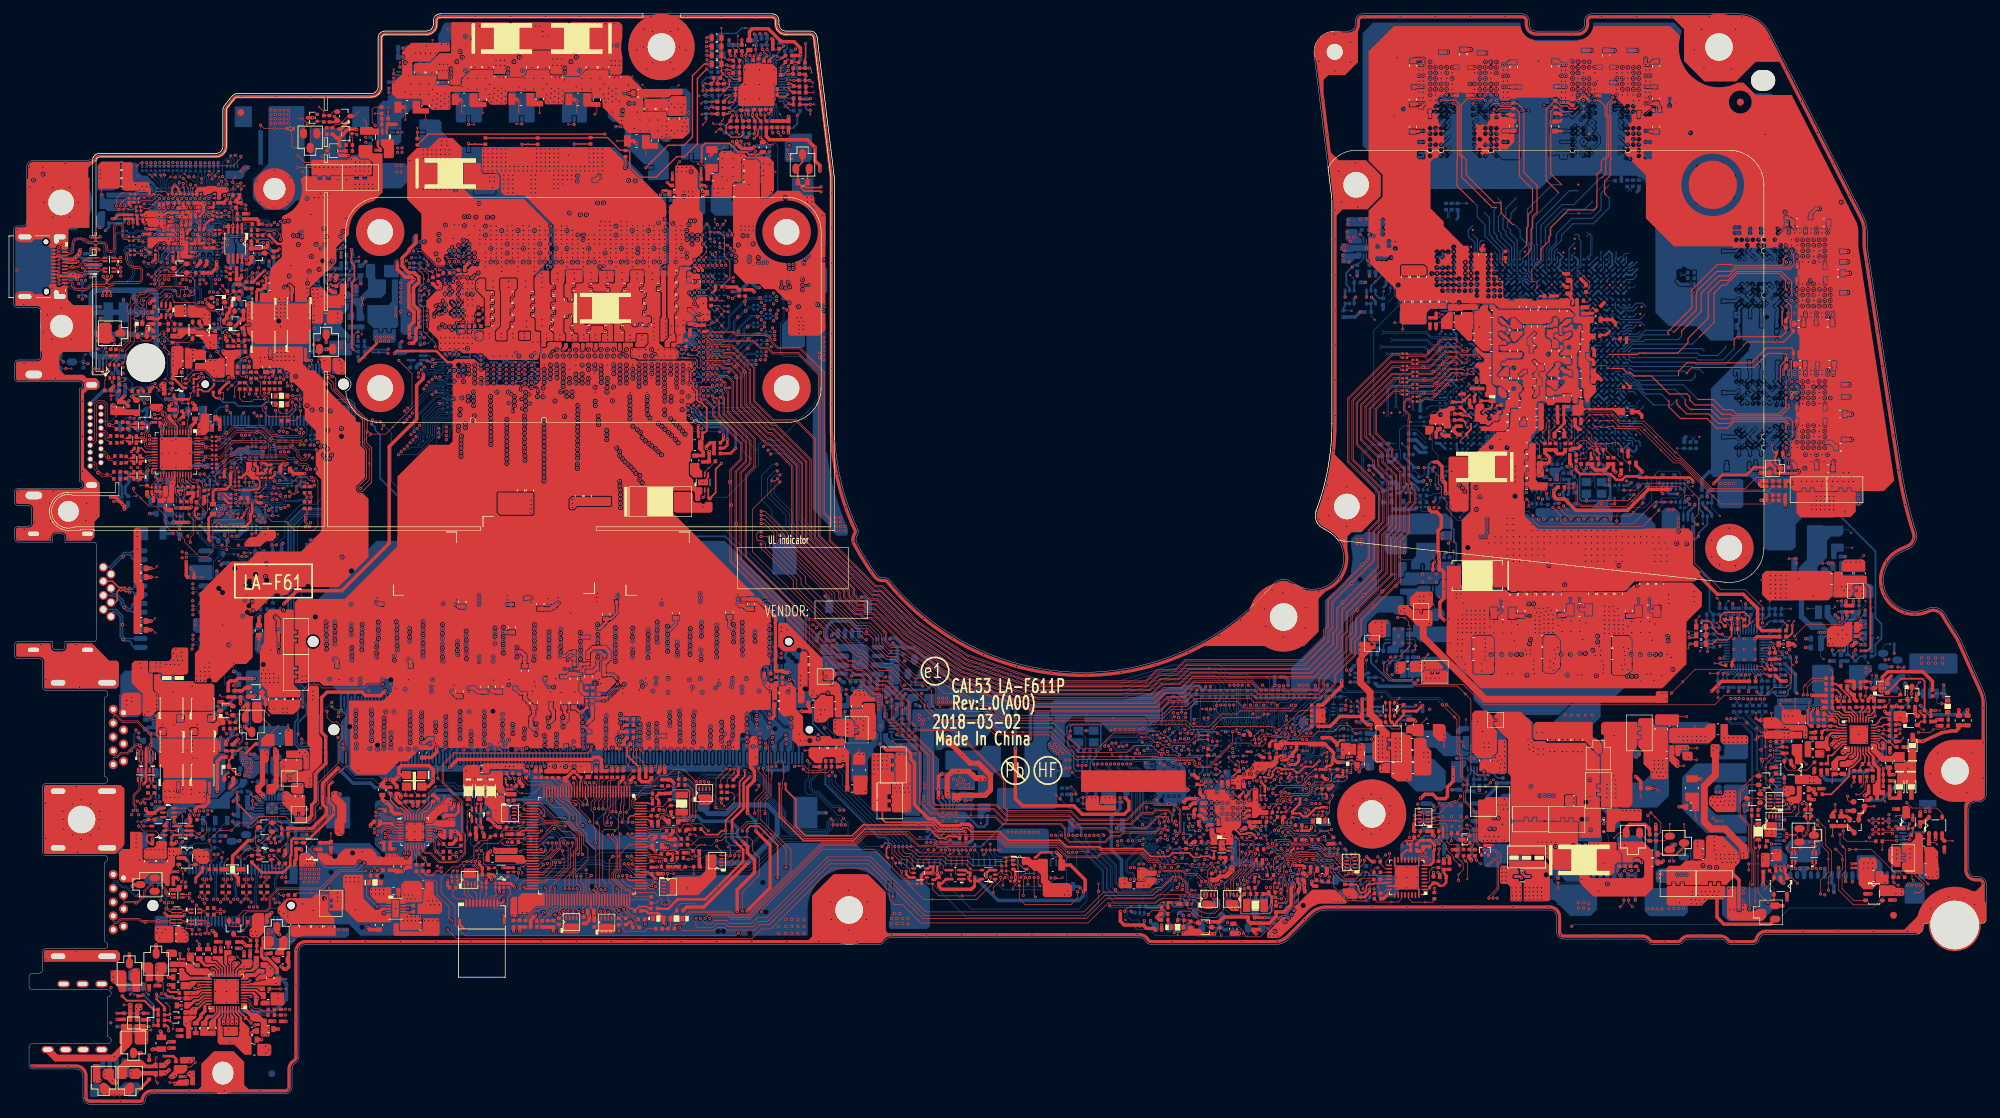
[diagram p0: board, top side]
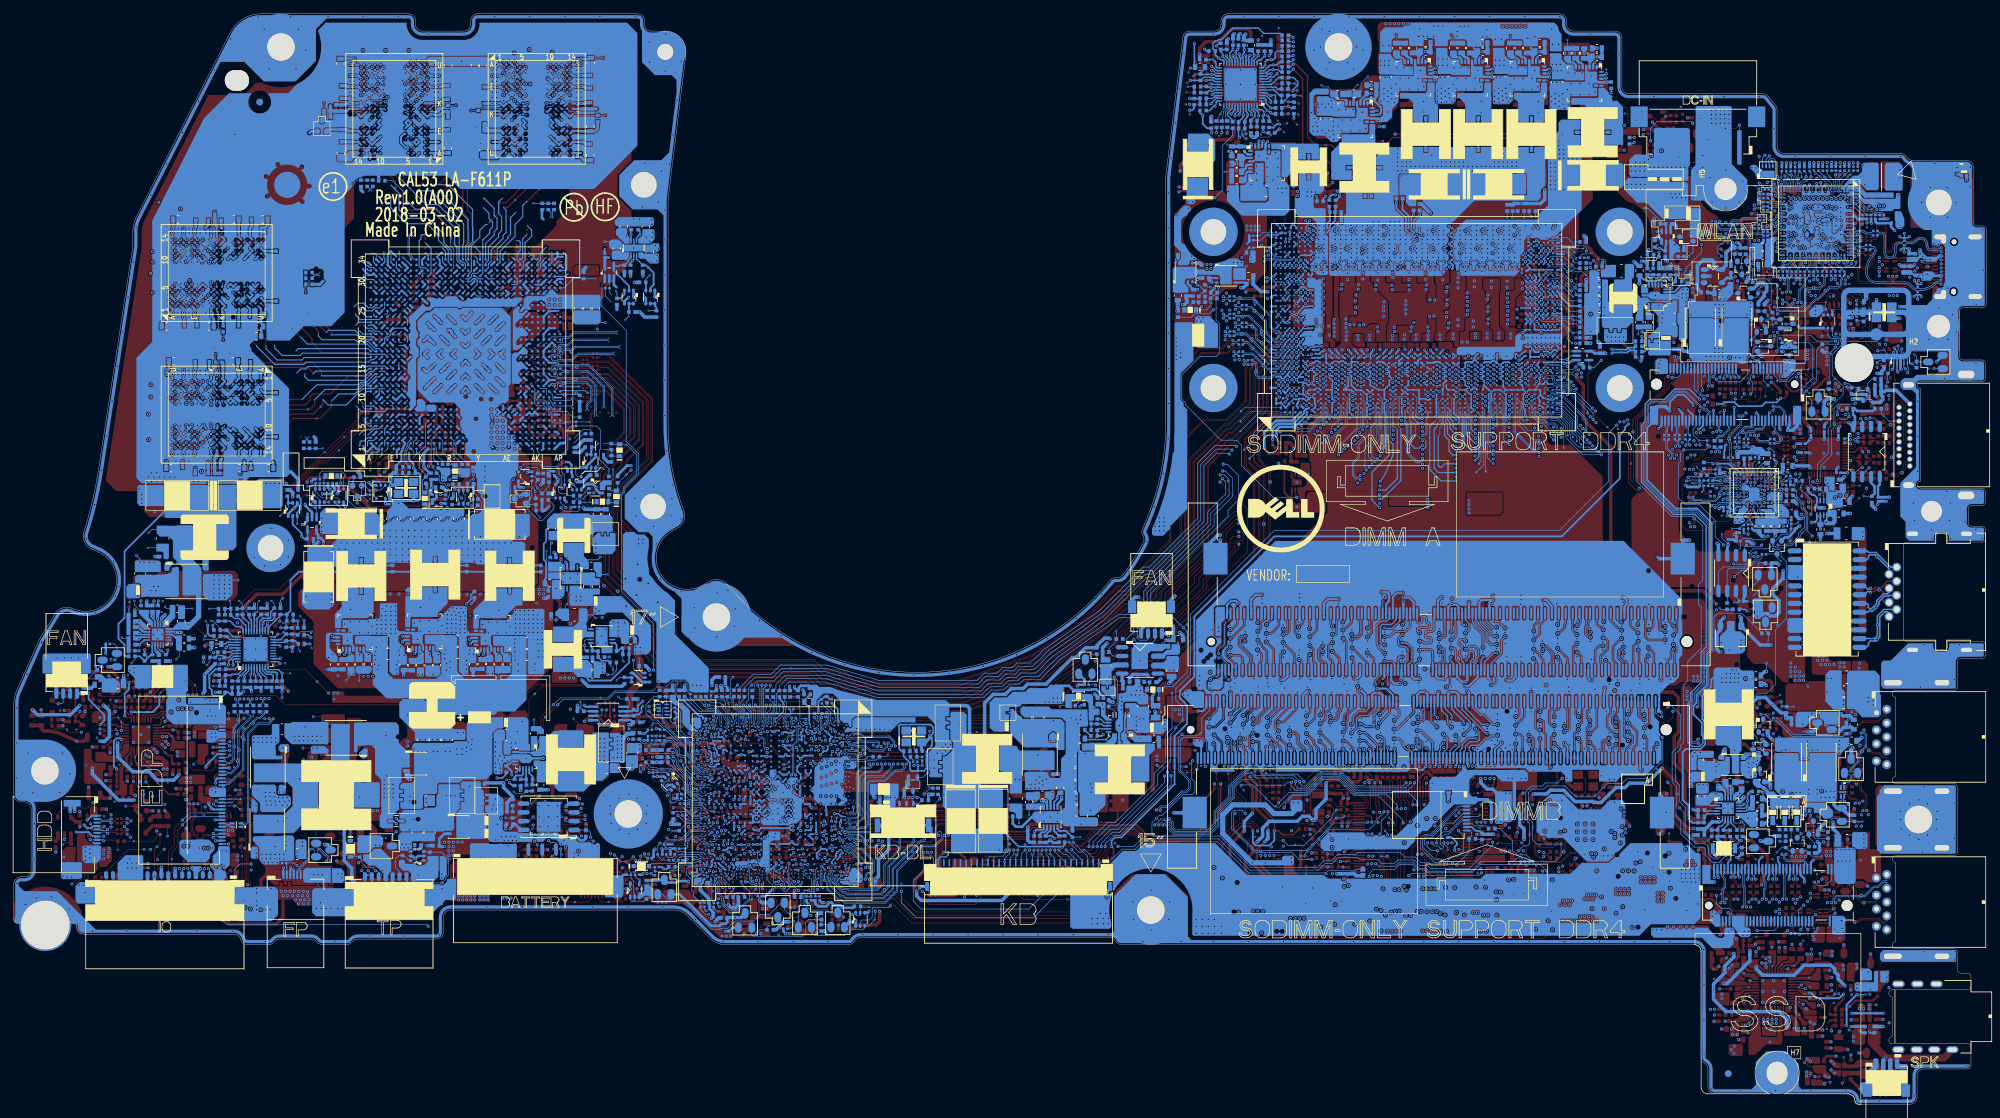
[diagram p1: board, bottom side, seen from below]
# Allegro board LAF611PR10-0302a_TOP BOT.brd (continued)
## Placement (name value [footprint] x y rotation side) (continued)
RH463  1K_0201_5%  [R_0201]  192.86 47.41 90 bottom
RH501  499_0402_1%  [R_0402]  190.2 45.67 180 top
RH502  499_0402_1%  [R_0402]  191.49 47.54 90 top
RH503  0_0201_5%  [R_0201]  182.46 31.99 0 top
RH506  1M_0402_5%  [R_0402]  190.91 38.62 270 top
RH512  10K_0201_5%  [R_0201]  166.4 29.21 0 top
RH515  8.2K_0402_5%  [R_0402]  189.68 34.35 0 bottom
RH520  8.2K_0402_5%  [R_0402]  194.84 53.75 270 bottom
RH521  10K_0201_5%  [R_0201]  186.07 44.22 180 top
RH524  2.2K_0402_5%  [R_0402]  189.94 41.27 90 bottom
RH531  1M_0402_5%  [R_0402]  182.61 28.72 270 top
RH533  100K_0201_5%  [R_0201]  189.19 35.3 180 bottom
RH537  10K_0201_5%  [R_0201]  180.34 47.33 0 top
RH545  10K_0201_5%  [R_0201]  192.61 34.31 180 bottom
RH546  10K_0201_5%  [R_0201]  185.74 39.57 0 top
RH551  10K_0201_5%  [R_0201]  193.61 54.18 180 bottom
RH552  10K_0201_5%  [R_0201]  191.25 54.18 0 bottom
RH553  10K_0201_5%  [R_0201]  183.44 48.45 270 top
RH554  10K_0201_5%  [R_0201]  184.06 47.85 0 top
RH557  10K_0201_5%  [R_0201]  169.39 29.5 90 bottom
RH561  10K_0201_5%  [R_0201]  170.03 29.5 90 bottom
RH562  10K_0201_5%  [R_0201]  170.66 30.09 270 bottom
RH571  8.2K_0402_5%  [R_0402]  182.89 58.97 90 bottom
RH573  10K_0201_5%  [R_0201]  184.99 41.51 90 top
RH578  8.2K_0402_5%  [R_0402]  185.43 40.37 0 top
RH580  1K_0201_5%  [R_0201]  167.01 58.03 90 bottom
RH581  1K_0201_5%  [R_0201]  168.46 57.99 90 bottom
RH588  20K_0402_5%  [R_0402]  188.7 57.73 180 top
RH589  10K_0402_5%  [R_0402]  187.78 56.97 0 top
RH613  20K_0402_5%  [R_0402]  185.21 59.89 270 bottom
RH614  20K_0402_5%  [R_0402]  186.73 59.89 270 bottom
RH656  0_0201_5%  [R_0201]  180.21 52.21 180 top
RH658  15_0402_5%  [R_0402]  187.81 38.28 0 top
RH665  30_0402_5%  [R_0402]  178.52 58.95 90 bottom
RH666  200_0402_1%  [R_0402]  189.1 58.98 90 bottom
RH667  150_0402_1%  [R_0402]  188.3 58.97 90 bottom
RH668  200_0402_1%  [R_0402]  187.78 56.21 0 top
RH669  100_0402_1%  [R_0402]  160.12 50.29 0 bottom
RH670  200_0402_1%  [R_0402]  187.78 55.45 0 top
RH671  4.7K_0402_5%~D  [R_0402]  185.97 59.89 270 bottom
RH672  0_0201_5%  [R_0201]  183.27 31.13 270 top
RH673  100K_0201_5%  [R_0201]  184.49 59.72 270 bottom
RH674  1K_0201_5%  [R_0201]  189.37 44.86 180 bottom
RH675  1K_0201_5%  [R_0201]  189.37 44.27 180 bottom
RH676  10K_0201_5%  [R_0201]  182.12 47.7 180 top
RH679  100K_0201_5%  [R_0201]  173.44 25.37 0 bottom
RH680  100K_0201_5%  [R_0201]  185.57 47.99 270 top
RH681  10K_0201_5%  [R_0201]  168.76 30.09 270 bottom
RH682  0_0201_5%  [R_0201]  183.38 42.25 180 top
RH683  0_0201_5%  [R_0201]  143.55 33.76 180 top
RH684  0_0201_5%  [R_0201]  189.95 35.32 0 bottom
RH685  150K_0402_5%  [R_0402]  183.75 41.57 180 top
RH687  10K_0201_5%  [R_0201]  193.03 53.29 0 bottom
RH697  0_0402_5%  [R_0402]  178.59 27 0 top
RH698  0_0402_5%  [R_0402]  172.8 50.49 90 top
RH699  0_0201_5%  [R_0201]  191.83 53.29 180 bottom
RH700  100K_0201_5%  [R_0201]  181.97 29.93 0 top
RH701  8.2K_0402_5%  [R_0402]  181.2 40.85 180 top
RH705  10K_0201_5%  [R_0201]  189.75 36.16 0 bottom
RH706  8.2K_0402_5%  [R_0402]  189.33 47.45 180 top
RH707  8.2K_0402_5%  [R_0402]  195.73 53.75 270 bottom
RH708  33_0402_5%  [R_0402]  213.19 42.34 270 bottom
RH709  49.9K_0402_1%  [R_0402]  193.9 51.26 180 bottom
RH710  49.9K_0402_1%  [R_0402]  190.65 51.26 0 bottom
RH711  33_0201_5%  [R_0201]  153.92 49.67 90 bottom
RH712  33_0201_5%  [R_0201]  154.65 49.57 0 bottom
RH713  0_0201_5%  [R_0201]  185.42 28.56 90 bottom
RH714  0_0201_5%  [R_0201]  186 28.56 90 bottom
RH716  10K_0201_5%  [R_0201]  172.79 52.8 90 top
RH717  10K_0201_5%  [R_0201]  185.75 33.25 270 top
RH719  10K_0201_5%  [R_0201]  187.43 59.94 270 bottom
RH721  10K_0201_5%  [R_0201]  188.37 48.45 0 top
RH722  4.7K_0201_5%  [R_0201]  26.62 103.99 270 top
RH723  4.7K_0201_5%  [R_0201]  28.96 104.79 270 top
RH724  1K_0201_5%  [R_0201]  26.02 103.75 90 top
RH725  1K_0201_5%  [R_0201]  26.02 105.54 270 top
RH726  100K_0201_5%  [R_0201]  174.48 33.62 270 top
RH727  4.7K_0402_5%  [R_0402]  173.3 33.38 270 top
RH728  100K_0201_5%  [R_0201]  192.29 48.3 0 top
RH731  0_0603_5%  [R_0603]  170.98 58.22 180 bottom
RH732  0_0603_5%  [R_0603]  162.76 31.7 180 top
RH734  10K_0201_5%  [R_0201]  180.39 38.52 180 top
RH735  100K_0402_5%  [R_0402]  204.42 39.5 180 top
RH736  0_0402_5%  [R_0402]  177.28 47.32 90 top
RH737  8.2K_0402_5%  [R_0402]  182.11 58.97 90 bottom
RH738  100K_0201_5%  [R_0201]  180.19 32.92 180 top
RH739  100K_0201_5%  [R_0201]  189.73 55.15 90 bottom
RH740  100K_0201_5%  [R_0201]  144.18 32.27 0 top
RH741  100K_0201_5%  [R_0201]  192.22 36.16 0 bottom
RH742  100K_0201_5%  [R_0201]  196.06 33.2 0 bottom
RH743  100K_0201_5%  [R_0201]  185.73 36.98 180 top
RH744  100K_0201_5%  [R_0201]  23.79 115.05 180 bottom
RH745  100K_0201_5%  [R_0201]  21.88 102.78 0 top
RH746  100K_0201_5%  [R_0201]  189.71 57.38 270 bottom
RH747  10K_0402_5%  [R_0402]  196.99 60.86 90 bottom
RH748  51_0402_5%  [R_0402]  193.95 63.45 0 bottom
RH749  1K_0201_5%  [R_0201]  193.62 35.57 180 bottom
RL2  2.49K_0402_1%  [R_0402]  54.51 45.87 270 top
RL3  1K_0402_5%  [R_0402]  63.08 37.65 180 top
RL4  15K_0402_5%  [R_0402]  64.67 37.41 90 top
RL6  100K_0402_5%  [R_0402]  40.84 36.94 90 top
RL7  10K_0402_5%  [R_0402]  45.87 37.08 90 top
RL8  33_0402_5%  [R_0402]  59.36 44.68 270 top
RL9  33_0402_5%  [R_0402]  56.67 44.73 270 top
RL13  0_0402_5%  [R0402_0OHM]  58.24 33.73 90 top
RL14  75_0603_5%  [R_0603]  17.73 68.65 0 top
RL15  75_0603_5%  [R_0603]  17.73 69.92 0 top
RL17  0_0402_5%  [R_0402]  60.65 43.78 90 top
RL19  75_0603_5%  [R_0603]  17.73 76.27 0 top
RL20  75_0603_5%  [R_0603]  17.73 77.54 0 top
RP1  100K_8P4R_5%  [RP_0804_8P4R]  253.94 40.46 90 top
RP2  100_8P4R_5%  [RP_0804_8P4R]  255.28 43.17 180 top
RP3  10K_0804_8P4R_5%  [RP_0804_8P4R]  172.18 29.14 90 top
RP9  0_0402_5%  [R_0402]  17.09 103.2 0 top
RP10  0_0402_5%  [R_0402]  14.77 108.33 90 top
RP11  0_0201_5%  [R0201_0OHM]  21.14 99.27 180 top
RP24  47K_0402_5%  [R_0402]  25.2 89.34 270 top
RP25  47K_0402_5%  [R_0402]  25.98 89.34 270 top
RP28  0_0603_1%  [R0603_0OHM]  26.23 99.2 90 top
RP30  4.99K_0402_1%  [R_0402]  23.17 89.08 0 bottom
RP31  10K_0402_1%  [R_0402]  24.84 89.08 0 bottom
RP32  4.53K_0402_1%  [R_0402]  27.54 88.8 270 top
RP33  10K_0201_5%  [R_0201]  25.27 102.02 270 top
RP34  10K_0201_5%  [R_0201]  23.49 102.01 270 top
RP35  10K_0201_5%  [R_0201]  23.77 88.81 90 top
RP36  10K_0201_5%  [R_0201]  19.96 88.68 90 top
RP37  10K_0201_5%  [R_0201]  24.36 88.81 90 top
RP38  10K_0201_5%  [R_0201]  26.65 88.73 90 top
RP39  10K_0402_5%  [R_0402]  24.33 100.28 0 top
RP40  10K_0402_5%  [R_0402]  23.36 100.48 270 top
RP41  10K_0402_5%  [R_0402]  24.16 86.28 90 top
RP42  10K_0402_5%  [R_0402]  19.28 88.61 90 top
RP43  10K_0402_5%  [R_0402]  25.01 86.29 90 top
RP44  10K_0402_5%  [R_0402]  24.54 99.47 270 top
RP45  1K_0201_5%  [R_0201]  28.24 88.89 270 top
RP48  10K_0201_5%  [R_0201]  21.18 89.27 270 top
RP49  10K_0201_5%  [R_0201]  20.55 89.27 270 top
RP50  33_0804_8P4R_5%  [RP_0804_8P4R]  192.05 57.86 180 bottom
RP51  0_0603_1%  [R0603_0OHM]  22.63 87.4 270 top
RP52  0_0603_1%  [R0603_0OHM]  22.25 89.28 180 bottom
RPE1  10K_8P4R_5%  [RP_0804_8P4R]  94.07 32.19 0 top
RPE2  10K_8P4R_5%  [RP_0804_8P4R]  102.33 34.5 180 top
RPE3  100K_8P4R_5%  [RP_0804_8P4R]  99.16 44.46 90 top
RPE4  100K_8P4R_5%  [RP_0804_8P4R]  71.22 42.82 0 top
RPE5  100K_8P4R_5%  [RP_0804_8P4R]  79.92 25.79 90 top
RPE6  100K_8P4R_5%  [RP_0804_8P4R]  85 25.71 90 top
RPE7  10K_0804_8P4R_5%  [RP_0804_8P4R]  65.19 31.88 90 top
RPH5  33_0804_8P4R_5%  [RP_0804_8P4R]  204.53 40.81 180 top
RPH6  10K_8P4R_5%  [RP_0804_8P4R]  176.98 30.29 270 top
RPH7  15_0804_8P4R_5%  [RP_0804_8P4R]  194 34.22 180 top
RPT1  100K_0804_8P4R_5%  [RP_0804_8P4R]  32.35 134.59 90 bottom
RS1  0_0402_5%  [R0402_0OHM]  269.39 38.05 0 top
RS2  10K_0402_5%  [R_0402]  24.85 31.44 180 top
RS3  100K_0402_5%  [R_0402]  272.64 42.71 0 top
RS4  100K_0402_5%  [R_0402]  275.44 38.95 180 top
RS5  10K_0402_5%  [R_0402]  279.3 38.11 270 top
RS8  0_0603_5%  [R_0603]  277.08 37.87 180 top
RS9  10K_0402_5%  [R_0402]  34.75 26.39 180 top
RS10  0_0201_5%  [R_0201]  25.81 24.6 0 top
RSPI1  0_0402_5%  [R_0402]  183.32 61.82 180 bottom
RT1  0_0201_5%  [R_0201]  24.72 131.71 0 top
RT2  0_0201_5%  [R_0201]  32.21 131.13 90 bottom
RT3  3.01K_0201_1%  [R_0201]  25.07 125.34 90 top
RT4  1M_0201_1%  [R_0201]  24.28 135.1 90 bottom
RT5  14K_0402_1%  [R_0402]  25.23 130.39 0 top
RT6  10K_0201_5%  [R_0201]  29.64 131.71 180 top
RT7  10K_0201_5%  [R_0201]  26.47 131.71 180 top
RT8  10K_0201_5%  [R_0201]  27.65 131.71 180 top
RT9  10K_0201_5%  [R_0201]  29.64 131.14 180 top
RT10  0_0201_5%  [R_0201]  27.65 135.04 90 bottom
RT11  1M_0201_1%  [R_0201]  29.55 135.04 90 bottom
RT12  0_0201_5%  [R_0201]  18.31 129.91 180 top
RT13  0_0201_5%  [R_0201]  17.5 131.71 180 top
RT14  0_0201_5%  [R_0201]  23.01 135.1 90 bottom
RT15  0_0201_5%  [R_0201]  19.2 135.1 90 bottom
RT16  0_0201_5%  [R_0201]  21.11 135.1 90 bottom
RT17  100_0201_5%  [R_0201]  19.84 135.1 90 bottom
RT18  100_0201_5%  [R_0201]  31.64 130.54 0 bottom
RT19  14K_0402_1%  [R_0402]  28.92 124.87 270 top
RT20  10K_0201_5%  [R_0201]  31.58 131.72 270 bottom
RT21  10K_0201_5%  [R_0201]  16.66 128.11 90 bottom
RT23  0_0201_5%  [R_0201]  18.03 131.08 180 top
RT24  10K_0201_5%  [R_0201]  32.8 131.71 270 bottom
RT25  4.75K_0402_0.5%  [R_0402]  22.3 130.4 0 top
RT26  3.3K_0201_5%  [R_0201]  25.55 135.62 270 bottom
RT27  3.3K_0201_5%  [R_0201]  26.31 135.62 270 bottom
RT28  10K_0201_5%  [R_0201]  28.28 135.62 270 bottom
RT29  10K_0201_5%  [R_0201]  28.92 135.62 270 bottom
RT30  10K_0201_5%  [R_0201]  18.57 135.69 270 bottom
RT31  10K_0201_5%  [R_0201]  23.65 135.69 270 bottom
RT32  10K_0201_5%  [R_0201]  24.11 131.71 180 top
RT33  10K_0201_5%  [R_0201]  20.47 135.69 270 bottom
RT34  100K_0201_5%  [R_0201]  27.01 135.04 90 bottom
RT35  100K_0201_5%  [R_0201]  20.24 131.7 180 top
RT36  100K_0201_5%  [R_0201]  22.38 135.1 90 bottom
RT37  100K_0201_5%  [R_0201]  18.42 129.27 270 top
RT40  1M_0201_1%  [R_0201]  17.29 128.69 270 bottom
RT42  1M_0201_1%  [R_0201]  14.8 128.7 270 bottom
RT43  499_0201_1%  [R_0201]  23.01 123.3 270 top
RT44  499_0201_1%  [R_0201]  20.47 123.56 270 top
RT45  100K_0201_5%  [R_0201]  15.39 128.69 270 bottom
RT46  100K_0201_5%  [R_0201]  17.93 128.69 270 bottom
RT47  100K_0201_5%  [R_0201]  24.92 135.1 90 bottom
RT48  3.3K_0402_5%  [R_0402]  32.21 119.39 180 top
RT49  2.2K_0402_5%  [R_0402]  32.21 120.98 180 top
RT50  2.2K_0402_5%  [R_0402]  32.21 120.2 180 top
RT51  3.3K_0402_5%  [R_0402]  16.54 87.07 90 bottom
RT57  10K_0201_5%  [R_0201]  28.34 90.18 0 bottom
RT58  10K_0201_5%  [R_0201]  28.33 89.61 0 bottom
RT59  0_0402_5%  [R_0402]  27.95 88.94 0 bottom
RT60  0_0402_5%  [R_0402]  26.62 90.24 0 bottom
RT61  0_0201_5%  [R_0201]  37.24 92.52 270 top
RT62  100K_0201_5%  [R_0201]  32.85 92.88 90 bottom
RT63  100K_0201_5%  [R_0201]  33.87 83.89 270 bottom
RT64  0_0402_5%  [R_0402]  32.86 87.74 0 top
RT65  0_0402_5%  [R_0402]  28.93 87.27 180 bottom
RT66  10K_0201_5%  [R_0201]  32.57 90.7 270 top
RT67  10K_0201_5%  [R_0201]  33.24 88.88 180 top
RT68  100K_0201_5%  [R_0201]  40.88 89.48 0 bottom
RT69  100K_0201_5%  [R_0201]  40.2 90.24 180 bottom
RT70  100K_0201_5%  [R_0201]  37.91 93.57 180 bottom
RT71  100K_0201_5%  [R_0201]  39.17 91.24 180 bottom
RT72  100K_0201_5%  [R_0201]  39.17 91.85 180 bottom
RT73  100K_0201_5%  [R_0201]  36.64 93.57 180 bottom
RT74  0_0201_5%  [R_0201]  35.67 82.72 90 bottom
RT75  15K_0402_0.1%  [R_0402]  34.13 93.49 90 bottom
RT76  100K_0201_5%  [R_0201]  28.84 129.2 90 top
RT78  100K_0201_5%  [R_0201]  28.84 128.6 270 top
RT80  100K_0201_5%  [R_0201]  18.03 130.52 180 top
RT83  0_0201_5%  [R_0201]  33.43 94.24 270 bottom
RT86  10K_0201_5%  [R_0201]  16.02 128.11 90 bottom
RT94  10K_0201_5%  [R_0201]  22.92 131.71 180 top
RT95  0_0402_5%  [R_0402]  12.84 128.93 90 bottom
RT97  0_0402_5%  [R0402_0OHM]  12.85 127.5 0 bottom
RT101  15_0201_1%  [R_0201]  31.45 132.37 0 bottom
RT102  0_0201_5%  [R_0201]  32.96 84.86 180 top
RT108  0_0201_5%  [R_0201]  31.39 88.27 270 top
RT111  1M_0201_1%  [R_0201]  31.39 86.42 90 top
RT112  10K_0201_5%  [R_0201]  35.26 90.66 0 top
RT113  100K_0201_5%  [R_0201]  36.47 90.66 0 top
RT114  0_0201_5%  [R_0201]  39.61 89.48 0 bottom
RT115  0_0201_5%  [R_0201]  41.47 90.24 180 bottom
RT118  0_0402_5%  [R_0402]  40.37 91.04 0 bottom
RT119  0_0402_5%  [R_0402]  40.83 91.95 90 bottom
RT120  0_0402_5%  [R_0402]  28.87 88.12 180 bottom
RT122  0_0201_5%  [R_0201]  34.44 83.89 270 bottom
RT123  15_0201_1%  [R_0201]  28.89 90.88 180 bottom
RT125  3.3K_0201_5%  [R_0201]  35.56 81.5 0 bottom
RT126  3.3K_0201_5%  [R_0201]  34.7 80.88 90 bottom
RT127  3.3K_0201_5%  [R_0201]  37.34 81.14 90 bottom
RT128  3.3K_0201_5%  [R_0201]  35.73 72.79 180 bottom
RT129  100K_0201_5%  [R_0201]  16.64 131.1 270 top
RT130  0_0402_5%  [R_0402]  42.82 88.48 90 top
RT131  0_0402_5%  [R_0402]  42.06 88.48 90 top
RT132  0_0402_5%  [R_0402]  42.82 86.23 90 top
RT133  0_0402_5%  [R_0402]  42.06 86.23 90 top
RT134  0_0603_5%  [R0603_0OHM]  28.8 85.43 90 top
RT152  10K_0201_5%  [R_0201]  21.74 135.69 270 bottom
RT153  10K_0201_5%  [R_0201]  17.73 128.68 90 top
RT154  0_0201_5%  [R_0201]  18.75 114.03 270 bottom
RT155  0_0201_5%  [R_0201]  18.76 115.72 270 bottom
RT156  33_0402_5%  [R_0402]  37.49 71.61 90 bottom
RT157  33_0402_5%  [R_0402]  31.81 117.66 180 top
RT159  0_0201_5%  [R_0201]  15.72 126.37 0 bottom
RT160  0_0201_5%  [R_0201]  15.72 125.74 0 bottom
RT161  0_0201_5%  [R_0201]  16.87 122.9 0 top
RT162  0_0201_5%  [R_0201]  16.87 123.53 0 top
RT163  0_0201_5%  [R_0201]  35.08 83.81 270 bottom
RT164  0_0201_5%  [R_0201]  30.67 93.28 90 bottom
RT165  0_0201_5%  [R_0201]  28.22 84.57 270 bottom
RT166  100K_0201_5%  [R_0201]  27.67 83.26 0 bottom
RT167  0_0201_5%  [R_0201]  31.86 79.58 0 bottom
RT168  0_0402_5%  [R0402_0OHM]  27 122.01 0 top
RTPM1  33_0402_5%  [R_0402]  196.84 30.51 0 top
RTPM2  33_0402_5%  [R_0402]  196.77 32.51 0 top
RTPM3  33_0402_5%  [R_0402]  196.77 33.56 0 top
RTPM4  10K_0402_5%  [R_0402]  196.84 29.74 0 top
RTPM6  0_0402_5%  [R_0402]  207.71 33.98 90 top
RTPM7  0_0402_5%  [R_0402]  206.9 33.98 90 top
RTPM8  0_0402_5%  [R_0402]  203 37.59 180 top
RTPM9  10K_0402_5%  [R_0402]  196.77 35.1 0 top
RTPM10  0_0402_5%  [R_0402]  202.6 39.52 270 top
RTPM11  0_0402_5%  [R_0402]  205.51 29.72 90 top
RTPM12  0_0402_5%  [R_0402]  206.1 34.24 90 top
RV27  100K_0402_5%  [R_0402]  224.97 91.33 270 bottom
RV28  0_0402_5%  [R0402_0OHM]  15.75 97.71 180 top
RV29  0_0402_5%  [R0402_0OHM]  15.52 93.8 180 top
RV30  0_0402_5%  [R0402_0OHM]  15.52 92.78 180 top
RV33  0_0402_5%  [R0402_0OHM]  15.39 91.51 180 top
RV34  0_0402_5%  [R0402_0OHM]  15.39 90.5 180 top
RV37  10K_0402_5%  [R_0402]  224.2 91.33 270 bottom
RV39  10K_0402_5%  [R_0402]  208.02 88.39 0 bottom
RV40  0_0201_5%  [R_0201]  204 98.16 90 bottom
RV41  10K_0402_5%  [R_0402]  201.8 97.03 270 bottom
RV42  10K_0402_5%  [R_0402]  225.74 90.78 270 bottom
RV49  10K_0402_5%  [R_0402]  226.02 93.95 180 top
RV50  2.49K_0402_1%  [R_0402]  202.92 120.39 270 bottom
RV51  10K_0402_5%  [R_0402]  225.23 95.62 270 top
RV52  10M_0402_5%  [R_0402]  229.07 92.24 180 bottom
RV55  10K_0402_5%  [R_0402]  223.06 95.61 270 top
RV56  0_0201_5%  [R_0201]  233.84 88.79 270 bottom
RV57  10K_0402_5%  [R_0402]  236.14 90.75 180 bottom
RV58  10K_0402_5%  [R_0402]  208.94 87.47 180 bottom
RV60  100K_0402_5%  [R_0402]  222.56 92.61 270 bottom
RV62  10K_0402_5%  [R_0402]  203.48 99.44 90 bottom
RV63  10K_0402_5%  [R_0402]  203.48 102.59 270 bottom
RV66  100K_0402_5%  [R_0402]  225.11 93.15 0 top
RV77  40.2_0402_1%  [R_0402]  226.17 116.27 0 top
RV78  40.2_0402_1%  [R_0402]  227.45 118.47 270 top
RV79  60.4_0402_1%  [R_0402]  229.63 115.53 225 top
RV95  10K_0402_5%  [R_0402]  223 146.16 270 top
RV96  10K_0402_5%  [R_0402]  258.37 108.7 180 top
RV98  10K_0402_5%  [R_0402]  216.94 145.84 270 top
RV99  10K_0402_5%  [R_0402]  258.34 111.93 180 top
RV107  10K_0402_5%  [R_0402]  216.94 144.06 270 top
RV108  10K_0402_5%  [R_0402]  223 144.32 270 top
RV110  10K_0402_5%  [R_0402]  256.34 112.35 90 top
RV111  10K_0402_5%  [R_0402]  256.44 107.81 270 top
RV116  1K_0402_1%  [R_0402]  222.55 144.57 270 bottom
RV117  1K_0402_1%  [R_0402]  218.15 143.81 270 bottom
RV120  121_0402_1%  [R_0402]  237.21 143.86 0 top
RV121  121_0402_1%  [R_0402]  200.87 143.11 270 bottom
RV125  549_0402_1%  [R_0402]  238.61 142.84 0 bottom
RV126  931_0402_1%  [R_0402]  240.47 143.73 180 bottom
RV127  1.33K_0402_1%  [R_0402]  238.75 143.72 90 bottom
RV131  1K_0402_1%  [R_0402]  255.06 111.79 180 bottom
RV132  1K_0402_1%  [R_0402]  256.14 107.36 180 bottom
RV135  121_0402_1%  [R_0402]  256.44 127.34 90 top
RV136  121_0402_1%  [R_0402]  256.74 92.15 0 top
RV140  549_0402_1%  [R_0402]  254.53 91.29 0 bottom
RV141  931_0402_1%  [R_0402]  255 94.27 0 top
RV142  1.33K_0402_1%  [R_0402]  256.3 91.29 0 bottom
RV146  100K_0402_5%  [R_0402]  230.62 93.56 270 top
RV147  100K_0402_5%  [R_0402]  255.41 90.19 0 top
RV148  100K_0402_5%  [R_0402]  255.41 89.43 0 top
RV149  100K_0402_5%  [R_0402]  233.76 92.87 0 top
RV150  100K_0402_5%  [R_0402]  229.3 92.65 180 top
RV152  100K_0402_5%  [R_0402]  229.04 94.73 0 top
RV153  100K_0402_5%  [R_0402]  253.57 90.19 0 top
RV154  100K_0402_5%  [R_0402]  253.57 89.43 0 top
RV155  100K_0402_5%  [R_0402]  233.54 94.6 180 top
RV156  100K_0402_5%  [R_0402]  228.25 93.46 0 top
RV157  100K_0402_5%  [R_0402]  255.36 87.4 0 top
RV158  100K_0402_5%  [R_0402]  255.36 88.16 0 top
RV159  100K_0402_5%  [R_0402]  231.42 93.56 270 top
RV160  100K_0402_5%  [R_0402]  253.56 87.4 0 top
RV161  100K_0402_5%  [R_0402]  253.56 88.16 0 top
RV162  100K_0402_5%  [R_0402]  232.55 91.77 90 top
RV191  1.8K_0402_5%  [R_0402]  221.95 86.75 90 bottom
RV192  1.8K_0402_5%  [R_0402]  219.74 89.78 180 bottom
RV500  619_0402_1%  [R_0402]  15.65 95.77 90 top
RV501  619_0402_1%  [R_0402]  16.49 97.76 90 top
RV502  619_0402_1%  [R_0402]  16.26 92.84 90 top
RV503  619_0402_1%  [R_0402]  16.21 90.55 90 top
RV512  1.8K_0402_5%  [R_0402]  222.29 95.61 270 top
RV513  1.8K_0402_5%  [R_0402]  221.51 95.61 270 top
RV514  1.8K_0402_5%  [R_0402]  220.47 92.6 270 bottom
RV515  1.8K_0402_5%  [R_0402]  219.64 92.6 270 bottom
RV526  10K_0402_5%  [R_0402]  223.32 92.61 270 bottom
RV532  10K_0402_5%  [R_0402]  202.63 97.03 270 bottom
RV571  0_0402_5%  [R_0402]  218.22 87.59 270 bottom
RV572  0_0402_5%  [R_0402]  221.83 89.73 180 bottom
RV573  100K_0402_5%  [R_0402]  207.92 90.03 90 bottom
RV574  10K_0402_5%  [R_0402]  224.44 95.62 270 top
RV583  0_0402_5%  [R0402_0OHM]  204.88 113.82 270 top
RV584  0_0402_5%  [R0402_0OHM]  208.18 101.62 270 top
RV585  0_0402_5%  [R0402_0OHM]  208.43 99.92 180 top
RV586  0_0402_5%  [R0402_0OHM]  208.43 99.03 180 top
RV590  0_0402_5%  [R0402_0OHM]  212.51 104.48 270 top
RV593  100K_0402_5%  [R_0402]  226.75 92.65 0 top
RV594  40.2_0402_1%  [R_0402]  234.23 132.82 90 bottom
RV595  40.2_0402_1%  [R_0402]  233.41 132.82 90 bottom
RV596  40.2_0402_1%  [R_0402]  207.19 129.45 90 bottom
RV597  40.2_0402_1%  [R_0402]  208.02 129.45 90 bottom
RV598  40.2_0402_1%  [R_0402]  243.39 95.83 270 bottom
RV599  40.2_0402_1%  [R_0402]  242.57 95.83 270 bottom
RV600  40.2_0402_1%  [R_0402]  242.19 120.37 0 bottom
RV601  40.2_0402_1%  [R_0402]  242.19 119.54 0 bottom
RV602  60.4_0402_1%  [R_0402]  231.66 133.64 0 bottom
RV603  60.4_0402_1%  [R_0402]  215.8 123.41 270 top
RV604  60.4_0402_1%  [R_0402]  232.89 103.79 0 top
RV605  60.4_0402_1%  [R_0402]  232.41 110.84 0 top
RV638  2.2_0402_1%  [R_0402]  18.28 90.5 180 top
RV639  2.2_0402_1%  [R_0402]  18.28 92.78 180 top
RV640  2.2_0402_1%  [R_0402]  17.71 95.67 180 top
RV641  2.2_0402_1%  [R_0402]  17.71 96.68 180 top
RV642  2.2_0402_1%  [R_0402]  18.28 93.8 180 top
RV643  2.2_0402_1%  [R_0402]  18.54 98.6 180 top
RV645  2.2_0402_1%  [R_0402]  18.28 91.51 180 top
RV646  2.2_0402_1%  [R_0402]  18.54 97.84 180 top
RV655  0_0402_5%  [R0402_0OHM]  210.84 100.88 0 top
RV673  0_0402_5%  [R0402_0OHM]  14.9 96.71 180 top
RV674  0_0402_5%  [R0402_0OHM]  15.75 98.73 180 top
RV675  0_0402_5%  [R0402_0OHM]  14.9 95.7 180 top
RV676  2.2K_0402_5%  [R_0402]  14.07 103.28 180 top
RV677  2.2K_0402_5%  [R_0402]  19.66 103.2 180 top
RV678  10K_0402_5%  [R_0402]  15.11 105.76 180 bottom
RV679  10K_0402_5%  [R_0402]  14.81 106.72 90 bottom
RV680  0_0402_5%  [R0402_0OHM]  14.01 108.33 90 top
RV681  0_0402_5%  [R0402_0OHM]  15.27 104.16 270 top
RV682  10K_0402_5%  [R_0402]  220.71 93.67 270 top
RV683  0_0402_5%  [R0402_0OHM]  208.75 90.36 90 bottom
RV684  0_0402_5%  [R_0402]  209.54 90.36 90 bottom
RW3  0_0805_5%  [R_0805]  26.96 106.74 90 top
RW4  75K_0402_1%  [R_0402]  23.71 109.99 270 bottom
RW5  0_0805_5%  [R_0805]  23.91 114.91 0 top
RW9  0_0402_5%  [R_0402]  38.72 98.92 0 top
RW11  75K_0402_1%  [R_0402]  22.97 111.15 270 top
RW12  10K_0402_5%  [R_0402]  29.13 110.96 90 top
RW13  0_0402_5%  [R_0402]  33.43 104.42 270 top
RW15  0_0402_5%  [R_0402]  34.32 105.94 270 top
RW18  0_0402_5%  [R_0402]  35.08 105.03 90 top
RW19  0_0402_5%  [R_0402]  32.66 103.5 90 top
RW20  0_0402_5%  [R_0402]  36.98 103.5 90 top
RW21  0_0402_5%  [R_0402]  36.22 103.5 90 top
RW25  0_0402_5%  [R_0402]  37.74 103.5 90 top
RW26  0_0402_5%  [R_0402]  38.51 103.5 90 top
RW27  0_0402_5%  [R_0402]  34.24 103.45 0 top
RW28  0_0402_5%  [R_0402]  33.25 105.87 180 top
RW29  75K_0402_1%  [R_0402]  24.24 105.95 180 top
RW30  75K_0402_1%  [R_0402]  26.34 120.31 0 top
RW31  0_0201_1%  [R_0201]  40.36 95.45 90 bottom
RX6  150K_0402_5%  [R_0402]  16.1 104.98 180 bottom
RX8  100K_0402_5%  [R_0402]  19.47 103.69 270 bottom
RZ21  0_0402_5%  [R_0402]  169.6 37.89 270 top
RZ48  0_0603_1%  [R0603_0OHM]  106.03 119.84 0 bottom
RZ49  10K_0402_5%  [R_0402]  112.21 116.61 180 bottom
RZ67  0_0603_1%  [R0603_0OHM]  98.58 93.86 270 top
RZ71  100K_0201_5%  [R_0201]  138.38 34.07 270 top
RZ102  100K_0402_5%  [R_0402]  113.01 116.08 0 bottom
RZ108  150K_0402_5%  [R_0402]  51.64 33.09 0 top
RZ111  0_0402_5%  [R_0402]  113.01 116.9 0 bottom
RZ112  0_0402_5%  [R_0402]  113.04 118.6 270 bottom
RZ234  0_0201_5%  [R_0201]  145.47 31.67 90 top
RZ237  0_0201_5%  [R_0201]  142.96 34.5 0 top
RZ238  0_0201_5%  [R_0201]  143.55 35.1 90 top
SW1  TST71-N-220-T170-S017_2P  [SW_TST71-N-220-T170-S017_2P]  36.35 37.03 0 bottom
T2  PAD~D  [TPC12]  26.7 134.16 180 bottom
T7  PAD~D  [TPC12]  28.3 135.04 0 top
T9  PAD~D  [TPC12]  29.68 135.06 0 top
T45  PAD~D  [TPC12]  62.29 44.55 0 top
T47  PAD~D  [TPC12]  61.04 45.95 0 top
T62  PAD~D  [TPC12]  33.62 90.66 180 top
T63  PAD~D  [TPC12]  34.06 89.44 180 top
T65  PAD~D  [TPC12]  33 93.28 180 top
T92  PAD  [TPC12]  190.82 38.47 180 bottom
T97  PAD~D  [TPC12]  227.91 98.93 0 top
T98  PAD~D  [TPC12]  204.48 100.71 180 bottom
T99  PAD~D  [TPC12]  204.48 102.25 180 bottom
T100  PAD~D  [TPC12]  203.62 103.83 180 bottom
T101  PAD~D  [TPC12]  202.34 102.94 180 bottom
T4937  PAD  [TPC12]  182.6 44.77 0 top
T4938  PAD  [TPC12]  171.92 57.2 0 top
T4939  PAD  [TPC12]  173.75 57.19 0 top
T4940  PAD  [TPC12]  188.54 49.14 180 bottom
T4941  PAD  [TPC12]  178.68 37.11 0 top
T4942  PAD  [TPC12]  178.33 51 0 top
T4943  PAD  [TPC12]  181.27 61.85 180 bottom
TC1  PAD~D  [TPC12]  102.15 124.67 0 top
TC4  PAD~D  [TPC12]  72.38 91.55 180 bottom
TC5  PAD~D  [TPC12]  73.74 91.46 180 bottom
TC6  PAD~D  [TPC12]  73.42 102.02 0 top
TC7  PAD~D  [TPC12]  74.57 102.72 0 top
TC8  PAD~D  [TPC12]  72 102.74 0 top
TC9  PAD~D  [TPC12]  71.58 101.46 0 top
TC10  PAD~D  [TPC12]  73.37 92.7 180 bottom
TC11  PAD~D  [TPC12]  74.68 101.38 0 top
TC12  PAD~D  [TPC12]  73.53 100.66 0 top
TC13  PAD~D  [TPC12]  72.19 100.25 0 top
TC14  PAD~D  [TPC12]  75.79 107.31 0 top
TC15  PAD~D  [TPC12]  74.41 107.4 0 top
TC16  PAD~D  [TPC12]  72.64 104.56 0 top
TC17  PAD~D  [TPC12]  75.64 104.55 0 top
TC18  PAD~D  [TPC12]  72.57 107.38 0 top
TC19  PAD~D  [TPC12]  75.38 106.01 0 top
TC20  PAD~D  [TPC12]  73.33 103.4 0 top
TC21  PAD~D  [TPC12]  74.42 104.14 0 top
TC22  PAD~D  [TPC12]  75.82 103.14 0 top
TC23  PAD~D  [TPC12]  73.53 105.98 0 top
TC24  PAD~D  [TPC12]  107.9 97.38 180 bottom
TC25  PAD~D  [TPC12]  107.37 94.7 180 bottom
TC26  PAD~D  [TPC12]  106.59 93.42 180 bottom
TC27  PAD~D  [TPC12]  59.79 96.52 180 bottom
TC28  PAD~D  [TPC12]  64.88 119.77 0 top
TC29  PAD~D  [TPC12]  58.58 95.44 180 bottom
TC30  PAD~D  [TPC12]  66.64 119.97 0 top
TC31  PAD~D  [TPC12]  59.54 123.26 180 bottom
TC32  PAD~D  [TPC12]  98.1 117.04 0 top
TC33  PAD~D  [TPC12]  100.52 118.12 0 top
TC34  PAD~D  [TPC12]  63.42 124.09 0 top
TC35  PAD~D  [TPC12]  65.57 124.92 0 top
TC36  PAD~D  [TPC12]  93.72 120.98 0 top
TC37  PAD~D  [TPC12]  92.74 108.6 0 top
TC38  PAD~D  [TPC12]  85.38 121.3 0 top
TC39  PAD~D  [TPC12]  88.17 108.6 0 top
TC40  PAD~D  [TPC12]  77.1 121.41 0 top
TC41  PAD~D  [TPC12]  77.95 108.94 0 top
TC42  PAD~D  [TPC12]  100.19 124 0 top
TC43  PAD~D  [TPC12]  100.19 122.59 0 top
TC44  PAD~D  [TPC12]  102.21 122.03 0 top
TC45  PAD~D  [TPC12]  65.14 123.25 0 top
TC46  PAD~D  [TPC12]  101.6 123.29 0 top
TC47  PAD~D  [TPC12]  81.77 104.7 0 top
TC48  PAD~D  [TPC12]  98.15 109.1 0 top
TC49  PAD~D  [TPC12]  99.4 99.77 0 top
TC50  PAD~D  [TPC12]  98.07 100.15 0 top
TC51  PAD~D  [TPC12]  101.42 128.13 0 top
TC52  PAD~D  [TPC12]  107.9 98.82 180 bottom
TC53  PAD~D  [TPC12]  59.21 95.95 180 bottom
TC54  PAD~D  [TPC12]  58.27 123.82 180 bottom
TC55  PAD~D  [TPC12]  60.55 96.77 180 bottom
TC56  PAD~D  [TPC12]  57.87 119.96 180 bottom
TC57  PAD~D  [TPC12]  102.97 127.9 0 top
TC58  PAD~D  [TPC12]  67.22 122.03 0 top
TC59  PAD~D  [TPC12]  107.85 100.29 180 bottom
TC94  PAD~D  [TPC12]  75.35 108.72 0 top
TC95  PAD~D  [TPC12]  72.63 108.75 0 top
TC96  PAD~D  [TPC12]  62.61 122.69 0 top
TC97  PAD~D  [TPC12]  61.11 94.98 180 bottom
TC98  PAD~D  [TPC12]  62.33 119.38 0 top
TC99  PAD~D  [TPC12]  59.8 116.86 180 bottom
TC100  PAD~D  [TPC12]  60 120.56 180 bottom
TC101  PAD~D  [TPC12]  63.87 122.9 0 top
TC103  PAD~D  [TPC12]  252.54 44.14 180 bottom
TC104  PAD~D  [TPC12]  252.71 50.02 0 top
TC105  PAD~D  [TPC12]  25.71 106.36 180 bottom
TC106  PAD~D  [TPC12]  30.91 103.41 0 top
TC107  PAD~D  [TPC12]  39.51 105.8 90 top
TC108  PAD~D  [TPC12]  39.51 104.46 90 top
TC109  PAD~D  [TPC12]  40.31 103.36 90 top
TC110  PAD~D  [TPC12]  33.35 102.36 0 top
TC111  PAD~D  [TPC12]  64.01 108.93 0 top
TH1  PAD~D  [TPC12]  174.51 49.48 0 top
TH2  PAD~D  [TPC12]  174.54 48.18 0 top
TH3  PAD~D  [TPC12]  172.23 39.05 0 top
TH4  PAD~D  [TPC12]  170.89 39.47 0 top
TH5  PAD~D  [TPC12]  169.82 41.92 0 top
TH6  PAD~D  [TPC12]  170.14 40.65 0 top
TH7  PAD~D  [TPC12]  175.71 50.13 0 top
TH8  PAD~D  [TPC12]  178.33 49.48 0 top
TH101  PAD~D  [TPC12]  178.32 38.51 0 top
TH138  PAD~D  [TPC12]  167.55 30.99 0 top
TH139  PAD~D  [TPC12]  168.66 31.98 0 top
TH141  PAD~D  [TPC12]  166.4 53 0 top
TH142  PAD~D  [TPC12]  164.76 53.43 0 top
TH143  PAD~D  [TPC12]  163.11 53.15 0 top
TH145  PAD~D  [TPC12]  170.13 50.66 0 top
TH148  PAD~D  [TPC12]  188.25 37.55 180 bottom
TL1  MHPC_NS692417  [MHPC_NS692417_24P]  27.7 80.08 270 bottom
TP40  PAD  [TPC12]  86.57 60.65 180 bottom
TP41  PAD  [TPC12]  86.84 73.32 180 bottom
TP42  PAD  [TPC12]  91.44 60.79 0 top
TP43  PAD  [TPC12]  91.06 49.48 0 top
TP44  PAD  [TPC12]  84.49 49.48 0 top
TP74  PAD  [TPC12]  77.28 27.56 0 top
TPC1  PAD  [TPC12]  58.84 117.68 0 top
TPC2  PAD  [TPC12]  58.97 116.34 0 top
TPC3  PAD  [TPC12]  176.85 54.23 0 top
TPC4  PAD  [TPC12]  57.91 121.73 0 top
TPC5  PAD  [TPC12]  58.98 111.4 0 top
TPC6  PAD  [TPC12]  59.64 120.93 0 top
TPC7  PAD  [TPC12]  111.28 115.2 90 top
TPC8  PAD  [TPC12]  179.9 33.9 0 top
TPC9  PAD  [TPC12]  181.2 28.97 180 bottom
TPC10  PAD  [TPC12]  64.68 118.4 0 top
TPC11  PAD  [TPC12]  63.56 119.02 0 top
TPC12  PAD  [TPC12]  63.46 117.64 0 top
TPC13  PAD  [TPC12]  58.48 123.42 0 top
TPC14  PAD  [TPC12]  59.8 112.51 0 top
TPC15  PAD  [TPC12]  59.8 111.61 180 bottom
TPC16  PAD  [TPC12]  59.82 112.94 180 bottom
TPC17  PAD  [TPC12]  59.79 114.86 0 top
TPC18  PAD  [TPC12]  64.68 116.04 0 top
TPC19  PAD  [TPC12]  63.37 116.05 0 top
TPC20  PAD  [TPC12]  62.08 116.29 0 top
TPC21  PAD  [TPC12]  62.04 114.41 0 top
TPC22  PAD  [TPC12]  61.02 115.49 0 top
TPC23  PAD  [TPC12]  60.81 113.98 0 top
TPC24  PAD  [TPC12]  64.08 113.09 0 top
TPC25  PAD  [TPC12]  61.94 112.86 0 top
TPC26  PAD  [TPC12]  63.34 112.03 0 top
TPC27  PAD  [TPC12]  59.91 110.12 180 bottom
TPC28  PAD  [TPC12]  63.34 114.48 0 top
TPC29  PAD  [TPC12]  64.68 114.44 0 top
TPC30  PAD  [TPC12]  58.76 109.82 0 top
TPC31  PAD  [TPC12]  60.1 117.19 0 top
TPC32  PAD  [TPC12]  181.14 34.26 180 top
TPC33  PAD  [TPC12]  60.96 120.89 0 top
TPS10  PAD  [TPC12]  109.53 39.11 0 top
U1  -  [SY6288C20AAC_SOT23-5]  258.06 49.65 180 top
U2  -  [NCT7718W_MSOP8]  197.16 55.56 90 bottom
U3  -  [SY6288C20AAC_SOT23-5]  256.54 32.77 180 top
UA1  -  [ALC3204-CG_MQFN40_5X5]  33.3 14.51 180 top
UC1  CFL-H_BGA1440  [CFL-H_BGA_1440P-T]  102.71 100.13 270 bottom
UC10  -  [74AUP1G07GW_TSSOP5]  59.27 108.98 270 bottom
UC12  -  [TC7SH08FUF_SSOP5]  144.6 35.32 270 top
UC16  74AUP1G07SE-7_SOT353  [74AUP1G07GW_TSSOP5]  137.1 32.57 90 top
UE1  -  [MEC1416-NU-D0_VTQFP128_14X14]  89.09 45.24 270 top
UE2  -  [NL17SZ06DFT2G_SC70-5]  71.48 32.93 90 top
UG12  AOZ1331_SON14_2X3  [TPS22966DPUR_SON14_2X3]  196.86 122.87 180 bottom
UG22  -  [NL17SZ08DFT2G_SC70-5]  238.94 87.14 180 bottom
UG25  -  [74LVC1G32GW_TSSOP5]  199.85 119.5 180 bottom
UG27  -  [74LVC1G32GW_TSSOP5]  241.56 84.98 0 bottom
UG31  -  [NL17SZ08DFT2G_SC70-5]  204.55 88.9 180 bottom
UH1  CNP-H_BGA874  [CNP-H_BGA_874P-T]  163.89 55.81 270 bottom
UH3  -  [TC7SH08FU_SSOP5]  196.16 30 180 bottom
UH4  W25Q256JVEIQ_WSON8_8X6  [W25Q256FVEIQ_WSON8_8X6-NPM]  203.98 39.69 90 bottom
UH14  -  [MC74VHC1G08DFT2G_SC70-5]  130.18 34.11 270 top
UH15  S IC FL 128M W25Q128JVSIQ SOIC8P SPI ROM  [W25Q128FVSIQ_SO8]  204.3 39.69 90 bottom
UL1  -  [RTL8111H-CG_QFN32_4X4]  55.96 40.83 0 top
UL2  -  [SY6288C20AAC_SOT23-5]  44.33 35.94 90 top
UP1  -  [RT9041E-15GQW_WDFN8_2X2]  23 87.38 0 bottom
UP2  PS8409AQFN48GTR2-A2_QFN48_6X6  [PS8409AQFN48GTR2-A0_QFN48_6X6]  25.66 97.23 270 top
US1  -  [LNG2DMTR_LGA12_2X2]  193.54 49.21 90 top
US2  -  [SY6288D20AAC_SOT23-5]  277.08 39.15 0 top
UT1  ALPINE-RIDGE_BGA337  [ALPINE-RIDGE_BGA_337P]  19.58 132.54 270 bottom
UT2  -  [W25Q80DVSSIG_SO8]  15.39 98.06 0 bottom
UT3  -  [W25X20CLSNIG_SO8]  34.93 79.44 0 bottom
UT4  SN1610042ZQZR BGA 96P_BGA96  [TPS65982DAZQZR-ES_BGA_96P]  31.05 90.99 270 bottom
UTPM1  -  [NPCT650VB2YX_QFN32_5X5]  204.07 31.07 180 top
UU1  -  [SY6288D20AAC_SOT23-5]  23.87 36.58 270 top
UU3  -  [SY6288D20AAC_SOT23-5]  267.9 31.39 270 top
UV1  N17P-GT_BGA908  [N15P-GT_BGA_908P]  233.7 94.85 90 bottom
UV6  H5GC4H24MFR-T2C  [H5GQ1H24AFR-T2L_BGA_170P]  225.1 137.65 0 bottom
UV7  H5GC4H24MFR-T2C  [H5GQ1H24AFR-T2L_BGA_170P]  214.9 150.45 180 bottom
UV8  H5GC4H24MFR-T2C  [H5GQ1H24AFR-T2L_BGA_170P]  249.6 105 270 bottom
UV9  H5GC4H24MFR-T2C  [H5GQ1H24AFR-T2L_BGA_170P]  262.4 115.1 90 bottom
UV14  -  [NL17SZ08DFT2G_SC70-5]  206.97 87.73 180 bottom
UV17  -  [AP2330W-7_SC59-3]  20.15 100.91 270 top
UV19  -  [NL17SZ08DFT2G_SC70-5]  231.6 89.56 0 bottom
UV20  -  [NL17SZ08DFT2G_SC70-5]  210.44 90.21 90 bottom
UW1  -  [SY6288C20AAC_SOT23-5]  27.76 113.2 180 top
UZ1  -  [EM5209VF_DFN14_3X2]  54.23 29.49 270 top
UZ7  -  [TPS22967DSGR_SON8_2X2]  173.66 38.15 270 top
UZ9  -  [TPS22961DNYR_WSON8]  111.35 120.86 270 bottom
UZ15  -  [TPS22961DNYR_WSON8]  116.8 119.03 180 bottom
UZ16  -  [AOZ1336DI_DFN8_2X2]  98.97 88.89 0 top
UZ21  -  [MC74VHC1G08DFT2G_SC70-5]  141.97 32.57 90 top
YE1  32.768KHZ_9PF_X1A000141000200  [Y_X1A000141000200_2P]  96.62 42.26 90 top
YH1  32.768KHZ_X1A000141000300  [Y_CM31532768DZFT_2P]  180.87 28.78 180 top
YH2  24MHZ 12PF +-10PPM 7M24090001  [Y_X3G024000DC1H_4P]  156.23 52.37 180 bottom
YL1  25MHZ_10PF_7V25000014  [Y_7V25000014_4P]  59.04 47.66 180 top
YT1  25MHZ 20PF +-10PPM 7M25000153  [Y_7V25000012_4P]  15.86 113.75 180 bottom
YV1  27MHZ_10PF_7V27000050  [Y_7V27000011_4P]  229.71 88.34 180 bottom
ZTB02  PAD  [TPC12]  270.31 54.66 0 top

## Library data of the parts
C1-C3 C5-C12 C14 C16-C19 C21 C23 C26 C27 C31-C34 C37 C59-C61 C149 C150 CA2 CA4 CA6 CA7 CA9 CA10 CA14 CA16 CA27-CA31 CA34-CA38 CA40-CA42 CA51-CA53 CC17-CC28 CC33-CC35 CC41-CC43 CC57 CC298-CC300 CC303 CD3-CD5 CD9 CD11-CD18 CD28-CD31 CD35 CD36 CD39 CD41-CD48 CD58-CD63 CE1-CE4 CE6-CE17 CE19-CE23 CE25 CE26 CE28 CE30-CE34 CE99 CE100 CG47 CG48 CG64 CG65 CG310 CG386 CG442 CG482 CG487 CH12-CH25 CH29-CH36 CH45-CH49 CH51 CH62 CH63 CH197 CH209-CH212 CH222-CH226 CH228 CL1-CL12 CL15 CL18-CL20 CL22 CL23 CP3 CP7 CP11 CP14 CP25 CP27 CS5 CS6 CS8 CS16-CS23 CS25-CS27 CS29 CT37 CT38 CT50-CT53 CT81 CT82 CT88 CT94-CT97 CT101 CT103 CT104 CT156 CT157 CTPM1-CTPM7 CU1-CU7 CU11 CU12 CU16 CV52 CV53 CV70-CV72 CV87-CV90 CV100-CV103 CV112-CV114 CV117-CV119 CV152-CV154 CV158 CV165-CV167 CV173-CV175 CV177 CV184-CV186 CV192-CV194 CV199 CV200 CV202 CV206-CV211 CV214 CV374-CV380 CV382-CV388 CV390-CV396 CV398-CV404 CV598-CV601 CV833 CV835-CV838 CV843 CV851-CV858 CV869-CV884 CV895-CV906 CV937-CV940 CW1-CW4 CW7-CW9 CX2 CZ9-CZ12 CZ28 CZ32 CZ33 CZ37 CZ40 CZ46 CZ47 CZ49-CZ51 CZ57 CZ86 CZ88 CZ96 CZ97 CZ102 CZ108 CZ111 LV7 LV13 PC1-PC4 PC7 PC9-PC14 PC22-PC24 PC301 PC302 PC305-PC307 PC315 PC501 PC502 PC505-PC507 PC516 PC517 PC901-PC904 PC908 PC910 PC912 PC1004 PC1008 PC1805-PC1807 PC2503-PC2505 PCA01 PCA02 PCA11 PCA12 PCA107-PCA113 PCB01 PCB02 PCB18-PCB24 PCB26 PCB28 PCB29 PCB33-PCB35 PCB38-PCB45 PCB56 PCB57 PCG01 PCG02 PCG11 PCG12 PCG111-PCG120 PCH01 PCH02 PCH06 PCH07 PCH09 PCH12 PCI03 PCI04 PCI08 PCI09 PCI18 PCI19 PCI28 PCI29 PCI38 PCI39 PCI48-PCI53 PCI101-PCI121 PCM01 PCM02 PCM11 PCM12 PCM15-PCM19 PCM22 PCM23 PCS01 PCS02 PCS03 PCS04 PCS05 PCS06 PCS07 PCS08 PCS10-PCS14 PCS16 PCS19-PCS22 PCV02 PCV03 PCV04 PCV05 PCV06 PCV07 PCV08 PCV09-PCV20 PCV30 PCV31 PCV40 PCV41 PCV54-PCV57 PCV101-PCV108 PCV201-PCV205 PCW01 PCW02 PCW07 PCW08 PCW10 PCW12-PCW15 PCW17 PCZ01 PCZ02 PCZ03 PCZ04 PCZ05 PCZ06 PCZ07 PCZ08 PCZ09-PCZ31 PCZ33-PCZ38 PRW16 = C_0402
C4 C15 C22 C151 CA1 CA3 CA5 CA11-CA13 CA15 CA20-CA26 CA32 CA33 CC29-CC32 CD1 CD2 CD6 CD7 CD10 CD19-CD26 CD32-CD34 CD37 CD40 CD49-CD56 CE5 CE24 CG288-CG290 CG320 CH52 CH53 CL24 CL25 CP8 CP28 CP29 CP32 CS35 CS36 CT73-CT75 CT90-CT93 CT98-CT100 CT106 CT154 CT155 CV50 CV51 CV79 CV80 CV83-CV86 CV91-CV97 CV120 CV156 CV160-CV164 CV168-CV172 CV179-CV183 CV187-CV191 CV213 CV373 CV381 CV389 CV397 CV597 CV834 CV839-CV842 CV844 CV845 CV859-CV868 CV885-CV894 CV941-CV947 CW5 CW6 CZ23 CZ25 CZ109 CZ110 PC5 PC6 PC8 PC308 PC309 PC508 PC509 PC515 PC907 PC909 PC911 PC913-PC916 PC1001-PC1003 PC1005-PC1007 PC1801-PC1804 PCA07 PCA08 PCA09 PCA10 PCA105 PCA106 PCB25 PCB27 PCB30 PCB36 PCB37 PCG07 PCG08 PCG09 PCG10 PCG104-PCG110 PCH08 PCH10 PCI14-PCI17 PCI24-PCI27 PCI34-PCI37 PCI44-PCI47 PCI122-PCI136 PCM05 PCM06 PCM07 PCM08 PCM09 PCM10 PCM13 PCM14 PCM20 PCM21 PCS09 PCS15 PCS23 PCV01 PCV26-PCV29 PCV36-PCV39 PCV46-PCV49 PCV109-PCV133 PCV206 PCV207 PCV211-PCV217 PCW09 PCW11 PCZ32 = C_0603
C30 C148 CS7 CS24 CS30 CS33 CS34 CU8 CU9 CU13 CU14 CU17 PC303 PC304 PC310-PC314 PC503 PC504 PC510-PC514 PC518 PC905 PC906 PC2501 PC2502 PCA03 PCA04 PCA05 PCA06 PCA101-PCA104 PCB03 PCB04 PCB05 PCB06 PCB10-PCB17 PCB31 PCB32 PCB53 PCB54 PCG03 PCG04 PCG05 PCG06 PCG101-PCG103 PCH03 PCH04 PCI10-PCI13 PCI20-PCI23 PCI30-PCI33 PCI40-PCI43 PCI137-PCI141 PCM03 PCM04 PCV21-PCV24 PCV32-PCV35 PCV42-PCV45 PCV134-PCV140 PCV208-PCV210 PCW03 PCW04 PCW05 PCW06 = C_0805
C46-C56 CA43-CA50 CC1-CC16 CC36-CC40 CC148 CC301 CC302 CE36-CE39 CG246 CG438 CG440 CG527 CH201 CP4-CP6 CP9 CP10 CP12 CP13 CP15-CP24 CP26 CS1-CS4 CS32 CT1-CT5 CT12-CT16 CT18 CT21 CT39-CT49 CT54-CT72 CT77-CT80 CT83-CT86 CT102 CT108-CT113 CT117-CT126 CT137 CT153 CU19-CU22 CV212 CV529-CV546 PCG121-PCG132 PCI142-PCI165 = C_0201
CD27 PCH13 PCH14 PCW18 PCW19 = C_D2
CE35 = C_0402-NPM
CL13 CU10 CU15 = C_1206
CLIP1 = CLIP_15X3
CLIP2 = CLIP_10P2X7P2_SHIELDING_CASE1
CLRP1 = SHORTPADS: User Part Number: PART#
D1 = BAS40C_SOT23-3
D3 D4 DA3 PDB04 PDS01 = BAT54CW_SOT323-3
D5 D6 DT19-DT21 = RB551V-30_SOD323-2
D7 DC2 = RB520SM-30T2R_EMD2-2
DA1 DA2 DA4 DA7 DC1 = L03ESDL5V0CC3-2_SOT23-3
DA5 = AZ5123-02SPR7G_SOT23-3
DA6 DF1 DU2 DU4 = AZC199-02SPR7G_SOT23-3
DA8 = BAT54ATB_SOT523-3
DE1 = AZ5125-01HPR7G_SOD523-2
DE7 DE9 DG3 DG4 DG7 DG10 DH2 DN1 DN2 DV9 DV11 DZ1 DZ2 = RB751S40T1G_SOD523-2
DH1 = RB751V40_SC76-2
DT2-DT9 = ESD101-B1-02ELS_TSSLP-2-4-2
DT10 DT11 = TVWDF1004AD0_DFN9
DT16 = PESD24VS2UT_SOT23-3
DU1 DU3 = L05ESDL5V0NA-4_SLP2510P8-10-9
F1 = F_SMD1812P150TF-24
F3 = F_MF-NSMF050-2
FD1-FD5 = FIDUCIAL_C40M80
H1 = H_3P7-G
H2 = H_3P3
H3 = H_5P6N
H4 = H_3P0
H5 = H_3P2
H6 H11 H13 H16 = H_4P0
H7 = H_3P0X3P3
H8-H10 = H_4P0-G
H12 = H_2P3
H14 = H_3P5X3P0N
H15 = H_7P0
HCPU1-HCPU4 HGPU2-HGPU4 = H_3P7
JDEG1 = JXT_FP241AH-010GAAM_10P
JDIMM1 = LOTES_ADDR0206-P001A02_260P
JDIMM2 = LOTES_ADDR0205-P001A02_260P
JEDP1 = ACES_51540-04001-P01_40P
JESPI1 = JXT_FP241AH-010GAAM_10P-NPM
JFAN1 JFAN2 JSPK1 = ACES_50224-00401-001_4P
JFP = ACES_51522-00801-001_8P
JHDD = ACES_51625-01201-001_12P
JHDMI1 = ACON_HMRBL-AK120D_19P
JHP1 = SINGA_2SJ3095-136111F_6P
JIOB1 = TWVM_FPC1020-18RC-TA0HC_18P
JKB = ACES_51698-03001-001_30P-T
JKBBL = ACES_51575-00401-001_4P
JLAN1 = SINGA_2RJ3076-058211F_8P
JP5 JP10 PJP3 PJP501 PJP1002 PJP1802 = JUMP_43X79
JSSD1 = LCN_DAN05-67306-0103_75P
JTP = ACES_51524-0080N-001_8P
JUSB1 JUSB2 = LOTES_AUSB0172-P001A_9P
JUSBC1 = FOX_UT12113-116B2-7H_24P
JWLAN1 = LOTES_APCI0136-P001A_75P
L3 LT2 LT3 LU1 LU4 LU8 LU9 = INPAQ_MCM1012B900F06BP_4P
L4 = INPAQ_MCM1012B900F06BP_4P-NPM
L5 = MURAT_BLM15PX221SN1D_2P
LA1-LA4 = MURAT_BLM15PX330SN1D_2P
LED1 = LED_LTW-295DSKS-5A_4P
LG8 = CHILI_PBY160808T-300Y-N_2P
LT1 = MAG_MND-04ABIR60M-XGL_2P
LT4 = MURAT_LQM18PN1R0MFHD_2P
LU2 LU3 LU5 LU6 = INPAQ_HCM1012GH900BP_4P
LV3-LV6 = INPAQ_HCM1012GH900BP_4P-NPM
PBATT1 = ACES_50458-01001-P01_10P-T
PCB07 PCI05 PCI06 PCI07 = C_EEFCX1E330R
PCG171 PCG172 = C_EEFSS0D221R
PCI171-PCI173 PCV173 PCV272 = C_X
PCV50 = C_ECST250ADA101MF611
PCV171 PCV172 PCV271 = C_D1
PD1 PD5 PD6 = TVNST52302AB0_SOT523-3
PD2 PD3 = BAV99W_SC70-3
PD4 PD7 PDS02 PDS07 = PDS5100H-13_POWERDI5-3
PD10 PDS03 = LRB715FT1G_SOT323-3
PD12 = DFLS160-7_POWERDI123-2
PD13 PD14 = PJSOT24C_SOT23-3
PD501 PDB01 PDB02 PDB03 PDB05 PDS04 PDS05 PDS06 = SDMK0340L-7-F_SOD323-2
PHV01 PHZ01 PHZ02 PHZ03 PHZ04 PHZ05 PR1-PR17 PR22 PR31 PR33-PR48 PR50-PR52 PR62-PR65 PR100 PR302-PR304 PR306-PR308 PR502-PR504 PR506-PR511 PR901 PR903-PR906 PR908-PR913 PR1001 PR1002 PR1004-PR1007 PR1801-PR1803 PR1805-PR1807 PR2501-PR2504 PRB02 PRB03 PRB04 PRB05 PRB07 PRB09-PRB11 PRB13 PRB14 PRB16 PRB19-PRB45 PRB50 PRB51 PRB57 PRB59-PRB61 PRB68 PRB70 PRG03 PRH01 PRH03 PRH04 PRH05 PRH10 PRH13 PRH14 PRI03 PRI07 PRI11 PRI15 PRM03 PRM06 PRM07 PRM08 PRM09-PRM11 PRS01 PRS02 PRS03 PRS04 PRS05 PRS06 PRS07 PRS08 PRS09-PRS12 PRS14-PRS16 PRS23 PRS25-PRS30 PRS32-PRS34 PRS36-PRS51 PRV01 PRV02 PRV03 PRV04 PRV06 PRV07 PRV08 PRV09-PRV11 PRV13-PRV38 PRV40 PRV43-PRV46 PRV50 PRV54 PRV58 PRW02 PRW03 PRW06 PRW07 PRW08 PRW09-PRW15 PRW17-PRW19 PRZ02 PRZ03 PRZ05 PRZ06 PRZ08 PRZ10-PRZ12 PRZ14-PRZ34 PRZ40-PRZ42 PRZ44-PRZ50 PRZ52 PRZ54-PRZ64 PRZ66-PRZ77 R1 R2 R5 R9 R10 R19-R22 R24-R34 R38-R43 R45-R49 R57 R68 R69 R73 R78 R79 R82 R83 RA3 RA7-RA11 RA23-RA34 RA41-RA43 RC1-RC5 RC8-RC13 RC15 RC16 RC19 RC20 RC22 RC46 RC76-RC78 RC80 RC83-RC86 RC144 RC145 RC224 RC249 RC250 RC252-RC264 RC267-RC277 RC442 RD1-RD24 RE1 RE3 RE4 RE6 RE8-RE11 RE14-RE19 RE21 RE23 RE25 RE29-RE32 RE41 RE43 RE45-RE49 RE51 RE52 RE54 RE59 RE68 RE70 RE82 RE89 RE90 RE100 RE101 RE150-RE153 RE155-RE157 RE161-RE169 RG37 RG50 RG51 RG70 RG509-RG514 RG543 RG544 RG546 RG549 RG550 RG557 RG573 RG575 RG576 RG580 RH1 RH13 RH14 RH16 RH20 RH33 RH38 RH39 RH64-RH66 RH70-RH75 RH78 RH79 RH83 RH84 RH93 RH104 RH109 RH130 RH143 RH174 RH501 RH502 RH506 RH515 RH520 RH524 RH531 RH571 RH578 RH588 RH589 RH613 RH614 RH658 RH665-RH671 RH685 RH697 RH698 RH701 RH706-RH710 RH727 RH735-RH737 RH747 RH748 RL2-RL4 RL6-RL9 RL17 RP9 RP10 RP24 RP25 RP30-RP32 RP39-RP44 RS2-RS5 RS9 RSPI1 RT5 RT19 RT25 RT48-RT51 RT59 RT60 RT64 RT65 RT75 RT95 RT118-RT120 RT130-RT133 RT156 RT157 RTPM1-RTPM4 RTPM6-RTPM12 RV27 RV37 RV39 RV41 RV42 RV49-RV52 RV55 RV57 RV58 RV60 RV62 RV63 RV66 RV77-RV79 RV95 RV96 RV98 RV99 RV107 RV108 RV110 RV111 RV116 RV117 RV120 RV121 RV125-RV127 RV131 RV132 RV135 RV136 RV140-RV142 RV146-RV150 RV152-RV162 RV191 RV192 RV500-RV503 RV512-RV515 RV526 RV532 RV571-RV574 RV593-RV605 RV638-RV643 RV645 RV646 RV676-RV679 RV682 RV684 RW4 RW9 RW11-RW13 RW15 RW18-RW21 RW25-RW30 RX6 RX8 RZ21 RZ49 RZ102 RZ108 RZ111 RZ112 = R_0402
PJP1 PJP4 PJP302 PJP303 PJP502 PJP503 PJP902 PJPB01 PJPB02 PJPB03 PJPB04 PJPB05 PJPB06 PJPB07 PJPB08 PJPH02 PJPH03 PJPM02 PJPM04 PJPW02 PJPW03 = JUMP_43X118
PJP301 PJP901 PJP1001 PJP1801 PJP2501 PJP2502 PJPH01 PJPM01 PJPM03 PJPW01 = JUMP_43X39
PJPDC1 = ACES_51202-00901-001_9P-T
PL1 PL4-PL7 PL311 PL511 PL911 PL1011 PL1811 PLB11-PLB13 PLH11 PLM11 PLS11 PLS12 PLW11 = 5A_Z120_0805_2P
PL3 = MURAT_BLM15AG102SN1D_2P
PL301 PL501 PLH01 PLM01 = L_7X7X3_M_2P
PL901 = CYNTE_PCMB042T-1R0MS_2P
PL1001 = MAGLA_MMD-05CZ-1R0M-M7L_2P
PL1801 = L_5X5X3_M_2P
PLA01 = MAG_MMD05CZR47M_4P
PLB01 = TAI-T_TMPA1005S-2R2MN-D_2P
PLG01 PLI01 PLI02 PLI03 PLI04 = L_7X7X3_M
PLI11 PLIV11 = KC_FBMA-L11-453215800LMA90T_2P
PLV01 PLV02 PLV03 = L_7X7X4_M
PLW01 = MAG_MMD-06CZ-R82M-V1L_2P
PQ1 = FDV301N-G_SOT23-3
PQ2 = LMBT3904WT1G_SC70-3
PQ3 PQ4 PQ7 PQ8 PQB03 PQS01 PQS02 PQS15-PQS18 = AON7409_DFN8-5
PQ5 PQ6 PQ11 PQ15-PQ18 PQ20 PQ21 PQB04 PQB05 PQS03 PQS04 PQS08 PQS11 PQS12 PQS19 = 2N7002KW_SOT323-3
PQ12 PQ13 PQS05 PQS10 PQS22 = 2N7002KDW_SOT363-6
PQ19 PQS06 PQS13 PQS20 = AO3409_SOT23-3
PQB01 PQB02 PQB07 PQH01 PQW01 = AON6962_DFN5X6D-8-7
PQB06 = AON7380_DFN3X3-8-5
PQB10 = LTC015EUBFS8TL_UMT3F
PQB11 = LMUN5113T1G_SOT323-3
PQM01 = AONH36334_DFN3X3A8-10
PQS07 PQS21 = DMN65D8LW-7_SOT323-3
PR32 PR305 PR505 PR907 PR1804 PRA04 PRB17 PRB18 PRG04 PRH06 PRI04 PRI08 PRI12 PRI16 PRM01 PRV49 PRV53 PRV57 PRW04 RH89 = R_1206
PR301 PR501 PR902 PR1003 PRA01 PRA02 PRB06 PRB15 PRB46 PRB65-PRB67 PRB69 PRG01 PRG02 PRH02 PRI01 PRI02 PRI05 PRI06 PRI09 PRI10 PRI13 PRI14 PRM02 PRM04 PRM05 PRV05 PRV39 PRV41 PRV42 PRV47 PRV48 PRV51 PRV52 PRV55 PRV56 PRW01 PRW05 PRZ13 PRZ35-PRZ38 PRZ51 PRZ53 R13 R36 R37 RC251 RE2 RE50 RH731 RH732 RL14 RL15 RL19 RL20 RS8 = R_0603
PRB01 PRB12 = R_1206_4P-D
PRB08 RC14 RW3 RW5 = R_0805
PU01 = RT9069-33GB_SOT23-5
PU301 = SY8288BRAC_QFN20_3X3
PU501 = SY8288CRAC_QFN20_3X3
PU901 = SY8286RAC_QFN20_3X3
PU1001 PU1801 = RT8061AZQW_WDFN10_3X3
PU2501 = RT9059GSP_SO8
PUA01 PUG01 PUI01 PUI02 PUI03 PUI04 PUV01 PUV02 PUV03 = NCP302045MNTXG_PQFN33_5X5
PUB01 = ISL9538HRTZ-T_TQFN32_4X4
PUB02 PUS02 UH3 = TC7SH08FU_SSOP5
PUH01 = TPS51212DSCR_SON10_3X3
PUM01 = RT8207PGQW_WQFN20_3X3
PUS01 = LM393DGKR_VSSOP8
PUS03 = TC7SH32FU_SSOP5
PUS04 = AP2204R-5P0TRG1_SOT89-3
PUV101 = NCP81276MNTXG_QFN40_5X5
PUW01 = RT8816AGQW_WQFN20_3X3
PUZ01 = NCP81215MNTXG_QFN52_6X6
Q1 Q12 Q13 Q23 Q24 QH7 = 2N7002K_SOT23-3
Q6 Q9 Q22 QA1 = LN2306LT1G_SOT23-3
Q7 Q18 Q19 = DDTA144VCA-7-F_SOT23-3
Q8 = SSM3K7002FU_SC70-3
Q10 Q11 Q17 Q27 QS1 = DMN66D0LDW-7_SOT363-6
Q14 = LMBT3904LT1G_SOT23-3
Q25 Q29 Q30 = L2N7002WT1G_SC-70-3
Q26 = LP2301ALT1G_SOT23-3
QG10 QV3 QV20 QV21 = 2N7002W-T-R7_SOT323-3
QG23 QH4 QV96 = DMN65D8LDW-7_SOT363-6
QG502-QG506 QH10 QV1 = 2N7002DW-7-F_SOT363-6
QH8 QH9 = L2N7002DW1T1G_SC88-6
QV10 = BSS138DW_SC88-6
QX3 = MMBT3904WH_SOT323-3
R3 RA1 RA22 = R0805_0OHM
R6 R8 R35 R77 RA2 RA5 RA6 RA12 RA17 RA18 RA40 RE28 RE37 RE42 RE85 RE158 RH150 RH162 RL13 RS1 RT97 RT168 RV28-RV30 RV33 RV34 RV583-RV586 RV590 RV655 RV673-RV675 RV680 RV681 RV683 = R0402_0OHM
R16 RA4 RE7 RE66 RE104 RE105 RP28 RP51 RP52 RT134 RZ48 RZ67 = R0603_0OHM
R3004-R3008 R3010 R3019 R3021 R3023-R3026 RC6 RC7 RC44 RC45 RE53 RE55-RE58 RE60-RE63 RE121 RE122 RE149 RF1 RG9 RG505 RG506 RG516 RG551 RG553 RG554 RH4 RH11 RH12 RH23 RH24 RH29 RH30 RH62 RH63 RH69 RH90 RH94 RH103 RH105 RH128 RH135 RH179 RH180 RH199 RH453 RH455 RH462 RH463 RH503 RH512 RH521 RH533 RH537 RH545 RH546 RH551-RH554 RH557 RH561 RH562 RH573 RH580 RH581 RH656 RH672-RH676 RH679-RH684 RH687 RH699 RH700 RH705 RH711-RH714 RH716 RH717 RH719 RH721-RH726 RH728 RH734 RH738-RH746 RH749 RP33-RP38 RP45 RP48 RP49 RS10 RT1-RT4 RT6-RT18 RT20 RT21 RT23 RT24 RT26-RT37 RT40 RT42-RT47 RT57 RT58 RT61-RT63 RT66-RT74 RT76 RT78 RT80 RT83 RT86 RT94 RT101 RT102 RT108 RT111-RT115 RT122 RT123 RT125-RT129 RT152-RT155 RT159-RT167 RV40 RV56 RW31 RZ71 RZ234 RZ237 RZ238 = R_0201
RA13-RA16 = MURAT_BLM15PD600SN1D_2P
RE65 RE67 = R_0402-NPM
RE160 RP11 = R0201_0OHM
RP1-RP3 RP50 RPE1-RPE7 RPH5-RPH7 RPT1 = RP_0804_8P4R
SW1 = SW_TST71-N-220-T170-S017_2P
T2 T7 T9 T45 T47 T62 T63 T65 T92 T97-T101 T4937-T4943 TC1 TC4-TC59 TC94-TC101 TC103-TC111 TH1-TH8 TH101 TH138 TH139 TH141-TH143 TH145 TH148 TP40-TP44 TP74 TPC1-TPC33 TPS10 ZTB02 = TPC12
TL1 = MHPC_NS692417_24P
U1 U3 UL2 UW1 = SY6288C20AAC_SOT23-5
U2 = NCT7718W_MSOP8
UA1 = ALC3204-CG_MQFN40_5X5
UC1 = CFL-H_BGA_1440P-T
UC10 UC16 = 74AUP1G07GW_TSSOP5
UC12 = TC7SH08FUF_SSOP5
UE1 = MEC1416-NU-D0_VTQFP128_14X14
UE2 = NL17SZ06DFT2G_SC70-5
UG12 = TPS22966DPUR_SON14_2X3
UG22 UG31 UV14 UV19 UV20 = NL17SZ08DFT2G_SC70-5
UG25 UG27 = 74LVC1G32GW_TSSOP5
UH1 = CNP-H_BGA_874P-T
UH4 = W25Q256FVEIQ_WSON8_8X6-NPM
UH14 UZ21 = MC74VHC1G08DFT2G_SC70-5
UH15 = W25Q128FVSIQ_SO8
UL1 = RTL8111H-CG_QFN32_4X4
UP1 = RT9041E-15GQW_WDFN8_2X2
UP2 = PS8409AQFN48GTR2-A0_QFN48_6X6
US1 = LNG2DMTR_LGA12_2X2
US2 UU1 UU3 = SY6288D20AAC_SOT23-5
UT1 = ALPINE-RIDGE_BGA_337P
UT2 = W25Q80DVSSIG_SO8
UT3 = W25X20CLSNIG_SO8
UT4 = TPS65982DAZQZR-ES_BGA_96P
UTPM1 = NPCT650VB2YX_QFN32_5X5
UV1 = N15P-GT_BGA_908P
UV6-UV9 = H5GQ1H24AFR-T2L_BGA_170P
UV17 = AP2330W-7_SC59-3
UZ1 = EM5209VF_DFN14_3X2
UZ7 = TPS22967DSGR_SON8_2X2
UZ9 UZ15 = TPS22961DNYR_WSON8
UZ16 = AOZ1336DI_DFN8_2X2
YE1 = Y_X1A000141000200_2P
YH1 = Y_CM31532768DZFT_2P
YH2 = Y_X3G024000DC1H_4P
YL1 = Y_7V25000014_4P
YT1 = Y_7V25000012_4P
YV1 = Y_7V27000011_4P

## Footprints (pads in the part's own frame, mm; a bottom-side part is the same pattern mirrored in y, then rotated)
2N7002DW-7-F_SOT363-6
  oval 0.432x0.61 smd: 1(0,0) 2(0.65,0) 3(1.3,0) 4(1.3,1.9) 5(0.65,1.9) 6(0,1.9)
2N7002K_SOT23-3
  oval 1.016x1.524 smd: 1(0,0) 2(0.965,2.083) 3(-0.965,2.083)
2N7002KDW_SOT363-6
  oval 0.356x0.889 smd: 1(0,0) 2(0.65,0) 3(1.3,0) 4(1.3,1.6) 5(0.65,1.6) 6(0,1.6)
2N7002KW_SOT323-3
  oval 0.66x0.864 smd: 1(0,0) 2(0.65,1.85) 3(-0.65,1.85)
2N7002W-T-R7_SOT323-3
  oval 0.813x0.914 smd: 1(0,0) 2(0.65,1.6) 3(-0.65,1.6)
5A_Z120_0805_2P
  rect 0.813x1.397 smd: 1(0,0) 2(1.702,0)
74AUP1G07GW_TSSOP5
  oval 0.381x1.346 smd: 1(0,0) 2(0.65,0) 3(1.3,0) 4(1.3,1.79) 5(0,1.79)
74LVC1G32GW_TSSOP5
  oval 0.381x1.346 smd: 1(0,0) 2(0.65,0) 3(1.3,0) 4(1.3,1.79) 5(0,1.79)
ACES_50224-00401-001_4P
  oval 0.61x1.549 smd: 1(0,0) 2(1,0) 3(2,0) 4(3,0)
  rect 1.194x1.803 smd: 5(4.3,-3.875) 6(-1.3,-3.875)
ACES_50458-01001-P01_10P-T
  oval 0.559x1.803 smd: 1(0,0) 2(2,0) 3(4,0) 4(6,0) 5(8,0) 6(10,0) 7(12,0) 8(14,0) 9(16,0) 10(18,0)
  rect 1.295x2.057 smd: 11(-3.1,-5.275) 12(21.1,-5.275)
ACES_51202-00901-001_9P-T
  rect 0.66x5.004 smd: 1(0,0) 2(1.5,0) 3(3,0) 4(4.5,0) 5(6,0) 6(7.5,0) 7(9,0) 8(10.5,0) 9(12,0)
  rect 2.489x2.997 smd: 10(-2.5,-4.45) 11(14.5,-4.45)
ACES_51522-00801-001_8P
  oval 0.305x1.295 smd: 1(0,0) 2(0.5,0) 3(1,0) 4(1.5,0) 5(2,0) 6(2.5,0) 7(3,0) 8(3.5,0)
  rect 2.489x1.905 smd: 9(5.65,-3.3) 10(-2.15,-3.3)
ACES_51524-0080N-001_8P
  oval 0.61x1.295 smd: 1(0,0) 2(1,0) 3(2,0) 4(3,0) 5(4,0) 6(5,0) 7(6,0) 8(7,0)
  rect 2.489x2.21 smd: 9(10,-3.05) 10(-3,-3.05)
ACES_51540-04001-P01_40P
  oval 0.305x1.092 smd: 1(0,0) 2(0.5,0) 3(1,0) 4(1.5,0) 5(2,0) 6(2.5,0) 7(3,0) 8(3.5,0) 9(4,0) 10(4.5,0) 11(5,0) 12(5.5,0) 13(6,0) 14(6.5,0) 15(7,0) 16(7.5,0) 17(8,0) 18(8.5,0) 19(9,0) 20(9.5,0) 21(10,0) 22(10.5,0) 23(11,0) 24(11.5,0) 25(12,0) 26(12.5,0) 27(13,0) 28(13.5,0) 29(14,0) 30(14.5,0) 31(15,0) 32(15.5,0) 33(16,0) 34(16.5,0) 35(17,0) 36(17.5,0) 37(18,0) 38(18.5,0) 39(19,0) 40(19.5,0)
  rect 0.787x2.489 smd: 41(21.2,-3.6) 42(-1.7,-3.6)
ACES_51575-00401-001_4P
  oval 0.406x0.838 smd: 1(0,0) 2(1,0) 3(2,0) 4(3,0)
  rect 0.787x2.007 smd: 5(-2.2,-3.175) 6(5.2,-3.175)
ACES_51625-01201-001_12P
  oval 0.305x1.092 smd: 1(0,0) 2(0.5,0) 3(1,0) 4(1.5,0) 5(2,0) 6(2.5,0) 7(3,0) 8(3.5,0) 9(4,0) 10(4.5,0) 11(5,0) 12(5.5,0)
  rect 0.991x2.489 smd: 13(-1.8,-3.6) 14(7.3,-3.6)
ACES_51698-03001-001_30P-T
  oval 0.229x1.092 smd: 1(0,0) 2(-0.8,0) 3(-1.6,0) 4(-2.4,0) 5(-3.2,0) 6(-4,0) 7(-4.8,0) 8(-5.6,0) 9(-6.4,0) 10(-7.2,0) 11(-8,0) 12(-8.8,0) 13(-9.6,0) 14(-10.4,0) 15(-11.2,0) 16(-12,0) 17(-12.8,0) 18(-13.6,0) 19(-14.4,0) 20(-15.2,0) 21(-16,0) 22(-16.8,0) 23(-17.6,0) 24(-18.4,0) 25(-19.2,0) 26(-20,0) 27(-20.8,0) 28(-21.6,0) 29(-22.4,0) 30(-23.2,0)
  rect 0.559x1.295 smd: 31(-24.825,-3.45) 32(1.625,-3.45)
ACON_HMRBL-AK120D_19P
  round 0.813 hole 0.559: 1(0,0) 2(0.5,1.55) 3(1,0) 4(1.5,1.55) 5(2,0) 6(2.5,1.55) 7(3,0) 8(3.5,1.55) 9(4,0) 10(4.5,1.55) 11(5,0) 12(5.5,1.55) 13(6,0) 14(6.5,1.55) 15(7,0) 16(7.5,1.55) 17(8,0) 18(8.5,1.55) 19(9,0)
  oval 1.397x2.21 hole 0.787x1.6: 20(-2.75,0.2) 21(11.75,0.2)
  oval 1.702x2.997 hole 1.092x2.388: 22(-4.25,-8.15) 23(13.25,-8.15)
ALC3204-CG_MQFN40_5X5
  oval 0.889x0.203 smd: 1(0,0) 2(0,-0.4) 3(0,-0.8) 4(0,-1.2) 5(0,-1.6) 6(0,-2) 7(0,-2.4) 8(0,-2.8) 9(0,-3.2) 10(0,-3.6) 21(5.1,-3.6) 22(5.1,-3.2) 23(5.1,-2.8) 24(5.1,-2.4) 25(5.1,-2) 26(5.1,-1.6) 27(5.1,-1.2) 28(5.1,-0.8) 29(5.1,-0.4) 30(5.1,0)
  oval 0.203x0.889 smd: 11(0.75,-4.35) 12(1.15,-4.35) 13(1.55,-4.35) 14(1.95,-4.35) 15(2.35,-4.35) 16(2.75,-4.35) 17(3.15,-4.35) 18(3.55,-4.35) 19(3.95,-4.35) 20(4.35,-4.35) 31(4.35,0.75) 32(3.95,0.75) 33(3.55,0.75) 34(3.15,0.75) 35(2.75,0.75) 36(2.35,0.75) 37(1.95,0.75) 38(1.55,0.75) 39(1.15,0.75) 40(0.75,0.75)
  rect 3.607x3.607 smd: 41(2.55,-1.8)
ALPINE-RIDGE_BGA_337P
  round 0.254 smd: A1(0,0) A23(10.12,0) AA2(0.46,-9.2) AA22(9.66,-9.2) AB2(0.46,-9.66) AB3(0.92,-9.66) AB4(1.38,-9.66) AB5(1.84,-9.66) AB6(2.3,-9.66) AB7(2.76,-9.66) AB8(3.22,-9.66) AB9(3.68,-9.66) AB10(4.14,-9.66) AB11(4.6,-9.66) AB12(5.06,-9.66) AB13(5.52,-9.66) AB14(5.98,-9.66) AB15(6.44,-9.66) AB16(6.9,-9.66) AB17(7.36,-9.66) AB18(7.82,-9.66) AB19(8.28,-9.66) AB20(8.74,-9.66) AB21(9.2,-9.66) AB22(9.66,-9.66) AC1(0,-10.12) AC23(10.12,-10.12) B2(0.46,-0.46) B3(0.92,-0.46) B4(1.38,-0.46) B5(1.84,-0.46) B6(2.3,-0.46) B7(2.76,-0.46) B8(3.22,-0.46) B9(3.68,-0.46) B10(4.14,-0.46) B11(4.6,-0.46) B12(5.06,-0.46) B13(5.52,-0.46) B14(5.98,-0.46) B15(6.44,-0.46) B16(6.9,-0.46) B17(7.36,-0.46) B18(7.82,-0.46) B19(8.28,-0.46) B20(8.74,-0.46) B21(9.2,-0.46) B22(9.66,-0.46) C2(0.46,-0.92) C22(9.66,-0.92) D2(0.46,-1.38) D4(1.16,-1.16) D5(1.81,-1.16) D6(2.46,-1.16) D8(3.11,-1.16) D9(3.76,-1.16) D11(4.41,-1.16) D12(5.06,-1.16) D13(5.71,-1.16) D15(6.36,-1.16) D16(7.01,-1.16) D18(7.66,-1.16) D19(8.31,-1.16) D20(8.96,-1.16) D22(9.66,-1.38) E2(0.46,-1.84) E4(1.16,-1.81) E5(1.81,-1.81) E6(2.46,-1.81) E8(3.11,-1.81) E9(3.76,-1.81) E11(4.41,-1.81) E12(5.06,-1.81) E13(5.71,-1.81) E15(6.36,-1.81) E16(7.01,-1.81) E18(7.66,-1.81) E19(8.31,-1.81) E20(8.96,-1.81) E22(9.66,-1.84) F2(0.46,-2.3) F4(1.16,-2.46) F5(1.81,-2.46) F6(2.46,-2.46) F8(3.11,-2.46) F9(3.76,-2.46) F11(4.41,-2.46) F12(5.06,-2.46) F13(5.71,-2.46) F15(6.36,-2.46) F16(7.01,-2.46) F18(7.66,-2.46) F19(8.31,-2.46) F20(8.96,-2.46) F22(9.66,-2.3) G2(0.46,-2.76) G22(9.66,-2.76) H2(0.46,-3.22) H4(1.16,-3.11) H5(1.81,-3.11) H6(2.46,-3.11) H8(3.11,-3.11) H9(3.76,-3.11) H11(4.41,-3.11) H12(5.06,-3.11) H13(5.71,-3.11) H15(6.36,-3.11) H16(7.01,-3.11) H18(7.66,-3.11) H19(8.31,-3.11) H20(8.96,-3.11) H22(9.66,-3.22) J2(0.46,-3.68) J4(1.16,-3.76) J5(1.81,-3.76) J6(2.46,-3.76) J8(3.11,-3.76) J9(3.76,-3.76) J11(4.41,-3.76) J12(5.06,-3.76) J13(5.71,-3.76) J15(6.36,-3.76) J16(7.01,-3.76) J18(7.66,-3.76) J19(8.31,-3.76) J20(8.96,-3.76) J22(9.66,-3.68) K2(0.46,-4.14) K22(9.66,-4.14) L2(0.46,-4.6) L4(1.16,-4.41) L5(1.81,-4.41) L6(2.46,-4.41) L8(3.11,-4.41) L9(3.76,-4.41) L11(4.41,-4.41) L12(5.06,-4.41) L13(5.71,-4.41) L15(6.36,-4.41) L16(7.01,-4.41) L18(7.66,-4.41) L19(8.31,-4.41) L20(8.96,-4.41) L22(9.66,-4.6) M2(0.46,-5.06) M4(1.16,-5.06) M5(1.81,-5.06) M6(2.46,-5.06) M8(3.11,-5.06) M9(3.76,-5.06) M11(4.41,-5.06) M12(5.06,-5.06) M13(5.71,-5.06) M15(6.36,-5.06) M16(7.01,-5.06) M18(7.66,-5.06) M19(8.31,-5.06) M20(8.96,-5.06) M22(9.66,-5.06) N2(0.46,-5.52) N4(1.16,-5.71) N5(1.81,-5.71) N6(2.46,-5.71) N8(3.11,-5.71) N9(3.76,-5.71) N11(4.41,-5.71) N12(5.06,-5.71) N13(5.71,-5.71) N15(6.36,-5.71) N16(7.01,-5.71) N18(7.66,-5.71) N19(8.31,-5.71) N20(8.96,-5.71) N22(9.66,-5.52) P2(0.46,-5.98) P22(9.66,-5.98) R2(0.46,-6.44) R4(1.16,-6.36) R5(1.81,-6.36) R6(2.46,-6.36) R8(3.11,-6.36) R9(3.76,-6.36) R11(4.41,-6.36) R12(5.06,-6.36) R13(5.71,-6.36) R15(6.36,-6.36) R16(7.01,-6.36) R18(7.66,-6.36) R19(8.31,-6.36) R20(8.96,-6.36) R22(9.66,-6.44) T2(0.46,-6.9) T4(1.16,-7.01) T5(1.81,-7.01) T6(2.46,-7.01) T8(3.11,-7.01) T9(3.76,-7.01) T11(4.41,-7.01) T12(5.06,-7.01) T13(5.71,-7.01) T15(6.36,-7.01) T16(7.01,-7.01) T18(7.66,-7.01) T19(8.31,-7.01) T20(8.96,-7.01) T22(9.66,-6.9) U2(0.46,-7.36) U22(9.66,-7.36) V2(0.46,-7.82) V4(1.16,-7.66) V5(1.81,-7.66) V6(2.46,-7.66) V8(3.11,-7.66) V9(3.76,-7.66) V11(4.41,-7.66) V12(5.06,-7.66) V13(5.71,-7.66) V15(6.36,-7.66) V16(7.01,-7.66) V18(7.66,-7.66) V19(8.31,-7.66) V20(8.96,-7.66) V22(9.66,-7.82) W2(0.46,-8.28) W4(1.16,-8.31) W5(1.81,-8.31) W6(2.46,-8.31) W8(3.11,-8.31) W9(3.76,-8.31) W11(4.41,-8.31) W12(5.06,-8.31) W13(5.71,-8.31) W15(6.36,-8.31) W16(7.01,-8.31) W18(7.66,-8.31) W19(8.31,-8.31) W20(8.96,-8.31) W22(9.66,-8.28) Y2(0.46,-8.74) Y4(1.16,-8.96) Y5(1.81,-8.96) Y6(2.46,-8.96) Y8(3.11,-8.96) Y9(3.76,-8.96) Y11(4.41,-8.96) Y12(5.06,-8.96) Y13(5.71,-8.96) Y15(6.36,-8.96) Y16(7.01,-8.96) Y18(7.66,-8.96) Y19(8.31,-8.96) Y20(8.96,-8.96) Y22(9.66,-8.74)
  oval 0.178x0.33 smd: A2(0.46,0) A3(0.92,0) A4(1.38,0) A5(1.84,0) A6(2.3,0) A7(2.76,0) A8(3.22,0) A9(3.68,0) A10(4.14,0) A11(4.6,0) A12(5.06,0) A13(5.52,0) A14(5.98,0) A15(6.44,0) A16(6.9,0) A17(7.36,0) A18(7.82,0) A19(8.28,0) A20(8.74,0) A21(9.2,0) A22(9.66,0) AC2(0.46,-10.12) AC3(0.92,-10.12) AC4(1.38,-10.12) AC5(1.84,-10.12) AC6(2.3,-10.12) AC7(2.76,-10.12) AC8(3.22,-10.12) AC9(3.68,-10.12) AC10(4.14,-10.12) AC11(4.6,-10.12) AC12(5.06,-10.12) AC13(5.52,-10.12) AC14(5.98,-10.12) AC15(6.44,-10.12) AC16(6.9,-10.12) AC17(7.36,-10.12) AC18(7.82,-10.12) AC19(8.28,-10.12) AC20(8.74,-10.12) AC21(9.2,-10.12) AC22(9.66,-10.12)
  oval 0.33x0.178 smd: AA1(0,-9.2) AA23(10.12,-9.2) AB1(0,-9.66) AB23(10.12,-9.66) B1(0,-0.46) B23(10.12,-0.46) C1(0,-0.92) C23(10.12,-0.92) D1(0,-1.38) D23(10.12,-1.38) E1(0,-1.84) E23(10.12,-1.84) F1(0,-2.3) F23(10.12,-2.3) G1(0,-2.76) G23(10.12,-2.76) H1(0,-3.22) H23(10.12,-3.22) J1(0,-3.68) J23(10.12,-3.68) K1(0,-4.14) K23(10.12,-4.14) L1(0,-4.6) L23(10.12,-4.6) M1(0,-5.06) M23(10.12,-5.06) N1(0,-5.52) N23(10.12,-5.52) P1(0,-5.98) P23(10.12,-5.98) R1(0,-6.44) R23(10.12,-6.44) T1(0,-6.9) T23(10.12,-6.9) U1(0,-7.36) U23(10.12,-7.36) V1(0,-7.82) V23(10.12,-7.82) W1(0,-8.28) W23(10.12,-8.28) Y1(0,-8.74) Y23(10.12,-8.74)
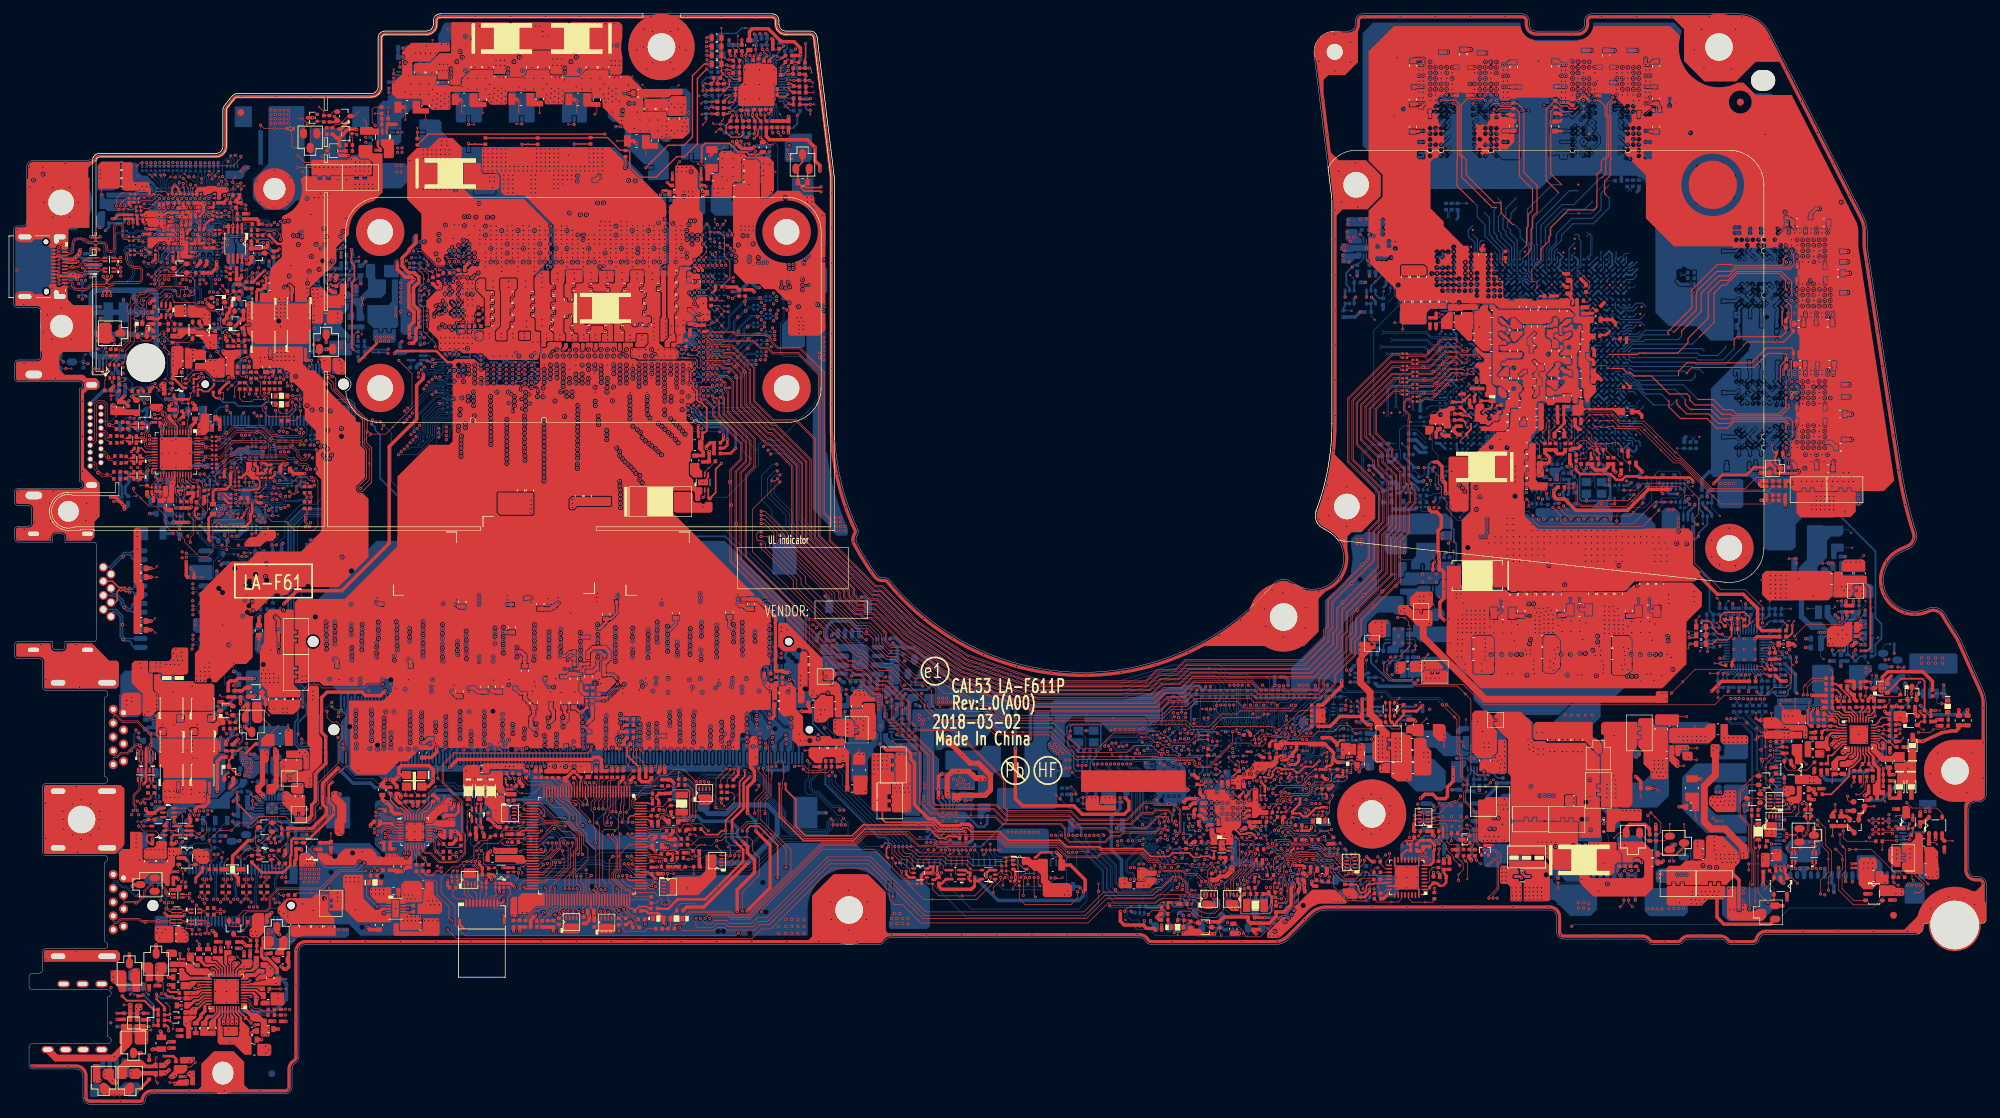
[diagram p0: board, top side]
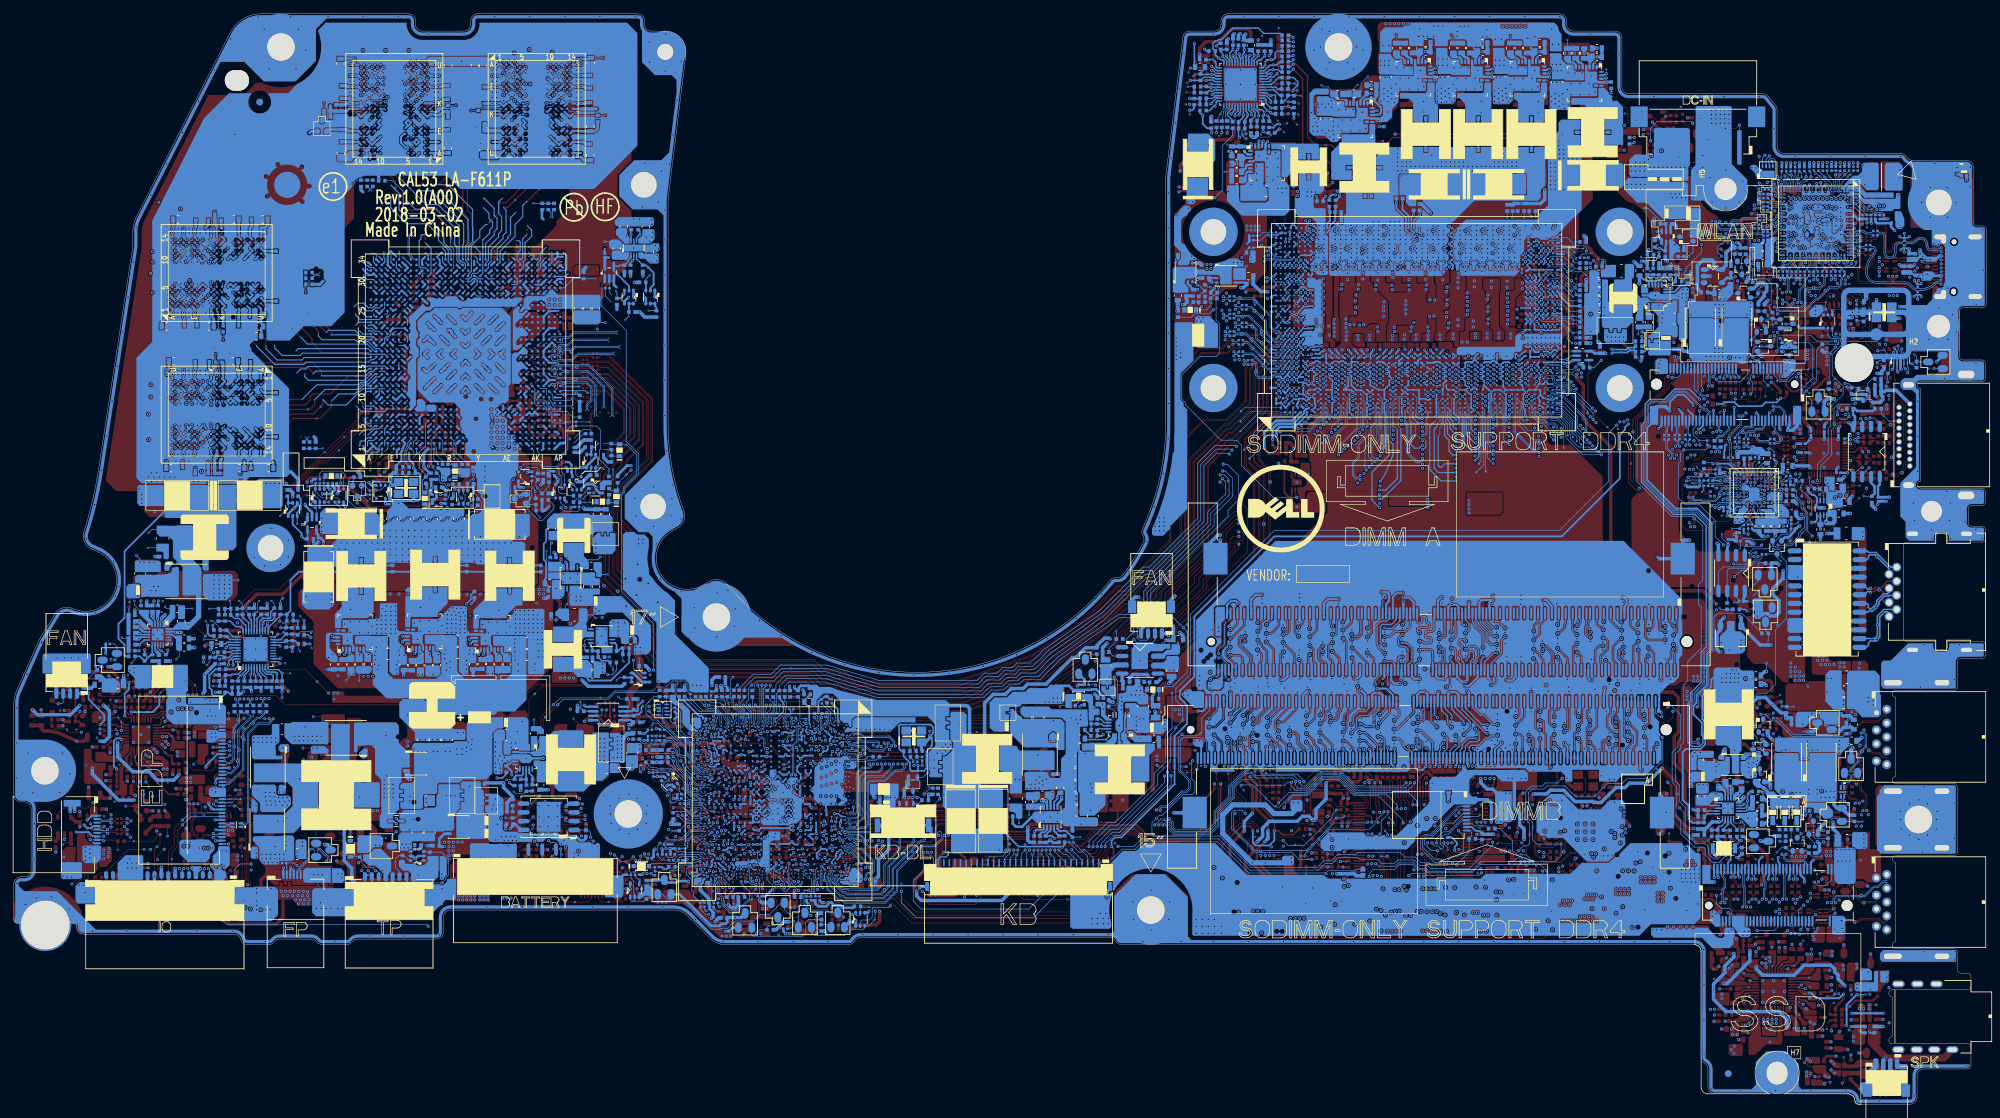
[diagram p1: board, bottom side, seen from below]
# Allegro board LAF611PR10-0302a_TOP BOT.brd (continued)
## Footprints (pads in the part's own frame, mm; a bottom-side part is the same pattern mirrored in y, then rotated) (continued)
H_2P3
  round 2.819 hole 2.311: 1(0,0)
H_3P0
  round 3.505 hole 2.997: 1(0,0)
H_3P0X3P3
  oval 3.505x3.81 hole 2.997x3.302: 1(0,0)
H_3P2
  round 3.708 hole 3.2: 1(0,0)
H_3P3
  round 3.81 hole 3.302: 1(0,0)
H_3P5X3P0N
  oval 3.505x2.997 hole 3.505x2.997 unplated: (0,0)
H_3P7
  round 4.216 hole 3.708: 1(0,0)
H_3P7-G
  round 4.216 hole 3.708: 1(0,0)
H_4P0
  round 4.496 hole 3.988: 1(0,0)
H_4P0-G
  round 4.496 hole 3.988: 1(0,0)
H_5P6N
  round 5.588 hole 5.588 unplated: (0,0)
H_7P0
  round 7.518 hole 7.01: 1(0,0)
INPAQ_HCM1012GH900BP_4P
  rect 0.711x0.305 smd: 1(0,0) 2(1.25,0) 3(1.25,-0.5) 4(0,-0.5)
INPAQ_HCM1012GH900BP_4P-NPM
  rect 0.711x0.305 smd: 1(0,0) 2(1.25,0) 3(1.25,-0.5) 4(0,-0.5)
INPAQ_MCM1012B900F06BP_4P
  rect 0.711x0.305 smd: 1(0,0) 2(1.25,0) 3(1.25,-0.5) 4(0,-0.5)
INPAQ_MCM1012B900F06BP_4P-NPM
  rect 0.711x0.305 smd: 1(0,0) 2(1.25,0) 3(1.25,-0.5) 4(0,-0.5)
ISL9538HRTZ-T_TQFN32_4X4
  oval 0.787x0.203 smd: 1(0,0) 2(0,-0.4) 3(0,-0.8) 4(0,-1.2) 5(0,-1.6) 6(0,-2) 7(0,-2.4) 8(0,-2.8) 17(4.2,-2.8) 18(4.2,-2.4) 19(4.2,-2) 20(4.2,-1.6) 21(4.2,-1.2) 22(4.2,-0.8) 23(4.2,-0.4) 24(4.2,0)
  oval 0.203x0.787 smd: 9(0.7,-3.5) 10(1.1,-3.5) 11(1.5,-3.5) 12(1.9,-3.5) 13(2.3,-3.5) 14(2.7,-3.5) 15(3.1,-3.5) 16(3.5,-3.5) 25(3.5,0.7) 26(3.1,0.7) 27(2.7,0.7) 28(2.3,0.7) 29(1.9,0.7) 30(1.5,0.7) 31(1.1,0.7) 32(0.7,0.7)
  rect 2.692x2.692 smd: 33(2.1,-1.4)
JUMP_43X39
  custom 0.191x0.191 smd: 1(0,0) 2(0.914,0)
JUMP_43X79
  custom 0.188x0.188 smd: 1(0,0) 2(1.1,0)
JUMP_43X118
  custom 0.187x0.187 smd: 1(0,0) 2(1.1,0)
JXT_FP241AH-010GAAM_10P
  oval 0.305x1.092 smd: 1(0,0) 2(0.5,0) 3(1,0) 4(1.5,0) 5(2,0) 6(2.5,0) 7(3,0) 8(3.5,0) 9(4,0) 10(4.5,0)
  rect 0.406x0.787 smd: 11(-1,-2.65) 12(5.5,-2.65)
JXT_FP241AH-010GAAM_10P-NPM
  oval 0.305x1.092 smd: 1(0,0) 2(0.5,0) 3(1,0) 4(1.5,0) 5(2,0) 6(2.5,0) 7(3,0) 8(3.5,0) 9(4,0) 10(4.5,0)
  rect 0.406x0.787 smd: 11(-1,-2.65) 12(5.5,-2.65)
KC_FBMA-L11-453215800LMA90T_2P
  rect 1.803x3.404 smd: 1(0,0) 2(3.8,0)
L2N7002DW1T1G_SC88-6
  oval 0.406x0.508 smd: 1(0,0) 2(0.65,0) 3(1.3,0) 4(1.3,1.9) 5(0.65,1.9) 6(0,1.9)
L2N7002WT1G_SC-70-3
  oval 0.711x0.889 smd: 1(0,0) 2(-0.65,-1.9) 3(0.65,-1.9)
L03ESDL5V0CC3-2_SOT23-3
  oval 1.016x1.524 smd: 1(0,0) 2(0.965,2.083) 3(-0.965,2.083)
L05ESDL5V0NA-4_SLP2510P8-10-9
  rect 0.203x0.686 smd: 1(0,0) 2(-0.5,0) 4(-1.5,0) 5(-2,0) 6(-2,-0.875) 7(-1.5,-0.875) 8(-0.5,-0.875) 9(0,-0.875)
  rect 0.406x1.549 smd: 3(-1,-0.437)
L_5X5X3_M_2P
  rect 2.159x2.794 smd: 1(0,0) 2(4.35,0)
L_7X7X3_M
  custom 0.591x0.591 smd: 1(0,0) 4(6.05,0)
  rect 0.762x0.508 smd: 2(0.8,0) 3(5.25,0)
L_7X7X3_M_2P
  rect 2.362x3.505 smd: 1(0,0) 2(6.05,0)
L_7X7X4_M
  custom 0.591x0.591 smd: 1(0,0) 4(6.05,0)
  rect 0.762x0.508 smd: 2(0.8,0) 3(5.25,0)
LCN_DAN05-67306-0103_75P
  round 1.092 hole 1.092 unplated: (-0.75,-5.275)
  round 1.6 hole 1.6 unplated: (19.25,-5.275)
  oval 0.305x1.549 smd: 1(0,0) 2(0.25,-7.55) 3(0.5,0) 4(0.75,-7.55) 5(1,0) 6(1.25,-7.55) 7(1.5,0) 8(1.75,-7.55) 9(2,0) 10(2.25,-7.55) 11(2.5,0) 12(2.75,-7.55) 13(3,0) 14(3.25,-7.55) 15(3.5,0) 16(3.75,-7.55) 17(4,0) 18(4.25,-7.55) 19(4.5,0) 20(4.75,-7.55) 21(5,0) 22(5.25,-7.55) 23(5.5,0) 24(5.75,-7.55) 25(6,0) 26(6.25,-7.55) 27(6.5,0) 28(6.75,-7.55) 29(7,0) 30(7.25,-7.55) 31(7.5,0) 32(7.75,-7.55) 33(8,0) 34(8.25,-7.55) 35(8.5,0) 36(8.75,-7.55) 37(9,0) 38(9.25,-7.55) 39(9.5,0) 40(9.75,-7.55) 41(10,0) 42(10.25,-7.55) 43(10.5,0) 44(10.75,-7.55) 45(11,0) 46(11.25,-7.55) 47(11.5,0) 48(11.75,-7.55) 49(12,0) 50(12.25,-7.55) 51(12.5,0) 52(12.75,-7.55) 53(13,0) 54(13.25,-7.55) 55(13.5,0) 56(13.75,-7.55) 57(14,0) 58(14.25,-7.55) 67(16.5,0) 68(16.75,-7.55) 69(17,0) 70(17.25,-7.55) 71(17.5,0) 72(17.75,-7.55) 73(18,0) 74(18.25,-7.55) 75(18.5,0)
  rect 1.194x2.743 smd: 76(19.6,-0.775) 77(-1.1,-0.775)
LED_LTW-295DSKS-5A_4P
  rect 0.508x0.406 smd: 1(0,0) 2(1.2,0) 3(0,0.7) 4(1.2,0.7)
LM393DGKR_VSSOP8
  oval 1.575x0.381 smd: 1(0,0) 2(0,-0.65) 3(0,-1.3) 4(0,-1.95) 5(4.35,-1.95) 6(4.35,-1.3) 7(4.35,-0.65) 8(4.35,0)
LMBT3904LT1G_SOT23-3
  oval 1.016x1.524 smd: 1(0,0) 2(0.965,2.083) 3(-0.965,2.083)
LMBT3904WT1G_SC70-3
  oval 0.711x0.889 smd: 1(0,0) 2(0.65,1.9) 3(-0.65,1.9)
LMUN5113T1G_SOT323-3
  oval 0.711x0.889 smd: 1(0,0) 2(0.65,1.9) 3(-0.65,1.9)
LN2306LT1G_SOT23-3
  oval 1.016x1.524 smd: 1(0,0) 2(0.965,2.083) 3(-0.965,2.083)
LNG2DMTR_LGA12_2X2
  oval 0.406x0.305 smd: 1(0,0) 4(0,-1.5) 7(1.602,-1.5) 10(1.602,0)
  oval 0.508x0.305 smd: 2(0.051,-0.5) 3(0.051,-1) 8(1.551,-1) 9(1.551,-0.5)
  oval 0.305x0.508 smd: 5(0.551,-1.5) 6(1.051,-1.5) 11(1.051,0) 12(0.551,0)
LOTES_ADDR0205-P001A02_260P
  round 1.6 hole 1.6 unplated: (-1.025,4.1)
  round 1.092 hole 1.092 unplated: (67.775,4.1)
  oval 0.305x1.753 smd: 1(0,0) 2(0.25,8.2) 3(0.5,0) 4(0.75,8.2) 5(1,0) 6(1.25,8.2) 7(1.5,0) 8(1.75,8.2) 9(2,0) 10(2.25,8.2) 11(2.5,0) 12(2.75,8.2) 13(3,0) 14(3.25,8.2) 15(3.5,0) 16(3.75,8.2) 17(4,0) 18(4.25,8.2) 19(4.5,0) 20(4.75,8.2) 21(5,0) 22(5.25,8.2) 23(5.5,0) 24(5.75,8.2) 25(6,0) 26(6.25,8.2) 27(6.5,0) 28(6.75,8.2) 29(7,0) 30(7.25,8.2) 31(7.5,0) 32(7.75,8.2) 33(8,0) 34(8.25,8.2) 35(8.5,0) 36(8.75,8.2) 37(9,0) 38(9.25,8.2) 39(9.5,0) 40(9.75,8.2) 41(10,0) 42(10.25,8.2) 43(10.5,0) 44(10.75,8.2) 45(11,0) 46(11.25,8.2) 47(11.5,0) 48(11.75,8.2) 49(12,0) 50(12.25,8.2) 51(12.5,0) 52(12.75,8.2) 53(13,0) 54(13.25,8.2) 55(13.5,0) 56(13.75,8.2) 57(14,0) 58(14.25,8.2) 59(14.5,0) 60(14.75,8.2) 61(15,0) 62(15.25,8.2) 63(15.5,0) 64(15.75,8.2) 65(16,0) 66(16.25,8.2) 67(16.5,0) 68(16.75,8.2) 69(17,0) 70(17.25,8.2) 71(17.5,0) 72(17.75,8.2) 73(18,0) 74(18.25,8.2) 75(18.5,0) 76(18.75,8.2) 77(19,0) 78(19.25,8.2) 79(19.5,0) 80(19.75,8.2) 81(20,0) 82(20.25,8.2) 83(20.5,0) 84(20.75,8.2) 85(21,0) 86(21.25,8.2) 87(21.5,0) 88(21.75,8.2) 89(22,0) 90(22.25,8.2) 91(22.5,0) 92(22.75,8.2) 93(23,0) 94(23.25,8.2) 95(23.5,0) 96(23.75,8.2) 97(24,0) 98(24.25,8.2) 99(24.5,0) 100(24.75,8.2) 101(25,0) 102(25.25,8.2) 103(25.5,0) 104(25.75,8.2) 105(26,0) 106(26.25,8.2) 107(26.5,0) 108(26.75,8.2) 109(27,0) 110(27.25,8.2) 111(27.5,0) 112(27.75,8.2) 113(28,0) 114(28.25,8.2) 115(28.5,0) 116(28.75,8.2) 117(29,0) 118(29.25,8.2) 119(29.5,0) 120(29.75,8.2) 121(30,0) 122(30.25,8.2) 123(30.5,0) 124(30.75,8.2) 125(31,0) 126(31.25,8.2) 127(31.5,0) 128(31.75,8.2) 129(32,0) 130(32.25,8.2) 131(32.5,0) 132(32.75,8.2) 133(33,0) 134(33.25,8.2) 135(33.5,0) 136(33.75,8.2) 137(34,0) 138(34.25,8.2) 139(34.5,0) 140(34.75,8.2) 141(35,0) 142(35.25,8.2) 143(35.5,0) 144(35.75,8.2) 145(38,0) 146(38.25,8.2) 147(38.5,0) 148(38.75,8.2) 149(39,0) 150(39.25,8.2) 151(39.5,0) 152(39.75,8.2) 153(40,0) 154(40.25,8.2) 155(40.5,0) 156(40.75,8.2) 157(41,0) 158(41.25,8.2) 159(41.5,0) 160(41.75,8.2) 161(42,0) 162(42.25,8.2) 163(42.5,0) 164(42.75,8.2) 165(43,0) 166(43.25,8.2) 167(43.5,0) 168(43.75,8.2) 169(44,0) 170(44.25,8.2) 171(44.5,0) 172(44.75,8.2) 173(45,0) 174(45.25,8.2) 175(45.5,0) 176(45.75,8.2) 177(46,0) 178(46.25,8.2) 179(46.5,0) 180(46.75,8.2) 181(47,0) 182(47.25,8.2) 183(47.5,0) 184(47.75,8.2) 185(48,0) 186(48.25,8.2) 187(48.5,0) 188(48.75,8.2) 189(49,0) 190(49.25,8.2) 191(49.5,0) 192(49.75,8.2) 193(50,0) 194(50.25,8.2) 195(50.5,0) 196(50.75,8.2) 197(51,0) 198(51.25,8.2) 199(51.5,0) 200(51.75,8.2) 201(52,0) 202(52.25,8.2) 203(52.5,0) 204(52.75,8.2) 205(53,0) 206(53.25,8.2) 207(53.5,0) 208(53.75,8.2) 209(54,0) 210(54.25,8.2) 211(54.5,0) 212(54.75,8.2) 213(55,0) 214(55.25,8.2) 215(55.5,0) 216(55.75,8.2) 217(56,0) 218(56.25,8.2) 219(56.5,0) 220(56.75,8.2) 221(57,0) 222(57.25,8.2) 223(57.5,0) 224(57.75,8.2) 225(58,0) 226(58.25,8.2) 227(58.5,0) 228(58.75,8.2) 229(59,0) 230(59.25,8.2) 231(59.5,0) 232(59.75,8.2) 233(60,0) 234(60.25,8.2) 235(60.5,0) 236(60.75,8.2) 237(61,0) 238(61.25,8.2) 239(61.5,0) 240(61.75,8.2) 241(62,0) 242(62.25,8.2) 243(62.5,0) 244(62.75,8.2) 245(63,0) 246(63.25,8.2) 247(63.5,0) 248(63.75,8.2) 249(64,0) 250(64.25,8.2) 251(64.5,0) 252(64.75,8.2) 253(65,0) 254(65.25,8.2) 255(65.5,0) 256(65.75,8.2) 257(66,0) 258(66.25,8.2) 259(66.5,0) 260(66.75,8.2)
  rect 3.505x4.597 smd: 261(-0.425,16.1) 262(67.175,16.1)
LOTES_ADDR0206-P001A02_260P
  round 1.092 hole 1.092 unplated: (-67.775,-4.1)
  round 1.6 hole 1.6 unplated: (1.025,-4.1)
  oval 0.305x1.753 smd: 1(0,0) 2(-0.25,-8.2) 3(-0.5,0) 4(-0.75,-8.2) 5(-1,0) 6(-1.25,-8.2) 7(-1.5,0) 8(-1.75,-8.2) 9(-2,0) 10(-2.25,-8.2) 11(-2.5,0) 12(-2.75,-8.2) 13(-3,0) 14(-3.25,-8.2) 15(-3.5,0) 16(-3.75,-8.2) 17(-4,0) 18(-4.25,-8.2) 19(-4.5,0) 20(-4.75,-8.2) 21(-5,0) 22(-5.25,-8.2) 23(-5.5,0) 24(-5.75,-8.2) 25(-6,0) 26(-6.25,-8.2) 27(-6.5,0) 28(-6.75,-8.2) 29(-7,0) 30(-7.25,-8.2) 31(-7.5,0) 32(-7.75,-8.2) 33(-8,0) 34(-8.25,-8.2) 35(-8.5,0) 36(-8.75,-8.2) 37(-9,0) 38(-9.25,-8.2) 39(-9.5,0) 40(-9.75,-8.2) 41(-10,0) 42(-10.25,-8.2) 43(-10.5,0) 44(-10.75,-8.2) 45(-11,0) 46(-11.25,-8.2) 47(-11.5,0) 48(-11.75,-8.2) 49(-12,0) 50(-12.25,-8.2) 51(-12.5,0) 52(-12.75,-8.2) 53(-13,0) 54(-13.25,-8.2) 55(-13.5,0) 56(-13.75,-8.2) 57(-14,0) 58(-14.25,-8.2) 59(-14.5,0) 60(-14.75,-8.2) 61(-15,0) 62(-15.25,-8.2) 63(-15.5,0) 64(-15.75,-8.2) 65(-16,0) 66(-16.25,-8.2) 67(-16.5,0) 68(-16.75,-8.2) 69(-17,0) 70(-17.25,-8.2) 71(-17.5,0) 72(-17.75,-8.2) 73(-18,0) 74(-18.25,-8.2) 75(-18.5,0) 76(-18.75,-8.2) 77(-19,0) 78(-19.25,-8.2) 79(-19.5,0) 80(-19.75,-8.2) 81(-20,0) 82(-20.25,-8.2) 83(-20.5,0) 84(-20.75,-8.2) 85(-21,0) 86(-21.25,-8.2) 87(-21.5,0) 88(-21.75,-8.2) 89(-22,0) 90(-22.25,-8.2) 91(-22.5,0) 92(-22.75,-8.2) 93(-23,0) 94(-23.25,-8.2) 95(-23.5,0) 96(-23.75,-8.2) 97(-24,0) 98(-24.25,-8.2) 99(-24.5,0) 100(-24.75,-8.2) 101(-25,0) 102(-25.25,-8.2) 103(-25.5,0) 104(-25.75,-8.2) 105(-26,0) 106(-26.25,-8.2) 107(-26.5,0) 108(-26.75,-8.2) 109(-27,0) 110(-27.25,-8.2) 111(-27.5,0) 112(-27.75,-8.2) 113(-28,0) 114(-28.25,-8.2) 115(-28.5,0) 116(-28.75,-8.2) 117(-29,0) 118(-29.25,-8.2) 119(-29.5,0) 120(-29.75,-8.2) 121(-30,0) 122(-30.25,-8.2) 123(-30.5,0) 124(-30.75,-8.2) 125(-31,0) 126(-31.25,-8.2) 127(-31.5,0) 128(-31.75,-8.2) 129(-32,0) 130(-32.25,-8.2) 131(-32.5,0) 132(-32.75,-8.2) 133(-33,0) 134(-33.25,-8.2) 135(-33.5,0) 136(-33.75,-8.2) 137(-34,0) 138(-34.25,-8.2) 139(-34.5,0) 140(-34.75,-8.2) 141(-35,0) 142(-35.25,-8.2) 143(-35.5,0) 144(-35.75,-8.2) 145(-38,0) 146(-38.25,-8.2) 147(-38.5,0) 148(-38.75,-8.2) 149(-39,0) 150(-39.25,-8.2) 151(-39.5,0) 152(-39.75,-8.2) 153(-40,0) 154(-40.25,-8.2) 155(-40.5,0) 156(-40.75,-8.2) 157(-41,0) 158(-41.25,-8.2) 159(-41.5,0) 160(-41.75,-8.2) 161(-42,0) 162(-42.25,-8.2) 163(-42.5,0) 164(-42.75,-8.2) 165(-43,0) 166(-43.25,-8.2) 167(-43.5,0) 168(-43.75,-8.2) 169(-44,0) 170(-44.25,-8.2) 171(-44.5,0) 172(-44.75,-8.2) 173(-45,0) 174(-45.25,-8.2) 175(-45.5,0) 176(-45.75,-8.2) 177(-46,0) 178(-46.25,-8.2) 179(-46.5,0) 180(-46.75,-8.2) 181(-47,0) 182(-47.25,-8.2) 183(-47.5,0) 184(-47.75,-8.2) 185(-48,0) 186(-48.25,-8.2) 187(-48.5,0) 188(-48.75,-8.2) 189(-49,0) 190(-49.25,-8.2) 191(-49.5,0) 192(-49.75,-8.2) 193(-50,0) 194(-50.25,-8.2) 195(-50.5,0) 196(-50.75,-8.2) 197(-51,0) 198(-51.25,-8.2) 199(-51.5,0) 200(-51.75,-8.2) 201(-52,0) 202(-52.25,-8.2) 203(-52.5,0) 204(-52.75,-8.2) 205(-53,0) 206(-53.25,-8.2) 207(-53.5,0) 208(-53.75,-8.2) 209(-54,0) 210(-54.25,-8.2) 211(-54.5,0) 212(-54.75,-8.2) 213(-55,0) 214(-55.25,-8.2) 215(-55.5,0) 216(-55.75,-8.2) 217(-56,0) 218(-56.25,-8.2) 219(-56.5,0) 220(-56.75,-8.2) 221(-57,0) 222(-57.25,-8.2) 223(-57.5,0) 224(-57.75,-8.2) 225(-58,0) 226(-58.25,-8.2) 227(-58.5,0) 228(-58.75,-8.2) 229(-59,0) 230(-59.25,-8.2) 231(-59.5,0) 232(-59.75,-8.2) 233(-60,0) 234(-60.25,-8.2) 235(-60.5,0) 236(-60.75,-8.2) 237(-61,0) 238(-61.25,-8.2) 239(-61.5,0) 240(-61.75,-8.2) 241(-62,0) 242(-62.25,-8.2) 243(-62.5,0) 244(-62.75,-8.2) 245(-63,0) 246(-63.25,-8.2) 247(-63.5,0) 248(-63.75,-8.2) 249(-64,0) 250(-64.25,-8.2) 251(-64.5,0) 252(-64.75,-8.2) 253(-65,0) 254(-65.25,-8.2) 255(-65.5,0) 256(-65.75,-8.2) 257(-66,0) 258(-66.25,-8.2) 259(-66.5,0) 260(-66.75,-8.2)
  rect 3.505x4.597 smd: 261(-67.175,7.9) 262(0.425,7.9)
LOTES_APCI0136-P001A_75P
  round 1.092 hole 1.092 unplated: (-0.75,-5.275)
  round 1.6 hole 1.6 unplated: (19.25,-5.275)
  oval 0.305x1.549 smd: 1(0,0) 2(0.25,-7.55) 3(0.5,0) 4(0.75,-7.55) 5(1,0) 6(1.25,-7.55) 7(1.5,0) 8(1.75,-7.55) 9(2,0) 10(2.25,-7.55) 11(2.5,0) 12(2.75,-7.55) 13(3,0) 14(3.25,-7.55) 15(3.5,0) 16(3.75,-7.55) 17(4,0) 18(4.25,-7.55) 19(4.5,0) 20(4.75,-7.55) 21(5,0) 22(5.25,-7.55) 23(5.5,0) 32(7.75,-7.55) 33(8,0) 34(8.25,-7.55) 35(8.5,0) 36(8.75,-7.55) 37(9,0) 38(9.25,-7.55) 39(9.5,0) 40(9.75,-7.55) 41(10,0) 42(10.25,-7.55) 43(10.5,0) 44(10.75,-7.55) 45(11,0) 46(11.25,-7.55) 47(11.5,0) 48(11.75,-7.55) 49(12,0) 50(12.25,-7.55) 51(12.5,0) 52(12.75,-7.55) 53(13,0) 54(13.25,-7.55) 55(13.5,0) 56(13.75,-7.55) 57(14,0) 58(14.25,-7.55) 59(14.5,0) 60(14.75,-7.55) 61(15,0) 62(15.25,-7.55) 63(15.5,0) 64(15.75,-7.55) 65(16,0) 66(16.25,-7.55) 67(16.5,0) 68(16.75,-7.55) 69(17,0) 70(17.25,-7.55) 71(17.5,0) 72(17.75,-7.55) 73(18,0) 74(18.25,-7.55) 75(18.5,0)
  rect 1.194x2.743 smd: 76(-1.1,-0.775) 77(19.6,-0.775)
LOTES_AUSB0172-P001A_9P
  round 1.295 hole 0.711: 1(0,0) 2(-2.5,0) 3(-4.5,0) 4(-7,0) 5(-7.5,-1.5) 6(-5.5,-1.5) 7(-3.5,-1.5) 8(-1.5,-1.5) 9(0.5,-1.5)
  oval 1.397x3.2 hole 0.787x2.591: 10(4.35,-2.38) 13(-11.35,-2.38)
  oval 1.397x2.692 hole 0.787x2.108: 11(4.35,-9.48) 12(-11.35,-9.48)
LP2301ALT1G_SOT23-3
  oval 1.016x1.524 smd: 1(0,0) 2(0.965,2.083) 3(-0.965,2.083)
LRB715FT1G_SOT323-3
  oval 0.711x0.889 smd: 1(0,0) 2(0.65,1.9) 3(-0.65,1.9)
LTC015EUBFS8TL_UMT3F
  oval 0.787x0.889 smd: 1(0,0) 2(-0.65,-1.6) 3(0.65,-1.6)
MAG_MMD05CZR47M_4P
  custom 0.54x0.54 smd: 1(0,0) 4(4.35,0)
  rect 0.762x0.508 smd: 2(0.699,0) 3(3.652,0)
MAG_MMD-06CZ-R82M-V1L_2P
  rect 2.159x3.505 smd: 1(0,0) 2(5.85,0)
MAG_MND-04ABIR60M-XGL_2P
  rect 1.448x3.708 smd: 1(0,0) 2(2.845,0)
MAGLA_MMD-05CZ-1R0M-M7L_2P
  rect 1.905x2.794 smd: 1(0,0) 2(4.1,0)
MC74VHC1G08DFT2G_SC70-5
  oval 0.381x0.711 smd: 1(0,0) 2(0.65,0) 3(1.3,0) 4(1.3,1.9) 5(0,1.9)
MEC1416-NU-D0_VTQFP128_14X14
  oval 1.753x0.203 smd: 1(0,0) 2(0,-0.4) 3(0,-0.8) 4(0,-1.2) 5(0,-1.6) 6(0,-2) 7(0,-2.4) 8(0,-2.8) 9(0,-3.2) 10(0,-3.6) 11(0,-4) 12(0,-4.4) 13(0,-4.8) 14(0,-5.2) 15(0,-5.6) 16(0,-6) 17(0,-6.4) 18(0,-6.8) 19(0,-7.2) 20(0,-7.6) 21(0,-8) 22(0,-8.4) 23(0,-8.8) 24(0,-9.2) 25(0,-9.6) 26(0,-10) 27(0,-10.4) 28(0,-10.8) 29(0,-11.2) 30(0,-11.6) 31(0,-12) 32(0,-12.4) 65(15.654,-12.4) 66(15.654,-12) 67(15.654,-11.6) 68(15.654,-11.2) 69(15.654,-10.8) 70(15.654,-10.4) 71(15.654,-10) 72(15.654,-9.6) 73(15.654,-9.2) 74(15.654,-8.8) 75(15.654,-8.4) 76(15.654,-8) 77(15.654,-7.6) 78(15.654,-7.2) 79(15.654,-6.8) 80(15.654,-6.4) 81(15.654,-6) 82(15.654,-5.6) 83(15.654,-5.2) 84(15.654,-4.8) 85(15.654,-4.4) 86(15.654,-4) 87(15.654,-3.6) 88(15.654,-3.2) 89(15.654,-2.8) 90(15.654,-2.4) 91(15.654,-2) 92(15.654,-1.6) 93(15.654,-1.2) 94(15.654,-0.8) 95(15.654,-0.4) 96(15.654,0)
  oval 0.203x1.753 smd: 33(1.627,-14.027) 34(2.027,-14.027) 35(2.427,-14.027) 36(2.827,-14.027) 37(3.227,-14.027) 38(3.627,-14.027) 39(4.027,-14.027) 40(4.427,-14.027) 41(4.827,-14.027) 42(5.227,-14.027) 43(5.627,-14.027) 44(6.027,-14.027) 45(6.427,-14.027) 46(6.827,-14.027) 47(7.227,-14.027) 48(7.627,-14.027) 49(8.027,-14.027) 50(8.427,-14.027) 51(8.827,-14.027) 52(9.227,-14.027) 53(9.627,-14.027) 54(10.027,-14.027) 55(10.427,-14.027) 56(10.827,-14.027) 57(11.227,-14.027) 58(11.627,-14.027) 59(12.027,-14.027) 60(12.427,-14.027) 61(12.827,-14.027) 62(13.227,-14.027) 63(13.627,-14.027) 64(14.027,-14.027) 97(14.027,1.627) 98(13.627,1.627) 99(13.227,1.627) 100(12.827,1.627) 101(12.427,1.627) 102(12.027,1.627) 103(11.627,1.627) 104(11.227,1.627) 105(10.827,1.627) 106(10.427,1.627) 107(10.027,1.627) 108(9.627,1.627) 109(9.227,1.627) 110(8.827,1.627) 111(8.427,1.627) 112(8.027,1.627) 113(7.627,1.627) 114(7.227,1.627) 115(6.827,1.627) 116(6.427,1.627) 117(6.027,1.627) 118(5.627,1.627) 119(5.227,1.627) 120(4.827,1.627) 121(4.427,1.627) 122(4.027,1.627) 123(3.627,1.627) 124(3.227,1.627) 125(2.827,1.627) 126(2.427,1.627) 127(2.027,1.627) 128(1.627,1.627)
MHPC_NS692417_24P
  oval 0.762x2.057 smd: 1(0,0) 2(1.27,0) 3(2.54,0) 4(3.81,0) 5(5.08,0) 6(6.35,0) 7(7.62,0) 8(8.89,0) 9(10.16,0) 10(11.43,0) 11(12.7,0) 12(13.97,0) 13(13.97,9.365) 14(12.7,9.365) 15(11.43,9.365) 16(10.16,9.365) 17(8.89,9.365) 18(7.62,9.365) 19(6.35,9.365) 20(5.08,9.365) 21(3.81,9.365) 22(2.54,9.365) 23(1.27,9.365) 24(0,9.365)
MMBT3904WH_SOT323-3
  oval 0.61x0.787 smd: 1(0,0) 2(-0.65,-1.6) 3(0.65,-1.6)
MURAT_BLM15AG102SN1D_2P
  rect 0.457x0.508 smd: 1(0,0) 2(0.85,0)
MURAT_BLM15PD600SN1D_2P
  rect 0.508x0.762 smd: 1(0,0) 2(0.75,0)
MURAT_BLM15PX221SN1D_2P
  rect 0.457x0.508 smd: 1(0,0) 2(0.85,0)
MURAT_BLM15PX330SN1D_2P
  rect 0.457x0.508 smd: 1(0,0) 2(0.85,0)
MURAT_LQM18PN1R0MFHD_2P
  rect 0.61x0.711 smd: 1(0,0) 2(1.3,0)
N15P-GT_BGA_908P
  round 0.381 smd: A2(0.8,0) A3(1.6,0) A5(3.3,0) A6(4.1,0) A8(5.8,0) A9(6.6,0) A11(8.3,0) A12(9.1,0) A14(10.8,0) A15(11.6,0) A17(13.3,0) A18(14.1,0) A20(15.8,0) A21(16.6,0) A23(18.3,0) A24(19.1,0) A26(20.8,0) A27(21.6,0) A29(23.3,0) A30(24.1,0) A32(25.8,0) A33(26.6,0) AA1(0,-16.6) AA2(0.8,-16.6) AA3(1.6,-16.6) AA4(2.4,-16.6) AA5(3.2,-16.6) AA6(4.05,-16.6) AA7(4.9,-16.6) AA8(5.7,-16.6) AA27(21.7,-16.6) AA28(22.5,-16.6) AA29(23.35,-16.6) AA30(24.2,-16.6) AA31(25,-16.6) AA32(25.8,-16.6) AA33(26.6,-16.6) AA34(27.4,-16.6) AB2(0.8,-17.45) AB3(1.6,-17.45) AB4(2.4,-17.45) AB5(3.2,-17.45) AB7(4.9,-17.45) AB8(5.7,-17.45) AB27(21.7,-17.45) AB28(22.5,-17.45) AB30(24.2,-17.45) AB31(25,-17.45) AB32(25.8,-17.45) AB33(26.6,-17.45) AC1(0,-18.3) AC2(0.8,-18.3) AC3(1.6,-18.3) AC4(2.4,-18.3) AC5(3.2,-18.3) AC6(4.05,-18.3) AC7(4.9,-18.3) AC8(5.7,-18.3) AC27(21.7,-18.3) AC28(22.5,-18.3) AC29(23.35,-18.3) AC30(24.2,-18.3) AC31(25,-18.3) AC32(25.8,-18.3) AC33(26.6,-18.3) AC34(27.4,-18.3) AD1(0,-19.1) AD2(0.8,-19.1) AD3(1.6,-19.1) AD4(2.4,-19.1) AD5(3.2,-19.1) AD6(4.05,-19.1) AD7(4.9,-19.1) AD8(5.7,-19.1) AD27(21.7,-19.1) AD28(22.5,-19.1) AD29(23.35,-19.1) AD30(24.2,-19.1) AD31(25,-19.1) AD32(25.8,-19.1) AD33(26.6,-19.1) AD34(27.4,-19.1) AE2(0.8,-19.95) AE3(1.6,-19.95) AE4(2.4,-19.95) AE5(3.2,-19.95) AE7(4.9,-19.95) AE8(5.7,-19.95) AE27(21.7,-19.95) AE28(22.5,-19.95) AE30(24.2,-19.95) AE31(25,-19.95) AE32(25.8,-19.95) AE33(26.6,-19.95) AF1(0,-20.8) AF2(0.8,-20.8) AF3(1.6,-20.8) AF4(2.4,-20.8) AF5(3.2,-20.8) AF6(4.05,-20.8) AF7(4.9,-20.8) AF8(5.7,-20.8) AF27(21.7,-20.8) AF28(22.5,-20.8) AF29(23.35,-20.8) AF30(24.2,-20.8) AF31(25,-20.8) AF32(25.8,-20.8) AF33(26.6,-20.8) AF34(27.4,-20.8) AG1(0,-21.6) AG2(0.8,-21.6) AG3(1.6,-21.6) AG4(2.4,-21.6) AG5(3.2,-21.6) AG6(4.05,-21.6) AG7(4.9,-21.6) AG8(5.7,-21.7) AG9(6.6,-21.7) AG10(7.45,-21.7) AG11(8.3,-21.7) AG12(9.1,-21.7) AG13(9.95,-21.7) AG14(10.8,-21.7) AG15(11.6,-21.7) AG16(12.45,-21.7) AG17(13.3,-21.7) AG18(14.1,-21.7) AG19(14.95,-21.7) AG20(15.8,-21.7) AG21(16.6,-21.7) AG22(17.45,-21.7) AG23(18.3,-21.7) AG24(19.1,-21.7) AG25(19.95,-21.7) AG26(20.8,-21.7) AG27(21.7,-21.7) AG28(22.5,-21.6) AG29(23.35,-21.6) AG30(24.2,-21.6) AG31(25,-21.6) AG32(25.8,-21.6) AG33(26.6,-21.6) AG34(27.4,-21.6) AH2(0.8,-22.45) AH3(1.6,-22.45) AH4(2.4,-22.45) AH5(3.2,-22.45) AH6(4.05,-22.45) AH7(4.9,-22.5) AH8(5.8,-22.5) AH9(6.6,-22.5) AH10(7.45,-22.5) AH11(8.3,-22.5) AH12(9.1,-22.5) AH13(9.95,-22.5) AH14(10.8,-22.5) AH15(11.6,-22.5) AH16(12.45,-22.5) AH17(13.3,-22.5) AH18(14.1,-22.5) AH19(14.95,-22.5) AH20(15.8,-22.5) AH21(16.6,-22.5) AH22(17.45,-22.5) AH23(18.3,-22.5) AH24(19.1,-22.5) AH25(19.95,-22.5) AH26(20.8,-22.5) AH27(21.6,-22.5) AH28(22.5,-22.5) AH29(23.35,-22.45) AH30(24.2,-22.45) AH31(25,-22.45) AH32(25.8,-22.45) AH33(26.6,-22.45) AJ1(0,-23.3) AJ2(0.8,-23.3) AJ3(1.6,-23.3) AJ4(2.4,-23.3) AJ5(3.2,-23.3) AJ6(4.05,-23.35) AJ7(4.95,-23.35) AJ8(5.8,-23.35) AJ9(6.6,-23.35) AJ11(8.3,-23.35) AJ12(9.1,-23.35) AJ14(10.8,-23.35) AJ15(11.6,-23.35) AJ17(13.3,-23.35) AJ18(14.1,-23.35) AJ20(15.8,-23.35) AJ21(16.6,-23.35) AJ23(18.3,-23.35) AJ24(19.1,-23.35) AJ26(20.8,-23.35) AJ27(21.6,-23.35) AJ28(22.45,-23.35) AJ29(23.35,-23.35) AJ30(24.2,-23.3) AJ31(25,-23.3) AJ32(25.8,-23.3) AJ33(26.6,-23.3) AJ34(27.4,-23.3) AK1(0,-24.1) AK2(0.8,-24.1) AK3(1.6,-24.1) AK4(2.4,-24.1) AK5(3.2,-24.2) AK6(4.1,-24.2) AK7(4.95,-24.2) AK8(5.8,-24.2) AK9(6.6,-24.2) AK10(7.45,-24.2) AK11(8.3,-24.2) AK12(9.1,-24.2) AK13(9.95,-24.2) AK14(10.8,-24.2) AK15(11.6,-24.2) AK16(12.45,-24.2) AK17(13.3,-24.2) AK18(14.1,-24.2) AK19(14.95,-24.2) AK20(15.8,-24.2) AK21(16.6,-24.2) AK22(17.45,-24.2) AK23(18.3,-24.2) AK24(19.1,-24.2) AK25(19.95,-24.2) AK26(20.8,-24.2) AK27(21.6,-24.2) AK28(22.45,-24.2) AK29(23.3,-24.2) AK30(24.2,-24.2) AK31(25,-24.1) AK32(25.8,-24.1) AK33(26.6,-24.1) AK34(27.4,-24.1) AL2(0.8,-24.95) AL3(1.6,-24.95) AL4(2.4,-25) AL5(3.3,-25) AL6(4.1,-25) AL7(4.95,-25) AL8(5.8,-25) AL9(6.6,-25) AL10(7.45,-25) AL11(8.3,-25) AL12(9.1,-25) AL13(9.95,-25) AL14(10.8,-25) AL15(11.6,-25) AL16(12.45,-25) AL17(13.3,-25) AL18(14.1,-25) AL19(14.95,-25) AL20(15.8,-25) AL21(16.6,-25) AL22(17.45,-25) AL23(18.3,-25) AL24(19.1,-25) AL25(19.95,-25) AL26(20.8,-25) AL27(21.6,-25) AL28(22.45,-25) AL29(23.3,-25) AL30(24.1,-25) AL31(25,-25) AL32(25.8,-24.95) AL33(26.6,-24.95) AM1(0,-25.8) AM2(0.8,-25.8) AM3(1.6,-25.8) AM4(2.45,-25.8) AM5(3.3,-25.8) AM6(4.1,-25.8) AM7(4.95,-25.8) AM8(5.8,-25.8) AM9(6.6,-25.8) AM10(7.45,-25.8) AM11(8.3,-25.8) AM12(9.1,-25.8) AM13(9.95,-25.8) AM14(10.8,-25.8) AM15(11.6,-25.8) AM16(12.45,-25.8) AM17(13.3,-25.8) AM18(14.1,-25.8) AM19(14.95,-25.8) AM20(15.8,-25.8) AM21(16.6,-25.8) AM22(17.45,-25.8) AM23(18.3,-25.8) AM24(19.1,-25.8) AM25(19.95,-25.8) AM26(20.8,-25.8) AM27(21.6,-25.8) AM28(22.45,-25.8) AM29(23.3,-25.8) AM30(24.1,-25.8) AM31(24.95,-25.8) AM32(25.8,-25.8) AM33(26.6,-25.8) AM34(27.4,-25.8) AN1(0,-26.6) AN2(0.8,-26.6) AN3(1.6,-26.6) AN4(2.45,-26.6) AN5(3.3,-26.6) AN6(4.1,-26.6) AN7(4.95,-26.6) AN8(5.8,-26.6) AN9(6.6,-26.6) AN10(7.45,-26.6) AN11(8.3,-26.6) AN12(9.1,-26.6) AN13(9.95,-26.6) AN14(10.8,-26.6) AN15(11.6,-26.6) AN16(12.45,-26.6) AN17(13.3,-26.6) AN18(14.1,-26.6) AN19(14.95,-26.6) AN20(15.8,-26.6) AN21(16.6,-26.6) AN22(17.45,-26.6) AN23(18.3,-26.6) AN24(19.1,-26.6) AN25(19.95,-26.6) AN26(20.8,-26.6) AN27(21.6,-26.6) AN28(22.45,-26.6) AN29(23.3,-26.6) AN30(24.1,-26.6) AN31(24.95,-26.6) AN32(25.8,-26.6) AN33(26.6,-26.6) AN34(27.4,-26.6) AP2(0.8,-27.4) AP3(1.6,-27.4) AP5(3.3,-27.4) AP6(4.1,-27.4) AP8(5.8,-27.4) AP9(6.6,-27.4) AP11(8.3,-27.4) AP12(9.1,-27.4) AP14(10.8,-27.4) AP15(11.6,-27.4) AP17(13.3,-27.4) AP18(14.1,-27.4) AP20(15.8,-27.4) AP21(16.6,-27.4) AP23(18.3,-27.4) AP24(19.1,-27.4) AP26(20.8,-27.4) AP27(21.6,-27.4) AP29(23.3,-27.4) AP30(24.1,-27.4) AP32(25.8,-27.4) AP33(26.6,-27.4) B1(0,-0.8) B2(0.8,-0.8) B3(1.6,-0.8) B4(2.45,-0.8) B5(3.3,-0.8) B6(4.1,-0.8) B7(4.95,-0.8) B8(5.8,-0.8) B9(6.6,-0.8) B10(7.45,-0.8) B11(8.3,-0.8) B12(9.1,-0.8) B13(9.95,-0.8) B14(10.8,-0.8) B15(11.6,-0.8) B16(12.45,-0.8) B17(13.3,-0.8) B18(14.1,-0.8) B19(14.95,-0.8) B20(15.8,-0.8) B21(16.6,-0.8) B22(17.45,-0.8) B23(18.3,-0.8) B24(19.1,-0.8) B25(19.95,-0.8) B26(20.8,-0.8) B27(21.6,-0.8) B28(22.45,-0.8) B29(23.3,-0.8) B30(24.1,-0.8) B31(24.95,-0.8) B32(25.8,-0.8) B33(26.6,-0.8) B34(27.4,-0.8) C1(0,-1.6) C2(0.8,-1.6) C3(1.6,-1.6) C4(2.45,-1.6) C5(3.3,-1.6) C6(4.1,-1.6) C7(4.95,-1.6) C8(5.8,-1.6) C9(6.6,-1.6) C10(7.45,-1.6) C11(8.3,-1.6) C12(9.1,-1.6) C13(9.95,-1.6) C14(10.8,-1.6) C15(11.6,-1.6) C16(12.45,-1.6) C17(13.3,-1.6) C18(14.1,-1.6) C19(14.95,-1.6) C20(15.8,-1.6) C21(16.6,-1.6) C22(17.45,-1.6) C23(18.3,-1.6) C24(19.1,-1.6) C25(19.95,-1.6) C26(20.8,-1.6) C27(21.6,-1.6) C28(22.45,-1.6) C29(23.3,-1.6) C30(24.1,-1.6) C31(24.95,-1.6) C32(25.8,-1.6) C33(26.6,-1.6) C34(27.4,-1.6) D2(0.8,-2.45) D3(1.6,-2.45) D4(2.4,-2.4) D5(3.3,-2.4) D6(4.1,-2.4) D7(4.95,-2.4) D8(5.8,-2.4) D9(6.6,-2.4) D10(7.45,-2.4) D11(8.3,-2.4) D12(9.1,-2.4) D13(9.95,-2.4) D14(10.8,-2.4) D15(11.6,-2.4) D16(12.45,-2.4) D17(13.3,-2.4) D18(14.1,-2.4) D19(14.95,-2.4) D20(15.8,-2.4) D21(16.6,-2.4) D22(17.45,-2.4) D23(18.3,-2.4) D24(19.1,-2.4) D25(19.95,-2.4) D26(20.8,-2.4) D27(21.6,-2.4) D28(22.45,-2.4) D29(23.3,-2.4) D30(24.1,-2.4) D31(25,-2.4) D32(25.8,-2.45) D33(26.6,-2.45) E1(0,-3.3) E2(0.8,-3.3) E3(1.6,-3.3) E4(2.4,-3.3) E5(3.2,-3.2) E6(4.1,-3.2) E7(4.95,-3.2) E8(5.8,-3.2) E9(6.6,-3.2) E10(7.45,-3.2) E11(8.3,-3.2) E12(9.1,-3.2) E13(9.95,-3.2) E14(10.8,-3.2) E15(11.6,-3.2) E16(12.45,-3.2) E17(13.3,-3.2) E18(14.1,-3.2) E19(14.95,-3.2) E20(15.8,-3.2) E21(16.6,-3.2) E22(17.45,-3.2) E23(18.3,-3.2) E24(19.1,-3.2) E25(19.95,-3.2) E26(20.8,-3.2) E27(21.6,-3.2) E28(22.45,-3.2) E29(23.3,-3.2) E30(24.2,-3.2) E31(25,-3.3) E32(25.8,-3.3) E33(26.6,-3.3) E34(27.4,-3.3) F1(0,-4.1) F2(0.8,-4.1) F3(1.6,-4.1) F4(2.4,-4.1) F5(3.2,-4.1) F6(4.05,-4.05) F7(4.95,-4.05) F8(5.8,-4.05) F9(6.6,-4.05) F11(8.3,-4.05) F12(9.1,-4.05) F14(10.8,-4.05) F15(11.6,-4.05) F17(13.3,-4.05) F18(14.1,-4.05) F20(15.8,-4.05) F21(16.6,-4.05) F23(18.3,-4.05) F24(19.1,-4.05) F26(20.8,-4.05) F27(21.6,-4.05) F28(22.45,-4.05) F29(23.35,-4.05) F30(24.2,-4.1) F31(25,-4.1) F32(25.8,-4.1) F33(26.6,-4.1) F34(27.4,-4.1) G2(0.8,-4.95) G3(1.6,-4.95) G4(2.4,-4.95) G5(3.2,-4.95) G6(4.05,-4.95) G7(4.9,-4.9) G8(5.8,-4.9) G9(6.6,-4.9) G10(7.45,-4.9) G11(8.3,-4.9) G12(9.1,-4.9) G13(9.95,-4.9) G14(10.8,-4.9) G15(11.6,-4.9) G16(12.45,-4.9) G17(13.3,-4.9) G18(14.1,-4.9) G19(14.95,-4.9) G20(15.8,-4.9) G21(16.6,-4.9) G22(17.45,-4.9) G23(18.3,-4.9) G24(19.1,-4.9) G25(19.95,-4.9) G26(20.8,-4.9) G27(21.6,-4.9) G28(22.5,-4.9) G29(23.35,-4.95) G30(24.2,-4.95) G31(25,-4.95) G32(25.8,-4.95) G33(26.6,-4.95) H1(0,-5.8) H2(0.8,-5.8) H3(1.6,-5.8) H4(2.4,-5.8) H5(3.2,-5.8) H6(4.05,-5.8) H7(4.9,-5.8) H8(5.7,-5.7) H9(6.6,-5.7) H10(7.45,-5.7) H11(8.3,-5.7) H12(9.1,-5.7) H13(9.95,-5.7) H14(10.8,-5.7) H15(11.6,-5.7) H16(12.45,-5.7) H17(13.3,-5.7) H18(14.1,-5.7) H19(14.95,-5.7) H20(15.8,-5.7) H21(16.6,-5.7) H22(17.45,-5.7) H23(18.3,-5.7) H24(19.1,-5.7) H25(19.95,-5.7) H26(20.8,-5.7) H27(21.7,-5.7) H28(22.5,-5.8) H29(23.35,-5.8) H30(24.2,-5.8) H31(25,-5.8) H32(25.8,-5.8) H33(26.6,-5.8) H34(27.4,-5.8) J1(0,-6.6) J2(0.8,-6.6) J3(1.6,-6.6) J4(2.4,-6.6) J5(3.2,-6.6) J6(4.05,-6.6) J7(4.9,-6.6) J8(5.7,-6.6) J27(21.7,-6.6) J28(22.5,-6.6) J29(23.35,-6.6) J30(24.2,-6.6) J31(25,-6.6) J32(25.8,-6.6) J33(26.6,-6.6) J34(27.4,-6.6) K2(0.8,-7.45) K3(1.6,-7.45) K4(2.4,-7.45) K5(3.2,-7.45) K7(4.9,-7.45) K8(5.7,-7.45) K27(21.7,-7.45) K28(22.5,-7.45) K30(24.2,-7.45) K31(25,-7.45) K32(25.8,-7.45) K33(26.6,-7.45) L1(0,-8.3) L2(0.8,-8.3) L3(1.6,-8.3) L4(2.4,-8.3) L5(3.2,-8.3) L6(4.05,-8.3) L7(4.9,-8.3) L8(5.7,-8.3) L27(21.7,-8.3) L28(22.5,-8.3) L29(23.35,-8.3) L30(24.2,-8.3) L31(25,-8.3) L32(25.8,-8.3) L33(26.6,-8.3) L34(27.4,-8.3) M1(0,-9.1) M2(0.8,-9.1) M3(1.6,-9.1) M4(2.4,-9.1) M5(3.2,-9.1) M6(4.05,-9.1) M7(4.9,-9.1) M8(5.7,-9.1) M27(21.7,-9.1) M28(22.5,-9.1) M29(23.35,-9.1) M30(24.2,-9.1) M31(25,-9.1) M32(25.8,-9.1) M33(26.6,-9.1) M34(27.4,-9.1) N2(0.8,-9.95) N3(1.6,-9.95) N4(2.4,-9.95) N5(3.2,-9.95) N7(4.9,-9.95) N8(5.7,-9.95) N27(21.7,-9.95) N28(22.5,-9.95) N30(24.2,-9.95) N31(25,-9.95) N32(25.8,-9.95) N33(26.6,-9.95) P1(0,-10.8) P2(0.8,-10.8) P3(1.6,-10.8) P4(2.4,-10.8) P5(3.2,-10.8) P6(4.05,-10.8) P7(4.9,-10.8) P8(5.7,-10.8) P27(21.7,-10.8) P28(22.5,-10.8) P29(23.35,-10.8) P30(24.2,-10.8) P31(25,-10.8) P32(25.8,-10.8) P33(26.6,-10.8) P34(27.4,-10.8) R1(0,-11.6) R2(0.8,-11.6) R3(1.6,-11.6) R4(2.4,-11.6) R5(3.2,-11.6) R6(4.05,-11.6) R7(4.9,-11.6) R8(5.7,-11.6) R27(21.7,-11.6) R28(22.5,-11.6) R29(23.35,-11.6) R30(24.2,-11.6) R31(25,-11.6) R32(25.8,-11.6) R33(26.6,-11.6) R34(27.4,-11.6) T2(0.8,-12.45) T3(1.6,-12.45) T4(2.4,-12.45) T5(3.2,-12.45) T7(4.9,-12.45) T8(5.7,-12.45) T27(21.7,-12.45) T28(22.5,-12.45) T30(24.2,-12.45) T31(25,-12.45) T32(25.8,-12.45) T33(26.6,-12.45) U1(0,-13.3) U2(0.8,-13.3) U3(1.6,-13.3) U4(2.4,-13.3) U5(3.2,-13.3) U6(4.05,-13.3) U7(4.9,-13.3) U8(5.7,-13.3) U27(21.7,-13.3) U28(22.5,-13.3) U29(23.35,-13.3) U30(24.2,-13.3) U31(25,-13.3) U32(25.8,-13.3) U33(26.6,-13.3) U34(27.4,-13.3) V1(0,-14.1) V2(0.8,-14.1) V3(1.6,-14.1) V4(2.4,-14.1) V5(3.2,-14.1) V6(4.05,-14.1) V7(4.9,-14.1) V8(5.7,-14.1) V27(21.7,-14.1) V28(22.5,-14.1) V29(23.35,-14.1) V30(24.2,-14.1) V31(25,-14.1) V32(25.8,-14.1) V33(26.6,-14.1) V34(27.4,-14.1) W2(0.8,-14.95) W3(1.6,-14.95) W4(2.4,-14.95) W5(3.2,-14.95) W7(4.9,-14.95) W8(5.7,-14.95) W27(21.7,-14.95) W28(22.5,-14.95) W30(24.2,-14.95) W31(25,-14.95) W32(25.8,-14.95) W33(26.6,-14.95) Y1(0,-15.8) Y2(0.8,-15.8) Y3(1.6,-15.8) Y4(2.4,-15.8) Y5(3.2,-15.8) Y6(4.05,-15.8) Y7(4.9,-15.8) Y8(5.7,-15.8) Y27(21.7,-15.8) Y28(22.5,-15.8) Y29(23.35,-15.8) Y30(24.2,-15.8) Y31(25,-15.8) Y32(25.8,-15.8) Y33(26.6,-15.8) Y34(27.4,-15.8)
  round 0.406 smd: AA12(8.2,-17.2) AA13(9.2,-17.2) AA14(10.2,-17.2) AA15(11.2,-17.2) AA16(12.2,-17.2) AA17(13.2,-17.2) AA18(14.2,-17.2) AA19(15.2,-17.2) AA20(16.2,-17.2) AA21(17.2,-17.2) AA22(18.2,-17.2) AA23(19.2,-17.2) AB12(8.2,-18.2) AB13(9.2,-18.2) AB14(10.2,-18.2) AB15(11.2,-18.2) AB16(12.2,-18.2) AB17(13.2,-18.2) AB18(14.2,-18.2) AB19(15.2,-18.2) AB20(16.2,-18.2) AB21(17.2,-18.2) AB22(18.2,-18.2) AB23(19.2,-18.2) AC12(8.2,-19.2) AC13(9.2,-19.2) AC14(10.2,-19.2) AC15(11.2,-19.2) AC16(12.2,-19.2) AC17(13.2,-19.2) AC18(14.2,-19.2) AC19(15.2,-19.2) AC20(16.2,-19.2) AC21(17.2,-19.2) AC22(18.2,-19.2) AC23(19.2,-19.2) M12(8.2,-8.2) M13(9.2,-8.2) M14(10.2,-8.2) M15(11.2,-8.2) M16(12.2,-8.2) M17(13.2,-8.2) M18(14.2,-8.2) M19(15.2,-8.2) M20(16.2,-8.2) M21(17.2,-8.2) M22(18.2,-8.2) M23(19.2,-8.2) N12(8.2,-9.2) N13(9.2,-9.2) N14(10.2,-9.2) N15(11.2,-9.2) N16(12.2,-9.2) N17(13.2,-9.2) N18(14.2,-9.2) N19(15.2,-9.2) N20(16.2,-9.2) N21(17.2,-9.2) N22(18.2,-9.2) N23(19.2,-9.2) P12(8.2,-10.2) P13(9.2,-10.2) P14(10.2,-10.2) P15(11.2,-10.2) P16(12.2,-10.2) P17(13.2,-10.2) P18(14.2,-10.2) P19(15.2,-10.2) P20(16.2,-10.2) P21(17.2,-10.2) P22(18.2,-10.2) P23(19.2,-10.2) R12(8.2,-11.2) R13(9.2,-11.2) R14(10.2,-11.2) R15(11.2,-11.2) R16(12.2,-11.2) R17(13.2,-11.2) R18(14.2,-11.2) R19(15.2,-11.2) R20(16.2,-11.2) R21(17.2,-11.2) R22(18.2,-11.2) R23(19.2,-11.2) T12(8.2,-12.2) T13(9.2,-12.2) T14(10.2,-12.2) T15(11.2,-12.2) T16(12.2,-12.2) T17(13.2,-12.2) T18(14.2,-12.2) T19(15.2,-12.2) T20(16.2,-12.2) T21(17.2,-12.2) T22(18.2,-12.2) T23(19.2,-12.2) U12(8.2,-13.2) U13(9.2,-13.2) U14(10.2,-13.2) U15(11.2,-13.2) U16(12.2,-13.2) U17(13.2,-13.2) U18(14.2,-13.2) U19(15.2,-13.2) U20(16.2,-13.2) U21(17.2,-13.2) U22(18.2,-13.2) U23(19.2,-13.2) V12(8.2,-14.2) V13(9.2,-14.2) V14(10.2,-14.2) V15(11.2,-14.2) V16(12.2,-14.2) V17(13.2,-14.2) V18(14.2,-14.2) V19(15.2,-14.2) V20(16.2,-14.2) V21(17.2,-14.2) V22(18.2,-14.2) V23(19.2,-14.2) W12(8.2,-15.2) W13(9.2,-15.2) W14(10.2,-15.2) W15(11.2,-15.2) W16(12.2,-15.2) W17(13.2,-15.2) W18(14.2,-15.2) W19(15.2,-15.2) W20(16.2,-15.2) W21(17.2,-15.2) W22(18.2,-15.2) W23(19.2,-15.2) Y12(8.2,-16.2) Y13(9.2,-16.2) Y14(10.2,-16.2) Y15(11.2,-16.2) Y16(12.2,-16.2) Y17(13.2,-16.2) Y18(14.2,-16.2) Y19(15.2,-16.2) Y20(16.2,-16.2) Y21(17.2,-16.2) Y22(18.2,-16.2) Y23(19.2,-16.2)
NCP81215MNTXG_QFN52_6X6
  oval 0.838x0.203 smd: 1(0,0) 2(0,-0.4) 3(0,-0.8) 4(0,-1.2) 5(0,-1.6) 6(0,-2) 7(0,-2.4) 8(0,-2.8) 9(0,-3.2) 10(0,-3.6) 11(0,-4) 12(0,-4.4) 13(0,-4.8) 27(6.15,-4.8) 28(6.15,-4.4) 29(6.15,-4) 30(6.15,-3.6) 31(6.15,-3.2) 32(6.15,-2.8) 33(6.15,-2.4) 34(6.15,-2) 35(6.15,-1.6) 36(6.15,-1.2) 37(6.15,-0.8) 38(6.15,-0.4) 39(6.15,0)
  oval 0.203x0.838 smd: 14(0.675,-5.475) 15(1.075,-5.475) 16(1.475,-5.475) 17(1.875,-5.475) 18(2.275,-5.475) 19(2.675,-5.475) 20(3.075,-5.475) 21(3.475,-5.475) 22(3.875,-5.475) 23(4.275,-5.475) 24(4.675,-5.475) 25(5.075,-5.475) 26(5.475,-5.475) 40(5.475,0.675) 41(5.075,0.675) 42(4.675,0.675) 43(4.275,0.675) 44(3.875,0.675) 45(3.475,0.675) 46(3.075,0.675) 47(2.675,0.675) 48(2.275,0.675) 49(1.875,0.675) 50(1.475,0.675) 51(1.075,0.675) 52(0.675,0.675)
  rect 4.699x4.699 smd: 53(3.075,-2.4)
NCP81276MNTXG_QFN40_5X5
  oval 0.889x0.203 smd: 1(0,0) 2(0,-0.4) 3(0,-0.8) 4(0,-1.2) 5(0,-1.6) 6(0,-2) 7(0,-2.4) 8(0,-2.8) 9(0,-3.2) 10(0,-3.6) 21(5.1,-3.6) 22(5.1,-3.2) 23(5.1,-2.8) 24(5.1,-2.4) 25(5.1,-2) 26(5.1,-1.6) 27(5.1,-1.2) 28(5.1,-0.8) 29(5.1,-0.4) 30(5.1,0)
  oval 0.203x0.889 smd: 11(0.75,-4.35) 12(1.15,-4.35) 13(1.55,-4.35) 14(1.95,-4.35) 15(2.35,-4.35) 16(2.75,-4.35) 17(3.15,-4.35) 18(3.55,-4.35) 19(3.95,-4.35) 20(4.35,-4.35) 31(4.35,0.75) 32(3.95,0.75) 33(3.55,0.75) 34(3.15,0.75) 35(2.75,0.75) 36(2.35,0.75) 37(1.95,0.75) 38(1.55,0.75) 39(1.15,0.75) 40(0.75,0.75)
  rect 3.505x3.505 smd: 41(2.55,-1.8)
NCP302045MNTXG_PQFN33_5X5
  oval 0.305x0.711 smd: 1(0,-0.051) 2(0.5,-0.051) 3(1,-0.051) 4(1.5,-0.051) 5(2,-0.051) 6(2.5,-0.051) 7(3,-0.051) 8(3.5,-0.051)
  custom 0.32x0.32 smd: 9(3.135,1.215)
  custom 0.543x0.543 smd: 10(2.225,3.215)
  rect 3.81x0.711 smd: 11(1.75,4.851)
  rect 0.711x1.295 smd: 12(-0.701,3.65)
  oval 0.711x0.305 smd: 13(-0.701,2.65) 14(-0.701,2.15) 15(-0.701,1.65) 16(-0.701,1.15) 17(-0.701,0.65)
  rect 1.422x1.118 smd: 18(0.7,1.215)
  rect 0.584x0.356 smd: 19(0.09,2.625)
NCT7718W_MSOP8
  oval 0.381x1.575 smd: 1(0,0) 2(0.65,0) 3(1.3,0) 4(1.95,0) 5(1.95,4.35) 6(1.3,4.35) 7(0.65,4.35) 8(0,4.35)
NL17SZ06DFT2G_SC70-5
  oval 0.406x0.508 smd: 1(0,0) 2(0.65,0) 3(1.3,0) 4(1.3,1.9) 5(0,1.9)
NL17SZ08DFT2G_SC70-5
  oval 0.406x0.508 smd: 1(0,0) 2(0.65,0) 3(1.3,0) 4(1.3,1.9) 5(0,1.9)
NPCT650VB2YX_QFN32_5X5
  oval 0.889x0.254 smd: 1(0,0) 2(0,-0.5) 3(0,-1) 4(0,-1.5) 5(0,-2) 6(0,-2.5) 7(0,-3) 8(0,-3.5) 17(5.1,-3.5) 18(5.1,-3) 19(5.1,-2.5) 20(5.1,-2) 21(5.1,-1.5) 22(5.1,-1) 23(5.1,-0.5) 24(5.1,0)
  oval 0.254x0.889 smd: 9(0.8,-4.3) 10(1.3,-4.3) 11(1.8,-4.3) 12(2.3,-4.3) 13(2.8,-4.3) 14(3.3,-4.3) 15(3.8,-4.3) 16(4.3,-4.3) 25(4.3,0.8) 26(3.8,0.8) 27(3.3,0.8) 28(2.8,0.8) 29(2.3,0.8) 30(1.8,0.8) 31(1.3,0.8) 32(0.8,0.8)
  rect 3.505x3.505 smd: 33(2.55,-1.75)
PDS5100H-13_POWERDI5-3
  rect 4.851x3.353 smd: 1(0,0)
  rect 1.397x1.397 smd: 2(3.982,-0.92) 3(3.982,0.92)
PESD24VS2UT_SOT23-3
  oval 1.016x1.524 smd: 1(0,0) 2(0.965,2.083) 3(-0.965,2.083)
PJSOT24C_SOT23-3
  oval 1.016x1.524 smd: 1(0,0) 2(0.965,2.083) 3(-0.965,2.083)
PS8409AQFN48GTR2-A0_QFN48_6X6
  oval 0.889x0.203 smd: 1(0,0) 2(0,-0.4) 3(0,-0.8) 4(0,-1.2) 5(0,-1.6) 6(0,-2) 7(0,-2.4) 8(0,-2.8) 9(0,-3.2) 10(0,-3.6) 11(0,-4) 12(0,-4.4) 25(6.1,-4.4) 26(6.1,-4) 27(6.1,-3.6) 28(6.1,-3.2) 29(6.1,-2.8) 30(6.1,-2.4) 31(6.1,-2) 32(6.1,-1.6) 33(6.1,-1.2) 34(6.1,-0.8) 35(6.1,-0.4) 36(6.1,0)
  oval 0.203x0.889 smd: 13(0.85,-5.25) 14(1.25,-5.25) 15(1.65,-5.25) 16(2.05,-5.25) 17(2.45,-5.25) 18(2.85,-5.25) 19(3.25,-5.25) 20(3.65,-5.25) 21(4.05,-5.25) 22(4.45,-5.25) 23(4.85,-5.25) 24(5.25,-5.25) 37(5.25,0.85) 38(4.85,0.85) 39(4.45,0.85) 40(4.05,0.85) 41(3.65,0.85) 42(3.25,0.85) 43(2.85,0.85) 44(2.45,0.85) 45(2.05,0.85) 46(1.65,0.85) 47(1.25,0.85) 48(0.85,0.85)
  rect 4.496x4.496 smd: 49(3.05,-2.2)
R0201_0OHM
  rect 0.381x0.356 smd: 1(0,0) 2(0.584,0)
R0402_0OHM
  rect 0.508x0.559 smd: 1(0,0) 2(0.914,0)
R0603_0OHM
  rect 0.635x0.889 smd: 1(0,0) 2(1.397,0)
R0805_0OHM
  rect 0.813x1.397 smd: 1(0,0) 2(1.702,0)
R_0201
  rect 0.381x0.356 smd: 1(0,0) 2(0.584,0)
R_0402
  rect 0.508x0.559 smd: 1(0,0) 2(0.914,0)
R_0402-NPM
  rect 0.508x0.559 smd: 1(0,0) 2(0.914,0)
R_0603
  rect 0.635x0.889 smd: 1(0,0) 2(1.397,0)
R_0805
  rect 0.813x1.397 smd: 1(0,0) 2(1.702,0)
R_1206
  rect 1.016x1.651 smd: 1(0,0) 2(2.667,0)
R_1206_4P-D
  custom 0.371x0.371 smd: 1(0,0) 4(3.327,0)
  custom 0.114x0.114 smd: 2(0.775,0) 3(2.553,0)
RB520SM-30T2R_EMD2-2
  rect 0.61x0.787 smd: 1(0,0) 2(1.7,0)
RB551V-30_SOD323-2
  rect 0.559x0.813 smd: 1(0,0) 2(2.3,0)
RB751S40T1G_SOD523-2
  rect 0.61x0.787 smd: 1(0,0) 2(1.7,0)
RB751V40_SC76-2
  rect 0.61x0.61 smd: 1(0,0) 2(2.2,0)
RP_0804_8P4R
  oval 0.66x0.254 smd: 1(0,0) 2(0,-0.5) 3(0,-1) 4(0,-1.5) 5(1.15,-1.5) 6(1.15,-1) 7(1.15,-0.5) 8(1.15,0)
RT8061AZQW_WDFN10_3X3
  oval 0.254x0.889 smd: 1(0,0) 2(0.5,0) 3(1,0) 4(1.5,0) 5(2,0) 6(2,3.1) 7(1.5,3.1) 8(1,3.1) 9(0.5,3.1) 10(0,3.1)
  rect 2.464x1.626 smd: 11(1,1.55)
RT8207PGQW_WQFN20_3X3
  oval 0.203x0.889 smd: 1(0,0) 2(0.4,0) 3(0.8,0) 4(1.2,0) 5(1.6,0) 11(1.6,3.1) 12(1.2,3.1) 13(0.8,3.1) 14(0.4,3.1) 15(0,3.1)
  oval 0.889x0.203 smd: 6(2.35,0.75) 7(2.35,1.15) 8(2.35,1.55) 9(2.35,1.95) 10(2.35,2.35) 16(-0.75,2.35) 17(-0.75,1.95) 18(-0.75,1.55) 19(-0.75,1.15) 20(-0.75,0.75)
  rect 1.702x1.702 smd: 21(0.8,1.55)
RT8816AGQW_WQFN20_3X3
  oval 0.203x0.889 smd: 1(0,0) 2(0.4,0) 3(0.8,0) 4(1.2,0) 5(1.6,0) 11(1.6,3.1) 12(1.2,3.1) 13(0.8,3.1) 14(0.4,3.1) 15(0,3.1)
  oval 0.889x0.203 smd: 6(2.35,0.75) 7(2.35,1.15) 8(2.35,1.55) 9(2.35,1.95) 10(2.35,2.35) 16(-0.75,2.35) 17(-0.75,1.95) 18(-0.75,1.55) 19(-0.75,1.15) 20(-0.75,0.75)
  rect 1.702x1.702 smd: 21(0.8,1.55)
RT9041E-15GQW_WDFN8_2X2
  oval 0.254x0.838 smd: 1(0,0) 2(0.5,0) 3(1,0) 4(1.5,0) 5(1.5,2.15) 6(1,2.15) 7(0.5,2.15) 8(0,2.15)
  rect 1.118x0.533 smd: 9(0.75,1.075)
RT9059GSP_SO8
  oval 0.635x1.854 smd: 1(0,0) 2(1.27,0) 3(2.54,0) 4(3.81,0) 5(3.81,5.157) 6(2.54,5.157) 7(1.27,5.157) 8(0,5.157)
  rect 2.311x2.311 smd: 9(1.905,2.579)
RT9069-33GB_SOT23-5
  oval 0.711x0.991 smd: 1(0,0) 2(0.95,0) 3(1.9,0) 4(1.9,2.6) 5(0,2.6)
RTL8111H-CG_QFN32_4X4
  oval 0.889x0.203 smd: 1(0,0) 2(0,-0.4) 3(0,-0.8) 4(0,-1.2) 5(0,-1.6) 6(0,-2) 7(0,-2.4) 8(0,-2.8) 17(4.1,-2.8) 18(4.1,-2.4) 19(4.1,-2) 20(4.1,-1.6) 21(4.1,-1.2) 22(4.1,-0.8) 23(4.1,-0.4) 24(4.1,0)
  oval 0.203x0.889 smd: 9(0.65,-3.45) 10(1.05,-3.45) 11(1.45,-3.45) 12(1.85,-3.45) 13(2.25,-3.45) 14(2.65,-3.45) 15(3.05,-3.45) 16(3.45,-3.45) 25(3.45,0.65) 26(3.05,0.65) 27(2.65,0.65) 28(2.25,0.65) 29(1.85,0.65) 30(1.45,0.65) 31(1.05,0.65) 32(0.65,0.65)
  rect 2.692x2.692 smd: 33(2.05,-1.4)
SDMK0340L-7-F_SOD323-2
  rect 1.346x0.66 smd: 1(0,0) 2(2.4,0)
SHORTPADS
  custom 0.19x0.19 smd: 1(-0.483,0) 2(0.483,0)
SINGA_2RJ3076-058211F_8P
  round 1.295 hole 0.889: 1(0,0) 2(-1.02,1.1) 3(-2.04,0) 4(-3.06,1.1) 5(-4.08,0) 6(-5.1,1.1) 7(-6.12,0) 8(-7.14,1.1)
  oval 0.991x2.007 hole 0.61x1.6: 9(-11.97,-2.3) 10(-11.97,-10.1) 11(4.83,-10.1) 12(4.83,-2.3)
SINGA_2SJ3095-136111F_6P
  oval 0.991x1.803 hole 0.61x1.397: 1(0,0) 2(-9.5,5.5) 3(0,5.2) 4(0,7.8) 5(-9.5,0) 6(-9.5,2.75) 7(0,2.65)
SSM3K7002FU_SC70-3
  oval 0.508x0.991 smd: 1(0,0) 2(0.65,1.9) 3(-0.65,1.9)
SW_TST71-N-220-T170-S017_2P
  rect 0.61x1.499 smd: 1(0,0) 2(3.2,0)
SY6288C20AAC_SOT23-5
  oval 0.559x0.787 smd: 1(0,0) 2(0.95,0) 3(1.9,0) 4(1.9,2.4) 5(0,2.4)
SY6288D20AAC_SOT23-5
  oval 0.559x0.787 smd: 1(0,0) 2(0.95,0) 3(1.9,0) 4(1.9,2.4) 5(0,2.4)
SY8286RAC_QFN20_3X3
  oval 0.889x0.254 smd: 1(0,0) 2(0,-0.45) 3(0,-0.9) 4(0,-1.35) 5(0,-1.8) 11(3.1,-1.8) 12(3.1,-1.35) 13(3.1,-0.9) 14(3.1,-0.45) 15(3.1,0)
  oval 0.254x0.889 smd: 6(0.65,-2.45) 7(1.1,-2.45) 8(1.55,-2.45) 9(2,-2.45) 10(2.45,-2.45) 16(2.45,0.65) 17(2,0.65) 18(1.55,0.65) 19(1.1,0.65) 20(0.65,0.65)
  rect 0.991x0.991 smd: 21(1.55,-0.9)
SY8288BRAC_QFN20_3X3
  oval 0.889x0.254 smd: 1(0,0) 2(0,-0.45) 3(0,-0.9) 4(0,-1.35) 5(0,-1.8) 11(3.1,-1.8) 12(3.1,-1.35) 13(3.1,-0.9) 14(3.1,-0.45) 15(3.1,0)
  oval 0.254x0.889 smd: 6(0.65,-2.45) 7(1.1,-2.45) 8(1.55,-2.45) 9(2,-2.45) 10(2.45,-2.45) 16(2.45,0.65) 17(2,0.65) 18(1.55,0.65) 19(1.1,0.65) 20(0.65,0.65)
  rect 0.991x0.991 smd: 21(1.55,-0.9)
SY8288CRAC_QFN20_3X3
  oval 0.889x0.254 smd: 1(0,0) 2(0,-0.45) 3(0,-0.9) 4(0,-1.35) 5(0,-1.8) 11(3.1,-1.8) 12(3.1,-1.35) 13(3.1,-0.9) 14(3.1,-0.45) 15(3.1,0)
  oval 0.254x0.889 smd: 6(0.65,-2.45) 7(1.1,-2.45) 8(1.55,-2.45) 9(2,-2.45) 10(2.45,-2.45) 16(2.45,0.65) 17(2,0.65) 18(1.55,0.65) 19(1.1,0.65) 20(0.65,0.65)
  rect 0.991x0.991 smd: 21(1.55,-0.9)
TAI-T_TMPA1005S-2R2MN-D_2P
  rect 3.556x3.505 smd: 1(0,0) 2(8.95,0)
TC7SH08FU_SSOP5
  oval 0.406x0.787 smd: 1(0,0) 2(0.65,0) 3(1.3,0) 4(1.3,1.9) 5(0,1.9)
TC7SH08FUF_SSOP5
  oval 0.457x0.711 smd: 1(0,0) 2(0.65,0) 3(1.3,0) 4(1.3,1.875) 5(0,1.875)
TC7SH32FU_SSOP5
  oval 0.381x1.422 smd: 1(0,0) 2(0.65,0) 3(1.3,0) 4(1.3,1.7) 5(0,1.7)
TPC12
  round 0.305 smd: 1(0,0)
TPS22961DNYR_WSON8
  oval 0.305x0.508 smd: 1(0,0) 2(0.65,0) 3(1.3,0) 4(1.95,0) 5(1.95,2.7)
  oval 1.6x0.508 smd: 6(0.65,2.7)
  rect 2.388x1.6 smd: 7(0.975,1.35)
TPS22966DPUR_SON14_2X3
  oval 0.203x0.762 smd: 1(0,0) 2(0.4,0) 3(0.8,0) 4(1.2,0) 5(1.6,0) 6(2,0) 7(2.4,0) 8(2.4,2.05) 9(2,2.05) 10(1.6,2.05) 11(1.2,2.05) 12(0.8,2.05) 13(0.4,2.05) 14(0,2.05)
  rect 2.489x0.889 smd: 15(1.2,1.025)
TPS22967DSGR_SON8_2X2
  oval 0.254x0.787 smd: 1(0,0) 2(0.5,0) 3(1,0) 4(1.5,0) 5(1.5,2.2) 6(1,2.2) 7(0.5,2.2) 8(0,2.2)
  rect 1.6x0.889 smd: 9(0.75,1.1)
TPS51212DSCR_SON10_3X3
  oval 0.279x0.838 smd: 1(0,0) 2(0.5,0) 3(1,0) 4(1.5,0) 5(2,0) 6(2,2.95) 7(1.5,2.95) 8(1,2.95) 9(0.5,2.95) 10(0,2.95)
  custom 0.412x0.412 smd: 11(1,1.475)
TPS65982DAZQZR-ES_BGA_96P
  round 0.254 smd: A1(0,0) A2(0.5,0) A3(1,0) A4(1.5,0) A5(2.001,0) A6(2.501,0) A7(3.001,0) A8(3.501,0) A9(4.001,0) A10(4.501,0) A11(5.001,0) B1(0,-0.5) B2(0.5,-0.5) B3(1,-0.5) B4(1.5,-0.5) B5(2.001,-0.5) B6(2.501,-0.5) B7(3.001,-0.5) B8(3.501,-0.5) B9(4.001,-0.5) B10(4.501,-0.5) B11(5.001,-0.5) C1(0,-1) C2(0.5,-1) C10(4.501,-1) C11(5.001,-1) D1(0,-1.5) D2(0.5,-1.5) D5(2.001,-1.5) D6(2.501,-1.5) D7(3.001,-1.5) D8(3.501,-1.5) D10(4.501,-1.5) D11(5.001,-1.5) E1(0,-2.001) E2(0.5,-2.001) E4(1.5,-2.001) E5(2.001,-2.001) E6(2.501,-2.001) E7(3.001,-2.001) E8(3.501,-2.001) E10(4.501,-2.001) E11(5.001,-2.001) F1(0,-2.501) F2(0.5,-2.501) F4(1.5,-2.501) F5(2.001,-2.501) F6(2.501,-2.501) F7(3.001,-2.501) F8(3.501,-2.501) F10(4.501,-2.501) F11(5.001,-2.501) G1(0,-3.001) G2(0.5,-3.001) G4(1.5,-3.001) G5(2.001,-3.001) G6(2.501,-3.001) G7(3.001,-3.001) G8(3.501,-3.001) G10(4.501,-3.001) G11(5.001,-3.001) H1(0,-3.501) H2(0.5,-3.501) H4(1.5,-3.501) H5(2.001,-3.501) H6(2.501,-3.501) H7(3.001,-3.501) H8(3.501,-3.501) H10(4.501,-3.501) H11(5.001,-3.501) J1(0,-4.001) J2(0.5,-4.001) J10(4.501,-4.001) J11(5.001,-4.001) K1(0,-4.501) K2(0.5,-4.501) K3(1,-4.501) K4(1.5,-4.501) K5(2.001,-4.501) K6(2.501,-4.501) K7(3.001,-4.501) K8(3.501,-4.501) K9(4.001,-4.501) K10(4.501,-4.501) K11(5.001,-4.501) L1(0,-5.001) L2(0.5,-5.001) L3(1,-5.001) L4(1.5,-5.001) L5(2.001,-5.001) L6(2.501,-5.001) L7(3.001,-5.001) L8(3.501,-5.001) L9(4.001,-5.001) L10(4.501,-5.001) L11(5.001,-5.001)
TVNST52302AB0_SOT523-3
  oval 0.508x0.559 smd: 1(0,0) 2(-0.5,-1.4) 3(0.5,-1.4)
TVWDF1004AD0_DFN9
  oval 0.203x0.686 smd: 1(0,0) 2(0.5,0) 4(1.5,0) 5(2,0) 6(2,0.875) 7(1.5,0.875) 8(0.5,0.875) 9(0,0.875)
  oval 0.406x1.549 smd: 3(1,0.437)
TWVM_FPC1020-18RC-TA0HC_18P
  oval 0.61x1.143 smd: 1(0,0) 2(-1,0) 3(-2,0) 4(-3,0) 5(-4,0) 6(-5,0) 7(-6,0) 8(-7,0) 9(-8,0) 10(-9,0) 11(-10,0) 12(-11,0) 13(-12,0) 14(-13,0) 15(-14,0) 16(-15,0) 17(-16,0) 18(-17,0)
  rect 2.489x2.21 smd: 19(-20,-2.975) 20(3,-2.975)
W25Q80DVSSIG_SO8
  oval 0.635x1.676 smd: 1(0,0) 2(1.27,0) 3(2.54,0) 4(3.81,0) 5(3.81,7.25) 6(2.54,7.25) 7(1.27,7.25) 8(0,7.25)
W25Q128FVSIQ_SO8
  oval 0.635x1.676 smd: 1(0,0) 2(1.27,0) 3(2.54,0) 4(3.81,0) 5(3.81,7.25) 6(2.54,7.25) 7(1.27,7.25) 8(0,7.25)
W25Q256FVEIQ_WSON8_8X6-NPM
  oval 0.66x0.991 smd: 1(0,0) 2(1.27,0) 3(2.54,0) 4(3.81,0) 5(3.81,8) 6(2.54,8) 7(1.27,8) 8(0,8)
  rect 4.293x3.404 smd: 9(1.905,4)
W25X20CLSNIG_SO8
  oval 0.635x1.854 smd: 1(0,0) 2(1.27,0) 3(2.54,0) 4(3.81,0) 5(3.81,5.165) 6(2.54,5.165) 7(1.27,5.165) 8(0,5.165)
Y_7V25000012_4P
  rect 1.397x1.194 smd: 1(0,0) 2(2.2,0) 3(2.2,1.7) 4(0,1.7)
Y_7V25000014_4P
  rect 1.397x1.194 smd: 1(0,0) 2(2.2,0) 3(2.2,1.7) 4(0,1.7)
Y_7V27000011_4P
  rect 1.397x1.194 smd: 1(0,0) 2(2.2,0) 3(2.2,1.7) 4(0,1.7)
Y_CM31532768DZFT_2P
  rect 1.092x1.905 smd: 1(0,0) 2(2.5,0)
Y_X1A000141000200_2P
  rect 0.991x1.803 smd: 1(0,0) 2(2.5,0)
Y_X3G024000DC1H_4P
  rect 1.397x1.194 smd: 1(0,0) 2(2.2,0) 3(2.2,1.7) 4(0,1.7)

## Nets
1.0VS_VGAP_VIN: PC1001.1 PC1002.2 PJP1001.2 PL1011.2 PU1001.8 PU1001.9 PU1001.10
1.2V_VDDQ_EN: CZ102.1 DZ1.2 PRM08.1 RZ102.2
1.2V_VIN: PCM01.1 PCM02.1 PCM03.1 PCM04.1 PCM22.1 PCM23.1 PJPM01.2 PLM11.2 PQM01.2 PQM01.3 PQM01.4 PQM01.10 PRM07.1
1.35VGPUP: PCW18.1 PCW19.1 PJPW02.1 PJPW03.1 PLW01.2 PRW14.2
1V05PRIM_PG: PRH01.2 PUH01.1 RE149.1
1V8_AON_ON: QG503.2 RG70.2 UG12.3 UG25.4
1V8_MAIN_EN: CG487.1 DG3.2 DG7.2 DG10.1 QG504.2 RG549.1 RG550.1 RV55.1 UG12.5 UV1.P7
2.5V_VIN: PC2501.1 PJP2501.2 PU2501.3
3.3V_TS_EN: U3.4 UH1.BD30
3V_FB: PC315.1 PR307.2 PR308.1 PU301.13
3V_SN: PC309.1 PR305.2
3V_VIN: PC301.1 PC302.1 PC303.1 PC304.1 PC305.1 PC306.1 PJP301.2 PL311.2 PU301.2 PU301.3 PU301.4 PU301.5
5V_FB: PC517.1 PR510.2 PR511.1 PU501.13
5V_SN: PC509.1 PR505.2
5V_VIN: PC501.1 PC502.1 PC503.1 PC504.1 PC505.1 PC506.1 PJP501.2 PL511.2 PU501.2 PU501.3 PU501.4 PU501.5
5VS_FAN1: JFAN1.4 RE104.2
5VS_FAN2: JFAN2.4 RE105.2
+0.6V_DDR_VTT: CD5.1 CD6.1 CD7.1 CD31.1 CD32.1 CD33.1 CD34.1 CD60.1 CD61.1 JDIMM1.258 JDIMM2.258 PJPM03.2
+0.6VSP: PCM20.1 PCM21.1 PJPM03.1 PUM01.2 PUM01.20
+0.9V_CIO: CT78.1 CT79.1 CT80.1 UT1.R8 UT1.R9 UT1.R11 UT1.R12
+0.9V_DP: CT54.1 CT57.1 CT58.1 CT59.1 CT60.1 CT61.1 CT62.1 UT1.L6 UT1.L8 UT1.L11 UT1.L12 UT1.M6 UT1.M8 UT1.T11 UT1.T12 UT1.V11 UT1.V12 UT1.V13
+0.9V_LVR_OUT: CT81.1 CT82.1 CT83.1 CT84.1 UT1.F18 UT1.H11 UT1.H18 UT1.J11
+0.9V_PCIE: CT55.1 CT70.1 CT71.1 CT72.1 UT1.L18 UT1.L19 UT1.M13 UT1.M15 UT1.M16 UT1.M18 UT1.N18 UT1.N19
+0.9V_SVR: CT63.1 CT64.1 CT65.1 CT66.1 CT67.1 CT68.1 CT69.1 CT73.1 CT74.1 CT75.1 LT1.2 UT1.E12 UT1.E13 UT1.F11 UT1.F12 UT1.F13 UT1.F15 UT1.J9 UT1.L9 UT1.M9
+0.9V_USB: CT56.1 CT77.1 UT1.R15 UT1.R16
+1.0VS_VGA_PGOOD: PR1002.2 PU1001.4 UG27.2
+1.0VS_VGAP: PC1003.1 PC1005.1 PC1006.1 PC1007.1 PJP1002.1 PL1001.2 PR1001.2
+1.2V_DDR: CC17.1 CC18.1 CC19.1 CC20.1 CC21.1 CC22.1 CC23.1 CC24.1 CC25.1 CC26.1 CC27.1 CC28.1 CC29.1 CC30.1 CC31.1 CC32.1 CD11.1 CD12.1 CD13.1 CD14.1 CD15.1 CD16.1 CD17.1 CD18.1 CD19.1 CD20.1 CD21.1 CD22.1 CD23.1 CD24.1 CD25.1 CD26.1 CD27.1 CD41.1 CD42.1 CD43.1 CD44.1 CD45.1 CD46.1 CD47.1 CD48.1 CD49.1 CD50.1 CD51.1 CD52.1 CD53.1 CD54.1 CD55.1 CD56.1 CH197.1 CZ50.1 JDIMM1.12 JDIMM1.33 JDIMM1.54 JDIMM1.75 JDIMM1.96 JDIMM1.111 JDIMM1.112 JDIMM1.117 JDIMM1.118 JDIMM1.123 JDIMM1.124 JDIMM1.129 JDIMM1.130 JDIMM1.135 JDIMM1.136 JDIMM1.141 JDIMM1.142 JDIMM1.147 JDIMM1.148 JDIMM1.153 JDIMM1.154 JDIMM1.159 JDIMM1.160 JDIMM1.163 JDIMM1.178 JDIMM1.199 JDIMM1.220 JDIMM1.241 JDIMM2.12 JDIMM2.33 JDIMM2.54 JDIMM2.75 JDIMM2.96 JDIMM2.111 JDIMM2.112 JDIMM2.117 JDIMM2.118 JDIMM2.123 JDIMM2.124 JDIMM2.129 JDIMM2.130 JDIMM2.135 JDIMM2.136 JDIMM2.141 JDIMM2.142 JDIMM2.147 JDIMM2.148 JDIMM2.153 JDIMM2.154 JDIMM2.159 JDIMM2.160 JDIMM2.163 JDIMM2.178 JDIMM2.199 JDIMM2.220 JDIMM2.241 PJPM02.2 PJPM04.2 RC14.2 RD7.1 RD10.1 RD20.1 RD23.1 RD24.1 UC1.AA6 UC1.AE12 UC1.AF5 UC1.AF6 UC1.AG5 UC1.AG9 UC1.AJ12 UC1.AL11 UC1.AP6 UC1.AP7 UC1.AR6 UC1.AR12 UC1.AT12 UC1.AW6 UC1.AY6 UC1.J5 UC1.J6 UC1.K6 UC1.K12 UC1.L6 UC1.L12 UC1.R6 UC1.T6 UC1.W6 UC1.Y12 UC10.5 UZ16.1 UZ16.2
+1.2V_RTM: CP3.1 CP4.1 CP5.1 CP6.1 CP7.1 CP8.1 CP9.1 CP10.1 CP11.1 CP12.1 CP13.1 CP14.1 RP51.1 RP52.1 UP2.6 UP2.11 UP2.15 UP2.18 UP2.30 UP2.43 UP2.46
+1.2V_RTM_IN: CP32.1 RP30.1 RP51.2 RP52.2 UP1.1
+1.2V_VCCPLL_OC: CC36.1 CC37.1 CZ49.1 RC14.1 RZ67.1 UC1.BH13 UC1.BJ13 UC1.G11
+1.2V_VCCPLL_OC_OUT: RZ67.2 UZ16.7 UZ16.8
+1.2VP: PCM05.1 PCM06.1 PCM07.1 PCM08.1 PCM09.1 PCM10.1 PCM17.2 PCM18.1 PJPM02.1 PJPM04.1 PLM01.1 PRM10.2 PUM01.5 PUM01.19
+1.05V_LDO: CH16.1 UH1.BG45 UH1.BG46
+1.05V_VCCAMPHYPLL: CH18.1 CH19.1 RH732.1 UH1.C49 UH1.D49 UH1.E49
+1.05V_XDP: RC80.1 RC251.2
+1.05V_XTAL: CH20.1 RH731.1 UH1.P2 UH1.P3
+1.05VALW: CC41.1 CC42.1 CH12.1 CH13.1 CH14.1 CH15.1 CH17.1 CH21.1 CH22.1 CH23.1 CH24.1 CH62.1 CH223.1 CZ88.1 CZ96.1 PJPH02.2 PJPH03.2 RC251.1 RE162.1 RH71.1 RH731.2 RH732.2 RH748.1 UH1.AA22 UH1.AA23 UH1.AB20 UH1.AB22 UH1.AB23 UH1.AB27 UH1.AB28 UH1.AB30 UH1.AD20 UH1.AD23 UH1.AD27 UH1.AD28 UH1.AD30 UH1.AD31 UH1.AE17 UH1.AF23 UH1.AF27 UH1.AF30 UH1.AF31 UH1.AG31 UH1.B1 UH1.B2 UH1.B3 UH1.C1 UH1.C2 UH1.D1 UH1.E1 UH1.U26 UH1.U29 UH1.V19 UH1.V25 UH1.V27 UH1.V28 UH1.V30 UH1.V31 UH1.W19 UH1.W20 UH1.W22 UH1.W23 UH1.W31 UZ9.1 UZ9.2 UZ9.7 UZ15.1 UZ15.2 UZ15.7
+1.05VP: PCH13.1 PCH14.1 PJPH02.1 PJPH03.1 PLH01.2 PRH10.2
+1.8V_AVDD: CA12.2 RA5.2 UA1.33
+1.8V_CPVDD: CA13.2 CA14.1 CA46.1 CA50.1 RA6.2 UA1.29
+1.8V_PHVLDO: RH736.2 UH1.AF19 UH1.AF20
+1.8V_PLLVDD: CV50.1 CV51.1 LV7.1 RV583.2 RV584.2 RV585.2 RV586.2
+1.8V_PRIM: CG288.1 CH29.1 CH35.1 PJP1802.2 QA1.1 RE66.1 RG70.1 RH93.2 RH150.2 RH546.2 RH578.2 RH588.1 RH613.1 RH614.1 RH671.1 RH719.1 RH722.2 RH723.2 RH736.1 UG12.1 UG12.2 UH1.AG19 UH1.AG20 UH1.AN15 UH1.AR15 UH1.BB11
+1.8VA_TBTA_LDO: CT100.1 UT4.K1
+1.8VALW_EC: CE15.1 CE38.1 CE39.1 RE66.2 UE1.54
+1.8VALWP: PC1802.1 PC1803.1 PC1804.1 PC1807.1 PJP1802.1 PL1801.2 PR1807.1
+1.8VD_TBTA_LDO: CT99.1 UT4.A2
+1.24V_PRIM_DPHY: RH174.2 UH1.AJ22 UH1.AJ23
+1.24V_PRIM_MAR: CH36.1 UH1.BG5
+1.24V_VCCLDOSRAM_IN: RH174.1 UH1.AK22 UH1.AK23
+1.35VGPU_BOOT1: PRW05.2 PUW01.1
+1.35VGPU_BOOT1_1: PCW11.2 PRW05.1
+1.35VGPU_EN: PRW06.2 PUW01.3
+1.35VGPU_LGATE1: PQW01.6 PUW01.19
+1.35VGPU_PHASE1: PCW11.1 PLW01.1 PQW01.7 PRW04.1 PUW01.20
+1.35VGPU_PSI: PCW13.1 PRW07.2 PRW08.1 PUW01.4
+1.35VGPU_PVCC: PCW09.1 PRW01.2 PUW01.18
+1.35VGPU_TON: PRW03.2 PUW01.9
+1.35VGPU_TON_1: PCW10.2 PRW02.2 PRW03.1
+1.35VGPU_UGATE1: PQW01.1 PUW01.2
+1.35VGPU_VIN: PCW01.1 PCW02.1 PCW03.1 PCW04.1 PCW05.1 PCW06.1 PCW07.1 PCW08.1 PJPW01.2 PLW11.2 PQW01.2 PRW02.1
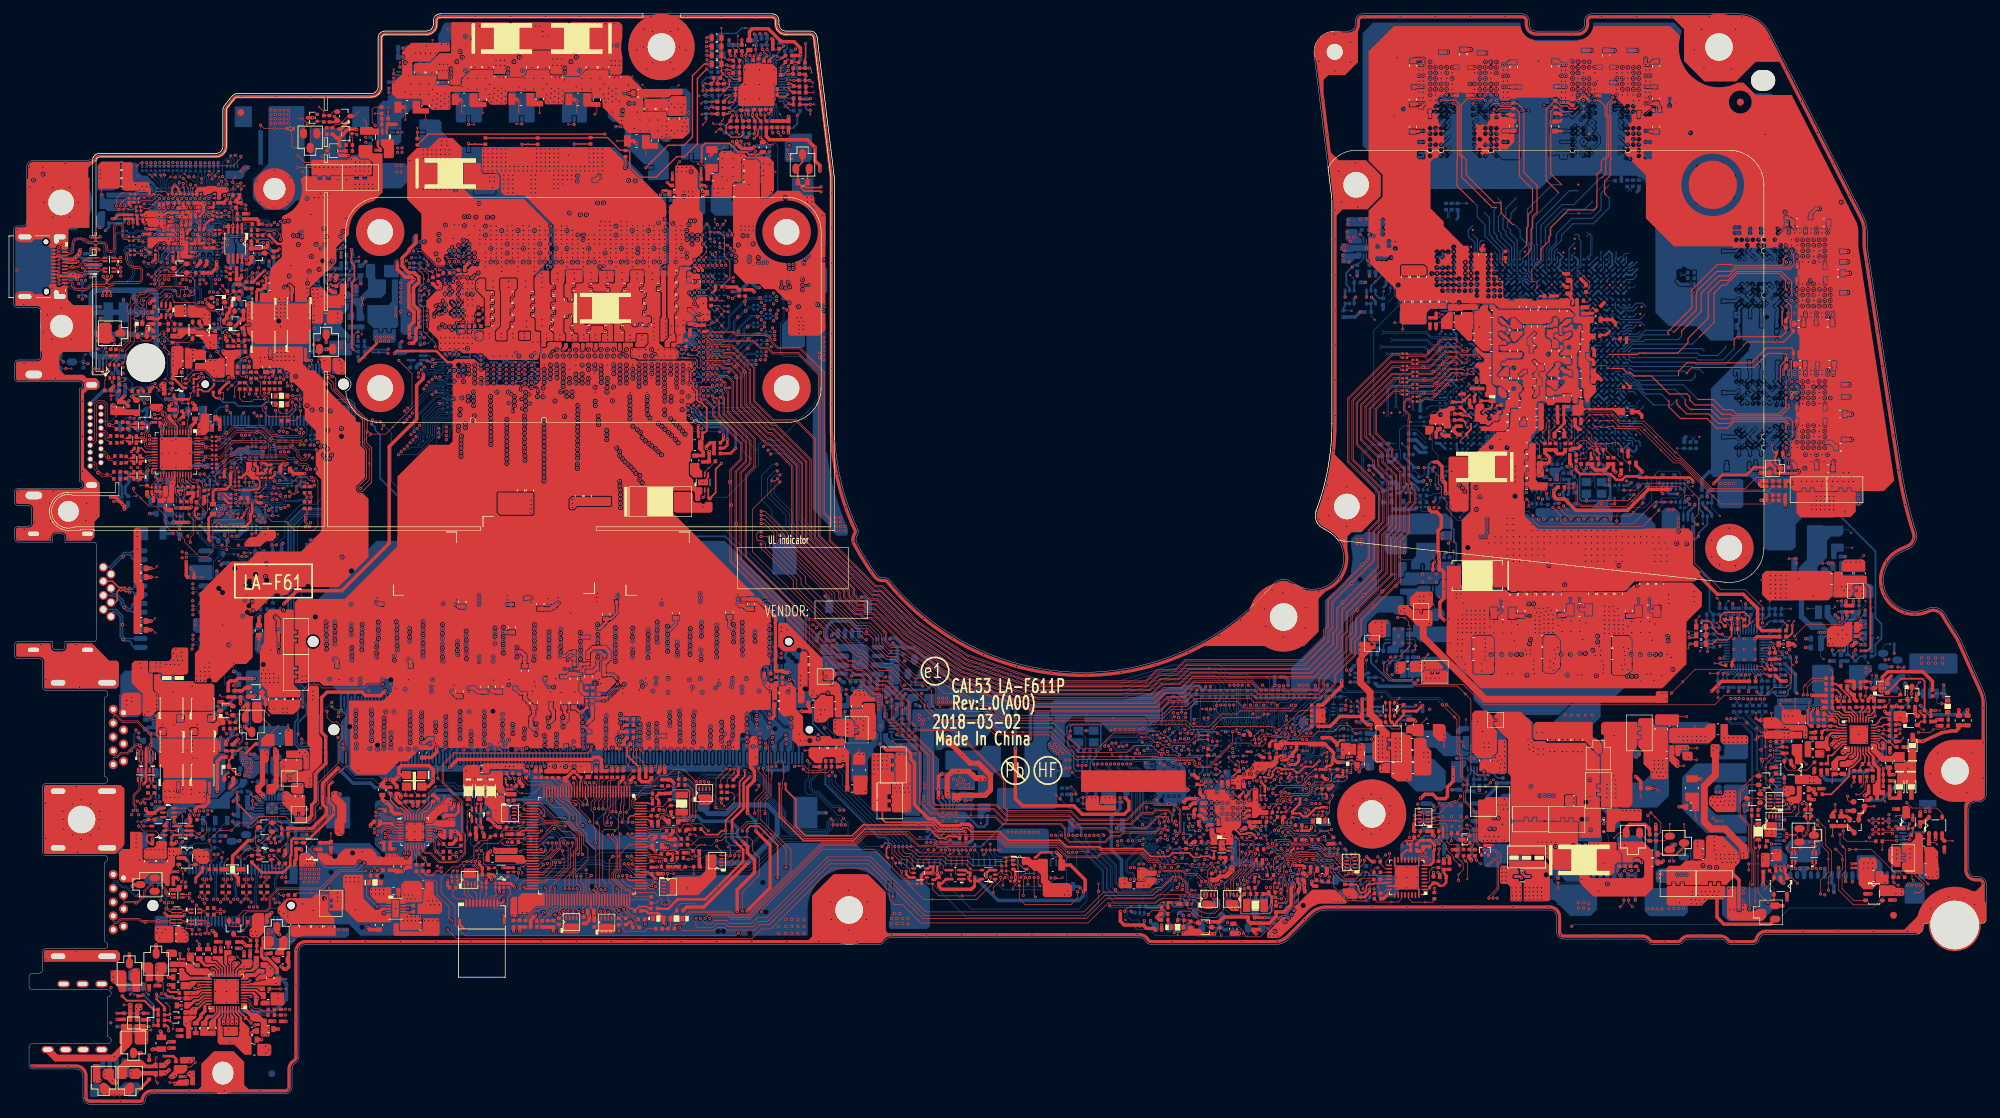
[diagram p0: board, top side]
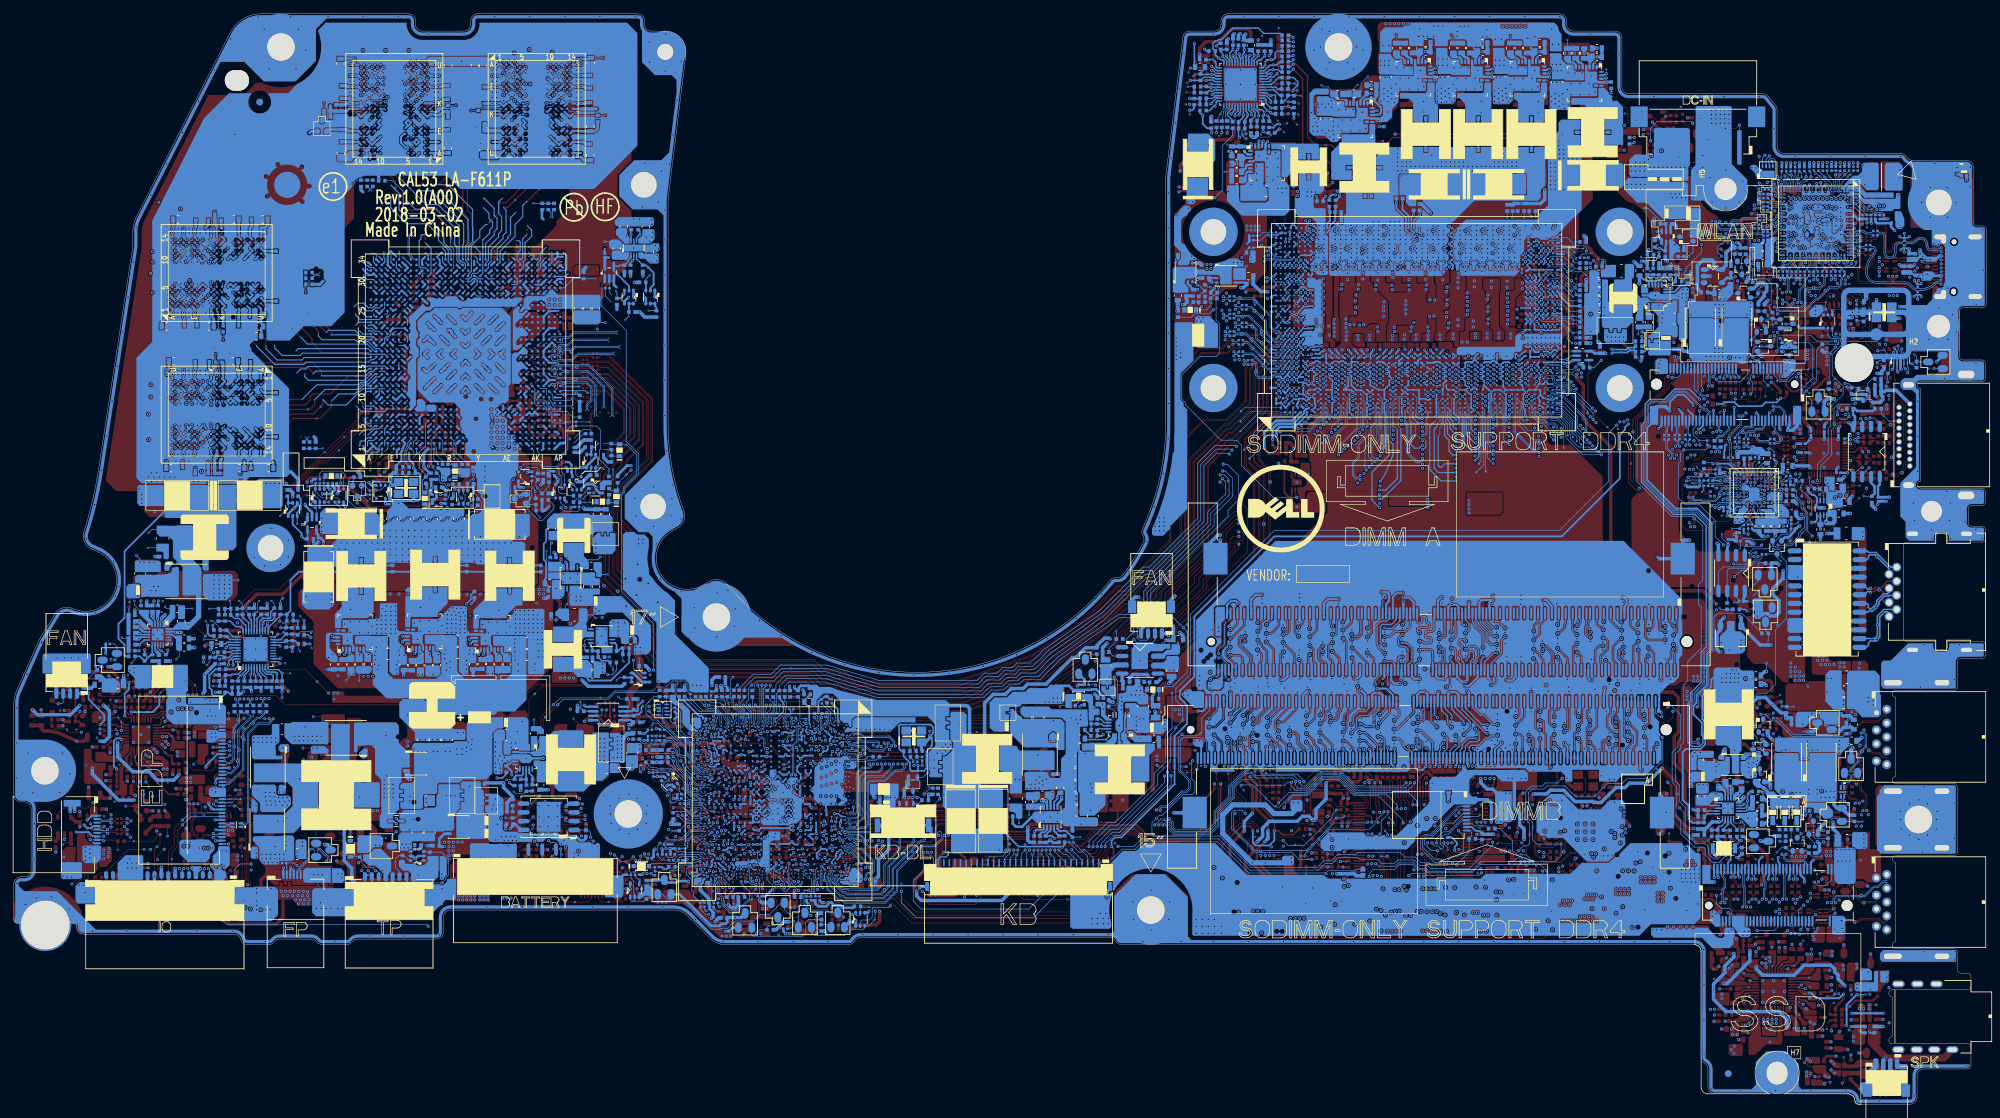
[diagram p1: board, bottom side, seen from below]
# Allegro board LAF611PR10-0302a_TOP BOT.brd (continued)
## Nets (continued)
+1.35VS_VGA: CV79.2 CV80.2 CV83.1 CV84.1 CV85.1 CV86.1 CV100.1 CV101.1 CV102.1 CV103.1 CV112.1 CV113.1 CV160.1 CV161.1 CV162.1 CV163.1 CV164.1 CV165.1 CV166.1 CV167.1 CV168.1 CV169.1 CV170.1 CV171.1 CV172.1 CV173.1 CV174.1 CV175.1 CV179.1 CV180.1 CV181.1 CV182.1 CV183.1 CV184.1 CV185.1 CV186.1 CV187.1 CV188.1 CV189.1 CV190.1 CV191.1 CV192.1 CV193.1 CV194.1 CV206.1 CV207.1 CV208.1 CV209.1 CV210.1 CV211.1 CV373.1 CV374.1 CV375.1 CV376.1 CV377.1 CV378.1 CV379.1 CV380.1 CV381.1 CV382.1 CV383.1 CV384.1 CV385.1 CV386.1 CV387.1 CV388.1 CV389.1 CV390.1 CV391.1 CV392.1 CV393.1 CV394.1 CV395.1 CV396.1 CV397.1 CV398.1 CV399.1 CV400.1 CV401.1 CV402.1 CV403.1 CV404.1 CV834.1 CV841.2 CV842.2 CV844.2 CV845.2 CV851.1 CV852.1 CV853.1 CV854.1 CV855.1 CV856.1 CV857.1 CV858.1 CV859.1 CV860.1 CV861.1 CV862.1 CV863.1 CV864.1 CV865.1 CV866.1 CV867.1 CV868.1 CV869.1 CV870.1 CV871.1 CV872.1 CV873.1 CV874.1 CV875.1 CV876.1 CV877.1 CV878.1 CV879.1 CV880.1 CV881.1 CV882.1 CV883.1 CV884.1 CV885.1 CV886.1 CV887.1 CV888.1 CV889.1 CV890.1 CV891.1 CV892.1 CV893.1 CV894.1 CV895.1 CV896.1 CV897.1 CV898.1 CV899.1 CV900.1 CV901.1 CV902.1 CV941.1 CV942.1 CV943.2 CV944.2 CV945.1 CV946.1 CV947.1 PJPW02.2 PJPW03.2 RG514.1 RV77.1 RV95.1 RV96.1 RV98.1 RV99.1 RV117.2 RV125.1 RV131.2 RV140.1 RV602.2 RV603.2 RV604.2 RV605.2 UV1.AA27 UV1.AA30 UV1.AB27 UV1.AB33 UV1.AC27 UV1.AD27 UV1.AE27 UV1.AF27 UV1.AG27 UV1.B13 UV1.B16 UV1.B19 UV1.E13 UV1.E16 UV1.E19 UV1.H8 UV1.H9 UV1.H10 UV1.H11 UV1.H12 UV1.H13 UV1.H14 UV1.H15 UV1.H16 UV1.H18 UV1.H19 UV1.H20 UV1.H21 UV1.H22 UV1.H23 UV1.H24 UV1.L27 UV1.M27 UV1.N27 UV1.P27 UV1.R27 UV1.T27 UV1.T30 UV1.T33 UV1.V27 UV1.W27 UV1.W30 UV1.W33 UV1.Y27 UV6.B1 UV6.B3 UV6.B12 UV6.B14 UV6.C5 UV6.C10 UV6.D1 UV6.D3 UV6.D11 UV6.D12 UV6.D14 UV6.E5 UV6.E10 UV6.F1 UV6.F3 UV6.F12 UV6.F14 UV6.G1 UV6.G2 UV6.G4 UV6.G11 UV6.G13 UV6.G14 UV6.H3 UV6.H12 UV6.K3 UV6.K12 UV6.L1 UV6.L2 UV6.L4 UV6.L11 UV6.L13 UV6.L14 UV6.M1 UV6.M3 UV6.M12 UV6.M14 UV6.N5 UV6.N10 UV6.P1 UV6.P3 UV6.P11 UV6.P12 UV6.P14 UV6.R5 UV6.R10 UV6.T1 UV6.T3 UV6.T12 UV6.T14 UV7.B1 UV7.B3 UV7.B12 UV7.B14 UV7.C5 UV7.C10 UV7.D1 UV7.D3 UV7.D11 UV7.D12 UV7.D14 UV7.E5 UV7.E10 UV7.F1 UV7.F3 UV7.F12 UV7.F14 UV7.G1 UV7.G2 UV7.G4 UV7.G11 UV7.G13 UV7.G14 UV7.H3 UV7.H12 UV7.K3 UV7.K12 UV7.L1 UV7.L2 UV7.L4 UV7.L11 UV7.L13 UV7.L14 UV7.M1 UV7.M3 UV7.M12 UV7.M14 UV7.N5 UV7.N10 UV7.P1 UV7.P3 UV7.P11 UV7.P12 UV7.P14 UV7.R5 UV7.R10 UV7.T1 UV7.T3 UV7.T12 UV7.T14 UV8.B1 UV8.B3 UV8.B12 UV8.B14 UV8.C5 UV8.C10 UV8.D1 UV8.D3 UV8.D11 UV8.D12 UV8.D14 UV8.E5 UV8.E10 UV8.F1 UV8.F3 UV8.F12 UV8.F14 UV8.G1 UV8.G2 UV8.G4 UV8.G11 UV8.G13 UV8.G14 UV8.H3 UV8.H12 UV8.K3 UV8.K12 UV8.L1 UV8.L2 UV8.L4 UV8.L11 UV8.L13 UV8.L14 UV8.M1 UV8.M3 UV8.M12 UV8.M14 UV8.N5 UV8.N10 UV8.P1 UV8.P3 UV8.P11 UV8.P12 UV8.P14 UV8.R5 UV8.R10 UV8.T1 UV8.T3 UV8.T12 UV8.T14 UV9.B1 UV9.B3 UV9.B12 UV9.B14 UV9.C5 UV9.C10 UV9.D1 UV9.D3 UV9.D11 UV9.D12 UV9.D14 UV9.E5 UV9.E10 UV9.F1 UV9.F3 UV9.F12 UV9.F14 UV9.G1 UV9.G2 UV9.G4 UV9.G11 UV9.G13 UV9.G14 UV9.H3 UV9.H12 UV9.K3 UV9.K12 UV9.L1 UV9.L2 UV9.L4 UV9.L11 UV9.L13 UV9.L14 UV9.M1 UV9.M3 UV9.M12 UV9.M14 UV9.N5 UV9.N10 UV9.P1 UV9.P3 UV9.P11 UV9.P12 UV9.P14 UV9.R5 UV9.R10 UV9.T1 UV9.T3 UV9.T12 UV9.T14
+1V8_AON: CG246.1 CG289.1 CG320.1 CG440.1 CG527.1 CV202.1 CV212.1 CV213.1 CV214.1 CV529.1 CV530.1 CV843.1 PR1006.1 PRV04.1 PRW07.1 PRW09.1 RG9.2 RG510.1 RG516.1 RV39.1 RV41.2 RV42.2 RV55.2 RV57.2 RV60.2 RV146.2 RV147.2 RV148.2 RV149.2 RV150.2 RV157.2 RV158.2 RV159.2 RV191.2 RV192.2 RV512.2 RV513.2 RV514.2 RV515.2 RV526.2 RV532.2 RV574.2 RV593.2 RV678.1 RV679.1 RV682.2 RV683.1 UG12.6 UG12.7 UG12.13 UG12.14 UG22.5 UG27.5 UG31.5 UV1.J8 UV1.K8 UV14.5 UV19.5 UV20.5
+1V8_MAIN: CG290.1 CV94.2 CV95.2 CV97.1 CV117.1 CV118.1 CV119.1 CV120.1 CV835.1 CV836.1 CV837.1 CV838.1 CV839.1 CV840.1 LG8.1 LV7.2 LV13.2 RG512.1 RV590.1 UG12.8 UG12.9 UV1.AG13 UV1.AG15 UV1.AG16 UV1.AG18 UV1.AG25 UV1.AH15 UV1.AH18 UV1.AH26 UV1.AH27 UV1.AJ27 UV1.AK27 UV1.AL27 UV1.AM28 UV1.AN28 UV1.L8 UV1.M8
+1VS_GFX: CV87.1 CV88.1 CV89.1 CV90.1 CV91.1 CV92.1 CV93.2 CV96.1 PJP1002.2 RG544.1 RV655.1 UV1.AG19 UV1.AG21 UV1.AG22 UV1.AG24 UV1.AH21 UV1.AH25
+2.5V_MEM: CD1.1 CD2.1 CD3.1 CD4.1 CD35.1 CD36.1 CD37.1 CD62.1 CD63.1 JDIMM1.257 JDIMM1.259 JDIMM2.257 JDIMM2.259 PJP2502.2
+2.5VP: PC2502.1 PC2505.1 PJP2502.1 PR2502.1 PU2501.6
+3.3V_ADP_DCIN: DT19.2 PC9.1 PDS01.2 PR14.1 PR22.1 PRS02.1 PRS04.1 PRS32.1 PRS34.1 PRS45.1 PU01.5
+3.3V_ANA_PCIE: CT85.1 UT1.L16
+3.3V_ANA_USB2: CT86.1 UT1.J16
+3.3V_FLASH: CT45.1 CT103.1 CT137.1 RT48.1 RT49.1 RT50.1 RT51.1 RT66.1 RT67.1 RT74.1 RT112.1 RT125.2 RT126.2 RT127.2 RT128.2 UT2.8 UT3.8 UT4.G1
+3.3V_LC: CT46.1 RT6.1 RT7.1 RT8.1 RT9.1 UT1.R6
+3.3V_TBT_SX: CT47.1 Q29.2 RT26.1 RT27.1 RT28.1 RT30.1 RT31.1 RT32.1 RT33.1 RT61.2 RT70.1 RT86.1 RT94.1 RT97.2 RT152.1 RT153.1 RT166.1 UT1.F8
+3.3V_TBT_SX_R: CT102.1 RT61.1 UT4.H2
+3.3V_VBUS_IN: DT21.2 PCS13.1 PCS14.1 PCS16.1 PDS01.3 PRB38.1 PRS12.1 PUS02.5 PUS03.5 PUS04.3
+3.3V_WLAN: CW6.1 CW7.1 CW8.1 CW9.1 JWLAN1.2 JWLAN1.4 JWLAN1.72 JWLAN1.74 RW3.1 RW5.2 UW1.1
+3V_1.8V_PGPPA: CH63.1 RH128.2 RH143.2 RH150.1 RH506.2 RH701.2 UH1.AN32
+3V_DVDD: CA5.2 CA6.1 CA15.1 CA16.1 CA44.1 CA48.1 RA2.2 RA3.2 RA8.1 UA1.1 UA1.8
+3V_PCH_PRIM: CC43.1 CC148.1 CH30.1 CH31.1 CH32.1 CH33.1 CZ32.1 RC252.1 RE10.2 RE11.2 RH12.1 RH23.2 RH29.2 RH62.1 RH63.1 RH64.1 RH65.1 RH66.1 RH89.2 RH130.1 RH143.1 RH162.1 RH524.1 RH674.1 RH675.1 RH687.2 RH721.2 RH724.2 RH725.2 RH726.2 RH727.2 RH734.2 RH737.2 RH744.1 RH745.1 RPH6.5 RPH6.6 RPH6.7 RPH6.8 RS2.2 RSPI1.2 RT29.1 RTPM9.1 RTPM10.1 RW5.1 UC12.5 UH1.AC35 UH1.AC36 UH1.AE35 UH1.AE36 UH1.AN21 UH1.AN24 UH1.AN26 UH1.AN44 UH1.AP26 UH1.AT44 UH1.AW9 UH1.AY8 UH1.BB7 UH1.BB14 UH1.V23 UZ7.7 UZ7.8
+3V_RTM: CP24.1 CP25.1 CP26.1 RP24.2 RP25.2 RP28.1 RP33.1 RP34.1 RP35.1 RP36.1 RP37.1 RP38.1 RP48.2 RP49.2 UP2.1 UP2.24
+3V_SPI: CH49.1 RH74.1 RH75.1 RH78.1 RH735.1 RSPI1.1 UH4.8 UH15.8
+3VALW: CC298.1 CC302.1 CL9.1 CZ25.1 CZ37.1 DT20.2 JIOB1.9 PC909.1 PJP302.2 PJP303.2 PJP1001.1 PJP1801.1 PJP2501.1 PL1011.1 PL1811.1 PR5.2 PR33.1 PR41.2 PR905.2 PR1803.1 PRB27.1 PRH01.1 PRM06.1 PRS28.1 PU901.15 Q17.2 Q17.5 R35.1 RA11.2 RE2.1 RE18.2 RE21.2 RE25.1 RE55.1 RE56.1 RE57.1 RE58.1 RE59.1 RE150.2 RE164.1 RH89.1 RH685.1 RH706.1 RH707.1 RL7.1 RPE1.5 RPE1.6 RPE1.7 RPE1.8 RPE2.5 RPE2.6 RPE2.7 RPE2.8 RPE3.1 RPE3.2 RPE3.3 RPE3.4 RPE4.1 RPE4.2 RPE4.3 RPE4.4 RPE5.1 RPE5.2 RPE5.3 RPE5.4 RPE6.1 RPE6.2 RPE6.3 RPE6.4 RPE7.5 RPE7.6 RPE7.7 RPE7.8 RT95.1 RT97.1 RT134.1 RTPM6.2 RW11.1 RW12.1 UC16.5 UL2.5 UW1.5 UZ1.1 UZ1.2 UZ7.1 UZ7.2 UZ21.5
+3VALW_DSW: CH34.1 RH162.2 RH453.2 RH515.2 RH533.2 RH545.2 RH717.2 UH1.BE48 UH1.BE49
+3VALW_EC: CE5.1 CE6.1 CE7.2 CE8.2 CE9.1 CE10.1 CE11.1 CE12.1 CE13.1 CE20.1 CE21.1 CE36.1 CE37.1 DT19.1 DT20.1 DT21.1 JESPI1.1 JESPI1.2 PRS49.1 PRS50.1 R43.1 RE1.1 RE2.2 RE3.1 RE8.2 RE9.2 RE14.2 RE15.2 RE17.2 RE30.2 RE31.2 RE46.1 RE49.1 RE155.1 RE165.2 RE166.2 RE169.2 UE1.5 UE1.19 UE1.22 UE1.43 UE1.65 UE1.82 UE1.103 UE1.115
+3VALW_PD: CT88.1 CT101.1 RT134.2 UT4.B1 UT4.H1
+3VALWP: PC310.1 PC311.1 PC312.1 PC313.1 PC314.1 PJP302.1 PJP303.1 PL301.2 PR304.1 PR306.2 PR307.1 PR504.1 PU301.14
+3VLP: D1.2 PC308.1 PU301.16 PU301.17 R42.1 RE29.2 RE167.1
+3VS: C17.1 C21.1 C37.2 C46.1 C50.1 C55.1 C56.1 CC301.1 CD9.1 CD10.1 CD39.1 CD40.1 CE22.1 CG438.1 CH201.1 CP28.1 CS29.1 CS30.1 CTPM3.1 CTPM4.1 CW3.1 CW4.1 CW5.1 CZ9.1 CZ110.1 JDIMM1.255 JDIMM2.255 JFP.7 JFP.8 JIOB1.12 JP10.2 PR901.1 PR1002.1 PRV01.1 PRV02.1 PRV10.2 PRW18.1 PRZ17.1 Q6.2 Q10.2 Q10.5 Q11.2 Q11.5 Q23.2 Q24.2 QA1.2 QH4.2 QH4.5 QX3.1 R5.1 R16.1 R24.1 R28.1 R29.1 R33.1 R34.1 R36.1 R48.1 R49.1 R57.1 R82.1 R83.1 RA2.1 RC270.1 RD1.1 RD2.1 RD3.1 RD13.1 RD14.1 RD15.1 RE121.1 RE122.1 RE152.1 RE153.1 RE156.2 RG50.1 RG51.1 RG505.1 RG506.1 RH33.2 RH69.2 RH179.2 RH180.1 RH462.1 RH463.1 RH501.1 RH502.1 RH512.2 RH520.1 RH521.1 RH537.2 RH551.1 RH553.1 RH557.1 RH561.1 RH571.2 RH573.2 RH676.1 RH680.1 RH709.2 RH710.2 RH728.1 RL3.1 RP3.1 RP3.2 RP3.3 RP3.4 RP28.2 RS3.1 RT57.1 RT58.1 RT168.1 RTPM7.2 RTPM8.1 RW3.2 U1.5 U2.1 UE2.5 UG25.5 UH3.5 UH14.5 UP1.5 UP1.8 US1.2 US1.3 US1.9 US1.10 UTPM1.8 UZ1.13 UZ1.14
+3VS_CAM: C14.1 C15.1 C49.1 JEDP1.29 R16.2
+3VS_SSD: CS24.1 CS25.1 CS26.1 CS27.1 CS33.1 CS34.1 CS35.1 CS36.1 JP10.1 JSSD1.2 JSSD1.4 JSSD1.12 JSSD1.14 JSSD1.16 JSSD1.18 JSSD1.70 JSSD1.72 JSSD1.74 RS9.1
+3VS_TBT: CT48.1 CT49.1 CT50.1 CT51.1 CT52.1 CT53.1 LT4.2 RT20.1 RT21.1 RT76.2 RT95.2 RT168.2 UT1.A2 UT1.A3 UT1.B3 UT1.H9
+5V_AVDD: CA10.1 CA11.1 CA45.1 CA49.1 RA4.2 UA1.20
+5V_HDD: CS5.1 CS6.1 CS7.1 CS32.1 JHDD.10 JHDD.11 JHDD.12 JP5.2 RS4.1 RS8.2
+5V_KB_BL: C34.1 C51.1 C150.1 F3.1 JKBBL.1
+5V_PVDD: CA1.1 CA2.1 CA3.1 CA4.1 CA43.1 CA47.1 RA1.2 UA1.34 UA1.39
+5VALW: CP29.1 CT90.1 CT91.1 CT92.1 CT93.1 CU5.1 CU16.1 CZ23.1 CZ40.1 CZ51.1 CZ86.1 CZ97.1 PCA08.1 PCG08.1 PCH10.1 PCI15.1 PCI25.1 PCI35.1 PCI45.1 PCV28.1 PCV38.1 PCV48.1 PD2.3 PD3.3 PJP502.2 PJP503.2 PR4.1 PR2504.1 PRA01.1 PRG01.1 PRI01.1 PRI05.1 PRI09.1 PRI13.1 PRM04.1 PRM05.2 PRV47.1 PRV51.1 PRV55.1 PRW01.1 PRZ53.1 PRZ71.1 PRZ77.1 PUA01.15 PUG01.2 PUG01.15 PUH01.7 PUI01.2 PUI01.15 PUI02.2 PUI02.15 PUI03.2 PUI03.15 PUI04.2 PUI04.15 PUV01.2 PUV01.15 PUV02.2 PUV02.15 PUV03.2 PUV03.15 Q18.3 Q19.3 RG509.1 RG511.1 RG513.1 RG543.1 RH747.1 UP1.6 UT4.A11 UT4.B11 UT4.C11 UT4.D11 UT4.H10 UU1.5 UU3.5 UZ1.4 UZ1.6 UZ1.7 UZ7.4 UZ9.3 UZ15.3 UZ16.4
+5VALWP: PC510.1 PC511.1 PC512.1 PC513.1 PC514.1 PC518.1 PJP502.1 PJP503.1 PL501.2 PR509.2 PR510.1 PU501.14
+5VS: C30.1 C31.1 C53.1 C54.1 C148.1 CG386.1 CS8.1 CZ12.1 CZ109.1 F3.2 JP5.1 PRV05.2 PUV101.17 Q7.3 R13.1 RA1.1 RA4.1 RE82.1 RE100.1 RE101.1 RE104.1 RE105.1 RE151.1 RS5.2 U3.5 UG12.4 US2.5 UV17.1 UZ1.8 UZ1.9
+VBUS_DC_SS: PCS23.1 PDS02.2 PDS02.3 PDS07.2 PDS07.3 PQS01.5 PQS02.5 PQS15.5 PQS16.5
+VBUS_DC_TRIP: PCS09.1 PCS21.1 PQS01.1 PQS01.2 PQS01.3 PQS13.3 PQS15.1 PQS15.2 PQS15.3 PQS17.1 PQS17.2 PQS17.3 PQS18.1 PQS18.2 PQS18.3 PQS20.3 PRS08.1 PRS36.1 PRS42.1 PRS44.1
+VCC_CORE: PCI101.1 PCI102.1 PCI103.1 PCI104.1 PCI105.1 PCI106.1 PCI107.1 PCI108.1 PCI109.1 PCI110.1 PCI111.1 PCI112.1 PCI113.1 PCI114.1 PCI115.1 PCI116.1 PCI117.1 PCI118.1 PCI119.1 PCI120.1 PCI121.1 PCI122.1 PCI123.1 PCI124.1 PCI125.1 PCI126.1 PCI127.1 PCI128.1 PCI129.1 PCI130.1 PCI131.1 PCI132.1 PCI133.1 PCI134.1 PCI135.1 PCI136.1 PCI137.1 PCI138.1 PCI139.1 PCI140.1 PCI141.1 PCI142.1 PCI143.1 PCI144.1 PCI145.1 PCI146.1 PCI147.1 PCI148.1 PCI149.1 PCI150.1 PCI151.1 PCI152.1 PCI153.1 PCI154.1 PCI155.1 PCI156.1 PCI157.1 PCI158.1 PCI159.1 PCI160.1 PCI161.1 PCI162.1 PCI163.1 PCI164.1 PCI165.1 PCI171.1 PCI172.1 PCI173.1 PLI01.4 PLI02.4 PLI03.4 PLI04.4 RC10.2 UC1.AA13 UC1.AA31 UC1.AA32 UC1.AA33 UC1.AA34 UC1.AA35 UC1.AA36 UC1.AA37 UC1.AA38 UC1.AB29 UC1.AB30 UC1.AB31 UC1.AB32 UC1.AB35 UC1.AB36 UC1.AB37 UC1.AB38 UC1.AC13 UC1.AC14 UC1.AC29 UC1.AC30 UC1.AC31 UC1.AC32 UC1.AC33 UC1.AC34 UC1.AC35 UC1.AC36 UC1.AD13 UC1.AD14 UC1.AD31 UC1.AD32 UC1.AD33 UC1.AD34 UC1.AD35 UC1.AD36 UC1.AD37 UC1.AD38 UC1.AE13 UC1.AE14 UC1.AE30 UC1.AE31 UC1.AE32 UC1.AE35 UC1.AE36 UC1.AE37 UC1.AE38 UC1.AF29 UC1.AF30 UC1.AF31 UC1.AF32 UC1.AF33 UC1.AF34 UC1.AF35 UC1.AF36 UC1.AF37 UC1.AF38 UC1.AG14 UC1.AG31 UC1.AG32 UC1.AG33 UC1.AG34 UC1.AG35 UC1.AG36 UC1.AH13 UC1.AH14 UC1.AH29 UC1.AH30 UC1.AH31 UC1.AH32 UC1.AJ14 UC1.AJ29 UC1.AJ30 UC1.AJ31 UC1.AJ32 UC1.AJ33 UC1.AJ34 UC1.AJ35 UC1.AJ36 UC1.AK31 UC1.AK32 UC1.AK33 UC1.AK34 UC1.AK35 UC1.AK36 UC1.AK37 UC1.AK38 UC1.AL13 UC1.AL29 UC1.AL30 UC1.AL31 UC1.AL32 UC1.AL35 UC1.AL36 UC1.AL37 UC1.AL38 UC1.AM13 UC1.AM14 UC1.AM29 UC1.AM30 UC1.AM31 UC1.AM32 UC1.AM33 UC1.AM34 UC1.AM35 UC1.AM36 UC1.AN13 UC1.AN14 UC1.AN31 UC1.AN32 UC1.AN33 UC1.AN34 UC1.AN35 UC1.AN36 UC1.AN37 UC1.AN38 UC1.AP13 UC1.AP30 UC1.AP31 UC1.AP32 UC1.AP35 UC1.AP36 UC1.AP37 UC1.AP38 UC1.K13 UC1.K14 UC1.L13 UC1.L14 UC1.N13 UC1.N14 UC1.N30 UC1.N31 UC1.N32 UC1.N35 UC1.N36 UC1.N37 UC1.N38 UC1.P13 UC1.P14 UC1.P29 UC1.P30 UC1.P31 UC1.P32 UC1.P33 UC1.P34 UC1.P35 UC1.P36 UC1.R13 UC1.R31 UC1.R32 UC1.R33 UC1.R34 UC1.R35 UC1.R36 UC1.R37 UC1.R38 UC1.T29 UC1.T30 UC1.T31 UC1.T32 UC1.T35 UC1.T36 UC1.T37 UC1.T38 UC1.U29 UC1.U30 UC1.U31 UC1.U32 UC1.U33 UC1.U34 UC1.U35 UC1.U36 UC1.V13 UC1.V14 UC1.V31 UC1.V32 UC1.V33 UC1.V34 UC1.V35 UC1.V36 UC1.V37 UC1.V38 UC1.W13 UC1.W14 UC1.W29 UC1.W30 UC1.W31 UC1.W32 UC1.W35 UC1.W36 UC1.W37 UC1.W38 UC1.Y29 UC1.Y30 UC1.Y31 UC1.Y32 UC1.Y33 UC1.Y34 UC1.Y35 UC1.Y36
+VCCGT: PCG101.1 PCG102.1 PCG103.1 PCG104.1 PCG105.1 PCG106.1 PCG107.1 PCG108.1 PCG109.1 PCG110.1 PCG111.1 PCG112.1 PCG113.1 PCG114.1 PCG115.1 PCG116.1 PCG117.1 PCG118.1 PCG119.1 PCG120.1 PCG121.1 PCG122.1 PCG123.1 PCG124.1 PCG125.1 PCG126.1 PCG127.1 PCG128.1 PCG129.1 PCG130.1 PCG131.1 PCG132.1 PCG171.1 PCG172.1 PLG01.4 RC12.2 UC1.AT14 UC1.AT31 UC1.AT32 UC1.AT33 UC1.AT34 UC1.AT35 UC1.AT36 UC1.AT37 UC1.AT38 UC1.AU14 UC1.AU29 UC1.AU30 UC1.AU31 UC1.AU32 UC1.AU35 UC1.AU36 UC1.AU37 UC1.AU38 UC1.AV29 UC1.AV30 UC1.AV31 UC1.AV32 UC1.AV33 UC1.AV34 UC1.AV35 UC1.AV36 UC1.AW14 UC1.AW31 UC1.AW32 UC1.AW33 UC1.AW34 UC1.AW35 UC1.AW36 UC1.AW37 UC1.AW38 UC1.AY29 UC1.AY30 UC1.AY31 UC1.AY32 UC1.AY35 UC1.AY36 UC1.AY37 UC1.AY38 UC1.BA13 UC1.BA14 UC1.BA29 UC1.BA30 UC1.BA31 UC1.BA32 UC1.BA33 UC1.BA34 UC1.BA35 UC1.BA36 UC1.BB13 UC1.BB14 UC1.BB31 UC1.BB32 UC1.BB33 UC1.BB34 UC1.BB35 UC1.BB36 UC1.BB37 UC1.BB38 UC1.BC29 UC1.BC30 UC1.BC31 UC1.BC32 UC1.BC35 UC1.BC36 UC1.BC37 UC1.BC38 UC1.BD13 UC1.BD14 UC1.BD29 UC1.BD30 UC1.BD31 UC1.BD32 UC1.BD33 UC1.BD34 UC1.BD35 UC1.BD36 UC1.BE31 UC1.BE32 UC1.BE33 UC1.BE34 UC1.BE35 UC1.BE36 UC1.BE37 UC1.BE38 UC1.BF13 UC1.BF14 UC1.BF29 UC1.BF30 UC1.BF31 UC1.BF32 UC1.BF35 UC1.BF36 UC1.BF37 UC1.BF38 UC1.BG29 UC1.BG30 UC1.BG31 UC1.BG32 UC1.BG33 UC1.BG34 UC1.BG35 UC1.BG36 UC1.BH33 UC1.BH34 UC1.BH35 UC1.BH36 UC1.BH37 UC1.BH38 UC1.BJ16 UC1.BJ17 UC1.BJ19 UC1.BJ20 UC1.BJ21 UC1.BJ23 UC1.BJ24 UC1.BJ26 UC1.BJ27 UC1.BJ37 UC1.BJ38 UC1.BK16 UC1.BK17 UC1.BK19 UC1.BK20 UC1.BK21 UC1.BK23 UC1.BK24 UC1.BK26 UC1.BK27 UC1.BL15 UC1.BL16 UC1.BL17 UC1.BL23 UC1.BL24 UC1.BL25 UC1.BL26 UC1.BL27 UC1.BL28 UC1.BL36 UC1.BL37 UC1.BM15 UC1.BM16 UC1.BM17 UC1.BM36 UC1.BM37 UC1.BN15 UC1.BN16 UC1.BN17 UC1.BN36 UC1.BN37 UC1.BN38 UC1.BP15 UC1.BP16 UC1.BP17 UC1.BP37 UC1.BP38 UC1.BR15 UC1.BR16 UC1.BR17 UC1.BR37 UC1.BT15 UC1.BT16 UC1.BT17 UC1.BT37
+VCCIO: CC33.1 CC34.1 CC35.1 PJP902.2 RC1.2 RC9.1 RC271.2 UC1.AG12 UC1.G15 UC1.G17 UC1.G19 UC1.G21 UC1.H15 UC1.H16 UC1.H17 UC1.H19 UC1.H20 UC1.H21 UC1.H26 UC1.H27 UC1.J15 UC1.J16 UC1.J17 UC1.J19 UC1.J20 UC1.J21 UC1.J26 UC1.J27
+VCCIO_PG: PR901.2 PU901.9 RH103.1
+VCCIOP: PC912.1 PC913.1 PC914.1 PC915.1 PC916.1 PJP902.1 PL901.2 PR908.1
+VCCRTCEXT: CH25.1 UH1.BF47 UH1.BG47
+VCCSA: CC303.1 PCA101.1 PCA102.1 PCA103.1 PCA104.1 PCA105.1 PCA106.1 PCA107.1 PCA108.1 PCA109.1 PCA110.1 PCA111.1 PCA112.1 PCA113.1 PLA01.4 RC15.2 UC1.J30 UC1.K29 UC1.K30 UC1.K31 UC1.K32 UC1.K33 UC1.K34 UC1.K35 UC1.L31 UC1.L32 UC1.L35 UC1.L36 UC1.L37 UC1.L38 UC1.M29 UC1.M30 UC1.M31 UC1.M32 UC1.M33 UC1.M34 UC1.M35 UC1.M36
+VCCST: C151.1 CC38.1 CC39.1 CZ28.1 PCZ12.2 PRZ20.1 PRZ21.2 PRZ22.1 PRZ23.1 RC20.2 RC46.2 RC259.1 RC260.1 RC261.1 RC263.1 UC1.H28 UC1.H30 UC1.J28 UZ15.6
+VCCSTG: CC40.1 CZ47.1 RC76.2 RC77.2 RC78.2 RC262.1 RZ48.1 UC1.G30 UC1.H29
+VCCSTG_OUT: RZ48.2 UZ9.6
GND: C1.2 C2.2 C3.2 C4.2 C5.2 C12.2 C14.2 C15.2 C16.2 C17.2 C19.2 C21.2 C26.2 C27.2 C30.2 C31.2 C34.2 C37.1 C46.2 C47.2 C48.2 C49.2 C50.2 C51.2 C52.2 C53.2 C54.2 C55.2 C56.2 C59.2 C60.2 C61.2 C148.2 C149.2 C150.2 C151.2 CA1.2 CA2.2 CA3.2 CA4.2 CA5.1 CA6.2 CA9.2 CA13.1 CA14.2 CA15.2 CA16.2 CA22.1 CA25.2 CA27.2 CA28.2 CA29.2 CA30.2 CA38.1 CA40.2 CA43.2 CA44.2 CA45.2 CA46.2 CA47.2 CA48.2 CA49.2 CA50.2 CA51.2 CA52.2 CA53.2 CC17.2 CC18.2 CC19.2 CC20.2 CC21.2 CC22.2 CC23.2 CC24.2 CC25.2 CC26.2 CC27.2 CC28.2 CC29.2 CC30.2 CC31.2 CC32.2 CC33.2 CC34.2 CC35.2 CC36.2 CC37.2 CC38.2 CC39.2 CC40.2 CC41.2 CC42.2 CC43.2 CC57.1 CC148.2 CC298.2 CC299.2 CC300.2 CC301.2 CC302.2 CC303.2 CD1.2 CD2.2 CD3.2 CD4.2 CD5.2 CD6.2 CD7.2 CD9.2 CD10.2 CD11.2 CD12.2 CD13.2 CD14.2 CD15.2 CD16.2 CD17.2 CD18.2 CD19.2 CD20.2 CD21.2 CD22.2 CD23.2 CD24.2 CD25.2 CD26.2 CD27.2 CD28.2 CD29.2 CD31.2 CD32.2 CD33.2 CD34.2 CD35.2 CD36.2 CD37.2 CD39.2 CD40.2 CD41.2 CD42.2 CD43.2 CD44.2 CD45.2 CD46.2 CD47.2 CD48.2 CD49.2 CD50.2 CD51.2 CD52.2 CD53.2 CD54.2 CD55.2 CD56.2 CD58.2 CD60.2 CD61.2 CD62.2 CD63.2 CE3.2 CE4.2 CE5.2 CE6.2 CE7.1 CE8.1 CE9.2 CE10.2 CE11.2 CE12.2 CE13.2 CE14.2 CE15.2 CE16.2 CE17.2 CE19.2 CE20.2 CE22.2 CE23.2 CE24.2 CE26.2 CE28.2 CE31.2 CE32.1 CE33.2 CE34.1 CE35.1 CE36.2 CE37.2 CE38.2 CE39.2 CE99.2 CE100.2 CG47.2 CG48.2 CG64.2 CG65.2 CG246.2 CG288.2 CG289.2 CG290.2 CG310.2 CG320.2 CG386.2 CG438.2 CG440.2 CG442.2 CG482.2 CG487.2 CG527.2 CH12.2 CH13.2 CH14.2 CH15.2 CH16.2 CH17.2 CH18.2 CH19.2 CH20.2 CH21.2 CH22.2 CH23.2 CH24.2 CH25.2 CH29.2 CH30.2 CH31.2 CH32.2 CH33.2 CH34.2 CH35.2 CH36.2 CH45.2 CH46.2 CH47.2 CH48.2 CH49.2 CH51.1 CH52.2 CH53.2 CH62.2 CH63.2 CH197.2 CH201.2 CH209.2 CH210.2 CH211.2 CH212.2 CH222.2 CH223.2 CH224.1 CH225.2 CH226.2 CH228.2 CL5.2 CL6.2 CL7.2 CL8.2 CL9.2 CL10.2 CL11.2 CL12.2 CL13.2 CL15.2 CL18.2 CL19.2 CL20.2 CL22.2 CL23.2 CL24.2 CL25.2 CLIP1.1(TP-1) CLIP2.1(TP-1) CLRP1.2 CP3.2 CP4.2 CP5.2 CP6.2 CP7.2 CP8.2 CP9.2 CP10.2 CP11.2 CP12.2 CP13.2 CP14.2 CP24.2 CP25.2 CP26.2 CP27.2 CP28.2 CP29.2 CP32.2 CS5.2 CS6.2 CS7.2 CS8.2 CS24.2 CS25.2 CS26.2 CS27.2 CS29.2 CS30.2 CS32.2 CS33.2 CS34.2 CS35.2 CS36.2 CT37.2 CT38.2 CT45.2 CT46.2 CT47.2 CT48.2 CT49.2 CT50.2 CT51.2 CT52.2 CT53.2 CT54.2 CT55.2 CT56.2 CT57.2 CT58.2 CT59.2 CT60.2 CT61.2 CT62.2 CT63.2 CT64.2 CT65.2 CT66.2 CT67.2 CT68.2 CT69.2 CT70.2 CT71.2 CT72.2 CT73.2 CT74.2 CT75.2 CT77.2 CT78.2 CT79.2 CT80.2 CT81.2 CT82.2 CT83.2 CT84.2 CT85.2 CT86.2 CT88.2 CT90.2 CT91.2 CT92.2 CT93.2 CT94.2 CT95.2 CT96.1 CT97.1 CT98.2 CT99.2 CT100.2 CT101.2 CT102.2 CT103.2 CT104.2 CT106.2 CT112.2 CT113.2 CT137.2 CT153.2 CT154.2 CT155.2 CT156.1 CT157.1 CTPM1.2 CTPM2.2 CTPM3.2 CTPM4.2 CTPM5.2 CTPM6.2 CTPM7.2 CU5.2 CU6.2 CU7.2 CU8.2 CU9.2 CU10.2 CU11.2 CU12.2 CU13.2 CU14.2 CU15.2 CU16.2 CU17.2 CU19.2 CU20.2 CU21.2 CU22.2 CV50.2 CV51.2 CV52.2 CV53.2 CV70.1 CV71.1 CV72.2 CV79.1 CV80.1 CV83.2 CV84.2 CV85.2 CV86.2 CV87.2 CV88.2 CV89.2 CV90.2 CV91.2 CV92.2 CV93.1 CV94.1 CV95.1 CV96.2 CV97.2 CV100.2 CV101.2 CV102.2 CV103.2 CV112.2 CV113.2 CV114.2 CV117.2 CV118.2 CV119.2 CV120.2 CV152.2 CV153.2 CV154.2 CV156.2 CV158.2 CV160.2 CV161.2 CV162.2 CV163.2 CV164.2 CV165.2 CV166.2 CV167.2 CV168.2 CV169.2 CV170.2 CV171.2 CV172.2 CV173.2 CV174.2 CV175.2 CV177.2 CV179.2 CV180.2 CV181.2 CV182.2 CV183.2 CV184.2 CV185.2 CV186.2 CV187.2 CV188.2 CV189.2 CV190.2 CV191.2 CV192.2 CV193.2 CV194.2 CV199.2 CV200.2 CV202.2 CV206.2 CV207.2 CV208.2 CV209.2 CV210.2 CV211.2 CV212.2 CV213.2 CV214.2 CV373.2 CV374.2 CV375.2 CV376.2 CV377.2 CV378.2 CV379.2 CV380.2 CV381.2 CV382.2 CV383.2 CV384.2 CV385.2 CV386.2 CV387.2 CV388.2 CV389.2 CV390.2 CV391.2 CV392.2 CV393.2 CV394.2 CV395.2 CV396.2 CV397.2 CV398.2 CV399.2 CV400.2 CV401.2 CV402.2 CV403.2 CV404.2 CV529.2 CV530.2 CV597.2 CV598.2 CV599.1 CV600.1 CV601.1 CV833.2 CV834.2 CV835.2 CV836.2 CV837.2 CV838.2 CV839.2 CV840.2 CV841.1 CV842.1 CV843.2 CV844.1 CV845.1 CV851.2 CV852.2 CV853.2 CV854.2 CV855.2 CV856.2 CV857.2 CV858.2 CV859.2 CV860.2 CV861.2 CV862.2 CV863.2 CV864.2 CV865.2 CV866.2 CV867.2 CV868.2 CV869.2 CV870.2 CV871.2 CV872.2 CV873.2 CV874.2 CV875.2 CV876.2 CV877.2 CV878.2 CV879.2 CV880.2 CV881.2 CV882.2 CV883.2 CV884.2 CV885.2 CV886.2 CV887.2 CV888.2 CV889.2 CV890.2 CV891.2 CV892.2 CV893.2 CV894.2 CV895.2 CV896.2 CV897.2 CV898.2 CV899.2 CV900.2 CV901.2 CV902.2 CV903.2 CV904.2 CV905.2 CV906.2 CV937.2 CV938.2 CV939.2 CV940.2 CV941.2 CV942.2 CV943.1 CV944.1 CV945.2 CV946.2 CV947.2 CW3.2 CW4.2 CW5.2 CW6.2 CW7.2 CW8.2 CW9.2 CX2.2 CZ9.2 CZ10.2 CZ11.2 CZ12.2 CZ23.2 CZ25.2 CZ28.2 CZ32.2 CZ33.1 CZ37.2 CZ40.2 CZ46.1 CZ47.2 CZ49.2 CZ50.2 CZ51.2 CZ57.2 CZ86.2 CZ88.2 CZ96.2 CZ97.2 CZ102.2 CZ108.2 CZ109.2 CZ110.2 CZ111.2 DA1.1 DA2.1 DA4.1 DA5.1 DA6.1 DA7.1 DC1.1 DE1.2 DF1.1 DT2.2 DT3.2 DT4.2 DT5.2 DT6.2 DT7.2 DT8.2 DT9.2 DT10.3 DT11.3 DT16.1 DU1.3 DU2.1 DU3.3 DU4.1 H1.1(TP-1) H2.1(TP-1) H4.1(TP-1) H5.1(TP-1) H6.1(TP-1) H7.1(TP-1) H8.1(TP-1) H9.1(TP-1) H10.1(TP-1) H11.1(TP-1) H12.1(TP-1) H13.1(TP-1) H15.1(TP-1) H16.1(TP-1) HCPU1.1(TP-1) HCPU2.1(TP-1) HCPU3.1(TP-1) HCPU4.1(TP-1) HGPU2.1(TP-1) HGPU3.1(TP-1) HGPU4.1(TP-1) JDEG1.10 JDEG1.11 JDEG1.12 JDIMM1.1 JDIMM1.2 JDIMM1.5 JDIMM1.6 JDIMM1.9 JDIMM1.10 JDIMM1.14 JDIMM1.15 JDIMM1.18 JDIMM1.19 JDIMM1.22 JDIMM1.23 JDIMM1.26 JDIMM1.27 JDIMM1.30 JDIMM1.31 JDIMM1.35 JDIMM1.36 JDIMM1.39 JDIMM1.40 JDIMM1.43 JDIMM1.44 JDIMM1.47 JDIMM1.48 JDIMM1.51 JDIMM1.52 JDIMM1.56 JDIMM1.57 JDIMM1.60 JDIMM1.61 JDIMM1.64 JDIMM1.65 JDIMM1.68 JDIMM1.69 JDIMM1.72 JDIMM1.73 JDIMM1.77 JDIMM1.78 JDIMM1.81 JDIMM1.82 JDIMM1.85 JDIMM1.86 JDIMM1.89 JDIMM1.90 JDIMM1.93 JDIMM1.94 JDIMM1.98 JDIMM1.99 JDIMM1.102 JDIMM1.103 JDIMM1.106 JDIMM1.107 JDIMM1.167 JDIMM1.168 JDIMM1.171 JDIMM1.172 JDIMM1.175 JDIMM1.176 JDIMM1.180 JDIMM1.181 JDIMM1.184 JDIMM1.185 JDIMM1.188 JDIMM1.189 JDIMM1.192 JDIMM1.193 JDIMM1.196 JDIMM1.197 JDIMM1.201 JDIMM1.202 JDIMM1.205 JDIMM1.206 JDIMM1.209 JDIMM1.210 JDIMM1.213 JDIMM1.214 JDIMM1.217 JDIMM1.218 JDIMM1.222 JDIMM1.223 JDIMM1.226 JDIMM1.227 JDIMM1.230 JDIMM1.231 JDIMM1.234 JDIMM1.235 JDIMM1.238 JDIMM1.239 JDIMM1.243 JDIMM1.244 JDIMM1.247 JDIMM1.248 JDIMM1.251 JDIMM1.252 JDIMM1.261 JDIMM1.262 JDIMM2.1 JDIMM2.2 JDIMM2.5 JDIMM2.6 JDIMM2.9 JDIMM2.10 JDIMM2.14 JDIMM2.15 JDIMM2.18 JDIMM2.19 JDIMM2.22 JDIMM2.23 JDIMM2.26 JDIMM2.27 JDIMM2.30 JDIMM2.31 JDIMM2.35 JDIMM2.36 JDIMM2.39 JDIMM2.40 JDIMM2.43 JDIMM2.44 JDIMM2.47 JDIMM2.48 JDIMM2.51 JDIMM2.52 JDIMM2.56 JDIMM2.57 JDIMM2.60 JDIMM2.61 JDIMM2.64 JDIMM2.65 JDIMM2.68 JDIMM2.69 JDIMM2.72 JDIMM2.73 JDIMM2.77 JDIMM2.78 JDIMM2.81 JDIMM2.82 JDIMM2.85 JDIMM2.86 JDIMM2.89 JDIMM2.90 JDIMM2.93 JDIMM2.94 JDIMM2.98 JDIMM2.99 JDIMM2.102 JDIMM2.103 JDIMM2.106 JDIMM2.107 JDIMM2.167 JDIMM2.168 JDIMM2.171 JDIMM2.172 JDIMM2.175 JDIMM2.176 JDIMM2.180 JDIMM2.181 JDIMM2.184 JDIMM2.185 JDIMM2.188 JDIMM2.189 JDIMM2.192 JDIMM2.193 JDIMM2.196 JDIMM2.197 JDIMM2.201 JDIMM2.202 JDIMM2.205 JDIMM2.206 JDIMM2.209 JDIMM2.210 JDIMM2.213 JDIMM2.214 JDIMM2.217 JDIMM2.218 JDIMM2.222 JDIMM2.223 JDIMM2.226 JDIMM2.227 JDIMM2.230 JDIMM2.231 JDIMM2.234 JDIMM2.235 JDIMM2.238 JDIMM2.239 JDIMM2.243 JDIMM2.244 JDIMM2.247 JDIMM2.248 JDIMM2.251 JDIMM2.252 JDIMM2.261 JDIMM2.262 JEDP1.13 JEDP1.17 JEDP1.20 JEDP1.23 JEDP1.24 JEDP1.25 JEDP1.32 JEDP1.35 JEDP1.38 JEDP1.41 JEDP1.42 JESPI1.9 JESPI1.11 JESPI1.12 JFAN1.1 JFAN1.5 JFAN1.6 JFAN2.1 JFAN2.5 JFAN2.6 JFP.1 JFP.3 JFP.4 JFP.9 JFP.10 JHDD.1 JHDD.4 JHDD.7 JHDD.13 JHDD.14 JHDMI1.2 JHDMI1.5 JHDMI1.8 JHDMI1.11 JHDMI1.17 JHDMI1.20 JHDMI1.21 JHDMI1.22 JHDMI1.23 JIOB1.1 JIOB1.2 JIOB1.5 JIOB1.8 JIOB1.10 JIOB1.19 JIOB1.20 JKB.30 JKB.31 JKB.32 JKBBL.5 JKBBL.6 JLAN1.9 JLAN1.10 JLAN1.11 JLAN1.12 JSPK1.5 JSPK1.6 JSSD1.1 JSSD1.3 JSSD1.9 JSSD1.15 JSSD1.21 JSSD1.27 JSSD1.33 JSSD1.39 JSSD1.45 JSSD1.51 JSSD1.57 JSSD1.71 JSSD1.73 JSSD1.75 JSSD1.76 JSSD1.77 JTP.5 JTP.9 JTP.10 JUSB1.4 JUSB1.7 JUSB1.10 JUSB1.11 JUSB1.12 JUSB1.13 JUSB2.4 JUSB2.7 JUSB2.10 JUSB2.11 JUSB2.12 JUSB2.13 JUSBC1.1 JUSBC1.2 JUSBC1.3 JUSBC1.4 JUSBC1.5 JUSBC1.6 JUSBC1.A1 JUSBC1.A12 JUSBC1.B1 JUSBC1.B12 JWLAN1.1 JWLAN1.7 JWLAN1.13 JWLAN1.18 JWLAN1.19 JWLAN1.33 JWLAN1.39 JWLAN1.45 JWLAN1.51 JWLAN1.57 JWLAN1.63 JWLAN1.69 JWLAN1.75 JWLAN1.76 JWLAN1.77 LED1.1 LED1.3 PBATT1.1 PBATT1.2 PBATT1.3 PBATT1.4 PBATT1.11 PBATT1.12 PC1.2 PC2.2 PC3.2 PC4.2 PC7.2 PC8.2 PC9.2 PC10.2 PC11.2 PC12.2 PC22.2 PC23.2 PC301.2 PC302.2 PC303.2 PC304.2 PC305.2 PC306.2 PC308.2 PC309.2 PC310.2 PC311.2 PC312.2 PC313.2 PC314.2 PC501.2 PC502.2 PC503.2 PC504.2 PC505.2 PC506.2 PC508.2 PC509.2 PC510.2 PC511.2 PC512.2 PC513.2 PC514.2 PC515.2 PC516.2 PC518.2 PC901.2 PC902.2 PC903.2 PC904.2 PC905.2 PC906.2 PC908.2 PC909.2 PC910.2 PC911.2 PC913.2 PC914.2 PC915.2 PC916.2 PC1001.2 PC1002.1 PC1004.2 PC1005.2 PC1006.2 PC1007.2 PC1008.2 PC1801.2 PC1802.2 PC1803.2 PC1804.2 PC1805.2 PC1806.2 PC2501.2 PC2502.2 PC2503.2 PC2504.2 PCA01.2 PCA02.2 PCA03.2 PCA04.2 PCA05.2 PCA06.2 PCA07.1 PCA08.2 PCA10.2 PCA11.2 PCA12.2 PCA101.2 PCA102.2 PCA103.2 PCA104.2 PCA105.2 PCA106.2 PCA107.2 PCA108.2 PCA109.2 PCA110.2 PCA111.2 PCA112.2 PCA113.2 PCB01.2 PCB02.2 PCB03.2 PCB04.2 PCB05.2 PCB06.2 PCB07.2 PCB10.2 PCB11.2 PCB12.2 PCB13.2 PCB14.2 PCB15.2 PCB16.2 PCB17.2 PCB19.2 PCB20.2 PCB21.2 PCB22.2 PCB23.2 PCB24.2 PCB26.2 PCB27.2 PCB28.2 PCB29.2 PCB31.2 PCB32.2 PCB33.2 PCB34.2 PCB35.2 PCB36.2 PCB37.2 PCB38.2 PCB39.2 PCB40.2 PCB42.2 PCB43.2 PCB44.1 PCB45.2 PCB53.2 PCB54.2 PCB56.2 PCG01.2 PCG02.2 PCG03.2 PCG04.2 PCG05.2 PCG06.2 PCG07.1 PCG08.2 PCG10.2 PCG11.2 PCG12.2 PCG101.2 PCG102.2 PCG103.2 PCG104.2 PCG105.2 PCG106.2 PCG107.2 PCG108.2 PCG109.2 PCG110.2 PCG111.2 PCG112.2 PCG113.2 PCG114.2 PCG115.2 PCG116.2 PCG117.2 PCG118.2 PCG119.2 PCG120.2 PCG121.2 PCG122.2 PCG123.2 PCG124.2 PCG125.2 PCG126.2 PCG127.2 PCG128.2 PCG129.2 PCG130.2 PCG131.2 PCG132.2 PCG171.2 PCG172.2 PCH01.2 PCH02.2 PCH03.2 PCH04.2 PCH06.2 PCH07.2 PCH09.2 PCH10.2 PCH12.2 PCH13.2 PCH14.2 PCI03.2 PCI04.2 PCI05.2 PCI06.2 PCI07.2 PCI08.2 PCI09.2 PCI10.2 PCI11.2 PCI12.2 PCI13.2 PCI14.1 PCI15.2 PCI17.2 PCI18.2 PCI19.2 PCI20.2 PCI21.2 PCI22.2 PCI23.2 PCI24.1 PCI25.2 PCI27.2 PCI28.2 PCI29.2 PCI30.2 PCI31.2 PCI32.2 PCI33.2 PCI34.1 PCI35.2 PCI37.2 PCI38.2 PCI39.2 PCI40.2 PCI41.2 PCI42.2 PCI43.2 PCI44.1 PCI45.2 PCI47.2 PCI48.2 PCI49.2 PCI50.2 PCI51.2 PCI52.2 PCI53.2 PCI101.2 PCI102.2 PCI103.2 PCI104.2 PCI105.2 PCI106.2 PCI107.2 PCI108.2 PCI109.2 PCI110.2 PCI111.2 PCI112.2 PCI113.2 PCI114.2 PCI115.2 PCI116.2 PCI117.2 PCI118.2 PCI119.2 PCI120.2 PCI121.2 PCI122.2 PCI123.2 PCI124.2 PCI125.2 PCI126.2 PCI127.2 PCI128.2 PCI129.2 PCI130.2 PCI131.2 PCI132.2 PCI133.2 PCI134.2 PCI135.2 PCI136.2 PCI137.2 PCI138.2 PCI139.2 PCI140.2 PCI141.2 PCI142.2 PCI143.2 PCI144.2 PCI145.2 PCI146.2 PCI147.2 PCI148.2 PCI149.2 PCI150.2 PCI151.2 PCI152.2 PCI153.2 PCI154.2 PCI155.2 PCI156.2 PCI157.2 PCI158.2 PCI159.2 PCI160.2 PCI161.2 PCI162.2 PCI163.2 PCI164.2 PCI165.2 PCI171.2 PCI172.2 PCI173.2 PCM01.2 PCM02.2 PCM03.2 PCM04.2 PCM05.2 PCM06.2 PCM07.2 PCM08.2 PCM09.2 PCM10.2 PCM11.2 PCM13.2 PCM14.2 PCM15.2 PCM16.2 PCM18.2 PCM19.2 PCM20.2 PCM21.2 PCM22.2 PCM23.2 PCS01.1 PCS02.2 PCS03.2 PCS04.2 PCS05.2 PCS06.2 PCS07.2 PCS08.2 PCS11.2 PCS12.2 PCS13.2 PCS14.2 PCS15.2 PCS16.2 PCS22.2 PCS23.2 PCV01.2 PCV03.1 PCV06.1 PCV08.1 PCV09.2 PCV10.2 PCV11.1 PCV17.2 PCV18.2 PCV19.2 PCV20.2 PCV21.2 PCV22.2 PCV23.2 PCV24.2 PCV26.1 PCV28.2 PCV29.2 PCV30.2 PCV31.2 PCV32.2 PCV33.2 PCV34.2 PCV35.2 PCV36.1 PCV38.2 PCV39.2 PCV40.2 PCV41.2 PCV42.2 PCV43.2 PCV44.2 PCV45.2 PCV46.1 PCV48.2 PCV49.2 PCV50.2 PCV54.2 PCV55.2 PCV56.2 PCV57.2 PCV101.2 PCV102.2 PCV103.2 PCV104.2 PCV105.2 PCV106.2 PCV107.2 PCV108.2 PCV109.2 PCV110.2 PCV111.2 PCV112.2 PCV113.2 PCV114.2 PCV115.2 PCV116.2 PCV117.2 PCV118.2 PCV119.2 PCV120.2 PCV121.2 PCV122.2 PCV123.2 PCV124.2 PCV125.2 PCV126.2 PCV127.2 PCV128.2 PCV129.2 PCV130.2 PCV131.2 PCV132.2 PCV133.2 PCV134.2 PCV135.2 PCV136.2 PCV137.2 PCV138.2 PCV139.2 PCV140.2 PCV171.2 PCV172.2 PCV173.2 PCV201.2 PCV202.2 PCV203.2 PCV204.2 PCV205.2 PCV206.2 PCV207.2 PCV208.2 PCV209.2 PCV210.2 PCV211.2 PCV212.2 PCV213.2 PCV214.2 PCV215.2 PCV216.2 PCV217.2 PCV271.2 PCV272.2 PCW01.2 PCW02.2 PCW03.2 PCW04.2 PCW05.2 PCW06.2 PCW07.2 PCW08.2 PCW09.2 PCW10.1 PCW12.2 PCW13.2 PCW14.1 PCW15.1 PCW17.2 PCW18.2 PCW19.2 PCZ08.1 PCZ09.1 PCZ11.1 PCZ12.1 PCZ16.2 PCZ19.1 PCZ22.2 PCZ26.2 PCZ29.2 PCZ30.1 PCZ31.2 PCZ32.2 PCZ38.2 PD1.1 PD2.2 PD3.2 PD5.1 PD6.1 PD12.2 PD13.1 PD14.1 PHZ03.2 PHZ04.2 PJPDC1.2 PJPDC1.3 PJPDC1.4 PJPDC1.5 PQ2.3 PQ5.3 PQ6.3 PQ11.3 PQ12.1 PQ12.4 PQ13.1 PQ13.4 PQ15.3 PQ16.3 PQ17.3 PQ18.3 PQ20.3 PQ21.3 PQB01.3 PQB01.4 PQB01.5 PQB02.3 PQB02.4 PQB02.5 PQB04.3 PQB05.3 PQB07.3 PQB07.4 PQB07.5 PQB10.3 PQH01.3 PQH01.4 PQH01.5 PQM01.5 PQM01.6 PQM01.7 PQS03.3 PQS04.3 PQS05.1 PQS05.4 PQS07.3 PQS08.3 PQS10.1 PQS10.4 PQS11.3 PQS12.3 PQS19.3 PQS21.3 PQS22.1 PQS22.4 PQW01.3 PQW01.4 PQW01.5 PR6.2 PR15.2 PR16.2 PR17.2 PR38.2 PR40.2 PR43.2 PR44.1 PR45.2 PR63.2 PR64.2 PR100.2 PR303.2 PR308.2 PR508.2 PR511.2 PR904.2 PR906.1 PR910.2 PR912.1 PR1004.2 PR1007.2 PR1802.2 PR1805.2 PR2503.2 PRB07.2 PRB10.2 PRB20.2 PRB23.2 PRB24.2 PRB26.2 PRB29.1 PRB33.2 PRB50.1 PRB51.2 PRB57.2 PRH03.1 PRH05.2 PRH13.2 PRM11.2 PRS05.2 PRS06.2 PRS07.2 PRS14.2 PRS25.2 PRS27.1 PRS29.2 PRS30.2 PRS48.2 PRS51.2 PRV03.1 PRV07.1 PRV18.2 PRV24.2 PRV25.2 PRV26.2 PRV29.1 PRV30.1 PRV31.1 PRV32.1 PRV33.1 PRV34.1 PRV35.1 PRV38.1 PRW08.2 PRW15.1 PRW16.2 PRW17.2 PRZ14.1 PRZ15.2 PRZ16.2 PRZ18.2 PRZ31.2 PRZ44.2 PRZ54.2 PRZ55.2 PRZ56.2 PRZ57.2 PRZ58.2 PRZ59.2 PRZ67.2 PRZ69.2 PRZ72.2 PU01.2 PU301.7 PU301.8 PU301.18 PU301.21 PU501.7 PU501.8 PU501.18 PU501.21 PU901.7 PU901.8 PU901.18 PU901.21 PU1001.11 PU1801.11 PU2501.8 PU2501.9 PUA01.2 PUA01.4 PUA01.10 PUA01.14 PUA01.18 PUB01.33 PUB02.3 PUG01.4 PUG01.10 PUG01.14 PUG01.18 PUH01.11 PUI01.4 PUI01.10 PUI01.14 PUI01.18 PUI02.4 PUI02.10 PUI02.14 PUI02.18 PUI03.4 PUI03.10 PUI03.14 PUI03.18 PUI04.4 PUI04.10 PUI04.14 PUI04.18 PUM01.1 PUM01.3 PUM01.14 PUM01.21 PUS01.4 PUS02.3 PUS03.3 PUS04.2 PUV01.4 PUV01.10 PUV01.14 PUV01.18 PUV02.4 PUV02.10 PUV02.14 PUV02.18 PUV03.4 PUV03.10 PUV03.14 PUV03.18 PUV101.41 PUW01.10 PUW01.21 PUZ01.53 Q1.3 Q8.3 Q13.3 Q25.3 Q27.1 Q27.4 QG10.3 QG23.1 QG23.4 QG502.1 QG503.1 QG503.4 QG504.1 QG504.4 QG505.1 QG505.4 QG506.1 QG506.4 QH7.3 QH8.1 QH8.4 QH9.1 QH9.4 QH10.1 QH10.4 QS1.1 QS1.4 QV10.1 QV10.4 QV20.3 QV21.3 R2.2 R10.2 R27.2 R40.2 R45.2 R79.1 RA9.1 RA17.2 RA18.2 RA22.2 RA24.2 RC3.1 RC4.1 RC5.1 RC6.1 RC7.1 RC11.2 RC13.2 RC16.2 RC19.2 RC83.2 RC84.2 RC85.2 RC144.2 RC145.2 RC224.2 RC253.2 RC254.2 RC255.2 RC256.2 RC257.2 RC258.2 RC274.2 RD4.2 RD5.2 RD6.2 RD11.2 RD12.2 RD16.2 RD17.2 RD18.2 RD21.2 RD22.2 RE16.2 RE19.2 RE32.2 RE48.2 RE50.1 RE53.1 RE62.2 RE68.2 RE157.2 RE168.2 RG37.2 RG557.2 RG573.2 RH14.1 RH20.1 RH24.2 RH30.2 RH90.1 RH94.2 RH109.2 RH135.1 RH199.2 RH455.1 RH552.2 RH554.2 RH562.2 RH580.2 RH581.2 RH589.2 RH666.2 RH667.2 RH668.2 RH670.2 RH673.1 RH679.2 RH681.2 RH700.1 RH705.2 RH716.2 RH738.2 RH739.2 RH740.2 RH741.2 RH742.2 RH743.2 RH746.2 RH749.2 RL2.1 RL4.2 RL6.1 RP1.1 RP1.2 RP1.3 RP31.2 RP32.2 RP39.1 RP40.1 RP41.1 RP42.1 RP43.1 RP44.1 RPT1.1 RPT1.2 RPT1.3 RPT1.4 RT3.2 RT4.2 RT5.2 RT11.2 RT17.2 RT18.2 RT19.2 RT24.2 RT34.2 RT35.2 RT36.2 RT37.2 RT40.2 RT42.2 RT43.2 RT44.2 RT45.2 RT46.2 RT47.2 RT62.2 RT63.2 RT64.2 RT65.2 RT68.2 RT69.2 RT71.2 RT72.2 RT73.2 RT75.2 RT78.2 RT80.2 RT83.1 RT108.2 RT111.2 RT113.2 RT129.2 RT163.2 RTPM4.2 RV27.2 RV37.2 RV49.2 RV50.1 RV51.2 RV58.1 RV62.2 RV63.2 RV66.1 RV78.1 RV79.1 RV107.2 RV108.2 RV110.2 RV111.2 RV116.2 RV120.2 RV121.2 RV127.2 RV132.2 RV135.2 RV136.2 RV142.2 RV152.1 RV153.1 RV154.1 RV155.1 RV156.1 RV160.1 RV161.1 RV162.1 RV573.2 RW4.2 RW29.2 RW30.2 RX8.2 RZ71.2 SW1.2 U1.2 U2.5 U3.2 UA1.41 UC1.A3 UC1.A4 UC1.A6 UC1.A9 UC1.A10 UC1.A12 UC1.A14 UC1.A16 UC1.A18 UC1.A20 UC1.A22 UC1.A24 UC1.A26 UC1.A28 UC1.A30 UC1.A34 UC1.AA12 UC1.AA29 UC1.AA30 UC1.AB6 UC1.AB33 UC1.AB34 UC1.AC1 UC1.AC2 UC1.AC3 UC1.AC4 UC1.AC5 UC1.AC6 UC1.AC12 UC1.AC37 UC1.AC38 UC1.AD6 UC1.AD7 UC1.AD8 UC1.AD9 UC1.AD10 UC1.AD11 UC1.AD12 UC1.AD29 UC1.AD30 UC1.AE6 UC1.AE33 UC1.AE34 UC1.AF1 UC1.AF2 UC1.AF3 UC1.AF4 UC1.AF12 UC1.AF13 UC1.AF14 UC1.AG6 UC1.AG7 UC1.AG8 UC1.AG10 UC1.AG11 UC1.AG13 UC1.AG29 UC1.AG30 UC1.AH6 UC1.AH12 UC1.AH33 UC1.AH34 UC1.AH35 UC1.AH36 UC1.AJ1 UC1.AJ2 UC1.AJ3 UC1.AJ4 UC1.AJ5 UC1.AJ6 UC1.AJ13 UC1.AJ37 UC1.AJ38 UC1.AK4 UC1.AK29 UC1.AK30 UC1.AL4 UC1.AL7 UC1.AL8 UC1.AL9 UC1.AL10 UC1.AL12 UC1.AL14 UC1.AL33 UC1.AL34 UC1.AM1 UC1.AM2 UC1.AM3 UC1.AM4 UC1.AM5 UC1.AM12 UC1.AM37 UC1.AM38 UC1.AN5 UC1.AN6 UC1.AN12 UC1.AN29 UC1.AN30 UC1.AP8 UC1.AP9 UC1.AP10 UC1.AP11 UC1.AP12 UC1.AP33 UC1.AP34 UC1.AR1 UC1.AR2 UC1.AR3 UC1.AR4 UC1.AR5 UC1.AR13 UC1.AR14 UC1.AR29 UC1.AR30 UC1.AR31 UC1.AR32 UC1.AR33 UC1.AR34 UC1.AR35 UC1.AR36 UC1.AR37 UC1.AR38 UC1.AT6 UC1.AT29 UC1.AT30 UC1.AU6 UC1.AU7 UC1.AU8 UC1.AU9 UC1.AU10 UC1.AU11 UC1.AU12 UC1.AU33 UC1.AU34 UC1.AV37 UC1.AV38 UC1.AW1 UC1.AW2 UC1.AW3 UC1.AW4 UC1.AW5 UC1.AW12 UC1.AW29 UC1.AW30 UC1.AY12 UC1.AY14 UC1.AY33 UC1.AY34 UC1.B3 UC1.B9 UC1.B37 UC1.BA6 UC1.BA7 UC1.BA8 UC1.BA9 UC1.BA10 UC1.BA11 UC1.BA12 UC1.BA37 UC1.BA38 UC1.BB1 UC1.BB2 UC1.BB3 UC1.BB4 UC1.BB5 UC1.BB6 UC1.BB12 UC1.BB29 UC1.BB30 UC1.BC6 UC1.BC12 UC1.BC13 UC1.BC14 UC1.BC33 UC1.BC34 UC1.BD6 UC1.BD7 UC1.BD8 UC1.BD9 UC1.BD10 UC1.BD11 UC1.BD12 UC1.BD37 UC1.BD38 UC1.BE1 UC1.BE2 UC1.BE3 UC1.BE4 UC1.BE5 UC1.BE6 UC1.BE29 UC1.BE30 UC1.BF6 UC1.BF12 UC1.BF33 UC1.BF34 UC1.BG6 UC1.BG12 UC1.BG13 UC1.BG14 UC1.BG37 UC1.BG38 UC1.BH1 UC1.BH2 UC1.BH3 UC1.BH4 UC1.BH5 UC1.BH6 UC1.BH7 UC1.BH8 UC1.BH9 UC1.BH10 UC1.BH11 UC1.BH12 UC1.BH14 UC1.BJ12 UC1.BJ14 UC1.BJ15 UC1.BJ18 UC1.BJ22 UC1.BJ25 UC1.BJ29 UC1.BJ30 UC1.BJ31 UC1.BJ32 UC1.BJ33 UC1.BJ34 UC1.BJ35 UC1.BJ36 UC1.BK6 UC1.BK13 UC1.BK14 UC1.BK15 UC1.BK18 UC1.BK22 UC1.BK25 UC1.BK29 UC1.BL6 UC1.BL13 UC1.BL14 UC1.BL18 UC1.BL19 UC1.BL20 UC1.BL21 UC1.BL22 UC1.BL29 UC1.BL33 UC1.BL35 UC1.BL38 UC1.BM2 UC1.BM3 UC1.BM5 UC1.BM6 UC1.BM7 UC1.BM8 UC1.BM9 UC1.BM11 UC1.BM12 UC1.BM13 UC1.BM14 UC1.BM18 UC1.BM21 UC1.BM22 UC1.BM23 UC1.BM24 UC1.BM25 UC1.BM26 UC1.BM27 UC1.BM28 UC1.BM29 UC1.BM33 UC1.BM35 UC1.BM38 UC1.BN2 UC1.BN4 UC1.BN7 UC1.BN12 UC1.BN14 UC1.BN18 UC1.BN19 UC1.BN20 UC1.BN21 UC1.BN24 UC1.BN29 UC1.BN30 UC1.BN31 UC1.BN34 UC1.BP7 UC1.BP12 UC1.BP14 UC1.BP18 UC1.BP21 UC1.BP24 UC1.BP25 UC1.BP26 UC1.BP29 UC1.BP33 UC1.BP34 UC1.BR7 UC1.BR9 UC1.BR12 UC1.BR14 UC1.BR18 UC1.BR21 UC1.BR24 UC1.BR25 UC1.BR26 UC1.BR29 UC1.BR34 UC1.BR36 UC1.BR38 UC1.BT3 UC1.BT4 UC1.BT5 UC1.BT8 UC1.BT12 UC1.BT14 UC1.BT18 UC1.BT21 UC1.BT24 UC1.BT26 UC1.BT29 UC1.BT32 UC1.BT35 UC1.BT36 UC1.C2 UC1.C5 UC1.C8 UC1.C9 UC1.C11 UC1.C13 UC1.C15 UC1.C17 UC1.C19 UC1.C21 UC1.C23 UC1.C25 UC1.C27 UC1.C29 UC1.C31 UC1.C37 UC1.D3 UC1.D6 UC1.D9 UC1.D10 UC1.D12 UC1.D14 UC1.D16 UC1.D18 UC1.D20 UC1.D22 UC1.D24 UC1.D26 UC1.D28 UC1.D30 UC1.D33 UC1.D38 UC1.E4 UC1.E9 UC1.E34 UC1.E35 UC1.E38 UC1.F2 UC1.F3 UC1.F4 UC1.F5 UC1.F8 UC1.F9 UC1.F11 UC1.F13 UC1.F15 UC1.F17 UC1.F19 UC1.F21 UC1.F23 UC1.F25 UC1.F27 UC1.F29 UC1.F31 UC1.F36 UC1.G4 UC1.G5 UC1.G6 UC1.G8 UC1.G9 UC1.G10 UC1.G12 UC1.G14 UC1.G16 UC1.G18 UC1.G20 UC1.G22 UC1.G23 UC1.G24 UC1.G26 UC1.G28 UC1.H11 UC1.H12 UC1.H18 UC1.H22 UC1.H25 UC1.H32 UC1.H35 UC1.J4 UC1.J7 UC1.J10 UC1.J18 UC1.J22 UC1.J25 UC1.J32 UC1.J33 UC1.J36 UC1.K1 UC1.K2 UC1.K3 UC1.K4 UC1.K5 UC1.K7 UC1.K8 UC1.K9 UC1.K10 UC1.K11 UC1.K38 UC1.L29 UC1.L30 UC1.L33 UC1.L34 UC1.M6 UC1.M12 UC1.M13 UC1.M14 UC1.N1 UC1.N2 UC1.N3 UC1.N4 UC1.N5 UC1.N6 UC1.N7 UC1.N8 UC1.N9 UC1.N10 UC1.N11 UC1.N12 UC1.N33 UC1.N34 UC1.P6 UC1.P12 UC1.P37 UC1.P38 UC1.R12 UC1.R29 UC1.R30 UC1.T1 UC1.T2 UC1.T3 UC1.T4 UC1.T5 UC1.T7 UC1.T8 UC1.T9 UC1.T10 UC1.T11 UC1.T12 UC1.T13 UC1.T14 UC1.T33 UC1.T34 UC1.U6 UC1.U37 UC1.U38 UC1.V6 UC1.V12 UC1.V29 UC1.V30 UC1.W1 UC1.W2 UC1.W3 UC1.W4 UC1.W5 UC1.W12 UC1.W33 UC1.W34 UC1.Y7 UC1.Y8 UC1.Y9 UC1.Y10 UC1.Y11 UC1.Y13 UC1.Y14 UC1.Y37 UC1.Y38 UC10.3 UC12.3 UC16.3 UE1.17 UE1.51 UE1.64 UE1.84 UE1.100 UE1.124 UE2.3 UG12.11 UG12.15 UG22.3 UG25.3 UG27.3 UG31.3 UH1.A2 UH1.A3 UH1.A4 UH1.A5 UH1.A8 UH1.A28 UH1.A33 UH1.A37 UH1.A45 UH1.A46 UH1.A47 UH1.A48 UH1.AA5 UH1.AA19 UH1.AA20 UH1.AA25 UH1.AA27 UH1.AA28 UH1.AA30 UH1.AA31 UH1.AA49 UH1.AB19 UH1.AB25 UH1.AB31 UH1.AC4 UH1.AC12 UH1.AC17 UH1.AC33 UH1.AC38 UH1.AC46 UH1.AD1 UH1.AD2 UH1.AD19 UH1.AD22 UH1.AD25 UH1.AD49 UH1.AE4 UH1.AE12 UH1.AE33 UH1.AE38 UH1.AE46 UH1.AF22 UH1.AF25 UH1.AF28 UH1.AG1 UH1.AG22 UH1.AG23 UH1.AG25 UH1.AG27 UH1.AG28 UH1.AG30 UH1.AG49 UH1.AH12 UH1.AH17 UH1.AH33 UH1.AH38 UH1.AJ19 UH1.AJ20 UH1.AJ25 UH1.AJ27 UH1.AJ28 UH1.AJ30 UH1.AJ31 UH1.AK4 UH1.AK19 UH1.AK20 UH1.AK25 UH1.AK27 UH1.AK28 UH1.AK30 UH1.AK31 UH1.AK46 UH1.AL12 UH1.AL17 UH1.AL21 UH1.AL24 UH1.AL26 UH1.AL29 UH1.AL33 UH1.AL38 UH1.AM1 UH1.AM18 UH1.AM32 UH1.AM49 UH1.AN12 UH1.AN16 UH1.AN34 UH1.AN38 UH1.AP4 UH1.AP46 UH1.AR12 UH1.AR16 UH1.AR34 UH1.AR38 UH1.AT1 UH1.AT16 UH1.AT18 UH1.AT21 UH1.AT24 UH1.AT26 UH1.AT29 UH1.AT32 UH1.AT34 UH1.AT45 UH1.AV11 UH1.AV39 UH1.AW4 UH1.AW10 UH1.AW40 UH1.AW46 UH1.B47 UH1.B48 UH1.B49 UH1.BA5 UH1.BA6 UH1.BA12 UH1.BA14 UH1.BA44 UH1.BB9 UH1.BB41 UH1.BB43 UH1.BC8 UH1.BC10 UH1.BC13 UH1.BC15 UH1.BC19 UH1.BC24 UH1.BC26 UH1.BC31 UH1.BC35 UH1.BC40 UH1.BC45 UH1.BD43 UH1.BE44 UH1.BF1 UH1.BF2 UH1.BF3 UH1.BF48 UH1.BF49 UH1.BG2 UH1.BG3 UH1.BG4 UH1.BG17 UH1.BG22 UH1.BG25 UH1.BG28 UH1.BG33 UH1.BG37 UH1.BG48 UH1.C4 UH1.C5 UH1.C12 UH1.C25 UH1.C30 UH1.C48 UH1.D8 UH1.D12 UH1.D16 UH1.D17 UH1.D30 UH1.D33 UH1.E8 UH1.E10 UH1.E13 UH1.E15 UH1.E17 UH1.E19 UH1.E22 UH1.E24 UH1.E26 UH1.E31 UH1.E33 UH1.E35 UH1.E40 UH1.E42 UH1.F41 UH1.F43 UH1.F47 UH1.G6 UH1.G44 UH1.H8 UH1.J4 UH1.J9 UH1.J10 UH1.J26 UH1.J29 UH1.J40 UH1.J46 UH1.J47 UH1.J48 UH1.K11 UH1.K39 UH1.M5 UH1.M16 UH1.M18 UH1.M21 UH1.M24 UH1.M32 UH1.M34 UH1.M49 UH1.N12 UH1.N16 UH1.N34 UH1.N35 UH1.N37 UH1.N38 UH1.P4 UH1.P26 UH1.P29 UH1.P46 UH1.R3 UH1.R4 UH1.R12 UH1.R16 UH1.R26 UH1.R29 UH1.R34 UH1.R38 UH1.T4 UH1.T5 UH1.T7 UH1.T17 UH1.T18 UH1.T32 UH1.T49 UH1.U12 UH1.U15 UH1.U17 UH1.U21 UH1.U24 UH1.U33 UH1.U38 UH1.V4 UH1.V20 UH1.V22 UH1.V46 UH1.W25 UH1.W27 UH1.W28 UH1.W30 UH1.Y9 UH1.Y10 UH1.Y12 UH1.Y17 UH1.Y33 UH1.Y38 UH3.3 UH4.4 UH4.9 UH14.3 UH15.4 UL1.33 UL2.2 UP1.4 UP1.9 UP2.49 US1.5 US1.6 US1.7 US1.8 US2.2 UT1.A1 UT1.A6 UT1.A8 UT1.A10 UT1.A12 UT1.A14 UT1.A16 UT1.A18 UT1.A20 UT1.A22 UT1.AA22 UT1.AA23 UT1.AB1 UT1.AB2 UT1.AB6 UT1.AB8 UT1.AB10 UT1.AB12 UT1.AB14 UT1.AB16 UT1.AB18 UT1.AB20 UT1.AB22 UT1.AC1 UT1.AC2 UT1.AC6 UT1.AC8 UT1.AC10 UT1.AC12 UT1.AC14 UT1.AC16 UT1.AC18 UT1.AC20 UT1.AC22 UT1.B1 UT1.B2 UT1.B6 UT1.B8 UT1.B10 UT1.B12 UT1.B14 UT1.B16 UT1.B18 UT1.B20 UT1.B22 UT1.C22 UT1.C23 UT1.D5 UT1.D6 UT1.D8 UT1.D9 UT1.D11 UT1.D12 UT1.D13 UT1.D15 UT1.D16 UT1.D18 UT1.E4 UT1.E5 UT1.E6 UT1.E8 UT1.E9 UT1.E11 UT1.E15 UT1.E16 UT1.E22 UT1.E23 UT1.F5 UT1.F6 UT1.F9 UT1.F16 UT1.F20 UT1.G22 UT1.G23 UT1.H1 UT1.H2 UT1.H5 UT1.H8 UT1.H12 UT1.H13 UT1.H15 UT1.H16 UT1.H20 UT1.J5 UT1.J8 UT1.J12 UT1.J13 UT1.J15 UT1.J18 UT1.J19 UT1.J20 UT1.J22 UT1.J23 UT1.K1 UT1.K2 UT1.L5 UT1.L13 UT1.L15 UT1.L20 UT1.L22 UT1.L23 UT1.M1 UT1.M2 UT1.M5 UT1.M11 UT1.M12 UT1.M19 UT1.M20 UT1.N5 UT1.N8 UT1.N9 UT1.N11 UT1.N12 UT1.N13 UT1.N15 UT1.N20 UT1.N22 UT1.N23 UT1.P1 UT1.P2 UT1.R5 UT1.R18 UT1.R19 UT1.R20 UT1.R22 UT1.R23 UT1.T1 UT1.T2 UT1.T5 UT1.T6 UT1.T8 UT1.T9 UT1.T13 UT1.T15 UT1.T16 UT1.T18 UT1.T20 UT1.U22 UT1.U23 UT1.V5 UT1.V6 UT1.V8 UT1.V9 UT1.V15 UT1.V16 UT1.V20 UT1.W5 UT1.W6 UT1.W8 UT1.W9 UT1.W13 UT1.W18 UT1.W20 UT1.W22 UT1.W23 UT1.Y9 UT1.Y13 UT1.Y20 UT2.4 UT3.4 UT4.A1 UT4.A6 UT4.A7 UT4.A8 UT4.B7 UT4.B8 UT4.D8 UT4.E5 UT4.E6 UT4.E7 UT4.E8 UT4.F5 UT4.F6 UT4.F7 UT4.F8 UT4.G5 UT4.G6 UT4.G7 UT4.G8 UT4.H4 UT4.H5 UT4.H8 UT4.L1 UTPM1.9 UTPM1.16 UTPM1.23 UTPM1.32 UTPM1.33 UU1.2 UU3.2 UV1.A2 UV1.A33 UV1.AA13 UV1.AA15 UV1.AA17 UV1.AA18 UV1.AA20 UV1.AA22 UV1.AB2 UV1.AB5 UV1.AB7 UV1.AB12 UV1.AB14 UV1.AB16 UV1.AB19 UV1.AB21 UV1.AB23 UV1.AB28 UV1.AB30 UV1.AB32 UV1.AC13 UV1.AC15 UV1.AC17 UV1.AC18 UV1.AC20 UV1.AC22 UV1.AE2 UV1.AE5 UV1.AE7 UV1.AE28 UV1.AE30 UV1.AE32 UV1.AE33 UV1.AG11 UV1.AH2 UV1.AH5 UV1.AH7 UV1.AH10 UV1.AH11 UV1.AH13 UV1.AH16 UV1.AH19 UV1.AH22 UV1.AH24 UV1.AH28 UV1.AH29 UV1.AH30 UV1.AH32 UV1.AH33 UV1.AJ7 UV1.AK7 UV1.AK10 UV1.AL2 UV1.AL5 UV1.AL12 UV1.AL14 UV1.AL15 UV1.AL17 UV1.AL18 UV1.AL20 UV1.AL21 UV1.AL23 UV1.AL24 UV1.AL26 UV1.AL28 UV1.AL30 UV1.AL32 UV1.AL33 UV1.AM13 UV1.AM16 UV1.AM19 UV1.AM22 UV1.AM25 UV1.AN1 UV1.AN4 UV1.AN7 UV1.AN10 UV1.AN13 UV1.AN16 UV1.AN19 UV1.AN22 UV1.AN25 UV1.AN30 UV1.AN34 UV1.AP2 UV1.AP33 UV1.B1 UV1.B4 UV1.B7 UV1.B10 UV1.B22 UV1.B25 UV1.B28 UV1.B31 UV1.B34 UV1.C7 UV1.C10 UV1.C13 UV1.C16 UV1.C19 UV1.C22 UV1.C25 UV1.C28 UV1.D2 UV1.D31 UV1.D33 UV1.E5 UV1.E7 UV1.E10 UV1.E22 UV1.E25 UV1.F7 UV1.F28 UV1.G2 UV1.G3 UV1.G5 UV1.G7 UV1.G10 UV1.G13 UV1.G16 UV1.G19 UV1.G22 UV1.G25 UV1.G28 UV1.G30 UV1.G32 UV1.G33 UV1.K2 UV1.K5 UV1.K7 UV1.K28 UV1.K30 UV1.K32 UV1.K33 UV1.M13 UV1.M15 UV1.M17 UV1.M18 UV1.M20 UV1.M22 UV1.N2 UV1.N5 UV1.N7 UV1.N12 UV1.N14 UV1.N16 UV1.N19 UV1.N21 UV1.N23 UV1.N28 UV1.N30 UV1.N32 UV1.N33 UV1.P13 UV1.P15 UV1.P17 UV1.P18 UV1.P20 UV1.P22 UV1.R12 UV1.R14 UV1.R16 UV1.R19 UV1.R21 UV1.R23 UV1.T2 UV1.T5 UV1.T7 UV1.T13 UV1.T15 UV1.T17 UV1.T18 UV1.T20 UV1.T22 UV1.T28 UV1.T32 UV1.U12 UV1.U14 UV1.U16 UV1.U19 UV1.U21 UV1.U23 UV1.V12 UV1.V14 UV1.V16 UV1.V19 UV1.V21 UV1.V23 UV1.W13 UV1.W15 UV1.W17 UV1.W18 UV1.W20 UV1.W22 UV1.W28 UV1.W32 UV1.Y12 UV1.Y14 UV1.Y16 UV1.Y19 UV1.Y21 UV1.Y23 UV6.A1 UV6.A3 UV6.A12 UV6.A14 UV6.B5 UV6.B10 UV6.C1 UV6.C3 UV6.C4 UV6.C11 UV6.C12 UV6.C14 UV6.D10 UV6.E1 UV6.E3 UV6.E12 UV6.E14 UV6.F5 UV6.F10 UV6.G5 UV6.G10 UV6.H1 UV6.H2 UV6.H13 UV6.H14 UV6.J10 UV6.K1 UV6.K2 UV6.K13 UV6.K14 UV6.L5 UV6.L10 UV6.M5 UV6.M10 UV6.N1 UV6.N3 UV6.N12 UV6.N14 UV6.P10 UV6.R1 UV6.R3 UV6.R4 UV6.R11 UV6.R12 UV6.R14 UV6.T5 UV6.T10 UV6.U1 UV6.U3 UV6.U12 UV6.U14 UV7.A1 UV7.A3 UV7.A12 UV7.A14 UV7.B5 UV7.B10 UV7.C1 UV7.C3 UV7.C4 UV7.C11 UV7.C12 UV7.C14 UV7.D10 UV7.E1 UV7.E3 UV7.E12 UV7.E14 UV7.F5 UV7.F10 UV7.G5 UV7.G10 UV7.H1 UV7.H2 UV7.H13 UV7.H14 UV7.J10 UV7.K1 UV7.K2 UV7.K13 UV7.K14 UV7.L5 UV7.L10 UV7.M5 UV7.M10 UV7.N1 UV7.N3 UV7.N12 UV7.N14 UV7.P10 UV7.R1 UV7.R3 UV7.R4 UV7.R11 UV7.R12 UV7.R14 UV7.T5 UV7.T10 UV7.U1 UV7.U3 UV7.U12 UV7.U14 UV8.A1 UV8.A3 UV8.A12 UV8.A14 UV8.B5 UV8.B10 UV8.C1 UV8.C3 UV8.C4 UV8.C11 UV8.C12 UV8.C14 UV8.D10 UV8.E1 UV8.E3 UV8.E12 UV8.E14 UV8.F5 UV8.F10 UV8.G5 UV8.G10 UV8.H1 UV8.H2 UV8.H13 UV8.H14 UV8.J10 UV8.K1 UV8.K2 UV8.K13 UV8.K14 UV8.L5 UV8.L10 UV8.M5 UV8.M10 UV8.N1 UV8.N3 UV8.N12 UV8.N14 UV8.P10 UV8.R1 UV8.R3 UV8.R4 UV8.R11 UV8.R12 UV8.R14 UV8.T5 UV8.T10 UV8.U1 UV8.U3 UV8.U12 UV8.U14 UV9.A1 UV9.A3 UV9.A12 UV9.A14 UV9.B5 UV9.B10 UV9.C1 UV9.C3 UV9.C4 UV9.C11 UV9.C12 UV9.C14 UV9.D10 UV9.E1 UV9.E3 UV9.E12 UV9.E14 UV9.F5 UV9.F10 UV9.G5 UV9.G10 UV9.H1 UV9.H2 UV9.H13 UV9.H14 UV9.J10 UV9.K1 UV9.K2 UV9.K13 UV9.K14 UV9.L5 UV9.L10 UV9.M5 UV9.M10 UV9.N1 UV9.N3 UV9.N12 UV9.N14 UV9.P10 UV9.R1 UV9.R3 UV9.R4 UV9.R11 UV9.R12 UV9.R14 UV9.T5 UV9.T10 UV9.U1 UV9.U3 UV9.U12 UV9.U14 UV14.3 UV17.2 UV19.3 UV20.3 UW1.2 UZ1.11 UZ1.15 UZ7.5 UZ7.9 UZ9.5 UZ15.5 UZ16.5 UZ16.9 UZ21.3 YH2.2 YH2.4 YL1.2 YL1.4 YT1.2 YT1.4 YV1.2 YV1.4
GND_SENSE_VGA: PRV07.2 PRV09.1 UV1.L5
V3D3_STB: RA11.1 RA12.1 UA1.16
VBAT_CHG: PCB45.1 PRB39.2 PRB68.2 PUB01.31
VBUS_P_CTRL_P1: PRS38.1 PRS48.1 PUS03.1 UT4.G11
VCC3V3_S0: CT153.1 CT154.1 CT155.1 LT4.1 UT1.R13
VCC_SA_SENSE: PRZ05.1 RC275.2
VCC_SENSE: PRZ08.1 RC10.1 UC1.AG37
VCC_VCCIO: PC910.1 PU901.16 PU901.17
VCCDSW_ON: DC2.2 RC442.1 RE163.2 RE164.2
VCCGT_SENSE: PRZ40.2 RC12.1 UC1.AH38
VCCIO_EN: CZ108.1 DZ2.2 PR903.1 RZ108.2
VCCIO_SENSE: PR911.2 RC272.2
VCCMPHY_SENSE: TH139.1(TP-1) UH1.K47
VCCST_EN: RZ111.2 RZ112.2 UZ15.4
VCCST_PWRGD_CPU: RC269.2 UC1.H13
VCCSTG_EN: CZ111.1 RZ49.1 UZ9.4
VDD10: CL5.1 CL6.1 CL15.1 CL18.1 CL19.1 CL22.1 CL23.1 UL1.3 UL1.8 UL1.22 UL1.24 UL1.30
VDD_1.2V: PCM14.1 PRM03.2 PRM04.2 PUM01.11
VDD_CHG: PCB28.1 PRB09.2 PRB11.1 PRB13.2 PRB60.1 PUB01.18
VDD_SENSE_VGA: PRV11.2 PRV14.1 UV1.L4
VDDP_CHG: PCB29.1 PRB09.1 PUB01.8
VIN_+1.05V: PCH01.1 PCH02.1 PCH03.1 PCH04.1 PCH06.1 PCH07.1 PJPH01.2 PLH11.2 PQH01.2
VIN_VCCIO: PC901.1 PC902.1 PC903.1 PC904.1 PC905.1 PC906.1 PJP901.2 PL911.2 PU901.2 PU901.3 PU901.4 PU901.5
VSS_SA_SENSE: PRZ02.1 RC276.2
VSS_SENSE: PRZ10.1 RC11.1 UC1.AG38
VSSGT_SENSE: PRZ42.2 RC13.1 UC1.AH37
VSSIO_SENSE: PR912.2 RC273.2
VSSMPHY_SENSE: TH138.1(TP-1) UH1.K46
81215_ALERT: PRZ26.2 PUZ01.41
81215_SCLK: PRZ25.1 PUZ01.42
81215_SDIO: PRZ27.1 PUZ01.40
81215_VR_HOT: PRZ24.1 PUZ01.39
+CHARGER_SRC: PCB01.1 PCB02.1 PCB03.1 PCB04.1 PCB05.1 PCB06.1 PCB07.1 PD13.3 PJPB01.2 PJPB02.1 PJPB03.1 PJPB08.2 PLB11.2 PLB12.2 PLB13.2 PQB01.2 PQB07.2
+DC_IN: PC3.1 PC4.1 PC5.1 PC8.1 PD12.1 PDB03.2 PJP1.2 PJP4.2 PL1.2 PL5.2 PL6.2 PQ3.1 PQ3.2 PQ3.3 PQ7.1 PQ7.2 PQ7.3 PR8.1 PR13.1 PR32.1 PR34.1 PR36.1 PR62.1 PRS03.1 PU01.1
+DC_IN_SS: PD4.2 PD4.3 PD7.2 PD7.3 PQ3.5 PQ4.5 PQ7.5 PQ8.5 PR11.1
+DCBAT_LCD: C4.1 C5.1 C47.1 F1.2 JEDP1.1 JEDP1.2 JEDP1.3 JEDP1.4
+FB_A_VREFC0: CV158.1 CV200.1 RV125.2 RV126.2 RV127.1 UV6.J14 UV7.J14
+FB_B_VREFC1: CV177.1 CV199.1 RV140.2 RV141.2 RV142.1 UV8.J14 UV9.J14
+FB_PLLAVDD: CV152.1 CV153.1 CV154.1 CV156.1 CV937.1 CV938.1 LV13.1 UV1.H17 UV1.K27 UV1.U27
+GPCPLL_AVDD: CV833.1 CV939.1 RV583.1 UV1.H26
+GPU_CORE: PCV101.1 PCV102.1 PCV103.1 PCV104.1 PCV105.1 PCV106.1 PCV107.1 PCV108.1 PCV109.1 PCV110.1 PCV111.1 PCV112.1 PCV113.1 PCV114.1 PCV115.1 PCV116.1 PCV117.1 PCV118.1 PCV119.1 PCV120.1 PCV121.1 PCV122.1 PCV123.1 PCV124.1 PCV125.1 PCV126.1 PCV127.1 PCV128.1 PCV129.1 PCV130.1 PCV131.1 PCV132.1 PCV133.1 PCV134.1 PCV135.1 PCV136.1 PCV137.1 PCV138.1 PCV139.1 PCV140.1 PCV171.1 PCV172.1 PCV173.1 PCV201.1 PCV202.1 PCV203.1 PCV204.1 PCV205.1 PCV206.1 PCV207.1 PCV208.1 PCV209.1 PCV210.1 PCV211.1 PCV212.1 PCV213.1 PCV214.1 PCV215.1 PCV216.1 PCV217.1 PCV271.1 PCV272.1 PLV01.4 PLV02.4 PLV03.4 PRV11.1 UV1.AA1 UV1.AA2 UV1.AA3 UV1.AA4 UV1.AA5 UV1.AA6 UV1.AA7 UV1.AA8 UV1.AA12 UV1.AA14 UV1.AA16 UV1.AA19 UV1.AA21 UV1.AA23 UV1.AB13 UV1.AB15 UV1.AB17 UV1.AB18 UV1.AB20 UV1.AB22 UV1.AC12 UV1.AC14 UV1.AC16 UV1.AC19 UV1.AC21 UV1.AC23 UV1.M12 UV1.M14 UV1.M16 UV1.M19 UV1.M21 UV1.M23 UV1.N13 UV1.N15 UV1.N17 UV1.N18 UV1.N20 UV1.N22 UV1.P12 UV1.P14 UV1.P16 UV1.P19 UV1.P21 UV1.P23 UV1.R13 UV1.R15 UV1.R17 UV1.R18 UV1.R20 UV1.R22 UV1.T12 UV1.T14 UV1.T16 UV1.T19 UV1.T21 UV1.T23 UV1.U4 UV1.U5 UV1.U6 UV1.U7 UV1.U8 UV1.U13 UV1.U15 UV1.U17 UV1.U18 UV1.U20 UV1.U22 UV1.V1 UV1.V2 UV1.V3 UV1.V4 UV1.V5 UV1.V6 UV1.V7 UV1.V8 UV1.V13 UV1.V15 UV1.V17 UV1.V18 UV1.V20 UV1.V22 UV1.W2 UV1.W3 UV1.W4 UV1.W5 UV1.W7 UV1.W8 UV1.W12 UV1.W14 UV1.W16 UV1.W19 UV1.W21 UV1.W23 UV1.Y1 UV1.Y2 UV1.Y3 UV1.Y4 UV1.Y5 UV1.Y6 UV1.Y7 UV1.Y8 UV1.Y13 UV1.Y15 UV1.Y17 UV1.Y18 UV1.Y20 UV1.Y22
+IFPX_PLLVDD: CG47.1 LG8.2 UV1.AF7
+LAN_VDD33: CL7.1 CL8.1 CL20.1 CL24.1 CL25.1 RL17.2 UL1.11 UL1.23 UL1.32 UL2.1
+LCDVDD: R3.2 U1.1
+LCDVDD_LCD: C2.1 C3.1 C12.1 JEDP1.7 JEDP1.8 R3.1
+LINE1_VREFO_L: DA8.1 UA1.24
+MIC2-VREFO: RA25.1 RA26.1 UA1.23
+PEX_PLL_HVDD: CV114.1 RV590.2 UV1.AH12
+PWR_SRC: F1.1 PCB10.1 PCB11.1 PCB12.1 PCB13.1 PCB14.1 PCB15.1 PCB16.1 PCB17.1 PCB21.1 PCB22.1 PCB23.1 PCB24.1 PCB53.1 PCB54.1 PD14.2 PJP301.1 PJP501.1 PJP901.1 PJPB02.2 PJPB03.2 PJPB04.2 PJPB05.2 PJPH01.1 PJPM01.1 PJPW01.1 PL311.1 PL511.1 PL911.1 PLH11.1 PLI11.1 PLIV11.1 PLM11.1 PLW11.1 PQB06.5 PR302.2 PRB21.2 PRB67.2 PRV23.2
+PWR_SRC_AC: PD13.2 PJPB01.1 PJPB08.1 PLB11.1 PLB12.1 PLB13.1 PRB01.4
+RTC_CELL: C1.1 D1.1 Q26.3 RA12.2 RE7.1 RE41.1 RE70.2 RH697.2
+RTC_CELL_PCH: C59.1 CH225.1 CH226.1 Q26.1 R73.1 RH83.1 RH84.1 RH531.2 RH697.1 UH1.BC49 UH1.BD49
+RTC_CELL_VBAT: CE14.1 RE7.2 UE1.122
+RTC_VCC: JIOB1.11 R1.2
+SDC_IN: PC6.1 PCS10.1 PD4.1 PD7.1 PDB02.2 PDS02.1 PDS07.1 PQ4.1 PQ4.2 PQ4.3 PQ8.1 PQ8.2 PQ8.3 PQ19.3 PQS02.1 PQS02.2 PQS02.3 PQS06.3 PQS16.1 PQS16.2 PQS16.3 PR9.1 PR47.1 PRB01.1 PRB04.2 PRB05.1 PRS09.1 PRS10.1
+SP_PLLVDD: CV52.1 RV585.1 UV1.AE8
+TBTA_VBUS: CT94.1 CT95.1 CT96.2 CT97.2 CT106.1 DT16.2 DT16.3 JUSBC1.A4 JUSBC1.A9 JUSBC1.B4 JUSBC1.B9 PCS05.1 PCS06.1 PCS15.1 PLS11.1 PLS12.1 PRS26.1 PUS04.1 UT4.A10 UT4.B10 UT4.H11 UT4.J10 UT4.J11 UT4.K11
+TBTA_VBUS_1: PCS07.1 PCS08.1 PLS11.2 PLS12.2 PQS17.5 PQS18.5 PRS07.1
+TP_VDD: C19.1 C52.1 JTP.8 Q9.2 Q12.1 R31.1 R32.1 R36.2 R37.2 R39.1 R40.1 R41.1 R46.1 R47.1
+TPAN_VDD: C48.1 JEDP1.40 R13.2 R30.2 U3.1
+V_DDR_REFA: CD28.1 JDIMM1.164 RD9.2 RD10.2 RD12.1
+V_DDR_REFA_R: CD30.1 RD9.1 UC1.BN13
+V_DDR_REFB: CD58.1 JDIMM2.164 RD19.2 RD20.2 RD21.1
+V_DDR_REFB_R: CD59.1 RD19.1 UC1.BR13
+VCHGR: PCB31.1 PCB32.1 PJPB07.1 PQB03.1 PQB03.2 PQB03.3 PRB12.4
+VDISPLAY_VCC: CV597.1 CV598.1 JHDMI1.18 RV676.1 RV677.1 UV17.3
+VID_PLLVDD: CV53.1 RV586.1 UV1.AD7
+XS_PLLVDD: CV72.1 CV940.1 RV584.1 UV1.AD8
AC_B2B_ACOK: PD10.1 PQ16.1 PQ21.1 PR2.1
AC_B2B_S1: PC22.1 PQ15.1 PQ16.2 PQS11.1 PR22.2
AC_B2B_S1_A: PC7.1 PQ5.2 PR2.2 PR100.1
AC_B2B_S2: PC10.1 PQ6.2 PR11.2 PR17.1 PR51.1
AC_B2B_S2_A: PQ17.2 PQ18.1 PR50.2
AC_B2B_S2_B: PQ19.2 PR47.2 PR48.1
AC_B2B_S2_G: PC6.2 PQ4.4 PQ8.4 PQ19.1 PR9.2 PR12.1
AC_B2B_S2_SW: PC23.1 PQ18.2 PR51.2 PR52.2
AC_DIS: PRB43.2 PRB45.1 UE1.69
AC_DIS1: PQ21.2 PQB04.2 PRB23.1 PRB43.1
AC_OK: PD10.2 PR13.2 PR15.1 PRB44.1 PRS33.1 PRS41.1
AC_PRESENT: DH1.2 RH533.1 UH1.BG42
AC_SW_PROCHOT: PC13.1 PC24.1 PQ12.6 PR33.2
ACAV_IN1: PQB04.1 PR65.1 PRB11.2 PRB20.1 PRB22.2 PRB41.1
ACAVIN_EC: PQS22.5 PQS22.6 PRS49.2
ACIN_CHG: PCB26.1 PRB05.2 PRB07.1 PUB01.19
ACOK_CHG: PRB22.1 PUB01.24
ADJ_2.5V: PC2505.2 PR2502.2 PR2503.1 PU2501.7
ADP_CHG: PCB56.1 PRB04.1 PRB51.1 PRB70.1 PUB01.16
ADPIN: PC1.1 PC2.1 PJP1.1 PJP4.1 PJPDC1.6 PJPDC1.7 PJPDC1.8 PJPDC1.9 PL1.1 PL5.1 PL6.1
ALERT#: R28.2 U2.6
ALL_GPWRGD: RV56.2 RV572.1 UV19.4
ALL_SYS_PWRGD: RE42.1 RH105.2 UH14.2
ALWON: PQB10.2 PR506.1 UE1.121
AMBER_LED_BAT: Q18.1 R68.2
AUD_AGND: CA7.2 CA10.2 CA11.2 CA12.1 CA20.1 CA21.1 CA23.2 CA26.2 CA34.2 CA35.2 CA36.2 CA37.2 CA41.2 CA42.2 CA51.1 CA52.1 CA53.1 JHP1.7 RA17.1 RA18.1 RA22.1 RA30.2 RA34.2 RA40.2 RA41.1 UA1.19 UA1.31
AUD_HP1_JACK_L: RA27.1 RA28.2 UA1.25
AUD_HP1_JACK_L1: LA2.1 RA27.2 RA29.2
AUD_HP1_JACK_R: RA31.1 RA32.2 UA1.26
AUD_HP1_JACK_R1: LA3.1 RA31.2 RA33.2
AUD_PC_BEEP: CA31.2 UA1.11
AUD_PC_BEEP_C: DA3.1 RA23.1
AUD_SENSE_A: CA7.1 RA3.1 RA10.2 UA1.12
AUD_SPK_L+: RA15.1 UA1.35
AUD_SPK_L+_C: CA28.1 DA1.2 JSPK1.3 RA15.2
AUD_SPK_L-: RA16.1 UA1.36
AUD_SPK_L-_C: CA27.1 DA1.3 JSPK1.4 RA16.2
AUD_SPK_R+: RA13.1 UA1.38
AUD_SPK_R+_C: CA30.1 DA2.2 JSPK1.1 RA13.2
AUD_SPK_R-: RA14.1 UA1.37
AUD_SPK_R-_C: CA29.1 DA2.3 JSPK1.2 RA14.2
AUD_VREF: CA23.1 UA1.22
AUX_EN_WOWL: TP74.1(TP-1) UE1.70
AUX_ON: RL6.2 UE1.3 UL2.4
BA: PQB11.1 PRB65.2 PRB66.1
BA_PWR: PRB66.2 PRB68.1 PRB69.2
BAT1_LED#: Q17.1 RE18.1 UE1.106
BAT2_LED#: Q17.4 RE21.1 UE1.1
BATGONE_CHG: PCB34.1 PRB24.1 PRB25.1 PUB01.25
BATLOW#: RT14.1 RT31.2 UT1.F2
BATT+: PC11.1 PJP3.1 PJPB07.2 PL4.1 PL7.1 PQB03.5 PQB11.3 PRB39.1 PRB65.1
BATT++: PBATT1.8 PBATT1.9 PBATT1.10 PC12.1 PJP3.2 PL4.2 PL7.2
BATT_WHITE_LED_R#: Q17.3 Q19.2 Q22.1
BBS_BIT0: RH130.2 UH1.BA26
BEEP: DA3.3 UE1.45
BGATE_CHG: PCB33.1 PQB03.4 PRB61.2 PUB01.32
BKLT_CTRL: D3.1 R9.1 RP1.8 RP2.7
BKLT_IN_EC: RE157.1 UE1.67 UH1.AV46
BLON_OUT_C: JEDP1.28 RP1.7 RP2.1
BOARD_ID: CE2.1 RE1.2 RE6.2 UE1.111
BOOT1_CHG: PRB06.1 PUB01.12
BOOT2_CHG: PCB30.1 PUB01.4
BS_VCCIO: PR902.1 PU901.1
BST_1.2V: PRM02.1 PUM01.18
BST_1.2V_R: PCM12.1 PRM02.2
BST_3V: PR301.1 PU301.1
BST_5V: PR501.1 PU501.1
BST_+1.05V: PCH08.1 PRH02.2
BST_VCCIO: PC907.1 PR902.2
BT_RADIO_DIS#: DN2.1 RH706.2 UH1.BA24
BT_RADIO_DIS#_R: DN2.2 JWLAN1.54
BUSPOWER#: RT74.2 RT163.1 UT4.F10
BYPSRC: PRB50.2 PUB01.13
CAP_LED: JKB.27 R25.2
CAP_LED#: Q6.3 R24.2 UE1.93
CAP_LED_Q: Q7.1 R25.1
CAP_LED_R#: Q6.1 Q7.2
CATERR#: RC263.2 TC96.1(TP-1) UC1.BM30
CBN: CA24.2 UA1.28
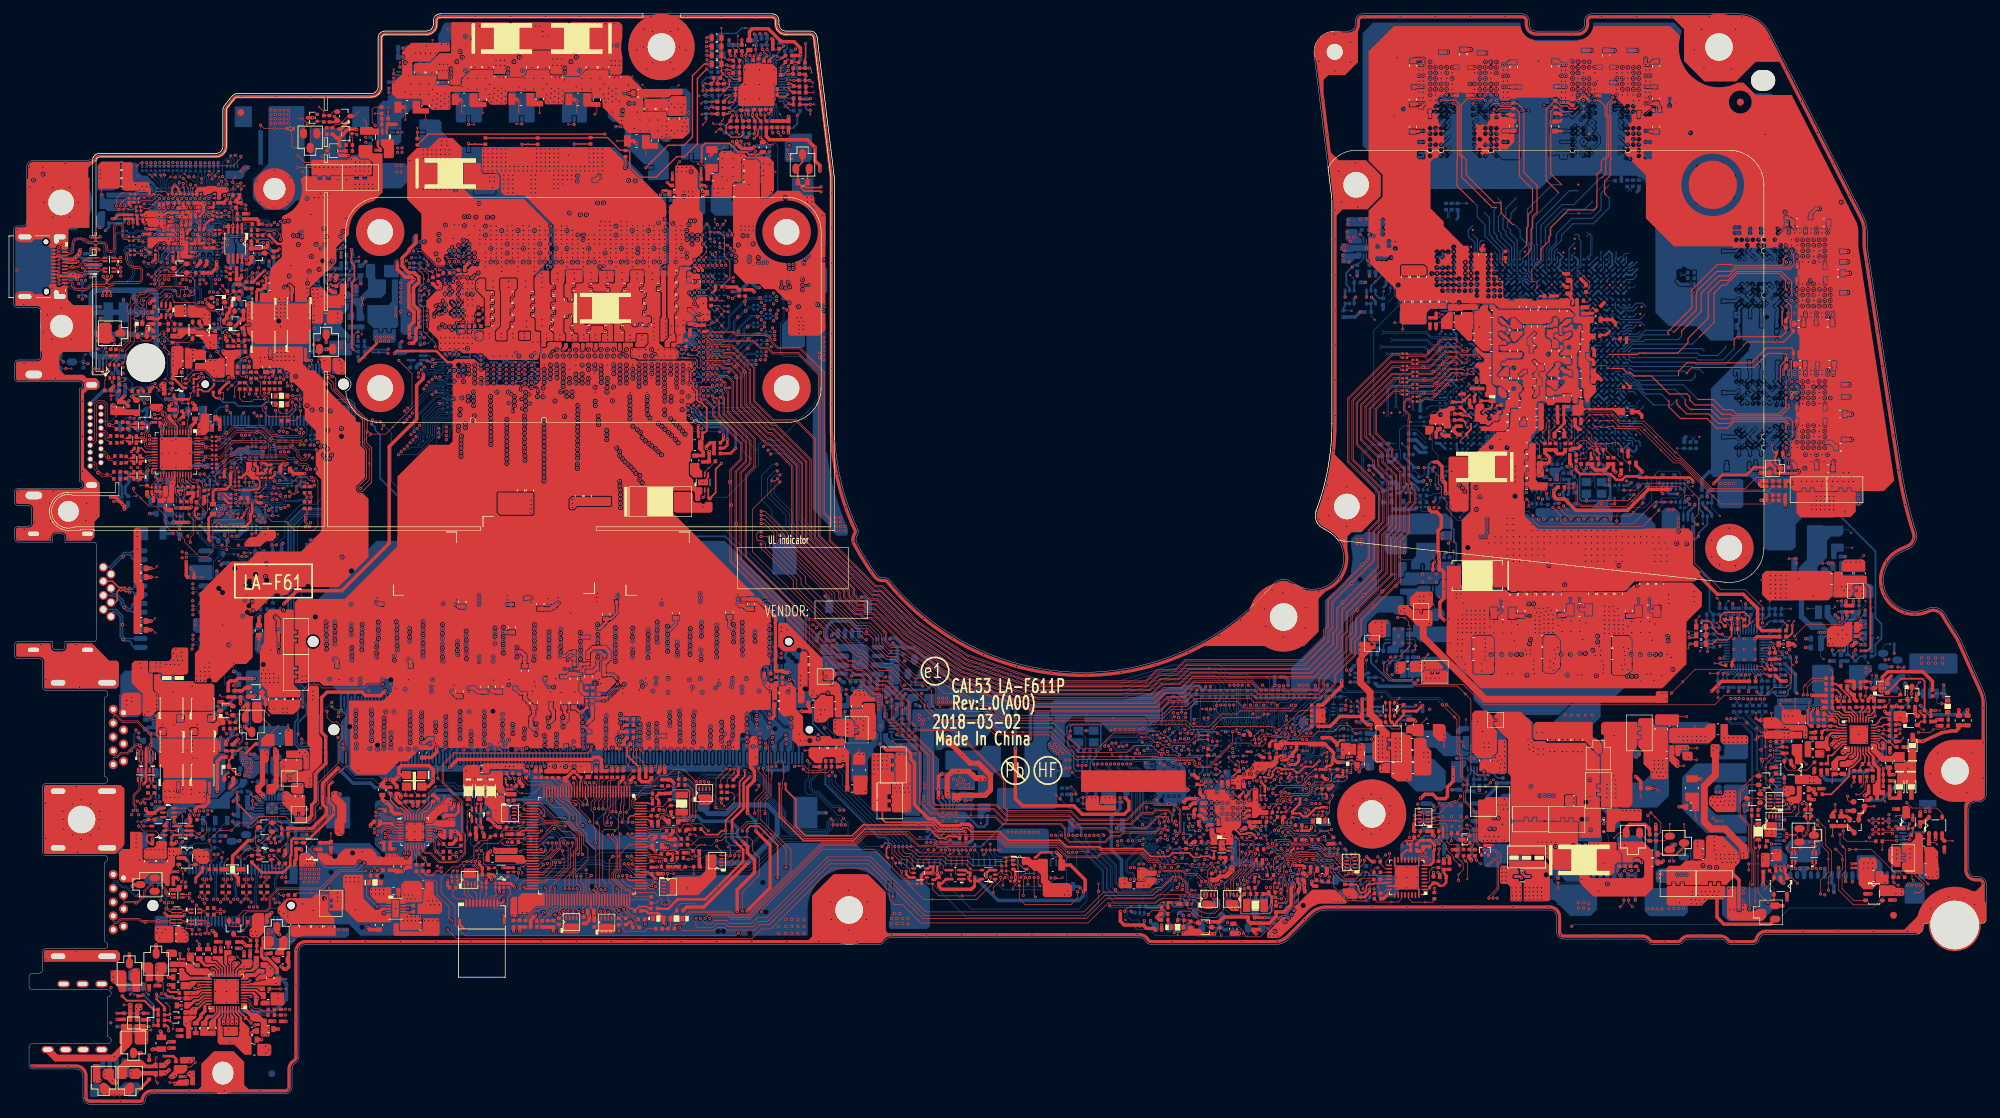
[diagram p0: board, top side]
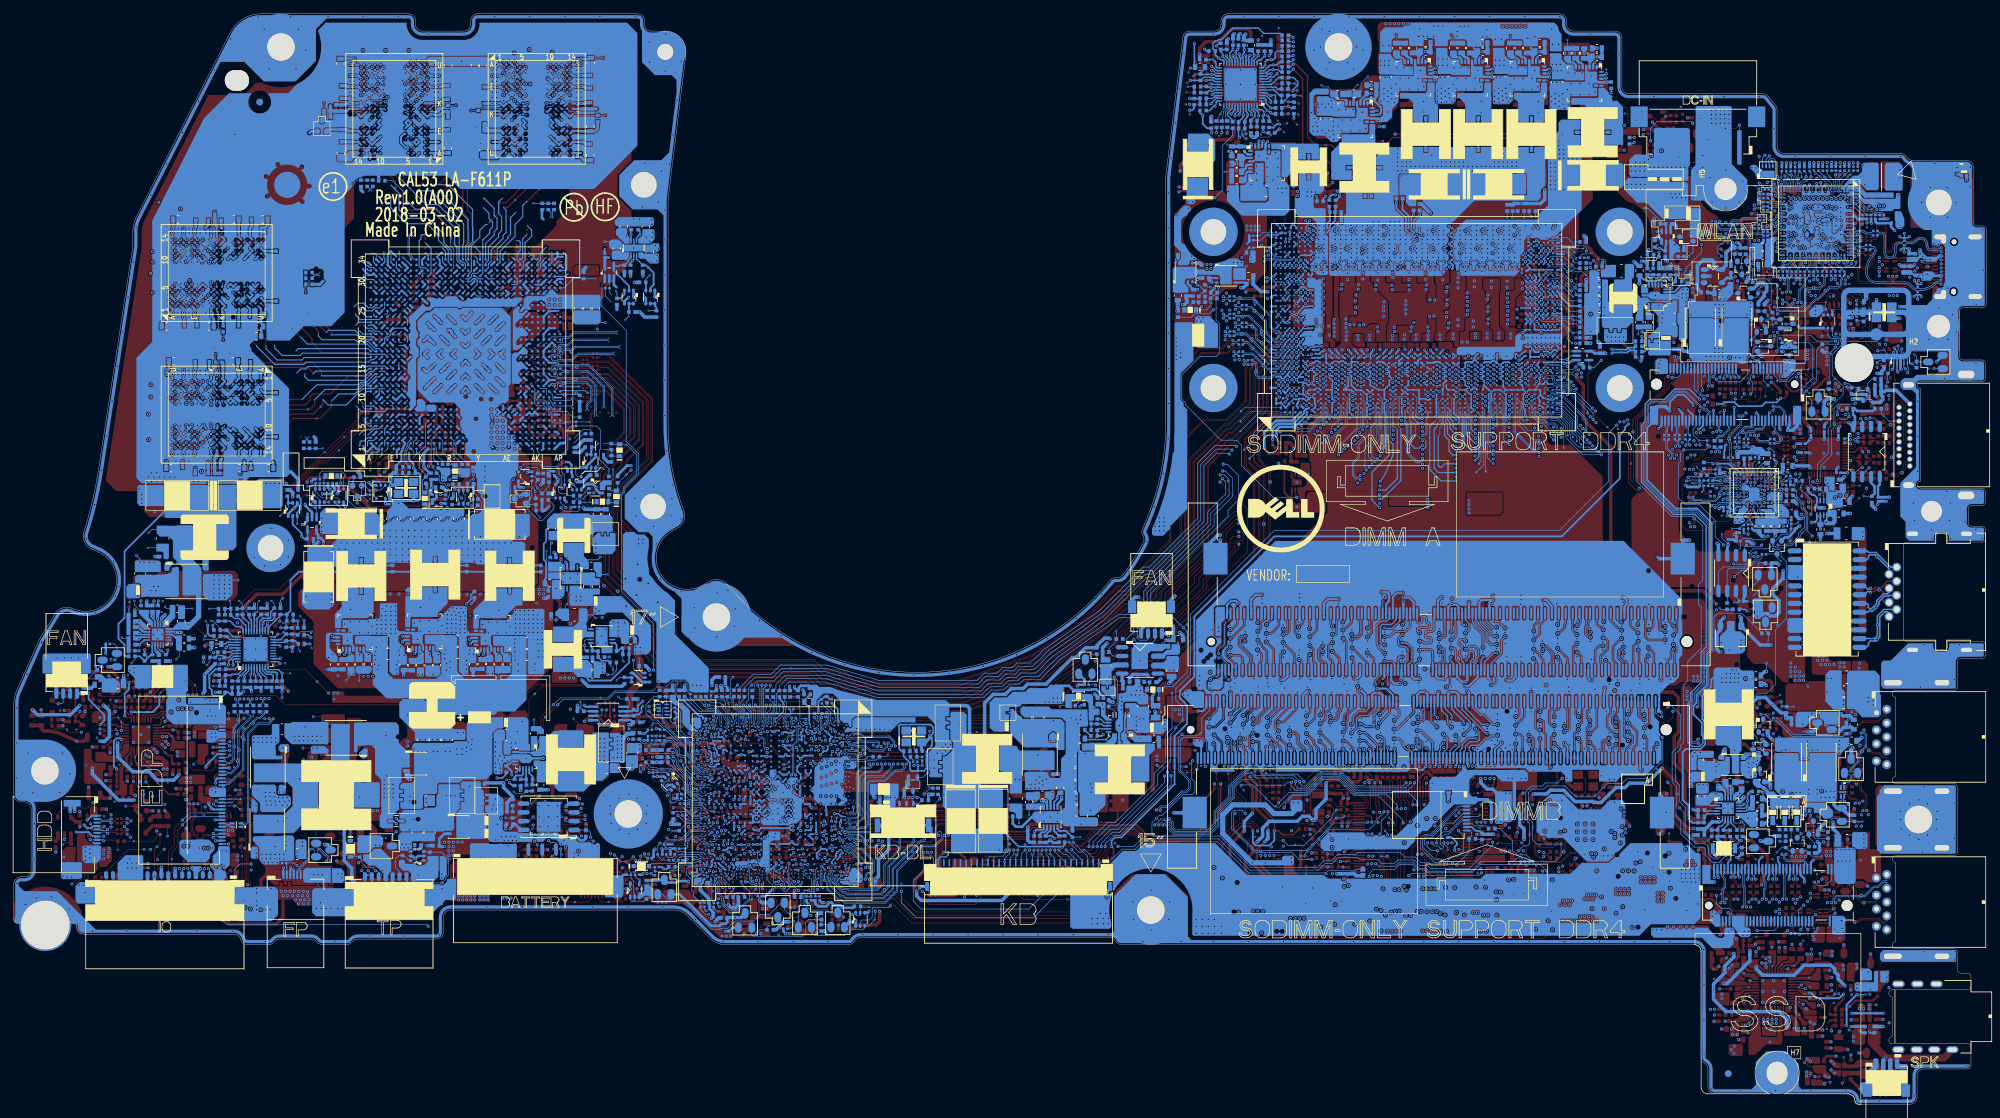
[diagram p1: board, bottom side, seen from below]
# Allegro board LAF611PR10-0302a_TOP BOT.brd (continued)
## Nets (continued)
CBP: CA24.1 UA1.30
CFG0: RC255.1 TPC10.1(TP-1) UC1.BN25
CFG1: TPC11.1(TP-1) UC1.BN27
CFG2: RC258.1 TPC12.1(TP-1) UC1.BN26
CFG3: RC250.1 TPC13.1(TP-1) UC1.BN28
CFG4: RC257.1 TPC14.1(TP-1) UC1.BR20
CFG5: RC256.1 TPC15.1(TP-1) UC1.BM20
CFG6: RC253.1 TPC16.1(TP-1) UC1.BT20
CFG7: RC254.1 TPC17.1(TP-1) UC1.BP20
CFG8: TPC20.1(TP-1) UC1.BR23
CFG9: TPC21.1(TP-1) UC1.BR22
CFG10: TPC22.1(TP-1) UC1.BT23
CFG11: TPC23.1(TP-1) UC1.BT22
CFG12: TPC24.1(TP-1) UC1.BM19
CFG13: TPC25.1(TP-1) UC1.BR19
CFG14: TPC26.1(TP-1) UC1.BP19
CFG15: TPC27.1(TP-1) UC1.BT19
CFG16: TPC19.1(TP-1) UC1.BP23
CFG17: TPC18.1(TP-1) UC1.BN23
CFG18: TPC29.1(TP-1) UC1.BN22
CFG19: TPC28.1(TP-1) UC1.BP22
CFG_RCOMP: RC19.1 UC1.BT25
CHG_AMBER_LED_R#: Q17.6 Q18.2
CLK_CNV_PRX_DTX_N: R3008.1 UH1.BD4
CLK_CNV_PRX_DTX_P: R3010.1 UH1.BE3
CLK_CNV_PRX_R_DTX_N: JWLAN1.21 R3008.2
CLK_CNV_PRX_R_DTX_P: JWLAN1.23 R3010.2
CLK_CNV_PTX_DRX_N: R3025.1 UH1.BC5
CLK_CNV_PTX_DRX_P: R3026.1 UH1.BB6
CLK_CNV_PTX_R_DRX_N: JWLAN1.71 R3025.2
CLK_CNV_PTX_R_DRX_P: JWLAN1.73 R3026.2
CLK_PCIE_N0: UH1.AJ6 UT1.T19
CLK_PCIE_N7: UH1.W7 UV1.AK13
CLK_PCIE_N9: JSSD1.53 UH1.U2
CLK_PCIE_N14: UH1.T2 UL1.16
CLK_PCIE_N15: JWLAN1.49 UH1.V2
CLK_PCIE_P0: UH1.AJ7 UT1.V19
CLK_PCIE_P7: UH1.W6 UV1.AL13
CLK_PCIE_P9: JSSD1.55 UH1.U3
CLK_PCIE_P14: UH1.T1 UL1.15
CLK_PCIE_P15: JWLAN1.47 UH1.V3
CLK_SMB: PBATT1.7 PR42.1
CLK_TP_SIO: C27.1 JTP.1 R32.2 UE1.78
CLKREQ_CNV#: QH9.2 RH725.1 RW29.1 UH1.BA17
CLKREQ_CNV#_D: JWLAN1.14 QH9.3 RH723.1
CLKREQ_PCIE#0: RT2.2 RT24.1 UH1.BF31
CLKREQ_PCIE#0_R: RT2.1 RT20.2 UT1.AC5
CLKREQ_PCIE#7: QV3.1 RP3.5 UH1.AC48
CLKREQ_PCIE#9: JSSD1.52 RP3.8 UH1.AF48
CLKREQ_PCIE#14: RL13.1 RP3.6 UH1.AC44
CLKREQ_PCIE#14_R: RL13.2 UL1.12
CLKREQ_PCIE#15: RP3.7 RW9.1 UH1.AC43
CLKREQ_PCIE#15_R: JWLAN1.53 RW9.2
CLKRUN#: RH701.1 UH1.AV32
CMP_STRAP0: RE165.1 UE1.118
CMP_VIN0: RE37.1 RE52.1 RE166.1 UE1.20
CMP_VOUT0: PR507.1 QG23.3 RE49.2 RE52.2 RG580.1 UE1.85
CNV_BRI_PRX_DTX: RH614.2 RW19.1 UH1.AY2
CNV_BRI_PRX_R_DTX: JWLAN1.22 RW13.1 RW19.2 RW27.1
CNV_BRI_PTX_DRX: RH671.2 RW20.1 UH1.AV4
CNV_BRI_PTX_R_DRX: JWLAN1.36 RW20.2
CNV_PRX_DTX_N0: R3006.1 UH1.BB3
CNV_PRX_DTX_N1: R3004.1 UH1.BA3
CNV_PRX_DTX_P0: R3007.1 UH1.BB4
CNV_PRX_DTX_P1: R3005.1 UH1.BA2
CNV_PRX_R_DTX_N0: JWLAN1.15 R3006.2
CNV_PRX_R_DTX_N1: JWLAN1.9 R3004.2
CNV_PRX_R_DTX_P0: JWLAN1.17 R3007.2
CNV_PRX_R_DTX_P1: JWLAN1.11 R3005.2
CNV_PTX_DRX_N0: R3023.1 UH1.BE6
CNV_PTX_DRX_N1: R3019.1 UH1.BG6
CNV_PTX_DRX_P0: R3024.1 UH1.BD7
CNV_PTX_DRX_P1: R3021.1 UH1.BF6
CNV_PTX_R_DRX_N0: JWLAN1.65 R3023.2
CNV_PTX_R_DRX_N1: JWLAN1.59 R3019.2
CNV_PTX_R_DRX_P0: JWLAN1.67 R3024.2
CNV_PTX_R_DRX_P1: JWLAN1.61 R3021.2
CNV_RF_RESET#: QH8.2 RH724.1 RW4.1 UH1.BE16
CNV_RF_RESET#_D: JWLAN1.10 QH8.3 RH722.1
CNV_RGI_PRX_DTX: RH613.2 RW21.1 UH1.AV3
CNV_RGI_PRX_R_DTX: JWLAN1.34 RW21.2
CNV_RGI_PTX_DRX: RH588.2 RH589.1 RW18.1 UH1.BA4
CNV_RGI_PTX_R_DRX: JWLAN1.32 RW15.1 RW18.2 RW28.1
CNV_WT_RCOMP: RH667.1 UH1.BA1
CNVI_EN#: Q30.2 RW30.1 UH1.BF17
COMP_1PH: PCZ10.1 PCZ11.2 PUZ01.50
COMP_2PH: PCZ24.2 PCZ25.2 PUZ01.33
COMP_4PH: PCZ13.1 PRZ29.1 PUZ01.6
COMP_CHG: PCB39.1 PRB30.1 PUB01.28
CORE_SW1: PLI01.1 PRI04.1 PUI01.11 PUI01.12
CORE_SW2: PLI02.1 PRI08.1 PUI02.11 PUI02.12
CORE_SW3: PLI03.1 PRI12.1 PUI03.11 PUI03.12
CORE_SW4: PLI04.1 PRI16.1 PUI04.11 PUI04.12
CPU_24MHZ_N: UC1.D31 UH1.C6
CPU_24MHZ_P: UC1.E31 UH1.D7
CPU_B+: PCA01.1 PCA02.1 PCA03.1 PCA04.1 PCA05.1 PCA06.1 PCA11.1 PCA12.1 PCG01.1 PCG02.1 PCG03.1 PCG04.1 PCG05.1 PCG06.1 PCG11.1 PCG12.1 PCI03.1 PCI04.1 PCI05.1 PCI06.1 PCI07.1 PCI08.1 PCI09.1 PCI10.1 PCI11.1 PCI12.1 PCI13.1 PCI18.1 PCI19.1 PCI20.1 PCI21.1 PCI22.1 PCI23.1 PCI28.1 PCI29.1 PCI30.1 PCI31.1 PCI32.1 PCI33.1 PCI38.1 PCI39.1 PCI40.1 PCI41.1 PCI42.1 PCI43.1 PCI48.1 PCI49.1 PCI50.1 PCI51.1 PCI52.1 PCI53.1 PLI11.2 PRZ52.1 PUA01.8 PUA01.9 PUG01.8 PUG01.9 PUI01.8 PUI01.9 PUI02.8 PUI02.9 PUI03.8 PUI03.9 PUI04.8 PUI04.9
CPU_DISPA_BCLK: RH38.1 UC1.G27
CPU_DISPA_BCLK_R: RH38.2 UH1.AM3
CPU_DISPA_SDI: RC2.1 UH1.AN3
CPU_DISPA_SDI_C: RC2.2 UC1.G29
CPU_DISPA_SDO: RH39.1 UC1.G25
CPU_DISPA_SDO_R: RH39.2 UH1.AM2
CPU_DP1_AUXN: CT126.1 UC1.E27
CPU_DP1_AUXN_C: CT126.2 RT76.1 UT1.W11
CPU_DP1_AUXP: CT125.1 UC1.D27
CPU_DP1_AUXP_C: CT125.2 RT78.1 UT1.Y11
CPU_DP1_CTRL_DATA: RH33.1 UH1.AR8
CPU_DP1_HPD: RPT1.6 UH1.AT6 UT1.AA2
CPU_DP1_N0: CT118.1 UC1.K37
CPU_DP1_N0_C: CT118.2 UT1.AC7
CPU_DP1_N1: CT120.1 UC1.J34
CPU_DP1_N1_C: CT120.2 UT1.AC9
CPU_DP1_N2: CT122.1 UC1.H36
CPU_DP1_N2_C: CT122.2 UT1.AC11
CPU_DP1_N3: CT124.1 UC1.J38
CPU_DP1_N3_C: CT124.2 UT1.AC13
CPU_DP1_P0: CT117.1 UC1.K36
CPU_DP1_P0_C: CT117.2 UT1.AB7
CPU_DP1_P1: CT119.1 UC1.J35
CPU_DP1_P1_C: CT119.2 UT1.AB9
CPU_DP1_P2: CT121.1 UC1.H37
CPU_DP1_P2_C: CT121.2 UT1.AB11
CPU_DP1_P3: CT123.1 UC1.J37
CPU_DP1_P3_C: CT123.2 UT1.AB13
CPU_ID: RH23.1 RH24.1 UH1.AP24
CPU_TRIGOUT: RC8.2 UC1.J23
CPU_TRIGOUT_R: RC8.1 UH1.AK2
CPU_VCCIO_PWR_GATE#: RH719.2 RZ234.1 UH1.AY3
CPU_XDP_TCK0: RC83.1 TPC2.1(TP-1) UC1.BR28 UH1.AH4
CPU_XDP_TDI: RC77.1 TPC5.1(TP-1) UC1.BL32 UH1.AH2
CPU_XDP_TDO: RC78.1 TPC1.1(TP-1) UC1.BT28 UH1.AH3
CPU_XDP_TMS: RC76.1 TPC4.1(TP-1) UC1.BP28 UH1.AJ4
CPU_XDP_TRST#: RC85.1 TPC6.1(TP-1) UC1.BP30 UH1.AM4
CPVEE: CA25.1 UA1.27
CS_1.2V: PRM03.1 PUM01.13
CSCOMP_2PH: PCZ27.1 PCZ28.1 PHZ02.1 PRZ48.2 PRZ49.1 PUZ01.31
CSCOMP_4PH: PCZ17.1 PCZ18.2 PHZ01.1 PRZ32.1 PRZ33.1 PUZ01.8
CSIN_CHG: PCB18.2 PCB20.1 PRB03.2 PUB01.14
CSIP_CHG: PCB18.1 PCB19.1 PRB02.2 PUB01.15
CSN_1PH: PHZ05.1 PLA01.3 PRZ70.1
CSN_1PH_R: PCZ06.1 PCZ07.1 PCZ38.1 PRZ70.2 PUZ01.48
CSON_CHG: PCB41.2 PCB43.1 PRB36.1 PUB01.1
CSOP_CHG: PCB38.1 PCB41.1 PRB32.1 PUB01.2
CSP1_2PH: PCZ33.2 PRZ60.1 PUZ01.28
CSP1_4PH: PCZ34.2 PRZ61.2 PRZ73.2 PUZ01.11
CSP2_4PH: PCZ35.2 PRZ62.2 PRZ74.2 PUZ01.12
CSP3_4PH: PCZ36.2 PRZ63.2 PRZ75.2 PUZ01.13
CSP4_4PH: PCZ37.2 PRZ64.2 PRZ76.2 PRZ77.2 PUZ01.26
CSP_1PH: PCZ06.2 PCZ07.2 PRZ12.2 PRZ13.1 PUZ01.47
CSREF_2PH: PCZ26.1 PCZ33.1 PRG03.2 PUZ01.29
CSREF_4PH: PCZ19.2 PCZ34.1 PCZ35.1 PCZ36.1 PCZ37.1 PRI03.2 PRI07.2 PRI11.2 PRI15.2 PRZ73.1 PRZ74.1 PRZ75.1 PRZ76.1 PUZ01.10
CSSUM_2PH: PCZ27.2 PCZ28.2 PRZ50.2 PRZ51.1 PUZ01.30
CSSUM_4PH: PCZ17.2 PCZ18.1 PRZ34.2 PRZ35.2 PRZ36.2 PRZ37.2 PRZ38.2 PUZ01.9
DAT_SMB: PBATT1.6 PR37.1
DAT_TP_SIO: C26.1 JTP.2 R31.2 UE1.79
DBC_PANEL_EN: R6.2 UH1.BD29
DBC_PANEL_EN_R: JEDP1.11 R5.2 R6.1
DCIN_CHG: PCB27.1 PRB08.2 PUB01.17
DDR_A_ACT#: JDIMM1.114 UC1.AU3
DDR_A_ALERT#: JDIMM1.116 UC1.AU5
DDR_A_BA0: JDIMM1.150 UC1.AH5
DDR_A_BA1: JDIMM1.145 UC1.AH1
DDR_A_BG0: JDIMM1.115 UC1.AU1
DDR_A_BG1: JDIMM1.113 UC1.AU2
DDR_A_CKE0: JDIMM1.109 UC1.AT1
DDR_A_CKE1: JDIMM1.110 UC1.AT2
DDR_A_CLK0: JDIMM1.137 UC1.AG1
DDR_A_CLK1: JDIMM1.138 UC1.AK2
DDR_A_CLK#0: JDIMM1.139 UC1.AG2
DDR_A_CLK#1: JDIMM1.140 UC1.AK1
DDR_A_CS#0: JDIMM1.149 UC1.AD5
DDR_A_CS#1: JDIMM1.157 UC1.AE2
DDR_A_D0: JDIMM1.4 UC1.BR6
DDR_A_D1: JDIMM1.3 UC1.BT6
DDR_A_D2: JDIMM1.20 UC1.BP3
DDR_A_D3: JDIMM1.21 UC1.BR3
DDR_A_D4: JDIMM1.8 UC1.BN5
DDR_A_D5: JDIMM1.7 UC1.BP6
DDR_A_D6: JDIMM1.16 UC1.BP2
DDR_A_D7: JDIMM1.17 UC1.BN3
DDR_A_D8: JDIMM1.29 UC1.BL4
DDR_A_D9: JDIMM1.25 UC1.BL5
DDR_A_D10: JDIMM1.37 UC1.BL2
DDR_A_D11: JDIMM1.41 UC1.BM1
DDR_A_D12: JDIMM1.24 UC1.BK4
DDR_A_D13: JDIMM1.28 UC1.BK5
DDR_A_D14: JDIMM1.42 UC1.BK1
DDR_A_D15: JDIMM1.38 UC1.BK2
DDR_A_D16: JDIMM1.45 UC1.BG4
DDR_A_D17: JDIMM1.49 UC1.BG5
DDR_A_D18: JDIMM1.63 UC1.BF4
DDR_A_D19: JDIMM1.58 UC1.BF5
DDR_A_D20: JDIMM1.50 UC1.BG2
DDR_A_D21: JDIMM1.46 UC1.BG1
DDR_A_D22: JDIMM1.62 UC1.BF1
DDR_A_D23: JDIMM1.59 UC1.BF2
DDR_A_D24: JDIMM1.67 UC1.BD2
DDR_A_D25: JDIMM1.70 UC1.BD1
DDR_A_D26: JDIMM1.80 UC1.BC4
DDR_A_D27: JDIMM1.84 UC1.BC5
DDR_A_D28: JDIMM1.66 UC1.BD5
DDR_A_D29: JDIMM1.71 UC1.BD4
DDR_A_D30: JDIMM1.83 UC1.BC1
DDR_A_D31: JDIMM1.79 UC1.BC2
DDR_A_D32: JDIMM1.174 UC1.AB1
DDR_A_D33: JDIMM1.170 UC1.AB2
DDR_A_D34: JDIMM1.187 UC1.AA4
DDR_A_D35: JDIMM1.186 UC1.AA5
DDR_A_D36: JDIMM1.169 UC1.AB5
DDR_A_D37: JDIMM1.173 UC1.AB4
DDR_A_D38: JDIMM1.182 UC1.AA2
DDR_A_D39: JDIMM1.183 UC1.AA1
DDR_A_D40: JDIMM1.195 UC1.V5
DDR_A_D41: JDIMM1.191 UC1.V2
DDR_A_D42: JDIMM1.207 UC1.U1
DDR_A_D43: JDIMM1.203 UC1.U2
DDR_A_D44: JDIMM1.194 UC1.V1
DDR_A_D45: JDIMM1.190 UC1.V4
DDR_A_D46: JDIMM1.208 UC1.U5
DDR_A_D47: JDIMM1.204 UC1.U4
DDR_A_D48: JDIMM1.211 UC1.R2
DDR_A_D49: JDIMM1.216 UC1.P5
DDR_A_D50: JDIMM1.212 UC1.R4
DDR_A_D51: JDIMM1.228 UC1.P4
DDR_A_D52: JDIMM1.215 UC1.R5
DDR_A_D53: JDIMM1.229 UC1.P2
DDR_A_D54: JDIMM1.224 UC1.R1
DDR_A_D55: JDIMM1.225 UC1.P1
DDR_A_D56: JDIMM1.237 UC1.M4
DDR_A_D57: JDIMM1.236 UC1.M1
DDR_A_D58: JDIMM1.232 UC1.L4
DDR_A_D59: JDIMM1.233 UC1.L2
DDR_A_D60: JDIMM1.245 UC1.M5
DDR_A_D61: JDIMM1.249 UC1.M2
DDR_A_D62: JDIMM1.246 UC1.L5
DDR_A_D63: JDIMM1.250 UC1.L1
DDR_A_DQS0: JDIMM1.13 UC1.BP5
DDR_A_DQS1: JDIMM1.34 UC1.BK3
DDR_A_DQS2: JDIMM1.55 UC1.BF3
DDR_A_DQS3: JDIMM1.76 UC1.BC3
DDR_A_DQS4: JDIMM1.179 UC1.AB3
DDR_A_DQS5: JDIMM1.200 UC1.V3
DDR_A_DQS6: JDIMM1.221 UC1.R3
DDR_A_DQS7: JDIMM1.242 UC1.M3
DDR_A_DQS#0: JDIMM1.11 UC1.BR5
DDR_A_DQS#1: JDIMM1.32 UC1.BL3
DDR_A_DQS#2: JDIMM1.53 UC1.BG3
DDR_A_DQS#3: JDIMM1.74 UC1.BD3
DDR_A_DQS#4: JDIMM1.177 UC1.AA3
DDR_A_DQS#5: JDIMM1.198 UC1.U3
DDR_A_DQS#6: JDIMM1.219 UC1.P3
DDR_A_DQS#7: JDIMM1.240 UC1.L3
DDR_A_MA0: JDIMM1.144 UC1.AH3
DDR_A_MA1: JDIMM1.133 UC1.AP4
DDR_A_MA2: JDIMM1.132 UC1.AN4
DDR_A_MA3: JDIMM1.131 UC1.AP5
DDR_A_MA4: JDIMM1.128 UC1.AP2
DDR_A_MA5: JDIMM1.126 UC1.AP1
DDR_A_MA6: JDIMM1.127 UC1.AP3
DDR_A_MA7: JDIMM1.122 UC1.AN1
DDR_A_MA8: JDIMM1.125 UC1.AN3
DDR_A_MA9: JDIMM1.121 UC1.AT4
DDR_A_MA10: JDIMM1.146 UC1.AH2
DDR_A_MA11: JDIMM1.120 UC1.AN2
DDR_A_MA12: JDIMM1.119 UC1.AU4
DDR_A_MA13: JDIMM1.158 UC1.AE3
DDR_A_MA14_WE#: JDIMM1.151 UC1.AG4
DDR_A_MA15_CAS#: JDIMM1.156 UC1.AD1
DDR_A_MA16_RAS#: JDIMM1.152 UC1.AH4
DDR_A_ODT0: JDIMM1.155 UC1.AD3
DDR_A_ODT1: JDIMM1.161 UC1.AE4
DDR_A_PAR: JDIMM1.143 UC1.AG3
DDR_B_ACT#: JDIMM2.114 UC1.AT9
DDR_B_ALERT#: JDIMM2.116 UC1.AR8
DDR_B_BA0: JDIMM2.150 UC1.AH8
DDR_B_BA1: JDIMM2.145 UC1.AH9
DDR_B_BG0: JDIMM2.115 UC1.AR9
DDR_B_BG1: JDIMM2.113 UC1.AR7
DDR_B_CKE0: JDIMM2.109 UC1.AT8
DDR_B_CKE1: JDIMM2.110 UC1.AT10
DDR_B_CLK0: JDIMM2.137 UC1.AM9
DDR_B_CLK1: JDIMM2.138 UC1.AM7
DDR_B_CLK#0: JDIMM2.139 UC1.AN9
DDR_B_CLK#1: JDIMM2.140 UC1.AM8
DDR_B_CS#0: JDIMM2.149 UC1.AF11
DDR_B_CS#1: JDIMM2.157 UC1.AE7
DDR_B_D0: JDIMM2.8 UC1.BT11
DDR_B_D1: JDIMM2.7 UC1.BR11
DDR_B_D2: JDIMM2.16 UC1.BT9
DDR_B_D3: JDIMM2.21 UC1.BR8
DDR_B_D4: JDIMM2.4 UC1.BP11
DDR_B_D5: JDIMM2.3 UC1.BN11
DDR_B_D6: JDIMM2.20 UC1.BP8
DDR_B_D7: JDIMM2.17 UC1.BN8
DDR_B_D8: JDIMM2.24 UC1.BL12
DDR_B_D9: JDIMM2.28 UC1.BL11
DDR_B_D10: JDIMM2.29 UC1.BL8
DDR_B_D11: JDIMM2.41 UC1.BJ8
DDR_B_D12: JDIMM2.38 UC1.BJ11
DDR_B_D13: JDIMM2.37 UC1.BJ10
DDR_B_D14: JDIMM2.25 UC1.BL7
DDR_B_D15: JDIMM2.42 UC1.BJ7
DDR_B_D16: JDIMM2.50 UC1.BG11
DDR_B_D17: JDIMM2.49 UC1.BG10
DDR_B_D18: JDIMM2.45 UC1.BG8
DDR_B_D19: JDIMM2.62 UC1.BF8
DDR_B_D20: JDIMM2.63 UC1.BF11
DDR_B_D21: JDIMM2.59 UC1.BF10
DDR_B_D22: JDIMM2.46 UC1.BG7
DDR_B_D23: JDIMM2.58 UC1.BF7
DDR_B_D24: JDIMM2.84 UC1.BB11
DDR_B_D25: JDIMM2.71 UC1.BC11
DDR_B_D26: JDIMM2.83 UC1.BB8
DDR_B_D27: JDIMM2.67 UC1.BC8
DDR_B_D28: JDIMM2.66 UC1.BC10
DDR_B_D29: JDIMM2.79 UC1.BB10
DDR_B_D30: JDIMM2.70 UC1.BC7
DDR_B_D31: JDIMM2.80 UC1.BB7
DDR_B_D32: JDIMM2.186 UC1.AA11
DDR_B_D33: JDIMM2.182 UC1.AA10
DDR_B_D34: JDIMM2.174 UC1.AC11
DDR_B_D35: JDIMM2.173 UC1.AC10
DDR_B_D36: JDIMM2.187 UC1.AA7
DDR_B_D37: JDIMM2.183 UC1.AA8
DDR_B_D38: JDIMM2.169 UC1.AC8
DDR_B_D39: JDIMM2.170 UC1.AC7
DDR_B_D40: JDIMM2.190 UC1.W8
DDR_B_D41: JDIMM2.194 UC1.W7
DDR_B_D42: JDIMM2.207 UC1.V10
DDR_B_D43: JDIMM2.203 UC1.V11
DDR_B_D44: JDIMM2.191 UC1.W11
DDR_B_D45: JDIMM2.195 UC1.W10
DDR_B_D46: JDIMM2.204 UC1.V7
DDR_B_D47: JDIMM2.208 UC1.V8
DDR_B_D48: JDIMM2.216 UC1.R11
DDR_B_D49: JDIMM2.224 UC1.P11
DDR_B_D50: JDIMM2.228 UC1.P7
DDR_B_D51: JDIMM2.211 UC1.R8
DDR_B_D52: JDIMM2.215 UC1.R10
DDR_B_D53: JDIMM2.229 UC1.P10
DDR_B_D54: JDIMM2.212 UC1.R7
DDR_B_D55: JDIMM2.225 UC1.P8
DDR_B_D56: JDIMM2.250 UC1.L11
DDR_B_D57: JDIMM2.236 UC1.M11
DDR_B_D58: JDIMM2.246 UC1.L7
DDR_B_D59: JDIMM2.232 UC1.M8
DDR_B_D60: JDIMM2.249 UC1.L10
DDR_B_D61: JDIMM2.233 UC1.M10
DDR_B_D62: JDIMM2.237 UC1.M7
DDR_B_D63: JDIMM2.245 UC1.L8
DDR_B_DQS0: JDIMM2.13 UC1.BP9
DDR_B_DQS1: JDIMM2.34 UC1.BJ9
DDR_B_DQS2: JDIMM2.55 UC1.BF9
DDR_B_DQS3: JDIMM2.76 UC1.BB9
DDR_B_DQS4: JDIMM2.179 UC1.AA9
DDR_B_DQS5: JDIMM2.200 UC1.V9
DDR_B_DQS6: JDIMM2.221 UC1.P9
DDR_B_DQS7: JDIMM2.242 UC1.L9
DDR_B_DQS#0: JDIMM2.11 UC1.BN9
DDR_B_DQS#1: JDIMM2.32 UC1.BL9
DDR_B_DQS#2: JDIMM2.53 UC1.BG9
DDR_B_DQS#3: JDIMM2.74 UC1.BC9
DDR_B_DQS#4: JDIMM2.177 UC1.AC9
DDR_B_DQS#5: JDIMM2.198 UC1.W9
DDR_B_DQS#6: JDIMM2.219 UC1.R9
DDR_B_DQS#7: JDIMM2.240 UC1.M9
DDR_B_MA0: JDIMM2.144 UC1.AJ9
DDR_B_MA1: JDIMM2.133 UC1.AK6
DDR_B_MA2: JDIMM2.132 UC1.AK5
DDR_B_MA3: JDIMM2.131 UC1.AL5
DDR_B_MA4: JDIMM2.128 UC1.AL6
DDR_B_MA5: JDIMM2.126 UC1.AM6
DDR_B_MA6: JDIMM2.127 UC1.AN7
DDR_B_MA7: JDIMM2.122 UC1.AN10
DDR_B_MA8: JDIMM2.125 UC1.AN8
DDR_B_MA9: JDIMM2.121 UC1.AR11
DDR_B_MA10: JDIMM2.146 UC1.AH7
DDR_B_MA11: JDIMM2.120 UC1.AN11
DDR_B_MA12: JDIMM2.119 UC1.AR10
DDR_B_MA13: JDIMM2.158 UC1.AF9
DDR_B_MA14_WE#: JDIMM2.151 UC1.AH11
DDR_B_MA15_CAS#: JDIMM2.156 UC1.AF8
DDR_B_MA16_RAS#: JDIMM2.152 UC1.AH10
DDR_B_ODT0: JDIMM2.155 UC1.AF7
DDR_B_ODT1: JDIMM2.161 UC1.AE8
DDR_B_PAR: JDIMM2.143 UC1.AJ7
DDR_DRAMRST#: CD29.1 JDIMM1.108 JDIMM2.108 RD8.2
DDR_VTT_PG_CTRL: UC1.BT13 UC10.2
DEBUG_CTL1: RT66.2 UT4.E4
DEBUG_CTL2: RT67.2 UT4.D5
DGPU_HOLD_RST#: RV58.2 UH1.BB20 UV14.1
DGPU_PEX_RST#: RG546.1 RV39.2 RV40.1 RV571.1 RV573.1 RV684.1 UG22.1 UV14.4 UV20.2
DGPU_PEX_RST#_R: RV40.2 UV1.AJ12
DGPU_PRSNT#: RH135.2 UH1.BD38
DGPU_PWR_EN: RG551.1 RH537.1 UH1.AN18
DGPU_PWROK: PRW18.2 PUW01.13 RH676.2 UG25.1 UH1.AV16 UV19.2
DIFFOUT_2PH: PRZ45.1 PRZ46.2 PUZ01.35
DIFFOUT_4PH: PCZ14.2 PRZ30.2 PUZ01.4
DIMM_CHA_SA0: JDIMM1.256 RD1.2 RD4.1
DIMM_CHA_SA1: JDIMM1.260 RD2.2 RD5.1
DIMM_CHA_SA2: JDIMM1.166 RD3.2 RD6.1
DIMM_CHB_SA0: JDIMM2.256 RD13.2 RD16.1
DIMM_CHB_SA1: JDIMM2.260 RD14.2 RD17.1
DIMM_CHB_SA2: JDIMM2.166 RD15.2 RD18.1
DMI_CRX_PTX_N0: UC1.E8 UH1.C33
DMI_CRX_PTX_N1: UC1.F6 UH1.C32
DMI_CRX_PTX_N2: UC1.E5 UH1.C31
DMI_CRX_PTX_N3: UC1.J9 UH1.C29
DMI_CRX_PTX_P0: UC1.D8 UH1.B33
DMI_CRX_PTX_P1: UC1.E6 UH1.B32
DMI_CRX_PTX_P2: UC1.D5 UH1.B31
DMI_CRX_PTX_P3: UC1.J8 UH1.B29
DMI_CTX_PRX_N0: UC1.A8 UH1.K34
DMI_CTX_PRX_N1: UC1.B6 UH1.G33
DMI_CTX_PRX_N2: UC1.A5 UH1.K32
DMI_CTX_PRX_N3: UC1.B4 UH1.G30
DMI_CTX_PRX_P0: UC1.B8 UH1.J35
DMI_CTX_PRX_P1: UC1.C6 UH1.F34
DMI_CTX_PRX_P2: UC1.B5 UH1.J32
DMI_CTX_PRX_P3: UC1.D4 UH1.F30
DMIC_CLK: L5.2 UA1.3
DMIC_CLK_EDP: CA9.1 JEDP1.31 L5.1
DMIC_DATA: RA42.2 UA1.2
DMIC_DATA_EDP: CA40.1 JEDP1.30 RA42.1
DP_RCOMP: RC1.1 UC1.D37
DPSNK1_DDC_CLK: RPT1.8 UT1.Y5
DPSNK1_DDC_DATA: RPT1.7 UT1.R4
DPSNK_RBIAS: RT19.1 UT1.Y18
DPSRC_RBIAS: RT5.1 UT1.N6
DRVON: PUA01.16 PUG01.16 PUI01.16 PUI02.16 PUI03.16 PUI04.16 PUZ01.17
EC_AC_BAT#: DV11.2 PQ20.1 RV60.1 UV1.N3
EC_AGND: CE1.2 CE2.2 CE21.2 CE25.2 CE30.2 RE4.1 RE6.1 RE50.2 UE1.112
EC_MUTE#: RA8.2 RE28.2 UA1.40
EC_RX_R: JWLAN1.40 RW26.2
EC_TX_R: JWLAN1.38 RW25.2
EDP_AUXN: C10.1 UC1.B26
EDP_AUXN_C: C10.2 JEDP1.16
EDP_AUXP: C11.1 UC1.C26
EDP_AUXP_C: C11.2 JEDP1.15
EDP_BKLT_CTRL: D3.2 R8.2 R9.2
EDP_DISP_UTIL: TC1.1(TP-1) UC1.A33
EDP_HPD: JEDP1.12 RH656.1 RP1.6
EDP_HPD_R: RH656.2 UH1.AN6
EDP_SW: T4937.1(TP-1) UH1.BB24
EDP_TXN0: C6.1 UC1.E29
EDP_TXN0_C: C6.2 JEDP1.18
EDP_TXN1: C8.1 UC1.E28
EDP_TXN1_C: C8.2 JEDP1.21
EDP_TXP0: C7.1 UC1.D29
EDP_TXP0_C: C7.2 JEDP1.19
EDP_TXP1: C9.1 UC1.F28
EDP_TXP1_C: C9.2 JEDP1.22
EDP_VDD_EN: D4.2 UH1.AV44
EN_0.6VSP: PCM16.1 PRM09.2 PUM01.7
EN_1.0VS_VGAP: PC1008.1 PR1005.2 PR1006.2 PR1007.1 PU1001.5
EN_1.2V: PCM15.1 PRM08.2 PUM01.8
EN_1.8VALW: PC1805.1 PR1801.2 PR1802.1 PR1806.2 PU1801.5
EN_2.5V: PC2503.1 PR2501.2 PU2501.2
EN_3V: PR502.1 PU301.12
EN_5V: PR503.1 PU501.12
EN_+1.05V: PCH09.1 PRH04.2 PRH14.2 PUH01.3
EN_PD_HV_1: PUS02.1 RT164.2
EN_VCCIO: PC908.1 PR903.2 PR904.1 PR913.2 PU901.11
EN_VCCSTG_VCCPLL_OC: PR913.1 RZ49.2 RZ238.2 UC12.4 UZ16.3
ENLDO_3V5V: PR302.1 PR303.1 PU301.11 PU501.11
ESPI_ALERT#: RH578.1 UE1.55 UH1.AW35
ESPI_CLK: CC57.2 RH658.1 UH1.BB36
ESPI_CLK_R: JESPI1.10 RE67.2 RH658.2 UE1.57
ESPI_CS#: JESPI1.7 UE1.58 UH1.BE38
ESPI_IO0: RPH7.8 UH1.BB39
ESPI_IO0_R: JESPI1.3 RPH7.1 UE1.59
ESPI_IO1: RPH7.7 UH1.AW37
ESPI_IO1_R: JESPI1.4 RPH7.2 UE1.60
ESPI_IO2: RPH7.6 UH1.AV37
ESPI_IO2_R: JESPI1.5 RPH7.3 UE1.61
ESPI_IO3: RPH7.5 UH1.BA38
ESPI_IO3_R: JESPI1.6 RPH7.4 UE1.62
ESPI_RESET#: RH743.1 UE1.53 UH1.BF38
FAN1_PWM: Q23.3 RE121.2 UE1.47
FAN1_PWM_OUT: JFAN1.2 Q23.1 RE100.2
FAN1_TACH: CE28.1 CE99.1 DE7.2 RE152.2 UE1.40
FAN1_TACH_D: DE7.1 JFAN1.3 RE82.2
FAN2_PWM: Q24.3 RE122.2 UE1.34
FAN2_PWM_OUT: JFAN2.2 Q24.1 RE101.2
FAN2_TACH: CE100.1 DE9.2 RE153.2 UE1.41
FAN2_TACH_D: DE9.1 JFAN2.3 RE151.2
FB_1.0VS_VGAP: PC1003.2 PR1001.1 PR1004.1 PU1001.6
FB_1.2V: PCM17.1 PRM10.1 PRM11.1 PUM01.6
FB_1.8VALW: PC1807.2 PR1805.1 PR1807.2 PU1801.6
FB_2PH: PCZ23.2 PCZ24.1 PRZ46.1 PRZ47.1 PUZ01.34
FB_4PH: PCZ13.2 PCZ15.2 PRZ28.1 PRZ30.1 PUZ01.5
FB_+1.05V: PRH10.1 PRH13.1 PUH01.4
FB_A_CLK0: RV595.1 UV1.R30 UV6.J12
FB_A_CLK0#: RV594.1 UV1.R31 UV6.J11
FB_A_CLK1: RV597.1 UV1.AB31 UV7.J12
FB_A_CLK1#: RV596.1 UV1.AC31 UV7.J11
FB_A_CMD0: UV1.U30 UV6.G12
FB_A_CMD1: UV1.T31 UV6.H10
FB_A_CMD2: UV1.U29 UV6.H11
FB_A_CMD3: UV1.R34 UV6.K11
FB_A_CMD4: UV1.R33 UV6.K10
FB_A_CMD5: UV1.U32 UV6.L12
FB_A_CMD6: UV1.U33 UV6.K4
FB_A_CMD7: UV1.U28 UV6.K5
FB_A_CMD8: UV1.V28 UV6.J4
FB_A_CMD9: UV1.V29 UV6.J5
FB_A_CMD10: UV1.V30 UV6.H4
FB_A_CMD11: UV1.U34 UV6.H5
FB_A_CMD12: UV1.U31 UV6.G3
FB_A_CMD13: RV108.1 UV1.V34 UV6.J2
FB_A_CMD14: RV95.2 UV1.V33 UV6.J3
FB_A_CMD15: UV1.Y32 UV6.L3
FB_A_CMD16: UV1.AA31 UV7.L12
FB_A_CMD17: UV1.AA29 UV7.K10
FB_A_CMD18: UV1.AA28 UV7.K11
FB_A_CMD19: UV1.AC34 UV7.H11
FB_A_CMD20: UV1.AC33 UV7.H10
FB_A_CMD21: UV1.AA32 UV7.G12
FB_A_CMD22: UV1.AA33 UV7.H4
FB_A_CMD23: UV1.Y28 UV7.H5
FB_A_CMD24: UV1.Y29 UV7.J4
FB_A_CMD25: UV1.W31 UV7.J5
FB_A_CMD26: UV1.Y30 UV7.K4
FB_A_CMD27: UV1.AA34 UV7.K5
FB_A_CMD28: UV1.Y31 UV7.L3
FB_A_CMD29: RV107.1 UV1.Y34 UV7.J2
FB_A_CMD30: RV98.2 UV1.Y33 UV7.J3
FB_A_CMD31: UV1.V31 UV7.G3
FB_A_D0: UV1.L28 UV6.A4
FB_A_D1: UV1.M29 UV6.A2
FB_A_D2: UV1.L29 UV6.B4
FB_A_D3: UV1.M28 UV6.B2
FB_A_D4: UV1.N31 UV6.E4
FB_A_D5: UV1.P29 UV6.E2
FB_A_D6: UV1.R29 UV6.F4
FB_A_D7: UV1.P28 UV6.F2
FB_A_D8: UV1.J28 UV6.A11
FB_A_D9: UV1.H29 UV6.A13
FB_A_D10: UV1.J29 UV6.B11
FB_A_D11: UV1.H28 UV6.B13
FB_A_D12: UV1.G29 UV6.E11
FB_A_D13: UV1.E31 UV6.E13
FB_A_D14: UV1.E32 UV6.F11
FB_A_D15: UV1.F30 UV6.F13
FB_A_D16: UV1.C34 UV6.U11
FB_A_D17: UV1.D32 UV6.U13
FB_A_D18: UV1.B33 UV6.T11
FB_A_D19: UV1.C33 UV6.T13
FB_A_D20: UV1.F33 UV6.N11
FB_A_D21: UV1.F32 UV6.N13
FB_A_D22: UV1.H33 UV6.M11
FB_A_D23: UV1.H32 UV6.M13
FB_A_D24: UV1.P34 UV6.U4
FB_A_D25: UV1.P32 UV6.U2
FB_A_D26: UV1.P31 UV6.T4
FB_A_D27: UV1.P33 UV6.T2
FB_A_D28: UV1.L31 UV6.N4
FB_A_D29: UV1.L34 UV6.N2
FB_A_D30: UV1.L32 UV6.M4
FB_A_D31: UV1.L33 UV6.M2
FB_A_D32: UV1.AG28 UV7.U4
FB_A_D33: UV1.AF29 UV7.U2
FB_A_D34: UV1.AG29 UV7.T4
FB_A_D35: UV1.AF28 UV7.T2
FB_A_D36: UV1.AD30 UV7.N4
FB_A_D37: UV1.AD29 UV7.N2
FB_A_D38: UV1.AC29 UV7.M4
FB_A_D39: UV1.AD28 UV7.M2
FB_A_D40: UV1.AJ29 UV7.U11
FB_A_D41: UV1.AK29 UV7.U13
FB_A_D42: UV1.AJ30 UV7.T11
FB_A_D43: UV1.AK28 UV7.T13
FB_A_D44: UV1.AM29 UV7.N11
FB_A_D45: UV1.AM31 UV7.N13
FB_A_D46: UV1.AN29 UV7.M11
FB_A_D47: UV1.AM30 UV7.M13
FB_A_D48: UV1.AN31 UV7.A11
FB_A_D49: UV1.AN32 UV7.A13
FB_A_D50: UV1.AP30 UV7.B11
FB_A_D51: UV1.AP32 UV7.B13
FB_A_D52: UV1.AM33 UV7.E11
FB_A_D53: UV1.AL31 UV7.E13
FB_A_D54: UV1.AK33 UV7.F11
FB_A_D55: UV1.AK32 UV7.F13
FB_A_D56: UV1.AD34 UV7.A4
FB_A_D57: UV1.AD32 UV7.A2
FB_A_D58: UV1.AC30 UV7.B4
FB_A_D59: UV1.AD33 UV7.B2
FB_A_D60: UV1.AF31 UV7.E4
FB_A_D61: UV1.AG34 UV7.E2
FB_A_D62: UV1.AG32 UV7.F4
FB_A_D63: UV1.AG33 UV7.F2
FB_A_DBI0: UV1.P30 UV6.D2
FB_A_DBI1: UV1.F31 UV6.D13
FB_A_DBI2: UV1.F34 UV6.P13
FB_A_DBI3: UV1.M32 UV6.P2
FB_A_DBI4: UV1.AD31 UV7.P2
FB_A_DBI5: UV1.AL29 UV7.P13
FB_A_DBI6: UV1.AM32 UV7.D13
FB_A_DBI7: UV1.AF34 UV7.D2
FB_A_EDC0: UV1.M31 UV6.C2
FB_A_EDC1: UV1.G31 UV6.C13
FB_A_EDC2: UV1.E33 UV6.R13
FB_A_EDC3: UV1.M33 UV6.R2
FB_A_EDC4: UV1.AE31 UV7.R2
FB_A_EDC5: UV1.AK30 UV7.R13
FB_A_EDC6: UV1.AN33 UV7.C13
FB_A_EDC7: UV1.AF33 UV7.C2
FB_A_WCK0: UV1.K31 UV6.D4
FB_A_WCK1: UV1.H34 UV6.P4
FB_A_WCK2: UV1.AG30 UV7.P4
FB_A_WCK3: UV1.AJ34 UV7.D4
FB_A_WCK#0: UV1.L30 UV6.D5
FB_A_WCK#1: UV1.J34 UV6.P5
FB_A_WCK#2: UV1.AG31 UV7.P5
FB_A_WCK#3: UV1.AK34 UV7.D5
FB_B_CLK0: RV599.1 UV1.D12 UV8.J12
FB_B_CLK0#: RV598.1 UV1.E12 UV8.J11
FB_B_CLK1: RV601.1 UV1.E20 UV9.J12
FB_B_CLK1#: RV600.1 UV1.F20 UV9.J11
FB_B_CMD0: UV1.D13 UV8.G12
FB_B_CMD1: UV1.E14 UV8.H10
FB_B_CMD2: UV1.F14 UV8.H11
FB_B_CMD3: UV1.A12 UV8.K11
FB_B_CMD4: UV1.B12 UV8.K10
FB_B_CMD5: UV1.C14 UV8.L12
FB_B_CMD6: UV1.B14 UV8.K4
FB_B_CMD7: UV1.G15 UV8.K5
FB_B_CMD8: UV1.F15 UV8.J4
FB_B_CMD9: UV1.E15 UV8.J5
FB_B_CMD10: UV1.D15 UV8.H4
FB_B_CMD11: UV1.A14 UV8.H5
FB_B_CMD12: UV1.D14 UV8.G3
FB_B_CMD13: RV111.1 UV1.A15 UV8.J2
FB_B_CMD14: RV96.2 UV1.B15 UV8.J3
FB_B_CMD15: UV1.C17 UV8.L3
FB_B_CMD16: UV1.D18 UV9.L12
FB_B_CMD17: UV1.E18 UV9.K10
FB_B_CMD18: UV1.F18 UV9.K11
FB_B_CMD19: UV1.A20 UV9.H11
FB_B_CMD20: UV1.B20 UV9.H10
FB_B_CMD21: UV1.C18 UV9.G12
FB_B_CMD22: UV1.B18 UV9.H4
FB_B_CMD23: UV1.G18 UV9.H5
FB_B_CMD24: UV1.G17 UV9.J4
FB_B_CMD25: UV1.F17 UV9.J5
FB_B_CMD26: UV1.D16 UV9.K4
FB_B_CMD27: UV1.A18 UV9.K5
FB_B_CMD28: UV1.D17 UV9.L3
FB_B_CMD29: RV110.1 UV1.A17 UV9.J2
FB_B_CMD30: RV99.2 UV1.B17 UV9.J3
FB_B_CMD31: UV1.E17 UV9.G3
FB_B_D0: UV1.G9 UV8.A4
FB_B_D1: UV1.E9 UV8.A2
FB_B_D2: UV1.G8 UV8.B4
FB_B_D3: UV1.F9 UV8.B2
FB_B_D4: UV1.F11 UV8.E4
FB_B_D5: UV1.G11 UV8.E2
FB_B_D6: UV1.F12 UV8.F4
FB_B_D7: UV1.G12 UV8.F2
FB_B_D8: UV1.G6 UV8.A11
FB_B_D9: UV1.F5 UV8.A13
FB_B_D10: UV1.E6 UV8.B11
FB_B_D11: UV1.F6 UV8.B13
FB_B_D12: UV1.F4 UV8.E11
FB_B_D13: UV1.G4 UV8.E13
FB_B_D14: UV1.E2 UV8.F11
FB_B_D15: UV1.F3 UV8.F13
FB_B_D16: UV1.C2 UV8.U11
FB_B_D17: UV1.D4 UV8.U13
FB_B_D18: UV1.D3 UV8.T11
FB_B_D19: UV1.C1 UV8.T13
FB_B_D20: UV1.B3 UV8.N11
FB_B_D21: UV1.C4 UV8.N13
FB_B_D22: UV1.B5 UV8.M11
FB_B_D23: UV1.C5 UV8.M13
FB_B_D24: UV1.A11 UV8.U4
FB_B_D25: UV1.C11 UV8.U2
FB_B_D26: UV1.D11 UV8.T4
FB_B_D27: UV1.B11 UV8.T2
FB_B_D28: UV1.D8 UV8.N4
FB_B_D29: UV1.A8 UV8.N2
FB_B_D30: UV1.C8 UV8.M4
FB_B_D31: UV1.B8 UV8.M2
FB_B_D32: UV1.F24 UV9.U4
FB_B_D33: UV1.G23 UV9.U2
FB_B_D34: UV1.E24 UV9.T4
FB_B_D35: UV1.G24 UV9.T2
FB_B_D36: UV1.D21 UV9.N4
FB_B_D37: UV1.E21 UV9.N2
FB_B_D38: UV1.G21 UV9.M4
FB_B_D39: UV1.F21 UV9.M2
FB_B_D40: UV1.G27 UV9.U11
FB_B_D41: UV1.D27 UV9.U13
FB_B_D42: UV1.G26 UV9.T11
FB_B_D43: UV1.E27 UV9.T13
FB_B_D44: UV1.E29 UV9.N11
FB_B_D45: UV1.F29 UV9.N13
FB_B_D46: UV1.E30 UV9.M11
FB_B_D47: UV1.D30 UV9.M13
FB_B_D48: UV1.A32 UV9.A11
FB_B_D49: UV1.C31 UV9.A13
FB_B_D50: UV1.C32 UV9.B11
FB_B_D51: UV1.B32 UV9.B13
FB_B_D52: UV1.D29 UV9.E11
FB_B_D53: UV1.A29 UV9.E13
FB_B_D54: UV1.C29 UV9.F11
FB_B_D55: UV1.B29 UV9.F13
FB_B_D56: UV1.B21 UV9.A4
FB_B_D57: UV1.C23 UV9.A2
FB_B_D58: UV1.A21 UV9.B4
FB_B_D59: UV1.C21 UV9.B2
FB_B_D60: UV1.B24 UV9.E4
FB_B_D61: UV1.C24 UV9.E2
FB_B_D62: UV1.B26 UV9.F4
FB_B_D63: UV1.C26 UV9.F2
FB_B_DBI0: UV1.E11 UV8.D2
FB_B_DBI1: UV1.E3 UV8.D13
FB_B_DBI2: UV1.A3 UV8.P13
FB_B_DBI3: UV1.C9 UV8.P2
FB_B_DBI4: UV1.F23 UV9.P2
FB_B_DBI5: UV1.F27 UV9.P13
FB_B_DBI6: UV1.C30 UV9.D13
FB_B_DBI7: UV1.A24 UV9.D2
FB_B_EDC0: UV1.D10 UV8.C2
FB_B_EDC1: UV1.D5 UV8.C13
FB_B_EDC2: UV1.C3 UV8.R13
FB_B_EDC3: UV1.B9 UV8.R2
FB_B_EDC4: UV1.E23 UV9.R2
FB_B_EDC5: UV1.E28 UV9.R13
FB_B_EDC6: UV1.B30 UV9.C13
FB_B_EDC7: UV1.A23 UV9.C2
FB_B_WCK0: UV1.F8 UV8.D4
FB_B_WCK1: UV1.A5 UV8.P4
FB_B_WCK2: UV1.D24 UV9.P4
FB_B_WCK3: UV1.B27 UV9.D4
FB_B_WCK#0: UV1.E8 UV8.D5
FB_B_WCK#1: UV1.A6 UV8.P5
FB_B_WCK#2: UV1.D25 UV9.P5
FB_B_WCK#3: UV1.C27 UV9.D5
FB_VCCIO: PC912.2 PR909.2 PR910.1 PU901.14
FB_VCCIO_SENSE: PR908.2 PR909.1 PR911.1
FBVDD/Q_EN: PRW06.1 QG506.2 RG557.1 UG27.4
FBVDDQ_SENSE: PRW19.2 UV1.F1
FFS_INT1: RH728.2 UH1.AW26 US1.12
FFS_INT2: QS1.2 RH680.2 UH1.BF18 US1.11
FFS_INT2_Q: JHDD.9 QS1.3 RS4.2
FPR_SCAN#: JFP.2 RE85.2 RE156.1 RF1.1
GC6_EVENT#_D: DV9.2 RV42.1 UV1.L6
GC6_THM_DIS#: RH573.1 UE1.23 UH1.BC33
GPD_7: RH12.2 RH705.1 UH1.BE41
GPP_H12: RH727.1 UH1.AB47
GPP_H15: RH726.1 UH1.AC47
GPP_J9: RH93.1 UH1.AU9
GPPJ_RCOMP_1P8: RH666.1 UH1.BD1 UH1.BE1 UH1.BE2
GPU_EVENT#: DV9.1 UH1.BB26
GPU_GC6_FB_EN: QV10.5 RV37.1 UV1.M3
GPU_GC6_FB_EN_H: QV10.6 RG51.2 RG553.1 UG27.1 UH1.BF29
GPU_HPD_RT: RG575.2 RP45.2 UV20.1
GPU_ID1: RH551.2 RH552.1 UH1.AW18
GPU_ID2: RH553.2 RH554.1 UH1.AV18
GPU_JTAG_TCK: T98.1(TP-1) UV1.AM10
GPU_JTAG_TDI: T99.1(TP-1) UV1.AM11
GPU_JTAG_TDO: T100.1(TP-1) UV1.AP12
GPU_JTAG_TMS: T101.1(TP-1) UV1.AP11
GPU_JTAG_TRST#: RV63.1 UV1.AN11
GPU_PEX_RST_HOLD#: RV41.1 UV1.T8
GPU_PWR_EN: RG551.2 UG25.2 UG31.1
GPU_PWR_LEVEL: DV11.1 UE1.10
GPU_THM_SMBCLK: Q11.3 QV1.3 RE11.1 UE1.12 UH1.BF27
GPU_THM_SMBDAT: Q11.6 QV1.6 RE10.1 UE1.11 UH1.BE27
GSYNC_ID: RH29.1 RH30.1 UH1.BE17
GT_SW1: PLG01.1 PRG04.1 PUG01.11 PUG01.12
H_CPUPWRGD: UC1.BT31 UH1.AE3
H_DRAMRST#: RD7.2 RD8.1 UH1.BB46
H_PECI: RE23.1 UE1.94
H_PLTRST_CPU#: UC1.BP35 UH1.AG5
H_PM_DOWN: RC22.1 RH14.2 UH1.AE2
H_PM_DOWN_R: RC22.2 UC1.BP31
H_PM_SYNC_PCH: RH13.1 UH1.AF3
H_PM_SYNC_R: RH13.2 UC1.BM34
H_PROCHOT#: CE26.1 PQ11.1 PQ12.3 PQS10.3 PRB19.1 PRZ20.2 PRZ24.2 RC262.2 RC268.1 UE2.4
H_PROCHOT#_R: CH211.1 RC268.2 UC1.BR30
H_THERMTRIP#: RC45.1 RC46.1 RH79.2
H_THERMTRIP#_C: RC45.2 UC1.J31
H_THERMTRIP#_R: RH79.1 UH1.AD3
H_VCCST_PWRGD: CH210.1 RC20.1 RC269.1 UC16.4
HDA_CODEC_SDIN0: RA7.2 UA1.7
HDD_DET#: T4940.1(TP-1) UH1.BE19
HDD_DEVSLP: RS1.1 UH1.AL48
HDD_DEVSLP_R: JHDD.8 RS1.2
HDD_EN_PCH: RH687.1 RH699.1 US2.4
HDD_EN_PCH_H: RH699.2 UH1.BD17
HDMI_CEC: CV601.2 JHDMI1.13 RP11.2
HDMI_CLKN: CP23.2 LV3.4 RV641.1 UP2.13
HDMI_CLKP: CP23.1 LV3.1 RV640.1 UP2.14
HDMI_CTRL_CLK: JHDMI1.15 RV681.2 UP2.7
HDMI_CTRL_DAT: JHDMI1.16 RV680.2 UP2.8
HDMI_HPD: CV599.2 CX2.1 JHDMI1.19 RX6.2 UP2.21
HDMI_HPD_PCH: QX3.3 RX8.1 UH1.AW24
HDMI_L_CLKN: JHDMI1.12 RV673.2
HDMI_L_CLKP: JHDMI1.10 RV675.2
HDMI_L_TX_N0: JHDMI1.9 RV674.2
HDMI_L_TX_N1: JHDMI1.6 RV29.2
HDMI_L_TX_N2: JHDMI1.3 RV33.2
HDMI_L_TX_P0: JHDMI1.7 RV28.2
HDMI_L_TX_P1: JHDMI1.4 RV30.2
HDMI_L_TX_P2: JHDMI1.1 RV34.2
HDMI_RESERVED: CV600.2 JHDMI1.14
HDMI_TX_N0: LV4.4 RV643.1 UP2.16
HDMI_TX_N1: LV5.4 RV642.1 UP2.19
HDMI_TX_N2: LV6.4 RV645.1 UP2.22
HDMI_TX_P0: LV4.1 RV646.1 UP2.17
HDMI_TX_P1: LV5.1 RV639.1 UP2.20
HDMI_TX_P2: LV6.1 RV638.1 UP2.23
HOST_DEBUG_TX: JDEG1.8 RE57.2 RW15.2 UE1.81
HPD_IFPC: QG10.1 RV682.1 UV1.U3
HPOUT_L: CA35.1 DA4.2 JHP1.1 LA2.2 RA30.1
HPOUT_R: CA34.1 DA4.3 JHP1.2 LA3.2 RA34.1
HV_GATE1_A: RT64.1 UT4.B9
HV_GATE2_A: RT65.1 UT4.A9
HW_ACAV_IN: CE32.2 DH1.1 PR31.1 PRB42.2 PUS02.2 RH749.1 UE1.128
HW_ACAVIN_NB: PQS22.2 PR46.1 PR52.1 PRB40.1 PRS23.1 PRS39.2 PRS40.1 PRS51.1
HW_ACAVIN_NB_EC: CE34.2 PQS22.3 PRS50.2 UE1.24
I2C1_SCL_TCH_PAD: Q10.1 R34.2 UH1.BE21
I2C1_SDA_TCH_PAD: Q10.4 R33.2 UH1.BF21
I2C_SCL_TP: JTP.6 Q10.6 R46.2
I2C_SDA_TP: JTP.7 Q10.3 R47.2
I2CB_SCL: RV512.1 UV1.R7
I2CB_SDA: RV513.1 UV1.R6
I2CC_SCL_R: RV514.1 UV1.R2
I2CC_SDA_R: RV515.1 UV1.R3
I_ADP: CE25.1 RE51.1 UE1.110
I_ADP_R: PRB35.2 RE51.2
I_BATT: CE30.1 RE54.1 UE1.114
I_BATT_R: PRB34.2 PRB59.1 RE54.2
ICSP_CLK: RE60.2 UE1.101
ICSP_CLR: RE61.2 UE1.87
ICSP_DAT: RE63.2 UE1.102
IFP_IOVDD: CG48.1 CG310.1 RV655.2 UV1.AC7 UV1.AC8 UV1.AF6 UV1.AG6 UV1.AG8 UV1.AG9
IFPC_CLK_CN: CP22.2 UP2.48
IFPC_CLK_CP: CP21.2 UP2.47
IFPC_CLK_N: CP22.1 UV1.AG4
IFPC_CLK_P: CP21.1 UV1.AG5
IFPC_I2C_8409_CLK: RP9.2 RP25.1 UP2.34
IFPC_I2C_8409_DAT: RP10.2 RP24.1 UP2.33
IFPC_I2C_CLK: QV96.4 RV679.2 UV1.AG3
IFPC_I2C_CLK_R: QV96.3 RP9.1 RV677.2 RV681.1
IFPC_I2C_DAT: QV96.1 RV678.2 UV1.AG2
IFPC_I2C_DAT_R: QV96.6 RP10.1 RV676.2 RV680.1
IFPC_TX0_CN: CP20.2 UP2.45
IFPC_TX0_CP: CP19.2 UP2.44
IFPC_TX0_N: CP20.1 UV1.AH4
IFPC_TX0_P: CP19.1 UV1.AH3
IFPC_TX1_CN: CP18.2 UP2.42
IFPC_TX1_CP: CP17.2 UP2.41
IFPC_TX1_N: CP18.1 UV1.AJ2
IFPC_TX1_P: CP17.1 UV1.AJ3
IFPC_TX2_CN: CP16.2 UP2.39
IFPC_TX2_CP: CP15.2 UP2.38
IFPC_TX2_N: CP16.1 UV1.AJ1
IFPC_TX2_P: CP15.1 UV1.AK1
IFPCD_RSET: RG37.1 UV1.AF8
ILIM_1PH: PCZ09.2 PRZ15.1 PUZ01.49
ILIM_2PH: PRZ48.1 PUZ01.32
ILIM_4PH: PRZ32.2 PUZ01.7
ILMT_VCCIO: PR905.1 PR906.2 PU901.13
IMON_1PH: PCZ08.2 PRZ14.2 PUZ01.46
IMVP_VR_ON: CE31.1 RE16.1 RE158.1 UZ21.1
IMVP_VR_PG: PRZ17.2 PUZ01.45 UH14.1
INT_TP#: JTP.4 Q9.3 R39.2
INTRUDER#: RH531.1 UH1.BB44
IR_CAM_DETECT#: JEDP1.26 TC103.1(TP-1)
ISOLATE#: RL3.2 RL4.1 UL1.20
JACK_PLUG: DA7.3 JHP1.5 RA10.1
JACK_PLUG_DET: DA7.2 JHP1.6 RA40.1
JTAG_CLK: JDEG1.4 RPE7.3
JTAG_TDI: JDEG1.2 RE60.1 RPE7.1
JTAG_TDO: JDEG1.5 RE63.1 RPE7.4
JTAG_TMS: JDEG1.3 RE61.1 RPE7.2
KB_BL_CTRL#: C149.1 JKBBL.4 Q8.1
KB_DET#: JKB.1 RH128.1 UH1.BE34
KB_LED_BL_DET: R26.1 R27.1 UH1.BD8
KB_LED_DET_C: JKBBL.2 R26.2
KB_LED_PWM: Q8.2 UE1.44
KSI0: JKB.9 RPE1.4 UE1.98
KSI1: JKB.7 RPE1.3 UE1.99
KSI2: JKB.5 RPE1.2 UE1.6
KSI3: JKB.8 RPE1.1 UE1.7
KSI4: JKB.4 RPE2.1 UE1.104
KSI5: JKB.6 RPE2.2 UE1.105
KSI6: JKB.3 RPE2.3 UE1.107
KSI7: JKB.2 RPE2.4 UE1.108
KSO0: JKB.18 RPE3.8 UE1.2
KSO1: JKB.16 RPE3.7 UE1.14
KSO2: JKB.17 RPE3.6 UE1.15
KSO3: JKB.15 RPE3.5 UE1.16
KSO4: JKB.11 RPE4.8 UE1.37
KSO5: JKB.10 RPE4.7 UE1.38
KSO6: JKB.13 RPE4.6 UE1.39
KSO7: JKB.12 RPE4.5 UE1.50
KSO8: JKB.14 RPE6.8 UE1.46
KSO9: JKB.24 RE15.1 UE1.68
KSO10: JKB.26 RPE5.8 UE1.72
KSO11: JKB.25 RPE5.7 UE1.74
KSO12: JKB.19 RPE5.6 UE1.75
KSO13: JKB.22 RPE5.5 UE1.76
KSO14: JKB.23 RPE6.6 UE1.77
KSO15: JKB.21 RPE6.7 UE1.86
KSO16: JKB.20 RPE6.5 UE1.92
L_BKLT_CTRL: R8.1 UH1.AU48
LAN_MDIN0: TL1.2 UL1.2
LAN_MDIN1: TL1.6 UL1.5
LAN_MDIN2: TL1.8 UL1.7
LAN_MDIN3: TL1.12 UL1.10
LAN_MDIP0: TL1.1 UL1.1
LAN_MDIP1: TL1.5 UL1.4
LAN_MDIP2: TL1.7 UL1.6
LAN_MDIP3: TL1.11 UL1.9
LAN_WAKE#: RH11.2 RH545.1 UH1.BG44
LANWAKE#: RH11.1 UE1.35
LANXIN: RL8.2 UL1.28
LANXIN_R: CL10.1 RL8.1 YL1.1
LANXOUT: RL9.2 UL1.29
LANXOUT_R: CL11.1 RL9.1 YL1.3
LCD_BRIGHTNESS: JEDP1.27 RP2.2
LCD_CBL_DET#: JEDP1.14 TC104.1(TP-1)
LCD_TST: D3.3 RP2.6 UE1.26
LCD_TST_C: JEDP1.10 RP2.3
LCD_VCC_TEST_EN: D4.3 UE1.113
LCDVDD_EN: D4.1 R10.1 U1.4
LDO1_CAP: CA20.2 RA41.2 UA1.21
LDO2_CAP: CA21.2 UA1.32
LDO3_CAP: CA22.2 UA1.6
LED0: T47.1(TP-1) UL1.27
LED1: T45.1(TP-1) UL1.25
LG1_CHG: PQB01.6 PQB07.6 PUB01.9
LG2_CHG: PCB57.2 PQB02.6 PUB01.7
LG_1.2V: PQM01.8 PUM01.15
LG_+1.05V: PQH01.6 PUH01.6
LID_CL_SIO#: CE19.1 D5.1 R22.1 RE25.2 UE1.66
LID_CLOSE#: CC300.1 JIOB1.18 R22.2
LINE1-L_C: CA32.2 RA28.1
LINE1-L_R: CA33.2 RA32.1
LINE1_L: CA32.1 UA1.18
LINE1_R: CA33.1 UA1.17
LM393_P: PCB44.2 PCS01.2 PDS01.1 PR50.1 PRB37.2 PUB02.5 PUS01.8
LOM_TCT: CL12.1 TL1.3 TL1.4 TL1.9 TL1.10
LX1_CHG: PCB25.2 PLB01.1 PQB01.7 PQB07.7 PRB17.1 PUB01.10
LX2_CHG: PRB15.2 PRB46.2 PUB01.6
LX2P_CHG: PJPB06.2 PLB01.2 PQB02.7 PRB18.1 PRB46.1
LX_1.0VS_VGAP: PL1001.1 PR1003.1 PU1001.2 PU1001.3
LX_1.2V: PCM12.2 PLM01.2 PQM01.9 PRM01.1 PUM01.16
LX_1.8VALW: PL1801.1 PR1804.1 PU1801.2 PU1801.3
LX_3V: PC307.2 PL301.1 PR305.1 PU301.6 PU301.19 PU301.20
LX_5V: PC507.2 PL501.1 PR505.1 PU501.6 PU501.19 PU501.20
LX_+1.05V: PCH08.2 PLH01.1 PQH01.7 PRH06.1 PUH01.8
LX_VCCIO: PC907.2 PL901.1 PR907.1 PU901.6 PU901.19 PU901.20
M2_SSD_DETECT: JSSD1.69 RS2.1 UH1.AJ43
MASK_SATA_LED#: Q22.2 RC224.1 UE1.56
MCT: CL13.1 RL14.1 RL15.1 RL19.1 RL20.1
MCT0: RL14.2 TL1.15
MCT1: RL15.2 TL1.16
MCT2: RL19.2 TL1.21
MCT3: RL20.2 TL1.22
ME_FWP: RE19.1 RH16.1 UE1.80
ME_SUS_PWR_ACK: RH506.1 UH1.BC37
MEC_XTAL1: CE3.1 RE47.2 YE1.1
MEC_XTAL1_R: RE47.1 UE1.123
MEC_XTAL2: CE4.1 RE45.1 UE1.125 YE1.2
MEM_VDD_CTL: PRW10.1 UV1.L3
MEM_VREF: QV20.2 QV21.2 RV27.1 UV1.L1
MIC_CAP: CA26.1 UA1.15
MODEL_ID: CE1.1 RE3.2 RE4.2 UE1.109
MSCLK: JDEG1.6 RE55.2
MSDATA: JDEG1.7 RE56.2 RE62.1
NB_MUTE#: RE28.1 UE1.119
NC_B4: RT45.1 RT86.2 UT1.B4
NC_B5: RT46.1 UT1.B5
NC_G2: RT47.1 UT1.G2
NCT7718_DXN: C22.2 C23.2 Q14.3 U2.3
NCT7718_DXP: C22.1 C23.1 Q14.1 Q14.2 U2.2
NRB_BIT: RH524.2 UH1.BE30
NV_ALERT#: RV526.1 UV1.M2
NVVDD1_EN: CG442.1 DG7.1 PRV06.2 RG549.2
NVVDD1_PGOOD: DG4.1 PRV10.1 PUV101.38 UV19.1
NVVDD_B+: PCV17.1 PCV18.1 PCV19.1 PCV20.1 PCV21.1 PCV22.1 PCV23.1 PCV24.1 PCV30.1 PCV31.1 PCV32.1 PCV33.1 PCV34.1 PCV35.1 PCV40.1 PCV41.1 PCV42.1 PCV43.1 PCV44.1 PCV45.1 PCV50.1 PCV54.1 PCV55.1 PCV56.1 PCV57.1 PLIV11.2 PUV01.8 PUV01.9 PUV02.8 PUV02.9 PUV03.8 PUV03.9
NVVDD_PSI: PRV08.2 RV574.1 UV1.M7
NVVDD_VID: PRV13.2 UV1.P6
OTGEN/CMIN_CHG: PRB10.1 PRB13.1 PUB01.20
OVERT#: RG9.1 RG576.1 UV1.M1
OVP_TRIP_P1: PQS03.2 UT4.E10
PA_USB2_RBIAS: RT43.1 UT1.H19
PANEL_BKEN_EC: RP2.8 UE1.117
PB_USB2_RBIAS: RT44.1 UT1.F19
PBAT_CHG_SMBCLK: PD5.3 PR42.2 PRB16.1 RE9.1 UE1.9
PBAT_CHG_SMBDAT: PD5.2 PR37.2 PRB14.1 RE8.1 UE1.8
PBAT_PRES#: CE16.1 PC14.1 PD6.2 PQB05.1 PR39.2 PR41.1 PRB25.2 UE1.29
PCH_AZ_BITCLK: RH739.1 RP50.5 UH1.BD11
PCH_AZ_CODEC_BITCLK: RA43.2 RP50.4 UA1.5
PCH_AZ_CODEC_SDIN0: RA7.1 UH1.BE11
PCH_AZ_CODEC_SDOUT: RP50.1 UA1.4
PCH_AZ_CODEC_SYNC: RP50.2 UA1.9
PCH_AZ_RST#: RH746.1 RP50.6 UH1.BE10
PCH_AZ_SDOUT: CH51.2 RH16.2 RP50.8 UH1.BF12
PCH_AZ_SYNC: RP50.7 UH1.BG13
PCH_BATLOW#: RH515.1 RT14.2 UH1.BF44
PCH_CPU_BCLK_N: UC1.A32 UH1.C8
PCH_CPU_BCLK_P: UC1.B31 UH1.B8
PCH_CPU_PCIBCLK_N: UC1.C36 UH1.B6
PCH_CPU_PCIBCLK_P: UC1.D35 UH1.A6
PCH_DPWROK: RH90.2 RH672.2 UH1.AW41
PCH_JTAG_TCK1: RC84.1 TPC3.1(TP-1) UH1.AJ3
PCH_PCIE_WAKE#: RH4.2 RH453.1 UH1.BB47
PCH_PLTRST#: CH222.1 RH742.1 UH1.AV29 UH3.1 UH3.2
PCH_PRIM_EN: PR1806.1 PRH14.1 QH10.2 RC442.2 RZ21.1
PCH_PWROK: RH94.1 UH1.AY42 UH14.4
PCH_RSMRST#: CH212.1 RC86.1 RH503.1 RH672.1 RH700.2 UE1.27
PCH_RSMRST#_R: RH503.2 UH1.BA47
PCH_RTCRST#: CH53.1 CLRP1.1 QH7.1 RH84.2 UH1.BE47
PCH_RTCX1: CH45.1 RH70.1 UH1.BA49 YH1.1
PCH_RTCX2: CH46.1 RH70.2 UH1.BA48 YH1.2
PCH_SATA_LED#: Q27.2 R77.2 RH512.1 UH1.AK48
PCH_SMBCLK: JDIMM1.253 JDIMM2.253 QH4.1 RH463.2 US1.1
PCH_SMBDATA: JDIMM1.254 JDIMM2.254 QH4.4 RH462.2 US1.4
PCH_SPI_CLK: RH104.1 RH708.2 UH4.6 UH15.6
PCH_SPI_CLK_R: RH104.2 RH738.1 RTPM3.1 UH1.AW47
PCH_SPI_CLK_TPM: RTPM3.2 UTPM1.19
PCH_SPI_CS2#: UH1.AT40 UTPM1.20
PCH_SPI_CS#: RH74.2 UH1.AY47 UH4.1 UH15.1
PCH_SPI_HOLD#: RPH5.1 UH4.7 UH15.7
PCH_SPI_HOLD#_R: RH78.2 RH455.2 RPH5.8 UH1.BA46
PCH_SPI_SI: RPH5.3 UH4.5 UH15.5
PCH_SPI_SI_R: RC264.2 RH735.2 RPH5.6 RTPM2.1 UH1.AU41
PCH_SPI_SI_TPM: RTPM2.2 UTPM1.21
PCH_SPI_SO: RPH5.2 UH4.2 UH15.2
PCH_SPI_SO_R: RPH5.7 RTPM1.1 UH1.BA45
PCH_SPI_SO_TPM: RTPM1.2 UTPM1.24
PCH_SPI_WP#: RPH5.4 UH4.3 UH15.3
PCH_SPI_WP#_R: RC249.1 RH75.2 RPH5.5 UH1.AY48
PCH_SRTCRST#: CH52.1 RH83.2 UH1.BD46
PCH_TRIGOUT: RH665.1 UH1.AK3
PCH_TRIGOUT_R: RH665.2 UC1.H23
PCH_XDP_CLK_N: T4938.1(TP-1) UH1.Y3
PCH_XDP_CLK_P: T4939.1(TP-1) UH1.Y4
PCIE_PRX_C_DTX_N14: CL2.1 UL1.18
PCIE_PRX_C_DTX_N21: CT16.2 UT1.V22
PCIE_PRX_C_DTX_N22: CT2.2 UT1.P22
PCIE_PRX_C_DTX_N23: CT108.2 UT1.K22
PCIE_PRX_C_DTX_N24: CT110.2 UT1.F22
PCIE_PRX_C_DTX_P14: CL1.1 UL1.17
PCIE_PRX_C_DTX_P21: CT14.2 UT1.V23
PCIE_PRX_C_DTX_P22: CT12.2 UT1.P23
PCIE_PRX_C_DTX_P23: CT109.2 UT1.K23
PCIE_PRX_C_DTX_P24: CT111.2 UT1.F23
PCIE_PRX_DTX_N9: JSSD1.5 UH1.G36
PCIE_PRX_DTX_N10: JSSD1.17 UH1.K37
PCIE_PRX_DTX_N11: JSSD1.29 UH1.G38
PCIE_PRX_DTX_N12: JSSD1.43 UH1.H42
PCIE_PRX_DTX_N14: CL2.2 UH1.D46
PCIE_PRX_DTX_N15: JWLAN1.43 UH1.F44
PCIE_PRX_DTX_N21: CT16.1 UH1.T43
PCIE_PRX_DTX_N22: CT2.1 UH1.U40
PCIE_PRX_DTX_N23: CT108.1 UH1.W43
PCIE_PRX_DTX_N24: CT110.1 UH1.Y40
PCIE_PRX_DTX_P9: JSSD1.7 UH1.F36
PCIE_PRX_DTX_P10: JSSD1.19 UH1.J37
PCIE_PRX_DTX_P11: JSSD1.31 UH1.F39
PCIE_PRX_DTX_P12: JSSD1.41 UH1.J41
PCIE_PRX_DTX_P14: CL1.2 UH1.C47
PCIE_PRX_DTX_P15: JWLAN1.41 UH1.E45
PCIE_PRX_DTX_P21: CT14.1 UH1.R44
PCIE_PRX_DTX_P22: CT12.1 UH1.U41
PCIE_PRX_DTX_P23: CT109.1 UH1.W44
PCIE_PRX_DTX_P24: CT111.1 UH1.Y41
PCIE_PTX_C_CRX_N23: CT18.2 UT1.M22
PCIE_PTX_C_DRX_N9: CS16.2 JSSD1.11
PCIE_PTX_C_DRX_N10: CS18.2 JSSD1.23
PCIE_PTX_C_DRX_N11: CS20.2 JSSD1.35
PCIE_PTX_C_DRX_N12: CS22.2 JSSD1.47
PCIE_PTX_C_DRX_N14: CL4.1 UL1.14
PCIE_PTX_C_DRX_N15: CW1.2 JWLAN1.37
PCIE_PTX_C_DRX_N21: CT15.2 UT1.Y22
PCIE_PTX_C_DRX_N22: CT13.2 UT1.T22
PCIE_PTX_C_DRX_N24: CT21.2 UT1.H22
PCIE_PTX_C_DRX_P9: CS17.2 JSSD1.13
PCIE_PTX_C_DRX_P10: CS19.2 JSSD1.25
PCIE_PTX_C_DRX_P11: CS21.2 JSSD1.37
PCIE_PTX_C_DRX_P12: CS23.2 JSSD1.49
PCIE_PTX_C_DRX_P14: CL3.1 UL1.13
PCIE_PTX_C_DRX_P15: CW2.2 JWLAN1.35
PCIE_PTX_C_DRX_P21: CT3.2 UT1.Y23
PCIE_PTX_C_DRX_P22: CT1.2 UT1.T23
PCIE_PTX_C_DRX_P23: CT4.2 UT1.M23
PCIE_PTX_C_DRX_P24: CT5.2 UT1.H23
PCIE_PTX_DRX_N9: CS16.1 UH1.C34
PCIE_PTX_DRX_N10: CS18.1 UH1.C35
PCIE_PTX_DRX_N11: CS20.1 UH1.B36
PCIE_PTX_DRX_N12: CS22.1 UH1.D38
PCIE_PTX_DRX_N14: CL4.2 UH1.C39
PCIE_PTX_DRX_N15: CW2.1 UH1.B40
PCIE_PTX_DRX_N21: CT15.1 UH1.G47
PCIE_PTX_DRX_N22: CT13.1 UH1.H47
PCIE_PTX_DRX_N23: CT18.1 UH1.G49
PCIE_PTX_DRX_N24: CT21.1 UH1.G46
PCIE_PTX_DRX_P9: CS17.1 UH1.D34
PCIE_PTX_DRX_P10: CS19.1 UH1.B35
PCIE_PTX_DRX_P11: CS21.1 UH1.C36
PCIE_PTX_DRX_P12: CS23.1 UH1.E37
PCIE_PTX_DRX_P14: CL3.2 UH1.D39
PCIE_PTX_DRX_P15: CW1.1 UH1.C40
PCIE_PTX_DRX_P21: CT3.1 UH1.F46
PCIE_PTX_DRX_P22: CT1.1 UH1.H48
PCIE_PTX_DRX_P23: CT4.1 UH1.G48
PCIE_PTX_DRX_P24: CT5.1 UH1.G45
PCIE_RBIAS: RT3.1 UT1.N16
PCIE_RCOMPN: RH669.1 UH1.B12
PCIE_RCOMPP: RH669.2 UH1.A13
PCIE_WAKE#: RH4.1 RS10.2 RT10.2 RW31.1 UE1.4 UL1.21
PCIE_WAKE#_R: JWLAN1.55 RW31.2
PCIE_WAKE#_SSD_R: JSSD1.54 RS10.1
PD_EE_CLK: RT123.1 UT4.A3
PD_EE_CLK_R: RT123.2 RT156.2 UT3.6
PD_EE_CS_N: RT126.1 UT3.1 UT4.B3
PD_EE_DI: UT3.5 UT4.B4
PD_EE_DO: RT125.1 UT3.2 UT4.A4
PD_EE_HOLD#: RT128.1 UT3.7
PD_EE_WP#: RT127.1 UT3.3
PD_I2C_INT#: RT120.1 UT4.B6
PD_I2C_SCL_R: RT57.2 RT60.2 RT118.2 UT4.B5
PD_I2C_SDA_R: RT58.2 RT59.2 RT119.2 UT4.A5
PD_UART: RT62.1 UT4.E2 UT4.F2
PECI_EC: DE1.1 RC44.1 RE23.2 RH73.2
PECI_EC_R: RC44.2 UC1.BT34
PECI_PCH: RH73.1 UH1.AF2
PEG_CRX_C_GTX_N0: CV532.1 UV1.AJ14
PEG_CRX_C_GTX_N1: CV534.1 UV1.AG14
PEG_CRX_C_GTX_N2: CV536.1 UV1.AJ15
PEG_CRX_C_GTX_N3: CV538.1 UV1.AK16
PEG_CRX_C_GTX_N4: CV540.1 UV1.AJ17
PEG_CRX_C_GTX_N5: CV542.1 UV1.AG17
PEG_CRX_C_GTX_N6: CV544.1 UV1.AJ18
PEG_CRX_C_GTX_N7: CV546.1 UV1.AK19
PEG_CRX_C_GTX_P0: CV531.1 UV1.AK14
PEG_CRX_C_GTX_P1: CV533.1 UV1.AH14
PEG_CRX_C_GTX_P2: CV535.1 UV1.AK15
PEG_CRX_C_GTX_P3: CV537.1 UV1.AL16
PEG_CRX_C_GTX_P4: CV539.1 UV1.AK17
PEG_CRX_C_GTX_P5: CV541.1 UV1.AH17
PEG_CRX_C_GTX_P6: CV543.1 UV1.AK18
PEG_CRX_C_GTX_P7: CV545.1 UV1.AL19
PEG_CRX_GTX_N0: CV532.2 UC1.E10
PEG_CRX_GTX_N1: CV534.2 UC1.E11
PEG_CRX_GTX_N2: CV536.2 UC1.E12
PEG_CRX_GTX_N3: CV538.2 UC1.E13
PEG_CRX_GTX_N4: CV540.2 UC1.E14
PEG_CRX_GTX_N5: CV542.2 UC1.E15
PEG_CRX_GTX_N6: CV544.2 UC1.E16
PEG_CRX_GTX_N7: CV546.2 UC1.E17
PEG_CRX_GTX_P0: CV531.2 UC1.F10
PEG_CRX_GTX_P1: CV533.2 UC1.D11
PEG_CRX_GTX_P2: CV535.2 UC1.F12
PEG_CRX_GTX_P3: CV537.2 UC1.D13
PEG_CRX_GTX_P4: CV539.2 UC1.F14
PEG_CRX_GTX_P5: CV541.2 UC1.D15
PEG_CRX_GTX_P6: CV543.2 UC1.F16
PEG_CRX_GTX_P7: CV545.2 UC1.D17
PEG_CTX_C_GRX_N0: CC2.2 UV1.AM12
PEG_CTX_C_GRX_N1: CC4.2 UV1.AM14
PEG_CTX_C_GRX_N2: CC6.2 UV1.AP15
PEG_CTX_C_GRX_N3: CC8.2 UV1.AM15
PEG_CTX_C_GRX_N4: CC10.2 UV1.AM17
PEG_CTX_C_GRX_N5: CC12.2 UV1.AP18
PEG_CTX_C_GRX_N6: CC14.2 UV1.AM18
PEG_CTX_C_GRX_N7: CC16.2 UV1.AM20
PEG_CTX_C_GRX_P0: CC1.2 UV1.AN12
PEG_CTX_C_GRX_P1: CC3.2 UV1.AN14
PEG_CTX_C_GRX_P2: CC5.2 UV1.AP14
PEG_CTX_C_GRX_P3: CC7.2 UV1.AN15
PEG_CTX_C_GRX_P4: CC9.2 UV1.AN17
PEG_CTX_C_GRX_P5: CC11.2 UV1.AP17
PEG_CTX_C_GRX_P6: CC13.2 UV1.AN18
PEG_CTX_C_GRX_P7: CC15.2 UV1.AN20
PEG_CTX_GRX_N0: CC2.1 UC1.B10
PEG_CTX_GRX_N1: CC4.1 UC1.B11
PEG_CTX_GRX_N2: CC6.1 UC1.B12
PEG_CTX_GRX_N3: CC8.1 UC1.B13
PEG_CTX_GRX_N4: CC10.1 UC1.B14
PEG_CTX_GRX_N5: CC12.1 UC1.B15
PEG_CTX_GRX_N6: CC14.1 UC1.B16
PEG_CTX_GRX_N7: CC16.1 UC1.B17
PEG_CTX_GRX_P0: CC1.1 UC1.C10
PEG_CTX_GRX_P1: CC3.1 UC1.A11
PEG_CTX_GRX_P2: CC5.1 UC1.C12
PEG_CTX_GRX_P3: CC7.1 UC1.A13
PEG_CTX_GRX_P4: CC9.1 UC1.C14
PEG_CTX_GRX_P5: CC11.1 UC1.A15
PEG_CTX_GRX_P6: CC13.1 UC1.C16
PEG_CTX_GRX_P7: CC15.1 UC1.A17
PEG_RCOMP: RC9.2 UC1.G2
PEX_CLKREQ#: QV3.3 RV57.1 UV1.AK12
PEX_TERMP: RV50.2 UV1.AP29
PEX_VDD_EN: PR1005.1 QG505.2 UG31.4
PEX_VDD_EN_U: CG482.1 DG10.2 RG550.2 UG31.2
PIRQA#: RH546.1 UH1.BA36
PLTRST#: JSSD1.50 JWLAN1.52 RE65.1 RH199.1 RT1.2 UH3.4 UL1.19 UTPM1.17 UV14.2
POK: DC2.1 PR35.1 PR304.2 PR504.2 PR1801.1 PU301.9 PU501.9
POWER_SW#_MB: CC299.1 DC1.3 JIOB1.17 RE43.2 SW1.1 TPS10.1(TP-1)
POWER_SW_IN#: CE33.1 RE41.2 RE43.1 RE161.1 UE1.127
PRIM_PWRGD: RE149.2 RE160.2 UE1.30
PRIM_PWRGD_R: PR1803.2 PRH04.1 PU1801.4 RE150.1 RE160.1
PROC_DETECT#: RC277.1 UH1.AP41
PROC_SELECT#: TC97.1(TP-1) UC1.BN1
PROCHOT: RE53.2 UE1.83 UE2.2
PROJECT_ID1: RH557.2 RH681.1 UH1.L48
PROJECT_ID2: RH561.2 RH562.1 UH1.M45
PS_ID: PD2.1 PR1.2 PR5.1 UE1.36
PSID: PJPDC1.1 PL3.1
PSID-1: PQ2.2 PR3.2 PR6.1
PSID-3: PQ1.3 PR1.1
PTP_DIS#: D6.1 UE1.90
PWM1_1PH/ICCMAX1: PRZ18.1 PUA01.1 PUZ01.44
PWM1_2PH/ICCMAX2: PRZ59.1 PUG01.1 PUZ01.23
PWM1_4PH/ICCMAX4: PRZ54.1 PUI01.1 PUZ01.18
PWM2_2PH/ROSC1: PRZ72.1 PUZ01.22
PWM2_4PH/ADDR: PRZ55.1 PUI02.1 PUZ01.19
PWM3_4PH/VBOOT: PRZ56.1 PUI03.1 PUZ01.20
PWM4_4PH/ROSCM: PRZ57.1 PUI04.1 PUZ01.21
PWR_BTN_DOCK1#: Q29.3 RT165.2 RT166.2
PWR_TB_DOCK#: RE161.2 RT167.2
REFCLK_CNV: JWLAN1.64 RH698.1
REFCLK_CNV_H: RH698.2 RH716.1 UH1.R6
RESET_N: RT102.1 UT4.F11
RESET_OUT#: RE158.2 UE1.73
RF_+1.30V: PRH05.1 PUH01.5
RING2: LA1.1 RA25.2 UA1.13
RING2_R: CA36.1 CA42.1 DA5.3 JHP1.4 LA1.2
RJ45_MDIN0: JLAN1.2 TL1.23
RJ45_MDIN1: JLAN1.6 TL1.19
RJ45_MDIN2: JLAN1.5 TL1.17
RJ45_MDIN3: JLAN1.8 TL1.13
RJ45_MDIP0: JLAN1.1 TL1.24
RJ45_MDIP1: JLAN1.3 TL1.20
RJ45_MDIP2: JLAN1.4 TL1.18
RJ45_MDIP3: JLAN1.7 TL1.14
ROM_CS#: T97.1(TP-1) UV1.H6
ROM_SCLK: RV159.1 RV162.2 UV1.H4
ROM_SI: RV157.1 RV160.2 UV1.H5
ROM_SO: RV158.1 RV161.2 UV1.H7
RSET: RL2.2 UL1.31
RTC_DET#: Q1.1 RH734.1 UH1.AV34
RTC_PWR: D1.3 Q1.2 R1.1 R2.1
RTCRST_ON: C61.1 D7.1 Q26.2 QH7.2 R78.2 R79.2 RH679.1 UE1.31
RTD3_CIO_PWR_EN: RT16.2 UH1.Y46
RTD3_CIO_PWR_EN_R: RT16.1 RT36.1 RT152.2 UT1.F1
RTD3_USB_PWR_EN: RT12.2 UH1.Y48
RTD3_USB_PWR_EN_R: RT12.1 RT37.1 RT153.2 UT1.D4
RTM_CSCL: RP48.1 UP2.29
RTM_CSDA: RP49.1 UP2.28
RTM_DCIN_ENB: RP33.2 RP39.2 UP2.3
RTM_EQ: RP34.2 RP40.2 UP2.5
RTM_HDMI_ID: RP37.2 RP43.2 UP2.32
RTM_I2C_ADDR: RP35.2 RP41.2 UP2.31
RTM_PDB: RP44.2 UP2.4
RTM_PRE: RP36.2 RP42.2 UP2.27
RTM_RST#: CP27.1 RP38.2 UP2.35
RUNPWROK: RE42.2 UE1.48
SA_SW: PLA01.1 PRA04.1 PUA01.11 PUA01.12
SATA3_PRX_C_DTX_N0: CS3.2 JHDD.5
SATA3_PRX_C_DTX_P0: CS4.2 JHDD.6
SATA3_PRX_DTX_N0: CS3.1 UH1.C45
SATA3_PRX_DTX_P0: CS4.1 UH1.C46
SATA3_PTX_C_DRX_N0: CS2.2 JHDD.3
SATA3_PTX_C_DRX_P0: CS1.2 JHDD.2
SATA3_PTX_DRX_N0: CS2.1 UH1.B38
SATA3_PTX_DRX_P0: CS1.1 UH1.C38
SATA_LED#_R: Q22.3 Q27.3 R83.2
SD_RCOMP_1P8: RH668.1 UH1.BE5
SD_RCOMP_3P3: RH670.1 UH1.BE4
SIO_EXT_SCI#: RH521.2 UH1.AU26
SIO_EXT_WAKE#: RH721.1 UE1.116 UH1.AW21
SIO_PWRBTN#: RH717.1 UE1.52 UH1.BE46
SIO_SLP_S0#: RE90.2 RH682.2 RTPM11.2 RTPM12.2
SIO_SLP_S0#_PCH: RH682.1 UH1.BC28
SIO_SLP_S3#: DZ2.1 RH683.2 RH740.1 RT15.2 RZ108.1 RZ112.1 RZ237.1 UZ1.3 UZ1.5 UZ21.2
SIO_SLP_S3#_AR: RT15.1 RT30.2 UT1.D2
SIO_SLP_S3#_PCH: RH683.1 UH1.BF42
SIO_SLP_S4#: DZ1.1 PR2501.1 RH684.2 RH741.1 RZ102.1 RZ111.1
SIO_SLP_S4#_PCH: RH684.1 UH1.BE42
SLEEVE: LA4.1 RA26.2 UA1.14
SLEEVE_R: CA37.1 CA41.1 DA5.2 JHP1.3 LA4.2
SM_PG_CTRL: PRM09.1 RC270.2 UC10.4
SM_RCOMP0: RC3.2 UC1.G1
SM_RCOMP1: RC4.2 UC1.H1
SM_RCOMP2: RC5.2 UC1.J2
SMBALERT#: RH66.2 UH1.BE25
SMBCLK: QH4.6 RH674.2 UH1.BE26
SMBDATA: QH4.3 RH675.2 UH1.BF26
SML0_SMBCLK: RH62.2 RH501.2 UH1.BF25
SML0_SMBDATA: RH63.2 RH502.2 UH1.BE24
SML0ALERT#: RH64.2 UH1.BF24
SML1ALERT#: RH65.2 UH1.BD33
SNB_1.0VS_VGAP: PC1004.1 PR1003.2
SNB_VCCIO: PC911.1 PR907.2
SNUB1_CHG: PCB36.1 PRB17.2
SNUB2_CHG: PCB37.1 PRB18.2
SNUB_+1.05V: PCH12.1 PRH06.2
SPKR: DA3.2 RH685.2 UH1.AW29
SSD_DEVSLP: JSSD1.38 RS9.2 UH1.AH35
SSD_LED#: JSSD1.10 R77.1
STRAP0: RV146.1 RV152.2 UV1.J2
STRAP1: RV147.1 RV153.2 UV1.J7
STRAP2: RV148.1 RV154.2 UV1.J6
STRAP3: RV149.1 RV155.2 UV1.J5
STRAP4: RV150.1 RV156.2 UV1.J3
STRAP5: RV66.2 RV593.1 UV1.J1
SUSCLK: RH713.2 RH714.2 UH1.BE45
SUSCLK_EC: RE45.2 RH714.1
SUSCLK_WLAN: JWLAN1.50 RH713.1
SW1_2PH: PLG01.2 PRZ51.2 PRZ60.2
SW1_4PH: PLI01.2 PRZ35.1 PRZ61.1
SW2_4PH: PLI02.2 PRZ36.1 PRZ62.1
SW3_4PH: PLI03.2 PRZ37.1 PRZ63.1
SW4_4PH: PLI04.2 PRZ38.1 PRZ64.1
SW_1PH: PLA01.2 PRZ13.2
SYS_PEX_RST_MON#: RV532.1 UV1.R8
SYS_PWROK: RE68.1 RH673.2 UE1.28 UH1.AU3
SYS_RESET#: CH209.1 RH571.1 RH737.1 UH1.AU2
SYSPWR_PRES: RE29.1 RE32.1 UE1.120
T_CRIT#: R29.2 U2.4
TBT_A_AUX_N: CT44.2 UT1.W15
TBT_A_AUX_N_C: CT44.1 RT70.2 UT4.J2
TBT_A_AUX_P: CT43.2 UT1.Y15
TBT_A_AUX_P_C: CT43.1 RT73.1 UT4.J1
TBT_A_CC1: CT112.1 DT11.2 DT11.8 JUSBC1.B5 UT4.K9 UT4.L9
TBT_A_CC2: CT113.1 DT11.1 DT11.9 JUSBC1.A5 UT4.K10 UT4.L10
TBT_A_SBU1: DT11.4 DT11.7 JUSBC1.B8 UT4.K8
TBT_A_SBU2: DT11.5 DT11.6 JUSBC1.A8 UT4.L8
TBT_A_TRX_DTX_N0: DT5.1 JUSBC1.A10 RT162.1
TBT_A_TRX_DTX_N0_R: RT162.2 UT1.A21
TBT_A_TRX_DTX_N1: DT9.1 JUSBC1.B10 RT160.1
TBT_A_TRX_DTX_N1_R: RT160.2 UT1.B15
TBT_A_TRX_DTX_P0: DT4.1 JUSBC1.A11 RT161.1
TBT_A_TRX_DTX_P0_R: RT161.2 UT1.B21
TBT_A_TRX_DTX_P1: DT8.1 JUSBC1.B11 RT159.1
TBT_A_TRX_DTX_P1_R: RT159.2 UT1.A15
TBT_A_TTX_C_DRX_N0: CT42.1 DT3.1 JUSBC1.B3
TBT_A_TTX_C_DRX_N1: CT40.1 DT7.1 JUSBC1.A3
TBT_A_TTX_C_DRX_P0: CT41.1 DT2.1 JUSBC1.B2
TBT_A_TTX_C_DRX_P1: CT39.1 DT6.1 JUSBC1.A2
TBT_A_TTX_DRX_N0: CT42.2 UT1.B19
TBT_A_TTX_DRX_N1: CT40.2 UT1.B17
TBT_A_TTX_DRX_P0: CT41.2 UT1.A19
TBT_A_TTX_DRX_P1: CT39.2 UT1.A17
TBT_A_USB20_L_NB: DT10.4 DT10.7 JUSBC1.A7 LT3.2
TBT_A_USB20_L_NT: DT10.2 DT10.8 JUSBC1.B7 LT2.3
TBT_A_USB20_L_PB: DT10.5 DT10.6 JUSBC1.A6 LT3.3
TBT_A_USB20_L_PT: DT10.1 DT10.9 JUSBC1.B6 LT2.2
TBT_A_USB20_N: RT131.2 UT1.D20
TBT_A_USB20_NB: LT3.1 UT4.L7
TBT_A_USB20_NT: LT2.4 UT4.L6
TBT_A_USB20_P: RT130.2 UT1.E20
TBT_A_USB20_PB: LT3.4 UT4.K7
TBT_A_USB20_PT: LT2.1 UT4.K6
TBT_CIO_PLUG_EVENT#: RT29.2 UH1.BF8 UT1.W2
TBT_CONFIG: RT112.2 RT113.1 UT4.H6
TBT_EE_CLK: RT101.1 UT1.AB4
TBT_EE_CLK_R: RT101.2 RT157.2 UT2.6
TBT_EE_CS_N: RT50.2 UT1.AC3 UT2.1
TBT_EE_DI: UT1.AB3 UT2.5
TBT_EE_DO: RT49.2 UT1.AC4 UT2.2
TBT_EE_WP_N: RT48.2 UT1.V1 UT2.3
TBT_FORCE_PWR: RT13.2 UH1.Y47
TBT_FORCE_PWR_R: RT13.1 RT35.1 RT94.2 UT1.H4
TBT_HDMI_DDC_CLK: T9.1(TP-1) UT1.Y2
TBT_HDMI_DDC_DATA: T7.1(TP-1) UT1.Y1
TBT_HOLD_N: RT51.2 UT2.7
TBT_I2C_SCL: RT27.2 UT1.U2 UT4.D2
TBT_I2C_SDA: RT26.2 UT1.U1 UT4.D1
TBT_PCIE_WAKE_N: RT10.1 RT28.2 UT1.W1
TBT_RBIAS: RT25.1 UT1.H6
TBT_RESET_N: RT23.1 RT80.1 RT102.2 UT1.F4
TBT_RESET_N_EC#: RT23.2 RT122.2 RT129.1 UE1.97
TBT_RSENSE: RT25.2 UT1.J6
TBT_RST#_R: RT1.1 UT1.L4
TBT_SRC_CFG1: RT11.1 UT1.AA1
TBT_SRC_HPD: RT4.1 UT1.G1
TBT_SVR_IND: LT1.1 UT1.C1 UT1.C2 UT1.D1
TBT_TCK: RT7.2 UT1.T4
TBT_TDI: RT9.2 UT1.Y4
TBT_TDO: RT6.2 UT1.W4
TBT_TEST_EN: RT17.1 UT1.E1
TBT_TEST_PWG: RT18.1 UT1.AB5
TBT_TMS: RT8.2 UT1.V4
TBT_TMU_CLK_OUT: RT34.1 T2.1(TP-1) UT1.V2
TBT_XTAL_25_IN: RT154.1 UT1.D22
TBT_XTAL_25_IN_R: CT37.1 RT154.2 YT1.1
TBT_XTAL_25_OUT: RT155.1 UT1.D23
TBT_XTAL_25_OUT_R: CT38.1 RT155.2 YT1.3
TBTA_DEBUG1: RT71.1 RT118.1 UT4.L2
TBTA_DEBUG2: RT72.1 RT119.1 UT4.K2
TBTA_DIG_AUD_N: RT69.1 RT115.2 UT4.K3
TBTA_DIG_AUD_P: RT68.1 RT114.2 UT4.L3
TBTA_HPD: RPT1.5 UT1.M4 UT4.C10
TBTA_HRESET: RE89.2 RT108.1 UT4.D6
TBTA_I2C_INT: RT32.2 UT1.J4 UT4.C1
TBTA_LDO_BMC: CT98.1 UT4.E1
TBTA_LSRX: RT42.1 RT115.1 UT1.A4 UT4.K4
TBTA_LSTX: RT21.2 RT40.1 RT114.1 UT1.A5 UT4.L4
TBTA_MRESET: RT63.1 RT122.1 UT4.E11
TBTA_ROSC: RT75.1 UT4.G2
TBTB_I2C_INT: RT33.2 UT1.E2
TESTMODE: RV62.1 UV1.AK11
THERMDA: UT1.AB23 UT1.AC23
THM_SML1_CLK: Q11.4 R49.2 U2.8
THM_SML1_DATA: Q11.1 R48.2 U2.7
TON_1.2V: PRM07.2 PUM01.9
TOUCH_SCREEN_PD#: D5.2 R19.2 RH69.1 UH1.AM45
TOUCHPAD_INTR#: DH2.2 RH179.1 UH1.BF32
TP_EN#: R38.1 UE1.49
TP_LOCK#: D6.2 JTP.3 R41.2
TP_WAKE_KBC#: DH2.1 Q9.1 RE14.1 UE1.33
TPM_PIRQ#: RTPM9.2 UH1.BE18 UTPM1.18
TRIP_+1.05V: PRH03.2 PUH01.2
TS_EN: C16.1 JEDP1.39 R19.1
TSENSE_2PH: PCZ31.1 PRZ68.1 PUZ01.25
TSENSE_4PH: PCZ29.1 PRZ66.1 PUZ01.14
TSENSE_PSYS: PRB31.2 PRZ58.1 PUZ01.24
TYPEC_SMBCLK: RE31.1 RT60.1 UE1.91
TYPEC_SMBDA: RE30.1 RT59.1 UE1.89
UART_2_CRXD_DTXD: RH709.1 RW27.2 UH1.BD20
UART_2_CTXD_DRXD: RH710.1 RW28.2 UH1.BE20
UG1_CHG: PQB01.1 PQB07.1 PUB01.11
UG2_CHG: PCB57.1 PQB02.1 PUB01.5
UG_1.2V: PQM01.1 PUM01.17
UG_+1.05V: PQH01.1 PUH01.9
UPD1_ALERT: RE155.2 RT120.2 UE1.32
US2_5VHDD: RS8.1 US2.1
USB2_COMP: RH109.1 UH1.F4
USB2_ID: RH581.1 UH1.G3
USB2_VBUSSENSE: RH580.1 UH1.F3
USB3_PRX_DTX_N1: LU3.3 UH1.D11
USB3_PRX_DTX_N3: LU6.3 UH1.B10
USB3_PRX_DTX_P1: LU3.2 UH1.C11
USB3_PRX_DTX_P3: LU6.2 UH1.C10
USB3_PRX_L_DTX_N1: DU1.1 DU1.9 JUSB1.5 LU3.4
USB3_PRX_L_DTX_N3: DU3.1 DU3.9 JUSB2.5 LU6.4
USB3_PRX_L_DTX_P1: DU1.2 DU1.8 JUSB1.6 LU3.1
USB3_PRX_L_DTX_P3: DU3.2 DU3.8 JUSB2.6 LU6.1
USB3_PTX_C_DRX_N1: CU2.2 LU2.3
USB3_PTX_C_DRX_N3: CU4.2 LU5.3
USB3_PTX_C_DRX_P1: CU1.2 LU2.2
USB3_PTX_C_DRX_P3: CU3.2 LU5.2
USB3_PTX_DRX_N1: CU2.1 UH1.F9
USB3_PTX_DRX_N3: CU4.1 UH1.F11
USB3_PTX_DRX_P1: CU1.1 UH1.F7
USB3_PTX_DRX_P3: CU3.1 UH1.G12
USB3_PTX_L_DRX_N1: DU1.4 DU1.7 JUSB1.8 LU2.4
USB3_PTX_L_DRX_N3: DU3.4 DU3.7 JUSB2.8 LU5.4
USB3_PTX_L_DRX_P1: DU1.5 DU1.6 JUSB1.9 LU2.1
USB3_PTX_L_DRX_P3: DU3.5 DU3.6 JUSB2.9 LU5.1
USB20_N1: LU1.2 UH1.J3
USB20_N1_R: DU2.3 JUSB1.2 LU1.1
USB20_N2: LU9.3 UH1.N13
USB20_N2_R: JIOB1.7 LU9.4
USB20_N3: LU4.2 UH1.K4
USB20_N3_R: DU4.3 JUSB2.2 LU4.1
USB20_N4: RT133.1 UH1.M10
USB20_N4_R: RT131.1 RT133.2 UT4.K5
USB20_N5: L3.4 UH1.M1
USB20_N5_R: JEDP1.33 L3.3
USB20_N6: LU8.3 UH1.K7
USB20_N6_R: JIOB1.4 LU8.4
USB20_N7: JWLAN1.5 UH1.L4
USB20_N8: L4.4 R21.2 UH1.G4
USB20_N8_R: DA6.2 JEDP1.36 L4.3 R21.1
USB20_N9: DF1.3 JFP.6 UH1.M6
USB20_N11: TH145.1(TP-1) UH1.R10
USB20_N14: TH142.1(TP-1) UH1.E5
USB20_P1: LU1.3 UH1.J2
USB20_P1_R: DU2.2 JUSB1.3 LU1.4
USB20_P2: LU9.2 UH1.N15
USB20_P2_R: JIOB1.6 LU9.1
USB20_P3: LU4.3 UH1.K3
USB20_P3_R: DU4.2 JUSB2.3 LU4.4
USB20_P4: RT132.1 UH1.L9
USB20_P4_R: RT130.1 RT132.2 UT4.L5
USB20_P5: L3.1 UH1.L2
USB20_P5_R: JEDP1.34 L3.2
USB20_P6: LU8.2 UH1.K6
USB20_P6_R: JIOB1.3 LU8.1
USB20_P7: JWLAN1.3 UH1.L3
USB20_P8: L4.1 R20.2 UH1.G5
USB20_P8_R: DA6.3 JEDP1.37 L4.2 R20.1
USB20_P9: DF1.2 JFP.5 UH1.N8
USB20_P11: TH143.1(TP-1) UH1.P9
USB20_P14: TH141.1(TP-1) UH1.F6
USB20_VCCB: CU17.1 CU21.1 CU22.1 JIOB1.13 JIOB1.14 JIOB1.15 JIOB1.16 UU3.1
USB30_VCCA: CU6.1 CU7.1 CU8.1 CU9.1 CU10.1 CU11.1 CU12.1 CU13.1 CU14.1 CU15.1 CU19.1 CU20.1 JUSB1.1 JUSB2.1 UU1.1
USB_EN#: RE17.1 UE1.13 UU1.4 UU3.4
USB_OC0#: CH228.1 RPH6.4 UH1.AH36 UU1.3
USB_OC1#: RPH6.3 UH1.AL40 UU3.3
USB_OC2#: RPH6.1 UH1.AJ44
USB_OC3#: RPH6.2 UH1.AL41
USB_POWERSHARE_VBUS_EN: RE168.1 RE169.1 UE1.71
USBC_B2B_S1: PDS04.1 PDS05.1 PDS06.1 PQS08.2
USBC_B2B_S1_A: PCS11.1 PQS03.1 PQS04.2 PQS08.1 PRS12.2 PRS14.1
USBC_B2B_S2: PCS12.1 PQS05.2 PQS05.3 PQS19.2 PRS25.1 PUS02.4
USBC_B2B_S2_G: PCS10.2 PQS02.4 PQS06.1 PQS16.4 PRS09.2 PRS16.1
USBC_B2B_S3: PQS07.2 PRS34.2
USBC_SW_PROCHOT: PCS19.1 PCS20.1 PQS10.6 PRS28.2
VBST_+1.05V: PRH02.1 PUH01.10
VCI_IN1: RE70.1 UE1.126
VCIN0_PH: C32.1 C33.1 R42.2 R43.2 RE37.2 RH1.1
VCREF0: CE23.1 RE46.2 RE48.1 RE167.2 UE1.25
VD_IN1_C: C32.2 C33.2 R45.1 RH1.2
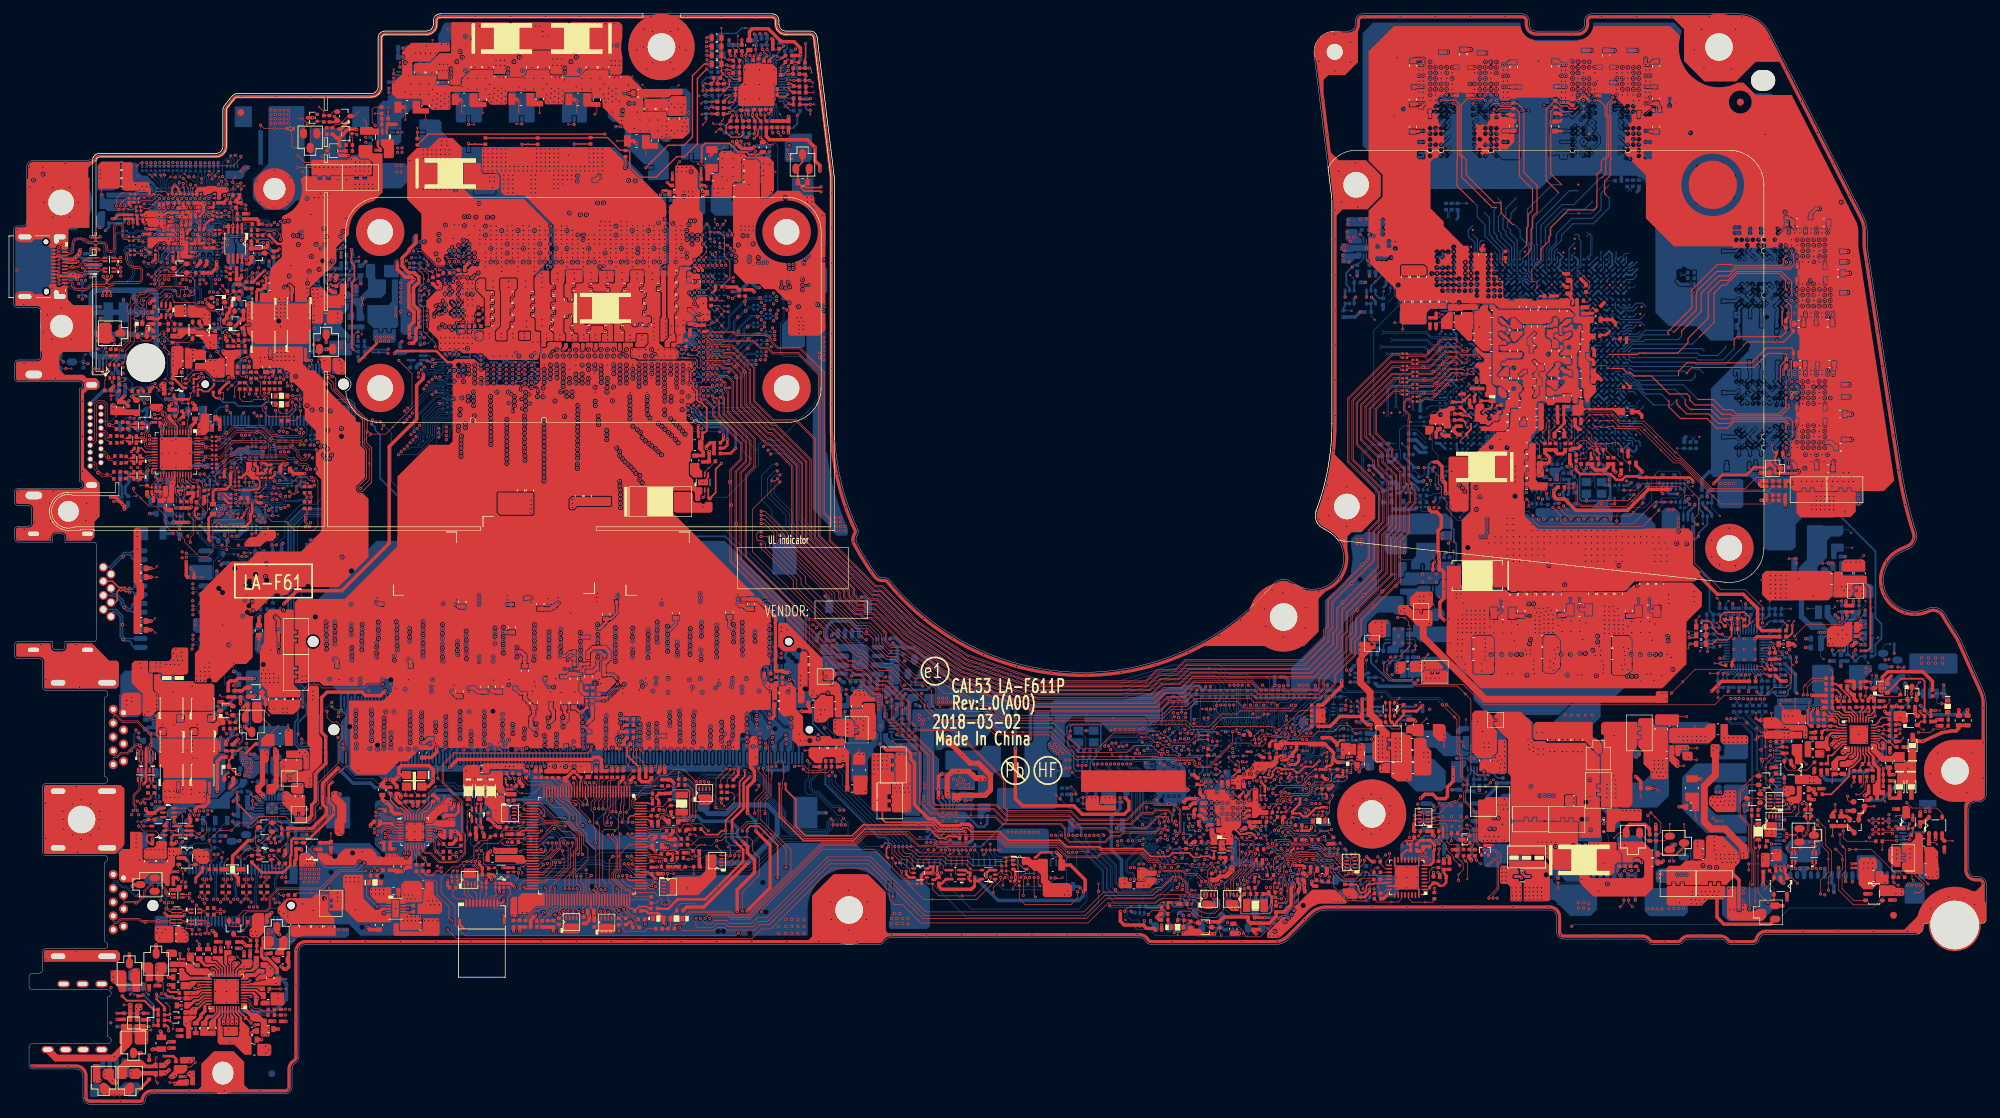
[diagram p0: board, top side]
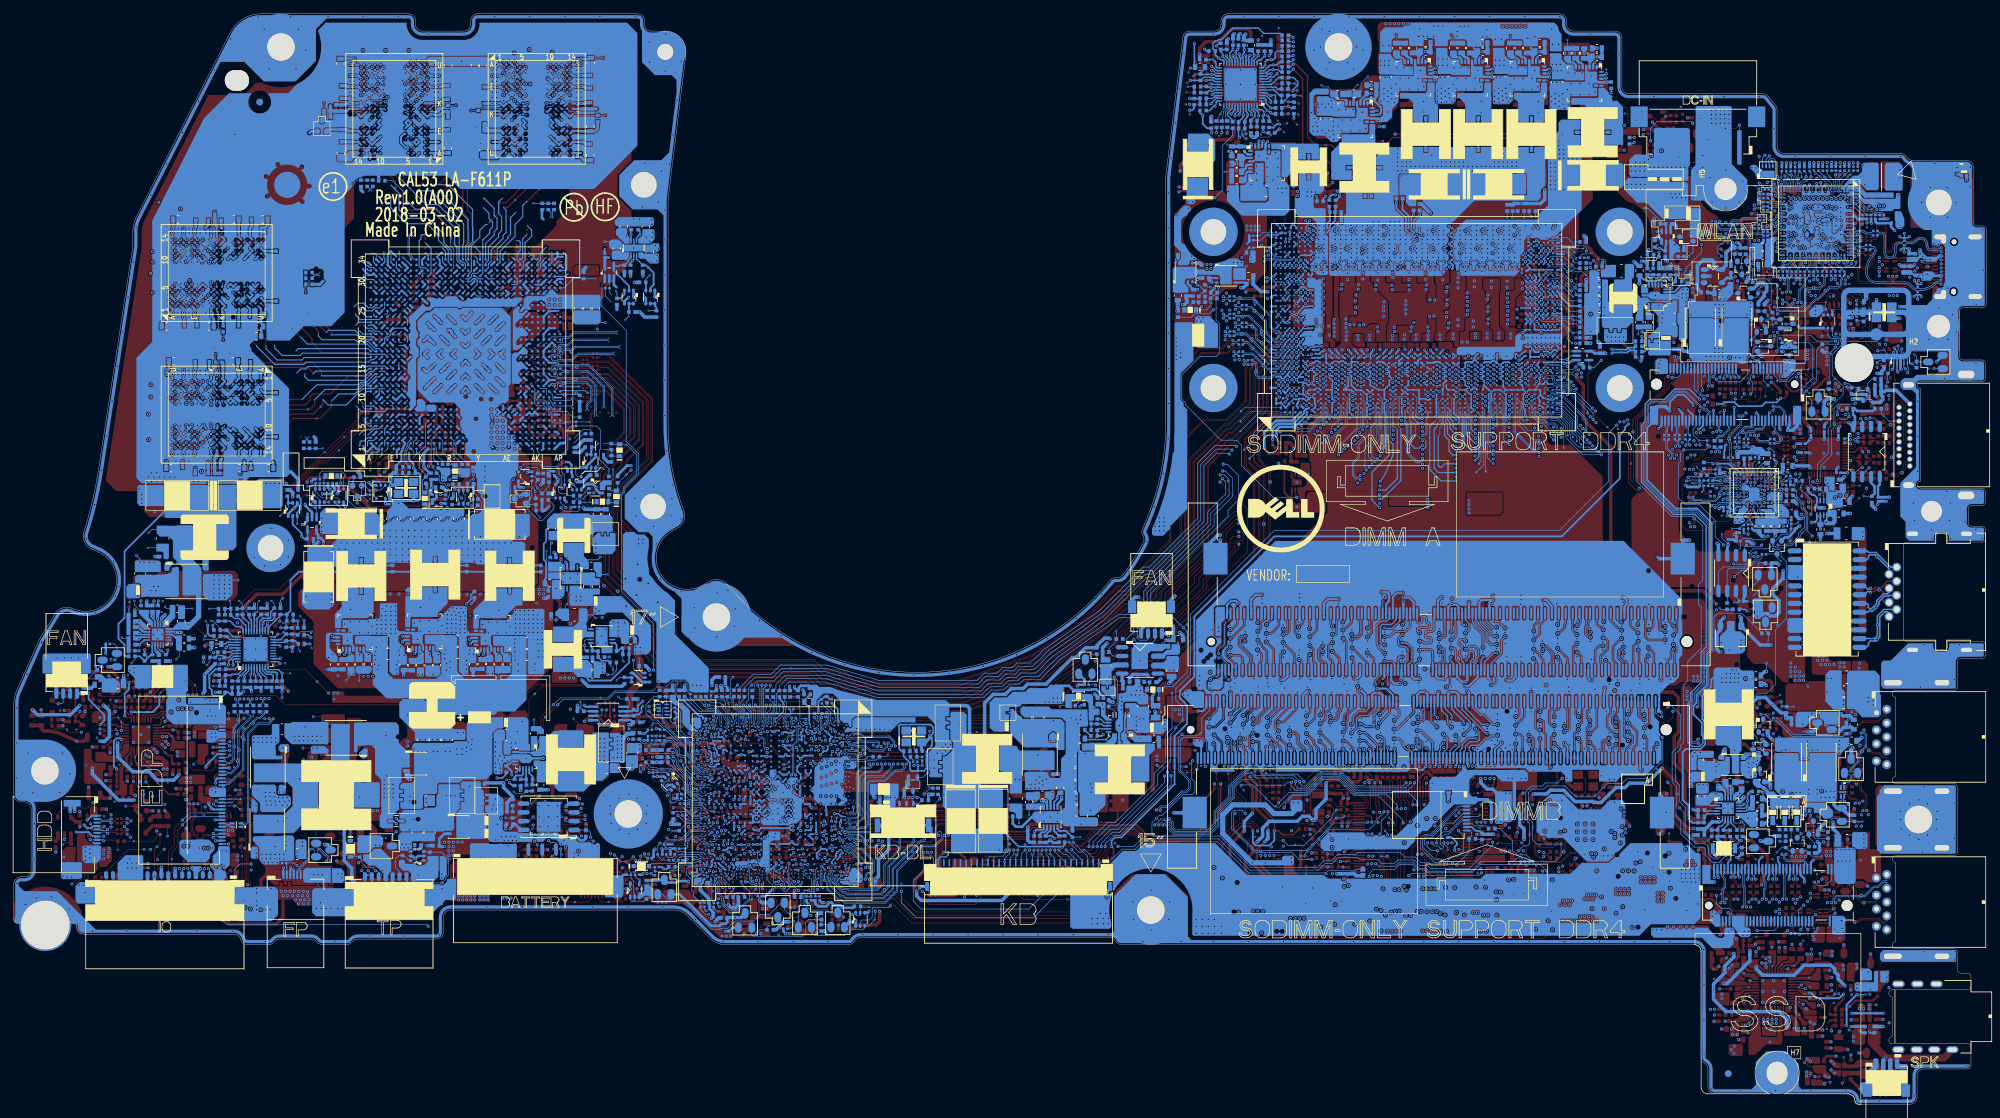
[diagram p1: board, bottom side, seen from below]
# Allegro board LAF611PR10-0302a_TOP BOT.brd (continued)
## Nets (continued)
VGA_CSREF: PCV11.2 PCV14.1 PCV15.1 PCV16.1 PRV37.2 PRV40.2 PRV43.2 PRV50.1 PRV54.1 PRV58.1 PUV101.21
VGA_DRON: PUV01.16 PUV02.16 PUV03.16 PUV101.12
VGA_PWM1: PRV38.2 PUV01.1 PUV101.11
VGA_PWM2: PRV35.2 PUV02.1 PUV101.10
VGA_PWM3: PRV34.2 PUV03.1 PUV101.9
VGA_REFIN: PCV06.2 PRV16.1 PRV19.1 PUV101.1
VGA_SMB_CK2: QV1.4 RV191.1 UV1.T4
VGA_SMB_DA2: QV1.1 RV192.1 UV1.T3
VGA_SW1: PLV01.1 PRV49.1 PUV01.11 PUV01.12
VGA_SW2: PLV02.1 PRV53.1 PUV02.11 PUV02.12
VGA_SW3: PLV03.1 PRV57.1 PUV03.11 PUV03.12
VGA_SWN1: PLV01.2 PRV39.1 PRV46.2
VGA_SWN2: PLV02.2 PRV41.1 PRV45.2
VGA_SWN3: PLV03.2 PRV42.1 PRV44.2
VGA_VREF: PCV08.2 PRV17.1 PUV101.2
VL: PC515.1 PU501.15
VR_CAP: CE24.1 TP44.1(TP-1) UE1.18
VR_ON: PRZ19.2 RZ71.1 UC16.2 UZ21.4
VR_SVID_ALERT#: PRZ22.2 PRZ26.1 RC261.2 RC267.1
VR_SVID_ALERT#_R: RC267.2 UC1.BH31
VR_SVID_CLK: PRZ23.2 PRZ25.2 UC1.BH32
VR_SVID_DATA: PRZ21.1 PRZ27.2 RC260.2 UC1.BH29
VREF_CPU: CE17.1 RE162.2 UE1.95
VSN_1PH: PCZ01.2 PRZ03.2 PUZ01.51
VSN_2PH: PCZ21.1 PRZ41.1 PUZ01.37
VSN_4PH: PCZ05.2 PRZ11.2 PUZ01.2
VSP_1PH: PCZ03.2 PRZ06.2 PUZ01.52
VSP_2PH: PCZ20.1 PRZ40.1 PUZ01.38
VSP_4PH: PCZ04.2 PRZ08.2 PUZ01.1
VTTREF_1.2V: PCM19.1 PUM01.4
WHITE_LED_BAT: Q19.1 R69.2
WLAN_PWR_EN: Q30.3 UE1.21
WLAN_RADIO_DIS#: DN1.1 RH520.2 RH707.2 UH1.BB16
WLAN_RADIO_DIS#_R: DN1.2 JWLAN1.56
XCLK_BIASREF: RH20.2 RH71.2 UH1.T3
XDP_BPM#0: TC98.1(TP-1) UC1.BR27
XDP_BPM#1: TC99.1(TP-1) UC1.BT27
XDP_BPM#2: TC101.1(TP-1) UC1.BM31
XDP_BPM#3: TC100.1(TP-1) UC1.BT30
XDP_HOOK0: RC86.2 TPC32.1(TP-1)
XDP_ITP_PMODE: RC80.2 TPC7.1(TP-1) UH1.AL3
XDP_PRDY#: TPC31.1(TP-1) UC1.BP27 UH1.AM5
XDP_PREQ#: RC259.2 TPC30.1(TP-1) UC1.BL30 UH1.AL2
XDP_PRSENT_CPU: RC144.1 RC250.2 TPC33.1(TP-1)
XDP_PRSENT_PCH: RC145.1 RC249.2 TPC9.1(TP-1)
XDP_SPI_SI: RC252.2 RC264.1 TPC8.1(TP-1)
XTAL24_IN: RH712.1 UH1.U10
XTAL24_IN_R: CH47.1 RH72.1 RH712.2 YH2.1
XTAL24_OUT: RH711.1 UH1.U9
XTAL24_OUT_R: CH48.1 RH72.2 RH711.2 YH2.3
XTAL_OUT: CV71.2 RV52.2 UV1.H2 YV1.3
XTALIN: CV70.2 RV52.1 UV1.H3 YV1.1
XTALOUT: RV51.1 UV1.J4
XTALSSIN: RV49.1 UV1.H1
N12281337: RA9.2 UA1.10
N16785983: TC28.1(TP-1) UC1.BK28
N16785994: TC30.1(TP-1) UC1.BJ28
N16789236: TC45.1(TP-1) UC1.BL31
N16789248: TC47.1(TP-1) UC1.AJ8
N16789274: TC48.1(TP-1) UC1.G13
N16789292: TC51.1(TP-1) UC1.C38
N16789346: TC55.1(TP-1) UC1.BP1
N16789364: TC57.1(TP-1) UC1.B38
N16789382: TC59.1(TP-1) UC1.B2
N16789430: TC25.1(TP-1) UC1.E2
N16789448: TC26.1(TP-1) UC1.E1
N16789466: TC24.1(TP-1) UC1.D1
N16789484: TC27.1(TP-1) UC1.BR1
N16789502: TC29.1(TP-1) UC1.BT2
N16789520: TC31.1(TP-1) UC1.BN35
N16789538: TC32.1(TP-1) UC1.J24
N16789556: TC33.1(TP-1) UC1.H24
N16789574: TC34.1(TP-1) UC1.BN33
N16789592: TC35.1(TP-1) UC1.BL34
N16789610: TC36.1(TP-1) UC1.N29
N16789628: TC37.1(TP-1) UC1.R14
N16789646: TC38.1(TP-1) UC1.AE29
N16789664: TC39.1(TP-1) UC1.AA14
N16789682: TC40.1(TP-1) UC1.AP29
N16789700: TC41.1(TP-1) UC1.AP14
N16789725: TC42.1(TP-1) UC1.F30
N16789743: TC43.1(TP-1) UC1.E30
N16789761: TC44.1(TP-1) UC1.B30
N16789779: TC46.1(TP-1) UC1.C30
N16789797: TC49.1(TP-1) UC1.G3
N16789815: TC50.1(TP-1) UC1.J3
N16789833: TC54.1(TP-1) UC1.BR35
N16789851: TC56.1(TP-1) UC1.BR31
N16789869: TC58.1(TP-1) UC1.BH30
N16795294: RC6.2 UC1.A36
N16795301: RC7.2 UC1.A37
N16815495: TC4.1(TP-1) UC1.BA2
N16815498: TC5.1(TP-1) UC1.BA1
N16815505: TC6.1(TP-1) UC1.AY4
N16815512: TC7.1(TP-1) UC1.AY5
N16815519: TC8.1(TP-1) UC1.BA5
N16815526: TC9.1(TP-1) UC1.BA4
N16815533: TC10.1(TP-1) UC1.AY1
N16815540: TC12.1(TP-1) UC1.AY2
N16820214: TC13.1(TP-1) UC1.BA3
N16820216: TC11.1(TP-1) UC1.AY3
N16844270: TC14.1(TP-1) UC1.AW11
N16844279: TC15.1(TP-1) UC1.AY11
N16844288: TC16.1(TP-1) UC1.AY8
N16844297: TC17.1(TP-1) UC1.AW8
N16844306: TC18.1(TP-1) UC1.AY10
N16844322: TC19.1(TP-1) UC1.AW10
N16844331: TC20.1(TP-1) UC1.AY7
N16844333: TC22.1(TP-1) UC1.AW7
N16844514: TC23.1(TP-1) UC1.AY9
N16844516: TC21.1(TP-1) UC1.AW9
N16865170: TC94.1(TP-1) UC1.AU13
N16865242: TC95.1(TP-1) UC1.AY13
N16946088: QG23.5 QG23.6 RG546.2
N17003752: JDIMM1.134 RD23.2
N17004366: JDIMM2.134 RD24.2
N17075731: DA8.2 RA29.1
N17075741: DA8.3 RA33.1
N17283936: QA1.3 RA5.1 RA6.1
N17389450: PC516.1 PD501.2 PR502.2 PR503.2 PR506.2 PR508.1
N17462309: JDEG1.9 RE58.2
N17462311: JDEG1.1 RE59.2
N17462343: JESPI1.8 RE65.2
N17731278: DG3.1 QG502.3 RG505.2 RG580.2
N18346546: Q13.1 R37.1
N18346552: C18.2 Q12.2 Q13.2 R38.2
N18346555: C18.1 Q12.3 R35.2
N18855880: R57.2 U1.3
N18983262: CE35.2 RE67.1
N18984098: CA38.2 RA43.1
N19136586: QS1.5 QS1.6 RS3.2
N20816750: PRG02.1 PUG01.5
N20816752: PCG09.2 PUG01.7
N20816771: PCG09.1 PRG02.2
N20816775: PCG07.2 PRG01.2 PUG01.3
N20816793: PLG01.3 PRG03.1
N20816821: PCA09.2 PUA01.7
N20816822: PRA02.1 PUA01.5
N20816832: PCA07.2 PRA01.2 PUA01.3
N20816859: PCA09.1 PRA02.2
N20820556: PLI01.3 PRI03.1
N20820665: PLI02.3 PRI07.1
N20820729: PLI03.3 PRI11.1
N20820776: PLI04.3 PRI15.1
N20905578: CT104.1 UT4.H7
N21354362: PQS05.5 PUS03.4
N21379353: PC508.1 PU501.16 PU501.17
N21388536: PDS03.1 PUS03.2
N21449558: PQ1.2 PQ2.1 PR4.2 PR7.1
N21449563: PD1.2 PL3.2 PQ1.1 PR3.1
N21449587: PQ13.2 PR31.2 PR35.2 PR45.1
N21449588: PQ13.3 PR32.2
N21449601: PQ12.2 PR36.2 PR44.2
N21449607: PC14.2 PQ11.2 PR43.1
N21449609: PQ13.5 PQ13.6 PR34.2 PR38.1
N21449623: PC13.2 PQ12.5 PR40.1
N21449665: PD3.1 PR7.2
N21449681: PQ6.1 PR12.2
N21449685: PC5.2 PQ3.4 PQ7.4 PR8.2 PR10.1
N21449690: PQ5.1 PR10.2
N21449736: PBATT1.5 PR39.1
N21449778: PQS10.2 PRS26.2 PRS27.2
N21484822: PC1801.1 PJP1801.2 PL1811.2 PU1801.8 PU1801.9 PU1801.10
N21513882: PD10.3 PR14.2 PR16.1
N21517490: PQ15.2 PR46.2 PR65.2
N21537645: PQ17.1 PR48.2
N21556764: PCS19.2 PQS10.5 PRS29.1
N21558641: PCS20.2 PQS11.2 PRS30.1
N21562486: PDS06.2 PRS23.2
N21563532: PDS05.2 PRS33.2
N21563639: PDS04.2 PRS32.2
N21599913: RL7.2 UL2.3
N21664134: RS5.1 US2.3
N21741311: PQS12.1 PRS37.2
N21741314: PQS13.2 PRS36.2 PRS37.1
N21741394: PQS12.2 PRS38.2
N21741739: PCS09.2 PQS01.4 PQS13.1 PQS15.4 PRS08.2 PRS11.1
N21876819: QV21.1 RV141.1
N21996246: R30.1 U3.3
N22121555: RW12.2 UW1.3
N22230445: PCS04.1 PRS01.2 PRS02.2 PRS39.1 PUS01.1
N22234781: PDS03.2 PRS40.2
N22234784: PDS03.3 PRS41.2
N22253138: LED1.4 R68.1
N22253145: LED1.2 R69.1
N22336501: PHZ03.1 PRZ66.2 PRZ67.1
N22336574: PHZ04.1 PRZ68.2 PRZ69.1
N22572921: PRZ71.2 PUZ01.27
N22693418: CTPM5.1 CTPM6.1 CTPM7.1 RTPM8.2 RTPM10.2 UTPM1.14 UTPM1.22
N22693460: CTPM1.1 CTPM2.1 RTPM6.1 RTPM7.1 UTPM1.1
N22693593: RTPM4.1 UTPM1.27
N22894187: RE85.1 UE1.42
N23415623: RE89.1 UE1.96
N23757940: TC52.1(TP-1) UC1.C1
N23757941: TC53.1(TP-1) UC1.BR2
N24091331: T92.1(TP-1) UH1.BE33
N24173022: TH101.1(TP-1) UH1.AL35
N24203733: QV96.2 QV96.5 RV683.2 RV684.2
N24570150: Q25.1 R73.2
N24570154: C60.1 D7.2 Q25.2 R78.1
N24625779: CZ11.1 UZ1.12
N24625783: CZ10.1 UZ1.10
N24678846: RH103.2 RH105.1 RH180.2
N24681096: RC271.1 RC272.1 UC1.H14
N24681102: RC273.1 RC274.1 UC1.J14
N25297595: RZ234.2 UC12.2
N25297620: RZ237.2 RZ238.1 UC12.1
N25559338: QX3.2 RX6.1
N25587837: RTPM11.1 UTPM1.29
N25587876: RTPM12.1 UTPM1.3
N25755660: PQS19.1 PRS43.2
N25756286: PCS21.2 PQS17.4 PQS18.4 PQS20.1 PRS42.2 PRS43.1
N25791938: QV20.1 RV126.1
N25839183: PR62.2 PR63.1 PU01.4
N25903529: RV116.1 UV6.J1
N25932446: RV132.1 UV8.J1
N25932452: RV136.1 UV8.J13
N25986828: RV131.1 UV9.J1
N25986830: RV135.1 UV9.J13
N26540304: LV3.3 RV500.2 RV641.2 RV673.1
N26540312: LV4.3 RV501.2 RV643.2 RV674.1
N26540318: LV5.3 RV29.1 RV502.2 RV642.2
N26540324: LV6.3 RV33.1 RV503.2 RV645.2
N26540332: LV6.2 RV34.1 RV503.1 RV638.2
N26540338: LV5.2 RV30.1 RV502.1 RV639.2
N26540344: LV4.2 RV28.1 RV501.1 RV646.2
N26540350: LV3.2 RV500.1 RV640.2 RV675.1
N26571966: QV3.2 RV56.1
N26577826: QG10.2 RG573.1 RG575.1 UV20.4
N26578092: QV1.2 QV1.5 RV571.2 RV572.2
N26699849: CT156.2 RT156.1
N26700727: CT157.2 RT157.1
N26701062: CH224.2 RH708.1
N26874760: PCV03.2 PRV15.1 PRV16.2 PRV17.2
N26874782: PRV06.1 PUV101.36
N26874784: PCV16.2 PRV43.1 PRV44.1 PUV101.18
N26874788: PCV14.2 PRV37.1 PRV46.1 PUV101.20
N26874798: PRV20.1 PRV22.1 PUV101.28
N26874811: PCV04.2 PCV07.2 PUV101.30
N26875019: PCV12.2 PCV13.2 PRV36.2 PRV39.2 PRV41.2 PRV42.2 PUV101.22
N26875029: PHV01.1 PRV28.2 PRV36.1
N26875045: PRV31.2 PUV101.6
N26875049: PRV30.2 PUV101.5
N26875053: PCV09.1 PRV23.1 PUV101.3
N26875069: PRV33.2 PUV101.8
N26875073: PRV32.2 PUV101.7
N26875077: PRV29.2 PUV101.4
N26875110: PRV15.2 PUV101.40
N26875121: PCV02.2 PRV09.2 PUV101.32
N26875125: PCV02.1 PRV14.2 PUV101.31
N26875157: PRV03.2 PRV04.2 PRV08.1 PUV101.37
N26875247: PRV13.1 PUV101.39
N26877105: PLV01.3 PRV50.2
N26877609: PCV27.2 PUV01.7
N26877615: PRV48.1 PUV01.5
N26877657: PCV26.2 PRV47.2 PUV01.3
N26877691: PRV52.1 PUV02.5
N26877733: PCV27.1 PRV48.2
N26877795: PCV37.2 PUV02.7
N26877907: PCV36.2 PRV51.2 PUV02.3
N26878499: PRV56.1 PUV03.5
N26878505: PCV47.2 PUV03.7
N26878545: PCV47.1 PRV56.2
N26878585: PCV49.1 PRV57.2
N26878589: PLV03.3 PRV58.2
N26891657: PRV18.1 PRV19.2
N26891663: PCV15.2 PRV40.1 PRV45.1 PUV101.19
N26891668: PCV04.1 PCV05.2 PRV21.1 PRV22.2 PUV101.29
N26891679: PCV07.1 PRV21.2
N26891685: PCV05.1 PRV20.2
N26891690: PCV01.1 PRV05.1 PUV101.33
N26891691: PRV01.2 PUV101.35
N26891692: PRV02.2 PUV101.34
N26891707: PRV24.1 PUV101.27
N26891711: PRV25.1 PUV101.26
N26891716: PCV10.1 PRV26.1 PUV101.25
N26891720: PRV27.1 PUV101.24
N26891721: PCV12.1 PCV13.1 PHV01.2 PRV27.2 PRV28.1 PUV101.23
N26893030: PLV02.3 PRV54.2
N26893128: PCV37.1 PRV52.2
N26894100: PCV46.2 PRV55.2 PUV03.3
N26983473: PQS07.1 PRS15.2
N26983484: PQS06.2 PRS10.2 PRS15.1
N26985058: RC15.1 RC275.1 UC1.M38
N26985064: RC16.1 RC276.1 UC1.M37
N27106564: RC277.2 UC1.BR33
N27108011: T4941.1(TP-1) UH1.AN40
N27125806: PC24.2 PQ20.2 PR64.1
N27182711: PCZ25.1 PRZ47.2
N27238858: PCI17.1 PRI04.2
N27238942: PCI27.1 PRI08.2
N27239057: PCI37.1 PRI12.2
N27239175: PCI47.1 PRI16.2
N27239423: PCG10.1 PRG04.2
N27239504: PCA10.1 PRA04.2
N27327907: PQS20.2 PRS44.2 PRS46.1
N27327919: PRS45.2 PRS47.2
N27330630: PQS21.1 PRS46.2
N27330757: PCS22.1 PQS21.2 PRS47.1
N27396422: PCV29.1 PRV49.2
N27396428: PCV39.1 PRV53.2
N27484470: PRW09.2 PRW10.2 PUW01.5
N27522006: Q27.5 Q27.6 R82.2
N27603868: T65.1(TP-1) UT4.B2
N27604678: RT164.1 UT4.C2
N27605266: RT165.1 UT4.D7
N27606921: Q29.1 RT167.1
N27736039: JWLAN1.6 TC105.1(TP-1)
N27736188: JWLAN1.16 TC106.1(TP-1)
N27736197: JWLAN1.44 TC107.1(TP-1)
N27736206: JWLAN1.46 TC108.1(TP-1)
N27736215: JWLAN1.48 TC109.1(TP-1)
N27736333: RW13.2 TC110.1(TP-1)
N27933518: PCI46.2 PUI04.7
N27933520: PRI14.1 PUI04.5
N27933540: PCI44.2 PRI13.2 PUI04.3
N27933602: PCI46.1 PRI14.2
N28152235: PCZ20.2 PCZ21.2 PRZ41.2 PRZ42.1
N28152401: PCZ30.2 PRZ52.2 PUZ01.15
N28152437: PCZ16.1 PRZ31.1 PUZ01.3
N28152465: PCZ22.1 PRZ44.1 PUZ01.36
N28152580: PCZ01.1 PCZ02.2 PRZ02.2 PRZ03.1
N28152729: PCZ02.1 PCZ03.1 PRZ05.2 PRZ06.1
N28152784: PCZ32.1 PRZ53.2 PUZ01.16
N28152958: PHZ02.2 PRZ49.2 PRZ50.1
N28153073: PHZ05.2 PRZ12.1
N28153589: PRZ19.1 PUZ01.43
N28153954: PCZ15.1 PRZ29.2
N28154016: PCZ04.1 PCZ05.1 PRZ10.2 PRZ11.1
N28154283: PHZ01.2 PRZ33.2 PRZ34.1
N28180064: PCZ10.2 PRZ16.1
N28185893: PCZ23.1 PRZ45.2
N28185971: PCZ14.1 PRZ28.2
N28761690: PQB06.4 PRB61.1
N28764708: PCB35.1 PRB21.1 PRB57.1 PUB01.3
N28766144: PRB26.1 PRB59.2 PUB01.27
N28767446: PRB27.2 PRB29.2 PRB60.2 PUB01.26
N28769298: PD14.3 PJPB04.1 PJPB05.1 PJPB06.1 PQB02.2 PQB06.1 PQB06.2 PQB06.3 PRB12.1
N28789751: PCW17.1 PRW14.1 PRW19.1 PUW01.11
N28823932: CZ57.1 UZ16.6
N28832867: RL17.1 UL1.26
N28866414: PDB01.1 PDB02.1 PDB03.1 PRB08.1 PRB70.2
N28866422: PRB01.3 PRB03.1
N28866424: PRB28.1 PUB01.29
N28866425: PCB40.1 PRB28.2 PRB34.1 PRB35.1
N28866427: PRB31.1 PRB33.1 PUB01.30
N28866432: PDB04.3 PRB37.1 PRB38.2
N28866460: PRB12.3 PRB36.2
N28866498: PDB04.1 PDB05.1 PUB02.1
N28866500: PRB42.1 PUB02.4
N28866517: PRB12.2 PRB32.2
N28866565: PRB41.2 PUB02.2
N28866567: PDB04.2 PRB40.2
N28866577: PCB42.1 PRB30.2
N28866586: PCB25.1 PRB06.2
N28866597: PCB30.2 PRB15.1
N28866613: PRB01.2 PRB02.1
N28866635: PRB14.2 PUB01.21
N28866636: PRB16.2 PUB01.22
N28866639: PRB19.2 PUB01.23 ZTB02.1(TP-1)
N28866700: PDB05.2 PRB44.2
N28866811: PQB05.2 PRB45.2
N28909904: QV10.2 QV10.3 RG50.2
N28980130: RE90.1 RE163.1 UE1.88
N29040119: PDB01.2 PRB67.1 PRB69.1
N29056076: PQB10.1 PQB11.2
N29169731: TC111.1(TP-1) UC1.BP13
N29212180: RP30.2 RP31.1 UP1.2
N29536756: CZ46.2 RZ21.2 UZ7.3
N29536778: CZ33.2 UZ7.6
N29634660: RP32.1 UP2.36
N29634710: RP11.1 UP2.9
N29634752: RP45.1 UP2.40
N30315085: CG64.1 UG12.12
N30315086: CG65.1 UG12.10
N30316777: DG4.2 QG502.4 RG506.2
N30316795: QG502.6 RG516.2 UG22.2
N30391035: QG502.5 RG554.2
N30391036: RG554.1 UG22.4
N30391037: QG502.2 RG553.2
N30700583: QG505.5 QG505.6 RG543.2
N30700603: QG506.5 QG506.6 RG513.2
N30700625: QG506.3 RG514.2
N30700675: QG503.5 QG503.6 RG509.2
N30700682: QG503.3 RG510.2
N30700690: QG504.5 QG504.6 RG511.2
N30700699: QG504.3 RG512.2
N30700734: QG505.3 RG544.2
N30909781: QH10.5 QH10.6 RH747.2
N30909795: QH10.3 RH748.2
N31133241: Q30.1 RW11.2 UW1.4
N31240142: T4942.1(TP-1) UH1.AL10
N31240160: T4943.1(TP-1) UH1.AR3
N31738846: QH8.5 QH8.6 RH744.2
N31739459: QH9.5 QH9.6 RH745.2
N32320644: PRW13.1 PRW15.2 PRW16.1 PUW01.7
N32320879: PRW17.1 PUW01.12
N32320932: PCW14.2 PRW11.2 PUW01.8
N32321023: PCW12.1 PRW04.2
N32321094: PCW15.2 PRW11.1 PRW12.2 PRW13.2
N32332705: PRW12.1 PUW01.6
N33188643: CA31.1 RA23.2 RA24.1
N35924928: RV77.2 UV1.J27
N35928308: RV78.2 UV1.H27
N35950826: RV79.2 UV1.H25
N36655056: TH148.1(TP-1) UH1.BE35
N36697219: TH1.1(TP-1) UH1.Y14
N36697221: TH2.1(TP-1) UH1.Y15
N36697223: TH4.1(TP-1) UH1.U35
N36697225: TH5.1(TP-1) UH1.N32
N36697227: TH6.1(TP-1) UH1.R32
N36697229: TH7.1(TP-1) UH1.AH15
N36697231: TH8.1(TP-1) UH1.AH14
N36697247: TH3.1(TP-1) UH1.U37
N40598435: PC307.1 PR301.2
N40598500: PC507.1 PR501.2
N40598503: PC315.2 PR306.1
N40598539: PC517.2 PR509.1
N40598619: PD501.1 PR507.2
N40664383: JDIMM1.165 TP41.1(TP-1)
N40665360: JDIMM2.165 TP42.1(TP-1)
N40665398: JDIMM2.162 TP43.1(TP-1)
N41527020: JDIMM1.162 TP40.1(TP-1)
N42077965: PCI16.2 PUI01.7
N42077969: PRI02.1 PUI01.5
N42077993: PCI14.2 PRI01.2 PUI01.3
N42078041: PCI26.2 PUI02.7
N42078055: PRI06.1 PUI02.5
N42078421: PCI16.1 PRI02.2
N42078657: PCI26.1 PRI06.2
N42078671: PCI24.2 PRI05.2 PUI02.3
N42079748: PRI10.1 PUI03.5
N42079752: PCI36.2 PUI03.7
N42079902: PCI36.1 PRI10.2
N42079910: PCI34.2 PRI09.2 PUI03.3
N45824609: PCS03.1 PRS01.1 PRS03.2 PRS05.1 PUS01.3
N45824651: PCS02.1 PRS04.2 PRS06.1 PUS01.2
N45824918: PQS04.1 PRS11.2
N45824994: PQS05.6 PRS16.2
N47710281: PC2504.1 PR2504.2 PU2501.4
N47714748: PCM11.1 PRM01.2
N47719295: PCM13.1 PRM05.1 PUM01.12
N47720067: PRM06.2 PUM01.10
N47887852: PC1806.1 PR1804.2
N101473793: RV120.1 UV6.J13
N101484120: RV117.1 UV7.J1
N101484397: RV121.1 UV7.J13
N124752685: CD30.2 RD11.1
N124753277: CD59.2 RD22.1
N132121209: CV903.1 RV594.2 RV595.2
N132122697: CV904.1 RV596.2 RV597.2
N132123770: CV905.1 RV598.2 RV599.2
N132124417: CV906.1 RV600.2 RV601.2
N132421462: RV602.1 UV1.R32
N132421465: RV603.1 UV1.AC32
N132618344: RV604.1 UV1.C12
N133325166: RV605.1 UV1.C20
N135624823: RT83.2 UT4.F1
N135625951: RT111.1 UT4.D10
N135629282: T62.1(TP-1) UT4.F4
N135629285: T63.1(TP-1) UT4.G4
N137678407: QG23.2 RG576.2

Pads without a net: DC1 2; FD1 1; FD2 1; FD3 1; FD4 1; FD5 1; JDIMM1 87 88 91 92 95 97 100 101 104 105; JDIMM2 87 88 91 92 95 97 100 101 104 105; JEDP1 5 6 9; JKB 28 29; JKBBL 3; JSSD1 6 8 20 22 24 26 28 30 32 34 36 40 42 44 46 48 56 58 67 68; JWLAN1 8 12 20 42 58 60 62 66 68 70; PD1 3; PD6 3; PJPDC1 10 11; PU01 3; PU301 10 15; PU501 10; PU901 10 12; PU1001 1 7; PU1801 1 7; PU2501 1 5; PUA01 6 13 17 19; PUG01 6 13 17 19; PUI01 6 13 17 19; PUI02 6 13 17 19; PUI03 6 13 17 19; PUI04 6 13 17 19; PUS01 5 6 7; PUV01 6 13 17 19; PUV02 6 13 17 19; PUV03 6 13 17 19; PUV101 13 14 15 16; PUW01 14 15 16 17; RF1 2; RP1 4 5; RP2 4 5; RP50 3; RW25 1; RW26 1; UC1 A19 A21 A23 A25 A27 A29 AD2 AD4 AE1 AE5 AE9 AE10 AE11 AF10 AJ10 AJ11 AK3 AL1 AL2 AL3 AM10 AM11 AT3 AT5 AT7 AT11 AT13 AW13 B18 B19 B20 B21 B22 B23 B24 B25 B27 B28 B29 B33 B34 B36 C18 C20 C22 C24 C28 C33 C34 D19 D21 D23 D25 D34 E3 E18 E19 E20 E21 E22 E23 E24 E25 E26 E33 E36 E37 F18 F20 F22 F24 F26 F33 F34 F35 F37 G38 H33 H34; UC10 1; UC16 1; UE1 63; UE2 1; UH1 A17 A22 A25 A42 A44 AA1 AA45 AB2 AB3 AB48 AC2 AC3 AC6 AC7 AC9 AC11 AC14 AC15 AC39 AC41 AD47 AD48 AE6 AE7 AE9 AE11 AE14 AE15 AE39 AE41 AE43 AE44 AE47 AE48 AF47 AG45 AH9 AH10 AH40 AH41 AH46 AH47 AH48 AJ46 AJ47 AK47 AL9 AL13 AL15 AL37 AL47 AM7 AM43 AM46 AM47 AM48 AN4 AN10 AN13 AN29 AN35 AN37 AN46 AN47 AP2 AP3 AP9 AP21 AP29 AP47 AP48 AR2 AR13 AR18 AR32 AR35 AR37 AR42 AR47 AR48 AT5 AT10 AT49 AU4 AU24 AU46 AU47 AV6 AV7 AV13 AV21 AV43 AV47 AW2 AW3 AW13 AW15 AW32 AW48 B9 B14 B15 B17 B18 B19 B21 B23 B24 B25 B26 B27 B41 B42 B44 BA20 BA30 BA33 BB30 BB34 BC1 BC17 BC22 BC42 BD12 BD16 BD21 BD34 BD39 BD42 BE8 BE9 BE12 BE14 BE15 BE23 BE29 BE31 BE32 BE36 BE39 BE40 BF9 BF10 BF14 BF15 BF19 BF23 BF33 BF35 BF36 BF40 BF41 BG8 C3 C9 C14 C15 C16 C17 C18 C19 C20 C21 C23 C24 C26 C27 C41 C42 C44 D4 D20 D21 D29 D42 D43 E28 F14 F16 F20 F24 F26 G1 G2 G14 G17 G20 G24 G26 H2 H3 J13 J15 J18 J21 J24 K13 K16 K18 K21 K29 K43 K44 L24 L26 L41 L46 L47 M26 M29 M40 M44 N2 N3 N18 N42 N47 N48 P21 P24 P41 P47 P48 R13 R15 R18 R21 R24 R35 R37 R40 R46 R47 T45 T46 T47 T48 U13 U47 U48 V47 V48 W3 W4 W46 W47 Y2 Y35 Y36; UP1 3 7; UP2 2 10 12 25 26 37; UT1 A7 A9 A11 A13 A23 AB15 AB17 AB19 AB21 AC15 AC17 AC19 AC21 B7 B9 B11 B13 B23 D19 E18 E19 J1 J2 L1 L2 N1 N2 N4 R1 R2 V18 W12 W16 W19 Y6 Y8 Y12 Y16 Y19; UT4 G10 L11; UTPM1 2 4 5 6 7 10 11 12 13 15 25 26 28 30 31; UV1 A9 A26 A27 A30 AB3 AB4 AB8 AC1 AC2 AC3 AC4 AC5 AC6 AC28 AD1 AD2 AD3 AD4 AD5 AD6 AE3 AE4 AF1 AF2 AF3 AF4 AF5 AF30 AF32 AG1 AG7 AG10 AG12 AG20 AG23 AG26 AH6 AH8 AH9 AH20 AH23 AH31 AJ4 AJ5 AJ6 AJ8 AJ9 AJ11 AJ20 AJ21 AJ23 AJ24 AJ26 AJ28 AJ31 AJ32 AJ33 AK2 AK3 AK4 AK5 AK6 AK8 AK9 AK20 AK21 AK22 AK23 AK24 AK25 AK26 AK31 AL3 AL4 AL6 AL7 AL8 AL9 AL10 AL11 AL22 AL25 AM1 AM2 AM3 AM4 AM5 AM6 AM7 AM8 AM9 AM21 AM23 AM24 AM26 AM27 AM34 AN2 AN3 AN5 AN6 AN8 AN9 AN21 AN23 AN24 AN26 AN27 AP3 AP5 AP6 AP8 AP9 AP20 AP21 AP23 AP24 AP26 AP27 B2 B6 B23 C6 C15 D6 D7 D9 D19 D20 D22 D23 D26 D28 E1 E4 E26 E34 F2 F26 G14 G20 H30 H31 J30 J31 J32 J33 K3 K4 L2 L7 M4 M5 M6 M30 M34 N4 N8 P1 P2 P3 P4 P5 P8 R1 R4 R5 R28 U1 U2 V32; UV6 A5 A10 U5 U10; UV7 A5 A10 U5 U10; UV8 A5 A10 U5 U10; UV9 A5 A10 U5 U10

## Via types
v1: diameter 0.457, hole 0.203, TOP to BOTTOM, 7741 vias
v2: diameter 0.305, hole 0.152, TOP to BOTTOM, 806 vias
v3: diameter 0.406, hole 0.203, TOP to BOTTOM, 249 vias
v4: diameter 0.508, hole 0.254, TOP to BOTTOM, 88 vias

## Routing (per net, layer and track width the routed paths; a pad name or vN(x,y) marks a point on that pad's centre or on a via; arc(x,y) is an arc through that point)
1.0VS_VGAP_VIN:
  vias: v1(203.35,73.48) v1(203.35,72.85) v1(203.99,73.48) v1(203.99,72.85) v3(204.93,73.71)
1.2V_VDDQ_EN: length 4.4
  BOTTOM w0.102: v1(113.52,115.4) 113.93,115.81 RZ102.2 114.72,116.08 CZ102.1 115.85,114.95 DZ1.2 ; v1(37.21,37.84) 37.05,38.01 PRM08.1
1.2V_VIN: length 1
  BOTTOM w0.254: v1(35.43,38.14) 35.71,38.14 36.07,38.49 PRM07.1
  vias: v1(39.06,49.5) v1(39.06,48.86) v1(39.12,48.24) v2(38.66,49.19)
1.35VGPUP: length 24.9
  BOTTOM w0.254: v1(263.3,86.05) 269.33,80.02 269.33,70.38 270.21,69.51 270.21,67.38 269.33,66.51 269.33,65.02 269.13,64.82 PRW14.2
  vias: v1(260.12,86.69) v1(260.12,86.05) v1(260.78,87.98) v1(260.76,87.39) v1(260.76,86.69) v1(260.76,86.05) v1(261.42,87.98) v1(261.39,87.32) v1(261.39,86.69) v1(261.39,86.05) v1(262.03,87.95) v1(262.03,87.32) v1(262.03,86.69) v1(262.03,86.05) v1(262.66,87.95) v1(262.66,87.32) v1(262.66,86.69) v1(262.66,86.05) v1(263.3,87.96) v1(263.3,87.32) v1(263.3,86.69) v3(264.94,85.74)
1V05PRIM_PG: length 36.3
  TOP w0.254: RE149.1 71.18,46.38 v1(71.18,47.12) ; v1(137.69,39.47) 137.66,39.44 133.76,39.44 132.8,40.4 122.85,40.4 121.31,38.86 114.52,38.86 113.13,40.25 113.13,44.06 v2(112.24,44.95) 111.65,45.54 111.65,46.35 v1(111.65,46.35)
  BOTTOM w0.254: PUH01.1 136.35,39.84 136.47,39.71 137.45,39.71 v1(137.69,39.47) 137.71,39.44 PRH01.2
1V8_AON_ON: length 7.9
  BOTTOM w0.203: UG25.4 197.75,121.29 197.61,121.43 RG70.2 196.45,121.99 196.45,122.12 196.06,122.51 UG12.3
  BOTTOM w0.254: UG25.4 198.55,120.62 v2(196.99,119.06) 196.35,118.42 QG503.2
1V8_MAIN_EN: length 27.7
  TOP w0.102: RV55.1 223.06,95.82 222.76,96.12 222.49,96.12 222.24,96.36 222.24,97.36 222.95,98.07 222.95,98.88 222.49,99.35
  BOTTOM w0.102: 200.03,95.63 RG549.1 198.78,95.5 DG7.2 196.77,95.5 195.23,93.96 195.23,91.24 197.19,89.28 197.19,88.62 197.66,88.15 197.66,87.59 DG10.1 199.24,87.1 199.34,87.2 199.24,87.3 RG550.1
  BOTTOM w0.114: 222.49,99.35 222.88,99.75 UV1.P7
  BOTTOM w0.203: UG12.5 195.26,122.34 CG487.1 193.89,121.43 v1(193.62,121.15)
  BOTTOM w0.254: v1(193.62,121.15) 192.79,120.32 192.79,118.59 193.26,118.12 QG504.2
2.5V_VIN: length 0.7
  TOP w0.102: v1(126.8,61.84) 126.8,61.71 v2(127.22,61.29)
3.3V_TS_EN: length 13
  TOP w0.102: v1(251.01,34.77) v3(251.01,33.88) ; U3.4 v1(254.64,29.61)
  BOTTOM w0.089: 187.34,41.31 186.12,41.31 185.92,41.51 185.6,41.51 185.49,41.41 185.11,41.41 UH1.BD30
  BOTTOM w0.102: v1(254.64,29.61) 254.64,31.26 253.47,32.43 253.47,33.91 252.61,34.77 v1(251.01,34.77) ; v1(188.08,41.85) 187.98,41.85 187.43,41.31 187.34,41.31
3V_FB: length 3.2
  BOTTOM w0.254: PR307.2 211.22,46.22 PC315.1 ; PR307.2 211.24,47.01 PU301.13 ; PR307.2 212,46.99 PR308.1
3V_SN: length 2.1
  TOP w0.102: v2(204.39,55.8) 203.21,54.62 PR305.2
3V_VIN:
  vias: v1(212.5,53.92) v1(212.75,52.27) v1(212.75,51.64) v1(213.39,52.27) v1(213.39,51.64) v3(211.79,55.37)
5V_FB: length 3.6
  BOTTOM w0.203: PC517.1 129.5,54.16 PR511.1 128.65,55.06 PR510.2 127.96,55.03 127.71,54.77 PU501.13
5V_SN:
  vias: v3(123.23,45.27)
5V_VIN:
  vias: v1(121.87,55.76) v1(122.45,55.76) v1(122.96,56.08) v1(122.96,55.45) v1(122.96,54.81) v1(122.96,54.18) v1(123.6,56.18) v3(124.45,54.14)
5VS_FAN1: length 9.7
  TOP w0.102: v1(118.67,67.15) 118.67,67.09 119.08,66.69 v3(119.08,66.66)
  BOTTOM w0.508: 117.59,67.28 117.59,69.11 118.4,69.92 121.02,69.92 122.25,68.69 JFAN1.4 ; 117.59,67.28 117.73,67.15 v1(118.67,67.15) ; 117.59,67.28 RE104.2
5VS_FAN2: length 4.2
  TOP w0.102: v1(275.34,60.21) 275.34,60.68 v3(275.73,61.07)
  BOTTOM w0.508: RE105.2 273.67,60.69 274.16,60.21 v1(275.34,60.21) ; JFAN2.4 v1(279.2,60.66)
+0.6V_DDR_VTT: length 29
  TOP w0.508: 42.55,41.26 43.1,41.8 43.1,43.28 43.61,43.8 43.61,47.8 45.13,49.32 45.13,53.2 44.52,53.81 44.52,58.84 45.31,59.64 50.36,59.64 50.86,59.13 53.03,59.13 v1(53.75,59.85)
  vias: v1(112.26,60.82) v1(112.27,60.23) v1(113.78,52.62) v1(114.48,52.58) v3(113.65,53.55)
+0.6VSP: length 2.6
  BOTTOM w0.203: PUM01.2 39.93,43.22 40.45,43.75
  BOTTOM w0.254: 40.45,43.75 40.56,43.86 PCM21.1
  vias: v1(39.06,44.89) v1(40.56,44.54) v1(41.17,44.56) v1(41.77,44.53) v3(39.1,43.89)
+0.9V_CIO: length 2.9
  TOP w0.127: CT80.1 26.34,127.62 v2(26.45,127.51)
  TOP w0.356: v1(26.26,129.1) 26.29,129.1 26.42,129.23 CT78.1 ; CT79.1 25.55,127.75 v1(25.61,127.8)
  TOP w0.381: CT80.1 26.26,128.48 v1(26.26,129.1)
+0.9V_DP: length 3.7
  TOP w0.127: v1(17.25,127.56) v2(17.25,126.88)
  TOP w0.356: CT57.1 24.24,127.74 v1(24.31,127.8)
  TOP w0.381: v1(26.91,127.15) 26.84,127.08 CT54.1 ; CT60.1 CT61.1 CT62.1 17.25,127.97 v1(17.25,127.56)
  vias: v1(24.31,129.75) v1(24.96,129.75) v1(26.91,127.8)
+0.9V_LVR_OUT: length 0.6
  TOP w0.381: CT84.1 22.94,127.75 v1(23,127.8)
  vias: v1(22.36,125.21) v1(23.01,125.22) v2(20.71,125.28)
+0.9V_PCIE: length 1.4
  TOP w0.127: v2(26.86,123.05) 26.53,122.72 CT70.1
  vias: v1(24.32,126.5) v1(24.32,125.85) v1(24.32,125.19) v1(24.32,124.56)
+0.9V_SVR: length 1.2
  TOP w0.127: v3(12.66,131.61) 12.66,132.84
  vias: v1(12.48,135.21) v1(12.5,134.62) v1(12.49,134.03) v1(21.08,127.8) v1(21.06,127.16) v1(21.72,127.8) v1(21.72,127.16) v1(21.72,126.5) v1(23.66,128.45) v1(24.31,128.47)
+0.9V_USB: length 2.5
  TOP w0.381: v1(26.26,125.85) 26.53,125.85 v2(26.82,125.56) 26.82,125.04 26.8,125.02 CT56.1 27.14,124.53 27.24,124.63 CT77.1
+1.0VS_VGA_PGOOD: length 5.1
  TOP w0.102: v1(205.54,78.45) 205.54,78.84 v2(205.25,79.13)
  TOP w0.381: PR1002.2 205.31,78.22 v1(205.54,78.45)
  BOTTOM w0.254: PU1001.4 205.31,78.22 v1(205.54,78.45)
  BOTTOM w0.381: v1(243.21,86.82) 243.21,86.66 242.21,85.66 UG27.2
+1.0VS_VGAP: length 10.5
  BOTTOM w0.254: PC1006.1 208.33,83.13 v2(208.33,81.46) 208.69,81.1 208.69,78.83 208.34,78.48 208.34,76.17 208.51,76 PC1003.1 208.03,74.91 PR1001.2
+1.2V_DDR: length 149.9
  TOP w0.381: v1(55.07,108.67) 55.4,109 61.14,109 62.76,107.38 63.78,107.38
  TOP w0.508: v1(92.2,48.87) 92.2,48.19 RD20.1 ; CD48.1 93.47,48.23 v1(93.47,48.86)
  BOTTOM w0.203: UC1.W6 89.53,103.39 v1(89.15,103) 89.13,103 88.75,103.38 UC1.AA6 ; v1(84.04,105.78) 84.03,105.78 UC1.AG9 ; UC1.AP7 78.11,103.64 UC1.AP6 UC1.AR6 76.65,103.02 v1(76.57,103.02) ; UC1.AW6 74.43,103.39 v1(74.08,103.73) UC1.AY6 ; UC1.L6 96.29,103.39 96.49,103.58 96.93,103.58 UC1.K6 UC1.J6 98.06,103.3 v1(98.34,103.05) 98.06,102.82 UC1.J5 ; UC1.L12 96.64,107.55 96.98,107.55 UC1.K12 97.47,107.3 97.65,107.12 97.65,107.12 v1(97.7,107.07) ; v1(89.54,107.01) 89.4,107.01 89.11,107.3 UC1.Y12 ; UC1.AL11 80.54,106.33 v1(80.4,106.33) ; v1(84.11,103.05) UC1.AF6 ; v1(84.11,103.05) UC1.AF5 ; v1(84.11,103.05) UC1.AG5
  BOTTOM w0.254: v1(47.06,61.46) 47.07,61.47 JDIMM1.12 ; UC1.AT12 76.6,106.97 v1(76.74,106.97) UC1.AR12 ; JDIMM2.12 50.08,48.53 v1(49.86,48.31) ; v1(61.01,52.2) 60.57,51.77 JDIMM2.54 ; JDIMM2.130 79.58,49.11 v1(79.82,48.87) ; v1(85.86,106.98) 85.74,106.98 UC1.AE12 ; v1(55.21,60.22) 55.21,59.54 55.33,59.42 JDIMM2.33 ; JDIMM2.136 81.08,49.33 81.05,49.3 v1(81.05,48.87) 81.53,48.39 82.3,48.39 82.58,48.66 JDIMM2.142 ; JDIMM2.124 78.08,49.05 v1(78.23,48.89) ; v1(76.81,48.88) 76.81,49.01 76.57,49.24 JDIMM2.118 ; v1(57.1,61.42) 57.32,61.42 57.57,61.67 JDIMM1.54 ; v1(92.29,105.13) 92.29,103.93 92.6,103.62 92.7,103.62 UC1.R6 UC1.T6 91.95,103.39 v1(91.59,103.03) ; v1(81.32,106.93) 81.69,107.3 UC1.AJ12 ; JDIMM2.96 71.08,51.31 v1(70.11,52.27) ; v1(84.45,73.95) 85.28,73.95 85.82,73.41 JDIMM1.159 ; v1(65.83,59.59) JDIMM2.75
  BOTTOM w0.305: JDIMM1.142 79.57,61.88 79.3,61.6 v1(78.4,61.6) 78.38,61.6 78.07,61.9 JDIMM1.136 ; JDIMM2.154 v1(87.58,51.36) ; JDIMM2.123 77.83,59.44 v1(77.61,59.65) 76.75,59.65 76.32,59.22 JDIMM2.117 ; JDIMM1.163 86.82,72.37 86.39,72.81 86.39,73.86 86.62,74.1 v1(87.4,74.1) ; v1(84.32,73.32) 83.48,73.32 82.82,72.66 JDIMM1.147 ; JDIMM1.130 76.57,61.86 75.86,61.14 v1(75.31,61.14) 75.07,61.38 75.07,61.45 JDIMM1.124 ; JDIMM2.129 79.32,59.48 v1(79.2,59.6) ; v1(104.12,51.66) 104.07,51.62 JDIMM2.220 ; JDIMM1.75 62.82,72.03 63.17,72.37 63.17,72.49 63.65,72.97 v1(64.03,72.97) ; JDIMM1.199 95.82,72.52 95.25,73.09 v1(93.74,73.09) ; v1(91.38,61.64) 90.95,61.64 90.57,62.02 JDIMM1.178 ; JDIMM2.141 82.32,59.23 81.87,59.68 v1(81.18,59.68) 81.14,59.68 80.83,59.37 JDIMM2.135 ; JDIMM1.220 101.07,61.93 101.59,61.42 v1(102.01,61.42) ; JDIMM2.160 89.08,51.2 v1(89.23,51.36) ; JDIMM1.118 73.57,61.78 74.85,60.51 v1(75.42,60.51) ; JDIMM2.111 74.83,59.54 v1(75.05,59.76) ; v1(93.47,48.86) 93.58,48.96 JDIMM2.178 ; JDIMM1.135 77.82,71.97 77.48,72.31 v1(77.31,72.31) 76.66,72.31 76.32,71.98 JDIMM1.129 ; JDIMM1.154 84.57,61.56 v1(84.67,61.46) ; v1(88.09,60.14) 86.76,60.14 85.83,59.21 JDIMM2.147 ; v1(98.05,59.79) 98.07,59.77 98.21,59.77 98.83,59.15 JDIMM2.199 ; JDIMM1.153 84.32,72.29 84.32,72.29 v1(84.32,72.7) ; v1(71.37,72.97) 71.5,72.97 ; 71.5,72.97 72.97,72.97 73.32,72.62 JDIMM1.117 ; 71.5,72.97 71.88,72.59 71.88,71.93 71.82,71.87 JDIMM1.111 ; JDIMM2.163 89.83,59.28 v1(90.52,59.98) ; v1(85.7,48.87) 86.08,49.24 JDIMM2.148 ; v1(81.97,61.57) 82.75,61.57 83.07,61.9 JDIMM1.148 ; JDIMM1.123 74.82,72.59 v1(74.82,72.6) ; JDIMM1.141 79.32,72.86 78.86,73.33 v1(78.77,73.33) ; JDIMM1.112 72.07,61.75 71.79,61.46 v1(71.65,61.46) ; v1(74.92,48.92) 74.92,49.12 75.08,49.28 JDIMM2.112 ; v1(52.54,73.28) 52.33,73.28 52.02,72.97 52.02,72.35 52.32,72.05 JDIMM1.33 ; v1(69.38,61.38) 69.38,61.38 69.31,61.31 68.63,61.31 68.07,61.86 JDIMM1.96 ; JDIMM1.241 106.32,73.05 105.65,73.72 v1(104.8,73.72) ; JDIMM2.241 v1(109.32,59.56) ; v1(84.92,60.89) 85.66,60.89 86.07,61.31 JDIMM1.160 ; JDIMM2.159 88.83,59.25 88.57,59.5 v1(88.09,59.5) 87.68,59.5 87.32,59.14 JDIMM2.153
  BOTTOM w0.381: UC10.5 57,108.98 56.67,108.66 CH197.1
  BOTTOM w0.508: v1(55.07,108.67) 55.09,108.66 CH197.1
  vias: v1(41.73,61.92) v1(41.73,61.29) v1(42.32,61.92) v1(42.32,61.29) v1(63.66,60.65) v1(71.37,73.57) v1(77.29,73.17) v3(80.58,71.07)
+1.2V_RTM: length 15.3
  TOP w0.127: CP8.1 v3(27.77,100.86)
  TOP w0.203: UP2.46 v1(27.41,95.58) ; UP2.18 19.03,94.38 18.45,94.96 CP13.1 ; UP2.43 v1(27.3,94.38) ; UP2.6 23.66,98.09 v1(23.16,98.59) ; CP6.1 21.24,98.69 21.72,98.21 21.72,97.71 21.66,97.65 UP2.11 ; v1(19.63,95.58) UP2.15
  TOP w0.381: v1(21.19,98.06) 21.12,98.14 CP6.1 ; v1(17.85,94.4) 18.02,94.57 CP13.1
  TOP w0.508: CP7.1 22.5,99.24 v1(23.16,98.59)
  BOTTOM w0.381: CP5.1 23.42,98.33 v1(23.16,98.59) ; v1(21.19,98.06) 21.39,97.87 CP12.1 ; v1(27.3,94.38) 27.27,94.38 27.19,94.31 CP10.1 ; CP9.1 27.41,95.58 v1(27.41,95.58)
  vias: v1(22.92,89.81) v1(23.22,90.32) v1(26.92,97.66) v1(26.92,97.05)
+1.2V_RTM_IN: length 3.1
  TOP w0.102: RP51.2 23.55,85.09 v3(24.17,85.09)
  TOP w0.508: v1(21.9,86.57) 21.9,86.3 22.19,86 RP51.2
+1.2V_VCCPLL_OC: length 17.5
  TOP w0.254: v1(98.49,106.42) 97.91,105.84 97.91,104.74 98.31,104.33 98.31,103.72 98.83,103.2 98.83,101.93 99.17,101.6 99.41,101.6 100.25,100.75 v3(100.25,98.27) 100.25,97.51 99.92,97.18 CC37.1
  TOP w0.356: RC14.1 99.37,96.01 99.63,96.27 CC36.1
  TOP w0.381: CC37.1 CC36.1
  TOP w0.508: RZ67.1 98.59,93.88 CZ49.1 99.72,94.41 99.37,94.76 RC14.1
  BOTTOM w0.203: UC1.G11 v1(98.49,106.42)
  BOTTOM w0.254: UC1.BJ13 66.78,108.31 UC1.BH13 67.41,107.67 v1(67.6,107.67)
+1.2V_VCCPLL_OC_OUT:
  vias: v2(97.98,91.26)
+1.2VP: length 30.8
  BOTTOM w0.203: PCM18.1 40.36,42.02 PUM01.5
  BOTTOM w0.254: PCM18.1 40.77,40.79 PCM17.2 PRM10.2 42.51,40.74 43.04,41.26 43.04,43.18 43.92,44.06 43.92,50.95 43.45,51.42 41.31,51.42 40.64,52.09 40.64,55.27 41.07,55.7 41.07,59.13 39.75,60.45 39.75,61.44 39.52,61.67 v1(38.25,61.67)
  vias: v1(35.84,62.3) v1(35.84,61.67) v1(35.84,61.03) v1(36.14,62.84) v1(36.42,62.3) v1(36.42,61.67) v1(36.42,61.03) v1(36.75,62.86) v1(37.01,62.3) v1(37.01,61.67) v1(37.01,61.03) v1(37.59,62.3) v1(37.62,61.67) v1(37.62,61.03) v1(38.25,61.03) v1(38.82,46.16) v1(38.8,45.55) v3(37.17,65.75)
+1.05V_LDO: length 2.4
  TOP w0.508: CH16.1 187.6,34.29 187.6,33.55 v1(187.49,33.44)
  BOTTOM w0.254: v1(187.49,33.44) 187.39,33.54 UH1.BG46 UH1.BG45
+1.05V_VCCAMPHYPLL: length 1.2
  TOP w0.102: CH19.1 v2(166.12,32.47)
  vias: v1(163.48,31.67) v1(164.16,31.67)
+1.05V_XDP: length 2.4
  TOP w0.127: v1(116.93,115.53) 116.93,115.06 v3(117.16,114.83)
  BOTTOM w0.508: RC80.1 116.93,115.53 v1(116.93,115.53) RC251.2
+1.05V_XTAL: length 5.5
  BOTTOM w0.152: UH1.P3 170.12,54.95 UH1.P2 170.27,55.52
  BOTTOM w0.254: 170.27,55.52 170.27,57.38 170.98,58.09 RH731.1 170.98,58.44 CH20.1
+1.05VALW: length 62.7
  TOP w0.254: v1(172.48,46.71) 171.95,46.18 171.35,46.18 CH22.1
  TOP w0.381: v1(103.92,39.57) 103.92,41.13 105.57,42.78 105.57,46.45 v1(106.52,47.4) ; RE162.1 93.15,28.28 94.67,28.28 96.03,29.64 100.01,29.64 v3(101.81,31.44) 105.51,35.14 105.51,36.84 v1(104.34,38.02)
  TOP w0.508: v1(172.51,41.3) 172.2,41.3 171.72,41.78 CH15.1 ; v1(171.27,44.21) 169.74,44.21 CH14.1 ; CH12.1 172.45,43.54 172.48,43.57 v1(172.48,43.67) ; CH13.1 171.92,42.64 v1(172.49,42.07) ; CH62.1 174.75,46.09 v1(174.83,46)
  BOTTOM w0.381: 170.14,60.34 170.36,60.55 171.5,60.55 171.77,60.29 171.77,60.01 RH71.1 172.05,59.87 172.43,60.25 v1(172.43,60.43)
  BOTTOM w0.508: v1(160.05,44.37) 160.05,42.8 158.78,41.53 158.78,36.83 160.25,35.36 160.25,33.01 v1(160.68,32.58) 160.69,32.57 v1(160.69,31.93) ; v1(193.43,62.81) 193.43,62.93 RH748.1 ; v1(103.92,39.57) 103.92,38.44 v1(104.34,38.02) ; v1(147.08,52.89) 147.08,57.29 147.47,57.68 150.88,57.68
  vias: v1(107.72,121.79) v1(108.31,121.79) v1(108.92,121.82) v1(149.81,52.04) v1(150.22,51.61) v1(150.55,52.09) v1(150.62,51.18) v1(150.95,51.66) v1(151.03,50.75) v1(151.36,51.23) v1(151.77,50.8) v1(152.21,49.81) v1(152.21,48.63) v1(152.8,49.81) v1(152.8,48.63) v1(172.53,42.88) v1(173.2,46.69) v1(173.26,41.29) v1(174.06,45.13) v1(174.81,43.6) v1(174.82,42.81) v1(174.78,42.03) v1(175.27,48.07) v1(175.55,42.01) v1(175.58,45.18) v1(175.62,43.56) v1(175.55,41.23) v1(176.34,41.25) v1(177.08,41.26)
+1.05VP: length 15.6
  BOTTOM w0.254: PCH13.1 143.67,40.99 v2(140.27,37.59) 139.96,37.28 133.57,37.28 133.31,37.54 PRH10.2
+1.8V_AVDD: length 21.6
  TOP w0.508: RA5.2 37.14,21.81 v1(36.5,21.81)
  BOTTOM w0.508: v1(28.81,11.02) 28.81,12.25 29.96,13.4 37.67,13.4 39.44,15.17 39.44,17.38 37.81,19.02 37.81,20.01 36.5,21.32 v1(36.5,21.81)
+1.8V_CPVDD: length 3.5
  TOP w0.508: v1(38.67,19.95) 39.08,19.54 v2(39.43,19.54) 39.76,19.87 39.76,20.7 CA13.2 39.62,21.22 39.73,21.33 RA6.2
  vias: v1(26.05,13.79)
+1.8V_PHVLDO: length 4.2
  TOP w0.102: v2(177.01,49.68) 177.28,49.41 RH736.2
  TOP w0.254: v1(176.38,47.42) 177.19,48.23 RH736.2
  BOTTOM w0.254: v1(176.38,47.42) 176.06,47.1 UH1.AF19 175.84,46.97 175.84,46.45 UH1.AF20
+1.8V_PLLVDD: length 0.7
  TOP w0.508: RV583.2 204.88,112.22
  vias: v2(206.55,100.48)
+1.8V_PRIM: length 18.7
  TOP w0.254: RH723.2 28.96,104 28.11,103.15 27.41,103.15 27.15,103.4 RH722.2 26.62,102.61 v1(26.65,102.58)
  TOP w0.356: RH578.2 186.35,39.6 RH546.2
  TOP w0.381: v1(187.73,40.18) 187.73,39.94 187.36,39.57 RH546.2 ; v1(177.88,41.28) 177.99,41.28 178.43,41.73 RH150.2
  TOP w0.508: RE66.1 68.54,36.2 v1(68.97,36.63) ; v1(192.11,61.29) 192.11,60.53 v3(190.47,58.89) 189.31,57.73 RH588.1 ; QA1.1 38.06,24.92 v1(38.44,24.54)
  BOTTOM w0.203: v1(183.9,50.37) 184,50.47 UH1.BB11 ; UH1.AN15 v1(180.1,48.92) UH1.AR15 ; v1(176.36,46.66) 176.7,46.32 UH1.AG20 ; v1(177.11,46.66) 176.75,47.03 UH1.AG19
  BOTTOM w0.508: RG70.1 197.02,119.86
  vias: v1(185.96,60.62) v1(186.54,60.62) v1(187.15,60.63) v1(194.34,81.74) v1(194.34,81.1) v1(194.97,81.74) v1(194.97,81.1) v1(204.37,61.67) v1(205,61.67) v1(205.64,61.67) v1(206.27,61.67)
+1.8VA_TBTA_LDO: length 7
  TOP w0.127: v2(39.33,90.5) 38.56,91.27 CT100.1
  TOP w0.457: CT100.1 38.56,92.31 v1(38.94,92.7)
  BOTTOM w0.254: v1(38.94,92.7) 37.23,92.7 36.51,91.98 36.19,91.98 35.55,91.34 UT4.K1
+1.8VALW_EC:
  vias: v2(73.24,34.95)
+1.8VALWP: length 11.4
  TOP w0.127: v1(204.08,63.82) 204.08,64.56 v3(204.61,65.09)
  BOTTOM w0.254: PR1807.1 196.34,65.96 PC1807.1 196.34,63.92 198.95,61.31 202.1,61.31 202.36,61.57 PC1804.1
  vias: v1(203.47,63.78) v1(203.48,63.15) v1(204.09,63.19)
+1.8VD_TBTA_LDO: length 4.4
  BOTTOM w0.127: CT99.1 29.41,93.42 v2(29.07,93.76)
  BOTTOM w0.203: UT4.A2 31.05,90.49 30.25,91.28 30.25,91.38 30.23,91.41
  BOTTOM w0.381: 30.23,91.41 29.67,91.41
  BOTTOM w0.508: 29.67,91.41 29.41,91.66 CT99.1
+1.24V_PRIM_DPHY: length 3.4
  TOP w0.127: v2(176.01,44.74) 176.67,44.74 176.91,44.5 RH174.2
  TOP w0.381: v1(177.91,45.16) 177.32,44.57 RH174.2
  BOTTOM w0.203: UH1.AJ23 v1(177.91,45.16) UH1.AJ22
+1.24V_VCCLDOSRAM_IN: length 2.5
  TOP w0.127: v1(178.69,45.16) v2(179.09,45.56)
  TOP w0.381: RH174.1 178.69,44.95 v1(178.69,45.16)
  BOTTOM w0.203: UH1.AK22 v1(178.69,45.16) UH1.AK23
+1.35VGPU_BOOT1: length 1.2
  BOTTOM w0.102: v2(263.47,72) 263.18,71.7 PRW05.2
+1.35VGPU_BOOT1_1: length 1.6
  BOTTOM w0.102: 261.09,71.72 v2(259.51,71.72)
+1.35VGPU_EN: length 0.7
  TOP w0.102: v1(264.54,70.33) 264.54,70.2 v2(264.14,69.8)
+1.35VGPU_LGATE1: length 1
  TOP w0.102: v1(257.84,78.94) v3(256.82,78.94)
  vias: v1(257.84,78.31) v1(261.37,68.27) v1(261.98,68.3)
+1.35VGPU_PHASE1: length 9.9
  BOTTOM w0.102: v2(265.84,82.68) 265.33,83.2 PRW04.1
  BOTTOM w0.762: 260.2,68.98 258.62,70.56 258.62,74.71 PQW01.7
+1.35VGPU_PSI: length 2.7
  TOP w0.102: PRW08.1 v2(263.96,71.25)
  TOP w0.254: PCW13.1 PRW08.1 265.07,70.79 v1(265.23,70.64)
+1.35VGPU_PVCC: length 1.8
  BOTTOM w0.102: PCW09.1 261.4,64.83 v2(261.82,64.41)
+1.35VGPU_TON: length 1.2
  TOP w0.102: v2(267.86,66.46) 267.86,66.71 v1(267.22,67.35)
+1.35VGPU_TON_1: length 1
  BOTTOM w0.102: v2(269.72,67.54) 269.6,67.41 PRW03.1
+1.35VGPU_UGATE1: length 0.9
  TOP w0.102: v1(262.53,78.28) v3(261.68,78.28)
  vias: v1(263.14,78.28) v1(263.54,70.79) v1(263.94,70.36)
+1.35VGPU_VIN: length 11.8
  TOP w0.254: v1(267.21,65.62) 268.18,65.62 268.6,66.05 v2(268.6,72.71) 268.6,74.76 267.97,75.39
  BOTTOM w0.254: PRW02.1 v1(267.21,65.62)
  vias: v1(264.45,74.9) v1(264.81,74.32) v1(265.13,74.9) v1(265.52,74.33)
+1.35VS_VGA: length 25.4
  TOP w0.305: RV604.2 233.8,103.87 233.3,104.37 ; RV603.2 215.8,121.88 215.82,121.85
  TOP w0.381: 223.9,142.45 223.66,142.21 CV860.1 ; CV190.1 258.26,112.93 258.27,112.92
  TOP w0.4: v1(261.6,106.2) v1(261.6,105.6) ; v1(260,106.2) v1(260,105.6) ; v1(257.2,102.2) v1(257.2,103) v1(258,103) ; v1(260,126.1) v1(260,126.7) ; v1(261.6,126.7) v1(261.6,126.1) ; v1(261.6,114.5) v1(261.6,113.9) ; v1(260,114.5) v1(260,113.9)
  TOP w0.406: v1(227.9,145.25) v1(227.1,146.05) v1(226.3,145.25)
  TOP w0.457: RV605.2 233.32,110.25 233.3,110.22
  TOP w0.508: 258.41,107.11 258.4,107.1 CV182.1
  BOTTOM w0.127: 226.3,137.25 226.3,138.05
  BOTTOM w0.305: UV1.AB33 215.85,121.85 215.82,121.85 ; UV1.E13 230.07,105.22 ; UV1.T33 220.85,121.05 220.82,121.05 ; UV1.E16 230.07,107.72 ; 233.3,110.22 233.3,110.2 UV1.B19 ; 216.67,118.62 UV1.AA30 ; v1(258.8,101.4) UV8.N5 ; 221.67,118.62 UV1.T30 ; 230.9,110.22 230.9,110.2 UV1.E19 ; UV1.W33 218.75,122.05 ; UV1.B13 233.3,104.37 ; UV7.D3 213.3,148.05 ; 219.17,118.62 UV1.W30 ; UV1.B16 233.55,107.3
  BOTTOM w0.508: RV602.2 232.57,134.59 ; RG514.1 244.21,90.45 245.29,91.53 246.11,91.53
  vias: v1(203.3,149.65) v1(203.3,148.05) v1(203.3,146.45) v1(203.3,145.65) v1(203.9,149.65) v1(203.9,148.05) v1(203.9,146.45) v1(203.9,145.65) v1(204.9,145.25) v1(205.7,146.05) v1(205.7,145.25) v1(206.5,149.25) v1(206.5,148.45) v1(206.5,146.05) v1(207.3,148.45) v1(208.11,149.26) v1(208.1,147.65) v1(208.1,146.85) v1(211.3,149.25) v1(211.3,146.85) v1(212.9,146.05) v1(213.7,149.25) v1(213.7,148.45) v1(213.7,146.05) v1(213.7,145.25) v1(214.49,145.26) v1(215.5,149.65) v1(215.5,148.05) v1(215.49,146.45) v1(215.49,145.65) v1(216.1,149.65) v1(216.1,148.05) v1(216.13,146.45) v1(216.13,145.65) v1(223.9,149.65) v1(223.9,148.05) v1(223.9,146.45) v1(223.9,145.65) v1(224.5,149.65) v1(224.5,148.05) v1(224.5,146.45) v1(224.5,145.65) v1(225.5,146.05) v1(226.3,148.45) v1(227.1,149.25) v1(228.7,149.25) v1(228.7,146.85) v1(229.1,148.1) v1(231.9,149.25) v1(231.88,146.83) v1(232.7,149.25) v1(232.7,146.05) v1(233.5,149.25) v1(233.51,148.46) v1(233.52,147.67) v1(233.5,146.05) v1(234.3,146.05) v1(234.3,145.25) v1(235.1,145.25) v1(236.1,149.65) v1(236.1,148.05) v1(236.1,146.45) v1(236.1,145.65) v1(236.7,149.65) v1(236.7,148.05) v1(236.7,146.45) v1(257.2,125.1) v1(257.2,124.3) v1(257.2,116.3) v1(257.2,95.8) v1(257.2,95) v1(257.6,126.1) v1(257.6,114.5) v1(257.6,106.2) v1(257.6,105.59) v1(258,124.3) v1(258,123.5) v1(258.02,117.08) v1(258,115.5) v1(257.99,103.81) v1(258,97.4) v1(258,96.6) v1(258,95) v1(258.4,126.7) v1(258.4,126.1) v1(258.4,106.18) v1(258.4,105.6) v1(258.55,113.99) v1(258.6,90.14) v1(258.8,121.9) v1(258.8,118.7) v1(258.8,116.3) v1(258.77,98.23) v1(259.36,90.14) v1(259.63,121.87) v1(259.6,103.8) v1(260,94) v1(260,93.04) v1(260.12,90.14) v1(260.4,123.5) v1(260.4,122.7) v1(260.4,116.3) v1(260.4,104.6) v1(260.4,96.6) v1(260.88,90.14) v1(261.2,123.5) v1(261.2,121.9) v1(261.2,118.7) v1(261.2,117.1) v1(261.2,103) v1(261.2,102.2) v1(261.2,101.4) v1(261.2,98.2) v1(261.2,97.4) v1(261.2,96.6) v1(261.52,89.45) v1(261.6,94) v1(261.65,90.14) v1(261.9,93.04) v1(262.03,90.75) v1(262.28,89.45) v1(262.41,90.13) v1(262.79,90.75) v1(263.04,89.43) v1(263.13,90.12) v1(263.55,90.75) v1(263.89,90.12) v1(264.31,90.75) v1(264.69,91.39) v1(264.66,90.09) v1(265.07,90.75) v1(265.42,90.09) v1(265.46,91.39) v1(265.84,90.75) v1(266.14,90.12) v3(253.35,140.35)
+1V8_AON: length 55.8
  TOP w0.508: RV574.2 224.44,94.47 224.11,94.13 223.35,94.13 223.06,94.43 RV55.2 223.05,94.7 RV512.2 RV513.2 221.51,94.26 222.2,93.57 222.2,93.01 221.94,92.76 RV682.2 ; v1(207.13,88.35) 207.13,89.9 v1(206.62,90.41) 206.62,92.3 205.98,92.94 205.45,92.94 ; RV158.2 RV157.2 v1(256.27,86.66) ; v1(257.12,89.87) 256.8,90.19 RV147.2 RV148.2 ; v1(231.75,91.48) 231.42,91.81 RV159.2 RV146.2 230.62,92.21 230.19,91.78 228.8,91.78 228.38,92.2 RV150.2 RV593.2 ; v1(235.61,91.51) 234.67,92.45 RV149.2
  BOTTOM w0.305: UV19.5 v1(231.6,86.91) 231.52,86.83 CV530.1 ; UG31.5 204.55,91.14 204.66,91.25 CG527.1 204.66,92.54 205.06,92.94 205.45,92.94
  BOTTOM w0.356: UV20.5 212.34,89.42 CV529.1 212.17,89.25 v1(211.56,89.25)
  BOTTOM w0.381: v1(242.27,90.03) 242.27,90.17 241.98,90.45 RG516.1 ; v1(225.6,89.18) 225.6,89.72 RV42.2 ; RV191.2 221.77,87.84 v1(221.77,88.41) ; PR1006.1 206.93,79.57 v1(207.2,79.84) ; v1(240.71,88.33) 239.48,88.33 238.94,88.87 UG22.5 238.94,89.15 239.22,89.43 CG246.1 ; CV212.1 207.16,90.95 v1(206.62,90.41) 206.62,90.01 206.97,89.66 UV14.5 ; v1(240.58,81.15) 240.58,81.55 241,81.97 CG440.1 241.32,82.36 241.56,82.6 UG27.5
  BOTTOM w0.508: PRW07.1 PRW09.1 v1(266.13,72.81) ; v1(235.61,91.51) 235.22,91.13 RV57.2 ; v1(218.83,89.14) 218.83,89.76 RV192.2 ; RG510.1 198.1,115.01 ; PRV04.1 256.21,63.73 v1(257.75,62.19) 257.75,59.69 v1(257.98,59.46) ; v1(15.8,105.76) RV678.1 15.11,106.03 14.81,106.34 RV679.1 ; 204.32,95.03 203.98,95.03 202.89,96.12 RV532.2 RV41.2 ; RV39.1 207.18,88.39 v1(207.13,88.35) ; RV683.1 208.75,89.99 v1(209.12,89.62)
  vias: v1(192.32,122.86) v1(192.34,122.06) v1(193.17,121.89) v1(196.72,125.64) v1(220.69,91.05) v1(221.12,91.67) v1(223.29,91.01) v1(223.29,90.42)
+1V8_MAIN: length 7
  TOP w0.102: 204.9,97.15 v3(204.9,96.29)
  TOP w0.381: CV120.1 222.89,97.12 224.3,98.53 CV119.1 224.3,99.13 224.24,99.19 CV118.1 CV117.1 224.95,100.94 224.96,100.93
  BOTTOM w0.508: RG512.1 v1(195.54,118.93)
  vias: v1(192.9,126.19) v1(193.04,125.48) v1(193.39,124.88) v1(193.86,125.46)
+1VS_GFX: length 3.7
  TOP w0.508: RV655.1 210.63,101.09 210.63,101.93
  BOTTOM w0.508: v1(203.98,90.23) 203.84,90.09 203.04,90.09 202.1,91.03 RG544.1
  vias: v1(201.17,81.11) v1(201.17,80.47) v1(201.17,79.84) v3(212.04,112.44)
+2.5V_MEM:
  vias: v1(111.03,69.02) v1(111.03,68.4) v1(115.48,59.21) v1(115.65,59.79) v1(116.1,59.21) v3(111.9,68.65)
+2.5VP: length 1.1
  TOP w0.127: v1(117.53,62.79) v2(117.53,63.84)
  vias: v1(118.14,62.8)
+3.3V_ADP_DCIN: length 32.6
  TOP w0.508: v1(30.4,113.05) 30.4,113.41 30.81,113.82 30.81,114.22 31.22,114.63 31.22,115.18 31.59,115.55 v1(31.59,116.36) ; PRS45.1 31.01,60.97 31.31,61.26 32.08,61.26 32.42,61.6 v2(33.85,61.6) v1(34.8,61.6) ; PRS02.1 34.38,124.83 PDS01.2 35.68,123.84 35.83,123.99 36.5,123.99 36.72,124.2 v1(36.72,124.66) ; DT19.2 67.41,44.61 v1(67.01,45.02) ; PRS04.1 v1(33.97,128.87)
  BOTTOM w0.508: PRS34.1 24.41,36.36 24.11,36.66 24.11,37.67 v1(24.42,37.98) ; v1(30.66,38.81) 29.9,38.81 PRS32.1 ; PR22.1 32.07,115.87 v1(31.59,116.36) ; PC9.1 41.77,118.03 41.77,121.35 40.93,122.19 39.68,122.19 39.38,121.89 39.38,121.27 38.89,120.79 PU01.5 38.22,120.82 37.64,121.4 37.64,123.18 36.97,123.85 36.47,123.85 PR14.1 36.39,124.07 36.72,124.4 v1(36.72,124.66)
+3.3V_ANA_PCIE: length 0.5
  BOTTOM w0.203: v1(23.66,125.2) 23.99,125.53 UT1.L16
+3.3V_ANA_USB2: length 0.5
  BOTTOM w0.203: UT1.J16 v1(23.66,125.85)
+3.3V_FLASH: length 24.7
  TOP w0.254: RT67.1 34.67,88.88 34.76,88.97 35.25,88.97 35.57,89.29 35.57,90.19 35.26,90.5 RT112.1
  TOP w0.381: v1(33.9,91.62) 32.97,90.7 RT66.1
  TOP w0.508: v1(32.93,119.98) 32.93,119.63 32.69,119.39 RT48.1 RT50.1 RT49.1 ; v1(15.99,86.1) 15.99,86.57 v3(15.75,86.82) 14.7,87.87 v1(14,87.87)
  BOTTOM w0.203: v1(33.9,91.62) 33.93,91.59 33.93,91.11 UT4.G1
  BOTTOM w0.381: UT2.8 15.39,89.67 15.65,89.42 CT45.1 14.03,87.83 v1(14,87.87) ; v1(34.49,72.79) 34.5,72.79 RT128.2 35.14,73.17 34.93,73.38 UT3.8 ; RT74.1 36.11,82.72 v1(36.38,82.45) 36.14,82.22 RT125.2 36.14,81.5 36.38,81.5 36.61,81.72 RT127.2 ; RT126.2 34.27,81.46 33.92,81.11 v1(33.62,81.11)
  BOTTOM w0.508: RT51.1 16.54,86.65 v1(15.99,86.1)
+3.3V_LC: length 1.1
  TOP w0.356: CT46.1 26.33,129.8 v1(26.27,129.74)
  BOTTOM w0.203: v1(26.27,129.74) 25.94,130.08 UT1.R6
  vias: v1(30.78,132.48) v2(28.41,132.57)
+3.3V_TBT_SX: length 21.1
  TOP w0.127: v1(18.57,136.25) 18.28,136.25 v3(17.84,135.81)
  TOP w0.305: RT32.1 24.11,131.94 23.86,132.18 23.86,132.47 v1(23.31,133.02) 22.92,132.63 RT94.1
  TOP w0.356: CT47.1 21.64,129.82 v1(21.71,129.75)
  TOP w0.381: v1(37.1,91.35) 37.1,91.8 RT61.2 ; RT153.1 17.86,128.55 17.86,127.45 v1(17.95,127.36)
  BOTTOM w0.203: v1(21.71,129.75) UT1.F8
  BOTTOM w0.254: v1(37.65,95.43) 37.82,95.26 37.82,94.55 37.91,94.46 RT70.1
  BOTTOM w0.305: RT30.1 v1(18.57,136.25)
  BOTTOM w0.381: RT28.1 v1(28.28,136.24) ; RT152.1 v1(21.74,136.27) ; RT33.1 v1(20.47,136.25) ; RT86.1 16.02,127.68 15.84,127.5 RT97.2 13.76,126.97 v1(13.23,126.44) ; RT26.1 v1(25.55,136.27) ; Q29.2 29.13,82.02 28.61,82.02 27.67,82.95 RT166.1 27.49,83.26 27.07,83.68 v1(26.94,83.68) ; RT27.1 v1(26.31,136.25) ; RT31.1 v1(23.65,136.27)
+3.3V_TBT_SX_R: length 2.8
  TOP w0.127: v1(35.79,92.78) 35.75,92.74 v2(35.75,92.1)
  TOP w0.381: RT61.1 CT102.1 36.35,92.78 v1(35.79,92.78)
  BOTTOM w0.254: UT4.H2 34.55,90.09 v1(34.64,90)
+3.3V_VBUS_IN: length 57.1
  TOP w0.254: PCS13.1 19.69,37.71 19.22,38.17 19.22,38.67 19.5,38.95 PUS02.5 ; PCS14.1 22.78,38.7 23.04,38.95 PUS03.5
  TOP w0.508: PCS13.1 v1(20.05,38.36) ; v1(37.86,70.49) 38.29,70.06 PCS16.1 ; v1(46.89,48.64) 44.7,46.45 v3(44.7,44.92) 44.7,43.4 45.23,42.87 45.23,41.99 43.13,39.89 v1(42.35,39.89) 39.7,39.89 PRB38.1 ; PRS12.1 30.04,50.21 29.44,49.62 v1(29.44,45.25) ; v1(33.7,121.64) 34.07,121.64 34.38,121.95 PDS01.3 ; PCS14.1 23.28,37.71 v1(23.53,37.96) ; v1(65.49,44.91) 65.76,44.63 DT21.2
  BOTTOM w0.508: v1(38.43,65.47) 38.6,65.47 38.94,65.81 38.94,68.15 38.44,68.65 PUS04.3 38.44,69.91 v1(37.86,70.49) ; v1(46.89,48.64) 49.07,46.46 51.61,46.46 52.26,45.81 53.55,45.81 55.69,43.67 56.83,43.67 56.97,43.81 59.51,43.81 61.13,45.43 63.06,45.43 63.59,44.91 v1(65.49,44.91)
+3.3V_WLAN: length 1.7
  TOP w0.127: v3(29.34,108.9) 30.01,108.23 CW6.1
  vias: v1(27.29,113.75) v1(27.61,114.25) v1(28.23,114.26) v1(28.27,113.66) v1(28.48,107.6) v1(29.1,107.61) v1(29.36,105.37) v1(47.09,107.67) v1(47.37,107.14) v1(47.38,106.54) v3(28.97,106.16) v3(47.51,105.89)
+3V_1.8V_PGPPA: length 6.4
  TOP w0.127: v3(180.43,39.6) 180.43,39.65 179.9,40.18 v1(179.81,40.18)
  TOP w0.508: v1(190.09,37.62) 190.18,37.71 RH506.2 ; v1(179.81,40.18) 179.27,40.18 CH63.1 179.05,40 178.84,40.21 178.84,40.59 178.69,40.74 RH150.1 179.52,40.82 RH143.2 180.26,40.82 RH701.2
  BOTTOM w0.254: UH1.AN32 179.59,40.4 v1(179.81,40.18) ; RH128.2 190.12,37.59 v1(190.09,37.62)
+3V_DVDD: length 8.7
  TOP w0.127: v2(39.4,18.12) 38.16,18.12 RA2.2
  TOP w0.508: RA3.2 v1(34.19,22.25)
  BOTTOM w0.508: v1(34.19,22.25) 34.19,20.74 37.48,17.45 v1(37.94,17.45)
  vias: v1(36.02,10.05) v1(36.68,10.08) v1(36.83,10.87)
+3V_PCH_PRIM: length 68.1
  TOP w0.254: RH724.2 RH725.2 26.2,104.95 26.23,104.93 26.55,104.93 26.82,105.2 v1(26.82,105.24)
  TOP w0.305: 176.82,40.02 176.82,39.67 177.38,39.11 178.22,39.11 178.37,39.27 179.06,39.27 RH734.2
  TOP w0.356: RH62.1 189.95,44.74 v1(189.95,44.27) ; RTPM9.1 196.41,35.1 195.73,35.79 v1(195.73,35.79)
  TOP w0.381: RH721.2 188.96,48.45 RH63.1 189.82,48.73 190.06,48.97 190.49,48.97 190.75,49.24 190.75,49.82 190.93,49.99 ; RC252.1 180.65,34.85 v1(180.35,34.54)
  TOP w0.406: v1(183.36,49.88) 183.41,49.83 184.16,49.83 184.74,50.41 CC43.1
  TOP w0.508: CH31.1 189.67,52.13 190.93,50.88 190.93,49.99 191.44,49.48 v1(192.3,49.48) ; 185.58,52.12 185.58,51.38 184.99,50.79 CC43.1 ; v1(63.07,48.77) 64.2,49.9 83.63,49.9 83.91,50.18 84.66,50.18 85.03,49.81 85.03,48.87 85.01,48.86 RE11.2 RE10.2 ; RTPM10.1 202.63,39.55 202.63,39.56 202.55,39.64 v1(202.55,40.55) ; RH162.1 164.95,25.45 163.87,25.45 163.39,25.93 160.66,25.93 160.08,26.5 v1(160.08,27.9)
  BOTTOM w0.203: UH1.AN21 179.49,45.71 v1(179.68,45.52) ; v1(180.26,42.93) UH1.AP26
  BOTTOM w0.254: UH1.AW9 183.07,51.82 v1(183.3,51.59) ; UH1.AP26 UH1.AN26 ; v1(183.36,49.88) 183.36,49.75 183.49,49.62 UH1.BB14 ; UH1.BB7 v1(183.66,52.53) UH1.AY8 ; UH1.AN24 v1(179.77,44.04) ; UH1.V23 v1(172.5,45.18) ; v1(194.21,52.65) RH29.2 RH687.2
  BOTTOM w0.305: RH675.1 RH674.1
  BOTTOM w0.356: RT29.1 v1(28.92,136.22) ; v1(191.59,36.94) 191.53,36.88 RH12.1 ; v1(189.95,44.27) RH675.1
  BOTTOM w0.381: RH737.2 182.11,60.28 v1(182.43,60.6)
  BOTTOM w0.508: RH64.1 v1(192.3,49.48) RH66.1 ; RH65.1 190.29,40.5 v1(190.32,40.52) 190.32,40.68 189.94,41.06 RH524.1 ; v1(182.43,60.6) 182.4,60.63 RSPI1.2
  vias: v1(21.33,103.88) v1(21.77,104.3) v1(22.72,30.99) v1(23.36,30.99) v1(24.68,115.43) v1(24.68,114.82) v1(24.68,114.24) v1(36.81,25.28) v1(36.78,24.69) v1(37.31,24.93) v1(46.22,44.93) v1(46.91,39.53) v1(46.95,25.23) v1(47.37,39.1) v1(47.64,25.25) v1(48.22,25.25) v1(152.02,30.3) v1(152.46,30.85) v1(152.65,30.29) v1(175.13,39.17) v1(175.32,38.61) v1(176.17,38.81) v1(176.25,34.33) v1(176.25,33.74) v1(176.46,28.31) v1(177.04,28.31)
+3V_RTM: length 15.6
  TOP w0.127: v2(25.58,102.91) 25.58,102.32 RP33.1
  TOP w0.203: UP2.24 20.1,91.98 19.95,91.84 19.95,91.48 v1(20.08,91.36) ; v1(25.66,98.12) UP2.1
  TOP w0.254: RP37.1 24.35,88.81 RP35.1 23.77,88.55 v1(24.09,88.23)
  TOP w0.381: v1(21.15,88.13) 21.18,88.16 21.18,88.65 21.15,88.68 ; RP48.2 21.15,88.68 ; 21.15,88.68 RP49.2 ; v1(23.16,102.67) 23.16,102.34 RP34.1 24.45,102.01 24.45,102.02 RP33.1 ; RP38.1 26.65,88.01 v1(26.65,88.01) ; v1(20.19,88.11) 19.96,88.34 RP36.1
  TOP w0.508: v1(25.68,87.15) 25.68,87.63 25.98,87.92 RP25.2 25.97,88.43 RP24.2 ; RP28.1 26.23,98.69 v1(25.66,98.12) ; v1(20.19,88.11) 20.21,88.09 CP25.1
  BOTTOM w0.356: v1(20.08,91.36) 20.09,91.38 CP24.1
  BOTTOM w0.381: v1(25.66,98.12) 25.35,97.81 CP26.1
+3V_SPI: length 10.2
  TOP w0.508: RH735.1 RH78.1 205.25,39.03 v1(205.48,38.8) ; v1(208.12,36.82) 208.14,36.84 RH75.1
  BOTTOM w0.381: UH4.8 212.81,40.53 CH49.1 213.16,40.26 v1(213.56,39.86) ; v1(205.48,38.8) 204.02,38.8 203.43,38.2 202.88,38.2 202.59,38.49 RH74.1
  BOTTOM w0.508: RSPI1.1 183.91,61.82 184.35,61.38 v1(184.35,60.59)
+3VALW: length 248.1
  TOP w0.356: v1(139.01,32.88) 139,32.87 CC302.1 139,31.58 ; RE57.1 70.28,31.97 RE56.1
  TOP w0.381: v1(62.77,32.46) 62.77,31.62 RE59.1 ; UC16.5 134.87,32.57 134.24,31.94 CC298.1 ; v1(93.07,34.33) 93.02,34.29 RE18.2 ; v1(72.42,31.4) 71.86,31.97 RE58.1 RE57.1 ; PR5.2 47.02,137.95 v1(47,137.97) ; CC302.1 139.52,32.29 139.8,32.57 UZ21.5 ; RE55.1 v1(68.35,32.53) ; v1(28.38,81.52) 28.18,81.72 28.18,84.81 RT134.1
  TOP w0.508: v1(59.24,105.67) 59.24,105.02 58.28,104.06 58.28,99.13 54.3,95.15 54.3,81.17 47.44,74.31 40.97,74.31 v1(39.04,72.39) ; PR905.2 46.58,119.73 46.58,119.29 v1(46.48,119.19) ; RA11.2 v1(29.93,22.68) ; 139,31.58 138.53,31.11 134.25,31.11 133.85,31.52 CC298.1 ; PR41.2 210.56,35.66 210.86,35.37 v1(210.86,35.24) ; v1(32.48,31.74) 32.48,32.74 31.65,33.58 31.65,35.9 33.91,38.16 v1(34.46,38.16) ; v1(138.65,40.06) 138.2,40.51 137.1,40.51 136.92,40.33 134.13,40.33 133.17,41.29 132.36,41.29 130.3,43.36 130.3,49.39 129.74,49.95 129.74,50.77 129.25,51.27 126.25,51.27 v1(125.8,51.72) ; v1(106.22,34.94) 99.8,28.52 97.32,28.52 RE164.1 ; RE150.2 73.6,46.23 73.13,46.7 v1(73.13,47.13) ; v1(183.57,40.72) 183.57,41.39 RH685.1 ; v1(207.44,35.88) 207.71,35.61 RTPM6.2 ; v1(150.81,36.45) 151.46,35.8 151.46,34.61 RH89.1 152.86,34.61 154.99,32.47 154.99,31.04 v1(154.74,30.78) ; v1(190.04,47.06) 189.71,47.06 RH706.1 ; PRB27.1 v1(270.56,58.36) ; RE25.1 v1(72.3,25.04) ; RE21.2 89.27,46.93 v1(89.27,46.54) ; RL7.1 v1(45.87,36.33) ; R35.1 v1(237.54,40.49)
  TOP w1.016: 197.5,54.81 197.5,55.21 196.2,56.5 196.2,59.63 194.83,61 194.83,64.2 ; 203.91,69.58 203.91,67.59 212.88,58.61 238.01,58.61
  BOTTOM w0.254: PU901.15 48.75,118.95 49.15,119.35 49.56,119.35 PC909.1
  BOTTOM w0.381: PRM06.1 35.04,38.75 v1(34.46,38.16)
  BOTTOM w0.508: PR33.1 46.43,122.34 v1(46.11,122.02) ; v1(138.65,40.06) 138.65,38.16 138.38,37.89 PRH01.1 ; PC909.1 50.15,118.81 v1(50.22,118.74) ; v1(139.01,32.88) 142.41,29.49 154.08,29.49 154.74,30.15 v1(154.74,30.78) ; v1(234.59,29.52) 234.59,30.66 236.46,32.54 236.46,34.15 237.54,35.23 v1(237.54,40.49) ; PR1803.1 v1(203.23,64.68) ; v1(263.32,30.66) 263.32,31.66 263,31.99 JIOB1.9 ; v1(73.13,47.13) 73.13,46.53 72.2,45.6 71.4,45.6 70.65,44.86
  BOTTOM w0.762: 99.85,42.67 100.47,42.06 103.05,42.06 104.31,43.31 109.01,43.31 110.45,41.87 110.45,39.17 v1(106.22,34.94) 101.39,34.94
  vias: v1(12.43,126.87) v1(23.76,111.12) v1(28.42,110.21) v1(28.45,109.52) v1(28.93,109.88) v1(42.19,34.62) v1(42.51,35.15) v1(42.82,34.62) v1(43.14,35.15) v1(43.46,34.62) v1(51.74,31.06) v1(51.74,30.43) v1(52.32,31.06) v1(52.32,30.43) v1(52.91,31.06) v1(52.91,30.43) v1(53.49,31.06) v1(53.49,30.43) v1(57.23,114.34) v1(65.39,33.87) v1(66,33.87) v1(66.59,33.87) v1(68.91,45.01) v1(69.52,45.01) v1(70.22,40.83) v1(70.8,40.83) v1(79.65,25.09) v1(80.29,25.09) v1(80.92,25.09) v1(81.56,25.09) v1(84.73,25.04) v1(85.37,25.04) v1(85.99,25.02) v1(86.64,25.04) v1(99.5,43.66) v1(100.19,43.66) v1(100.48,35.63) v1(100.48,35) v1(126.15,58.82) v1(173.6,38.81) v1(174.19,38.82) v1(190.61,39.75) v1(194.73,66.09) v1(194.72,65.42) v1(195.39,66.09) v1(195.4,65.41) v1(197.43,53.16) v1(197.43,52.58) v1(197.43,52) v1(197.43,51.41) v1(197.43,50.8) v1(197.45,50.21) v1(197.46,49.63) v1(198.01,53.16) v1(198.01,52.58) v1(198.01,52) v1(198.01,51.41) v1(198.01,50.8) v1(198.03,50.18) v1(198.64,50.18) v1(200.66,71.36) v1(201.16,71.72) v1(201.23,71.09) v1(204.79,69.57) v1(238.47,59.49) v1(239.06,59.49) v3(69.76,42.53) v3(97.45,31.29) v3(239.04,58.61)
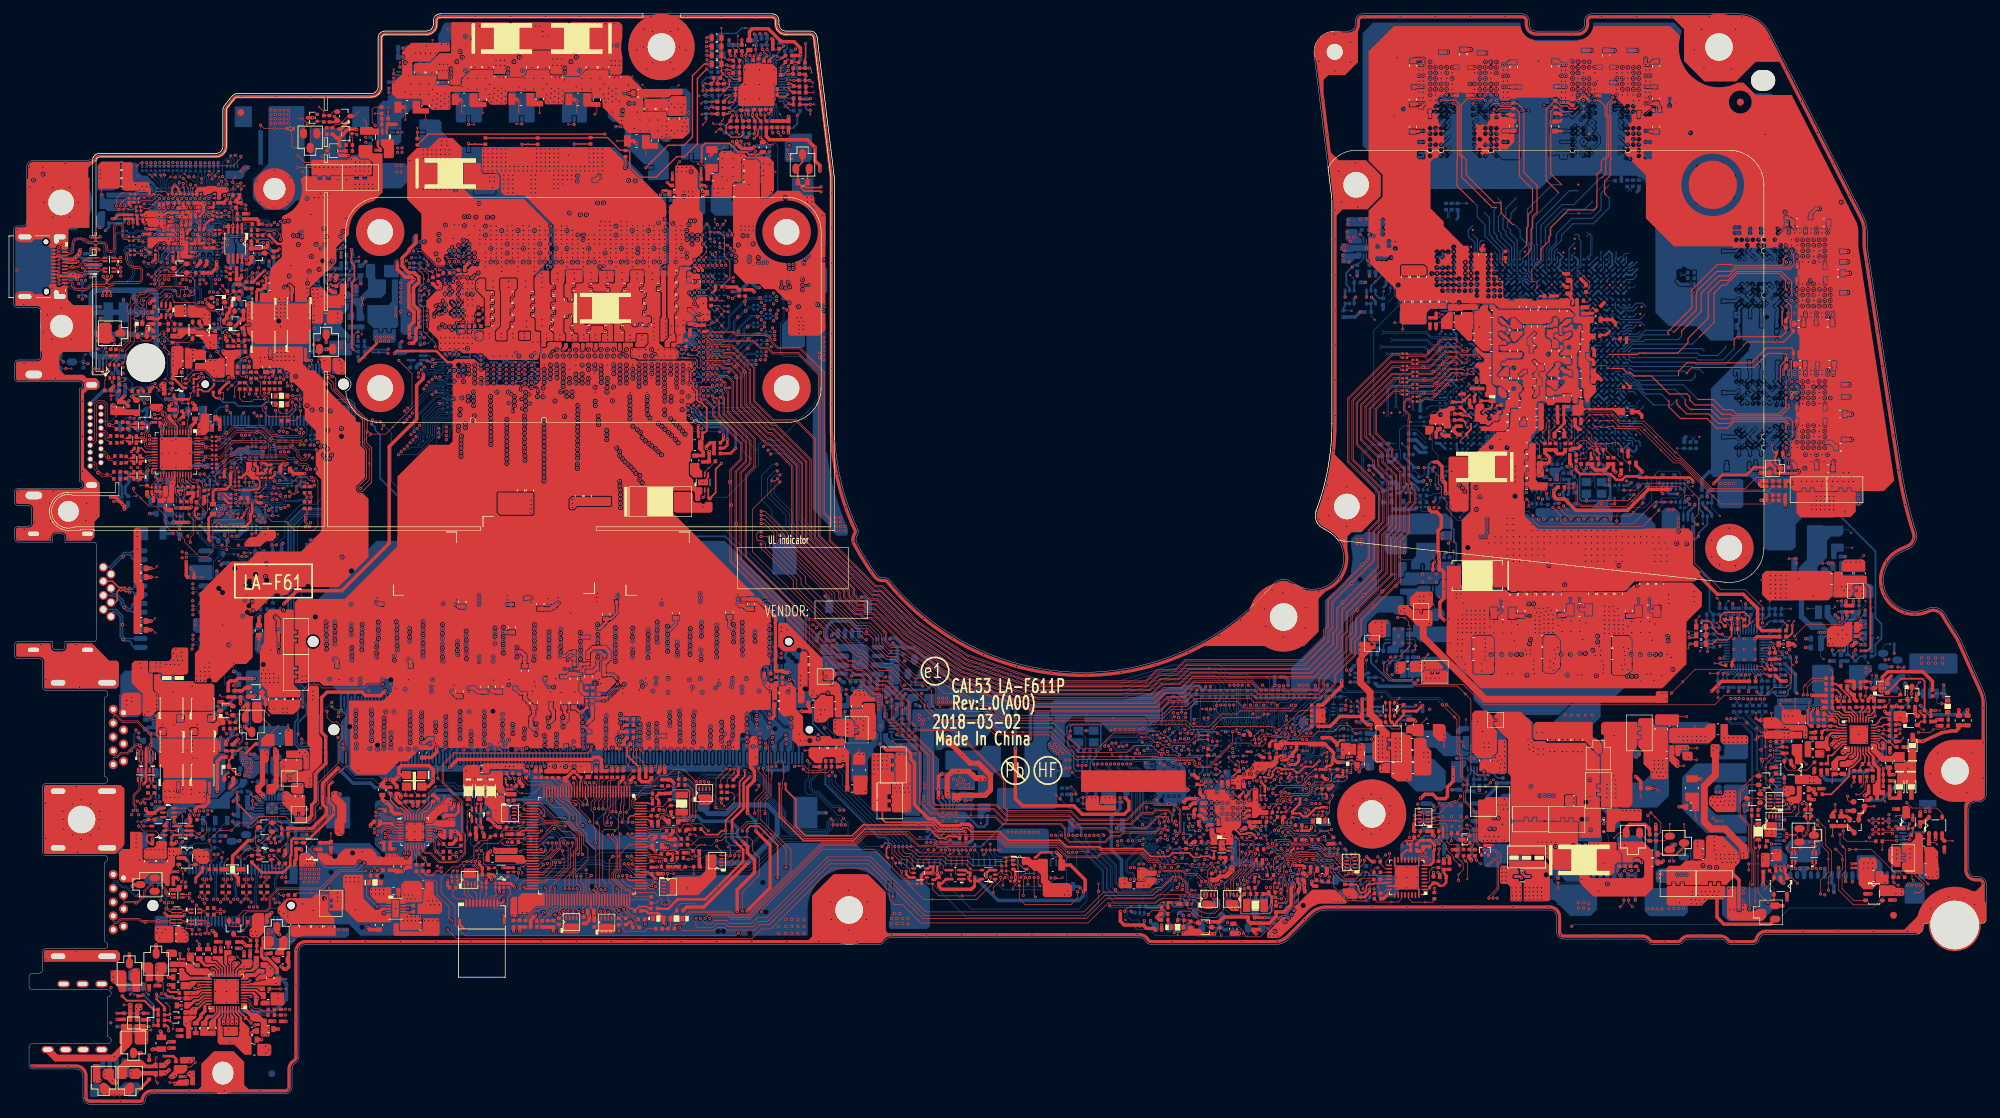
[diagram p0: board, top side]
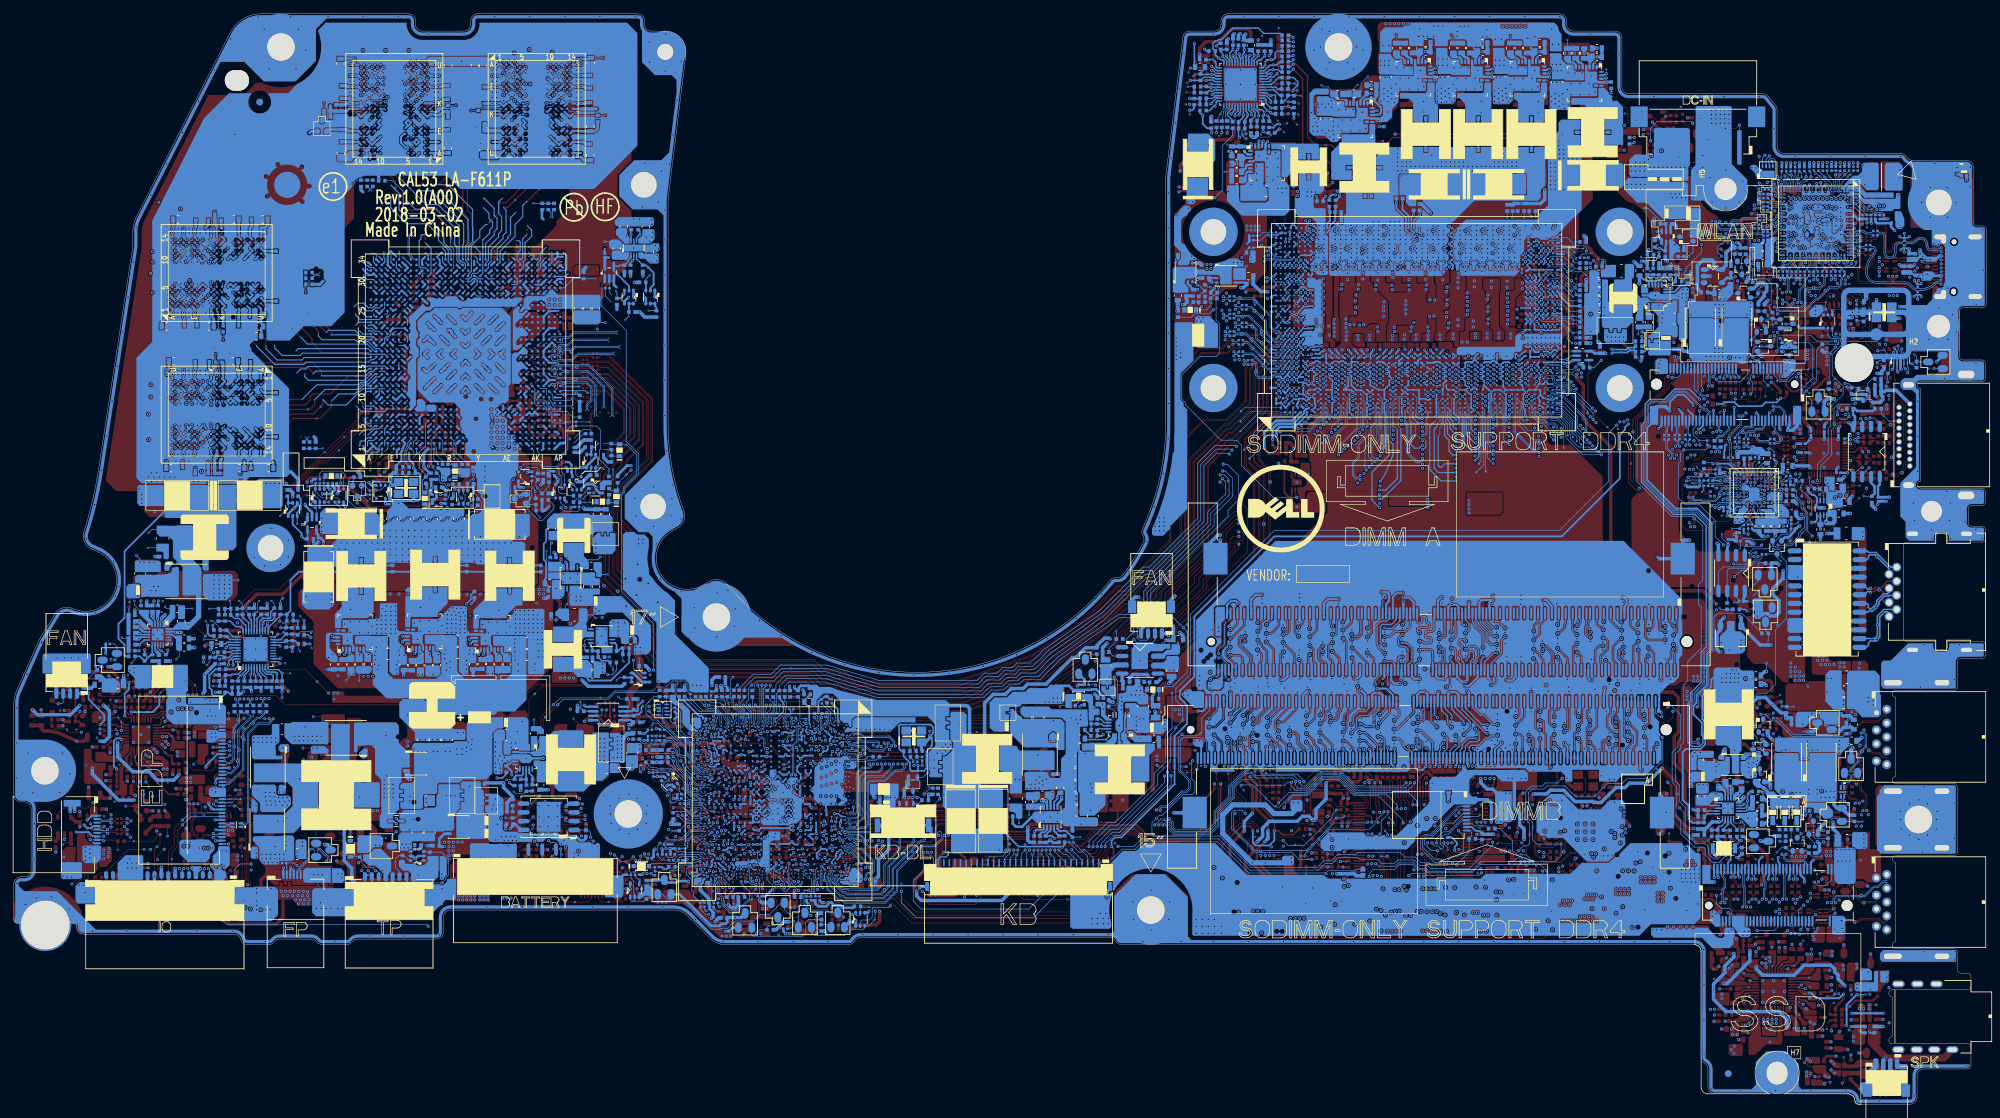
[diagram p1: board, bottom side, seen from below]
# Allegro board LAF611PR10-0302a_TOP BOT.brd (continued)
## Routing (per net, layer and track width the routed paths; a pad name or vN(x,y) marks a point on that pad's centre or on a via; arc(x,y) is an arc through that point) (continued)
+3VALW_DSW: length 13.4
  TOP w0.127: v3(185.65,29.46) 185.84,29.65 CH34.1
  TOP w0.381: RH717.2 185.75,32.13 186.08,31.8 186.08,31.73 186.05,31.7 v1(186.05,31.69) 186.05,31.33 185.84,31.13 CH34.1
  TOP w0.508: RH162.2 v1(166.05,25.93)
  BOTTOM w0.254: RH515.2 190.89,34.05 v1(191.31,34.05) 191.57,34.31 RH545.2
  BOTTOM w0.305: v1(186.05,31.69) 186.03,31.7 186.01,31.7 185.66,32.06 UH1.BE49 185.66,32.36 UH1.BE48 ; RH533.2 188.11,35.3 187.97,35.45 187.94,35.45 v1(187.94,35.44)
  BOTTOM w0.381: 184.82,29.11 184.68,28.98 RH453.2 184.68,28.26 184.19,27.76
  BOTTOM w0.508: v1(184.43,26.94) 184.19,27.18 184.19,27.76 ; 184.82,29.11 184.82,29.76 186.05,30.99 v1(186.05,31.69)
+3VALW_EC: length 49.2
  TOP w0.203: CE11.1 73.55,39.61 UE1.43 ; CE13.1 92.03,33.35 91.77,33.61 UE1.103 ; CE21.1 92.91,38.77 92.76,38.92 92.09,38.92 91.58,38.41 UE1.115 ; UE1.5 87.49,46.4 v1(87.63,46.54) ; CE8.2 82.03,46.73 81.89,46.59 UE1.19 ; UE1.22 80.69,46.06 80.3,46.45 v1(80.15,46.45) ; CE10.1 83.49,28.44 UE1.82
  TOP w0.305: v1(89.18,26.52) 89.41,26.29 89.41,25.73 RE31.2
  TOP w0.381: RE166.2 81.06,48.14 81.93,47.28 CE8.2 ; v1(92.97,32.61) 92.83,32.61 92.28,33.16 CE13.1 ; RE30.2 88.65,25.99 v1(89.18,26.52)
  TOP w0.457: RE8.2 87.34,48.73 v1(87.21,48.86) ; RE46.1 75.54,48.27 v1(75.54,48.88) ; v1(86.44,48.87) 86.56,48.74 RE9.2
  TOP w0.508: v1(80.15,46.45) 79.72,46.89 CE20.1 79.96,47.24 80.86,48.14 RE166.2 ; RE3.1 99.16,34.49 v1(99.16,35.9) RE1.1 ; CE9.1 88.16,47.07 v1(87.63,46.54) ; v1(92.27,38.39) 92.61,38.39 CE21.1 ; RE169.2 RE15.2 74.77,26.64 v1(75.49,27.37) ; RE17.2 v1(84.24,48.86) ; v1(66.86,38.32) 66.92,38.38 PRS50.1 66.82,39.13 PRS49.1 ; R43.1 64.54,111.83 v1(64.36,111.66) ; RE165.2 95.35,39.33 v1(94.95,38.92) ; CE10.1 83.92,27.33 83.95,27.3 v1(83.98,27.3) 83.97,27.3 RE49.1 ; CE11.1 v1(73.69,39.06)
  BOTTOM w0.457: 73.7,44.08 72.14,44.08 71.59,43.54 v1(71.59,40.83)
  BOTTOM w0.508: v1(68.58,47.15) 68.26,46.84 68.26,42.87 67.5,42.11 67.5,40.44 66.86,39.79 v1(66.86,38.32)
  vias: v1(66.62,47.16) v1(67.29,47.14) v1(69.17,47.16) v1(73.6,27.75) v1(74.19,27.75) v3(65.46,48.25)
+3VALW_PD: length 9.9
  TOP w0.381: RT134.2 28.8,88.58 29.2,88.98 v3(29.63,88.98) 30.7,88.98 31.36,89.63 CT88.1 31.36,91.31 v1(31.55,91.51)
  BOTTOM w0.203: UT4.B1 v1(31.55,91.51) ; UT4.H1 34.55,91.79 34.67,91.9 v1(34.69,91.9) 34.73,91.94 34.73,92.08 35.01,92.36 35.01,92.61
  BOTTOM w0.381: CT101.1 35.01,92.61
+3VALWP: length 5.8
  BOTTOM w0.254: PU301.14 210.79,47.92 210.31,47.44 PR307.1 210.36,46.94 PR306.2 210.31,46.2 v1(209.67,46.2) ; PR304.1 214.1,47.79 214.68,47.21 v1(215.44,47.21)
  BOTTOM w0.508: v1(126.31,58.17) 126.39,58.25 126.71,58.25 PR504.1
  vias: v1(199.92,52.91) v1(199.92,52.27) v1(199.92,51.64) v1(199.92,51) v1(199.92,50.37) v1(199.92,49.73) v1(200.56,52.91) v1(200.56,52.27) v1(200.56,51.64) v1(200.56,51) v1(200.56,50.37) v1(200.56,49.73) v3(201.57,46.95)
+3VLP: length 44
  TOP w0.254: RE29.2 100.23,39.01 101.84,39.01 102.4,39.57 v1(102.99,39.57) 102.99,41.07 105,43.08 105,46.68 105.76,47.44 v1(105.76,48.27) ; v1(110.52,32.75) 110.52,37.46 107.75,40.23 106.53,40.23 106.1,39.8 v1(106.1,39.55) ; R42.1 64.43,112.6 v1(64.36,112.53)
  TOP w0.508: v1(203.51,44.23) 204.14,44.86 205.27,44.86 205.91,44.22 207.1,44.22 207.4,44.52 207.4,45.89 208.24,46.73 v3(208.24,47.43) v1(208.24,48.72) ; v1(76.2,48.87) 76.2,48.26 RE167.1
  BOTTOM w0.254: v1(102.99,39.57) 102.99,38.16 103.71,37.44 105.65,37.44 106.1,37.88 v1(106.1,39.55)
  BOTTOM w0.381: v1(182.45,25.02) 181.87,25.02 181.35,25.55 D1.2
+3VS: length 206.7
  TOP w0.254: RH537.2 180.99,47.27 181.88,47.27 182.12,47.51 RH676.1 182.12,48.15 182.62,48.66 183.23,48.66 RH553.1 183.47,48.48 185.08,48.48 RH680.1 185.9,47.99 186.75,48.84 187.99,48.84 v1(188.85,49.69) ; 204.87,34.65 204.78,34.57 UTPM1.8
  TOP w0.305: v1(199.99,54.93) 199.68,54.93 199.68,54.94 R49.1 199.09,55.54 Q11.5 Q11.2
  TOP w0.33: RH573.2 186.1,42.09 186.56,41.63 187.12,41.63 188.34,42.84 188.94,42.84 189.09,42.99 RH179.2 189.85,42.99 v1(189.94,42.9)
  TOP w0.356: v1(167.55,29.17) 167.51,29.21 RH512.2 R83.1 ; RH180.1 131.32,32.55
  TOP w0.381: RD13.1 115.76,48.85 v1(115.74,48.87) ; v1(119.96,49.06) 119.75,48.85 RD14.1 ; v1(190.9,46.07) 190.5,45.67 RH501.1 ; RH521.1 186.07,43.49 184.99,42.4 RH573.2 ; CH201.1 195.4,29.98 196.16,30.75 v1(196.16,31.14) ; v1(199.99,54.93) 199.99,55.27 201.06,56.34 R48.1 202.97,56.89 v1(203.81,57.73) ; RH728.1 192.29,47.43 v1(192.26,47.41) 191.62,47.41 RH502.1 ; v1(88.04,54.53) 88.36,54.86 RD15.1 ; 204.87,34.65 204.97,34.65 205.4,35.08 205.4,36.66 205.54,36.81 v1(205.54,37.16) 205.54,37.56 204.9,38.2 CTPM3.1 203.88,38.2 CTPM4.1 203.5,38.19 203.02,37.72 203.02,37.62 RTPM8.1 ; UH14.5 132.27,34.11 132.54,34.38 CC301.1 133.01,34.1 132.98,34.07 v1(132.98,33.47) ; v1(255.55,64.43) 254.83,64.43 PRV02.1 PRV01.1 ; UE2.5 69.58,32.97 69.29,33.25 CE22.1 68.68,32.98 69.1,32.57 v1(69.1,32.47)
  TOP w0.457: RE156.2 68.02,39.14 v1(67.81,39.36) ; R5.1 v1(256.55,50.8)
  TOP w0.508: v1(256.45,61.25) 255.64,61.25 PRV10.2 ; RA2.1 38.1,19.66 36.74,21.02 36.2,21.02 35.85,21.36 35.85,22.52 36.13,22.8 ; v1(206.91,70.07) 206.32,70.67 206.32,72.64 206.88,73.2 v3(206.88,74.62) 206.88,76.98 206.52,77.34 PR1002.1 206.22,78.82 v1(206.19,78.85) 206.19,79.69 206.05,79.83 206.05,82.99 206.51,83.46 206.51,85.06 205.86,85.71 205.11,85.71 204.78,86.03 v1(204.78,86.34) ; v1(116.61,135.05) 116.61,135.86 115.91,136.56 v1(115.91,138.46) 114.79,139.58 109.33,139.58 108.86,140.06 PRZ17.1 ; RT168.1 27,121.82 v1(26.42,121.23) ; v1(112.27,62.51) 111.4,62.51 RD2.1 RD1.1 110.19,62.81 110.19,70.56 v1(108.23,72.51) 107.66,73.08 CD10.1 105.59,73.08 CD9.1 ; v1(82.91,55.08) 83.71,55.88 RD3.1 ; R57.1 260.5,48.06 v1(260.39,47.94) ; v1(132.98,33.47) 131.66,33.47 131.32,33.13 131.32,32.55 ; 195.07,56.41 v1(195.07,58.63) ; 195.07,56.41 195.07,55.67 195.82,54.93 v1(196.38,54.93) ; 195.07,56.41 194.77,56.11 191.85,56.11 190.42,54.68 RH33.2 ; v1(238.63,35.2) 238.4,34.97 R36.1 ; RL3.1 63.45,37.65 63.95,38.16 v1(63.95,38.52) ; v1(239.64,88.95) 239.61,88.97 236.47,88.97 233.44,85.94 226,85.94 224.35,87.59 223.23,87.59 222.81,88.01 222.81,88.78 v1(222.82,88.8) 223.34,89.32 RG51.1 ; CD40.1 114.95,57.53 115.19,57.29 CD39.1 114.07,56.84 v1(114,56.9) ; R16.1 260.02,44.08 v1(260.49,44.08) ; v1(25.84,101.5) 26.23,101.11 RP28.2 ; v1(25.31,84.2) v1(23.11,84.2) ; RE153.1 v1(278.26,54.77) ; RTPM7.2 v1(206.9,35.53) ; RS3.1 v1(271.96,42.71)
  BOTTOM w0.254: v1(196.16,31.14) UH3.5 ; RH463.1 192.27,47.41 v1(192.26,47.41) ; RH520.1 194.74,53.64 v1(194.19,53.64) 194.03,53.64 193.61,54.06 RH551.1 ; RT58.1 v1(27.78,89.61) ; UP1.5 24.5,84.52 24.76,84.26 25.25,84.26 v1(25.31,84.2)
  BOTTOM w0.305: RT58.1 28.34,89.61 RT57.1 ; JDIMM1.255 109.82,72.21 109.78,72.25 109.65,72.38 109.18,72.85 108.57,72.85 v1(108.23,72.51) ; v1(192.26,47.41) 191.27,47.41 QH4.2 ; v1(114,56.9) 113.34,56.9 112.83,57.42 JDIMM2.255 ; RG505.1 204.69,86.43 v1(204.78,86.34) ; U2.1 196.03,55.56 C21.1
  BOTTOM w0.356: v1(175.57,31.11) 176.57,30.11 RH69.2 ; RH557.1 RH561.1 ; RE122.1 v1(272.05,65.25)
  BOTTOM w0.381: 199.25,122.52 CG438.1 199.85,122.5 UG25.5 ; Q10.2 226.87,35.92 v1(227.29,35.51) 227.7,35.92 Q10.5 ; RG506.1 239.9,89.22 v1(239.64,88.95) ; v1(190.9,46.07) 190.76,46.2 190.09,46.2 189.83,45.94 QH4.5 ; RH557.1 169.39,29.04 168.97,28.62 167.81,28.62 167.55,28.88 v1(167.55,29.17) 167.04,29.17 166.66,28.78 165.79,28.78 165.43,28.42 163.94,28.42 R82.1 ; Q23.2 130.44,61.43 RE121.1 131.32,60.7 v1(131.5,60.53)
  BOTTOM w0.508: PRW18.1 v1(262.7,64.13) ; QX3.1 18.01,102.07 19.29,102.07 v1(19.36,102.01) ; RC270.1 58.27,106.82 58.57,107.12 v1(58.91,107.12) ; JIOB1.12 v1(266,32.18) ; RH571.2 182.89,60.14 183.06,60.32 v1(183.06,60.59) ; v1(222.82,88.8) 223.3,89.28 RG50.1 ; C21.1 196.08,54.93 v1(196.38,54.93) ; v1(30.01,78.06) 30.26,78.31 R24.1 31.06,78.26 Q6.2 ; RH710.2 v1(192.29,51.26) RH709.2 ; v1(119.41,61.54) 119.89,61.06 RE152.1 ; v1(195.07,58.63) 195.09,58.64 R29.1 ; R33.1 226.44,37.19 v1(226.75,36.87) ; PR901.1 42.72,120.22 v1(42.72,120.53) ; Q24.2 v1(271.72,63.31) ; R28.1 v1(203.81,57.73) ; R34.1 v1(192.29,50.24)
  vias: v1(25.87,109.09) v1(25.86,108.5) v1(25.87,107.91) v1(36.14,23.91) v1(39.02,71.52) v1(46.81,30.57) v1(46.84,29.98) v1(46.84,29.39) v1(47.47,30.56) v1(47.47,29.98) v1(47.47,29.39) v1(56.52,30.28) v1(56.9,29.7) v1(57.1,30.28) v1(57.48,29.7) v1(57.68,30.28) v1(58.06,29.7) v1(172.4,28.52) v1(173,28.5) v1(193.44,51.86) v1(194.23,48.55) v1(195.9,49.12) v1(195.9,48.54) v1(240.69,33.22) v1(241.33,33.22) v1(241.96,33.22) v1(259.77,47.2) v1(259.77,46.57) v1(260.4,47.2) v1(260.4,46.57)
+3VS_CAM: length 4.5
  TOP w0.127: v2(257.87,41.78) 258.24,42.15 258.24,43.64
  BOTTOM w0.305: v1(257.15,43.61) 257.15,43.31 256.49,42.65 JEDP1.29
+3VS_SSD:
  vias: v1(20.69,24.85) v1(20.83,25.42) v1(21.44,24.81) v1(21.88,25.31) v1(34.36,25) v1(34.57,24.44) v1(34.99,25.01) v1(35.17,24.41) v1(38.45,27.84) v1(39.07,27.61) v1(39.63,27.82) v1(39.64,27.2) v3(21.13,24.04) v3(41.75,28.98) v3(43.31,28.03)
+3VS_TBT: length 6.1
  TOP w0.127: v3(33.65,120.77) 33.56,120.68 32.97,120.68 v1(32.94,120.71)
  TOP w0.305: v1(28.21,129.76) 28.24,129.79 RT76.2 28.9,129.84 CT49.1
  TOP w0.356: CT48.1 22.45,128.37 v1(22.36,128.45)
  TOP w0.508: RT168.2 27.92,121.55 v1(27.63,121.26)
  BOTTOM w0.203: UT1.H9 v1(22.36,128.45)
  BOTTOM w0.381: v1(31.08,131.6) 31.17,131.69 31.55,131.69 RT20.1 ; v1(16.58,127.49) 16.66,127.56 RT21.1
  BOTTOM w0.508: LT4.2 32.94,121.48 v1(32.94,120.71)
  vias: v1(15.21,129.49) v1(16.04,130.02)
+5V_HDD: length 8.2
  TOP w0.127: v3(276.94,31.88) 275.74,33.07 CS7.1 ; v3(274.83,32.37) 274.61,32.59 274.61,33.54 ; 275.04,33.53 275.04,33.2 276.34,31.9 276.34,31.22 275.74,30.62 v3(275.07,30.62)
  vias: v1(274.35,36.92) v1(274.35,36.28) v1(274.35,35.65) v1(274.98,37.17) v1(274.98,36.54) v1(274.98,35.9) v1(274.98,35.27)
+5V_KB_BL: length 1.2
  TOP w0.127: C34.1 v3(160.34,43.74)
  vias: v1(157.89,44.37) v1(158.52,44.37) v1(159.16,44.37)
+5V_PVDD:
  vias: v3(31.27,8.98)
+5VALW: length 156.2
  TOP w0.254: v1(102.37,92.74) 101.54,91.92 101.54,88.53 CZ51.1 100.47,87.85 UZ16.4 ; UZ7.4 173.66,36.27 173.6,36.2 CZ40.1 173.11,35.68 172.92,35.88 172.56,35.88 172.56,35.88 171.71,35.88 171.56,35.72 170.68,35.72 170.04,36.36 167.64,36.36 167.13,35.85 164.48,35.85 163.34,36.99 157.31,36.99 157.06,37.24 152.33,37.24 151.38,38.19 143.92,38.19 142.66,39.44 138.51,39.44 137.96,39.99 137.31,39.99 137.15,39.83 133.91,39.83 132.96,40.78 126.12,40.78 125.64,41.26 125.64,42.61
  TOP w0.381: v1(34.48,87.03) 34.48,85.61 34.24,85.37 34.24,84.35 33.52,83.62 32.96,83.62 v1(32.92,83.67)
  TOP w0.508: v1(49.61,141.04) 49.52,141.13 48.4,141.13 47.09,139.82 PD2.3 ; v1(104.59,139.37) 104.59,138.99 105.28,138.31 106.85,138.31 v1(107.06,138.52) ; PR4.1 46.68,139.82 PD2.3 ; PRZ53.1 106.42,155.2 106.85,155.62 109.16,155.62 111.02,153.77 112.88,153.77 113.8,152.85 v1(113.8,151.92) 113.64,151.76 PRZ77.1 ; PD2.3 47.07,138.74 PD3.3
  BOTTOM w0.203: v1(34.48,87.03) 34.55,86.96 UT4.H10
  BOTTOM w0.254: PUI04.15 63.3,149.16 v1(63.21,149.25) ; PUH01.7 134.85,43.73 134.4,44.18 v1(134.4,44.36) 134.4,44.62 PCH10.1 ; PUG01.15 55.63,148.43 55.04,148.43 v1(54.95,148.52) ; PUV03.2 237.24,65.37 v1(237.51,65.1) ; v1(79.71,149.33) 79.95,149.33 80.12,149.16 PUI02.15 ; v1(88,143.2) 88.46,143.2 88.52,143.14 PUI01.15 ; PUA01.15 104.75,139.21 v1(104.59,139.37) ; v1(217.44,65.09) 217.28,65.24 PUV01.2 ; v1(227.36,65.23) 227.16,65.42 PUV02.2 ; PUI03.15 71.54,149.16 v1(71.45,149.25)
  BOTTOM w0.305: v1(219.4,67.26) 219.17,67.49 PUV01.15 ; PUG01.2 56.87,150.51 v1(56.62,150.75) ; CZ86.1 112.46,119.56 UZ9.3 ; PRI01.1 88.24,145.74 88.49,145.49 ; PUV02.15 229.09,67.69 v1(229.13,67.73) ; UP1.6 24,83.9 CP29.1 v1(23.98,83.21) ; 88.49,145.49 88.49,145.19 87.55,144.25 87.55,143.52 87.87,143.2 v1(88,143.2) ; 88.49,145.49 89.72,145.49 90.03,145.17 PUI01.2 ; PUI02.2 81.63,151.27 v1(81.39,151.52) ; 114.12,117.88 v1(114.12,117.88) ; PUI03.2 73.38,151.27 v1(73.13,151.52) ; v1(239.23,67.69) 239.11,67.57 PUV03.15 ; UZ15.3 115.5,118.72 114.79,118.02 CZ97.1 ; v1(64.88,151.52) 65.12,151.27 PUI04.2
  BOTTOM w0.381: v1(7.18,107.42) 6.3,108.3 Q19.3
  BOTTOM w0.457: PCI35.1 PRI09.1 v1(72.83,152.32) ; v1(64.56,152.32) PRI13.1 PCI45.1 ; v1(81.1,152.33) PRI05.1 80.38,152.33 PCI25.1 ; PCG08.1 PRG01.1 v1(56.29,151.55)
  BOTTOM w0.508: PRW01.1 v1(259.25,67.37) ; v1(228.95,62.04) PCV38.1 227.78,62.83 PRV51.1 ; RH747.1 197.37,60.48 202.26,60.48 v1(203.18,61.4) ; PRI01.1 88.23,146.29 PCI15.1 ; RG513.1 245.39,88.9 245,88.51 v1(245,87.91) ; CZ97.1 114.12,117.88 ; RG511.1 194.06,113.92 v1(194.79,114.65) RG509.1 ; PRM05.2 32.43,43.05 PRM04.1 31.86,41.84 v1(31.73,41.97) ; v1(112.03,118.96) 112.47,119.4 CZ86.1 ; PRV55.1 238.98,62.94 PCV48.1 v1(240.01,62.92) ; PR2504.1 123.93,61.74 123.48,62.19 121.42,62.19 v1(121.18,61.95) ; v1(218.91,62.1) PCV28.1 217.71,62.95 PRV47.1 ; PRZ71.1 v1(113.8,151.92) ; RG543.1 203.43,94.33 204.32,94.33 ; v1(21.95,102.06) 21.98,102.09 22.98,102.09 23.44,101.62 23.44,100.38 Q18.3 ; v1(107.06,138.52) 107.14,138.6 PRA01.1 PCA08.1
  vias: v1(26.19,35.84) v1(26.73,41.83) v1(26.82,35.84) v1(26.88,42.42) v1(27.48,42.44) v1(27.46,35.84) v1(28.06,42.53) v1(28.06,41.94) v1(28.09,35.84) v1(28.65,42.45) v1(30.02,83.67) v1(30.61,83.67) v1(30.85,85.5) v1(31.36,85.11) v1(31.75,83.67) v1(32.33,83.67) v1(48.01,32.79) v1(48.01,32.16) v1(48.64,32.79) v1(48.64,32.16) v1(49.28,32.79) v1(49.28,32.16) v1(49.91,32.79) v1(49.91,32.16) v1(112.17,138.76) v1(124.46,50.37) v1(124.46,49.73) v1(124.46,49.1) v1(124.46,48.51) v1(124.92,44) v1(125.04,50.37) v1(125.04,49.73) v1(125.04,49.1) v1(125.04,48.51) v1(125.68,50.37) v1(125.68,49.73) v1(125.68,49.1) v1(125.68,48.51) v1(126.31,50.37) v1(126.31,49.73) v1(126.31,49.1) v1(126.31,48.51) v1(233.45,61.92) v1(234.09,61.92) v1(234.72,61.92) v1(272.29,30.46) v1(273.13,31.07) v1(273.1,30.46) v3(27.61,36.69) v3(49.42,28.13) v3(124.38,47.76)
+5VALWP: length 3.5
  BOTTOM w0.203: PU501.14 128.4,54.32 PR510.1 128.61,53.3 PR509.2
  BOTTOM w0.254: PR509.2 127.95,53.29 127.74,53.49 v1(127.74,53.49)
  vias: v1(127.48,45.77) v1(127.7,46.34) v1(127.66,45.19) v1(128.12,45.77) v1(128.17,50.62) v1(128.32,46.34) v1(128.3,45.19) v1(128.8,50.62) v1(128.75,45.77) v1(128.89,45.16) v1(128.96,46.34) v1(129.38,45.77) v1(129.5,45.16) v1(129.59,46.34) v1(130.38,50.74) v3(129.53,42.52)
+5VS: length 112.4
  TOP w0.457: v1(106.06,27.95) 109.41,31.3 109.41,37.47 v1(107.34,39.54)
  TOP w0.508: RE151.1 277.58,61.19 276.18,62.6 271.12,62.6 270.33,61.8 270.33,61.24 ; v1(144.9,51.46) 144.9,44.2 145.92,43.18 153.35,43.18 154.56,41.97 160.67,41.97 161.33,42.63 161.33,43.8 v1(160.76,44.37) ; v1(275.81,40.17) CS8.1 276.37,40.84 US2.5 ; v1(257.69,66.32) 257.41,66.6 PRV05.2 ; 106.65,49.42 106.65,48.71 107.13,48.23 107.13,46.85 106.14,45.86 106.14,42.11 v1(106.17,42.09) ; U3.5 v1(256.54,29.54) ; RS5.2 v1(279.3,36.5)
  BOTTOM w0.203: UG12.4 195.66,122.27 v1(195.87,122.06) 196.13,121.8 CG386.1 ; v1(246.84,66.3) 246.98,66.44 PUV101.17
  BOTTOM w0.381: C30.1 120.65,58.14 RE82.1 120.65,59.08 v1(120.4,59.33)
  BOTTOM w0.457: v1(106.17,42.09) 107.34,40.91 v1(107.34,39.54)
  BOTTOM w0.508: 32.46,70.81 32.27,71 31.61,71 31.28,70.67 30.49,70.67 29.97,71.19 29.97,72.87 30.86,73.77 30.86,74.62 29.37,76.11 v1(29.37,77.18) ; RE104.1 116.19,67.77 v1(116.69,68.28) ; v1(144.9,51.46) 144.9,58.07 143.66,59.31 141.91,59.31 141.07,60.15 139.31,60.15 138.67,60.8 136.01,60.8 132.18,64.63 131.72,64.63 130.29,66.06 RE100.1 128.68,66.32 127.54,67.45 126.86,67.45 v1(126.74,67.33) ; F3.2 160.99,44.61 v1(160.76,44.37)
  vias: v1(20.83,100.43) v1(21.34,100.79) v1(22.3,22.13) v1(22.32,21.51) v1(33.11,70.64) v1(33.41,72.95) v1(36.41,8.39) v1(36.49,7.4) v1(36.88,7.88) v1(56.36,26.54) v1(56.95,27.13) v1(56.95,26.54) v1(57.53,27.13) v1(57.53,26.54) v1(58.12,27.13) v1(58.12,26.54) v1(58.7,27.13) v1(58.7,26.54) v1(107.26,52.88) v1(252.96,35.95) v1(252.96,35.31) v1(270.26,60.49) v1(270.25,59.87) v1(271.56,37.02) v1(271.59,36.43) v1(271.7,35.84) v1(272.35,36.79) v1(272.39,36.18) v1(272.39,35.55) v3(107.24,50.2)
+VBUS_DC_SS: length 0.8
  TOP w0.127: 29.68,52.4 29.92,52.64 v3(29.92,53.14)
  vias: v1(21.25,52.6) v1(21.25,52.01) v1(21.26,51.43) v1(21.26,50.82) v1(24.38,51.24) v1(25.11,51.24) v1(25.84,52.52) v1(25.84,51.93) v1(25.78,51.26) v1(25.9,50.11) v1(26.49,50.08) v1(29,51.25) v1(29.61,51.16)
+VBUS_DC_TRIP: length 6
  TOP w0.102: 20.74,55.7 v3(19.93,55.7)
  TOP w0.508: v1(33.15,57.34) 33.15,57.38 33.63,57.86 PRS44.1 33.86,56.95 33.48,56.56 33.48,55.95
  BOTTOM w0.508: v1(21,56.5) 20.7,56.2 PRS08.1 19.7,56.2 PCS09.1
  vias: v1(21.57,54.99) v1(23.19,54.91) v1(25.25,56.53) v1(25.69,56.04) v1(26.54,54.91)
+VCC_CORE: length 41.6
  BOTTOM w0.127: 89.59,121.23 UC1.W30 89.54,121.51 ; UC1.U29 91.78,120.86 ; UC1.U29 91.45,120.53 ; UC1.U29 91.12,120.86 ; UC1.Y29 89.42,120.86 ; UC1.Y29 88.76,120.86 ; UC1.Y29 89.09,120.53 ; 82.33,121.51 UC1.AJ30 82,121.84 ; UC1.AH29 82.79,120.53 ; UC1.AH29 83.12,120.86 ; UC1.AH29 82.46,120.86 ; 82.46,121.51 UC1.AH30 82.5,121.23 ; 84.36,121.84 UC1.AF30 84.65,121.8 ; 91.91,120.86 UC1.T29 ; UC1.T29 92.57,120.86 ; UC1.T29 92.24,120.53 ; 79.64,121.84 UC1.AM30 79.97,121.51 ; UC1.AL29 80.76,120.86 ; UC1.AL29 80.42,120.53 ; UC1.AL29 80.09,120.86 ; 79.97,120.86 UC1.AM29 ; UC1.AM29 79.31,120.86 ; UC1.AM29 79.64,120.53 ; UC1.AC29 86.72,120.53 ; UC1.AC29 87.05,120.86 ; UC1.AC29 86.39,120.86 ; 93.53,121.23 UC1.P30 93.81,121.84 ; 92.24,121.84 UC1.T30 91.91,121.51 ; UC1.W29 90.2,120.86 ; UC1.W29 89.87,120.53 ; UC1.W29 89.54,120.86 ; 87.18,121.51 UC1.AB30 87.51,121.84 ; 80.42,121.84 UC1.AL30 80.09,121.51 ; 88.8,121.23 UC1.Y30 89.42,121.51 ; 87.18,120.86 UC1.AB29 ; UC1.AB29 87.84,120.86 ; UC1.AB29 87.51,120.53 ; 85.15,121.84 UC1.AE30 85.48,121.51 ; 94.6,121.84 UC1.N30 94.93,121.51 ; UC1.AJ29 82,120.53 ; UC1.AJ29 82.33,120.86 ; UC1.AJ29 81.67,120.86 ; 84.08,120.58 UC1.AF29 84.36,120.53 ; 91.16,121.23 UC1.U30 91.78,121.51 ; UC1.AM33 79.34,123.51 ; UC1.AM33 79.64,123.22 ; UC1.AM33 79.64,123.8 ; 93.48,120.86 UC1.P29 93.81,120.53 ; 86.44,121.23 UC1.AC30 87.05,121.51
  BOTTOM w0.254: UC1.N14 v1(95.02,109.19) ; UC1.P13 v1(94.11,108.27) ; UC1.W13 v1(89.54,108.27) ; UC1.N13 v1(95.02,108.27) ; UC1.R13 v1(93.2,108.27) ; UC1.V14 v1(91.37,109.19) ; UC1.AC13 v1(86.79,108.27) ; UC1.P14 v1(94.11,109.19) ; UC1.AA13 v1(87.71,108.27) ; UC1.AN14 v1(78.56,109.19) ; v1(80.39,108.27) UC1.AM13 ; UC1.AE14 v1(84.97,109.19) ; UC1.AD14 v1(85.88,109.19) ; UC1.AJ14 v1(82.22,108.27) UC1.AH14 ; v1(78.56,108.27) UC1.AP13 ; UC1.AC14 v1(86.79,109.19) ; UC1.K14 UC1.L14 96.35,108.79 v1(95.78,109.11) ; UC1.AH13 v1(83.14,108.27) ; UC1.V13 v1(90.45,108.27) ; UC1.AD13 v1(85.88,108.27) ; UC1.AM14 v1(80.36,109.14) ; v1(79.48,108.27) UC1.AN13 ; UC1.AG14 v1(83.14,109.19) ; UC1.AE13 v1(84.97,108.27) ; UC1.K13 96.46,108.01 UC1.L13 v1(95.94,108.27) ; UC1.W14 v1(90.45,109.19) ; UC1.AL13 v1(81.31,108.27)
  vias: v1(67.97,138.25) v1(67.97,137.62) v1(67.97,136.98) v1(67.97,136.35) v1(67.97,135.71) v1(67.97,135.08) v1(68.61,138.25) v1(68.61,137.62) v1(68.61,136.98) v1(68.61,136.35) v1(68.61,135.71) v1(68.61,135.08) v1(69.24,138.25) v1(69.24,137.62) v1(69.24,136.98) v1(69.24,136.35) v1(69.24,135.71) v1(69.24,135.08) v1(69.88,138.25) v1(69.88,137.62) v1(69.88,136.98) v1(69.88,136.35) v1(69.88,135.71) v1(69.88,135.08) v1(70.51,138.25) v1(70.51,137.62) v1(70.51,136.98) v1(70.51,136.35) v1(70.51,135.71) v1(70.51,135.08) v1(70.89,134.44) v1(70.89,133.81) v1(70.89,133.17) v1(70.89,132.54) v1(71.15,138.25) v1(71.15,137.62) v1(71.15,136.98) v1(71.15,136.35) v1(71.15,135.71) v1(71.15,135.08) v1(71.53,134.44) v1(71.53,133.81) v1(71.53,133.17) v1(71.53,132.54) v1(71.53,131.9) v1(71.78,135.71) v1(71.78,135.08) v1(72.19,134.44) v1(72.19,133.81) v1(72.19,133.17) v1(72.19,132.54) v1(72.19,131.9) v1(72.42,135.71) v1(72.42,135.08) v1(73.05,135.71) v1(73.05,135.08) v1(73.69,135.71) v1(73.69,135.08) v1(74.32,135.71) v1(74.32,135.08) v1(74.83,134.44) v1(74.83,133.81) v1(74.83,133.17) v1(74.83,132.54) v1(74.83,131.9) v1(74.96,135.71) v1(74.96,135.08) v1(75.49,134.44) v1(75.49,133.81) v1(75.49,133.17) v1(75.49,132.54) v1(75.49,131.9) v1(75.62,138.25) v1(75.62,137.62) v1(75.62,136.98) v1(75.62,136.35) v1(75.62,135.71) v1(75.62,135.08) v1(76.25,138.25) v1(76.25,137.62) v1(76.25,136.98) v1(76.25,136.35) v1(76.25,135.71) v1(76.25,135.08) v1(76.89,138.25) v1(76.89,137.62) v1(76.89,136.98) v1(76.89,136.35) v1(76.89,135.71) v1(76.89,135.08) v1(77.52,138.25) v1(77.52,137.62) v1(77.52,136.98) v1(77.52,136.35) v1(77.52,135.71) v1(77.52,135.08) v1(77.8,112.36) v1(78,115.72) v1(78.13,134.44) v1(78.13,133.81) v1(78.13,133.17) v1(78.13,132.54) v1(78.06,117.64) v1(78.05,113.97) v1(78.16,138.25) v1(78.16,137.62) v1(78.16,136.98) v1(78.16,136.35) v1(78.16,135.71) v1(78.16,135.08) v1(78.44,125.8) v1(78.46,126.43) v1(78.46,125.13) v1(78.46,124.48) v1(78.46,123.19) v1(78.46,122.53) v1(78.62,119.32) v1(78.7,120.26) v1(78.79,138.25) v1(78.79,137.62) v1(78.79,136.98) v1(78.79,136.35) v1(78.79,135.71) v1(78.79,135.08) v1(78.79,134.44) v1(78.79,133.81) v1(78.79,133.17) v1(78.79,132.54) v1(79.01,111.31) v1(78.99,110.69) v1(79.24,127.08) v1(79.2,126.44) v1(79.24,125.78) v1(79.22,125.14) v1(79.24,124.48) v1(79.24,123.18) v1(79.23,122.55) v1(79.43,135.71) v1(79.43,135.08) v1(79.43,134.44) v1(79.43,133.81) v1(79.43,133.17) v1(79.79,116.39) v1(79.91,114.04) v1(80.03,127.09) v1(80.04,125.8) v1(80.03,125.13) v1(80.01,124.51) v1(80.01,123.19) v1(80.03,122.53) v1(80.03,121.89) v1(80.03,121.19) v1(80.06,135.71) v1(80.06,135.08) v1(80.06,134.44) v1(80.06,133.81) v1(80.7,135.71) v1(80.7,135.08) v1(80.7,134.44) v1(80.7,133.81) v1(80.82,126.43) v1(80.82,125.78) v1(80.82,125.12) v1(80.82,124.48) v1(80.8,123.85) v1(80.82,123.18) v1(80.83,122.55) v1(80.77,112.49) v1(81.03,117.92) v1(81.33,135.71) v1(81.33,135.08) v1(81.61,125.13) v1(81.61,124.51) v1(81.61,123.83) v1(81.58,123.19) v1(81.61,122.53) v1(81.97,135.71) v1(81.97,135.08) v1(82.4,123.85) v1(82.4,123.21) v1(82.37,122.53) v1(82.39,121.89) v1(82.39,121.19) v1(82.47,111.33) v1(82.48,110.74) v1(82.6,135.71) v1(82.6,135.08) v1(83.24,138.25) v1(83.24,137.62) v1(83.24,136.98) v1(83.24,136.35) v1(83.24,135.71) v1(83.24,135.08) v1(83.18,125.79) v1(83.18,125.14) v1(83.2,124.49) v1(83.19,123.19) v1(83.16,122.55) v1(83.18,112.45) v1(83.5,120.3) v1(83.5,119.35) v1(83.48,117.85) v1(83.87,138.25) v1(83.87,137.62) v1(83.87,136.98) v1(83.87,136.35) v1(83.87,135.71) v1(83.87,135.08) v1(83.96,125.79) v1(83.97,125.13) v1(83.97,124.48) v1(83.97,123.19) v1(83.97,122.53) v1(83.97,116.28) v1(83.97,115.64) v1(83.97,115.01) v1(83.97,114.37) v1(84.51,138.25) v1(84.51,137.62) v1(84.51,136.98) v1(84.51,136.35) v1(84.51,135.71) v1(84.51,135.08) v1(84.77,127.15) v1(84.79,126.46) v1(84.79,125.77) v1(84.76,125.13) v1(84.75,124.51) v1(84.76,123.19) v1(84.76,122.53) v1(84.76,121.94) v1(84.93,127.74) v1(85.14,138.25) v1(85.14,137.62) v1(85.14,136.98) v1(85.14,136.35) v1(85.14,135.71) v1(85.14,135.08) v1(85.54,127.08) v1(85.54,126.44) v1(85.54,125.78) v1(85.54,125.17) v1(85.54,124.48) v1(85.54,122.53) v1(85.55,121.92) v1(85.56,127.69) v1(85.57,123.85) v1(85.64,112.42) v1(85.94,118.5) v1(85.88,111.24) v1(85.91,110.65) v1(86.2,127.74) v1(86.27,127.15) v1(86.33,126.43) v1(86.33,125.78) v1(86.33,125.13) v1(86.32,124.51) v1(86.31,123.85) v1(86.32,123.22) v1(86.33,122.53) v1(87.14,125.15) v1(87.12,124.48) v1(87.1,123.85) v1(87.12,123.18) v1(87.11,122.55) v1(87.12,121.89) v1(87.12,121.19) v1(87.85,127.74) v1(87.9,127.13) v1(87.91,126.43) v1(87.9,125.78) v1(87.91,125.13) v1(87.93,124.48) v1(87.99,120.32) v1(88.02,119.31) v1(88.04,112.47) v1(88.32,118.52) v1(88.69,127.69) v1(88.69,127.08) v1(88.69,126.47) v1(88.69,125.78) v1(88.69,125.15) v1(88.69,124.48) v1(88.69,123.85) v1(88.69,123.18) v1(88.71,122.55) v1(89.18,111.26) v1(89.17,110.65) v1(89.51,127.15) v1(89.47,125.78) v1(89.5,125.15) v1(89.48,124.51) v1(89.49,123.82) v1(89.47,123.19) v1(89.48,122.53) v1(89.46,121.89) v1(89.48,121.19) v1(89.54,109.19) v1(90.27,127.08) v1(90.26,126.44) v1(90.27,125.78) v1(90.26,125.15) v1(90.27,124.48) v1(90.66,112.76) v1(90.85,117.96) v1(91.05,125.78) v1(91.05,124.51) v1(91.05,127.08) v1(91.05,126.43) v1(91.05,125.13) v1(91.05,123.83) v1(91.08,123.19) v1(91.05,122.55) v1(91.23,116.27) v1(91.27,114.56) v1(91.84,125.78) v1(91.84,125.12) v1(91.84,124.48) v1(91.84,123.82) v1(91.84,123.18) v1(91.84,122.53) v1(91.84,121.89) v1(91.84,121.19) v1(91.9,127.18) v1(92.03,112.79) v1(92.38,120.28) v1(92.38,119.33) v1(92.51,111.8) v1(92.63,127.08) v1(92.63,126.43) v1(92.62,125.78) v1(92.63,125.13) v1(92.63,124.48) v1(92.64,113.63) v1(92.61,112.99) v1(92.64,112.38) v1(92.59,111.2) v1(92.61,110.61) v1(93.22,118.62) v1(93.2,109.19) v1(93.39,126.44) v1(93.42,125.78) v1(93.39,125.15) v1(93.42,124.48) v1(93.39,123.83) v1(93.42,123.18) v1(93.41,122.55) v1(94.15,127.11) v1(94.19,125.77) v1(94.17,125.14) v1(94.2,124.53) v1(94.21,123.18) v1(94.21,122.53) v1(94.18,121.89) v3(80.24,137.36)
+VCCGT: length 29.4
  BOTTOM w0.127: 73.05,121.23 UC1.AY30 73.01,121.51 ; 70.69,121.23 UC1.BC30 70.65,121.51 ; 70.65,120.86 UC1.BC29 ; UC1.BC29 70.98,120.53 ; UC1.BC29 71.31,120.86 ; 69.9,121.23 UC1.BD30 70.52,121.51 ; 72.22,120.86 UC1.BA29 ; UC1.BA29 72.88,120.86 ; UC1.BA29 72.55,120.53 ; 73.01,120.86 UC1.AY29 ; UC1.AY29 73.67,120.86 ; UC1.AY29 73.34,120.53 ; 74.91,121.84 UC1.AV30 75.24,121.51 ; 72.88,121.51 UC1.BA30 72.55,121.84 ; 67.5,121.51 UC1.BG30 ; UC1.BG30 67.83,121.84 ; UC1.BG30 68.16,121.51 ; UC1.BD29 70.52,120.86 ; UC1.BD29 69.86,120.86 ; UC1.BD29 70.19,120.53 ; UC1.AV29 74.91,120.53 ; UC1.AV29 74.58,120.86 ; UC1.AV29 75.24,120.86 ; UC1.BF29 68.61,120.53 ; UC1.BF29 68.94,120.86 ; UC1.BF29 68.28,120.86 ; 75.37,120.86 UC1.AU29 ; UC1.AU29 75.7,120.53 ; UC1.AU29 76.03,120.86 ; 67.83,120.53 UC1.BG29 68.16,120.86 ; 68.28,121.51 UC1.BF30 68.33,121.23 ; 75.7,121.84 UC1.AU30 75.37,121.51
  BOTTOM w0.254: UC1.BJ23 v1(66.31,115.64) ; UC1.BJ27 v1(66.31,118.79) ; UC1.BJ20 v1(66.31,113.28) UC1.BJ19 ; UC1.BL24 v1(65.01,116.43) ; UC1.BK27 v1(65.66,118.79) ; UC1.BK19 v1(65.66,113.28) UC1.BK20 ; UC1.BT15 v1(61.76,109.34) ; UC1.BJ24 v1(66.31,116.43) ; UC1.BL25 v1(65.01,117.22) ; UC1.BJ21 v1(66.31,114.07) ; UC1.BN15 v1(63.71,109.34) ; UC1.BK21 v1(65.66,114.07) ; UC1.BJ26 v1(66.31,118) ; UC1.BP15 v1(63.06,109.34) 62.74,109.67 UC1.BR15 ; UC1.BK26 v1(65.66,118) ; UC1.BL23 v1(65.01,115.64) ; v1(65.01,118.79) UC1.BL27 65.11,119.41 65.11,119.75 UC1.BL28 ; UC1.BM15 v1(64.36,109.34) ; UC1.BL15 v1(65.01,109.34) ; UC1.BK24 v1(65.66,116.43) ; UC1.BL26 v1(65.01,118) ; UC1.BK23 v1(65.66,115.64)
  BOTTOM w0.508: RC12.2 81.72,130.29 v1(80.4,128.97)
  vias: v1(59.21,138.12) v1(59.21,137.49) v1(59.21,136.85) v1(59.21,132.41) v1(59.84,138.12) v1(59.84,137.49) v1(59.84,136.85) v1(59.84,132.41) v1(60.48,138.12) v1(60.48,137.49) v1(60.48,136.85) v1(60.48,132.41) v1(61.11,138.12) v1(61.11,137.49) v1(61.11,136.85) v1(61.11,132.41) v1(61.75,138.12) v1(61.75,137.49) v1(61.75,136.85) v1(61.75,136.22) v1(61.75,135.58) v1(61.75,134.95) v1(61.75,134.31) v1(61.75,133.68) v1(61.75,133.04) v1(61.75,132.41) v1(61.76,110.92) v1(61.76,110.13) v1(61.87,139.39) v1(61.87,138.76) v1(62.38,138.12) v1(62.38,137.49) v1(62.38,136.85) v1(62.38,136.22) v1(62.38,135.58) v1(62.38,134.95) v1(62.38,134.31) v1(62.38,133.68) v1(62.38,133.04) v1(62.38,132.41) v1(62.41,110.92) v1(62.41,110.13) v1(62.64,139.39) v1(62.64,138.76) v1(63.02,138.12) v1(63.02,137.49) v1(63.02,136.85) v1(63.02,136.22) v1(63.02,135.58) v1(63.02,134.95) v1(63.02,134.31) v1(63.02,133.68) v1(63.02,133.04) v1(63.02,132.41) v1(63.06,110.92) v1(63.06,110.13) v1(63.55,125.29) v1(63.73,127.27) v1(63.71,110.92) v1(63.71,110.13) v1(64.4,127.25) v1(64.36,110.92) v1(64.36,110.13) v1(65.01,110.92) v1(65.01,110.13) v1(65.66,110.92) v1(65.66,110.13) v1(65.86,125.81) v1(66.31,110.92) v1(66.31,110.13) v1(66.65,127.11) v1(67.43,126.43) v1(67.43,125.79) v1(67.43,125.13) v1(67.43,124.48) v1(68.22,125.14) v1(68.22,124.48) v1(68.22,123.18) v1(68.22,122.53) v1(68.22,121.88) v1(68.22,121.19) v1(68.79,111.48) v1(68.79,110.89) v1(69.01,127.08) v1(69.01,126.43) v1(69.01,125.79) v1(69.01,125.13) v1(69.01,124.49) v1(69.03,123.19) v1(69.01,122.54) v1(69.24,115.44) v1(69.24,114.17) v1(69.24,112.9) v1(69.32,119.12) v1(69.32,118.21) v1(69.27,116.66) v1(69.38,108.25) v1(69.79,127.08) v1(69.79,126.43) v1(69.79,125.78) v1(69.79,125.13) v1(69.79,124.48) v1(69.79,123.84) v1(69.79,123.18) v1(69.79,122.54) v1(70.32,108.24) v1(70.58,125.78) v1(70.58,125.13) v1(70.58,124.48) v1(70.58,123.83) v1(70.58,123.19) v1(70.58,122.53) v1(70.58,121.89) v1(70.58,121.19) v1(70.58,120.54) v1(71.26,108.27) v1(71.37,127.08) v1(71.37,126.43) v1(71.37,125.78) v1(71.37,125.13) v1(72.07,127.15) v1(72.13,116.51) v1(72.08,114.78) v1(72.09,112.99) v1(72.13,108.27) v1(72.16,126.43) v1(72.16,125.78) v1(72.16,125.13) v1(72.16,124.49) v1(72.16,123.83) v1(72.16,123.19) v1(72.16,122.53) v1(72.19,111.53) v1(72.19,110.9) v1(72.94,125.78) v1(72.94,125.14) v1(72.94,124.48) v1(72.94,123.84) v1(72.94,123.18) v1(72.94,122.54) v1(72.94,121.89) v1(72.94,121.19) v1(72.94,120.54) v1(73.7,127.18) v1(73.73,126.43) v1(73.73,125.79) v1(73.73,125.13) v1(73.73,124.49) v1(74.04,119.15) v1(74.07,118.29) v1(74.19,113.36) v1(74.19,112.47) v1(74.52,127.08) v1(74.52,126.44) v1(74.52,125.78) v1(74.52,125.14) v1(74.52,124.48) v1(74.52,123.84) v1(74.52,123.18) v1(74.52,122.54) v1(75.07,117.41) v1(75.06,116.18) v1(75.07,114.91) v1(75.08,110.31) v1(75.31,125.79) v1(75.31,125.13) v1(75.31,124.49) v1(75.31,123.83) v1(75.31,123.19) v1(75.31,122.53) v1(75.32,121.9) v1(75.31,121.19) v1(75.31,120.54) v1(75.84,110.31) v1(76.09,127.08) v1(76.09,126.44) v1(76.09,125.78) v1(76.09,125.14) v1(76.09,123.84) v1(76.09,122.54) v1(76.88,126.43) v1(76.88,125.79) v1(76.88,125.13) v1(76.88,123.83) v1(76.88,122.53) v3(57.26,136.55)
+VCCIO: length 11.7
  TOP w0.127: v3(101.09,113.1) 100.73,112.74 RC9.1
  TOP w0.381: v1(49.95,107.54) 52.48,110.07 v1(52.48,110.44) ; v1(101.08,117.43) 101.54,117.88 RC1.2
  TOP w0.508: v1(97.79,111.14) 97.79,111.17 97.83,111.21 CC33.1 ; RC9.1 98.48,112.74 v1(98.48,112.74) 98.3,112.92 CC34.1 ; CC35.1 97.83,114.96 v1(98.52,114.27)
  BOTTOM w0.254: RC271.2 49.81,107.68 v1(49.95,107.54) ; UC1.AG12 83.76,107.3 84.03,107.03 v1(84.03,107)
  vias: v1(52.48,111.02) v1(53.06,111.02) v1(53.06,110.44) v1(53.65,111.02) v1(53.65,110.44) v1(54.23,111.02) v1(54.23,110.44) v1(54.81,111.02) v1(98.5,113.52) v1(98.47,111.15) v1(99.15,114.27)
+VCCIO_PG: length 124.1
  TOP w0.254: v1(126.53,37.29) 126.25,37.01 126.25,35.89 RH103.1
  BOTTOM w0.254: v1(42.49,118.82) PR901.2 43.54,118.49 44.2,118.49 45.11,117.58 45.51,117.58 45.59,117.49 PU901.9 ; v1(51.77,98.45) 52.27,97.94 52.27,97.6 52.99,96.88 52.99,90.57 61.39,82.18 102.96,82.18 114.55,70.58 114.55,61.9 116.66,59.79 116.66,58.77 115.61,57.72 115.61,55.06 117.42,53.25 117.42,46.29 125.11,38.6 126.07,38.6 126.53,38.14 v1(126.53,37.29)
+VCCIOP: length 3
  TOP w0.127: v1(55.25,114.12) v3(55.25,115.31)
  BOTTOM w0.381: v1(49.89,122.01) 49.44,122.01 49.19,121.75 PR908.1 49.07,121.68 49,121.6 PC912.1
+VCCRTCEXT: length 1.8
  TOP w0.508: v1(187.07,32.99) 186.64,33.43 CH25.1
  BOTTOM w0.254: v1(187.07,32.99) 187.02,33.04 UH1.BG47 UH1.BF47
+VCCSA: length 5.3
  TOP w0.127: v1(96.04,135.58) 96.04,136.12 v3(96.34,136.42)
  BOTTOM w0.127: 97.55,121.53 UC1.J30 ; UC1.J30 97.22,121.2 ; UC1.J30 97.55,120.87 ; UC1.K30 97.29,121.51 ; UC1.K30 96.63,121.51 ; UC1.K30 96.96,121.84 ; 95.72,120.86 UC1.M29 95.39,120.53 ; 96.63,120.86 UC1.K29 ; UC1.K29 96.96,120.53 ; UC1.K29 97.29,120.86 ; 95.72,121.51 UC1.M30 95.39,121.84
  vias: v1(95.02,111.31) v1(95.1,112.62) v1(95.8,127.08) v1(95.8,126.44) v1(95.8,125.81) v1(95.8,125.15) v1(95.8,124.48) v1(95.8,123.82) v1(95.8,123.19) v1(95.8,122.53) v1(95.91,120.34) v1(95.91,118.57) v1(95.91,116.79) v1(95.91,115.14) v1(96.04,134.95) v1(96.53,127.15) v1(96.53,126.44) v1(96.57,125.78) v1(96.59,125.15) v1(96.6,124.49) v1(96.57,123.18) v1(96.59,122.53) v1(96.67,135.58) v1(96.67,134.95) v1(97.03,132.03) v1(97.31,135.58) v1(97.31,134.95) v1(97.61,132.03) v1(97.61,131.39) v1(97.94,135.58) v1(98.2,132.03) v1(98.2,131.39)
+VCCST: length 41.1
  TOP w0.508: v1(112.07,142.95) PCZ12.2 PRZ21.2 110.43,142.29 PRZ22.1 PRZ23.1 ; v1(57.23,110.13) 57.72,110.13 58.19,110.6 58.19,112.15 58.57,112.53 v3(58.57,113.46) 58.57,114.93 57.8,115.7 57.8,118.17 58.6,118.97 58.6,119.68 57.94,120.34 57.14,120.34 56.18,121.3 56.18,122.45 57.19,123.46 57.19,123.7 58.18,124.69 v1(58.18,125.72) ; v1(107.13,117.55) 106.79,117.88 RC20.2
  BOTTOM w0.254: v1(98.49,122.17) 98.16,121.85 UC1.H30 ; UC1.J28 97.46,120.13 v1(97.79,119.81) 98.11,120.13 UC1.H28
  BOTTOM w0.508: v1(63.87,132.31) 63.87,130.94 64.46,130.34 v1(67.31,130.34) 68.36,130.34 RC261.1 RC260.1 ; v1(58.18,125.72) 57.86,125.4 RC263.1 ; RC259.1 v1(57.23,110.13) ; PRZ20.1 112.15,142.86 v1(112.07,142.95)
  BOTTOM w1.016: 116.09,129.12 116.98,128.23 116.98,124.55 116.29,123.86
  vias: v1(106.39,122.59) v1(106.39,122.01) v1(114.54,122.36) v1(115,122.73) v1(115.42,129.67)
+VCCSTG: length 22
  TOP w0.356: CC40.1 99.07,120.71 98.52,121.27 v1(98.52,121.38)
  TOP w0.508: v1(57.22,110.92) v3(57.22,111.84) 57.22,112.59 57.89,113.26 57.89,114.62 57.16,115.34 57.16,118.65 v1(57.88,119.36) 57.53,119.71 56.63,119.71 55.47,120.87 v1(55.47,121.87)
  BOTTOM w0.254: UC1.H29 98.52,121.34 v1(98.52,121.38) UC1.G30
  BOTTOM w0.381: v1(55.47,121.87) 55.57,121.76 RC262.1
  BOTTOM w0.508: v1(103.94,117.59) 104.95,117.59 CZ47.1 RZ48.1 ; v1(57.88,119.36) 57.86,119.35 RC76.2 RC78.2 ; RC77.2 v1(57.22,110.92)
+VCCSTG_OUT: length 0.7
  BOTTOM w0.127: 107.2,120.74 107.2,121.13 v2(106.97,121.36)
GND: length 4265.9
  TOP w0.127: 200.94,113.1 v3(200.94,112.18) ; v3(68.97,40) 69.15,40 v1(69.6,40.45) ; v1(95.28,41.64) 94.75,41.64 94.55,41.85 93.85,41.85 93.59,41.58 93.59,41.28 CE14.2 ; v3(114.44,51.21) 115.14,51.21 115.15,51.19 ; v1(254.28,55.75) v3(254.28,56.59) ; 50.44,99.05 50.44,95.36 51.03,94.77 51.03,90.61 49.68,89.25 49.68,88.94 49.99,88.63 50.39,88.63 51.77,90.01 51.77,94.99 51.02,95.74 51.02,97.19 v1(51.12,97.3) 51.12,99.06 46.58,103.6 46.58,105.03 46.3,105.31 v1(46.03,105.31) 45.75,105.6 45.12,105.6 44.98,105.45 44.98,104.99 45.91,104.07 45.91,103.59 50.44,99.05
  TOP w0.152: 97.76,41.91 97.76,41.67 97.64,41.54 95.37,41.54 v1(95.28,41.64)
  TOP w0.203: DT5.2 12.94,119.71 v1(12.94,119.81) ; DT5.2 13.63,119.21 14.14,119.72 v1(14.14,119.81) ; DT5.2 13.53,119.31 v1(13.53,119.81) ; UE1.84 84.29,30.59 v1(83.91,30.97) ; DT4.2 13.07,117.74 12.85,117.52 v1(12.85,117.03) ; DT4.2 13.81,117.74 14.02,117.52 v1(14.02,117.03) ; DT4.2 v1(13.44,117.03) ; DT7.2 12.08,123.91 v1(12.34,123.65) ; DT7.2 11.3,123.91 v1(11.14,123.75) ; DT7.2 v1(11.84,123.32) ; UE1.64 74.02,31.21 v1(73.81,31.42) ; v1(177.47,29.5) 177.53,29.43 177.53,27.66 177.62,27.58 181.7,27.58 181.98,27.86 v1(181.98,28.84) ; UE1.17 82.69,44.3 82.97,44.02 82.97,43.38 v1(82.94,43.35) ; v1(88.7,33.13) 88.7,32.7 88.99,32.41 UE1.100 ; v1(88.88,40.81) 88.88,41.42 89.18,41.72 89.61,41.72 89.91,42.01 UE1.124 ; v1(171.46,53.4) 171.48,53.38 RH716.2 ; DT6.2 11.3,125.39 v1(11.14,125.55) ; DT6.2 12.33,125.39 v1(12.5,125.55) ; DT6.2 v1(11.84,126.02) ; UZ1.11 v1(57.02,28.29) ; UTPM1.9 203.27,34.57 v1(203.05,34.34) ; UE1.51 76.64,36.41 76.89,36.67 v1(76.89,36.73) ; 97.76,41.91 97.76,45.37 97.62,45.51 95.43,45.51 CE4.2
  TOP w0.254: UTPM1.23 199.73,31.57 v1(200,31.29) ; CT81.2 19.53,123.25 v1(18.98,123.8) ; C48.2 255.51,33.95 v1(255.51,34.45) ; v1(174.9,37.29) 175.54,36.65 UZ7.5 ; UZ16.5 100.47,90.74 v1(99.72,89.99) ; v1(200,34.34) 199.77,34.57 UTPM1.16 ; CP27.2 26.16,85.99 26.16,85.2 26.61,84.76 v1(26.7,84.76) ; v1(70.84,29.6) 70.84,29.3 70.63,29.09 JDEG1.10 ; v1(24.03,21.79) CA45.2 CA49.2 ; 229.44,94.11 229.04,94.5 RV152.1 ; CU21.2 v1(265.91,34.19) ; v1(203.05,31.29) 203.27,31.07 UTPM1.32 ; PR45.2 53.96,141.63 PQ13.1 ; CD43.2 82.54,54.65 v1(82.24,54.65) ; v1(52.82,42.75) 53.46,42.75 CL20.2 ; v1(79.13,64.84) 79.79,64.84 80.4,65.45 RD11.2 ; v1(184.34,47.18) 184.34,47.38 184.65,47.69 RH554.2 ; RT108.2 31.18,87.69 30.54,88.33 v1(30.32,88.33) ; CU22.2 v1(265.94,34.83)
  TOP w0.305: CD18.2 87.2,71.01 86.41,70.22 CD24.2 ; v1(94.54,68.6) 94.89,68.6 95.78,69.49 CD25.2 ; v1(37.76,91.43) 37.76,91.07 37.34,90.66 RT113.2 ; PQS22.4 66.26,41.66 v1(65.99,41.93) ; v1(23.66,131.06) 23.66,130.97 23.93,130.7 CT59.2 ; RT78.2 28.43,128.02 v1(27.56,127.15) ; v1(67.63,43.47) 67.56,43.41 PQS22.1 ; CV841.1 212.48,124.19 212.66,124.37 ; PQ13.4 52.66,138.65 53.01,138.3 PR38.2 ; RD12.2 84.92,65.45 v1(84.51,65.45) ; v1(184.75,36.37) 184.75,36.59 RH743.2 ; CT78.2 27.43,129.05 26.93,128.54 CT80.2 ; v1(16.95,129.95) 16.64,130.26 RT129.2 16.64,130.52 RT80.2
  TOP w0.33: v1(36.09,35.7) 35.81,35.42 PUB02.3
  TOP w0.356: v1(21.71,128.45) 21.71,128.61 22.14,129.03 22.87,129.03 CT48.2 23.04,129.05 CT58.2 ; v1(206.71,40.22) 206.77,40.16 RH455.1 ; v1(192.43,52.65) 191.9,52.65 191.43,52.18 191.43,52.16 ; CC148.2 147.84,35.69 148.6,36.45 v1(150.19,36.45) ; CC40.2 99.66,120.79 99.19,121.26 v1(99.19,121.39) ; 133.78,32.85 133.66,32.85 133.29,32.49 RH94.2 ; v1(133.59,33.47) CC301.2 ; v1(179.5,32.18) 179.5,32.82 RH738.2 ; RZ71.2 138.38,33.11 v1(138.16,32.89) 138.16,32.55 CC302.2 ; CU19.2 v1(23.74,33.65) ; RE62.2 70.26,30.77 ; CT47.2 21.06,129.76 v1(21.06,129.75) ; v1(144.9,32.83) 144.9,32.4 RH740.2 ; v1(180.44,46.76) 180.44,46.59 180.99,46.05 RH24.2
  TOP w0.381: v1(73.74,48.91) 73.74,48.55 74.08,48.21 RE68.2 ; CD42.2 73.3,59.43 CD46.2 ; 211.54,102.72 211.33,102.52 CG47.2 ; CV856.2 CV852.2 216.14,147.21 v1(216.1,147.25) ; v1(95.28,41.64) 95.08,41.84 CE3.2 ; v1(99.09,98.23) 99,98.14 99,97.23 CC37.2 CC36.2 ; CH45.2 181.24,30.43 181.58,30.76 CH212.2 181.58,30.41 181.97,30.02 RH700.1 181.97,29.42 181.98,29.41 RH90.1 v1(181.98,28.84) ; v1(24.79,3.99) 24.15,3.99 CA27.2 ; CV879.2 259.94,128.83 260.69,129.59 v1(261.24,129.59) ; CV52.2 209.39,100.82 209.99,100.22 ; 70.26,30.77 v1(70.26,30.71) ; RT43.2 23.01,122.01 v1(23.2,121.82) ; CT82.2 18.74,125.94 v1(18.62,125.83) ; v1(21.84,27.65) 22.28,27.21 DU3.3 24.48,27.21 v1(24.71,27.44) ; PD6.1 213.22,37.46 213.23,37.45 v1(213.86,37.45) ; CV398.2 262.05,121.86 v1(262,121.9) ; UC16.3 137.68,33.87 138.06,33.49 RZ71.2 ; CT85.2 21.59,125.85 v1(21.06,125.85) ; CT62.2 CT61.2 CT60.2 15.12,128.71 14.56,128.14 v1(14.22,128.14) ; v1(259.2,113.9) 258.92,113.62 CV190.2 ; CV382.2 204.87,142.88 204.9,142.85 ; CT54.2 27.56,126.72 v1(27.56,127.15) ; CD17.2 81.99,67.59 v1(81.98,67.59) ; v1(19.88,98.63) 19.94,98.69 CP6.2 ; CV875.2 231.85,150.1 v1(231.9,150.05) ; v1(260.8,106.2) 260.97,106.37 CV184.2 ; v1(71.37,72.33) 71.4,72.31 CD13.2 ; 235.1,142.85 235.13,142.88 CV374.2 ; v1(23.17,40.87) 23.19,40.89 PQS05.4 ; v1(263.2,113.9) 263.11,113.81 CV188.2 ; v1(224.5,144.95) 224.92,144.95 225.32,144.55 CV166.2 ; v1(12.57,121.49) DT10.3 v1(10.35,121.49) ; 223.9,140.85 223.86,140.81 CV860.2 ; RV110.2 256.34,113.54 v1(256.7,113.9) ; CT102.2 36.38,91.72 v1(36.38,91.34) 35.83,91.34 35.75,91.26 CT137.2 35.28,92.18 CT103.2 ; PQS10.4 20.89,113.63 20.21,113.63 20.1,113.73 PRS27.1 ; v1(256,106.2) 256.44,106.65 RV111.2 ; PUS02.3 21.87,40.52 v1(22.16,40.82) ; CA48.2 35.37,11.51 34.92,11.51 v1(34.85,11.43) ; CV388.2 211.28,150.03 v1(211.3,150.05) ; v1(84.45,68.86) 84.8,68.86 85.69,69.74 CD24.2 ; CV186.2 257.96,101.36 v1(258,101.4) ; CT79.2 25.4,126.5 v1(24.96,126.5) 24.96,126.44 25.07,126.33 RT3.2 ; UZ21.3 141.11,33.87 140.74,33.5 v1(140.74,32.88) ; v1(223.9,147.25) 223.87,147.28 CV869.2 ; RT44.2 20.47,122.3 v1(20.05,121.88) ; v1(19.29,51.6) 19.13,51.44 DU1.3 19.13,46.7 v1(18.76,46.33) ; CT72.2 CT55.2 23.8,122.28 24.18,121.9 v1(24.18,121.82) ; v1(231.9,147.65) 231.68,147.87 CV380.2 ; v1(257.69,126.76) 257.33,127.11 CV191.2 257.33,127.77 256.85,128.25 RV135.2 ; v1(30.29,87.74) 31.04,87 RT111.2 ; CH33.2 178.45,42.5 v1(177.93,41.98) ; v1(203.28,144.85) 203.03,144.85 202.87,144.69 CV865.2 ; v1(258.09,121.85) 258.03,121.8 CV193.2 ; CA28.2 23.47,6.55 23.07,6.95 v1(21.73,6.95) ; v1(23.66,124.55) 23.64,124.53 CT83.2 ; UH14.3 129.52,32.81 129.1,33.23 v1(129.1,33.72) ; v1(36.04,127.36) 35.44,127.36 PCS04.2 ; CV375.2 236.74,147.21 v1(236.7,147.25) ; CV867.2 203.2,140.75 203.3,140.85 ; v1(87.75,55.8) 88.66,55.8 RD18.2 ; v1(263.2,106.2) 263.37,106.37 CV183.2 ; 223.3,99.33 223.39,99.24 CV119.2 ; CT68.2 CT69.2 19.18,126.65 v1(19.07,126.76) ; v1(262,101.4) 262.05,101.36 CV391.2 ; CV861.2 237.16,150.91 v1(236.7,150.45) ; JDEG1.11 64.46,26.06 v1(65.19,25.34) ; CTPM1.2 206.3,33.28 v1(206.03,33.55) ; v1(211.3,146.05) 211.25,146.01 CV174.2 ; QH9.1 24.55,103.65 23.25,104.95 QH9.4 22.96,105.35 23.33,105.71 RW29.2 ; v1(52.53,72.64) 52.8,72.37 CD12.2 ; CE32.1 93.32,43.99 v1(93.01,44.3) 93.01,44.63 CE33.2 ; v1(33.58,50.67) 33.58,50.8 34.92,52.14 PCM11.2 ; v1(259.2,106.2) 259.11,106.29 CV182.2 ; 228.16,94.25 228.16,93.55 RV156.1 ; CV864.2 216.12,140.88 216.1,140.85 ; CV192.2 257.96,118.75 v1(258,118.7) ; CH46.2 177.96,30.43 177.47,29.94 v1(177.47,29.5) ; v1(203.92,144.85) 203.92,144.56 CV173.2 ; CA29.2 v1(19.58,7.12) ; JDEG1.12 70.96,27.19 v1(70.79,27.36) ; CD28.2 84.45,64.06 v1(84.52,64.13) ; v1(187.02,38.17) 186.92,38.28 CC57.1 ; CU5.2 27.33,33.78 26.32,32.77 v1(26.32,32.13) ; v1(144.9,32.83) 144.9,33.72 UC12.3 ; v1(262.4,126.7) 262.54,126.84 CV397.2 ; v1(104.8,48.5) 104.8,47.68 104.09,46.97 R45.2 ; PRV38.1 248.58,64.04 v1(248.85,64.31) ; v1(38.32,66.85) 38.32,68.25 PCS16.2 ; RT64.2 33.9,87.63 v1(33.9,87.01) ; CL15.2 63.36,42.82 63.71,43.17 v1(63.71,43.52) ; v1(182.58,52.57) 182.04,52.57 181.69,52.22 CH30.2 ; CT88.2 30.44,91.72 v1(30.55,91.83) ; CV400.2 262.11,118.81 v1(262,118.7) ; CE22.2 CE26.2 67.77,34.26 67.34,34.7 v1(67.34,35.11) ; CV940.2 209.2,102.79 209.1,102.68 ; v1(64.03,72.29) 64.32,72 CD21.2 ; v1(35.04,87.32) 35.34,87.01 CT104.2 ; CTPM2.2 v1(205.38,33.53) ; v1(24.96,127.8) 24.96,127.27 CT57.2 ; PQS10.1 22.65,115.17 22.35,114.86 v1(22.17,114.86) ; PCA108.2 94.99,132.95 v1(94.53,133.41) ; PCS12.2 21.07,42.85 PQS05.1 ; 211.57,105.18 211.63,105.12 CV114.2 ; CV393.2 262.05,98.24 v1(262,98.2) ; v1(216.1,150.45) 216.43,150.78 CV868.2 ; CL19.2 CL18.2 52.95,37.84 v1(52.92,37.81) ; CD22.2 72.06,68.3 v1(70.81,68.3) ; v1(19.12,128.66) 19.1,128.68 RT37.2 ; v1(104.13,68.79) 103.91,68.79 103.53,69.17 CD26.2 ; PCA110.2 99.98,132.96 v1(100.18,132.76) ; C27.2 235.1,35.33 v1(235.48,34.95) ; 236.7,140.85 236.8,140.75 CV164.2 ; v1(203.3,151.25) 202.74,151.25 CV381.2 ; v1(99.62,132.1) 100.09,132.1 PCA105.2 99.89,131.49 v1(99.62,131.49) ; CV870.2 228.74,146.01 v1(228.7,146.05) ; v1(23.01,127.15) 23,127.16 CT84.2 22.3,127.02 CT86.2 ; RC84.2 178.89,53.65 v1(178.48,54.06) ; v1(208.1,150.05) 208.14,150.1 CV387.2 ; CV404.2 260.78,113.88 v1(260.8,113.9) ; CE17.2 91.42,28.01 91.78,27.64 93.23,27.64 DE1.2 93.99,26.3 v1(94.26,26.03) ; RD6.2 82.88,57.43 v1(82.04,56.59) 81.22,57.42 CD50.2 ; v1(36.3,120.62) 36.22,120.62 34.56,118.96 PC7.2 ; v1(223.9,150.45) 223.44,150.91 CV373.2 ; CV876.2 228.74,150.1 v1(228.7,150.05) ; v1(26.26,125.2) 26.21,125.15 CT56.2 CT71.2 ; CV175.2 203.26,147.21 v1(203.3,147.25) ; RE50.1 93.95,37.15 v1(94.6,37.15) ; v1(30.85,131.02) 30.39,130.57 PRS05.2 ; PCA106.2 94.47,132.23 93.96,132.23 v1(93.85,132.13) ; v1(257.94,98.29) 257.96,98.3 CV392.2 ; CH35.2 180.5,50.16 v1(180.1,50.57) ; v1(208.1,146.05) 208.14,146.01 CV383.2 ; v1(93,53.25) 93.03,53.29 CD47.2 ; RT35.2 19.65,132.31 v1(19.18,132.79) ; 63.36,41.82 63.84,41.82 64.34,42.32 v1(64.34,43.49) ; RP39.1 24.54,100.07 RP44.1 24.33,99.47 v1(23.93,99.06) ; PUS03.3 25.31,40.51 25.58,40.78 PRS48.2 ; CP13.2 17.43,94.86 v1(17.01,94.44) ; PCA107.2 v1(95.29,134.76) ; v1(18.95,127.42) 18.66,127.71 CT67.2 ; RV120.2 238.12,144.29 CV859.2 236.74,144.81 v1(236.7,144.85) ; v1(30.48,127.01) 30.91,127.01 31.06,126.87 PUS01.4 ; PR38.2 52.36,138.07 v1(52.35,138.06) ; v1(26.25,123.26) 26.21,123.3 CT70.2 ; v1(70.74,34.23) UE2.3 72.29,34.23 RE53.1 ; CV389.2 263.18,92.91 v1(263.3,93.04) ; CT77.2 27.66,123.91 v1(28.2,123.91) 28.25,123.95 RT19.2 ; PCS01.1 38.11,123.47 v1(38.39,123.75) ; 230.9,111.87 230.34,111.31 229.55,111.31 CV112.2 ; CA25.2 v1(24.26,14.3) ; PR6.2 46.6,142.15 PQ2.3 46.79,142.53 v1(46.34,142.97) ; 224.21,97.65 224.29,97.57 CV120.2 ; PCA109.2 v1(99.44,135.45) ; QS1.4 v1(274.74,41.08)
  TOP w0.4: v1(259.2,126.1) v1(259.2,126.7) ; v1(203.9,147.25) v1(203.3,147.25) ; v1(223.9,150.45) v1(224.5,150.45) ; v1(236.7,150.45) v1(236.1,150.45) v1(236.1,151.28) ; v1(203.3,151.25) v1(203.9,151.25) v1(203.9,150.45) v1(203.3,150.45) ; v1(259.2,105.6) v1(259.2,106.2) ; v1(259.2,113.9) v1(259.2,114.5) ; v1(263.2,114.5) v1(263.2,113.9) ; v1(236.1,147.25) v1(236.7,147.25) ; v1(224.5,144.95) v1(223.9,144.95) ; v1(223.9,147.25) v1(224.5,147.25)
  TOP w0.406: v1(184.4,49.33) 184.57,49.16 185.41,49.16 185.9,49.66 CC43.2 ; CH16.2 186.45,34.55 v1(185.24,34.55)
  TOP w0.457: CE28.2 69.96,40.08 v1(69.6,40.45) 68.81,41.24 PRS51.2 ; 224.17,118.62 224.54,118.26 CV152.2 ; CZ40.2 174.52,35.68 CZ33.1 175.34,35.18 v1(175.08,34.92) ; CH228.2 168.34,28.98 v1(168.15,29.17) ; CV938.2 224.26,120.17 224.17,120.25 ; PQ11.3 v1(275.27,59.4) ; CV154.2 223.3,116.97 223.32,116.95 ; v1(109.38,55.85) 109.71,55.85 110.01,56.15 CD7.2 ; CC298.2 133.78,32.85 133.78,33.09 133.59,33.29 v1(133.59,33.47) ; CE9.2 88.16,48.72 v1(88.3,48.86) ; RV108.2 223.65,143.4 223.9,143.15 ; v1(18.24,2.18) 19.58,3.53 CA30.2 ; v1(263.72,58.95) 263.72,58.55 263.94,58.32 PRB33.2 ; PCB43.2 v1(260.96,57.23) ; RP41.1 24.16,86.29 RP43.1 25.56,86.29 v1(25.7,86.43)
  TOP w0.508: v1(58.37,43.13) 58.48,43.24 CL10.2 ; v1(198.82,30.39) 198.17,29.74 RTPM4.2 ; 223.3,99.33 223.33,99.36 CV118.2 CV117.2 ; v1(171.62,45.49) 171.62,44.92 CH32.2 ; PC309.2 202.54,55.66 v1(202.79,55.41) ; CH15.2 171.43,40.44 v1(171.63,40.24) ; v1(252.59,91.27) 252.7,91.37 QV21.3 ; v1(75.58,54.3) 75.22,54.3 74.81,54.71 74.81,55.95 75.21,56.35 CD49.2 73.94,58.69 CD46.2 ; UW1.2 26.81,112.99 v1(27.2,112.6) ; U1.2 257.11,49.24 v1(257.58,48.77) ; PQ16.3 33.22,113.69 PQ15.3 33.02,113.59 32.09,112.66 v1(32.05,112.66) ; v1(261.49,58.51) 261.73,58.27 PCB45.2 ; RA22.2 20.11,7.97 v1(20.03,7.89) ; RW30.2 28.59,120.31 v3(29.34,121.06) v1(29.34,121.92) ; PCB29.2 262.35,48.35 v1(262.35,47.7) ; DA6.1 v1(260.43,39.92) ; v1(68.9,60.21) 69.41,59.7 70.16,59.7 70.17,59.71 CD53.2 ; RV153.1 v1(252.56,90.19) 252.56,89.68 252.81,89.43 RV154.1 ; 215.5,140.85 216.1,140.85 ; PQB04.3 275.06,56.52 v1(275.06,56.85) PR43.2 ; CL12.2 24.94,76.5 v1(24.94,78.54) ; CV833.2 205.77,112.22 ; CT49.2 30.39,130.46 PRS05.2 ; PCS11.2 30.7,52.51 v1(30.9,52.71) ; 226.64,98.45 226.76,98.57 CV214.2 ; RP40.1 CP7.2 22.5,101.04 v1(22.82,101.35) ; CC19.2 84.2,109.34 v1(84.05,109.19) ; v1(19.09,42.76) 19.09,42.54 PRS25.2 19.49,42.14 PCS12.2 ; CU16.2 272.18,29.54 v1(272.19,29.54) ; RV78.1 227.45,118.69 226.69,119.45 226.67,119.45 ; v1(19.53,112.92) PRS29.2 ; PCB39.2 266.23,58.71 PCB42.2 265.99,59.25 v1(265.57,59.66) 265.23,60.01 PCB40.2 ; v1(267.75,44.66) 267.88,44.66 PCB56.2 PRB51.2 ; v1(263.49,55.37) 263.2,55.65 PCB38.2 ; v1(42.06,91.26) 40.53,91.26 CT100.2 ; CV598.2 15.99,101.61 CV597.2 15.37,101.89 v1(15.95,102.47) ; CD23.2 76.65,71.72 76.68,71.68 77.7,71.68 CD16.2 78.19,71.98 v1(78.74,72.53) ; R10.2 254.27,48.75 v1(254.17,48.65) ; PQB10.3 v1(265.21,42.47) ; US2.2 v1(278.03,38.31) ; DA7.1 v1(20.59,23.05) ; v1(252.79,87.4) RV160.1 RV161.1 ; PRB20.2 271.01,56.52 v1(270.69,56.84) ; RP42.1 19.28,88.1 v1(19.4,87.98) ; PCS15.2 v1(35.46,67.14) ; v1(82.03,62.18) 81.06,62.18 CD51.2 80.37,62.26 79.99,61.87 CD45.2 ; CZ108.2 55.33,33.86 CL24.2 56.24,33.69 v1(56.33,33.78) 56.84,34.29 CL7.2 ; v1(74.82,73.29) 74.16,73.29 CD14.2 ; PCV117.2 218.47,98.59 218.47,99.17 ; v1(23.77,32.57) 23.57,32.78 CU11.2 CU12.2 ; v1(32.41,52.79) 31.68,52.06 PRS14.2 ; v1(79.48,109.19) 79.88,109.59 CC22.2 ; CD58.2 RD21.2 v1(91.42,48.86) ; PR45.2 v1(55.53,141.82) ; QS1.1 272.59,39.9 v1(272.3,40.19) ; PCW13.2 PRW08.2 v1(265.07,72.82) ; UL2.2 v1(43.49,36.89) ; v1(93.97,33.35) CE13.2 ; v1(77.35,55.27) 77.54,55.27 78.05,55.79 78.05,56.87 77.69,57.23 CD44.2 ; PQS11.3 v1(19.22,112.28) 19.79,112.28 PRS30.2 ; RV107.2 216.55,143.15 216.45,143.25 216.13,143.25 ; CZ32.2 174.3,41.03 v1(174.03,41.3) ; CV394.2 v1(265.84,96.18) ; v1(57.73,43.17) 57.73,43.56 CL11.2 ; CV390.2 260.8,92.15 260.8,92.96 v1(260.88,93.04) ; UU3.2 v1(268.68,30.44) ; CV189.2 v1(265.55,120.24) ; 63.36,41.82 62.46,41.82 CL8.2 ; CH31.2 189.35,53.03 190.56,53.03 191.43,52.16 CS29.2 ; CV943.1 231.25,113.55 231.7,113.1 231.7,112.72 ; CZ23.2 51.52,25.26 v1(51.21,25.58) ; v1(172.6,40.25) 172.78,40.43 CZ37.2 ; v1(265.1,61.21) 266.1,61.21 PRB24.2 PCB34.2 ; v1(251.9,67.36) 252.18,67.64 PRV07.1 ; CV202.2 225.87,98.16 226.38,97.65 226.67,97.65 ; RL4.2 64.67,38.81 63.98,39.5 v1(63.86,39.5) CL23.2 CL22.2 ; v1(34.47,10.34) 34.75,10.62 CA3.2 ; v1(265.85,66.37) 266.04,66.37 266.46,66.79 PCW14.1 ; CH12.2 170.59,43.54 v1(169.97,42.92) 169.91,42.86 CH14.2 ; CD55.2 67.13,59.7 66.61,60.22 v1(65.82,60.22) ; RV51.2 225.45,94.92 226.31,94.92 226.68,95.28 ; CC17.2 82.32,109.29 v1(82.22,109.19) ; v1(170.45,47.66) 170.78,47.66 CH22.2 ; RE157.2 CE19.2 v1(73.19,25.04) ; CA52.2 v1(22.43,8.13) ; PD1.1 v1(43.21,142.76) ; CZ46.1 170.65,37.95 v1(170.25,37.56) ; C17.2 v1(261.89,45.67) ; 120.59,49.85 120.59,49.84 PC509.2 ; v1(179.73,24.66) 179.3,25.09 CH225.2 179.31,25.28 CH226.2 ; v1(240.36,37.58) 240.3,37.58 Q13.3 ; RD4.2 108.56,61.74 v1(108.71,61.59) ; PCS04.2 35.4,127.82 35.12,128.1 PRS06.2 ; CL9.2 40.64,35.24 40.84,35.44 RL6.1 41.46,36.94 v1(41.63,36.77) ; RD22.2 87.85,53.92 v1(87.64,53.71) ; CH62.2 175.66,46.01 v1(175.59,45.94) ; 235.53,99.37 235.53,99.7 235.01,100.22 CV213.2 ; v1(103.09,118.25) 104.55,118.25 CH210.2 ; RP32.2 27.54,87.02 v1(27.39,86.87) ; CL6.2 51.6,40.42 v1(51.6,40.25) ; CV863.2 v1(231.54,152.5) ; PCB19.2 v1(268.94,46.75) ; RE168.2 76.45,25.65 RE16.2 CE31.2 v1(78.05,25.04) ; RV136.2 257.66,92.47 v1(257.22,92.91) ; PRB23.2 277.97,55.38 v1(278.24,55.66) CE100.2 ; v1(272.01,47.7) PCB26.2 271.3,47.78 PCB27.2 ; CV180.2 262.88,95.8 v1(262,95.8) ; RV155.1 233.54,93.66 ; PD3.2 47.23,137.29 v1(48.39,137.29) ; v1(100.65,94.44) 100.58,94.37 CZ57.2 100.5,92.96 CZ49.2 ; v1(34.91,59.21) 34.69,58.99 PQS21.3 ; CD20.2 73.93,64.91 73.37,65.48 v1(72.79,65.48) ; UV17.2 17.2,102.42 v1(17.07,102.42) ; CD11.2 57.42,64.04 v1(57.1,64.36) ; DU4.1 17.37,31.78 v1(17.13,31.55) ; CV53.2 208.68,98.13 208.32,97.77 208.32,97.43 208.85,96.9 RG37.2 ; PRS48.2 25.43,41.32 v1(25.43,41.82) ; RV162.1 232.55,91.2 v1(232.32,90.97) ; CH52.2 189.97,33.4 v1(189.69,33.12) ; CH29.2 177.91,46.05 v1(177.91,46.66) ; CT157.1 32.62,118.64 v1(31.91,118.64) ; v1(94.18,48.88) CD48.2 ; PRB10.2 v1(273.99,51.69) ; RC3.1 RC5.1 RC4.1 100.75,95.71 100.2,95.15 v1(100.2,94.89) ; RA17.2 33.07,23.47 v1(33.38,23.16) 33.61,22.93 RA24.2 ; v1(256,32.03) 255.59,32.44 U3.2 ; PRB07.2 v1(272.03,46.81) ; H15.1 280.8,26.83 ; RE32.2 97.39,39.76 v1(97.84,39.76) ; CV185.2 v1(265.52,102.34) ; CE14.2 v1(93.19,40.21) ; v1(55.7,47.53) 55.84,47.66 YL1.2 ; v1(55.7,47.53) 55.17,46.99 v1(54.53,46.99) 55.4,46.12 CL5.2 ; v1(55.7,47.53) 55.7,48.64 56.06,49 60.07,49 60.67,48.4 v1(60.67,47.14) 60.67,46.67 59.96,45.96 YL1.4 ; v1(104.77,72.47) 105.09,72.15 CD9.2 105.61,72.15 106.08,71.68 CD10.2 ; CV181.2 v1(265.87,99.86) ; PRZ69.2 109.79,154.06 v1(109.67,154.18) ; CV939.2 228.41,114.44 ; CD19.2 83.75,62.59 84.24,63.07 CD28.2 ; PCI106.2 84.2,133.72 84.67,134.19 v1(84.67,134.34) ; v1(27.98,115.93) 28.52,115.39 PQ21.3 ; CA15.2 v1(38.29,10.87) ; PRB50.1 260.43,45.13 v1(260.43,45.59) C15.2 ; CV170.2 v1(210.77,152.62) ; PCB28.2 v1(271.42,50.85) ; v1(263.2,106.2) v1(263.2,105.6) ; DA4.1 v1(16.73,21.73) ; RV49.2 RV66.1 225.11,92.76 225.34,92.53 v1(225.34,92.32) ; v1(267.13,46.66) PCB20.2 ; v1(46.43,64.45) 46.75,64.12 CD15.2 ; CD41.2 59.97,52.88 59.4,52.31 v1(59.02,52.31) ; v1(271.6,61.96) 271.04,61.4 PQB05.3 ; CC21.2 87.66,109.24 v1(87.71,109.19) ; CV403.2 v1(265.29,117.44) ; PCB35.2 260.59,53.77 v1(259.97,53.77) ; PCS22.2 v1(32.79,57.95) ; C31.2 v1(253.09,31.8) ; PCB36.2 v1(240.94,43.05) ; v1(29.8,97.63) 29.8,98.99 29.5,99.29 CP8.2 ; v1(63.35,59.78) 64.08,59.05 CD56.2 ; R79.1 165.81,27.55 v1(165.34,27.08) 165.74,26.68 C61.2 ; CH13.2 170.74,42.49 v1(170.74,41.48) ; v1(28.69,97.55) 28.7,97.55 CP11.2 ; CV858.2 v1(212.95,152.13) ; CA40.2 v1(39.38,11.99) ; 205.78,96.47 205.78,97.28 206.19,97.69 CV51.2 ; v1(82.06,60.96) 82.06,59.88 82.58,59.35 CD29.2 ; CA1.2 v1(35.82,9.35) ; DT16.1 v1(15.42,112.6) ; CH25.2 186.7,32.31 v1(186.7,31.66) 186.7,31.07 186.75,31.01 CH34.2 ; CS8.2 v1(275.81,42.37) ; DA5.1 v1(18.42,7.42) ; v1(32.97,130.3) 32.81,130.47 32.35,130.47 PCS02.2 32.63,131.19 PCS03.2 ; PQS19.3 31.38,57.9 30.49,57.9 30.15,58.23 v1(29.65,58.23) ; UU1.2 24.7,35.63 v1(25.04,35.3) ; CV937.2 228.62,109.15 228.4,109.37 ; CA13.1 37.9,20.84 v1(37.54,21.2) ; CE33.2 94.18,44.94 94.22,44.98 CE4.2 ; PCV101.2 218.48,106.03 218,105.55 ; CV883.2 v1(265.25,121.89) ; RL2.1 53.59,45.87 CL25.2 53.31,46.46 v1(53.81,46.97) ; RE19.2 82.82,26.16 83.26,26.61 v1(83.26,27.3) 83.01,27.56 CE10.2 ; PCZ12.1 v1(112.07,140.56) ; PQS03.3 31.77,46.31 v1(31.21,45.75) ; CS27.2 CS25.2 36.9,27.3 v1(37.32,27.72) ; CV851.2 v1(207.42,152.25) ; PRB26.2 268.31,58.63 v1(268.72,59.04) 269.12,58.64 PRB29.1 ; CV395.2 v1(265.51,104.12) ; RV79.1 230.07,115.98 230.07,116.05 ; v1(177.61,39.64) 177.97,40 CH63.2 ; PRS27.1 19.51,113.73 v1(19.37,113.86) ; v1(79.41,55.3) 79.68,55.3 80.02,55.64 80.02,56.36 79.66,56.72 CD52.2 ; CV165.2 v1(228.2,152.51) ; CV50.2 206.77,96.76 206.54,97 ; CA16.2 v1(37.75,12.01) ; CE11.2 v1(71.27,39.06) ; RC144.2 61.69,118.74 v1(61.69,118.14) 61.22,118.14 RC85.2 ; v1(48.28,142.12) 47.28,141.12 PD2.2 ; PCB44.1 39.27,36.15 v1(39.06,35.94) ; CTPM6.2 203.02,36.74 203.14,36.63 v1(203.67,36.63) 203.67,36.63 203.87,36.83 CTPM4.2 204.79,37.28 CTPM3.2 ; CH211.2 65.24,121.16 65.86,121.77 v1(65.86,121.89) ; CD54.2 60.4,50.18 61.19,50.97 v1(61.19,51.58) ; v1(210,38.08) 209.74,38.33 PD5.1 ; CZ25.2 v1(55.64,30) ; CV167.2 v1(234.82,152.51) ; CA51.2 29.23,24.61 v1(28.73,25.12) ; CV399.2 v1(265.31,123.41)
  GND1 w0.203: H10.1 12.23,41.2 ; H10.1 8.03,39.43 ; H10.1 9.8,43.63 ; H10.1 11.57,42.97 ; H10.1 11.57,39.43 ; H10.1 9.8,38.77 ; H10.1 8.03,42.97 ; H10.1 7.37,41.2 ; JHDMI1.5 11.51,93.89 ; JHDMI1.5 10.59,93.89 ; JHDMI1.5 10.47,94.35 ; JHDMI1.5 11.63,94.35 ; JHDMI1.5 11.51,94.81 ; JHDMI1.5 10.59,94.81 ; 4.88,37.98 JUSB2.11 ; JUSB2.11 4.88,37.1 ; JUSB2.11 7.92,37.98 ; JUSB2.11 7.92,37.1 ; JUSB2.11 6.4,37.98 ; JUSB1.7 14.38,53.98 ; JUSB1.7 15.21,53.15 ; JUSB1.7 13.74,52.52 ; JUSB1.7 15.01,53.79 ; JUSB1.7 13.74,53.79 ; JUSB1.7 15.01,52.52 ; JUSB1.7 14.38,52.32 ; JUSB1.7 13.55,53.15 ; JUSB2.4 16.51,25.11 ; JUSB2.4 15.88,26.58 ; JUSB2.4 16.51,26.38 ; JUSB2.4 15.88,24.92 ; JUSB2.4 15.24,26.38 ; JUSB2.4 16.71,25.75 ; 10.47,97.35 JHDMI1.11 ; JHDMI1.11 11.51,96.89 ; JHDMI1.11 11.51,97.81 ; JHDMI1.11 11.63,97.35 ; JHDMI1.11 10.59,97.81 ; JHDMI1.11 10.59,96.89 ; JUSB2.10 13.5,37.98 ; JUSB2.10 15.28,37.98 ; JUSB2.10 15.28,36.22 ; JUSB2.10 11.72,37.98 ; JUSB2.10 15.28,37.1 ; JUSB2.10 11.72,37.1 ; JUSB2.10 13.5,36.22 ; 5.97,85.8 H4.1 ; H4.1 6.48,84.38 ; H4.1 9.32,84.38 ; H4.1 6.48,87.22 ; H4.1 7.9,83.87 ; H4.1 9.83,85.8 ; H4.1 9.32,87.22 ; H4.1 7.9,87.73 ; H12.1 192.27,151.13 ; H12.1 191.1,153.89 ; H12.1 189.93,151.13 ; H12.1 192.69,152.3 ; H12.1 189.51,152.3 ; H12.1 192.27,153.47 ; H12.1 189.93,153.47 ; H12.1 191.1,150.71 ; H16.1 280.85,50.68 ; H16.1 279.08,46.48 ; H16.1 283.28,48.25 ; H16.1 280.85,45.82 ; H16.1 278.42,48.25 ; H16.1 279.08,50.02 ; H16.1 282.62,50.02 ; H16.1 282.62,46.48 ; H9.1 95.47,154.77 ; H9.1 91.93,151.23 ; H9.1 91.27,153 ; H9.1 93.7,150.57 ; H9.1 93.7,155.43 ; H9.1 91.93,154.77 ; H9.1 96.13,153 ; H9.1 95.47,151.23 ; H11.1 248.47,151.23 ; H11.1 248.47,154.77 ; H11.1 246.7,150.57 ; H11.1 244.27,153 ; H11.1 244.93,154.77 ; H11.1 244.93,151.23 ; H11.1 249.13,153 ; H11.1 246.7,155.43 ; 13.5,60.12 JUSB1.10 ; JUSB1.10 15.28,61 ; JUSB1.10 11.72,61 ; JUSB1.10 11.72,61.88 ; JUSB1.10 13.5,61.88 ; JUSB1.10 15.28,61.88 ; JUSB1.10 15.28,60.12 ; 5.18,132.17 H1.1 ; H1.1 6.85,128.21 ; H1.1 6.85,132.79 ; H1.1 9.14,130.5 ; H1.1 8.52,128.83 ; H1.1 5.18,128.83 ; H1.1 8.52,132.17 ; H1.1 4.56,130.5 ; JLAN1.9 10.65,66.42 ; JLAN1.9 10.65,65.08 ; JLAN1.9 11.83,65.08 ; JLAN1.9 9.47,66.42 ; JLAN1.9 9.47,65.08 ; JLAN1.9 11.83,65.75 ; JLAN1.9 9.47,65.75 ; JUSB1.4 15.88,50.48 ; JUSB1.4 15.24,50.29 ; JUSB1.4 16.51,50.29 ; JUSB1.4 16.51,49.02 ; JUSB1.4 16.71,49.65 ; JUSB1.4 15.88,48.82 ; 37.7,130.42 H5.1 ; H5.1 39.19,133.94 ; H5.1 39.73,132.45 ; H5.1 36.21,133.94 ; H5.1 37.7,134.48 ; H5.1 35.67,132.45 ; H5.1 39.19,130.96 ; H5.1 36.21,130.96 ; JUSB2.13 15.28,20.52 ; JUSB2.13 13.5,22.28 ; JUSB2.13 13.5,20.52 ; JUSB2.13 11.72,21.4 ; JUSB2.13 11.72,20.52 ; JUSB2.13 15.28,21.4 ; JUSB2.13 15.28,22.28 ; 4.88,61.88 JUSB1.11 ; JUSB1.11 6.4,61.88 ; JUSB1.11 7.92,61.88 ; JUSB1.11 7.92,61 ; JUSB1.11 4.88,61 ; JHDMI1.8 13.06,95.39 ; JHDMI1.8 12.14,96.31 ; JHDMI1.8 12.14,95.39 ; JHDMI1.8 13.06,96.31 ; JHDMI1.8 13.18,95.85 ; JHDMI1.8 12.02,95.85 ; 30.25,2.42 H7.1 ; H7.1 32.18,2.42 ; H7.1 30.25,6.58 ; H7.1 28.32,6.58 ; H7.1 32.18,6.58 ; H7.1 32.18,4.5 ; H7.1 28.32,4.5 ; H7.1 28.32,2.42 ; JHDMI1.22 4.58,87.07 ; JHDMI1.22 4.58,88.1 ; JHDMI1.22 1.22,87.07 ; JHDMI1.22 1.22,88.1 ; JHDMI1.22 2.9,87.07 ; 4.88,45.3 JUSB1.12 ; JUSB1.12 6.4,44.42 ; JUSB1.12 7.92,45.3 ; JUSB1.12 4.88,44.42 ; JUSB1.12 7.92,44.42 ; 5.41,125.22 JUSBC1.2 ; JUSBC1.2 6.89,126.35 ; JUSBC1.2 5.41,124.29 ; JUSBC1.2 6.15,126.35 ; JUSBC1.2 5.41,126.35 ; JLAN1.10 4.03,65.08 ; JLAN1.10 2.85,65.08 ; JLAN1.10 1.67,66.42 ; JLAN1.10 1.67,65.08 ; JLAN1.10 1.67,65.75 ; JLAN1.10 4.03,65.75 ; JLAN1.10 2.85,66.42 ; JLAN1.10 4.03,66.42 ; HGPU3.1 195.87,134.72 ; HGPU3.1 192.53,131.38 ; HGPU3.1 195.87,131.38 ; HGPU3.1 194.2,130.76 ; HGPU3.1 192.53,134.72 ; HGPU3.1 191.91,133.05 ; HGPU3.1 196.49,133.05 ; HGPU3.1 194.2,135.34 ; 111.8,101.36 HCPU4.1 ; HCPU4.1 110.13,101.98 ; HCPU4.1 111.8,105.94 ; HCPU4.1 109.51,103.65 ; HCPU4.1 110.13,105.32 ; HCPU4.1 113.47,101.98 ; HCPU4.1 113.47,105.32 ; HCPU4.1 114.09,103.65 ; JHDMI1.20 11.25,90.48 ; JHDMI1.20 12.53,88.72 ; JHDMI1.20 9.97,90.48 ; JHDMI1.20 9.97,88.72 ; JHDMI1.20 12.53,90.48 ; JHDMI1.20 12.53,89.6 ; JHDMI1.20 11.25,88.72 ; 6.4,20.52 JUSB2.12 ; JUSB2.12 4.88,20.52 ; JUSB2.12 7.92,21.4 ; JUSB2.12 7.92,20.52 ; JUSB2.12 4.88,21.4 ; JHDMI1.23 4.58,105.6 ; JHDMI1.23 1.22,106.63 ; JHDMI1.23 2.9,106.63 ; JHDMI1.23 1.22,105.6 ; JHDMI1.23 4.58,106.63 ; 9.97,104.98 JHDMI1.21 ; JHDMI1.21 11.25,104.98 ; JHDMI1.21 12.53,104.1 ; JHDMI1.21 12.53,103.22 ; JHDMI1.21 9.97,103.22 ; JHDMI1.21 12.53,104.98 ; JHDMI1.21 11.25,103.22 ; 192.86,84.21 HGPU2.1 ; HGPU2.1 192.86,88.79 ; HGPU2.1 194.53,84.83 ; HGPU2.1 190.57,86.5 ; HGPU2.1 195.15,86.5 ; HGPU2.1 191.19,84.83 ; HGPU2.1 191.19,88.17 ; HGPU2.1 194.53,88.17 ; 50.71,103.65 HCPU3.1 ; HCPU3.1 53,101.36 ; HCPU3.1 54.67,101.98 ; HCPU3.1 51.33,101.98 ; HCPU3.1 51.33,105.32 ; HCPU3.1 55.29,103.65 ; HCPU3.1 53,105.94 ; HCPU3.1 54.67,105.32 ; 1.6,124.69 JUSBC1.5 ; JUSBC1.5 3.02,125.52 ; JUSBC1.5 3.02,124.69 ; JUSBC1.5 3.02,126.35 ; JUSBC1.5 1.6,126.35 ; JUSBC1.6 1.6,117.71 ; JUSBC1.6 1.6,116.05 ; JUSBC1.6 3.02,117.71 ; JUSBC1.6 3.02,116.05 ; JUSBC1.6 3.02,116.88 ; JUSBC1.1 7.88,125.52 ; JUSBC1.1 5.42,126.35 ; JUSBC1.1 5.42,124.69 ; JUSBC1.1 6.65,126.35 ; JUSBC1.1 7.88,126.35 ; JUSBC1.1 5.42,125.52 ; JUSBC1.1 7.88,124.69 ; 194.02,42 H8.1 ; H8.1 198.22,40.23 ; H8.1 194.68,43.77 ; H8.1 198.22,43.77 ; H8.1 194.68,40.23 ; H8.1 198.88,42 ; H8.1 196.45,39.57 ; H8.1 196.45,44.43 ; 13.74,28.61 JUSB2.7 ; JUSB2.7 15.01,28.61 ; JUSB2.7 14.38,30.08 ; JUSB2.7 15.21,29.25 ; JUSB2.7 13.55,29.25 ; JUSB2.7 15.01,29.88 ; JUSB2.7 13.74,29.88 ; JUSB2.7 14.38,28.42 ; 5.41,116.05 JUSBC1.3 ; JUSBC1.3 6.89,116.05 ; JUSBC1.3 6.15,116.05 ; JUSBC1.3 5.41,117.18 ; JUSBC1.3 5.41,118.11 ; 248.2,78.21 HGPU4.1 ; HGPU4.1 246.53,82.17 ; HGPU4.1 246.53,78.83 ; HGPU4.1 249.87,78.83 ; HGPU4.1 245.91,80.5 ; HGPU4.1 249.87,82.17 ; HGPU4.1 250.49,80.5 ; HGPU4.1 248.2,82.79 ; JLAN1.11 4.03,82.55 ; JLAN1.11 2.85,83.22 ; JLAN1.11 1.67,82.55 ; JLAN1.11 4.03,83.22 ; JLAN1.11 1.67,83.22 ; JLAN1.11 4.03,81.88 ; JLAN1.11 2.85,81.88 ; JLAN1.11 1.67,81.88 ; 9.47,83.22 JLAN1.12 ; JLAN1.12 9.47,82.55 ; JLAN1.12 10.65,83.22 ; JLAN1.12 9.47,81.88 ; JLAN1.12 10.65,81.88 ; H2.1 6.9,114.68 ; H2.1 5.38,114.12 ; H2.1 8.98,112.6 ; H2.1 8.42,111.08 ; H2.1 5.38,111.08 ; H2.1 4.82,112.6 ; H2.1 6.9,110.52 ; H2.1 8.42,114.12 ; 5.42,116.88 JUSBC1.4 ; JUSBC1.4 7.88,116.88 ; JUSBC1.4 6.65,116.05 ; JUSBC1.4 7.88,117.71 ; JUSBC1.4 5.42,116.05 ; JUSBC1.4 7.88,116.05 ; H6.1 185.47,68.73 ; H6.1 183.7,68.07 ; H6.1 181.93,68.73 ; H6.1 181.27,70.5 ; H6.1 186.13,70.5 ; H6.1 183.7,72.93 ; H6.1 185.47,72.27 ; H6.1 181.93,72.27 ; 51.33,127.92 HCPU1.1 ; HCPU1.1 50.71,126.25 ; HCPU1.1 51.33,124.58 ; HCPU1.1 53,123.96 ; HCPU1.1 53,128.54 ; HCPU1.1 54.67,124.58 ; HCPU1.1 55.29,126.25 ; HCPU1.1 54.67,127.92 ; JHDMI1.2 13.06,93.31 ; JHDMI1.2 12.14,92.39 ; JHDMI1.2 12.6,92.27 ; JHDMI1.2 12.02,92.85 ; JHDMI1.2 12.14,93.31 ; JHDMI1.2 13.18,92.85 ; JHDMI1.2 13.06,92.39 ; JUSB1.13 15.28,45.3 ; JUSB1.13 11.72,44.42 ; JUSB1.13 15.28,44.42 ; JUSB1.13 13.5,44.42 ; JUSB1.13 15.28,46.18 ; JUSB1.13 11.72,45.3 ; JUSB1.13 13.5,46.18 ; JHDMI1.17 11.63,100.35 ; JHDMI1.17 10.59,100.81 ; JHDMI1.17 10.59,99.89 ; JHDMI1.17 11.51,100.81 ; JHDMI1.17 10.47,100.35 ; JHDMI1.17 11.51,99.89 ; HCPU2.1 114.09,126.25 ; HCPU2.1 109.51,126.25 ; HCPU2.1 110.13,127.92 ; HCPU2.1 110.13,124.58 ; HCPU2.1 111.8,128.54 ; HCPU2.1 113.47,127.92 ; HCPU2.1 111.8,123.96 ; HCPU2.1 113.47,124.58 ; 120.85,25.67 H13.1 ; H13.1 119.08,29.87 ; H13.1 119.08,26.33 ; H13.1 123.28,28.1 ; H13.1 122.62,26.33 ; H13.1 118.42,28.1 ; H13.1 120.85,30.53 ; H13.1 122.62,29.87
  VCC w0.203: H9.1 96.13,153 ; H9.1 95.47,151.23 ; H9.1 93.7,155.43 ; H9.1 91.93,151.23 ; H9.1 91.93,154.77 ; H9.1 95.47,154.77 ; H9.1 91.27,153 ; H9.1 93.7,150.57 ; 181.93,72.27 H6.1 ; H6.1 185.47,72.27 ; H6.1 183.7,72.93 ; H6.1 183.7,68.07 ; H6.1 181.93,68.73 ; H6.1 181.27,70.5 ; H6.1 186.13,70.5 ; H6.1 185.47,68.73 ; 189.93,151.13 H12.1 ; H12.1 192.69,152.3 ; H12.1 192.27,153.47 ; H12.1 189.51,152.3 ; H12.1 191.1,153.89 ; H12.1 191.1,150.71 ; H12.1 192.27,151.13 ; H12.1 189.93,153.47 ; HGPU4.1 250.49,80.5 ; HGPU4.1 248.2,78.21 ; HGPU4.1 245.91,80.5 ; HGPU4.1 246.53,78.83 ; HGPU4.1 248.2,82.79 ; HGPU4.1 249.87,78.83 ; HGPU4.1 249.87,82.17 ; HGPU4.1 246.53,82.17 ; HGPU3.1 195.87,131.38 ; HGPU3.1 191.91,133.05 ; HGPU3.1 194.2,130.76 ; HGPU3.1 192.53,134.72 ; HGPU3.1 194.2,135.34 ; HGPU3.1 195.87,134.72 ; HGPU3.1 196.49,133.05 ; HGPU3.1 192.53,131.38 ; H1.1 8.52,128.83 ; H1.1 6.85,128.21 ; H1.1 5.18,132.17 ; H1.1 8.52,132.17 ; H1.1 5.18,128.83 ; H1.1 4.56,130.5 ; H1.1 6.85,132.79 ; H1.1 9.14,130.5 ; 36.21,130.96 H5.1 ; H5.1 39.19,130.96 ; H5.1 35.67,132.45 ; H5.1 37.7,134.48 ; H5.1 36.21,133.94 ; H5.1 39.19,133.94 ; H5.1 37.7,130.42 ; H5.1 39.73,132.45 ; 244.93,151.23 H11.1 ; H11.1 244.93,154.77 ; H11.1 246.7,150.57 ; H11.1 246.7,155.43 ; H11.1 248.47,154.77 ; H11.1 248.47,151.23 ; H11.1 249.13,153 ; H11.1 244.27,153 ; 28.32,4.5 H7.1 ; H7.1 32.18,6.58 ; H7.1 32.18,2.42 ; H7.1 28.32,6.58 ; H7.1 28.32,2.42 ; H7.1 30.25,6.58 ; H7.1 30.25,2.42 ; H7.1 32.18,4.5
  GND2 w0.203: 10.47,100.35 JHDMI1.17 ; JHDMI1.17 10.59,100.81 ; JHDMI1.17 10.59,99.89 ; JHDMI1.17 11.51,100.81 ; JHDMI1.17 11.63,100.35 ; JHDMI1.17 11.51,99.89 ; JHDMI1.23 4.58,106.63 ; JHDMI1.23 4.58,105.6 ; JHDMI1.23 1.22,105.6 ; JHDMI1.23 1.22,106.63 ; JHDMI1.23 2.9,106.63 ; 6.48,84.38 H4.1 ; H4.1 7.9,83.87 ; H4.1 9.83,85.8 ; H4.1 6.48,87.22 ; H4.1 9.32,87.22 ; H4.1 7.9,87.73 ; H4.1 9.32,84.38 ; H4.1 5.97,85.8 ; 36.21,130.96 H5.1 ; H5.1 37.7,134.48 ; H5.1 37.7,130.42 ; H5.1 39.73,132.45 ; H5.1 39.19,133.94 ; H5.1 36.21,133.94 ; H5.1 39.19,130.96 ; H5.1 35.67,132.45 ; 1.67,65.08 JLAN1.10 ; JLAN1.10 4.03,66.42 ; JLAN1.10 2.85,66.42 ; JLAN1.10 4.03,65.08 ; JLAN1.10 4.03,65.75 ; JLAN1.10 1.67,65.75 ; JLAN1.10 1.67,66.42 ; JLAN1.10 2.85,65.08 ; 2.9,87.07 JHDMI1.22 ; JHDMI1.22 4.58,87.07 ; JHDMI1.22 4.58,88.1 ; JHDMI1.22 1.22,87.07 ; JHDMI1.22 1.22,88.1 ; 91.93,151.23 H9.1 ; H9.1 93.7,150.57 ; H9.1 91.27,153 ; H9.1 95.47,154.77 ; H9.1 93.7,155.43 ; H9.1 96.13,153 ; H9.1 95.47,151.23 ; H9.1 91.93,154.77 ; JLAN1.9 11.83,65.08 ; JLAN1.9 9.47,66.42 ; JLAN1.9 9.47,65.75 ; JLAN1.9 10.65,66.42 ; JLAN1.9 10.65,65.08 ; JLAN1.9 9.47,65.08 ; JLAN1.9 11.83,65.75 ; 28.32,4.5 H7.1 ; H7.1 28.32,2.42 ; H7.1 28.32,6.58 ; H7.1 30.25,6.58 ; H7.1 30.25,2.42 ; H7.1 32.18,2.42 ; H7.1 32.18,4.5 ; H7.1 32.18,6.58 ; JUSB1.4 16.51,50.29 ; JUSB1.4 15.88,48.82 ; JUSB1.4 16.71,49.65 ; JUSB1.4 16.51,49.02 ; JUSB1.4 15.88,50.48 ; JUSB1.4 15.24,50.29 ; 279.08,50.02 H16.1 ; H16.1 282.62,50.02 ; H16.1 279.08,46.48 ; H16.1 283.28,48.25 ; H16.1 282.62,46.48 ; H16.1 280.85,45.82 ; H16.1 280.85,50.68 ; H16.1 278.42,48.25 ; H10.1 11.57,39.43 ; H10.1 9.8,43.63 ; H10.1 9.8,38.77 ; H10.1 8.03,42.97 ; H10.1 12.23,41.2 ; H10.1 7.37,41.2 ; H10.1 11.57,42.97 ; H10.1 8.03,39.43 ; 9.97,90.48 JHDMI1.20 ; JHDMI1.20 12.53,88.72 ; JHDMI1.20 12.53,90.48 ; JHDMI1.20 9.97,88.72 ; JHDMI1.20 12.53,89.6 ; JHDMI1.20 11.25,88.72 ; JHDMI1.20 11.25,90.48 ; 244.27,153 H11.1 ; H11.1 248.47,154.77 ; H11.1 244.93,154.77 ; H11.1 246.7,155.43 ; H11.1 249.13,153 ; H11.1 248.47,151.23 ; H11.1 244.93,151.23 ; H11.1 246.7,150.57 ; JUSB1.12 7.92,45.3 ; JUSB1.12 6.4,44.42 ; JUSB1.12 7.92,44.42 ; JUSB1.12 4.88,44.42 ; JUSB1.12 4.88,45.3 ; HCPU3.1 54.67,101.98 ; HCPU3.1 55.29,103.65 ; HCPU3.1 51.33,101.98 ; HCPU3.1 53,105.94 ; HCPU3.1 51.33,105.32 ; HCPU3.1 50.71,103.65 ; HCPU3.1 54.67,105.32 ; HCPU3.1 53,101.36 ; 11.72,37.98 JUSB2.10 ; JUSB2.10 13.5,36.22 ; JUSB2.10 15.28,37.98 ; JUSB2.10 11.72,37.1 ; JUSB2.10 15.28,37.1 ; JUSB2.10 15.28,36.22 ; JUSB2.10 13.5,37.98 ; 1.6,116.05 JUSBC1.6 ; JUSBC1.6 1.6,117.71 ; JUSBC1.6 3.02,116.88 ; JUSBC1.6 3.02,117.71 ; JUSBC1.6 3.02,116.05 ; 109.51,103.65 HCPU4.1 ; HCPU4.1 111.8,101.36 ; HCPU4.1 114.09,103.65 ; HCPU4.1 110.13,105.32 ; HCPU4.1 111.8,105.94 ; HCPU4.1 110.13,101.98 ; HCPU4.1 113.47,101.98 ; HCPU4.1 113.47,105.32 ; 5.41,126.35 JUSBC1.2 ; JUSBC1.2 5.41,125.22 ; JUSBC1.2 6.89,126.35 ; JUSBC1.2 5.41,124.29 ; JUSBC1.2 6.15,126.35 ; 4.88,21.4 JUSB2.12 ; JUSB2.12 7.92,20.52 ; JUSB2.12 7.92,21.4 ; JUSB2.12 4.88,20.52 ; JUSB2.12 6.4,20.52 ; H6.1 183.7,72.93 ; H6.1 181.27,70.5 ; H6.1 181.93,72.27 ; H6.1 186.13,70.5 ; H6.1 181.93,68.73 ; H6.1 185.47,68.73 ; H6.1 183.7,68.07 ; H6.1 185.47,72.27 ; JUSB2.4 15.88,26.58 ; JUSB2.4 16.71,25.75 ; JUSB2.4 16.51,25.11 ; JUSB2.4 15.88,24.92 ; JUSB2.4 15.24,26.38 ; JUSB2.4 16.51,26.38 ; HGPU3.1 195.87,131.38 ; HGPU3.1 194.2,130.76 ; HGPU3.1 194.2,135.34 ; HGPU3.1 196.49,133.05 ; HGPU3.1 195.87,134.72 ; HGPU3.1 192.53,131.38 ; HGPU3.1 191.91,133.05 ; HGPU3.1 192.53,134.72 ; H1.1 9.14,130.5 ; H1.1 5.18,128.83 ; H1.1 4.56,130.5 ; H1.1 8.52,128.83 ; H1.1 6.85,132.79 ; H1.1 8.52,132.17 ; H1.1 5.18,132.17 ; H1.1 6.85,128.21 ; HCPU1.1 54.67,127.92 ; HCPU1.1 50.71,126.25 ; HCPU1.1 53,128.54 ; HCPU1.1 51.33,124.58 ; HCPU1.1 54.67,124.58 ; HCPU1.1 55.29,126.25 ; HCPU1.1 51.33,127.92 ; HCPU1.1 53,123.96 ; JHDMI1.2 13.06,93.31 ; JHDMI1.2 12.6,92.27 ; JHDMI1.2 12.14,92.39 ; JHDMI1.2 12.14,93.31 ; JHDMI1.2 13.18,92.85 ; JHDMI1.2 13.06,92.39 ; JHDMI1.2 12.02,92.85 ; 110.13,124.58 HCPU2.1 ; HCPU2.1 109.51,126.25 ; HCPU2.1 111.8,123.96 ; HCPU2.1 113.47,124.58 ; HCPU2.1 114.09,126.25 ; HCPU2.1 111.8,128.54 ; HCPU2.1 110.13,127.92 ; HCPU2.1 113.47,127.92 ; HGPU4.1 249.87,78.83 ; HGPU4.1 248.2,78.21 ; HGPU4.1 248.2,82.79 ; HGPU4.1 250.49,80.5 ; HGPU4.1 246.53,82.17 ; HGPU4.1 246.53,78.83 ; HGPU4.1 245.91,80.5 ; HGPU4.1 249.87,82.17 ; JUSB2.7 15.01,28.61 ; JUSB2.7 14.38,30.08 ; JUSB2.7 15.01,29.88 ; JUSB2.7 14.38,28.42 ; JUSB2.7 13.55,29.25 ; JUSB2.7 15.21,29.25 ; JUSB2.7 13.74,28.61 ; JUSB2.7 13.74,29.88 ; JUSB1.7 15.01,52.52 ; JUSB1.7 13.55,53.15 ; JUSB1.7 13.74,53.79 ; JUSB1.7 14.38,53.98 ; JUSB1.7 15.21,53.15 ; JUSB1.7 14.38,52.32 ; JUSB1.7 15.01,53.79 ; JUSB1.7 13.74,52.52 ; 10.47,97.35 JHDMI1.11 ; JHDMI1.11 11.63,97.35 ; JHDMI1.11 11.51,97.81 ; JHDMI1.11 10.59,97.81 ; JHDMI1.11 11.51,96.89 ; JHDMI1.11 10.59,96.89 ; 6.9,110.52 H2.1 ; H2.1 5.38,114.12 ; H2.1 8.98,112.6 ; H2.1 8.42,114.12 ; H2.1 8.42,111.08 ; H2.1 6.9,114.68 ; H2.1 5.38,111.08 ; H2.1 4.82,112.6 ; H12.1 191.1,153.89 ; H12.1 192.27,153.47 ; H12.1 192.69,152.3 ; H12.1 189.51,152.3 ; H12.1 189.93,153.47 ; H12.1 191.1,150.71 ; H12.1 189.93,151.13 ; H12.1 192.27,151.13 ; 10.47,94.35 JHDMI1.5 ; JHDMI1.5 10.59,93.89 ; JHDMI1.5 10.59,94.81 ; JHDMI1.5 11.51,93.89 ; JHDMI1.5 11.63,94.35 ; JHDMI1.5 11.51,94.81 ; H13.1 123.28,28.1 ; H13.1 122.62,29.87 ; H13.1 119.08,26.33 ; H13.1 119.08,29.87 ; H13.1 122.62,26.33 ; H13.1 120.85,30.53 ; H13.1 118.42,28.1 ; H13.1 120.85,25.67 ; 11.72,45.3 JUSB1.13 ; JUSB1.13 15.28,46.18 ; JUSB1.13 11.72,44.42 ; JUSB1.13 15.28,45.3 ; JUSB1.13 15.28,44.42 ; JUSB1.13 13.5,44.42 ; JUSB1.13 13.5,46.18 ; 190.57,86.5 HGPU2.1 ; HGPU2.1 195.15,86.5 ; HGPU2.1 192.86,88.79 ; HGPU2.1 191.19,84.83 ; HGPU2.1 192.86,84.21 ; HGPU2.1 194.53,88.17 ; HGPU2.1 191.19,88.17 ; HGPU2.1 194.53,84.83 ; 5.42,124.69 JUSBC1.1 ; JUSBC1.1 6.65,126.35 ; JUSBC1.1 5.42,125.52 ; JUSBC1.1 7.88,125.52 ; JUSBC1.1 7.88,126.35 ; JUSBC1.1 7.88,124.69 ; JUSBC1.1 5.42,126.35 ; JHDMI1.8 13.18,95.85 ; JHDMI1.8 13.06,95.39 ; JHDMI1.8 12.14,96.31 ; JHDMI1.8 12.02,95.85 ; JHDMI1.8 12.14,95.39 ; JHDMI1.8 13.06,96.31 ; JUSBC1.5 3.02,125.52 ; JUSBC1.5 3.02,126.35 ; JUSBC1.5 1.6,126.35 ; JUSBC1.5 3.02,124.69 ; JUSBC1.5 1.6,124.69 ; H8.1 198.22,43.77 ; H8.1 194.68,40.23 ; H8.1 196.45,44.43 ; H8.1 198.88,42 ; H8.1 198.22,40.23 ; H8.1 194.02,42 ; H8.1 196.45,39.57 ; H8.1 194.68,43.77 ; 9.47,81.88 JLAN1.12 ; JLAN1.12 9.47,83.22 ; JLAN1.12 10.65,81.88 ; JLAN1.12 10.65,83.22 ; JLAN1.12 9.47,82.55 ; 13.5,20.52 JUSB2.13 ; JUSB2.13 13.5,22.28 ; JUSB2.13 11.72,20.52 ; JUSB2.13 15.28,20.52 ; JUSB2.13 15.28,22.28 ; JUSB2.13 15.28,21.4 ; JUSB2.13 11.72,21.4 ; 11.25,103.22 JHDMI1.21 ; JHDMI1.21 12.53,104.98 ; JHDMI1.21 12.53,104.1 ; JHDMI1.21 9.97,104.98 ; JHDMI1.21 11.25,104.98 ; JHDMI1.21 12.53,103.22 ; JHDMI1.21 9.97,103.22 ; JUSBC1.4 7.88,116.05 ; JUSBC1.4 5.42,116.05 ; JUSBC1.4 7.88,116.88 ; JUSBC1.4 6.65,116.05 ; JUSBC1.4 7.88,117.71 ; JUSBC1.4 5.42,116.88 ; 4.88,61 JUSB1.11 ; JUSB1.11 7.92,61.88 ; JUSB1.11 7.92,61 ; JUSB1.11 4.88,61.88 ; JUSB1.11 6.4,61.88 ; JLAN1.11 2.85,83.22 ; JLAN1.11 2.85,81.88 ; JLAN1.11 4.03,82.55 ; JLAN1.11 1.67,82.55 ; JLAN1.11 1.67,81.88 ; JLAN1.11 1.67,83.22 ; JLAN1.11 4.03,81.88 ; JLAN1.11 4.03,83.22 ; JUSB2.11 6.4,37.98 ; JUSB2.11 4.88,37.1 ; JUSB2.11 7.92,37.1 ; JUSB2.11 7.92,37.98 ; JUSB2.11 4.88,37.98 ; 6.15,116.05 JUSBC1.3 ; JUSBC1.3 5.41,118.11 ; JUSBC1.3 6.89,116.05 ; JUSBC1.3 5.41,117.18 ; JUSBC1.3 5.41,116.05 ; 13.5,60.12 JUSB1.10 ; JUSB1.10 15.28,61 ; JUSB1.10 15.28,61.88 ; JUSB1.10 11.72,61 ; JUSB1.10 13.5,61.88 ; JUSB1.10 15.28,60.12 ; JUSB1.10 11.72,61.88
  GND3 w0.203: 5.41,124.29 JUSBC1.2 ; JUSBC1.2 6.15,126.35 ; JUSBC1.2 5.41,125.22 ; JUSBC1.2 5.41,126.35 ; JUSBC1.2 6.89,126.35 ; JUSBC1.3 6.89,116.05 ; JUSBC1.3 5.41,116.05 ; JUSBC1.3 5.41,117.18 ; JUSBC1.3 5.41,118.11 ; JUSBC1.3 6.15,116.05 ; JUSBC1.6 3.02,116.05 ; JUSBC1.6 3.02,117.71 ; JUSBC1.6 1.6,117.71 ; JUSBC1.6 3.02,116.88 ; JUSBC1.6 1.6,116.05 ; H11.1 248.47,151.23 ; H11.1 246.7,150.57 ; H11.1 244.93,154.77 ; H11.1 246.7,155.43 ; H11.1 244.93,151.23 ; H11.1 244.27,153 ; H11.1 249.13,153 ; H11.1 248.47,154.77 ; HGPU2.1 195.15,86.5 ; HGPU2.1 191.19,84.83 ; HGPU2.1 190.57,86.5 ; HGPU2.1 194.53,84.83 ; HGPU2.1 192.86,84.21 ; HGPU2.1 194.53,88.17 ; HGPU2.1 192.86,88.79 ; HGPU2.1 191.19,88.17 ; 11.72,61 JUSB1.10 ; JUSB1.10 13.5,61.88 ; JUSB1.10 11.72,61.88 ; JUSB1.10 15.28,61 ; JUSB1.10 15.28,61.88 ; JUSB1.10 13.5,60.12 ; JUSB1.10 15.28,60.12 ; HGPU4.1 249.87,82.17 ; HGPU4.1 248.2,82.79 ; HGPU4.1 246.53,78.83 ; HGPU4.1 248.2,78.21 ; HGPU4.1 245.91,80.5 ; HGPU4.1 249.87,78.83 ; HGPU4.1 250.49,80.5 ; HGPU4.1 246.53,82.17 ; 2.85,65.08 JLAN1.10 ; JLAN1.10 2.85,66.42 ; JLAN1.10 1.67,66.42 ; JLAN1.10 1.67,65.75 ; JLAN1.10 4.03,65.08 ; JLAN1.10 4.03,65.75 ; JLAN1.10 4.03,66.42 ; JLAN1.10 1.67,65.08 ; JUSB2.4 16.71,25.75 ; JUSB2.4 16.51,25.11 ; JUSB2.4 15.24,26.38 ; JUSB2.4 15.88,26.58 ; JUSB2.4 16.51,26.38 ; JUSB2.4 15.88,24.92 ; 120.85,25.67 H13.1 ; H13.1 119.08,26.33 ; H13.1 123.28,28.1 ; H13.1 122.62,29.87 ; H13.1 122.62,26.33 ; H13.1 120.85,30.53 ; H13.1 119.08,29.87 ; H13.1 118.42,28.1 ; 10.59,93.89 JHDMI1.5 ; JHDMI1.5 11.63,94.35 ; JHDMI1.5 11.51,93.89 ; JHDMI1.5 11.51,94.81 ; JHDMI1.5 10.47,94.35 ; JHDMI1.5 10.59,94.81 ; JHDMI1.20 12.53,88.72 ; JHDMI1.20 11.25,88.72 ; JHDMI1.20 11.25,90.48 ; JHDMI1.20 12.53,90.48 ; JHDMI1.20 12.53,89.6 ; JHDMI1.20 9.97,88.72 ; JHDMI1.20 9.97,90.48 ; H16.1 282.62,46.48 ; H16.1 282.62,50.02 ; H16.1 280.85,45.82 ; H16.1 278.42,48.25 ; H16.1 279.08,50.02 ; H16.1 283.28,48.25 ; H16.1 280.85,50.68 ; H16.1 279.08,46.48 ; HGPU3.1 196.49,133.05 ; HGPU3.1 195.87,134.72 ; HGPU3.1 192.53,134.72 ; HGPU3.1 194.2,130.76 ; HGPU3.1 194.2,135.34 ; HGPU3.1 192.53,131.38 ; HGPU3.1 191.91,133.05 ; HGPU3.1 195.87,131.38 ; H6.1 186.13,70.5 ; H6.1 181.93,68.73 ; H6.1 185.47,72.27 ; H6.1 183.7,68.07 ; H6.1 183.7,72.93 ; H6.1 185.47,68.73 ; H6.1 181.93,72.27 ; H6.1 181.27,70.5 ; 12.14,96.31 JHDMI1.8 ; JHDMI1.8 13.06,95.39 ; JHDMI1.8 12.02,95.85 ; JHDMI1.8 13.06,96.31 ; JHDMI1.8 12.14,95.39 ; JHDMI1.8 13.18,95.85 ; 28.32,2.42 H7.1 ; H7.1 32.18,6.58 ; H7.1 32.18,4.5 ; H7.1 28.32,6.58 ; H7.1 28.32,4.5 ; H7.1 30.25,6.58 ; H7.1 32.18,2.42 ; H7.1 30.25,2.42 ; HCPU4.1 113.47,101.98 ; HCPU4.1 111.8,105.94 ; HCPU4.1 111.8,101.36 ; HCPU4.1 110.13,105.32 ; HCPU4.1 110.13,101.98 ; HCPU4.1 113.47,105.32 ; HCPU4.1 114.09,103.65 ; HCPU4.1 109.51,103.65 ; 189.93,151.13 H12.1 ; H12.1 189.51,152.3 ; H12.1 191.1,150.71 ; H12.1 191.1,153.89 ; H12.1 192.27,153.47 ; H12.1 192.69,152.3 ; H12.1 192.27,151.13 ; H12.1 189.93,153.47 ; JUSBC1.5 3.02,125.52 ; JUSBC1.5 3.02,124.69 ; JUSBC1.5 3.02,126.35 ; JUSBC1.5 1.6,126.35 ; JUSBC1.5 1.6,124.69 ; 10.59,100.81 JHDMI1.17 ; JHDMI1.17 10.47,100.35 ; JHDMI1.17 10.59,99.89 ; JHDMI1.17 11.51,99.89 ; JHDMI1.17 11.63,100.35 ; JHDMI1.17 11.51,100.81 ; JLAN1.12 10.65,83.22 ; JLAN1.12 9.47,82.55 ; JLAN1.12 9.47,81.88 ; JLAN1.12 9.47,83.22 ; JLAN1.12 10.65,81.88 ; JHDMI1.21 11.25,104.98 ; JHDMI1.21 9.97,103.22 ; JHDMI1.21 9.97,104.98 ; JHDMI1.21 12.53,104.98 ; JHDMI1.21 12.53,103.22 ; JHDMI1.21 12.53,104.1 ; JHDMI1.21 11.25,103.22 ; H2.1 8.98,112.6 ; H2.1 8.42,114.12 ; H2.1 5.38,114.12 ; H2.1 5.38,111.08 ; H2.1 4.82,112.6 ; H2.1 6.9,110.52 ; H2.1 6.9,114.68 ; H2.1 8.42,111.08 ; H5.1 39.19,130.96 ; H5.1 37.7,134.48 ; H5.1 37.7,130.42 ; H5.1 39.73,132.45 ; H5.1 35.67,132.45 ; H5.1 39.19,133.94 ; H5.1 36.21,133.94 ; H5.1 36.21,130.96 ; JUSB1.4 16.71,49.65 ; JUSB1.4 15.24,50.29 ; JUSB1.4 15.88,48.82 ; JUSB1.4 16.51,49.02 ; JUSB1.4 15.88,50.48 ; JUSB1.4 16.51,50.29 ; 13.74,28.61 JUSB2.7 ; JUSB2.7 15.01,29.88 ; JUSB2.7 14.38,30.08 ; JUSB2.7 14.38,28.42 ; JUSB2.7 15.21,29.25 ; JUSB2.7 13.74,29.88 ; JUSB2.7 13.55,29.25 ; JUSB2.7 15.01,28.61 ; 8.03,39.43 H10.1 ; H10.1 9.8,43.63 ; H10.1 11.57,39.43 ; H10.1 8.03,42.97 ; H10.1 7.37,41.2 ; H10.1 9.8,38.77 ; H10.1 11.57,42.97 ; H10.1 12.23,41.2 ; 110.13,127.92 HCPU2.1 ; HCPU2.1 113.47,127.92 ; HCPU2.1 110.13,124.58 ; HCPU2.1 111.8,128.54 ; HCPU2.1 109.51,126.25 ; HCPU2.1 114.09,126.25 ; HCPU2.1 111.8,123.96 ; HCPU2.1 113.47,124.58 ; JHDMI1.23 4.58,106.63 ; JHDMI1.23 4.58,105.6 ; JHDMI1.23 1.22,106.63 ; JHDMI1.23 2.9,106.63 ; JHDMI1.23 1.22,105.6 ; 11.72,44.42 JUSB1.13 ; JUSB1.13 15.28,46.18 ; JUSB1.13 13.5,44.42 ; JUSB1.13 11.72,45.3 ; JUSB1.13 13.5,46.18 ; JUSB1.13 15.28,45.3 ; JUSB1.13 15.28,44.42 ; 91.27,153 H9.1 ; H9.1 91.93,154.77 ; H9.1 95.47,151.23 ; H9.1 95.47,154.77 ; H9.1 93.7,150.57 ; H9.1 91.93,151.23 ; H9.1 93.7,155.43 ; H9.1 96.13,153 ; 4.88,37.98 JUSB2.11 ; JUSB2.11 7.92,37.1 ; JUSB2.11 6.4,37.98 ; JUSB2.11 4.88,37.1 ; JUSB2.11 7.92,37.98 ; JLAN1.11 4.03,81.88 ; JLAN1.11 1.67,83.22 ; JLAN1.11 2.85,81.88 ; JLAN1.11 1.67,81.88 ; JLAN1.11 2.85,83.22 ; JLAN1.11 1.67,82.55 ; JLAN1.11 4.03,82.55 ; JLAN1.11 4.03,83.22 ; H4.1 9.83,85.8 ; H4.1 7.9,83.87 ; H4.1 6.48,87.22 ; H4.1 6.48,84.38 ; H4.1 7.9,87.73 ; H4.1 9.32,84.38 ; H4.1 5.97,85.8 ; H4.1 9.32,87.22 ; HCPU1.1 54.67,124.58 ; HCPU1.1 53,128.54 ; HCPU1.1 54.67,127.92 ; HCPU1.1 53,123.96 ; HCPU1.1 51.33,124.58 ; HCPU1.1 51.33,127.92 ; HCPU1.1 50.71,126.25 ; HCPU1.1 55.29,126.25 ; 50.71,103.65 HCPU3.1 ; HCPU3.1 54.67,101.98 ; HCPU3.1 55.29,103.65 ; HCPU3.1 53,105.94 ; HCPU3.1 54.67,105.32 ; HCPU3.1 51.33,105.32 ; HCPU3.1 51.33,101.98 ; HCPU3.1 53,101.36 ; JHDMI1.11 11.63,97.35 ; JHDMI1.11 10.59,96.89 ; JHDMI1.11 10.47,97.35 ; JHDMI1.11 11.51,96.89 ; JHDMI1.11 11.51,97.81 ; JHDMI1.11 10.59,97.81 ; 4.88,21.4 JUSB2.12 ; JUSB2.12 7.92,20.52 ; JUSB2.12 6.4,20.52 ; JUSB2.12 4.88,20.52 ; JUSB2.12 7.92,21.4 ; 9.47,65.08 JLAN1.9 ; JLAN1.9 9.47,65.75 ; JLAN1.9 10.65,66.42 ; JLAN1.9 10.65,65.08 ; JLAN1.9 9.47,66.42 ; JLAN1.9 11.83,65.75 ; JLAN1.9 11.83,65.08 ; 4.88,45.3 JUSB1.12 ; JUSB1.12 7.92,44.42 ; JUSB1.12 6.4,44.42 ; JUSB1.12 7.92,45.3 ; JUSB1.12 4.88,44.42 ; JUSB1.7 14.38,53.98 ; JUSB1.7 15.21,53.15 ; JUSB1.7 15.01,53.79 ; JUSB1.7 13.55,53.15 ; JUSB1.7 13.74,52.52 ; JUSB1.7 14.38,52.32 ; JUSB1.7 15.01,52.52 ; JUSB1.7 13.74,53.79 ; 5.42,125.52 JUSBC1.1 ; JUSBC1.1 6.65,126.35 ; JUSBC1.1 7.88,124.69 ; JUSBC1.1 5.42,124.69 ; JUSBC1.1 5.42,126.35 ; JUSBC1.1 7.88,126.35 ; JUSBC1.1 7.88,125.52 ; 13.5,20.52 JUSB2.13 ; JUSB2.13 15.28,21.4 ; JUSB2.13 11.72,20.52 ; JUSB2.13 13.5,22.28 ; JUSB2.13 15.28,20.52 ; JUSB2.13 15.28,22.28 ; JUSB2.13 11.72,21.4 ; H1.1 8.52,128.83 ; H1.1 5.18,132.17 ; H1.1 6.85,132.79 ; H1.1 8.52,132.17 ; H1.1 4.56,130.5 ; H1.1 9.14,130.5 ; H1.1 5.18,128.83 ; H1.1 6.85,128.21 ; 12.02,92.85 JHDMI1.2 ; JHDMI1.2 13.06,92.39 ; JHDMI1.2 13.06,93.31 ; JHDMI1.2 12.14,92.39 ; JHDMI1.2 12.6,92.27 ; JHDMI1.2 13.18,92.85 ; JHDMI1.2 12.14,93.31 ; 194.68,40.23 H8.1 ; H8.1 196.45,44.43 ; H8.1 196.45,39.57 ; H8.1 198.22,43.77 ; H8.1 198.22,40.23 ; H8.1 194.02,42 ; H8.1 198.88,42 ; H8.1 194.68,43.77 ; JUSB2.10 15.28,37.1 ; JUSB2.10 13.5,36.22 ; JUSB2.10 15.28,37.98 ; JUSB2.10 11.72,37.98 ; JUSB2.10 13.5,37.98 ; JUSB2.10 15.28,36.22 ; JUSB2.10 11.72,37.1 ; JUSBC1.4 7.88,116.88 ; JUSBC1.4 5.42,116.88 ; JUSBC1.4 5.42,116.05 ; JUSBC1.4 7.88,117.71 ; JUSBC1.4 7.88,116.05 ; JUSBC1.4 6.65,116.05 ; 4.88,61.88 JUSB1.11 ; JUSB1.11 7.92,61.88 ; JUSB1.11 7.92,61 ; JUSB1.11 4.88,61 ; JUSB1.11 6.4,61.88 ; JHDMI1.22 4.58,88.1 ; JHDMI1.22 4.58,87.07 ; JHDMI1.22 2.9,87.07 ; JHDMI1.22 1.22,88.1 ; JHDMI1.22 1.22,87.07
  BOTTOM w0.127: v1(246.55,59.71) v3(246.55,58.83) ; 200.94,113.1 v3(199.77,113.1) ; v1(267.11,78.45) 267.11,78.91 v3(267.61,79.41) ; 231.67,94.45 231.25,94.87 UV1.D2 ; UV1.B34 232.91,122.26 232.91,122.93 233.12,123.14 233.68,123.14 ; v3(237.3,61.31) 236.86,61.75 v1(236.86,62.26) ; v3(200.13,151.42) CV172.2 ; UH1.A37 163.76,37.8 163.57,37.8 v1(163.34,37.57) ; v3(246.43,73.24) 246.79,72.88 v1(246.79,72.43) ; v1(254.11,75.85) v3(252.92,75.85) ; 198.93,124.83 v3(199.87,124.83) ; v3(31.81,63.83) v1(31.81,62.61) ; v1(186.98,47.87) UH1.BG17
  BOTTOM w0.15: UV1.C25 231.7,115.2 231.7,116.05 ; 231.7,110.22 231.7,110.85 231.5,111.05 231.1,111.05 230.9,111.25 230.9,111.87 ; 232.5,102.72 232.5,103.4 232.35,103.55 231.7,103.55 ; UV1.W28 218.35,116.95 217.48,116.95
  BOTTOM w0.152: UC1.AE34 UC1.AE33 ; v1(176.54,60.64) 176.54,60.5 176.92,60.12 176.92,56.22 176.88,56.18 UH1.AG1 ; v1(177.04,31.78) 176.88,31.94 UH1.AG49 ; UH1.A28 v1(163.89,42.98) ; v1(186.91,42.14) 186.73,42.32 UH1.BG28 ; UH1.C48 165.1,32.53 165.73,32.53 UH1.F47 ; UH1.T49 171.33,31.95 v1(171.65,31.62) ; 174.73,56.11 175.02,55.81 UH1.AD1 UH1.AD2 ; UH1.AA49 173.17,31.83 v1(173.17,31.76) ; UH1.BG25 186.87,44 v1(186.96,44.09) ; DT6.2 12.33,125.39 v1(12.5,125.55) ; DT6.2 v1(11.84,126.02) ; DT6.2 11.3,125.39 v1(11.14,125.55) ; UH1.A33 163.62,40.13 v1(163.28,40.46) ; UH1.R4 170.64,54.19 UH1.R3 ; UH1.D30 165.51,41.63 UH1.C30 ; UH1.A8 163.34,52.29 v1(163.24,52.39) ; v1(179.27,56.5) 179.07,56.31 UH1.AM1 ; UH1.D33 165.63,39.98 UH1.E33 ; UH1.BG33 v1(187.02,40.13) ; UH1.M49 v1(169.1,31.66) ; UH1.BG37 186.78,37.93 v1(187.02,38.17) ; v1(168.08,32.41) UH1.J48 168.08,33.29 UH1.J47 ; UV1.G19 229.65,109.8 ; UH1.BG22 v1(186.98,45.68)
  BOTTOM w0.178: UT1.B16 UT1.A16 18.81,125.64 v1(18.62,125.83) ; UT1.M2 UT1.M1 ; UT1.B12 UT1.A12 19.51,127.42 v1(18.95,127.42) ; UT1.AC8 UT1.AB8 ; UT1.AC6 UT1.AB6 ; UT1.T2 UT1.T1 ; UT1.B18 UT1.A18 18.74,124.72 v1(18.67,124.79) ; v1(30.33,123.45) 29.76,122.88 UT1.AC22 UT1.AB22 ; UT1.AB12 UT1.AC12 30.01,127.48 v1(30.48,127.01) ; UT1.K2 UT1.K1 23.72,132.83 23.94,133.05 v1(23.94,133.4) ; UT1.P2 UT1.P1 v1(25.56,133.05) ; UT1.E22 UT1.E23 21.42,121.99 v1(21.28,121.85) ; UT1.B22 UT1.A22 19.21,122.88 v1(19,122.67) ; UT1.AB2 UT1.AB1 29.24,132.75 v1(29.62,133.14) ; v1(22.21,121.74) 22.34,121.87 UT1.G23 UT1.G22 ; UT1.AC16 UT1.AB16 ; v1(24.18,121.82) UT1.L23 UT1.L22 ; UT1.H1 UT1.H2 22.8,132.08 ; UT1.C22 UT1.C23 20.5,122.33 v1(20.05,121.88) ; UT1.R22 UT1.R23 26.02,121.88 v1(26.11,121.79) ; v1(18.98,123.8) UT1.A20 UT1.B20 ; UT1.AC10 UT1.AB10 ; UT1.AB18 UT1.AC18 30.12,124.72 v1(30.21,124.63) ; UT1.N23 UT1.N22 ; v1(19.07,126.76) 19.27,126.56 UT1.A14 UT1.B14 ; v1(29.34,121.92) 29.06,121.92 28.78,122.2 UT1.AA23 ; UT1.U23 UT1.U22 ; UT1.B6 UT1.A6 ; UT1.AC14 UT1.AB14 ; v1(19.12,128.66) 19.38,128.4 UT1.A10 ; UV1.E22 UV1.G22 ; UT1.AB20 29.34,123.69 29.59,123.69 UT1.AC20 ; v1(23.2,121.82) 23.26,121.88 UT1.J23 UT1.J22 ; UT1.W23 UT1.W22
  BOTTOM w0.203: v1(81.61,125.79) 81.93,126.11 UC1.AJ37 UC1.AJ38 ; UC1.K11 v1(97.64,106.31) ; v1(97.64,106.31) 97.9,106.15 98.06,106.04 UC1.J10 ; v1(97.64,106.31) UC1.K10 v1(96.83,105.68) UC1.K9 97.29,105.29 97.29,104.75 UC1.K8 v1(97.64,104.34) ; UH1.BE44 185.56,34.81 185.3,34.55 v1(185.24,34.55) 185.07,34.72 UH1.BD43 ; UH1.J4 167.95,54.06 v1(167.67,53.78) ; UC1.AC6 v1(86.76,103.78) 86.64,103.86 UC1.AD7 UC1.AD8 v1(85.89,105.02) 86.18,105.23 UC1.AD9 UC1.AD10 ; UC1.AC6 UC1.AC5 UC1.AC4 86.64,101.8 v1(86.62,101.79) 86.64,101.77 UC1.AC3 UC1.AC2 UC1.AC1 86.96,100.03 86.96,95.22 v1(87.22,94.97) ; UC1.AC6 UC1.AB6 UC1.Y7 UC1.Y8 v1(89.54,105.07) UC1.Y9 UC1.Y10 v1(89.54,106.37) UC1.Y11 ; UH1.AC46 174.58,33.94 v1(174.21,34.31) ; UT1.B16 20.21,125.64 v1(20.43,125.86) 20.74,126.17 UT1.D15 ; UC1.C25 101.41,117.98 UC1.D26 ; UH1.G44 167,35.14 166.43,35.71 UH1.F41 166.43,36.21 v1(166.21,36.43) 165.81,36.83 UH1.E40 ; UC1.D12 101.41,106.95 UC1.C11 101.41,106.75 v1(101.74,106.42) ; UC1.AG8 UC1.AG7 v1(84.08,103.75) UC1.AG6 UC1.AH6 UC1.AJ6 UC1.AJ5 UC1.AJ4 ; UC1.D14 101.41,108.53 UC1.C13 101.41,108.32 v1(101.74,108) ; UH1.R29 170.91,41.65 v1(170.74,41.48) ; v1(174.02,57.69) 174.02,56.82 174.73,56.11 ; UH1.AT1 181.3,56.3 v1(181.45,56.45) ; UC1.BM5 64.58,102.65 v1(64.82,102.21) 64.65,101.87 UC1.BM3 UC1.BM2 UC1.BN2 ; UC1.BM5 64.5,102.66 UC1.BN4 v1(63.58,102.07) 63.32,102.07 63.15,101.9 62.6,101.9 62.35,102.15 UC1.BT4 ; UC1.BM5 64.48,102.76 UC1.BM6 64.57,103.39 UC1.BL6 ; UC1.BT8 61.46,104.78 v1(61.01,105.23) ; 22.38,123.27 22.34,123.22 UT1.G22 ; UC1.N10 v1(95.03,106.33) UC1.N11 v1(95.03,106.98) ; UC1.AU33 75.77,123.51 v1(76.09,123.18) ; UC1.G5 98.7,102.74 98.37,102.41 98.29,102.41 UC1.J4 ; UC1.G5 98.81,102.78 98.81,103.34 UC1.G6 v1(98.81,103.92) UC1.G8 ; UC1.G5 99.3,102.74 UC1.F5 ; UC1.H25 98.07,117.84 98.03,117.88 97.5,117.88 UC1.J25 ; UC1.AR5 77,102.72 v1(76.57,102.37) 77,102.09 UC1.AR4 UC1.AR3 UC1.AR2 UC1.AR1 77.01,99.97 76.27,99.23 76.27,98.66 76.53,98.4 v1(76.71,98.4) ; v1(171.46,53.4) 171.46,53.8 UH1.T5 171.18,54.07 UH1.T4 ; UC1.AL10 v1(81.31,105.67) UC1.AL9 ; UC1.BR21 62.68,114.4 62.15,114.4 UC1.BT21 61.62,114.46 v1(61.52,114.36) ; UH1.K11 168.22,51 v1(168.66,50.57) ; UT1.AA22 28.78,123.25 28.74,123.28 ; DT2.2 9.61,117.15 v1(9.37,116.92) ; DT2.2 10.2,117.15 v1(10.43,116.92) ; DT2.2 v1(9.92,116.51) ; UC1.BH12 v1(67.59,107.01) UC1.BG12 ; UC1.AM5 UC1.AM4 79.56,102.05 79.56,101.47 UC1.AM3 UC1.AM2 UC1.AM1 79.53,99.66 v1(79.67,99.52) ; v1(41.12,53.57) 41.12,53.38 41,53.25 41,52.24 41.46,51.77 42.6,51.77 43.16,52.33 43.16,57.95 42.75,58.35 42.75,59.52 41.25,61.02 41.25,65.42 40.51,66.16 40.51,83.76 42.1,85.35 45.22,85.35 49.86,89.99 49.86,98.22 49.33,98.75 49.33,101.33 48.68,101.98 46.56,101.98 45.05,103.48 42.93,103.48 v1(41.47,102.02) ; v1(66.51,103.06) UC1.BK6 UC1.BL6 ; v1(66.51,103.06) UC1.BH5 UC1.BH4 UC1.BH3 ; v1(66.51,103.06) UC1.BH6 ; UC1.D22 100.76,115.34 UC1.C21 101.76,115.04 v1(101.76,115.08) ; UC1.BM27 64.41,119.46 v1(64.41,119.59) 64.69,119.87 UC1.BM28 UC1.BM29 ; UH1.AG22 176.66,45.55 v1(176.37,45.83) 176.09,45.55 UH1.AF22 v1(175.59,45.94) UH1.AD22 ; UH1.AD19 v1(174.81,47.49) UH1.AB19 ; v1(169.75,33.83) 169.86,33.94 UH1.P46 ; UC1.F31 99.16,122.86 UC1.H32 ; UH1.W28 172.88,42.48 v1(173.27,42.87) 173.65,42.49 UH1.AA28 ; UC1.F15 v1(99.81,109.55) ; UC1.F15 v1(99.11,109.54) UC1.G14 ; UC1.F15 v1(99.16,110.33) UC1.G16 ; UC1.BN12 63.99,107.32 63.44,107.32 UC1.BP12 UC1.BR12 UC1.BT12 61.12,107.37 v1(60.95,107.21) ; v1(71.56,103.06) 71.57,103.01 71.57,102.61 71.62,102.56 71.62,101.91 71.98,101.55 UC1.BB3 UC1.BB2 UC1.BB1 ; v1(71.56,103.06) UC1.BB6 UC1.BA7 ; v1(71.56,103.06) UC1.BC6 UC1.BD6 v1(69.86,103.06) ; v1(71.56,103.06) UC1.BB5 UC1.BB4 ; UC1.AR38 77.35,126.76 v1(77.67,127.08) ; v1(103.4,116.78) 103.13,117.05 UC1.A24 ; UT1.E22 21.42,122.98 21.78,123.35 ; UC1.A20 102.39,114.23 v1(102.39,114.3) ; UC1.AH33 82.86,123.51 v1(83.18,123.83) 82.85,124.16 UC1.AH34 ; UC1.D3 UC1.E4 100.06,102.01 99.53,102.01 UC1.F4 ; v1(63.06,123.51) UC1.BP33 63.39,122.98 UC1.BN31 v1(63.78,121.94) UC1.BN30 ; v1(63.06,123.51) UC1.BR34 ; v1(63.06,123.51) UC1.BP34 ; UC1.G8 98.75,104.39 98.46,104.39 UC1.J7 v1(97.64,104.34) ; UC1.G8 UC1.F8 v1(99.79,104.85) ; UC1.AM38 79.7,126.76 v1(80.03,126.43) 79.71,126.11 UC1.AM37 ; v1(9.78,119.23) 9.92,119.09 DT3.2 ; UC1.BN34 v1(64.36,123.51) UC1.BM33 ; v1(103.42,109.3) 103.3,109.18 UC1.A14 ; UH1.AT26 181.03,43.09 v1(180.86,42.92) ; UC1.F9 99.47,105.23 v1(99.79,104.85) ; UC1.AD12 86.64,107.11 v1(86.79,107.01) UC1.AD11 86.64,106.47 v1(86.8,106.37) 86.64,106.24 UC1.AD10 ; UC1.BE6 69.88,103.8 UC1.BD7 UC1.BD8 v1(70.34,105.1) 70.09,105.23 UC1.BD9 v1(70.34,105.74) UC1.BD10 v1(70.34,106.37) UC1.BD11 v1(70.35,106.96) ; UC1.BE6 v1(69.86,103.06) ; UC1.BE6 UC1.BF6 UC1.BG6 UC1.BH6 ; UH1.U17 171.62,47.81 UH1.T17 UH1.T18 171.52,47.02 v1(171.81,46.73) ; UC1.BM38 64.83,126.77 v1(65.19,127.14) 65.54,126.8 UC1.BL38 ; UV6.J10 231.77,144.05 231.61,143.89 ; UC1.AJ4 UC1.AJ3 v1(81.6,101.11) UC1.AJ2 v1(81.61,100.47) UC1.AJ1 ; UC1.AJ4 UC1.AK4 81.02,101.95 80.55,101.95 UC1.AL4 ; UC1.T13 UC1.T12 ; UC1.T12 91.66,107.46 91.08,107.46 UC1.V12 ; UC1.T12 v1(92.28,107.01) UC1.R12 93,107.56 93.39,107.56 93.65,107.3 UC1.P12 93.87,107.51 94.35,107.51 UC1.N12 v1(95.03,106.98) ; UC1.T12 UC1.T11 v1(92.29,106.37) UC1.T10 v1(92.29,105.74) UC1.T9 UC1.T8 UC1.T7 91.26,103.48 UC1.U6 91.2,103.32 90.49,103.32 UC1.V6 89.77,102.74 UC1.W5 UC1.W4 UC1.W3 v1(89.14,101.13) UC1.W2 UC1.W1 89.58,99.65 v1(89.14,99.2) ; UC1.T3 UC1.T4 UC1.T5 ; UC1.T3 92.1,101.33 92.11,101.31 92.11,100.94 92.1,100.92 UC1.T2 UC1.T1 91.72,99.8 v1(91.71,99.79) ; UC1.T3 v1(91.66,101.12) ; UC1.BA7 UC1.BA6 ; UC1.BA7 UC1.BA8 v1(73.08,105.1) 72.84,105.23 UC1.BA9 v1(73.08,105.74) UC1.BA10 v1(73.08,106.37) UC1.BA11 v1(73.07,107) ; UC1.D20 100.76,113.64 101.29,113.11 UC1.C19 101.53,113.11 101.72,113.3 v1(101.72,113.48) ; v1(267.19,66.51) 266.52,67.17 PUW01.10 ; UC1.BJ32 v1(65.86,122.54) ; 25.12,123.26 25.1,123.23 UT1.N22 ; UH1.J46 168.03,33.97 v1(168.47,34.41) ; UC1.A22 v1(103.35,115.48) ; v1(66.52,101.1) 66.55,101.1 UC1.BH3 ; v1(30.05,133.55) 30.16,133.43 30.16,133.06 29.7,132.6 UT1.AC1 UT1.AC2 ; UC1.N34 94.52,124.16 v1(94.19,123.83) 94.51,123.51 UC1.N33 ; UC1.BL35 65.27,124.81 v1(65.03,125.05) 65.03,125.04 UC1.BM35 ; UC1.BL33 v1(65.86,123.84) UC1.BJ33 ; DT7.2 12.08,123.91 v1(12.34,123.65) ; DT7.2 v1(11.84,123.32) ; DT7.2 11.79,123.86 11.25,123.86 v1(11.14,123.75) ; v1(67.22,115.25) UC1.BJ22 66.58,115.19 66.05,115.19 UC1.BK22 ; v1(99.79,104.85) 100.11,105.23 UC1.E9 ; UT1.W22 27.86,123.25 ; UC1.BL6 UC1.BM7 ; v1(103.45,105.97) 103.4,106.02 102.72,106.02 UC1.A10 ; UH1.J10 167.59,51.37 167.59,51.79 UH1.J9 ; v1(183.89,48.94) 183.99,48.84 184.62,48.84 UH1.BC15 ; UC1.BM23 64.69,116.08 v1(64.34,116.43) 64.04,116.73 UC1.BN24 ; UC1.N1 UC1.N2 UC1.N3 v1(94.19,101.75) UC1.N4 UC1.N5 UC1.N6 ; v1(35.01,43.45) 35.24,43.22 PUM01.14 ; UC1.BR36 62.63,125.45 UC1.BT36 61.67,125.87 v1(61.5,125.87) ; v1(69.86,103.06) UC1.BE5 UC1.BE4 UC1.BE3 ; UC1.BM7 UC1.BN7 v1(63.71,104.63) UC1.BP7 UC1.BR7 ; UC1.BM7 64.61,104.3 64.61,104.94 UC1.BM8 64.5,105.23 v1(64.35,105.4) UC1.BM9 ; UH1.BB41 184.23,36.23 184.61,36.23 v1(184.75,36.37) 184.81,36.43 184.81,36.78 UH1.BC40 ; v1(102.33,111.15) 102.34,111.15 102.41,111.09 102.41,111.06 UC1.A16 ; UH1.AD49 174.75,32.19 v1(174.69,32.24) ; UC1.A26 v1(103.09,118.25) ; UC1.N6 94.61,104 UC1.N7 UC1.N8 95.01,105.14 v1(95.01,105.65) UC1.N9 ; UC1.N6 UC1.M6 ; v1(179.5,32.18) 179.5,32.19 UH1.AM49 ; UC1.BH3 66.99,101.4 66.99,100.82 UC1.BH2 66.7,100.53 UC1.BH1 66.7,99.7 v1(66.61,99.62) ; JKB.30 151.6,35.48 151.3,35.78 150.49,35.78 150.19,36.08 v1(150.19,36.45) ; v1(184.35,39.36) 184.43,39.36 UH1.BC35 ; DT3.2 10.37,119.08 v1(10.37,119.26) ; DT3.2 9.55,118.62 v1(9.38,118.79) ; UH1.E10 165.64,51.08 166.04,50.68 v1(166.04,50.53) ; UH1.AT21 181.49,45.63 v1(181.52,45.63) ; v1(97.59,102.43) 97.28,102.74 UC1.K5 ; v1(97.59,102.43) 97.62,102.43 UC1.J4 ; v1(97.59,102.43) 97.49,102.43 97.18,102.12 97.16,102.12 UC1.K4 UC1.K3 97.04,101.35 97.04,100.87 UC1.K2 v1(97.54,100.44) UC1.K1 ; UC1.BP25 63.06,117.28 v1(63.06,117.22) 63.06,117.15 UC1.BP24 ; v1(30.55,91.83) 30.55,91.61 31.05,91.11 UT4.A1 ; v1(169.97,42.92) 170.14,43.09 UH1.P26 ; v1(97.64,104.34) UC1.K7 ; UC1.BH6 UC1.BH7 v1(67.59,104.37) UC1.BH8 v1(67.59,105.02) 67.3,105.23 UC1.BH9 UC1.BH10 v1(67.6,106.37) UC1.BH11 ; UH1.P4 169.93,54.06 169.84,53.97 v1(169.84,53.68) 169.38,53.68 UH1.M5 ; v1(102.41,112.72) 102.41,112.63 UC1.A18 ; UC1.T33 v1(92.63,123.83) 92.3,124.16 UC1.T34 ; UC1.AU6 74.68,102.74 UC1.AW5 UC1.AW4 UC1.AW3 UC1.AW2 v1(74.05,100.46) UC1.AW1 ; UC1.AU6 UC1.AT6 ; UC1.AU6 v1(74.89,103.73) UC1.AU7 UC1.AU8 75.76,104.95 v1(75.89,105.03) 75.76,105.11 UC1.AU9 v1(75.82,105.74) UC1.AU10 v1(75.83,106.34) UC1.AU11 ; v1(82.35,125.13) 82.67,124.81 UC1.AH35 ; CT156.1 34.81,71.61 v1(34.6,71.41) ; UC1.F25 99.83,117.47 v1(99.83,117.45) ; UT1.E4 21.05,131.71 20.59,131.71 20.36,131.48 20.36,131.11 UT1.D5 ; v1(170.44,53.65) 170.73,53.94 UH1.R4 ; v1(76.09,124.48) 75.77,124.16 UC1.AU34 ; UC1.AB34 v1(87.91,123.83) UC1.AB33 ; UC1.J4 98.06,102.01 98.38,101.75 UC1.G4 UC1.F4 ; UC1.AL34 80.36,124.16 v1(80.03,123.83) 80.35,123.51 UC1.AL33 ; UH1.AN38 v1(180.1,37.56) UH1.AR38 ; UC1.A28 v1(103.07,119.84) ; UC1.AD10 86.64,105.82 v1(86.8,105.72) ; v1(94.15,103.74) 93.8,103.39 UC1.P6 ; v1(68.22,125.78) 67.89,126.11 UC1.BG37 ; UC1.BD38 70.25,126.76 v1(70.58,126.43) 70.26,126.11 UC1.BD37 ; UH1.AT24 181.03,44.25 v1(181.19,44.08) ; UC1.AY33 73.41,123.51 v1(73.73,123.83) 73.4,124.16 UC1.AY34 ; UT1.J20 23.26,123.5 UT1.J22 ; UC1.G12 v1(98.49,107.21) ; v1(98.49,107.21) UC1.H12 ; v1(98.49,107.21) UC1.H11 ; UC1.F4 99.45,101.77 99.55,101.67 UC1.F3 ; PUM01.1 38.34,43.62 37.97,43.25 v1(37.97,42.82) ; UG12.11 v1(195.66,123.9) ; UC1.Y37 v1(89.48,126.43) UC1.Y38 ; UC1.U38 v1(91.84,126.43) UC1.U37 ; UC1.BJ18 UC1.BK18 ; UC1.BR29 UC1.BP29 UC1.BN29 UC1.BM29 ; UC1.D18 101.41,111.68 UC1.C17 101.41,111.47 v1(101.74,111.15) ; v1(184.59,44.08) 184.76,44.25 UH1.BC24 ; UC1.BC34 71.05,124.16 v1(71.37,124.48) ; UC1.BE3 UC1.BE2 UC1.BE1 69.47,99.67 v1(69.01,99.21) ; UC1.BE3 v1(68.97,101.11) ; UC1.AF4 UC1.AF3 v1(84.14,101.11) UC1.AF2 UC1.AF1 v1(84.55,99.59) ; v1(165.5,51.88) 165.39,52 UH1.D8 165.63,52.41 UH1.E8 ; UC1.J18 UC1.H18 98.21,112.23 98.72,112.23 UC1.G18 99.14,112 v1(99.14,111.93) 99.46,111.61 UC1.F17 99.8,111.2 v1(99.8,111.11) ; UH1.D30 165.75,41.73 166.06,42.04 v1(166.62,42.04) ; UH1.F43 165.84,35.77 UH1.E42 165.84,36.06 v1(165.52,36.38) ; v1(95.78,121.89) 95.83,121.89 96.17,121.54 UC1.L30 UC1.L29 ; UH1.AN12 179.68,50.57 v1(180.1,50.57) 180.52,50.57 UH1.AR12 ; UC1.BK15 v1(65.62,109.35) UC1.BK14 ; UC1.BR38 62.42,127.02 v1(62.42,127.24) ; v1(95.03,106.98) 95.47,107.29 UC1.M12 UC1.M13 UC1.M14 ; UC1.AN12 79.02,107.3 v1(78.56,107) 78.11,106.65 UC1.AP11 v1(78.57,106.37) UC1.AP10 v1(78.56,105.74) UC1.AP9 78.32,105.23 v1(78.56,105.1) UC1.AP8 78.54,104.26 78.54,103.53 UC1.AN6 78.64,103.34 UC1.AN5 ; v1(61.06,103.08) 61.18,102.95 UC1.BT5 ; v1(101.74,104.85) UC1.C8 ; v1(101.74,104.85) 101.96,105.12 UC1.B9 102.15,105.32 102.63,105.32 UC1.A9 ; v1(101.74,104.85) 101.42,105.23 UC1.C9 ; v1(30.25,124.02) 30.02,123.8 UT1.AC20 ; UC1.BJ34 v1(65.86,124.49) UC1.BJ35 UC1.BJ36 ; UC1.F11 v1(99.79,106.42) ; UH1.AK20 177.96,46.66 v1(177.91,46.66) 177.86,46.66 UH1.AJ20 ; UC1.W33 v1(90.27,123.18) ; UH1.AJ19 177.52,47.38 v1(177.91,47.77) 178.3,47.39 UH1.AK19 ; v1(176.36,45.16) UH1.AG23 ; UH1.E35 165.91,39.3 v1(166.01,39.3) ; v1(101.71,116.66) 101.71,116.56 UC1.C23 101.1,116.57 101.1,116.71 UC1.D24 ; 234.1,112.72 233.3,112.72 ; v1(101.74,109.57) 101.41,109.9 UC1.C15 101.41,110.1 UC1.D16 ; UC1.BM18 UC1.BN18 63.92,111.98 63.51,111.98 UC1.BP18 63.26,111.97 62.86,111.97 UC1.BR18 62.71,112.08 62.11,112.08 UC1.BT18 61.79,112.1 v1(61.56,112.33) ; v1(103.28,125.79) 102.46,125.79 102.21,126.04 UC1.B37 102.01,126.04 UC1.C37 ; UT1.D13 20.47,126.56 UT1.B14 ; v1(70.35,106.96) UC1.BD12 ; v1(70.35,106.96) 70.42,106.96 70.76,107.3 UC1.BC12 UC1.BC13 UC1.BC14 ; UC1.BM22 64.69,115.18 v1(65.01,114.85) 65.34,114.53 UC1.BL21 ; v1(103.46,107.64) 103.4,107.64 103.37,107.6 UC1.A12 ; UC1.AC38 v1(87.12,127.08) ; UH1.AP46 180.17,34.06 179.89,34.34 179.29,34.34 179.07,34.57 v1(178.86,34.57) 178.86,34.47 178.33,33.94 UH1.AK46 ; UC1.W34 89.94,124.16 v1(90.28,123.82) ; UC1.AL7 80.88,104.04 v1(81.32,104.36) UC1.AL8 ; UC1.BG38 v1(68.22,127.08) ; UC1.BJ14 UC1.BH14 v1(67.58,108.28) 67.63,108.28 UC1.BG14 68.11,108.54 68.11,108 UC1.BG13 ; UT1.AB8 28.94,129.32 ; UH1.V20 v1(172.43,45.99) 172.1,45.66 UH1.V22 ; 24.2,123.29 24.18,123.26 UT1.L22 ; UC1.BF34 68.68,124.16 v1(69.01,123.83) 68.69,123.51 UC1.BF33 ; UH1.AT18 v1(181.12,46.77) ; UC1.AP34 78.13,124.16 v1(78.46,123.83) 78.13,123.51 UC1.AP33 ; UT1.B10 UT1.A10 ; UH1.E33 165.84,40.59 v1(165.76,40.67) ; UC1.BJ12 66.31,107.34 v1(66.68,106.97) ; UC1.BC33 71.04,123.51 v1(71.37,123.18) ; UC1.AC37 v1(87.12,125.78) ; UH1.BC31 v1(184.76,40.72) ; UC1.AP12 v1(77.65,106.96) ; UT4.L1 36.05,91.01 v1(36.38,91.34) ; UC1.BM29 UC1.BL29 65.77,120.76 UC1.BK29 66.39,121.37 UC1.BJ30 v1(65.86,121.89) UC1.BJ31 ; UT1.R22 26.02,123.03 v1(26.25,123.26) ; UT1.T1 26.48,132.8 v1(26.3,132.98) ; UC1.G20 99.14,113.58 v1(99.14,113.51) ; UT1.D18 20.58,124.72 UT1.B18 ; v1(24.52,133.25) 24.52,132.93 24.64,132.81 UT1.M1 ; UC1.BR9 v1(63.08,106.21) ; UC1.BR14 62.74,108.93 v1(63.08,108.58) 63.08,108.62 63.39,108.93 UC1.BP14 63.41,108.92 64.01,108.92 UC1.BN14 ; UC1.AV37 74.99,126.11 v1(75.31,126.43) 74.98,126.76 UC1.AV38 ; UC1.AD6 v1(85.81,103.05) UC1.AE6 ; UH1.AT29 v1(180.65,41.54) ; UC1.A30 103.01,121.68 v1(103.01,121.41) ; UH1.V46 171.92,33.94 v1(171.86,33.89) ; UT1.AB10 28.91,128.4 ; v1(100.42,114.27) 100.41,114.28 v1(99.76,114.28) 99.46,114.58 UC1.F21 98.81,115.34 UC1.G22 98.78,115.44 98.15,115.44 UC1.H22 UC1.J22 ; UC1.L33 96.25,123.51 v1(96.57,123.83) 96.24,124.16 UC1.L34 ; UC1.AE33 v1(85.54,123.18) ; UH1.AK4 v1(178.48,54.06)
  BOTTOM w0.25: 234.86,120.88 234.85,120.87 234.85,120.82 234.15,120.12 234.15,120.05 ; 223.32,123.25 223.53,123.25 223.87,122.91 223.87,122.87 224.09,122.65 224.17,122.65 223.75,122.22 223.75,122.07 223.72,122.04 223.72,121.66 223.75,121.63 UV1.N33 ; 230,122.65 230.34,122.99 230.34,122.99 230.8,123.44 230.8,123.45 ; 209.1,118.55 209.15,118.6 209.9,118.6 209.92,118.62
  BOTTOM w0.254: UC1.AJ13 82.22,107.63 v1(82.22,106.97) 82.43,107.18 82.43,107.3 UC1.AH12 ; CH209.2 183.89,59.72 RH673.1 ; v1(63.06,118.77) 63.39,118.44 UC1.BP26 ; UC1.BT24 62.09,116.91 v1(62.41,117.24) UC1.BR25 ; UC1.D3 100.89,101.29 UC1.C2 102.02,101.5 UC1.B3 UC1.A3 UC1.A4 ; v1(176.34,42) 176.66,41.68 UH1.AG30 176.8,41.68 v1(177.11,41.99) ; UV1.AH16 210.87,106.97 210.65,106.97 ; 230.04,115.04 230.07,115.04 230.18,114.93 230.37,114.93 UV1.E25 230.5,114.82 230.9,115.22 ; v1(29.8,97.63) 29.95,97.78 JWLAN1.7 ; UC1.BK14 UC1.BK13 65.86,108.16 UC1.BL13 UC1.BM13 ; UH1.K11 167.83,51.08 167.69,51.22 UH1.J10 ; 26.92,123.28 26.94,123.26 UT1.U22 ; v1(97.4,125.14) 97.72,125.46 UC1.J36 ; UV1.AL32 208.72,120.65 208.32,121.05 208.35,121.05 UV1.AL33 ; UH1.AW4 182.37,54.01 v1(182.67,53.71) ; UC1.H35 98.6,124.81 v1(98.93,125.14) ; UC1.BL22 65.34,115.18 v1(65.01,114.85) ; UC1.BR26 62.65,118.31 62.17,118.31 UC1.BT26 61.95,118.4 v1(61.69,118.14) ; 228.4,116.95 UV1.G28 229.22,117.77 229.65,117.35 UV1.F28 ; UC1.BA37 v1(72.95,126.44) UC1.BA38 ; UC1.BR24 62.74,116.89 v1(63.06,117.22) ; UH1.AT45 181.2,34.52 v1(181.49,34.81) ; UC1.F19 v1(99.8,113.51) ; v1(86.79,107.01) 87.08,107.3 UC1.AC12 87.4,107.45 88.01,107.45 UC1.AA12 ; UH1.AH38 177.78,37.6 v1(177.8,37.58) UH1.AL38 ; UH1.AJ27 177.52,43.28 v1(177.93,43.69) ; UH1.AJ27 v1(177.92,42.83) ; UH1.AJ27 v1(177.14,42.84) ; UH1.AL33 178.23,39.64 v1(177.61,39.64) 177.55,39.64 UH1.AH33 177.2,39.96 UH1.AE33 UH1.AC33 173.2,39.96 UH1.Y33 ; UH1.AE38 175.28,37.67 v1(174.9,37.29) ; UV1.AM13 207.9,104.88 208.67,105.65 UV1.AL14 UV1.AL15 ; UC1.AG11 v1(84.06,106.37) UC1.AG10 ; UC1.K38 97.49,127.29 v1(97.66,127.29) ; UH1.AN34 180.07,39.18 v1(180.07,39.1) ; UH1.BC10 184.42,50.83 184.42,50.13 UH1.BC13 184.38,49.82 184.38,49.36 v1(184.4,49.33) ; UH1.AC17 174.54,48.04 174.19,47.68 v1(173.94,47.68) 173.56,47.68 173.21,48.03 UH1.Y17 ; UC1.BF12 69.07,107.4 69.77,107.4 UC1.BD12 ; UC1.AH36 82.73,125.46 v1(82.41,125.77) ; UH1.AE12 176.42,50.33 v1(176.45,50.29) 176.57,50.4 UH1.AH12 ; v1(182.58,52.57) 182.58,52.87 182.84,53.13 UH1.BA6 183.39,53.14 UH1.BA5 ; v1(182.71,50.78) UH1.AW10 182.36,51.26 UH1.AV11 ; UC1.A34 103.02,124.29 v1(103.26,124.29) ; UH1.AD25 175.29,44.09 175.89,44.09 UH1.AF25 176.31,44.34 176.31,44.34 v1(176.32,44.34) ; v1(170.74,41.48) 170.24,41.99 UH1.P29 ; v1(180.53,40.21) 180.38,40.06 UH1.AR34 ; UH1.BC26 184.76,43.91 v1(184.59,44.08) ; UV8.M10 258.4,97.83 v1(257.94,98.29) 257.6,97.95 UV8.L10 ; UC1.F3 99.64,101.44 99.73,101.34 99.73,100.98 99.55,100.8 UC1.F2 ; JFP.4 244.85,33.77 v1(245.35,34.27) JFP.3 ; UC1.D26 100.76,118.71 v1(101.08,119.02) ; UH1.U12 v1(171.51,49.98) 171.05,50.44 UH1.R12 UH1.N12 ; v1(61.09,123.06) UC1.BT32 ; RT69.2 v1(38.47,90.24) ; UV1.T7 221.24,99.75 220.84,99.35 220.84,99.3 ; UC1.BL19 UC1.BL18 UC1.BM18 ; UC1.AF12 84.55,107.3 v1(84.96,106.89) 84.96,107.61 UC1.AF13 ; JEDP1.13 255.9,50.65 257.58,48.97 v1(257.58,48.77) ; v1(183.89,48.94) 183.59,49.24 UH1.BA14 ; JSSD1.21 34.37,32.72 v1(34.53,32.57) ; UH1.AF28 v1(176.36,42.84) UH1.AG28 176.75,42.35 v1(177.11,41.99) ; UH1.Y33 172.91,40.25 v1(172.6,40.25) ; UH1.Y33 172.88,39.67 v1(172.6,39.67) ; 230.07,99.37 UV1.F7 228.85,99.8 UV1.G7 ; UC1.BC12 70.87,107.3 71.14,107.57 71.44,107.57 UC1.BB12 71.83,107.42 72.5,107.42 UC1.BA12 ; UC1.D10 101.15,105.56 ; 101.15,105.56 UC1.D9 ; 101.15,105.56 UC1.C9 ; UC1.C31 101.41,122.63 v1(101.09,122.96) 100.76,123.28 UC1.D33 ; JHDD.4 273.85,40.25 274.12,39.98 274.75,39.98 v1(275.18,40.41) ; UC1.AG13 v1(84.05,108.27) UC1.AF14 ; v1(31.52,32.57) 31.52,32.93 31.37,33.08 JSSD1.33 ; RC274.2 v1(49.81,111.11) ; 209.09,116.05 209.09,116.04 UV1.AL26 ; v1(173.26,43.67) 173.65,43.28 UH1.AA27 v1(174.08,43.66) ; v1(173.26,43.67) 172.88,43.29 UH1.W27 ; v1(173.26,43.67) 172.93,44 UH1.W25 ; v1(177.93,41.98) 177.63,41.68 UH1.AJ30 ; v1(177.93,41.98) 178.3,42.35 UH1.AK28 v1(177.92,42.83) ; v1(177.93,41.98) 178.23,41.68 UH1.AK30 ; v1(177.93,41.98) 177.93,42.05 UH1.AJ28 ; v1(45.78,100.34) 45.78,101.6 44.71,102.67 43.71,102.67 42.42,101.37 v1(42.42,101.12) ; 228.16,94.25 228.16,93.33 227.65,92.83 227.64,92.83 227.51,92.69 v1(227.51,92.01) ; v1(169.26,39.17) UH1.M34 169.28,39.67 UH1.M32 ; UC1.BT29 v1(61.57,120.76) ; v1(154.54,49.03) 154.54,48.34 154.64,48.23 ; v1(35.01,82.67) 35.08,82.73 RT163.2 ; UH1.J29 167.78,42.47 v1(167.85,42.54) UH1.J26 ; UH1.AK30 178.43,41.54 178.43,41.03 UH1.AK31 ; UH1.AK30 178.61,41.99 UH1.AL29 ; 154.64,48.23 153.67,48.23 153.33,48.58 153.33,51.04 152.5,51.87 152.5,53.01 v1(152.82,53.33) 152.74,53.33 152.34,53.73 152.34,54.55 152.73,54.94 157.1,54.94 157.27,54.77 157.27,51.45 156.92,51.1 CH47.2 156.61,50.34 155.7,49.43 155.7,48.46 155.47,48.23 154.64,48.23 ; JSSD1.27 32.87,35.31 v1(32.41,35.77) ; UC1.Y13 UC1.Y14 v1(88.62,109.19) ; v1(65.62,109.35) 65.62,109.23 UC1.BL14 65.21,108.82 64.82,108.82 UC1.BM14 ; v1(39.35,32.81) 39.37,32.84 JSSD1.1 ; UC1.BT3 v1(61.54,101.43) ; UH1.AA31 173.65,40.92 v1(174.03,41.3) UH1.AB31 ; UC1.G10 UC1.F9 UC1.G9 ; UC1.BR14 62.55,109.13 62.29,109.13 62.1,108.95 UC1.BT14 ; 208.33,104.3 208.68,103.95 UV1.AL12 ; v1(61.5,124.98) 61.85,124.63 UC1.BT35 ; PUA01.4 105.99,136.45 v1(105.19,137.25) ; RT62.2 32.85,94.01 v1(32.88,94.03) ; UH1.AC12 173.96,50.33 v1(173.68,50.6) 173.48,50.4 UH1.Y12 ; UH1.AA19 v1(174.09,46.66) ; v1(174.17,53.67) 173.98,53.86 UH1.AA5 173.49,53.75 172.74,53.75 UH1.V4 ; v1(35.72,32.91) 35.87,33.07 JSSD1.15 ; UC1.P37 v1(94.17,126.43) UC1.P38 ; UC1.AU11 UC1.AU12 75.23,107.43 74.64,107.43 UC1.AW12 74,107.74 74,107.76 ; JEDP1.20 255.9,47.15 256.16,46.89 v1(256.16,46.48) ; UH1.E31 165.64,41.04 165.76,40.92 v1(165.76,40.67) ; UV1.AN25 206.53,114.8 ; 212.34,102.76 212.34,102.81 UV1.AG11 ; UH1.AR16 180.38,48.35 v1(179.97,47.94) ; UC1.AY14 74,108.13 74,107.76 ; v1(180.73,47.94) 181.14,48.35 UH1.AT16 ; v1(169,35.59) 169.19,35.78 169.19,36.3 168.57,36.92 UH1.K39 167.87,36.92 UH1.J40 ; UC1.AR35 77.34,124.81 v1(77.67,124.48) 77.35,124.16 UC1.AR34 ; UH1.AL17 178.4,48.13 v1(177.91,48.63) ; UC1.G26 99.12,118.94 v1(99.12,119.05) 99.14,119.05 99.46,119.37 UC1.F27 98.81,120.06 UC1.G28 ; v1(177.92,42.83) 177.53,42.45 UH1.AJ28 ; v1(177.11,41.99) 177.11,42.04 UH1.AJ28 ; v1(177.93,43.69) 177.62,44 UH1.AJ25 177.41,44 v1(177.13,43.73) 176.86,44 UH1.AG25 ; v1(177.93,43.69) 178.3,43.32 UH1.AK27 ; v1(177.93,43.69) 178.24,44 UH1.AK25 ; UH1.BC8 184.14,52.19 UH1.BB9 v1(183.97,51.51) 183.62,51.15 183.62,50.77 UH1.BA12 ; v1(256.13,39.72) 256.06,39.65 JEDP1.35 ; UC1.F36 99.34,125.46 v1(99.67,125.79) ; JESPI1.12 77.3,38.6 76.58,37.88 76.58,37.56 76.89,37.24 v1(76.89,36.73) ; v1(37.85,100.41) 37.95,100.32 JWLAN1.39 ; UC1.AR33 77.34,123.51 v1(77.67,123.18) 77.35,122.86 UC1.AR32 ; v1(64.34,118.78) 64.69,118.43 UC1.BM26 ; JWLAN1.19 32.95,99.75 v1(33.25,100.05) ; v1(254.17,48.65) JEDP1.17 ; JSSD1.39 29.87,34.86 30.09,35.08 v1(30.09,35.69) ; RT24.2 33.01,130.92 33.01,130.34 v1(32.97,130.3) 32.74,130.54 RT18.2 ; v1(174.08,43.66) UH1.AB25 ; v1(174.08,43.66) 173.74,44 UH1.AA25 ; UH1.AJ31 177.63,40.79 178.19,40.79 UH1.AK31 ; 223.3,99.33 223.71,99.75 UV1.N7 ; UC1.AN12 79.14,107.42 79.82,107.42 UC1.AM12 UC1.AL12 ; v1(31.32,100.07) 31.45,99.94 JWLAN1.13 ; UH1.AE46 175.78,33.99 175.08,34.69 v1(175.08,34.92) ; v1(174.02,57.69) 174.02,58.1 174.58,58.67 RH14.1 ; 216.1,98.57 216.25,98.42 UV1.AB5 ; UC1.AR13 v1(76.74,108.27) UC1.AR14 ; UH1.N16 170.02,48.09 v1(170.45,47.66) 170.81,48.01 UH1.R16 ; UC1.J33 97.68,123.51 v1(97.35,123.18) 97.43,123.18 UC1.J32 UC1.H32 ; UC1.BM21 64.69,114.39 65,114.08 65.02,114.08 v1(65.04,114.07) 65.04,113.97 UC1.BL20 ; UV1.N2 223.75,94.9 ; UH1.AA20 173.65,46.29 v1(173.28,45.92) ; UH1.AN16 179.36,48.35 v1(179.08,48.63) ; v1(169.93,40.19) 170.02,40.1 UH1.N34 UH1.R34 ; UH1.AW46 182.47,33.94 v1(182.79,34.26) 183.4,34.87 UH1.BA44 ; UH1.AM18 v1(178.88,47.8) ; UH1.AC38 173.26,37.67 UH1.Y38 v1(172.79,37.99) 172.38,37.58 UH1.U38 ; UC1.BN20 64.04,113.78 v1(64.33,114.07) 64.04,114.36 UC1.BN21 ; v1(192.42,54.35) 192.01,54.35 RH552.2 ; RH580.2 167.32,58.61 RH109.2 168.03,59.01 RH581.2 168.68,58.58 168.96,58.29 v1(168.96,56.74) ; JEDP1.38 256.11,38.15 v1(256.13,38.12) ; JSSD1.3 38.87,32.93 v1(38.76,32.82) ; 229.17,97.65 228.77,98.05 UV1.G5 228.43,98.37 228.43,98.47 ; v1(171.46,53.4) 171.36,53.3 UH1.T7 ; UC1.D38 100.62,127.01 v1(100.26,127.37) 99.82,126.92 UC1.E38 ; UH1.U21 v1(171.62,45.49) 171.62,44.59 UH1.U24 ; JEDP1.32 v1(256.21,41.15) ; UH1.AC4 175.14,54.06 v1(175.3,53.9) 175.62,53.9 UH1.AE4 ; UH1.AL12 v1(177.85,50.42) ; UC1.BJ18 66.64,112.06 v1(67.03,111.66) ; UC1.A6 v1(103.49,103.68) ; UH1.N38 v1(170.25,37.56) UH1.R38 ; v1(63.68,114.08) 63.39,114.37 UC1.BP21 ; v1(246.35,34.24) JFP.1 ; JWLAN1.69 v1(45.45,97.56) ; UH1.AM32 178.46,40.74 UH1.AK31 ; PUM01.3 v1(37.97,42.82) ; UH1.Y9 v1(174.03,51.92) 173.29,51.18 UH1.Y10 ; v1(63.72,112.5) 63.72,112.57 UC1.BN19 ; UC1.C27 101.08,119.75 v1(101.08,119.81) 101.08,119.88 UC1.D28 ; UV1.K2 226.28,95.65 226.47,95.46 226.5,95.46 226.68,95.28 ; 227.1,137.25 UV6.A3 ; UH1.AG27 v1(177.14,42.84) ; v1(177.14,42.84) UH1.AJ28 ; UC1.D30 100.76,121.71 v1(101.09,121.38) 101.41,121.06 UC1.C29 ; UC1.BJ15 66.49,109.59 66.13,109.59 UC1.BK15 ; UH1.BC45 184.37,34.45 v1(184.37,34.84) 184.37,35.24 UH1.BB43 ; JWLAN1.77 48.05,98.88 49.05,97.88 49.05,90.34 44.89,86.19 41.78,86.19 39.69,84.1 39.69,65.82 40.43,65.08 40.43,60.68 41.91,59.21 41.91,58.08 42.34,57.64 42.34,56.43 41.12,55.21 v1(41.12,53.57) ; UV1.AB7 216.25,99.36 216.1,99.21 ; UH1.U17 172.03,48.22 172.03,48.8 UH1.U15 v1(171.51,49.32) ; RP31.2 25.76,88.72 25.18,88.15 24.87,88.15 24.5,87.78 UP1.4 24.5,86.5 24.31,86.31 UP1.9 ; UH1.AL26 v1(178.79,44.03) UH1.AL24 ; UC1.G23 98.81,116.33 v1(99.14,116.66) ; UC1.E35 v1(99.78,124.48) 100.11,124.14 UC1.E34 ; v1(47.39,97.78) 46.95,98.22 JWLAN1.75 ; 206.2,102.26 207.06,102.26 UV1.AN10 ; v1(99.77,108) 99.46,108.31 UC1.F13 ; UC1.BJ25 v1(66.31,117.22) ; 210.6,112 210.8,112 211.1,112.3 UV1.AH22 ; UC1.H25 98.19,117.84 98.58,118.22 99.08,118.22 UC1.F25 ; v1(167.67,53.78) 167.02,53.13 UH1.G6 167.3,52.82 UH1.H8 ; JHDD.7 273.9,38.75 274.52,39.37 v1(276.3,39.37) ; 74,107.76 UC1.AY12 ; v1(43.17,100.46) 43.15,100.46 42.45,99.76 JWLAN1.57 ; CV71.1 226.84,91.35 226.53,91.03 226.53,87.58 226.78,87.33 v1(227.51,87.33) ; UC1.AR37 77.34,126.11 v1(77.67,125.78) 77.35,125.46 UC1.AR36 ; UH1.T32 171.52,40.35 v1(171.63,40.24) 171.94,39.92 UH1.U33 ; JESPI1.9 74.39,40.1 73.84,39.55 73.26,39.55 CE35.1 ; v1(41.62,97.71) 41.46,97.71 40.95,98.22 JWLAN1.51 ; v1(103.96,139.32) 104.25,139.03 PUA01.14 ; UC1.T14 v1(92.28,109.19) ; v1(99.79,115.87) 99.46,116.2 UC1.F23 99.14,116.59 v1(99.14,116.66) ; UC1.AL14 v1(81.27,109.14) ; UC1.AR31 77.35,122.21 v1(77.67,121.89) 77.65,121.89 UC1.AR30 77.15,121.39 77.15,120.98 UC1.AR29 ; UH1.W30 v1(173.26,42.07) UH1.AA30 ; v1(176.66,48.42) 177.06,48.03 UH1.AH17 ; 230.9,99.37 230.5,99.77 UV1.E7 ; UC1.BM24 64.66,116.82 v1(64.34,117.22) 64.66,117.61 UC1.BM25 ; v1(181.42,37.1) 181.99,37.1 UH1.AV39 182.36,36.74 UH1.AW40 ; 230.8,123.45 231.25,123 231.25,123 231.26,122.99 231.26,122.61 231.25,122.6 231.25,122.14 ; v1(36.96,36) 36.96,35.37 37.37,34.95 JSSD1.9 ; v1(101.7,103.29) 101.54,103.14 101.54,103.01 UC1.C5 101.08,103.21 101.08,103.35 UC1.D6 ; UC1.BM11 v1(65,106.98) UC1.BM12 ; UH1.R26 UH1.P26 ; UC1.F29 99.19,121.26 v1(99.19,121.39) ; UH1.AP4 v1(180.64,54.06) ; UC1.G24 99.14,116.73 v1(99.14,116.66) ; UH1.N37 v1(170.3,38.86) 170.09,39.08 UH1.N35 ; v1(258.8,125.1) UV9.E14 v1(259.2,126.1) ; JWLAN1.33 v1(36.45,100.83) ; v1(60.95,107.21) 60.87,107.29 60.27,107.29 59.88,107.68 UC10.3 ; JHDD.1 274.07,41.75 v1(274.74,41.08) ; UC1.BK25 v1(65.66,117.22) ; v1(91.37,108.27) UC1.T13 ; UH1.BC19 184.74,46.78 v1(184.34,47.18) ; UC1.BK29 66.31,120.63 UC1.BJ29 ; 229.44,94.11 229.29,93.95 229.29,93.14 229.95,92.48 ; UH1.AT34 181.14,40.19 v1(181.12,40.21) UH1.AT32 ; RH30.2 v1(192.43,52.65) ; JWLAN1.45 v1(39.45,100.43) ; v1(178.75,46.55) 178.75,46.04 UH1.AL21 ; UV8.K1 v1(257.2,104.6) ; UV9.N12 252.8,123.9 252.4,124.3 ; UC1.W12 v1(90.48,107.01)
  BOTTOM w0.279: UV1.AN25 UV1.AM25 208.7,114 UV1.AL24 UV1.AL23
  BOTTOM w0.3: UV1.K33 226.25,121.6 226.31,121.65 226.31,122.17 225.82,122.65
  BOTTOM w0.305: UV1.A33 234.07,121.82 234.17,121.82 ; UV7.C4 v1(212.1,148.45) ; UV7.C4 212.9,148.45 v1(212.9,148.45) UV7.C3 v1(212.9,149.25) UV7.C4 ; UV8.T10 v1(262,98.2) ; v1(262.8,117.1) UV9.A3 v1(262,116.3) ; 206.7,121.05 UV1.AP33 205.92,121.07 205.89,121.07 ; 255.6,103.8 UV8.H2 254.8,104.6 UV8.H1 255.1,105.1 255.1,105.6 ; UV1.B25 232.5,114.37 UV1.C25 ; UV9.A14 v1(262.4,126.1) v1(262.4,126.7) ; v1(262,121.9) 261.6,122.3 UV9.B10 v1(261.2,122.7) 260.8,123.1 UV9.C11 ; UV1.AH10 211.2,102.38 211.54,102.72 211.54,102.81 UV1.AH11 ; 226.3,143.65 UV6.H2 225.5,142.85 UV6.H1 224.6,143.25 224.5,143.15 ; 252.4,125.1 UV9.N14 252.8,125.5 252.8,126.1 ; UV8.J10 255.87,97.93 255.87,98.29 ; 252.4,103.8 252.8,103.4 UV8.E3 ; v1(258.8,95.8) UV8.N12 v1(259.6,95.8) ; v1(258,122.7) UV9.G10 257.63,122.3 258.08,121.85 v1(258.09,121.85) 258.24,122 258.24,122.14 UV9.F10 v1(258.8,122.7) ; 205.7,144.45 UV7.H13 ; 220.86,97.66 221.25,98.05 UV1.T5 ; 223.75,118.2 224.17,118.62 UV1.N30 ; 213.32,121.85 213.35,121.85 UV1.AE33 214.17,121.05 UV1.AE32 ; UV7.C1 v1(215.5,148.85) v1(216.1,148.85) ; 249.6,126.1 UV9.U14 ; 206.7,123.35 206.7,122.65 ; 206.7,122.65 UV1.AN34 ; 206.7,122.65 205.9,122.65 ; v1(203.3,151.25) v1(203.9,151.25) v1(203.9,150.45) ; UV9.T10 250.4,122.3 250,122.7 ; UV8.A3 249.2,103 ; UV1.AN7 206.4,99.8 ; UV1.AN13 UV1.AM13 207.9,104.77 208.33,104.34 208.33,104.3 ; v1(256.8,126.7) v1(256.8,126.1) UV9.H14 ; 224.17,120.25 223.77,120.65 UV1.N32 223.72,120.65 223.32,121.05 223.35,121.05 UV1.N33 ; v1(207.3,147.65) UV7.D10 v1(208.1,148.45) ; v1(260.4,125.1) UV9.C14 v1(260.8,126.1) ; UV7.G10 207.7,145.65 v1(208.1,146.05) UV7.F10 v1(207.3,146.85) ; v1(236.1,147.25) 235.5,147.25 UV6.N14 v1(235.1,146.85) ; v1(262.4,114.5) UV9.A1 v1(262.8,115.5) ; 251.2,94 251.2,94 UV8.C14 251.2,94.6 250.8,95 ; v1(236.7,144.85) v1(236.1,144.85) 236.1,144.85 UV6.K14 ; 205.9,119.37 205.94,119.42 206.65,119.42 206.7,119.37 206.7,119.35 UV1.AN30 206.7,118.55 ; 234.15,120.05 234.1,120 233.52,120 233.3,120.22 232.9,119.82 UV1.B31 ; UV9.L10 254.4,122.3 254,122.7 UV9.M10 253.2,122.7 ; v1(224.5,147.25) UV6.N1 v1(225.5,147.65) ; UV6.R4 v1(227.1,148.45) UV6.R3 ; UV6.R4 v1(227.9,148.45) ; UV6.R4 227.5,148.85 227.9,149.25 UV6.T5 ; UV6.R11 v1(232.7,148.45) UV6.P10 ; v1(260.4,121.9) UV9.D10 v1(259.6,122.7) ; 206.54,97 206.84,97.3 UV1.AN4 ; UV6.P10 v1(231.9,147.65) ; UV6.P10 v1(231.9,148.45) ; UV6.N3 v1(226.3,146.85) ; UV6.N3 v1(227.1,147.65) ; UV6.N3 v1(226.3,147.65) ; UV1.W28 218.77,117.35 219.17,116.95 ; v1(258.8,102.2) UV8.M5 v1(258,101.4) 257.6,101.8 UV8.L5 ; 250.8,101.4 250.4,101.8 UV8.B5 250,101.4 ; v1(214.5,146.85) UV7.E1 v1(215.5,147.25) ; UV9.K14 254.8,125.1 UV9.K13 255.2,124.7 255.6,124.3 ; UV1.AH5 211.36,98.05 211.71,98.39 211.71,98.41 ; 214.17,116.95 214.15,116.95 UV1.AE28 214.17,117.77 ; 230.84,121.03 230.84,121.03 231.25,121.43 UV1.D33 231.25,122.1 231.25,122.14 ; 226.67,116.95 226.65,116.95 UV1.K28 ; UV8.M10 258.4,97.8 v1(258.8,97.4) ; UV6.L10 v1(231.9,146.05) 232.3,146.45 UV6.M10 232.3,146.45 v1(232.7,146.85) ; UV1.AH13 211.57,105.18 ; UV7.R12 206.5,138.85 206.9,139.25 UV7.R11 206.9,139.25 207.7,140.05 UV7.P10 ; v1(28.69,97.55) 28.69,97.9 28.45,98.14 JWLAN1.1 ; UV6.F5 227.9,142.05 228.3,142.45 UV6.G5 228.7,142.05 228.3,141.65 UV6.F5 ; UV6.F5 228.7,141.25 ; UV8.K13 256.8,95.4 v1(256.4,95.8) ; 226.3,141.25 UV6.E3 226.3,140.45 ; v1(236.1,150.45) UV6.U14 ; UV1.G25 228.44,114.44 228.41,114.44 ; 252.8,114.5 252.8,114.5 UV9.N1 ; UV9.N3 252.8,116.7 253.2,116.3 ; v1(223.9,144.95) v1(224.5,144.95) 224.6,144.85 UV6.K1 UV6.K2 ; v1(212.1,149.25) 212.1,149.25 UV7.B5 v1(211.3,150.05) ; UV1.AK7 209.57,99.8 209.99,100.22 209.99,100.15 210.33,99.8 UV1.AJ7 210.48,99.8 210.79,100.11 211.15,99.75 UV1.AH7 ; 236.1,139.25 235.5,139.25 UV6.C14 235.5,139.25 235.1,138.85 ; 213.49,99.28 213.75,99.54 UV1.AE7 ; 224.5,140.85 UV6.E1 ; v1(202.84,57.73) 202.63,57.51 U2.5 ; v1(227.9,146.85) UV6.M5 v1(228.7,146.05) 228.3,145.65 UV6.L5 ; UV1.AH19 210.92,110.07 210.6,110.07 ; v1(260.4,95) UV8.R14 v1(260.8,94) ; v1(224.5,148.85) UV6.R1 v1(225.5,149.25) ; 250.8,104.6 UV8.C1 251.2,105.6 ; v1(213.7,150.85) 213.3,150.45 UV7.A3 v1(212.9,150.05) ; 229.17,119.45 228.78,119.05 UV1.G30 ; CP9.2 26.1,95.58 v1(25.48,96.2) ; UV7.B10 v1(207.3,149.25) 206.9,148.85 UV7.C11 ; v1(204.9,149.25) UV7.C14 v1(203.9,148.85) v1(203.3,148.85) ; 218.32,121.05 218.35,121.05 UV1.W32 ; 208.33,121.84 208.36,121.84 UV1.AL33 ; UV7.U3 213.3,137.65 212.9,137.25 ; 203.9,137.65 UV7.U14 ; 203.9,137.65 203.3,137.65 ; 203.9,137.65 203.9,137.05 203.3,137.05 ; UV9.B5 v1(262,117.9) ; UV9.B5 261.2,117.9 v1(261.2,117.9) UV9.C4 260.4,117.1 v1(260.4,117.1) 260.8,116.7 UV9.C3 260.8,116.7 v1(261.2,116.3) ; UV9.B5 v1(262,118.7) ; 233.3,117.72 232.9,117.32 UV1.B28 ; v1(256.8,105.59) UV8.K1 ; UV8.P10 v1(259.6,98.2) ; UV8.P10 v1(260.4,98.2) ; UV8.P10 v1(260.4,97.4) UV8.R11 ; v1(259.2,105.6) UV8.N1 v1(258.8,104.6) ; v1(236.1,151.28) 236.14,151.32 238.08,151.32 CV163.2 ; 226.67,97.65 226.65,97.65 UV1.K5 ; v1(262.4,94) UV8.U14 ; 228.4,105.22 UV1.G13 229.22,105.22 229.65,104.8 ; v1(44.48,100.53) 43.95,100 JWLAN1.63 ; 228.37,111.87 UV1.G22 ; UV1.AL28 208.7,117.32 208.3,117.72 ; UV1.AH30 211.67,118.62 UV1.AH29 210.8,117.75 UV1.AH28 ; v1(203.3,147.25) v1(203.9,147.25) UV7.E14 ; 213.7,138.85 UV7.R3 213.3,139.25 212.9,138.85 UV7.R4 ; UV6.A12 233.8,137.54 233.8,137.5 233.77,137.47 233.77,136.89 233.86,136.8 ; UV1.T32 221.65,120.25 221.67,120.25 ; UV8.D10 251.55,97.35 UV8.C11 250.8,96.6 250.84,96.56 250.84,96.56 UV8.C12 251.2,96.2 251.6,95.8 ; UV1.K30 225.85,118.65 225.85,118.6 226.25,118.2 ; 252.4,95 252.8,94.6 UV8.E14 252.8,94 252.8,94 ; UV1.C7 232.5,99.37 UV1.B7 233.3,99.37 ; CZ47.2 107.18,118.91 UZ9.5 ; v1(236.1,148.85) UV6.R14 v1(235.1,148.45) ; UV1.E10 230.07,101.87 229.22,102.72 UV1.G10 ; v1(203.9,150.45) UV7.A14 ; v1(203.9,150.45) v1(203.3,150.45) ; v1(38.64,86.2) 38.4,86.44 CT112.2 38,86.43 CT113.2 ; UV7.N3 213.7,140.45 ; 251.6,115.5 UV9.R1 251.2,115.1 251.2,114.5 ; UV1.V12 220,103.69 UV1.U12 ; UV1.N28 223.35,116.95 223.32,116.95 ; UV8.F5 253.2,101.4 253.2,101.4 ; UV8.F5 253.6,101.8 254,101.4 UV8.G5 254.4,101.8 254,102.2 UV8.F5 ; UV1.AL20 UV1.AL21 208.27,111.93 UV1.AM22 UV1.AN22 ; UV1.C22 232.1,112.32 231.7,112.72 ; UV8.U12 v1(262,95.8) ; 211.3,138.05 211.7,138.45 UV7.T5 211.3,138.85 ; 252.8,105.6 UV8.E1 253.2,104.6 ; 253.19,118.71 UV9.M5 254.01,118.71 254.4,118.31 UV9.L5 ; v1(262,101.4) 261.6,101.8 UV8.T5 ; 252.4,95.8 UV8.E12 ; v1(259.2,114.5) UV9.E1 v1(259.6,115.5) ; 206.5,137.25 UV7.U12 ; UV8.R12 260.8,96.2 v1(261.2,95.8) ; v1(25.48,94.18) 25.6,94.31 CP10.2 ; UV6.K13 234.7,144.85 234.3,144.45 ; v1(47,56.67) 47.33,56.99 ; 215.82,118.62 UV1.AB30 ; 251.6,117.1 UV9.R3 251.2,116.7 250.8,117.1 UV9.R4 ; 207.3,141.25 207.7,141.65 UV7.M10 207.3,142.05 207.7,142.45 UV7.L10 ; UV9.E12 v1(259.6,124.3) ; 250.8,103 251.2,102.6 UV8.C4 251.6,103 251.2,103.4 UV8.C3 ; UV1.G16 229.22,107.72 ; 250,115.5 UV9.U1 249.6,115.1 249.6,114.5 ; v1(256.8,94) 256.8,94 UV8.K14 ; v1(28.51,32.57) 28.51,33.01 28.37,33.14 JSSD1.45 ; UV1.E22 230.9,111.87 ; UV1.B4 232.9,97.29 233.3,96.88 233.35,96.88 ; 214.5,139.65 UV7.R1 214.9,139.25 216.1,139.25 ; UV1.AE2 213.75,95.09 ; JSSD1.51 26.87,33.16 26.32,32.6 v1(26.32,32.13) ; v1(227.11,150.87) UV6.U3 v1(226.3,150.05) ; UV6.G10 232.7,142.05 232.3,141.65 UV6.F10 232.7,141.25 ; 234.76,95.25 234.76,94.74 234.47,94.45 234.16,94.45 233.36,95.25 233.3,95.25 ; 216.03,95.02 216.25,95.24 UV1.AB2 ; UV8.K2 v1(257.2,104.6) ; UV1.B10 232.5,102.72 ; UV1.G3 229.15,96.05 UV1.G2 229.24,94.48 229.44,94.11 ; UV8.H14 255.2,94.6 254.8,95 UV8.H13 255.6,95.8 ; 215.82,116.95 215.85,116.95 UV1.AB28 ; UV1.K7 226.63,99.37 226.63,98.46 226.64,98.45 ; UV6.D10 232.7,139.65 UV6.C11 233.5,138.85 233.9,139.25 UV6.C12 234.3,139.65 234.3,139.65 ; v1(214.5,150.05) UV7.A1 v1(215.5,150.45) ; UV9.J10 v1(256.44,121.86) ; UV7.J10 208.1,143.65 208.3,143.65 ; UV6.T5 v1(227.9,150.05) ; UV6.T5 v1(228.7,150.05) ; 253.2,97.4 UV8.F10 253.6,97.8 254,97.4 UV8.G10 ; 210.82,121.85 210.85,121.85 UV1.AH33 210.85,121.05 UV1.AH32 ; UV9.G5 v1(258,118.7) UV9.F5 v1(258.8,117.9) ; 203.3,140.85 203.9,140.85 UV7.N14 204.9,140.45 ; 250,97.4 UV8.B10 ; UV1.A2 233.3,95.25 ; 233.3,95.25 UV1.B1 ; UV7.A12 v1(205.7,150.05) ; UV9.H2 v1(256.4,115.5) 256.8,115.1 UV9.H1 256.8,114.6 v1(256.7,114.5) ; UV1.AK10 209.12,102.68 209.1,102.68 ; v1(33.45,107.6) 33.08,107.6 32.7,107.22 JWLAN1.18 ; 249.98,118.72 250.4,118.3 UV9.T5 250.79,118.69 250.79,118.72 ; v1(260.8,114.5) UV9.C1 v1(261.2,115.5) ; 226.69,120.17 226.67,120.18 226.67,120.22 UV1.K32 ; v1(262.4,105.6) UV8.U1 ; 224.5,139.25 UV6.C1 ; UV7.G5 v1(211.3,146.05) 211.7,146.45 UV7.F5 211.7,146.45 v1(212.1,146.85) ; UV7.T10 207.7,138.45 207.3,138.05 ; UV1.C10 232.5,101.87 ; UV1.AN16 UV1.AM16 208.29,107.73 UV1.AL17 UV1.AL18 208.7,109.06 207.96,109.8 UV1.AM19 207.9,109.85 207.49,110.26 207.1,109.87 UV1.AN19 ; 234.3,143.65 UV6.H13 235.1,142.85 235.5,143.25 UV6.H14 ; v1(204.9,146.85) UV7.E14 ; UV7.E14 v1(204.9,147.65) ; UV1.AH2 211.18,95.65 210.79,95.26 ; 249.2,96.6 249.6,96.2 UV8.A12 ; 250.8,125.1 UV9.R14 251.2,125.5 251.2,126.1 ; 249.6,105.6 UV8.A1 ; v1(205.7,148.45) 206.1,148.85 UV7.C12 ; UV8.N3 v1(259.6,103) ; v1(215.49,144.85) UV7.H1 214.9,144.82 214.5,144.41 214.1,144.81 UV7.H2 ; 209.1,118.55 UV1.AL30 208.7,118.97 208.3,119.37 ; 233.3,112.72 232.9,112.32 UV1.B22 ; UV1.G32 228.32,121.05 UV1.G33 228.77,121.45 229.17,121.85 ; 230.9,97.65 UV1.E5 ; 220.82,117.77 UV1.T28 ; UV6.E12 234.3,140.45 ; 232.7,138.05 UV6.B10 ; UV1.AL2 208.75,94.84 208.95,94.64 ; 213.32,119.45 213.35,119.45 UV1.AE30 ; UV7.K14 204.9,142.85 205.3,143.25 UV7.K13 205.7,143.65 ; v1(234.3,147.65) 233.9,147.25 UV6.N12 ; UV1.C13 231.7,105.2 ; UV1.N5 223.81,98.05 224.21,97.65 ; 228.4,109.37 UV1.G19 ; UV9.P10 252,122.3 251.2,123.1 UV9.R11 251.2,123.1 250.8,123.5 UV9.R12 ; v1(234.3,149.25) 233.9,148.85 UV6.R12 ; 211.3,141.25 211.7,141.65 UV7.M5 211.3,142.05 211.7,142.45 UV7.L5 ; UV1.AL5 208.32,97.77 ; 235.1,140.45 235.1,140.45 UV6.E14 235.5,140.85 236.1,140.85 ; 249.6,94 249.6,94 UV8.A14 ; UV9.H13 v1(256.4,124.3) ; v1(213.7,147.65) 213.3,147.25 UV7.E3 213.3,147.25 v1(212.9,146.85) ; UV1.AE5 213.35,97.65 ; 255.1,114.5 255.2,114.6 UV9.K1 255.2,115.1 254.8,115.5 254.8,115.5 UV9.K2 255.6,116.3 ; v1(114.27,121.73) UZ15.5 ; UV8.N14 v1(259.2,94) ; 231.7,120.25 UV1.D31 ; v1(25.04,35.3) 25.37,34.96 JSSD1.57 ; v1(261.2,103.8) UV8.R3 v1(260.4,103) UV8.R4 ; PUA01.2 106.85,137.45 v1(107.32,137.92) ; 216.67,120.25 216.65,120.25 UV1.AB32 ; UV9.E3 v1(259.6,117.1) ; 231.7,117.72 232.1,117.32 UV1.C28 ; 232.5,121.85 UV1.B34 ; UV6.T10 v1(231.9,150.05) ; 204.9,138.85 UV7.R14 203.9,139.25 203.3,139.25 ; UV8.R1 v1(260.8,105.6) ; 228.7,140.45 228.87,140.45 229.34,139.98 229.34,139.15 228.64,138.45 UV6.B5 ; v1(262,103.8) UV8.U3 ; v1(205.7,147.65) UV7.E12 v1(206.5,146.85) ; UV1.C16 231.72,107.72 ; 224.5,137.65 UV6.A1 ; 216.13,143.25 UV7.K1 214.5,142.85 UV7.K2 213.7,143.65 ; UV7.H14 v1(203.92,144.85) ; UV6.U12 v1(234.3,150.05) ; UV9.U3 249.2,116.3 ; 205.7,141.25 UV7.N12 ; 199.87,123.83 CG438.2 ; UV9.A12 v1(262,124.3) ; UV9.C12 v1(261.2,124.3) ; UV9.U12 249.2,123.5 ; 231.7,110.22 UV1.C19 ; UV1.AH24 210.76,114.45 ; UV6.C4 227.1,139.65 UV6.C3 227.1,138.85 227.5,139.25 UV6.C4
  BOTTOM w0.356: PR44.1 45.65,127.2 PQ12.1 ; CV212.2 208.01,91.6 v1(208.02,91.59) ; v1(194.32,33.36) 194.48,33.2 RH199.2 ; RH679.2 174.03,25.04 v1(173.7,24.71) ; RH746.2 189.35,56.43 v1(189.35,56.28) 189.35,56.11 RH739.2 ; RH705.2 190.34,36.54 190.42,36.62 v1(190.42,37.01) 189.71,37.01 RH135.1 ; v1(168.15,29.17) 168.43,29.17 RH681.2 ; v1(47.32,125.55) 46.95,125.18 PQ12.4 ; 197.42,32.93 197.16,33.2 RH742.2 ; v1(172.44,30.95) 172.44,30.43 172.39,30.38 RC224.2 ; v1(263.2,105.6) v1(262.4,105.6) v1(262.4,106.2) ; RH562.2 170.66,29.25 v1(170.37,28.96) ; UV1.T2 221.22,95.65 221.06,95.82 221.05,95.82 220.82,96.04 ; RC7.1 106.61,125.04 RC6.1 106.6,124.87 v1(106.96,124.52) ; RH749.2 192.8,35.81 RH741.2 192.8,36.71 v1(192.6,36.92) ; v1(212.08,87.91) 212.85,88.68 CV529.2 ; v1(37.76,91.43) 38.16,91.43 38.35,91.24 RT71.2 RT72.2 ; v1(21.44,92.16) 21.67,91.93 CP24.2 ; v1(14.22,128.14) 14.26,128.11 RT42.2 14.8,128.11 RT45.2 ; 249,105.6 249,106.2
  BOTTOM w0.381: CV885.2 262.92,106.48 v1(263.2,106.2) ; QG505.4 201.18,93.64 202.48,92.34 QG505.1 v1(203.2,92.13) ; RT34.2 v1(27.01,136.23) ; PRH13.2 134.2,37.84 135.01,37.84 v1(135.43,38.26) 135.8,37.9 PCH09.2 136.08,37.89 PRH03.1 ; v1(36.09,35.7) 35.88,35.7 CC299.2 ; 252.8,126.7 252.82,126.72 CV893.2 ; v1(211.07,91.39) 210.94,91.51 UV20.3 ; UV1.AA22 216.5,113.11 215.56,114.05 UV1.AB23 ; CP12.2 21.39,96.25 v1(21.44,96.2) ; CV887.2 247.81,92.91 ; CV402.2 250.97,126.93 251.2,126.7 ; PCH12.2 140.83,40.61 140.36,40.14 139.5,40.14 138.07,41.57 137.89,41.57 ; CP5.2 23.42,96.24 v1(23.46,96.2) ; UV19.3 233.58,89.56 v1(233.99,89.97) ; v1(194.12,116.8) 193.91,116.59 QG504.4 ; PCM15.2 PCM16.2 38.95,38.68 38.95,38.46 v1(38.47,37.99) ; CV904.2 208.94,129.4 208.94,128.27 208.72,128.05 ; v1(39.19,118.25) 39.32,118.12 PC8.2 39.83,117.35 39.97,117.49 PC9.2 ; v1(161.64,27.92) 161.86,27.7 Q27.4 ; CV898.2 249.16,102.96 249.2,103 ; v1(250.96,59.71) 250.96,59.97 251.1,60.11 PRV29.1 PCV09.2 ; CT37.2 18.03,114.2 v1(18.45,114.62) ; v1(215.5,147.25) v1(216.1,147.25) 216.14,147.21 CV857.2 ; 251.06,92.78 CV899.2 ; v1(256.92,65.76) 256.74,65.95 PCV01.2 ; UV1.M17 225.5,108.07 226,108.57 225.52,109.05 UV1.M18 ; CG246.2 238.63,89.62 238.39,89.37 238.39,88.55 v1(238.57,88.36) ; v1(183.72,60.58) CH209.2 ; v1(10.35,121.49) 10.56,121.28 CT96.1 CT97.1 12.36,121.28 v1(12.57,121.49) ; v1(236.7,147.25) v1(236.1,147.25) ; UV1.P20 UV1.R19 ; UV1.P22 223.86,113.41 223.86,113.46 223.9,113.5 223.95,113.5 UV1.N23 ; RT36.2 v1(22.38,136.3) ; RV37.2 224.2,90.41 RV27.2 v1(224.97,89.18) 224.97,88.34 QV10.1 ; CV396.2 251.1,106.3 251.2,106.2 ; UV1.U23 220,113.55 UV1.V23 219.18,114.37 219.18,114.56 219.17,114.57 ; v1(255.55,63.65) 255.45,63.75 PRV03.1 ; QH10.4 195.73,62.4 194.43,61.1 QH10.1 v1(193.33,61.1) ; RT63.2 33.6,83.03 32.99,83.03 CT90.2 ; v1(227.51,87.33) 229.28,87.33 v1(229.67,86.94) ; v1(153.04,44.86) C149.2 ; UV1.V19 219.89,109.66 220.11,109.66 UV1.U19 ; PCV08.1 252.88,59.41 PCV03.1 252.48,59.38 v1(252.15,59.71) ; UV1.AC22 214.99,112.56 215.02,112.56 215.02,112.53 UV1.AB21 ; UV1.R21 222.22,112.05 222.01,111.84 222.01,111.56 UV1.T20 ; UV1.R16 222.99,106.56 222.99,106.46 223.09,106.46 UV1.P15 ; UV1.W15 UV1.Y14 ; v1(205.48,92.17) 205.24,91.94 CG527.2 ; PCV11.1 v1(246.79,72.43) ; v1(262.4,126.7) 262.29,126.82 CV894.2 ; QV10.4 223.01,86.98 v1(223.56,86.98) ; UV1.T17 222,108.55 UV1.T18 ; UV1.V14 220,105.55 UV1.U14 ; v1(19.88,98.63) 19.31,98.06 UT2.4 18.98,98.28 18.98,99.5 19.25,99.77 CV601.1 19.03,100.66 18.68,100.32 16.45,100.32 CV600.1 ; UV1.Y16 UV1.AA15 ; v1(207.9,86.54) 208.54,85.9 RG573.2 208.94,85.97 RV58.1 ; v1(259.2,106.2) 259.1,106.3 CV896.2 ; v1(205.42,87.18) 205.67,87.43 UV14.3 ; CH20.2 171.03,59.78 v1(171.21,59.96) ; PCV06.1 v1(256.35,62.1) ; UV1.AN1 UV1.AP2 205.83,95.65 205.73,95.75 ; CV71.1 227.26,91.77 v1(227.51,92.01) ; CV886.2 252.95,106.35 252.8,106.2 ; UV1.AC20 214.95,110.6 215.02,110.6 215.02,110.53 UV1.AB19 ; CV884.2 260.69,113.79 v1(260.8,113.9) ; UV1.Y21 UV1.W20 ; 255.2,126.7 255.35,126.85 CV199.2 ; v1(260.88,93.04) 260.95,92.97 CV901.2 ; UV1.N21 224.98,112.53 225.15,112.53 225.15,112.7 UV1.M22 ; 230.95,87.69 230.95,89.47 v1(230.83,89.59) ; CV401.2 257.19,127.25 v1(257.69,126.76) ; CV902.2 249.17,96.57 249.2,96.6 ; QG506.1 245.65,85.42 v1(244.81,86.27) 244.35,86.72 QG506.4 ; CV878.2 249.16,123.46 249.2,123.5 ; UG31.3 203.25,89.02 202.51,89.75 QG23.1 201.59,89.75 v1(201.12,89.28) 201.12,88.97 200.6,88.45 QG23.4 ; UV1.AA17 216,108.55 UV1.AA18 ; PRV18.2 v1(256.2,59.61) ; v1(194.21,55.4) 194.34,55.27 C21.2 ; PCV10.2 PRV26.2 v1(248.69,72.46) ; PRV24.2 PRV25.2 v1(250.55,72.4) ; PRV34.1 PRV35.1 246.53,59.73 v1(246.55,59.71) ; v1(111.68,118.11) 111.68,118.05 112.18,117.55 CZ111.2 ; UV1.P18 224,108.55 UV1.P17 ; PRV32.1 PRV33.1 248.06,59.77 v1(248,59.71) ; PR15.2 PR16.2 35.59,124.41 35.85,124.67 v1(36.1,124.67) ; 226.05,110.45 225.5,111 UV1.M20 225.2,110.75 225.2,110.53 224.98,110.53 UV1.N19 ; v1(203.3,151.25) 202.05,151.25 CV172.2 ; RH20.1 173.11,59.94 v1(173.11,60.5) ; v1(196.05,92.41) 196.65,92.41 198.01,91.06 CG482.2 ; RV121.2 200.87,141.2 201.26,140.81 CV866.2 203.26,140.81 203.3,140.85 ; v1(47.32,125.55) 47.61,125.55 47.93,125.23 PR40.2 ; v1(19.12,128.66) 18.57,128.11 RT46.2 RT40.2 ; QG503.4 197,116.2 v1(196.43,116.78) ; 249,126.87 248.63,127.23 CV187.2 ; v1(54.95,147.9) 54.92,147.93 PHZ04.2 ; v1(25.48,96.2) 25.35,96.33 CP26.2 ; UV1.R12 222.03,103.52 222.02,103.52 222.02,103.6 221.95,103.6 UV1.T13 ; 255.1,113.9 255.06,113.86 CV880.2 ; UV1.V16 220,107.55 UV1.U16 ; CV179.2 249.56,112.27 CV891.2 249.27,112.77 249.6,113.09 249.6,113.94 ; UV1.AC17 215.04,108.59 215.04,108.65 214.9,108.65 UV1.AC18 ; QG503.1 v1(195.7,116.8) ; UV1.Y12 UV1.W13 ; RT17.2 v1(19.84,136.24) ; v1(12.3,106.35) 12.4,106.45 DT11.3 ; UV1.W17 218,108.55 UV1.W18 ; UV1.AC15 UV1.AB16 ; UV1.AA20 UV1.Y19 ; v1(259.2,126.7) 259.04,126.87 CV194.2 ; UV1.AC13 214.99,104.54 215.02,104.54 215.04,104.57 215.04,104.59 UV1.AB14 ; UV1.N16 UV1.M15 225.75,106.05 226.07,106.37 ; CV877.2 252.84,113.86 252.8,113.9 ; UG27.3 242.86,84.43 243.39,83.9 v1(243.63,83.9) ; v1(163.54,26.57) Q27.1 ; v1(42.41,42.69) 42.29,42.57 PCM19.2 PCM18.2 ; v1(259.2,113.9) 258.84,113.54 CV881.2 ; v1(22.17,114.86) 22.25,114.79 QH8.4 ; RT11.2 v1(29.55,136.26) ; 198.17,118.22 198.55,118.59 UG25.3 ; QH8.1 26.93,112.32 v1(27.2,112.6) ; CG440.2 241.61,81.09 v1(242,81.09) RG557.2 ; 252,93.04 CV888.2 ; v1(214.19,39.84) 214.19,40.41 CH49.2 ; QV20.3 239.85,141.05 CV377.2 ; UV1.Y23 UV1.W22 ; CV890.2 263.94,113.16 v1(263.2,113.9) ; UV1.N14 UV1.M13 225.9,103.65 ; v1(249.58,59.71) PRV31.1 PRV30.1 ; QG504.1 v1(192.61,116.82) ; UV1.AB12 UV1.AA13 ; 249.2,116.3 249.12,116.22 CV882.2 ; UV1.N12 UV1.P13 ; UV1.R23 UV1.T22 ; RT4.2 v1(24.28,136.28) ; CV892.2 256.44,113.64 v1(256.7,113.9) ; UV1.R14 UV1.T15 ; RT68.2 41.63,89.32 43.21,89.32 v1(43.47,89.58) ; UV1.V21 220,111.55 UV1.U21 ; CV895.2 257.07,106.47 v1(256.8,106.2) ; CT45.2 v1(14.45,87.25) ; v1(237.39,86.49) 237.64,86.74 UG22.3 ; v1(154.42,38.92) 154.42,39.99 154.06,40.35 JKBBL.6 152.6,39.95 v1(152.6,38.91) ; RT47.2 v1(24.92,136.25) ; CV900.2 v1(259.11,92.02) ; v1(263.3,93.04) CV889.2
  BOTTOM w0.4: v1(223.9,147.25) v1(224.5,147.25) ; 249,106.2 249.6,106.2 ; v1(259.2,105.6) v1(259.2,106.2) ; v1(263.2,113.9) v1(263.2,114.5) ; 223.9,143.15 224.5,143.15 ; v1(259.2,113.9) v1(259.2,114.5) ; v1(263.2,106.2) v1(263.2,105.6) ; 249.6,114.5 249.6,113.94 249,113.94 249,114.5 249.6,114.5 249.6,114.5 ; 249.6,126.87 249.6,126.1 249,126.1 249,126.87 249.6,126.87
  BOTTOM w0.406: 251.2,106.2 251.2,105.6 ; v1(236.7,150.45) v1(236.1,150.45) v1(236.1,151.28) ; v1(259.2,126.1) v1(259.2,126.7) ; v1(262.4,113.9) v1(262.4,114.5) v1(263.2,114.5) ; v1(260.8,114.5) v1(260.8,113.9) ; v1(236.1,148.85) v1(236.7,148.85) ; 249.6,106.2 249.6,105.6 ; 223.9,139.25 224.5,139.25 ; v1(260.8,126.1) v1(260.8,126.7) ; 252.8,113.9 252.8,114.5 ; v1(224.5,148.85) v1(223.9,148.85) ; 255.1,106.2 255.1,105.6 ; 251.2,113.9 251.2,114.5 ; v1(260.8,106.2) v1(260.8,105.6) ; 252.8,126.7 252.8,126.1 ; 251.2,126.1 251.2,126.7 ; 223.9,137.65 224.5,137.65 224.5,137 224.5,137 224.48,137.02 223.9,137.02 223.9,137.01 223.9,137.65
  BOTTOM w0.457: v1(223.9,147.25) 223.48,147.25 223.33,147.4 CV871.2 ; v1(203.3,147.25) 202.78,147.25 202.57,147.05 CV854.2 ; JKB.31 154.08,31.5 v1(154.31,31.28) ; PC1801.2 195.49,67.43 v1(195.96,67.9) ; CV161.2 222.57,137.65 223.9,137.65 ; v1(256,106.2) v1(256,105.59) ; 223.9,143.15 223.71,143.15 223.2,143.66 RV116.2 CV873.2 ; YH2.4 v1(155.11,54.07) ; CV200.2 202.65,144.95 202.75,144.85 v1(203.28,144.85) v1(203.92,144.85) ; v1(208.02,91.59) 208.02,91.04 RV573.2 ; CV874.2 223.25,141.01 223.42,140.85 224.5,140.85 ; CZ97.2 CZ96.2 115.74,116.59 115.63,116.48 CZ102.2 116,115.71 v1(116.27,115.71) ; CV378.2 236.79,145.56 v1(236.7,145.65) v1(236.7,144.85) 237.12,144.85 237.34,144.63 CV158.2 RV127.2 ; v1(127.19,30) 127.19,30.74 126.77,31.15 JKB.32 ; 203.3,137.05 202.87,136.62 CV169.2 ; v1(203.3,148.85) 202.75,148.85 202.71,148.89 CV385.2 ; CV903.2 235.12,132.31 234.83,132.02 ; CV386.2 216.74,144.8 216.68,144.85 v1(216.13,144.85) v1(215.49,144.85) ; RV132.2 255.1,107.23 255.1,106.2 ; v1(11.14,123.75) 11.15,123.74 CT94.2 CT95.2 ; v1(152.82,53.33) 152.82,53.01 153.46,52.37 YH2.2 154.03,51.26 CH48.2 ; 236.1,139.25 236.7,139.25 236.72,139.27 CV376.2 ; CV379.2 237.29,147.4 237.13,147.25 v1(236.7,147.25) ; CV906.2 241.08,118.65 240.62,119.11 ; CG442.2 199.39,92.95 200.03,93.59 200.03,94.07 ; 203.3,139.25 202.87,139.25 202.58,138.96 CV853.2 ; v1(223.9,144.95) 223.62,144.95 223.14,145.43 CV872.2 ; RX8.2 19.41,102.72 17.37,102.72 v1(17.07,102.42) ; R2.2 168.09,25.07 v1(167.88,24.87) ; CV377.2 237.27,141.05 237.07,140.85 236.1,140.85 ; RV142.2 CV177.2 v1(257.22,92.91)
  BOTTOM w0.508: PU01.2 v1(39.86,119.84) ; C1.2 183.35,26.97 v1(183.91,26.41) ; JKBBL.5 159.98,40.35 v1(159.53,39.9) ; JDIMM2.262 116.35,42.2 116.38,42.16 v1(117.51,42.16) ; v1(47.48,79.17) 47.26,78.95 JDIMM1.262 43.9,81.45 43.72,81.63 v1(42.92,81.63) ; PCZ31.2 109.87,153.98 v1(109.67,154.18) ; CZ28.2 116.92,122.46 v1(117.13,122.24) ; v1(44.86,126.73) 44.86,127.09 45.16,127.39 PR44.1 ; v1(93.97,33.35) 91.4,33.35 91.12,33.07 CLRP1.2 ; v1(164.45,26.55) 164.45,26.35 Q1.3 ; CG386.2 v1(196.13,119.86) ; CT92.2 v1(30.51,82.26) ; CT92.2 CT91.2 ; CT92.2 CT93.2 ; CG487.2 v1(194.35,119.88) ; CZ86.2 113.88,119.57 v1(114.11,119.34) ; PRZ57.2 108.17,154.7 v1(107.94,154.93) ; JDIMM2.261 46.9,44.43 47.18,44.72 v1(47.18,44.92) ; PC1802.2 201.64,64.15 PR1802.2 ; v1(31.81,60.59) 32.03,60.81 PCM08.2 ; PRH05.2 132.19,40.46 ; JFAN1.6 117.95,72.97 v1(117.38,73.54) ; CX2.2 CV599.1 16.1,102.63 v1(15.95,102.47) ; PCB33.2 v1(225.58,37.41) ; PCG07.1 v1(58.15,152.09) ; v1(19.4,87.98) 19.78,87.61 CP32.2 ; CZ88.2 113.76,121.73 v1(114.27,121.73) ; UT3.4 38.74,80.98 v1(38.92,81.16) ; v1(109.35,137.88) 109.15,137.67 PCA08.2 ; YV1.2 v1(227.51,87.33) ; v1(50.93,121.94) 50.32,121.33 PC909.2 ; v1(153.04,44.86) 153.01,44.83 R27.2 ; PC22.2 32.95,116.07 32.11,116.92 PR100.2 31.74,117.72 31.74,118.46 v1(31.91,118.64) 32.17,118.9 32.79,118.9 33.65,118.03 PQ5.3 ; v1(26.7,84.76) 27.1,84.76 27.5,85.15 CT106.2 ; v1(56.13,110.37) 55.88,110.12 CH197.2 ; CP14.2 20.92,90.4 v1(20.52,90.8) ; v1(202.95,86.33) 202.71,86.09 PC1007.2 PC1005.2 ; v1(71.27,39.06) 72.77,39.06 CE35.1 ; v1(25.48,92.16) 25.69,92.38 CT99.2 ; 255.29,93.37 255.44,93.22 CV897.2 ; RT65.2 27.8,87.27 v1(27.39,86.87) ; v1(31.66,40.92) 31.99,40.59 PCM14.2 ; PR303.2 128.53,58.93 v1(128.99,59.38) ; JIOB1.10 v1(264,34.24) ; v1(45.78,100.34) 46.39,100.95 47.72,100.95 48.05,100.62 JWLAN1.77 ; v1(42.4,39.01) 42.34,38.95 PRM11.2 ; v1(107.13,154.86) 107.38,154.61 PRZ55.2 107.13,153.93 PCZ32.2 ; CV905.2 241.68,96.36 241.91,96.59 ; v1(262,34.11) JIOB1.8 ; Q8.3 155.92,46.19 156.53,45.58 v1(156.53,44.37) ; v1(256.8,106.2) v1(256.8,105.59) ; v1(118.31,67.82) 118.61,68.11 JFAN1.1 ; DU2.1 19.55,51.34 v1(19.29,51.6) ; YT1.4 v1(15.86,116.43) ; PCS23.2 18.49,52.59 v1(18,53.08) ; v1(264.32,63.39) PRW17.2 264.34,64.13 PCW17.2 ; v1(23.17,40.87) 24.34,39.69 PQS07.3 ; PR1004.2 208.25,73.23 v1(208.69,73.23) ; PRZ16.2 105.49,140.19 105.75,139.94 v1(106.11,139.94) 106.37,140.19 PCZ11.1 ; PCW12.2 v1(264.92,79.24) ; PQS04.3 31.87,52.24 v1(32.41,52.79) ; PCI15.2 v1(88.94,147.48) ; v1(31.81,62.61) 32.05,62.61 PCM06.2 ; PC2502.2 117.83,61.36 v1(118.3,60.88) ; JESPI1.11 v1(77.8,43.91) ; v1(120.28,56.84) 120.17,56.73 C30.2 ; YV1.4 230.16,89.59 v1(230.83,89.59) v1(230.83,90.35) 230.83,91.01 230.5,91.35 CV70.1 230.02,92.41 229.95,92.48 ; v1(22.16,40.82) 22.16,39.88 21.45,39.17 CU15.2 ; PCG08.2 v1(56.31,152.83) ; PC12.2 214,43.61 213.49,44.11 CH224.1 213.19,44.54 214.5,45.86 v1(214.5,46.49) 217.16,46.49 PC11.2 ; v1(110.81,81.62) 110.81,79.64 JDIMM1.261 112.42,79.87 112.42,81.1 111.15,82.37 v1(110.82,82.37) ; RC145.2 180.51,29.95 180.51,28.87 180.94,28.43 181.57,28.43 v1(181.98,28.84) ; v1(190.02,60.67) 190.03,60.66 CH36.2 191.02,59.88 CH51.1 ; v1(30.9,52.71) 31.62,53.43 PQS12.3 ; JTP.5 v1(230.55,31.92) ; v1(32.5,108.22) 33.07,108.79 PQ6.3 ; PRZ59.2 108.97,154.73 v1(108.78,154.92) ; PCW15.1 v1(267.84,71.5) ; PR308.2 v1(212.03,45.4) ; 202.59,121.11 202.92,120.78 RV50.1 ; v1(267.19,66.51) PCW10.1 ; RV62.2 RV63.2 ; v1(276.56,42.35) 276.56,43.21 JHDD.13 277.19,43.26 v1(277.19,42.34) ; C148.2 v1(269.47,62.01) ; v1(45.61,121.58) 45.61,121.42 45.7,121.34 PR904.2 PR906.1 PR910.2 PR912.1 ; CT90.2 32.92,82.67 32.45,82.2 v1(32.19,82.2) ; QG502.1 241.81,87.14 v1(242.32,87.65) ; JWLAN1.76 27.35,98.16 27.87,97.63 27.96,97.55 v1(28.69,97.55) ; CP29.2 v1(23.98,81.77) ; v1(19.66,85.48) CP28.2 ; PC308.2 v1(208.03,45.52) ; RC16.2 v1(93.29,127.53) ; v1(127.18,66.73) 127.83,66.09 PC2503.2 127.83,64.72 PC2501.2 ; v1(240.36,37.58) 239.91,37.58 239.52,37.18 DF1.1 ; 252.8,106.2 252.8,105.6 ; UH4.4 UH15.4 205.05,43.5 v1(205.44,43.12) ; v1(103.49,154.03) PRZ67.2 103.49,153.29 PCZ29.2 104.41,153.31 PCZ30.1 ; DC1.1 32.59,38.05 v1(32.69,38.15) ; PQ17.3 v1(28.43,112.29) ; v1(212.08,87.91) 211.71,88.27 QG10.3 ; PC1806.2 v1(207.62,70.26) ; QH7.3 177.1,29.13 v1(177.47,29.5) ; CZ47.2 107.46,118.17 v1(107.84,118.17) ; YT1.2 v1(12.51,113.75) ; H15.1 280.8,26.68 ; PCA07.1 108.46,136.14 v1(108.44,136.16) ; JFAN2.1 275.3,59.42 v1(275.27,59.4) ; PQS08.3 31.55,46.65 31.21,46.31 v1(31.21,45.75) ; v1(23.04,108.81) 23.45,108.81 RW4.2 ; v1(122.62,73.39) 123.13,73.39 123.55,72.97 JFAN1.5 ; PCW09.2 v1(259.2,66.09) ; PQ18.3 31.88,112.42 32.05,112.59 v1(32.05,112.66) ; v1(17.38,116.58) 17.73,116.22 CT38.2 ; JSSD1.77 40.47,32.66 39.97,32.16 v1(39.34,32.16) ; v1(31.74,43.85) 32.15,44.26 PCM13.2 ; v1(188.3,60.63) RH667.2 188.3,59.89 RH666.2 ; v1(256.7,113.9) v1(256.7,114.5) ; CL13.2 v1(23.06,82.6) ; 255.1,114.5 255.1,113.9 ; v1(39.06,35.94) 39.55,36.43 SW1.2 ; PR64.2 v1(43.71,124.42) ; PCI35.2 v1(72.85,153.55) ; PR63.2 v1(36.93,122.01)
  vias: v1(0.43,120.7) v1(0.5,126.53) v1(0.65,88.72) v1(0.57,81.81) v1(1.45,115.73) v1(1.49,107.27) v1(1.5,83.21) v1(2.28,135.6) v1(2.29,132.74) v1(2.83,5.54) v1(3.03,84.23) v1(3.87,66.52) v1(4.22,135.56) v1(4.31,111.75) v1(4.39,130.5) v1(4.58,61.49) v1(4.58,43.56) v1(4.58,38.48) v1(4.59,20.88) v1(4.85,114.25) v1(5.19,86.98) v1(5.16,81.79) v1(5.31,84.44) v1(5.54,118.1) v1(5.49,110.69) v1(5.62,132.64) v1(5.62,128.36) v1(5.73,88.72) v1(6.03,104.98) v1(6.89,124.4) v1(6.88,115.26) v1(7.09,42.38) v1(7.2,41.2) v1(7.21,39.84) v1(7.4,136.17) v1(7.59,124.57) v1(7.84,81.79) v1(7.78,5.53) v1(7.9,83.13) v1(8.08,132.64) v1(8.08,128.36) v1(8.28,110.69) v1(8.5,43.45) v1(8.5,38.95) v1(8.95,66.52) v1(8.98,22.07) v1(9.06,45.97) v1(9.23,36.43) v1(9.31,130.5) v1(9.53,60.33) v1(9.75,44.04) v1(9.75,38.32) v1(9.93,101.73) v1(9.93,96.65) v1(9.93,91.57) v1(10.39,84.44) v1(10.43,1.2) v1(10.52,86.98) v1(11.1,43.45) v1(11.1,38.95) v1(12.29,39.84) v1(12.38,137.17) v1(12.42,42.38) v1(12.4,41.2) v1(12.51,115.4) v1(13.49,1.38) v1(14.52,1.36) v1(15.02,121.47) v1(15.32,1.35) v1(15.47,119.89) v1(15.45,0.43) v1(15.79,106.64) v1(16.23,1.42) v1(17.06,41.9) v1(17.46,137.17) v1(17.86,43.85) v1(18.06,41.88) v1(18.19,132.28) v1(18.3,63.82) v1(18.38,63.12) v1(18.53,97.06) v1(18.58,132.82) v1(18.82,132.28) v1(18.88,56.39) v1(19.24,36.84) v1(19.44,120.06) v1(19.43,56.79) v1(19.7,35.18) v1(19.83,36.84) v1(19.96,43.41) v1(20.28,35.18) v1(20.31,1.93) v1(20.41,36.84) v1(20.65,59.08) v1(20.65,58.42) v1(20.65,57.81) v1(20.65,57.22) v1(20.87,35.18) v1(20.99,36.84) v1(21.06,129.08) v1(21.06,128.45) v1(21.08,126.51) v1(21.29,29.54) v1(21.44,94.18) v1(21.54,118.8) v1(21.45,35.18) v1(21.58,36.84) v1(21.81,87.79) v1(22.34,123.9) v1(22.43,61.62) v1(22.54,137.17) v1(23.04,109.43) v1(23.04,108.2) v1(23.04,107.58) v1(23.04,106.99) v1(23.01,61.64) v1(22.96,29.17) v1(23.44,86.3) v1(23.46,94.18) v1(23.46,92.16) v1(23.66,127.15) v1(23.66,126.5) v1(23.66,123.9) v1(24.05,118.79) v1(24.31,123.9) v1(24.35,79.93) v1(24.35,79.07) v1(24.38,25.41) v1(24.64,24.89) v1(24.88,23.83) v1(24.92,11.63) v1(25.04,24.4) v1(25.39,1.93) v1(25.53,119.12) v1(25.47,11.89) v1(25.61,129.1) v1(25.61,123.9) v1(25.78,65.89) v1(25.85,29.35) v1(25.9,75.3) v1(25.88,72.86) v1(25.91,70.85) v1(25.93,67.88) v1(26.91,118.69) v1(26.86,30.01) v1(27.62,137.17) v1(27.56,130.4) v1(27.57,125.21) v1(27.6,29.09) v1(27.81,118.79) v1(28.23,124.55) v1(29.19,118.74) v1(29.18,17.89) v1(29.18,16.31) v1(29.18,14.74) v1(29.51,117.44) v1(29.71,88.28) v1(29.7,87.69) v1(29.92,29.26) v1(30.18,116.66) v1(30.28,108.99) v1(30.43,27.89) v1(30.47,1.93) v1(30.57,129.29) v1(30.68,141.22) v1(30.66,115.37) v1(30.75,17.89) v1(30.75,16.31) v1(30.75,14.74) v1(31.1,10.83) v1(31.37,29.23) v1(31.69,105.15) v1(32.33,17.89) v1(32.33,16.31) v1(32.33,14.74) v1(32.85,145.82) v1(32.89,135.01) v1(32.87,29.25) v1(33.04,50.92) v1(33.03,50.3) v1(33.09,49.72) v1(33.22,49.15) v1(33.29,135.5) v1(33.44,47.58) v1(33.6,79.27) v1(33.61,50.07) v1(33.69,124.3) v1(33.71,123.41) v1(33.66,122.23) v1(33.72,49.45) v1(33.73,48.09) v1(33.77,48.69) v1(33.92,135.57) v1(33.88,95.08) v1(34.01,47.44) v1(34.11,96.84) v1(34.08,28.53) v1(34.2,49.97) v1(34.33,48.08) v1(34.34,29.26) v1(34.35,49.34) v1(34.36,48.72) v1(34.76,100.04) v1(35.07,89.6) v1(35.2,133.58) v1(35.45,65.92) v1(35.45,66.51) v1(35.55,1.93) v1(35.71,130.55) v1(36.07,94.49) v1(36.73,42.82) v1(36.78,20.12) v1(36.98,57.22) v1(37.21,143.87) v1(37.21,143.23) v1(37.21,142.6) v1(37.21,141.96) v1(37.17,19.68) v1(37.35,43.45) v1(37.35,42.2) v1(37.62,57.22) v1(37.62,29.7) v1(37.67,135.16) v1(37.67,129.7) v1(37.68,127.58) v1(37.84,143.87) v1(37.84,143.23) v1(37.84,142.6) v1(37.84,141.96) v1(37.93,145.82) v1(38.2,127.28) v1(38.31,66.22) v1(38.25,15.95) v1(38.25,15.31) v1(38.48,143.87) v1(38.48,143.23) v1(38.48,142.6) v1(38.48,141.96) v1(38.91,57.24) v1(38.91,56.65) v1(39.11,143.87) v1(39.11,143.23) v1(39.11,142.6) v1(39.11,141.96) v1(39.31,87.97) v1(39.54,97.2) v1(39.55,57.24) v1(39.55,56.65) v1(39.75,143.87) v1(39.75,143.23) v1(39.75,142.6) v1(39.75,141.96) v1(39.66,130.55) v1(39.73,127.84) v1(39.73,2.2) v1(39.75,94.41) v1(39.94,134.1) v1(39.9,13.71) v1(40.38,46.21) v1(40.85,22.39) v1(40.82,17.31) v1(40.82,12.23) v1(40.82,7.15) v1(40.97,46.24) v1(41.35,50.88) v1(41.56,126.22) v1(41.56,46.21) v1(41.67,125.52) v1(41.78,134.93) v1(41.78,50.37) v1(42.16,50.88) v1(42.27,96.02) v1(42.41,131.09) v1(42.45,50.37) v1(42.41,25.65) v1(42.93,84.15) v1(43.01,145.82) v1(43.23,117.89) v1(43.22,93.53) v1(43.33,25.65) v1(43.38,117.27) v1(43.36,116.69) v1(43.45,115.53) v1(43.4,114.15) v1(43.36,113.42) v1(43.46,116.11) v1(43.46,112.27) v1(43.61,91.92) v1(43.9,117.9) v1(43.97,117.27) v1(43.97,116.69) v1(43.98,95.78) v1(44.08,110.63) v1(44.22,25.65) v1(44.55,116.93) v1(44.47,108.03) v1(44.79,93.94) v1(44.92,107.61) v1(45.08,108.19) v1(45.2,69.8) v1(45.19,68.6) v1(45.24,67.15) v1(45.24,25.65) v1(45.36,94.79) v1(45.69,61.51) v1(45.8,23.53) v1(45.97,93.94) v1(46.1,25.65) v1(46.44,69.75) v1(46.45,67.79) v1(46.45,66.61) v1(47.62,51.55) v1(47.85,117.04) v1(48.09,145.82) v1(48.79,72.34) v1(48.79,69.42) v1(48.82,67.97) v1(48.81,61.46) v1(48.9,65.48) v1(48.9,64.29) v1(49.48,56.98) v1(49.47,55.08) v1(49.46,53.85) v1(49.58,52.12) v1(49.57,51.48) v1(50.11,61.52) v1(50.11,60.88) v1(50.35,67.59) v1(50.34,66.43) v1(50.4,68.83) v1(50.88,23.53) v1(51.37,59.83) v1(51.51,51.44) v1(51.76,57.02) v1(51.76,55.75) v1(51.78,54.58) v1(51.77,53.26) v1(52.49,66.74) v1(52.47,64.72) v1(52.6,51.37) v1(52.64,38.93) v1(52.71,69.18) v1(52.73,68) v1(53.13,151.9) v1(53.07,146.83) v1(53.32,61.4) v1(53.54,51.47) v1(53.58,55.28) v1(53.56,54.04) v1(53.56,52.74) v1(53.83,56.81) v1(54.26,39.46) v1(54.55,60.79) v1(54.57,53.72) v1(54.57,51.54) v1(55.05,64.85) v1(54.98,56.79) v1(55.23,28.29) v1(55.4,135.84) v1(55.4,134.95) v1(55.44,69.24) v1(55.42,68.07) v1(55.45,66.9) v1(55.51,65.74) v1(56.03,135.84) v1(56.03,134.95) v1(55.98,118.87) v1(55.98,118.18) v1(55.98,117.47) v1(55.97,116.81) v1(55.97,116.1) v1(55.97,114.71) v1(56.04,94.43) v1(55.99,51.37) v1(55.96,23.53) v1(56.45,98.64) v1(56.59,146.47) v1(56.55,100.32) v1(56.6,60.04) v1(56.78,35.74) v1(56.93,95.26) v1(56.9,40.55) v1(56.9,39.43) v1(56.9,38.31) v1(57.07,148.83) v1(57.08,51.36) v1(57.26,154.87) v1(57.27,99.5) v1(57.25,68.87) v1(57.27,66.96) v1(57.3,56.74) v1(57.33,56.14) v1(57.33,54.23) v1(57.33,52.96) v1(57.44,147.69) v1(57.44,146.13) v1(57.44,96.94) v1(57.75,96.15) v1(58.01,40.55) v1(58.01,39.43) v1(58.01,38.31) v1(58.08,51.43) v1(58.57,105.82) v1(58.74,147.69) v1(58.74,146.13) v1(58.73,98.24) v1(58.85,152.09) v1(58.99,56.68) v1(58.99,55.47) v1(58.98,53.6) v1(59.13,40.55) v1(59.13,39.43) v1(59.13,38.31) v1(59.22,69.83) v1(59.21,68.64) v1(59.19,67.38) v1(59.19,66.06) v1(59.2,64.81) v1(59.41,26.54) v1(59.56,152.09) v1(60.04,147.69) v1(60.04,146.13) v1(60.05,104.52) v1(60,29.44) v1(60,26.54) v1(60.2,52.08) v1(60.27,152.09) v1(60.27,28.87) v1(60.41,60.36) v1(60.39,59.73) v1(60.46,144.57) v1(60.59,146.83) v1(60.63,145.28) v1(60.6,61.43) v1(60.59,29.43) v1(60.63,26.54) v1(60.91,28.87) v1(60.99,152.09) v1(61.03,144.12) v1(61.04,23.53) v1(61.05,55.27) v1(61.23,145.49) v1(61.23,144.73) v1(61.18,29.42) v1(61.27,146.27) v1(61.28,34.46) v1(61.29,26.54) v1(61.52,147.88) v1(61.48,97.81) v1(61.6,28.87) v1(61.68,157.37) v1(61.78,145.91) v1(61.78,145.15) v1(61.78,144.39) v1(61.87,153.36) v1(62.03,68.76) v1(62,67.44) v1(62,66.62) v1(62,65.35) v1(62.13,147.88) v1(62.13,72.44) v1(62.07,64.09) v1(62.38,146.27) v1(62.35,145.54) v1(62.35,144.78) v1(62.5,55.41) v1(62.49,54.15) v1(62.49,52.88) v1(62.49,51.61) v1(62.58,97.99) v1(62.57,96.75) v1(62.76,153.36) v1(62.76,147.88) v1(62.95,145.83) v1(62.95,145.07) v1(62.95,144.3) v1(63.2,148.66) v1(64.18,67) v1(64.18,65.06) v1(64.34,98.12) v1(64.56,56.15) v1(64.57,54.8) v1(64.57,53.53) v1(64.7,95.54) v1(64.69,93.73) v1(64.69,36.57) v1(64.85,147.24) v1(64.78,96.7) v1(65.08,51.35) v1(65.3,154.51) v1(65.32,149.6) v1(65.34,97.87) v1(65.41,66.54) v1(65.46,67.82) v1(65.49,65.24) v1(65.7,148.46) v1(65.7,146.89) v1(65.87,56.77) v1(66.12,23.53) v1(66.15,54) v1(66.15,51.99) v1(66.32,154.25) v1(66.76,157.37) v1(67,148.46) v1(67,146.89) v1(67.08,118.85) v1(67.11,118.03) v1(67.05,110.91) v1(67.31,73.63) v1(67.31,73) v1(67.32,72.34) v1(67.33,64.74) v1(67.34,64.08) v1(68.02,52.85) v1(68.06,56.85) v1(68.07,55.47) v1(68.07,54.2) v1(68.29,148.46) v1(68.29,146.89) v1(68.57,51.33) v1(68.84,147.6) v1(68.78,146.14) v1(68.78,145.54) v1(68.86,134.19) v1(68.86,133.55) v1(68.91,51.98) v1(69.03,121.9) v1(69.01,97.31) v1(69.03,96.08) v1(69.09,145.03) v1(69.24,116.05) v1(69.24,114.78) v1(69.24,113.51) v1(69.27,117.3) v1(69.36,145.64) v1(69.36,64.74) v1(69.36,64.13) v1(69.53,147.03) v1(69.48,146.26) v1(69.49,134.19) v1(69.49,133.55) v1(69.65,148.61) v1(69.62,68.27) v1(69.58,66.66) v1(69.57,51.54) v1(69.6,36.63) v1(69.79,121.89) v1(69.9,145.29) v1(70.02,146.67) v1(70.02,145.91) v1(70.13,154.13) v1(70.23,148.64) v1(70.23,51.45) v1(70.18,36.64) v1(70.5,144.92) v1(70.5,111.55) v1(70.5,110.91) v1(70.57,147.04) v1(70.57,146.28) v1(70.57,145.52) v1(70.7,56.46) v1(70.72,55.64) v1(70.7,54.18) v1(70.7,52.65) v1(70.84,148.64) v1(70.81,67.13) v1(70.82,65.95) v1(71.02,154.13) v1(71.12,146.62) v1(71.12,145.86) v1(71.12,145.09) v1(71.06,52.04) v1(71.1,48.87) v1(71.2,23.53) v1(71.32,99.08) v1(71.32,97.18) v1(71.32,95.91) v1(71.32,94.64) v1(71.32,93.37) v1(71.44,148.66) v1(71.37,121.89) v1(71.58,119.12) v1(71.6,118.21) v1(71.57,52.68) v1(71.71,48.87) v1(71.84,157.37) v1(72.14,121.9) v1(72.13,117.1) v1(72.1,115.37) v1(72.09,113.63) v1(72.11,27.36) v1(72.22,154.51) v1(72.19,54.36) v1(72.29,48.87) v1(72.71,51.37) v1(72.72,27.36) v1(72.86,154.43) v1(73.1,147.24) v1(73.58,149.6) v1(73.57,51.36) v1(73.7,121.89) v1(73.88,111.53) v1(73.88,110.94) v1(73.91,98.99) v1(73.88,97.7) v1(73.9,96.32) v1(73.88,95.03) v1(73.95,93.82) v1(73.87,53.66) v1(73.95,148.46) v1(73.95,146.89) v1(74.52,121.89) v1(74.84,87.37) v1(74.84,86.76) v1(74.84,86.15) v1(74.84,85.54) v1(74.93,156.03) v1(75.05,115.56) v1(75.05,114.29) v1(75.07,116.78) v1(75.25,148.46) v1(75.25,146.89) v1(75.32,68.78) v1(75.32,67.61) v1(75.32,66.44) v1(75.31,64.89) v1(75.51,156.03) v1(76.12,156) v1(76.12,121.89) v1(76.28,23.53) v1(76.36,120.23) v1(76.42,119.59) v1(76.44,118.95) v1(76.41,118.17) v1(76.43,113.53) v1(76.41,112.64) v1(76.52,155.25) v1(76.55,148.46) v1(76.55,146.89) v1(76.56,154.53) v1(76.71,96.49) v1(76.71,95.22) v1(76.71,93.32) v1(76.71,92.05) v1(76.71,90.78) v1(76.92,157.37) v1(76.92,145.48) v1(76.86,121.9) v1(76.89,52.64) v1(77.1,147.6) v1(77.05,146.05) v1(77.11,111.45) v1(77.09,110.8) v1(77.2,34.83) v1(77.3,145.03) v1(77.44,67.76) v1(77.44,66.56) v1(77.41,65.37) v1(77.53,48.88) v1(77.63,145.63) v1(77.74,146.26) v1(77.75,148.62) v1(77.8,147.02) v1(77.78,113.02) v1(78.04,118.22) v1(78.03,116.41) v1(78.08,145.06) v1(78.08,114.58) v1(78.27,146.6) v1(78.27,145.84) v1(78.35,148.63) v1(78.46,121.89) v1(78.52,52.92) v1(78.47,51.63) v1(78.57,156.03) v1(78.82,147.04) v1(78.82,146.27) v1(78.82,145.55) v1(78.8,144.96) v1(78.96,148.62) v1(79.14,68.78) v1(79.13,66.78) v1(79.08,48.87) v1(79.24,121.89) v1(79.27,156.03) v1(79.4,146.65) v1(79.4,145.89) v1(79.4,145.12) v1(79.69,148.23) v1(79.9,156.03) v1(79.91,154.51) v1(80.48,116.4) v1(80.51,114.03) v1(80.47,48.87) v1(80.72,111.87) v1(80.75,111.26) v1(80.75,110.67) v1(80.81,154.51) v1(80.82,121.86) v1(80.79,87.53) v1(80.8,86.95) v1(80.8,86.36) v1(81.01,118.54) v1(81,52.49) v1(81.05,120.29) v1(81.11,119.38) v1(81.39,154.52) v1(81.36,147.24) v1(81.36,23.53) v1(81.54,92.02) v1(81.56,134.31) v1(81.56,133.55) v1(81.58,121.89) v1(81.57,97.99) v1(81.57,96.01) v1(81.58,94.07) v1(81.83,149.6) v1(82,157.37) v1(81.99,66.28) v1(81.99,65.05) v1(82.09,154.52) v1(82.05,48.86) v1(82.21,148.46) v1(82.21,146.89) v1(82.34,53.42) v1(82.39,51.64) v1(82.79,113.12) v1(83.18,121.86) v1(83.21,111.85) v1(83.51,148.46) v1(83.51,146.89) v1(83.49,118.49) v1(83.98,121.89) v1(84.16,111.33) v1(84.2,110.73) v1(84.5,67.32) v1(84.58,98.37) v1(84.8,148.46) v1(84.8,146.89) v1(85.31,146.14) v1(85.35,147.6) v1(85.4,145.57) v1(85.59,144.96) v1(85.63,111.83) v1(85.64,52.18) v1(85.71,56.24) v1(85.65,54.88) v1(85.67,53.66) v1(85.83,120.26) v1(85.83,119.65) v1(85.79,96.87) v1(85.94,117.87) v1(86,146.26) v1(86,145.49) v1(86.06,147.05) v1(86.34,148.61) v1(86.33,121.88) v1(86.39,153.24) v1(86.44,23.53) v1(86.55,146.62) v1(86.55,145.86) v1(86.55,145.09) v1(86.94,148.61) v1(87.02,68.32) v1(87.02,67.05) v1(87.02,65.86) v1(87.02,64.67) v1(87.08,157.37) v1(87.12,146.99) v1(87.12,146.23) v1(87.12,145.46) v1(87.1,116.1) v1(87.18,115.43) v1(87.18,114.82) v1(87.2,114.02) v1(87.27,153.24) v1(87.4,73.48) v1(87.58,148.61) v1(87.61,145.14) v1(87.64,52.65) v1(87.66,93.86) v1(87.69,89.49) v1(87.78,88.24) v1(87.78,86.97) v1(87.91,121.89) v1(87.95,142.36) v1(88.02,111.85) v1(88.32,117.89) v1(88.43,92.97) v1(88.69,121.89) v1(89.28,92.18) v1(89.52,68.3) v1(89.52,67.03) v1(89.53,65.91) v1(89.52,64.73) v1(89.76,141.21) v1(90.01,91.26) v1(90.11,152.58) v1(90.06,112.8) v1(90.23,143.57) v1(90.19,120.23) v1(90.19,119.42) v1(90.25,121.89) v1(90.39,55.79) v1(90.61,142.43) v1(90.61,140.87) v1(90.65,97.22) v1(90.62,54.4) v1(90.62,53.21) v1(90.64,52) v1(90.83,118.6) v1(90.83,61.08) v1(90.9,111.26) v1(90.88,110.64) v1(90.91,89.92) v1(91.1,153) v1(91.06,121.9) v1(91.17,155.56) v1(91.2,117.11) v1(91.24,115.31) v1(91.33,105.67) v1(91.35,96.01) v1(91.43,112.8) v1(91.52,149.82) v1(91.52,23.53) v1(91.74,66.65) v1(91.77,68.63) v1(91.77,65.41) v1(91.84,53.04) v1(91.9,142.43) v1(91.9,140.87) v1(91.86,54.37) v1(92.08,51.36) v1(92.16,157.37) v1(92.3,95.25) v1(92.4,155.25) v1(92.4,150.75) v1(92.46,59.8) v1(92.65,121.9) v1(92.83,48.87) v1(92.92,61.63) v1(92.89,60.83) v1(93.04,68.03) v1(93.01,54.42) v1(93.03,51.98) v1(93.08,69.2) v1(93.07,66.84) v1(93.2,142.43) v1(93.2,140.87) v1(93.24,117.98) v1(93.25,98.49) v1(93.41,121.91) v1(93.69,93.98) v1(93.72,72.4) v1(93.75,141.57) v1(93.79,139.99) v1(94.07,51.36) v1(94.2,97.66) v1(94.31,113.59) v1(94.35,112.33) v1(94.33,111.73) v1(94.34,111.13) v1(94.44,142.26) v1(94.43,140.37) v1(94.43,139.61) v1(94.35,112.93) v1(94.45,141.53) v1(94.5,140.95) v1(94.57,67.39) v1(94.58,66.21) v1(94.64,59.62) v1(94.69,61.61) v1(94.86,56.71) v1(94.9,54.76) v1(95,155.25) v1(95,150.75) v1(94.97,139.99) v1(95.03,99.19) v1(95.1,140.9) v1(95.07,51.36) v1(95.19,142.63) v1(95.16,96.77) v1(95.44,149.81) v1(95.55,140.53) v1(95.71,96.2) v1(95.91,119.45) v1(95.91,117.68) v1(95.91,115.9) v1(95.91,114.25) v1(95.95,142.63) v1(96.01,112.62) v1(95.98,66.9) v1(95.98,64.92) v1(96.12,155.56) v1(96.07,140.95) v1(96.07,51.36) v1(96.3,153) v1(96.32,97.88) v1(96.32,56.94) v1(96.33,55.66) v1(96.35,111.33) v1(96.37,54.4) v1(96.4,53.19) v1(96.6,142.62) v1(96.6,23.53) v1(96.72,140.79) v1(96.77,141.48) v1(96.86,112.72) v1(96.98,142.06) v1(96.97,113.46) v1(97.13,96.95) v1(97.07,51.36) v1(97.24,157.37) v1(97.22,152.54) v1(97.23,142.62) v1(97.41,141.48) v1(97.38,140.82) v1(97.74,61.44) v1(97.85,68.24) v1(97.85,67) v1(97.85,65.73) v1(98.07,51.36) v1(98.19,60.36) v1(98.31,55.52) v1(98.31,53.04) v1(98.36,54.34) v1(98.46,56.79) v1(99.3,73.93) v1(99.33,73.31) v1(99.32,72.71) v1(99.32,61.57) v1(99.4,65.74) v1(99.48,69.73) v1(99.46,68.38) v1(99.46,64.94) v1(99.6,59.62) v1(99.58,51.43) v1(99.72,86.43) v1(100.72,51.37) v1(100.79,54.63) v1(100.77,52.68) v1(101.24,132.54) v1(101.52,60.22) v1(101.71,69.34) v1(101.7,67.4) v1(101.69,66.19) v1(101.66,64.7) v1(101.68,23.53) v1(101.88,132.54) v1(101.88,131.9) v1(102.01,60.81) v1(102.32,157.37) v1(102.42,54.71) v1(102.39,52.53) v1(102.48,136.87) v1(102.48,135.57) v1(102.48,134.28) v1(102.51,132.54) v1(102.67,51.66) v1(102.83,137.72) v1(102.85,53.59) v1(103.19,133.73) v1(103.48,51.66) v1(103.83,60.4) v1(103.86,122.88) v1(103.92,52.76) v1(104.04,136.87) v1(104.04,135.57) v1(104.04,134.28) v1(103.95,61.61) v1(103.95,60.97) v1(104.01,55.34) v1(104.01,54.06) v1(104.14,67.51) v1(104.77,73.13) v1(105.35,60.38) v1(105.35,59.65) v1(105.38,69.05) v1(105.38,67.81) v1(105.41,66.52) v1(105.43,64.99) v1(105.76,149.7) v1(105.76,147.58) v1(105.76,145.46) v1(105.95,61.57) v1(106.05,51.85) v1(106.07,56.46) v1(106.05,54.35) v1(106.1,53.1) v1(106.76,23.53) v1(106.96,51.74) v1(107.2,68.4) v1(107.4,157.37) v1(107.47,55.67) v1(107.48,54.39) v1(107.81,59.78) v1(107.88,149.7) v1(107.88,147.58) v1(107.88,145.46) v1(107.94,53.64) v1(107.92,51.74) v1(108.04,107.75) v1(108.14,116.04) v1(108.13,114.57) v1(108.14,113.51) v1(108.18,112.1) v1(108.45,135.08) v1(108.45,134.37) v1(108.7,107.72) v1(108.72,60.92) v1(108.79,51.59) v1(109.17,54.54) v1(109.33,60.37) v1(109.43,114.91) v1(109.38,69.3) v1(109.36,68.09) v1(109.36,66.82) v1(109.37,65.56) v1(109.58,109.63) v1(109.79,112.33) v1(109.78,53.75) v1(109.91,117.38) v1(109.91,115.82) v1(109.92,113.37) v1(109.89,51.79) v1(110,149.7) v1(110,147.58) v1(110,145.46) v1(110.1,110.64) v1(110.58,114.89) v1(111.73,52.87) v1(111.82,154.87) v1(111.84,23.53) v1(111.95,138.1) v1(111.95,137.46) v1(111.95,136.83) v1(112,59.65) v1(112.42,55.18) v1(112.59,137.46) v1(112.59,136.83) v1(113.8,62) v1(113.8,61.35) v1(113.83,60.65) v1(116.07,152.08) v1(116.47,23.54) v1(116.69,147.04) v1(116.74,57.08) v1(116.74,56.4) v1(117.31,141.99) v1(117.32,57.09) v1(117.93,136.95) v1(118.14,29.28) v1(118.27,131.88) v1(118.27,126.8) v1(118.27,121.72) v1(118.27,116.64) v1(118.27,111.56) v1(118.27,106.48) v1(118.27,101.4) v1(118.33,96.32) v1(118.26,26.74) v1(118.99,91.29) v1(119.96,50.36) v1(119.96,49.74) v1(120.34,86.39) v1(120.8,30.94) v1(120.8,25.22) v1(121.44,81.43) v1(121.82,59.23) v1(122,23.53) v1(122.31,59.87) v1(122.43,64.16) v1(122.45,59.23) v1(122.56,60.43) v1(122.95,59.87) v1(123.08,59.23) v1(123.34,26.74) v1(123.47,29.28) v1(123.66,59.22) v1(124.02,77.05) v1(125.04,58.9) v1(125.04,58.27) v1(125.07,57.69) v1(125.1,57.1) v1(125.3,52.09) v1(125.43,54.77) v1(126.98,24.53) v1(127.92,73.8) v1(131,56.26) v1(131.04,55.67) v1(131.46,55.09) v1(131.62,70.31) v1(131.62,55.65) v1(131.65,44.53) v1(131.65,43.93) v1(131.76,46.36) v1(131.76,45.77) v1(132.06,24.53) v1(134.38,42.14) v1(134.38,40.94) v1(135.35,41.54) v1(135.76,67.38) v1(135.95,47.05) v1(136.32,42.14) v1(136.32,40.94) v1(136.51,46.84) v1(136.5,46.19) v1(136.92,47.35) v1(137.01,46.51) v1(137,45.72) v1(137.14,24.53) v1(137.43,46.92) v1(137.58,46.3) v1(137.58,45.72) v1(138.16,46.3) v1(138.19,45.69) v1(138.77,45.7) v1(140.27,65.05) v1(142.22,24.53) v1(143.79,39.37) v1(144.42,39.37) v1(145.07,63.36) v1(145.06,39.37) v1(145.69,39.37) v1(146.33,39.37) v1(146.96,39.37) v1(147.3,24.53) v1(147.6,39.37) v1(148.23,39.37) v1(150.05,62.37) v1(150.11,38.92) v1(152.38,24.53) v1(155.12,62.07) v1(155.31,44.37) v1(155.89,44.37) v1(156.27,38.92) v1(157.44,49.24) v1(157.46,24.53) v1(158.7,54.1) v1(158.68,51.32) v1(159.33,54.23) v1(160.05,54.23) v1(160.18,62.48) v1(160.27,38.15) v1(160.43,49.22) v1(160.79,54.25) v1(161.01,51.96) v1(161.43,54.22) v1(162.03,54.22) v1(162.54,51.28) v1(162.54,24.53) v1(162.8,54.2) v1(162.77,34.02) v1(162.78,32.56) v1(163.4,54.35) v1(163.38,32.56) v1(163.7,49.4) v1(165.14,63.6) v1(165.41,44) v1(165.86,49.39) v1(166.38,49.07) v1(167.52,23.53) v1(167.65,49.47) v1(168.78,49.2) v1(169.19,24.84) v1(169.89,65.39) v1(169.85,45.5) v1(172.5,24.71) v1(172.6,23.53) v1(173.11,24.71) v1(174.35,67.82) v1(177.28,24.71) v1(177.47,70.05) v1(177.68,23.53) v1(180.99,71.68) v1(181.11,69.14) v1(182.04,74.42) v1(182.76,23.55) v1(183.63,73.99) v1(183.65,67.62) v1(186.72,26.73) v1(186.84,68.89) v1(186.91,71.85) v1(187.01,55.15) v1(188.8,150.93) v1(188.79,84.67) v1(188.77,74.16) v1(189.37,145.29) v1(189.99,140.25) v1(190.03,89.6) v1(190.15,87.68) v1(190.27,85.14) v1(190.51,136.07) v1(190.92,94.6) v1(191.05,154.87) v1(191.15,149.52) v1(191.13,129.39) v1(191.13,125.08) v1(191.13,120) v1(191.13,114.92) v1(191.13,109.84) v1(191.13,104.76) v1(191.13,99.68) v1(191.47,28.53) v1(191.66,135.03) v1(191.83,76.03) v1(192.09,130.58) v1(192.09,123.86) v1(192.39,81.08) v1(192.54,124.25) v1(192.58,123.51) v1(192.81,89.34) v1(192.81,83.62) v1(193.03,127.33) v1(193.05,127.99) v1(193.17,30.07) v1(193.41,153.71) v1(193.4,150.79) v1(193.46,57.57) v1(193.74,43.18) v1(193.85,42) v1(193.86,40.64) v1(194.07,136.23) v1(194.41,129.83) v1(194.41,50.01) v1(194.84,128.08) v1(194.78,52) v1(194.78,51.36) v1(195.15,44.25) v1(195.15,39.75) v1(195.35,85.14) v1(195.47,157.37) v1(195.48,87.68) v1(195.66,128.13) v1(196.4,44.84) v1(196.4,39.12) v1(196.55,28.53) v1(197.75,44.25) v1(197.75,39.75) v1(197.89,48.97) v1(197.89,48.33) v1(198.94,40.64) v1(199.07,43.18) v1(199.05,42) v1(199.73,68.75) v1(199.73,66.74) v1(200,32.82) v1(200.18,63.69) v1(200.18,63.11) v1(200.18,62.52) v1(200.32,67.74) v1(200.55,157.37) v1(200.9,68.75) v1(200.9,66.74) v1(201.52,34.34) v1(201.52,32.82) v1(201.52,31.29) v1(201.63,28.53) v1(203.05,32.82) v1(203.11,43.43) v1(203.28,42.8) v1(203.8,76.73) v1(203.8,75.56) v1(203.99,50.87) v1(203.99,50.24) v1(204.62,50.87) v1(204.62,50.24) v1(204.81,76.15) v1(204.83,57.16) v1(205.63,157.37) v1(205.81,76.73) v1(205.81,75.56) v1(206.65,82.5) v1(206.65,81.86) v1(206.71,43.21) v1(206.71,41.6) v1(206.71,28.53) v1(207.98,43.2) v1(208,41.6) v1(208.06,40.22) v1(208.69,74.5) v1(208.69,73.86) v1(208.81,65.61) v1(208.81,64.72) v1(208.77,50.06) v1(208.94,70.18) v1(208.94,69.54) v1(208.94,68.91) v1(208.94,68.27) v1(208.91,67.26) v1(208.91,66.62) v1(209.19,40.22) v1(209.32,74.5) v1(209.32,73.86) v1(209.45,65.61) v1(209.45,64.72) v1(209.37,43.2) v1(209.37,41.59) v1(209.54,67.26) v1(209.54,66.62) v1(209.58,70.81) v1(209.58,70.18) v1(209.58,69.54) v1(209.58,68.91) v1(209.58,68.27) v1(209.96,63.7) v1(209.96,62.81) v1(210.21,71.45) v1(210.21,70.81) v1(210.21,70.18) v1(210.21,69.54) v1(210.21,68.91) v1(210.21,68.27) v1(210.71,157.37) v1(210.65,147.66) v1(210.85,71.45) v1(210.85,70.81) v1(210.85,70.18) v1(210.85,69.54) v1(210.85,68.91) v1(210.85,68.27) v1(211.24,50.06) v1(211.48,71.45) v1(211.48,70.81) v1(211.48,70.18) v1(211.48,69.54) v1(211.48,68.91) v1(211.48,68.27) v1(211.79,28.53) v1(212.12,71.45) v1(212.12,70.81) v1(212.12,70.18) v1(212.12,69.54) v1(212.12,68.91) v1(212.12,68.27) v1(212.24,82.12) v1(212.75,71.45) v1(212.75,70.81) v1(212.75,70.18) v1(212.75,69.54) v1(212.75,68.91) v1(212.75,68.27) v1(212.88,82.12) v1(213.13,84.66) v1(213.13,84.02) v1(213.13,83.39) v1(213.13,82.75) v1(213.29,34.64) v1(213.56,69.05) v1(213.75,35.04) v1(213.91,49.68) v1(214.11,69.76) v1(214.11,68.2) v1(214.19,35.43) v1(214.36,50.16) v1(214.58,29.82) v1(214.68,49.65) v1(214.78,41.41) v1(214.94,48.05) v1(215,50.41) v1(214.98,48.64) v1(215.1,49.23) v1(215.29,49.82) v1(215.41,69.76) v1(215.41,68.2) v1(215.64,48.77) v1(215.6,48.13) v1(215.67,52.4) v1(215.67,51.76) v1(215.67,51) v1(215.67,50.37) v1(215.68,49.35) v1(215.79,157.37) v1(216.12,62.3) v1(216.7,69.76) v1(216.7,68.2) v1(216.66,35.58) v1(216.75,62.3) v1(216.87,28.53) v1(216.99,73.72) v1(217.08,67.05) v1(217.25,35.58) v1(217.56,69.41) v1(217.83,35.58) v1(217.87,73.78) v1(218.42,35.58) v1(218.73,65.72) v1(218.83,91.05) v1(218.85,65.1) v1(219,35.58) v1(219.39,65.75) v1(219.49,65.13) v1(219.78,73.78) v1(219.86,64.21) v1(219.86,63.57) v1(219.86,62.94) v1(220.04,71.79) v1(219.99,62.3) v1(220.05,70.66) v1(220.12,70.05) v1(220.12,69.42) v1(220.11,68.82) v1(220.11,68.24) v1(220.21,154.87) v1(220.34,71.18) v1(220.33,53.77) v1(220.63,71.78) v1(220.75,69.96) v1(220.81,73.79) v1(220.75,70.56) v1(220.77,69.38) v1(220.75,68.78) v1(220.77,68.19) v1(220.93,71.12) v1(221.13,53.8) v1(221.32,84.66) v1(221.26,71.76) v1(221.4,70.77) v1(221.39,70.18) v1(221.39,69.54) v1(221.39,68.91) v1(221.39,68.27) v1(221.56,89) v1(221.65,71.3) v1(221.89,71.83) v1(221.95,28.53) v1(222.02,70.81) v1(222.02,70.18) v1(222.02,69.54) v1(222.02,68.91) v1(222.02,68.27) v1(222.08,73.79) v1(222.26,52.77) v1(222.4,71.45) v1(222.66,70.81) v1(222.66,70.18) v1(222.66,69.54) v1(222.66,68.91) v1(222.66,68.27) v1(223.03,52.77) v1(223.26,84.67) v1(223.44,69.26) v1(223.42,33.35) v1(223.42,32.71) v1(223.79,24.51) v1(223.99,69.96) v1(223.99,68.4) v1(224.04,52.77) v1(224.43,56.31) v1(224.8,52.77) v1(225.21,84.66) v1(225.29,154.87) v1(225.28,69.96) v1(225.28,68.4) v1(225.32,56.31) v1(225.44,150.94) v1(225.7,44.22) v1(225.7,43.64) v1(225.82,52.77) v1(226.23,62.13) v1(226.34,56.31) v1(226.32,29.15) v1(226.34,28.4) v1(226.58,69.96) v1(226.58,68.4) v1(226.58,52.77) v1(226.82,62.14) v1(226.96,67.26) v1(227.1,29.16) v1(227.1,28.4) v1(227.15,84.67) v1(227.43,69.62) v1(227.36,56.31) v1(227.86,29.03) v1(227.86,28.27) v1(227.99,37.64) v1(228.3,37.1) v1(228.37,73.82) v1(228.37,56.31) v1(228.37,52.46) v1(228.37,51.83) v1(228.58,37.64) v1(228.82,64.94) v1(228.78,24.33) v1(228.88,37.1) v1(229.07,84.68) v1(229.16,37.64) v1(229.37,66.23) v1(229.55,64.97) v1(229.46,37.1) v1(229.64,73.82) v1(229.63,65.65) v1(229.72,157.37) v1(229.79,64.14) v1(229.94,62.96) v1(229.93,62.36) v1(229.97,63.57) v1(230.15,72.08) v1(230.15,71.32) v1(230.15,70.69) v1(230.15,70.05) v1(230.15,69.42) v1(230.15,68.78) v1(230.15,68.15) v1(230.78,71.96) v1(230.78,71.32) v1(230.78,70.69) v1(230.78,70.05) v1(230.78,69.42) v1(230.78,68.78) v1(230.78,68.15) v1(230.91,73.84) v1(230.99,84.67) v1(231.42,72.08) v1(231.55,71.32) v1(231.55,70.69) v1(231.55,70.05) v1(231.55,69.42) v1(231.55,68.78) v1(231.55,68.15) v1(232.05,71.7) v1(232.18,73.84) v1(232.18,70.69) v1(232.18,70.05) v1(232.18,69.42) v1(232.18,68.78) v1(232.18,68.15) v1(232.74,42.48) v1(232.82,70.05) v1(232.82,69.42) v1(232.82,68.78) v1(232.87,68.19) v1(233.32,42.48) v1(233.52,69.13) v1(233.91,42.48) v1(233.86,24.33) v1(234.07,69.84) v1(234.07,68.27) v1(234.49,42.48) v1(234.8,157.37) v1(235.08,42.48) v1(235.37,69.84) v1(235.37,68.27) v1(235.74,75.28) v1(236.25,62.24) v1(236.34,28.29) v1(236.66,69.84) v1(236.66,68.27) v1(237.01,75.28) v1(237.04,67.13) v1(237.07,28.28) v1(237.51,69.49) v1(237.78,28.28) v1(237.86,33.32) v1(237.86,32.74) v1(238.15,75.28) v1(238.46,33.34) v1(238.46,28.27) v1(238.88,23.53) v1(239.2,65.09) v1(239.42,86.05) v1(239.42,73.73) v1(239.42,73.1) v1(239.42,72.46) v1(239.45,28.33) v1(239.81,64.65) v1(239.88,157.37) v1(240.06,86.05) v1(240.19,28.32) v1(240.82,84.78) v1(240.82,84.15) v1(240.82,83.51) v1(240.82,82.88) v1(240.88,53.25) v1(240.89,28.32) v1(241.52,53.25) v1(241.52,52.59) v1(241.57,28.32) v1(242.16,53.25) v1(242.16,52.59) v1(242.79,53.25) v1(242.79,52.59) v1(243.11,152.58) v1(243.11,74.23) v1(243.09,73.47) v1(243.11,72.74) v1(243.43,53.25) v1(243.43,52.59) v1(243.59,37.98) v1(243.59,37.37) v1(243.9,24.33) v1(244.06,53.25) v1(244.06,52.59) v1(244.17,155.56) v1(244.34,36.51) v1(244.34,35.93) v1(244.52,149.82) v1(244.7,53.25) v1(244.7,52.59) v1(245.31,157.36) v1(245.52,43.89) v1(245.64,81.61) v1(245.64,79.2) v1(245.81,44.4) v1(245.77,43.25) v1(246.15,43.76) v1(246.44,44.37) v1(246.49,43.24) v1(246.79,78.05) v1(246.93,89.83) v1(246.9,43.82) v1(247.04,44.4) v1(247.41,43.3) v1(247.51,43.87) v1(247.58,89.84) v1(247.65,45.12) v1(247.66,44.5) v1(248.1,43.31) v1(248.12,31.23) v1(248.17,89.85) v1(248.19,83.35) v1(248.19,43.89) v1(248.25,28.14) v1(248.3,45.11) v1(248.29,44.5) v1(248.44,149.81) v1(248.42,58.71) v1(248.73,43.26) v1(248.81,89.83) v1(248.76,31.23) v1(248.85,67.36) v1(248.85,65.84) v1(248.95,45.11) v1(248.93,44.5) v1(248.88,43.89) v1(248.88,28.14) v1(248.91,23.53) v1(249.05,55.8) v1(249.12,155.56) v1(249.07,77.93) v1(250.04,157.35) v1(250.22,58.68) v1(250.22,31.19) v1(250.22,30.55) v1(250.22,29.41) v1(250.22,28.78) v1(250.22,28.14) v1(250.38,67.36) v1(250.38,65.84) v1(250.38,64.31) v1(250.6,79.07) v1(251.9,65.84) v1(251.9,64.31) v1(252.07,58.64) v1(253.7,39.62) v1(253.77,25.03) v1(254.01,154.18) v1(254.11,76.48) v1(254.11,75.21) v1(254.11,74.58) v1(254.11,73.94) v1(254.31,39.62) v1(254.33,39.04) v1(254.87,76.48) v1(254.87,75.85) v1(254.87,75.21) v1(254.87,74.58) v1(254.87,73.94) v1(254.87,73.31) v1(255.63,76.48) v1(255.63,75.85) v1(255.63,75.21) v1(255.63,74.58) v1(255.63,73.94) v1(255.63,73.31) v1(255.73,58.48) v1(256.19,54.54) v1(256.16,45.79) v1(256.16,45.19) v1(256.32,149.66) v1(256.4,117.1) v1(256.4,103) v1(256.4,76.48) v1(256.4,75.85) v1(256.4,75.21) v1(256.4,74.58) v1(256.4,73.94) v1(256.4,73.31) v1(256.36,58.48) v1(256.57,37.06) v1(256.69,45.46) v1(256.69,34.47) v1(256.95,58.48) v1(258.38,34.11) v1(258.47,37.06) v1(258.63,145.13) v1(258.72,43.47) v1(258.85,25.03) v1(259.2,53.8) v1(259.22,53.19) v1(259.6,97.4) v1(259.55,34.11) v1(259.83,37.92) v1(259.89,119.22) v1(260.4,118.7) v1(260.4,117.9) v1(260.4,102.2) v1(260.4,101.4) v1(260.59,37.92) v1(260.93,140.61) v1(261.38,34.11) v1(262,30.3) v1(262.53,66.62) v1(262.8,102.2) v1(263.24,136.08) v1(263.17,66.62) v1(263.91,67.97) v1(263.93,25.03) v1(264.38,130.54) v1(264.54,68.59) v1(264.54,67.35) v1(265.07,78.43) v1(265.16,67.97) v1(265.54,131.55) v1(265.71,78.43) v1(265.82,54.6) v1(265.82,52.36) v1(266.52,78.45) v1(266.85,88.21) v1(266.85,87.58) v1(266.85,86.94) v1(266.93,53.48) v1(267.65,126.93) v1(268.04,121.86) v1(268.05,54.6) v1(268.05,52.36) v1(268.42,41.02) v1(268.49,38.63) v1(268.82,116.84) v1(269.01,25.03) v1(269.35,40.18) v1(269.59,111.82) v1(269.68,31.96) v1(270.16,74.89) v1(270.36,106.8) v1(270.65,73.52) v1(270.72,32.09) v1(270.92,78.59) v1(271.13,101.78) v1(271.29,41.9) v1(271.27,40.11) v1(271.91,96.76) v1(272.35,38.76) v1(272.68,91.74) v1(273.56,71.12) v1(273.66,86.75) v1(273.96,31.7) v1(273.96,25.03) v1(274.6,31.7) v1(274.84,81.81) v1(275.01,70.9) v1(275.23,31.7) v1(275.87,31.7) v1(276,64.59) v1(276,63.83) v1(277.01,64.59) v1(277.01,63.83) v1(276.99,32.87) v1(277.26,47.83) v1(277.34,28.25) v1(277.62,32.87) v1(278.03,64.59) v1(278.03,63.83) v1(278.24,33.59) v1(278.23,33.01) v1(278.32,50.81) v1(278.64,71.16) v1(278.67,45.07) v1(279.04,64.59) v1(279.04,63.83) v1(279.94,30.01) v1(281.35,66.86) v1(282.11,29.85) v1(282.42,40.57) v1(282.42,35.49) v1(282.59,45.06) v1(283.27,50.81) v1(283.41,62.22) v1(283.69,28.91) v1(284.92,57.37) v1(284.92,52.29) v1(284.92,47.21) v1(284.91,31.98) v3(17.59,133.07) v3(23.03,59.69) v3(47.38,115.56) v3(59.69,153.14) v3(62.85,155.57) v3(69.24,132.68) v3(72.26,155.51) v3(81.97,155.62) v3(86.63,143.58) v3(97.63,143.53) v3(109.36,135.98) v3(109.64,132.08) v3(116.27,55.61) v3(130.96,40.51) v3(132.37,55.88) v3(204.72,49.48) v3(207.76,66.72) v3(209.69,72.52) v3(220.56,150.94) v3(238.44,62.04) v3(243.23,54.62) v3(258.24,76.05) v3(260.35,73.58) v3(262.85,67.37) v3(267.21,89.03) v3(278.13,35.75)
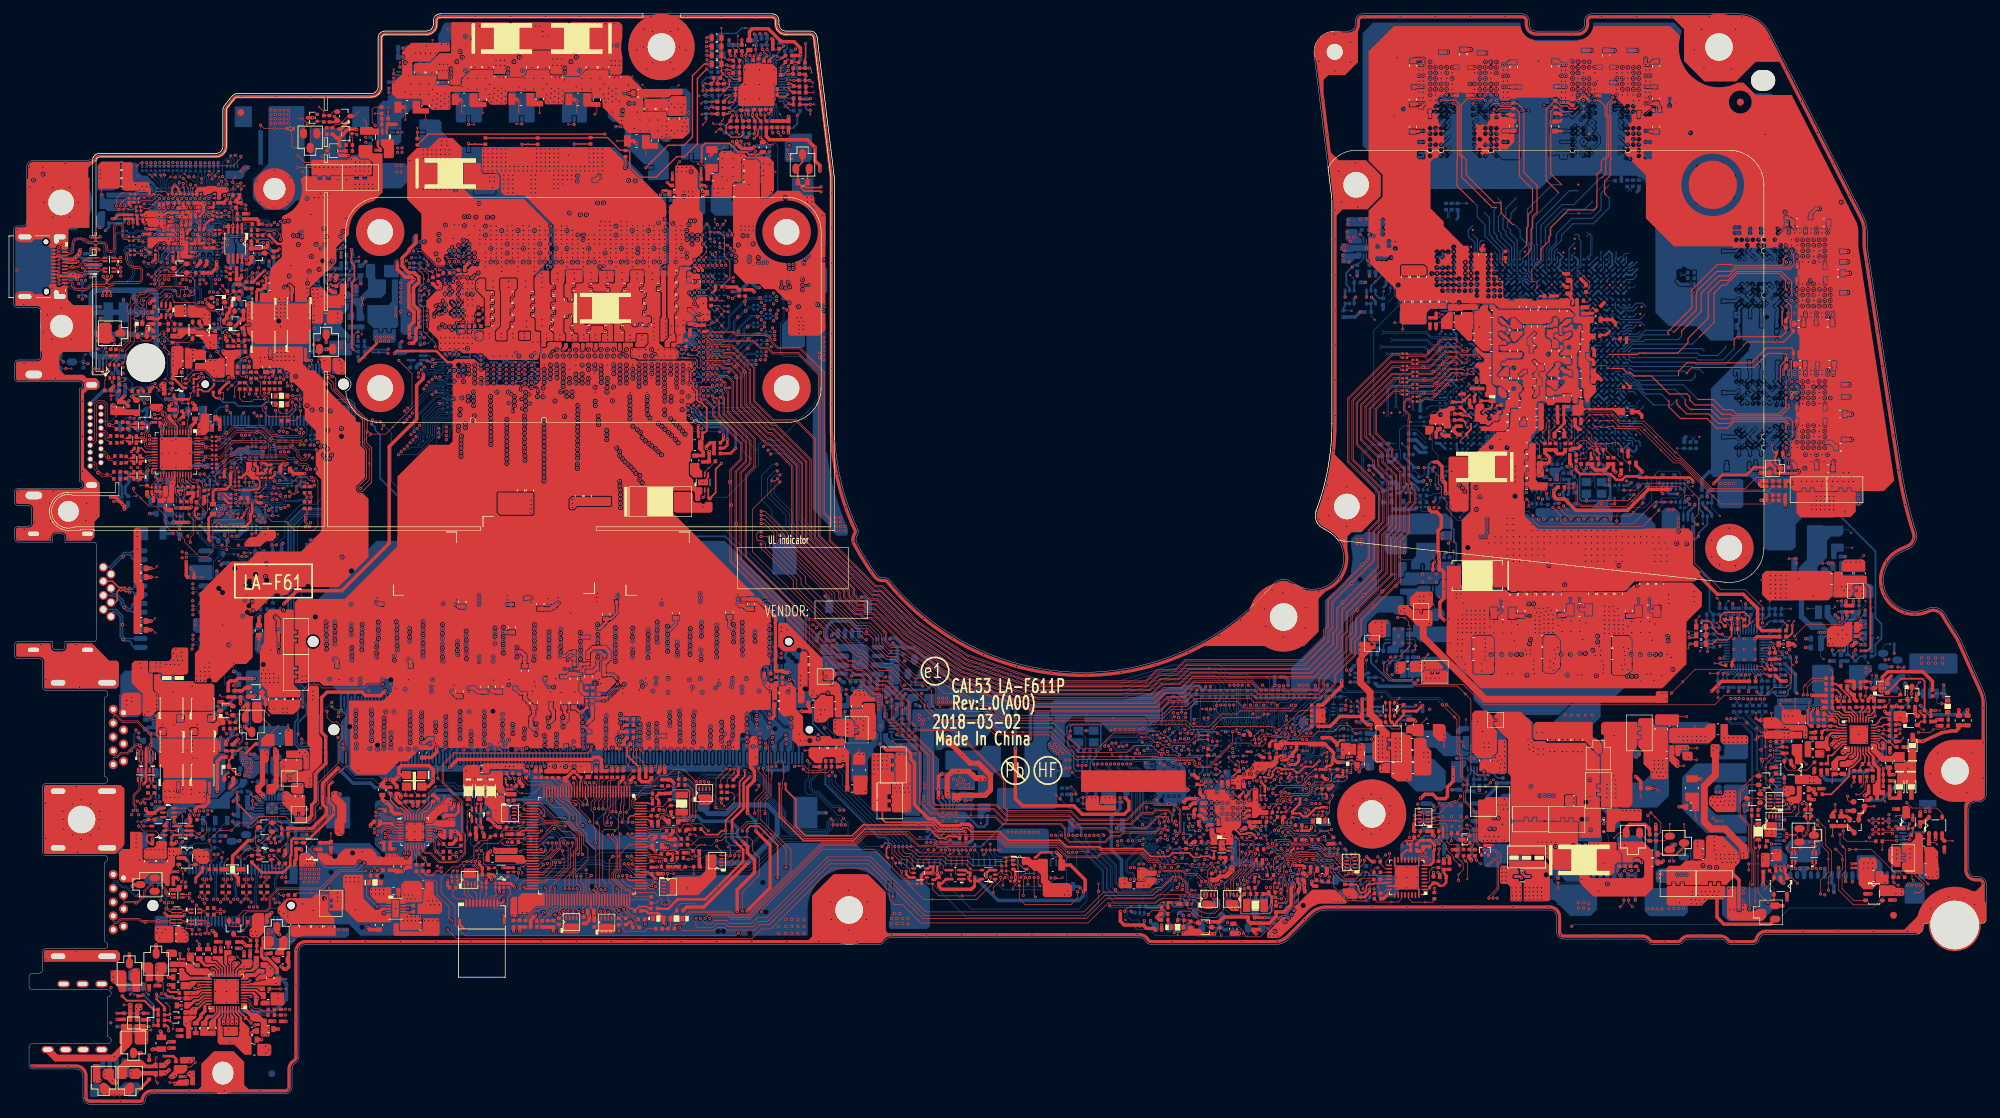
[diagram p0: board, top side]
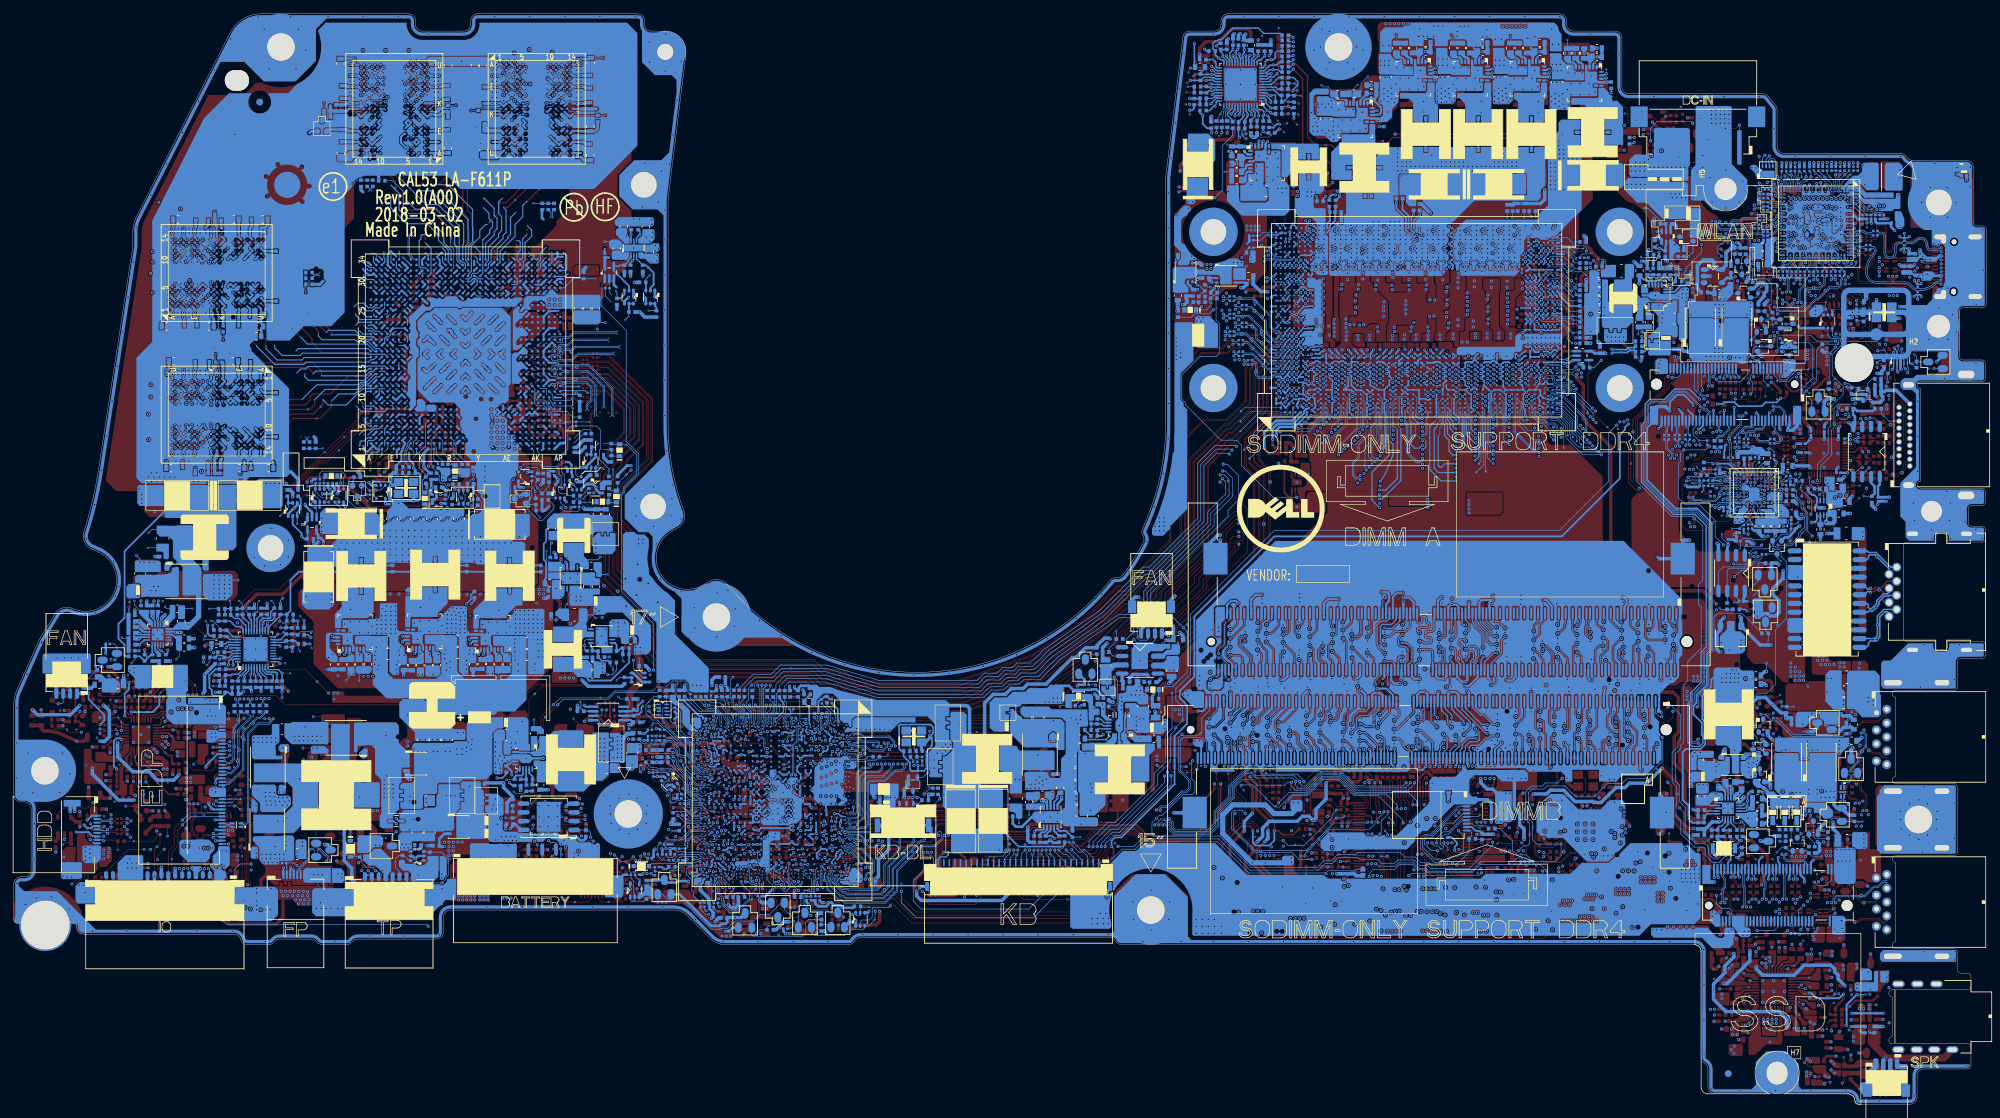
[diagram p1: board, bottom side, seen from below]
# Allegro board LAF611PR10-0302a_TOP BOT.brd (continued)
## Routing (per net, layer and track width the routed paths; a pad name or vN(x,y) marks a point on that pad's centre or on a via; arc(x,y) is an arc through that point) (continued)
GND_SENSE_VGA: length 5.8
  TOP w0.102: v1(257.3,69.32) 257.3,69.63 v2(257.57,69.9)
  TOP w0.254: PRV07.2 256.72,67.64 257.3,68.22 v1(257.3,69.32)
  BOTTOM w0.254: v1(257.3,69.32) 257.3,68.1 256.99,67.78 PRV09.1 ; 224.97,98.49 225.4,98.06 UV1.L5
VBAT_CHG: length 5.7
  TOP w0.203: PUB01.31 265.93,56.01 265.62,56.32 264.58,56.32 264.08,56.82 263.53,56.82 263.11,57.24 PRB68.2 PCB45.1 PRB39.2
VBUS_P_CTRL_P1: length 8.2
  TOP w0.102: PRS48.1 27.5,41.17 27.88,40.79 27.88,39.31 27.19,38.62 v1(26.43,38.62) 26.1,38.95 PUS03.1 ; v1(30.81,53.6) 30.35,54.05 PRS38.1
  BOTTOM w0.102: UT4.G11 34.32,85.72 34.32,85.58 v1(34.79,85.1)
VCC3V3_S0: length 1.6
  BOTTOM w0.102: LT4.1 v2(31.7,120.43)
  BOTTOM w0.254: UT1.R13 v1(26.26,126.5)
  vias: v1(30.4,125.27) v1(30.95,125.01) v1(30.89,124.34)
VCC_SA_SENSE: length 3.2
  TOP w0.127: v1(102.27,141.13) 102.02,141.13 v2(101.55,140.66)
  BOTTOM w0.254: v1(94.16,131.62) 94.64,131.62 95.02,131.24 RC275.2 ; v1(102.27,141.13) 102.34,141.13 PRZ05.1
VCC_SENSE: length 8
  TOP w0.127: v2(99.51,143.19) 99.65,143.34 v1(100.98,143.34)
  TOP w0.254: PRZ08.1 101.01,143.31 v1(100.98,143.34)
  BOTTOM w0.254: UC1.AG37 83.94,126.48 83.94,128.26 85.33,129.65 v1(85.33,130.45) RC10.1
VCC_VCCIO: length 2.2
  TOP w0.102: v1(49.51,118.45) v2(49.51,117.47)
  TOP w0.508: v1(45.5,118.1) 46.1,117.5 PC910.1
VCCDSW_ON: length 7.2
  TOP w0.102: v2(98.46,29.06) 96.48,29.06 95.91,28.48 RE164.2 95.02,27.14 DC2.2 95.02,25.77 RC442.1 94.64,25.39 RE163.2
VCCGT_SENSE: length 5.1
  TOP w0.127: v1(115.24,144.7) v2(115.79,144.7)
  TOP w0.254: PRZ40.2 115.21,144.67 v1(115.24,144.7)
  BOTTOM w0.254: RC12.1 v1(81.95,128.73) 82.79,127.89 UC1.AH38
VCCIO_EN: length 10.6
  TOP w0.102: v2(52.16,34.21) 52.59,33.78 v1(52.59,33.76) 52.91,34.09 53.19,34.09 CZ108.1 52.65,33.09 RZ108.2 52.55,32.62 DZ2.2
  BOTTOM w0.102: PR903.1 44.06,119.94 43.46,120.53 43.46,120.98 41.16,123.28 v1(41.16,124.41)
VCCIO_SENSE: length 16.5
  TOP w0.254: v1(49.07,109.28) 48.93,109.42 48.93,118.86 49.28,119.2 49.28,121.37 48.84,121.8 v2(48.84,122.17) v1(48.84,123.7)
  BOTTOM w0.254: v1(49.07,109.28) 49.44,108.91 RC272.2 ; v1(48.84,123.7) 49.02,123.52 PR911.2
VCCMPHY_SENSE: length 2.8
  TOP w0.102: TH139.1 168.66,31.72 v1(168.3,31.37)
  BOTTOM w0.089: UH1.K47 168.44,31.5 v1(168.3,31.37)
VCCST_EN: length 4.5
  TOP w0.102: v1(114.11,118.52) v2(115,118.52)
  BOTTOM w0.102: UZ15.4 114.61,119.03 v1(114.11,118.52) 113.88,118.52 RZ112.2 113.34,117.4 113.44,117.4 RZ111.2
VCCST_PWRGD_CPU: length 9.6
  TOP w0.102: v1(97.59,108.52) 97.72,108.39 98.92,108.39 99.3,108.01 99.3,106.62 99.2,106.52 99,106.52 98.88,106.64 98.88,107.69 98.6,107.97 v2(97.09,107.97) 96.79,107.97 96.69,108.07 96.69,108.47 97.23,109.02 RC269.2
  BOTTOM w0.076: v1(97.59,108.52) 97.72,108.39 UC1.H13
VCCSTG_EN: length 3.7
  TOP w0.102: v1(111.06,118.24) v2(111.06,118.95)
  BOTTOM w0.102: RZ49.1 111.77,117.04 111.66,117.04 CZ111.1 111.06,117.64 v1(111.06,118.24) 111.35,118.53 UZ9.4
VDD10: length 17.3
  TOP w0.203: UL1.8 54.63,38.03 CL18.1 ; 54.79,40.48 55.24,40.03 UL1.3 ; UL1.22 61.17,40.03 61.35,39.86 61.93,39.86 CL23.1 ; UL1.30 57.41,42.03 55.93,43.51
  TOP w0.381: CL6.1 53.27,40.64 54.63,40.64 54.79,40.48
  TOP w0.508: 55.93,43.51 55.33,44.11 55.33,44.89 CL5.1 55.67,44.96 55.99,44.63 v1(55.99,44.36) ; CL6.1 53,40.5 v1(52.68,40.19) ; v1(55.23,36.96) CL19.1 CL18.1 ; CL23.1 CL22.1 62.04,38.61 61.62,39.03 v1(61.62,39.32)
  vias: v1(62.23,43.46) v1(62.82,43.46) v1(63.17,43.97) v2(61.35,42.58)
VDD_1.2V: length 5.3
  TOP w0.254: v1(32.3,45.09) 32.3,43.56 v3(32.77,43.08) v1(34.49,41.36)
  BOTTOM w0.254: v1(32.3,45.09) 32.46,45.25 PRM03.2
VDD_CHG: length 25.9
  TOP w0.127: v2(273.34,53.05) 273.34,52.98 v1(272.88,52.52)
  TOP w0.203: 269.58,52.34 269.44,52.48 PUB01.18
  TOP w0.254: 269.58,52.34 269.82,52.09 269.82,51.56 269.93,51.46 270.43,51.46 PCB28.1
  TOP w0.381: PRB11.1 272.65,57.47 v1(272.37,57.76) 272.16,57.55 PRB60.1 ; PRB13.2 272.76,52.49 272.8,52.52 v1(272.88,52.52)
  TOP w0.508: v1(270.33,52.3) 270.51,52.12 PCB28.1 ; PRB09.2 v1(261.48,47.62)
  BOTTOM w0.508: v1(270.33,52.3) 270.33,50.3 268.14,48.11 265.77,48.11 264.57,46.9 262.2,46.9 v1(261.48,47.62) ; v1(272.88,52.52) 272.2,52.52 271.55,53.17 271.55,56.94 v1(272.37,57.76)
VDD_SENSE_VGA: length 3
  TOP w0.102: v2(255.98,69.87) v1(256.56,69.3)
  TOP w0.254: PRV11.2 256.57,68.71 256.57,69.28 v1(256.56,69.3)
  BOTTOM w0.254: v1(256.56,69.3) 256.56,68.79 PRV14.1 ; UV1.L4 225.4,97.26 224.97,97.69
VDDP_CHG: length 5.2
  TOP w0.203: PUB01.8 264.6,52.08 263.45,50.92 v2(263.45,50.88) ; PCB29.1 262.32,49.25 PRB09.1
  TOP w0.254: PCB29.1 262.48,49.41 262.48,50.47 263.03,50.47 v2(263.45,50.88)
VIN_+1.05V:
  vias: v3(134.93,55.5)
VIN_VCCIO:
  vias: v1(46.85,114.45) v1(46.89,113.77) v1(46.89,113.14) v2(47.44,113.41)
VSS_SA_SENSE: length 3.9
  TOP w0.127: v1(102.26,141.83) 101.26,141.83 v2(101.13,141.96)
  BOTTOM w0.254: v1(102.26,141.83) 102.63,141.83 103.13,141.33 103.73,141.33 PRZ02.1 ; v1(93.55,131.62) 93.55,131.32 94.03,130.83 RC276.2
VSS_SENSE: length 6.5
  TOP w0.127: v1(100.15,142.71) 100.15,142.23 v2(99.7,141.77)
  BOTTOM w0.254: UC1.AG38 83.57,128.61 84.44,129.47 v1(84.44,130.42) RC11.1 ; v1(100.15,142.71) PRZ10.1
VSSGT_SENSE: length 5.5
  TOP w0.127: v2(115.22,143.23) 115.24,143.24 v1(115.24,143.85)
  BOTTOM w0.254: UC1.AH37 83.17,126.49 83.17,128.4 v1(82.84,128.73) RC13.1 ; PRZ42.2 114.58,144.13 114.86,143.85 v1(115.24,143.85)
VSSIO_SENSE: length 4.3
  TOP w0.127: v1(47.34,123.26) v2(47.34,122.49)
  BOTTOM w0.254: v1(49.81,111.77) 49.62,111.77 49.2,111.35 49.2,109.97 49.49,109.68 RC273.2 ; v1(47.34,123.26) 47.35,123.26 PR912.2
VSSMPHY_SENSE: length 4.6
  TOP w0.102: v1(169.09,31.08) 169,30.99 TH138.1
  BOTTOM w0.089: UH1.K46 168.53,33.78 168.67,33.65 168.67,31.5 v1(169.09,31.08)
81215_ALERT: length 2.4
  BOTTOM w0.102: PUZ01.41 109.88,144.22 110.31,143.67 110.33,143.58 PRZ26.2
81215_SCLK: length 2.5
  BOTTOM w0.102: PUZ01.42 109.48,144.22 110.05,143.58 110.05,142.92 PRZ25.1
81215_SDIO: length 2.5
  BOTTOM w0.102: PRZ27.1 v2(110.81,143.28) 110.28,144.22 PUZ01.40
81215_VR_HOT: length 2.6
  BOTTOM w0.203: PUZ01.39 111.26,145.18 111.42,145.02 111.42,144.75 v2(111.94,144.23) 112.38,143.79 112.81,143.79 PRZ24.1
+CHARGER_SRC: length 6.5
  TOP w0.508: v1(249.59,28.14) 249.59,32.45 248.82,33.22 ; PD13.3 v1(255.93,28.73)
  vias: v1(220.5,37.92) v1(221.13,37.92) v1(221.77,37.92) v1(221.77,37.29) v1(221.77,36.65) v1(221.77,36.02) v1(222.4,37.92) v1(222.4,37.29) v1(222.4,36.65) v1(222.4,36.02) v1(223.04,37.92) v1(246.02,38.68) v1(246.02,38.05) v1(246.02,37.41) v1(246.02,36.78) v1(246.25,35.47) v1(246.28,36.14) v1(246.91,36.14) v1(246.91,35.51) v1(247.22,34.97) v1(247.47,53.02) v1(247.47,52.39) v1(247.55,36.14) v1(247.55,35.51) v1(247.85,34.97) v1(248.11,53.02) v1(248.11,52.39) v1(248.18,36.14) v1(248.18,35.51) v1(248.49,34.97) v1(248.74,53.02) v1(248.74,52.39) v1(248.82,36.14) v1(248.82,35.51) v1(249.12,34.97) v1(249.38,53.02) v1(249.38,52.39) v1(249.45,36.14) v1(249.45,35.51) v1(250.01,53.02) v1(250.01,52.39) v1(250.65,53.02) v1(250.65,52.39) v3(247.54,37.3)
+DC_IN: length 6.2
  TOP w0.381: PRS03.1 38.16,124.51 38.82,124.51
  TOP w0.508: PDB03.2 v1(274.52,45.88)
  BOTTOM w0.508: v1(34.48,119.68) 34.48,119.21 34.71,118.99 PR13.1 ; PU01.1 40.41,120.79 40.09,121.11 v1(40.09,121.38) ; PR36.1 v1(48.03,128.15)
  vias: v1(37.06,117.54) v1(37.82,116.55) v1(38.44,116.55) v1(39.27,116.53) v1(42.44,118.06) v1(42.42,117.45) v1(42.49,119.45) v1(43.5,131.21) v1(44.13,131.21) v1(44.35,131.75) v1(44.77,131.21) v1(44.98,131.75) v1(45.4,131.21) v1(45.62,131.75) v1(46.88,133.81) v1(47.51,133.81) v1(48.15,133.81) v1(49.39,133.12) v1(49.39,132.49) v1(50.03,133.12) v1(50.03,132.49) v1(50.66,133.12) v1(50.66,132.49) v1(51.3,133.12) v1(51.3,132.49) v1(51.93,133.12) v1(51.93,132.49) v3(42.95,128.76)
+DC_IN_SS: length 0.8
  TOP w0.508: PR11.1 30.63,110.69 v1(30.63,111.22)
  vias: v1(34.01,114.2) v1(34.02,113.58) v1(34.07,115.95) v1(34.07,115.37) v1(34.07,114.78) v1(34.6,114.22) v1(38.04,115.72) v1(38.04,115.14) v1(38.04,114.55) v1(38.04,113.97) v1(38.63,115.72) v1(38.63,115.14) v1(38.63,114.55) v1(38.63,113.97) v1(39.21,115.72) v1(39.21,115.14) v1(39.21,114.55) v1(39.21,113.97) v1(42.72,114.22) v1(42.77,116.36) v3(38.6,112.56)
+DCBAT_LCD: length 3
  TOP w0.127: v3(255.52,57.89) 255.96,57.45 255.96,56.84 ; 257.71,56.84 v3(257.71,58.61)
  vias: v1(256.15,56.17) v1(256.73,56.17) v1(257.31,56.16) v3(256.99,56.91)
+FB_A_VREFC0: length 9.3
  BOTTOM w0.305: 237.23,143.72 236.9,144.05 UV6.J14 ; UV7.J14 203.1,144.05
  BOTTOM w0.508: RV125.2 239.56,142.88 RV126.2 ; RV126.2 238.76,143.73 RV127.1 CV158.1 237.23,143.72 ; RV126.2 239.56,144.48 ; 201.06,144.04 CV200.1 203.08,144.04 203.1,144.05
+FB_B_VREFC1: length 9.7
  TOP w0.102: v2(255.92,95.34) RV141.2
  TOP w0.381: RV141.2 255.92,93.77 v1(256.03,93.66)
  BOTTOM w0.305: UV9.J14 256,127.09 ; UV8.J14 256,94.01
  BOTTOM w0.508: 256,127.09 256.27,127.36 CV199.1 v1(256.27,129.08) ; 256,94.01 256.03,93.98 v1(256.03,93.66) 256.3,93.38 CV177.1 RV142.1 RV140.2
+FB_PLLAVDD: length 5.5
  TOP w0.127: 206.85,112.46 206.55,112.17 v2(206.55,111.81)
  TOP w0.381: CV154.1 221.44,116.95 220.8,116.95
  TOP w0.457: CV153.1 228.55,107.6 228.4,107.75 228.02,107.75 227.71,108.06 CV937.1
  BOTTOM w0.305: UV1.U27 220.8,116.95 ; UV1.H17 228.4,107.75 ; UV1.K27 225.89,116.19 225.86,116.19 225.51,115.84
+GPCPLL_AVDD: length 3.2
  TOP w0.127: 205.77,114.5 206.21,114.5 206.44,114.27 v2(206.74,114.27)
  TOP w0.508: 205.77,114.5 CV833.1 RV583.1
  BOTTOM w0.305: 227.7,115.23 227.7,115.32 228,115.62 UV1.H26
+GPU_CORE: length 17.4
  TOP w0.508: 243.65,76.61 246.46,73.79 250.21,73.79 252.29,71.72 252.29,69.18 252.93,68.53 PRV11.1
  BOTTOM w0.381: UV1.V20 219,111.55
  vias: v1(213.39,81.23) v1(214.27,82.12) v1(214.27,81.23) v1(215.16,82.12) v1(215.16,81.23) v1(216.05,84.78) v1(216.05,83.89) v1(216.05,83.01) v1(216.05,82.12) v1(216.05,81.23) v1(216.05,80.34) v1(216.05,79.45) v1(216.05,78.56) v1(216.94,84.78) v1(216.94,83.89) v1(216.94,83.01) v1(216.94,82.12) v1(216.94,81.23) v1(216.94,80.34) v1(216.94,79.45) v1(216.94,78.56) v1(217.2,92.28) v1(217.2,91.64) v1(217.2,90.75) v1(217.2,90.12) v1(217.83,82.12) v1(217.83,81.23) v1(217.83,80.34) v1(217.83,79.45) v1(217.83,78.56) v1(218.72,82.12) v1(218.72,81.23) v1(218.72,80.34) v1(218.72,79.45) v1(218.72,78.56) v1(218.83,91.82) v1(219.61,83.89) v1(219.61,83.01) v1(219.61,82.12) v1(219.61,81.23) v1(219.61,80.34) v1(219.61,79.45) v1(220.5,83.01) v1(220.5,82.12) v1(220.5,81.23) v1(220.5,80.34) v1(220.5,79.45) v1(220.5,78.56) v1(220.56,84.66) v1(221.39,83.01) v1(221.39,82.12) v1(221.39,81.23) v1(221.39,80.34) v1(221.39,79.45) v1(221.39,78.56) v1(222.28,83.01) v1(222.28,82.12) v1(222.28,81.23) v1(222.5,84.67) v1(223.29,83.01) v1(223.29,82.12) v1(223.29,81.23) v1(224.31,83.01) v1(224.31,82.12) v1(224.31,81.23) v1(224.45,84.66) v1(225.32,83.01) v1(225.32,82.12) v1(225.32,81.23) v1(226.34,83.01) v1(226.34,82.12) v1(226.34,81.23) v1(226.39,84.67) v1(227.36,83.01) v1(227.36,82.12) v1(227.36,81.23) v1(227.36,80.34) v1(227.36,79.45) v1(227.36,78.56) v1(228.24,83.01) v1(228.24,82.12) v1(228.24,81.23) v1(228.24,80.34) v1(228.24,79.45) v1(228.24,78.56) v1(228.3,84.68) v1(229.13,83.01) v1(229.13,82.12) v1(229.13,81.23) v1(229.13,80.34) v1(229.13,79.45) v1(229.13,78.56) v1(230.02,83.01) v1(230.02,82.12) v1(230.02,81.23) v1(230.02,80.34) v1(230.02,79.45) v1(230.02,78.56) v1(230.22,84.67) v1(230.91,83.01) v1(230.91,82.12) v1(230.91,81.23) v1(230.91,80.34) v1(230.91,79.45) v1(231.8,83.01) v1(231.8,82.12) v1(231.8,81.23) v1(231.8,80.34) v1(231.8,79.45) v1(231.8,78.56) v1(232.69,82.12) v1(232.69,81.23) v1(232.69,80.34) v1(232.69,79.45) v1(232.69,78.56) v1(233.58,82.12) v1(233.58,81.23) v1(234.47,82.12) v1(234.47,81.23) v1(235.36,82.12) v1(235.36,81.23) v1(236.25,82.12) v1(236.25,81.23) v1(237.13,82.12) v1(237.13,81.23) v1(237.39,80.34) v1(237.39,79.45) v1(237.39,78.56) v1(238.02,82.12) v1(238.02,81.23) v1(238.28,80.34) v1(238.28,79.45) v1(238.28,78.56) v1(238.91,81.23) v1(239.17,80.34) v1(239.17,79.45) v1(239.17,78.56) v3(215.04,96.18)
+IFPX_PLLVDD: length 4.7
  TOP w0.305: 212.5,100.09 v2(212.91,100.5) 213,100.59 213.49,100.59 213.88,100.97 LG8.2 213.83,101.8 CG47.1
  BOTTOM w0.305: UV1.AF7 212.84,99.75 212.5,100.09
+LAN_VDD33: length 8.9
  TOP w0.203: UL1.32 56.61,41.78 56.35,42.04 55.86,42.04 ; CL7.1 57.35,35.74 57.56,35.95 57.56,36.6 57.41,36.75 UL1.11
  TOP w0.508: v1(61.42,43.99) 61.42,44.12 60.84,44.7 RL17.2 ; CL25.1 53.31,44.14 v1(53.75,43.7) 53.9,43.7 54.63,42.97 CL20.1 55.09,42.04 55.86,42.04
  vias: v1(54.09,35.93) v1(54.73,35.93) v1(55.36,35.93) v1(63.02,41.12) v1(63.63,41.12) v3(50.41,36.54)
+LCDVDD: length 1.5
  TOP w0.127: v3(259.33,49.2) 258.88,49.65 U1.1
+LCDVDD_LCD: length 4.4
  TOP w0.127: C2.1 252.77,53.81 v3(252.13,54.44) ; 253.38,53.07 v3(253.38,51.73) ; 253.24,53.29 252.57,53.29 v3(252.02,52.74)
  vias: v1(256.13,53.69) v1(256.13,53.11) v1(256.74,53.69) v1(256.74,53.11)
+LINE1_VREFO_L: length 2.7
  TOP w0.203: v1(26.18,16.74) 26.85,16.74 27.03,16.92 v2(27.09,16.92) 28.2,16.92 UA1.24
  TOP w0.381: DA8.1 v1(23.34,12.55)
+MIC2-VREFO: length 7.8
  TOP w0.203: UA1.23 26.76,17.31 v1(26.7,17.25)
  TOP w0.305: RA26.1 v1(19.46,13.16) ; RA25.1 v1(14.91,13.16)
  BOTTOM w0.305: v1(14.91,13.16) v1(19.46,13.16)
+PEX_PLL_HVDD: length 3.2
  TOP w0.127: 210.79,103.54 210.79,104.01 v2(210.5,104.3)
  TOP w0.508: 210.79,103.54 210.82,103.57 CV114.1 211.64,103.57 RV590.2
  BOTTOM w0.254: UV1.AH12 210.79,103.54
+PWR_SRC: length 15.7
  TOP w0.508: PRV23.2 247.07,61.19 v3(246.44,60.56) v1(245.64,59.76) ; PRB21.2 v1(259.96,53) ; PRB67.2 v1(281.39,57.1)
  BOTTOM w0.381: PR302.2 127.71,58.99 128.74,60.02 129.38,60.02 129.44,59.96 132.09,59.96 132.66,60.54 134.59,60.54 134.79,60.34
  vias: v1(42.75,46.03) v1(42.8,47.19) v1(42.8,46.61) v1(43.27,59.74) v1(43.27,59.13) v1(43.27,58.55) v1(47.38,110.12) v1(47.37,109.5) v1(51.89,99.03) v1(52.41,98.75) v1(53.01,98.75) v1(55.52,138.38) v1(55.52,137.74) v1(56.16,138.38) v1(56.16,137.74) v1(112.17,121.53) v1(112.17,120.94) v1(112.75,121.53) v1(112.75,120.94) v1(116.57,108.71) v1(116.57,108.08) v1(117.2,110.95) v1(117.2,110.31) v1(117.2,109.68) v1(117.2,109.04) v1(117.2,108.41) v1(117.2,107.77) v1(118.83,55.55) v1(118.82,54.96) v1(118.82,54.38) v1(118.97,84.89) v1(118.97,84.26) v1(118.97,83.62) v1(118.97,82.99) v1(119.61,84.89) v1(119.61,84.26) v1(119.61,83.62) v1(119.61,82.99) v1(120.24,83.62) v1(120.24,82.99) v1(120.65,54.94) v1(120.65,54.35) v1(120.65,53.77) v1(133.8,58.77) v1(133.8,58.18) v1(134.38,58.77) v1(134.38,58.18) v1(134.96,58.77) v1(134.96,58.18) v1(135.55,58.18) v1(136.13,58.18) v1(219.06,52.8) v1(219.1,52.02) v1(219.23,51.38) v1(219.61,52.4) v1(219.86,51.64) v1(219.86,51) v1(220.5,51.38) v1(220.5,50.62) v1(221.25,50.62) v1(221.26,51.38) v1(222.26,51.05) v1(222.91,51.05) v1(224.04,51.05) v1(224.67,51.05) v1(225.61,51.01) v1(226.25,51.01) v1(226.88,51.01) v1(227.44,51.43) v1(227.46,44.98) v1(227.46,44.37) v1(228.05,44.51) v1(228.05,43.89) v1(267.42,74.82) v1(267.42,74.18) v1(267.42,73.6) v1(267.97,63.14) v1(267.97,62.47) v1(268.57,62.77)
+PWR_SRC_AC: length 12.3
  TOP w0.508: v1(246.41,30.17) 246.41,27.06 247.42,26.05 254.06,26.05 PD13.2
  vias: v1(218.66,31.33) v1(218.66,30.74) v1(218.66,30.16) v1(218.66,29.57) v1(219.25,31.33) v1(219.25,30.74) v1(219.25,30.16) v1(219.25,29.57) v1(219.83,31.33) v1(219.83,30.74) v1(219.83,30.16) v1(219.83,29.57) v1(220.42,31.33) v1(220.42,30.74) v1(220.42,30.16) v1(220.42,29.57) v1(221,31.33) v1(221,30.74) v1(221,30.16) v1(221,29.57) v1(242.64,29.6) v1(242.74,29) v1(242.83,30.76) v1(242.85,30.17) v1(243.25,29.58) v1(243.48,30.81) v1(243.45,28.99) v1(243.61,30.17) v1(243.87,29.54) v1(244.12,30.81) v1(244.25,30.17) v1(244.17,28.99) v1(244.57,29.6) v1(244.75,30.81) v1(245.01,30.17) v1(245.39,30.81) v1(245.77,30.17) v1(246.02,30.81) v1(246.66,30.81) v3(240.98,29.16)
+RTC_CELL: length 48.3
  TOP w0.127: v1(180.96,27.01) 181,26.97 v2(181.62,26.97)
  TOP w0.381: RH697.2 180.95,27 v1(180.96,27.01)
  TOP w0.508: RE70.2 RE41.1 95.01,46.97 v1(95.5,46.48) ; RA12.2 v1(29.11,22.68) ; v1(105.47,38) 106.15,37.32 106.15,36.35 107.15,35.34 107.15,33.52 104.64,31.01 v1(104.64,27.91) ; RE7.1 96.3,41.07 v1(97.36,41.07)
  BOTTOM w0.381: Q26.3 189.03,30.38 184.46,25.81 183.26,25.81 182.94,26.12 182.39,26.12 182.14,26.36 C1.1
  BOTTOM w0.508: v1(95.5,46.48) 95.5,44.16 96.95,42.71 96.95,41.48 v1(97.36,41.07) 97.38,41.07 97.98,41.67 98.92,41.67 99.64,40.94 103.7,40.94 104.67,39.97 104.67,38.79 v1(105.47,38) ; D1.1 180.17,27.01 v1(180.96,27.01) 182.11,27.01 C1.1
+RTC_CELL_PCH: length 27.2
  TOP w0.508: v1(185.02,31.69) 185.02,31.46 184.79,31.23 184.79,28.87 v2(184.2,28.29) 183.72,27.81 RH531.2 182.61,27.14 181.67,26.19 CH226.1 179.31,26.19 CH225.1 178.91,26.2 178.59,26.52 RH697.1 178.5,27.09 175.1,27.09 R73.1 174.41,26.4 v1(173.2,26.4) ; v1(187.77,32.27) 187.77,31.84 188.05,31.56 RH83.1
  BOTTOM w0.381: C59.1 192.15,32.37 192.06,32.46 Q26.1 190.86,32.08 189.52,32.08 189.33,32.27 v1(187.77,32.27)
  BOTTOM w0.508: v1(173.2,26.4) 173.93,26.4 175.08,25.25 RH84.1
+RTC_CELL_VBAT: length 4.7
  TOP w0.203: UE1.122 91.72,41.21 92.04,40.89 CE14.1
  TOP w0.508: v1(94,41.41) 94.52,40.89 RE7.2 ; v1(92.41,40.2) 92.28,40.34 CE14.1
  BOTTOM w0.127: v1(94,41.41) 93.08,41.41 v2(92.8,41.69)
+RTC_VCC: length 2.5
  TOP w0.127: v1(265,32.23) v3(265,32.96)
  BOTTOM w0.508: JIOB1.11 v1(265,32.23) ; R1.2 168.82,27.66 v1(169.2,27.28)
+SDC_IN: length 11.3
  TOP w0.508: PDB02.2 272.4,44.3 v1(271.4,44.3) 271.37,44.32 PRB04.2 PRB05.1 ; v1(45.25,109.25) 45.3,109.29 PQ19.3
  BOTTOM w0.508: 42.98,108.96 43.72,108.96 44.01,109.25 v1(45.25,109.25) ; v1(22.01,44.4) 22.01,43.32 21.54,42.85 PQS06.3 19.85,41.82 PRS10.1
  vias: v1(21.87,45.29) v1(22.5,45.29) v1(22.64,44.4) v1(23.14,45.29) v1(23.28,44.4) v1(23.9,44.4) v1(24.45,45.54) v1(24.45,44.91) v1(25.68,45.54) v1(25.68,44.91) v1(26.42,61.97) v1(26.42,61.33) v1(26.91,45.11) v1(27,62.6) v1(27,61.97) v1(27,61.33) v1(27.52,45.12) v1(27.64,63.24) v1(27.64,62.6) v1(27.64,61.97) v1(27.64,61.33) v1(27.55,44.51) v1(28.27,63.87) v1(28.27,63.24) v1(28.27,62.6) v1(28.27,61.97) v1(35.68,108.04) v1(35.68,107.41) v1(36.28,108.05) v1(37.52,107.62) v1(38.1,109.37) v1(38.1,108.79) v1(38.1,108.2) v1(38.1,107.62) v1(38.68,109.37) v1(38.68,108.79) v1(38.68,108.2) v1(38.68,107.62) v1(39.27,109.37) v1(39.27,108.79) v1(39.27,108.2) v1(39.27,107.62) v1(39.85,108.2) v1(39.85,107.62) v1(40.51,108.2) v1(40.51,107.62) v1(41.55,33.98) v1(41.55,33.35) v1(41.55,32.71) v1(42.01,32.16) v1(42.19,33.98) v1(42.19,33.35) v1(42.19,32.71) v1(42.65,32.16) v1(42.82,33.98) v1(42.82,33.35) v1(42.82,32.71) v1(43.28,32.13) v1(43.46,33.98) v1(43.46,33.35) v1(43.46,32.71) v1(43.89,32.16) v1(44.09,33.98) v1(44.09,33.35) v1(44.09,32.71) v1(110.64,25.73) v1(110.64,24.71) v1(111.66,26.74) v1(111.66,25.73) v1(111.66,24.71) v1(112.55,26.74) v1(112.55,25.73) v1(112.55,24.71) v1(113.44,26.74) v1(113.44,25.73) v1(113.44,24.71) v1(114.33,26.74) v1(114.33,25.73) v1(114.33,24.71) v1(126.98,26.89) v1(126.98,26.13) v1(127.37,27.6) v1(127.74,26.89) v1(127.74,26.13) v1(128.2,27.6) v1(128.56,26.89) v1(128.56,26.13) v1(129.35,26.87) v1(129.35,26.11) v1(181.64,24.33) v1(182.27,24.33) v1(182.91,24.33) v1(190.98,29.26) v1(191.57,29.26) v1(192.15,29.26) v1(215.29,34.12) v1(215.29,33.54) v1(215.29,32.96) v1(215.29,32.37) v1(215.88,34.12) v1(215.88,33.54) v1(215.88,32.96) v1(215.88,32.37) v1(216.73,31.32) v1(216.73,30.73) v1(216.79,30.14) v1(216.76,29.56) v1(217.31,31.32) v1(217.32,30.73) v1(217.34,29.56) v1(217.37,30.14) v1(217.91,30.73) v1(217.93,29.56) v1(217.96,31.31) v1(217.96,30.14) v3(30.19,69.3)
+SP_PLLVDD: length 3.4
  TOP w0.305: RV585.1 209.29,99.92 CV52.1 209.54,99.67 v2(210.31,99.67) 210.51,99.67 210.88,99.3
  BOTTOM w0.305: 213.32,101.1 213.75,100.66 UV1.AE8
+TBTA_VBUS: length 9.2
  TOP w0.508: PCS15.1 35.46,70.39 v1(35.66,70.59) ; v1(19.67,115.92) 20.1,116.35 PRS26.1
  BOTTOM w0.508: v1(31.12,66.46) 32.7,66.46 35.44,69.19 PUS04.1 35.44,70.37 v1(35.66,70.59)
  vias: v1(6.51,122.79) v1(6.51,119.86) v1(8.15,122.22) v1(8.54,120.11) v1(8.75,122.25) v1(9.13,122.69) v1(9.15,120) v1(9.19,119.41) v1(9.54,123.11) v1(9.61,123.69) v1(9.73,119.88) v1(12.22,110.49) v1(14.46,110.62) v1(20.59,63.88) v1(20.56,63.29) v1(21.19,63.87) v1(21.16,63.29) v1(22.02,63.63) v1(22.68,63.63) v1(23.02,64.22) v1(23.05,65.24) v1(23.28,63.62) v1(23.58,64.85) v1(23.68,64.22) v1(23.9,63.61) v1(24.2,64.84) v1(24.29,65.42) v1(24.4,64.21) v1(29.64,85.75) v1(29.66,85.14) v1(30.02,86.21) v1(30.16,85.46) v1(30.38,86.69) v1(30.61,86.15) v1(35.18,84.52) v1(35.46,85.19) v1(35.7,84.23) v1(35.96,84.76) v1(36.33,84.23) v3(23.43,65.82)
+TBTA_VBUS_1:
  vias: v3(25.79,60.48)
+TP_VDD:
  vias: v1(226.86,33.17) v1(226.86,32.54) v1(232.41,37.46) v1(233.01,37.46) v3(229.27,30.82)
+TPAN_VDD: length 4.3
  TOP w0.127: U3.1 257.23,32.77 v3(258.04,31.96)
  TOP w0.381: R30.2 v1(254.91,34.45) ; U3.1 256.54,33.14 256.27,33.4 C48.1 256.27,34.04 256.09,34.21 v1(256.09,34.45)
  vias: v1(254.62,36.64) v1(255.24,36.64)
+V_DDR_REFA: length 11.5
  TOP w0.381: v1(87.28,61.6) 86.73,62.15 v2(86.6,62.15) RD10.2
  TOP w0.508: RD9.2 83.08,65.35 83.82,66.09 85.51,66.09 86.17,65.43 86.17,64.5 85.67,64.01 RD12.1 85.37,63.93 85.37,63.08 CD28.1 85.36,62.2 RD10.2
  BOTTOM w0.305: v1(87.28,61.6) 87.07,61.8 JDIMM1.164
+V_DDR_REFA_R: length 4.5
  TOP w0.127: v1(81.19,62.98) v2(79.64,62.98)
  TOP w0.381: v1(81.19,62.98) 81.66,62.98 82.01,63.33 CD30.1 83.02,63.69 RD9.1
  BOTTOM w0.254: v1(64.35,108.52) 64.35,108.48 UC1.BN13
+V_DDR_REFB: length 9.9
  TOP w0.305: v1(90.5,48.85) 90.35,48.85 88.7,50.5 v2(88.7,50.71) 88.7,51.56 89.21,52.07 RD19.2
  TOP w0.508: RD20.2 92.23,47.05 91.83,46.66 90.87,46.66 90.51,47.02 CD58.1 RD21.1 90.5,48.19 v1(90.5,48.85)
  BOTTOM w0.305: JDIMM2.164 90.08,49.07 90.3,48.85 v1(90.5,48.85)
+V_DDR_REFB_R: length 3.6
  TOP w0.127: v1(87.6,51.97) 87.2,52.38 v2(87.2,53.01)
  TOP w0.381: RD19.1 88.15,51.97 v1(87.6,51.97)
  TOP w0.508: CD59.1 88.29,52.6 RD19.1
  BOTTOM w0.254: v1(62.42,108.56) 62.74,108.24 UC1.BR13
+VCHGR: length 0.8
  TOP w0.127: v1(221.51,44.65) v3(220.73,44.65)
  vias: v1(222.15,44.65) v1(222.78,44.65) v1(227.58,41.24) v1(228.12,39.7)
+VDISPLAY_VCC: length 2.7
  TOP w0.127: v3(21.02,103.31) 21.02,103.41 20.65,103.79 v1(20.12,103.79)
  TOP w0.508: RV676.1 14.07,103.51 v1(14.48,103.92) ; v1(20.12,103.79) 19.66,103.33 RV677.1
  vias: v1(14.4,101.22) v1(14.39,100.63)
+VID_PLLVDD: length 3.3
  TOP w0.127: v2(210.31,97.86) 210.03,98.14 210.03,98.45
  TOP w0.305: 210.03,98.45 210.03,98.64 209.63,99.04 CV53.1 209.29,99.03 RV586.1
  BOTTOM w0.305: UV1.AD7 214.18,100.17
+XS_PLLVDD: length 4.8
  TOP w0.127: v2(214.22,100.68) 214.55,101.01 214.55,101.13
  TOP w0.305: 210.66,102.69 209.85,101.87 CV940.1 209.52,101.62 RV584.1
  TOP w0.381: 214.55,101.13 215.17,101.13 CV72.1
  BOTTOM w0.305: UV1.AD8 214.55,100.6 214.55,101.13
AC_B2B_ACOK: length 8.8
  TOP w0.102: PQ21.1 31.32,116.86 32.02,116.86 32.25,116.63 PQ16.1 33.13,117.19 33.13,118.52 PR2.1 33.56,118.96 33.56,119.36 v1(34.51,120.31) 35.07,120.31 v2(35.27,120.51)
  BOTTOM w0.102: PD10.1 34.76,120.07 v1(34.51,120.31)
AC_B2B_S1: length 23.6
  TOP w0.102: PQ16.2 31.92,114.45 v1(31.56,114.09) 31.27,113.8 PQ15.1 31.27,112.5 31.15,112.38 30.24,112.38 29.91,112.71 29.91,114.15 29.22,114.83 28.41,114.83 27.76,115.49 26.65,115.49 26.14,116 23.36,116 23.03,116.33 23.03,117.01 22.66,117.38 21.94,117.38 21.35,116.78 19.87,116.78 19.2,116.11 19.2,115.23 18.9,114.92 18.9,114.3 v2(18.76,114.16) 18.57,113.97 PQS11.1
  BOTTOM w0.102: PC22.1 32.95,114.78 PR22.2 31.56,114.27 v1(31.56,114.09)
AC_B2B_S1_A: length 5
  TOP w0.102: v1(34.43,117.38) PC7.1 PR2.2
  BOTTOM w0.102: v2(32.51,118.35) 33.02,117.84 PR100.1 33.02,116.99 33.28,116.73 PQ5.2 34.43,117.1 v1(34.43,117.38)
AC_B2B_S2: length 6.5
  TOP w0.102: PC10.1 PR17.1 32.5,109.69 PR51.1 31.77,110.49 PR11.2 31.75,110.62 v1(31.24,111.13) 31.24,111.28 v2(30.77,111.75)
  BOTTOM w0.102: v1(31.24,111.13) 32.05,110.33 PQ6.2
AC_B2B_S2_A: length 3.8
  BOTTOM w0.102: PR50.2 30.91,112.82 v2(30.8,112.71) ; PR50.2 30.59,113.69 30.49,113.59 PQ17.2 ; PR50.2 31.34,113.69 31.41,113.63 PQ18.1
AC_B2B_S2_B: length 4.7
  TOP w0.102: v1(43.35,109.91) 43.61,109.91 PQ19.2 44.22,108.56 44.01,108.34 v2(44.01,107.4) ; v1(34.05,107.51) PR47.2 34.05,106.7 PR48.1
AC_B2B_S2_G: length 7.1
  TOP w0.102: v3(42.72,106.64) 43.08,107 v1(43.08,107.64)
  TOP w0.254: PC6.2 37.4,105.94 PR12.1 37.54,105.46 v1(37.46,105.39)
  TOP w0.381: v1(43.08,107.64) PR9.2 42.2,107.76 PQ8.4 ; v1(45.19,110.22) PQ19.1 ; PQ4.4 v1(37.11,108.05)
AC_B2B_S2_SW: length 3.9
  TOP w0.102: PC23.1 33.48,109.7 PR51.2 33.4,109.78 PR52.2 33.42,110.58 v1(34.03,110.58)
  BOTTOM w0.102: PQ18.2 33.18,111.44 v1(34.03,110.58)
AC_DIS: length 3.9
  TOP w0.102: v1(278.02,56.98) v2(278.64,56.98) ; v1(78.22,31.37) 78.29,31.3 UE1.69
  TOP w0.254: PRB43.2 277.35,56.97 PRB45.1 v1(278.02,56.98)
AC_DIS1: length 5.2
  TOP w0.102: v1(27.73,116.46) 27.96,116.69 PQ21.2 ; PQB04.2 276.07,54.22 v2(276.31,54.22)
  TOP w0.254: PQB04.2 275.92,55.38 PRB23.1 PRB43.1 276.34,56.17 275.78,56.73 v1(275.78,56.86)
AC_OK: length 51.8
  TOP w0.102: v1(45.31,56.85) 45.31,55.97 45.98,55.3 46.76,55.3 47.5,54.56 47.5,52.87 47.03,52.4 47.03,49.48 44.04,46.49 44.04,43.44 43.67,43.07 43.67,41.51 42.76,40.61 40.34,40.61 39.3,41.64 35.46,41.64 34.52,40.7 32.55,40.7 v3(31.46,39.61) 29.7,39.61 v1(28.27,38.18) 28.27,37.76 28.53,37.5 28.53,34.86 28.27,34.61 PRB44.1
  BOTTOM w0.102: v1(35.43,121.07) 35.43,122.39 PR15.1 34.53,122.76 34.53,122.49 34.69,122.34 PD10.2 34.69,121.39 33.8,120.5 PR13.2 ; PRS33.1 28.22,38.23 v1(28.27,38.18) 27.86,37.77 26.14,37.77 PRS41.1
AC_PRESENT: length 7.8
  BOTTOM w0.102: DH1.2 193.08,34.83 189.66,34.83 RH533.1 189.19,35.56 188.95,35.8 188.25,35.8 188.18,35.88 186.68,35.88 UH1.BG42
AC_SW_PROCHOT: length 0.9
  TOP w0.102: v2(44.44,123.82) 45.03,124.42 v1(45.05,124.42)
ACAV_IN1: length 34.7
  TOP w0.254: PR65.1 28.85,102.54 29.24,102.16 v1(29.73,102.16)
  TOP w0.381: v1(46.06,46.61) 45.56,46.1 45.56,43.8 46.29,43.07 v3(46.29,42.24) 46.29,41.92 42.81,38.44 40.42,38.44 40.16,38.18 40.16,36.11 40,35.95 40,34.56 38.97,33.53 35.89,33.53 34.44,34.97 PRB41.1
  BOTTOM w0.254: v1(38.9,101.33) 38.14,101.33 37.87,101.6 36.41,101.6 35.83,101.01 32.47,101.01 31.93,101.56 30.33,101.56 v1(29.73,102.16)
  vias: v1(272.86,55.94)
ACAVIN_EC: length 2.6
  TOP w0.102: PQS22.6 67.56,40.57 67.73,40.41 PRS49.2 67.6,40 66.91,40.69 PQS22.5
ACIN_CHG: length 9.7
  TOP w0.102: v1(270.46,48.5) 270.46,48.73 v2(270.05,49.14)
  TOP w0.203: PUB01.19 269.71,52.88 v1(269.81,52.79)
  TOP w0.254: PRB05.2 PRB07.1 PCB26.1 v1(270.46,48.5)
  BOTTOM w0.254: v1(269.81,52.79) 269.97,52.95 270.52,52.95 270.88,52.58 270.88,48.92 v1(270.46,48.5)
ACOK_CHG: length 2.9
  TOP w0.203: PRB22.1 271.11,55.95 v2(270.25,55.95) 269.9,55.6 269.9,55.43 269.35,54.88 PUB01.24
ADP_CHG: length 2.4
  TOP w0.127: PRB04.1 270.46,44.09 v2(270.76,43.79)
  TOP w0.508: PRB70.1 269.58,44.79 PCB56.1
ADPIN: length 6
  TOP w0.127: 44.07,136.31 42.06,136.31 v3(41.06,137.31) ; v1(43.59,135.58) v3(41.01,135.58)
  vias: v1(44.22,135.58) v1(44.86,135.58) v1(45.49,135.58) v1(46.13,135.58) v1(46.76,135.58) v1(47.4,135.58) v1(48.03,135.58) v1(48.67,135.58) v1(49.44,136.32) v1(49.44,135.69) v1(49.44,135.05) v1(50.08,136.32) v1(50.08,135.69) v1(50.08,135.05) v1(50.71,136.32) v1(50.71,135.69) v1(50.71,135.05) v1(51.35,135.69) v1(51.35,135.05) v3(48.87,136.74)
ALERT#: length 3
  BOTTOM w0.102: U2.6 202.89,56.86 R28.2 203.31,57.29 203.31,58.1 v2(203.43,58.22)
ALL_GPWRGD: length 17.7
  TOP w0.102: v1(234.39,88.21) v2(233.81,87.63) 233.56,87.37 229.52,87.37 228.85,86.7 226.72,86.7 226.24,87.18 226.24,89.45 225.83,89.86 222.68,89.86 v1(222.44,89.62)
  BOTTOM w0.102: v1(222.44,89.62) 222.33,89.73 RV572.1 ; UV19.4 233.44,88.21 RV56.2 v1(234.39,88.21)
ALL_SYS_PWRGD: length 68.4
  TOP w0.102: v1(125.6,37.3) 125.6,37.31 v2(126.06,37.77) 126.8,37.77 127.05,37.52 127.05,36.34 128.14,35.24 RH105.2 128.66,34.9 129.64,33.92 129.64,33.63 129.81,33.46 UH14.2 ; RE42.1 v1(71.4,37.92)
  BOTTOM w0.102: v1(125.6,37.3) 123.28,37.3 122.19,38.39 111.04,38.39 106.52,33.87 96.61,33.87 95.67,34.81 94.59,34.81 93.71,35.7 90.9,35.7 90.58,35.38 88.01,35.38 87.5,34.86 85.61,34.86 85.15,35.33 82.72,35.33 81.92,34.53 80.82,34.53 80.41,34.12 74.8,34.12 71.4,37.52 v1(71.4,37.92)
ALWON: length 35.4
  TOP w0.102: v1(109.66,48.87) v2(109.66,47.85) 109.66,47.19 109.54,47.07 109.54,44.76 108.68,43.9 v1(108.68,42.09) ; UE1.121 v1(89.49,40.81) ; PQB10.2 265.56,43.77 265.3,44.02 v1(265.3,44.56)
  BOTTOM w0.102: v1(108.68,42.09) 108.86,41.9 108.86,39.86 105.71,36.71 98.36,36.71 94.37,40.69 89.61,40.69 v1(89.49,40.81)
  BOTTOM w0.203: v1(131.1,57.56) 131.1,57.64 130.93,57.8 PR506.1
AMBER_LED_BAT: length 3.6
  BOTTOM w0.102: v2(21.69,103.15) 22.02,103.47 R68.2 23.9,103.47 24.26,103.11 Q18.1
AUD_AGND: length 37
  TOP w0.127: v1(25.27,21.7) v3(25.27,22.44)
  TOP w0.203: v1(28.67,19.59) 29.04,19.59 29.35,19.28 UA1.19
  TOP w0.381: CA26.2 v1(31.01,22.71)
  TOP w0.457: CA7.2 v1(33.3,22.07)
  TOP w0.508: v1(21.18,10.55) 21.35,10.37 RA22.1 ; CA52.1 v1(22.45,9.04) ; CA20.1 v1(22.34,18.36) ; CA53.1 v1(23.65,9.86) ; RA40.2 v1(19.58,16.53) ; CA23.2 22.9,17.27 v1(22.37,17.27) ; CA36.2 v1(14.94,12.27) ; CA37.2 v1(19.55,12.22) ; CA51.1 v1(30,23.5) ; RA41.1 v1(22.63,19.38) ; RA17.1 v1(32.92,22.55) ; RA18.1 v1(23.65,10.74)
  GND1 w0.203: 8.97,7.23 JHP1.7 ; JHP1.7 11.13,7.23 ; JHP1.7 8.97,7.9 ; JHP1.7 11.13,7.9 ; JHP1.7 10.05,7.23
  VCC w0.203: 10.05,7.23 JHP1.7 ; JHP1.7 8.97,7.23 ; JHP1.7 11.13,7.23 ; JHP1.7 8.97,7.9 ; JHP1.7 11.13,7.9
  GND2 w0.203: 10.05,7.23 JHP1.7 ; JHP1.7 8.97,7.9 ; JHP1.7 11.13,7.9 ; JHP1.7 8.97,7.23 ; JHP1.7 11.13,7.23
  GND3 w0.203: 8.97,7.23 JHP1.7 ; JHP1.7 10.05,7.23 ; JHP1.7 8.97,7.9 ; JHP1.7 11.13,7.23 ; JHP1.7 11.13,7.9
  BOTTOM w0.381: CA41.2 v1(19.56,11.24)
  BOTTOM w0.508: CA42.2 v1(14.93,11.24)
  vias: v1(14.03,11.78) v1(14.06,16.86) v1(16.74,16.62) v1(18.71,17.36) v1(18.71,16.77) v1(25.91,21.7) v1(27.17,11) v1(27.78,11) v1(28.36,13.98)
AUD_HP1_JACK_L: length 8.2
  TOP w0.305: RA27.1 21.79,14.04 20.66,15.18 v1(20.66,15.94)
  BOTTOM w0.305: v1(20.66,15.94) 21.26,15.33 24.56,15.33 25.29,16.06 v1(25.6,16.06)
  vias: v2(26.26,15.92)
AUD_HP1_JACK_L1: length 6.8
  TOP w0.305: RA29.2 RA27.2 20.21,13.69 v3(19.74,14.15) 18.92,14.97 16.36,14.97 LA2.1
AUD_HP1_JACK_R: length 1.2
  TOP w0.254: v1(22.38,10.62) 22.38,11.15 22.12,11.4 RA31.1
  vias: v1(25.55,15.36)
AUD_HP1_JACK_R1: length 8.7
  TOP w0.305: v1(20.19,11.4) RA31.2 RA33.2 ; v1(18.71,15.87) 18.49,15.65 LA3.1
  BOTTOM w0.127: v1(18.71,15.87) v2(17.43,15.87)
  BOTTOM w0.305: v1(18.71,15.87) 20.19,14.39 v1(20.19,11.4)
AUD_PC_BEEP:
  vias: v2(35.12,20.31)
AUD_PC_BEEP_C: length 2.8
  TOP w0.102: RA23.1 33.71,24.23 v2(33.25,24.23) 32.2,24.23 DA3.1
AUD_SENSE_A: length 17.9
  TOP w0.102: v2(32.33,21.37) 33.16,20.55 CA7.1
  TOP w0.508: RA10.2 v1(20.43,17.14)
  BOTTOM w0.508: v1(20.43,17.14) 21.43,18.14 21.43,18.66 21.94,19.17 21.94,19.58 22.48,20.12 26.32,20.12 27.77,18.66 32.32,18.66 33.27,19.62 v1(33.27,19.91)
AUD_SPK_L+:
  vias: v1(25.43,6.2) v1(25.91,6.53) v1(30.37,12.28) v1(30.37,11.7)
AUD_SPK_L+_C: length 2
  TOP w0.127: RA15.2 25.61,5.39 v3(26.26,6.04)
  vias: v1(13.07,4.65) v1(13.07,4.05) v1(14.25,3.35) v1(14.81,3.13) v1(22.78,3.91) v1(23.34,4.09)
AUD_SPK_L-:
  vias: v1(26,4.66) v1(26,4.07) v1(30.98,12.28) v1(30.98,11.7) v3(25.44,4.46)
AUD_SPK_L-_C: length 0.9
  TOP w0.127: v3(22.57,3.16) 23.19,3.16 v1(23.4,2.95)
  vias: v1(11.62,5.54) v1(11.8,3.28) v1(12.21,5.54) v1(12.45,3.4)
AUD_SPK_R+:
  vias: v1(21.93,4.52) v1(22.44,4.95) v1(32.22,12.28) v1(32.22,11.7)
AUD_SPK_R+_C: length 1.4
  TOP w0.127: v3(20.82,3.06) 20.54,3.33 RA13.2
  vias: v1(16.96,4.71) v1(16.96,4.11)
AUD_SPK_R-:
  vias: v1(22,5.79) v1(22.44,6.26) v1(31.59,12.28) v1(31.59,11.7)
AUD_SPK_R-_C: length 1.2
  TOP w0.127: v2(20.64,6.78) 20.54,6.68 RA14.2
  vias: v1(15.01,4.67) v1(15.01,4.08)
AUD_VREF:
  vias: v2(25.53,17.02)
AUX_EN_WOWL: length 2.8
  TOP w0.102: TP74.1 78.19,28.47 78.56,28.47 78.69,28.6 UE1.70
AUX_ON: length 15.8
  TOP w0.102: v1(88,40.8) 88,41.15 88.19,41.34 88.19,43.18 88.29,43.29 UE1.3 ; v1(50.03,35.08) 49.23,34.29 v2(48.21,34.29) 44.99,34.29 43.59,35.69 43.59,36.07 41.93,37.72 UL2.4 40.86,37.84 RL6.2
BA: length 5
  TOP w0.127: PRB66.1 v3(263.13,38.81)
  TOP w0.508: PRB66.1 PRB65.2 265.32,40.25 PQB11.1
BA_PWR: length 11.2
  TOP w0.127: v1(263.5,42.47) v3(263.5,43.39)
  TOP w0.508: v1(263.5,42.47) 263.13,42.1 PRB66.2 ; v1(261.58,57.24) 261.75,57.4 PRB68.1 ; PRB69.2 v1(282.66,57.1)
  BOTTOM w0.508: v1(275.81,57.71) 277.15,56.36 281.93,56.36 v1(282.66,57.1)
BAT1_LED#: length 4.5
  TOP w0.102: v1(93.42,35.13) 93.34,35.2 RE18.1 91.84,34.81 UE1.106
  BOTTOM w0.102: v1(93.42,35.13) v2(92.61,35.13) ; Q17.1 29.55,110.57 v1(29.82,110.83)
BAT2_LED#: length 9.2
  TOP w0.102: v1(88.6,42.24) 89.09,42.74 UE1.1 89.09,46.06 88.86,46.29 88.86,47.43 RE21.1 88.84,49.06 v2(88.84,49.16)
  BOTTOM w0.102: v1(28.47,108.24) 28.47,108.6 28.17,108.9 Q17.4
BATGONE_CHG: length 10.1
  TOP w0.102: v1(268.69,61.01) 268.83,61.16 v2(268.83,62.09)
  TOP w0.203: PUB01.25 268.33,55.87 268.4,55.94 269.03,55.94 v1(269.3,56.21)
  TOP w0.254: PCB34.1 PRB24.1 267.28,61.17 PRB25.1 268.53,61.17 v1(268.69,61.01)
  BOTTOM w0.254: v1(269.3,56.21) 269.3,59.4 268.69,60.01 v1(268.69,61.01)
BATLOW#: length 4.1
  BOTTOM w0.076: UT1.F2 22.11,132.31 22.11,133.42
  BOTTOM w0.102: 22.11,133.42 22.11,133.72 v2(22.61,134.22) 23.01,134.63 RT14.1 RT31.2
BATT+: length 4.3
  TOP w0.508: PQB11.3 265.17,41.64 PRB65.1 v1(264.38,42.44) ; v1(260.11,59.21) 260.17,59.14 PRB39.1
  vias: v1(219.48,45.98)
BATT++:
  vias: v1(203.7,35.99) v1(203.81,35.39) v1(204.25,36.35) v1(204.29,35.75) v1(204.29,35.06) v1(204.81,35.44) v1(205.77,38.15) v1(206.17,37.71) v1(212.6,38.15) v1(212.87,38.72) v1(213.22,38.15) v1(213.49,38.72) v1(213.83,38.15) v1(214.14,38.72) v1(214.41,38.15) v1(214.73,43.31) v1(214.8,38.72) v1(215.33,43.32) v1(215.53,42.69) v1(215.91,43.32) v1(216.12,42.69) v3(215.38,40.51) v3(215.62,38.21) v3(215.66,44.14)
BATT_WHITE_LED_R#: length 14.4
  TOP w0.102: v1(7.53,106.46) v2(8.31,106.46)
  BOTTOM w0.102: Q22.1 170.4,27.68 v1(170.04,27.33) ; v1(21.79,110.43) 24.5,110.43 25.36,111.29 30.05,111.29 30.23,111.11 30.23,109.57 Q17.3 ; v1(7.53,106.46) 7.53,106.45 Q19.2
BBS_BIT0: length 3.2
  TOP w0.102: RH130.2 182.09,42.77 v2(182.53,43.21) 182.66,43.34 183.23,43.34 v1(183.74,43.85)
  BOTTOM w0.102: UH1.BA26 v1(183.74,43.85)
BEEP: length 34.4
  TOP w0.102: v1(66.97,36.68) 68.02,37.73 70.08,37.73 70.78,38.43 73.78,38.43 74.16,38.81 UE1.45 ; v1(50.93,33.75) 50.83,33.64 47.2,33.64 v2(45.81,32.26) 44.62,31.06 38.33,31.06 37.17,29.91 37.17,28.42 36.59,27.84 33.72,27.84 33.21,27.32 33.21,26.07 32.85,25.72 31.36,25.72 31.14,25.94 DA3.3
BGATE_CHG: length 8.9
  TOP w0.102: v1(237.03,45.72) 237.53,45.72 v3(237.96,45.29)
  TOP w0.203: v1(262.6,56.75) 262.86,56.49 263.84,56.49 264.38,55.95 265.42,55.95 265.53,55.84 PUB01.32
  TOP w0.508: PRB61.2 v1(237.03,45.72)
  BOTTOM w0.381: v1(223.04,37.29) 223.67,37.29 PCB33.1 223.8,38.4 223.06,39.14 PQB03.4
BKLT_CTRL: length 9.7
  TOP w0.102: RP1.8 253.94,42.04 254.72,42.82 254.72,43.48 254.54,43.67 RP2.7 253.74,43.67 253.12,44.28 D3.1 251.43,43.59 R9.1 250.79,42.58 v2(250.39,42.19)
BKLT_IN_EC: length 15.4
  TOP w0.102: RE157.1 74.02,26.86 74.19,27.04 74.51,27.04 75.4,27.93 v2(75.85,27.93) 76.16,28.24 77,28.24 77.49,28.74 UE1.67 77.49,30.36 77.55,30.42 77.55,31.32 80.54,34.31 80.54,36.99 80.81,37.25 v1(80.81,37.81)
  BOTTOM w0.089: UH1.AV46 v1(181.87,34.37)
BLON_OUT_C: length 5.5
  TOP w0.102: RP1.7 254.44,41.95 255.28,42.8 RP2.1 256.18,43.17 v1(256.47,43.46) 256.47,43.44 256.88,43.03 v2(256.88,42.68)
  BOTTOM w0.102: JEDP1.28 256.16,43.15 v1(256.47,43.46)
BOARD_ID: length 10.6
  TOP w0.102: UE1.111 91.5,36.81 92.21,36.1 93.55,36.1 CE2.1 94.16,36.71 95.64,36.71 RE6.2 96.47,36.9 97.99,36.9 RE1.2 99.14,37.54 v2(100,37.54)
BOOT1_CHG:
  vias: v2(266,49.55)
BOOT2_CHG:
  vias: v2(262.53,53.29)
BST_1.2V: length 1.3
  BOTTOM w0.102: PRM02.1 37.88,46.7 v2(39.1,46.7)
BST_1.2V_R: length 0.9
  BOTTOM w0.102: 35.38,46.65 v2(34.48,46.65)
BST_3V: length 0.8
  TOP w0.102: v1(209.7,51.76) 209.55,51.92 v3(209.55,52.48)
BST_5V:
  vias: v2(122.53,52.91)
BST_+1.05V: length 0.9
  TOP w0.102: v1(137.66,43.95) v2(138.51,43.95)
BST_VCCIO: length 1.1
  BOTTOM w0.102: v2(50.33,111.42) 50.33,112.32 PC907.1
BT_RADIO_DIS#: length 7.6
  TOP w0.102: v1(38.58,102.81) 38.18,102.81 DN2.1 ; RH706.2 187.58,47.45 v2(187.38,47.24) 186.97,46.84 186.97,46.56 186.22,45.81 183.96,45.81 v1(183.31,45.16)
  BOTTOM w0.102: v1(183.31,45.16) UH1.BA24
BT_RADIO_DIS#_R: length 6.8
  TOP w0.102: v2(41.44,102.58) 41.39,102.53 v1(40.34,102.53) 40.31,102.5 DN2.2
  BOTTOM w0.102: v1(40.34,102.53) 40.91,102.53 41.7,103.32 JWLAN1.54
BUSPOWER#: length 5.2
  BOTTOM w0.076: UT4.F10 33.8,86.24 33.8,85.82 33.98,85.64 33.98,85.51
  BOTTOM w0.102: v2(36.77,83.3) RT74.2 35.17,83.81 RT163.1 34.44,84.44 34.44,84.87 33.98,85.33 33.98,85.51
BYPSRC: length 9.7
  TOP w0.203: 267.18,49.95 267.18,51 267.13,51.05 PUB01.13
  TOP w0.254: 267.18,49.95 266.05,48.82 265.88,48.82 265.53,48.47 265.53,47.46 v2(264.54,46.47) 262.93,44.86 PRB50.2
CAP_LED: length 39.7
  TOP w0.102: v1(41.81,57.49) 41.81,59.9 42.71,60.8 44.09,60.8 44.65,60.23 50.79,60.23 51.35,60.79 v1(53.32,60.79)
  BOTTOM w0.102: v1(41.81,57.49) 41.61,57.7 41.61,59.08 40.13,60.56 40.13,64.96 39.37,65.71 39.37,70.48 38.8,71.06 35.34,71.06 R25.2 ; JKB.27 149.2,33.58 v1(150.04,32.74)
CAP_LED#: length 15.2
  TOP w0.102: UE1.93 87.89,31.19 86.53,32.55 86.53,33.44 87.13,34.04 87.13,37.81 v1(86,38.95)
  BOTTOM w0.102: R24.2 32.36,78.31 32.45,78.4 v2(32.88,78.4) 33,78.28 Q6.3 33,75.74 v1(33.6,75.13)
CAP_LED_Q: length 3
  BOTTOM w0.102: v2(31.52,67) R25.1 31.93,68.55 Q7.1
CAP_LED_R#: length 5
  BOTTOM w0.102: Q7.2 30.96,72.62 32.03,73.68 Q6.1 32.77,74.5 v2(33.63,73.63)
CATERR#: length 3.2
  TOP w0.102: TC96.1 62.94,122.36 63.95,122.36 v1(64.36,121.94)
  BOTTOM w0.102: UC1.BM30 64.69,121.62 v1(64.36,121.94) ; RC263.2 v1(59.41,124.79)
CBN: length 2.8
  TOP w0.203: v1(26.47,14.45) 26.72,14.45 v2(27.03,14.76) 27.58,15.31 UA1.28
  TOP w0.254: CA24.2 v1(26.31,10.98)
CBP: length 3.8
  TOP w0.203: UA1.30 27.9,14.51 27.63,14.25 27.63,14.07
  TOP w0.508: 27.63,14.07 27.63,13.47 v2(27.07,12.9) 27.07,12.56 26.31,11.81 CA24.1
CFG0: length 7.9
  TOP w0.102: TPC10.1 64.68,118.31 v1(64.37,117.99)
  BOTTOM w0.102: RC255.1 60.25,114.76 61.85,116.36 63.48,116.36 63.73,116.61 63.73,117.3 UC1.BN25 64.37,117.94 v1(64.37,117.99)
CFG1: length 1.1
  TOP w0.102: TPC11.1 63.56,119.44 v1(63.69,119.56)
  BOTTOM w0.102: v1(63.69,119.56) 64.04,119.22 UC1.BN27
CFG2: length 6.7
  TOP w0.102: TPC12.1 63.42,117.64 v1(63.07,117.99)
  BOTTOM w0.076: RC258.1 60.35,116.28 62.07,117.99 v1(63.07,117.99) 63.63,117.99 UC1.BN26
CFG3: length 7
  TOP w0.102: TPC13.1 58.97,123.42 61.19,121.19 62.17,121.19 RC250.1 63.66,120.31 v1(63.69,120.34)
  BOTTOM w0.102: v1(63.69,120.34) 64.04,119.99 UC1.BN28
CFG4: length 5.3
  TOP w0.102: TPC14.1 v1(59.8,113.47)
  BOTTOM w0.102: RC257.1 59.02,113.47 v1(59.8,113.47) 60.07,113.74 61.74,113.74 61.96,113.96 62.44,113.96 UC1.BR20
CFG5: length 6.8
  BOTTOM w0.102: UC1.BM20 64.27,113.26 61.48,113.26 59.83,111.61 TPC15.1 59.73,111.68 RC256.1
CFG6: length 3.8
  BOTTOM w0.102: RC253.1 59.27,112.94 TPC16.1 60.33,112.94 60.85,113.46 61.87,113.46 UC1.BT20
CFG7: length 5.8
  TOP w0.102: TPC17.1 59.79,114.08 v1(59.8,114.07)
  BOTTOM w0.102: UC1.BP20 62.9,114.15 61.87,114.15 61.68,113.97 59.91,113.97 v1(59.8,114.07) 59.73,113.99 RC254.1
CFG8: length 1.3
  TOP w0.102: v1(62.42,115.67) 62.08,116.01 TPC20.1
  BOTTOM w0.102: v1(62.42,115.67) 62.74,115.99 UC1.BR23
CFG9: length 1.1
  TOP w0.102: TPC21.1 62.04,114.46 v1(62.43,114.86)
  BOTTOM w0.102: v1(62.43,114.86) 62.43,114.94 UC1.BR22
CFG10: length 1.3
  TOP w0.102: v1(61.75,115.67) 61.2,115.67 TPC22.1
  BOTTOM w0.102: UC1.BT23 61.75,115.7 v1(61.75,115.67)
CFG11: length 2.1
  TOP w0.102: v1(61.52,115.12) 60.81,114.41 TPC23.1
  BOTTOM w0.102: v1(61.52,115.12) 61.96,115.12 UC1.BT22
CFG12: length 1.5
  TOP w0.102: TPC24.1 64.81,113.09 v1(65,113.28)
  BOTTOM w0.102: UC1.BM19 64.69,112.97 v1(65,113.28)
CFG13: length 1.1
  TOP w0.102: TPC25.1 62.05,112.86 v1(62.41,112.51)
  BOTTOM w0.102: v1(62.41,112.51) 62.74,112.84 UC1.BR19
CFG14: length 1.1
  TOP w0.102: TPC26.1 63.34,112.21 v1(63.05,112.5)
  BOTTOM w0.102: v1(63.05,112.5) 63.39,112.83 UC1.BP19
CFG15: length 4
  BOTTOM w0.102: UC1.BT19 61.5,112.88 60.64,112.03 60.64,110.86 TPC27.1
CFG16: length 1.1
  TOP w0.102: v1(63.71,115.64) 63.71,115.72 TPC19.1
  BOTTOM w0.102: UC1.BP23 63.39,115.96 v1(63.71,115.64)
CFG17: length 1
  TOP w0.102: v1(64.34,115.65) 64.68,115.99 TPC18.1
  BOTTOM w0.102: UC1.BN23 64.04,115.95 v1(64.34,115.65)
CFG18: length 1.1
  TOP w0.102: TPC29.1 64.68,114.56 v1(64.37,114.86)
  BOTTOM w0.102: v1(64.37,114.86) 64.04,115.2 UC1.BN22
CFG19: length 1.1
  TOP w0.102: v1(63.71,114.85) 63.34,114.48 TPC28.1
  BOTTOM w0.102: UC1.BP22 63.39,115.17 v1(63.71,114.85)
CFG_RCOMP: length 4.3
  BOTTOM w0.254: UC1.BT25 61.63,117.16 61.63,116.98 60.17,115.52 v2(59.77,115.52) RC19.1
CHG_AMBER_LED_R#: length 13.4
  BOTTOM w0.102: Q18.2 25.22,101.78 26.56,103.11 26.56,103.61 25.08,105.08 v2(25.08,107.83) 25.08,109.64 25.64,110.2 Q17.6
CLK_CNV_PRX_DTX_N: length 1.7
  BOTTOM w0.102: UH1.BD4 185.18,54.16 v1(184.94,53.91) ; v1(35.75,95.02) 35.92,95.19 35.92,95.64 R3008.1
CLK_CNV_PRX_DTX_P: length 1.5
  BOTTOM w0.102: R3010.1 36.13,95.64 36.13,95.23 v1(36.34,95.02) ; UH1.BE3 185.17,54.86 v1(185.05,54.98)
CLK_CNV_PRX_R_DTX_N: length 4.1
  BOTTOM w0.102: JWLAN1.21 33.45,98.3 33.88,97.87 34.85,97.87 35.88,96.84 35.88,96.61 R3008.2
CLK_CNV_PRX_R_DTX_P: length 4.1
  BOTTOM w0.102: R3010.2 36.09,96.69 36.09,96.92 34.94,98.08 33.97,98.08 33.83,98.21 33.83,98.37 33.95,98.48 JWLAN1.23
CLK_CNV_PTX_DRX_N: length 3.8
  BOTTOM w0.089: v1(184.37,53.16) 184.38,53.16 184.38,53.56 UH1.BC5
  BOTTOM w0.102: v1(45.1,93.42) 45.3,93.62 45.3,94.14 46.15,94.99 46.15,96 R3025.1
CLK_CNV_PTX_DRX_P: length 3.9
  BOTTOM w0.102: UH1.BB6 183.98,53.16 183.98,53.49 v1(183.91,53.57) ; v1(45.69,93.42) 45.51,93.6 45.51,94.06 46.35,94.9 46.35,96 R3026.1
CLK_CNV_PTX_R_DRX_N: length 2.3
  BOTTOM w0.102: R3025.2 46.16,97.02 46.16,97.28 46.1,97.34 46.1,97.96 45.95,98.11 JWLAN1.71
CLK_CNV_PTX_R_DRX_P: length 2.3
  BOTTOM w0.102: R3026.2 46.37,96.99 46.37,97.36 46.3,97.43 46.3,97.96 46.45,98.11 JWLAN1.73
CLK_PCIE_N0: length 3.3
  BOTTOM w0.089: UH1.AJ6 177.52,53.13 176.98,53.13 176.68,52.83 176.68,51.82 v1(176.33,51.48)
  BOTTOM w0.094: UT1.T19 v1(26.26,123.9)
CLK_PCIE_N7: length 2.4
  BOTTOM w0.089: v1(173.42,52.52) 173.42,52.93 173.2,53.15 172.79,53.15 172.61,52.97 172.61,52.85 UH1.W7
  BOTTOM w0.102: UV1.AK13 209.91,104.39
CLK_PCIE_N9: length 13
  BOTTOM w0.089: UH1.U2 171.81,55.04 172.06,54.8 172.06,52.62 172.7,51.98 172.7,47.81 v1(172.86,47.66)
  BOTTOM w0.102: v1(29.56,36.16) 29.37,35.97 29.37,35.63 28.87,35.13 26.41,35.13 26.23,34.95 26.23,34.85 26.37,34.7 JSSD1.53
CLK_PCIE_N14: length 45.2
  TOP w0.102: v1(82.98,51.72) 83.36,51.34 83.36,51.2 83.09,50.93 63.71,50.93 61.97,49.19 61.97,46.48 64.76,43.7 64.76,39.34 65.16,38.94 65.16,36.35 63.98,35.17 61.58,35.17 60.28,36.47 59.58,36.47 59.32,36.73 59.32,36.98 59.41,37.08 UL1.16
  BOTTOM w0.089: v1(170.73,55.09) 170.9,55.09 UH1.T2
CLK_PCIE_N15: length 71
  BOTTOM w0.089: v1(172.22,55.87) 172.06,55.71 172.06,55.48 172.12,55.42 172.31,55.42 172.45,55.56 172.63,55.56 172.64,55.55 172.64,55.44 172.75,55.44 172.77,55.42 172.77,55.18 172.62,55.03 172.55,55.03 UH1.V2
  BOTTOM w0.102: v1(41.63,52.83) 41.86,52.83 41.94,52.75 41.94,52.53 42.01,52.45 42.56,52.45 42.65,52.54 42.65,57.77 42.24,58.18 42.24,59.31 40.74,60.81 40.74,65.21 40,65.95 40,83.97 41.91,85.88 45.02,85.88 49.35,90.21 49.35,98.01 48.84,98.51 48.84,101.13 48.49,101.49 46.32,101.49 44.84,102.97 43.46,102.97 40.92,100.44 40.49,100.44 40.16,100.1 40.16,99.86 40.26,99.76 40.38,99.76 40.45,99.69 JWLAN1.49
CLK_PCIE_P0: length 3.6
  BOTTOM w0.089: v1(176.34,50.88) 176.73,51.27 176.73,51.61 176.87,51.74 176.87,52.75 177.06,52.94 177.46,52.94 177.6,52.8 UH1.AJ7
  BOTTOM w0.094: UT1.V19 27.24,124.23 v1(26.91,123.9)
CLK_PCIE_P7: length 2.4
  BOTTOM w0.089: v1(174.11,52.51) 173.22,53.4 UH1.W6
  BOTTOM w0.102: UV1.AL13 208.72,104.8 209.1,104.42
CLK_PCIE_P9: length 13.1
  BOTTOM w0.089: UH1.U3 171.72,54.78 171.62,54.78 171.49,54.65 171.49,54.51 171.59,54.41 171.8,54.41 171.86,54.35 171.86,52.54 172.51,51.9 172.51,47.9 v1(172.27,47.66)
  BOTTOM w0.102: JSSD1.55 25.87,34.68 26.02,34.82 26.02,35.03 26.32,35.33 28.78,35.33 29.16,35.71 29.16,35.97 v1(28.97,36.16)
CLK_PCIE_P14: length 45.9
  TOP w0.102: UL1.15 59.01,37.05 59.11,36.96 59.11,36.65 59.49,36.26 60.19,36.26 61.49,34.96 64.07,34.96 65.36,36.26 65.36,39.03 64.96,39.43 64.96,43.79 62.18,46.57 62.18,49.11 63.79,50.72 83.17,50.72 83.57,51.12 v1(83.57,51.72)
  BOTTOM w0.089: v1(170.77,55.7) 170.89,55.81 UH1.T1
CLK_PCIE_P15: length 71.2
  BOTTOM w0.089: UH1.V3 172.42,54.56 172.96,55.1 172.96,55.5 172.83,55.63 v1(172.83,55.9)
  BOTTOM w0.102: v1(41.63,52.25) 42.65,52.25 42.86,52.46 42.86,57.86 42.45,58.26 42.45,59.39 40.94,60.9 40.94,65.3 40.2,66.04 40.2,83.89 41.99,85.68 45.11,85.68 49.56,90.13 49.56,98.09 49.05,98.6 49.05,101.22 48.57,101.7 46.41,101.7 44.93,103.18 43.38,103.18 40.84,100.64 40.41,100.64 39.95,100.18 JWLAN1.47
CLK_SMB: length 3.2
  TOP w0.102: v1(207.98,38.15) PR42.1
  BOTTOM w0.102: PBATT1.7 206.9,37.69 207.09,37.87 207.7,37.87 v1(207.98,38.15)
CLK_TP_SIO: length 11.3
  TOP w0.102: R32.2 234.7,34.44 C27.1 235.03,34.11 v1(235.03,33.8) ; v1(233.63,29.53) 233.63,29.11 v3(234.15,28.59) ; v1(81.42,33.01) 81.42,31.96 81.99,31.39 81.99,30.81 81.89,30.71 UE1.78
  BOTTOM w0.102: v1(235.03,33.8) 234.55,33.32 JTP.1 234.55,31.89 233.63,30.97 v1(233.63,29.53)
CLKREQ_CNV#: length 5.7
  TOP w0.102: v1(27.15,105.75) 26.24,105.75 RH725.1 25.95,105.54 25.46,105.05 25.46,104.7 25.07,104.3 QH9.2 24.5,104.3 24.24,104.56 RW29.1
  BOTTOM w0.102: UH1.BA17 v1(182.92,48.11)
CLKREQ_CNV#_D: length 9.2
  TOP w0.102: v1(31.1,105.16) 30.61,104.67 v2(30.25,104.67) 29.07,104.67 RH723.1 27.58,106.16 25.92,106.16 24.86,105.1 QH9.3
  BOTTOM w0.102: v1(31.1,105.16) 31.7,105.76 JWLAN1.14
CLKREQ_PCIE#0: length 4.7
  BOTTOM w0.089: UH1.BF31 186.06,41.01 187.58,41.01 187.81,41.24 188.07,41.24 188.1,41.27
  BOTTOM w0.102: 188.1,41.27 v1(188.67,41.84) ; RT2.2 32.22,131.71 RT24.1 32.8,132.36 v1(32.9,132.46)
CLKREQ_PCIE#0_R: length 2.8
  BOTTOM w0.102: UT1.AC5 30.02,130.7 30.11,130.61 31.06,130.61 RT20.2 RT2.1
CLKREQ_PCIE#7: length 17.4
  TOP w0.102: v1(235.68,87.02) v3(234.31,85.64) 233.79,85.12 224.75,85.12 223.54,86.34 v1(223.54,86.35) ; v1(173.86,31.33) 173.86,30.8 173.68,30.62 RP3.5
  BOTTOM w0.102: UH1.AC48 174.67,32.81 173.86,32 v1(173.86,31.33) ; QV3.1 v1(235.68,87.02)
CLKREQ_PCIE#9: length 92.9
  TOP w0.102: v1(99.31,26.9) 100.12,26.1 100.89,26.1 101.38,26.59 103.13,26.59 103.56,26.16 106.71,26.16 107.62,27.06 108.98,27.06 117.72,35.8 123.96,35.8 131.93,27.82 154.78,27.82 157.65,30.69 164.57,30.69 165.24,31.37 166.02,31.37 167.66,33.01 168.75,33.01 169.81,31.94 169.81,30.79 170.32,30.29 RP3.8 172.18,30.63 v1(171.85,30.96)
  BOTTOM w0.102: v1(26.82,25.25) 26.62,25.44 JSSD1.52 ; v1(171.85,30.96) 172.24,31.36 173.09,31.36 173.61,30.83 173.93,30.83 174.38,31.29 175.15,31.29 176.39,32.52 UH1.AF48
CLKREQ_PCIE#14: length 109
  TOP w0.102: v1(174.3,31.78) 173.75,31.78 173.36,31.39 173.36,30.8 173.18,30.62 RP3.6 173.18,30.02 173.42,29.78 174.18,29.78 174.41,29.55 174.41,28.34 173.72,27.65 172.29,27.65 172.12,27.81 171.77,27.81 171.2,28.38 171.2,29.28 170.82,29.67 170.13,29.67 169.44,30.35 165.61,30.35 164.99,29.73 158.05,29.73 155.18,26.86 131.53,26.86 123.62,34.78 118.07,34.78 118,34.71 117.99,34.71 109.25,25.97 107.89,25.97 107.11,25.2 103.16,25.2 102.77,25.59 101.79,25.59 101.32,25.12 96.79,25.12 v1(96.29,25.61) ; v1(63.36,26.54) 62.94,26.96 v2(62.94,27.89) 62.94,28.6 61.2,30.34 61.2,32.12 60.9,32.42 59.39,32.42 58.24,33.56 RL13.1
  BOTTOM w0.102: v1(174.3,31.78) 175.17,31.78 175.46,32.08 175.46,33.93 174.77,34.63 UH1.AC44
CLKREQ_PCIE#14_R: length 2.9
  TOP w0.102: RL13.2 58.24,35.95 v2(58.09,36.11) 57.94,36.26 57.94,36.76 57.81,36.88 UL1.12
CLKREQ_PCIE#15: length 97.2
  TOP w0.102: v1(174.24,34.97) 173.86,34.97 172.7,33.8 172.7,32.78 172.85,32.62 172.85,32 172.72,31.86 172.72,31.67 173.09,31.3 173.09,31.03 172.68,30.62 RP3.7 172.68,29.98 172.49,29.79 171.2,29.79 171.02,29.97 170.35,29.97 169.58,30.74 169.58,31.88 168.66,32.8 167.74,32.8 165.95,31.01 165.59,31.01 164.79,30.21 157.85,30.21 154.98,27.34 131.73,27.34 123.76,35.32 117.92,35.32 109.05,26.45 107.69,26.45 106.91,25.68 103.36,25.68 102.93,26.11 101.63,26.11 101.12,25.6 98.87,25.6 98.69,25.78 v1(98.69,26.9) ; RW9.1 38.72,98.17 39.03,97.86 39.84,97.86 v2(39.88,97.9) 40.2,97.59 v1(40.89,97.59)
  BOTTOM w0.102: UH1.AC43 174.62,35.34 v1(174.24,34.97)
CLKREQ_PCIE#15_R: length 4.3
  TOP w0.102: RW9.2 40.68,98.92 v2(41.15,99.39) 41.49,99.73 v1(41.49,100.38)
  BOTTOM w0.102: JWLAN1.53 41.45,100.34 v1(41.49,100.38)
CLKRUN#: length 2.8
  TOP w0.102: v2(182.16,40.54) 181.84,40.85 RH701.1 181.2,41.47 v1(181.25,41.52)
  BOTTOM w0.102: UH1.AV32 181.25,41.37 v1(181.25,41.52)
CMP_STRAP0: length 4
  TOP w0.102: RE165.1 94.08,39.23 91.96,39.23 91.58,39.61 UE1.118
CMP_VIN0: length 30.2
  TOP w0.102: v2(102.76,43.17) 102.38,43.55 v1(102.38,43.6) RE37.1 RE52.1 ; RE166.1 81.05,47.23 81.49,46.79 UE1.20 81.49,44.37 82.39,43.48 82.39,43.36 v1(82.36,43.33)
  BOTTOM w0.102: v1(82.36,43.33) 82.39,43.36 82.39,43.94 83.56,45.11 91.23,45.11 93.57,47.45 96.06,47.45 98.41,45.11 100.87,45.11 v1(102.38,43.6)
CMP_VOUT0: length 54.8
  TOP w0.102: RE49.2 84.51,26.19 84.51,28.54 84.69,28.72 UE1.85 84.69,30.63 84.47,30.86 84.47,31.21 84.71,31.46 84.71,40.33 v1(84.35,40.7) ; RE52.2 103.89,45.13 104.22,44.8 v2(104.22,44.25) 104.22,43.71 103.22,42.71 101.78,42.71 v1(101.58,42.91) 101.58,47.05 v1(103.06,48.53)
  BOTTOM w0.102: v1(201.42,88.49) 202.1,88.49 QG23.3 203.01,87.59 203.92,87.59 RG580.1 ; v1(131.33,59.42) 131.33,58.16 PR507.1 ; v1(101.58,42.91) 101.39,43.1 101.39,43.52 100.26,44.65 98.22,44.65 95.88,46.99 93.76,46.99 91.42,44.65 87.93,44.65 84.36,41.08 84.36,40.72 v1(84.35,40.7)
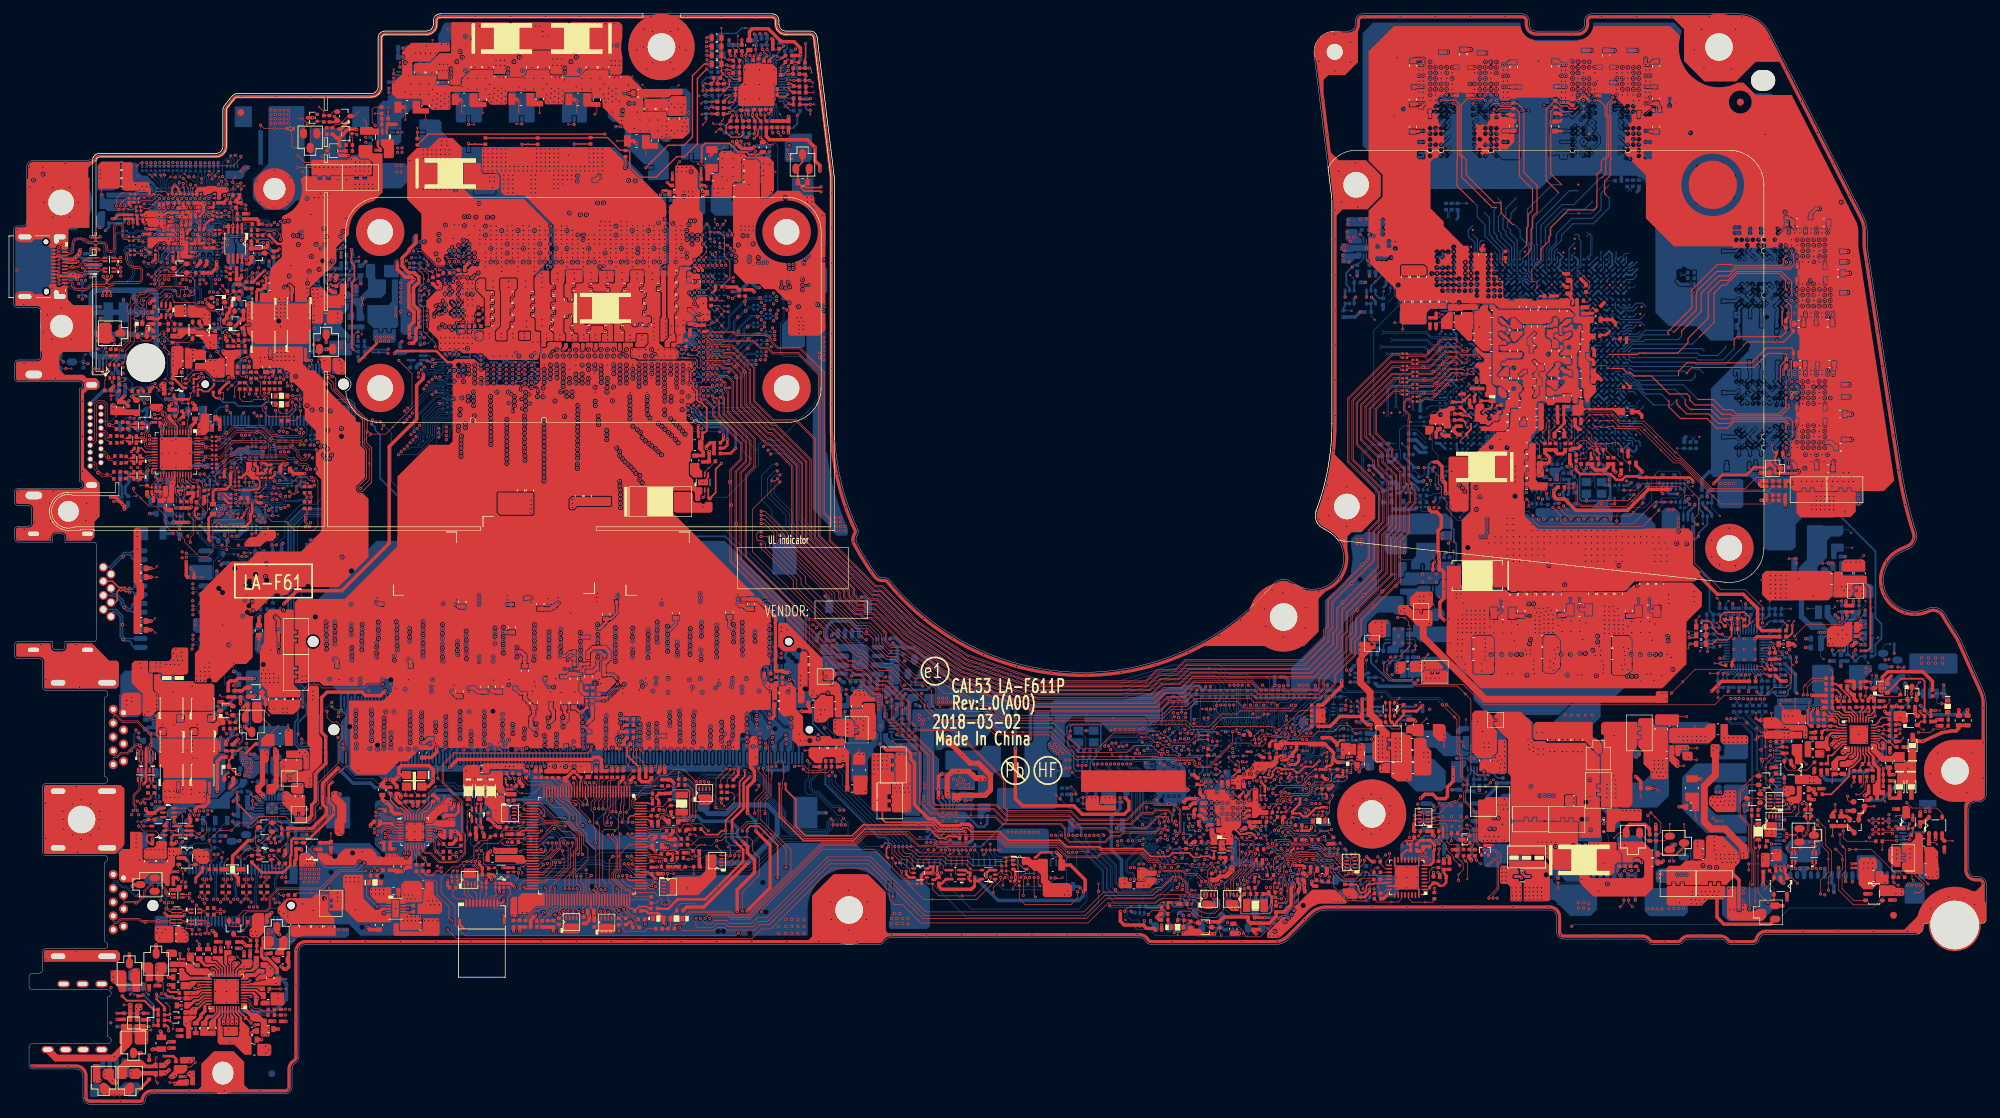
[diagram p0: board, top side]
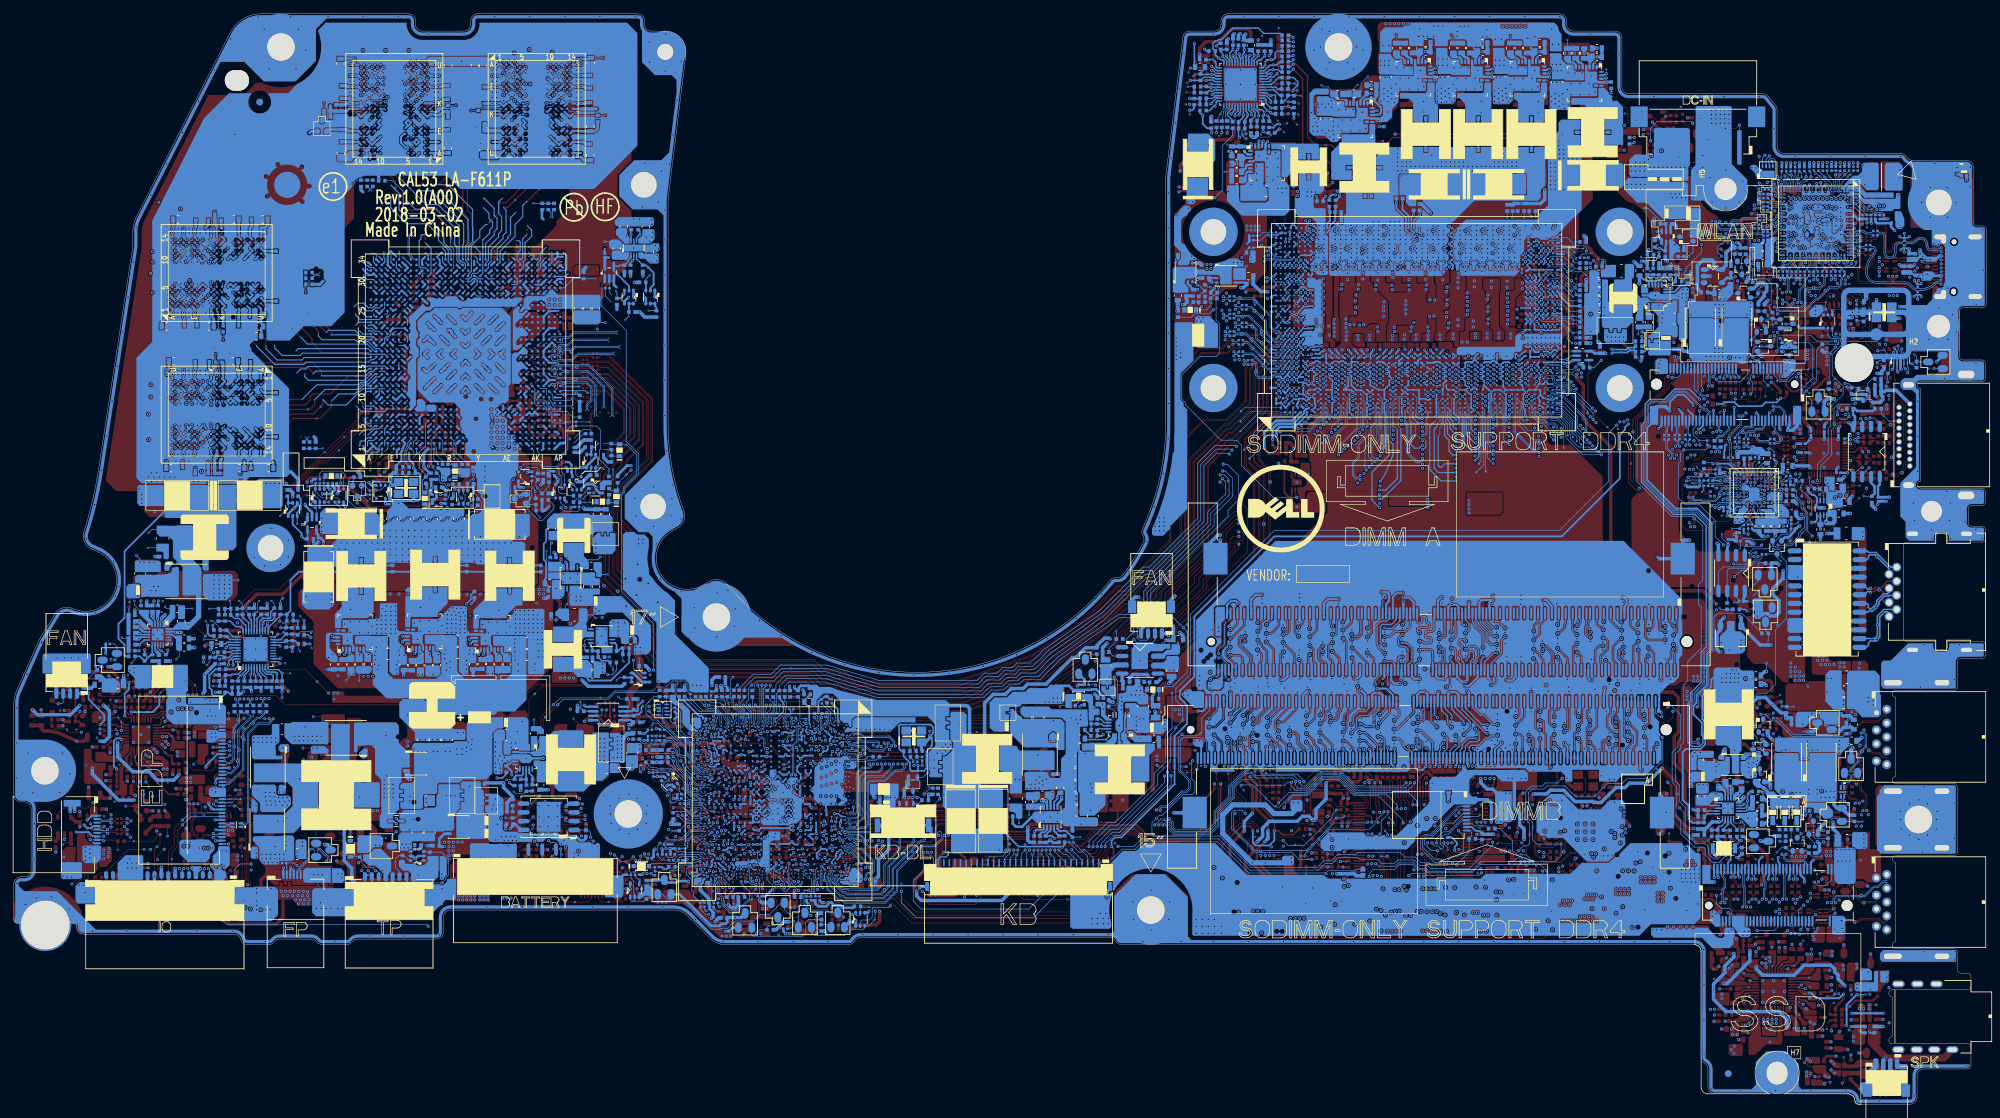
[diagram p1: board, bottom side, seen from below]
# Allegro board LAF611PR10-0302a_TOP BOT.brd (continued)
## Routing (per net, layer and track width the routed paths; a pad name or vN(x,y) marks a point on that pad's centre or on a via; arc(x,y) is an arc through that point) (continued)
CNV_BRI_PRX_DTX: length 104.6
  TOP w0.102: v1(108.14,84.64) 108.56,84.64 110.4,82.79 110.4,81.12 117.96,73.57 117.96,72.61 121.07,69.51 121.75,68.83 123.57,68.83 124.73,67.66 124.73,66.46 126.41,64.78 127.67,64.78 130.36,62.09 131.98,62.09 134.59,59.48 135.69,59.48 137.95,57.22 141.01,57.22 142.75,55.48 v2(151.69,55.48) 169.68,55.48 170.49,54.67 172.93,54.67 174.72,56.47 176.96,56.47 177.41,56.92 184.81,56.92 185.43,57.54 v1(185.43,57.74) ; v1(36.3,102.07) 36.21,101.98 34.71,101.98 34.4,101.67 33.15,101.67 32.66,102.16 RW19.1
  BOTTOM w0.089: 183.09,56.37 182.98,56.27 UH1.AY2
  BOTTOM w0.102: 183.09,56.37 184,57.28 184.98,57.28 v1(185.43,57.74) 186.2,58.51 186.29,58.51 186.73,58.95 RH614.2
CNV_BRI_PRX_R_DTX: length 9.2
  TOP w0.102: v2(31.94,102.41) 31.94,103.69 RW19.2 RW13.1 34.24,103.61 RW27.1 34.09,103.3 v1(34.09,102.78)
  BOTTOM w0.102: JWLAN1.22 33.7,105.81 34.09,105.42 34.09,104.77 33.85,104.52 33.85,103.02 v1(34.09,102.78)
CNV_BRI_PTX_DRX: length 99.6
  TOP w0.102: v1(36.87,102.89) 36.98,103.01 RW20.1 ; v1(184.84,57.74) 184.43,57.32 177.94,57.32 176.96,58.3 171.02,58.3 169.88,57.16 167.54,57.16 166.27,55.88 v2(159.03,55.88) 142.92,55.88 141.18,57.62 139.41,57.62 128.02,65.22 126.55,65.22 125.14,66.63 125.14,67.83 123.74,69.23 121.92,69.23 121.19,69.96 118.37,72.78 118.37,73.74 111.57,80.53 111.57,82.33 108.68,85.22 v1(108.13,85.22)
  BOTTOM w0.089: 182.95,56.54 182.6,56.19 182.6,55.76 182.11,55.27 182.11,54.87 182.19,54.79 182.19,54.42 UH1.AV4
  BOTTOM w0.102: 182.95,56.54 184.14,57.74 v1(184.84,57.74) 185.97,58.86 RH671.2
CNV_BRI_PTX_R_DRX: length 2.2
  TOP w0.102: v1(36.93,105.13) 36.98,105.09 RW20.2
  BOTTOM w0.102: v1(36.93,105.13) 36.93,105.43 37.2,105.7 JWLAN1.36
CNV_PRX_DTX_N0: length 1.9
  BOTTOM w0.089: v1(184.1,54.43) 184.07,54.46 184.07,54.95 184.23,55.11 184.31,55.11 UH1.BB3
  BOTTOM w0.102: v1(34.46,95.14) 34.63,95.31 34.63,95.49 R3006.1
CNV_PRX_DTX_N1: length 3.9
  BOTTOM w0.089: UH1.BA3 183.79,54.98 184.12,55.3 v1(184.12,55.58)
  BOTTOM w0.102: R3004.1 31.47,95.85 32.85,95.85 33.3,96.29 33.3,96.62 v1(33.52,96.83)
CNV_PRX_DTX_P0: length 1.5
  BOTTOM w0.089: UH1.BB4 184.39,54.89 184.6,54.89 184.69,54.81 v1(184.69,54.44)
  BOTTOM w0.102: R3007.1 34.84,95.49 34.84,95.34 v1(35.04,95.14)
CNV_PRX_DTX_P1: length 3.6
  BOTTOM w0.089: v1(184.12,56.17) 183.75,55.81 183.75,55.59 183.73,55.56 UH1.BA2
  BOTTOM w0.102: v1(32.93,96.83) 33.1,96.67 33.1,96.38 32.77,96.05 31.47,96.05 R3005.1
CNV_PRX_R_DTX_N0: length 4.8
  BOTTOM w0.102: R3006.2 34.63,96.5 34.63,96.98 34.35,97.26 33.58,97.26 33.25,97.59 32.4,97.59 32.1,97.89 32.1,98.13 31.95,98.28 JWLAN1.15
CNV_PRX_R_DTX_N1: length 4.5
  BOTTOM w0.102: JWLAN1.9 30.45,97.43 29.66,96.64 v4(29.66,96.26) 29.66,95.9 29.93,95.63 R3004.2
CNV_PRX_R_DTX_P0: length 4.8
  BOTTOM w0.102: JWLAN1.17 32.45,98.35 32.3,98.2 32.3,97.97 32.48,97.8 33.33,97.8 33.66,97.46 34.44,97.46 34.83,97.06 34.83,96.51 R3007.2
CNV_PRX_R_DTX_P1: length 4.4
  BOTTOM w0.102: JWLAN1.11 30.95,98.2 30.66,97.9 30.66,97.34 29.89,96.58 29.89,95.96 30.02,95.84 30.24,95.84 R3005.2
CNV_PTX_DRX_N0: length 2.9
  BOTTOM w0.089: UH1.BE6 185.66,52.99 185.86,52.99 186,53.13 186.69,53.13 v1(187.05,52.77)
  BOTTOM w0.102: v1(44.36,95.22) 44.51,95.37 44.51,96.12 R3023.1
CNV_PTX_DRX_N1: length 2.4
  BOTTOM w0.102: UH1.BG6 186.73,53.4 186.82,53.31 187.27,53.31 187.65,53.69 v1(187.66,53.69) ; v1(42.88,95.38) 43.09,95.6 43.09,96.02 R3019.1
CNV_PTX_DRX_P0: length 2.9
  BOTTOM w0.089: UH1.BD7 185.36,52.91 185.45,52.83 185.93,52.83 186.07,52.97 186.36,52.97 186.44,52.89 v1(186.44,52.75)
  BOTTOM w0.102: R3024.1 44.72,95.92 44.72,95.45 v1(44.95,95.22)
CNV_PTX_DRX_P1: length 2.2
  BOTTOM w0.089: v1(187.06,53.68) 186.3,53.68 UH1.BF6
  BOTTOM w0.102: v1(43.46,95.38) 43.3,95.55 43.3,96.02 R3021.1
CNV_PTX_R_DRX_N0: length 2.3
  BOTTOM w0.102: JWLAN1.65 44.45,98.14 44.6,98 44.6,97.02 R3023.2
CNV_PTX_R_DRX_N1: length 2.3
  BOTTOM w0.102: R3019.2 43.09,97.03 43.09,97.97 42.95,98.11 JWLAN1.59
CNV_PTX_R_DRX_P0: length 2.3
  BOTTOM w0.102: JWLAN1.67 44.95,98.12 44.8,97.98 44.8,97.05 R3024.2
CNV_PTX_R_DRX_P1: length 2.3
  BOTTOM w0.102: JWLAN1.61 43.45,98.12 43.3,97.97 43.3,97.03 R3021.2
CNV_RF_RESET#: length 16.2
  TOP w0.102: v1(186.27,49.01) 186.34,49.01 v2(186.93,49.6) ; RH724.1 26.02,103.21 v1(26.04,103.19)
  BOTTOM w0.076: v1(186.27,49.01) 185.97,48.71 185.57,48.71 185.42,48.56 UH1.BE16
  BOTTOM w0.102: QH8.2 22.9,111.26 22.47,110.83 21.5,110.83 21.35,110.68 21.35,110.15 21.51,109.99 23.7,109.99 RW4.1 24.58,109.13 24.58,104.66 v1(26.04,103.19)
CNV_RF_RESET#_D: length 9.9
  TOP w0.102: v1(27.45,105.23) 27.45,105.17 26.62,104.34 RH722.1 ; v1(20.92,110.51) v2(21.41,110.03)
  BOTTOM w0.102: JWLAN1.10 30.7,105.45 29.81,104.56 28.63,104.56 27.95,105.23 v1(27.45,105.23) ; v1(20.92,110.51) 20.92,110.57 21.41,111.06 22.06,111.06 22.25,111.25 QH8.3
CNV_RGI_PRX_DTX: length 96.9
  TOP w0.102: RW21.1 36.22,102.95 v1(36.28,102.88) ; v1(182.78,57.73) 182.34,58.17 179.45,58.17 178.91,58.71 170.85,58.71 169.71,57.56 167.38,57.56 166.1,56.29 v2(155.21,56.29) 143.09,56.29 141.35,58.03 139.54,58.03 128.15,65.62 126.72,65.62 125.55,66.79 125.55,68 123.91,69.64 122.08,69.64 121.35,70.37 118.77,72.95 118.77,73.9 111.99,80.69 111.99,82.48 108.67,85.81 v1(108.13,85.81)
  BOTTOM w0.089: 182.38,56.87 182.38,55.86 181.94,55.41 181.94,54.64 UH1.AV3
  BOTTOM w0.102: 182.38,56.87 182.78,57.26 v1(182.78,57.73) 183.14,58.09 184.51,58.09 185.21,58.79 RH613.2
CNV_RGI_PRX_R_DTX: length 2.3
  TOP w0.102: RW21.2 36.22,105.09 v1(36.36,105.23)
  BOTTOM w0.102: v1(36.36,105.23) 36.7,105.57 JWLAN1.34
CNV_RGI_PTX_DRX: length 114.5
  TOP w0.102: v1(108.13,84.05) 108.57,84.05 109.97,82.66 109.97,80.92 114.55,76.33 114.55,75.44 120.9,69.1 120.9,69.1 121.61,68.39 122.73,68.39 123.18,67.94 123.74,67.94 124.3,67.38 124.3,66.32 126.24,64.38 127.5,64.38 130.2,61.68 131.81,61.68 133.39,60.11 133.39,58.01 133.63,57.78 136.82,57.78 137.78,56.81 140.84,56.81 142.58,55.07 v2(148.46,55.07) 150.5,55.07 153.14,52.44 153.41,52.44 154.32,51.52 156.88,51.52 159.09,53.73 163.98,53.73 164.25,54 165.67,54 166.23,53.44 166.52,53.44 167.68,52.28 169.96,52.28 170.93,53.26 170.93,53.48 171.39,53.95 173.41,53.95 174.12,54.66 182.12,54.66 182.6,54.18 v1(183.03,54.18) 183.72,54.86 184.02,54.86 186.11,56.95 187.76,56.95 RH589.1 RH588.2 ; RW18.1 35.68,104.42 35.68,102.78 35.99,102.48 36.6,102.48 36.85,102.23 36.85,101.85 35.99,100.99 35.99,100.39 36.86,99.53 39.88,99.53 40.74,100.39 v1(40.74,101.17)
  BOTTOM w0.102: UH1.BA4 183.16,54.3 v1(183.03,54.18)
CNV_RGI_PTX_R_DRX: length 4.3
  TOP w0.102: v1(35.77,105.2) 35.77,105.25 RW18.2 RW15.1 34.24,105.87 RW28.1
  BOTTOM w0.102: v1(35.77,105.2) 35.77,105.3 36.2,105.73 JWLAN1.32
CNV_WT_RCOMP: length 6.3
  BOTTOM w0.089: 186.12,56.8 184.15,56.8 183.52,56.17 UH1.BA1
  BOTTOM w0.102: 186.12,56.8 RH667.1
CNVI_EN#: length 9.8
  TOP w0.102: v2(19.79,118.7) v1(20.39,118.7) 20.77,119.08 20.77,119.4 21.41,120.04 23.8,120.04 24.09,120.33 Q30.2 25.05,120.31 RW30.1
  BOTTOM w0.076: UH1.BF17 186.08,48.07 186.33,48.31 186.64,48.31 186.95,48.62 187.03,48.62 187.64,49.23 v1(187.64,49.51)
COMP_1PH: length 3.5
  BOTTOM w0.203: PCZ11.2 106.4,141.52 PCZ10.1 105.76,142.99 v2(105.76,143.34) 105.76,143.53 106.28,144.05 PUZ01.50
COMP_2PH: length 3.7
  TOP w0.102: v1(112.14,147.68) 111.86,147.96 v2(111.86,148.33)
  TOP w0.203: v1(112.14,147.68) 112.5,147.68 112.82,147.37 PCZ24.2 112.92,147.27 PCZ25.2
  BOTTOM w0.203: PUZ01.33 112.04,147.58 v1(112.14,147.68)
COMP_4PH: length 3.8
  BOTTOM w0.203: PUZ01.6 v2(103.56,147.18) 102.75,147.18 102.5,146.93 PCZ13.1 101.94,147.68 PRZ29.1
COMP_CHG: length 2.9
  TOP w0.203: PUB01.28 267.13,56.86 267.46,57.18 PRB30.1 266.56,57.47 PCB39.1
CORE_SW1: length 3
  TOP w0.127: v2(87.28,139.41) PRI04.1
  TOP w0.508: PRI04.1 89.67,139.41 v1(90.07,139.01)
CORE_SW2: length 2.8
  TOP w0.127: v1(81.43,145.11) v2(81.43,143.6)
  TOP w0.508: PRI08.1 81.12,145.42 v1(81.43,145.11)
CORE_SW3: length 2.7
  TOP w0.127: v1(73.05,145.11) v2(73.05,143.53)
  TOP w0.508: v1(73.05,145.11) 72.7,145.46 PRI12.1
CORE_SW4: length 2.6
  TOP w0.127: v2(64.8,143.56) v1(64.8,145.11)
  TOP w0.508: PRI16.1 64.49,145.41 v1(64.8,145.11)
CPU_24MHZ_N: length 11
  BOTTOM w0.089: 163.31,53.03 163.34,53.03 163.34,53.02 164.39,53.02 164.74,53.38 164.85,53.38 164.94,53.29 164.94,53.19 UH1.C6 ; v1(104.41,122.7) 104.41,122.46 104.32,122.37 103.12,122.37 103.03,122.46 102.47,122.46 102.27,122.26 100.59,122.26 100.53,122.32 100.53,122.45 100.64,122.56 UC1.D31
  BOTTOM w0.102: v1(159.87,51.75) 160.08,51.96 160.08,52.33 160.32,52.57 162.57,52.57 163.04,53.03 163.31,53.03
CPU_24MHZ_P: length 10.7
  BOTTOM w0.089: 163.31,52.82 163.34,52.82 163.34,52.83 165.24,52.83 UH1.D7 ; UC1.E31 100.34,122.34 100.34,122.24 100.51,122.07 102.35,122.07 102.55,122.27 102.95,122.27 103.04,122.18 104.25,122.18 v1(104.45,121.99)
  BOTTOM w0.102: v1(160.45,51.75) 160.29,51.92 160.29,52.25 160.4,52.36 162.66,52.36 163.12,52.82 163.31,52.82
CPU_B+: length 0.7
  TOP w0.381: PRZ52.1 v1(105.32,154.03)
  vias: v1(58.45,149.24) v1(59.5,149.24) v1(60.48,149.24) v1(61.48,149.55) v1(61.61,150.49) v1(62.07,149.55) v1(62.19,150.49) v1(62.65,149.55) v1(62.78,150.49) v1(66.71,155.98) v1(66.7,150) v1(67.36,156.01) v1(67.76,150) v1(68.05,155.98) v1(68.69,155.98) v1(68.73,150) v1(69.32,155.98) v1(69.75,151.08) v1(69.75,150.32) v1(69.96,155.98) v1(70.38,151.08) v1(70.38,150.32) v1(71.02,151.08) v1(71.02,150.32) v1(74.96,149.98) v1(76.01,149.98) v1(76.99,149.98) v1(78,151.26) v1(77.97,150.34) v1(78.64,151.26) v1(78.6,150.34) v1(79.24,150.34) v1(79.27,151.26) v1(83.21,149.98) v1(83.69,156.37) v1(84.33,156.37) v1(84.27,149.98) v1(84.96,156.37) v1(85.24,149.98) v1(85.6,156.37) v1(86.23,156.37) v1(86.44,151) v1(86.44,150.35) v1(86.87,156.37) v1(87.02,151) v1(87.02,150.35) v1(87.61,150.97) v1(87.61,150.33) v1(91.61,143.96) v1(92.66,143.96) v1(93.64,143.96) v1(94.73,145.23) v1(94.74,144.3) v1(95.15,144.75) v1(95.61,144.26) v1(96.07,144.74) v1(96.55,144.23) v1(96.63,143.57) v1(96.93,144.7) v1(105.21,127.07) v1(105.21,126.49) v1(105.57,135.73) v1(105.57,134.68) v1(105.58,133.71) v1(105.79,127.07) v1(105.79,126.49) v1(106.33,133.09) v1(106.38,127.07) v1(106.38,126.49) v1(106.96,127.07) v1(106.96,126.49) v1(113.32,113.84) v1(113.61,113.3) v1(113.61,112.71) v1(113.61,112.13) v1(113.61,111.54) v1(113.92,113.84) v1(114.2,113.3) v1(114.2,112.71) v1(114.2,112.13) v1(114.8,131.22) v1(114.8,130.59) v1(115.44,131.22) v1(115.44,130.59) v3(117.03,128.65)
CPU_DISPA_BCLK: length 92.8
  BOTTOM w0.076: v1(98.51,119.05) 98.51,119.12 UC1.G27
  BOTTOM w0.102: RH38.1 180.41,60.18 178.39,62.21 175.79,62.21 174.44,63.55 167.71,63.55 160.07,61.29 146.05,61.29 144.97,62.37 143.14,62.37 142.3,63.21 140.89,63.21 140.25,63.84 138.29,63.84 136.4,65.73 128.3,71.41 121.98,77.73 121.12,77.73 114.12,84.73 114.12,92.78 111.56,95.34 108.71,95.34 108.58,95.21 v1(108.47,95.21)
CPU_DISPA_BCLK_R: length 4.6
  BOTTOM w0.089: 179.82,56.63 179.82,56.16 179.51,55.85 179.51,55.16 179.3,54.95 UH1.AM3
  BOTTOM w0.102: RH38.2 180.41,57.62 179.82,57.03 179.82,56.63
CPU_DISPA_SDI: length 5.2
  BOTTOM w0.089: 180.99,57.34 180.73,57.34 180.2,56.81 180.2,55.88 179.88,55.56 179.88,54.84 179.76,54.73 UH1.AN3
  BOTTOM w0.102: 180.99,57.34 181.27,57.61 181.27,58.88 RC2.1
CPU_DISPA_SDI_C: length 1.5
  BOTTOM w0.102: v1(98.5,120.56) 98.81,120.87 UC1.G29 ; RC2.2 181.18,60.11 v1(180.64,60.64)
CPU_DISPA_SDO: length 91.3
  BOTTOM w0.076: UC1.G25 v1(99.21,117.44)
  BOTTOM w0.102: RH39.1 179.65,60.26 178.2,61.72 175.6,61.72 174.24,63.07 v2(172.89,63.07) 167.79,63.07 160.14,60.81 145.85,60.81 144.77,61.89 142.94,61.89 142.1,62.72 140.69,62.72 140.05,63.36 137.96,63.36 135.65,65.67 127.99,71.03 121.78,77.25 120.92,77.25 113.64,84.53 113.64,92.58 111.41,94.8 109.26,94.8 109.11,94.66 v1(109.11,94.64)
CPU_DISPA_SDO_R: length 4.2
  BOTTOM w0.089: 179.63,56.65 179.63,56.26 179.3,55.93 179.3,55.46 179.27,55.43 UH1.AM2
  BOTTOM w0.102: 179.63,56.65 179.63,57.11 180.17,57.64 180.17,58.16 179.65,58.68 RH39.2
CPU_DP1_AUXN: length 1.8
  TOP w0.102: CT126.1 30.23,128.81 30.94,128.81 v1(31.16,129.03)
  BOTTOM w0.102: v1(99.79,119.05) 100.09,119.41 UC1.E27
CPU_DP1_AUXN_C: length 2.8
  TOP w0.102: v1(27.56,128.45) 27.8,128.69 27.8,128.85 28.11,129.16 28.64,129.16 28.68,129.2 RT76.1 29.04,129.01 CT126.2
  BOTTOM w0.102: UT1.W11 v1(27.56,128.45)
CPU_DP1_AUXP: length 1.8
  TOP w0.102: v1(31.16,128.45) 31,128.61 30.22,128.61 CT125.1
  BOTTOM w0.102: UC1.D27 100.74,119.41 v1(100.44,119.05)
CPU_DP1_AUXP_C: length 2.8
  TOP w0.102: CT125.2 29.23,128.6 29.12,128.71 28.95,128.71 RT78.1 28.62,128.6 28.55,128.67 28.55,128.87 28.46,128.96 28.19,128.96 28,128.76 28,128.66 v1(28.21,128.45)
  BOTTOM w0.102: UT1.Y11 v1(28.21,128.45)
CPU_DP1_CTRL_DATA: length 10.2
  TOP w0.102: RH33.1 187.78,54.66 187.42,54.3 187.31,54.3 187.3,54.3 186.82,54.3 185.62,53.1 184.99,53.1 184.1,54 183.67,54 183,53.33 182.15,53.33 181.9,53.58 v2(181.43,53.58) 180.59,53.58 180.11,53.1 v1(180.11,52.86)
  BOTTOM w0.089: UH1.AR8 180.47,52.51 v1(180.11,52.86)
CPU_DP1_HPD: length 98.5
  TOP w0.102: v1(108.12,81.07) 108.12,80.47 112.75,75.83 112.75,74.71 122.27,65.19 122.76,65.19 125.2,62.74 126.84,62.74 128.34,61.24 128.34,60.56 128.74,60.16 129.42,60.16 131.76,57.82 131.76,57.34 133.92,55.19 140.17,55.19 141.91,53.45 v2(143.52,53.45) 149.83,53.45 152.46,50.81 152.73,50.81 153.65,49.89 167.85,49.89 168.01,49.73 170.53,49.73 170.71,49.55 170.71,49.17 171.17,48.71 172.92,48.71 176.47,52.26 178.87,52.26 179.29,51.83 180.66,51.83 181.06,52.23 v1(181.06,52.83)
  BOTTOM w0.076: UT1.AA2 29.01,132.31 29.01,133.04 29.47,133.51
  BOTTOM w0.089: v1(181.06,52.83) 181.06,53.1 UH1.AT6
  BOTTOM w0.102: 29.47,133.51 v1(30.21,134.24) 30.21,136.27 30.85,136.9 31.15,136.9 31.45,136.61 31.45,136.19 31.35,136.1 RPT1.6
CPU_DP1_N0: length 2
  BOTTOM w0.102: CT118.1 32.41,129.58 33.51,129.58 v1(33.56,129.53) ; v1(97.36,126.44) 97.29,126.44 UC1.K37
CPU_DP1_N0_C: length 2.6
  BOTTOM w0.089: 30.29,129.8 30.27,129.8 30.26,129.81 30.06,129.81 30.01,129.77 30.01,129.64 29.91,129.54 29.66,129.54 29.6,129.6 29.6,129.68 UT1.AC7
  BOTTOM w0.102: CT118.2 31.43,129.57 31.06,129.57 30.82,129.8 30.29,129.8
CPU_DP1_N1: length 5.3
  BOTTOM w0.102: v1(98.12,124.46) 97.82,124.16 UC1.J34 ; CT120.1 32.9,128.09 35.21,128.09 35.51,127.79 36.63,127.79 36.81,127.61 36.81,127.41 v1(36.62,127.22)
CPU_DP1_N1_C: length 3.7
  BOTTOM w0.089: CT120.2 31.92,128.14 31.77,128.14 31.49,127.86 30.7,127.86 30.27,128.28 30.27,128.42 30.01,128.69 29.95,128.69 29.88,128.62 29.53,128.62 29.48,128.67 29.48,128.76 29.58,128.86 UT1.AC9
CPU_DP1_N2: length 7.3
  BOTTOM w0.102: UC1.H36 98.64,125.46 v1(98.93,125.75) ; CT122.1 33.66,126.92 34.74,126.92 35.16,126.5 38.48,126.5 38.95,126.97 38.95,127.58 v1(39.13,127.76)
CPU_DP1_N2_C: length 4.2
  BOTTOM w0.089: UT1.AC11 29.59,127.94 29.49,127.83 29.49,127.74 29.53,127.7 29.89,127.7 29.96,127.78 30.09,127.78 30.47,127.4 30.69,127.4 31.09,127
  BOTTOM w0.102: CT122.2 32.71,126.92 31.91,126.92 31.89,126.9 31.19,126.9 31.09,127
CPU_DP1_N3: length 12.5
  BOTTOM w0.089: UC1.J38 97.85,126.76 97.74,126.66 97.74,126.51 97.81,126.45 98.17,126.45 98.32,126.59 98.32,126.95 98.08,127.19 98.08,127.65 v1(97.88,127.85)
  BOTTOM w0.102: CT124.1 32.39,126.08 34.32,126.08 34.4,126 37.08,126 37.54,125.54 37.89,125.54 38.34,125.98 39.57,125.98 39.98,126.39 40.58,126.39 40.87,126.1 40.87,125.87 v1(41.04,125.69)
CPU_DP1_N3_C: length 2.9
  BOTTOM w0.089: 30.35,126.59 30.33,126.6 30.32,126.6 30.04,126.88 30.04,127.09 29.87,127.26 29.69,127.26 29.63,127.19 29.63,127.09 UT1.AC13
  BOTTOM w0.102: CT124.2 31.44,126.08 30.85,126.08 30.35,126.59
CPU_DP1_P0: length 2.1
  BOTTOM w0.102: v1(97.36,125.78) 97.28,125.78 UC1.K36 ; v1(33.56,130.12) 33.22,129.79 32.37,129.79 CT117.1
CPU_DP1_P0_C: length 2.6
  BOTTOM w0.089: UT1.AB7 29.53,130 30.26,130 30.27,130.01 30.29,130.01
  BOTTOM w0.102: 30.29,130.01 30.91,130.01 31.14,129.78 31.45,129.78 CT117.2
CPU_DP1_P1: length 5.7
  BOTTOM w0.102: CT119.1 32.92,128.3 35.3,128.3 35.59,128 36.71,128 37.02,127.7 37.02,127.41 v1(37.2,127.22) ; v1(98.15,125.12) 97.84,124.81 UC1.J35
CPU_DP1_P1_C: length 3.7
  BOTTOM w0.089: CT119.2 31.99,128.33 31.69,128.33 31.41,128.05 30.78,128.05 30.46,128.36 30.46,128.5 30.14,128.82 30.11,128.85 29.88,129.09 29.46,129.09 UT1.AB9
CPU_DP1_P2: length 7
  BOTTOM w0.102: v1(98.14,125.8) 98.23,125.8 UC1.H37 ; CT121.1 33.66,127.13 34.82,127.13 35.25,126.7 38.39,126.7 38.74,127.05 38.74,127.58 v1(38.55,127.76)
CPU_DP1_P2_C: length 4.3
  BOTTOM w0.089: 31.15,127.21 30.77,127.59 30.55,127.59 30.34,127.8 29.98,128.16 29.46,128.16 UT1.AB11
  BOTTOM w0.102: CT121.2 32.71,127.13 v4(31.61,127.13) 31.23,127.13 31.15,127.21
CPU_DP1_P3: length 12
  BOTTOM w0.089: UC1.J37 97.89,126.26 98.25,126.26 98.51,126.51 98.51,127.03 98.27,127.27 98.27,127.65 v1(98.46,127.85)
  BOTTOM w0.102: CT123.1 32.39,125.88 34.23,125.88 34.32,125.79 37,125.79 37.46,125.33 37.98,125.33 38.42,125.78 39.66,125.78 40.06,126.19 40.49,126.19 40.66,126.02 40.66,125.9 v1(40.46,125.69)
CPU_DP1_P3_C: length 2.9
  BOTTOM w0.089: UT1.AB13 29.47,126.78 29.87,126.78 30.19,126.47 30.19,126.46 30.2,126.44
  BOTTOM w0.102: 30.2,126.44 30.77,125.88 31.44,125.88 CT123.2
CPU_ID: length 3.1
  TOP w0.102: v1(180.43,44.08) 180.39,44.12 RH23.1 ; RH24.1 RH23.1 ; RH23.1 v2(180.39,46)
  BOTTOM w0.102: UH1.AP24 180.26,44.25 v1(180.43,44.08)
CPU_TRIGOUT: length 5.6
  TOP w0.102: v2(102.44,116.28) 101.12,116.28 RC8.2 100.34,117.05 98.89,117.05 v1(98.47,116.64)
  BOTTOM w0.076: UC1.J23 97.84,116.64 v1(98.47,116.64)
CPU_TRIGOUT_R: length 5.8
  TOP w0.102: RC8.1 101.96,115.61 v2(102.73,114.83) 102.88,114.68 v1(103.35,114.68)
  BOTTOM w0.089: 177.7,56.34 177.7,55.33 UH1.AK2
  BOTTOM w0.102: v1(178.08,57.76) 177.7,57.37 177.7,56.34
CPU_VCCIO_PWR_GATE#: length 75.2
  TOP w0.102: RZ234.1 145.47,29.72 146.27,28.92 152.96,28.92 153.91,29.87 v1(153.91,30.77) ; v1(214,29.83) 214,30.29 214.82,31.11 214.82,34.9 215.06,35.14 v2(215.06,35.79) 215.06,36.19 214.41,36.85 212.77,36.85 211.62,37.99 211.62,42.29 209.99,43.91 209.99,45.1 210.34,45.44 210.34,46.71 209.55,47.5 209.55,50.38 209.11,50.82 209.11,56.04 207.34,57.81 v1(207.28,57.81)
  BOTTOM w0.089: 183.65,56.63 183.21,56.18 183.21,54.92 182.98,54.7 UH1.AY3
  BOTTOM w0.102: 183.65,56.63 184.05,57.03 185.77,57.03 187.43,58.69 RH719.2 187.58,59.36 187.82,59.6 187.82,60.77 188.29,61.24 190.08,61.24 190.95,60.37 192.35,60.37 192.93,59.8 198.45,59.8 199.45,58.8 206.28,58.8 v1(207.28,57.81)
CPU_XDP_TCK0: length 10.3
  TOP w0.102: TPC2.1 58.97,116.78 v1(59.35,117.16)
  BOTTOM w0.076: 59.23,117.04 v1(59.35,117.16) 59.45,117.26 59.45,117.65 61.48,119.68 62.45,119.68 UC1.BR28
  BOTTOM w0.089: 176.38,56.57 176.38,55.68 176.62,55.44 176.62,54.96 176.81,54.77 176.81,54.52 UH1.AH4
  BOTTOM w0.102: RC83.1 59.23,117.04 ; v1(175.9,57.76) 175.9,57.13 176.38,56.65 176.38,56.57
CPU_XDP_TDI: length 7.2
  TOP w0.102: TPC5.1 58.98,111.33 v1(59.39,110.92)
  BOTTOM w0.089: UH1.AH2 177.07,55.52 177.17,55.62 177.17,56.57
  BOTTOM w0.102: v1(59.39,110.92) RC77.1 ; UC1.BL32 v1(65.86,123.19) ; v1(177.12,60.64) 177.17,60.59 177.17,56.57
CPU_XDP_TDO: length 8.3
  TOP w0.102: v1(59.46,118.17) 58.97,117.68 TPC1.1
  BOTTOM w0.076: 58.9,117.8 59.12,117.8 59.46,118.14 v1(59.46,118.17) 59.58,118.17 61.38,119.97 UC1.BT28
  BOTTOM w0.089: UH1.AH3 176.84,55.08 176.84,55.48 176.64,55.67 176.64,56.57
  BOTTOM w0.102: v1(176.49,57.76) 176.49,57.27 176.64,57.11 176.64,56.57 ; RC78.1 58.9,117.8
CPU_XDP_TMS: length 16.1
  TOP w0.102: v1(59.98,119.17) 59.98,120.12 58.37,121.73 TPC4.1
  BOTTOM w0.076: UC1.BP28 63.05,120.3 62.01,120.3 61.89,120.19 61.14,120.19 60.12,119.17 v1(59.98,119.17)
  BOTTOM w0.089: 177.41,56.57 177.41,55.2 177.79,54.83 177.79,54.75 177.79,54.41 UH1.AJ4
  BOTTOM w0.102: v1(59.98,119.17) 59.37,118.57 RC76.1 ; 177.41,56.57 177.41,60.15 177.7,60.44 v1(177.7,60.64)
CPU_XDP_TRST#: length 9.3
  TOP w0.102: TPC6.1 60.08,120.48 v1(60.57,120.48) 60.62,120.43 RC85.1
  BOTTOM w0.076: v1(60.57,120.48) 61.27,121.18 63.02,121.18 UC1.BP30
  BOTTOM w0.089: 180.01,56.5 180.01,56.01 179.7,55.69 179.7,55 179.52,54.82 179.52,54.68 179.52,54.68 179.52,54.61 UH1.AM4
  BOTTOM w0.102: 180.01,56.5 180.01,56.95 180.82,57.76 v1(180.84,57.76)
CS_1.2V: length 5
  TOP w0.102: v1(34.53,43.91) v3(34.53,42.84)
  BOTTOM w0.203: PUM01.13 34.96,42.82 34.53,43.25 v1(34.53,43.91) 34.53,44.94 34.22,45.25 PRM03.1
CSCOMP_2PH: length 8.2
  TOP w0.102: v1(115.12,148.16) 115.25,148.16 v2(115.58,147.83)
  TOP w0.203: v1(115.12,148.16) PRZ48.2 114.5,149.02 PRZ49.1 114.43,149.09 PCZ27.1
  BOTTOM w0.152: PHZ02.1 51.15,138.99 v1(50.93,139.22)
  BOTTOM w0.203: PUZ01.31 111.47,148.38 111.67,148.57 112.23,148.57 112.28,148.63 113.14,148.63 113.6,148.17 PCZ28.1 115.12,148.17 v1(115.12,148.16)
CSCOMP_4PH: length 12
  TOP w0.102: v1(100.28,146.68) 100.28,146.5 v2(99.87,146.09)
  TOP w0.152: PRZ33.1 100.36,146.76 v1(100.28,146.68)
  TOP w0.203: PRZ33.1 PCZ17.1 101.79,146.76 PCZ18.2 102.92,146.76 103.51,147.35 v1(103.51,148.23)
  BOTTOM w0.203: PRZ32.1 100.22,148.59 99.58,147.95 99.58,147.48 100.28,146.78 v1(100.28,146.68) ; v1(103.51,148.23) 103.76,147.98 PUZ01.8 ; PHZ01.1 89.9,131.44 v1(89.9,133.62)
CSIN_CHG: length 4.4
  TOP w0.203: PRB03.2 266.26,48.3 PCB20.1 267.13,48.89 PCB18.2 267.81,49.57 v2(267.81,50.2) 267.81,50.35 267.53,50.63 PUB01.14
CSIP_CHG: length 7
  TOP w0.102: PRB02.2 267.6,47.87 267.6,46.26 v2(267.3,45.96)
  TOP w0.203: PRB02.2 268.07,48.33 268.36,48.33 268.36,48.32 PCB19.1 268.94,48.67 PCB18.1 268.38,50.29 267.93,50.73 PUB01.15
CSN_1PH: length 3.3
  TOP w0.102: v1(107.1,140.44) v2(106.39,140.44)
  TOP w0.203: v1(107.1,140.44) 107.19,140.53 PRZ70.1
  BOTTOM w0.152: PLA01.3 v1(97.99,134.97)
  BOTTOM w0.203: v1(95.56,131.39) 95.91,131.04 PHZ05.1
CSN_1PH_R: length 6.7
  TOP w0.203: PRZ70.2 107.19,142.53 106.86,142.86 v1(106.86,143.18) 106.86,143.73 PCZ38.1
  BOTTOM w0.102: v2(107.52,140.11) 107.52,140.94 PCZ07.1
  BOTTOM w0.203: PUZ01.48 107.08,143.67 106.86,143.45 v1(106.86,143.18) 106.86,142.87 107.26,142.47 PCZ06.1 PCZ07.1
CSON_CHG: length 5.7
  TOP w0.203: PRB36.1 261.05,55.65 PCB41.2 261.88,55.65 PCB43.1 262.13,56.53 262.5,56.16 263.55,56.16 v2(263.77,55.94) 264.03,55.68 264.03,55.05 264.21,54.88 PUB01.1
CSOP_CHG: length 3.9
  TOP w0.203: PUB01.2 263.87,54.48 v2(263.77,54.58) 263.61,54.74 PCB38.1 261.88,54.74 PCB41.1 261.05,54.73 PRB32.1
CSP1_2PH: length 3.2
  TOP w0.152: PRZ60.1 113.05,150.78 113.01,150.82 PCZ33.2 112.04,150.32 v1(112.04,150.2)
  BOTTOM w0.203: PUZ01.28 111.34,149.58 111.96,150.2 v1(112.04,150.2)
CSP1_4PH: length 6.3
  TOP w0.102: v2(103.16,148.67) 103.01,148.82 103.01,149.57 v1(103.16,149.72)
  TOP w0.152: PCZ34.2 103.61,149.72 v1(103.16,149.72)
  BOTTOM w0.203: PRZ61.2 PRZ73.2 102.07,149.36 102.42,149.72 v1(103.16,149.72) 103.67,149.72 104.2,149.18 PUZ01.11
CSP2_4PH: length 5.3
  TOP w0.152: v1(103.13,150.4) 103.39,150.15 PCZ35.2
  BOTTOM w0.203: PUZ01.12 104.39,149.58 v2(103.75,150.22) 103.57,150.4 v1(103.13,150.4) 102.62,150.4 102.14,150.88 PRZ74.2 PRZ62.2
CSP3_4PH: length 6.1
  TOP w0.152: v1(103.44,151.16) 103.94,151.16 PCZ36.2
  BOTTOM w0.203: PRZ63.2 PRZ75.2 102.57,152.41 102.87,152.11 v2(102.87,151.43) 103.13,151.16 v1(103.44,151.16) 104.02,151.16 104.3,150.88 104.3,150.43 104.74,149.98 PUZ01.13
CSP4_4PH: length 16.6
  TOP w0.254: PRZ77.2 111.29,151.4 v1(111.02,151.4)
  BOTTOM w0.203: PUZ01.26 110.28,150.95 110.46,151.13 110.76,151.13 v1(111.02,151.4) 111.52,151.89 PCZ37.2 111.86,152.75 111.86,153.52 111.51,153.88 111.24,153.88 111.05,154.08 110.62,154.08 108.96,155.74 v2(105.83,155.74) 105.3,155.74 104.53,154.96 102.13,154.96 PRZ64.2 PRZ76.2
CSP_1PH: length 8.5
  TOP w0.102: v2(109.8,138.9) 109.18,138.9 108.88,139.2 PRZ13.1
  TOP w0.203: v1(107.48,143.18) 107.48,142.94 108.03,142.39 PRZ12.2
  TOP w0.254: PRZ13.1 108.36,139.59 v1(108.02,139.92)
  BOTTOM w0.203: PUZ01.47 107.48,143.19 v1(107.48,143.18) 107.48,142.82 PCZ06.2 PCZ07.2 108.17,140.07 v1(108.02,139.92)
CSREF_2PH: length 32.6
  TOP w0.152: v1(112.05,149.61) 112,149.61 111.32,148.94 PCZ26.1 110.95,150.14 PCZ33.1
  TOP w0.203: v1(85.5,140.39) v2(61.33,140.39) 59.96,140.39 PRG03.2
  BOTTOM w0.152: v1(112.05,149.61) 111.81,149.61 111.38,149.18 PUZ01.29
CSREF_4PH: length 57.9
  TOP w0.152: v1(103.44,149.16) 103.44,149.01 104.11,148.34 PCZ19.2 105.02,148.83 104.99,148.86 PCZ34.1 PCZ35.1 PCZ36.1
  TOP w0.203: v1(100.25,149.81) 98.9,148.45 98.9,139 97.03,137.13 95.91,137.13 92.94,134.16 90.6,134.16 89.13,135.63 89.13,137.84 88.94,138.03 PRI03.2 88.48,138.05 87.74,138.05 85.89,139.89 PRI07.2 83.38,139.82 PRI11.2 v2(70.73,139.82) 68.24,139.82 PRI15.2
  BOTTOM w0.152: PRZ74.1 100.55,150.88 v1(100.28,151.15) ; PRZ73.1 100.7,149.36 v1(100.25,149.81) ; PRZ76.1 100.76,153.74 v1(100.23,153.74) ; PRZ75.1 100.92,152.38 100.32,152.38 v1(100.25,152.45)
  BOTTOM w0.203: PCZ37.1 112.79,152.41 v1(113.08,152.7) ; v1(103.44,149.16) 103.74,149.16 104.12,148.78 PUZ01.10
CSSUM_2PH: length 6.9
  TOP w0.203: v1(112.04,149.03) 112.1,149.09 PCZ27.2 PRZ50.2
  BOTTOM w0.102: PCZ28.2 114.39,149.08 v2(114.71,148.77)
  BOTTOM w0.203: PUZ01.30 111.41,148.78 111.65,149.03 v1(112.04,149.03) 113.62,149.03 PCZ28.2 113.67,149.25 113.05,149.86 PRZ51.1
CSSUM_4PH: length 11.9
  TOP w0.102: v2(102.37,155.74) PRZ38.2
  TOP w0.203: PCZ18.1 101.79,147.67 PCZ17.2 101.79,148.11 PRZ34.2 102.2,148.71 102.59,149.1 v1(102.59,149.13) 102.59,149.16 102.37,149.38 PRZ35.2 PRZ36.2 PRZ37.2 PRZ38.2
  BOTTOM w0.203: v1(102.59,149.13) 103.02,148.7 103.69,148.7 104.01,148.38 PUZ01.9
DAT_SMB: length 6.1
  TOP w0.102: PR37.1 209.74,35.52 v1(210.05,35.22) 210.29,34.97 v2(210.29,32.59)
  BOTTOM w0.102: v1(210.05,35.22) 209.37,35.22 208.9,35.68 PBATT1.6
DAT_TP_SIO: length 11.8
  TOP w0.102: C26.1 R31.2 233.12,34.31 233.64,33.8 v1(234.09,33.8) ; UE1.79 82.29,30.56 82.48,30.74 82.48,31.71 82.05,32.13 v1(82.05,33.01) ; v1(232.94,29.53) 232.94,29.11 v3(232.4,28.56)
  BOTTOM w0.102: v1(234.09,33.8) 233.55,33.26 JTP.2 233.55,31.78 232.94,31.18 v1(232.94,29.53)
DBC_PANEL_EN: length 4.1
  TOP w0.102: v1(187.32,42.56) 187.08,42.8 v2(186.72,42.8) ; R6.2 v1(254.1,52.48)
  BOTTOM w0.102: UH1.BD29 185.39,42.56 v1(187.32,42.56)
DBC_PANEL_EN_R: length 3.9
  TOP w0.102: R5.2 255.4,51.71 v2(254.9,51.22) ; R5.2 256.46,51.71 v1(256.53,51.65) ; R5.2 255.88,52.45 R6.1
  BOTTOM w0.102: JEDP1.11 v1(256.53,51.65)
DCIN_CHG:
  vias: v2(270.02,50.51)
DDR_A_ACT#: length 7.1
  BOTTOM w0.076: v1(73.93,98.35) 74.27,98.69 74.27,99.07 74.98,99.78 74.98,101.03 UC1.AU3
  BOTTOM w0.168: JDIMM1.114 72.57,63.99 71.29,65.27 v1(70.82,65.27)
DDR_A_ALERT#: length 2.5
  BOTTOM w0.076: UC1.AU5 v1(75.76,102.41)
  BOTTOM w0.168: v1(72.78,64.71) 72.78,64.6 73.06,64.32 73.06,63.96 73.07,63.95 JDIMM1.116
DDR_A_BA0: length 9
  BOTTOM w0.076: UC1.AH5 82.89,102.74 82.39,102.24 82.39,99.89 82.27,99.77 81.67,99.77 v1(81.59,99.85)
  BOTTOM w0.168: v1(84.49,66.74) 83.89,66.74 83.08,65.93 83.08,64.17 83.57,63.67 JDIMM1.150
DDR_A_BA1: length 10
  BOTTOM w0.168: JDIMM1.145 82.32,69.82 82.19,69.68 82.15,69.65 81.84,69.65 81.67,69.82 81.67,70.39 81.5,70.56 81.16,70.56 80.99,70.39 80.99,69.82 80.82,69.65 80.69,69.65 80.52,69.48 80.52,69.14 80.69,68.97 82.1,68.97 82.27,68.8 82.27,68.42 82.1,68.25 v1(81.97,68.25) ; UC1.AH1 82.93,99.29 82.25,98.6 v1(81.61,98.6)
DDR_A_BG0: length 8.2
  BOTTOM w0.168: UC1.AU1 75.39,99.88 74.52,99.02 74.52,97.71 v1(73.88,97.06) ; JDIMM1.115 72.82,69.65 71.64,68.46 71.64,68.02 71.33,67.71 v1(70.82,67.71)
DDR_A_BG1: length 12.4
  BOTTOM w0.076: UC1.AU2 75.71,100.78 75.79,100.71 75.79,99.99 74.86,99.05 74.86,97.41 74.12,96.67 73.69,96.67 73.39,96.38
  BOTTOM w0.168: v1(70.82,69.03) 71.39,69.03 72.32,69.97 JDIMM1.113 ; 73.39,96.38 73.39,93.72 v1(73.95,93.17)
DDR_A_CKE0: length 8.7
  BOTTOM w0.076: UC1.AT1 76.12,99.97 75.54,99.39 75.43,99.39 75.22,99.18 75.22,99.01
  BOTTOM w0.168: 75.22,99.01 75.22,96.91 74.04,95.73 v1(73.87,95.73) ; JDIMM1.109 71.32,70.02 71.15,69.85 70.56,69.85 v1(69.62,68.92)
DDR_A_CKE1: length 13.4
  BOTTOM w0.076: UC1.AT2 76.42,100.48 76.42,100.02 75.53,99.13
  BOTTOM w0.168: v1(73.87,94.45) 74.35,94.45 75.53,95.63 75.53,99.13 ; v1(69.61,67.65) 70.12,67.14 70.12,65.27 71.57,63.82 JDIMM1.110
DDR_A_CLK0: length 14.2
  BOTTOM w0.076: 83.98,98.75 84,98.77 84,98.79 83.98,98.8 83.98,100.23 83.86,100.35 83.74,100.35 83.67,100.28 UC1.AG1
  BOTTOM w0.102: v1(81.57,93.48) 81.41,93.32 81.41,93.17 81.53,93.04 82.34,93.04 83.67,94.38 83.67,94.86 83.67,94.87 83.67,94.94 83.66,94.94 83.66,98.43 83.98,98.75 ; v1(79.14,67.36) 78.94,67.56 78.47,67.56 78.19,67.83 78.19,69.99 78.32,70.12 JDIMM1.137
DDR_A_CLK1: length 8.7
  BOTTOM w0.076: UC1.AK2 80.93,100.43 80.92,100.43 80.69,100.2 80.69,99.44 80.89,99.24 80.89,97.06 81.12,96.83 81.53,96.83 v1(81.58,96.77)
  BOTTOM w0.102: JDIMM1.138 78.57,63.92 78.38,64.11 78.38,65.75 78.65,66.01 78.97,66.01 v1(79.13,66.17)
DDR_A_CLK#0: length 14.3
  BOTTOM w0.076: UC1.AG2 83.93,100.52 84.15,100.3 84.15,100.3 84.19,100.26 84.19,98.62 84.15,98.58
  BOTTOM w0.102: 84.15,98.58 83.9,98.33 83.9,94.28 82.43,92.81 81.74,92.81 v1(81.53,92.61) ; JDIMM1.139 78.82,70.29 78.49,69.96 78.42,69.89 78.42,67.93 78.56,67.79 79.1,67.79 79.18,67.87 79.18,68.08 v1(79.13,68.12)
DDR_A_CLK#1: length 8.4
  BOTTOM w0.076: UC1.AK1 81.15,100.18 81.07,100.26 80.99,100.26 80.86,100.13 80.86,99.51 81.05,99.31 81.05,97.13 81.19,96.99 81.3,96.99 81.38,97.07 81.38,97.41 81.44,97.48 81.51,97.48 v1(81.58,97.41)
  BOTTOM w0.102: v1(79.13,65.46) 79.13,65.63 78.97,65.78 78.74,65.78 78.61,65.66 78.61,64.2 78.83,63.98 78.95,63.98 79.08,63.85 79.08,62.86 JDIMM1.140
DDR_A_CS#0: length 23.9
  BOTTOM w0.076: UC1.AD5 85.85,102.41 85.16,102.41 85.08,102.32 85.08,98.13 84.68,97.73
  BOTTOM w0.168: v1(87.02,67.68) 86.3,67.68 85.56,68.42 84.03,68.42 83.32,69.13 JDIMM1.149 ; v1(87.78,87.6) 87.36,87.6 85.74,89.22 84.68,90.28 84.68,97.73
DDR_A_CS#1: length 20.6
  BOTTOM w0.076: UC1.AE2 85.73,100.5 85.73,98.15 85.19,97.61
  BOTTOM w0.168: v1(87.01,66.45) 87.22,66.45 87.65,66.88 87.65,69.17 87.38,69.44 86.03,69.44 85.32,70.14 JDIMM1.157 ; v1(87.78,88.87) 86.86,88.87 85.19,90.55 85.19,97.61
DDR_A_D0: length 11
  BOTTOM w0.076: UC1.BR6 62.62,103.46 62.23,103.46 62.21,103.44 61.77,103.44 61.55,103.66 60.76,103.66 60.19,103.09 60.19,102.83 58.9,101.54
  BOTTOM w0.102: v1(45.24,66.52) 45.24,66.51 44.85,66.11 44.85,65.43 45.07,65.2 JDIMM1.4 ; 58.9,101.54 57.65,100.29 v1(57.65,100.01)
DDR_A_D1: length 11.2
  BOTTOM w0.076: UC1.BT6 61.95,103.86 60.71,103.86 58.9,102.05
  BOTTOM w0.102: 58.9,102.05 56.86,100.01 v1(56.86,99.07) ; v1(45.22,67.89) 45.22,67.9 44.72,68.4 44.72,70.05 44.82,70.15 JDIMM1.3
DDR_A_D2: length 12.1
  BOTTOM w0.076: UC1.BP3 62.95,101.19 62.38,101.19 62.27,101.08 61.73,101.08
  BOTTOM w0.102: 61.73,101.08 61.6,100.95 61.1,100.95 59.33,99.19 59.33,97.57 58.57,96.81 58.57,96.24 58.02,95.69 57.36,95.69 v1(57.33,95.73) ; JDIMM1.20 49.07,63.75 49.33,64.01 49.33,64.46 v1(48.9,64.9)
DDR_A_D3: length 14.5
  BOTTOM w0.076: 60.91,101.33 61.43,101.84 61.74,101.84 61.81,101.77 62.27,101.77 62.51,101.52 UC1.BR3
  BOTTOM w0.102: v1(58.17,96.59) 58.17,96.85 59.1,97.78 59.1,99.52 60.91,101.33 ; JDIMM1.21 49.32,67.66 48.84,67.18 46.49,67.18 46.46,67.21 v1(46.45,67.21)
DDR_A_D4: length 12.6
  BOTTOM w0.076: 58.9,102.65 59.4,103.15 59.71,103.15 60.61,104.05 62.45,104.05 62.74,103.76 63.8,103.76 63.92,103.63 UC1.BN5
  BOTTOM w0.102: 58.9,102.65 v1(56.98,100.73) ; JDIMM1.8 46.07,64.14 45.6,64.61 45.6,65.54 45.28,65.86 v1(45.27,65.86)
DDR_A_D5: length 5.9
  BOTTOM w0.076: v1(60.56,102.7) 60.56,103.13 60.88,103.45 61.43,103.45 61.61,103.27 62.25,103.27 62.48,103.05 63.05,103.05 63.43,103.42 UC1.BP6
  BOTTOM w0.102: JDIMM1.7 45.82,69.8 45.21,69.19 v1(45.19,69.19)
DDR_A_D6: length 16.2
  BOTTOM w0.076: 63.15,99.45 63.21,99.45 63.73,99.97 63.73,100.66 UC1.BP2
  BOTTOM w0.102: JDIMM1.16 48.07,65.27 v1(48.9,66.09) ; 63.15,99.45 62.93,99.23 61.91,99.23 60.84,98.16 60.84,96.5 58.33,93.99 v1(55.66,93.99)
DDR_A_D7: length 14.8
  BOTTOM w0.076: UC1.BN3 63.86,101.28 63.46,101.28 63.45,101.27 63.31,101.27 63.13,101.09 63.13,100.95 63.12,100.94 63.12,100.38 63.03,100.28 63.03,100.01 62.81,99.79 61.67,99.79
  BOTTOM w0.102: v1(48.79,68.65) 48.64,68.65 48.16,69.14 48.16,70.02 48.32,70.18 JDIMM1.17 ; 61.67,99.79 60.29,98.42 60.29,97 60.17,96.87 60.17,96.31 58.95,95.1 57.46,95.1 57.17,94.81 v1(56.48,94.81)
DDR_A_D8: length 3.9
  BOTTOM w0.076: v1(65.74,101.76) 65.41,102.09 UC1.BL4
  BOTTOM w0.102: v1(50.38,68.18) 51.48,69.28 51.48,69.96 51.32,70.12 JDIMM1.29
DDR_A_D9: length 2.2
  BOTTOM w0.076: UC1.BL5 65.41,102.74 v1(65.74,102.41)
  BOTTOM w0.102: JDIMM1.25 50.35,71.03 50.35,69.48 v1(50.4,69.43)
DDR_A_D10: length 2.4
  BOTTOM w0.076: v1(64.58,100.54) 64.63,100.54 64.87,100.78 UC1.BL2
  BOTTOM w0.102: v1(52.74,69.78) 52.95,69.78 53.32,70.15 JDIMM1.37
DDR_A_D11: length 3.7
  BOTTOM w0.076: v1(64.53,99.76) UC1.BM1
  BOTTOM w0.102: v1(52.74,68.59) 52.92,68.59 54.32,70 JDIMM1.41
DDR_A_D12: length 3.5
  BOTTOM w0.076: UC1.BK4 v1(66.51,101.76)
  BOTTOM w0.102: v1(50.34,65.74) 50.23,65.63 50.23,63.85 50.07,63.7 JDIMM1.24
DDR_A_D13: length 5
  BOTTOM w0.076: UC1.BK5 v1(66.51,102.41)
  BOTTOM w0.102: JDIMM1.28 51.07,66.28 v1(50.34,67.01)
DDR_A_D14: length 6.1
  BOTTOM w0.076: UC1.BK1 65.68,99.66 64.75,98.74 64.68,98.74 64.64,98.7 63.89,98.7 62.57,97.38 v1(62.57,97.38)
  BOTTOM w0.102: JDIMM1.42 54.57,63.76 v1(55.06,64.24)
DDR_A_D15: length 11.7
  BOTTOM w0.076: 64.14,98.52 64.77,98.52 66.11,99.86 UC1.BK2
  BOTTOM w0.102: v1(52.75,67.39) 52.85,67.39 53.99,66.25 53.99,64.25 53.57,63.84 JDIMM1.38 ; v1(62.57,96.15) 63.03,96.61 63.03,97.4 64.14,98.52
DDR_A_D16: length 5.2
  BOTTOM w0.076: v1(66.42,99.02) 66.88,99.02 67.12,99.26 67.12,100.48 67.27,100.63 67.27,101.58 67.77,102.09 UC1.BG4
  BOTTOM w0.102: v1(55.32,69.82) JDIMM1.45
DDR_A_D17: length 9.3
  BOTTOM w0.076: UC1.BG5 68.16,102.42 68.16,101.95 67.97,101.77 67.69,101.77 67.44,101.52 67.44,100.56 67.32,100.45 67.32,99.19 66.58,98.45
  BOTTOM w0.089: 66.58,98.45 v1(65.34,98.45)
  BOTTOM w0.102: JDIMM1.49 56.32,69.5 55.48,68.66 v1(55.4,68.66)
DDR_A_D18: length 3.9
  BOTTOM w0.076: v1(68.97,101.76) 68.9,101.76 UC1.BF4
  BOTTOM w0.102: v1(59.21,67.97) 59.82,68.59 JDIMM1.63
DDR_A_D19: length 3.3
  BOTTOM w0.089: UC1.BF5 v1(68.97,102.41)
  BOTTOM w0.102: v1(59.19,65.42) 58.57,64.8 JDIMM1.58
DDR_A_D20: length 10.1
  BOTTOM w0.076: UC1.BG2 67.84,100.58 67.52,100.27 67.52,98.75 66.28,97.51 v1(64.31,97.51)
  BOTTOM w0.102: JDIMM1.50 56.57,65.72 55.98,66.32 v1(55.46,66.32)
DDR_A_D21: length 11.4
  BOTTOM w0.076: UC1.BG1 67.84,98.84
  BOTTOM w0.102: JDIMM1.46 55.57,63.72 55.8,63.94 55.8,64.82 54.74,65.87 54.74,67.06 55.18,67.49 v1(55.43,67.49) ; v1(64.71,96.12) 65.46,96.12 67.84,98.5 67.84,98.84
DDR_A_D22: length 4.7
  BOTTOM w0.089: UC1.BF1 v1(68.97,99.81)
  BOTTOM w0.102: JDIMM1.62 59.57,63.71 59.76,63.9 59.76,66.14 v1(59.2,66.7)
DDR_A_D23: length 2.6
  BOTTOM w0.089: UC1.BF2 v1(68.97,100.46)
  BOTTOM w0.102: v1(59.21,69.24) 58.7,69.75 58.7,70.13 58.82,70.25 JDIMM1.59
DDR_A_D24: length 8.2
  BOTTOM w0.076: UC1.BD2 70.08,100.51 70.08,99.88 70.03,99.83 70.03,99.38 70.02,99.38 70.02,99.36 69.75,99.08 69.75,98.16 69.62,98.03 69.62,97.38
  BOTTOM w0.102: v1(69.01,96.67) 69.62,97.28 69.62,97.38 ; v1(62,68.1) 61.86,68.1 60.98,68.97 60.98,69.42 60.82,69.58 JDIMM1.67
DDR_A_D25: length 7.3
  BOTTOM w0.076: UC1.BD1 70.36,99.46 69.91,99.02 69.91,97.41 69.89,97.38
  BOTTOM w0.102: JDIMM1.70 61.57,64.28 v1(62,64.71) ; v1(69.01,95.47) 69.14,95.47 69.89,96.23 69.89,97.38
DDR_A_D26: length 12.5
  BOTTOM w0.076: 72.19,99.23 71.54,99.88 71.54,100.57 71.53,100.57 71.53,101.41 71.09,101.85 UC1.BC4
  BOTTOM w0.102: v1(71.32,94) 71.75,94.43 71.75,95.2 72.19,95.63 72.19,99.23 ; JDIMM1.80 64.07,64.31 64.64,64.87 64.64,65.07 v1(65.46,65.88)
DDR_A_D27: length 12.8
  BOTTOM w0.076: UC1.BC5 71.09,102.55 71.37,102.27 71.37,101.83 71.7,101.5 71.7,99.97 72.44,99.23
  BOTTOM w0.102: v1(65.49,64.47) 65.07,64.06 JDIMM1.84 ; 72.44,99.23 72.44,95.51 72.13,95.2 72.13,93.54 v1(71.32,92.73)
DDR_A_D28: length 8.4
  BOTTOM w0.076: UC1.BD5 69.75,102.13 69.75,101.97 69.74,101.96 69.74,101.56 69.75,101.55 69.75,100.02 69.7,99.97 69.7,99.52 69.69,99.52 69.69,99.5 69.42,99.22 69.42,98.98 v1(69.01,98.58)
  BOTTOM w0.102: JDIMM1.66 60.57,64.56 v1(62,65.98)
DDR_A_D29: length 6.4
  BOTTOM w0.076: v1(69.01,97.94) 69.58,98.51 69.58,99.15 69.86,99.43 69.86,99.45 69.86,99.45 69.86,99.9 69.91,99.95 69.91,101.64 UC1.BD4
  BOTTOM w0.102: JDIMM1.71 61.82,69.59 v1(62,69.42)
DDR_A_D30: length 6.9
  BOTTOM w0.076: 71.73,99.2 71.09,99.84 UC1.BC1
  BOTTOM w0.102: JDIMM1.83 64.82,69.85 65.44,69.24 v1(65.44,68.46) ; v1(71.32,96.54) 71.73,96.95 71.73,99.2
DDR_A_D31: length 10.7
  BOTTOM w0.076: 71.96,99.09 71.96,99.22 71.37,99.81 71.37,100.51 UC1.BC2
  BOTTOM w0.102: v1(65.46,67.18) 64.59,68.05 64.59,69.39 63.82,70.15 JDIMM1.79 ; v1(71.32,95.27) 71.96,95.91 71.96,99.09
DDR_A_D32: length 13.3
  BOTTOM w0.076: 89.55,95.35 88.58,96.32 88.58,97.71 87.98,98.32 87.98,100.12 UC1.AB1
  BOTTOM w0.102: v1(89.7,91.76) 89.88,91.95 89.88,95.02 89.55,95.35 ; v1(91.75,66.03) 91.69,66.03 89.57,63.91 JDIMM1.174
DDR_A_D33: length 12.2
  BOTTOM w0.076: 89.09,95.35 88.18,96.26 88.18,97.71 87.81,98.08 87.81,99.89 87.68,100.02 87.68,100.61 87.86,100.78 UC1.AB2
  BOTTOM w0.102: v1(88.87,92.59) 88.87,93.23 89.36,93.72 89.36,95.07 89.09,95.35 ; v1(89.54,65.32) 89.45,65.32 88.57,64.44 JDIMM1.170
DDR_A_D34: length 1.9
  BOTTOM w0.076: UC1.AA4 v1(89.14,101.76)
  BOTTOM w0.102: v1(93.1,69.78) 92.82,70.05 JDIMM1.187
DDR_A_D35: length 5.3
  BOTTOM w0.076: UC1.AA5 v1(89.13,102.37)
  BOTTOM w0.102: v1(93.03,67.44) 92.57,66.98 JDIMM1.186
DDR_A_D36: length 12.6
  BOTTOM w0.076: UC1.AB5 87.55,102.33 87.55,102.07 87.35,101.87 87.35,99.82 87.43,99.75 87.43,97.08 87.47,97.04 87.47,95.8
  BOTTOM w0.102: 87.47,95.8 87.65,95.62 v1(87.65,94.45) ; JDIMM1.169 88.32,70.35 88.89,69.79 88.89,68.24 v1(89.5,67.63)
DDR_A_D37: length 12.4
  BOTTOM w0.076: 88.63,95.35 87.85,96.13 87.85,97.51 87.59,97.77 87.59,99.84 87.51,99.91 87.51,101.64 UC1.AB4
  BOTTOM w0.102: v1(88.04,93.42) 88.1,93.47 88.54,93.47 88.87,93.8 88.87,95.11 88.63,95.35 ; JDIMM1.173 89.2,70.92 89.2,69.07 89.35,68.91 v1(89.52,68.91)
DDR_A_D38: length 2.3
  BOTTOM w0.076: UC1.AA2 v1(89.14,100.53)
  BOTTOM w0.102: v1(91.74,64.6) 91.57,64.44 JDIMM1.182
DDR_A_D39: length 3.6
  BOTTOM w0.076: UC1.AA1 v1(89.14,99.88)
  BOTTOM w0.102: v1(93.07,68.61) 93.06,68.6 92.91,68.6 91.82,69.69 JDIMM1.183
DDR_A_D40: length 7
  BOTTOM w0.076: v1(89.57,98.11) 89.54,98.13 89.54,98.95 89.86,99.27 89.86,101.57 90.08,101.79 90.08,102.35 UC1.V5
  BOTTOM w0.102: JDIMM1.195 94.82,69.45 v1(94.56,69.19)
DDR_A_D41: length 7
  BOTTOM w0.076: v1(90.2,97.6) 90.27,97.66 90.27,98.75 90.19,98.82 90.19,100.51 UC1.V2
  BOTTOM w0.102: v1(94.58,68) 94.11,68 94,68.1 94,70.04 93.82,70.22 JDIMM1.191
DDR_A_D42: length 3.7
  BOTTOM w0.076: UC1.U1 91.21,99.71 91.63,99.29 v1(92.05,99.29)
  BOTTOM w0.102: JDIMM1.207 97.82,70.35 97.9,70.28 97.9,68.85 v1(97.87,68.82)
DDR_A_D43: length 4.4
  BOTTOM w0.076: UC1.U2 91.36,100.78 91.61,100.53 v1(91.61,100.5)
  BOTTOM w0.102: JDIMM1.203 96.82,68.65 v1(97.85,67.63)
DDR_A_D44: length 8.6
  BOTTOM w0.076: UC1.V1 90.47,98.02 91.15,97.33 91.15,96.71 v1(90.9,96.46)
  BOTTOM w0.102: JDIMM1.194 94.57,64.09 95.18,64.7 95.18,66.35 94.74,66.8 v1(94.57,66.8)
DDR_A_D45: length 11.3
  BOTTOM w0.076: v1(91.85,95.63) 91.73,95.63 91.56,95.47 91.23,95.47 89.75,96.95 89.75,97.78 90.03,98.06 90.03,101.5 90.33,101.8 90.33,101.94 UC1.V4
  BOTTOM w0.102: JDIMM1.190 93.57,64.51 v1(94.59,65.53)
DDR_A_D46: length 2.9
  BOTTOM w0.076: v1(91.66,102.41) 91.33,102.74 UC1.U5
  BOTTOM w0.102: JDIMM1.208 98.07,64.84 v1(97.84,65.08)
DDR_A_D47: length 4.4
  BOTTOM w0.076: v1(91.61,101.8) 91.33,102.09 UC1.U4
  BOTTOM w0.102: v1(97.85,66.36) 97.35,65.87 97.35,64.07 97.07,63.8 JDIMM1.204
DDR_A_D48: length 5.5
  BOTTOM w0.076: v1(93.76,98.11) 93.76,98.74 92.71,99.79 92.71,100.51 UC1.R2
  BOTTOM w0.102: JDIMM1.211 98.82,69.69 v1(99.48,69.03)
DDR_A_D49: length 5.3
  BOTTOM w0.076: UC1.P5 93.72,102.84 93.95,103.07 v1(94.17,103.07)
  BOTTOM w0.102: v1(101.71,66.79) 101.71,66.79 100.07,65.16 JDIMM1.216
DDR_A_D50: length 10.9
  BOTTOM w0.076: v1(96.72,97.43) 96.38,97.43 95.37,96.42 94.74,96.42 92.66,98.5 92.66,99.52 92.54,99.64 92.54,101.64 UC1.R4
  BOTTOM w0.102: JDIMM1.212 99.07,64.19 99.23,64.35 v1(99.42,64.35)
DDR_A_D51: length 5
  BOTTOM w0.076: UC1.P4 v1(94.17,102.37)
  BOTTOM w0.102: v1(104.14,66.89) 103.07,65.83 JDIMM1.228
DDR_A_D52: length 13.1
  BOTTOM w0.076: v1(96.11,95.69) 95.1,95.69 92.43,98.36 92.43,99.51 92.38,99.57 92.38,102.13 UC1.R5
  BOTTOM w0.102: v1(99.48,67.71) 99.99,68.22 99.99,70.16 99.82,70.32 JDIMM1.215
DDR_A_D53: length 2.5
  BOTTOM w0.076: v1(94.15,100.47) 94.04,100.47 UC1.P2
  BOTTOM w0.102: JDIMM1.229 103.32,70.21 v1(104.13,69.41)
DDR_A_D54: length 6.4
  BOTTOM w0.076: v1(94.71,97.22) 94.71,98.05 92.99,99.77 UC1.R1
  BOTTOM w0.102: v1(101.66,65.46) 102.07,65.05 JDIMM1.224
DDR_A_D55: length 4.7
  BOTTOM w0.076: v1(94.16,99.76) 94.11,99.76 UC1.P1
  BOTTOM w0.102: JDIMM1.225 102.32,69.24 103.44,68.13 v1(104.12,68.13)
DDR_A_D56: length 1.9
  BOTTOM w0.076: v1(95.08,101.73) UC1.M4
  BOTTOM w0.102: v1(105.38,69.71) 105.32,69.77 JDIMM1.237
DDR_A_D57: length 8.3
  BOTTOM w0.076: UC1.M1 95.5,100.01 97.75,97.76 v1(99.54,97.76)
  BOTTOM w0.102: JDIMM1.236 105.07,63.89 104.84,64.13 104.84,65.18 v1(105.41,65.76)
DDR_A_D58: length 5.4
  BOTTOM w0.076: UC1.L4 96.32,102.09 v1(96.65,101.76)
  BOTTOM w0.102: JDIMM1.232 104.07,65.56 104.81,66.3 104.81,66.58 v1(105.38,67.15)
DDR_A_D59: length 3.6
  BOTTOM w0.076: UC1.L2 96.5,100.52 v1(96.68,100.52)
  BOTTOM w0.102: v1(105.38,68.44) 104.93,68.89 104.93,69.66 104.32,70.27 JDIMM1.233
DDR_A_D60: length 5.1
  BOTTOM w0.076: UC1.M5 95.47,102.71 v1(95.09,102.38)
  BOTTOM w0.102: JDIMM1.245 107.32,69.3 109.21,67.42 v1(109.36,67.42)
DDR_A_D61: length 11.8
  BOTTOM w0.076: v1(102.14,97.32) 97.92,97.32 95.22,100.02 95.22,100.51 UC1.M2
  BOTTOM w0.102: v1(109.34,68.69) 109.11,68.69 108.32,69.48 JDIMM1.249
DDR_A_D62: length 4.2
  BOTTOM w0.076: UC1.L5 v1(96.67,103.07)
  BOTTOM w0.102: JDIMM1.246 107.57,64.6 107.95,64.97 v1(109.37,64.97)
DDR_A_D63: length 5.8
  BOTTOM w0.076: UC1.L1 96.68,99.69 v1(97.69,99.69)
  BOTTOM w0.102: JDIMM1.250 108.57,63.6 110,65.02 110,65.56 109.42,66.15 v1(109.36,66.15)
DDR_A_DQS0: length 12.5
  BOTTOM w0.076: UC1.BP5 63.25,102.51 62.94,102.82 62.38,102.82 62.21,102.65 61.63,102.65 61.52,102.54 61.14,102.54 58.9,100.3
  BOTTOM w0.102: v1(57.91,97.33) 57.91,97.56 57.76,97.72 57.75,97.72 57.75,99.15 58.9,100.3 ; JDIMM1.13 47.32,68.76 47.09,68.53 46.6,68.53 46.46,68.39 v1(46.45,68.39)
DDR_A_DQS1: length 11.8
  BOTTOM w0.076: UC1.BK3 65.79,101.12 65.79,100.84 65.76,100.7 65.67,100.51 65.51,100.38 65.37,100.24 65.37,99.72 64.62,98.97 64.48,98.97 63.93,98.97 63.37,98.41 62.45,98.41 62.21,98.17 62.21,97.05 61.92,96.77 61.71,96.77 v1(61.48,96.54)
  BOTTOM w0.102: v1(52.49,66.14) 52.79,65.84 52.98,65.84 53.24,65.58 53.24,64.56 52.57,63.9 JDIMM1.34
DDR_A_DQS2: length 13.1
  BOTTOM w0.076: 68.32,98.2 68.32,98.22 68.29,98.25 68.29,101.15 UC1.BF3
  BOTTOM w0.102: JDIMM1.55 57.82,69.2 57.98,69.04 57.98,68.05 57.67,67.74 57.42,67.74 v1(57.27,67.59) ; v1(64.69,94.32) 64.86,94.49 65.53,94.49 68.32,97.27 68.32,98.2
DDR_A_DQS3: length 8.5
  BOTTOM w0.076: v1(71.32,98.45) 71.32,98.32 71.2,98.2 70.94,98.2 70.81,98.32 70.81,101.34 70.91,101.44 UC1.BC3
  BOTTOM w0.102: JDIMM1.76 63.07,63.66 62.8,63.93 62.8,65.15 63.65,66 64.07,66 64.17,65.9 v1(64.17,65.65)
DDR_A_DQS4: length 18
  BOTTOM w0.076: UC1.AB3 88.03,101.51 88.14,101.51 88.25,101.4 88.25,98.62 88.92,97.95 88.92,97.19 90.73,95.38 90.73,94.99 90.7,94.96 90.7,94.94
  BOTTOM w0.102: v1(91.79,68.02) 91.79,67.81 91.64,67.66 91.05,67.66 90.55,68.16 90.55,69.98 90.82,70.25 JDIMM1.179 ; 90.7,94.94 90.7,93.52 91.48,92.73 91.48,91.06 91.12,90.7 90.75,90.7 90.58,90.88 v1(90.58,91)
DDR_A_DQS5: length 12.3
  BOTTOM w0.076: UC1.V3 90.66,101.44 90.77,101.33 90.77,99.54 90.95,99.36 90.95,97.77 93.18,95.55 93.18,95.5 93.19,95.49
  BOTTOM w0.102: 93.19,95.49 93.29,95.38 93.29,95.01 93.1,94.82 92.86,94.82 v1(92.81,94.87) ; v1(95.98,66.32) 96.32,65.98 96.38,65.98 96.62,65.74 96.62,64.38 96.07,63.84 JDIMM1.200
DDR_A_DQS6: length 9.3
  BOTTOM w0.076: UC1.R3 93.28,101.14 93.28,99.76 93.85,99.2 94.42,99.2 94.82,99.59 95.18,99.59 95.88,98.9 95.88,98.83 95.79,98.74 v1(95.47,98.74)
  BOTTOM w0.102: JDIMM1.221 101.32,70.19 101.05,69.92 101.05,68.55 101.3,68.3 101.44,68.3 101.72,68.58 101.72,68.73 v1(101.7,68.75)
DDR_A_DQS7: length 11.5
  BOTTOM w0.076: v1(98.62,98.71) 98.36,98.71 98.1,98.45 97.3,98.45 95.79,99.95 95.79,101.14 UC1.M3
  BOTTOM w0.102: v1(107.19,67.73) 107.22,67.71 107.83,67.71 108.09,67.44 108.09,66.37 108.09,66.36 108.07,66.36 106.45,64.74 106.45,63.93 106.57,63.81 JDIMM1.242
DDR_A_DQS#0: length 12.3
  BOTTOM w0.076: UC1.BR5 62.87,102.16 62.99,102.16 63.09,102.26 63.09,102.43 62.88,102.64 62.5,102.64 62.34,102.48 61.76,102.48 61.61,102.33 61.25,102.33 59.07,100.16 59.07,100.13 59.07,100.13
  BOTTOM w0.102: JDIMM1.11 46.82,70.24 47.1,69.97 47.1,68.86 46.99,68.76 46.67,68.76 46.48,68.95 46.48,69.14 46.46,69.15 v1(46.46,69.16) ; v1(58.36,97.77) 58.25,97.66 58.14,97.66 57.99,97.81 57.99,99.05 59.07,100.13
DDR_A_DQS#1: length 11.8
  BOTTOM w0.076: v1(61.48,97.18) 61.48,97.09 61.64,96.93 61.85,96.93 62.04,97.12 62.04,98.24 62.38,98.58 63.3,98.58 63.86,99.13 64.55,99.13 65.2,99.79 65.2,100.31 65.4,100.5 65.54,100.61 65.54,100.62 65.63,100.86 65.63,101.32 65.52,101.44 UC1.BL3
  BOTTOM w0.102: JDIMM1.32 52.07,62.85 52.07,63.98 52.2,64.11 52.46,64.11 53.01,64.65 53.01,65.49 52.89,65.61 52.6,65.61 52.49,65.49 v1(52.49,65.3)
DDR_A_DQS#2: length 12.9
  BOTTOM w0.076: 68.09,98.2 68.09,98.22 68.12,98.25 68.12,101.42 68.05,101.5 67.9,101.5 UC1.BG3
  BOTTOM w0.102: v1(64.69,94.95) 64.69,94.82 64.8,94.72 65.44,94.72 68.09,97.37 68.09,98.2 ; v1(57.27,68.28) 57.27,68.13 57.43,67.97 57.58,67.97 57.75,68.14 57.75,68.95 57.6,69.1 57.6,69.93 57.32,70.2 JDIMM1.53
DDR_A_DQS#3: length 8.6
  BOTTOM w0.076: UC1.BD3 70.65,101.14 70.65,98.26 70.87,98.03 71.11,98.03 v1(71.32,97.81)
  BOTTOM w0.102: v1(64.18,66.41) 63.99,66.23 63.56,66.23 62.57,65.25 JDIMM1.74
DDR_A_DQS#4: length 18.2
  BOTTOM w0.076: 90.93,94.94 90.93,94.96 90.89,94.99 90.89,95.45 89.08,97.26 89.08,98.02 88.42,98.69 88.42,101.16 UC1.AA3
  BOTTOM w0.102: 90.93,94.94 90.93,93.61 91.71,92.82 91.71,90.97 91.22,90.47 90.63,90.47 v1(90.52,90.37) ; JDIMM1.177 90.32,68.07 90.96,67.44 91.64,67.44 v1(91.79,67.29)
DDR_A_DQS#5: length 12.2
  BOTTOM w0.076: 93.35,95.65 93.34,95.66 93.29,95.66 91.12,97.84 91.12,99.43 90.93,99.61 90.93,101.16 UC1.U3
  BOTTOM w0.102: JDIMM1.198 95.57,63.87 95.74,64.04 95.95,64.04 96.39,64.48 96.39,65.65 96.29,65.75 96.11,65.75 95.98,65.62 v1(95.98,65.5) ; 93.35,95.65 93.52,95.48 93.52,94.92 93.22,94.61 v1(93.22,94.42)
DDR_A_DQS#6: length 9.4
  BOTTOM w0.076: UC1.P3 93.44,101.16 93.44,99.83 93.91,99.36 94.35,99.36 94.75,99.76 95.25,99.76 96.04,98.96 96.04,98.76 95.89,98.6 v1(95.89,98.33)
  BOTTOM w0.102: JDIMM1.219 100.82,68.44 101.2,68.07 101.62,68.07 v1(101.71,67.99)
DDR_A_DQS#7: length 11.4
  BOTTOM w0.076: UC1.L3 96.2,101.47 96.06,101.47 95.96,101.37 95.96,100.02 97.36,98.61 98.03,98.61 98.3,98.88 98.3,99.03 v1(98.08,99.25)
  BOTTOM w0.102: v1(107.23,66.99) 107.23,67.2 107.51,67.48 107.73,67.48 107.85,67.36 107.85,66.47 106.22,64.84 106.22,63.8 106.07,63.65 JDIMM1.240
DDR_A_MA0: length 13
  BOTTOM w0.076: 81.07,95.99 81.07,96.03 81.4,96.36 81.89,96.36 82.52,96.99 82.52,98.24 83.22,98.94 83.22,101.15 82.93,101.44 UC1.AH3
  BOTTOM w0.168: JDIMM1.144 80.07,65.48 80.37,65.78 81.91,65.78 v1(81.99,65.69) ; v1(81.55,94.75) 81.44,94.75 81.07,95.12 81.07,95.99
DDR_A_MA1: length 3.3
  BOTTOM w0.076: UC1.AP4 77.95,102.09 v1(78.28,101.76)
  BOTTOM w0.168: v1(77.41,68.35) 77.32,68.43 JDIMM1.133
DDR_A_MA2: length 17.5
  BOTTOM w0.076: UC1.AN4 79.19,101.53 79.19,99.42 79.92,98.69
  BOTTOM w0.168: v1(76.71,90.19) 78.84,90.19 80.49,91.84 80.49,98.12 79.92,98.69 ; v1(77.41,64.69) 77.52,64.58 77.52,64.22 77.07,63.77 JDIMM1.132
DDR_A_MA3: length 8.5
  BOTTOM w0.076: UC1.AP5 77.33,102.16 77.33,99.65 v1(76.71,99.03)
  BOTTOM w0.168: JDIMM1.131 76.82,69.36 76.71,69.24 76.71,67.78 77.31,67.18 v1(77.44,67.18)
DDR_A_MA4: length 7.5
  BOTTOM w0.168: JDIMM1.128 76.07,63.72 76.75,64.39 76.75,65.75 76.97,65.98 v1(77.41,65.98) ; v1(76.71,97.76) 76.86,97.76 77.12,98.02 77.12,98.8 77.57,99.25 77.57,100.45 UC1.AP2
DDR_A_MA5: length 9.6
  BOTTOM w0.168: UC1.AP1 77.9,99 77.56,98.66 77.56,97.78 76.91,97.13 v1(76.71,97.13) ; v1(75.32,67.03) 75.5,67.21 76.07,67.21 76.25,67.04 76.25,66.58 76.02,66.36 75.95,66.36 75.78,66.19 75.78,65.85 75.95,65.68 76.02,65.68 76.19,65.51 76.19,64.95 75.9,64.65 75.9,64.21 75.57,63.89 JDIMM1.126
DDR_A_MA6: length 8.4
  BOTTOM w0.076: 78.19,99.83 78.19,101.14 UC1.AP3
  BOTTOM w0.168: v1(76.71,95.86) 76.76,95.86 77.94,97.04 77.94,98.43 78.19,98.69 78.19,99.83 ; JDIMM1.127 75.82,69.54 75.65,69.37 v1(75.33,69.37)
DDR_A_MA7: length 15.5
  BOTTOM w0.076: 79.28,96.71 79.03,96.95 79.03,97.87 78.86,98.04 78.86,99.91 UC1.AN1
  BOTTOM w0.168: v1(76.71,92.68) 78.32,92.68 78.8,92.2 79.06,92.2 79.28,92.42 79.28,96.71 ; JDIMM1.122 74.57,64.08 74.19,64.47 74.19,65.36 74.36,65.53 74.6,65.53 74.8,65.33 74.8,64.78 75.25,64.33 v1(75.25,64.25)
DDR_A_MA8: length 12
  BOTTOM w0.076: UC1.AN3 78.36,101.16 78.36,100.02 78.48,99.9 78.48,99.78 78.58,99.67
  BOTTOM w0.168: 78.58,99.67 78.58,98.44 78.34,98.2 78.34,96.73 77.7,96.09 77.7,94.49 77.17,93.95 v1(76.71,93.95) ; JDIMM1.125 75.32,70.08 74.83,69.58 74.83,68.65 75.28,68.2 v1(75.32,68.2)
DDR_A_MA9: length 14.1
  BOTTOM w0.076: 75.79,99.08 76.69,99.98 76.69,101.51 UC1.AT4
  BOTTOM w0.168: 75.79,99.08 75.79,95.5 v1(76.71,94.59) ; JDIMM1.121 74.32,69.75 73.98,69.41 73.98,69.17 72.79,67.99 v1(72.79,66.11)
DDR_A_MA10: length 4.3
  BOTTOM w0.076: 82.58,99.7 82.58,100.44 UC1.AH2
  BOTTOM w0.168: JDIMM1.146 82.57,63.55 81.98,64.15 v1(81.98,64.45) ; 82.58,99.7 82.11,99.23 v1(81.59,99.23)
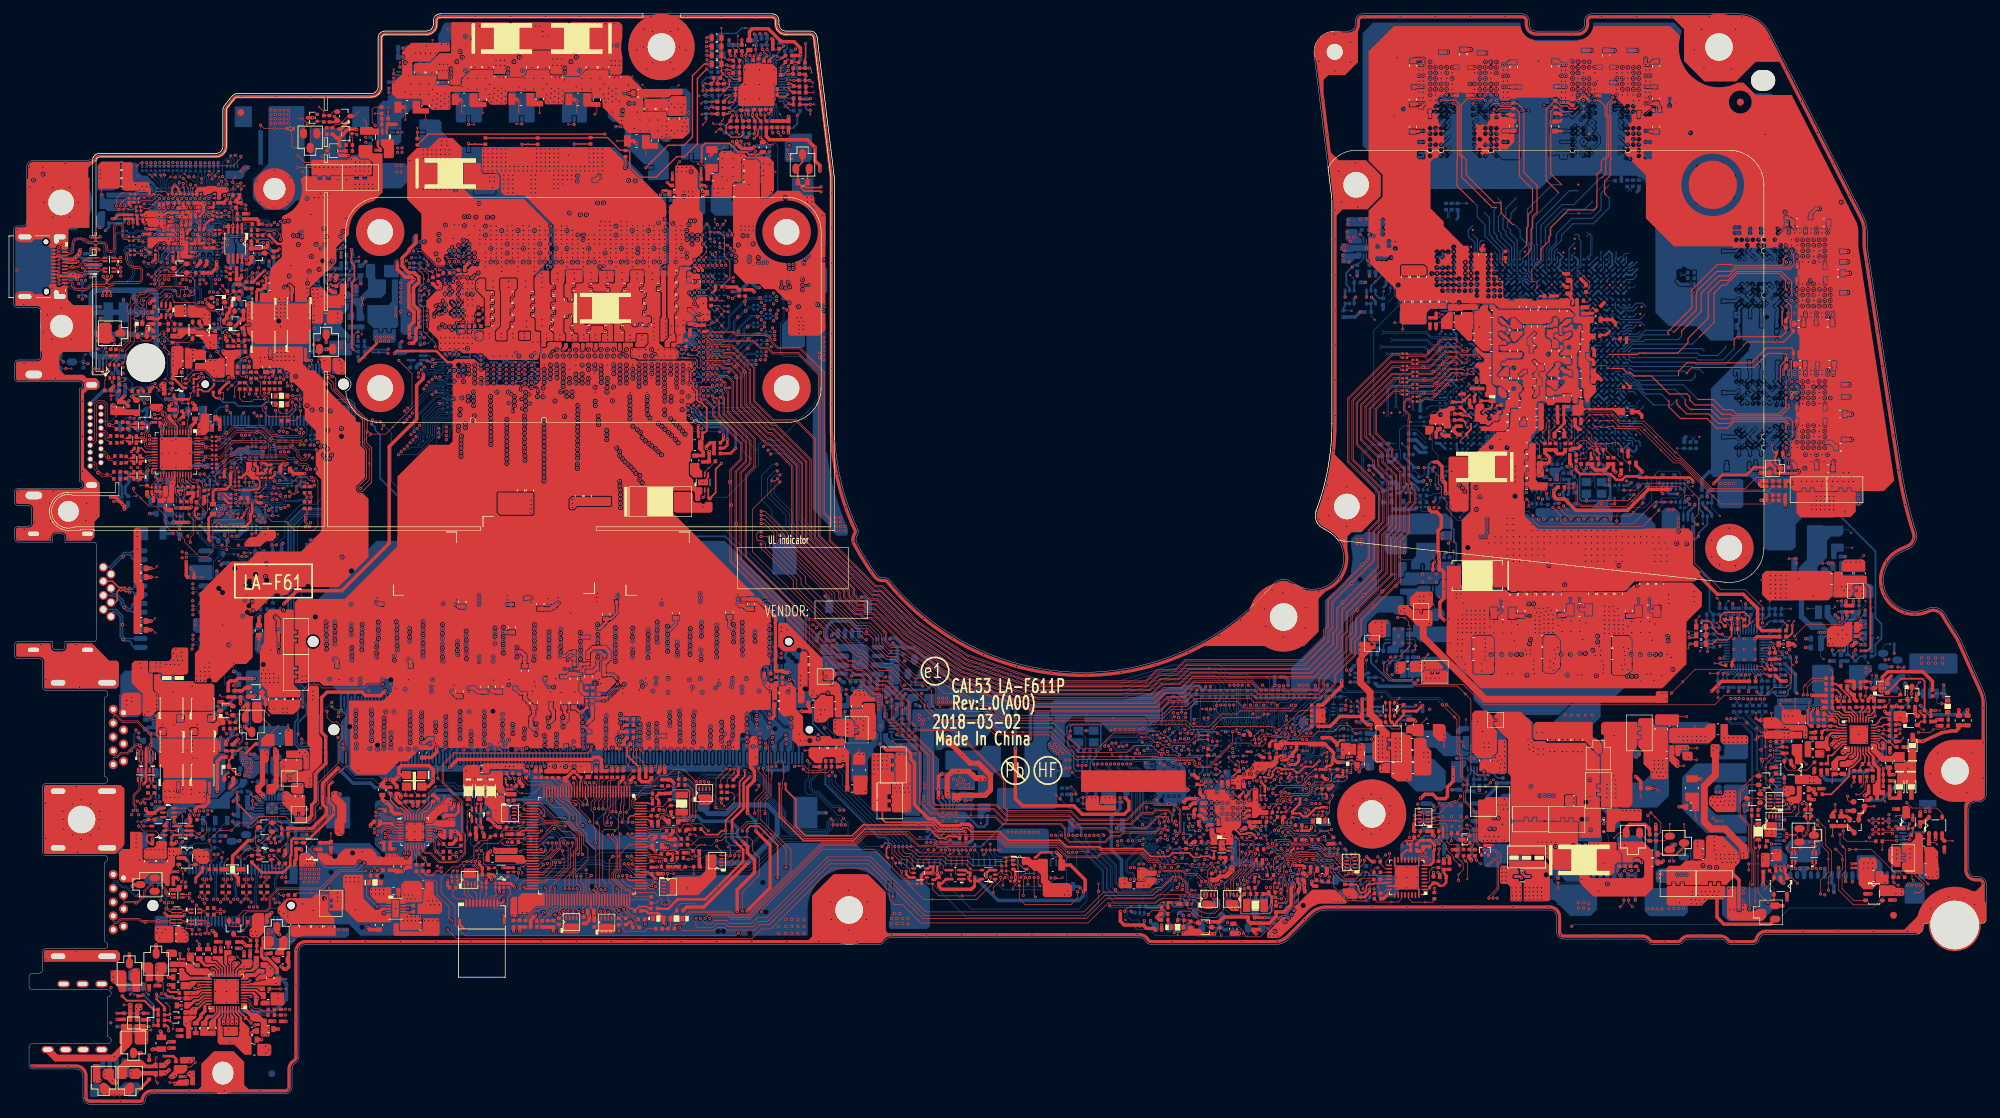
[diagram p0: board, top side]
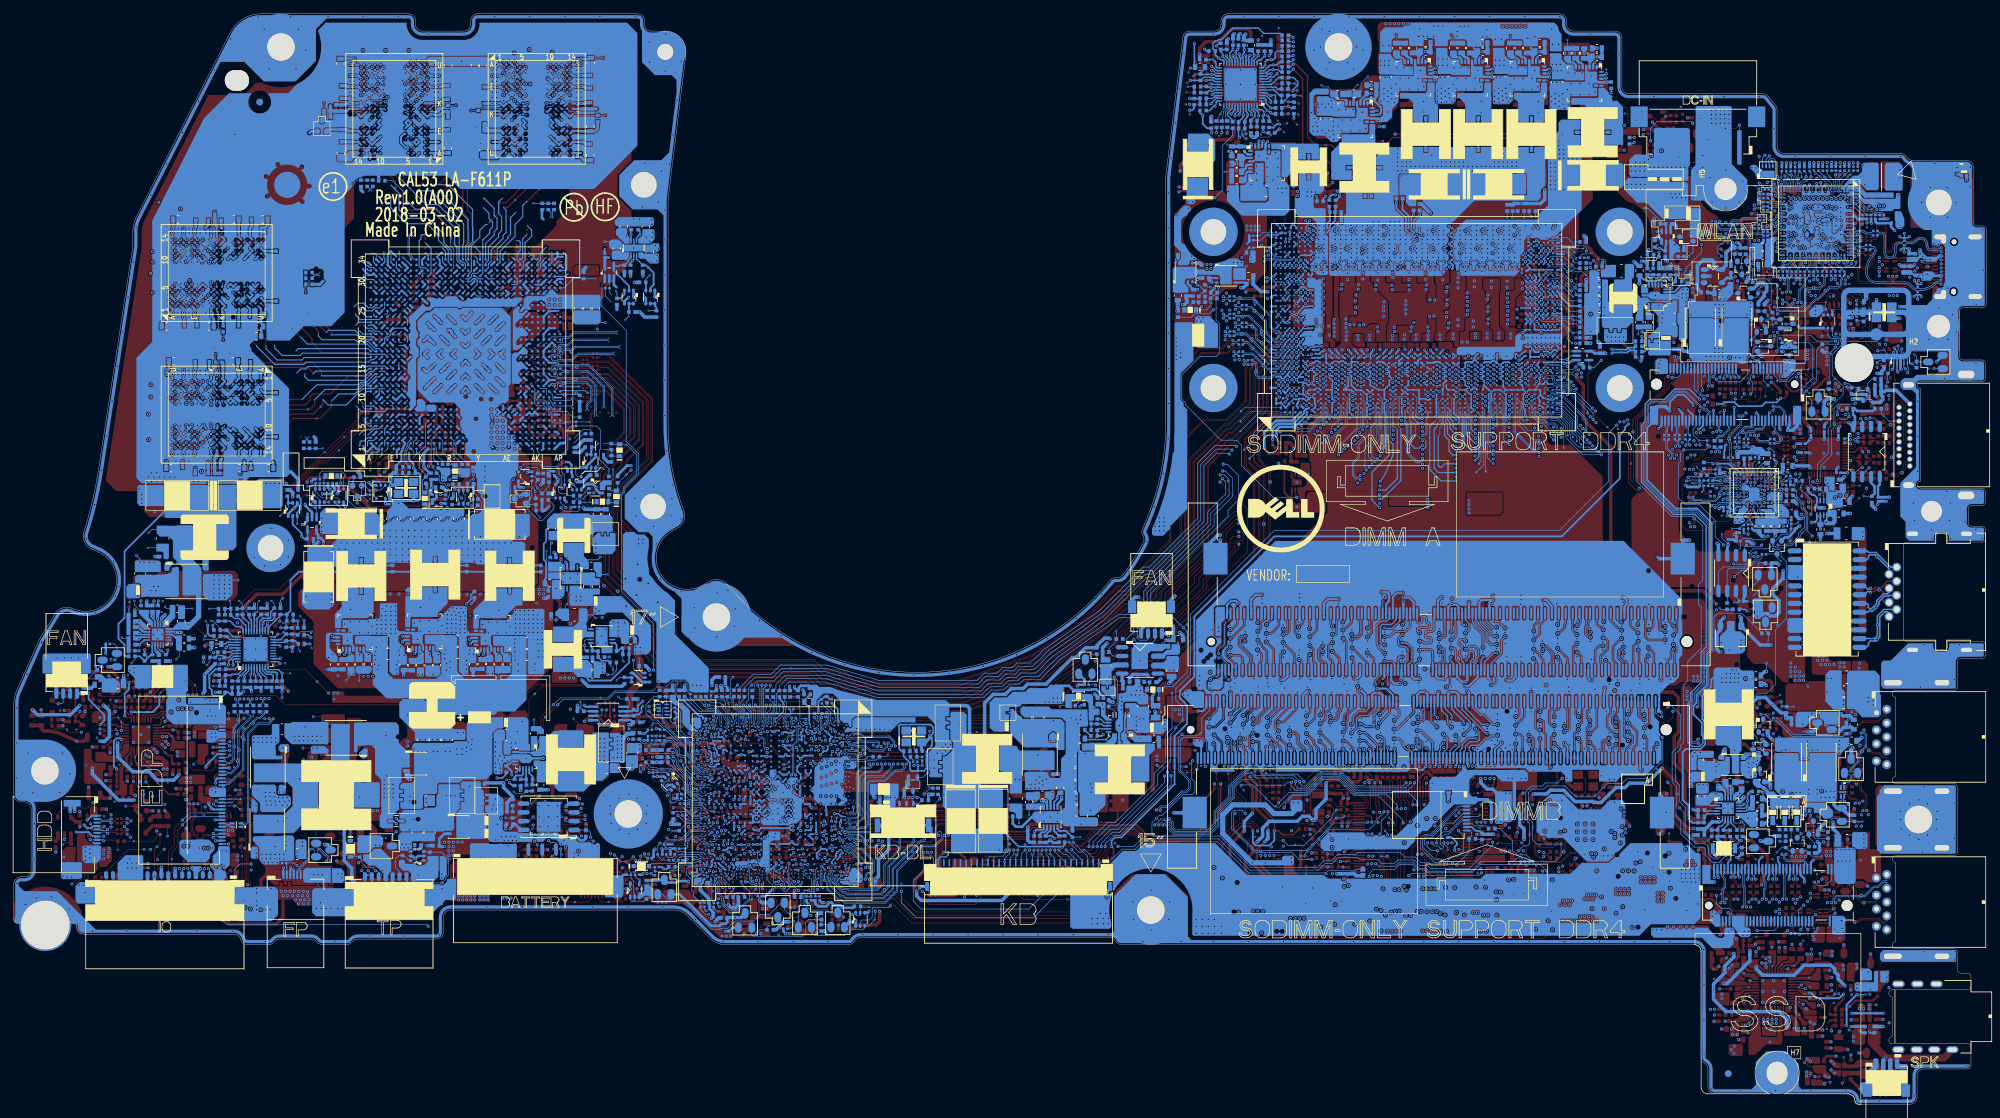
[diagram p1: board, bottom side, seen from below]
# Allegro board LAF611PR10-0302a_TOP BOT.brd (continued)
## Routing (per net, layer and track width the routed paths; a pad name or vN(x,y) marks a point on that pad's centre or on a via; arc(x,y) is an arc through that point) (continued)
DDR_A_MA11: length 18.3
  BOTTOM w0.076: 79.44,98.14 79.44,98.52 79.03,98.94 79.03,100.71 78.95,100.78 UC1.AN2
  BOTTOM w0.168: JDIMM1.120 74.07,63.64 73.65,64.06 73.65,64.6 73.42,64.83 73.42,65.73 73.96,66.27 74.72,66.27 75.15,65.83 v1(75.31,65.83) ; 79.44,98.14 79.85,97.73 79.85,92.02 79.25,91.41 v1(76.71,91.41)
DDR_A_MA12: length 9.7
  BOTTOM w0.076: UC1.AU4 75.39,101.89 74.81,101.32 74.81,99.94 74.47,99.6 v1(73.88,99.6)
  BOTTOM w0.168: v1(70.81,66.54) 71.68,66.54 72.21,67.08 72.21,68.23 73.4,69.41 73.4,69.65 73.82,70.07 JDIMM1.119
DDR_A_MA13: length 6.6
  BOTTOM w0.076: UC1.AE3 85.82,101.06 85.82,100.64 85.89,100.57 85.89,98.08 85.82,98.01 85.82,97.56 v1(85.78,97.51)
  BOTTOM w0.168: JDIMM1.158 85.57,63.28 85.65,63.36 85.65,63.74 85.99,64.08 v1(87.02,64.08)
DDR_A_MA14_WE#: length 6.8
  BOTTOM w0.076: v1(84.57,98.95) 84.91,99.29 84.91,102.33 84.83,102.4 84.39,102.4 84.38,102.39 83.97,102.39 UC1.AG4
  BOTTOM w0.168: v1(84.43,69.45) 83.82,70.05 JDIMM1.151
DDR_A_MA15_CAS#: length 6.5
  BOTTOM w0.076: UC1.AD1 86.18,96.54 85.85,96.21 v1(85.78,96.21)
  BOTTOM w0.168: JDIMM1.156 85.07,64.59 84.94,64.72 v1(84.48,64.72)
DDR_A_MA16_RAS#: length 7.7
  BOTTOM w0.076: v1(84.11,101.73) 84.07,101.77 83.25,101.77 UC1.AH4
  BOTTOM w0.168: JDIMM1.152 84.07,63.84 83.66,64.25 83.66,65.84 84.08,66.27 84.68,66.27 85.02,66.61 85.02,67.42 v1(84.49,67.95)
DDR_A_ODT0: length 20.9
  BOTTOM w0.076: 86.39,95.58 86.74,95.92 86.74,100 86.71,100.02 86.71,101.16 86.44,101.44 UC1.AD3
  BOTTOM w0.168: v1(87.02,68.96) 86.89,68.83 85.96,68.83 84.82,69.97 JDIMM1.155 ; v1(87.78,86.33) 88.87,87.42 88.87,91.45 88.42,91.9 86.39,93.92 86.39,95.58
DDR_A_ODT1: length 20.8
  BOTTOM w0.076: 86.18,95.86 86.55,96.23 86.55,100.83 86.28,101.1 86.01,101.1 85.82,101.29 85.82,101.71 UC1.AE4
  BOTTOM w0.168: JDIMM1.161 86.32,70.26 86.56,70.03 86.84,69.91 87.51,69.91 87.63,69.86 88.12,69.36 88.12,66.7 87.82,65.98 87.1,65.25 v1(87.02,65.25) ; v1(87.66,90.13) 87.26,90.73 86.95,91.19 85.82,93.92 85.82,95.51 86.18,95.86
DDR_A_PAR: length 15.9
  BOTTOM w0.076: 83.38,98.73 83.38,101.36 83.46,101.44 UC1.AG3
  BOTTOM w0.168: 83.38,98.73 83.22,98.56 83.22,95.47 82.69,94.94 82.01,94.94 v1(81.58,95.37) ; v1(81.95,66.98) 81.55,66.98 81.32,66.76 80.45,66.76 80.28,66.93 80.28,67.35 80.45,67.52 80.98,67.52 81.09,67.62 81.09,68.23 80.93,68.39 80.21,68.39 79.9,68.7 79.9,70.04 79.82,70.11 JDIMM1.143
DDR_B_ACT#: length 6.6
  BOTTOM w0.089: UC1.AT9 76.6,105.67 v1(76.74,105.67)
  BOTTOM w0.168: JDIMM2.114 75.57,51.03 75.34,51.26 75.34,51.81 74.71,52.44 73.64,52.44 73.35,52.73 73.35,53.77 v1(73.89,54.31)
DDR_B_ALERT#: length 4.9
  BOTTOM w0.076: v1(77.57,104.99) 77.57,104.95 77.33,104.7 UC1.AR8
  BOTTOM w0.168: v1(73.84,52.95) 74.91,52.95 75.81,52.05 75.81,51.5 76.08,51.24 JDIMM2.116
DDR_B_BA0: length 2.1
  BOTTOM w0.076: v1(83.14,105.02) 83,105.02 UC1.AH8
  BOTTOM w0.168: v1(86.58,51.57) JDIMM2.150
DDR_B_BA1: length 3.8
  BOTTOM w0.076: UC1.AH9 82.58,105.35 v1(82.22,104.99)
  BOTTOM w0.168: JDIMM2.145 85.32,57.37 84.94,56.98 84.94,56.25 v1(85.64,55.55)
DDR_B_BG0: length 6.8
  BOTTOM w0.076: UC1.AR9 77.07,105.35 v1(76.75,105.03)
  BOTTOM w0.168: JDIMM2.115 75.83,57.13 72.34,53.65 v1(72.2,53.65)
DDR_B_BG1: length 5.9
  BOTTOM w0.076: UC1.AR7 76.96,104.05 v1(76.57,103.66)
  BOTTOM w0.168: v1(72.19,54.96) 72.98,54.96 75.32,57.3 JDIMM2.113
DDR_B_CKE0: length 6.1
  BOTTOM w0.089: v1(76.72,104.44) 76.69,104.41 76.56,104.41 UC1.AT8
  BOTTOM w0.168: v1(70.7,54.94) 71.33,54.94 72.69,56.29 73.17,56.29 74.32,57.45 JDIMM2.109
DDR_B_CKE1: length 7.1
  BOTTOM w0.089: v1(76.74,106.32) 76.6,106.32 UC1.AT10
  BOTTOM w0.168: JDIMM2.110 74.57,51.01 74.81,51.24 74.81,51.63 74.5,51.94 73.44,51.94 72.41,52.97 72.05,52.97 71.73,53.29 70.82,53.29 v1(70.7,53.41)
DDR_B_CLK0: length 4.3
  BOTTOM w0.076: v1(79.52,105.68) 79.86,105.35 UC1.AM9
  BOTTOM w0.102: JDIMM2.137 81.32,57.18 81.25,57.1 81.25,55.73 81.56,55.42 82.05,55.42 v1(82.24,55.23)
DDR_B_CLK1: length 3.8
  BOTTOM w0.076: UC1.AM7 80.26,104.37 v1(80.39,104.37)
  BOTTOM w0.102: v1(82.36,52.84) 82.2,52.68 81.89,52.68 81.58,52.37 81.58,51.46 JDIMM2.138
DDR_B_CLK#0: length 4.4
  BOTTOM w0.076: UC1.AN9 79.23,105.35 79.5,105.09 v1(79.52,105.09)
  BOTTOM w0.102: v1(82.23,56.04) 82.23,55.8 82.08,55.65 81.65,55.65 81.48,55.83 81.48,56.98 81.6,57.1 81.71,57.1 81.83,57.21 JDIMM2.139
DDR_B_CLK#1: length 3.7
  BOTTOM w0.076: UC1.AM8 v1(80.39,105.02)
  BOTTOM w0.102: v1(82.36,52.25) 82.36,52.32 82.23,52.45 81.98,52.45 81.8,52.27 81.8,51.5 81.9,51.4 82.01,51.4 82.08,51.34 JDIMM2.140
DDR_B_CS#0: length 4.3
  BOTTOM w0.076: UC1.AF11 84.59,106.65 v1(84.95,106.29)
  BOTTOM w0.168: v1(87.78,55.15) 86.32,56.61 JDIMM2.149
DDR_B_CS#1: length 7.3
  BOTTOM w0.076: v1(85.82,103.7) 85.77,103.7 UC1.AE7
  BOTTOM w0.168: JDIMM2.157 88.32,57.35 89.44,56.23 90.65,56.23 91.11,55.77 91.11,54.46 91.69,53.88 v1(91.84,53.72)
DDR_B_D0: length 6.8
  BOTTOM w0.076: UC1.BT11 61.87,106.37 61.73,106.37 61.48,106.13 60.88,106.13 60.68,105.93 59.82,105.93
  BOTTOM w0.089: 59.82,105.93 59.76,105.93 59.41,106.27 v1(58.98,106.27)
  BOTTOM w0.102: v1(49.46,53.18) 49.08,52.8 JDIMM2.8
DDR_B_D1: length 9
  BOTTOM w0.076: UC1.BR11 62.3,106.15 61.87,106.15 61.69,105.96 60.95,105.96 60.65,105.66 59.82,105.66
  BOTTOM w0.089: 59.35,105.23 59.39,105.23 59.82,105.66
  BOTTOM w0.102: v1(49.46,54.46) 48.74,55.18 48.74,57.34 48.83,57.43 JDIMM2.7 ; 59.35,105.23 v1(58.52,105.23)
DDR_B_D2: length 8
  BOTTOM w0.076: UC1.BT9 61.02,105.8 60.53,105.31 v1(60.53,104.88)
  BOTTOM w0.102: v1(51.76,55.17) 50.52,53.92 50.52,52.08 50.99,51.61 50.99,51.27 51.08,51.18 JDIMM2.16
DDR_B_D3: length 10.2
  BOTTOM w0.076: UC1.BR8 62.74,104.67 62.28,104.21 60.54,104.21 59.78,103.45 59.4,103.45 v1(59.33,103.52)
  BOTTOM w0.102: v1(51.77,52.63) 52.33,53.18 JDIMM2.21
DDR_B_D4: length 6.8
  BOTTOM w0.076: UC1.BP11 63.08,106.89 61.88,106.89 61.3,106.31 59.77,106.31 v1(59.37,106.71)
  BOTTOM w0.102: JDIMM2.4 48.08,51.7 v1(47.61,52.16)
DDR_B_D5: length 6.5
  BOTTOM w0.076: UC1.BN11 63.57,107.06 61.72,107.06 61.43,106.77 v1(60.57,106.77)
  BOTTOM w0.102: JDIMM2.3 47.83,56.63 47.27,56.08 v1(46.96,56.08)
DDR_B_D6: length 9.1
  BOTTOM w0.076: UC1.BP8 63.19,105.01 62.87,105.33 62.58,105.33 62.41,105.16 62.41,104.65 62.21,104.44 60.48,104.44 60.05,104.01 v1(59.69,104.01)
  BOTTOM w0.102: JDIMM2.20 52.08,51.46 51.14,52.39 51.14,53.26 v1(51.78,53.9)
DDR_B_D7: length 4.8
  BOTTOM w0.076: v1(61.65,105.23) 61.85,105.23 62.11,105.49 63.2,105.49 63.28,105.41 63.64,105.41 UC1.BN8
  BOTTOM w0.102: v1(51.76,56.44) 51.7,56.44 51.33,56.81 JDIMM2.17
DDR_B_D8: length 6.6
  BOTTOM w0.102: v1(65.77,106.91) 65.34,107.34 UC1.BL12 ; JDIMM2.24 53.08,55.41 v1(53.56,55.89)
DDR_B_D9: length 2.7
  BOTTOM w0.089: v1(65,106.2) 65.34,106.54 UC1.BL11
  BOTTOM w0.102: v1(53.56,52.08) 54.08,51.57 JDIMM2.28
DDR_B_D10: length 6.2
  BOTTOM w0.089: UC1.BL8 65.01,105.34 v1(65.01,105.4)
  BOTTOM w0.102: JDIMM2.29 54.33,56.59 54.83,56.09 54.83,54.63 v1(53.56,53.35)
DDR_B_D11: length 3.7
  BOTTOM w0.089: v1(66.68,105.02) 66.35,104.7 UC1.BJ8
  BOTTOM w0.102: JDIMM2.41 57.33,57.3 57.75,56.88 57.75,55.91 v1(57.33,55.5)
DDR_B_D12: length 3.1
  BOTTOM w0.089: UC1.BJ11 66.55,106.32 v1(66.68,106.32)
  BOTTOM w0.102: v1(57.33,52.33) 56.57,51.57 JDIMM2.38
DDR_B_D13: length 5.7
  BOTTOM w0.089: UC1.BJ10 66.55,105.67 v1(66.68,105.67)
  BOTTOM w0.102: JDIMM2.37 56.33,54.6 v1(57.33,53.6)
DDR_B_D14: length 4.8
  BOTTOM w0.089: v1(65.05,104.58) 65.05,104.4 UC1.BL7
  BOTTOM w0.102: v1(53.56,54.62) 54.07,55.14 54.07,55.99 53.33,56.73 JDIMM2.25
DDR_B_D15: length 5.6
  BOTTOM w0.089: v1(66.68,104.37) 66.35,104.05 UC1.BJ7
  BOTTOM w0.102: v1(57.33,54.87) 57.74,54.46 57.74,51.84 57.57,51.67 JDIMM2.42
DDR_B_D16: length 4.9
  BOTTOM w0.089: v1(68.51,106.96) 68.36,106.96 UC1.BG11
  BOTTOM w0.102: v1(59,54.19) 59.57,53.62 JDIMM2.50
DDR_B_D17: length 3
  BOTTOM w0.089: UC1.BG10 68.37,106.32 v1(68.51,106.32)
  BOTTOM w0.102: JDIMM2.49 59.33,57.29 59.42,57.2 59.42,56.52 58.99,56.1 v1(58.99,56.07)
DDR_B_D18: length 4.4
  BOTTOM w0.089: UC1.BG8 68.37,105.02 v1(68.51,105.02)
  BOTTOM w0.102: v1(58.99,54.8) 58.48,55.31 58.48,57.18 58.33,57.34 JDIMM2.45
DDR_B_D19: length 4.3
  BOTTOM w0.089: v1(69.41,105.03) 69.3,105.03 UC1.BF8
  BOTTOM w0.102: v1(62.49,53.52) 62.96,53.05 62.96,51.36 62.57,50.98 JDIMM2.62
DDR_B_D20: length 4.7
  BOTTOM w0.089: UC1.BF11 69.27,106.96 v1(69.41,106.96)
  BOTTOM w0.102: v1(62.5,54.8) 62.86,54.8 63.22,55.16 63.22,56.89 62.83,57.28 JDIMM2.63
DDR_B_D21: length 3.3
  BOTTOM w0.089: UC1.BF10 69.29,106.32 v1(69.42,106.32)
  BOTTOM w0.102: JDIMM2.59 61.83,57.22 61.95,57.1 62.35,57.1 62.5,56.95 v1(62.5,56.07)
DDR_B_D22: length 3.6
  BOTTOM w0.089: UC1.BG7 68.37,104.37 v1(68.51,104.37)
  BOTTOM w0.102: JDIMM2.46 58.57,52.5 v1(59,52.92)
DDR_B_D23: length 3.1
  BOTTOM w0.089: UC1.BF7 69.29,104.37 v1(69.42,104.37)
  BOTTOM w0.102: JDIMM2.58 61.57,51.33 v1(62.49,52.25)
DDR_B_D24: length 2.6
  BOTTOM w0.089: v1(72.16,106.97) 72.03,106.97 UC1.BB11
  BOTTOM w0.102: v1(68.08,52.14) JDIMM2.84
DDR_B_D25: length 5.3
  BOTTOM w0.089: UC1.BC11 71.1,106.96 v1(71.25,106.96)
  BOTTOM w0.102: v1(64.57,54.17) 64.88,54.17 65.18,54.47 65.18,56.9 64.83,57.26 JDIMM2.71
DDR_B_D26: length 3.3
  BOTTOM w0.089: UC1.BB8 72.03,105.02 v1(72.16,105.02)
  BOTTOM w0.102: v1(68.07,56.1) 67.78,56.1 67.55,56.34 67.55,57.23 67.83,57.51 JDIMM2.83
DDR_B_D27: length 2.4
  BOTTOM w0.089: v1(71.25,105.02) 71.12,105.02 UC1.BC8
  BOTTOM w0.102: v1(64.57,56.8) 63.83,57.54 JDIMM2.67
DDR_B_D28: length 6.6
  BOTTOM w0.089: UC1.BC10 71.12,106.32 v1(71.25,106.32)
  BOTTOM w0.102: v1(64.56,55.5) 64.16,55.5 64.04,55.38 64.04,53.87 63.72,53.55 63.72,51 63.57,50.86 JDIMM2.66
DDR_B_D29: length 4.6
  BOTTOM w0.089: UC1.BB10 72.03,106.32 v1(72.16,106.32)
  BOTTOM w0.102: JDIMM2.79 66.83,56.08 66.95,55.95 67.52,55.39 v1(68.07,54.83)
DDR_B_D30: length 3.4
  BOTTOM w0.089: v1(71.25,104.37) 71.12,104.37 UC1.BC7
  BOTTOM w0.102: v1(64.57,52.9) 64.57,52.89 JDIMM2.70
DDR_B_D31: length 4.8
  BOTTOM w0.089: UC1.BB7 72.03,104.37 v1(72.16,104.37)
  BOTTOM w0.102: v1(68.07,53.56) 67.47,53.56 67.08,53.17 JDIMM2.80
DDR_B_D32: length 3.4
  BOTTOM w0.089: UC1.AA11 88.49,106.97 v1(88.62,106.97)
  BOTTOM w0.102: v1(96.4,52.52) 95.58,51.69 JDIMM2.186
DDR_B_D33: length 5
  BOTTOM w0.089: v1(88.62,106.32) 88.49,106.32 UC1.AA10
  BOTTOM w0.102: v1(96.38,53.79) 94.58,51.99 JDIMM2.182
DDR_B_D34: length 2.1
  BOTTOM w0.089: v1(87.71,106.97) 87.58,106.97 UC1.AC11
  BOTTOM w0.102: JDIMM2.174 92.58,50.91 v1(93.05,51.39)
DDR_B_D35: length 4.1
  BOTTOM w0.076: UC1.AC10 87.38,106 v1(87.71,106.32)
  BOTTOM w0.102: v1(93.03,55.11) 92.91,55.23 92.91,56.25 92.32,56.84 JDIMM2.173
DDR_B_D36: length 2.8
  BOTTOM w0.089: UC1.AA7 88.49,104.37 v1(88.62,104.37)
  BOTTOM w0.102: JDIMM2.187 95.83,56.76 95.94,56.64 96.03,56.64 96.33,56.34 v1(96.33,56.34)
DDR_B_D37: length 4.5
  BOTTOM w0.089: UC1.AA8 88.49,105.02 v1(88.62,105.02)
  BOTTOM w0.102: v1(96.36,55.07) 96.29,55.07 95.64,55.71 95.64,56.51 94.83,57.32 JDIMM2.183
DDR_B_D38: length 5.8
  BOTTOM w0.089: UC1.AC8 87.58,105.02 v1(87.71,105.02)
  BOTTOM w0.102: v1(93.02,53.84) 92.61,54.25 92.61,55.35 92.42,55.54 92.42,56.3 91.32,57.39 JDIMM2.169
DDR_B_D39: length 3.9
  BOTTOM w0.089: v1(87.71,104.37) 87.58,104.37 UC1.AC7
  BOTTOM w0.102: v1(93.01,52.57) 92.99,52.55 92.65,52.55 91.58,51.48 JDIMM2.170
DDR_B_D40: length 4.8
  BOTTOM w0.089: UC1.W8 90.22,104.47 90.44,104.47 v1(90.46,104.49)
  BOTTOM w0.102: JDIMM2.190 96.58,51.46 97.31,52.19 97.31,52.61 v1(98.34,53.65)
DDR_B_D41: length 3.1
  BOTTOM w0.076: UC1.W7 v1(90.45,103.88)
  BOTTOM w0.102: v1(98.34,52.38) 97.58,51.61 JDIMM2.194
DDR_B_D42: length 5.9
  BOTTOM w0.089: v1(91.33,106.32) 91.23,106.32 UC1.V10
  BOTTOM w0.102: JDIMM2.207 100.83,57.49 102.82,55.49 102.82,54.43 102.42,54.03 v1(102.39,54.03)
DDR_B_D43: length 5.1
  BOTTOM w0.089: v1(91.34,106.97) 91.23,106.97 UC1.V11
  BOTTOM w0.102: v1(102.4,55.3) 101.66,55.3 99.83,57.13 JDIMM2.203
DDR_B_D44: length 4.8
  BOTTOM w0.076: UC1.W11 90.13,106.65 v1(90.45,106.32)
  BOTTOM w0.102: v1(98.34,54.92) 98.07,54.92 97.1,55.9 97.1,57.17 96.83,57.44 JDIMM2.191
DDR_B_D45: length 2.9
  BOTTOM w0.076: UC1.W10 89.91,106 v1(89.59,105.67)
  BOTTOM w0.102: JDIMM2.195 97.83,56.71 v1(98.34,56.19)
DDR_B_D46: length 2.8
  BOTTOM w0.089: v1(91.37,104.37) 91.04,104.05 UC1.V7
  BOTTOM w0.102: JDIMM2.204 100.07,51.32 100.75,51.99 v1(100.79,51.99)
DDR_B_D47: length 4.1
  BOTTOM w0.089: v1(91.37,105.02) 91.23,105.02 UC1.V8
  BOTTOM w0.102: JDIMM2.208 101.07,50.95 101.22,51.09 101.22,51.95 v1(102.38,53.11)
DDR_B_D48: length 2.9
  BOTTOM w0.089: v1(93.2,106.97) 93.06,106.97 UC1.R11
  BOTTOM w0.102: JDIMM2.216 103.07,51.85 v1(103.48,52.25)
DDR_B_D49: length 3.9
  BOTTOM w0.089: UC1.P11 93.98,106.97 v1(94.11,106.97)
  BOTTOM w0.102: JDIMM2.224 105.07,51.06 105.19,51.17 105.19,52.38 105.26,52.45 v1(106.1,52.45)
DDR_B_D50: length 4.6
  BOTTOM w0.089: v1(94.14,104.34) 93.84,104.05 UC1.P7
  BOTTOM w0.102: JDIMM2.228 106.07,51.17 106.56,51.66 106.56,53.26 v1(106.09,53.73)
DDR_B_D51: length 5.1
  BOTTOM w0.089: v1(93.2,105.02) 93.06,105.02 UC1.R8
  BOTTOM w0.102: JDIMM2.211 101.83,57.54 103.56,55.8 103.56,55.13 v1(104.01,54.69)
DDR_B_D52: length 3.4
  BOTTOM w0.089: v1(93.2,106.32) 92.87,106 UC1.R10
  BOTTOM w0.102: v1(104.01,55.97) 104.01,56.1 102.83,57.28 JDIMM2.215
DDR_B_D53: length 3.1
  BOTTOM w0.089: v1(94.11,106.32) 93.98,106.32 UC1.P10
  BOTTOM w0.102: v1(107.48,56.26) 106.32,57.41 JDIMM2.229
DDR_B_D54: length 4.8
  BOTTOM w0.089: UC1.R7 93.06,104.37 v1(93.2,104.37)
  BOTTOM w0.102: v1(104.01,53.42) 103.85,53.42 102.07,51.64 JDIMM2.212
DDR_B_D55: length 5
  BOTTOM w0.089: v1(94.13,105.02) 93.81,104.7 UC1.P8
  BOTTOM w0.102: v1(107.49,54.99) 106.86,55.61 106.86,56.31 106.01,57.16 105.63,57.16 105.32,57.46 JDIMM2.225
DDR_B_D56: length 2.7
  BOTTOM w0.089: UC1.L11 96.45,106.65 96.72,106.91 v1(96.8,106.91)
  BOTTOM w0.102: v1(111.75,52.17) 111.58,51.99 JDIMM2.250
DDR_B_D57: length 3.8
  BOTTOM w0.089: v1(95.94,106.97) 95.81,106.97 UC1.M11
  BOTTOM w0.102: v1(107.93,52.99) 108.33,52.58 108.33,51.21 108.07,50.95 JDIMM2.236
DDR_B_D58: length 4.5
  BOTTOM w0.102: UC1.L7 96.66,104.39 96.73,104.39 96.8,104.46 v1(96.81,104.46) ; JDIMM2.246 110.58,52.34 v1(111.68,53.45)
DDR_B_D59: length 3.1
  BOTTOM w0.076: v1(95.84,104.37) 95.51,104.7 UC1.M8
  BOTTOM w0.102: JDIMM2.232 107.07,51.09 107.44,51.46 107.44,51.89 v1(107.92,52.38)
DDR_B_D60: length 3.5
  BOTTOM w0.089: v1(96.82,106.32) 96.72,106.32 UC1.L10
  BOTTOM w0.102: v1(112.45,55.86) 111.33,56.98 JDIMM2.249
DDR_B_D61: length 4.6
  BOTTOM w0.089: UC1.M10 95.81,106.32 v1(95.94,106.32)
  BOTTOM w0.102: v1(109.38,55.18) 108.68,55.88 108.68,56.21 107.32,57.56 JDIMM2.233
DDR_B_D62: length 2.8
  BOTTOM w0.076: v1(95.92,103.76) 95.89,103.79 95.73,103.79 UC1.M7
  BOTTOM w0.102: JDIMM2.237 108.32,57.48 v1(109.36,56.45)
DDR_B_D63: length 5.9
  BOTTOM w0.102: v1(96.84,105.05) 96.81,105.02 96.47,105.02 96.37,104.92 UC1.L8 ; v1(112.45,54.59) 111.49,54.59 110.32,55.75 JDIMM2.245
DDR_B_DQS0: length 3.6
  BOTTOM w0.076: UC1.BP9 v1(63.71,106.19)
  BOTTOM w0.102: v1(49.48,55.67) 49.56,55.7 50.03,55.93 50.33,56.22 JDIMM2.13
DDR_B_DQS1: length 4.5
  BOTTOM w0.076: UC1.BJ9 66.11,105.23 65.89,105.23 65.74,105.38 65.74,105.58 v1(65.83,105.67)
  BOTTOM w0.102: v1(54.57,52.97) 54.83,52.7 55.32,52.7 55.57,52.44 JDIMM2.34
DDR_B_DQS2: length 5.5
  BOTTOM w0.076: UC1.BF9 68.96,105.59 69.05,105.67 v1(69.4,105.67)
  BOTTOM w0.102: v1(61.04,54.69) 61.04,54.45 60.93,54.34 60.67,54.34 60.56,54.44 60.56,55.97 60.56,57.14 60.67,57.25 60.75,57.25 60.83,57.32 JDIMM2.55
DDR_B_DQS3: length 4.3
  BOTTOM w0.089: UC1.BB9 72.03,105.67 v1(72.16,105.67)
  BOTTOM w0.102: JDIMM2.76 66.08,50.85 65.8,51.12 65.8,51.63 65.67,51.76 65.67,52.79 65.84,52.96 66.07,52.96 66.15,52.87 v1(66.15,52.61)
DDR_B_DQS4: length 4.5
  BOTTOM w0.089: UC1.AA9 88.49,105.67 v1(88.62,105.67)
  BOTTOM w0.102: JDIMM2.179 93.83,57.6 93.55,57.33 93.55,57.03 93.93,56.66 93.93,56.03 94.18,55.78 94.82,55.78 94.9,55.86 v1(94.9,56.09)
DDR_B_DQS5: length 5.8
  BOTTOM w0.076: v1(90.45,105.08) 90.72,105.35 UC1.V9
  BOTTOM w0.102: JDIMM2.200 99.07,50.81 98.8,51.08 98.8,51.36 99.7,52.26 99.7,53.29 100.07,53.66 100.64,53.66 100.78,53.51 v1(100.78,53.29)
DDR_B_DQS6: length 5.2
  BOTTOM w0.089: v1(94.11,105.67) 93.76,105.67 93.65,105.57 UC1.P9
  BOTTOM w0.102: v1(106.05,55.8) 106.05,55.57 105.82,55.35 105.49,55.35 105.38,55.45 105.38,56.09 104.19,57.28 104.19,57.5 104.32,57.64 JDIMM2.221
DDR_B_DQS7: length 3.8
  BOTTOM w0.089: UC1.L9 96.22,105.35 v1(95.93,105.64)
  BOTTOM w0.102: v1(109.79,52.38) 109.79,52.57 109.67,52.69 109.49,52.69 109.38,52.58 109.38,52.02 109.44,51.95 109.44,50.98 109.58,50.85 JDIMM2.242
DDR_B_DQS#0: length 3.6
  BOTTOM w0.076: UC1.BN9 v1(64.36,106.19)
  BOTTOM w0.102: v1(49.48,56.4) 49.48,56.16 49.56,56.08 49.86,56.08 49.87,56.09 50.1,56.32 50.1,57.32 49.83,57.59 JDIMM2.11
DDR_B_DQS#1: length 4
  BOTTOM w0.076: UC1.BL9 v1(65.79,106.32)
  BOTTOM w0.102: JDIMM2.32 55.08,50.87 55.35,51.15 55.35,52.35 55.22,52.48 54.86,52.48 v1(54.56,52.17)
DDR_B_DQS#2: length 5.4
  BOTTOM w0.089: v1(68.51,105.67) 68.37,105.67 UC1.BG9
  BOTTOM w0.102: v1(61.03,53.92) 60.85,54.09 60.54,54.09 60.32,54.31 60.32,56.07 60.33,56.07 JDIMM2.53
DDR_B_DQS#3: length 4.4
  BOTTOM w0.089: UC1.BC9 71.12,105.67 v1(71.25,105.67)
  BOTTOM w0.102: JDIMM2.74 65.57,51.53 65.44,51.67 65.44,52.88 65.74,53.19 65.96,53.19 v1(66.17,53.39)
DDR_B_DQS#4: length 4.6
  BOTTOM w0.089: UC1.AC9 87.58,105.67 v1(87.71,105.67)
  BOTTOM w0.102: v1(94.9,55.34) 94.69,55.55 94.09,55.55 93.7,55.93 93.7,56.56 93.32,56.94 JDIMM2.177
DDR_B_DQS#5: length 5.8
  BOTTOM w0.089: UC1.W9 90.14,105.35 v1(90.47,105.68)
  BOTTOM w0.102: v1(100.79,54.04) 100.64,53.89 99.98,53.89 99.47,53.38 99.47,52.36 98.58,51.46 JDIMM2.198
DDR_B_DQS#6: length 5.1
  BOTTOM w0.089: v1(93.2,105.67) 93.06,105.67 UC1.R9
  BOTTOM w0.102: v1(106.05,55) 105.93,55.12 105.39,55.12 105.15,55.36 105.15,56 103.83,57.33 JDIMM2.219
DDR_B_DQS#7: length 4
  BOTTOM w0.089: UC1.M9 95.51,105.35 v1(95.89,104.96)
  BOTTOM w0.102: v1(109.79,53.08) 109.63,52.92 109.39,52.92 109.15,52.68 109.15,51.92 109.21,51.86 109.21,51.01 109.07,50.87 JDIMM2.240
DDR_B_MA0: length 5.1
  BOTTOM w0.076: UC1.AJ9 82.09,105.67 v1(82.22,105.67)
  BOTTOM w0.168: JDIMM2.144 83.08,50.98 83.4,51.31 83.81,51.31 84.39,51.89 84.39,52.3 84.97,52.88 v1(85.66,52.88)
DDR_B_MA1: length 4.6
  BOTTOM w0.076: v1(80.76,103.08) 80.89,103.08 UC1.AK6
  BOTTOM w0.168: v1(79.46,54.59) 80.32,55.45 JDIMM2.133
DDR_B_MA2: length 5.7
  BOTTOM w0.076: v1(80.78,102.42) 80.78,102.42 81.1,102.74 UC1.AK5
  BOTTOM w0.168: v1(82.3,54.05) 81.79,54.05 80.08,52.34 JDIMM2.132
DDR_B_MA3: length 3.1
  BOTTOM w0.076: v1(79.98,102.45) 80.06,102.45 80.35,102.74 UC1.AL5
  BOTTOM w0.168: JDIMM2.131 79.83,56.38 v1(79.39,55.95)
DDR_B_MA4: length 3
  BOTTOM w0.076: UC1.AL6 80.03,103.06 v1(79.9,103.06)
  BOTTOM w0.168: JDIMM2.128 79.08,51.15 78.93,51.29 78.93,51.85 v1(78.54,52.25)
DDR_B_MA5: length 4.5
  BOTTOM w0.076: UC1.AM6 79.24,103.1 v1(79.11,103.1)
  BOTTOM w0.168: JDIMM2.126 78.57,50.85 77.97,51.45 77.97,53.04 78.49,53.55 v1(78.52,53.55)
DDR_B_MA6: length 4.9
  BOTTOM w0.076: UC1.AN7 79.29,104.05 v1(79.47,103.87)
  BOTTOM w0.168: JDIMM2.127 78.83,57.02 77.91,56.1 77.91,55.11 v1(77.37,54.57)
DDR_B_MA7: length 2.7
  BOTTOM w0.076: UC1.AN10 79.35,106.32 v1(79.48,106.32)
  BOTTOM w0.168: JDIMM2.122 77.57,51.14 v1(76.81,51.91)
DDR_B_MA8: length 3.4
  BOTTOM w0.076: v1(79.45,104.46) 79.45,104.51 79.27,104.7 UC1.AN8
  BOTTOM w0.168: JDIMM2.125 78.32,58.01 78.2,57.89 78.2,57.21 77.31,56.32 77.31,55.91 v1(77.31,55.91)
DDR_B_MA9: length 4.6
  BOTTOM w0.076: UC1.AR11 77.26,106.65 v1(77.64,106.27)
  BOTTOM w0.168: JDIMM2.121 77.32,57.15 75.58,55.4 v1(75.58,55.07)
DDR_B_MA10: length 1.8
  BOTTOM w0.076: UC1.AH7 83,104.37 v1(83.04,104.37)
  BOTTOM w0.168: v1(85.58,51.41) JDIMM2.146
DDR_B_MA11: length 4.4
  BOTTOM w0.076: UC1.AN11 79.02,106.68 79.31,106.97 v1(79.48,106.97)
  BOTTOM w0.168: JDIMM2.120 77.08,50.96 76.28,51.75 76.28,52.88 v1(76.75,53.34)
DDR_B_MA12: length 6.7
  BOTTOM w0.076: v1(77.65,105.66) 77.32,106 UC1.AR10
  BOTTOM w0.168: v1(75.56,53.48) 74.65,54.39 74.65,55.29 76.83,57.47 JDIMM2.119
DDR_B_MA13: length 4.4
  BOTTOM w0.076: UC1.AF9 84.64,105.35 v1(84.97,105.67)
  BOTTOM w0.142: v1(90.62,52.62) 89.87,52.62 88.58,51.33 JDIMM2.158
DDR_B_MA14_WE#: length 2.9
  BOTTOM w0.076: UC1.AH11 83,106.97 v1(83.14,106.97)
  BOTTOM w0.168: v1(87.76,56.42) 87.74,56.4 87.71,56.4 86.83,57.28 JDIMM2.151
DDR_B_MA15_CAS#: length 5.8
  BOTTOM w0.076: UC1.AF8 84.89,105.07 v1(85.01,105.07)
  BOTTOM w0.168: v1(90.62,53.79) 89.88,53.79 88.08,51.99 JDIMM2.156
DDR_B_MA16_RAS#: length 4.3
  BOTTOM w0.076: UC1.AH10 83,106.32 v1(83.14,106.32)
  BOTTOM w0.168: JDIMM2.152 87.08,52.75 87.51,53.19 v1(87.97,53.19)
DDR_B_ODT0: length 6.7
  BOTTOM w0.076: UC1.AF7 84.62,104.05 84.99,104.42 v1(84.99,104.45)
  BOTTOM w0.168: v1(90.61,55.01) 90.24,55.01 89.86,54.63 88.84,54.63 88.55,54.92 88.55,56.34 87.83,57.07 JDIMM2.155
DDR_B_ODT1: length 5.5
  BOTTOM w0.076: UC1.AE8 85.59,104.7 v1(85.86,104.42)
  BOTTOM w0.168: JDIMM2.161 89.32,57.31 89.83,56.81 90.81,56.81 91.58,56.04 91.58,55.22 v1(91.84,54.97)
DDR_B_PAR: length 6
  BOTTOM w0.076: v1(82.22,104.37) 82.09,104.37 UC1.AJ7
  BOTTOM w0.168: v1(85.67,54.28) 85.23,54.28 82.83,56.69 JDIMM2.143
DDR_DRAMRST#: length 5.8
  TOP w0.102: v1(84.07,60.89) 84.07,60.56 RD8.2 CD29.1
  BOTTOM w0.102: v1(74.19,51.51) 74.08,51.39 JDIMM2.108
  BOTTOM w0.127: JDIMM1.108 71.07,61.95 70.86,61.74 70.86,61.19 71.38,60.67 v1(71.6,60.67)
DDR_VTT_PG_CTRL: length 4.1
  TOP w0.102: v3(59.79,107.54) 60.39,107.54 v1(60.63,107.78)
  BOTTOM w0.102: UC10.2 60.08,108.33 v1(60.63,107.78) 61.71,107.78 UC1.BT13
DEBUG_CTL1: length 1.1
  TOP w0.102: RT66.2 32.57,89.51 v1(32.6,89.49)
  BOTTOM w0.102: UT4.E4 v1(32.6,89.49)
DEBUG_CTL2: length 1.7
  TOP w0.102: RT67.2 32.63,88.85 v1(32.08,88.85) 31.88,88.85 v2(31.59,89.14)
  BOTTOM w0.102: UT4.D5 32.22,88.99 v1(32.08,88.85)
DGPU_HOLD_RST#: length 10.2
  TOP w0.102: v1(183.33,47.2) 183.13,47.01 v2(183.13,46.61)
  BOTTOM w0.102: v1(211.58,86.08) 210.96,86.08 209.37,84.49 208.85,84.49 207.22,86.12 207.22,86.67 RV58.2 207.77,87.73 UV14.1 ; v1(183.33,47.2) 183.94,46.59 UH1.BB20
DGPU_PEX_RST#: length 54.6
  TOP w0.102: v1(238,85.95) v3(236.75,84.7) 235.63,83.59 220.68,83.59 219.77,84.49 v1(219.77,85.15)
  BOTTOM w0.102: RG546.1 199.26,91.95 200.61,93.31 200.61,94.68 200.47,94.82 200.47,97.56 201.07,98.16 RV40.1 204.71,98.16 205.19,97.67 205.19,94.82 206.06,93.95 206.06,91.43 205.67,91.04 205.67,90.32 205.67,90.31 UV14.4 205.67,89.23 205.79,89.11 v1(206.02,89.11) ; v1(218.82,88.52) 218.22,87.93 RV571.1 218.05,87.59 217.72,87.26 217.72,86.33 218.26,85.79 219.14,85.79 219.77,85.16 v1(219.77,85.15) ; v1(238,85.95) 238,86.21 238.94,87.14 UG22.1 ; RV573.1 207.92,89.41 RV39.2 209.32,88.78 209.32,88.92 v1(209.57,89.16) 209.8,89.4 209.8,90.09 RV684.1 210.04,90.86 UV20.2
DGPU_PEX_RST#_R: length 12.7
  BOTTOM w0.102: RV40.2 v2(202.06,98.75)
  BOTTOM w0.109: UV1.AJ12 209.97,103.58 209.97,102.95 210.06,102.86 210.06,101.69 209.97,101.61 209.97,101.4 209.65,101.07 208.59,101.07 208.27,100.75 208.27,100.49 207.95,100.17 207.74,100.17 207.5,99.93 207.5,98.82 207.25,98.58 205.74,98.58 205.58,98.74 204.01,98.74 RV40.2
DGPU_PRSNT#: length 5.5
  BOTTOM w0.089: 187.85,37.94 187.22,38.57 186.43,38.57 185.81,37.95 185.29,37.95 185.12,37.79 UH1.BD38
  BOTTOM w0.102: RH135.2 188.14,36.98 187.85,37.27 187.85,37.94
DGPU_PWR_EN: length 4.4
  TOP w0.102: v2(179.26,46.86) 179.35,46.77 v1(179.81,46.77) 179.82,46.77 180.34,47.29 RH537.1
  BOTTOM w0.102: 198.82,116.01 199.74,116.93 RG551.1 ; UH1.AN18 179.59,46.99 v1(179.81,46.77)
DGPU_PWROK: length 68.2
  TOP w0.102: v3(193.31,62.14) 193.31,62.32 v1(192.8,62.83) ; RH676.2 181.53,48.1 v1(181.64,48.21)
  BOTTOM w0.089: UH1.AV16 181.64,48.37 v1(181.64,48.21)
  BOTTOM w0.102: UG25.1 199.85,118.97 200.27,118.54 200.27,115.49 196.75,111.96 196.75,95.92 195,94.18 195,91.15 196.96,89.19 196.96,88.52 197.43,88.05 197.43,74.19 192.8,69.56 v1(192.8,62.83) ; v1(233.35,90.18) 232.64,90.18 232.25,89.78 UV19.2
  BOTTOM w0.152: PRW18.2 263.93,65.62 264.12,65.62 264.54,66.03 PUW01.13
  BOTTOM w0.203: PRW18.2 263.09,65.31 v1(263.09,65.72)
DIFFOUT_2PH: length 2.9
  BOTTOM w0.203: PUZ01.35 111.7,146.78 111.87,146.62 112.5,146.62 112.75,146.36 PRZ46.2 113.59,146.36 PRZ45.1
DIFFOUT_4PH: length 4.3
  TOP w0.203: PCZ14.2 103.51,145.9 v1(103.51,145.96)
  BOTTOM w0.203: PRZ30.2 102.83,145.94 v2(102.93,146.04) 103.43,146.04 v1(103.51,145.96) 103.69,145.96 104.12,146.38 PUZ01.4
DIMM_CHA_SA0: length 4.8
  TOP w0.102: v1(109.55,61.42) 109.91,61.42 RD1.2 109.77,62.32 RD4.1 109.47,62.6 v2(108.81,63.26)
  BOTTOM w0.127: JDIMM1.256 110.07,61.95 v1(109.55,61.42)
DIMM_CHA_SA1: length 4.9
  TOP w0.102: v2(112.87,61.25) 112.66,61.45 v1(112.23,61.45) 111.74,60.96 RD5.1 111.2,60.97 RD2.2
  BOTTOM w0.127: JDIMM1.260 111.07,62.13 111.35,61.85 111.84,61.85 v1(112.23,61.45)
DIMM_CHA_SA2: length 8.8
  TOP w0.102: RD6.1 RD3.2 v2(85.38,58.36) 85.74,58.36 88.12,60.75 v1(88.33,60.75)
  BOTTOM w0.102: v1(88.33,60.75) 88.33,61.33 87.57,62.08 JDIMM1.166
DIMM_CHB_SA0: length 7.1
  TOP w0.102: RD16.1 RD13.2 116.96,48.33 115.02,48.33 114.4,48.95 v2(113.61,48.95) 113.02,48.95 v1(112.94,48.87)
  BOTTOM w0.102: JDIMM2.256 113.07,49.01 v1(112.94,48.87)
DIMM_CHB_SA1: length 7.4
  TOP w0.102: RD17.1 RD14.2 118.28,48.54 117.73,47.99 v2(115.63,47.99) 114.69,47.99 v1(114.2,48.47)
  BOTTOM w0.102: v1(114.2,48.47) 114.08,48.47 114.07,48.47 JDIMM2.260
DIMM_CHB_SA2: length 7
  TOP w0.102: RD18.1 RD15.2 89.79,54.86 90.18,54.47 90.18,51.86 90.47,51.57 90.5,51.57 v1(90.71,51.36) 90.71,51.13 v2(91.06,50.77)
  BOTTOM w0.127: JDIMM2.166 90.58,51.23 v1(90.71,51.36)
DMI_CRX_PTX_N0: length 17.1
  BOTTOM w0.076: 162.73,39.92 162.74,39.92 162.77,39.95 162.9,39.95 163.13,39.71 164.7,39.71 UH1.C33 ; v1(100.44,104.85) 100.11,104.52 UC1.E8
  BOTTOM w0.102: v1(156.23,49.24) 156.39,49.08 156.39,48.65 156.86,48.18 157.79,48.18 159.27,46.7 161.5,46.7 161.69,46.51 161.69,40.38 162.14,39.92 162.73,39.92
DMI_CRX_PTX_N1: length 14.2
  BOTTOM w0.076: UC1.F6 99.44,103.61 v1(99.77,103.29) ; UH1.C32 164.79,40.84 163.64,40.84 163.5,40.98 163.02,40.98 162.78,41.22 162.78,41.26 162.76,41.28
  BOTTOM w0.102: v1(158.67,49.23) 158.48,49.04 158.48,48.73 159.68,47.53 161.92,47.53 162.51,46.93 162.51,41.53 162.76,41.28
DMI_CRX_PTX_N2: length 12.7
  BOTTOM w0.076: 163.17,41.87 163.19,41.86 163.19,41.82 163.51,41.5 164.75,41.5 UH1.C31 ; UC1.E5 99.78,102.55 v1(99.78,102.51)
  BOTTOM w0.102: v1(159.84,49.25) 159.84,48.64 160.32,48.16 162.31,48.16 163.02,47.45 163.02,42.02 163.17,41.87
DMI_CRX_PTX_N3: length 11
  BOTTOM w0.076: UC1.J9 98.11,105.35 v1(98.43,105.66) ; UH1.C29 164.65,41.87 163.63,41.87 163.3,42.19 163.3,42.93 163.27,42.96 163.27,42.98
  BOTTOM w0.102: 163.27,42.98 163.27,47.84 162.54,48.57 161.47,48.57 161.2,48.84 161.2,49.06 v1(161.01,49.25)
DMI_CRX_PTX_P0: length 17
  BOTTOM w0.076: UC1.D8 100.76,104.52 v1(101.09,104.85) ; UH1.B33 164.58,39.93 164.65,40 164.65,40.11 164.6,40.16 164.25,40.16 164.25,40.16 164.22,40.16 164.15,40.09 164.13,40.04 164.12,40.03 164.12,40.01 164.09,39.96 164,39.86 163.2,39.86 162.96,40.1 162.77,40.1 162.74,40.13 162.73,40.13
  BOTTOM w0.102: v1(156.81,49.24) 156.6,49.03 156.6,48.74 156.94,48.39 157.87,48.39 159.36,46.9 161.59,46.9 161.89,46.6 161.89,40.47 162.23,40.13 162.73,40.13
DMI_CRX_PTX_P1: length 14.2
  BOTTOM w0.076: UH1.B32 164.51,40.43 164.47,40.39 164.36,40.39 164.06,40.68 163.58,40.68 163.44,40.83 162.96,40.83 162.67,41.12 162.63,41.12 162.62,41.13 ; UC1.E6 100.11,103.61 v1(100.44,103.29)
  BOTTOM w0.102: v1(158.08,49.23) 158.27,49.04 158.27,48.64 159.59,47.32 161.84,47.32 162.31,46.85 162.31,41.44 162.62,41.13
DMI_CRX_PTX_P2: length 12.9
  BOTTOM w0.076: v1(100.43,102.51) 100.43,102.55 UC1.D5 ; 163.03,41.72 163.04,41.71 163.08,41.71 163.44,41.35 164.27,41.35 164.33,41.29 164.33,41.13 164.39,41.06 164.53,41.06 164.6,41.13 UH1.B31
  BOTTOM w0.102: 163.03,41.72 162.81,41.94 162.81,47.37 162.22,47.96 160.23,47.96 159.64,48.55 159.64,48.87 v1(159.26,49.25)
DMI_CRX_PTX_P3: length 10.4
  BOTTOM w0.076: UC1.J8 98.17,104.85 v1(98.49,104.85) ; 163.48,42.98 163.48,42.96 163.45,42.93 163.45,42.25 163.69,42.02 163.96,42.02 164.05,42.11 164.13,42.24 164.19,42.3 164.32,42.3 164.38,42.24 UH1.B29
  BOTTOM w0.102: 163.48,42.98 163.48,47.92 162.63,48.77 161.56,48.77 161.41,48.93 161.41,49.06 v1(161.59,49.25)
DMI_CTX_PRX_N0: length 117.9
  TOP w0.102: v1(168.02,39.53) 168.02,39.31 168.09,39.25 168.42,39.25 168.63,39.46 168.63,42.51 167.88,43.25 165,43.25 164.73,43.53 163.58,43.53 161.11,41.06 154.11,41.06 152.89,42.27 143.83,42.27 143.21,42.9 143.21,46.9 136.02,54.08 130.85,54.08 129.46,55.47 129.46,58.05 126.36,61.14 125.13,61.14 122.73,63.55 122.11,63.55 121.63,64.03 120.73,64.03 117.12,67.64 117.12,68.72 115.8,70.04 114.98,70.04 105.81,79.21 105.81,91.06 107.06,92.31 107.06,96.27 103.22,100.11 103.22,102.92 102.85,103.29 102.85,104.32 102.74,104.43 102.41,104.43 102.33,104.36 v1(102.33,104.06)
  BOTTOM w0.102: UC1.A8 102.71,104.44 v1(102.33,104.06) ; UH1.K34 168.21,39.34 v1(168.02,39.53)
DMI_CTX_PRX_N1: length 119.9
  TOP w0.102: v1(166.59,40.26) 166.66,39.97 166.66,39.9 166.62,39.87 166.24,39.87 166.12,39.99 165.59,39.99 165.03,39.43 160.5,39.43 159.95,38.88 158.67,38.88 157.82,38.04 152.78,38.04 152.18,38.63 152.18,39.95 151.49,40.64 143.09,40.64 142.01,41.72 136.09,41.72 135.64,42.16 135.01,42.16 134.53,41.67 134.22,41.67 133.71,42.18 132.73,42.18 131.22,43.7 131.22,50.91 126.11,56.01 126.11,57.47 125.69,57.9 125.69,59.13 125.67,59.16 125.67,59.16 125.31,59.51 124.38,59.51 124.37,59.52 124.36,59.52 122.45,61.43 120.97,61.43 103.79,78.61 v4(103.79,86.7) 103.79,89.74 103.81,89.76 103.81,90.32 103.79,90.34 103.79,91.75 105.34,93.3 105.34,95.65 101.27,99.73 101.27,100.81 100.01,102.08 99.52,102.08 99.34,102.26 99.34,103.52 99.5,103.68 101.32,103.68 v1(101.73,104.09)
  BOTTOM w0.089: v1(166.59,40.26) 166.69,40.16 UH1.G33
  BOTTOM w0.102: v1(101.73,104.09) 101.73,104 UC1.B6
DMI_CTX_PRX_N2: length 114.6
  TOP w0.102: v1(102.25,102.32) 102.52,102.32 102.6,102.24 102.6,99.84 106.44,96.01 106.44,92.8 105.05,91.4 105.05,78.84 120.5,63.38 121.33,63.38 121.94,62.77 122.62,62.77 124.86,60.53 126.1,60.53 128.34,58.3 128.34,55.23 132.86,50.71 132.86,43.64 133.29,43.2 142.04,43.2 143.58,41.66 152.64,41.66 153.86,40.44 161.68,40.44 163.22,41.98 164.74,41.98 165.25,42.49 166.9,42.49 167.47,41.93 167.47,40.94 167.82,40.59 167.99,40.59 v1(168.23,40.35)
  BOTTOM w0.102: UC1.A5 v1(102.25,102.32) ; v1(168.23,40.35) 168.52,40.64 UH1.K32
DMI_CTX_PRX_N3: length 114.2
  TOP w0.102: v1(167.04,40.96) 167.04,41.38 166.77,41.65 165.4,41.65 163.79,40.04 160.25,40.04 159.7,39.49 158.68,39.49 158.13,40.04 153.69,40.04 152.47,41.26 143.36,41.26 141.82,42.8 133.12,42.8 132.44,43.49 132.44,50.56 127.19,55.8 127.19,58.74 125.81,60.13 124.63,60.13 122.54,62.22 121.81,62.22 121.08,62.95 120.35,62.95 104.55,78.76 v4(104.55,83.98) 104.55,91.5 106.03,92.99 106.03,95.83 102.12,99.75 102.12,101.83 101.61,102.34 101.24,102.34 v1(101.07,102.51)
  BOTTOM w0.089: v1(167.04,40.96) UH1.G30
  BOTTOM w0.102: v1(101.07,102.51) 101.41,102.17 UC1.B4
DMI_CTX_PRX_P0: length 118
  TOP w0.102: v1(168.22,38.86) 168.41,39.04 168.51,39.04 168.84,39.37 168.84,42.59 167.97,43.46 v4(167.06,43.46) 165.08,43.46 164.81,43.73 163.5,43.73 161.02,41.26 154.2,41.26 152.98,42.48 143.92,42.48 143.41,42.98 143.41,46.98 136.11,54.29 130.93,54.29 129.66,55.56 129.66,58.13 126.44,61.35 125.22,61.35 122.82,63.75 122.2,63.75 121.72,64.24 120.82,64.24 117.33,67.72 117.33,68.8 115.89,70.24 115.06,70.24 106.02,79.29 106.02,90.98 107.27,92.23 107.27,96.36 103.43,100.2 103.43,103.08 103.06,103.45 103.06,104.41 102.83,104.64 102.53,104.64 v1(102.33,104.84)
  BOTTOM w0.102: UC1.B8 102.06,104.58 v1(102.33,104.84) ; UH1.J35 167.97,39.11 v1(168.22,38.86)
DMI_CTX_PRX_P1: length 120
  TOP w0.102: v1(101.07,104.06) 100.89,103.89 99.42,103.89 99.14,103.61 99.14,102.18 99.44,101.88 99.92,101.88 101.07,100.73 101.07,99.64 105.14,95.57 105.14,93.39 103.58,91.83 v4(103.58,90.04) 103.58,87 103.56,86.98 103.56,86.4 103.58,86.38 103.58,78.52 120.88,61.22 122.37,61.22 124.27,59.31 124.29,59.31 124.3,59.31 125.22,59.31 125.46,59.07 125.46,59.07 125.48,59.05 125.48,57.81 125.91,57.38 125.91,55.93 131.01,50.83 131.01,43.62 132.65,41.98 133.62,41.98 134.14,41.47 134.61,41.47 135.1,41.95 135.56,41.95 136,41.51 141.93,41.51 143,40.44 151.41,40.44 151.98,39.87 151.98,38.55 152.7,37.83 157.91,37.83 158.75,38.67 160.04,38.67 160.59,39.22 165.11,39.22 165.68,39.78 166.04,39.78 166.16,39.66 v1(167.02,39.66)
  BOTTOM w0.089: v1(167.02,39.66) 166.84,39.66 166.73,39.78 UH1.F34
  BOTTOM w0.102: UC1.C6 101.07,104.01 v1(101.07,104.06)
DMI_CTX_PRX_P2: length 114.6
  TOP w0.102: v1(102.33,103.28) 102.61,102.52 102.81,102.32 102.81,99.93 106.64,96.09 106.64,92.71 105.25,91.32 105.25,78.92 120.59,63.59 121.41,63.59 122.03,62.97 122.71,62.97 124.94,60.74 126.19,60.74 128.54,58.38 128.54,55.32 133.06,50.8 133.06,43.73 133.38,43.41 142.12,43.41 143.66,41.87 152.73,41.87 153.94,40.65 161.59,40.65 163.13,42.19 164.66,42.19 165.17,42.7 166.99,42.7 167.67,42.01 167.67,41.03 167.74,40.96 v1(168.09,40.96)
  BOTTOM w0.102: v1(102.33,103.28) 102.14,103.28 102.06,103.2 UC1.B5 ; UH1.J32 167.79,40.66 v1(168.09,40.96)
DMI_CTX_PRX_P3: length 114.1
  TOP w0.102: v1(166.42,40.87) 166.64,41.15 166.75,41.27 166.75,41.38 166.68,41.45 165.49,41.45 163.87,39.83 160.33,39.83 159.78,39.28 158.59,39.28 158.05,39.83 153.6,39.83 152.39,41.05 143.27,41.05 141.73,42.59 133.04,42.59 132.23,43.4 132.23,50.47 126.99,55.71 126.99,58.66 125.73,59.92 124.55,59.92 122.45,62.02 121.73,62.02 121,62.75 120.26,62.75 104.34,78.67 104.34,83.68 104.32,83.7 104.32,84.3 104.34,84.32 104.34,91.59 105.83,93.07 105.83,95.75 101.91,99.66 101.91,101.75 101.53,102.13 101.27,102.13 101.17,102.03 101.17,101.85 v1(101.42,101.6)
  BOTTOM w0.089: v1(166.42,40.87) 166.3,40.98 UH1.F30
  BOTTOM w0.102: UC1.D4 101.06,101.96 v1(101.42,101.6)
DMIC_CLK: length 4.5
  TOP w0.102: L5.2 36.68,13.6 v2(35.83,13.6) 35.62,13.8 34.82,13.8 34.29,14.33 34.29,14.79 33.77,15.31 UA1.3
DMIC_CLK_EDP: length 19
  TOP w0.102: L5.1 CA9.1 v1(39.31,13.73) ; v1(260.95,40.42) 261.61,39.76 261.61,37.33 262.5,36.45 v2(262.5,35.46) 262.5,33.54 261.39,32.43 v1(261.39,30.43)
  BOTTOM w0.102: v1(260.95,40.42) 259.72,41.65 JEDP1.31
DMIC_DATA: length 4.6
  TOP w0.102: RA42.2 35.84,12.9 35.34,13.4 34.72,13.4 v2(34.47,13.64) 34.06,14.05 34.06,14.6 33.75,14.91 UA1.2
DMIC_DATA_EDP: length 19
  TOP w0.102: v1(260.95,41.11) 262.1,39.96 262.1,37.53 262.99,36.64 262.99,33.31 262.53,32.85 v2(262.53,32.07) v1(262.53,30.96) ; v1(39.31,12.9) CA40.1 RA42.1
  BOTTOM w0.102: v1(260.95,41.11) 259.91,42.15 JEDP1.30
DP_RCOMP: length 10.9
  TOP w0.127: v1(100.73,126.23) v2(101.9,126.23) 102.14,126.23 102.81,125.56 102.81,122.72 103.59,121.93 103.59,119.47 RC1.1
  BOTTOM w0.254: v1(100.73,126.23) UC1.D37
DPSNK1_DDC_CLK: length 2.2
  BOTTOM w0.102: v1(28.21,130.41) UT1.Y5 ; RPT1.8 32.35,137 v1(32.01,137.33)
DPSNK1_DDC_DATA: length 2.2
  BOTTOM w0.102: RPT1.7 31.85,136.78 v1(31.38,137.24) ; UT1.R4 v1(25.61,131.05)
DPSNK_RBIAS: length 3.5
  TOP w0.102: v1(28.21,125.2) 28.58,125.2 RT19.1 29.43,124.36 v2(29.43,122.88)
  BOTTOM w0.089: UT1.Y18 v1(28.21,125.2)
DPSRC_RBIAS: length 1.3
  TOP w0.102: RT5.1 25.23,130.14 v1(25.61,129.75)
  BOTTOM w0.102: v1(25.61,129.75) UT1.N6
DRVON: length 6.6
  TOP w0.102: v1(54.96,149.14) v2(54.96,149.74)
  BOTTOM w0.203: PUZ01.17 106.68,151.61 v1(106.5,151.79)
  BOTTOM w0.254: v1(79.7,149.97) 79.83,149.97 80.14,149.66 PUI02.16 ; v1(71.45,149.83) 71.65,149.83 71.82,149.66 PUI03.16 ; PUI01.16 88.5,143.64 88.33,143.81 v1(88.09,143.81) ; PUI04.16 63.56,149.66 63.39,149.83 v1(63.21,149.83) ; v1(54.96,149.14) 55.04,149.14 55.28,148.9 PUG01.16
  BOTTOM w0.305: v1(105.21,139.38) 105.25,139.33 PUA01.16
EC_AC_BAT#: length 7.2
  BOTTOM w0.102: PQ20.1 v1(45.18,125.55) ; v1(221.81,91.76) 221.53,92.05 DV11.2 221.67,92.61 RV60.1 222.56,93.5 223.35,94.29 223.35,96.05 UV1.N3
EC_AGND: length 9.9
  TOP w0.102: v1(97.56,36.4) 98.1,35.86 v2(98.1,35.47)
  TOP w0.203: RE50.2 92.35,37.35 91.7,37.35 91.56,37.21 UE1.112
  TOP w0.381: CE25.2 95.32,35.47 v1(95.32,36.24) 94.6,36.24 CE2.2 ; v1(92.86,36.51) 92.37,37.01 RE50.2
  TOP w0.508: CE1.2 v1(95.28,34.36) RE4.1 ; RE6.1 v1(97.56,36.4) ; CE21.2 94.23,38.7 v1(94.64,38.29) 95.57,38.29 CE30.2
EC_MUTE#: length 4.7
  TOP w0.102: RE28.2 97.46,38.71 v1(97.82,39.06) 98.53,39.06 v2(98.74,38.85)
  TOP w0.203: UA1.40 32.55,13.42 33.03,12.94 33.23,12.94 33.52,12.65 RA8.2 33.58,12.47 v1(34.33,11.73)
EC_RX_R: length 2.2
  TOP w0.102: v1(38.53,105.17) 38.51,105.15 RW26.2
  BOTTOM w0.102: v1(38.53,105.17) 38.53,105.4 38.2,105.73 JWLAN1.40
EC_TX_R: length 2.3
  TOP w0.102: v1(37.96,105.05) 37.74,104.84 RW25.2
  BOTTOM w0.102: v1(37.96,105.05) 37.96,105.47 37.7,105.72 JWLAN1.38
EDP_AUXN: length 4.7
  BOTTOM w0.076: v1(104.09,119.05) 103.9,119.05 103.75,119.19 103.75,119.39 103.66,119.48 103.44,119.48 102.89,118.93 101.76,118.93 101.68,118.85 101.68,118.71 101.76,118.63 UC1.B26
  BOTTOM w0.102: C10.1 252.87,58.08 252.87,58.47 v1(252.68,58.66)
EDP_AUXN_C: length 9.4
  BOTTOM w0.102: C10.2 252.72,56.57 252.72,55.93 252.7,55.91 252.7,55.34 252.72,55.32 252.72,55.13 252.89,54.97 253.41,54.44 v4(253.41,54) 253.44,53.98 253.44,49.87 254.04,49.27 254.55,49.27 254.67,49.15 JEDP1.16
EDP_AUXP: length 4.4
  BOTTOM w0.076: v1(104.09,119.63) 103.38,119.63 102.83,119.08 101.7,119.08 101.53,118.91 101.53,118.74 UC1.C26
  BOTTOM w0.102: C11.1 253.08,58.06 253.08,58.47 v1(253.27,58.66)
EDP_AUXP_C: length 9.2
  BOTTOM w0.102: JEDP1.15 254.73,49.65 254.55,49.47 254.12,49.47 253.64,49.95 253.64,54.5 252.93,55.22 v4(252.93,55.62) 252.93,56.29 C11.2
EDP_BKLT_CTRL: length 2
  TOP w0.102: D3.2 252.35,43.34 R9.2 R8.2
EDP_DISP_UTIL: length 1.3
  TOP w0.102: v1(102.15,124.01) 102.15,124.67 TC1.1
  BOTTOM w0.102: v1(102.15,124.01) 102.37,123.79 UC1.A33
EDP_HPD: length 22.9
  TOP w0.102: v1(257.66,43.03) 257.66,42.71 257.18,42.23 255.22,42.23 254.94,41.94 RP1.6 ; v1(196.35,54.32) 193.66,54.32 193.21,54.77 191.82,54.77 190.96,53.91 188.54,53.91 187.88,53.24 186.36,53.24 185.87,52.75 184.24,52.75 183.87,53.13 182.04,53.13 181.9,53.26 180.81,53.26 180.53,52.98 180.53,52.52 RH656.1
  BOTTOM w0.102: v1(254.11,51.2) 254.15,51.15 JEDP1.12
EDP_HPD_R: length 2.3
  TOP w0.102: RH656.2 179.63,52.69 v1(179.5,52.81) 179.5,53.29 v2(179.98,53.77)
  BOTTOM w0.089: UH1.AN6 179.5,53.21 v1(179.5,52.81)
EDP_SW: length 2.1
  TOP w0.102: T4937.1 183.55,44.77 v1(183.91,45.13)
  BOTTOM w0.102: UH1.BB24 184.07,44.97 v1(183.91,45.13)
EDP_TXN0: length 1.7
  BOTTOM w0.076: UC1.E29 100.11,120.99 99.81,121.29 v1(99.81,121.37)
  BOTTOM w0.102: v1(251.45,58.66) 251.27,58.48 251.27,58.04 C6.1
EDP_TXN0_C: length 11.7
  BOTTOM w0.102: JEDP1.18 254.67,48.15 254.52,48 253.98,48 252.98,49 v4(252.98,49.67) 252.98,50.99 253,51.01 253,51.57 252.98,51.6 252.98,54.2 251.05,56.13 251.05,56.24 251.14,56.33 251.45,56.33 251.6,56.48 C6.2
EDP_TXN1: length 1.8
  BOTTOM w0.102: UC1.E28 v1(100.45,119.8) ; C8.1 249.39,58.09 249.39,58.49 v1(249.6,58.71)
EDP_TXN1_C: length 14.3
  BOTTOM w0.102: C8.2 249.66,56.91 249.39,56.91 249.29,56.81 249.29,56.47 249.77,56 250.2,56 250.64,55.56 250.67,55.56 251.1,55.12 251.1,55.09 252.28,53.92 v4(252.28,53.11) 252.28,48.47 254.26,46.48 254.53,46.48 254.7,46.65 JEDP1.21
EDP_TXP0: length 1.9
  BOTTOM w0.076: UC1.D29 100.47,120.99 100.38,121.08 100.38,121.29 v1(100.46,121.37)
  BOTTOM w0.102: v1(250.86,58.66) 251.06,58.46 251.06,58.07 C7.1
EDP_TXP0_C: length 11.7
  BOTTOM w0.102: C7.2 250.7,56.19 252.77,54.12 v4(252.77,51.29) 252.77,49.98 252.75,49.96 252.75,49.39 252.77,49.36 252.77,48.92 253.89,47.8 254.53,47.8 254.67,47.65 JEDP1.19
EDP_TXP1: length 1.7
  BOTTOM w0.102: C9.1 249.18,58.07 249.18,58.54 v1(249.02,58.71) ; UC1.F28 v1(99.79,119.79)
EDP_TXP1_C: length 14.1
  BOTTOM w0.102: C9.2 249.09,56.53 249.09,56.39 249.68,55.79 250.11,55.79 v4(250.72,55.19) 252.07,53.83 252.07,53.43 252.05,53.41 252.05,52.81 252.07,52.79 252.07,48.38 254.18,46.28 254.57,46.28 254.7,46.15 JEDP1.22
EDP_VDD_EN: length 22.4
  TOP w0.102: v1(251.12,28.25) 251.1,28.27 251.1,32.04 251.46,32.4 251.46,36.31 250.95,36.82 250.95,40.32 249.59,41.68 249.59,45.33 v2(251.2,46.94) 251.77,47.51 D4.2
  BOTTOM w0.089: v1(182.75,35.07) 182.74,35.08 182.67,35.08 UH1.AV44
EN_0.6VSP: length 3.1
  BOTTOM w0.203: PRM09.2 39.7,39.66 PCM16.1 38.88,39.99 38.66,40.21 38.33,40.21 37.75,40.79 PUM01.7
EN_1.0VS_VGAP: length 2.1
  BOTTOM w0.102: v2(208.28,80.08) 208.28,78.85 207.73,78.3 PR1005.2
EN_1.2V: length 2.8
  BOTTOM w0.203: PRM08.2 PCM15.1 37.99,39.84 37.35,40.48 PUM01.8
EN_1.8VALW: length 6.3
  BOTTOM w0.102: v2(198.65,62.83) 198.65,63.07 199.09,63.5 PR1806.2
  BOTTOM w0.254: PU1801.5 201.9,66.71 201.9,66.26 201.64,65.99 PR1802.1 200.85,65.59 PC1805.1 PR1801.2 200.28,64.17 199.34,64.17 PR1806.2
EN_2.5V: length 5.6
  BOTTOM w0.102: v2(125.85,68.44) PR2501.2 125.85,66.95 126.91,65.89 PC2503.1 126.33,64.86 PU2501.2
EN_3V: length 3.7
  BOTTOM w0.102: v2(214.06,46.94) 213.97,47.02 PR502.1
  BOTTOM w0.254: PR502.1 212.9,47.35 212.7,47.55 211.85,47.55 211.69,47.72 PU301.12
EN_5V: length 1.8
  BOTTOM w0.203: PR503.1 128.12,55.75 127.59,55.22 PU501.12
EN_+1.05V: length 37.7
  TOP w0.254: v1(110.75,46.35) 110.75,46.3 110.76,46.29 110.76,41.63 v2(111.29,41.1) 114.23,38.15 121.46,38.15 123.1,39.79 132.54,39.79 133.86,38.47 v1(134.81,38.47) 135.08,38.75 136.55,38.75 PRH14.2 ; 71.27,47.92 71.27,47.74 71.81,47.2 v1(71.81,47.12)
  BOTTOM w0.254: v1(134.81,38.47) 135.15,38.81 PCH09.1 136.08,38.96 135.35,39.69 PUH01.3
EN_PD_HV_1: length 5.8
  TOP w0.102: PUS02.1 21.13,38.95 20.55,39.53 18.77,39.53 v1(18.06,40.25)
  BOTTOM w0.102: v1(31.44,94.84) 31.12,94.84 30.67,94.39 RT164.2
EN_VCCIO: length 6.4
  TOP w0.102: v2(47.71,119.4) 47.64,119.4 PC908.1
  TOP w0.254: PC908.1 46.08,118.41 v1(45.86,118.63)
  BOTTOM w0.254: PR904.1 PR913.2 44.87,119.52 44.97,119.42 PR903.2 45.4,118.63 v1(45.86,118.63) 45.9,118.59 PU901.11
EN_VCCSTG_VCCPLL_OC: length 91.4
  TOP w0.102: UC12.4 146.14,34.02 145.39,34.77 145.39,35.32 144.79,35.91 144.12,35.91 143.89,35.69 RZ238.2 143.19,35.69 142.94,35.43 138.57,35.43 138.21,35.79 135.33,35.79 134.74,36.37 131.05,36.37 v2(130.63,36.79) 130.14,37.29 v1(129.79,37.29) ; v1(99.72,87.83) 99.97,88.08 UZ16.3
  BOTTOM w0.102: v1(44.17,120.81) 44.3,120.94 PR913.1 ; v1(117.78,59.51) 117.78,54.36 118.73,53.41 118.73,49.51 120.38,47.86 120.38,46.39 126.01,40.76 127.08,40.76 129.79,38.05 v1(129.79,37.29) ; RZ49.2 111.42,116.48 111.42,113.47 110.91,112.96 110.91,108.67 111.35,108.23 113.69,108.23 116.37,105.55 116.37,102.08 115.86,101.57 115.86,101.26 110.69,96.09 108.45,96.09 107.73,95.37 107.73,92.42 103.15,87.83 v1(99.72,87.83)
ENLDO_3V5V: length 1.5
  TOP w0.102: v2(127.84,57.9) 127.84,57.35 v1(127.66,57.17)
  BOTTOM w0.254: v1(212.68,48.07) 212.25,48.51 PU301.11
ESPI_ALERT#: length 7.1
  TOP w0.102: v2(73.57,33.4) 73.57,33.62 v1(73.12,34.07) 73.46,34.42 73.78,34.42 74.18,34.81 UE1.55 ; v1(182.38,39.65) 183.02,40.29 184.88,40.29 184.91,40.32 184.98,40.32 185.03,40.37 RH578.1
  BOTTOM w0.089: v1(182.38,39.65) 182.38,39.38 UH1.AW35
ESPI_CLK: length 5
  TOP w0.102: RH658.1 187.2,38.89 186.03,38.89 CC57.2 184.84,38.86 v1(184,38.86)
  BOTTOM w0.102: UH1.BB36 v1(184,38.86)
ESPI_CLK_R: length 10
  TOP w0.102: v1(76.63,34.64) 76,34.01 UE1.57 ; v2(189.79,38.15) 189.79,38.64 189.69,38.74 v1(189.59,38.74) 189.19,38.74 RH658.2
  BOTTOM w0.102: v1(76.63,34.64) 74.81,36.47 RE67.2 74.46,38.76 74.46,39.33 74.73,39.6 JESPI1.10
ESPI_CS#: length 18.8
  TOP w0.102: v1(80.17,37.8) 79.74,38.24 79.34,38.24 79.11,38.01 79.11,37.01 77.69,35.59 77.69,34.68 76.56,33.54 76.03,33.54 75.96,33.61 UE1.58 ; v2(183.72,37.59) 184.28,37.59 v1(184.31,37.57)
  BOTTOM w0.076: UH1.BE38 185.33,37.52 185.01,37.52 184.86,37.59 184.42,37.59 v1(184.31,37.57)
  BOTTOM w0.102: JESPI1.7 75.74,41.1 77.75,39.09 78.28,39.09 78.98,38.39 78.98,37.72 78.53,37.27 78.53,37.13 78.72,36.94 78.91,36.94 79.33,37.36 79.74,37.36 v1(80.17,37.8)
ESPI_IO0: length 11
  TOP w0.102: v1(184.25,36.74) 184.89,37.38 187.31,37.38 187.53,37.16 v2(188.01,37.16) 188.75,37.16 189.87,36.04 191.35,36.04 191.86,35.53 191.86,35.21 192.34,34.73 192.34,34.52 192.63,34.22 RPH7.8
  BOTTOM w0.089: UH1.BB39 184,36.99 v1(184.25,36.74)
ESPI_IO0_R: length 21
  TOP w0.102: v1(79.01,34.99) 78.62,35.38 78.18,35.38 77.94,35.14 77.94,34.57 76.63,33.26 76.09,33.26 76.04,33.21 UE1.59 ; v1(195.39,35.3) 195.39,35.3 195.39,34.92 194.69,34.22 RPH7.1
  BOTTOM w0.102: JESPI1.3 76.36,43.1 80.4,39.06 81.18,39.06 81.8,38.45 81.8,36.98 v2(80.83,36.02) 79.8,34.99 v1(79.01,34.99)
ESPI_IO1: length 12.4
  TOP w0.102: RPH7.7 192.67,34.72 192.57,34.83 192.57,34.83 192.09,35.31 192.09,35.63 191.43,36.28 190.09,36.28 v2(189.58,36.8) 188.91,37.46 187.62,37.46 187.5,37.58 184.94,37.58 184.47,38.05 183.23,38.05 v1(182.69,37.51)
  BOTTOM w0.089: UH1.AW37 v1(182.69,37.51)
ESPI_IO1_R: length 19.2
  TOP w0.102: v1(78.35,34.97) 78.35,34.31 76.85,32.81 UE1.60 ; RPH7.2 194.56,34.72 194.8,34.97 v1(194.8,35.3)
  BOTTOM w0.102: v1(78.35,34.97) 78.83,35.46 v2(79.35,35.46) 79.79,35.46 81.55,37.22 81.55,38.29 81.01,38.83 80.3,38.83 76.54,42.6 JESPI1.4
ESPI_IO2: length 13.1
  TOP w0.102: RPH7.6 192.57,35.22 192.32,35.48 192.32,35.72 191.53,36.51 190.33,36.51 189.06,37.78 185.02,37.78 184.51,38.29 182.63,38.29 v2(182.55,38.21) 182.09,37.76 v1(182.09,37.69)
  BOTTOM w0.089: UH1.AV37 181.96,37.83 v1(182.09,37.69)
ESPI_IO2_R: length 22.2
  TOP w0.102: v1(79.37,36.69) 79.37,36.68 79.37,36.17 79.6,35.94 79.6,34.27 78.17,32.84 77.26,32.84 76.84,32.41 UE1.61 73.88,32.41 73.23,31.76 v2(73.23,31.16) ; RPH7.3 194.28,35.22 194.37,35.32 194.37,35.46 194.65,35.74 v1(194.65,35.89)
  BOTTOM w0.102: v1(79.37,36.69) 80.29,36.69 81.25,37.65 81.25,38.2 80.91,38.53 80.28,38.53 78.14,40.67 77.09,40.67 75.66,42.1 JESPI1.5
ESPI_IO3: length 15
  TOP w0.102: 191.36,35.57 191.36,35.42 191.63,35.15 191.63,35.12 192.11,34.64 192.11,34.32 192.53,33.9 193.15,33.9 193.41,34.15 193.41,35.52 193.21,35.72 RPH7.5 ; 191.36,35.57 v2(191.35,35.57) ; 191.36,35.57 191.36,35.58 191.13,35.82 189.77,35.82 188.73,36.85 187.43,36.85 187.18,36.6 185.52,36.6 184.91,35.99 184.46,35.99 183.44,37.01 v1(183.33,37.01)
  BOTTOM w0.089: UH1.BA38 v1(183.33,37.01)
ESPI_IO3_R: length 19
  TOP w0.102: v1(193.51,36.2) 193.51,35.92 193.7,35.72 RPH7.4 ; v1(79.52,37.82) 80.19,37.15 80.19,34.35 78.36,32.53 77.28,32.53 76.89,32.14 76.14,32.14 76.01,32.01 UE1.62
  BOTTOM w0.102: v1(79.52,37.82) 79.52,38.44 78.55,39.42 77.74,39.42 75.57,41.6 JESPI1.6 73.51,41.6 v2(73.28,41.83)
ESPI_RESET#: length 7.6
  TOP w0.102: v1(78.47,37.82) 78.47,37.02 77.07,35.61 UE1.53 ; RH743.1 v1(186.39,36.98)
  BOTTOM w0.089: UH1.BF38 186.39,37.36 v1(186.39,36.98)
  BOTTOM w0.102: v1(78.47,37.82) 78.47,37.69 77.9,37.12 v2(77.9,36.82)
FAN1_PWM: length 6.8
  TOP w0.102: v1(78.22,39.9) 78.2,39.92 78.01,39.92 76.11,38.01 UE1.47
  BOTTOM w0.102: v1(128.86,60.64) 128.92,60.7 RE121.2 129.86,61.12 129.36,61.61 Q23.3
FAN1_PWM_OUT: length 8.3
  TOP w0.102: v1(123.33,67.23) 123.11,67.23 v3(122.63,67.72)
  BOTTOM w0.102: Q23.1 129.54,65.15 RE100.2 128.68,64.36 v1(128.9,64.14) ; JFAN1.2 120.25,67.16 120.57,66.84 122.94,66.84 v1(123.33,67.23)
FAN1_TACH: length 7.3
  TOP w0.102: UE1.40 v1(73.68,40.81) 73.68,40.5 73.53,40.35 73.05,40.35 72.78,40.08 CE28.1
  BOTTOM w0.102: CE99.1 121.77,61.06 RE152.2 121.02,60.72 121.41,60.32 121.41,60.01 DE7.2 v1(120.41,60.01)
FAN1_TACH_D: length 25.8
  TOP w0.102: v1(116.15,68.97) 115.73,69.39 v3(115.58,69.39)
  BOTTOM w0.102: JFAN1.3 121.25,67.32 121.43,67.14 122.48,67.14 122.83,67.5 122.83,68.86 121.25,70.45 117.63,70.45 v1(116.15,68.97) 115.6,68.41 115.6,62.51 117.65,60.45 118.78,60.45 119.23,60.01 DE7.1 119.71,59.43 119.74,59.41 RE82.2
FAN2_PWM: length 6.6
  TOP w0.102: v3(271.3,64.39) 271.22,64.31 v1(270.74,64.31) ; v1(76.71,41.73) 76.77,41.79 76.77,42.56 76.12,43.21 UE1.34
  BOTTOM w0.102: v1(270.74,64.31) 270.43,64.62 Q24.3 270.43,66.22 270.83,66.61 RE122.2
FAN2_PWM_OUT: length 9.2
  TOP w0.102: v1(272.59,63.25) 273.45,63.25 v3(273.5,63.3)
  BOTTOM w0.102: Q24.1 272.52,63.32 v1(272.59,63.25) 272.9,63.25 RE101.2 273.33,62.85 274.54,61.64 276.8,61.64 277.2,61.24 JFAN2.2
FAN2_TACH: length 11.6
  TOP w0.102: DE9.2 279.78,56.23 279.86,56.15 CE100.1 279.86,54.79 RE153.2 279.36,54.29 277.76,54.29 v2(277.67,54.21) 277.29,53.82 v1(275.57,53.82) ; UE1.41 76.1,40.41 76.24,40.55 78.55,40.55 78.83,40.28 v1(79.78,40.28)
FAN2_TACH_D: length 6.4
  TOP w0.102: v1(278.93,57.98) 279.33,57.98 DE9.1 279.86,58.51 279.86,59.03 279.42,59.47 v3(278.84,59.47) 278,59.47 RE151.2
  BOTTOM w0.102: v1(278.93,57.98) 278.38,57.98 278.2,58.16 JFAN2.3
FB_1.0VS_VGAP:
  vias: v2(206.19,73.44)
FB_1.2V: length 5.2
  BOTTOM w0.203: 38.61,40.85 38.34,40.85 38.15,41.04 PUM01.6
  BOTTOM w0.508: PRM11.1 40.77,39.77 PCM17.1 ; PCM17.1 PRM10.1 ; PCM17.1 40.64,39.83 39.62,40.85 38.61,40.85
FB_1.8VALW: length 4.7
  BOTTOM w0.102: PC1807.2 197.26,64.21 v2(197.12,64.07)
  BOTTOM w0.254: PU1801.6 198.41,66.74 198.16,66.49 PR1805.1 197.94,65.57 197.52,65.99 PR1807.2 197.23,65.55 197.26,65.52 PC1807.2
FB_2PH: length 5.5
  TOP w0.102: v1(112.15,147.09) v2(111.41,147.09)
  TOP w0.203: PRZ47.1 113.66,146.45 PCZ24.1 112.6,146.45 112.15,146.91 v1(112.15,147.09)
  BOTTOM w0.102: PCZ23.2 113.62,147.28 PRZ46.1
  BOTTOM w0.203: PRZ46.1 112.72,147.18 112.23,147.18 v1(112.15,147.09) 112.06,147.18 PUZ01.34
FB_4PH: length 7.5
  BOTTOM w0.102: PRZ28.1 v2(99.11,145.94)
  BOTTOM w0.203: PRZ28.1 100.22,146.02 PCZ15.2 101.02,145.74 101.69,145.07 PRZ30.1 101.94,145.1 PCZ13.2 102.26,146.02 103.02,146.78 PUZ01.5
FB_+1.05V: length 2.3
  BOTTOM w0.254: PUH01.4 134.85,39.56 PRH13.1 134.12,38.84 PRH10.1
FB_A_CLK0: length 2.1
  BOTTOM w0.102: 233.5,144.45 UV6.J12
  BOTTOM w0.112: 233.48,132.1 233.66,132.27 233.66,132.56 RV595.1
  BOTTOM w0.119: UV1.R30 222.07,119.05 221.67,119.45
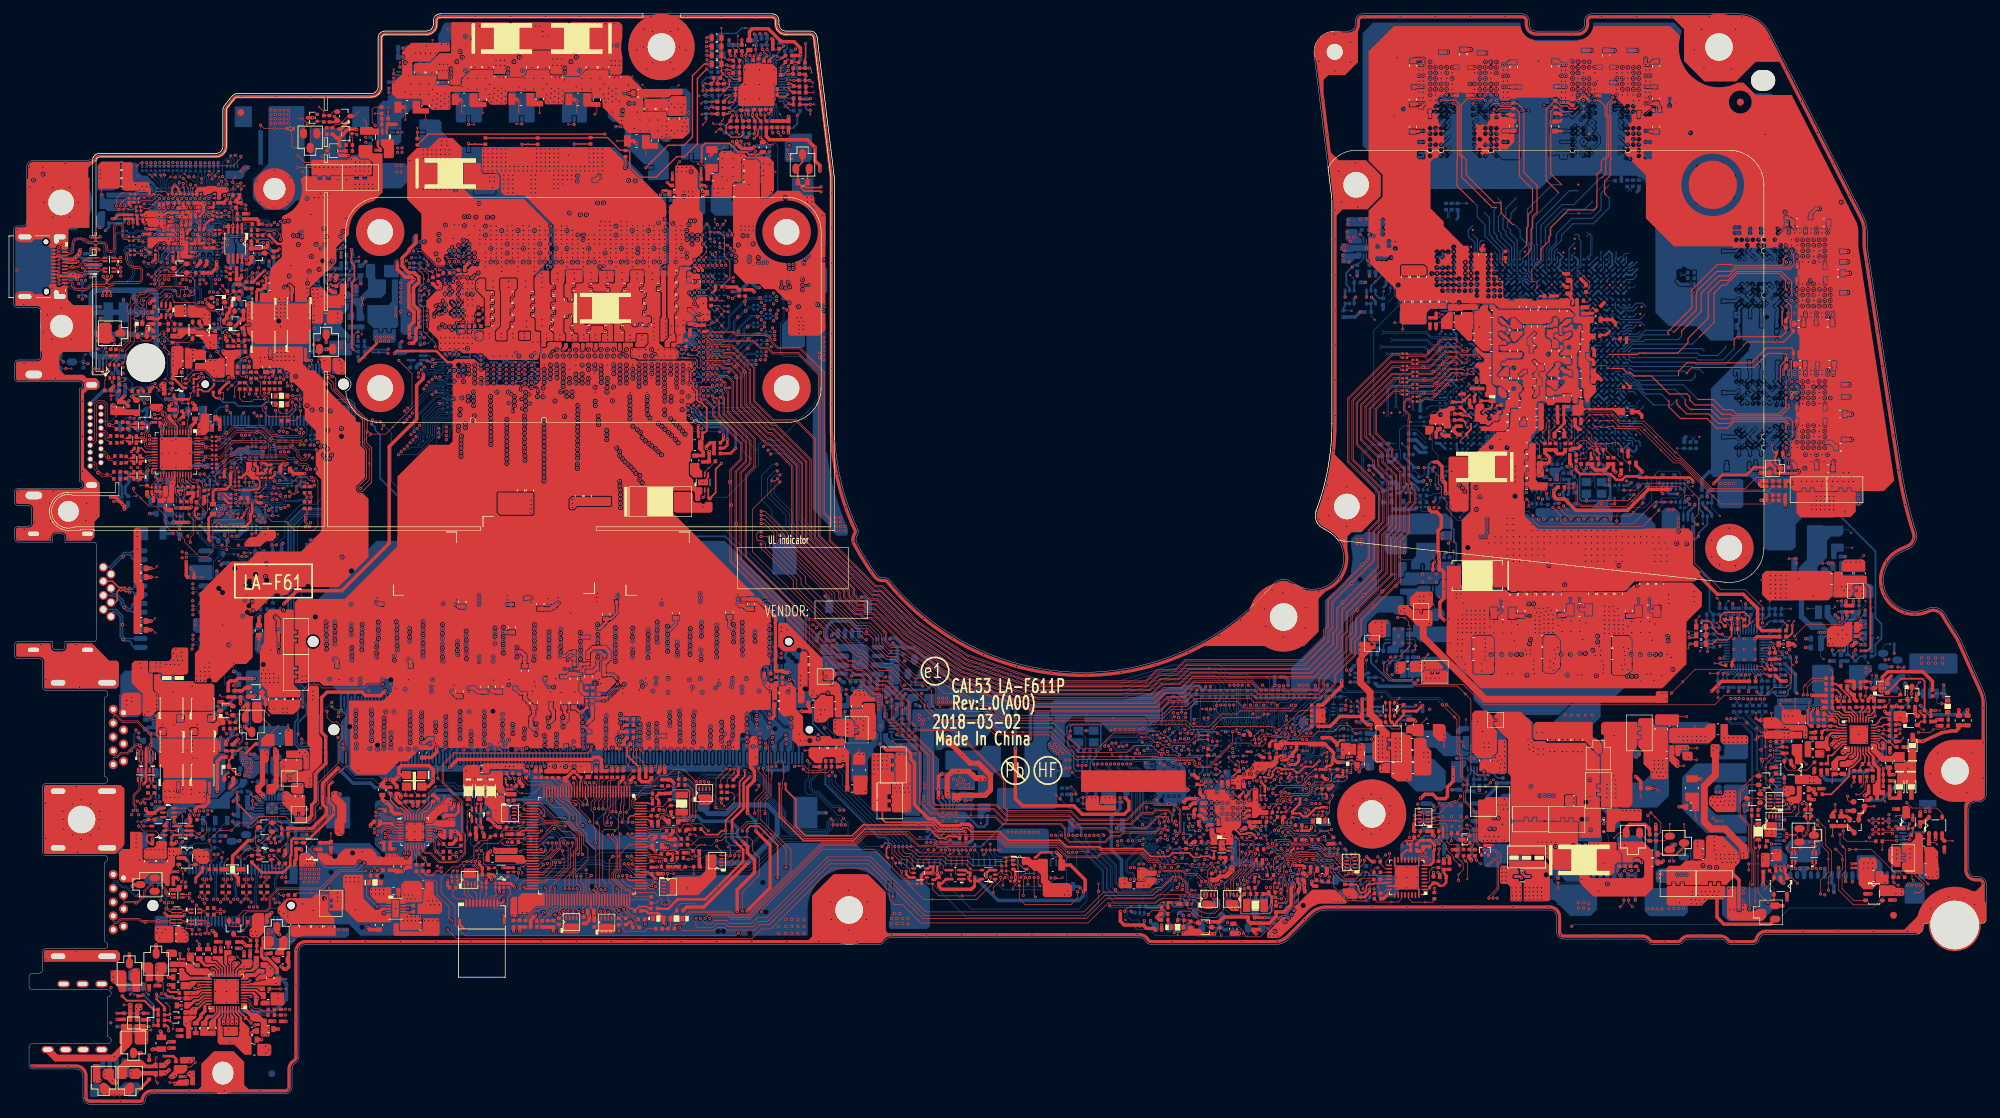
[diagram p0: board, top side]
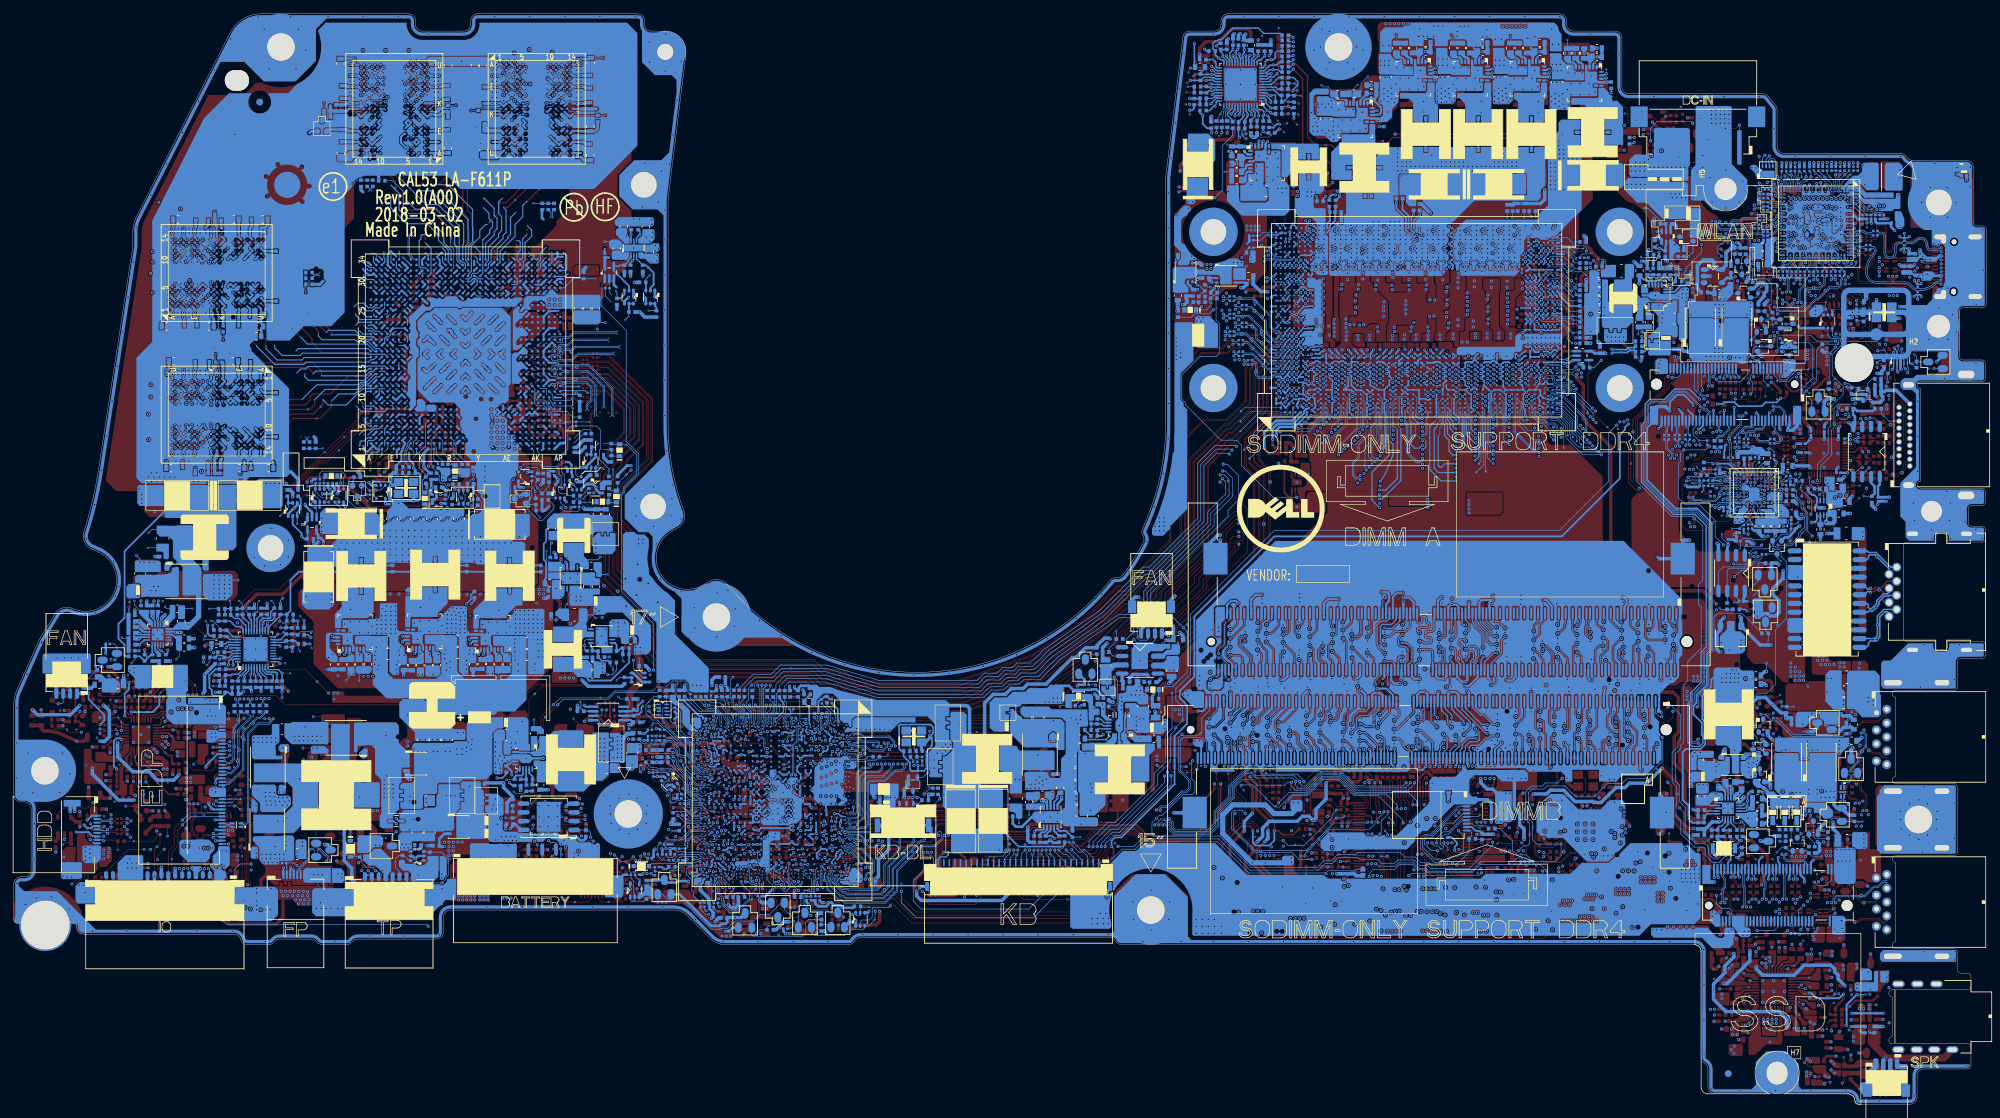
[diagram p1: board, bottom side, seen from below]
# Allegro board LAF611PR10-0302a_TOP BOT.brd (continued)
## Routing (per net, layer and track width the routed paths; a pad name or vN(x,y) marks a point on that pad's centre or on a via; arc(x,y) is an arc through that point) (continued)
FB_A_CLK0#: length 2.1
  BOTTOM w0.102: 233.5,143.65 UV6.J11
  BOTTOM w0.112: 234.07,132.1 233.87,132.3 233.87,132.45 RV594.1
  BOTTOM w0.119: UV1.R31 222.5,119.45
FB_A_CLK1: length 2.6
  BOTTOM w0.102: 206.5,144.45 206.1,144.05 UV7.J12
  BOTTOM w0.112: 207.83,128.22 207.63,128.42 207.63,129.07 RV597.1
  BOTTOM w0.119: UV1.AB31 216.22,119.85 215.82,120.25
FB_A_CLK1#: length 2.5
  BOTTOM w0.102: UV7.J11 206.9,144.05 206.5,143.65
  BOTTOM w0.112: 207.25,128.22 207.42,128.4 207.42,129.22 RV596.1
  BOTTOM w0.119: 215,120.25 215.02,120.25 215.4,119.87 UV1.AC31
FB_A_CMD0: length 1.2
  BOTTOM w0.102: 233.5,142.85 UV6.G12
  BOTTOM w0.168: UV1.U30 220.43,119.05 220.82,119.45
FB_A_CMD1: length 1.1
  BOTTOM w0.168: UV6.H10 232.3,143.25 232.65,142.89 ; 220.82,120.25 221.22,119.85 UV1.T31
FB_A_CMD2: length 1.2
  BOTTOM w0.102: 232.7,143.65 UV6.H11
  BOTTOM w0.168: 220.82,118.62 UV1.U29
FB_A_CMD3: length 17.8
  BOTTOM w0.102: 231.57,144.47 231.57,144.47 231.57,144.47 232.72,144.47 UV6.K11
  BOTTOM w0.168: UV1.R34 222.1,123.63 223.16,124.69 223.16,125.95 225.4,128.2 228.36,128.2 229.63,129.47 229.63,131.85 230.8,133.02
FB_A_CMD4: length 30.9
  TOP w0.168: v1(231.57,145.06) 231.33,145.06 230.92,144.64 230.92,143.13 231.05,143 231.05,136.7 230.96,136.61 230.96,134.4 230.15,133.58 v2(230.15,132.62) 230.15,131.79 230.37,131.57
  BOTTOM w0.102: v1(231.57,145.06) 231.57,145.05 231.62,145.1 232.05,145.1 UV6.K10
  BOTTOM w0.168: UV1.R33 222.5,121.85 222.5,123.62 223.91,125.03 223.91,125.75 225.57,127.42 228.5,127.42 230.82,129.74 230.82,131.12 230.37,131.57
FB_A_CMD5: length 34.4
  TOP w0.168: 229.7,134.05 230.31,134.67 v2(230.31,136.08) 230.31,136.71 230.72,137.12 230.72,138.76 230.76,138.8 230.76,142.9 230.51,143.16 230.51,144.74 231.32,145.55 v1(231.32,145.75)
  BOTTOM w0.102: v1(231.32,145.75) 231.51,145.56 231.89,145.56 232.21,145.24 233.49,145.24 UV6.L12
  BOTTOM w0.168: 229.7,134.05 229.54,134.05 225.69,130.2 223.98,130.2 220.93,127.15 220.93,122.25 220.74,122.05 220.74,122.04 220.54,121.85 220.26,121.85 220.01,121.61 220.01,121.03 UV1.U32
FB_A_CMD6: length 15
  BOTTOM w0.102: 227.9,144.45 UV6.K4
  BOTTOM w0.168: 228.4,130.66 227.26,129.53 224.23,129.53 221.58,126.88 221.58,124.45 221.25,124.12 221.25,122.15 220.55,121.45 UV1.U33
FB_A_CMD7: length 37.1
  TOP w0.102: 220.92,122.45 220.92,122.18 219.62,120.87 219.62,119.29 219.87,119.04 220.12,119.04 220.38,118.78 220.38,118.16 220,117.77
  TOP w0.168: v1(228.7,145.25) 229.41,145.25 230.22,144.44 230.22,143.06 230.49,142.79 230.49,138.91 230.45,138.87 230.45,137.23 229.66,136.44 229.66,135.19 229.05,134.58 229.05,129.9 228.57,129.42 224.89,129.42 222.34,126.88 222.34,125.74 222.1,125.5 v2(222.1,125.3) 222.1,124.91 220.92,123.73 220.92,122.45
  BOTTOM w0.102: UV6.K5 v1(228.7,145.25)
  BOTTOM w0.168: 220,117.77 220.21,117.57 220.21,117.54 UV1.U28
FB_A_CMD8: length 1.1
  BOTTOM w0.102: 227.9,143.65 UV6.J4
  BOTTOM w0.168: 220,116.95 UV1.V28
FB_A_CMD9: length 1.1
  BOTTOM w0.102: UV6.J5 228.35,144.05 228.68,144.38
  BOTTOM w0.168: 220,118.62 219.6,118.22 UV1.V29
FB_A_CMD10: length 3.9
  BOTTOM w0.102: 227.9,142.85 UV6.H4
  BOTTOM w0.168: 219.17,117.77 218.3,118.65 218.3,119.15 218.36,119.2 218.36,119.21 218.59,119.44 218.6,119.44 218.6,119.45 218.74,119.45 218.75,119.44 218.91,119.44 219.14,119.21 219.31,119.05 UV1.V30
FB_A_CMD11: length 13.8
  BOTTOM w0.102: 228.75,143.48 228.72,143.48 228.72,143.46 228.51,143.46 UV6.H5
  BOTTOM w0.168: 226.32,132.2 225.06,132.2 220.28,127.42 220.28,124.5 220.4,124.38 UV1.U34
FB_A_CMD12: length 1.1
  BOTTOM w0.102: 227.1,142.85 UV6.G3
  BOTTOM w0.168: 220,120.25 UV1.U31
FB_A_CMD13: length 29.5
  TOP w0.168: 225.5,143.65 225.48,143.64 224.04,143.64 223.35,144.32 RV108.1 222.35,143.67 v2(222.35,138.97) 222.35,134.66 223.94,133.07
  BOTTOM w0.102: UV6.J2 225.9,144.05 225.5,143.65
  BOTTOM w0.168: UV1.V34 219.6,124.19 218.98,124.81 218.98,129.49 222.56,133.07 223.94,133.07
FB_A_CMD14: length 31.5
  TOP w0.168: 223.49,131.93 221.68,133.74 221.68,143.96 v2(221.77,144.05) 222.97,145.24 RV95.2 223.76,144.48 224.73,144.48 225.13,144.07 225.92,144.07 226.3,144.45
  BOTTOM w0.102: 226.3,144.45 UV6.J3
  BOTTOM w0.168: UV1.V33 219.6,121.7 219.72,121.82 219.72,121.84 219.98,122.09 219.98,124.24 219.63,124.59 219.63,128.02 223.49,131.88 223.49,131.93
FB_A_CMD15: length 3.3
  BOTTOM w0.102: UV6.L3 v1(227.1,145.25)
  BOTTOM w0.168: UV1.Y32 218.3,120.25 218.95,120.25 219.15,120.05 219.15,119.75 219.45,119.45 220,119.45
FB_A_CMD16: length 2
  BOTTOM w0.102: 206.5,142.85 UV7.L12
  BOTTOM w0.168: 215.82,119.45 216.7,119.45 UV1.AA31
FB_A_CMD17: length 1.1
  BOTTOM w0.102: 207.34,142.9 UV7.K10
  BOTTOM w0.168: UV1.AA29 216.67,117.77
FB_A_CMD18: length 1.2
  BOTTOM w0.102: UV7.K11 206.9,143.25 207.3,143.65
  BOTTOM w0.168: 216.67,116.95 216.7,116.95 UV1.AA28
FB_A_CMD19: length 9.6
  BOTTOM w0.102: 208.3,144.24 208.12,144.42 207.49,144.42 207.06,144.85 UV7.H11
  BOTTOM w0.168: 212.73,129.05 213.48,128.3 213.48,125.88 213.85,125.52 213.85,125.31 215.4,123.76 UV1.AC34
FB_A_CMD20: length 27.1
  TOP w0.168: v1(208.25,144.85) 208.38,144.85 208.85,144.38 208.85,138.03 208.85,138.03 208.85,136.62 208.79,136.56 208.79,132.94 v2(209.28,132.44) 211.08,130.65
  BOTTOM w0.102: UV7.H10 v1(208.25,144.85)
  BOTTOM w0.168: 211.08,130.65 211.11,130.65 211.72,130.04 211.72,128.43 212.83,127.32 212.83,125.61 215,123.45 215,121.85 UV1.AC33
FB_A_CMD21: length 31.5
  TOP w0.168: 214.51,129.78 213.88,129.78 v2(212.82,130.84) 209.47,134.18 209.47,136.98 209.12,137.34 209.12,144.73 209.12,144.74 208.56,145.31 206.55,145.31 v1(206.5,145.25)
  BOTTOM w0.102: UV7.G12 v1(206.5,145.25)
  BOTTOM w0.168: 214.51,129.78 214.13,129.4 214.13,126.15 214.56,125.73 214.56,125.3 216.29,123.57 216.29,122.01 216.7,121.6 216.7,121.05 UV1.AA32
FB_A_CMD22: length 11.6
  BOTTOM w0.102: UV7.H4 212.1,144.45 212.1,144.45
  BOTTOM w0.168: UV1.AA33 217.1,121.7 216.69,122.11 216.69,124.04 215.21,125.52 215.21,125.99 214.78,126.42 214.78,128.47 215.21,128.9 215.21,130.57 214.66,131.12
FB_A_CMD23: length 1.1
  BOTTOM w0.102: UV7.H5 v1(211.1,144.85)
  BOTTOM w0.168: UV1.Y28 218.27,117.72
FB_A_CMD24: length 1.2
  BOTTOM w0.102: 212.9,143.65 UV7.J4
  BOTTOM w0.168: 217.5,117.77 217.5,117.8 217.81,118.11 UV1.Y29
FB_A_CMD25: length 2
  BOTTOM w0.102: 211.1,144.05 UV7.J5
  BOTTOM w0.168: UV1.W31 218.55,119.85 218.15,119.45 217.5,119.45
FB_A_CMD26: length 1.2
  BOTTOM w0.102: 212.1,143.65 UV7.K4
  BOTTOM w0.168: UV1.Y30 217.9,119.02 217.5,118.62
FB_A_CMD27: length 11.1
  BOTTOM w0.102: 211.1,143.15 211.2,143.25 UV7.K5
  BOTTOM w0.168: UV1.AA34 217.1,124.55 215.86,125.79 215.86,126.26 215.43,126.69 215.43,128.2 215.86,128.63 215.86,129.65 217.31,131.1 217.43,131.1
FB_A_CMD28: length 11.8
  BOTTOM w0.102: 212.9,142.85 UV7.L3
  BOTTOM w0.168: 217.43,129.75 216.61,128.93 216.61,128.21 216.08,127.69 216.08,126.96 216.51,126.53 216.51,126.06 217.5,125.07 217.5,120.25 217.81,119.94 UV1.Y31
FB_A_CMD29: length 27.1
  TOP w0.168: 218.62,124.05 218.85,124.28 218.85,126.84 219.09,127.09 219.09,128.75 219.72,129.38 219.72,132.41 217.81,134.33 v2(217.81,139.03) 217.81,143.59 217.33,144.06 RV107.1 214.91,144.06 214.5,143.65
  BOTTOM w0.102: 214.5,143.65 214.5,143.65 UV7.J2
  BOTTOM w0.168: UV1.Y34 217.9,123.33 218.62,124.05
FB_A_CMD30: length 30.5
  TOP w0.168: 213.7,144.45 214.08,144.83 214.79,144.83 215.19,144.43 216.44,144.43 RV98.2 217.41,144.93 218.46,143.88 v2(218.46,141.39) 218.46,134.84 220.37,132.92 220.37,129.11 219.74,128.48 219.74,126.82 219.5,126.57 219.5,123.84 219.31,123.65 219.31,123.37 218.64,122.7
  BOTTOM w0.102: 213.7,144.45 213.7,144.45 UV7.J3
  BOTTOM w0.168: 218.64,122.7 218.32,122.39 218.32,121.87 UV1.Y33
FB_A_CMD31: length 34.2
  TOP w0.168: v1(212.9,145.25) 212.61,145.54 210.31,145.54 209.39,144.62 209.39,137.45 210.12,136.71 210.12,134.48 214.14,130.47 215.01,130.47 215.16,130.31 215.16,128.99 v2(216.42,127.73) 216.84,127.31 216.89,127.31
  BOTTOM w0.102: v1(212.9,145.25) 213.3,145.65 UV7.G3
  BOTTOM w0.168: UV1.V31 219.6,120.1 219.16,120.53 219.16,124.24 217.93,125.47 217.93,126.47 217.09,127.31 216.89,127.31
FB_A_D0: length 1.1
  BOTTOM w0.102: UV6.A4 227.84,137.31 227.84,137.28
  BOTTOM w0.168: 225.82,116.95 225.42,117.35 UV1.L28
FB_A_D1: length 1.2
  BOTTOM w0.102: UV6.A2 225.9,137.65 225.5,137.25
  BOTTOM w0.168: 224.17,117.77 UV1.M29
FB_A_D2: length 1.2
  BOTTOM w0.102: 227.9,138.05 UV6.B4
  BOTTOM w0.168: 225.82,117.77 UV1.L29
FB_A_D3: length 1.2
  BOTTOM w0.102: 225.5,138.05 225.9,138.45 UV6.B2
  BOTTOM w0.168: UV1.M28 224.57,117.35 224.17,116.95
FB_A_D4: length 1.2
  BOTTOM w0.102: 227.1,140.45 227.5,140.85 UV6.E4
  BOTTOM w0.168: 223.32,119.42 223.32,119.42 UV1.N31
FB_A_D5: length 1.2
  BOTTOM w0.102: UV6.E2 225.9,140.85 225.5,140.45
  BOTTOM w0.168: UV1.P29 223.32,117.77
FB_A_D6: length 1.2
  BOTTOM w0.102: 227.1,141.25 227.5,141.65 UV6.F4
  BOTTOM w0.168: 221.67,117.77 UV1.R29
FB_A_D7: length 1.2
  BOTTOM w0.102: UV6.F2 225.9,141.65 225.5,141.25
  BOTTOM w0.168: 222.5,117.77 222.5,117.75 UV1.P28
FB_A_D8: length 1.4
  BOTTOM w0.102: UV6.A11 233.1,137.06 233.23,136.93
  BOTTOM w0.168: 226.67,117.77 UV1.J28
FB_A_D9: length 1.2
  BOTTOM w0.102: 235.1,137.25 UV6.A13
  BOTTOM w0.168: UV1.H29 228.32,118.62
FB_A_D10: length 1.1
  BOTTOM w0.102: 233.5,138.05 UV6.B11
  BOTTOM w0.168: UV1.J29 227.08,118.2 226.7,118.58
FB_A_D11: length 1.2
  BOTTOM w0.102: 235.1,138.05 UV6.B13
  BOTTOM w0.168: UV1.H28 228.3,117.75 228.41,117.75
FB_A_D12: length 1.2
  BOTTOM w0.102: UV6.E11 233.5,140.45
  BOTTOM w0.168: 229.17,118.62 UV1.G29
FB_A_D13: length 1.2
  BOTTOM w0.102: 234.3,141.25 UV6.E13
  BOTTOM w0.168: UV1.E31 230.42,119.85 230.82,120.25
FB_A_D14: length 1.1
  BOTTOM w0.102: 233.5,141.25 UV6.F11
  BOTTOM w0.168: 230,120.25 UV1.E32
FB_A_D15: length 1.1
  BOTTOM w0.102: 235.1,141.25 UV6.F13
  BOTTOM w0.168: 230,119.45 UV1.F30
FB_A_D16: length 1.2
  BOTTOM w0.102: UV6.U11 v1(233.5,150.05)
  BOTTOM w0.168: UV1.C34 232.51,122.66 232.51,122.7
FB_A_D17: length 1.2
  BOTTOM w0.102: UV6.U13 v1(235.1,150.05)
  BOTTOM w0.168: UV1.D32 231.65,121.05 231.67,121.05
FB_A_D18: length 1.9
  BOTTOM w0.102: UV6.T11 v1(232.7,150.05)
  BOTTOM w0.168: UV1.B33 233.24,121.79 233.31,121.86 233.31,122.66
FB_A_D19: length 2.7
  BOTTOM w0.102: UV6.T13 v1(235.1,149.25)
  BOTTOM w0.168: 231.81,123.35 231.81,122.53 231.67,122.39 231.67,121.87 231.76,121.79 UV1.C33
FB_A_D20: length 1.2
  BOTTOM w0.102: UV6.N11 v1(232.7,147.65)
  BOTTOM w0.168: UV1.F33 229.57,121.45 229.17,121.05
FB_A_D21: length 2
  BOTTOM w0.102: UV6.N13 v1(234.3,146.85)
  BOTTOM w0.168: 230,121.92 230,121.05 UV1.F32
FB_A_D22: length 2.3
  BOTTOM w0.102: v1(233.5,146.85) 233.1,146.45 UV6.M11
  BOTTOM w0.168: 229.17,122.65 229,122.48 228.93,122.48 UV1.H33
FB_A_D23: length 1.2
  BOTTOM w0.102: UV6.M13 v1(235.1,146.05)
  BOTTOM w0.168: 228.32,120.25 228.3,120.25 UV1.H32
FB_A_D24: length 2.3
  BOTTOM w0.102: v1(227.9,150.85) 227.5,150.45 UV6.U4
  BOTTOM w0.168: UV1.P34 222.9,123.42 223.32,123.85
FB_A_D25: length 1.1
  BOTTOM w0.102: v1(226.3,150.85) 226.3,150.85 UV6.U2
  BOTTOM w0.168: 222.5,121.05 UV1.P32
FB_A_D26: length 1.2
  BOTTOM w0.102: UV6.T4 v1(227.1,150.05)
  BOTTOM w0.168: 223.32,120.25 223.3,120.25 UV1.P31
FB_A_D27: length 1.9
  BOTTOM w0.102: UV6.T2 v1(225.5,150.05)
  BOTTOM w0.168: UV1.P33 223.32,121.87 223.32,122.65
FB_A_D28: length 5.9
  BOTTOM w0.102: UV6.N4 v1(227.1,146.85)
  BOTTOM w0.168: UV1.L31 225,120.25 225,123.82 225.59,124.41 225.82,124.64
FB_A_D29: length 1.7
  BOTTOM w0.102: UV6.N2 v1(225.5,146.85)
  BOTTOM w0.168: 225.82,123.25 225.46,122.89 225.4,122.82 UV1.L34
FB_A_D30: length 7.3
  BOTTOM w0.168: UV6.M4 v1(227.9,146.05) ; 225.82,125.85 226.27,125.85 226.44,125.68 226.44,125.23 226.7,124.97 226.7,121.29 226.46,121.05 225.8,121.05 UV1.L32
FB_A_D31: length 1.2
  BOTTOM w0.102: UV6.M2 v1(226.3,146.05)
  BOTTOM w0.168: 225.82,121.85 225.42,121.45 UV1.L33
FB_A_D32: length 1.1
  BOTTOM w0.102: 212.1,137.25 212.5,137.64 UV7.U4
  BOTTOM w0.168: 211.67,117.04 211.79,117.04 UV1.AG28
FB_A_D33: length 1.2
  BOTTOM w0.102: UV7.U2 214.1,137.65 214.5,137.25
  BOTTOM w0.168: UV1.AF29 213.32,117.77
FB_A_D34: length 1.2
  BOTTOM w0.102: 212.1,138.05 212.5,138.45 UV7.T4
  BOTTOM w0.168: 211.67,117.77 UV1.AG29
FB_A_D35: length 1.2
  BOTTOM w0.102: UV7.T2 214.1,138.45 213.7,138.05
  BOTTOM w0.168: 213.32,116.95 213.3,116.95 UV1.AF28
FB_A_D36: length 1.1
  BOTTOM w0.102: UV7.N4 212.9,140.45
  BOTTOM w0.168: 214.23,118.68 UV1.AD30
FB_A_D37: length 1.2
  BOTTOM w0.102: 213.7,141.25 UV7.N2
  BOTTOM w0.168: UV1.AD29 215,117.8 215,117.77
FB_A_D38: length 1.2
  BOTTOM w0.102: 212.9,141.25 UV7.M4
  BOTTOM w0.168: 215.82,117.77 UV1.AC29
FB_A_D39: length 1.1
  BOTTOM w0.102: 214.5,141.25 UV7.M2
  BOTTOM w0.168: UV1.AD28 215,116.95
FB_A_D40: length 1.2
  BOTTOM w0.102: 207.3,137.25 UV7.U11
  BOTTOM w0.168: UV1.AJ29 210.77,118.62 210.8,118.62
FB_A_D41: length 1.2
  BOTTOM w0.102: 204.9,137.25 205.3,137.65 UV7.U13
  BOTTOM w0.168: 209.92,117.72 UV1.AK29
FB_A_D42: length 1.1
  BOTTOM w0.102: 206.5,138.05 206.9,138.45 UV7.T11
  BOTTOM w0.168: UV1.AJ30 210.05,119.4 210.05,119.45
FB_A_D43: length 1.2
  BOTTOM w0.102: 204.9,138.05 205.3,138.45 UV7.T13
  BOTTOM w0.168: 209.1,117.72 209.1,117.7 UV1.AK28
FB_A_D44: length 1.1
  BOTTOM w0.102: UV7.N11 206.9,140.85 206.5,140.45
  BOTTOM w0.168: UV1.AM29 207.5,118.55
FB_A_D45: length 1.2
  BOTTOM w0.102: 205.7,140.45 UV7.N13
  BOTTOM w0.168: 207.5,120.22 207.5,120.2 UV1.AM31
FB_A_D46: length 1.2
  BOTTOM w0.102: 206.5,141.25 206.9,141.65 UV7.M11
  BOTTOM w0.168: 206.7,117.72 206.7,117.75 UV1.AN29
FB_A_D47: length 1.2
  BOTTOM w0.102: UV7.M13 205.3,141.65 204.9,141.25
  BOTTOM w0.168: UV1.AM30 207.5,119.35 207.5,119.37
FB_A_D48: length 2.7
  BOTTOM w0.102: UV7.A11 v1(206.5,150.05)
  BOTTOM w0.168: 205.13,120.21 205.54,119.8 UV1.AN31
FB_A_D49: length 1.2
  BOTTOM w0.102: v1(204.9,150.85) 205.3,150.45 UV7.A13
  BOTTOM w0.168: UV1.AN32 206.7,120.25 206.7,120.22
FB_A_D50: length 1.2
  BOTTOM w0.102: v1(207.3,150.05) 206.9,149.65 UV7.B11
  BOTTOM w0.168: 205.9,118.57 205.9,118.66 206.19,118.95 UV1.AP30
FB_A_D51: length 4.3
  BOTTOM w0.102: UV7.B13 v1(204.9,150.05)
  BOTTOM w0.168: 205.9,123.35 205.35,122.8 205.35,120.9 205.6,120.65 UV1.AP32
FB_A_D52: length 2.6
  BOTTOM w0.102: UV7.E11 v1(206.5,147.65)
  BOTTOM w0.168: UV1.AM33 207.56,121.79 207.5,121.85 207.5,123.35
FB_A_D53: length 1.1
  BOTTOM w0.102: UV7.E13 v1(205.7,146.85)
  BOTTOM w0.168: UV1.AL31 208.53,120.02 208.3,120.25
FB_A_D54: length 3.7
  BOTTOM w0.102: UV7.F11 v1(207.3,146.05)
  BOTTOM w0.168: UV1.AK33 209.6,121.7 209.15,122.15 209.15,123.22 208.32,124.05
FB_A_D55: length 3
  BOTTOM w0.102: v1(204.9,146.05) 205.3,146.45 UV7.F13
  BOTTOM w0.168: UV1.AK32 209.15,121.1 209.15,121.65 208.75,122.05 208.75,122.18 208.33,122.6
FB_A_D56: length 1.8
  BOTTOM w0.102: v1(212.9,150.85) 212.5,150.45 UV7.A4
  BOTTOM w0.168: UV1.AD34 214.6,122.92 214.17,123.35
FB_A_D57: length 1.2
  BOTTOM w0.102: v1(214.5,150.85) 214.1,150.45 UV7.A2
  BOTTOM w0.168: 214.17,120.25 214.57,120.65 UV1.AD32
FB_A_D58: length 1.1
  BOTTOM w0.102: UV7.B4 v1(212.1,150.05)
  BOTTOM w0.168: 214.99,118.66 215.01,118.66 UV1.AC30
FB_A_D59: length 1.2
  BOTTOM w0.102: UV7.B2 v1(213.7,150.05)
  BOTTOM w0.168: UV1.AD33 214.2,121.85 214.17,121.85
FB_A_D60: length 2.7
  BOTTOM w0.102: v1(212.9,147.65) 212.5,147.25 UV7.E4
  BOTTOM w0.168: UV1.AF31 212.5,119.45 212.5,118.8 212.67,118.62 213.32,118.62
FB_A_D61: length 4.7
  BOTTOM w0.102: v1(213.7,146.85) 214.1,147.25 UV7.E2
  BOTTOM w0.168: 211.08,125.88 211.74,125.22 211.74,122.47 211.96,122.25 UV1.AG34
FB_A_D62: length 8
  BOTTOM w0.102: UV7.F4 212.5,146.45 v1(212.1,146.05)
  BOTTOM w0.168: UV1.AG32 211.91,120.84 211.65,121.1 211.65,121.98 211.39,122.24 211.39,124.65 210.43,125.61 210.43,126.5 211.08,127.15
FB_A_D63: length 4.9
  BOTTOM w0.102: UV7.F2 v1(214.5,146.05)
  BOTTOM w0.168: 212.7,124.96 212.27,124.96 212.09,124.77 212.09,123.53 212.52,123.1 212.52,122.14 212.1,121.72 UV1.AG33
FB_A_DBI0: length 1.2
  BOTTOM w0.102: UV6.D2 225.9,140.05 225.5,139.65
  BOTTOM w0.168: 223.32,118.62 UV1.P30
FB_A_DBI1: length 1.2
  BOTTOM w0.102: UV6.D13 235.1,139.65
  BOTTOM w0.168: UV1.F31 229.57,119.85 229.17,120.25
FB_A_DBI2: length 1.8
  BOTTOM w0.102: 229.6,123.12 229.6,122.25 UV1.F34 ; UV6.P13 v1(235.1,147.65)
  BOTTOM w0.168: 229.6,123.47 229.6,123.12
FB_A_DBI3: length 1.2
  BOTTOM w0.102: UV6.P2 v1(225.5,148.45)
  BOTTOM w0.168: UV1.M32 224.57,120.65 224.17,121.05
FB_A_DBI4: length 1.2
  BOTTOM w0.102: UV7.P2 214.1,140.05 213.7,139.65
  BOTTOM w0.168: UV1.AD31 214.18,119.43
FB_A_DBI5: length 1.1
  BOTTOM w0.102: UV7.P13 205.3,140.05 204.9,139.65
  BOTTOM w0.168: 208.3,118.55 UV1.AL29
FB_A_DBI6: length 1.1
  BOTTOM w0.102: UV7.D13 v1(204.9,148.45)
  BOTTOM w0.168: UV1.AM32 207.5,121.05
FB_A_DBI7: length 1.2
  BOTTOM w0.102: UV7.D2 v1(214.5,147.65)
  BOTTOM w0.168: 213.32,122.65 213.1,122.43 213.08,122.43 UV1.AF34
FB_A_EDC0: length 1.2
  BOTTOM w0.102: UV6.C2 225.9,139.25 225.5,138.85
  BOTTOM w0.168: 224.17,119.45 224.57,119.85 UV1.M31
FB_A_EDC1: length 1.2
  BOTTOM w0.102: 234.3,138.85 234.7,139.25 UV6.C13
  BOTTOM w0.168: UV1.G31 228.35,119.45 228.32,119.45
FB_A_EDC2: length 2.1
  BOTTOM w0.102: UV6.R13 v1(234.3,148.45)
  BOTTOM w0.168: 230.8,122.8 230.8,121.85 UV1.E33
FB_A_EDC3: length 1.2
  BOTTOM w0.102: UV6.R2 v1(226.3,149.25)
  BOTTOM w0.168: UV1.M33 224.57,121.45 224.17,121.85
FB_A_EDC4: length 1.2
  BOTTOM w0.102: UV7.R2 214.5,138.85
  BOTTOM w0.168: 213.32,120.25 213.72,119.85 UV1.AE31
FB_A_EDC5: length 1.1
  BOTTOM w0.102: 205.7,138.85 UV7.R13
  BOTTOM w0.168: UV1.AK30 209.47,119.05 209.08,119.44
FB_A_EDC6: length 1.8
  BOTTOM w0.102: UV7.C13 v1(205.7,149.25)
  BOTTOM w0.168: 206.04,121.94 206.61,121.94 UV1.AN33
FB_A_EDC7: length 1.2
  BOTTOM w0.102: v1(214.5,149.25) 214.1,148.85 UV7.C2
  BOTTOM w0.168: 213.32,121.05 213.3,121.05 UV1.AF33
FB_A_WCK0: length 1.4
  BOTTOM w0.102: 227.9,139.65 227.9,139.77 227.62,140.05 UV6.D4
  BOTTOM w0.119: UV1.K31 226.25,120.13 226.13,120.25 225.82,120.25
FB_A_WCK1: length 5.3
  BOTTOM w0.102: UV6.P4 v1(227.9,147.65)
  BOTTOM w0.109: 227.49,126.29 227.75,126.03 227.99,126.03 228.11,125.91 228.32,125.71 228.32,122.96 227.91,122.55 227.91,122.51 227.91,122.5 227.91,122.45 227.9,122.44 UV1.H34
FB_A_WCK2: length 1.2
  BOTTOM w0.102: UV7.P4 212.5,140.05 212.1,139.65
  BOTTOM w0.119: UV1.AG30 212.07,119.05 211.67,119.45
FB_A_WCK3: length 1.9
  BOTTOM w0.102: UV7.D4 v1(212.1,147.65)
  BOTTOM w0.119: 210.82,122.65 210.82,122.65 210.62,122.85 210.34,122.85 210.22,122.73 210.22,122.43 UV1.AJ34
FB_A_WCK#0: length 1.2
  BOTTOM w0.102: 228.7,139.65 UV6.D5
  BOTTOM w0.119: UV1.L30 225.43,119.05 225.82,119.45
FB_A_WCK#1: length 5.3
  BOTTOM w0.102: UV6.P5 v1(228.7,147.65)
  BOTTOM w0.109: 227.49,125.56 227.75,125.82 227.9,125.82 228.1,125.62 228.1,123.05 227.68,122.63 227.68,122.53 227.55,122.4 227.55,122.39 227.4,122.25 UV1.J34
FB_A_WCK#2: length 1.5
  BOTTOM w0.102: 211.3,139.65 211.58,139.65 211.7,139.77 UV7.P5
  BOTTOM w0.119: UV1.AG31 211.79,119.85 211.67,119.97 211.67,120.25
FB_A_WCK#3: length 2.8
  BOTTOM w0.102: v1(211.3,147.65) 211.58,147.65 211.75,147.82 211.75,148 UV7.D5
  BOTTOM w0.119: 210.82,123.38 210.82,123.2 210.71,123.08 210.25,123.08 209.99,122.82 209.99,122.37 209.87,122.25 UV1.AK34
FB_B_CLK0: length 2.1
  BOTTOM w0.102: UV8.J12 v1(256.4,96.6)
  BOTTOM w0.112: 242.64,96.59 242.85,96.38 242.85,96.11 RV599.1
  BOTTOM w0.119: UV1.D12 231.7,104.35 231.7,104.37
FB_B_CLK0#: length 2.1
  BOTTOM w0.102: 255.6,96.6 UV8.J11
  BOTTOM w0.112: 243.22,96.59 243.06,96.43 243.06,96.17 RV598.1
  BOTTOM w0.119: 230.9,104.37 230.5,103.97 UV1.E12
FB_B_CLK1: length 2.5
  BOTTOM w0.102: UV9.J12 256,123.9 v1(256.4,123.5)
  BOTTOM w0.112: RV601.1 241.82,119.91 241.18,119.91 241.04,119.78
  BOTTOM w0.119: 230.07,110.22 230.11,110.22 230.5,110.62 UV1.E20
FB_B_CLK1#: length 2.7
  BOTTOM w0.102: 255.6,123.5 256,123.1 UV9.J11
  BOTTOM w0.112: RV600.1 241.94,120.12 241.29,120.12 241.04,120.36
  BOTTOM w0.119: 229.22,110.22 229.52,110.22 229.65,110.35 UV1.F20
FB_B_CMD0: length 1.2
  BOTTOM w0.102: 254.8,96.6 UV8.G12
  BOTTOM w0.168: 230.9,105.22 230.9,105.2 UV1.D13
FB_B_CMD1: length 1.1
  BOTTOM w0.168: UV1.E14 230.1,106.05 230.07,106.05 ; UV8.H10 254.85,98.15 254.85,98.16
FB_B_CMD2: length 1.2
  BOTTOM w0.102: 255.6,97.4 UV8.H11
  BOTTOM w0.168: UV1.F14 229.25,106.05 229.22,106.05
FB_B_CMD3: length 27.9
  TOP w0.168: v1(256.41,97.39) 256.39,97.41 256.39,98.54 256.15,98.78 248.85,98.78 247.92,97.85 246.36,97.85 244.97,99.23 v2(241.54,99.23) 241.12,99.23 239.46,100.89 239.46,101.68 239.3,101.84
  BOTTOM w0.102: UV8.K11 v1(256.41,97.39)
  BOTTOM w0.168: 239.3,101.84 238.35,102.79 236.02,102.79 234.86,103.95 UV1.A12
FB_B_CMD4: length 28.4
  TOP w0.168: 240.6,101.95 240.6,101.31 v2(240.95,100.96) 242.01,99.9 245.23,99.9 246.59,98.53 248.22,98.53 248.77,99.08 250.98,99.08 256.28,99.08 256.66,98.71 256.66,98.5 v1(256.8,98.36)
  BOTTOM w0.102: UV8.K10 v1(256.8,98.36)
  BOTTOM w0.168: 240.6,101.95 240.6,101.93 239.87,101.19 237.24,101.19 234.88,103.55 233.3,103.55 UV1.B12
FB_B_CMD5: length 31.5
  TOP w0.168: v1(257.2,96.6) 257.35,96.75 257.35,98.84 256.84,99.35 248.62,99.35 248.45,99.18 246.86,99.18 245.49,100.55 v2(242.8,100.55) 242.52,100.55 241.81,101.26 241.81,101.93
  BOTTOM w0.102: v1(257.2,96.6) 257.6,96.2 UV8.L12
  BOTTOM w0.168: UV1.C14 232.5,105.25 233.01,105.25 234.04,104.22 234.97,104.22 235.75,103.44 240.32,103.44 241.81,101.95 241.81,101.93
FB_B_CMD6: length 28.1
  TOP w0.168: 243.64,101.99 245.89,101.99 247.38,100.51 248.61,100.51 249.21,99.9 255.36,99.9 v2(255.88,100.41) 256.39,100.92 256.39,102.19 v1(256.4,102.2)
  BOTTOM w0.102: UV8.K4 v1(256.4,102.2)
  BOTTOM w0.168: 243.64,101.99 241.53,104.11 235.46,104.11 235.08,104.49 234.31,104.49 233.15,105.65 UV1.B14
FB_B_CMD7: length 33
  TOP w0.102: 231.38,106.48 230.72,106.48 230.32,106.87 229.22,106.87
  TOP w0.168: v1(256.8,101.2) 256.8,100.77 255.66,99.63 248.65,99.63 248.43,99.84 247.12,99.84 245.76,101.2 243.19,101.2 242.47,101.92 242.47,102.38 242.06,102.79 239.51,102.79 236.91,105.39 v2(235.84,105.39) 234.32,105.39 233.9,105.82 233.38,105.82 232.72,106.48 231.38,106.48
  BOTTOM w0.102: UV8.K5 256.8,101.2 v1(256.8,101.2)
  BOTTOM w0.168: UV1.G15 229.22,106.87
FB_B_CMD8: length 1.4
  BOTTOM w0.102: 255.6,102.2 UV8.J4
  BOTTOM w0.168: 229.65,107.3 UV1.F15
FB_B_CMD9: length 1.2
  BOTTOM w0.102: UV8.J5 256,101.3 255.9,101.2
  BOTTOM w0.168: UV1.E15 230.9,106.85 230.9,106.87
FB_B_CMD10: length 14.3
  BOTTOM w0.102: 254.8,102.2 UV8.H4
  BOTTOM w0.168: UV1.D15 231.68,106.83 234.12,106.83 234.19,106.75 242.79,106.75 243.13,106.4 243.83,106.4 244.42,105.81
FB_B_CMD11: length 11.2
  BOTTOM w0.102: 255,101.2 255.2,101.4 UV8.H5
  BOTTOM w0.168: UV1.A14 234.59,104.76 242.73,104.76 243.26,105.28 243.26,105.69
FB_B_CMD12: length 1.9
  BOTTOM w0.102: 254.8,103.8 UV8.G3
  BOTTOM w0.168: UV1.D14 231.71,106.06 232.48,106.06
FB_B_CMD13: length 29.3
  TOP w0.168: 242.06,105.69 242.06,105.86 242.82,106.63 251.74,106.63 253.77,108.66 v2(254.11,108.66) 256.31,108.66 256.44,108.53 RV111.1 256.44,107.71 255.56,106.82 255.56,104.65 255.6,104.6
  BOTTOM w0.102: UV8.J2 256,104.2 255.6,104.6
  BOTTOM w0.168: 242.06,105.69 241.65,106.1 234.34,106.1 233.99,106.45 UV1.A15
FB_B_CMD14: length 33.5
  TOP w0.102: 257.18,106.73 257.18,106.49 257.2,106.47 257.2,105.25 256.4,104.46 v1(256.4,103.8)
  TOP w0.168: 240.84,105.45 240.84,106.07 242.06,107.29 251.38,107.29 253.52,109.42 v2(256.35,109.42) 257.2,109.42 257.46,109.16 RV96.2 257.46,107.89 257.18,107.61 257.18,106.73
  BOTTOM w0.102: UV8.J3 v1(256.4,103.8)
  BOTTOM w0.168: 240.84,105.45 240.8,105.41 234.47,105.41 233.83,106.05 233.41,106.05 233.02,106.45 UV1.B15
FB_B_CMD15: length 1.2
  BOTTOM w0.102: UV8.L3 v1(257.2,103.8)
  BOTTOM w0.168: UV1.C17 232.5,107.75 232.5,107.72
FB_B_CMD16: length 1.2
  BOTTOM w0.102: 254.8,123.5 254.4,123.9 UV9.L12
  BOTTOM w0.168: 231.7,109.37 231.3,108.97 UV1.D18
FB_B_CMD17: length 1.2
  BOTTOM w0.102: 255.57,121.82 255.57,121.93 UV9.K10
  BOTTOM w0.168: UV1.E18 230.87,109.32 230.87,109.37
FB_B_CMD18: length 1.2
  BOTTOM w0.102: 255.6,122.7 255.2,123.1 UV9.K11
  BOTTOM w0.168: UV1.F18 229.65,109 230.02,109.37 230.07,109.37
FB_B_CMD19: length 30.8
  TOP w0.168: v1(256.4,122.71) 255.99,122.3 255.99,121.65 255.75,121.41 248.54,121.41 248.42,121.53 246.45,121.53 242.76,117.84 242.76,115.25 v2(240.21,112.7) 239.3,111.79 239.3,111.5 239.47,111.34
  BOTTOM w0.102: UV9.H11 256.79,123.1 v1(256.4,122.71)
  BOTTOM w0.168: 239.47,111.34 235.73,111.34 235.04,110.65 UV1.A20
FB_B_CMD20: length 31.3
  TOP w0.168: v1(257.05,121.82) 257.05,121.49 256.7,121.14 248.99,121.14 248.38,120.52 246.37,120.52 243.41,117.57 243.41,114.97 v2(242.81,114.37) 240.14,111.69
  BOTTOM w0.102: v1(257.05,121.82) 256.8,122.07 UV9.H10
  BOTTOM w0.168: UV1.B20 233.3,111.05 235.06,111.05 236,111.99 239.84,111.99 240.14,111.69
FB_B_CMD21: length 35.3
  TOP w0.168: v1(257.2,123.5) 257.2,123.09 257.51,122.78 257.51,121.4 256.97,120.87 249.11,120.87 248.11,119.87 246.64,119.87 244.12,117.36 244.12,114.72 v2(242.06,112.65) 241.28,111.88 241.28,111.44
  BOTTOM w0.102: UV9.G12 v1(257.2,123.5)
  BOTTOM w0.168: 241.28,111.44 241.28,111.14 240.79,110.65 236.03,110.65 235.76,110.38 234.08,110.38 233.05,109.35 232.5,109.35 UV1.C18
FB_B_CMD22: length 33
  TOP w0.168: v1(256.4,117.9) 256.32,117.99 256.32,119.3 255.39,120.23 249.37,120.23 247.68,118.54 247.14,118.54 245.98,117.38 245.98,113.14 v2(245.05,112.2) 243.91,111.07
  BOTTOM w0.102: UV9.H4 256.8,117.5 v1(256.4,117.9)
  BOTTOM w0.168: UV1.B18 233.15,108.95 234.2,110 242.84,110 243.91,111.07
FB_B_CMD23: length 1.2
  BOTTOM w0.102: v1(256.75,118.9) 256.8,118.85 UV9.H5
  BOTTOM w0.168: 229.22,109.37 UV1.G18
FB_B_CMD24: length 1.2
  BOTTOM w0.102: 255.6,117.1 UV9.J4
  BOTTOM w0.168: 229.22,108.55 229.2,108.55 UV1.G17
FB_B_CMD25: length 1.2
  BOTTOM w0.102: UV9.J5 256,118.8 255.9,118.9
  BOTTOM w0.168: UV1.F17 229.67,108.15 230.07,108.55
FB_B_CMD26: length 1.2
  BOTTOM w0.102: 255.6,117.9 UV9.K4
  BOTTOM w0.168: UV1.D16 230.9,107.7 230.9,107.72
FB_B_CMD27: length 11.8
  BOTTOM w0.102: UV9.K5 255.2,118.75 255.05,118.9
  BOTTOM w0.168: UV1.A18 234.1,109.35 244.2,109.35 244.55,109
FB_B_CMD28: length 18.1
  BOTTOM w0.102: 254.8,117.1 UV9.L3
  BOTTOM w0.168: UV1.D17 231.68,108.53 233.93,108.53 234.1,108.7 243.6,108.7 243.94,108.35 246.51,108.35 247.63,109.47 247.63,109.8
FB_B_CMD29: length 29.9
  TOP w0.168: 248.9,109.8 248.9,110.7 249.27,111.07 255.71,111.07 256.34,111.71 RV110.1 255.86,112.83 v2(255.86,114.65) 255.86,115.24 255.6,115.5
  BOTTOM w0.102: 255.6,115.5 UV9.J2
  BOTTOM w0.168: UV1.A17 233.8,108.05 243.33,108.05 243.67,107.7 247.25,107.7 248.9,109.35 248.9,109.8
FB_B_CMD30: length 32.7
  TOP w0.168: 250.23,109.8 250.23,109.8 250.74,110.31 v2(254.78,110.31) 256.06,110.31 257.42,111.68 RV99.2 257.42,111.99 257.02,112.4 257.02,113.46 257.15,113.59 257.15,115.55 v1(256.4,116.3)
  BOTTOM w0.102: v1(256.4,116.3) 256,116.7 UV9.J3
  BOTTOM w0.168: UV1.B17 233.3,107.75 233.69,107.75 234.04,107.4 243.06,107.4 243.4,107.05 247.59,107.05 250.23,109.69 250.23,109.8
FB_B_CMD31: length 37.5
  TOP w0.168: 230.9,108.55 230.95,108.5 234.91,108.5 235.11,108.69 v2(235.88,108.69) 240.7,108.69 242.21,110.19 242.21,110.81 245.14,113.74 245.14,117.45 246.91,119.22 247.98,119.22 249.26,120.5 255.74,120.5 257.2,119.04 v1(257.2,117.1)
  BOTTOM w0.102: v1(257.2,117.1) 257.6,116.7 UV9.G3
  BOTTOM w0.168: 230.9,108.55 UV1.E17
FB_B_D0: length 1.2
  BOTTOM w0.102: 249.2,102.2 UV8.A4
  BOTTOM w0.168: UV1.G9 228.4,101.85 228.4,101.87
FB_B_D1: length 1.2
  BOTTOM w0.102: UV8.A2 249.6,104.2 249.2,104.6
  BOTTOM w0.168: 230.9,101.87 230.9,101.85 UV1.E9
FB_B_D2: length 1.1
  BOTTOM w0.102: 250,102.2 UV8.B4
  BOTTOM w0.168: UV1.G8 228.8,100.67 228.42,101.05
FB_B_D3: length 1.2
  BOTTOM w0.102: UV8.B2 250.4,104.2 250,104.6
  BOTTOM w0.168: UV1.F9 229.22,101.87
FB_B_D4: length 1.2
  BOTTOM w0.102: UV8.E4 252.8,102.6 252.4,103
  BOTTOM w0.168: 230.07,103.55 229.67,103.15 UV1.F11
FB_B_D5: length 1.2
  BOTTOM w0.102: 252.4,104.6 252.8,104.2 UV8.E2
  BOTTOM w0.168: 229.22,103.55 229.2,103.55 UV1.G11
FB_B_D6: length 1.2
  BOTTOM w0.102: 253.2,103 253.6,102.6 UV8.F4
  BOTTOM w0.168: 230.07,104.37 UV1.F12
FB_B_D7: length 1.2
  BOTTOM w0.102: 254,103.8 UV8.F2
  BOTTOM w0.168: UV1.G12 229.22,104.37
FB_B_D8: length 1.2
  BOTTOM w0.102: UV8.A11 249.6,97 249.2,97.4
  BOTTOM w0.168: 229.17,99.32 UV1.G6
FB_B_D9: length 1.2
  BOTTOM w0.102: 249.2,95 UV8.A13
  BOTTOM w0.168: 230.07,98.45 229.67,98.05 UV1.F5
FB_B_D10: length 1.2
  BOTTOM w0.102: 250,96.6 UV8.B11
  BOTTOM w0.168: 230.92,98.52 UV1.E6
FB_B_D11: length 1.1
  BOTTOM w0.102: 250,95 UV8.B13
  BOTTOM w0.168: 229.24,98.49 229.24,98.49 UV1.F6
FB_B_D12: length 1.1
  BOTTOM w0.102: 252.4,96.6 UV8.E11
  BOTTOM w0.168: 229.98,96.87 UV1.F4
FB_B_D13: length 1.1
  BOTTOM w0.102: UV8.E13 253.2,95.8
  BOTTOM w0.168: UV1.G4 229.09,96.91 229.17,96.91
FB_B_D14: length 1.2
  BOTTOM w0.102: UV8.F11 253.2,96.6
  BOTTOM w0.168: 230.84,95.21 UV1.E2
FB_B_D15: length 1.1
  BOTTOM w0.102: 253.2,95 UV8.F13
  BOTTOM w0.168: 230,96.05 UV1.F3
FB_B_D16: length 3.8
  BOTTOM w0.102: UV8.U11 v1(262,97.4)
  BOTTOM w0.168: UV1.C2 232.5,95.25 232.5,94.6 232.75,94.35 233.46,94.35 234.16,93.65
FB_B_D17: length 1.2
  BOTTOM w0.102: UV8.U13 v1(262,95)
  BOTTOM w0.168: 230.81,96.88 231.17,97.25 UV1.D4
FB_B_D18: length 1.9
  BOTTOM w0.102: UV8.T11 261.6,97 v1(262,96.6)
  BOTTOM w0.168: 231.69,95.29 231.69,96.01 UV1.D3
FB_B_D19: length 1.9
  BOTTOM w0.102: UV8.T13 v1(261.2,95)
  BOTTOM w0.168: 232.42,93.62 232.1,93.94 UV1.C1
FB_B_D20: length 2.7
  BOTTOM w0.102: UV8.N11 259.2,97 v1(259.6,96.6)
  BOTTOM w0.168: UV1.B3 233.3,96.05 234.02,96.05 234.17,95.89 234.17,95.25
FB_B_D21: length 1.1
  BOTTOM w0.102: UV8.N13 v1(258.8,95)
  BOTTOM w0.168: 232.49,96.89 232.49,96.91 UV1.C4
FB_B_D22: length 3.6
  BOTTOM w0.102: UV8.M11 258.4,97 v1(258.8,96.6)
  BOTTOM w0.168: 235.4,96.87 234.67,97.6 233.7,97.6 233.15,98.15 UV1.B5
FB_B_D23: length 3.1
  BOTTOM w0.102: UV8.M13 v1(258,95.8)
  BOTTOM w0.168: 234.12,96.87 234.1,96.87 233.66,97.31 233.58,97.31 233.14,97.75 232.5,97.75 UV1.C5
FB_B_D24: length 1.7
  BOTTOM w0.102: UV8.U4 v1(262,103)
  BOTTOM w0.168: 234.7,102.72 234.43,102.99 234.27,103.15 UV1.A11
FB_B_D25: length 1.2
  BOTTOM w0.102: v1(262,104.6) UV8.U2
  BOTTOM w0.168: UV1.C11 231.9,102.95 231.9,102.92 231.7,102.72
FB_B_D26: length 1.1
  BOTTOM w0.102: v1(262,102.2) 261.6,102.6 UV8.T4
  BOTTOM w0.168: 230.9,103.55 UV1.D11
FB_B_D27: length 1.2
  BOTTOM w0.102: UV8.T2 v1(261.2,104.6)
  BOTTOM w0.168: 233.3,102.72 232.9,103.13 UV1.B11
FB_B_D28: length 5.6
  BOTTOM w0.102: UV8.N4 259.2,102.6 v1(258.8,103)
  BOTTOM w0.168: UV1.D8 231.7,100.25 235.05,100.25 235.85,101.05
FB_B_D29: length 3.1
  BOTTOM w0.102: 235.29,101.87 235.25,101.87 234.84,101.46 234.84,100.84 234.65,100.65 234.65,100.65 234.62,100.63 233.72,100.63 UV1.A8 ; UV8.N2 v1(258.8,103.8)
FB_B_D30: length 1.1
  BOTTOM w0.102: UV8.M4 v1(258,102.2)
  BOTTOM w0.168: 232.5,101.05 UV1.C8
FB_B_D31: length 2.3
  BOTTOM w0.102: v1(258,104.6) 258.4,104.2 UV8.M2
  BOTTOM w0.168: 234.45,101.05 233.3,101.05 UV1.B8
FB_B_D32: length 1.1
  BOTTOM w0.102: 249.2,117.9 249.59,117.5 UV9.U4
  BOTTOM w0.168: 229.42,114.42 229.43,114.4 229.43,114.39 229.52,114.29 229.52,114.08 UV1.F24
FB_B_D33: length 1.2
  BOTTOM w0.102: 249.2,115.51 249.59,115.9 UV9.U2
  BOTTOM w0.168: UV1.G23 229.2,112.75 229.2,112.72
FB_B_D34: length 1.2
  BOTTOM w0.102: 250,117.9 250.4,117.5 UV9.T4
  BOTTOM w0.168: 230.07,114.37 UV1.E24
FB_B_D35: length 1.9
  BOTTOM w0.102: 250,116.3 250.4,115.9 UV9.T2
  BOTTOM w0.168: UV1.G24 228.4,113.55 228.4,112.75
FB_B_D36: length 1.2
  BOTTOM w0.102: UV9.N4 252.4,117.1
  BOTTOM w0.168: UV1.D21 231.3,111.47 231.7,111.87
FB_B_D37: length 1.2
  BOTTOM w0.102: 252.4,115.5 UV9.N2
  BOTTOM w0.168: 230.07,111.87 UV1.E21
FB_B_D38: length 2
  BOTTOM w0.102: 253.2,117.1 UV9.M4
  BOTTOM w0.168: UV1.G21 228.4,111.05 228.4,110.22
FB_B_D39: length 1.1
  BOTTOM w0.102: 253.2,115.5 UV9.M2
  BOTTOM w0.168: 229.25,111.85 UV1.F21
FB_B_D40: length 1.2
  BOTTOM w0.102: 249.2,122.7 UV9.U11
  BOTTOM w0.168: 229.22,116.05 229.2,116.05 UV1.G27
FB_B_D41: length 1.1
  BOTTOM w0.102: 249.2,125.1 249.6,124.7 UV9.U13
  BOTTOM w0.168: 230.9,116.85 UV1.D27
FB_B_D42: length 1.1
  BOTTOM w0.102: UV9.T11 250.4,123.1 250,123.5
  BOTTOM w0.168: 228.4,116.05 UV1.G26
FB_B_D43: length 1.3
  BOTTOM w0.102: 250,125.1 250.4,124.7 UV9.T13
  BOTTOM w0.168: UV1.E27 230.5,116.51 230.06,116.95
FB_B_D44: length 1.2
  BOTTOM w0.102: UV9.N11 252.8,123.1 252.4,123.5
  BOTTOM w0.168: UV1.E29 230.1,117.75 229.99,117.75
FB_B_D45: length 1.2
  BOTTOM w0.102: 253.2,125.1 UV9.N13
  BOTTOM w0.168: 230.07,118.62 UV1.F29
FB_B_D46: length 1.2
  BOTTOM w0.102: UV9.M11 253.6,123.1 253.2,123.5
  BOTTOM w0.168: 230.85,119.59 230.5,119.24 UV1.E30
FB_B_D47: length 1.2
  BOTTOM w0.102: 253.2,124.3 UV9.M13
  BOTTOM w0.168: UV1.D30 231.7,119.35 231.7,119.37
FB_B_D48: length 1.3
  BOTTOM w0.102: UV9.A11 v1(262,123.5)
  BOTTOM w0.168: 234.26,120.88 234.25,120.87 234.25,120.82 234.08,120.65 UV1.A32
FB_B_D49: length 1.2
  BOTTOM w0.102: UV9.A13 v1(262,125.1)
  BOTTOM w0.168: UV1.C31 232.5,120.2 232.5,120.22
FB_B_D50: length 1.1
  BOTTOM w0.102: UV9.B11 261.6,123.1 v1(262,122.7)
  BOTTOM w0.168: 232.5,121.05 UV1.C32
FB_B_D51: length 3.1
  BOTTOM w0.102: UV9.B13 v1(261.2,125.1)
  BOTTOM w0.168: 234.9,121.85 234.8,121.85 234.32,121.37 234.16,121.37 233.85,121.06 233.31,121.06 UV1.B32
FB_B_D52: length 1.1
  BOTTOM w0.102: v1(259.6,123.5) UV9.E11
  BOTTOM w0.168: 231.7,118.55 UV1.D29
FB_B_D53: length 1.7
  BOTTOM w0.102: 234.7,118.55 234.3,118.15 UV1.A29 ; UV9.E13 v1(258.8,124.3)
FB_B_D54: length 1.2
  BOTTOM w0.102: UV9.F11 v1(258.8,123.5)
  BOTTOM w0.168: 232.5,117.72 232.5,117.75 UV1.C29
FB_B_D55: length 1.1
  BOTTOM w0.102: UV9.F13 258.4,124.7 v1(258,125.1)
  BOTTOM w0.168: 233.3,118.55 UV1.B29
FB_B_D56: length 2
  BOTTOM w0.102: UV9.A4 v1(262.8,117.9)
  BOTTOM w0.168: 234.1,111.87 234.05,111.92 233.62,111.92 233.15,111.45 UV1.B21
FB_B_D57: length 1.3
  BOTTOM w0.102: UV9.A2 v1(262.8,116.3)
  BOTTOM w0.168: UV1.C23 232.28,113.15 232.5,112.93 232.5,112.72
FB_B_D58: length 2.3
  BOTTOM w0.102: UV9.B4 261.6,117.5 v1(262,117.1)
  BOTTOM w0.168: UV1.A21 234.87,111.45 235.3,111.87
FB_B_D59: length 3.7
  BOTTOM w0.102: UV9.B2 261.6,115.9 v1(262,115.5)
  BOTTOM w0.168: 234.7,112.72 234.28,112.3 233.55,112.3 233.1,111.85 232.5,111.85 UV1.C21
FB_B_D60: length 1.3
  BOTTOM w0.102: UV9.E4 v1(258.8,117.1)
  BOTTOM w0.168: UV1.B24 233.07,113.95 233.3,114.18 233.3,114.37
FB_B_D61: length 5
  BOTTOM w0.102: UV9.E2 v1(258.8,115.5)
  BOTTOM w0.168: UV1.C24 232.5,113.55 235.22,113.55 235.9,114.23 235.9,114.37
FB_B_D62: length 4.5
  BOTTOM w0.102: v1(258,117.9) 258.4,117.5 UV9.F4
  BOTTOM w0.168: UV1.B26 233.05,115.65 233.44,115.26 234.06,115.26 234.72,115.92 235.58,115.92 236.13,115.38
FB_B_D63: length 3.9
  BOTTOM w0.102: UV9.F2 258.4,115.9 v1(258,116.3)
  BOTTOM w0.168: UV1.C26 232.5,115.25 233.04,115.25 233.48,114.82 234.34,114.82 234.9,115.38
FB_B_DBI0: length 1.2
  BOTTOM w0.102: 251.6,104.6 252,104.2 UV8.D2
  BOTTOM w0.168: 230.07,102.72 UV1.E11
FB_B_DBI1: length 1.2
  BOTTOM w0.102: 251.6,95 UV8.D13
  BOTTOM w0.168: 230.83,96.02 UV1.E3
FB_B_DBI2: length 3
  BOTTOM w0.102: UV8.P13 v1(259.6,95)
  BOTTOM w0.168: UV1.A3 234.2,96.45 234.66,95.99 235.1,95.99 235.26,95.82 235.26,95.39 235.4,95.25
FB_B_DBI3: length 1.2
  BOTTOM w0.102: UV8.P2 v1(259.6,104.6)
  BOTTOM w0.168: UV1.C9 231.67,101.87
FB_B_DBI4: length 1.2
  BOTTOM w0.102: UV9.P2 252,115.9 251.6,116.3
  BOTTOM w0.168: 230.07,112.72 UV1.F23
FB_B_DBI5: length 1.2
  BOTTOM w0.102: UV9.P13 252,124.7 251.6,125.1
  BOTTOM w0.168: 229.22,116.87 UV1.F27
FB_B_DBI6: length 1.2
  BOTTOM w0.102: UV9.D13 260,124.7 v1(259.6,125.1)
  BOTTOM w0.168: 232.5,119.37 232.1,118.97 UV1.C30
FB_B_DBI7: length 1.8
  BOTTOM w0.102: UV9.D2 260,115.9 v1(259.6,116.3)
  BOTTOM w0.168: 234.7,114.37 234.7,114.34 234.31,113.95 UV1.A24
FB_B_EDC0: length 1.2
  BOTTOM w0.102: 250.8,103.8 251.2,104.2 UV8.C2
  BOTTOM w0.168: 230.87,102.72 UV1.D10
FB_B_EDC1: length 2
  BOTTOM w0.102: 250.8,95.8 251.2,95.4 UV8.C13
  BOTTOM w0.168: 231.7,96.88 231.7,97.75 UV1.D5
FB_B_EDC2: length 1.1
  BOTTOM w0.102: UV8.R13 v1(260.4,95.8)
  BOTTOM w0.168: 232.5,96.05 UV1.C3
FB_B_EDC3: length 1.2
  BOTTOM w0.102: UV8.R2 v1(260.4,103.8)
  BOTTOM w0.168: 233.3,101.87 232.9,101.47 UV1.B9
FB_B_EDC4: length 1.2
  BOTTOM w0.102: 250.8,115.5 UV9.R2
  BOTTOM w0.168: UV1.E23 230.9,112.75 230.9,112.72
FB_B_EDC5: length 1.2
  BOTTOM w0.102: 250.8,124.3 UV9.R13
  BOTTOM w0.168: UV1.E28 230.9,117.7 230.9,117.72
FB_B_EDC6: length 3
  BOTTOM w0.102: v1(260.4,124.3) UV9.C13
  BOTTOM w0.168: UV1.B30 233.3,119.35 234.25,119.35 234.75,119.85 234.75,120.05
FB_B_EDC7: length 2.9
  BOTTOM w0.102: UV9.C2 v1(260.4,115.5)
  BOTTOM w0.168: UV1.A23 235.47,113.15 235.9,112.72
FB_B_WCK0: length 1.2
  BOTTOM w0.102: 251.6,102.2 UV8.D4
  BOTTOM w0.119: UV1.F8 229.67,100.65 230.07,101.05
FB_B_WCK1: length 2.5
  BOTTOM w0.102: v1(259.6,102.2) UV8.P4
  BOTTOM w0.119: UV1.A5 233.82,98.27 234.17,98.27 234.64,98.74 234.64,99.19 234.83,99.37
FB_B_WCK2: length 1.2
  BOTTOM w0.102: UV9.P4 252,117.5 251.6,117.9
  BOTTOM w0.119: 230.9,114.37 231.3,113.97 UV1.D24
FB_B_WCK3: length 1.1
  BOTTOM w0.102: UV9.D4 v1(259.6,117.9)
  BOTTOM w0.119: 233.3,116.05 UV1.B27
FB_B_WCK#0: length 1.7
  BOTTOM w0.102: 251.6,101.4 251.52,101.48 251.52,101.62 251.75,101.85 251.95,101.85 UV8.D5
  BOTTOM w0.119: 230.9,101.05 230.82,101.13 230.65,101.13 230.44,100.92 230.44,100.71 UV1.E8
FB_B_WCK#1: length 2.5
  BOTTOM w0.102: UV8.P5 v1(259.6,101.4)
  BOTTOM w0.119: 234.1,99.37 234.21,99.37 234.42,99.16 234.42,98.84 234.07,98.49 233.86,98.49 233.7,98.65 UV1.A6
FB_B_WCK#2: length 1.7
  BOTTOM w0.102: UV9.P5 251.97,118.27 251.68,118.27 251.54,118.41 251.54,118.74
  BOTTOM w0.119: UV1.D25 231.28,114.78 231.28,114.46 231.42,114.32 231.64,114.32 231.7,114.37
FB_B_WCK#3: length 1.1
  BOTTOM w0.102: UV9.D5 260,118.3 v1(259.6,118.7)
  BOTTOM w0.119: 232.5,116.05 UV1.C27
FB_VCCIO: length 4.7
  TOP w0.102: v2(48.65,120.6) 48.49,120.43 v1(48.49,119.38)
  BOTTOM w0.254: PU901.14 48.3,119.2 v1(48.49,119.38) 49,119.89 PC912.2 PR909.2 PR910.1
FB_VCCIO_SENSE: length 4.1
  BOTTOM w0.102: v2(49.95,122.63) 49.81,122.49 48.58,122.49 PR911.1
  BOTTOM w0.254: PR909.1 48.17,121.74 PR908.2 48.11,121.8 PR911.1
FBVDD/Q_EN: length 7.1
  TOP w0.102: v1(264.43,72.82) 263.83,72.82 v2(263.82,72.81)
  BOTTOM w0.254: v1(264.43,72.82) 264.48,72.77 PRW06.1 ; QG506.2 245,83.92 243.72,82.63 v1(243.72,82.2) 243.32,81.8 RG557.1 242.86,81.86 UG27.4
FBVDDQ_SENSE: length 3.4
  TOP w0.127: v3(266.05,64.71) 266.05,65.38 v1(266.43,65.76)
  BOTTOM w0.254: PRW19.2 v1(266.43,65.76) ; 229.92,93.53 229.92,94.53 UV1.F1
FFS_INT1: length 15.4
  TOP w0.102: v1(182.8,43.97) 182.8,43.97 183.32,44.5 184.94,44.5 185.13,44.69 187.27,44.69 187.81,45.22 187.81,45.75 188.24,46.19 190.44,46.19 190.93,46.68 192.43,46.68 192.87,47.13 v2(192.87,47.31) RH728.2 192.87,49.37 193.26,49.76 US1.12
  BOTTOM w0.102: v1(182.8,43.97) 182.8,43.67 UH1.AW26
FFS_INT2: length 4.3
  TOP w0.102: QS1.2 274.09,40.42 v1(274.24,40.57) ; RH680.2 185.57,46.72 185.74,46.55 v2(185.78,46.55) 186.14,46.55 186.4,46.81 v1(186.4,47.47) ; US1.11 192.95,50.26 v1(192.93,50.24)
  BOTTOM w0.102: UH1.BF18 186.32,47.39 v1(186.4,47.47)
FFS_INT2_Q: length 4
  TOP w0.102: v2(273.38,38.47) 273.53,38.31 v1(274.3,38.31) 274.3,38.72 RS4.2 274.74,39.17 QS1.3
  BOTTOM w0.102: v1(274.3,38.31) 273.73,37.75 JHDD.9
FPR_SCAN#: length 9.5
  TOP w0.102: RE85.2 69.13,38.89 RE156.1 68.36,38.12 67.5,38.12 v3(67.19,37.81) 66.56,37.19 66.56,35.52 v1(66.13,35.1)
  BOTTOM w0.102: v1(244.38,34.53) 244.74,34.9 RF1.1 245.94,34.28 245.85,34.19 JFP.2
GC6_EVENT#_D: length 11.6
  BOTTOM w0.109: UV1.L6 225.81,98.49 225.81,95.24 226.63,94.42 226.63,92.01 v2(226.33,91.71) 225.74,91.12 RV42.1 226.2,90.32 226.2,88.84 DV9.2
GC6_THM_DIS#: length 8.9
  TOP w0.102: UE1.23 80.29,44.51 80.85,43.95 81.39,43.95 81.81,43.52 81.81,42.71 83.32,41.2 v1(83.32,40.86) ; v1(184.17,40.71) 184.17,40.98 184.7,41.51 RH573.1 185.84,41.51 v2(185.94,41.41)
  BOTTOM w0.089: UH1.BC33 184.51,40.2 184.17,40.53 v1(184.17,40.71)
GPD_7: length 6.5
  BOTTOM w0.089: UH1.BE41 185.6,36.43 188.22,36.43
  BOTTOM w0.102: RH12.2 190.95,35.91 190.75,35.72 190.01,35.72 189.75,35.98 RH705.1 189.34,36.56 188.35,36.56 188.22,36.43
GPP_H12: length 1.9
  TOP w0.102: v2(173.65,34.33) 173.91,34.06 v1(173.91,33.76) 173.54,33.38 RH727.1
  BOTTOM w0.102: v1(173.91,33.76) 174.01,33.66 UH1.AB47
GPP_H15: length 2.1
  TOP w0.102: RH726.1 174.96,33.62 v1(175.09,33.75) 175.4,34.06 v2(175.4,34.31)
  BOTTOM w0.102: UH1.AC47 174.78,33.44 v1(175.09,33.75)
GPP_J9: length 2.9
  TOP w0.102: RH93.1 181.74,50.67 v1(181.62,50.79) 181.06,50.79 v2(180.68,51.17)
  BOTTOM w0.089: UH1.AU9 v1(181.62,50.79)
GPPJ_RCOMP_1P8: length 8.3
  BOTTOM w0.102: v2(189.32,60.88) 189.56,60.64 189.56,59.43 RH666.1
  BOTTOM w0.254: UH1.BE2 185.16,55.61 UH1.BD1 UH1.BE1 185.66,56.03 185.84,56.21 186.22,56.21 188.44,58.43 188.86,58.43 189.1,58.67 RH666.1
GPU_EVENT#: length 3.3
  TOP w0.102: v2(224.75,86.03) 224.21,86.57 v1(224.21,86.59)
  BOTTOM w0.102: DV9.1 225.49,86.42 224.37,86.42 v1(224.21,86.59) ; v1(183.91,42.92) 184.07,43.09 UH1.BB26
GPU_GC6_FB_EN: length 12.2
  TOP w0.102: v1(224.7,92.3) 225.39,91.61 v3(225.39,91.16)
  BOTTOM w0.102: UV1.M3 224.97,96.07 224.97,94.59 ; QV10.5 222.68,87.54 222.5,87.72 222.5,87.95 222.33,88.12 222.33,88.92 222.89,89.48 222.89,89.67 223.08,89.86 223.51,89.86 223.74,90.09 223.74,90.87 RV37.1 224.2,91.57 224.7,92.07 v1(224.7,92.3)
  BOTTOM w0.109: v1(224.7,92.3) 224.97,92.58 224.97,94.59
GPU_GC6_FB_EN_H: length 32.3
  TOP w0.102: v1(242.47,86.82) 241.76,87.53 241.76,88.58 240.92,89.42 236.2,89.42 233.25,86.47 226.61,86.47 226.01,87.07 226.01,89.36 225.73,89.64 224.64,89.64 RG51.2 224.32,88.93 v1(223.62,88.23)
  BOTTOM w0.089: 187.34,42.03 187.08,41.78 186.16,41.78 186.02,41.92 UH1.BF29
  BOTTOM w0.102: v1(223.62,88.23) 222.96,88.23 QV10.6 ; 187.34,42.03 187.98,42.67 188.22,42.67 188.97,43.42 v1(188.97,43.5) ; UG27.1 241.56,86.19 RG553.1 241.99,86.34 v1(242.47,86.82)
GPU_HPD_RT: length 14.2
  TOP w0.102: RP45.2 28.03,88.09 28.03,85.76 27.65,85.38 v1(26.7,85.38)
  BOTTOM w0.102: UV20.1 210.44,89.42 209.93,88.91 v1(209.93,88.68) 209.93,87.98 209.82,87.87 RG575.2 ; v1(26.7,85.38) 26.26,84.95 26.26,83.48 27.13,82.61 27.13,82.16 28.21,81.08 28.93,81.08 29.13,80.88 30.09,80.88 v1(30.13,80.92)
GPU_ID1: length 16
  BOTTOM w0.076: UH1.AW18 182.44,47.66 182.44,48.24 182.73,48.52 184.17,48.52 184.49,48.2 184.84,48.2 184.95,48.26 185.05,48.37 185.05,48.68 185.19,48.82 185.34,48.82 185.89,49.37 186.43,49.37 187.22,50.15
  BOTTOM w0.102: RH551.2 193.03,54.96 v2(192.86,55.13) 192.13,55.13 191.25,54.25 RH552.1 191.02,54.18 189.26,52.41 188.85,52.41 188.01,51.57 188.01,51 187.9,50.88 187.9,50.83 187.22,50.15
GPU_ID2: length 3.4
  TOP w0.102: RH554.1 183.45,47.85 RH553.2 183.27,47.87 v1(182.39,46.99) 182.39,46.99 181.94,46.53 v2(181.8,46.53)
  BOTTOM w0.102: v1(182.39,46.99) 182.15,46.99 UH1.AV18
GPU_JTAG_TCK: length 4.4
  BOTTOM w0.102: UV1.AM10 207.9,101.98 207.74,101.82
  BOTTOM w0.109: 207.74,101.82 207.47,101.55 207.47,101.29 207.26,101.07 207.22,101.07 207.19,101.05 204.83,101.05 T98.1
GPU_JTAG_TDI: length 4.5
  BOTTOM w0.102: UV1.AM11 207.89,103.15 207.46,102.72 207.46,102.11 207.18,101.83 204.9,101.83 T99.1
GPU_JTAG_TDO: length 2.7
  BOTTOM w0.109: UV1.AP12 205.95,103.95 205.83,103.83 203.96,103.83 203.95,103.83 T100.1
GPU_JTAG_TMS: length 4.2
  BOTTOM w0.109: UV1.AP11 206.15,103.3 202.69,103.3 T101.1
GPU_JTAG_TRST#: length 3.9
  BOTTOM w0.109: UV1.AN11 206.68,102.73 203.62,102.73 RV63.1
GPU_PEX_RST_HOLD#: length 4.1
  BOTTOM w0.102: RV41.1 201.8,97.38 202.03,97.61 203.04,97.61 204.3,96.35
  BOTTOM w0.109: 221.68,100.16 221.3,100.55 UV1.T8
GPU_PWR_EN: length 4.8
  TOP w0.102: v1(204.97,90.25) v2(204.43,90.8)
  BOTTOM w0.102: UG25.2 199.2,118.14 RG551.2 199.16,117.45 198.85,117.13 ; UG31.1 204.55,89.12 204.97,89.54 v1(204.97,90.25)
GPU_PWR_LEVEL: length 32.3
  TOP w0.102: v1(107.79,46.15) 107.83,46.1 107.83,46.03 107.83,46.03 107.83,45.84 v2(107.4,45.41) ; v1(85.24,42.76) 85.24,42.76 85.23,42.78 85.23,43.87 85.49,44.14 UE1.10
  BOTTOM w0.102: DV11.1 221.91,90.77 v1(222.27,90.4) ; v1(107.79,46.15) 107.73,46.2 106.1,46.2 102.9,43.01 102.23,43.01 100.36,44.88 98.31,44.88 95.97,47.22 93.66,47.22 91.32,44.88 86.77,44.88 85.23,43.33 85.23,42.78 85.24,42.76 v1(85.24,42.76)
GPU_THM_SMBCLK: length 10.1
  TOP w0.102: v1(84.02,42.77) 84.03,42.79 84.03,43.74 84.69,44.41 UE1.12 84.69,46.99 RE11.1 ; v1(198.54,57.03) 198.44,57.13 Q11.3
  BOTTOM w0.089: 187.31,42.98 186.06,42.98 UH1.BF27
  BOTTOM w0.102: 187.31,42.98 187.84,42.98 v1(188.37,43.5) ; v1(220.56,87.72) 220.98,88.14 QV1.3
GPU_THM_SMBDAT: length 10.7
  TOP w0.102: v1(84.63,42.76) 84.64,42.77 84.64,43.23 84.64,43.87 85.09,44.33 UE1.11 85.09,46.61 RE10.1 ; v1(199.6,57.06) 199.74,56.92 Q11.6 ; v3(219.19,86.63) 219.19,87.24 v1(218.9,87.54)
  BOTTOM w0.089: UH1.BE27 185.78,43.21 187.34,43.21
  BOTTOM w0.102: 187.34,43.21 187.49,43.21 v1(187.78,43.5) ; v1(218.9,87.54) 219.53,86.9 QV1.6
GSYNC_ID: length 10.6
  BOTTOM w0.076: UH1.BE17 185.76,48.35 186.08,48.35 186.21,48.48 186.55,48.48 187.07,49
  BOTTOM w0.102: RH29.1 192.62,52.25 191.4,52.25 191.25,52.4 RH30.1 190.23,52.65 189.53,51.96 189.53,51.86 v2(189.38,51.71) 189.08,51.41 189.08,50.75 188.77,50.44 188.05,50.44 187.07,49.47 187.07,49
GT_SW1: length 2.9
  TOP w0.127: v1(56.64,144.3) v2(56.64,142.47)
  TOP w0.508: PRG04.1 v1(56.64,144.3)
H_CPUPWRGD: length 5.1
  TOP w0.102: v1(174.6,57.76) v3(175.27,57.76)
  BOTTOM w0.076: v1(61.42,122.15) 61.58,122.31 UC1.BT31
  BOTTOM w0.089: 174.84,56.57 175.47,55.95 175.47,54.98 UH1.AE3
  BOTTOM w0.102: 174.84,56.57 174.6,56.81 v1(174.6,57.76)
H_DRAMRST#: length 5.8
  TOP w0.102: v1(87.33,60.83) v2(86.48,59.97) 85.86,59.35 RD7.2 RD8.1
  BOTTOM w0.102: v1(183.99,31.7) 184,31.71 184,32.84 UH1.BB46
H_PECI: length 3.9
  TOP w0.102: UE1.94 88.29,28.73 88.67,28.35 88.67,28.04 v2(88.88,27.83) 89.47,27.24 89.87,27.24 RE23.1
H_PLTRST_CPU#: length 95.9
  TOP w0.102: v1(176.34,53.92) 176.34,52.45 172.81,48.92 171.27,48.92 170.92,49.27 170.92,49.63 170.62,49.93 168.24,49.93 168.03,50.15 165.75,50.15 165.6,50.3 153.82,50.3 152.9,51.22 152.63,51.22 150,53.85 v2(146.03,53.85) 142.08,53.85 140.34,55.59 134.09,55.59 132.17,57.51 132.17,57.98 127,63.15 125.37,63.15 122.93,65.59 122.44,65.59 113.28,74.76 113.28,75.88 108.75,80.41 108.75,81.13 108.32,81.56 107.69,81.56 107.49,81.77 107.49,82.56 107.76,82.83 v1(108.14,82.83)
  BOTTOM w0.089: v1(176.34,53.92) 176.4,53.86 UH1.AG5
  BOTTOM w0.102: v1(57.84,123.47) 57.84,123.91 58.23,124.31 59.5,124.31 60.58,125.38 61.64,125.38 61.99,125.04 62.58,125.04 62.64,124.98 63.1,124.98 UC1.BP35
H_PM_DOWN: length 104.1
  TOP w0.102: v1(60.98,109.64) 60.98,110.14 59.28,111.83 59.28,115.19 58.48,115.99 58.48,117.89 59.3,118.7 v2(59.3,119.48) 59.3,120 58.21,121.09 v1(57.25,121.09)
  BOTTOM w0.089: 175.2,56.57 175.73,56.04 UH1.AE2
  BOTTOM w0.102: v1(57.25,121.09) 57.75,121.09 RC22.1 ; v1(110.83,91.08) 110.21,91.08 109.54,90.4 109.54,88.12 112.18,85.47 112.18,83.94 121.87,74.25 121.87,71.88 122.85,70.9 125.48,70.9 134.33,64.7 137.12,61.91 139.45,61.91 140.09,61.28 141.49,61.28 142.34,60.43 144.12,60.43 145.23,59.32 160.24,59.32 167.88,61.58 173.54,61.58 174.58,60.55 RH14.2 175.04,59.4 175.04,56.73 175.2,56.57
H_PM_DOWN_R: length 6.6
  TOP w0.102: v2(59.33,122.31) 59.92,121.73 v1(59.92,121.44)
  BOTTOM w0.076: UC1.BP31 63.04,122.68 61.16,122.68 v1(59.92,121.44) 59.46,120.98 58.9,120.98
  BOTTOM w0.102: RC22.2 58.9,120.98
H_PM_SYNC_PCH: length 4.8
  BOTTOM w0.089: UH1.AF3 176.39,54.77 175.95,55.21 175.95,56.2 175.58,56.57
  BOTTOM w0.102: 175.58,56.57 175.27,56.89 175.27,58.72 RH13.1
H_PM_SYNC_R: length 83
  TOP w0.102: v3(109.68,90.21) 110.18,90.21 v1(110.5,90.53)
  BOTTOM w0.076: UC1.BM34 v1(64.36,124.3)
  BOTTOM w0.102: RH13.2 175.1,60.26 175.1,60.72 173.75,62.07 167.8,62.07 160.16,59.81 145.43,59.81 144.32,60.91 142.54,60.91 141.69,61.76 140.29,61.76 139.65,62.39 137.49,62.39 135.09,64.8 127.67,69.99 121.44,76.22 120.58,76.22 112.67,84.14 112.67,85.67 110.02,88.32 110.02,90.05 v1(110.5,90.53)
H_PROCHOT#: length 36.4
  TOP w0.102: v1(22.11,116.97) 21.35,116.21 PQS10.3 ; v1(67.63,36.7) 67.93,36.39 67.93,34.89 CE26.1 69.48,34.14 UE2.4 ; v2(61.38,48.69) 61.34,48.66 v1(61.34,47.16)
  TOP w0.254: v1(274.53,59.42) 274.53,59.77 274.62,59.86 PQ11.1 ; v1(272.87,54.93) PRB19.1
  BOTTOM w0.102: RC268.1 v1(65.2,128.45) ; PQ12.3 v1(47.63,126.32) ; RC262.2 56.48,121.75 v1(56.79,122.06) ; v1(61.34,47.16) 62.01,46.49 63.79,46.49 64.25,46.04 65.8,46.04 66.6,45.23 66.6,42.89 66.83,42.66 66.83,41.39 66.05,40.61 66.05,37.69 66.35,37.4 66.92,37.4 v1(67.63,36.7)
  BOTTOM w0.254: v1(272.87,54.93) 272.26,55.54 272.26,56.34 274.53,58.61 v1(274.53,59.42) ; PRZ20.2 112.7,141.24 113.35,141.9 v1(113.35,143.1) 113.75,143.5 PRZ24.2
H_PROCHOT#_R: length 3.6
  TOP w0.102: v1(63.02,121.95) 63.02,121.5 v2(63.26,121.26) 63.78,120.74 CH211.1
  BOTTOM w0.102: v1(65.81,128.45) 66.12,128.75 RC268.2 ; UC1.BR30 62.74,121.81 62.87,121.95 v1(63.02,121.95)
H_THERMTRIP#: length 86.1
  BOTTOM w0.102: v1(110.45,91.64) 110.09,91.64 109.06,90.6 109.06,87.92 111.7,85.27 111.7,83.74 121.39,74.05 121.39,71.68 122.65,70.42 125.3,70.42 134.02,64.3 136.9,61.43 139.25,61.43 139.89,60.79 141.29,60.79 142.14,59.94 143.92,59.94 145.03,58.84 160.39,58.84 168.03,61.1 173.24,61.1 173.82,60.52 RH79.2 ; RC45.1 107.01,123.57 RC46.1 107.01,123.2 v1(107.7,122.52)
H_THERMTRIP#_C: length 1.9
  BOTTOM w0.102: v1(104.82,124.34) 105.19,123.96 RC45.2 ; UC1.J31 97.7,122.21 v1(97.34,122.57)
H_THERMTRIP#_R: length 4.9
  BOTTOM w0.089: 173.76,56.57 174.96,55.37 174.96,55.04 UH1.AD3
  BOTTOM w0.102: RH79.1 173.82,58.34 173.56,58.08 173.56,57.48 173.72,57.32 173.72,56.6 173.76,56.57
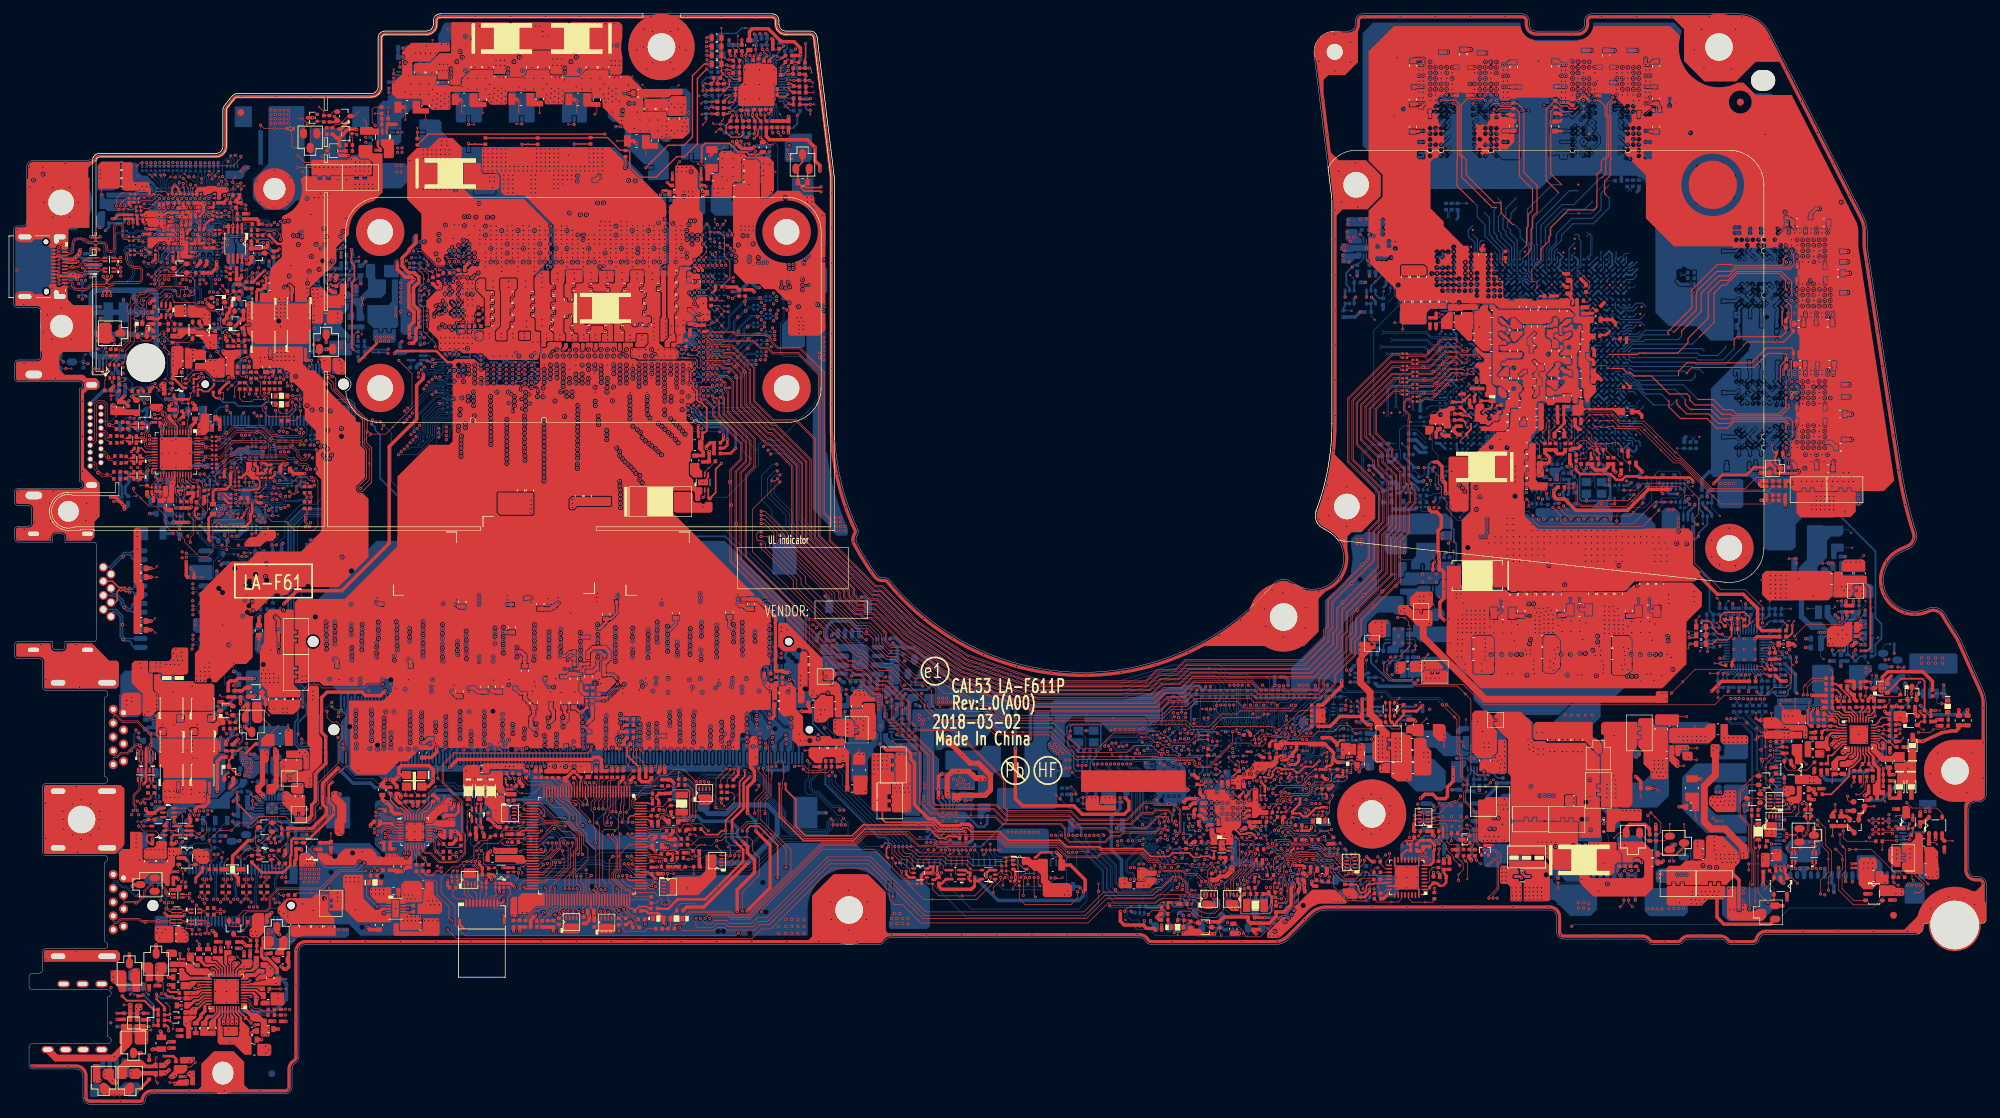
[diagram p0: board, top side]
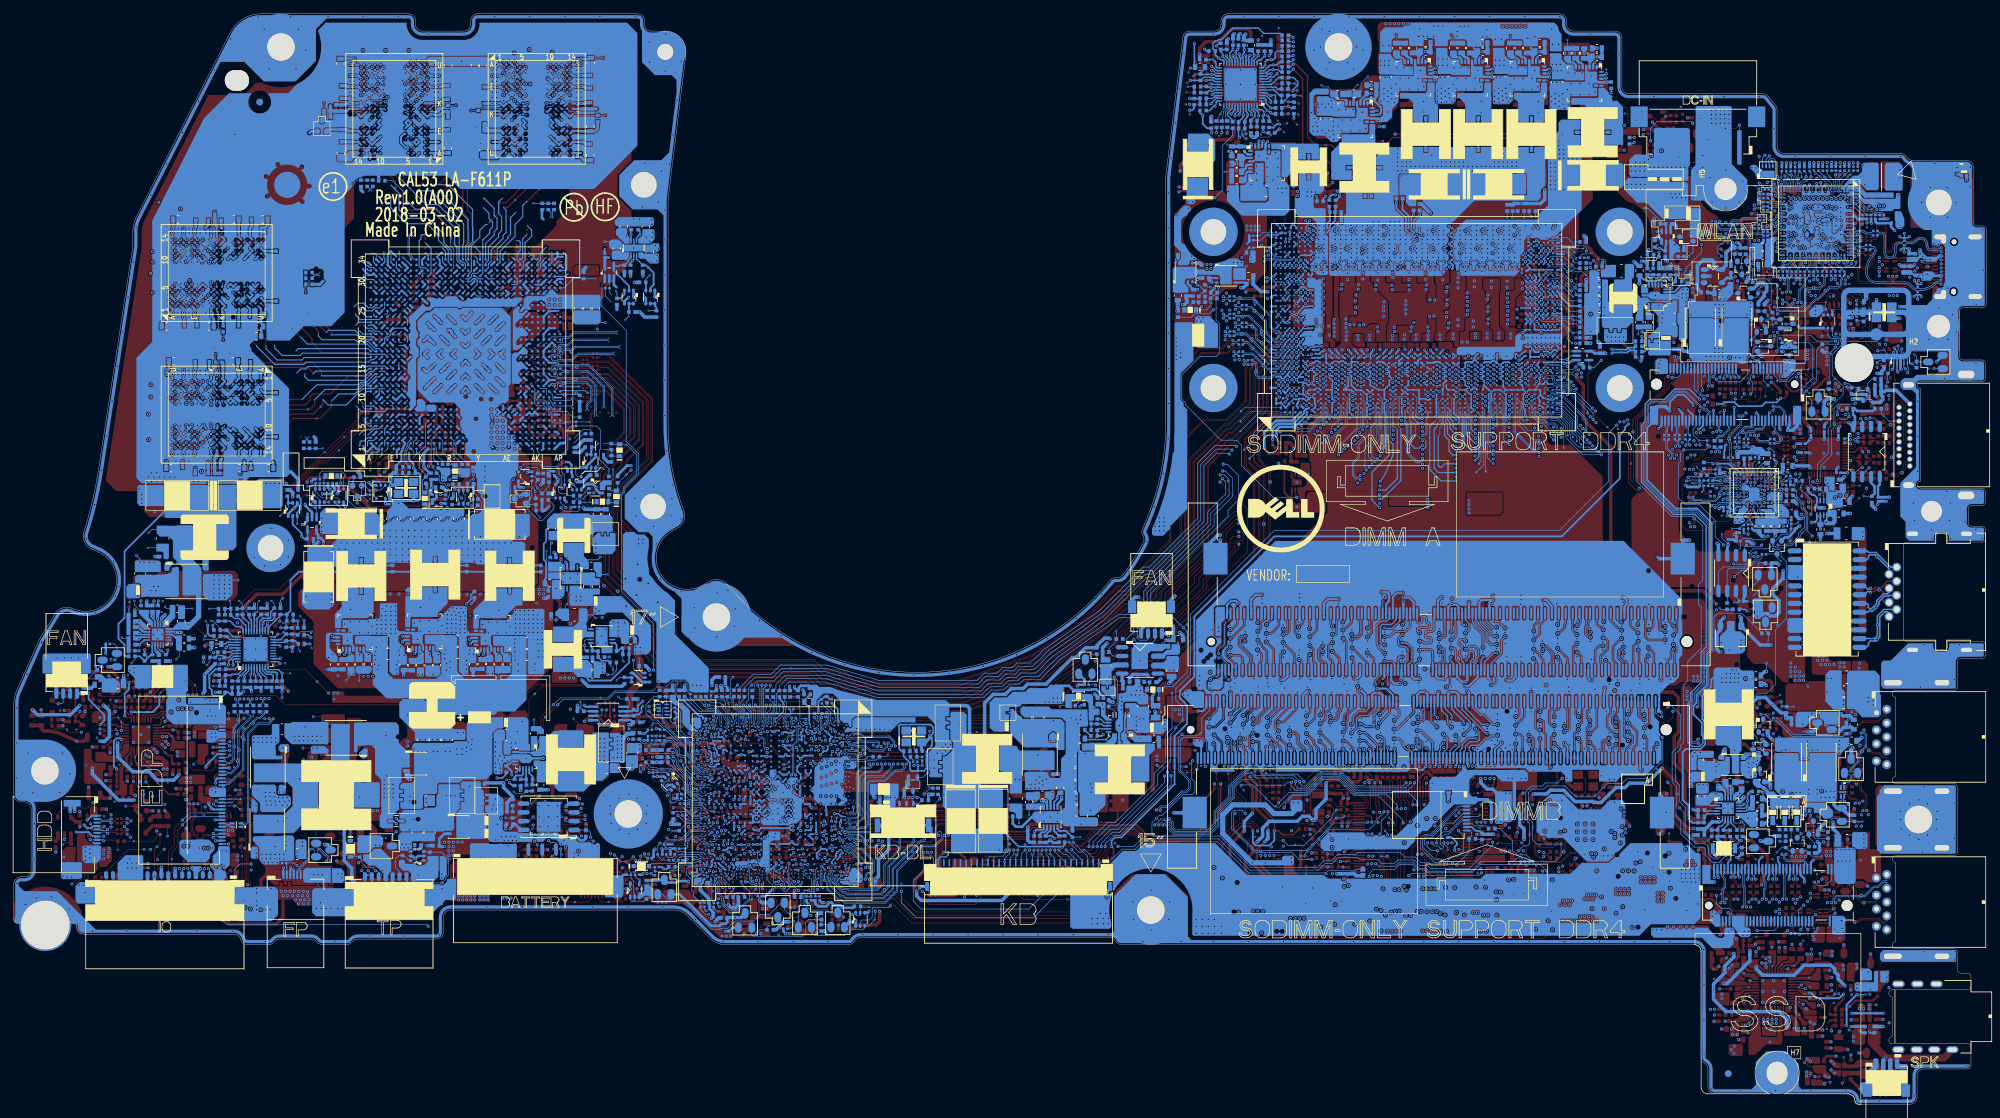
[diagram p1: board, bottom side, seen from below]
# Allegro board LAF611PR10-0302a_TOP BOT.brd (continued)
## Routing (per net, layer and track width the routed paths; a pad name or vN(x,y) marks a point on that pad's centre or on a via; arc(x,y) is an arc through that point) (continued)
H_VCCST_PWRGD: length 29.7
  TOP w0.102: UC16.4 134.66,33.87 134.44,34.09 134.44,34.56 134.07,34.92 130.45,34.92 129.55,35.82 128.77,35.82 128.04,36.55 v1(128.04,37.28) ; v1(98.48,109.55) 97.47,110.55 RC269.1 ; v1(104,116.6) 104.36,116.97 CH210.1 RC20.1 v2(105.82,115.67)
  BOTTOM w0.102: v1(128.04,37.28) 128.04,37.7 126.43,39.31 125.41,39.31 118.37,46.35 118.37,47.98 v1(118.43,48.04)
HDA_CODEC_SDIN0:
  vias: v2(34.38,16.94)
HDD_DET#: length 4.4
  BOTTOM w0.089: UH1.BE19 185.42,47.05 186.7,47.05
  BOTTOM w0.102: T4940.1 188.54,48.9 186.7,47.05
HDD_DEVSLP: length 11.5
  TOP w0.102: RS1.1 v2(267.97,38.05) 265.2,38.05 264.67,38.58 v1(264.67,39.55) ; v1(178.45,32.18) 178.28,32.35 178.28,32.96 179.52,34.19 179.52,34.78 179.26,35.04 179.26,35.65 179.63,36.02 v1(179.63,36.28)
  BOTTOM w0.102: v1(178.45,32.18) 178.59,32.32 UH1.AL48
HDD_DEVSLP_R: length 4.4
  TOP w0.102: v2(270.31,36.8) RS1.2 270.46,38.2 272.29,38.2 v1(272.37,38.12)
  BOTTOM w0.102: JHDD.8 272.5,38.25 v1(272.37,38.12)
HDD_EN_PCH: length 7.5
  TOP w0.102: US2.4 278.98,42.08 278.2,42.86 v2(276.96,42.86) 274.64,42.86 v1(273.86,43.64)
  BOTTOM w0.102: RH687.1 v1(192.43,53.29) RH699.1
HDD_EN_PCH_H: length 9
  BOTTOM w0.076: 186.82,49.01 186.45,48.64 186.14,48.64 186.04,48.54 185.7,48.54 185.5,48.33 185.33,48.33 UH1.BD17
  BOTTOM w0.102: RH699.2 190.97,53.01 v2(190.41,53.01) 190.26,53.01 189.38,52.13 188.9,52.13 188.2,51.44 188.2,50.87 186.82,49.48 186.82,49.01
HDMI_CEC: length 3.4
  TOP w0.102: v1(19.84,99.49) 20.06,99.27 RP11.2
  BOTTOM w0.102: CV601.2 20.17,100.29 19.84,99.96 v1(19.84,99.49) 20.22,99.11 v2(20.93,99.11)
HDMI_CLKN: length 2.7
  TOP w0.089: v1(18.53,96.46) 18.48,96.41 LV3.4 ; UP2.13 20.04,96.38 v1(19.65,96.77)
  BOTTOM w0.089: CP23.2 20.13,96.29 v1(19.65,96.77)
HDMI_CLKP: length 2.6
  TOP w0.089: UP2.14 19.84,95.98 v1(19.65,96.17) ; LV3.1 18.47,95.91 v1(18.53,95.86)
  BOTTOM w0.089: CP23.1 20.11,95.71 v1(19.65,96.17)
HDMI_CTRL_CLK: length 7.2
  TOP w0.102: UP2.7 23.26,97.86 22.04,99.08 22.04,99.96 21.82,100.18 21.34,100.18 20.98,99.82 v1(20.35,99.82) ; RV681.2 14.58,102.56 v1(14.07,102.56) v2(14.07,101.98)
HDMI_CTRL_DAT: length 4.6
  TOP w0.102: UP2.8 22.86,97.93 21.81,98.98 21.81,99.48 v1(21.51,99.77) ; RV680.2 14.01,109.4 v1(14.57,109.96)
  BOTTOM w0.102: v1(21.51,99.77) 21.51,100.25 v2(21.54,100.28)
HDMI_HPD: length 10.9
  TOP w0.203: v1(19.61,93.14) 19.65,93.18 UP2.21
  BOTTOM w0.508: v1(16.66,101.8) 16.41,101.55 15.37,101.55 v2(14.97,101.95) 14.97,102.42 15.19,102.64 CV599.2 ; RX6.2 CX2.1 CV599.2 ; JHDMI1.19 11.05,101.36 13,103.3 14.51,103.3 14.68,103.14 CV599.2
HDMI_HPD_PCH: length 3
  BOTTOM w0.102: v1(182.16,45.02) 182.55,44.63 UH1.AW24 ; v1(20.44,104.31) 19.96,104.31 19.47,103.82 RX8.1 18.68,103.69 QX3.3
HDMI_L_CLKN: length 2.6
  TOP w0.089: JHDMI1.12 12.97,97.48 13.24,97.48 13.49,97.22 13.49,96.42 13.55,96.37 13.64,96.37 RV673.2
HDMI_L_CLKP: length 2.6
  TOP w0.089: RV675.2 13.62,96.07 13.43,96.07 13.19,96.3 13.19,97.1 13.11,97.18 12.93,97.18 JHDMI1.10
HDMI_L_TX_N0: length 12.6
  TOP w0.089: JHDMI1.9 11.4,96 11.53,96 11.67,96.15 11.67,101.38 12.1,101.8 13.02,101.8 13.51,101.32 13.51,98.45 13.59,98.37 v4(13.86,98.37) 14.48,98.37 RV674.2
HDMI_L_TX_N1: length 2.9
  TOP w0.089: JHDMI1.6 13.01,94.44 13.2,94.44 13.52,94.12 13.52,93.81 v4(13.7,93.63) 13.89,93.45 14.25,93.45 RV29.2
HDMI_L_TX_N2: length 4.9
  TOP w0.089: RV33.2 14.12,91.16 v4(13.5,91.16) 12.82,91.16 12,91.97 12,92.64 11.69,92.95 11.45,92.95 JHDMI1.3
HDMI_L_TX_P0: length 12.6
  TOP w0.089: RV28.2 14.48,98.07 13.47,98.07 13.21,98.33 13.21,101.19 12.9,101.5 12.23,101.5 11.97,101.25 11.97,96.02 11.65,95.7 11.4,95.7 JHDMI1.7
HDMI_L_TX_P1: length 2.9
  TOP w0.089: RV30.2 14.24,93.15 13.76,93.15 13.49,93.42 13.22,93.69 13.22,93.99 13.08,94.14 12.89,94.14 JHDMI1.4
HDMI_L_TX_P2: length 4.8
  TOP w0.089: JHDMI1.1 11.36,92.65 11.57,92.65 11.7,92.52 11.7,91.85 v4(12.16,91.39) 12.69,90.86 14.12,90.86 RV34.2
HDMI_RESERVED: length 3.7
  BOTTOM w0.102: JHDMI1.14 14.04,98.85 v2(14.83,99.64) 15.19,100 CV600.2
HDMI_TX_N0: length 5.3
  TOP w0.089: UP2.16 19.8,95.18 19.75,95.13 19.4,95.13 19.23,95.31 19.23,97 19.58,97.36 19.58,98.09 19.31,98.37 18.98,98.37 18.88,98.47 LV4.4
HDMI_TX_N1: length 2.5
  TOP w0.089: UP2.19 19.96,93.98 19.9,93.92 19.32,93.92 18.88,93.48 18.5,93.48 LV5.4 18.28,93.7 RV642.1
HDMI_TX_N2: length 3.6
  TOP w0.089: RV645.1 18.28,91.42 LV6.4 18.55,91.14 18.96,91.14 19.11,91.28 19.11,92.25 19.59,92.73 19.95,92.73 20,92.78 UP2.22
HDMI_TX_P0: length 5.3
  TOP w0.089: UP2.17 19.8,94.78 19.75,94.83 19.28,94.83 18.93,95.18 v4(18.93,96.15) 18.93,97.13 19.28,97.48 19.28,97.97 19.19,98.07 19,98.07 18.9,97.97 LV4.1
HDMI_TX_P1: length 2.5
  TOP w0.089: UP2.20 19.97,93.58 19.93,93.62 19.45,93.62 19.01,93.18 18.58,93.18 LV5.1 18.28,92.88 RV639.1
HDMI_TX_P2: length 3.6
  TOP w0.089: UP2.23 20,92.38 19.96,92.43 19.71,92.43 19.41,92.12 v4(19.41,91.72) 19.41,91.16 19.09,90.84 18.53,90.84 LV6.1 18.28,90.59 RV638.1
HOST_DEBUG_TX: length 8.8
  TOP w0.102: RW15.2 34.35,104.99 v1(34.35,104.39) ; UE1.81 83.09,30.47 82.79,30.77 v1(82.79,33.92) ; RE57.2 v1(70.89,30.73) 70.89,30.5 70.21,29.82 69.18,29.82 68.96,29.6 JDEG1.8
HPD_IFPC: length 7.5
  TOP w0.102: 219.98,96.09 220.71,95.35 RV682.1 221.03,93.36 v2(221.65,93.36)
  BOTTOM w0.102: v1(213.03,90.39) 213.46,89.96 213.46,88.22 QG10.1 ; UV1.U3 220.34,96.45 219.98,96.09
HPOUT_L:
  vias: v1(14.39,18.39) v1(14.39,17.76) v3(14.2,19.16)
HPOUT_R: length 0.9
  TOP w0.127: v3(16.83,15.91) 17.32,16.41 17.32,16.6
  vias: v1(17.01,19.16) v1(18.03,19.38)
HV_GATE1_A: length 2.3
  TOP w0.102: v2(32.47,86.54) 32.11,86.9 v1(32.11,87.05)
  TOP w0.152: v1(32.11,87.05) 32.8,87.74 RT64.1
  BOTTOM w0.152: v1(32.11,87.05) 32.07,87.02 31.59,87.02 UT4.B9
HV_GATE2_A: length 2.2
  BOTTOM w0.152: UT4.A9 30.91,87.13 29.07,87.13 RT65.1
HW_ACAV_IN: length 40.8
  TOP w0.102: v1(23.56,39.6) PUS02.2 ; v2(54.21,144.27) 54.21,143.68 v1(54.15,143.62) PR31.1 ; v1(37.63,36) 38.37,35.27 PRB42.2
  TOP w0.203: UE1.128 91.72,43.61 91.82,43.51 CE32.2
  TOP w0.381: v1(92.29,44.29) 92.41,44.17 CE32.2
  BOTTOM w0.102: DH1.1 194.44,34.45 193.62,35.27 RH749.1 194.09,36.04 v1(194.09,36.22) ; v1(46,58.14) 44.22,56.36 44.22,52.78 44.7,52.3 44.7,51.63 45.43,50.9 45.43,46.56 44.86,45.99 44.86,41.72 44.2,41.07 44.2,39.2 42.21,37.21 40.88,37.21 40.65,36.98 40.65,36.46 40.65,36.46 40.65,36.06 39.6,35.01 38.63,35.01 v1(37.63,36)
HW_ACAVIN_NB: length 13.3
  TOP w0.102: v1(30.2,111.67) 30.67,112.14 30.99,112.14 31.76,111.37 PR46.1 PR52.1 ; v1(37.85,37.79) 37.85,37.99 37.69,38.15 PRB40.1 ; PRS51.1 68.53,42.05 67.03,42.05 66.91,42.17 PQS22.2 66.91,43.35 v1(67.03,43.47) ; v1(38.56,125.15) 38.56,125.84 37.89,126.51 PRS39.2
  BOTTOM w0.102: v1(29.86,38.06) 29.85,38.05 PRS40.1 PRS23.1
HW_ACAVIN_NB_EC: length 10.6
  TOP w0.102: v1(65.61,43.36) 65.89,43.36 66.26,42.98 PQS22.3 65.95,42.67 65.58,42.3 v2(65.58,40.04) 65.58,39.74 66,39.32 PRS50.2 ; v1(81.31,43.34) 80.98,43.67 80.63,43.67 79.89,44.41 UE1.24 79.89,46.13 CE34.2
I2C1_SCL_TCH_PAD: length 9.7
  BOTTOM w0.076: UH1.BE21 185.61,45.9 186.49,45.02 187.19,45.02 187.37,45.2
  BOTTOM w0.102: v1(226.73,34.87) 226.33,35.27 Q10.1 ; 187.37,45.2 187.73,45.56 187.73,46.16 187.93,46.36 187.93,47.17 189.93,49.17 v1(189.93,49.64) 190.53,50.24 R34.2
I2C1_SDA_TCH_PAD: length 5.6
  TOP w0.102: v1(187.45,46.4) 187.14,46.4 186.5,45.76 v2(186.5,45.45)
  BOTTOM w0.089: UH1.BF21 186.02,45.77 186.56,45.22 187.12,45.22 187.45,45.55 v1(187.45,46.4)
  BOTTOM w0.102: R33.2 227.33,37.5 227.33,36.92 v1(227.37,36.88) 227.68,36.57 Q10.4
I2C_SCL_TP: length 5.5
  BOTTOM w0.102: JTP.6 229.55,33.69 230.14,34.28 v2(230.14,34.86) 230.14,35.53 229.67,36 R46.2 228.92,36 228.19,35.27 Q10.6
I2C_SDA_TP: length 14.6
  TOP w0.102: v1(223.41,32.02) v3(223.41,31.19)
  BOTTOM w0.102: Q10.3 225.68,36.57 225.59,36.48 R47.2 223.45,36.48 222.5,35.53 222.5,33.13 222.86,32.77 222.86,32.53 223.37,32.02 v1(223.41,32.02) 228.24,32.02 228.55,32.33 JTP.7
I2CB_SCL: length 4.7
  TOP w0.109: RV512.1 222.01,95.89 222.01,97.5 222.12,97.6 v2(222.12,98.9) 221.72,99.3 221.67,99.3
  BOTTOM w0.109: 221.67,99.3 221.67,99.32 UV1.R7
I2CB_SDA: length 3.8
  TOP w0.102: 221.7,97.68 v2(221.27,97.25) 221.18,97.17 221.18,96.46 221.51,96.13 RV513.1
  TOP w0.114: 221.7,98.49 221.7,97.68
  BOTTOM w0.114: 221.7,98.49 221.7,98.5 222.09,98.9 UV1.R6
I2CC_SCL_R: length 3.7
  BOTTOM w0.109: UV1.R2 222.1,95.43 221.68,95.02 221.68,93.82 RV514.1
I2CC_SDA_R: length 4.9
  BOTTOM w0.109: UV1.R3 221.67,96.02 221.67,95.51 221.37,95.22 221.37,94.33 RV515.1
I_ADP: length 6.4
  TOP w0.102: UE1.110 91.58,36.41 92.13,35.86 92.91,35.86 93.02,35.76 93.85,35.76 CE25.1 94.76,34.85 95.56,34.85 95.96,35.25 RE51.1
I_ADP_R: length 31.2
  TOP w0.102: v1(258.88,59.24) 258.88,60.36 259.14,60.62 v2(259.14,60.62) 260.17,61.64 262.18,61.64 PRB35.2 ; v1(107.19,42.09) 107.19,44.08 108.51,45.39 108.51,47.39 107.7,48.2 107.7,48.6 v1(107.73,48.63) ; v1(97.56,35.43) 97.08,35.43 RE51.2
  BOTTOM w0.102: v1(107.19,42.09) 107.62,42.52 108.85,42.52 109.16,42.21 109.16,39.83 105.76,36.43 100.43,36.43 99.43,35.43 v1(97.56,35.43)
I_BATT: length 6.1
  TOP w0.102: UE1.114 91.75,38.01 91.81,37.96 94.22,37.96 94.48,37.71 94.88,37.71 95.12,37.46 CE30.1 96.14,37.46 96.24,37.57 RE54.1
I_BATT_R: length 24.9
  TOP w0.102: PRB59.1 262.19,60 PRB34.2 261.77,61.25 v2(260.54,61.25) 260.33,61.25 259.47,60.39 v1(259.47,59.24) ; RE54.2 98.12,37.57 99.21,38.66 102.2,38.66 102.68,39.14 104.31,39.14 106.05,40.88 107.18,40.88 107.68,41.39 107.68,43.94 108.84,45.1 108.84,47.59 108.45,47.98 108.45,48.6 v1(108.42,48.63)
ICSP_CLK: length 30.5
  TOP w0.102: UE1.101 89.38,32.81 v1(89.25,32.94) ; v1(63.58,33.76) 63.35,33.53 RE60.2
  BOTTOM w0.102: v1(89.25,32.94) 89.25,33.37 88.65,33.97 85.56,33.97 84.83,34.7 82.99,34.7 82.19,33.9 81.16,33.9 80.75,33.49 74.41,33.49 73.22,34.68 64.5,34.68 v1(63.58,33.76)
ICSP_CLR: length 2.6
  TOP w0.102: RE61.2 64.11,33.66 v1(64.21,33.76) ; v1(84.95,31.04) 85.49,30.5 UE1.87
ICSP_DAT: length 31.3
  TOP w0.102: v2(67.25,36.17) 67.25,35.67 66.75,35.18 v1(66.75,35.11) 66.75,34.75 67.29,34.21 67.29,32.42 RE63.2 ; UE1.102 89.87,33.21 88.32,34.76 v1(88.32,34.79)
  BOTTOM w0.102: v1(88.32,34.79) 88.29,34.79 87.95,34.44 85.46,34.44 84.98,34.93 82.89,34.93 82.09,34.12 80.98,34.12 80.58,33.72 74.5,33.72 73.08,35.14 68.37,35.14 67.87,35.64 67.28,35.64 v1(66.75,35.11)
IFP_IOVDD: length 3.9
  BOTTOM w0.305: UV1.AG8 212,100.63 212.47,101.11 212.13,101.45 UV1.AG9 ; UV1.AC8 215,100.15 UV1.AC7 ; 213.36,98.44 UV1.AF6 ; 211.66,99.46 212.1,99.02 UV1.AG6
  vias: v2(211.53,98.92)
IFPC_CLK_CN: length 2.3
  TOP w0.089: UP2.48 26.91,96.38 26.96,96.33 27.25,96.33 27.35,96.43 v4(27.79,96.43) 28.52,96.43 CP22.2
IFPC_CLK_CP: length 2.3
  TOP w0.089: UP2.47 26.91,95.98 26.96,96.03 27.38,96.03 27.48,96.13 28.52,96.13 CP21.2
IFPC_CLK_N: length 14.5
  TOP w0.089: CP22.1 30.18,96.59 v4(30.74,97.15) 31.82,98.24 36.15,98.24 37.46,96.93 38.07,96.93 38.21,96.79 41.36,96.79 41.49,96.92 41.49,97.05 v1(41.34,97.2)
  BOTTOM w0.089: 211.67,96.78 211.67,96.82 UV1.AG4
IFPC_CLK_P: length 15.2
  TOP w0.089: v1(41.93,97.2) 41.79,97.06 41.79,96.79 41.48,96.49 38.09,96.49 37.95,96.63 37.34,96.63 36.03,97.94 31.95,97.94 30.3,96.3 29.61,96.3 CP21.1
  BOTTOM w0.089: 211.67,97.55 212.1,97.98 UV1.AG5
IFPC_I2C_8409_CLK: length 20.6
  TOP w0.089: UP2.34 24.86,90.27 v1(25.07,90.06) 25.33,89.8 25.52,89.8 RP25.1
  TOP w0.102: v1(18.92,101.45) 18.48,101.89 18.48,102.4 18.01,102.87 RP9.2
  BOTTOM w0.089: v1(25.07,90.06) 24.85,90.06 24.63,89.84 24.18,89.84 23.93,90.09 23.93,92.39 22.39,93.93 v2(22.39,94.23) 22.39,97.55 22.02,97.91 22.02,99.54
  BOTTOM w0.102: 22.02,99.54 22.02,100.72 21.42,101.32 19.05,101.32 v1(18.92,101.45)
IFPC_I2C_8409_DAT: length 31.4
  TOP w0.089: UP2.33 24.46,90.31 v1(24.42,90.27) 24.42,90.12 RP24.1
  TOP w0.102: RP10.2 15.42,109.9 v1(15.42,110)
  BOTTOM w0.089: v1(24.42,90.27) 24.42,92.61 22.86,94.17 v2(22.86,96.05) 22.86,97.74 22.53,98.07 22.53,100.88 20.69,102.72 20.69,103.9 22.28,105.48 22.28,108.5 20.38,110.39 15.82,110.39 v1(15.42,110)
IFPC_I2C_CLK: length 25.6
  TOP w0.102: v1(24.71,117.02) 24.71,117.73 24.58,117.86 24.23,117.86 24.08,117.71 24.08,116.96 23.93,116.81 23.72,116.81 23.57,116.96 23.57,117.71 23.42,117.86 21.74,117.86 21.15,117.26 19.67,117.26 19.12,116.71 18.57,116.71 18.34,116.48 18.34,116.25 18.25,116.16 18.25,115.94 18.62,115.57 18.62,115.36 18.47,115.21 18.27,115.21 17.89,115.59 17.68,115.59 17.41,115.33 17.41,114.68 17.56,114.53 17.8,114.53 17.95,114.38 17.95,114.17 17.8,114.02 17.56,114.02 17.41,113.88 17.41,113.67 17.56,113.52 17.8,113.52 17.95,113.37 17.95,113.16 17.8,113.01 17.56,113.01 17.41,112.86 17.41,112.65 17.56,112.5 17.8,112.5 17.95,112.35 17.95,112.14 17.8,111.99 17.56,111.99 17.41,111.84 17.41,110.25 16.19,109.03 16.19,108.38 15.99,108.18 15.99,107.5 v1(15.77,107.29) 15.49,107 QV96.4
  BOTTOM w0.102: UV1.AG3 212.07,96.45 211.67,96.05 ; v1(15.77,107.29) 15.43,107.63 RV679.2
IFPC_I2C_CLK_R: length 7.1
  TOP w0.102: QV96.3 16.02,105.1 16.12,105 16.12,104.71 16.02,104.61 15.41,104.61 15.27,104.47 RV681.1 15.46,103.97 16.1,103.97 v2(16.19,103.89) 16.88,103.2 RP9.1 17.69,103.79 18.41,103.79 18.75,103.46 RV677.2
IFPC_I2C_DAT: length 24.5
  TOP w0.102: QV96.1 13.87,104.89 v1(14.26,104.5) ; v1(15.69,109.04) 15.69,109.21 16.89,110.41 v2(16.89,115.14) 16.89,115.49 17.84,116.44 17.84,116.67 18.37,117.19 18.92,117.19 19.47,117.75 20.72,117.75 21.35,118.38 24.79,118.38 v1(25.63,117.53)
  BOTTOM w0.102: UV1.AG2 211.84,95.39 211.73,95.28 ; v1(14.26,104.5) 14.26,105.7 RV678.2 14.02,105.94 14.02,108.33 14.73,109.04 v1(15.69,109.04)
IFPC_I2C_DAT_R: length 8.6
  TOP w0.102: QV96.6 13.87,107.2 14.77,108.1 RP10.1 RV680.1 13.2,108.33 12.89,108.03 v2(12.89,108) 12.89,106.43 13.27,106.05 13.27,104.91 13.16,104.8 RV676.2
IFPC_TX0_CN: length 2.3
  TOP w0.089: UP2.45 26.97,95.18 27.02,95.13 v4(27.78,95.13) 28.14,95.13 28.17,95.16 28.52,95.16 CP20.2
IFPC_TX0_CP: length 2.3
  TOP w0.089: CP19.2 28.52,94.86 28.29,94.86 28.27,94.83 27.02,94.83 26.97,94.78 UP2.44
IFPC_TX0_N: length 15.5
  TOP w0.089: CP20.1 29.47,95.13 29.75,95.13 32.16,97.54 35.82,97.54 37.13,96.23 37.79,96.23 37.92,96.1 41.54,96.1 41.86,95.78 41.86,95.56 v1(42,95.42)
  BOTTOM w0.089: 210.78,96.81 211.22,97.25 UV1.AH4
IFPC_TX0_P: length 15
  TOP w0.089: CP19.1 29.41,94.83 29.87,94.83 32.29,97.24 v4(35.17,97.24) 35.7,97.24 37,95.93 37.66,95.93 37.8,95.8 41.42,95.8 41.56,95.65 41.56,95.56 v1(41.42,95.42)
  BOTTOM w0.089: 210.78,96.01 210.81,96.01 UV1.AH3
IFPC_TX1_CN: length 2.3
  TOP w0.089: UP2.42 26.94,93.98 26.99,93.93 28.15,93.93 28.32,93.76 28.52,93.76 CP18.2
IFPC_TX1_CP: length 2.3
  TOP w0.089: CP17.2 28.52,93.46 28.2,93.46 28.03,93.63 v4(27.74,93.63) 26.97,93.63 26.93,93.58 UP2.41
IFPC_TX1_N: length 16.9
  TOP w0.089: v1(42.15,93.95) 42.3,93.8 42.3,93.65 42.12,93.47 41.72,93.47 41.25,93.94 41.25,94.44 40.46,95.24 v4(40.04,95.24) 38.12,95.24 37.88,95.01 37.34,95.01 36.32,96.02 31.64,96.02 30.56,94.95 30.56,94.5 29.82,93.76 29.44,93.76 CP18.1
  BOTTOM w0.089: 209.97,95.25 210.37,95.65 UV1.AJ2
IFPC_TX1_P: length 17.4
  TOP w0.089: v1(42.73,93.95) 42.6,93.82 42.6,93.53 42.25,93.17 41.6,93.17 40.95,93.81 40.95,94.32 40.33,94.94 38.24,94.94 38.01,94.71 37.21,94.71 36.2,95.72 31.76,95.72 30.86,94.82 30.86,94.38 29.95,93.46 29.44,93.46 CP17.1
  BOTTOM w0.089: 209.97,96.05 210.37,96.45 UV1.AJ3
IFPC_TX2_CN: length 2.4
  TOP w0.089: UP2.39 26.94,92.78 26.99,92.73 27.26,92.73 27.49,92.49 28.52,92.49 CP16.2
IFPC_TX2_CP: length 2.4
  TOP w0.089: UP2.38 26.94,92.38 26.99,92.43 27.13,92.43 27.37,92.19 v4(27.74,92.19) 28.52,92.19 CP15.2
IFPC_TX2_N: length 16.9
  TOP w0.089: CP16.1 29.44,92.49 29.53,92.49 31.07,94.03 31.48,94.03 32.3,94.84 33.46,94.84 34.34,93.96 39.38,93.96 39.78,93.55 40.61,93.55 41.41,92.76 42.31,92.76 42.65,92.42 42.65,92.16 v1(42.93,91.88)
  BOTTOM w0.089: UV1.AJ1 210.15,94.6 210.15,94.14
IFPC_TX2_P: length 16.3
  TOP w0.089: v1(42.35,91.88) 42.35,92.3 42.19,92.46 41.28,92.46 40.49,93.25 39.66,93.25 39.25,93.66 34.21,93.66 33.33,94.54 32.42,94.54 31.61,93.73 31.2,93.73 v4(30.4,92.93) 29.66,92.19 29.44,92.19 CP15.1
  BOTTOM w0.089: 209.29,94.14 209.6,94.45 UV1.AK1
IFPCD_RSET: length 3.9
  TOP w0.102: RG37.1 209.32,96.06 v2(209.32,95.81)
  TOP w0.305: 210.8,98.45 210.8,97.68 210.16,97.04 RG37.1
  BOTTOM w0.305: UV1.AF8 212.9,100.5 213.33,100.07
ILIM_1PH: length 3.2
  TOP w0.203: PCZ09.2 105.24,143.85 PRZ15.1 106.18,143.26 v1(106.27,143.17)
  BOTTOM w0.203: PUZ01.49 106.68,143.89 106.27,143.48 v1(106.27,143.17)
ILIM_2PH: length 2.8
  TOP w0.203: PRZ48.1 112.88,148.16 v1(112.86,148.14)
  BOTTOM w0.203: v1(112.86,148.14) 112.8,148.2 v2(112.33,148.2) 111.8,148.2 111.58,147.98 PUZ01.32
ILIM_4PH: length 3.4
  BOTTOM w0.203: PUZ01.7 103.39,147.58 v2(102.76,148.21) 102.38,148.59 PRZ32.2
ILMT_VCCIO: length 5.6
  TOP w0.102: v2(46.53,120.97) 46.53,120.62 45.85,119.94 PR905.1
  TOP w0.254: v1(45.67,119.27) 45.67,119.73 PR905.1
  BOTTOM w0.254: v1(45.67,119.27) 45.85,119.27 46.23,119.64 46.23,119.73 PR906.2 46.75,119.79 46.75,119.67 47.06,119.36 47.57,119.36 47.85,119.07 PU901.13
IMON_1PH: length 3
  TOP w0.203: PRZ14.2 108.02,143.96 PCZ08.2 107.97,143.89 107.97,143.31 108.08,143.2 v1(108.08,143.18)
  BOTTOM w0.203: PUZ01.46 107.88,143.55 108.08,143.35 v1(108.08,143.18)
IMVP_VR_ON: length 45
  TOP w0.102: RE16.1 CE31.1 78.59,26.03 RE158.1 v1(78.89,25.04) ; v1(108.17,27.8) 108.17,28.06 117.01,36.89 124.41,36.89 131.66,29.64 v2(132.91,29.64) 139.31,29.64 141.97,32.3 UZ21.1
IMVP_VR_PG: length 21.9
  TOP w0.102: UH14.1 130.18,34.45 129.22,35.41 128.6,35.41 127.46,36.55 v1(127.46,37.3)
  TOP w0.203: v1(108.68,143.06) 108.68,142.47 PRZ17.2
  BOTTOM w0.102: v1(127.46,37.3) 127.46,37.65 126.2,38.91 125.24,38.91 117.93,46.21 v1(117.93,47.55)
  BOTTOM w0.203: v1(108.68,143.06) 108.68,143.33 108.28,143.72 PUZ01.45
INT_TP#: length 0.8
  TOP w0.102: v1(232,33.79) 232,33.41 v3(232.3,33.12)
INTRUDER#: length 7.9
  TOP w0.102: RH531.1 182.91,29.02 183.9,29.02 184.21,29.34 v2(184.21,30.82) 184.21,31.29 184.37,31.44 184.37,31.93 183.88,32.41 183.88,33.3 183.69,33.49 183.69,34.31 v1(183.82,34.44)
  BOTTOM w0.102: UH1.BB44 183.82,34.82 v1(183.82,34.44)
IR_CAM_DETECT#: length 2.7
  BOTTOM w0.102: TC103.1 253.26,44.14 253.27,44.15 JEDP1.26
ISOLATE#: length 5.6
  TOP w0.102: UL1.20 60.65,39.23 v2(61.21,38.67) 62.17,37.71 RL3.2 62.66,37.16 64.41,37.16 RL4.1
JACK_PLUG: length 2.4
  TOP w0.102: RA10.1 21.6,17.56 21.6,16.27 v3(21.32,15.99)
  vias: v1(20.68,20.09) v1(20.68,19.46)
JACK_PLUG_DET: length 2.7
  TOP w0.102: RA40.1 19.38,18.06 19.11,17.79 19.11,16.22 v3(19.47,15.86)
  vias: v1(18.72,20.28) v1(18.69,19.69)
JTAG_CLK: length 3.1
  TOP w0.102: JDEG1.4 66.96,30.41 v2(66.87,30.5) 66.19,31.18 RPE7.3
JTAG_TDI: length 5.1
  TOP w0.102: RE60.1 63.75,31.88 RPE7.1 v2(65.19,30.41) 65.96,29.63 JDEG1.2
JTAG_TDO: length 7
  TOP w0.102: v2(66.51,34.52) 66.65,34.52 67.04,34.12 67.04,32.55 66.69,32.19 RPE7.4 66.69,31.58 66.83,31.44 67.08,31.44 67.21,31.57 67.59,31.57 67.72,31.44 RE63.1 67.72,30.94 67.46,30.68 JDEG1.5
JTAG_TMS: length 8
  TOP w0.102: JDEG1.3 66.46,29.76 65.69,30.54 RPE7.2 65.69,32.2 65.47,32.42 65.03,32.42 64.77,32.16 64.24,32.16 RE61.1 64.29,32.46 64.49,32.46 64.73,32.7 64.73,34.11 v2(65.14,34.52)
KB_BL_CTRL#: length 4.5
  TOP w0.102: v1(154.69,44.37) v3(154.69,43.47)
  BOTTOM w0.102: JKBBL.4 154.42,43.52 C149.1 154.33,44.37 v1(154.69,44.37) 155.27,44.96 Q8.1
KB_DET#: length 47.3
  TOP w0.102: v1(153.77,36.45) 153.87,36.55 v3(155.36,36.55)
  BOTTOM w0.089: 187.56,39.26 187.38,39.44 UH1.BE34
  BOTTOM w0.102: v1(153.77,36.45) 153.77,33.76 155.23,32.3 155.23,29.4 154.06,28.23 138.52,28.23 133.69,33.06 132.78,33.06 131.65,34.19 128.65,34.19 128.4,34.44 JKB.1 ; v1(191,37.01) 191,37.18 191.3,37.48 RH128.1 191.3,37.83 191.02,38.11 189.08,38.11 188.86,38.33 188.49,38.33 187.56,39.26
KB_LED_BL_DET: length 4.6
  TOP w0.102: v1(153.65,44.87) 153.65,45.3 v2(152.97,45.97)
  BOTTOM w0.102: UH1.BD8 185.01,51.88 v1(184.76,51.63) ; v1(153.65,44.87) 152.77,45.74 R27.1 R26.1
KB_LED_DET_C: length 8.6
  TOP w0.102: v1(151.38,44.18) v3(150.79,44.78)
  BOTTOM w0.102: R26.2 151.38,44.58 v1(151.38,44.18) 152.78,42.79 156.97,42.79 157.2,43.01 JKBBL.2
KB_LED_PWM: length 71.4
  TOP w0.102: v2(115.23,49.29) 114.82,49.7 v1(114.81,49.7) ; UE1.44 75.97,39.21 v1(76.33,39.57)
  BOTTOM w0.102: Q8.2 153.88,47.25 v1(153.12,48.01) ; v1(76.33,39.57) 75.64,38.88 75.64,36.66 76.41,35.89 77.24,35.89 77.92,35.21 77.92,34.74 78.14,34.53 80.24,34.53 80.65,34.94 81.75,34.94 82.57,35.76 84.1,35.76 84.77,36.43 90.88,36.43 91.21,36.1 93.88,36.1 94.76,35.22 95.83,35.22 96.78,34.28 106.35,34.28 110.87,38.8 120.45,38.8 120.69,39.04 120.69,40.72 119.62,41.79 119.21,41.79 116.17,44.84 114.85,44.84 114.47,45.22 114.47,46.62 114.94,47.09 114.94,49.58 v1(114.81,49.7)
KSI0: length 8
  TOP w0.102: RPE1.4 93.71,30.69 v1(92.88,31.52) 92.59,31.24 91.93,31.24 91.55,31.61 UE1.98 ; v3(133.68,37.18) 133.71,37.21 134.89,37.21 135.05,37.06 135.26,37.06 135.42,36.89 v1(135.42,36.79)
  BOTTOM w0.102: v1(135.42,36.79) 135.42,36.24 134.8,35.62 JKB.9
KSI1: length 6.7
  TOP w0.102: UE1.99 91.63,32.01 92,31.64 v1(92.27,31.64) 92.27,31.87 v3(92.56,32.16) 92.82,32.16 93.78,31.19 RPE1.3
  BOTTOM w0.102: JKB.7 133.2,35 134.75,36.54 v1(134.75,36.78)
KSI2: length 23.8
  TOP w0.102: RPE1.2 93.69,31.69 93.51,31.88 93.51,32.37 93.73,32.59 94.37,32.59 94.58,32.8 v1(94.58,33.37) 95.47,33.37 v3(95.49,33.35) ; v1(87.12,42.3) 87.09,42.33 UE1.6
  BOTTOM w0.102: v1(98.55,35.91) 98.55,36.18 94.95,39.79 89.2,39.79 88.42,40.58 88.42,40.96 87.12,42.25 v1(87.12,42.3) ; v1(133.1,36.79) 133.07,36.79 131.6,35.32 JKB.5
KSI3: length 28.4
  TOP w0.102: v1(86.54,42.34) 86.69,42.49 UE1.7 ; v1(87.73,39.1) 87.59,38.96 87.59,33.85 87.04,33.3 87.04,32.69 88.62,31.11 89.03,31.11 89.52,30.62 92.71,30.62 93.78,29.55 93.78,29.04 93.96,28.87 v1(94.2,28.87) 94.55,28.87 94.86,29.17 v3(94.86,29.41) 94.61,29.65 94.61,32.03 94.45,32.19 RPE1.1
  BOTTOM w0.102: v1(86.54,42.34) 86.54,41.96 87.52,40.99 87.52,39.31 v1(87.73,39.1) ; v1(134.24,33.47) 134,33.71 JKB.8
KSI4: length 8.3
  TOP w0.102: RPE2.1 103.87,34.5 v3(104.29,34.92) 104.93,35.56 v1(104.93,36) ; v1(88.91,34.81) 88.91,34.6 89.5,34 89.71,34 89.72,34.01 UE1.104
  BOTTOM w0.102: JKB.4 130.8,35.32 v1(132.3,36.82)
KSI5: length 7.9
  TOP w0.102: v3(104.98,36.64) 104.69,36.64 104.29,36.24 v1(104.29,36) 104.29,35.72 103.57,35 RPE2.2 ; UE1.105 89.83,34.41 89.49,34.75 v1(89.49,34.77)
  BOTTOM w0.102: v1(134.16,36.8) 133.52,36.16 133.05,36.16 132.4,35.5 JKB.6
KSI6: length 9.6
  TOP w0.102: UE1.107 89.41,35.21 v1(88.73,35.89) ; RPE2.3 103.16,35.5 v1(103.66,36) 103.66,36.96 v3(103.38,37.24)
  BOTTOM w0.102: JKB.3 130,35.85 130.65,36.5 131.26,36.5 v1(132.68,37.91)
KSI7: length 8.3
  TOP w0.102: v1(103.02,36) RPE2.4 102.33,36.69 v3(101.68,37.34) ; v1(89.33,35.91) 89.62,35.61 UE1.108
  BOTTOM w0.102: v1(132.08,37.91) 130.96,36.79 130.34,36.79 129.2,35.65 JKB.2
KSO0: length 48
  TOP w0.102: v1(89.91,46.54) 89.91,46.37 90.17,46.11 91.94,46.11 93.38,47.55 94.61,47.55 95.49,48.44 96.92,48.44 v1(98.7,46.66) 99.16,46.2 RPE3.8 ; UE1.2 88.69,46.04 88.44,46.29 v1(88.44,46.49) ; v1(141.26,36.78) v3(141.26,37.65)
  BOTTOM w0.102: v1(98.7,46.66) 98.7,46.8 99.66,47.76 104.67,47.76 105.61,48.69 106.37,48.69 106.76,48.3 107.3,48.3 109.6,46 109.6,44.48 111.7,42.39 111.7,40.59 112.58,39.71 117.28,39.71 117.62,40.05 117.62,40.86 118.05,41.28 119.41,41.28 v1(120.28,40.41) ; v1(141.26,36.78) 141.26,36.33 142,35.58 JKB.18 ; v1(88.44,46.49) 88.44,46.72 88.67,46.95 89.5,46.95 v1(89.91,46.54)
KSO1: length 51.2
  TOP w0.102: v3(120.04,41.38) 119.7,41.03 v1(119.7,40.42) ; UE1.14 83.89,46.47 83.93,46.5 v1(83.93,46.53) ; RPE3.7 99.66,46.14 99.39,46.41 99.39,46.6 v1(99.3,46.69)
  BOTTOM w0.102: v1(140.09,36.78) 140.09,36.03 140.4,35.72 JKB.16 ; v1(119.7,40.42) 119.69,40.42 119.06,41.05 118.14,41.05 117.85,40.76 117.85,39.96 117.38,39.48 112.43,39.48 111.47,40.44 111.47,42.29 109.37,44.39 109.37,45.91 107.22,48.06 106.23,48.06 105.7,47.53 100.14,47.53 v1(99.3,46.69) 99.3,46.43 98.92,46.05 98.43,46.05 96.34,48.14 93.29,48.14 91.2,46.05 84.38,46.05 83.93,46.5 v1(83.93,46.53)
KSO2: length 51.4
  TOP w0.102: v1(83.3,46.53) 83.3,46.53 83.49,46.34 UE1.15 ; v3(140.34,36.13) 140.67,36.47 v1(140.67,36.78) ; RPE3.6 100.16,46.11 99.9,46.37 v1(99.9,46.71)
  BOTTOM w0.102: v1(140.67,36.78) 140.67,36.19 141.2,35.66 JKB.17 ; v1(119.11,40.41) 119.11,40.41 118.7,40.82 118.24,40.82 118.08,40.67 118.08,39.86 117.47,39.25 112.33,39.25 111.24,40.34 111.24,42.2 109.07,44.37 109.07,45.88 107.12,47.83 106.33,47.83 105.71,47.22 100.41,47.22 v1(99.9,46.71) 99.91,46.69 99.91,46.12 99.54,45.74 98.42,45.74 96.25,47.91 93.38,47.91 91.25,45.78 84.05,45.78 83.3,46.53 v1(83.3,46.53)
KSO3: length 51.3
  TOP w0.102: UE1.16 83.09,46.08 82.7,46.47 v1(82.7,46.53) ; v3(118.22,41.34) 118.53,41.03 v1(118.53,40.42) ; v1(100.49,46.61) 100.63,46.48 100.63,45.64 RPE3.5
  BOTTOM w0.102: v1(82.7,46.53) 82.7,46.35 83.62,45.44 91.24,45.44 93.47,47.68 96.16,47.68 98.4,45.44 99.92,45.44 100.49,46.01 v1(100.49,46.61) 101.04,46.61 101.49,46.16 105.5,46.16 106.29,46.95 107.65,46.95 108.8,45.8 108.8,44.31 111.01,42.1 111.01,40.25 112.24,39.02 117.57,39.02 118.53,39.99 v1(118.53,40.42) ; v1(139.03,36.78) 139.6,36.21 JKB.15
KSO4: length 16.8
  TOP w0.102: v1(82.29,36.14) 82.11,36.31 82.11,38.84 80.05,40.91 78.84,40.91 78.74,41.01 76.84,41.01 75.84,42.01 UE1.37 73.47,42.01 72.66,42.82 RPE4.8 ; v1(136.59,36.78) 136.82,36.55 v2(136.82,36.18)
  BOTTOM w0.102: v1(136.59,36.78) 136.6,36.76 136.6,35.98 136.4,35.78 JKB.11
KSO5: length 16.5
  TOP w0.102: v1(136,36.78) 136,36.57 135.69,36.26 135.56,36.26 v2(135.47,36.17) ; v1(81.64,36.17) 81.83,36.36 81.83,38.81 79.95,40.68 78.74,40.68 78.65,40.78 76.67,40.78 75.84,41.61 UE1.38 73.41,41.61 72.7,42.32 RPE4.7
  BOTTOM w0.102: JKB.10 135.6,35.74 136,36.14 v1(136,36.78)
KSO6: length 7.5
  TOP w0.102: v1(72.5,40.81) 72.22,40.81 71.82,41.21 71.82,41.62 72.03,41.82 RPE4.6 72.72,41.82 73.3,41.24 74.05,41.24 74.08,41.21 UE1.39 ; v1(137.76,36.78) 138.13,36.41 v2(138.13,36.16)
  BOTTOM w0.102: v1(137.76,36.78) 137.76,36.18 138,35.94 JKB.13
KSO7: length 5.9
  TOP w0.102: v1(73.1,40.81) 72.58,41.32 RPE4.5 ; v1(76.29,36.86) 76.24,36.81 UE1.50 73.52,36.81 v3(73.3,36.6)
  BOTTOM w0.102: JKB.12 137.2,35.73 137.15,35.78 137.15,36.76 v1(137.17,36.78)
KSO8: length 20.1
  TOP w0.102: v3(139.05,37.57) 139.05,37.43 v1(138.4,36.78) ; UE1.46 76.19,38.41 77.03,39.26 77.03,39.47 77.88,40.32 78.46,40.32 79.34,39.44 80.51,39.44 81.57,38.37 81.57,36.87 81.24,36.53 81.24,33.83 80.34,32.94 v1(80.34,31.18) ; v1(84.9,27.94) 85,27.84 RPE6.8
  BOTTOM w0.102: v1(138.4,36.78) 138.8,36.38 JKB.14
KSO9: length 7.5
  TOP w0.102: v3(146.71,31.82) 146.71,32.57 v1(146.94,32.8) ; RE15.1 75.68,26.78 v1(76.63,27.74) 76.92,27.74 77.89,28.7 UE1.68
  BOTTOM w0.102: JKB.24 146.8,34.07 146.94,33.93 v1(146.94,32.8)
KSO10: length 7.2
  TOP w0.102: RPE5.8 79.92,27.22 79.74,27.39 79.13,27.39 v1(78.96,27.57) 78.94,27.58 78.94,27.9 79.49,28.45 UE1.72 ; v3(148.47,31.61) 148.2,31.88 v1(148.2,32.82)
  BOTTOM w0.102: JKB.26 148.4,34.26 148.2,34.06 v1(148.2,32.82)
KSO11: length 7.9
  TOP w0.102: UE1.74 80.29,28.08 v1(80.07,27.86) 80.07,27.6 80.42,27.25 RPE5.7 ; v1(147.61,32.82) 147.61,30.16 v3(147.79,29.98)
  BOTTOM w0.102: JKB.25 147.6,34.06 147.61,34.05 v1(147.61,32.82)
KSO12: length 7.5
  TOP w0.102: RPE5.6 80.95,26.96 80.95,27.8 v1(80.9,27.84) 80.9,28.21 80.69,28.42 UE1.75 ; v1(142.77,32.83) 142.77,32.4 141.71,31.34 v3(141.71,30.62)
  BOTTOM w0.102: v1(142.77,32.83) 142.8,32.86 JKB.19
KSO13: length 7.5
  TOP w0.102: RPE5.5 81.42,27.37 81.74,27.68 v1(81.74,27.89) 81.09,28.53 UE1.76 ; v2(147.55,33.41) 146.32,33.41 v1(145.71,32.8)
  BOTTOM w0.102: v1(145.71,32.8) 145.71,33.52 145.2,34.03 JKB.22
KSO14: length 7.5
  TOP w0.102: v3(146.06,30.21) 146.06,32.51 v1(146.36,32.8) ; v1(81.51,31.18) 81.51,29.6 UE1.77 ; RPE6.6 86,27.68 v1(86.08,27.77)
  BOTTOM w0.102: v1(146.36,32.8) 146.36,33.84 146,34.2 JKB.23
KSO15: length 7.8
  TOP w0.102: RPE6.7 v1(85.5,27.9) 85.5,28.3 85.09,28.71 UE1.86 ; v1(141.84,36.78) v3(142.76,36.78)
  BOTTOM w0.102: JKB.21 144.4,35.63 144.15,35.89 142.27,35.89 141.84,36.31 v1(141.84,36.78)
KSO16: length 5.8
  TOP w0.102: v1(86.91,27.37) 86.5,26.95 RPE6.5 ; UE1.92 87.49,30.94 v1(87.26,31.17) ; v3(143.1,31.67) 143.1,32.52 v1(143.39,32.82)
  BOTTOM w0.102: v1(143.39,32.82) 143.6,33.02 JKB.20
L_BKLT_CTRL: length 15.2
  TOP w0.102: R8.1 251.43,36.98 251.92,36.5 v2(251.92,29.42) v1(251.92,28.46)
  BOTTOM w0.089: UH1.AU48 181.06,33.08 181.06,33.65 v1(180.67,34.05)
LAN_MDIN0: length 7.1
  TOP w0.089: v1(52.38,41.71) 52.45,41.78 53.08,41.78 53.61,41.25 54.54,41.25 55.31,40.48 55.5,40.48 55.55,40.43 UL1.2
  BOTTOM w0.089: TL1.2 26.91,78.81 26.48,79.24 25.04,79.24 v1(24.96,79.16)
LAN_MDIN1: length 6.3
  TOP w0.089: UL1.5 55.61,39.23 55.56,39.28 55.01,39.28 54.39,39.9 53.77,39.9 53.25,39.38 52.27,39.38 v1(52.17,39.28)
  BOTTOM w0.089: v1(25.93,73.99) 26.11,74.16 26.44,74.16 26.87,73.73 TL1.6
LAN_MDIN2: length 4.5
  TOP w0.089: v1(53.72,38.58) 53.85,38.71 54.33,38.71 54.56,38.48 55.48,38.48 55.53,38.43 UL1.7
  BOTTOM w0.089: TL1.8 26.91,71.19 26.4,71.71 26.08,71.71 v1(25.91,71.54)
LAN_MDIN3: length 3.2
  TOP w0.089: v1(57.08,36.26) 56.96,36.38 56.96,36.96 57.01,37.01 UL1.10
  BOTTOM w0.089: 27.7,66.11 27.08,66.11 26.62,66.57 26.03,66.57 v1(25.91,66.46)
LAN_MDIP0: length 7.3
  TOP w0.089: UL1.1 55.59,40.83 55.54,40.78 55.43,40.78 54.67,41.55 53.73,41.55 53.2,42.08 52.59,42.08 v1(52.38,42.29)
  BOTTOM w0.089: v1(24.96,79.74) 25.15,79.54 26.37,79.54 26.91,80.08 TL1.1
LAN_MDIP1: length 6.5
  TOP w0.089: v1(52.17,39.86) 52.35,39.68 53.12,39.68 53.64,40.2 54.52,40.2 55.13,39.58 55.51,39.58 55.56,39.63 UL1.4
  BOTTOM w0.089: v1(25.91,74.66) 26.11,74.46 26.37,74.46 26.91,75 TL1.5
LAN_MDIP2: length 4.4
  TOP w0.089: UL1.6 55.56,38.83 55.51,38.78 54.69,38.78 54.46,39.01 53.88,39.01 v1(53.72,39.17)
  BOTTOM w0.089: v1(25.91,72.12) 26.03,72.01 26.45,72.01 26.91,72.46 TL1.7
LAN_MDIP3: length 3.5
  TOP w0.089: UL1.9 56.61,37.03 56.66,36.98 56.66,36.43 v1(56.5,36.26)
  BOTTOM w0.089: v1(25.92,67.29) 25.92,67.04 26.08,66.87 26.59,66.87 27.11,67.38 TL1.11
LAN_WAKE#: length 7.2
  BOTTOM w0.102: UH1.BG44 188.65,34.6 189.45,33.81 190.34,33.81 190.65,33.49 191.61,33.49 191.82,33.7 RH11.2 192.61,33.73 RH545.1
LANWAKE#: length 2.9
  TOP w0.102: v1(76.29,42.17) 76.29,42.45 75.93,42.81 UE1.35 ; v2(192.72,33.11) 192.87,33.11 v1(193.15,33.39)
  BOTTOM w0.102: RH11.1 192.88,33.12 v1(193.15,33.39)
LANXIN: length 2.8
  TOP w0.102: RL8.2 59.36,43.39 v2(58.66,42.68) 58.21,42.24 UL1.28
LANXIN_R: length 4.7
  TOP w0.102: RL8.1 CL10.1 57.97,45.19 57.97,46.99 58.64,47.66 YL1.1
LANXOUT: length 2.8
  TOP w0.102: RL9.2 56.67,43.36 v2(57.23,42.8) 57.81,42.21 UL1.29
LANXOUT_R: length 2.2
  TOP w0.102: YL1.3 56.84,45.95 56.67,45.78 RL9.1 56.71,44.68 CL11.1
LCD_BRIGHTNESS: length 3.2
  TOP w0.102: v1(256.08,43.91) 255.84,43.67 RP2.2
  BOTTOM w0.102: v1(256.08,43.91) 255.82,43.65 JEDP1.27 v2(253.82,43.65)
LCD_CBL_DET#: length 2.9
  TOP w0.102: v1(254.1,50.52) 253.61,50.02 TC104.1
  BOTTOM w0.102: JEDP1.14 254.47,50.15 v1(254.1,50.52)
LCD_TST: length 10.2
  TOP w0.102: v1(82.31,40.33) 81.92,40.73 81.92,42.1 79.97,44.04 79.5,44.04 79.09,44.45 UE1.26 ; RP2.6 253.71,44.17 253.23,44.65 252.92,44.65 D3.3 252.64,45.31 252.8,45.47 v1(253.3,45.47)
  BOTTOM w0.102: v1(253.3,45.47) 252.58,45.47 v2(252.54,45.51)
LCD_TST_C: length 10.5
  TOP w0.102: RP2.3 254.91,44.17 254.71,44.37 254.71,45.11 253.49,46.33 v2(253.49,48.79) 253.49,49.18 254.56,50.25 254.56,51.4 v1(254.11,51.84)
  BOTTOM w0.102: JEDP1.10 254.42,52.15 v1(254.11,51.84)
LCD_VCC_TEST_EN: length 24.2
  TOP w0.102: D4.3 250.95,46.21 v2(250.17,45.43) 249.82,45.08 249.82,41.78 251.18,40.41 251.18,36.91 251.69,36.4 251.69,31.95 v1(251.51,31.77) ; v1(87.5,32.98) 87.5,33.32 87.82,33.64 87.82,36.34 89.09,37.61 UE1.113
LCDVDD_EN: length 4.2
  TOP w0.102: v2(255.04,45.9) 254.34,46.6 D4.1 254.34,47.25 R10.1 255.96,47.84 256.16,47.63 U1.4
LDO1_CAP:
  vias: v2(25.6,18.31)
LDO2_CAP:
  vias: v2(28.52,12.74)
LED0: length 5.5
  TOP w0.102: UL1.27 58.61,42.03 60.01,43.42 60.01,44.92 T47.1
LED1: length 4.6
  TOP w0.102: UL1.25 59.41,41.87 59.47,41.93 59.72,41.93 61.05,43.27 61.35,43.27 62.29,44.21 T45.1
LG1_CHG:
  vias: v1(246.28,45.16) v1(246.91,45.16) v1(250.29,43.25) v1(250.88,43.25) v1(264.62,50.93) v1(265.05,51.36) v2(250.75,44.02)
LG2_CHG: length 1.4
  TOP w0.127: v1(242.11,51.54) v3(243.52,51.54)
  vias: v1(241.49,51.55) v1(263.46,51.62) v1(263.89,52.03)
LG_1.2V: length 0.9
  TOP w0.127: v3(34.28,44.88) 34.66,44.5 v1(35.05,44.5)
  vias: v1(34.19,50.64) v1(34.78,50.66) v1(35.53,44.1)
LG_+1.05V: length 4.5
  TOP w0.508: v1(134.24,47.84) 133.78,47.37 v3(133.78,45.58) 133.76,45.57 v1(133.76,44.36)
  BOTTOM w0.508: v1(134.24,47.84) 134.31,47.77 PQH01.6
LID_CL_SIO#: length 22.1
  TOP w0.102: v1(76.89,31.32) 77.09,31.12 UE1.66 77.09,28.7 76.9,28.51 75.66,28.51 74.41,27.27 73.55,27.27 73.19,26.91 CE19.1 RE25.2 ; v1(251.94,37.06) 251.77,37.24 251.77,39.39 252.37,40 D5.1 ; v1(265.56,36.87) v3(266.52,36.87) 268.76,36.87 272.17,33.46 272.94,33.46 R22.1
LID_CLOSE#: length 3.5
  TOP w0.102: v3(272.64,31.7) 272.38,31.7 v1(272,32.08) 271.87,32.21 CC300.1 R22.2
  BOTTOM w0.102: JIOB1.18 v1(272,32.08)
LINE1-L_C: length 3.2
  TOP w0.127: v1(26.82,23.14) 26.82,23.29 v2(26.45,23.66)
  TOP w0.254: CA32.2 v1(26.82,23.14)
  TOP w0.305: RA28.1 23.79,16.24 22.59,16.24 v1(22.35,16.49)
LINE1-L_R: length 3
  TOP w0.254: CA33.2 v1(28.09,23.12)
  TOP w0.305: v1(21.89,15.94) 22.24,15.59 v2(22.96,15.59) 23.24,15.31 RA32.1
LINE1_L:
  vias: v2(27.79,20.01)
LINE1_R:
  vias: v2(29.58,20.18)
LM393_P: length 55.6
  TOP w0.102: PUS01.8 33.01,122.66 33.13,122.78 33.71,122.78 34.12,123.19 36.28,123.19 PDS01.1 36.9,123.19 PCS01.2 38.12,122.56 v1(38.3,122.75) ; v1(46.02,57.53) 46.48,57.07 47.36,57.07 48.04,56.39 48.04,48.92 v2(47.61,48.48) 47.13,48 46.86,48 45.13,46.27 45.13,43.71 45.76,43.08 45.76,41.91 43.27,39.42 39.96,39.42 PRB37.2 39.66,38.03 PCB44.2 37.32,36.72 PUB02.5
  BOTTOM w0.102: v1(38.3,122.75) 38.81,123.25 38.81,124.07 38.05,124.83 37.25,124.83 36.83,125.25 34.43,125.25 34.13,124.94 34.13,121.26 33.57,120.7 33.57,119.75 33.26,119.44 31.78,119.44 31.1,118.77 31.1,115.78 31.37,115.51 31.37,115.07 PR50.1
LOM_TCT: length 2
  TOP w0.102: CL12.1 v3(27.29,76.28)
  TOP w0.305: v1(26.01,77.06) 26.07,77 CL12.1
  vias: v1(25.62,77.51) v1(26.26,69.98) v1(26.26,69.34)
LX1_CHG: length 2.1
  TOP w0.127: v3(247.14,40.97) v1(246.29,40.97)
  TOP w0.508: PRB17.1 v1(244.06,47.09)
  vias: v1(245.85,41.4) v1(263.17,48.49) v1(263.75,48.49)
LX2_CHG: length 0.9
  TOP w0.127: v1(240.67,48.97) v3(241.61,48.97)
  vias: v1(240.67,49.55) v1(261.67,51) v1(261.67,50.41) v1(262.97,52.07) v1(263.36,52.51)
LX2P_CHG:
  vias: v1(237.03,48.02) v1(237.33,49.72) v1(237.33,49.14) v1(237.33,48.55) v1(237.66,48) v1(237.96,49.72) v1(237.96,49.14) v1(237.96,48.55) v1(238.02,47.46) v1(238.27,48) v1(238.57,49.72) v1(238.57,49.14) v1(238.57,48.55) v1(238.63,47.46) v3(239.01,48)
LX_1.0VS_VGAP: length 2.3
  BOTTOM w0.127: v2(200.48,79.2) 200.89,78.79 202.64,78.79
LX_1.2V: length 5
  TOP w0.127: v1(39.69,54.06) v2(39.69,54.88)
  TOP w0.762: 36.11,49.68 35.97,49.55 35.97,46.43 35.36,45.82
  vias: v1(35.62,44.94) v1(36.06,44.52) v1(36.38,51.18) v1(36.64,50.64)
LX_1.8VALW: length 1.9
  BOTTOM w0.127: PR1804.1 201.66,70.81 v2(201.18,70.33)
LX_3V: length 1.1
  TOP w0.127: v1(206.91,52.78) v3(206.91,51.73)
  vias: v1(206.91,53.41)
LX_5V: length 4
  TOP w0.127: v1(122.31,50.63) v3(122.31,51.34)
  BOTTOM w0.254: PU501.6 124.53,55.88 124.64,55.76 124.64,53.98 124.98,53.65 PU501.19
  vias: v1(122.95,50.63)
LX_+1.05V: length 6.3
  TOP w0.762: 135.04,45.91 135.04,47.42 135.79,48.18 v3(136.65,48.18) 138.16,48.18 139.1,47.23
  vias: v1(135.13,45.12) v1(135.13,44.49) v1(139.84,47) v1(140.42,47)
LX_VCCIO: length 0.9
  TOP w0.127: v1(50.43,116.64) v3(50.43,115.72)
M2_SSD_DETECT: length 6.6
  TOP w0.102: RS2.1 v1(24.85,32.14)
  BOTTOM w0.102: UH1.AJ43 177.79,35.53 177.79,36.4 v1(177.67,36.51) ; v1(24.85,32.14) 24.37,31.66 23.19,31.66 22.37,32.48 JSSD1.69
MASK_SATA_LED#: length 23.4
  TOP w0.102: UE1.56 75.8,34.41 76.79,35.4 77.18,35.4 78.88,37.11 78.88,38.23 79.25,38.6 81.02,38.6 81.35,38.27 81.35,36.96 81.01,36.63 81.01,33.92 79.75,32.66 v1(79.75,31.18) ; v1(170.36,30.95) v2(170.93,30.95)
  BOTTOM w0.102: Q22.2 171.87,28.54 171.48,28.93 RC224.1 171.48,30.32 170.84,30.95 v1(170.36,30.95)
MCT:
  vias: v1(17.86,82.83) v1(17.85,82.14) v3(17.87,80.33)
MCT0: length 3
  TOP w0.102: v2(20.49,68.24) 20.07,68.65 v1(19.84,68.65)
  TOP w0.508: RL14.2 v1(19.84,68.65)
  BOTTOM w0.508: TL1.15 v1(19.84,68.65)
MCT1: length 3
  TOP w0.102: v1(19.84,69.92) 20.05,69.92 v2(20.43,70.31)
  TOP w0.508: RL15.2 v1(19.84,69.92)
  BOTTOM w0.508: TL1.16 v1(19.84,69.92)
MCT2: length 3.1
  TOP w0.102: v1(19.84,76.27) v2(20.69,76.27)
  TOP w0.508: v1(19.84,76.27) RL19.2
  BOTTOM w0.508: TL1.21 v1(19.84,76.27)
MCT3: length 3.2
  TOP w0.102: v1(19.84,77.54) 20.41,77.54 v2(20.7,77.84)
  TOP w0.508: RL20.2 v1(19.84,77.54)
  BOTTOM w0.508: 18.33,77.54 v1(19.84,77.54)
ME_FWP: length 51.3
  TOP w0.102: RE19.1 82.45,27.76 v1(82.32,27.89) 82.32,28.4 82.69,28.77 82.69,29.54 UE1.80 ; v1(213.41,29.82) 213.41,30.06 214.59,31.24 214.59,36.28 214.26,36.62 212.67,36.62 211.39,37.9 211.39,42.19 209.76,43.82 209.76,45.19 210.11,45.53 210.11,46.62 209.32,47.41 209.32,50.28 208.79,50.81 208.79,55.67 v3(208.45,56.01) v1(206.66,57.8)
  BOTTOM w0.102: v1(206.66,57.8) 205.89,58.57 199.35,58.57 198.37,59.56 192.25,59.56 RH16.1
ME_SUS_PWR_ACK: length 10.6
  TOP w0.102: v1(183.56,39.36) 184.01,39.81 184.5,39.81 185.19,39.11 187.26,39.11 187.47,38.9 188.37,38.9 188.97,39.5 v2(189.64,39.5) 190.02,39.5 RH506.1
  BOTTOM w0.089: UH1.BC37 183.96,38 183.63,38.33 183.63,39.3 v1(183.56,39.36)
MEC_XTAL1: length 4.7
  TOP w0.102: YE1.1 95.66,43.22 CE3.1 94.83,43.22 94.44,42.83 94.44,42.41 94.09,42.06 93.46,42.06 RE47.2
MEC_XTAL1_R: length 1.6
  TOP w0.102: RE47.1 92.1,41.61 UE1.123
MEC_XTAL2: length 6.9
  TOP w0.102: UE1.125 92.27,42.41 RE45.1 92.93,43.06 93.89,43.06 CE4.1 95.93,44.07 YE1.2
MEM_VDD_CTL: length 14.1
  TOP w0.102: v1(266.96,72.85) 266.96,70.49 266.59,70.12 265.06,70.12 264.39,69.46 v2(260.1,69.46) 259.36,69.46 v1(257.64,67.73)
  BOTTOM w0.102: PRW10.1 v1(266.96,72.85)
  BOTTOM w0.109: 224.97,96.85 225.37,96.45 UV1.L3
MEM_VREF: length 38.8
  TOP w0.381: v1(226.04,92.29) 226.04,91.75 226.59,91.2 v3(229.85,91.2) 231.01,91.2 231.84,90.37 232.69,90.37 233.17,90.85 234.99,90.85 235.15,90.69 242.48,90.69 242.93,90.24 v1(242.93,90.02) ; v1(245.9,89.8) 247.18,91.08 250.7,91.08 251.77,92.15 253.46,92.15 QV21.2 254.17,92.67 254.79,92.06 254.79,91.48 254.97,91.29 257.93,91.29 v1(258.2,91.57)
  BOTTOM w0.381: RV27.1 225.16,91.33 226.04,92.21 v1(226.04,92.29) 226.04,94.21 UV1.L1 ; 242.58,140.56 242.37,140.77 QV20.2
MIC_CAP:
  vias: v2(30.93,20.04)
MODEL_ID: length 10.6
  TOP w0.102: UE1.109 91.6,36.01 91.97,35.63 92.76,35.63 92.86,35.53 93.63,35.53 93.84,35.32 93.84,34.88 93.68,34.72 CE1.1 93.68,34.31 94.09,33.9 96.66,33.9 RE4.2 RE3.2 v2(98.37,33.3)
MSCLK: length 2.5
  TOP w0.102: JDEG1.6 67.96,29.73 68.35,30.12 v2(68.35,30.39) RE55.2
MSDATA: length 3.9
  TOP w0.102: JDEG1.7 68.46,29.62 68.96,30.12 69.66,30.12 v2(69.82,30.28) 69.81,30.29 69.81,30.62 69.67,30.76 RE62.1 RE56.2
NB_MUTE#: length 7.4
  TOP w0.102: RE28.1 96.55,38.44 95.83,39.15 95.83,39.91 95.71,40.04 94.06,40.04 93.51,39.5 92.08,39.5 91.56,40.01 UE1.119
NC_B4: length 5.8
  BOTTOM w0.076: 18.66,130.74 18.76,130.84 19.03,130.84 19.12,130.93 19.81,130.93 UT1.B4
  BOTTOM w0.102: RT45.1 RT86.2 16.04,128.69 16.6,129.26 17.32,129.26 v2(17.66,129.6) 18.1,130.03 18.1,130.18 18.66,130.74
NC_B5: length 3.1
  BOTTOM w0.076: 18.94,129.73 19.25,130.04 19.25,130.33 19.39,130.47 19.81,130.47 UT1.B5
  BOTTOM w0.102: RT46.1 17.93,128.7 17.93,128.72 18.94,129.73
NC_G2: length 4.1
  BOTTOM w0.076: 22.56,132.79 22.56,132.3 UT1.G2
  BOTTOM w0.102: 22.56,132.79 v2(24.02,134.25) 24.17,134.4 24.21,134.4 RT47.1
NCT7718_DXN: length 9.2
  TOP w0.254: Q14.3 114.83,135.14 C22.2 114.43,133.02 114.43,132.83 114.61,132.65 116.68,132.65 v1(116.78,132.76)
  BOTTOM w0.254: U2.3 195.89,56.86 C23.2 195.45,56.91 195.15,56.91 195.06,56.99 195.06,57.63 194.38,58.31 v1(194.36,58.31)
NCT7718_DXP: length 12.4
  TOP w0.254: v1(116.78,132.04) 116.68,132.14 114.39,132.14 113.92,132.62 113.92,132.93 C22.1 113.43,135.09 Q14.2 114.1,136.35 Q14.1
  BOTTOM w0.254: v1(194.36,57.59) 194.55,57.4 v2(194.55,56.78) 194.94,56.4 195.45,56.4 C23.1 195.67,56.21 U2.2
NRB_BIT: length 5.1
  BOTTOM w0.076: 187.28,41.7 187.18,41.6 186.09,41.6 185.97,41.73 185.47,41.73 185.37,41.63 UH1.BE30
  BOTTOM w0.102: RH524.2 189.79,42.34 v2(188.85,42.34) 187.91,42.34 187.28,41.7
NV_ALERT#: length 3.6
  BOTTOM w0.102: RV526.1 223.32,93.08 224.22,93.98 224.22,95.03 224.6,95.41 UV1.M2
NVVDD1_EN: length 81.3
  TOP w0.102: v1(256.47,65.34) 257.18,64.63 v2(257.18,62.85) 257.18,61.06 256.41,60.3 254.58,60.3 253.47,59.18 247.45,59.18 246.07,57.8 212.64,57.8 209.7,60.74 202.98,60.74 202.27,61.45 199.53,61.45 198.65,62.33 198.65,63.51 200,64.85 200.56,64.85 201.96,66.25 201.96,69.17 201.78,69.35 201.78,69.87 201.22,70.43 v1(200.22,70.43)
  BOTTOM w0.102: v1(256.47,65.34) 256.38,65.43 PRV06.2 ; 200.02,94.72 RG549.2 CG442.1 198.85,93.8 DG7.1
NVVDD1_PGOOD: length 42.5
  TOP w0.102: v1(252.98,69.65) 252.98,71.95 250.48,74.45 247,74.45 243.19,78.26 243.19,84.86 243.75,85.42 243.75,87.7 241.59,89.87 v1(238.05,89.87) 235.65,89.87 v2(235.17,89.39) 234.65,88.86 v1(232.95,88.86)
  TOP w0.203: v1(254.28,63.57) 254.91,62.94 PRV10.1
  BOTTOM w0.102: UV19.1 232.3,88.86 v1(232.95,88.86) ; DG4.1 238.05,90.41 v1(238.05,89.87)
  BOTTOM w0.203: PUV101.38 253.52,64.84 254.28,64.08 v1(254.28,63.57)
NVVDD_B+:
  vias: v1(212.37,63.7) v1(212.37,62.69) v1(212.85,67.3) v1(212.82,64.27) v1(212.88,66.69) v1(212.89,66.1) v1(212.86,65.46) v1(212.86,64.86) v1(222.25,63.2) v1(222.25,64.09) v1(222.74,62.82) v1(222.76,63.77) v1(222.87,65.75) v1(222.99,64.47) v1(223.11,65.15) v1(223.39,66.09) v1(232.54,63.52) v1(232.71,62.92) v1(232.91,66.13) v1(232.99,65.53) v1(233,64.31) v1(233.11,64.93) v1(233.11,63.69) v1(233.61,65.94) v3(233.5,62.93)
NVVDD_PSI: length 6.3
  TOP w0.102: v1(257.89,63.99) v2(257.89,64.74) ; 225.4,96.57 RV574.1
  TOP w0.109: 225.4,96.57 225.4,98.9 224.97,99.33
  BOTTOM w0.102: PRV08.2 v1(257.89,63.99)
  BOTTOM w0.109: UV1.M7 224.6,99.7 224.97,99.33
NVVDD_VID: length 16.7
  TOP w0.102: PRV13.2 253.66,61.98 252.69,62.94 243.26,62.94 v3(241.46,61.14) v1(239.8,59.48)
  BOTTOM w0.109: UV1.P6 222.9,98.82 222.53,98.45
OTGEN/CMIN_CHG: length 4.1
  TOP w0.203: PUB01.20 269.98,53.28 270.26,53 v2(270.4,53) 270.92,52.49 PRB13.1 272.15,51.69 PRB10.1
OVERT#: length 14.5
  BOTTOM w0.102: v1(212.01,92.16) 211.52,92.66 209.22,92.66 208.84,92.28 206.78,92.28 206.5,92 206.5,91.27 206.16,90.93 206.16,89.62 206.54,89.24 206.54,88.66 206.25,88.37 205.36,88.37 205.06,88.07 RG576.1 ; RG9.1 223.99,92.75 224.48,93.24
  BOTTOM w0.109: 224.48,93.24 224.6,93.36 UV1.M1
OVP_TRIP_P1: length 49.6
  TOP w0.102: v1(33.31,87.01) 34.07,86.25 34.07,85.77 33.87,85.57 33.87,84.61 33.33,84.07 31.32,84.07 31.1,83.86 31.1,81.98 30.8,81.68 v2(30.8,80.97) v1(30.8,80.27)
  TOP w0.254: v1(31.01,47.98) 30.47,47.44 PQS03.2
  BOTTOM w0.102: v1(33.31,87.01) 33.05,86.75 UT4.E10 ; v1(31.01,47.98) 31.01,50.92 31.44,51.35 32.06,51.35 33.16,52.46 33.16,53.07 34.23,54.14 34.23,58.3 33.13,59.4 31.83,59.4 30.5,60.73 30.5,68.66 28.91,70.25 28.91,78.51 29.67,79.27 29.67,79.98 29.96,80.27 v1(30.8,80.27)
PA_USB2_RBIAS: length 2.6
  TOP w0.102: v1(23.01,123.91) RT43.1 22.75,123.3 22.11,122.67 v2(22.11,122.3)
  BOTTOM w0.102: UT1.H19 23.01,123.9 v1(23.01,123.91)
PANEL_BKEN_EC: length 3.1
  TOP w0.102: RP2.8 v1(253.44,43.17) ; v1(89.43,39.1) 89.55,39.21 UE1.117
  BOTTOM w0.102: v2(252.62,42.66) 253.13,43.17 v1(253.44,43.17)
PB_USB2_RBIAS: length 4.7
  TOP w0.102: v1(21.71,124.55) 21,124.55 20.47,124.03 RT44.1 20.69,123.56 20.97,123.28 20.97,122.13 v2(20.59,121.75)
  BOTTOM w0.102: v1(21.71,124.55) UT1.F19
PBAT_CHG_SMBCLK: length 13.3
  TOP w0.102: PRB16.1 272.44,54.3 v1(272.88,54.3) ; RE9.1 85.89,46.64 UE1.9 85.89,42.88 85.65,42.64 85.65,42.12 85.35,41.82 85.35,40.52 85.62,40.25 86.4,40.25 86.45,40.3 86.45,40.7 v1(86.47,40.71) ; PR42.2 208.89,39.25 209.51,39.88 v2(210.34,39.88) 210.63,39.58 PD5.3 210.28,38.83 210.09,39.02 v1(209.91,39.02)
PBAT_CHG_SMBDAT: length 11.1
  TOP w0.102: PRB14.1 272.49,53.28 v1(272.89,53.68) ; PR37.2 209.62,36.98 v1(209.62,37.54) 210.34,37.54 PD5.2 ; v1(85.83,40.72) 85.84,40.73 85.84,41.62 86.13,41.92 86.13,42.89 86.29,43.05 UE1.8 86.29,46.75 86.44,46.9 86.91,46.9 87.31,47.31 RE8.1
  BOTTOM w0.102: v1(85.83,40.72) 85.84,40.73 85.84,40.92 v2(86.4,41.48)
PBAT_PRES#: length 27
  TOP w0.102: CE16.1 73.56,47.32 73.56,46.98 74.34,46.19 76,46.19 76.28,46.47 77.48,46.47 77.89,46.06 UE1.29 77.89,44.46 79.03,43.32 79.32,43.32 80.93,41.72 v1(80.93,41.33) ; PD6.2 212.34,36.37 211.86,36.86 PR39.2 210.57,36.86 ; v1(210.21,40.4) 210.65,40.4 211.15,39.9 211.15,37.44 210.57,36.86 ; v2(272.63,60.22) 272.92,59.94 PC14.1 272.61,58.98 269.98,58.98 269.19,59.77 PQB05.1 268.43,60.22 268.39,60.26 PRB25.2 267.97,59.18 v1(267.84,59.05) ; 210.57,36.86 PR41.1
PCH_AZ_BITCLK: length 10.4
  BOTTOM w0.089: 187.07,51.01 187.07,50.86 186.78,50.57 185.98,50.57 185.56,50.98 185.11,50.98 UH1.BD11
  BOTTOM w0.102: RP50.5 190.54,56.36 190.34,56.16 190.34,55.43 190.06,55.15 RH739.1 189.47,54.9 189.47,54.04 188.57,53.14 188.29,53.14 187.07,51.92 187.07,51.01
PCH_AZ_CODEC_BITCLK: length 1.7
  BOTTOM w0.102: RP50.4 192.93,56.36 v1(193.48,56.91)
  vias: v1(35.26,15.29) v2(34.89,15.68)
PCH_AZ_CODEC_SDIN0: length 3.7
  TOP w0.102: v1(38.56,16.69) v2(39.41,16.69)
  TOP w0.203: RA7.1 v1(38.56,16.69)
  BOTTOM w0.076: v1(184.92,49.72) 185.25,50.05 185.28,50.17 185.25,50.33 185.25,50.69 UH1.BE11
PCH_AZ_CODEC_SDOUT: length 2.6
  TOP w0.102: v1(192.71,57.68) v2(192.71,58.5)
  TOP w0.203: v1(34.3,15.61) 34.2,15.71 UA1.4
  BOTTOM w0.102: v1(192.71,57.68) 192.53,57.86 RP50.1
PCH_AZ_CODEC_SYNC: length 2.5
  TOP w0.102: v1(192.68,57.1) v2(191.89,57.1)
  TOP w0.203: v1(34.16,17.88) 34,17.71 UA1.9
  BOTTOM w0.102: v1(192.68,57.1) 192.42,57.36 RP50.2
PCH_AZ_RST#: length 11.2
  BOTTOM w0.089: UH1.BE10 185.41,51.28 185.47,51.35 185.93,51.35 185.93,51.34 186.01,51.34 186.13,51.23 186.13,50.96 186.31,50.78 186.71,50.78 186.88,50.95 186.88,52
  BOTTOM w0.102: 186.88,52 188.9,54.01 188.9,56.73 189.55,57.38 RH746.1 189.95,57.38 190.47,56.86 RP50.6
PCH_AZ_SDOUT: length 17.4
  BOTTOM w0.102: UH1.BF12 186.02,50.05 186.23,49.83 186.65,49.83 186.65,49.84 186.65,49.85 187.03,50.22 187.03,50.23 187.56,50.76 187.56,51.86 188.38,52.69 189.14,52.69 191.08,54.63 191.28,54.63 192.25,55.6 192.96,55.6 193.89,56.53 193.89,57.82 v2(193.47,58.25) 192.74,58.98 RH16.2 CH51.2 190.9,58.84 RP50.8
PCH_AZ_SYNC: length 10.3
  BOTTOM w0.102: UH1.BG13 186.56,50.07 187.31,50.82 187.31,51.89 188.37,52.95 189.07,52.95 v2(191.34,55.21) 191.52,55.39 191.52,57.12 191.28,57.36 RP50.7
PCH_BATLOW#: length 5.1
  BOTTOM w0.102: RT14.2 v1(23.01,136.29) ; RH515.1 189.27,34.35 188.69,34.93 186.68,34.93 186.49,35.12 v1(186.06,35.12) 186.06,34.66 UH1.BF44
PCH_CPU_BCLK_N: length 9.1
  BOTTOM w0.089: UC1.A32 102.85,122.87 102.96,122.87 103.68,123.59 v1(103.68,123.88) ; UH1.C8 164.78,52.38 164.78,52.25 164.54,52.01 164.3,52.01 164.13,51.84 163.62,51.84 163.47,51.68 162.95,51.68 162.94,51.67 162.91,51.67
  BOTTOM w0.102: 162.91,51.67 162.16,51.67 161.57,51.08 159.57,51.08 158.97,51.67 158.97,52.14 v1(158.85,52.26)
PCH_CPU_BCLK_P: length 9.3
  BOTTOM w0.089: v1(104.09,123.47) 103.8,123.47 103.02,122.69 102.43,122.69 UC1.B31 ; 162.91,51.88 162.94,51.88 162.94,51.87 163.39,51.87 163.54,52.03 164.05,52.03 164.23,52.2 164.46,52.2 164.59,52.33 164.59,52.42 164.54,52.46 UH1.B8
  BOTTOM w0.102: 162.91,51.88 162.08,51.88 161.48,51.28 159.65,51.28 159.18,51.76 159.18,52 v1(159.44,52.26)
PCH_CPU_PCIBCLK_N: length 8.3
  BOTTOM w0.089: UH1.B6 164.11,53.68 163.56,53.68 163.55,53.69 163.53,53.69
  BOTTOM w0.102: v1(157.82,51.84) 157.93,51.95 157.93,52.57 158.64,53.28 162.44,53.28 162.85,53.69 163.53,53.69 ; UC1.C36 101.33,124.85 v1(101.39,124.79)
PCH_CPU_PCIBCLK_P: length 7.5
  BOTTOM w0.089: UH1.A6 163.8,53.49 163.56,53.49 163.55,53.48 163.53,53.48
  BOTTOM w0.102: v1(158.4,51.84) 158.13,52.11 158.13,52.48 158.73,53.08 162.53,53.08 162.93,53.48 163.53,53.48 ; v1(100.73,125.25) 100.85,125.12 UC1.D35
PCH_DPWROK: length 10.5
  TOP w0.102: v3(183.12,35.89) 182.8,35.89 v1(182.53,35.62) 182.22,35.31 182.22,34.56 182.25,34.53 182.25,34.21 182.22,34.18 182.22,34.01 182.94,33.29 183.41,33.29 183.6,33.09 183.6,30.87 RH672.2 183.27,30.48 183.96,29.79 183.96,29.45 183.73,29.22 182.7,29.22 RH90.2
  BOTTOM w0.089: UH1.AW41 182.78,35.87 v1(182.53,35.62)
PCH_JTAG_TCK1: length 2.6
  TOP w0.102: RC84.1 177.48,53.45 v1(177.27,53.66) 176.85,54.08 TPC3.1
  BOTTOM w0.076: v1(177.27,53.66) 177.21,53.72 177.21,54.13 177.31,54.36 UH1.AJ3
PCH_PCIE_WAKE#: length 5.4
  BOTTOM w0.102: UH1.BB47 184.37,32.54 184.37,29.42 RH4.2 184.08,28.53 RH453.1 183.5,27.91 v2(183.34,27.91)
PCH_PLTRST#: length 11.9
  BOTTOM w0.102: UH1.AV29 v1(181.88,41.46) ; v1(198.46,36.07) 197.51,35.13 v2(196.85,35.13) 196.36,34.63 196.36,33.82 196.06,33.53 RH742.1 196.06,32.69 195.67,32.29 195.67,30.63 195.51,30.48 UH3.2 UH3.1 196.16,29.51 195.95,29.3 194.22,29.3 193.84,29.68 CH222.1
PCH_PRIM_EN: length 73
  TOP w0.102: RC442.2 95.56,25.86 95.76,26.05 96.95,26.05 97.21,26.3 97.21,26.91 98.01,27.71 103.63,27.71 104.11,27.23 106.27,27.23 116.89,37.85 121.59,37.85 123.23,39.49 129.45,39.49 130.58,38.35 133.25,38.35 133.53,38.07 135.01,38.07 135.27,37.81 137.49,37.81 137.74,38.06 PRH14.1 138.02,38.75 142.6,38.75 143.7,37.65 151.12,37.65 152.32,36.45 v1(152.59,36.45) ; v1(169.25,38.53) 169.25,38.24 RZ21.1
  BOTTOM w0.102: QH10.2 194.39,61.75 195.69,63.05 v1(195.69,64.26) ; PR1806.1 198.17,62.76 198.76,62.18 v1(199.44,62.18)
PCH_PWROK: length 30.1
  TOP w0.102: v1(141.33,32.88) 141.33,32.49 138.99,30.15 v3(137.2,30.15) 133.87,30.15 132.94,31.08 RH94.1 132.32,31.9 132.08,32.15 UH14.4
  BOTTOM w0.102: v1(141.33,32.88) 143.18,31.02 151.4,31.02 152.32,31.95 152.32,35.59 v1(153.18,36.45) ; UH1.AY42 183.48,35.47 v1(183.59,35.58)
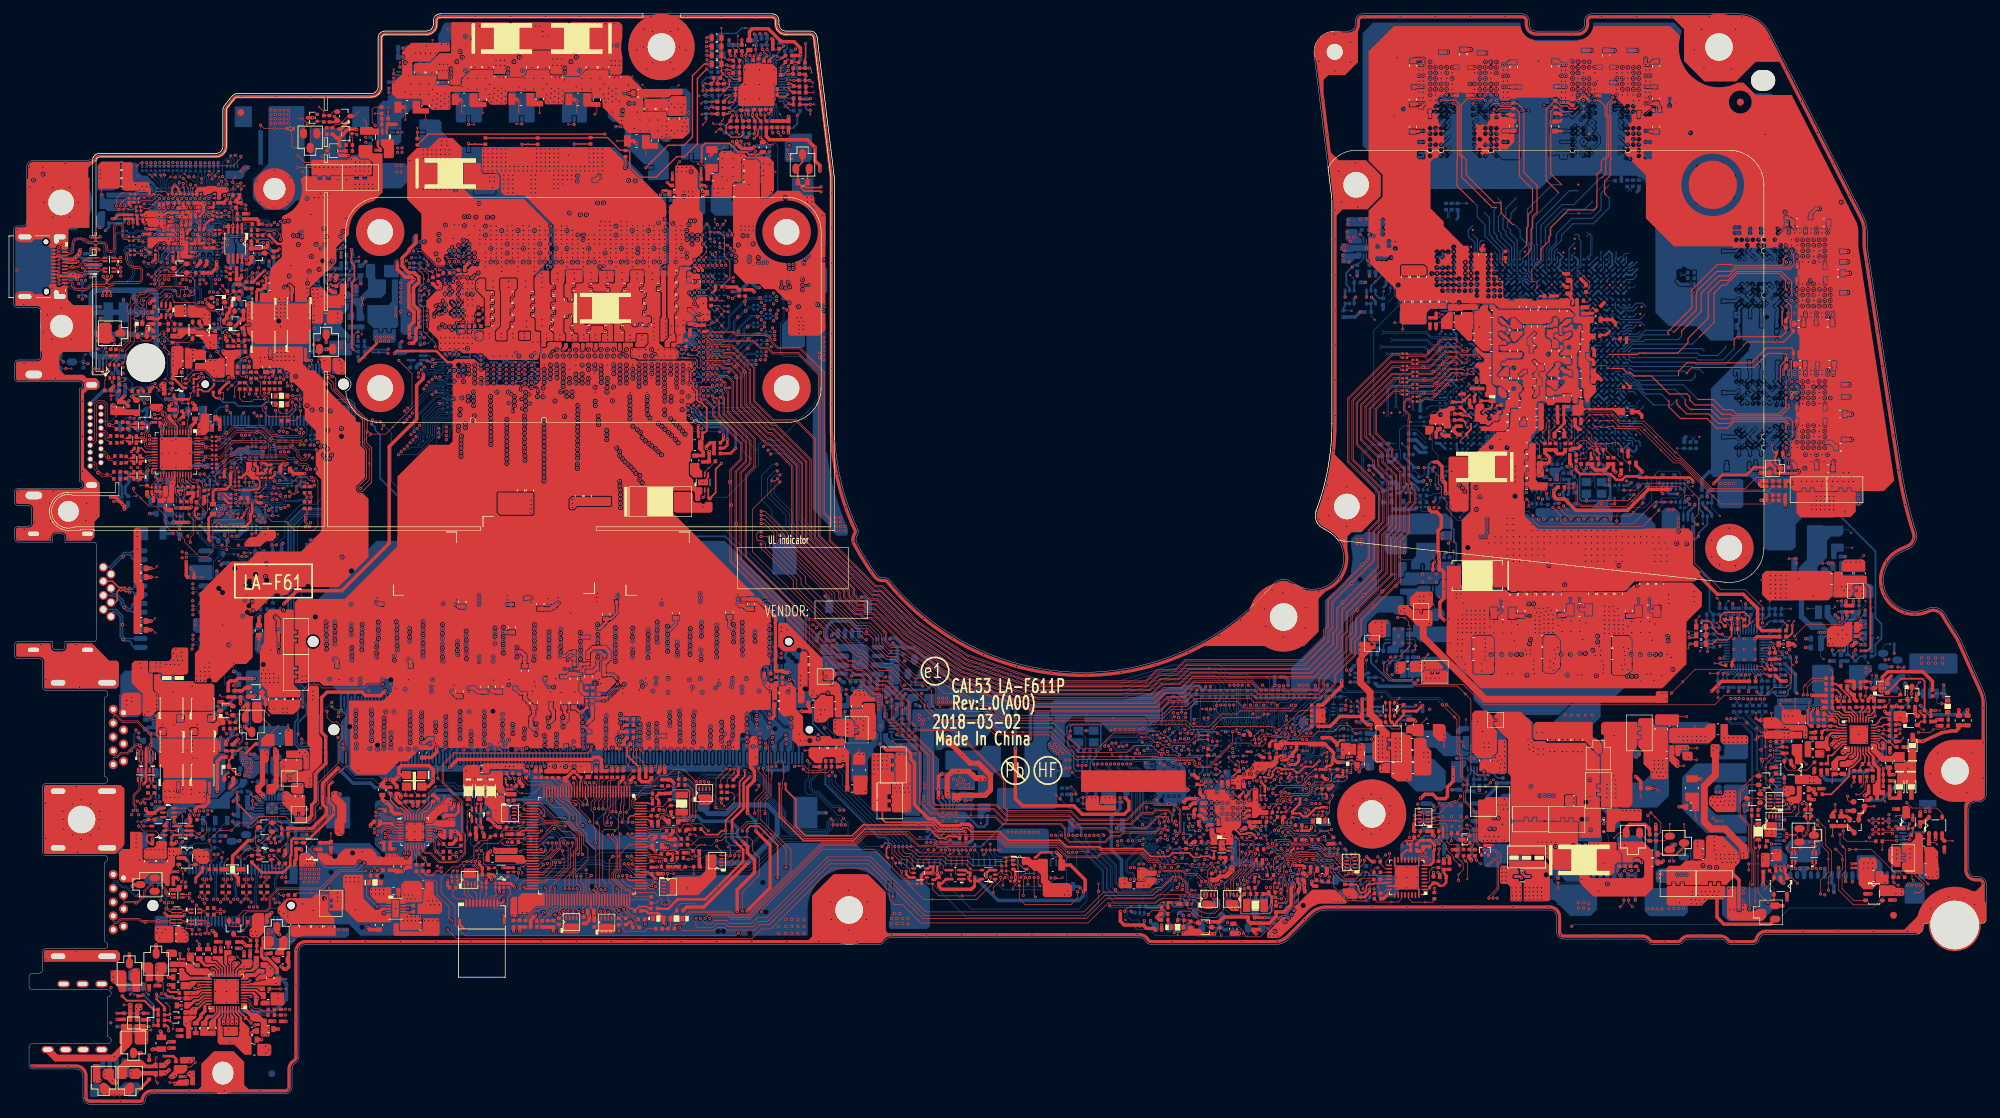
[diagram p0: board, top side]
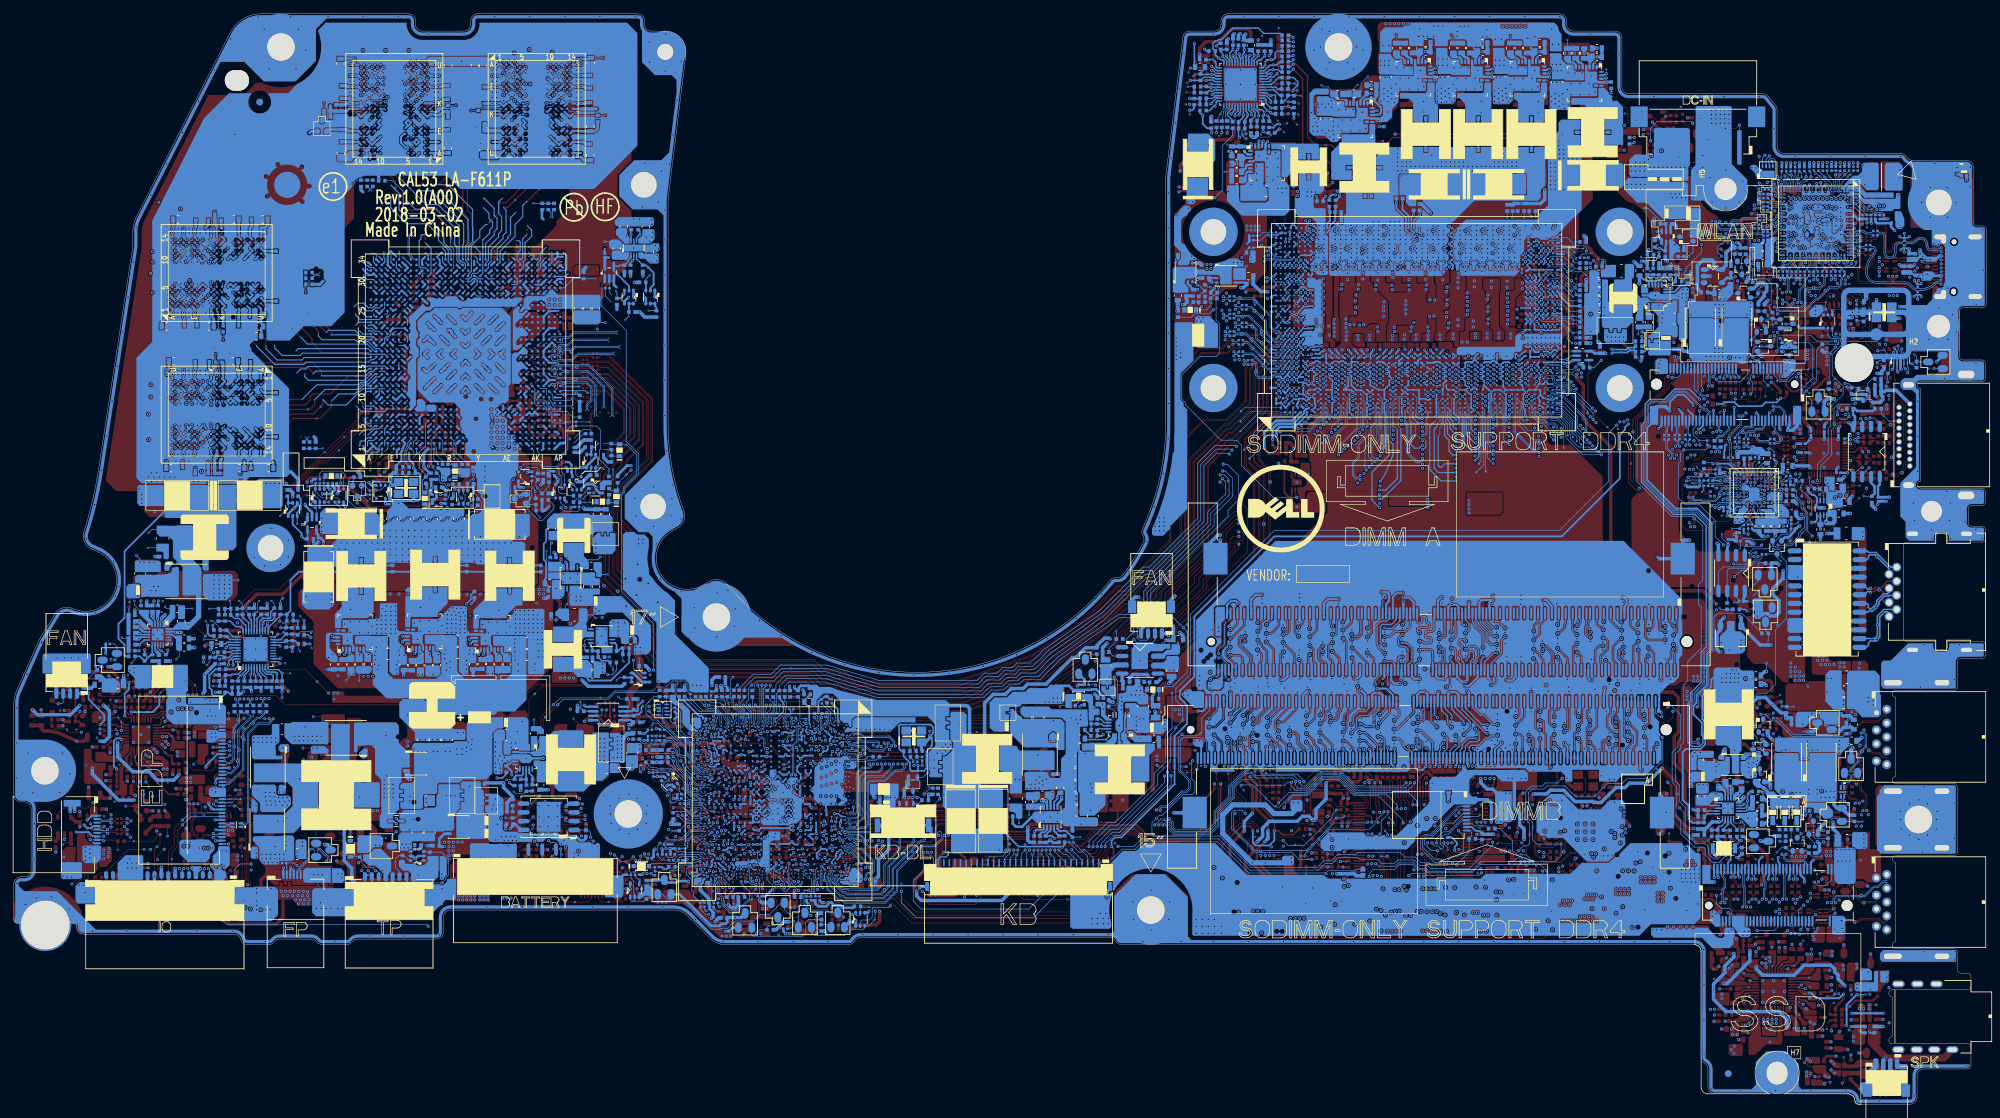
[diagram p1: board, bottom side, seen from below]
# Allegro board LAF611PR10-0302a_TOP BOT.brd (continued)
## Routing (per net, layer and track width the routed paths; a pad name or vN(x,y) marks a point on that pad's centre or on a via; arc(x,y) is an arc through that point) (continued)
PCH_RSMRST#: length 21.6
  TOP w0.102: CH212.1 182.26,30.91 182.26,31.79 RH503.1 182.46,32.51 182.26,32.71 RC86.1 ; CH212.1 182.49,29.99 RH700.2 182.76,29.73 v1(183.38,29.73) ; CH212.1 182.82,30.67 RH672.1 ; UE1.27 78.69,44.34 79.3,43.74 79.59,43.74 81.43,41.9 81.43,40.53 82.91,39.06 82.91,38.04 84.21,36.73 v1(84.21,31.54)
PCH_RSMRST#_R: length 4
  TOP w0.102: v2(183.29,32.9) 183.04,32.66 RH503.2 183.04,31.65 v1(182.77,31.37)
  BOTTOM w0.089: UH1.BA47 183.33,32.72 183.33,32.41 182.77,31.85 v1(182.77,31.37)
PCH_RTCRST#: length 100.4
  TOP w0.102: CH53.1 176.78,26.11 177.9,24.99 v1(177.9,24.71) 177.9,24.69 178.36,24.23 180.34,24.23 183.41,27.3 183.83,27.3 185.22,28.7 185.22,31.05 185.44,31.28 185.44,31.88 185,32.32 v1(185,32.95) ; v1(156.94,30.8) v2(156.94,31.93)
  BOTTOM w0.102: CLRP1.1 90.97,34.04 91.22,33.78 95.21,33.78 95.53,33.46 106.68,33.46 111.2,37.98 122.02,37.98 123.11,36.9 125.02,36.9 127.16,34.76 127.16,33.94 128.41,32.69 131.27,32.69 132.13,31.83 132.99,31.83 137.81,27.01 154.84,27.01 156.94,29.11 v1(156.94,30.8) ; v1(175.59,26.26) 175.59,26.82 175.36,27.05 QH7.1 174.82,26.26 175.26,25.82 176.16,25.82 176.38,25.6 RH84.2 177.37,25.25 v1(177.9,24.71) ; UH1.BE47 185.19,33.14 v1(185,32.95)
PCH_RTCX1: length 15.6
  TOP w0.102: v1(180.1,32.19) 180.1,31.85 RH70.1 179.57,30.67 CH45.1 179.81,29.84 YH1.1
  BOTTOM w0.102: v1(180.1,32.19) 180.1,31.96 178.89,30.76 178.89,29.86 180.78,27.97 181.73,27.97 182.46,28.7 182.46,28.9 v2(182.55,28.99) 182.55,29.4 182.7,29.54 182.7,29.98 183.3,30.58 183.3,31.97 UH1.BA49
PCH_RTCX2: length 15.2
  TOP w0.102: v1(178,31.15) 178.17,31.32 RH70.2 178.94,31.02 CH46.1 178.94,29.35 YH1.2
  BOTTOM w0.102: UH1.BA48 183.73,32.43 183.8,32.36 183.8,32.1 183.53,31.83 183.53,30.48 182.96,29.91 182.96,29.45 182.89,29.39 182.89,28.8 181.83,27.74 180.68,27.74 178.85,29.58 178.66,29.58 v2(178.55,29.69) 178.55,30.59 v1(178,31.15)
PCH_SATA_LED#: length 22.3
  TOP w0.102: R77.2 40.94,30.56 v2(43.02,30.56) 44.98,30.56 v1(45.69,31.26) ; v1(158.53,28.71) 165.51,28.71 165.98,29.18 166,29.18 166.03,29.21 RH512.1
  BOTTOM w0.102: UH1.AK48 177.75,32.9 177.44,32.59 177.44,31.58 v1(177.02,31.16) ; v1(158.53,28.71) 158.76,28.48 160.95,28.48 161.16,28.27 161.16,27.08 161.59,26.65 162.64,26.65 162.89,26.4 Q27.2
PCH_SMBCLK: length 33.3
  TOP w0.102: US1.1 193.54,48.12 v1(193.42,48)
  BOTTOM w0.102: JDIMM2.253 112.33,57.04 113.46,55.9 113.46,53.9 114.04,53.32 116.18,53.32 v1(116.37,53.5) 116.81,53.06 116.81,48.24 115.36,46.79 115.36,45.73 115.78,45.32 116.37,45.32 118.52,43.17 119.46,43.17 v1(120.07,42.56) ; QH4.1 190.94,47.99 192.86,47.99 RH463.2 193.41,47.99 v1(193.42,48)
  BOTTOM w0.109: v1(111.03,65.23) 111.03,65.79 110.21,66.61 110.21,69.4 109.32,70.28 JDIMM1.253
PCH_SMBDATA: length 33.8
  TOP w0.102: US1.4 195.04,48.69 194.64,48.29 v1(194.64,48.1)
  BOTTOM w0.102: QH4.4 190.91,45.48 191.31,45.88 191.31,46.38 190.17,47.52 190.17,48 190.38,48.22 192.39,48.22 192.58,48.41 193.44,48.41 194.03,49 194.63,49 RH462.2 194.83,48.89 194.83,48.28 v1(194.64,48.1) ; JDIMM2.254 112.58,51.02 112.81,51.25 112.81,52.43 113.47,53.09 116.15,53.09 v1(116.37,52.87) 116.59,52.65 116.59,48.34 115.13,46.88 115.13,45.64 115.68,45.09 116.27,45.09 118.42,42.94 119.37,42.94 119.49,42.82 v1(119.49,42.56)
  BOTTOM w0.109: v1(111.03,64.59) 110.62,64.59 109.57,63.55 JDIMM1.254
PCH_SPI_CLK: length 3.7
  TOP w0.102: v1(190.34,32.9) 190.34,32.42 RH104.1
  BOTTOM w0.102: UH15.6 UH4.6 212.79,41.42 RH708.2 v1(214.17,41.42)
PCH_SPI_CLK_R: length 7.1
  TOP w0.102: v1(189,33.11) 189,32.51 RH104.2 ; v1(197.33,34.21) 196.96,34.21 196.77,34.02 RTPM3.1 ; v1(181.88,32.57) 181.8,32.5 180.61,32.5 RH738.1 180.19,33.13 179.93,33.39 179.32,33.39 v2(178.71,32.78)
  BOTTOM w0.089: UH1.AW47 181.88,32.84 v1(181.88,32.57)
PCH_SPI_CLK_TPM: length 1.3
  TOP w0.102: UTPM1.19 197.69,33.57 RTPM3.2
PCH_SPI_CS2#: length 22.4
  TOP w0.102: UTPM1.20 198.96,33.08 196.37,33.08 195.85,33.6 v2(195.62,33.6) 195.13,33.6 194.16,32.63 192.52,32.63 191.72,33.43 191.72,34.42 190.68,35.46 189.46,35.46 188.52,36.4 185.68,36.4 185.06,35.79 184.3,35.79 183.46,36.63 183.03,36.63 182.35,37.31 181.8,37.31 v1(181.42,37.69)
  BOTTOM w0.089: UH1.AT40 180.97,37.25 v1(181.42,37.69)
PCH_SPI_CS#: length 5.7
  BOTTOM w0.089: v1(181.81,31.36) 181.81,31.67 182.63,32.49 182.63,32.96 UH1.AY47
  BOTTOM w0.102: UH15.1 UH4.1 202.61,39.69 RH74.2 202.24,39.67 201.9,39.34 v1(201.9,38.61)
PCH_SPI_HOLD#: length 8.1
  TOP w0.102: v1(210.2,41.57) 209.59,40.96 v2(208.69,40.96) 208.59,41.06 205.77,41.06 205.64,40.93 205.05,40.93 204.93,40.81 RPH5.1
  BOTTOM w0.102: UH4.7 UH15.7 210.8,40.96 v1(210.2,41.57)
PCH_SPI_HOLD#_R: length 10.4
  TOP w0.102: v1(209.21,34.57) 208.32,35.46 208.32,35.81 207.28,36.85 v2(207.28,36.96) 207.28,37.37 206.19,38.47 RH455.2 206.19,39.04 206.16,39.06 RH78.2 206.16,39.85 205.96,40.05 203.78,40.05 203.38,40.46 RPH5.8
  BOTTOM w0.102: v1(184.14,33.63) 184.07,33.7 UH1.BA46
PCH_SPI_SI: length 9.2
  TOP w0.102: RPH5.3 204.92,41.81 205.16,42.05 206.2,42.05 207.96,43.81 v3(208.48,43.81) 208.74,43.81 209.31,44.37 v1(209.31,44.61)
  BOTTOM w0.102: UH4.5 UH15.5 210.41,43.5 v1(209.31,44.61)
PCH_SPI_SI_R: length 24.1
  TOP w0.102: v1(202.7,41.76) 202.74,41.81 RPH5.6 ; RC264.2 180.82,36.54 181.03,36.33 181.79,36.33 v1(181.95,36.5) 182.44,36.5 182.69,36.24 183.47,36.24 184.18,35.53 185.19,35.53 185.76,36.1 188.31,36.1 189.31,35.1 190.44,35.1 190.89,34.65 190.89,33.65 192.28,32.27 194.55,32.27 v2(194.78,32.5) 194.98,32.7 196.58,32.7 RTPM2.1 196.57,32.31 195.69,32.31 195.2,31.81 v1(195.2,31.15) ; RH735.2 203.51,39.06 v1(203.24,38.8)
  BOTTOM w0.089: UH1.AU41 181.62,36.16 v1(181.95,36.5)
PCH_SPI_SI_TPM: length 1.3
  TOP w0.102: RTPM2.2 197.74,32.57 UTPM1.21
PCH_SPI_SO: length 4.1
  TOP w0.102: RPH5.2 205.34,41.31 v1(205.44,41.4) 205.63,41.59 v3(206.13,41.59)
  BOTTOM w0.102: v1(205.44,41.4) 205.63,41.4 205.73,41.3 205.73,41.1 205.6,40.96 UH15.2 UH4.2
PCH_SPI_SO_R: length 21.5
  TOP w0.102: v1(202.72,41.18) 202.85,41.31 RPH5.7 ; v1(196.8,31.17) 196.84,31.13 RTPM1.1 196.76,30.51 v2(195.68,29.44) 193.04,29.44 190.95,31.53 190.95,33.1 190.54,33.51 190.54,34.5 190.29,34.75 189.16,34.75 188.09,35.82 185.85,35.82 185.26,35.23 183.9,35.23 183.31,34.64 183.31,34.21 183.11,34.01 v1(183.11,33.77)
  BOTTOM w0.089: v1(183.11,33.77) 183.11,33.86 UH1.BA45
PCH_SPI_SO_TPM: length 2.6
  TOP w0.102: UTPM1.24 198.59,31.07 198.04,30.51 RTPM1.2 197.54,30.73 197.54,31.29 v2(197.32,31.51)
PCH_SPI_WP#: length 4
  TOP w0.102: v2(206.16,43.65) 206.16,43.22 v1(205.45,42.51) 205.06,42.51 204.86,42.31 RPH5.4
  BOTTOM w0.102: UH4.3 UH15.3 205.18,42.23 v1(205.45,42.51)
PCH_SPI_WP#_R: length 21
  TOP w0.102: v1(209,32.4) v2(209,33.23) 209.69,33.92 209.69,34.83 208.78,35.75 RH75.2 209.25,36.4 209.25,37.16 208.83,37.58 207.77,37.58 207.34,38.01 207.34,40.38 207.05,40.68 206.27,40.68 206.03,40.44 204.17,40.44 203.94,40.66 203.94,42.14 203.77,42.31 RPH5.5
  BOTTOM w0.089: UH1.AY48 182.98,32.45 182.36,31.82 182.36,30.14 RC249.1
  BOTTOM w0.102: v1(181.22,31.36) 181.22,30.97 RC249.1
PCH_SRTCRST#: length 8.3
  TOP w0.102: v1(184.71,33.8) 184.72,33.82 v2(184.72,34.38) 184.82,34.48 184.82,34.75 185.01,34.93 185.33,34.93 185.9,35.51 186.31,35.51 186.89,34.92 188.01,34.92 188.57,34.36 CH52.1 188.18,33.54 188.18,32.75 RH83.2
  BOTTOM w0.102: v1(184.71,33.8) 184.98,33.53 UH1.BD46
PCH_TRIGOUT: length 4.6
  BOTTOM w0.089: UH1.AK3 178.15,54.63 178.15,55.59
  BOTTOM w0.102: RH665.1 178.49,58.92 178.49,57.48 178.07,57.06 178.07,55.67 178.15,55.59
PCH_TRIGOUT_R: length 90.3
  TOP w0.102: v1(98.49,115.87) 98.49,115.85 v2(98.9,115.44)
  BOTTOM w0.076: UC1.H23 98.11,116.24 v1(98.49,115.87)
  BOTTOM w0.102: RH665.2 178.19,60.19 178.19,60.85 177.81,61.24 175.4,61.24 174.04,62.59 167.85,62.59 160.21,60.33 145.65,60.33 144.58,61.39 142.74,61.39 141.89,62.24 140.49,62.24 139.85,62.88 137.76,62.88 135.34,65.3 127.68,70.66 121.64,76.7 120.78,76.7 113.16,84.33 113.16,92.38 111.33,94.21 109.61,94.21 v1(109.51,94.1)
PCH_XDP_CLK_N: length 4.4
  TOP w0.102: v1(172.56,57.19) 171.93,57.19 T4938.1
  BOTTOM w0.089: UH1.Y3 173.3,54.72 173.38,54.64 173.5,54.64 173.57,54.71 173.57,55.41 173.79,55.63 173.79,55.92 173.56,56.16 173.19,56.16 172.76,56.59 172.76,56.87 172.77,56.88 172.77,56.98 172.76,56.98
  BOTTOM w0.102: 172.76,56.98 v1(172.56,57.19)
PCH_XDP_CLK_P: length 4.5
  TOP w0.102: T4939.1 v1(173.15,57.19)
  BOTTOM w0.089: UH1.Y4 173.52,54.45 173.58,54.45 173.76,54.63 173.76,55.33 173.98,55.55 173.98,56 173.64,56.35 173.27,56.35 172.95,56.67 172.95,56.87 172.96,56.88 172.96,56.99 v1(173.15,57.19)
PCIE_PRX_C_DTX_N14: length 3.7
  TOP w0.102: UL1.18 60.35,38.43 60.45,38.33 60.63,38.33 60.99,37.98 60.99,36.97 61.51,36.45 61.51,36.42 61.71,36.22 61.83,36.22 CL2.1
PCIE_PRX_C_DTX_N21: length 2.9
  BOTTOM w0.089: CT16.2 28.57,120.73 28.57,121.1 27.63,122.04 27.63,122.64 UT1.V22
PCIE_PRX_C_DTX_N22: length 2.8
  BOTTOM w0.089: UT1.P22 25.79,122.65 25.79,122.22 25.66,122.09 25.66,121.43 26.02,121.07 26.02,120.74 CT2.2
PCIE_PRX_C_DTX_N23: length 2.7
  BOTTOM w0.089: CT108.2 23.3,120.73 23.3,121.16 23.58,121.44 23.58,122.13 23.48,122.23 23.48,122.65 UT1.K22
PCIE_PRX_C_DTX_N24: length 3
  BOTTOM w0.089: CT110.2 20.76,120.74 20.76,120.9 21.12,121.26 21.25,121.26 21.66,121.66 21.66,122.66 UT1.F22
PCIE_PRX_C_DTX_P14: length 3.8
  TOP w0.102: CL1.1 61.78,36.02 61.62,36.02 v4(61.12,36.52) 60.78,36.86 60.78,37.89 60.55,38.13 60.46,38.13 60.36,38.03 UL1.17
PCIE_PRX_C_DTX_P21: length 3
  BOTTOM w0.089: UT1.V23 27.4,122.5 27.33,122.56 27.21,122.56 27.16,122.51 27.16,122.24 28.38,121.02 28.38,120.73 CT14.2
PCIE_PRX_C_DTX_P22: length 2.8
  BOTTOM w0.089: CT12.2 25.83,120.72 25.83,120.99 25.47,121.35 25.47,122.07 25.32,122.22 25.32,122.54 25.39,122.61 25.51,122.61 25.56,122.56 UT1.P23
PCIE_PRX_C_DTX_P23: length 2.7
  BOTTOM w0.089: UT1.K23 23.72,122.53 23.79,122.6 23.89,122.6 23.95,122.53 23.95,122.23 23.77,122.05 23.77,121.36 23.49,121.08 23.49,120.73 CT109.2
PCIE_PRX_C_DTX_P24: length 3
  BOTTOM w0.089: UT1.F23 21.88,122.51 21.94,122.57 22.05,122.57 22.11,122.5 22.11,122.23 21.85,121.96 21.85,121.58 21.33,121.07 21.2,121.07 20.95,120.82 20.95,120.73 CT111.2
PCIE_PRX_DTX_N9: length 5.8
  BOTTOM w0.089: UH1.G36 166.76,38.76 v1(166.6,38.92)
  BOTTOM w0.102: JSSD1.5 38.37,33.31 38.24,33.17 38.24,32.9 37.92,32.59 37.92,31.4 38.24,31.09 38.24,29.31 v1(38.4,29.15)
PCIE_PRX_DTX_N10: length 6.2
  BOTTOM w0.089: v1(168.17,37.82) 168.17,37.98 UH1.K37
  BOTTOM w0.102: v1(35.25,28.53) 35.07,28.72 35.07,31.3 35.22,31.45 35.22,33.11 35.37,33.26 JSSD1.17
PCIE_PRX_DTX_N11: length 5.6
  BOTTOM w0.089: v1(167.3,37.09) 166.98,37.09 166.82,37.25 166.82,37.41 166.92,37.52 UH1.G38
  BOTTOM w0.102: JSSD1.29 32.37,33.25 32.23,33.1 32.23,32.21 32.05,32.03 32.05,31.31 32.23,31.13 32.23,29.82 v1(32.39,29.66)
PCIE_PRX_DTX_N12: length 5.1
  BOTTOM w0.089: v1(167.71,35.15) 167.62,35.15 UH1.H42
  BOTTOM w0.102: JSSD1.43 28.87,33.28 29.1,33.06 29.1,29.85 v1(28.9,29.66)
PCIE_PRX_DTX_N14: length 1.8
  TOP w0.102: CL2.2 63.41,36.2 63.82,36.2 v1(64.03,36.41)
  BOTTOM w0.089: v1(165.72,33.63) 165.7,33.63 165.7,33.63 165.32,33.63 UH1.D46
PCIE_PRX_DTX_N15: length 3
  BOTTOM w0.089: UH1.F44 166.9,34.5 167.2,34.5 v1(167.47,34.23)
  BOTTOM w0.102: v1(38.97,97.38) 38.77,97.58 38.77,98.08 38.95,98.26 JWLAN1.43
PCIE_PRX_DTX_N21: length 3.2
  BOTTOM w0.102: v1(170.87,35.24) 171.24,35.24 UH1.T43 ; v1(28.9,117.52) 28.71,117.71 28.71,119.42 28.58,119.56 28.58,119.71 CT16.1
PCIE_PRX_DTX_N22: length 5.3
  BOTTOM w0.102: v1(171.26,36.95) 171.39,36.82 UH1.U40 ; v1(27.33,116) 27.12,116.2 27.12,117.82 26.34,118.6 26.34,119.24 26.04,119.55 26.04,119.71 CT2.1
PCIE_PRX_DTX_N23: length 10.9
  BOTTOM w0.102: v1(172.31,35.42) 172.58,35.42 UH1.W43 ; CT108.1 23.29,119.71 23.29,118.68 24.02,117.95 24.65,117.95 24.68,117.93 25.35,117.93 25.38,117.95 25.8,117.95 26.06,117.69 26.06,115.81 26.55,115.32 28.29,115.32 28.97,116 29.27,116 v1(29.46,115.81)
PCIE_PRX_DTX_N24: length 13.2
  BOTTOM w0.102: CT110.1 20.75,119.71 20.75,119.41 20.89,119.27 20.89,118.58 21.38,118.09 22.6,118.09 22.84,117.85 22.84,117.82 23.39,117.27 23.42,117.27 24.31,116.38 24.62,116.38 26.29,114.71 29.88,114.71 v1(30.22,114.37) ; UH1.Y40 172.78,36.82 v1(172.62,36.98)
PCIE_PRX_DTX_P9: length 5.8
  BOTTOM w0.089: UH1.F36 166.43,38.38 166.52,38.28 v1(166.9,38.28)
  BOTTOM w0.102: v1(37.81,29.15) 38.04,29.38 38.04,31 37.72,31.32 37.72,32.67 38.04,32.99 38.04,33.15 37.87,33.31 JSSD1.7
PCIE_PRX_DTX_P10: length 6.2
  BOTTOM w0.089: v1(167.79,38.45) 167.71,38.37 UH1.J37
  BOTTOM w0.102: JSSD1.19 34.87,33.27 35.01,33.14 35.01,31.54 34.86,31.39 34.86,28.73 v1(34.66,28.53)
PCIE_PRX_DTX_P11: length 5.5
  BOTTOM w0.089: v1(166.89,36.68) 166.89,36.91 166.77,37.03 166.67,37.13 UH1.F39
  BOTTOM w0.102: v1(31.81,29.66) 32.02,29.87 32.02,31.05 31.84,31.23 31.84,32.12 32.02,32.3 32.02,33.09 31.87,33.24 JSSD1.31
PCIE_PRX_DTX_P12: length 5.1
  BOTTOM w0.089: UH1.J41 167.62,36.08 v1(168.01,35.7)
  BOTTOM w0.102: JSSD1.41 29.37,33.27 29.3,33.2 29.3,29.83 29.48,29.66 v1(29.48,29.66)
PCIE_PRX_DTX_P14: length 1.9
  TOP w0.102: CL1.2 63.4,35.99 63.87,35.99 v1(64.03,35.83)
  BOTTOM w0.089: v1(165.6,33.05) 165.51,33.14 UH1.C47
PCIE_PRX_DTX_P15: length 2.2
  BOTTOM w0.089: UH1.E45 166.45,34.37 v1(166.5,34.31)
  BOTTOM w0.102: JWLAN1.41 38.45,98.19 38.56,98.07 38.56,97.55 v1(38.39,97.38)
PCIE_PRX_DTX_P21: length 3.1
  BOTTOM w0.102: v1(28.32,117.52) 28.51,117.71 28.51,119.33 28.37,119.47 28.37,119.71 CT14.1 ; UH1.R44 v1(170.49,34.7)
PCIE_PRX_DTX_P22: length 5.2
  BOTTOM w0.102: UH1.U41 171.2,36.09 v1(171.07,36.22) ; v1(26.75,116) 26.92,116.17 26.92,117.73 26.13,118.52 26.13,119.16 25.83,119.46 25.83,119.71 CT12.1
PCIE_PRX_DTX_P23: length 10.6
  BOTTOM w0.102: CT109.1 23.49,119.71 23.49,118.77 24.11,118.16 v4(24.96,118.16) 25.88,118.16 26.26,117.78 26.26,115.9 26.64,115.53 28.2,115.53 28.89,116.21 29.27,116.21 v1(29.46,116.39) ; v1(172.14,34.77) 172.31,34.6 UH1.W44
PCIE_PRX_DTX_P24: length 12.7
  BOTTOM w0.102: v1(30.22,114.95) 30.19,114.91 26.37,114.91 24.7,116.58 24.4,116.58 v4(23.24,117.74) 22.69,118.3 21.46,118.3 21.1,118.66 21.1,119.35 20.96,119.49 20.96,119.71 CT111.1 ; UH1.Y41 172.84,36.08 v1(172.52,36.4)
PCIE_PTX_C_CRX_N23: length 2.6
  BOTTOM w0.089: CT18.2 24.57,120.73 24.57,122.01 24.4,122.17 24.4,122.65 UT1.M22
PCIE_PTX_C_DRX_N9: length 3
  TOP w0.102: v1(36.92,32.86) 36.69,32.63 36.69,32.45 36.3,32.06 36.3,31.93 CS16.2
  BOTTOM w0.102: JSSD1.11 36.87,33.33 36.73,33.18 36.73,33.05 v1(36.92,32.86)
PCIE_PTX_C_DRX_N10: length 2.8
  TOP w0.102: v1(33.92,32.57) 33.74,32.39 33.74,31.94 CS18.2
  BOTTOM w0.102: v1(33.92,32.57) 33.73,32.75 33.73,33.1 33.87,33.25 JSSD1.23
PCIE_PTX_C_DRX_N11: length 2.8
  TOP w0.102: v1(30.92,32.57) 30.75,32.4 30.75,31.95 CS20.2
  BOTTOM w0.102: v1(30.92,32.57) 30.73,32.75 30.73,33.23 30.87,33.38 JSSD1.35
PCIE_PTX_C_DRX_N12: length 2.8
  TOP w0.102: CS22.2 27.72,31.93 27.72,32.37 v1(27.92,32.57)
  BOTTOM w0.102: JSSD1.47 27.87,33.26 27.73,33.11 27.73,32.75 v1(27.92,32.57)
PCIE_PTX_C_DRX_N14: length 3.4
  TOP w0.102: CL4.1 59.68,34.99 59.68,35.32 v4(59.42,35.58) 58.52,36.48 58.52,36.92 58.61,37.02 UL1.14
PCIE_PTX_C_DRX_N15: length 4.1
  BOTTOM w0.102: JWLAN1.37 37.45,98.26 37.32,98.13 37.32,98.12 37.3,98.1 37.3,97.74 38.21,96.83 38.65,96.83 38.95,96.53 38.95,96.35 CW1.2
PCIE_PTX_C_DRX_N21: length 3.6
  BOTTOM w0.089: UT1.Y22 28.54,122.65 28.54,122.17 28.44,122.06 28.44,121.91 28.86,121.49 29.51,121.49 29.84,121.15 29.84,120.73 CT15.2
PCIE_PTX_C_DRX_N22: length 2.8
  BOTTOM w0.089: UT1.T22 26.71,122.65 26.71,121.8 27.15,121.36 27.15,121.16 27.3,121.01 27.3,120.73 CT13.2
PCIE_PTX_C_DRX_N24: length 2.8
  BOTTOM w0.089: CT21.2 22.03,120.73 22.03,120.95 22.64,121.56 22.64,122.09 22.58,122.15 22.58,122.66 UT1.H22
PCIE_PTX_C_DRX_P9: length 3
  TOP w0.102: v1(36.33,32.86) 36.49,32.7 36.49,32.53 36.1,32.15 36.1,31.93 CS17.2
  BOTTOM w0.102: JSSD1.13 36.37,33.32 36.52,33.17 36.52,33.05 v1(36.33,32.86)
PCIE_PTX_C_DRX_P10: length 2.8
  TOP w0.102: v1(33.33,32.57) 33.54,32.36 33.54,31.92 CS19.2
  BOTTOM w0.102: v1(33.33,32.57) 33.52,32.75 33.52,33.1 33.37,33.25 JSSD1.25
PCIE_PTX_C_DRX_P11: length 2.8
  TOP w0.102: v1(30.33,32.57) 30.54,32.36 30.54,31.91 CS21.2
  BOTTOM w0.102: JSSD1.37 30.37,33.37 30.52,33.23 30.52,32.75 v1(30.33,32.57)
PCIE_PTX_C_DRX_P12: length 2.8
  TOP w0.102: CS23.2 27.52,31.94 27.52,32.38 v1(27.33,32.57)
  BOTTOM w0.102: v1(27.33,32.57) 27.52,32.75 27.52,33.12 27.37,33.27 JSSD1.49
PCIE_PTX_C_DRX_P14: length 3.4
  TOP w0.102: UL1.13 58.21,37.02 58.31,36.92 58.31,36.4 59.06,35.65 59.06,35.62 59.47,35.2 59.47,34.99 CL3.1
PCIE_PTX_C_DRX_P15: length 4.1
  BOTTOM w0.102: JWLAN1.35 36.95,98.23 37.1,98.08 37.1,97.66 38.13,96.63 38.57,96.63 38.75,96.45 38.75,96.35 CW2.2
PCIE_PTX_C_DRX_P21: length 3.6
  BOTTOM w0.089: CT3.2 29.65,120.73 29.65,121.08 29.43,121.3 28.78,121.3 28.25,121.83 28.25,122.05 28.08,122.22 28.08,122.53 28.15,122.6 28.26,122.6 28.32,122.55 UT1.Y23
PCIE_PTX_C_DRX_P22: length 2.8
  BOTTOM w0.089: CT1.2 27.11,120.73 27.11,120.93 26.96,121.08 26.96,121.28 26.52,121.72 26.52,121.96 26.24,122.23 26.24,122.5 26.31,122.56 26.41,122.56 26.48,122.5 UT1.T23
PCIE_PTX_C_DRX_P23: length 2.6
  BOTTOM w0.089: CT4.2 24.76,120.73 24.76,122.11 24.87,122.23 24.87,122.58 24.83,122.62 24.7,122.62 24.64,122.56 UT1.M23
PCIE_PTX_C_DRX_P24: length 2.8
  BOTTOM w0.089: UT1.H23 22.8,122.52 22.85,122.57 22.98,122.57 23.03,122.52 23.03,122.19 22.83,121.99 22.83,121.48 22.22,120.87 22.22,120.73 CT5.2
PCIE_PTX_DRX_N9: length 6.8
  TOP w0.102: CS16.1 36.31,30.28 36.31,29.85 v1(36.5,29.66)
  BOTTOM w0.089: UH1.C34 165.16,39.44 165.17,39.43 165.33,39.43 165.39,39.37 165.39,39.25 165.33,39.19 164.92,39.19 164.81,39.3 161.75,39.3 161.54,39.09 161.54,38.44 v1(161.86,38.12)
PCIE_PTX_DRX_N10: length 7.8
  TOP w0.102: v1(33.9,29.66) 33.73,29.83 33.73,30.25 CS18.1
  BOTTOM w0.089: UH1.C35 165.06,38.84 162.91,38.84 162.78,38.7 162.78,38.69 162.76,38.67
  BOTTOM w0.102: v1(159.69,37.47) 160.3,37.47 160.63,37.14 161.7,37.14 162.46,37.89 162.46,38.37 162.76,38.67
PCIE_PTX_DRX_N11: length 3.4
  TOP w0.102: CS20.1 30.76,30.26 30.76,29.84 v1(30.94,29.66)
  BOTTOM w0.102: UH1.B36 164.51,38.28 164.45,38.21 164.31,38.21 164.1,38.42 163.98,38.42 163.58,38.03 162.96,38.03 v1(162.84,38.16)
PCIE_PTX_DRX_N12: length 1.8
  TOP w0.102: CS22.1 27.71,30.27 27.71,29.86 v1(27.92,29.66)
  BOTTOM w0.089: v1(165.44,38.23) 165.25,38.04 165.25,37.92 UH1.D38
PCIE_PTX_DRX_N14: length 9
  TOP w0.102: CL4.2 59.9,33.73 59.63,33.45 59.63,33.35 59.74,33.23 60.49,33.23 61.09,33.84 61.48,33.84 61.54,33.91 61.54,34.12 61.64,34.22 v1(61.85,34.22)
  BOTTOM w0.089: v1(161.53,34.22) 161.76,34.45 161.76,34.85 163.99,37.08 164.17,37.08 164.4,37.31 164.72,37.31 164.89,37.48 165.18,37.48 165.25,37.41 165.25,37.29 165.2,37.24 UH1.C39
PCIE_PTX_DRX_N15: length 4.6
  BOTTOM w0.089: v1(162.78,34.74) 162.97,34.94 162.97,35.42 164.19,36.64 164.76,36.64 164.82,36.7 164.82,36.83 164.78,36.88 UH1.B40
  BOTTOM w0.102: CW2.1 38.7,95.1 38.82,94.97 38.82,94.65 v1(38.58,94.41)
PCIE_PTX_DRX_N21: length 17.9
  BOTTOM w0.089: UH1.G47 166.53,33.12 166.53,32.91 166.41,32.79 166.41,32.04 165.43,31.06 164.71,31.06 164.61,30.96 163.14,30.96 163.14,30.95 163.08,30.95 163.07,30.95 163.06,30.95
  BOTTOM w0.102: 163.06,30.95 160.37,30.95 159.3,32.02 159.3,34.56 157.07,36.78 157.07,38.71 v1(156.87,38.92) ; CT15.1 29.73,119.59 v1(29.73,119.33)
PCIE_PTX_DRX_N22: length 27
  BOTTOM w0.089: UH1.H47 167.7,33.03 167.7,32.25 167.78,32.17 167.78,31.2 165.98,29.4 165.53,29.4 165.23,29.09 163.39,29.09 163.39,29.09 163.31,29.09
  BOTTOM w0.102: CT13.1 27.31,119.71 27.31,119.47 v1(27.5,119.29) ; v1(150.72,38.92) 150.92,38.72 150.92,38.38 152.01,37.3 153.91,37.3 157.46,33.75 157.46,30.87 159.24,29.09 163.31,29.09
PCIE_PTX_DRX_N23: length 19.3
  BOTTOM w0.089: UH1.G49 166.83,32.14 166.83,31.94 165.46,30.57 165.05,30.57 164.8,30.32 163.55,30.32 163.54,30.31 163.51,30.31
  BOTTOM w0.102: 163.51,30.31 159.83,30.31 159.46,30.68 159.43,30.68 159.02,31.09 159.02,31.13 158.68,31.46 158.68,34.3 155.05,37.94 v1(155.05,38.92) ; CT18.1 24.56,119.71 24.56,119.5 v1(24.37,119.31)
PCIE_PTX_DRX_N24: length 23.5
  BOTTOM w0.089: UH1.G46 166.88,33.84 167.04,33.84 167.11,33.77 167.11,33.66 166.95,33.5 166.95,32.51 167.13,32.33 167.13,31.68 165.63,30.17 165.21,30.17 164.94,29.9 163.4,29.9 163.39,29.9 163.37,29.9
  BOTTOM w0.102: v1(21.83,119.34) 22.02,119.53 22.02,119.71 CT21.1 ; 163.37,29.9 159.6,29.9 158.28,31.23 158.28,34.09 154.13,38.24 153.76,38.24 153.64,38.36 153.64,38.74 v1(153.81,38.92)
PCIE_PTX_DRX_P9: length 6.8
  TOP w0.102: v1(35.92,29.66) 36.1,29.85 36.1,30.27 CS17.1
  BOTTOM w0.089: v1(161.21,38.12) 161.35,38.26 161.35,39.17 161.67,39.49 164.78,39.49 164.82,39.52 164.82,39.53 164.95,39.66 165.47,39.66 UH1.D34
PCIE_PTX_DRX_P10: length 7.4
  TOP w0.102: v1(33.32,29.66) 33.53,29.87 33.53,30.29 CS19.1
  BOTTOM w0.089: 162.62,38.82 162.63,38.84 162.64,38.84 162.83,39.03 164.55,39.03 UH1.B35
  BOTTOM w0.102: v1(159.69,38.05) 160.07,37.68 160.39,37.68 160.72,37.34 161.62,37.34 162.25,37.98 162.25,38.46 162.62,38.82
PCIE_PTX_DRX_P11: length 3.1
  TOP w0.102: v1(30.36,29.66) 30.55,29.85 30.55,30.28 CS21.1
  BOTTOM w0.102: UH1.C36 164.78,38.65 163.91,38.65 163.67,38.41 v1(163.37,38.41)
PCIE_PTX_DRX_P12: length 1.8
  TOP w0.102: v1(27.33,29.66) 27.51,29.83 27.51,30.28 CS23.1
  BOTTOM w0.089: v1(165.93,38.55) 165.84,38.47 UH1.E37
PCIE_PTX_DRX_P14: length 8.8
  TOP w0.102: v1(61.85,33.63) 61.18,33.63 60.58,33.03 59.65,33.03 59.42,33.26 59.42,33.44 CL3.2
  BOTTOM w0.089: UH1.D39 165.28,37.01 164.95,37.01 164.84,37.12 164.47,37.12 164.25,36.89 164.07,36.89 161.95,34.77 161.95,34.39 v1(162.12,34.22)
PCIE_PTX_DRX_P15: length 4.1
  BOTTOM w0.089: v1(163.41,34.75) 163.17,35 163.17,35.34 164.27,36.45 164.87,36.45 UH1.C40
  BOTTOM w0.102: v1(39.17,94.41) 39.03,94.54 39.03,94.83 CW1.1
PCIE_PTX_DRX_P21: length 18.2
  BOTTOM w0.089: UH1.F46 166.28,33.17 166.34,33.11 166.34,32.99 166.22,32.87 166.22,32.12 165.35,31.25 164.63,31.25 164.53,31.15 163.06,31.15
  BOTTOM w0.102: CT3.1 29.43,119.61 v1(29.15,119.33) ; 163.06,31.15 160.45,31.15 159.5,32.1 159.5,34.64 157.28,36.87 157.28,39.09 157.39,39.2 157.59,39.2 157.69,39.11 v1(157.69,38.92)
PCIE_PTX_DRX_P22: length 27.1
  BOTTOM w0.089: UH1.H48 167.51,32.72 167.51,32.17 167.59,32.09 167.59,31.28 165.9,29.59 165.45,29.59 165.15,29.28 163.37,29.28 163.37,29.29
  BOTTOM w0.102: v1(26.91,119.29) 27.1,119.47 27.1,119.71 CT1.1 ; v1(151.54,38.91) 151.66,39.04 151.66,39.32 151.51,39.47 151.31,39.47 151.13,39.29 151.13,38.47 152.1,37.5 154,37.5 157.67,33.83 157.67,30.95 159.33,29.29 163.37,29.29
PCIE_PTX_DRX_P23: length 19.3
  BOTTOM w0.089: UH1.G48 166.67,32.47 166.64,32.44 166.64,32.02 165.38,30.76 164.97,30.76 164.72,30.51 163.54,30.51 163.54,30.52 163.51,30.52
  BOTTOM w0.102: CT4.1 24.77,119.71 24.77,119.5 v1(24.96,119.31) ; 163.51,30.52 159.92,30.52 v4(159.39,31.04) 158.89,31.54 158.89,34.39 155.26,38.02 155.26,38.54 v1(155.64,38.92)
PCIE_PTX_DRX_P24: length 24.2
  BOTTOM w0.089: UH1.G45 167.3,33.85 167.3,33.58 167.14,33.42 167.14,32.59 167.32,32.41 167.32,31.6 165.71,29.98 165.29,29.98 165.01,29.71 163.41,29.71
  BOTTOM w0.102: CT5.1 22.23,119.71 22.23,119.53 v1(22.42,119.34) ; 163.41,29.71 163.39,29.7 159.52,29.7 158.07,31.15 158.07,34 154.04,38.03 153.67,38.03 153.43,38.28 153.43,38.71 v1(153.23,38.92)
PCIE_RBIAS: length 1.1
  TOP w0.102: RT3.1 25.48,125.34 v1(25.61,125.2)
  BOTTOM w0.089: UT1.N16 v1(25.61,125.2)
PCIE_RCOMPN: length 6.2
  BOTTOM w0.102: v2(158.88,50.61) 159.2,50.29 RH669.1 160.64,49.78 161.77,49.78 161.95,49.6 163.28,49.6 163.51,49.82 164,49.82 164.02,49.84 164.38,50.21 UH1.B12
PCIE_RCOMPP: length 3.1
  BOTTOM w0.102: RH669.2 161.82,50.29 v2(161.98,50.13) 162.24,49.87 163.25,49.87 163.45,50.07 UH1.A13
PCIE_WAKE#: length 41.9
  TOP w0.102: v1(37.98,80.94) v3(37.31,80.94) ; RS10.2 v1(27.01,24.6) ; UE1.4 87.89,43.57 87.75,43.43 v1(87.75,42.22) 87.49,41.96 87.49,40.1 87.16,39.77 85.46,39.77 85.2,39.5 85.2,32.43 85.56,32.07 v1(85.56,31.04) ; UL1.21 60.93,39.63 v1(60.99,39.57)
  BOTTOM w0.102: RW31.1 40.36,94.92 40.58,94.7 v1(43.75,94.7) 44.21,94.25 44.21,93.04 44.51,92.74 44.51,87.71 43.59,86.79 41.53,86.79 39.21,84.47 39.21,82.16 v1(37.98,80.94) ; RH4.1 183.5,28.79 v1(183.28,28.57) ; RT10.2 v1(27.65,136.23)
PCIE_WAKE#_R: length 4.6
  BOTTOM w0.102: JWLAN1.55 41.95,98.18 42.39,97.74 42.39,96.89 v2(41.54,96.04) RW31.2
PCIE_WAKE#_SSD_R: length 3
  TOP w0.102: RS10.1 25.81,25.23 v1(25.79,25.25) 25.6,25.44 v2(24.91,25.44)
  BOTTOM w0.102: JSSD1.54 26.12,25.58 v1(25.79,25.25)
PD_EE_CLK: length 2.5
  BOTTOM w0.102: RT123.1 29.46,90.32 30.43,90.32 30.76,89.99 UT4.A3
PD_EE_CLK_R: length 11.6
  TOP w0.102: v1(33.01,79.27) 32.6,79.27 v2(32.41,79.46)
  BOTTOM w0.102: RT156.2 37.47,72.55 UT3.6 37.47,77.25 37.2,77.52 34.76,77.52 v1(33.01,79.27) ; RT123.2 28.31,91.2 28.57,91.46 v1(28.8,91.46)
PD_EE_CS_N: length 6
  BOTTOM w0.076: v1(29.81,90.72) 30.42,90.72 30.91,90.24 31.36,90.24 31.55,90.04 UT4.B3
  BOTTOM w0.102: v1(32.49,80.9) 32.72,80.67 34.5,80.67 RT126.1 34.93,80.65 UT3.1
PD_EE_DI: length 11.3
  TOP w0.102: v1(33.33,79.79) v2(34.34,79.79)
  BOTTOM w0.102: v1(33.33,79.79) 33.81,79.79 34.02,79.58 34.02,78.64 34.91,77.75 38.01,77.75 38.74,77.03 UT3.5 ; UT4.B4 31.59,89.45 v1(32.01,89.45)
PD_EE_DO: length 7.3
  BOTTOM w0.076: v1(30.58,89.63) 30.76,89.63 30.9,89.49 UT4.A4
  BOTTOM w0.102: UT3.2 36.2,79.81 35.56,80.45 RT125.1 35.17,81.89 33.97,81.89 33.77,81.68 32.08,81.68 v1(31.55,82.21)
PD_EE_HOLD#: length 2.5
  BOTTOM w0.102: v2(36.51,72.6) 35.92,72.6 RT128.1 35.73,72.99 36.2,73.46 UT3.7
PD_EE_WP#: length 3.5
  BOTTOM w0.102: v2(38.23,82.47) 38.23,81.95 37.41,81.14 RT127.1
  BOTTOM w0.381: UT3.3 37.47,80.55 37.34,80.68 RT127.1
PD_I2C_INT#: length 3.1
  BOTTOM w0.076: UT4.B6 31.3,88.74 30.04,88.74
  BOTTOM w0.102: RT120.1 29.6,88.85 v2(29.78,88.85) 29.89,88.74 30.04,88.74
PD_I2C_SCL_R: length 25.9
  TOP w0.102: v1(43.08,90.71) 43.51,90.71 43.99,90.22 43.99,83.71 43.31,83.03 40.71,83.03 v2(39.56,84.18) 39.44,84.3 37.38,84.3 36.34,85.34 36.34,86.44 v1(36.54,86.65)
  BOTTOM w0.076: 30.33,89.35 30.44,89.24 31.3,89.24 UT4.B5
  BOTTOM w0.102: RT118.2 41.5,90.83 42.96,90.83 v1(43.08,90.71) ; v1(26.94,91.19) 26.94,90.84 RT60.2 27.84,90.56 28.55,90.56 RT57.2 29,90.1 29.71,90.1 30.16,89.65 30.16,89.52 30.33,89.35
PD_I2C_SDA_R: length 18.3
  TOP w0.102: v1(39.54,92.68) 39.03,93.18 33.97,93.18 33.54,93.61 32.17,93.61 31.78,93.22 31.36,93.22 v2(29.33,91.18) 29.21,91.07 29.21,90.01 v1(29.5,89.71)
  BOTTOM w0.102: UT4.A5 30.33,88.99 30.13,89.19 29.48,89.19 29.23,88.94 RT59.2 28.87,89.56 RT58.2 29.02,89.71 v1(29.5,89.71) ; v1(39.54,92.68) 39.73,92.87 RT119.2
PD_UART: length 3.2
  BOTTOM w0.076: UT4.F2 33.3,90.74 33.3,92.43 RT62.1
  BOTTOM w0.102: UT4.E2 UT4.F2
PECI_EC: length 3.6
  TOP w0.102: DE1.1 91.36,26.88 RE23.2 91.25,26.15 v1(91.35,26.05)
  BOTTOM w0.102: RH73.2 175.92,60.3 v1(175.92,60.64) ; RC44.1 v1(57.56,122.5)
PECI_EC_R: length 6
  BOTTOM w0.076: 61.53,123.83 60.75,123.83 59.42,122.5 58.9,122.5
  BOTTOM w0.102: v2(57.07,123.21) 57.23,123.06 58.41,123.06 58.74,122.73 RC44.2 58.9,122.5 ; UC1.BT34 61.53,123.83
PECI_PCH: length 4.5
  BOTTOM w0.089: UH1.AF2 176.16,55.42 176.16,56.32 175.91,56.57
  BOTTOM w0.102: RH73.1 175.49,58.08 175.49,56.98 175.91,56.57
PEG_CRX_C_GTX_N0: length 9.1
  TOP w0.102: 210.01,105.14 209.33,104.84 208.9,104.84 208.74,104.68 207.95,104.68 v4(207.42,104.16) 205.97,102.7 205.97,102.67 205.61,102.31 205.57,102.31 205.27,102.01 204.12,102.01 203.81,101.7 CV532.1
  BOTTOM w0.102: UV1.AJ14 210.35,105.48 210.01,105.14
PEG_CRX_C_GTX_N1: length 12.6
  TOP w0.102: 211.58,106.06 211.44,106.06 211.03,106.47 210.62,106.47 210.36,106.21 210.36,105.98 210.12,105.73 209.7,105.73 209.52,105.91 208,105.91 205.19,103.1 204.29,103.1 204.27,103.12 203.65,103.12 203.62,103.1 201.72,103.1 CV534.1
  BOTTOM w0.102: 211.58,106.06 211.99,105.65 UV1.AG14
PEG_CRX_C_GTX_N2: length 8.7
  TOP w0.102: 209.93,106.11 209.69,106.36 209.39,106.36 209.34,106.3 207.83,106.3 v4(205.85,104.33) 205.31,103.78 203.18,103.78 CV536.1
  BOTTOM w0.102: UV1.AJ15 210.27,106.45 209.93,106.11
PEG_CRX_C_GTX_N3: length 9.7
  TOP w0.102: 209.1,106.9 208.93,107.07 208.93,107.31 208.66,107.58 207.89,107.58 205.19,104.88 v4(204.06,104.88) 201.72,104.88 CV538.1
  BOTTOM w0.102: UV1.AK16 209.1,106.9
PEG_CRX_C_GTX_N4: length 10
  TOP w0.102: 210.75,107.75 210.2,107.2 209.52,107.2 208.74,107.98 207.59,107.98 v4(206.73,107.12) 205.68,106.07 205.68,106.03 205.21,105.56 203.18,105.56 CV540.1
  BOTTOM w0.102: UV1.AJ17 210.75,107.75
PEG_CRX_C_GTX_N5: length 13
  TOP w0.102: 212.33,107.73 212.16,107.9 212.16,108.12 211.77,108.51 209.42,108.51 208.96,108.97 207.03,108.97 204.74,106.68 v4(203.94,106.68) 201.7,106.68 CV542.1
  BOTTOM w0.102: 212.33,107.73 212,108.06 UV1.AG17
PEG_CRX_C_GTX_N6: length 10
  TOP w0.102: 210.81,109.41 210.23,108.83 209.73,108.83 209.06,109.5 206.75,109.5 206.34,109.09 206.31,109.09 204.56,107.34 203.18,107.34 CV544.1
  BOTTOM w0.102: UV1.AJ18 210.81,109.41
PEG_CRX_C_GTX_N7: length 9.7
  TOP w0.102: 209.08,110.15 208.9,110.33 208.9,110.57 208.59,110.89 206.7,110.89 v4(204.69,108.88) 204.25,108.44 201.72,108.44 CV546.1
  BOTTOM w0.102: UV1.AK19 209.5,109.85 209.2,110.15 209.08,110.15
PEG_CRX_C_GTX_P0: length 8.9
  TOP w0.102: 209.13,105.28 208.95,105.45 208.83,105.45 208.74,105.36 208.74,104.98 208.65,104.89 207.86,104.89 207.47,104.49 207.43,104.49 207,104.06 207,104.02 v4(205.63,102.66) 205.19,102.21 204.04,102.21 203.73,101.9 203.5,101.9 203.42,101.99 203.42,102.39 203.34,102.48 203.23,102.48 CV531.1
  BOTTOM w0.102: 209.13,105.28 UV1.AK14
PEG_CRX_C_GTX_P1: length 12.6
  TOP w0.102: 210.77,106.08 211.06,106.08 211.22,105.92 211.22,105.69 211.09,105.57 210.75,105.57 210.58,105.73 210.43,105.73 210.22,105.53 209.62,105.53 209.44,105.71 208.08,105.71 205.27,102.9 v4(203.99,102.9) 201.72,102.9 CV533.1
  BOTTOM w0.102: UV1.AH14 210.77,106.08
PEG_CRX_C_GTX_P2: length 8.8
  TOP w0.102: 209.92,106.81 209.67,106.56 209.31,106.56 209.26,106.51 207.74,106.51 205.86,104.63 205.83,104.63 205.44,104.24 205.44,104.2 205.23,103.99 203.18,103.99 CV535.1
  BOTTOM w0.102: UV1.AK15 209.56,106.45 209.92,106.81
PEG_CRX_C_GTX_P3: length 9.7
  TOP w0.102: CV537.1 201.72,104.67 203.77,104.67 203.78,104.66 204.4,104.66 204.42,104.67 205.27,104.67 207.98,107.38 208.57,107.38 208.73,107.22 208.73,106.97 208.66,106.9 208.3,106.9
  BOTTOM w0.102: UV1.AL16 208.3,106.9
PEG_CRX_C_GTX_P4: length 10
  TOP w0.102: CV539.1 203.18,105.77 205.09,105.77 v4(205.34,106.02) 206.31,106.99 206.31,107.03 206.76,107.48 206.8,107.48 207.5,108.18 208.83,108.18 209.61,107.4 210.11,107.4 210.31,107.6 210.31,107.75 210.24,107.83 209.93,107.83
  BOTTOM w0.102: 209.93,107.83 209.93,107.85 209.64,108.15 UV1.AK17
PEG_CRX_C_GTX_P5: length 13
  TOP w0.102: 211.61,107.76 211.88,107.76 211.95,107.83 211.95,108.03 211.68,108.3 209.34,108.3 208.87,108.77 207.12,108.77 204.82,106.47 204.27,106.47 204.25,106.45 203.64,106.45 203.61,106.47 201.73,106.47 CV541.1
  BOTTOM w0.102: UV1.AH17 211.38,108.15 211.61,107.92 211.61,107.76
PEG_CRX_C_GTX_P6: length 9.9
  TOP w0.102: CV543.1 203.18,107.55 204.47,107.55 v4(206.35,109.42) 206.63,109.71 209.14,109.71 209.82,109.03 210.14,109.03 210.37,109.26 210.37,109.38 210.3,109.45 209.99,109.45
  BOTTOM w0.102: 209.99,109.45 209.5,108.96 UV1.AK18
PEG_CRX_C_GTX_P7: length 9.7
  TOP w0.102: 208.3,110.14 208.4,110.05 208.56,110.05 208.69,110.18 208.69,110.49 208.5,110.68 206.79,110.68 205.05,108.95 205.05,108.92 204.66,108.52 204.63,108.52 204.34,108.23 201.72,108.23 CV545.1
  BOTTOM w0.102: UV1.AL19 208.34,110.16 208.33,110.16 208.3,110.14
PEG_CRX_GTX_N0: length 171.1
  TOP w0.102: v1(100.43,105.64) 100.23,105.44 100.23,105.32 100.32,105.23 100.67,105.23 100.81,105.37 100.81,105.5 100.95,105.64 101.51,105.64 101.91,105.23 103.2,105.23 103.91,104.52 103.91,100.44 108.83,95.52 109.26,95.52 112.52,92.26 112.52,80.85 119.35,74.01 119.35,73.14 121.64,70.85 122.41,70.85 123.02,70.24 123.99,70.24 126.08,68.15 126.08,66.94 126.92,66.11 128.3,66.11 136.41,60.7 147.66,56.77 165.78,56.77 167.2,58.19 169.65,58.19 170.65,59.19 179.17,59.19 179.71,58.65 189.1,58.65 191.26,60.81 191.26,62.08 194.13,64.95 194.13,66.9 194.99,67.76 194.99,70.02 196.66,71.69 196.69,71.69 197.12,72.12 197.12,72.15 v4(199.97,75.01) 200.6,75.63 200.6,81.35 201.91,82.66 201.91,86.05 202.84,86.98 202.84,88.92 202.41,89.35 202.41,89.81 201.91,90.32 201.91,99.14 202,99.23 202,99.8 201.22,100.57 201.22,101.52 201.64,101.94 202.17,101.94 CV532.2
  BOTTOM w0.102: v1(100.43,105.64) 100.11,105.96 UC1.E10
PEG_CRX_GTX_N1: length 173.5
  TOP w0.102: v1(100.43,106.42) 100.47,106.42 101.11,107.06 102.21,107.06 102.64,106.63 103.61,106.63 104.73,105.51 104.73,100.78 109.09,96.41 109.53,96.41 113.44,92.5 113.44,81.09 120.22,74.31 120.22,73.43 121.98,71.68 122.76,71.68 123.31,71.13 124.31,71.13 128.44,67 136.68,61.51 147.88,57.59 165.42,57.59 166.83,59.01 169.31,59.01 170.91,60.61 171.43,60.61 172.02,60.01 179.51,60.01 180.05,59.47 188.76,59.47 189.39,60.1 189.39,61.4 193.32,65.33 193.32,67.24 194.09,68.01 194.09,70.38 v4(197.96,74.26) 199.77,76.07 199.77,81.7 201.09,83.02 201.09,86.43 201.87,87.2 201.87,88.61 201.59,88.9 201.59,89.48 201.09,89.97 201.09,91.87 199.29,93.67 199.29,94.73 196.95,97.07 196.95,100.64 199.68,103.37 200.59,103.37 200.67,103.28 CV534.2
  BOTTOM w0.102: UC1.E11 100.11,106.74 v1(100.43,106.42)
PEG_CRX_GTX_N2: length 175.2
  TOP w0.102: v1(100.46,107.24) 100.27,107.05 100.27,106.93 100.39,106.81 100.57,106.81 101.15,107.39 102.64,107.39 103,107.03 103.78,107.03 105.14,105.68 105.14,100.95 109.1,96.98 109.6,96.98 113.92,92.66 113.92,81.2 120.7,74.42 120.7,73.54 122.14,72.1 122.94,72.1 123.42,71.62 124.43,71.62 128.77,67.27 136.78,61.94 148.08,58 165.15,58 166.56,59.42 169.14,59.42 170.79,61.06 179.04,61.06 180.22,59.88 188.57,59.88 188.95,60.25 188.95,61.59 192.9,65.54 192.9,67.4 193.63,68.13 193.63,70.75 v4(194.37,71.49) 199.36,76.48 199.36,81.87 200.68,83.19 200.68,91.54 198.83,93.39 198.83,94.42 196.28,96.97 196.28,100.62 199.45,103.78 202.23,103.78 CV536.2
  BOTTOM w0.102: v1(100.46,107.24) 100.11,107.58 UC1.E12
PEG_CRX_GTX_N3: length 171.8
  TOP w0.102: CV538.2 200.56,105.06 200.47,105.15 199.62,105.15 195.46,100.99 195.46,96.56 197.92,94.1 197.92,92.9 199.87,90.95 199.87,83.54 198.51,82.18 198.51,76.93 v4(195.26,73.68) 192.75,71.17 192.75,68.41 192,67.67 192,65.85 188.03,61.88 170.45,61.88 168.86,60.29 166.28,60.29 164.81,58.82 148.23,58.82 137.1,62.71 129.32,67.9 124.75,72.47 123.75,72.47 123.28,72.93 122.47,72.93 121.64,73.76 121.64,74.64 114.74,81.54 114.74,93.03 109.92,97.85 109.4,97.85 105.96,101.29 105.96,106.04 103.72,108.28 102.4,108.28 102.07,108.61 101.07,108.61 v1(100.46,108)
  BOTTOM w0.102: UC1.E13 100.11,108.34 v1(100.46,108)
PEG_CRX_GTX_N4: length 173.3
  TOP w0.102: CV540.2 202.23,105.56 199.43,105.56 195.03,101.17 195.03,96.18 197.48,93.73 197.48,92.5 199.46,90.52 199.46,83.71 198.1,82.35 198.1,77.29 v4(196.86,76.04) 192.26,71.44 192.26,68.53 191.58,67.84 191.58,66.19 187.67,62.28 170.28,62.28 168.71,60.71 166.1,60.71 164.61,59.22 148.37,59.22 137.26,63.1 129.62,68.19 124.88,72.93 123.93,72.93 115.17,81.7 115.17,93.21 110.11,98.27 109.56,98.27 106.39,101.44 106.39,106.27 104.08,108.58 102.76,108.58 102.38,108.96 101.14,108.96 100.59,108.41 100.38,108.41 100.27,108.52 100.27,108.65 v1(100.43,108.81)
  BOTTOM w0.102: v1(100.43,108.81) 100.11,109.13 UC1.E14
PEG_CRX_GTX_N5: length 173.3
  TOP w0.102: v1(100.44,109.55) 101.05,110.16 102.25,110.16 102.52,109.89 103.94,109.89 107.21,106.61 107.21,101.78 109.91,99.09 113.22,99.09 115.99,96.31 115.99,82.03 124.24,73.78 125.2,73.78 130.13,68.85 137.55,63.9 148.52,60.04 164.26,60.04 165.85,61.63 168.47,61.63 169.94,63.1 187.22,63.1 190.75,66.63 190.75,68.18 191.38,68.82 191.38,71.83 v4(192.19,72.63) 197.27,77.72 197.27,82.69 198.64,84.06 198.64,90.03 196.62,92.05 196.62,93.04 194.21,95.46 194.21,101.56 199.48,106.84 CV542.2
  BOTTOM w0.102: v1(100.44,109.55) 100.11,109.88 UC1.E15
PEG_CRX_GTX_N6: length 177.9
  TOP w0.102: v1(100.43,110.39) 100.25,110.2 100.25,110.08 100.35,109.97 100.58,109.97 100.81,110.21 100.81,110.33 100.95,110.46 102.46,110.46 102.56,110.36 106.97,110.36 108.02,109.32 109.02,109.32 109.77,108.57 113.49,108.57 116.43,105.63 116.43,82.17 124.41,74.19 125.39,74.19 130.43,69.14 137.7,64.29 148.6,60.45 164.07,60.45 165.69,62.06 168.33,62.06 169.77,63.51 186.83,63.51 190.31,66.99 190.31,68.34 190.87,68.9 190.87,72.64 v4(193.58,75.35) 196.86,78.63 196.86,82.87 198.24,84.25 198.24,88.89 193.79,93.34 193.79,101.79 199.34,107.34 202.23,107.34 CV544.2
  BOTTOM w0.102: v1(100.43,110.39) 100.11,110.71 UC1.E16
PEG_CRX_GTX_N7: length 176.6
  TOP w0.102: CV546.2 199.42,108.62 192.96,102.17 192.96,92.95 197.42,88.49 197.42,84.59 195.93,83.11 195.93,78.94 v4(195.12,78.13) 190.01,73.01 190.01,69.2 189.49,68.69 189.49,67.35 186.46,64.33 169.43,64.33 168,62.9 165.35,62.9 163.72,61.26 148.81,61.26 138.07,65.04 130.96,69.78 125.67,75.06 124.71,75.06 118.16,81.6 118.16,84.78 117.27,85.67 117.27,106.02 113.77,109.52 110.59,109.52 109.59,110.51 109.59,110.83 108.95,111.47 104.54,111.47 104.15,111.86 100.95,111.86 100.61,111.52 100.61,111.32 v1(100.43,111.15)
  BOTTOM w0.102: UC1.E17 100.11,111.47 v1(100.43,111.15)
PEG_CRX_GTX_P0: length 171.1
  TOP w0.102: CV531.2 202.16,102.15 201.55,102.15 201.02,101.61 201.02,100.49 201.8,99.71 201.8,99.32 201.7,99.22 201.7,90.23 202.2,89.73 202.2,89.26 202.64,88.83 202.64,87.06 201.71,86.13 201.71,82.75 200.39,81.43 200.39,75.72 200.08,75.4 200.04,75.4 199.61,74.96 199.61,74.93 v4(196.76,72.08) 194.78,70.11 194.78,67.85 193.93,66.99 193.93,65.03 191.06,62.16 191.06,60.9 189.02,58.86 179.8,58.86 179.26,59.39 170.56,59.39 169.57,58.4 167.11,58.4 165.69,56.98 147.69,56.98 136.51,60.88 128.36,66.31 127.01,66.31 126.29,67.03 126.29,68.23 124.07,70.45 123.11,70.45 122.5,71.06 121.73,71.06 119.55,73.23 119.55,74.1 112.72,80.93 112.72,92.35 109.34,95.72 108.92,95.72 104.11,100.53 104.11,104.61 103.29,105.44 102,105.44 101.59,105.84 100.79,105.84 100.61,106.02 100.16,106.02 v1(99.77,105.64)
  BOTTOM w0.102: UC1.F10 99.46,105.95 v1(99.77,105.64)
PEG_CRX_GTX_P1: length 173.5
  TOP w0.102: v1(101.09,106.42) 101,106.52 101,106.66 101.19,106.85 102.12,106.85 102.56,106.42 103.52,106.42 104.52,105.42 104.52,100.69 109.01,96.21 109.44,96.21 113.24,92.41 113.24,81 120.02,74.22 120.02,73.35 121.89,71.48 122.67,71.48 123.22,70.92 124.23,70.92 128.31,66.84 136.59,61.32 147.85,57.39 165.5,57.39 166.92,58.8 169.4,58.8 170.99,60.4 171.34,60.4 171.94,59.8 179.42,59.8 179.96,59.26 188.84,59.26 189.59,60.02 189.59,61.31 193.52,65.24 193.52,67.16 194.29,67.93 194.29,70.3 197.88,73.89 197.91,73.89 198.33,74.3 198.33,74.34 199.98,75.98 199.98,81.61 201.3,82.93 201.3,86.34 202.07,87.12 202.07,88.7 201.79,88.98 201.79,89.56 201.3,90.06 201.3,91.96 199.49,93.76 199.49,94.81 197.16,97.15 197.16,100.55 199.77,103.16 200.5,103.16 200.58,103.08 200.58,102.96 200.51,102.89 200.51,102.8 200.6,102.71 CV533.2
  BOTTOM w0.102: UC1.D11 100.76,106.63 100.97,106.42 v1(101.09,106.42)
PEG_CRX_GTX_P2: length 175.3
  TOP w0.102: CV535.2 202.23,103.99 199.36,103.99 196.08,100.7 196.08,96.89 198.63,94.34 198.63,93.3 200.48,91.45 200.48,83.28 199.16,81.96 199.16,76.57 194.44,71.85 194.41,71.85 193.94,71.38 193.94,71.35 193.43,70.83 193.43,68.22 192.69,67.48 192.69,65.63 188.74,61.68 188.74,60.34 188.48,60.08 180.3,60.08 179.12,61.26 170.7,61.26 169.06,59.62 166.48,59.62 165.06,58.2 148.11,58.2 136.87,62.12 128.9,67.43 124.51,71.83 123.5,71.83 123.02,72.3 122.22,72.3 120.9,73.63 120.9,74.51 114.13,81.28 114.13,92.75 109.68,97.19 109.18,97.19 105.34,101.03 105.34,105.77 103.87,107.24 103.08,107.24 102.72,107.61 100.17,107.61 v1(99.77,107.21)
  BOTTOM w0.102: UC1.F12 99.46,107.52 v1(99.77,107.21)
PEG_CRX_GTX_P3: length 171.8
  TOP w0.102: v1(101.07,108.02) 101.07,108.32 101.15,108.41 101.98,108.41 102.31,108.08 103.63,108.08 105.75,105.95 105.75,101.2 109.31,97.64 109.84,97.64 114.53,92.95 114.53,81.46 121.44,74.55 121.44,73.68 122.39,72.72 123.2,72.72 123.66,72.26 124.67,72.26 129.19,67.74 137.01,62.53 148.2,58.61 164.89,58.61 166.37,60.08 168.95,60.08 170.53,61.67 188.11,61.67 192.21,65.77 192.21,67.58 192.96,68.33 192.96,71.08 195.19,73.32 195.22,73.32 195.62,73.71 195.62,73.75 198.72,76.85 198.72,82.1 200.07,83.45 200.07,91.04 198.12,92.99 198.12,94.18 195.67,96.64 195.67,100.9 199.71,104.94 200.39,104.94 200.53,104.8 200.53,104.7 200.46,104.63 200.46,104.48 200.53,104.4 200.8,104.4 CV537.2
  BOTTOM w0.102: v1(101.07,108.02) 100.96,108.02 100.76,108.22 UC1.D13
PEG_CRX_GTX_P4: length 173.4
  TOP w0.102: v1(99.77,108.81) 100.14,109.18 100.79,109.18 100.8,109.17 102.46,109.17 102.85,108.79 104.17,108.79 106.59,106.36 106.59,101.53 109.65,98.47 110.19,98.47 115.37,93.29 115.37,81.78 124.02,73.14 124.97,73.14 129.75,68.35 137.35,63.29 148.4,59.43 164.52,59.43 166.01,60.92 168.62,60.92 170.2,62.49 187.59,62.49 191.37,66.27 191.37,67.93 192.05,68.61 192.05,71.53 196.42,75.89 196.42,75.93 196.89,76.4 196.92,76.4 197.89,77.37 197.89,82.43 199.25,83.79 199.25,90.44 197.28,92.41 197.28,93.65 194.83,96.1 194.83,101.25 199.34,105.77 202.23,105.77 CV539.2
  BOTTOM w0.102: UC1.F14 99.46,109.12 v1(99.77,108.81)
PEG_CRX_GTX_P5: length 173.3
  TOP w0.102: v1(101.07,109.55) 100.96,109.66 100.96,109.78 101.14,109.95 102.16,109.95 102.43,109.68 103.85,109.68 107.01,106.53 107.01,101.69 109.82,98.88 113.13,98.88 115.79,96.23 115.79,81.94 124.16,73.57 125.12,73.57 130,68.69 137.46,63.71 148.49,59.83 164.34,59.83 165.93,61.42 168.55,61.42 170.03,62.9 187.31,62.9 190.95,66.54 190.95,68.09 191.59,68.73 191.59,71.75 192.07,72.22 192.1,72.22 192.55,72.67 192.55,72.7 197.48,77.64 197.48,82.6 198.85,83.97 198.85,90.11 196.83,92.13 196.83,93.13 194.41,95.55 194.41,101.48 199.57,106.63 200.48,106.63 200.57,106.55 200.57,106.25 200.64,106.18 200.78,106.18 CV541.2
  BOTTOM w0.102: v1(101.07,109.55) 101,109.55 100.76,109.79 UC1.D15
PEG_CRX_GTX_P6: length 177.9
  TOP w0.102: CV543.2 202.23,107.55 199.25,107.55 193.58,101.88 193.58,93.25 198.03,88.81 198.03,84.33 196.65,82.95 196.65,78.71 193.69,75.75 193.65,75.75 193.19,75.3 193.19,75.25 190.67,72.73 190.67,68.99 190.1,68.42 190.1,67.08 186.74,63.71 169.69,63.71 168.24,62.27 165.61,62.27 163.99,60.65 148.63,60.65 137.79,64.48 130.56,69.3 125.47,74.39 124.5,74.39 116.64,82.25 116.64,105.71 113.58,108.77 109.85,108.77 109.1,109.52 108.1,109.52 107.06,110.57 102.65,110.57 102.55,110.67 100.73,110.67 100.65,110.76 100.17,110.76 v1(99.77,110.36)
  BOTTOM w0.102: UC1.F16 99.46,110.67 v1(99.77,110.36)
PEG_CRX_GTX_P7: length 176.6
  TOP w0.102: CV545.2 200.65,108.05 200.56,108.14 200.56,108.33 200.48,108.41 199.5,108.41 193.17,102.08 193.17,93.03 197.62,88.58 197.62,84.51 196.14,83.03 196.14,78.85 195.49,78.2 195.49,78.17 195.09,77.77 195.06,77.77 190.21,72.92 190.21,69.12 189.7,68.6 189.7,67.27 186.55,64.12 169.52,64.12 168.09,62.69 165.44,62.69 163.81,61.06 148.77,61.06 137.97,64.85 130.82,69.62 128.21,72.24 125.59,74.85 124.62,74.85 117.96,81.52 117.96,84.7 117.07,85.59 117.07,105.93 113.69,109.31 110.5,109.31 109.39,110.43 109.39,110.74 108.86,111.26 104.45,111.26 104.06,111.65 101.04,111.65 100.81,111.43 100.81,111.27 100.91,111.17 v1(101.07,111.17)
  BOTTOM w0.102: UC1.D17 100.76,111.48 v1(101.07,111.17)
PEG_CTX_C_GRX_N0: length 11.3
  BOTTOM w0.102: UV1.AM12 207.56,104.29 206.91,104.29 206.65,104.55 202.41,104.55 201.71,103.85 201.71,101.77 202.32,101.16 202.32,100.52 202.13,100.33 ; CC2.2 107.01,107.46 107.18,107.46 v1(107.37,107.65)
PEG_CTX_C_GRX_N1: length 12.7
  BOTTOM w0.102: CC4.2 108.34,108.5 108.64,108.5 v1(108.83,108.31) ; UV1.AM14 207.56,105.31 207.02,105.31 206.68,104.96 202.25,104.96 201.3,104.02 201.3,99.59 201.38,99.51
PEG_CTX_C_GRX_N2: length 11.7
  BOTTOM w0.102: UV1.AP15 206,106.15 202.18,106.15 199.88,103.84 199.88,100.91 199.68,100.71 ; v1(108.98,110.54) 108.79,110.35 108.34,110.35 CC6.2
PEG_CTX_C_GRX_N3: length 16
  BOTTOM w0.102: UV1.AM15 207.55,106.1 206.96,106.1 206.73,106.33 206.73,106.54 206.44,106.83 202.17,106.83 198.87,103.54 198.87,99.65 199.06,99.46 ; CC8.2 109.63,111.41 109.9,111.41 v1(110.09,111.23)
PEG_CTX_C_GRX_N4: length 11.7
  BOTTOM w0.102: 198.47,108.91 198.68,108.7 203.75,108.7 204.69,107.75 206.59,107.75 206.76,107.92 206.76,108.29 206.96,108.49 207.56,108.49 UV1.AM17 ; v1(108.61,113.08) 108.42,112.89 107.85,112.89 CC10.2
PEG_CTX_C_GRX_N5: length 11
  BOTTOM w0.102: CC12.2 109.63,113.95 110.18,113.95 v1(110.37,113.77) ; UV1.AP18 206.38,108.87 206.38,108.63 206.27,108.52 206.04,108.52 205.92,108.64 205.92,108.99 205.82,109.09 204.5,109.09 204.1,109.48 197.81,109.48 197.63,109.3
PEG_CTX_C_GRX_N6: length 10.6
  BOTTOM w0.102: CC14.2 107.85,115.43 108.42,115.43 v1(108.61,115.62) ; 199.21,110.91 199.4,110.72 204.47,110.72 205.26,109.92 206.41,109.92 206.88,109.46 207.18,109.46 207.69,108.95 UV1.AM18
PEG_CTX_C_GRX_N7: length 11.6
  BOTTOM w0.102: 197.96,111.98 198.15,111.79 204.34,111.79 205.07,111.06 207.49,111.06 UV1.AM20 ; CC16.2 109.63,116.7 110.18,116.7 v1(110.37,116.89)
PEG_CTX_C_GRX_P0: length 11
  BOTTOM w0.102: 202.72,100.33 202.53,100.52 202.53,101.24 201.92,101.86 201.92,103.76 202.5,104.34 206.56,104.34 206.7,104.21 206.7,103.61 206.81,103.5 207,103.5 207.1,103.6 UV1.AN12 ; CC1.2 107.01,107.26 107.18,107.26 v1(107.37,107.07)
PEG_CTX_C_GRX_P1: length 12.8
  BOTTOM w0.102: CC3.2 108.34,108.71 108.64,108.71 v1(108.83,108.9) ; UV1.AN14 207.1,105.8 207,105.9 206.84,105.9 206.73,105.8 206.73,105.31 206.59,105.17 202.16,105.17 201.1,104.1 201.1,99.81 200.8,99.51
PEG_CTX_C_GRX_P2: length 11.4
  BOTTOM w0.102: CC5.2 108.34,110.15 108.79,110.15 v1(108.98,109.96) ; 200.26,100.71 200.08,100.89 200.08,103.76 202.27,105.94 206.01,105.94 UV1.AP14
PEG_CTX_C_GRX_P3: length 16.3
  BOTTOM w0.102: 198.48,99.46 198.67,99.65 198.67,103.62 202.09,107.04 206.55,107.04 206.73,106.86 207.39,106.86 207.53,106.71 207.53,106.48 207.42,106.36 207.19,106.36 UV1.AN15 ; v1(110.09,111.81) 109.9,111.62 109.63,111.62 CC7.2
PEG_CTX_C_GRX_P4: length 11.8
  BOTTOM w0.102: v1(108.61,112.5) 108.42,112.68 107.85,112.68 CC9.2 ; 198.47,108.33 198.64,108.49 203.66,108.49 204.6,107.55 206.69,107.55 206.79,107.64 207.42,107.64 207.55,107.77 207.55,108.21 207.47,108.29 207.24,108.29 UV1.AN17
PEG_CTX_C_GRX_P5: length 11.5
  BOTTOM w0.102: v1(110.37,114.35) 110.18,114.16 109.63,114.16 CC11.2 ; UV1.AP17 206.64,108.49 206.64,109.09 206.44,109.3 204.58,109.3 204.19,109.69 197.81,109.69 197.63,109.88
PEG_CTX_C_GRX_P6: length 10
  BOTTOM w0.102: CC13.2 107.85,115.22 108.42,115.22 v1(108.61,115.04) ; UV1.AN18 207.19,109.04 207.19,109.16 207.1,109.25 206.79,109.25 206.32,109.72 205.18,109.72 204.38,110.51 199.4,110.51 199.21,110.32
PEG_CTX_C_GRX_P7: length 11.3
  BOTTOM w0.102: CC15.2 109.63,116.49 110.18,116.49 v1(110.37,116.31) ; UV1.AN20 206.71,110.26 206.05,110.26 205.95,110.35 205.95,110.74 205.84,110.85 204.99,110.85 204.25,111.59 198.15,111.59 197.96,111.4
PEG_CTX_GRX_N0: length 7.2
  BOTTOM w0.076: UC1.B10 101.85,106.03 101.71,105.89 101.71,105.78 101.77,105.71 103,105.71 103.15,105.56 103.17,105.56 103.18,105.55
  BOTTOM w0.102: 103.18,105.55 103.48,105.25 v4(104.5,105.25) 105.2,105.25 105.48,105.53 105.48,105.72 105.46,105.74 105.46,106.35 105.48,106.37 105.48,107.18 105.77,107.46 106,107.46 CC2.1
PEG_CTX_GRX_N1: length 6.8
  BOTTOM w0.076: 104.37,106.67 104.36,106.66 104.32,106.66 104.01,106.35 102.36,106.35 102.21,106.5 102.21,106.67 UC1.B11
  BOTTOM w0.102: 104.37,106.67 v4(104.58,106.88) 106.21,108.5 107.33,108.5 CC4.1
PEG_CTX_GRX_N2: length 7.8
  BOTTOM w0.076: UC1.B12 101.87,107.6 101.71,107.44 101.71,107.33 101.78,107.26 103.82,107.26 104.28,107.72 104.28,107.76 104.29,107.77
  BOTTOM w0.102: CC6.1 107.32,110.35 106.87,110.35 106.29,109.76 106.25,109.76 105.83,109.34 105.83,109.31 v4(104.72,108.2) 104.29,107.77
PEG_CTX_GRX_N3: length 8.6
  BOTTOM w0.076: 104.41,108.65 104.4,108.64 104.36,108.64 103.77,108.05 103.19,108.05 103.06,107.92 102.36,107.92 102.2,108.08 102.2,108.25 UC1.B13
  BOTTOM w0.102: CC8.1 108.61,111.41 v4(107.71,111.41) 107.17,111.41 106.6,110.84 106.6,110.8 106.2,110.41 106.17,110.41 104.41,108.65
PEG_CTX_GRX_N4: length 8.5
  BOTTOM w0.076: 104.12,109.52 104.1,109.51 104.1,109.47 103.39,108.76 103.05,108.76 102.97,108.84 101.8,108.84 101.71,108.92 101.71,109.03 101.86,109.18 UC1.B14
  BOTTOM w0.102: 104.12,109.52 v4(104.79,110.2) 105.48,110.89 105.48,112.11 105.8,112.43 105.8,112.46 106.23,112.89 106.83,112.89 CC10.1
PEG_CTX_GRX_N5: length 9.5
  BOTTOM w0.076: UC1.B15 102.2,109.83 102.2,109.65 102.36,109.5 103.04,109.5 103.16,109.62 103.73,110.2 103.77,110.2 103.78,110.21
  BOTTOM w0.102: CC12.1 108.61,113.95 v4(107.62,113.95) 106.7,113.95 105.03,112.28 105.03,111.45 103.78,110.21
PEG_CTX_GRX_N6: length 9
  BOTTOM w0.076: 103.16,110.74 103.15,110.73 103.15,110.69 102.87,110.41 101.81,110.41 101.7,110.52 101.7,110.61 101.85,110.75 UC1.B16
  BOTTOM w0.102: CC14.1 106.83,115.43 106.24,115.43 105.98,115.18 105.95,115.18 105.53,114.76 105.53,114.73 v4(104.74,113.93) 104.13,113.32 104.13,111.71 103.16,110.74
PEG_CTX_GRX_N7: length 10.1
  BOTTOM w0.076: 103.13,112.24 103.11,112.23 103.11,112.19 102.97,112.04 102.36,112.04 102.18,111.86 102.18,111.66 UC1.B17
  BOTTOM w0.102: CC16.1 108.61,116.7 v4(107.95,116.7) 106.03,116.7 105.85,116.51 105.81,116.51 105.41,116.11 105.41,116.08 103.4,114.07 103.4,112.52 103.13,112.24
PEG_CTX_GRX_P0: length 7.3
  BOTTOM w0.076: UC1.C10 101.56,105.89 101.56,105.71 101.71,105.56 102.93,105.56 103.04,105.46 103.04,105.41
  BOTTOM w0.102: CC1.1 106,107.26 105.85,107.26 105.69,107.1 v4(105.69,106.02) 105.69,105.45 105.29,105.05 104.79,105.05 104.77,105.02 104.18,105.02 104.16,105.05 103.4,105.05 103.04,105.41
PEG_CTX_GRX_P1: length 6.8
  BOTTOM w0.076: UC1.A11 102.5,106.81 102.36,106.67 102.36,106.56 102.42,106.5 103.95,106.5 104.08,106.63 104.22,106.77 104.22,106.8 104.23,106.82
  BOTTOM w0.102: 104.23,106.82 104.23,106.84 104.6,107.21 104.62,107.21 106.12,108.71 107.33,108.71 CC3.1
PEG_CTX_GRX_P2: length 7.8
  BOTTOM w0.076: UC1.C12 101.56,107.46 101.56,107.27 101.72,107.11 103.89,107.11 104.16,107.38 104.39,107.61 104.42,107.61 104.44,107.63
  BOTTOM w0.102: 104.44,107.63 104.62,107.81 104.66,107.81 105.09,108.24 105.09,108.27 v4(106.19,109.38) 106.96,110.14 107.33,110.14 CC5.1
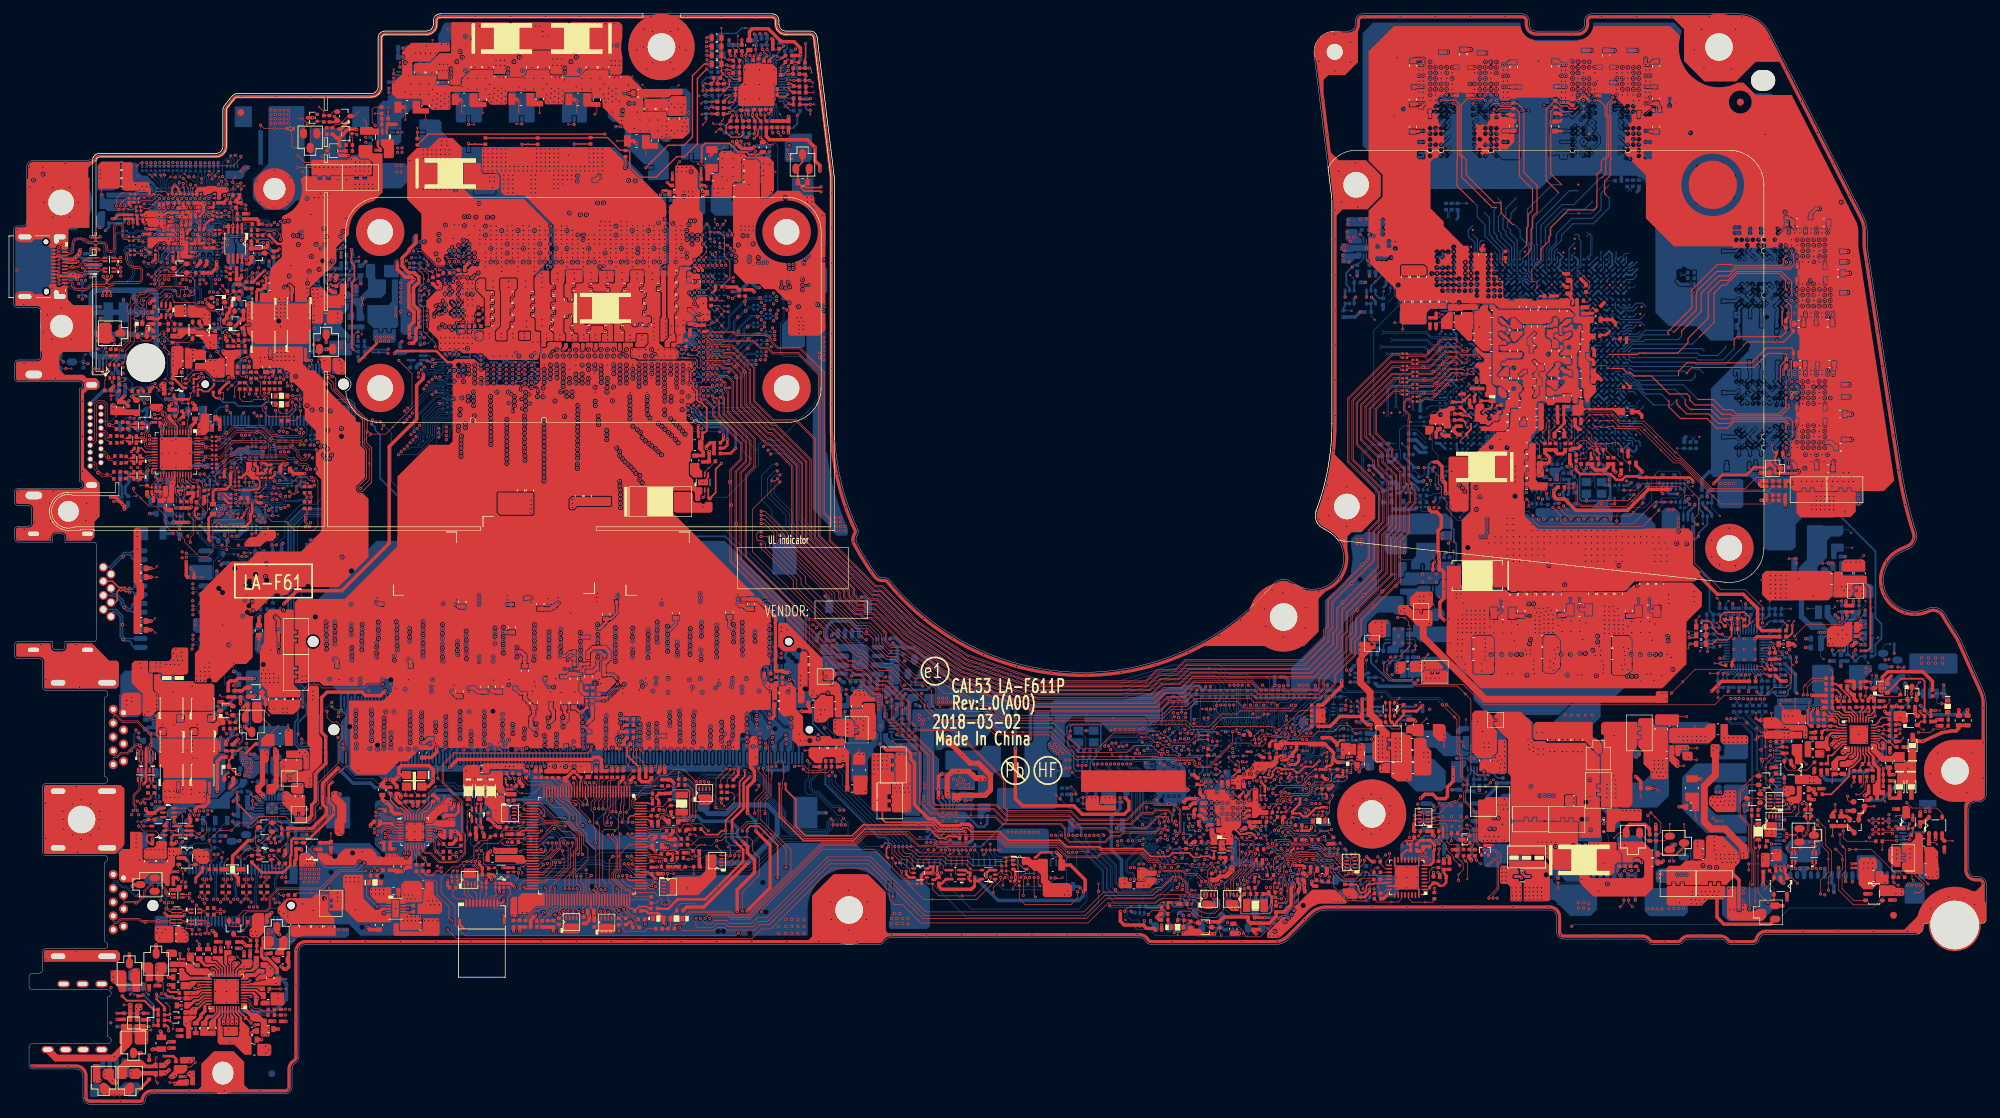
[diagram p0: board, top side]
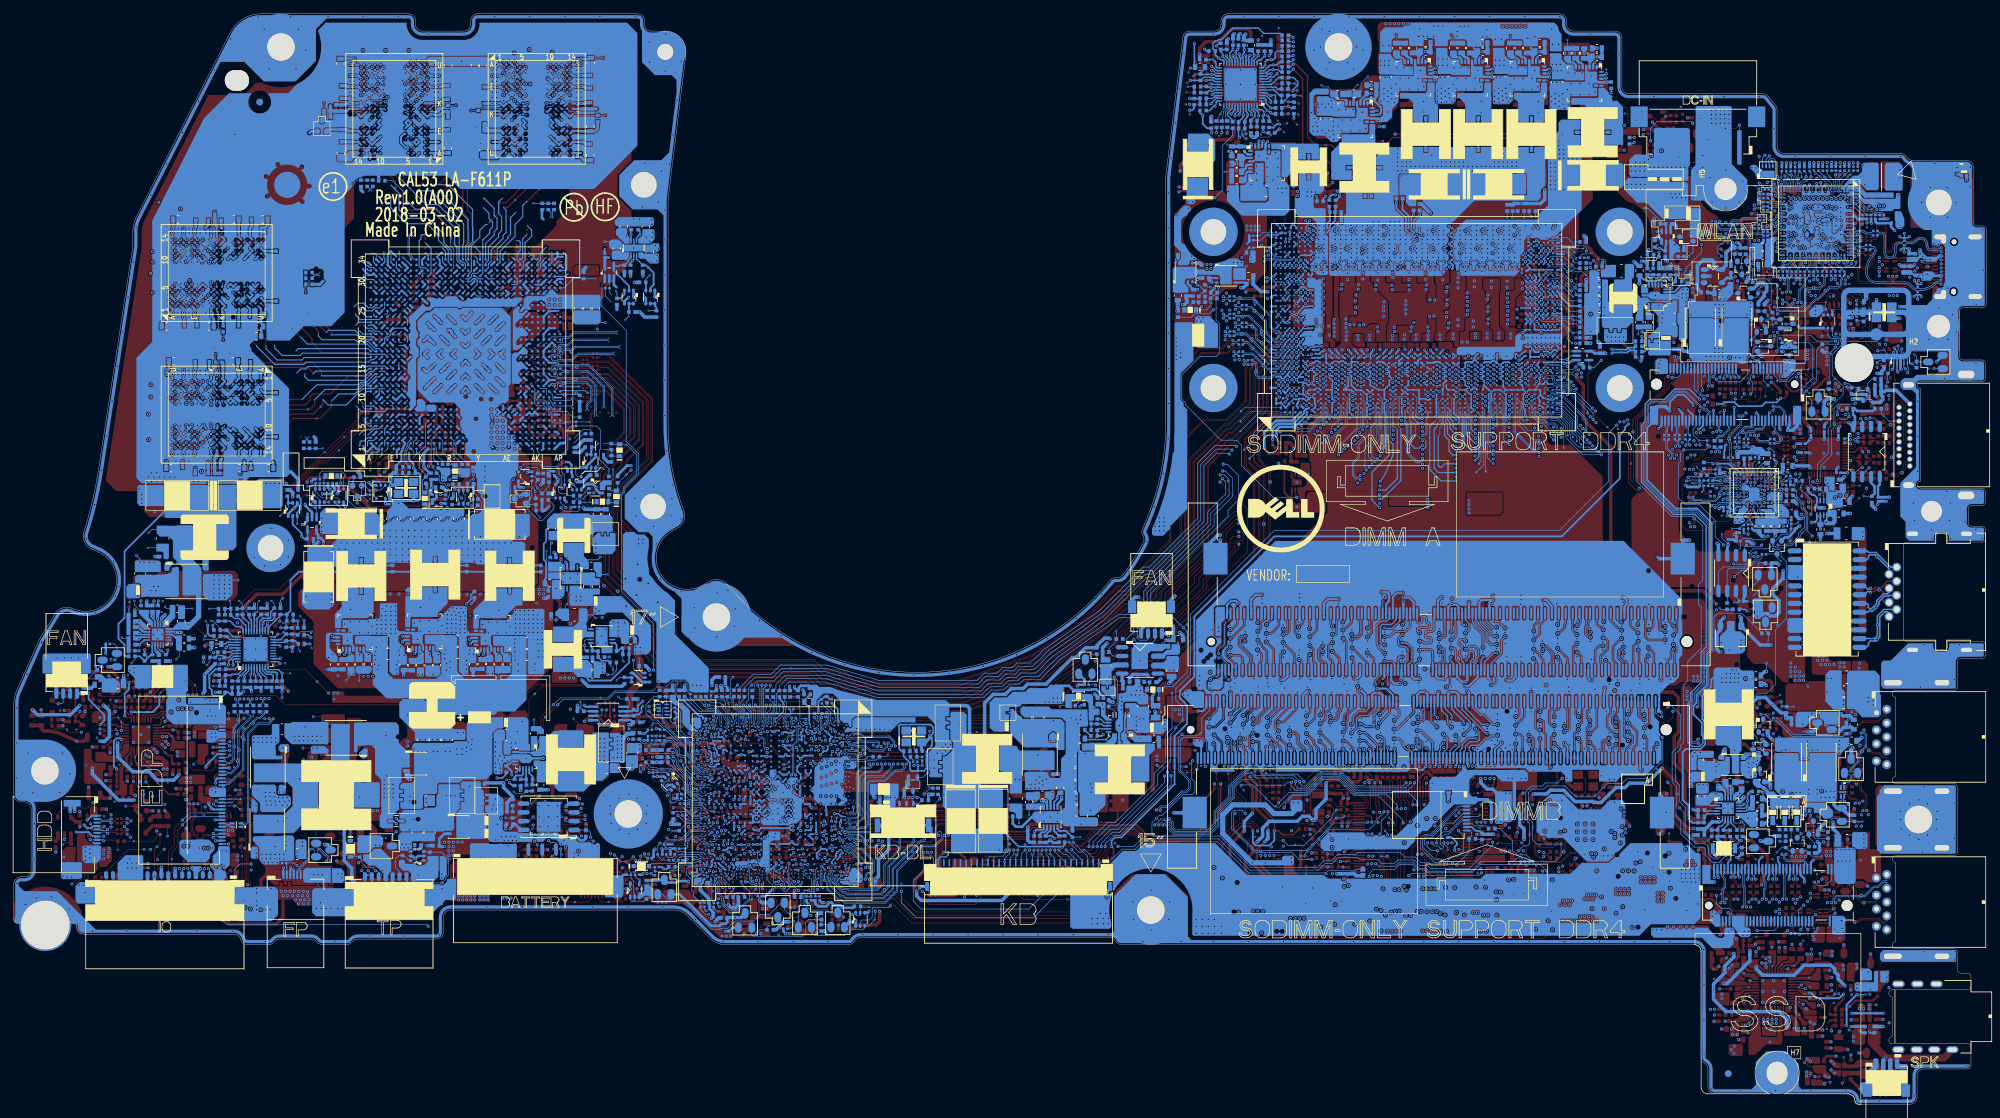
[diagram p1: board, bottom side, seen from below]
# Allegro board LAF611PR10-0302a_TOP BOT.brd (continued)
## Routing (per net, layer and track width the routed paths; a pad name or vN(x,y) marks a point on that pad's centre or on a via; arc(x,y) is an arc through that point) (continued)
PEG_CTX_GRX_P3: length 8.6
  BOTTOM w0.076: 104.27,108.8 104.25,108.78 104.25,108.75 103.71,108.2 103.12,108.2 103,108.08 102.42,108.08 102.36,108.14 102.36,108.24 102.51,108.39 UC1.A13
  BOTTOM w0.102: CC7.1 108.61,111.62 108.01,111.62 107.99,111.64 107.39,111.64 107.37,111.62 107.09,111.62 v4(106.24,110.77) 104.27,108.8
PEG_CTX_GRX_P4: length 8.5
  BOTTOM w0.076: UC1.C14 101.56,109.03 101.56,108.86 101.73,108.69 102.91,108.69 102.99,108.61 103.45,108.61 104.21,109.36 104.25,109.36 104.26,109.38
  BOTTOM w0.102: CC9.1 106.83,112.68 106.35,112.68 v4(106.17,112.51) 105.69,112.02 105.69,110.81 104.26,109.38
PEG_CTX_GRX_P5: length 9.5
  BOTTOM w0.076: UC1.A15 102.5,109.96 102.36,109.82 102.36,109.72 102.42,109.65 102.97,109.65 103.63,110.3 103.63,110.34 103.64,110.36
  BOTTOM w0.102: CC11.1 108.61,114.16 107.92,114.16 107.9,114.18 107.26,114.18 107.24,114.16 106.62,114.16 104.8,112.34 v4(104.8,111.86) 104.8,111.52 103.64,110.36
PEG_CTX_GRX_P6: length 9
  BOTTOM w0.076: 103.31,110.6 103.29,110.58 103.26,110.58 102.93,110.26 101.75,110.26 101.55,110.46 101.55,110.61 UC1.C16
  BOTTOM w0.102: 103.31,110.6 104.33,111.62 104.33,113.24 104.67,113.57 104.71,113.57 105.11,113.97 105.11,114.01 v4(105.89,114.79) 106.32,115.22 106.83,115.22 CC13.1
PEG_CTX_GRX_P7: length 10
  BOTTOM w0.076: UC1.A17 102.41,111.54 102.34,111.61 102.34,111.8 102.43,111.89 103.03,111.89 103.22,112.08 103.26,112.08 103.27,112.1
  BOTTOM w0.102: CC15.1 108.61,116.49 108.29,116.49 108.27,116.47 107.64,116.47 107.62,116.49 106.12,116.49 v4(105.78,116.15) 103.61,113.98 103.61,112.43 103.27,112.1
PEG_RCOMP: length 1.2
  TOP w0.381: RC9.2 100.15,111.83 100.22,111.91 v1(100.45,111.91)
  BOTTOM w0.305: UC1.G2 98.84,100.78 v1(99.16,101.1)
PEX_CLKREQ#: length 14.3
  BOTTOM w0.102: QV3.3 236.33,90.17 236.14,90.36 RV57.1 236.59,90.75 236.96,90.38 236.96,87.35 235.97,86.36 232.94,86.36 231.9,85.32 v1(231.9,84.4)
  BOTTOM w0.109: 208.26,102.71 208.26,103.47 208.37,103.58 209.13,103.58 UV1.AK12
PEX_TERMP: length 5.6
  BOTTOM w0.102: UV1.AP29 205.75,118.15 204.42,119.48 RV50.2 v2(201.23,119.48)
PEX_VDD_EN: length 19.6
  TOP w0.102: v1(204.05,92.1) 204.94,92.1 206.07,90.97 206.07,89.84 206.55,89.36 206.55,87.95 207.33,87.17 207.33,86.27 207.94,85.66 v2(207.94,84.03) 207.94,81.59 v1(207.57,81.21)
  BOTTOM w0.102: v1(207.57,81.21) 207.73,81.05 PR1005.1 ; v1(204.05,92.1) 204.05,91.13 203.72,90.8 UG31.4 203.25,91.15 202.76,91.64 201.99,91.64 201.83,91.81 QG505.2
PEX_VDD_EN_U: length 7.1
  TOP w0.102: v3(196.76,91.1) 196.07,91.79 v1(196.05,91.79)
  BOTTOM w0.102: UG31.2 203.9,89.13 v1(204.44,89.68) ; RG550.2 198.92,88.8 DG10.2 198.01,88.95 CG482.1 197.91,89.93 v1(196.05,91.79)
PIRQA#: length 4.1
  TOP w0.102: v1(182.97,39.58) 183.36,39.98 v2(183.36,39.98) 183.44,40.05 184.73,40.05 185.22,39.57 RH546.1
  BOTTOM w0.089: UH1.BA36 182.97,39.13 v1(182.97,39.58)
PLTRST#: length 124.9
  TOP w0.102: v1(24.5,134) 25.03,133.47 25.03,132.79 25.3,132.52 RT1.2 ; v1(199.02,36.28) 199.02,35.66 198.5,35.14 198.5,34.66 198.59,34.57 UTPM1.17 ; UL1.19 60.58,38.83 61.49,37.92 v1(61.49,37.64) ; v1(65.55,35.1) 65.11,35.1 64.35,34.34 63.39,34.34 61.82,32.78 61.82,30.61 63.82,28.61 63.82,25.89 65.34,24.37 104.42,24.37 v1(104.83,24.78)
  BOTTOM w0.102: JWLAN1.52 41.2,103.87 41.05,103.72 v1(41.05,103.31) ; UH3.4 194.86,32.4 195.47,33.01 RH199.1 195.47,33.62 195.21,33.87 194.23,33.87 v1(193.73,33.37) ; UV14.2 206.32,87.17 v1(205.47,86.32) ; v1(46.9,53.07) 46.8,52.97 46.8,49.68 49.38,47.1 51.97,47.1 52.64,46.43 54.73,46.43 56.69,44.47 59.31,44.47 60.9,46.06 63.53,46.06 63.99,45.6 65.66,45.6 66.19,45.07 66.19,42.72 66.42,42.49 66.42,41.56 65.65,40.78 65.65,38.29 65,37.64 v1(61.49,37.64) 61.49,35.98 62.37,35.1 v1(65.55,35.1) 66.53,36.08 67.91,36.08 68.54,36.71 68.54,38.09 70.34,39.89 RE65.1 ; JSSD1.50 27.12,28.08 v1(26.4,28.8)
POK: length 123.6
  TOP w0.102: v1(199.19,64.71) 198.2,63.72 198.2,62.45 199.43,61.22 202.18,61.22 202.88,60.51 208.85,60.51 v3(210,59.37) 210.8,58.57 210.8,48.5 211.65,47.66 v1(213.32,47.66) ; v1(126.15,61.83) 125.47,61.83 122.57,64.73 122.08,64.73 106.85,79.96 106.85,86.07 v1(110.83,90.05) ; v1(52.3,141.63) 51.84,142.09 51.84,143.98 52.15,144.29 PR35.1 ; DC2.1 97.8,27.94 103.73,27.94 104.21,27.46 106.18,27.46 112.43,33.71 112.43,36.82 107.99,41.26 107.99,43.74 109.22,44.97 109.22,51.76 v1(108.74,52.24)
  BOTTOM w0.102: v1(126.15,61.83) 125.71,61.39 125.71,58.04 126.01,57.74 126.76,57.74 PR504.2 126.94,57.27 126.86,57.19 126.45,57.19 125.88,56.62 PU501.9 ; v1(199.19,64.71) PR1801.1
  BOTTOM w0.254: PU301.9 213.24,49.61 213.67,49.17 213.88,49.17 PR304.2 213.63,48.49 213.62,48.49 213.32,48.19 v1(213.32,47.66)
POWER_SW#_MB: length 87.7
  TOP w0.102: v1(105.4,39.54) 105.4,39.78 106.22,40.6 108.04,40.6 TPS10.1 111.71,36.93 v1(111.71,34.26) ; v1(100.48,39.57) 99.48,40.58 98.12,40.58 97.83,40.86 97.83,41.35 98.24,41.76 v1(98.24,44.04) 98.24,45.5 97.54,46.2 RE43.2
  BOTTOM w0.102: DC1.3 34.67,37.08 34.75,37.16 CC299.1 35.68,37.16 35.81,37.03 SW1.1 37.34,37.03 38.88,35.49 39.4,35.49 40.17,36.26 40.17,37.19 40.68,37.69 42.01,37.69 43.72,39.4 43.72,42.22 v1(44.36,42.87) ; v1(225.4,25.75) 225.67,26.02 254.57,26.02 256.95,28.4 268.93,28.4 271.26,30.72 271.26,32.25 271,32.51 JIOB1.17
POWER_SW_IN#: length 11.3
  TOP w0.102: UE1.127 89.81,43.21 89.69,43.34 89.69,43.76 90.92,44.99 91.92,44.99 91.97,44.94 CE33.1 92.41,45.34 92.61,45.54 94.15,45.54 RE41.2 95.12,46.06 95.28,45.9 95.88,45.9 RE43.1 RE161.1 v2(96.18,48.08)
PRIM_PWRGD: length 7.7
  TOP w0.102: UE1.30 77.49,46.05 77.28,46.27 76.51,46.27 75.25,45.01 v2(73.51,45.01) 73.18,45.01 72.62,45.57 RE160.2 RE149.2
PRIM_PWRGD_R: length 6.1
  TOP w0.102: RE160.1 72.09,46.04 RE150.1 72.68,46.38 72.47,46.6 v1(72.47,47.12) 72.19,47.4 PRH04.1 ; v1(202.76,66.35) v2(202.76,65.71)
  BOTTOM w0.102: PU1801.4 202.6,67.24 202.76,67.08 v1(202.76,66.35) 202.76,65.96 PR1803.2
PROC_DETECT#: length 2
  BOTTOM w0.102: v1(57.25,121.7) 57.29,121.74 RC277.1 ; v1(181.25,35.4) 180.56,36.09 UH1.AP41
PROC_SELECT#: length 7.1
  BOTTOM w0.076: UC1.BN1 64.1,99.76 63.53,99.2 63.28,99.2 62.99,98.91 61.98,98.91 61.12,98.05 61.12,94.99 TC97.1
PROCHOT: length 17.7
  TOP w0.102: v1(83.55,33.09) 83.21,32.75 83.21,31.04 83.89,30.36 UE1.83 ; v2(72.61,32.41) 73.02,32.82 v1(73.02,33.47) 72.86,33.63 RE53.2 71.52,33.63 UE2.2
  BOTTOM w0.102: v1(83.55,33.09) 83.46,33.09 83.14,33.41 81.25,33.41 80.92,33.08 73.41,33.08 v1(73.02,33.47)
PROJECT_ID1: length 3.6
  BOTTOM w0.102: RH681.1 RH557.2 169.39,30.33 169.47,30.4 169.47,32.31 169.09,32.68 UH1.L48
PROJECT_ID2: length 5
  BOTTOM w0.089: 169.7,32.35 169.34,32.72 169.34,34.01 UH1.M45
  BOTTOM w0.102: 169.7,32.35 169.7,30.63 170.03,30.3 RH561.2 RH562.1
PS_ID: length 4.7
  TOP w0.102: v1(49.63,140.31) 49.48,140.47 PD2.1 48.92,139.94 48.98,139.87 PR1.2 PR5.1 ; v1(73.83,42.7) 74.12,42.41 UE1.36
PSID: length 7.3
  TOP w0.102: PL3.1 v3(37.73,141.18) 36.21,141.18 v1(35.71,141.69)
  BOTTOM w0.102: PJPDC1.1 v1(35.71,141.69)
PSID-1: length 3.7
  TOP w0.102: v2(44.17,144.35) 44.86,143.66 PR3.2 PR6.1 46.23,143.64 PQ2.2
PSID-3: length 12.4
  TOP w0.102: v1(48.55,139.41) 48.07,138.93 PR1.1 ; v2(41.31,142.66) 41.76,142.66 42.46,141.96 v1(42.47,141.96) 42.47,141.83 41.91,141.27 PQ1.3
  BOTTOM w0.102: v1(48.55,139.41) 48.55,141.26 47.59,142.21 42.71,142.21 v1(42.47,141.96)
PTP_DIS#: length 11.4
  TOP w0.102: UE1.90 86.69,31.62 86.13,32.18 86.13,35.33 v1(86.68,35.88)
  BOTTOM w0.102: v1(236.4,41.78) 236.65,41.53 D6.1 ; v1(86.68,35.88) v2(87.55,35.88)
PWM1_1PH/ICCMAX1: length 3.9
  TOP w0.102: v1(106.35,139.01) v2(105.72,139.01)
  TOP w0.203: PRZ18.1 109.56,143.64 v1(109.24,143.31)
  BOTTOM w0.203: v1(109.24,143.31) 108.68,143.87 PUZ01.44
  BOTTOM w0.254: v1(106.35,139.01) 106.45,138.91 PUA01.1
PWM1_2PH/ICCMAX2: length 4.1
  TOP w0.102: v1(55.84,150.1) v2(55.84,150.77)
  BOTTOM w0.203: PRZ59.1 v1(108.97,152.63) 108.97,152.6 109.42,152.15 109.42,151.53 109.08,151.19 PUZ01.23
  BOTTOM w0.254: PUG01.1 v1(55.84,150.1)
PWM1_4PH/ICCMAX4: length 3.1
  TOP w0.102: v1(89.01,144.84) v2(89.77,144.84)
  TOP w0.203: v1(107.12,151.75) 106.99,151.62 PRZ54.1
  BOTTOM w0.203: v1(107.12,151.75) 107.12,151.54 107.08,151.51 PUZ01.18
  BOTTOM w0.254: PUI01.1 v1(89.01,144.84)
PWM2_2PH/ROSC1: length 2.7
  TOP w0.102: v1(108.97,151.73) 108.97,151.87 v2(108.64,152.2)
  TOP w0.203: v1(108.97,151.73) 108.54,151.31 PRZ72.1
  BOTTOM w0.203: PUZ01.22 108.68,151.27 108.97,151.55 v1(108.97,151.73)
PWM2_4PH/ADDR: length 4.6
  TOP w0.102: v2(107.65,153.86) 107.33,153.55 v1(107.33,152.64)
  BOTTOM w0.203: PUZ01.19 107.48,151.45 107.58,151.54 107.58,151.96 107.33,152.2 v1(107.33,152.64) 107.38,152.69 PRZ55.1
  BOTTOM w0.254: PUI02.1 v1(80.61,150.86)
PWM3_4PH/VBOOT: length 2.7
  TOP w0.203: PRZ56.1 107.77,151.69 v1(108.05,151.97)
  BOTTOM w0.203: v1(108.05,151.97) 108.05,151.58 107.88,151.41 PUZ01.20
  BOTTOM w0.254: PUI03.1 v1(72.35,150.86)
PWM4_4PH/ROSCM: length 4.7
  TOP w0.102: v2(108.94,153.71) 108.3,153.06 v1(108.3,152.64)
  BOTTOM w0.203: PUZ01.21 108.28,151.34 108.51,151.56 108.51,152.43 v1(108.3,152.64)
  BOTTOM w0.254: PUI04.1 v1(64.1,150.86) ; v1(108.3,152.64) 108.17,152.76 PRZ57.1
PWR_BTN_DOCK1#: length 5.3
  BOTTOM w0.102: v2(27.22,84.2) 27.43,83.98 RT165.2 28.26,83.95 RT166.2 28.26,82.99 28.82,82.42 29.62,82.42 30.5,81.54 Q29.3
PWR_TB_DOCK#: length 12.7
  TOP w0.102: v1(98.27,41.06) 98.66,41.45 v2(98.66,42.39) 98.66,46.05 97.67,47.04 RE161.2
  BOTTOM w0.102: v1(36.42,76.36) 35.57,77.22 34.7,77.22 33.15,78.76 32.78,78.76 32.45,79.09 RT167.2
REFCLK_CNV: length 102.7
  TOP w0.102: v1(108.12,82.17) 108.98,82.17 109.36,81.79 109.36,80.67 113.89,76.14 113.89,75.25 122.75,66.39 123.32,66.39 125.95,63.76 127.26,63.76 129.94,61.07 131.53,61.07 132.78,59.82 132.78,57.76 133.37,57.17 136.56,57.17 137.53,56.2 140.59,56.2 142.33,54.46 150.25,54.46 152.88,51.83 153.16,51.83 154.07,50.91 161.06,50.91 162.08,51.93 164.61,51.93 165.62,50.91 166.27,50.91 166.65,50.53 168.1,50.53 168.5,50.13 170.96,50.13 171.32,50.49 RH698.1 ; v1(45.44,105.18) 46.29,104.33 46.29,103.54 50.72,99.12 50.72,95.54 51.41,94.84 v2(51.41,92.72) 51.41,90.36 v1(50.16,89.11)
  BOTTOM w0.102: JWLAN1.64 44.2,105.6 44.62,105.18 v1(45.44,105.18)
REFCLK_CNV_H: length 4.7
  TOP w0.102: v1(170.77,52.28) 171.29,52.8 v2(171.64,52.8) RH716.1 172.79,51.42 RH698.2
  BOTTOM w0.089: UH1.R6 170.98,52.48 v1(170.77,52.28)
RESET_N: length 2.3
  TOP w0.102: v1(33.31,85.42) 33.31,85.72 v2(33.72,86.13)
  TOP w0.254: RT102.1 33.31,85.22 v1(33.31,85.42)
  BOTTOM w0.203: UT4.F11 33.55,85.66 v1(33.31,85.42)
RESET_OUT#: length 2.7
  TOP w0.102: RE158.2 78.46,27.38 v1(78.27,27.38) ; UE1.73 79.89,28.32 79.48,27.9 v1(79.48,27.87)
RF_+1.30V: length 4
  BOTTOM w0.102: PRH05.1 v2(131.05,38.64)
  BOTTOM w0.254: PRH05.1 133.11,39.56 134.11,39.56 134.35,39.8 PUH01.5
RING2: length 1
  TOP w0.127: v3(15.93,14.38) v1(16.92,14.38)
  vias: v1(16.92,13.79) v1(31.85,19.81) v1(31.85,20.39) v1(32.48,20.43)
RING2_R: length 14.4
  TOP w1.016: JHP1.4 6.12,6.68 14.38,6.68 v3(14.56,6.86) 16.33,8.63 DA5.3
  BOTTOM w0.254: CA42.1 16.71,10.33 v1(16.88,10.49)
RJ45_MDIN0: length 6.4
  BOTTOM w0.229: TL1.23 17.23,78.81 17.02,79.02 17.02,79.34 16.86,79.51 16.08,79.51 v4(15.82,79.24) 14.05,77.47 JLAN1.2
RJ45_MDIN1: length 6.2
  TOP w0.229: v1(16.75,74.08) 16.63,74.19 16.17,74.19 15.92,74.44 v4(15.48,74.44) 15.23,74.44 14.95,74.16 14.95,72.92 14.65,72.62 JLAN1.6
  BOTTOM w0.229: TL1.19 17.63,73.73 17.16,74.2 16.87,74.2 v1(16.75,74.08)
RJ45_MDIN2: length 6.6
  BOTTOM w0.229: TL1.17 17.13,71.19 16.96,71.36 16.45,71.36 v4(15.96,71.86) 15.5,72.31 15.5,72.72 14.72,73.51 14.14,73.51 14,73.64 JLAN1.5
RJ45_MDIN3: length 8.8
  BOTTOM w0.229: 18.33,66.11 17.36,66.11 17.03,66.45 17.03,66.73 16.72,67.04 16,67.04 v4(15.8,67.24) 15.39,67.65 15.39,70.52 14.65,71.26 14.28,71.26 14.05,71.03 JLAN1.8
RJ45_MDIP0: length 6.4
  BOTTOM w0.229: TL1.24 17.26,80.08 17.02,79.85 15.94,79.85 13.81,77.72 JLAN1.1
RJ45_MDIP1: length 6.1
  TOP w0.229: JLAN1.3 14.29,75.68 15.19,74.78 16.07,74.78 16.31,74.53 16.62,74.53 v1(16.75,74.66)
  BOTTOM w0.229: v1(16.75,74.66) 16.87,74.54 17.16,74.54 17.63,75 TL1.20
RJ45_MDIP2: length 6.6
  BOTTOM w0.229: TL1.18 17.26,72.46 17.07,72.27 17.07,71.91 16.86,71.71 16.6,71.71 15.85,72.46 15.85,72.86 14.86,73.85 14.28,73.85 14.05,74.08 JLAN1.4
RJ45_MDIP3: length 8.8
  BOTTOM w0.229: JLAN1.7 14.8,71.6 15.73,70.66 v4(15.73,69.4) 15.73,67.79 16.14,67.38 TL1.14
ROM_CS#: length 1.1
  TOP w0.102: 227.51,98.51 227.91,98.91 T97.1
  BOTTOM w0.102: 227.51,98.51 UV1.H6
ROM_SCLK: length 7.8
  TOP w0.102: RV162.2 231.67,93.56 RV159.1 230.44,94.54 230.44,95.13 230.16,95.41 228.71,95.41 v2(227.88,96.25) 227.55,96.58 227.55,96.87
  BOTTOM w0.102: UV1.H4 227.9,97.23 227.55,96.87
ROM_SI: length 32.8
  TOP w0.102: RV157.1 RV160.2 253.94,86.86 246.97,86.86 241.03,92.8 240.14,92.8 v2(238.32,94.63) 235.14,97.81 231.69,97.81 231.4,98.09 230.74,98.09 230.63,97.98 229.65,97.98 229.57,98.06 228.82,98.06 228.4,97.64
  BOTTOM w0.109: UV1.H5 228,98.05 228.4,97.64
ROM_SO: length 32.3
  TOP w0.102: 228.4,99.38 228.88,98.9 230.21,98.9 230.27,98.97 231.32,98.97 232.21,98.07 235.43,98.07 v2(235.95,97.55) 240.4,93.1 241.07,93.1 245.52,88.65 253.98,88.65 RV161.2 RV158.1
  BOTTOM w0.109: UV1.H7 228.03,99.75 228.4,99.38
RSET: length 4.8
  TOP w0.203: UL1.31 57.01,41.91 56.06,42.86 55.63,42.86 v2(54.85,43.65) 54.51,43.98 RL2.2
RTC_DET#: length 15.4
  TOP w0.102: v2(181.24,38.24) 181.24,38.72 v1(181.12,38.85) 180.72,38.85 RH734.1
  BOTTOM w0.076: 170.36,32.63 170.4,32.63 170.89,33.11 170.89,33.31 170.89,33.32 170.89,33.57 171.06,34.09 171.12,34.14 171.12,34.39 v1(171.48,34.75)
  BOTTOM w0.089: v1(181.12,38.85) 181.42,38.85 UH1.AV34
  BOTTOM w0.102: Q1.1 167.28,27.7 167.69,28.1 170.1,28.1 170.55,28.55 170.59,28.55 171.03,28.99 171.03,30.36 170.93,30.47 170.24,30.47 169.93,30.78 169.93,32.51 170.05,32.63 170.36,32.63
RTC_PWR: length 15.4
  BOTTOM w0.102: Q1.2 167.49,25.98 R2.1 R1.1 170.38,26.74 170.82,26.31 170.82,24.78 171.29,24.31 v2(174.61,24.31) 178.37,24.31 178.59,24.52 D1.3
RTCRST_ON: length 57.8
  TOP w0.102: v1(172.59,26.44) 172.06,26.44 171.7,26.8 171.3,26.8 170.17,27.93 168.73,27.93 168.38,27.57 R78.2 168.38,26.48 D7.1 166.97,26.16 C61.1 166.97,27.53 R79.2 166.95,27.61 166.56,28 164.66,28 v1(164.12,27.47) ; v1(80.93,31.17) 80.93,33.2 83.05,35.32 83.05,37.01 82.42,37.65 82.42,38.86 80.37,40.91 80.37,41.96 79.37,42.95 78.16,42.95 77.09,44.01 UE1.31
  BOTTOM w0.102: RH679.1 173,25.37 172.59,25.78 v1(172.59,26.44) 172.59,26.96 173.85,28.22 QH7.2 174.35,29.13 176.04,27.44 177.39,27.44 178.32,26.52 181.01,26.52 182.07,25.45 182.98,25.45 v2(183.11,25.32) 184.5,25.32 188.58,29.41 190.54,29.41 191.5,30.38 Q26.2
RTD3_CIO_PWR_EN: length 78.4
  TOP w0.102: v1(110.26,48.9) 110.26,49.39 110.52,49.65 111.2,49.65 111.38,49.47 v2(111.38,48.02) 111.38,47.04 111.22,46.88 111.22,45.81 111.1,45.68 111.1,41.76 114.41,38.46 121.34,38.46 122.98,40.1 132.67,40.1 133.71,39.06 142.61,39.06 143.79,37.88 151.25,37.88 152.2,36.93 156.93,36.93 157.18,36.68 163.18,36.68 164.39,35.47 165.56,35.47 166.31,34.72 168.1,34.72 168.25,34.87 169.75,34.87 170.32,34.3 172.66,34.3 v1(173.22,34.87)
  BOTTOM w0.102: RT16.2 v1(21.11,136.27) ; UH1.Y46 173.38,33.93 173.22,34.1 v1(173.22,34.87)
RTD3_CIO_PWR_EN_R: length 4.9
  TOP w0.102: v1(21.78,134.48) v2(21.13,134.48)
  BOTTOM w0.089: 21.77,133.42 21.77,133.14 21.88,133.04 UT1.F1
  BOTTOM w0.102: 21.77,133.42 21.77,134.47 v1(21.78,134.48) 21.63,134.63 21.43,134.63 21.11,134.95 RT16.1 RT152.2 RT36.1
RTD3_USB_PWR_EN: length 85.7
  TOP w0.102: v1(100.67,26.9) 101.02,27.25 103.33,27.25 103.82,26.77 106.46,26.77 117.08,37.39 121.78,37.39 123.42,39.03 129.06,39.03 130.85,37.25 133.11,37.25 133.47,37.61 134.82,37.61 135.08,37.35 137.79,37.35 138.73,38.29 142.41,38.29 143.51,37.19 150.78,37.19 152.32,35.66 156.82,35.66 157.38,36.22 162.99,36.22 164.2,35.01 165.38,35.01 165.72,34.67 165.72,34.2 166.29,33.63 169.08,33.63 169.56,33.14 171.04,33.14 171.83,32.35 v1(171.83,32.19) ; v1(15.81,129.48) 15.91,129.58 v2(16.52,129.58) 16.61,129.49 17.31,129.49 RT12.2
  BOTTOM w0.102: UH1.Y48 173.33,32.47 172.55,31.69 172.34,31.69 v1(171.83,32.19)
RTD3_USB_PWR_EN_R: length 5.3
  TOP w0.102: RT153.2 RT37.1 18.42,129.41 18.31,129.52 RT12.1 18.57,129.91 18.85,129.63 19.63,129.63 v2(20.12,130.12) v1(21.06,131.05)
  BOTTOM w0.102: UT1.D4 v1(21.06,131.05)
RTM_CSCL: length 2.9
  TOP w0.102: UP2.29 22.86,90.63 22.1,89.88 21.51,89.88 21.18,89.55 RP48.1
RTM_CSDA: length 3.3
  TOP w0.102: RP49.1 20.55,89.75 v2(20.9,90.11) 20.98,90.18 22.01,90.18 22.46,90.63 UP2.28
RTM_DCIN_ENB: length 5.3
  TOP w0.102: UP2.3 24.86,97.8 25.11,98.06 25.11,99.07 25.25,99.21 RP39.2 25.25,101.04 25.27,101.07 RP33.2 v2(24.37,101.43)
RTM_EQ: length 6.1
  TOP w0.102: v2(22.4,101.81) 22.97,101.81 23.36,101.43 RP34.2 23.82,101.1 23.82,100.02 RP40.2 23.27,99.47 23.27,99.13 24.06,98.34 UP2.5
RTM_HDMI_ID: length 4.7
  TOP w0.102: UP2.32 24.06,90.57 23.91,90.42 23.91,90.1 24.36,89.65 RP37.2 24.59,89.4 24.73,89.25 24.73,88.53 24.63,88.42 24.63,87.59 RP43.2
RTM_I2C_ADDR: length 4.6
  TOP w0.102: UP2.31 23.66,89.68 23.77,89.56 RP35.2 23.56,89.39 23.39,89.23 23.39,88.35 24.16,87.59 RP41.2
RTM_PDB: length 1.4
  TOP w0.102: UP2.4 24.46,98.47 RP44.2
RTM_PRE: length 5.1
  TOP w0.102: UP2.27 22.06,90.63 21.93,90.5 20.83,90.5 19.96,89.64 RP36.2 19.54,89.27 RP42.2 v2(18.32,89.53)
RTM_RST#: length 7.1
  TOP w0.102: UP2.35 25.26,90.54 25.83,89.97 26.34,89.97 26.65,89.66 RP38.2 26.9,89.31 27.06,89.15 27.06,87.81 CP27.1 27.43,86.14 v2(27.43,85.89)
RUNPWROK: length 4.9
  TOP w0.102: UE1.48 73.71,37.61 73.41,37.92 RE42.2 73,37.87 72.59,37.46 70.97,37.46 v2(70.68,37.76)
SA_SW: length 3
  TOP w0.102: PRA04.1 102.4,138.15 v2(102.79,138.54)
  TOP w0.508: PRA04.1 100.98,137.52 v1(100.7,137.24)
SATA3_PRX_C_DTX_N0: length 3.2
  TOP w0.102: v1(271.79,39.78) 271.56,39.55 270.62,39.55 CS3.2
  BOTTOM w0.102: JHDD.5 272.82,39.75 272.66,39.59 271.98,39.59 v1(271.79,39.78)
SATA3_PRX_C_DTX_P0: length 3.2
  TOP w0.102: CS4.2 270.61,39.34 271.63,39.34 271.65,39.32 271.67,39.32 v1(271.79,39.19)
  BOTTOM w0.102: v1(271.79,39.19) 271.98,39.38 272.67,39.38 272.8,39.25 JHDD.6
SATA3_PRX_DTX_N0: length 1.6
  TOP w0.102: CS3.1 269.57,39.51 269.16,39.51 v1(268.95,39.73)
  BOTTOM w0.089: UH1.C45 165.06,34.11 v1(165.06,34.51)
SATA3_PRX_DTX_P0: length 1.7
  TOP w0.102: v1(268.95,39.08) 269.17,39.31 269.64,39.31 CS4.1
  BOTTOM w0.089: v1(164.53,34.16) 164.53,33.79 UH1.C46
SATA3_PTX_C_DRX_N0: length 3.2
  TOP w0.102: v1(271.27,40.71) 271.09,40.89 270.62,40.89 CS2.2
  BOTTOM w0.102: JHDD.3 272.79,40.75 272.64,40.9 271.46,40.9 v1(271.27,40.71)
SATA3_PTX_C_DRX_P0: length 3.2
  TOP w0.102: v1(271.27,41.29) 271.08,41.1 270.62,41.1 CS1.2
  BOTTOM w0.102: JHDD.2 272.81,41.25 272.66,41.1 271.46,41.1 v1(271.27,41.29)
SATA3_PTX_DRX_N0: length 9.2
  TOP w0.102: CS2.1 269.56,40.93 269.19,40.93 v1(268.95,40.69)
  BOTTOM w0.089: 162.82,37.05 162.84,37.05 162.85,37.04 163.36,37.04 163.77,37.46 163.9,37.46 164.06,37.61 164.06,37.62 164.18,37.73
  BOTTOM w0.102: 162.82,37.05 162.67,37.05 160.88,35.27 160.88,33.71 161.26,33.33 161.8,33.33 161.96,33.17 161.96,32.94 v1(161.59,32.56) ; UH1.B38 164.18,37.73
SATA3_PTX_DRX_P0: length 9.3
  TOP w0.102: v1(268.95,41.32) 269.13,41.14 269.64,41.14 CS1.1
  BOTTOM w0.089: UH1.C38 164.73,37.7 164.53,37.51 164.23,37.51 164.19,37.48 164.04,37.32 163.98,37.27 163.85,37.27 163.44,36.85 162.85,36.85 162.84,36.85 162.82,36.85
  BOTTOM w0.102: v1(162.17,32.56) 162.17,33.26 161.89,33.54 161.34,33.54 161.09,33.79 161.09,35.18 162.75,36.85 162.82,36.85
SATA_LED#_R: length 18.1
  TOP w0.102: v1(160.74,27.91) 160.74,28.1 161.13,28.48 166.04,28.48 R83.2
  BOTTOM w0.102: Q22.3 169.94,24.89 169.47,24.42 165.13,24.42 164.24,25.31 162.45,25.31 162.24,25.51 Q27.3 161.68,25.8 v2(160.84,26.64) 160.74,26.73 v1(160.74,27.91)
SD_RCOMP_1P8: length 4.7
  TOP w0.102: RH668.1 186.91,56.21 v2(186.71,56.01) 185.35,54.66 v1(185.35,53.49)
  BOTTOM w0.089: UH1.BE5 185.41,53.57 185.35,53.51 v1(185.35,53.49)
SD_RCOMP_3P3: length 3.5
  TOP w0.102: v1(185.96,53.99) v2(186.36,54.38) 186.36,55.06 186.93,55.64 187.59,55.64 RH670.1
  BOTTOM w0.089: v1(185.96,53.99) 185.69,54.26 UH1.BE4
SIO_EXT_SCI#: length 6.6
  TOP w0.102: v2(181.03,43.46) 181.56,42.92 v1(181.62,42.92) 182.25,43.55 183.02,43.55 183.3,43.83 183.3,44.07 183.47,44.23 184.01,44.23 184.16,44.08 184.16,43.83 184.35,43.64 184.9,43.64 RH521.2
  BOTTOM w0.102: UH1.AU26 181.79,43.09 v1(181.62,42.92)
SIO_EXT_WAKE#: length 10.6
  TOP w0.102: UE1.116 89.93,38.81 89.72,38.6 89.32,38.6 v1(88.83,39.09) ; RH721.1 188.13,48.45 186.77,47.09 186.77,46.64 186.25,46.13 182.83,46.13 182.36,45.65 v1(182.18,45.65)
  BOTTOM w0.102: UH1.AW21 182.62,45.91 182.36,45.65 v1(182.18,45.65)
SIO_PWRBTN#: length 7.5
  TOP w0.102: v2(184.52,32.42) 184.52,33.16 184.76,33.4 185.33,33.4 185.48,33.25 RH717.1 185.99,33.49 v1(185.99,33.99) ; UE1.52 76.88,36.01 77.55,36.68 77.55,36.87 77.89,37.21 v1(77.89,37.8)
  BOTTOM w0.102: UH1.BE46 185.69,33.69 v1(185.99,33.99)
SIO_SLP_S0#: length 10.3
  TOP w0.102: v1(87.56,25.07) 87.52,25.11 RE90.2 ; RTPM12.2 v2(206.1,36.16) 206.1,36.45 206.23,36.58 v1(206.23,36.94) ; RH682.2 182.8,42.31 182.99,42.5 v1(182.99,42.87) ; RTPM11.2 v1(205.51,31.24)
  BOTTOM w0.102: v1(206.23,36.94) 206.23,35.53 206.53,35.23 206.53,32.26 v1(205.51,31.24)
SIO_SLP_S0#_PCH: length 2.1
  TOP w0.102: v2(184.67,42.96) v1(184.05,42.34) 183.96,42.25 RH682.1
  BOTTOM w0.089: v1(184.05,42.34) 184.5,42.34 UH1.BC28
SIO_SLP_S3#: length 162.6
  TOP w0.102: UZ1.5 53.79,27.89 v1(53.54,27.65) ; v2(53.28,97.7) 53.28,98.07 v1(53.48,98.27) ; RH683.2 142.76,33.76 142.23,33.22 UZ21.2 ; RH683.2 RZ237.1 138.72,34.5 137.96,35.27 135.17,35.27 134.54,35.89 130.85,35.89 129.95,36.78 129.58,36.78 129.21,37.15 v1(129.21,37.28) ; RH683.2 142.96,33.5 143.19,33.27 143.68,33.27 143.83,33.11 143.83,32.62 RH740.1 ; v1(32.85,137.17) 32.85,136.92 31.73,135.8 19.57,135.8 19.2,136.16 v1(19.2,136.26) ; UZ1.3 52.71,28.69 v1(52.59,28.57) 51.03,30.13 51.03,31.71 DZ2.1 51.64,32.32 RZ108.1 51.64,33.66 v1(51.76,33.79)
  BOTTOM w0.102: RT15.2 v1(19.2,136.26) ; v1(53.48,98.27) 54.62,97.13 54.62,90.14 61.74,83.02 102.99,83.02 115.11,70.9 115.11,62.22 117.23,60.1 117.23,58.49 116.26,57.52 116.26,55.5 v1(117.29,54.47) 117.29,54.17 118,53.46 118,49.56 119.89,47.66 119.89,46.19 125.81,40.28 126.84,40.28 129.21,37.91 v1(129.21,37.28) ; v1(112.26,118.26) 112.7,118.26 RZ112.1
SIO_SLP_S3#_AR: length 4.6
  BOTTOM w0.076: 20.89,133.18 21.19,132.88 21.19,132.24 21.03,132.08 UT1.D2
  BOTTOM w0.102: RT30.2 RT15.1 19.2,135.05 v2(20.03,134.22) 20.89,133.36 20.89,133.18
SIO_SLP_S3#_PCH: length 11.3
  TOP w0.102: v1(150.67,32.75) 150.73,32.68 151.59,32.68 v2(151.72,32.81) ; v1(144.32,32.83) 144.32,33.44 144.01,33.76 RH683.1
  BOTTOM w0.102: v1(186.98,35.44) 186.94,35.41 186.31,35.41 186.18,35.54 UH1.BF42 ; v1(150.67,32.75) 149.47,31.55 145.11,31.55 144.32,32.34 v1(144.32,32.83)
SIO_SLP_S4#: length 42.2
  BOTTOM w0.102: RZ111.1 RZ102.1 112.28,116.08 v1(112.17,115.97) 112.17,115.58 112.8,114.95 DZ1.1 ; v1(110.39,92.62) 109.81,92.62 108.17,90.97 108.17,87.47 109.68,85.96 109.68,85.08 120.9,73.85 120.9,71.48 123.37,69.01 v1(123.37,68.35) 124.4,67.32 PR2501.1 ; v1(191.86,37.77) 192.19,37.43 192.19,36.18 RH741.1 192.22,35.95 191.58,35.32 RH684.2
SIO_SLP_S4#_PCH: length 5.1
  BOTTOM w0.102: RH684.1 189.11,36.16 v2(188.7,36.16) 186.33,36.16 186.06,35.89 185.85,35.89 185.51,35.55 UH1.BE42
SLEEVE:
  vias: v1(17.73,13.84) v1(18.33,13.84) v1(31.3,21.26) v1(31.28,20.68) v1(31.89,21.08) v3(18.03,14.34)
SLEEVE_R: length 1.6
  TOP w0.127: v3(19.84,10.74) 19.63,10.74 19.23,10.34
  BOTTOM w0.254: CA41.1 17.96,10.33 v1(18.25,10.63)
  vias: v1(19.19,9.74) v1(19.2,9.1)
SM_PG_CTRL: length 89.3
  TOP w0.102: v1(51.61,96.98) 53.81,96.98 v2(54.82,97.99) 57.61,100.77 57.61,105.72 v1(55.69,107.63)
  BOTTOM w0.102: PRM09.1 40.37,38.08 42.08,38.08 43.49,39.49 43.49,42.93 44.36,43.8 44.36,46.18 44.95,46.76 44.95,50.7 44.22,51.43 44.22,51.88 43.74,52.36 43.74,60.69 43.18,61.25 43.18,64.03 41.23,65.98 41.23,71.95 41.63,72.35 41.63,75.17 41,75.8 41,83.64 42.41,85.05 45.48,85.05 50.51,90.08 50.51,95.88 v1(51.61,96.98) ; v1(55.69,107.63) 56.72,106.6 RC270.2 57.48,106.73 UC10.4
SM_RCOMP0: length 11.4
  TOP w0.381: v1(104.44,94.95) 103.76,94.27 v2(103.76,94.18) RC3.2
  BOTTOM w0.305: UC1.G1 99.22,100.13 100.42,98.94
  BOTTOM w0.381: v1(104.44,94.95) 104.44,97.22 102.71,98.94 100.42,98.94
SM_RCOMP1: length 7.7
  TOP w0.381: v1(102.67,96.77) 102.67,96.16 RC4.2
  BOTTOM w0.254: 99.09,98.93 98.27,99.76 UC1.H1
  BOTTOM w0.305: 99.09,98.93 99.79,98.24
  BOTTOM w0.381: 99.79,98.24 100.03,98 102.23,98 102.67,97.56 v1(102.67,96.77)
SM_RCOMP2: length 10.2
  TOP w0.381: RC5.2 102.77,94.94 v2(103.23,95.4) v1(103.23,96.21)
  BOTTOM w0.305: 100.22,98.47 98.66,100.03 98.66,100.3 98.41,100.55 UC1.J2
  BOTTOM w0.381: 100.22,98.47 102.52,98.47 103.23,97.76 v1(103.23,96.21)
SMBALERT#: length 11.3
  BOTTOM w0.089: UH1.BE25 185.56,44 185.81,44.25 186.11,44.25 186.49,44.64 187.35,44.64 187.52,44.81
  BOTTOM w0.102: RH66.2 193.15,48.73 192.37,48.73 192.19,48.55 v2(191.8,48.55) 190.24,48.55 188.39,46.7 188.39,46.23 188.11,45.95 188.11,45.41 187.52,44.81
SMBCLK: length 6
  BOTTOM w0.089: 187.31,43.93 187,43.62 186.07,43.62 186.01,43.69 185.94,43.69 185.93,43.69 185.67,43.69 185.67,43.69 185.64,43.69 UH1.BE26
  BOTTOM w0.102: QH4.6 189.04,46.09 189.04,45.28 188.79,45.03 RH674.2 188.68,44.75 188.48,44.75 188.24,44.51 188.12,44.51 187.69,44.08 187.46,44.08 187.31,43.93
SMBDATA: length 9.1
  BOTTOM w0.089: UH1.BF26 185.84,43.43 187.17,43.43
  BOTTOM w0.102: QH4.3 191.61,45.82 190.97,45.19 190.68,45.19 190.4,44.91 190.4,43.83 v2(190.18,43.61) 189.7,43.61 189.4,43.92 189.03,43.92 188.91,44.03 188.91,44.14 RH675.2 188.48,43.97 187.99,43.97 187.91,43.89 187.62,43.89 187.17,43.43
SML0_SMBCLK: length 5.8
  TOP w0.102: RH62.2 189.22,45.24 189.28,45.3 RH501.2 188.6,45.67 v1(188.55,45.71) 188.27,45.43 v2(188.27,44.93)
  BOTTOM w0.089: v1(188.55,45.71) 188.55,45.58 187.42,44.46 186.56,44.46 186.1,44 UH1.BF25
SML0_SMBDATA: length 10.9
  TOP w0.102: RH502.2 191.48,48.45 RH63.2 190.4,48.15 190.65,47.9 190.65,46.9 v2(190.55,46.8) 190.39,46.63 188.25,46.63 187.49,45.88 187.49,45.32 187.13,44.95 v1(184.48,44.95)
  BOTTOM w0.089: v1(184.48,44.95) 185,44.95 UH1.BE24
SML0ALERT#: length 7.7
  BOTTOM w0.089: 187.57,45.13 187.25,44.82 186.18,44.82 185.9,44.53 UH1.BF24
  BOTTOM w0.102: RH64.2 190.7,49.48 v2(189.77,48.54) 188.16,46.94 188.16,46.32 187.92,46.08 187.92,45.49 187.57,45.13
SML1ALERT#: length 5.8
  BOTTOM w0.089: 187.22,40.59 186.59,40.59 186.19,40.19 185.22,40.19 UH1.BD33
  BOTTOM w0.102: 187.22,40.59 188.09,40.59 RH65.2 v2(190.13,39.58)
SNB_1.0VS_VGAP: length 1.3
  BOTTOM w0.102: PC1004.1 v2(199.46,76.67)
SNB_VCCIO: length 1.9
  BOTTOM w0.102: 55.03,121.33 55.03,122.03 55.28,122.29 v2(56.12,122.29)
SNUB1_CHG: length 1.7
  TOP w0.102: PCB36.1 v3(243.33,41.32)
SNUB2_CHG: length 1.3
  TOP w0.102: 240.72,56.08 v3(242.02,56.08)
SNUB_+1.05V: length 1
  BOTTOM w0.102: PCH12.1 v2(139.91,40.65)
SPKR: length 24.6
  TOP w0.102: v1(182.38,41.01) 182.83,41.46 RH685.2 ; v1(50.7,34.9) 49.73,33.93 47.01,33.93 v2(46.62,33.55) 44.36,31.29 38.22,31.29 36.94,30.02 36.94,28.52 36.49,28.07 33.29,28.07 32.44,27.21 DA3.2
  BOTTOM w0.102: UH1.AW29 182.62,41.24 v1(182.38,41.01)
SSD_DEVSLP: length 14.9
  TOP w0.102: v1(33.13,25.11) 33.83,25.82 RS9.2 ; v1(177.69,38.61) 177.69,38.45 178.02,38.12 179.17,38.12 179.41,37.88 179.41,36.8 179.24,36.63 179.24,36.03 178.96,35.75 178.96,35.06 179.27,34.74 179.27,34.28 177.9,32.9 v1(177.9,32.42)
  BOTTOM w0.102: v1(33.13,25.11) 30.71,25.11 30.12,25.7 JSSD1.38 ; v1(177.69,38.61) 177.21,39.08 UH1.AH35
SSD_LED#: length 6.9
  TOP w0.102: v2(38.38,30.44) 38.61,30.21 v1(39.03,30.21) 39.1,30.28 R77.1
  BOTTOM w0.102: v1(39.03,30.21) 39.03,29.04 38.3,28.31 37.14,28.31 36.87,28.04 36.87,27.54 37.12,27.29 JSSD1.10
STRAP0: length 6.5
  TOP w0.102: RV146.1 229.96,94.22 RV152.2 229.96,94.75 229.53,95.19 228.38,95.19 227.49,96.08 226.67,96.08 v2(226.22,95.63)
  BOTTOM w0.109: UV1.J2 226.67,96.08
STRAP1: length 34
  TOP w0.102: RV147.1 RV153.2 253.96,90.71 252.12,90.71 250.52,89.11 245.71,89.11 240.5,94.32 v2(240.4,94.32) 235.86,98.85 232.42,98.85 231.11,100.16 227.53,100.16
  BOTTOM w0.109: 227.53,100.16 227.47,100.16 227.1,99.79 UV1.J7
STRAP2: length 33.4
  TOP w0.102: 227.47,99.27 228.02,99.82 231.05,99.82 232.33,98.53 235.56,98.53 v2(237.53,96.56) 240.68,93.42 241.08,93.42 245.61,88.88 253.93,88.88 RV154.2 RV148.1
  BOTTOM w0.109: UV1.J6 227.47,99.27
STRAP3: length 11.3
  TOP w0.102: 227.54,97.66 228.3,96.9 228.3,96.25 228.9,95.64 230.43,95.64 230.46,95.61 231.15,95.61 231.25,95.72 232.03,95.72 232.63,95.12 RV155.2 232.83,94.4 232.83,93.43 233.39,92.87 RV149.1 v2(233.76,91.73)
  BOTTOM w0.109: 227.54,97.66 227.49,97.66 UV1.J5
STRAP4: length 5
  TOP w0.102: RV150.1 229.3,93.3 229.17,93.43 RV156.2 229.17,93.48 228.58,94.08 228.58,94.68 228.31,94.94 v2(228.08,94.94) 227.8,94.94 227.5,95.24
  BOTTOM w0.109: UV1.J3 227.1,96.26 227.52,95.84 227.52,95.26 227.5,95.24
STRAP5: length 5.2
  TOP w0.102: v2(227.1,91.68) 226.75,92.04 RV593.1 226.73,92.66 226.52,92.66 RV66.2 226.26,93.39 227.35,93.39 227.54,93.58
  BOTTOM w0.109: 227.54,93.58 227.1,94.02 UV1.J1
SUSCLK: length 9.3
  BOTTOM w0.076: 187.19,34.35 185.73,34.35 UH1.BE45
  BOTTOM w0.102: 187.19,34.35 187.77,34.35 188.06,34.06 188.06,33.26 187.26,32.46 187.26,30.9 186.99,30.62 186.99,30.13 RH714.2 RH713.2
SUSCLK_EC: length 30
  TOP w0.102: v1(94.01,42.56) 93.96,42.61 RE45.2 ; v1(101.7,38.15) 102.37,38.15 102.88,38.66 v2(105.86,38.66) 106.31,38.66 106.88,38.09 106.88,36.68 107.84,35.72 107.84,33.12 105.38,30.66 v1(105.38,27.95)
  BOTTOM w0.102: v1(101.7,38.15) 100.98,37.43 98.69,37.43 94.63,41.49 94.63,41.94 v1(94.01,42.56) ; RH714.1 186,28.23 185.23,27.46 v1(184.85,27.46)
SUSCLK_WLAN: length 1.8
  BOTTOM w0.102: v1(40.78,105.33) 40.7,105.41 JWLAN1.50 ; RH713.1 185.42,28.23 v1(185.21,28.02)
SW1_2PH: length 7.7
  TOP w0.102: v1(55.52,140.66) v2(56.22,140.66)
  TOP w0.203: v1(114.55,153.49) 114.55,151.44 114.45,151.33 PRZ60.2
  BOTTOM w0.152: PLG01.2 v1(55.52,140.66)
  BOTTOM w0.203: PRZ51.2 114.45,150.14 114.55,150.25 v1(114.55,153.49)
SW1_4PH: length 22.6
  TOP w0.152: PRZ35.1 v1(100.24,150.53)
  TOP w0.203: v1(100.24,150.53) 99.89,150.53 98.17,148.82 98.17,139.98 96.98,138.78 v2(95.58,138.78) 94.67,138.78 v1(91.41,135.53)
  BOTTOM w0.152: v1(100.24,150.53) 100.66,150.12 PRZ61.1
  BOTTOM w0.203: PLI01.2 v1(91.41,135.53)
SW2_4PH: length 3.2
  TOP w0.102: v1(81.07,141.81) v2(80.23,141.81)
  TOP w0.152: PRZ36.1 v1(100.24,151.8)
  BOTTOM w0.152: v1(100.24,151.8) 100.4,151.65 PRZ62.1
  BOTTOM w0.203: PLI02.2 v1(81.07,141.81)
SW3_4PH: length 3
  TOP w0.102: v1(73.49,141.87) v2(72.72,141.87)
  TOP w0.152: PRZ37.1 v1(100.22,153.07)
  BOTTOM w0.152: v1(100.22,153.07) 100.31,153.17 PRZ63.1
  BOTTOM w0.203: PLI03.2 v1(73.49,141.87)
SW4_4PH: length 3.2
  TOP w0.102: v1(65.79,141.81) v2(66.61,141.81)
  TOP w0.152: PRZ38.1 v1(100.26,154.34)
  BOTTOM w0.152: PRZ64.1 100.61,154.69 v1(100.26,154.34)
  BOTTOM w0.203: PLI04.2 v1(65.79,141.81)
SW_1PH: length 14.2
  TOP w0.254: v1(99.52,136.39) 99.52,138.58 100,139.06 103.53,139.06 v2(104.34,138.25) 104.8,137.8 106.03,137.8 106.39,137.44 107.67,137.44 108.04,137.81 PRZ13.2
  BOTTOM w0.152: v1(99.52,136.39) 98.21,136.39 97.99,136.61 PLA01.2
SYS_PEX_RST_MON#: length 2.8
  BOTTOM w0.102: 204.31,95.69 202.96,97.03 RV532.1 ; UV1.R8 222.5,100.15
SYS_PWROK: length 46.1
  TOP w0.102: v1(152.83,53.97) 152.83,54.62 153.21,55 169.52,55 170.28,54.24 173.18,54.24 174.92,55.98 v3(179.92,55.98) 180.38,55.98 v1(180.86,56.46) ; UE1.28 78.29,46.04 77.66,46.68 74.54,46.68 74.12,47.1 RE68.1 74.6,47.78 74.6,48.51 74.33,48.78 v1(74.33,48.93)
  BOTTOM w0.089: 182.15,57.04 182.15,55.88 181.75,55.48 181.75,55.07 UH1.AU3
  BOTTOM w0.102: 182.15,57.04 182.36,57.25 182.36,58.18 182.68,58.49 184.23,58.49 184.49,58.75 RH673.2 ; UH1.AU3 181.36,54.81 181.11,55.07 181.11,55.42 180.86,55.66 v1(180.86,56.46)
SYS_RESET#: length 5.6
  BOTTOM w0.089: 181.88,56.52 181.88,55.94 181.46,55.53 UH1.AU2
  BOTTOM w0.102: 181.88,56.52 181.88,57.88 v2(181.95,57.96) 181.95,58.16 182.18,58.39 182.18,58.9 RH737.1 RH571.1 CH209.1
SYSPWR_PRES: length 9.6
  TOP w0.102: RE29.1 97.79,40.54 v2(97.47,40.54) 96.99,40.54 96.67,40.22 96.67,39.97 RE32.1 96.15,39.73 96.15,40.06 95.94,40.27 93.96,40.27 93.42,39.74 92.19,39.74 91.51,40.41 UE1.120
T_CRIT#: length 3.5
  BOTTOM w0.102: v2(197.9,58.98) 197.57,58.64 R29.2 196.3,58.3 196.3,57.61 196.4,57.51 U2.4
TBT_A_AUX_N: length 2.4
  TOP w0.102: CT44.2 28.26,126.53 27.58,125.85 v1(27.55,125.85)
  BOTTOM w0.102: UT1.W15 27.89,126.14 27.59,125.85 v1(27.55,125.85)
TBT_A_AUX_N_C: length 15.8
  TOP w0.102: v1(33.5,125) 33.4,125.09 33.4,125.44 33.17,125.67 30.94,125.67 30.21,126.4 29.86,126.4 CT44.1
  BOTTOM w0.076: UT4.J2 35.3,90.84 35.3,91.64 35.89,92.23 36.39,92.23 37.07,92.91 37.07,93.31 RT70.2
  BOTTOM w0.102: RT70.2 37.11,93.78 37.11,95.66 37.24,95.78 v4(37.24,96.29) 37.24,96.82 35.62,98.44 35.62,99.47 v1(35.77,99.62)
TBT_A_AUX_P: length 2.4
  TOP w0.102: CT43.2 28.87,125.69 28.77,125.69 28.68,125.78 28.68,126.22 28.61,126.28 28.36,126.28 28.21,126.13 v1(28.21,125.85)
  BOTTOM w0.102: UT1.Y15 28.54,126.17 v1(28.21,125.85)
TBT_A_AUX_P_C: length 15.8
  TOP w0.102: v1(32.91,125) 33.16,125.24 33.16,125.34 33.07,125.43 30.84,125.43 30.11,126.16 29.93,126.16 CT43.1
  BOTTOM w0.076: UT4.J1 35.05,90.8 35,90.74 34.87,90.74 34.8,90.81 34.8,91.14 34.94,91.28 35.05,91.28 35.13,91.37 35.13,91.71 35.82,92.4 36.32,92.4 36.9,92.98 36.9,93.3 RT73.1
  BOTTOM w0.102: v1(35.19,99.62) 35.37,99.43 35.37,98.34 36.99,96.72 36.99,95.88 36.87,95.76 36.87,93.79 RT73.1
TBT_A_CC1: length 8.3
  TOP w0.102: v1(36.86,85.94) 37.04,85.94 v2(37.39,86.28)
  TOP w0.254: JUSBC1.B5 6.29,120.57 6.42,120.45 v1(6.51,120.45)
  BOTTOM w0.203: v1(13.29,109.45) 13.29,109.34 12.9,108.95 DT11.8 DT11.2 12.9,106.11 v1(12.77,105.98) ; UT4.K9 UT4.L9 36.25,86.99 36.37,87.1 36.71,87.1 37.38,86.44 CT112.1
  BOTTOM w0.254: CT112.1 37.25,86.26 36.96,86.26 36.86,86.16 v1(36.86,85.94)
TBT_A_CC2: length 8.8
  TOP w0.102: v1(37.41,85.17) v2(38.26,85.17)
  TOP w0.254: v1(9.27,121.97) 9.02,121.72 7.84,121.72 7.73,121.82 JUSBC1.A5
  BOTTOM w0.203: v1(13.61,106.33) 13.4,106.54 DT11.1 DT11.9 v1(13.4,108.8)
  BOTTOM w0.254: UT4.K10 UT4.L10 36.4,86.14 36.4,85.6 36.83,85.17 v1(37.41,85.17) CT113.1
TBT_A_SBU1: length 8.8
  TOP w0.102: v1(6.51,122.2) 6.39,122.07 JUSBC1.B8
  BOTTOM w0.076: 37.56,86.84 37.54,86.84 37.5,86.88 37.32,86.88 36.86,87.35 36.29,87.35 36.18,87.24 35.95,87.24 UT4.K8
  BOTTOM w0.102: v1(39.22,86.36) 39.04,86.53 38.88,86.53 38.58,86.84 37.56,86.84 ; v1(12.75,109.72) 12.75,109.25 11.9,108.39 DT11.7 DT11.4 11.9,106.61 v1(11.69,106.41)
TBT_A_SBU2: length 13.9
  TOP w0.102: JUSBC1.A8 7.73,120.32 7.99,120.59 9.23,120.59 9.48,120.34 9.96,120.34 10.14,120.15 11.62,120.15 11.82,119.95 11.82,119.77 11.73,119.68 v1(11.06,119.68)
  BOTTOM w0.076: 37.56,87.09 37.54,87.09 37.5,87.05 37.39,87.05 36.93,87.51 36.08,87.51 UT4.L8
  BOTTOM w0.102: v1(12.22,109.3) 12.22,109.06 11.8,108.64 11.5,108.64 11.4,108.54 DT11.6 DT11.5 11.4,106.8 11.28,106.69 11.28,105.96 v1(11.37,105.88) ; v1(39.74,86.64) 39.6,86.78 38.99,86.78 38.68,87.09 37.56,87.09
TBT_A_TRX_DTX_N0: length 18.4
  TOP w0.102: JUSBC1.A10 7.81,119.32 arc(7.9,119.31) 7.98,119.25 arc(8.03,119.22) 8.09,119.21 8.09,119.21 arc(8.44,119.06) 8.58,118.72 8.58,118.56 arc(8.6,118.46) 8.66,118.38 8.91,118.13 arc(9.05,118.03) 9.22,118 10.17,118 arc(10.5,118.07) 10.79,118.26 arc(11.17,118.51) 11.61,118.6 13.05,118.6 arc(13.19,118.63) 13.31,118.7 DT5.1 13.51,118.76 arc(13.67,118.65) 13.85,118.62 13.99,118.62 arc(14.07,118.63) 14.15,118.68 14.23,118.77 arc(14.53,118.97) 14.89,119.04 17.97,119.04 arc(18.27,119.17) 18.4,119.46 18.4,120.65 arc(18.31,120.87) 18.08,120.96 17.61,120.96 arc(16.64,121.36) 16.22,122.32 16.22,122.32 arc(16.21,122.43) 16.2,122.53 16.2,122.93 arc(16.32,123.22) 16.61,123.34 16.71,123.34 arc(16.83,123.39) 16.87,123.5 RT162.1
TBT_A_TRX_DTX_N0_R: length 2.8
  TOP w0.102: RT162.2 17.56,123.43 arc(17.66,123.36) 17.78,123.34 18.19,123.34 arc(18.29,123.36) 18.37,123.42 v1(18.47,123.51)
  BOTTOM w0.076: UT1.A21 19.62,123.34 arc(19.7,123.37) 19.73,123.45 19.73,123.46 arc(19.7,123.54) 19.62,123.57 19.52,123.57 arc(19.41,123.55) 19.31,123.49 19.25,123.42 arc(19.1,123.32) 18.93,123.29 18.85,123.29 arc(18.7,123.32) 18.57,123.4 v1(18.47,123.51)
TBT_A_TRX_DTX_N1: length 16.3
  TOP w0.102: v1(6.51,123.37) 6.35,123.37 6.06,123.07 JUSBC1.B10
  BOTTOM w0.102: RT160.1 15.58,125.88 arc(15.49,125.94) 15.4,125.96 15.03,125.96 arc(14.86,125.89) 14.79,125.72 14.79,123.26 arc(13.91,122.37) 13.02,123.26 13.02,124.05 arc(12.88,124.39) 12.54,124.53 12.18,124.53 arc(12.08,124.51) 12,124.45 DT9.1 11.69,124.44 arc(11.59,124.51) 11.47,124.53 11.47,124.53 arc(11.14,124.53) 10.81,124.53 10.8,124.53 arc(10.46,124.59) 10.17,124.79 10,124.95 arc(9.89,125.05) 9.76,125.12 9.59,125.19 arc(9.59,125.19) 9.58,125.19 arc(9.26,125.19) 8.98,125.03 arc(8.76,124.7) 8.68,124.31 8.68,124.19 arc(8.48,123.72) 8.01,123.53 6.73,123.53 arc(6.67,123.51) 6.61,123.48 v1(6.51,123.37)
TBT_A_TRX_DTX_N1_R: length 4.1
  BOTTOM w0.076: UT1.B15 19.92,125.99 arc(19.81,125.91) 19.68,125.88 19.49,125.88 arc(19.4,125.9) 19.33,125.95 19.29,125.99 arc(19.19,126.06) 19.07,126.08 arc(18.95,126.1) 18.86,126.17 18.78,126.24 arc(18.73,126.27) 18.67,126.28 18.53,126.28 18.49,126.24 18.47,126.24
  BOTTOM w0.102: RT160.2 16.41,125.84 arc(16.51,125.91) 16.63,125.93 17.37,125.93 arc(17.52,125.96) 17.64,126.04 17.8,126.2 arc(17.84,126.23) 17.9,126.24 18.47,126.24
TBT_A_TRX_DTX_P0: length 18.4
  TOP w0.102: JUSBC1.A11 7.8,118.82 arc(7.88,118.84) 7.96,118.89 7.98,118.92 arc(8.03,118.95) 8.09,118.96 arc(8.26,118.89) 8.34,118.72 8.34,118.56 arc(8.37,118.37) 8.48,118.21 8.73,117.96 arc(8.96,117.81) 9.22,117.75 10.17,117.75 arc(10.6,117.84) 10.96,118.08 arc(11.26,118.28) 11.61,118.35 13.05,118.35 arc(13.19,118.32) 13.31,118.24 DT4.1 13.57,118.25 arc(13.7,118.34) 13.85,118.37 13.99,118.37 arc(14.17,118.41) 14.32,118.51 14.41,118.59 arc(14.63,118.74) 14.89,118.8 17.97,118.8 arc(18.45,118.99) 18.64,119.46 18.64,120.65 arc(18.48,121.04) 18.08,121.21 17.61,121.21 arc(16.81,121.53) 16.46,122.33 arc(16.46,122.34) 16.46,122.35 arc(16.45,122.44) 16.45,122.53 16.45,122.93 arc(16.5,123.05) 16.61,123.09 16.7,123.09 arc(16.79,123.06) 16.85,122.98 RT161.1
TBT_A_TRX_DTX_P0_R: length 2.8
  TOP w0.102: v1(18.47,122.92) 18.37,123.02 arc(18.29,123.07) 18.19,123.09 17.78,123.09 arc(17.66,123.07) 17.56,123 RT161.2
  BOTTOM w0.076: v1(18.47,122.92) 18.57,123.03 arc(18.68,123.1) 18.8,123.12 19.68,123.12 arc(19.81,123.15) 19.92,123.23 UT1.B21
TBT_A_TRX_DTX_P1: length 16.3
  TOP w0.102: v1(6.51,123.95) 6.13,123.57 JUSBC1.B11
  BOTTOM w0.102: v1(6.51,123.95) 6.6,123.86 arc(6.7,123.79) 6.81,123.77 8.01,123.77 arc(8.31,123.89) 8.43,124.19 8.43,124.31 arc(8.53,124.79) 8.8,125.2 arc(9.19,125.43) 9.65,125.43 arc(9.67,125.42) 9.68,125.42 9.86,125.34 arc(10.03,125.25) 10.18,125.13 10.34,124.96 arc(10.55,124.82) 10.8,124.77 10.81,124.77 arc(11.14,124.77) 11.46,124.78 arc(11.6,124.81) 11.72,124.89 DT8.1 11.99,124.85 arc(12.08,124.8) 12.18,124.77 12.54,124.77 arc(13.05,124.56) 13.27,124.05 13.27,123.26 arc(13.91,122.62) 14.55,123.26 14.55,125.72 arc(14.69,126.06) 15.03,126.2 15.42,126.2 arc(15.54,126.23) 15.65,126.3 RT159.1
TBT_A_TRX_DTX_P1_R: length 4.1
  BOTTOM w0.076: UT1.A15 19.69,126.1 arc(19.8,126.21) 19.69,126.33 19.32,126.33 arc(19.27,126.32) 19.23,126.29 arc(19.18,126.26) 19.12,126.24 19.07,126.24 arc(19.02,126.25) 18.97,126.28 18.9,126.36 arc(18.8,126.43) 18.67,126.45 18.53,126.45 18.49,126.49 18.47,126.49
  BOTTOM w0.102: 18.47,126.49 17.9,126.49 arc(17.75,126.46) 17.63,126.38 17.47,126.22 arc(17.42,126.19) 17.37,126.18 16.63,126.18 arc(16.51,126.2) 16.41,126.27 RT159.2
TBT_A_TTX_C_DRX_N0: length 18.1
  TOP w0.102: JUSBC1.B3 6.25,119.57 v1(6.55,119.27)
  BOTTOM w0.102: CT42.1 16.78,124.32 16.66,124.2 arc(16.6,124.16) 16.53,124.15 16.41,124.13 16.4,124.13 16.36,124.12 arc(16.27,124.1) 16.19,124.06 16.2,124.05 arc(15.99,123.85) 15.91,123.57 15.91,123.51 arc(15.97,123.23) 16.13,122.99 16.17,122.95 arc(16.94,121.79) 17.21,120.43 arc(16.8,119.43) 15.8,119.02 12.79,119.02 11.78,119.02 arc(11.29,118.92) 10.87,118.64 10.26,118.03 10.25,118.03 arc(10.02,118.04) DT3.1 9.82,118.12 arc(9.71,118.03) 9.57,118 9.41,118 arc(8.72,118.11) 8.08,118.39 7.51,118.82 7.41,118.93 arc(7.23,119.05) 7.01,119.09 6.85,119.09 arc(6.74,119.11) 6.65,119.17 v1(6.55,119.27)
TBT_A_TTX_C_DRX_N1: length 17.5
  TOP w0.102: CT40.1 16.68,124.97 arc(16.52,125.08) 16.33,125.12 16.09,125.12 arc(15.79,125.24) 15.66,125.54 15.66,126.8 arc(15.53,127.12) 15.21,127.25 15.09,127.25 arc(14.78,127.12) 14.65,126.81 14.65,123.83 arc(14.48,123.41) 14.06,123.24 14,123.24 arc(13.53,123.43) 13.33,123.91 13.33,124.1 arc(13.2,124.41) 12.89,124.54 12.25,124.54 arc(12.1,124.51) 11.97,124.42 DT7.1 11.71,124.42 arc(11.58,124.51) 11.43,124.54 11.13,124.54 arc(10.84,124.6) 10.59,124.76 arc(10.22,125.01) 9.78,125.1 9.19,125.1 arc(8.82,124.95) 8.67,124.58 8.67,123.63 arc(8.63,123.41) 8.5,123.22 8.5,123.22 8.34,123.06 arc(8.21,122.97) 8.05,122.94 7.97,122.94 arc(7.96,122.94) 7.96,122.94 arc(7.88,122.92) 7.81,122.88 arc(7.75,122.84) 7.69,122.82 JUSBC1.A3
TBT_A_TTX_C_DRX_P0: length 18.1
  TOP w0.102: JUSBC1.B2 6.17,119.07 v1(6.55,118.69)
  BOTTOM w0.102: CT41.1 16.7,123.78 arc(16.61,123.84) 16.5,123.87 arc(16.48,123.87) 16.46,123.87 arc(16.38,123.87) 16.31,123.84 arc(16.2,123.73) 16.16,123.57 16.16,123.51 arc(16.19,123.32) 16.3,123.16 16.34,123.12 arc(17.17,121.89) 17.46,120.43 arc(16.97,119.26) 15.8,118.77 13.79,118.77 11.78,118.77 arc(11.38,118.69) 11.04,118.46 10.43,117.86 arc(10.35,117.8) 10.25,117.78 10.21,117.78 arc(10.18,117.78) 10.14,117.77 10.09,117.77 arc(9.97,117.72) 9.92,117.6 DT2.1 9.84,117.61 arc(9.68,117.72) 9.5,117.75 arc(9.45,117.75) 9.4,117.75 arc(8.65,117.87) 7.95,118.18 7.95,118.17 arc(7.63,118.39) 7.34,118.65 7.24,118.75 arc(7.13,118.82) 7.01,118.84 6.82,118.84 arc(6.72,118.82) 6.63,118.76 v1(6.55,118.69)
TBT_A_TTX_C_DRX_P1: length 17.5
  TOP w0.102: CT39.1 16.64,125.49 arc(16.5,125.4) 16.33,125.36 16.09,125.36 arc(15.96,125.41) 15.91,125.54 15.91,126.8 arc(15.7,127.29) 15.21,127.5 15.09,127.5 arc(14.61,127.3) 14.4,126.81 14.4,123.83 arc(14.3,123.59) 14.06,123.49 14,123.49 arc(13.7,123.61) 13.58,123.91 13.58,124.1 arc(13.38,124.58) 12.89,124.79 12.19,124.79 arc(12.07,124.81) 11.97,124.88 DT6.1 11.75,124.92 arc(11.6,124.82) 11.43,124.79 11.13,124.79 arc(10.93,124.82) 10.77,124.94 arc(10.31,125.24) 9.78,125.35 9.19,125.35 arc(8.65,125.12) 8.42,124.58 8.42,123.63 arc(8.4,123.51) 8.33,123.4 8.25,123.33 8.25,123.32 8.16,123.24 arc(8.11,123.2) 8.05,123.19 7.95,123.19 arc(7.88,123.2) 7.82,123.24 7.8,123.26 arc(7.73,123.31) 7.64,123.32 JUSBC1.A2
TBT_A_TTX_DRX_N0: length 2.9
  BOTTOM w0.076: 18.05,124.14 18.06,124.14 18.11,124.1 18.22,124.1 arc(18.3,124.11) 18.37,124.16 18.43,124.22 arc(18.56,124.31) 18.7,124.33 19.16,124.33 arc(19.26,124.35) 19.34,124.41 19.34,124.41 arc(19.42,124.46) 19.51,124.48 19.67,124.48 arc(19.81,124.45) 19.92,124.37 UT1.B19
  BOTTOM w0.102: CT42.2 17.39,124.33 17.49,124.23 arc(17.59,124.16) 17.71,124.14 18.05,124.14
TBT_A_TTX_DRX_N1: length 3.1
  TOP w0.102: v1(18.11,124.96) 18.02,125.05 arc(17.93,125.11) 17.83,125.13 17.54,125.13 arc(17.44,125.11) 17.36,125.05 CT40.2
  BOTTOM w0.076: UT1.B17 19.92,125.07 arc(19.81,124.99) 19.68,124.96 19.49,124.96 arc(19.4,124.98) 19.33,125.03 19.29,125.07 arc(19.17,125.14) 19.04,125.17 18.47,125.17 arc(18.33,125.14) 18.21,125.06 v1(18.11,124.96)
TBT_A_TTX_DRX_P0: length 2.9
  BOTTOM w0.076: 18.05,123.89 18.06,123.89 18.11,123.93 18.22,123.93 arc(18.36,123.96) 18.49,124.04 18.55,124.11 arc(18.62,124.15) 18.7,124.17 19.12,124.17 arc(19.21,124.15) 19.29,124.1 19.3,124.09 arc(19.36,124.04) 19.44,124.03 19.67,124.03 arc(19.78,124.14) 19.67,124.26 UT1.A19
  BOTTOM w0.102: CT41.2 17.39,123.7 17.49,123.8 arc(17.59,123.87) 17.71,123.89 18.05,123.89
TBT_A_TTX_DRX_P1: length 3.1
  TOP w0.102: CT39.2 17.36,125.45 arc(17.44,125.39) 17.54,125.37 17.83,125.37 arc(17.93,125.39) 18.02,125.45 v1(18.11,125.54)
  BOTTOM w0.076: v1(18.11,125.54) 18.21,125.44 arc(18.33,125.36) 18.47,125.33 19.25,125.33 arc(19.31,125.35) 19.36,125.38 19.37,125.39 arc(19.41,125.41) 19.45,125.42 19.69,125.42 arc(19.75,125.4) 19.78,125.33 19.78,125.29 arc(19.77,125.25) 19.75,125.22 19.74,125.21 arc(19.71,125.19) 19.67,125.18 UT1.A17
TBT_A_USB20_L_NB: length 6.6
  TOP w0.102: JUSBC1.A7 7.72,120.82 7.91,121.02 8.14,121.02 8.16,121 8.84,121 8.86,121.02 9.32,121.02 10.39,122.1 10.74,122.1 10.85,121.99 DT10.7 DT10.4 12.38,121.99 12.52,122.13 12.84,122.13 12.97,122 LT3.2
TBT_A_USB20_L_NT: length 4.2
  TOP w0.102: LT2.3 13.06,120.83 12.54,120.83 12.38,120.99 DT10.2 DT10.8 10,120.99 v1(9.94,121.04) ; JUSBC1.B7 6.46,121.57 v1(6.51,121.62)
TBT_A_USB20_L_PB: length 6.6
  TOP w0.102: LT3.3 13.01,122.5 12.84,122.33 12.54,122.33 12.38,122.49 DT10.5 DT10.6 10.83,122.49 10.65,122.31 10.31,122.31 9.23,121.23 v4(8.48,121.23) 7.85,121.23 7.75,121.32 JUSBC1.A6
TBT_A_USB20_L_PT: length 3.8
  TOP w0.102: JUSBC1.B6 6.46,121.07 v1(6.51,121.03) ; v1(10.31,120.57) 10.4,120.49 DT10.9 DT10.1 12.38,120.49 12.52,120.62 13.06,120.62 LT2.2
TBT_A_USB20_N: length 4.5
  TOP w0.102: RT131.2 42.25,89.58 42.25,89.73 42.05,89.92 41.62,89.92 40.98,89.29 40.98,88.57 40.62,88.2 40.13,88.2 v1(39.9,87.98)
  BOTTOM w0.089: UT1.D20 20.74,123.58 v1(21.07,123.91)
TBT_A_USB20_NB: length 3.3
  TOP w0.102: v1(15.46,121.96) 15.28,122.14 14.84,122.14 14.7,122 LT3.1
  BOTTOM w0.089: UT4.L7 36.11,87.93 37.42,87.93 37.81,87.74 v1(38.06,87.5)
TBT_A_USB20_NT: length 3.3
  TOP w0.102: LT2.4 14.72,120.97 14.85,120.85 15.25,120.85 v1(15.46,121.06)
  BOTTOM w0.089: v1(37.94,88.35) 37.55,88.74 36.93,88.74 36.67,88.49 UT4.L6
TBT_A_USB20_P: length 4.9
  TOP w0.102: v1(39.9,88.64) 40.13,88.41 40.53,88.41 40.78,88.65 40.78,89.37 41.54,90.13 42.14,90.13 42.82,89.44 RT130.2
  BOTTOM w0.089: UT1.E20 v1(21.71,123.9)
TBT_A_USB20_PB: length 3.4
  TOP w0.102: LT3.4 14.73,122.5 14.88,122.34 15.26,122.34 v1(15.46,122.54)
  BOTTOM w0.089: v1(37.45,87.5) 37.53,87.58 37.53,87.66 37.38,87.74 35.93,87.74 UT4.K7
TBT_A_USB20_PT: length 3.3
  TOP w0.102: LT2.1 14.7,120.47 14.87,120.64 15.3,120.64 v1(15.46,120.48)
  BOTTOM w0.089: v1(37.33,88.34) 37.13,88.55 37,88.55 36.69,88.24 35.67,88.24 35.55,88.35 UT4.K6
TBT_CIO_PLUG_EVENT#: length 5.8
  TOP w0.102: v1(186.51,51.14) v2(187.15,51.14)
  BOTTOM w0.076: 28.09,133.42 28.09,132.31 UT1.W2
  BOTTOM w0.089: v1(186.51,51.14) 186.51,51.79 186.02,52.28 UH1.BF8
  BOTTOM w0.102: RT29.2 28.92,134.85 28.54,134.47 v1(28.2,134.47) 28.2,133.92 28.09,133.81 28.09,133.42
TBT_CONFIG: length 4.2
  TOP w0.102: RT112.2 35.85,90.66 RT113.1 v2(36.47,89.64) 36.47,89.4 35.55,88.49 v1(35.04,88.49)
  BOTTOM w0.076: UT4.H6 v1(35.04,88.49)
TBT_EE_CLK: length 2.7
  BOTTOM w0.076: 30.43,131.96 29.86,131.39 29.47,131.39 UT1.AB4
  BOTTOM w0.102: 30.43,131.96 30.56,132.09 31.17,132.09 RT101.1
TBT_EE_CLK_R: length 4.4
  TOP w0.102: v1(32.4,132.86) 32.42,132.88 v2(33.37,132.88) ; v1(30.19,118.48) 30.19,118.36 RT157.2
  BOTTOM w0.102: v1(32.4,132.86) 32.03,132.49 RT101.2 ; 17.93,90.81 17.93,91.13 v1(16.95,92.11)
TBT_EE_CS_N: length 5.8
  TOP w0.102: RT50.2 31.05,120.2 v1(30.68,120.56) ; v2(30.58,133.83) 30.83,133.58 v1(30.83,133.1)
  BOTTOM w0.076: 30.34,132.57 30.23,132.45 30.23,131.99 29.85,131.62 UT1.AC3
  BOTTOM w0.089: 30.34,132.57 30.83,133.05 v1(30.83,133.1)
  BOTTOM w0.102: UT2.1 15.39,98.5 16.22,99.32 v1(16.8,99.32)
TBT_EE_DI: length 6.6
  TOP w0.102: v1(31.68,133.39) 31.68,133.79 v2(32,134.12)
  BOTTOM w0.076: UT1.AB3 29.24,131.65 29.43,131.85 29.84,131.85 30,132.01 30,132.49 30.14,132.63
  BOTTOM w0.102: UT2.5 19.2,91.13 18.2,92.14 v1(17.92,92.14) ; v1(31.68,133.39) 31.55,133.52 30.72,133.52 30.46,133.26 30.46,132.94 30.14,132.63
TBT_EE_DO: length 3.1
  TOP w0.102: RT49.2 30.88,120.98 v1(30.71,121.15)
  BOTTOM w0.089: UT1.AC4 30.13,131.16
  BOTTOM w0.102: 30.13,131.16 v1(30.5,131.53) ; UT2.2 16.66,98.5 v1(17.4,99.24)
TBT_EE_WP_N: length 4.2
  TOP w0.102: v1(27.15,133.95) v2(27.15,133.3) ; v1(30.71,119.76) 31.08,119.39 RT48.2
  BOTTOM w0.076: UT1.V1 27.4,132.89 27.25,133.04 27.25,133.3
  BOTTOM w0.102: v1(27.15,133.95) 27.25,133.85 27.25,133.3 ; 17.93,98.06 17.93,99.01 v1(18.16,99.23)
TBT_FORCE_PWR: length 87.6
  TOP w0.102: RT13.2 16.76,131.86 v2(15.7,131.86) 15.65,131.86 14.85,131.06 v1(14.85,129.99) ; v1(99.98,26.89) 100.57,27.48 103.43,27.48 103.91,27 106.37,27 116.99,37.62 121.68,37.62 123.32,39.26 129.16,39.26 130.94,37.48 132.98,37.48 133.34,37.84 134.91,37.84 135.17,37.58 137.69,37.58 138.63,38.52 142.51,38.52 143.6,37.42 150.88,37.42 152.39,35.91 156.75,35.91 157.28,36.45 163.09,36.45 164.29,35.24 165.47,35.24 165.93,34.78 165.93,34.28 166.38,33.83 169.18,33.83 169.63,33.37 171.28,33.37 v1(172.45,32.2)
  BOTTOM w0.102: v1(172.45,32.2) 173.3,33.04 UH1.Y47
TBT_FORCE_PWR_R: length 6.6
  TOP w0.102: RT13.1 19.05,131.71 19.46,131.3 19.84,131.3 RT35.1 20.65,132.1 v2(21.32,132.1) 21.95,132.1 RT94.2 22.34,131.1 v1(22.36,131.07)
  BOTTOM w0.089: UT1.H4 22.67,131.38 v1(22.36,131.07)
TBT_HDMI_DDC_CLK: length 3.5
  TOP w0.102: T9.1 29.11,134.49 v1(29.11,134.34)
  BOTTOM w0.076: v1(29.11,134.34) 29.11,133.83 28.55,133.27 28.55,132.31 UT1.Y2
TBT_HDMI_DDC_DATA: length 2.8
  TOP w0.102: T7.1 28.68,134.65 v1(28.68,133.92)
  BOTTOM w0.102: UT1.Y1 28.32,133.55 v1(28.68,133.92)
TBT_HOLD_N: length 4.4
  BOTTOM w0.102: RT51.2 v2(17.7,87.98)
  BOTTOM w0.381: RT51.2 16.15,88.37 16.15,89.43 16.66,89.94 UT2.7
TBT_I2C_SCL: length 5.4
  BOTTOM w0.076: 26.9,133.38 27.04,133.23 27.04,132.89 27.17,132.76 27.17,132.31 UT1.U2 ; v1(32.31,92.09) 32.17,91.95 32.17,91.25 32.3,91.12 32.3,90.74 UT4.D2
  BOTTOM w0.102: 26.9,133.38 v1(26.06,134.22) 26.06,134.78 RT27.2
TBT_I2C_SDA: length 4.8
  TOP w0.102: v2(24.7,134.67) 25.16,134.21 v1(25.35,134.21)
  BOTTOM w0.076: UT1.U1 26.8,132.68 26.8,133.05 26.35,133.5 ; UT4.D1 v1(32.55,91.52)
  BOTTOM w0.102: RT26.2 25.35,134.83 v1(25.35,134.21) 26.05,133.5 26.35,133.5
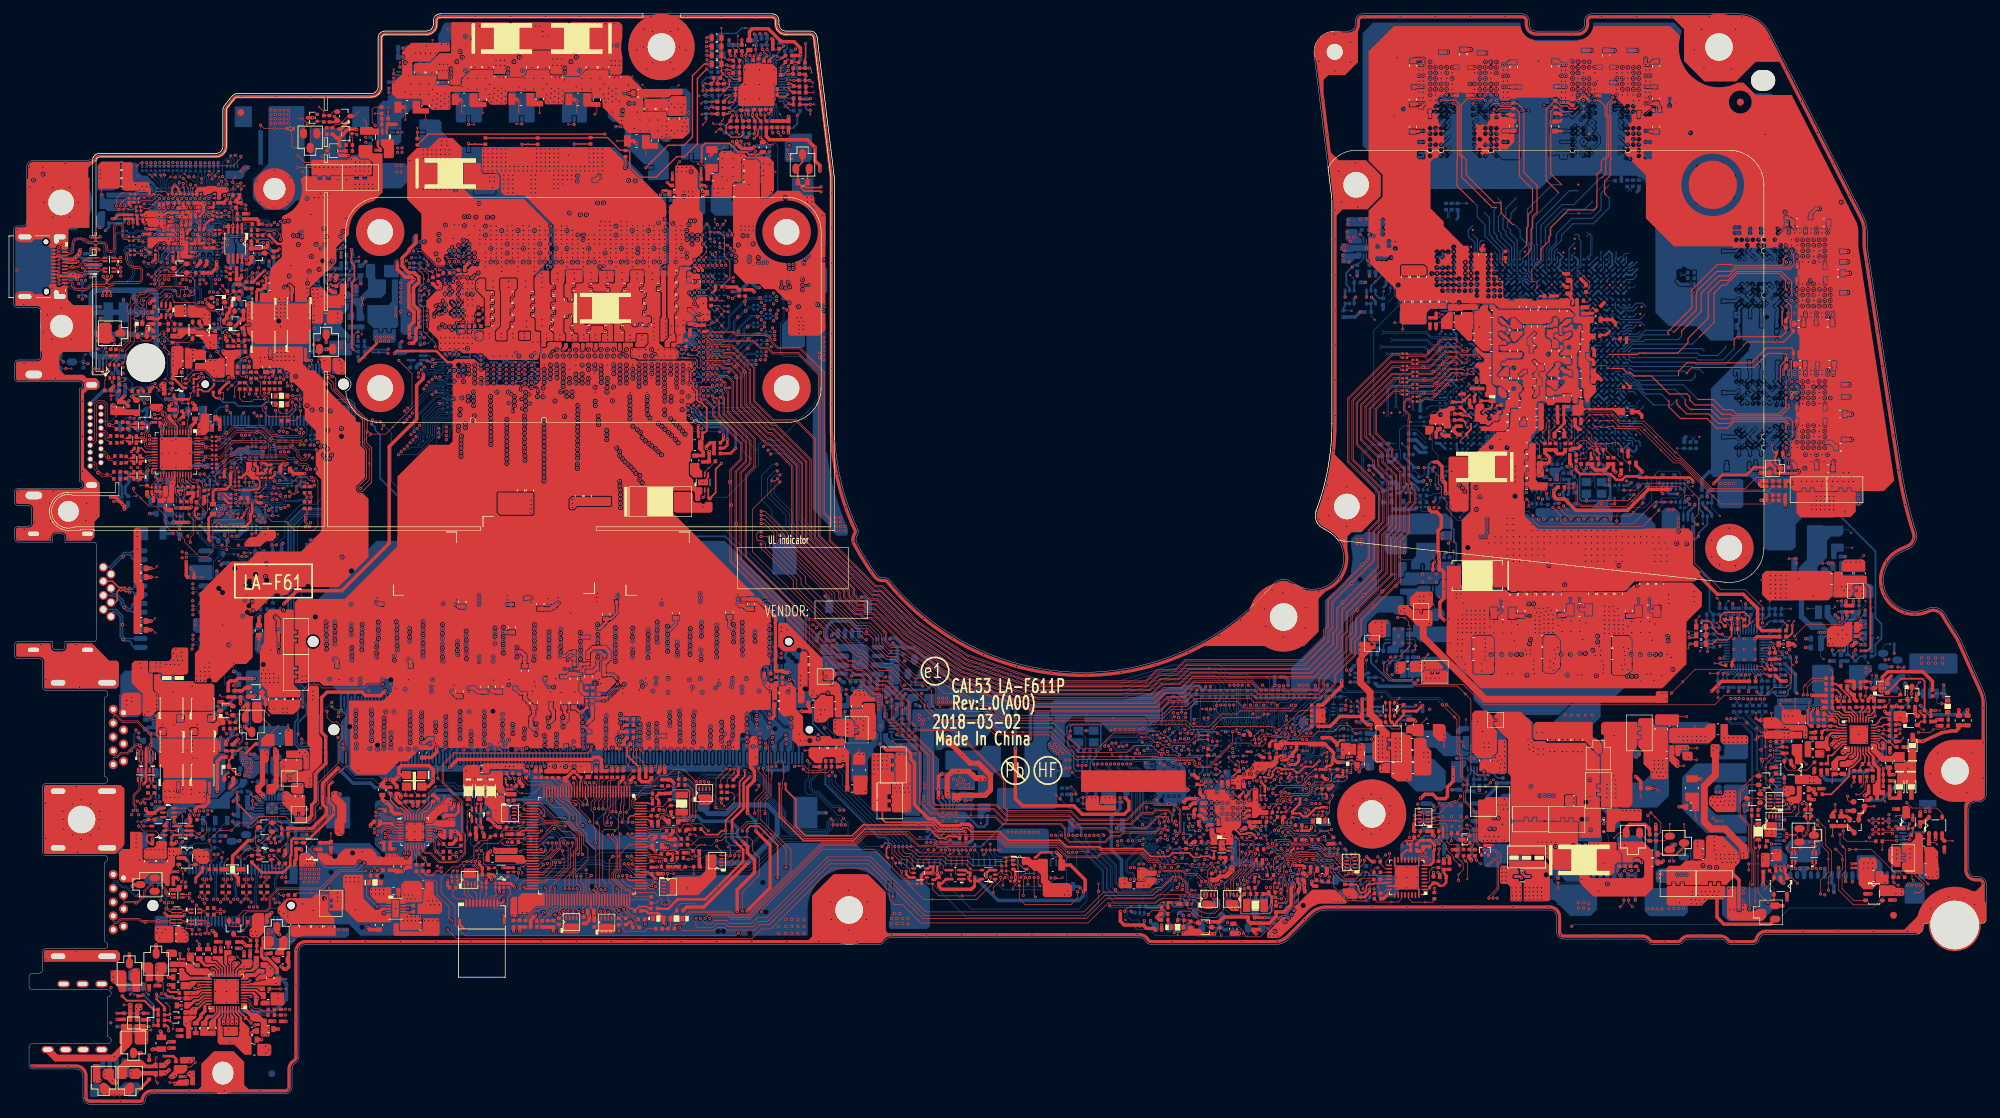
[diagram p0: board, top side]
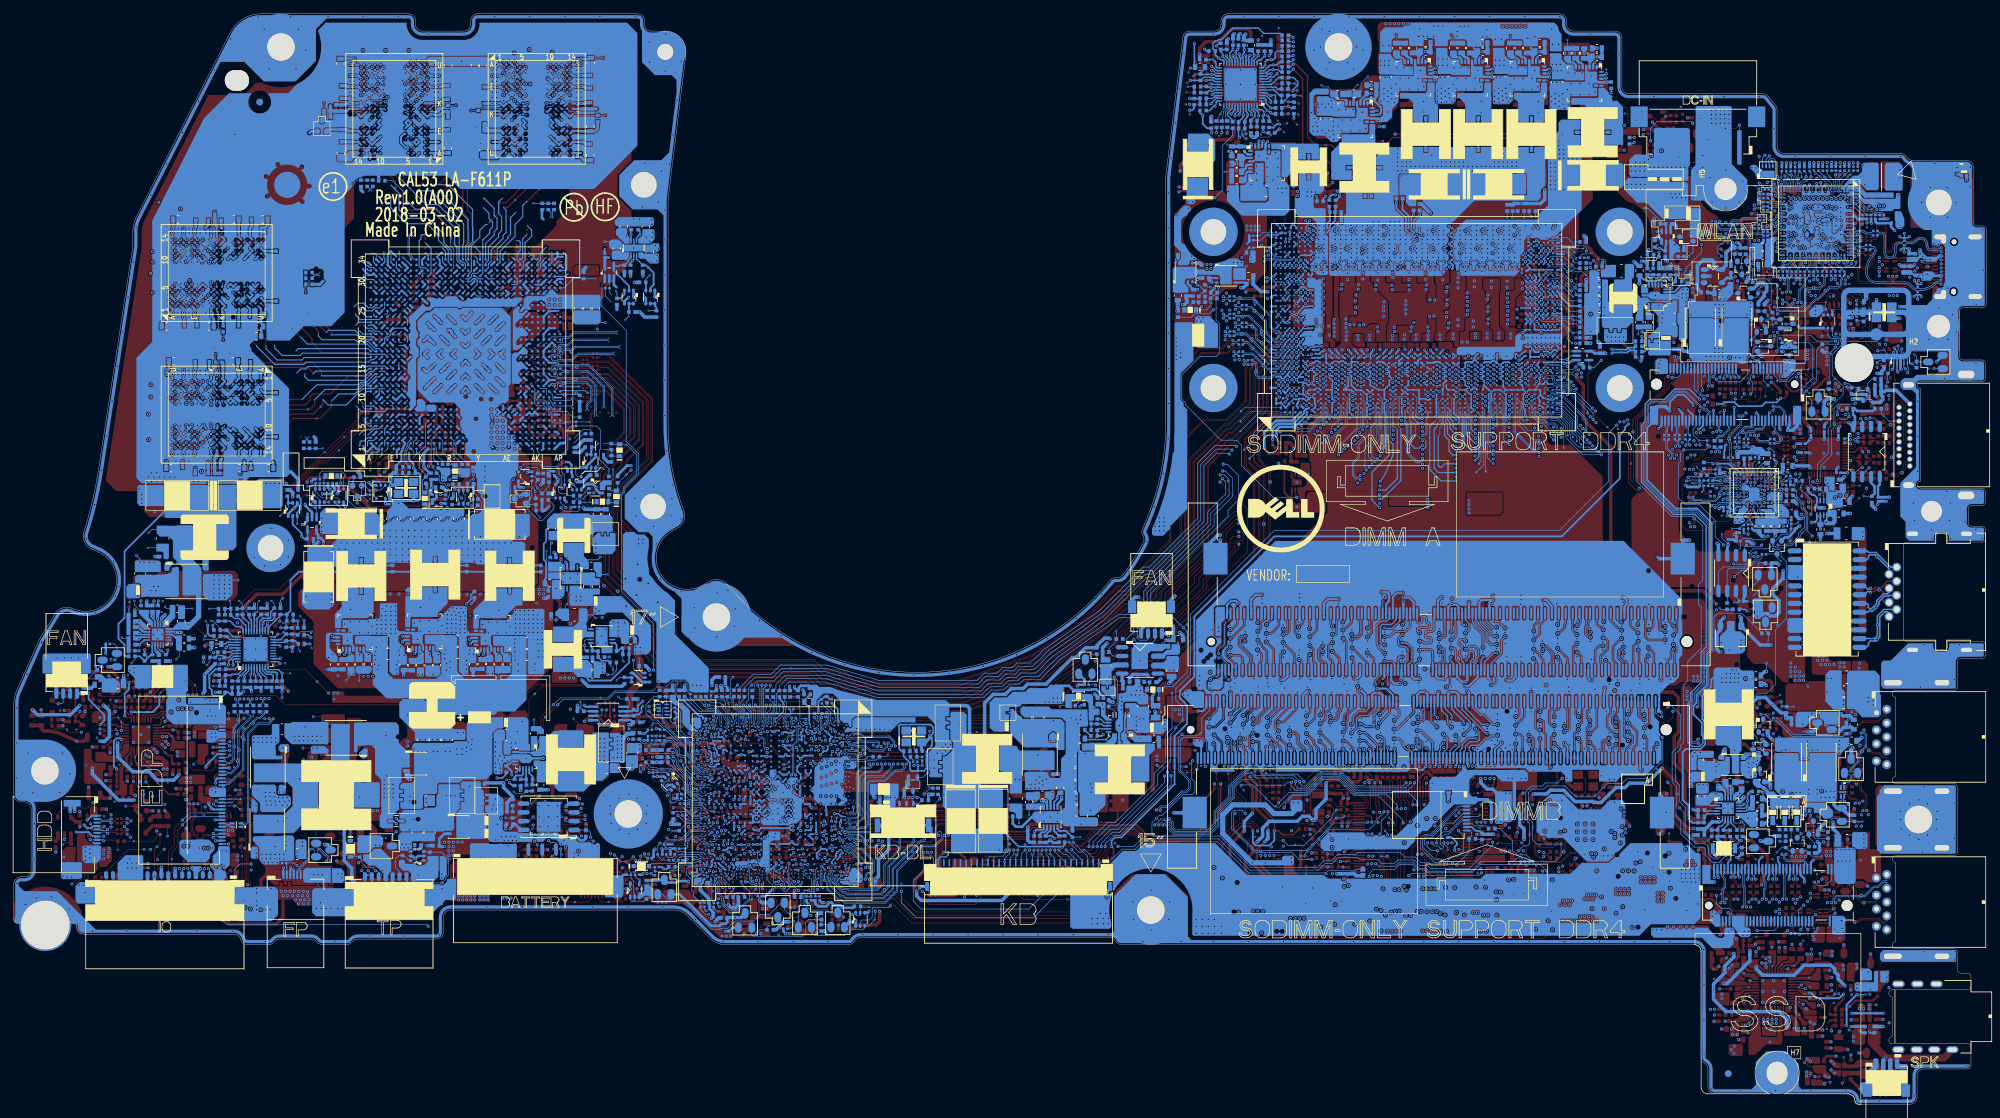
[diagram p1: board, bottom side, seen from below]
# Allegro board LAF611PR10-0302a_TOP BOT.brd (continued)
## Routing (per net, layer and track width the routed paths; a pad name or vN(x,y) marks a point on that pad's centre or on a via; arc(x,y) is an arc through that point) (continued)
TBT_PCIE_WAKE_N: length 3.2
  BOTTOM w0.076: UT1.W1 27.86,133.42
  BOTTOM w0.102: RT28.2 RT10.1 27.65,134.36 27.86,134.15 27.86,133.42
TBT_RBIAS: length 2.1
  TOP w0.102: RT25.1 22.3,129.82 v1(22.36,129.76) 22.08,129.48 22.02,129.48 21.79,129.25 v2(21.62,129.25)
  BOTTOM w0.089: UT1.H6 v1(22.36,129.76)
TBT_RESET_N: length 30.5
  TOP w0.102: RT102.2 32.08,84.57 29.42,84.57 28.8,83.95 28.8,79.98 28.06,79.24 26.83,79.24 24.7,81.36 24.7,81.75 23.39,83.06 22.66,83.06 22,83.72 22,85.09 20.53,86.55 19.52,86.55 v2(18.4,87.67) 17.32,88.75 v1(17.32,89.13) ; 18.03,130.52 RT80.1 ; 18.03,130.52 18.22,130.52 18.46,130.76 20.03,130.76 20.87,131.6 21.34,131.6 21.71,131.22 v1(21.71,131.05) ; 18.03,130.52 RT23.1
  BOTTOM w0.102: v1(21.71,131.05) 22.04,131.38 UT1.F4
TBT_RESET_N_EC#: length 7.3
  TOP w0.102: RT23.2 17.44,131.1 RT129.1 16.19,131.1 v2(15.67,130.57) 15.44,130.34 v1(15.44,130.03) ; v1(88.08,33.09) 88.08,32.33 88.82,31.59 89.23,31.59 89.61,31.21 UE1.97
  BOTTOM w0.102: v1(34.44,82.51) RT122.2
TBT_RSENSE: length 1.2
  TOP w0.102: v1(23,129.74) 23.22,129.96 RT25.2
  BOTTOM w0.102: UT1.J6 v1(23,129.74)
TBT_RST#_R: length 2.4
  TOP w0.102: v2(24.4,132.73) 24.72,132.41 RT1.1 24.72,131.48 v1(24.3,131.06)
  BOTTOM w0.102: v1(24.3,131.06) UT1.L4
TBT_SRC_CFG1: length 2.9
  BOTTOM w0.076: UT1.AA1 28.78,133.13
  BOTTOM w0.102: 28.78,133.13 29.66,134.01 29.66,134.14 v2(29.65,134.15) 29.65,134.94 RT11.1
TBT_SRC_HPD: length 4.1
  TOP w0.102: v1(23.36,134.17) v2(22.66,134.17)
  BOTTOM w0.076: UT1.G1 22.34,133.04
  BOTTOM w0.102: 22.34,133.04 22.34,133.16 v1(23.36,134.17) RT4.1
TBT_SVR_IND:
  vias: v2(18,134.31)
TBT_TCK: length 2.2
  TOP w0.102: v1(26.26,131.05) 25.89,131.42 RT7.2 v2(25.89,132.61)
  BOTTOM w0.102: UT1.T4 v1(26.26,131.05)
TBT_TDI: length 1.3
  TOP w0.102: RT9.2 28.3,131.14 v1(28.22,131.06)
  BOTTOM w0.089: v1(28.22,131.06) UT1.Y4
TBT_TDO: length 2.2
  TOP w0.102: v1(27.56,131.05) 27.69,131.05 28.12,131.48 28.58,131.48 28.8,131.71 RT6.2
  BOTTOM w0.089: UT1.W4 v1(27.56,131.05)
TBT_TEST_EN: length 4.1
  TOP w0.102: v1(20.46,134.5) v2(19.63,134.5)
  BOTTOM w0.076: UT1.E1 21.42,132.92 21.25,133.09 21.25,133.55
  BOTTOM w0.102: RT17.1 20.43,134.5 v1(20.46,134.5) 21.25,133.72 21.25,133.55
TBT_TEST_PWG: length 2.6
  BOTTOM w0.076: UT1.AB5 29.47,130.47 29.87,130.47 30.02,130.32 30.67,130.32
  BOTTOM w0.102: RT18.1 31.3,130.54 31.08,130.32 30.67,130.32
TBT_TMS: length 1.2
  TOP w0.102: v1(26.9,131.05) 27.06,131.2 RT8.2
  BOTTOM w0.102: UT1.V4 v1(26.9,131.05)
TBT_TMU_CLK_OUT: length 4.3
  BOTTOM w0.076: UT1.V2 27.63,132.31 27.63,133.08 27.52,133.19 27.52,133.54
  BOTTOM w0.102: 27.52,133.54 27.52,134.1 27.22,134.4 27.22,134.83 RT34.1 26.7,134.72 T2.1
TBT_XTAL_25_IN: length 4.9
  BOTTOM w0.076: UT1.D22 21.17,122.66 21.17,122.25 20.73,121.81 20.73,121.7 20.64,121.6
  BOTTOM w0.102: RT154.1 18.8,114.03 19.33,114.56 v1(19.33,114.6) ; v1(18.84,121.89) 18.84,121.56 19.24,121.15 20.19,121.15 20.64,121.6
TBT_XTAL_25_IN_R: length 3.2
  BOTTOM w0.102: YT1.1 17.22,113.75 17.68,113.28 CT37.1 17.9,113.45 RT154.2
TBT_XTAL_25_OUT: length 2.7
  BOTTOM w0.076: UT1.D23 20.57,122.03 20.57,121.88 20.28,121.59
  BOTTOM w0.102: 20.28,121.59 20.09,121.41 19.71,121.41 v1(19.45,121.67) ; RT155.1 v1(18.76,116.31)
TBT_XTAL_25_OUT_R: length 5.7
  BOTTOM w0.102: YT1.3 14.49,114.62 17.3,114.62 CT38.1 18.69,115.06 RT155.2
TBTA_DEBUG1: length 6.9
  BOTTOM w0.102: v2(41.83,92.16) 41.17,91.5 40.84,91.5 RT118.1 40.17,91.24 RT71.1 39.17,91.01 39.04,90.88 38.16,90.88 38.02,91.02 37.33,91.02 36.8,90.49 UT4.L2
TBTA_DEBUG2: length 6.6
  BOTTOM w0.076: UT4.K2 35.8,90.74 36.47,90.74 36.73,91 36.73,91.51 37.26,92.04 37.48,92.04 v2(37.58,92.13) 37.65,92.2
  BOTTOM w0.102: RT119.1 40.72,91.85 RT72.1 39.17,92.04 39,92.2 37.65,92.2
TBTA_DIG_AUD_N: length 7.8
  BOTTOM w0.076: UT4.K3 35.8,90.24 36.64,90.24
  BOTTOM w0.102: v2(42.51,89.89) 41.11,89.89 40.88,90.12 RT115.2 RT69.1 40.2,90.42 39.96,90.65 38.06,90.65 37.92,90.79 37.42,90.79 36.87,90.24 36.64,90.24
TBTA_DIG_AUD_P: length 6.8
  BOTTOM w0.102: v2(41.12,88.59) 40.88,88.84 RT68.1 RT114.2 40.2,89.68 40.01,89.86 39.22,89.86 39.17,89.82 38.3,89.82 38.04,90.08 38.04,90.34 37.82,90.56 37.48,90.56 36.91,89.99 UT4.L3
TBTA_HPD: length 2.1
  BOTTOM w0.102: v1(24.97,131.05) UT1.M4 ; v1(32.72,87.03) 32.18,86.49 UT4.C10 ; v1(31,136.45) 30.85,136.29 RPT1.5
TBTA_HRESET: length 15.4
  TOP w0.102: RE89.2 89.81,30 88.93,30.88 88.52,30.88 86.76,32.65 86.76,33.34 87.36,33.95 87.36,38.22 v1(86.63,38.95) ; v1(32.12,88.26) 32.11,88.27 RT108.1
  BOTTOM w0.102: UT4.D6 32.35,88.49 v1(32.12,88.26) ; v2(86.97,39.55) 86.63,39.21 v1(86.63,38.95)
TBTA_I2C_INT: length 2.9
  TOP w0.102: v1(23.01,131.07) 23.34,131.41 23.34,131.54 RT32.2
  BOTTOM w0.076: v1(31.41,92.13) 31.7,92.13 31.96,91.86 31.96,91.08 UT4.C1
  BOTTOM w0.089: v1(23.01,131.07) 23.32,131.38 UT1.J4
TBTA_LDO_BMC: length 2.7
  BOTTOM w0.152: CT98.1 32.29,92.76 33.05,92 UT4.E1
TBTA_LSRX: length 16.8
  TOP w0.102: v1(37.67,90.19) 38.05,89.81 40.17,89.81 41.06,90.7 v2(41.53,90.7) 42.42,90.7 42.92,90.2 v1(43.38,90.2)
  BOTTOM w0.076: UT4.K4 35.8,89.74 36.3,89.74
  BOTTOM w0.094: 36.3,89.74 36.99,89.74
  BOTTOM w0.102: v1(43.38,90.2) 42.88,90.2 42.76,90.32 41.54,90.32 RT115.1 ; 36.99,89.74 37.45,90.19 v1(37.67,90.19)
  BOTTOM w0.109: RT42.1 14.8,128.84 15.02,129.07 16,129.07 16.46,129.53 17.12,129.53 v1(18.86,131.27) 18.98,131.16 UT1.A4
TBTA_LSTX: length 8.9
  TOP w0.102: v1(38.98,89.16) v2(38.27,89.16)
  BOTTOM w0.094: UT4.L4 36.1,89.53 37.28,89.53 37.33,89.58 39.51,89.58 RT114.1 39.29,89.16 v1(38.98,89.16)
  BOTTOM w0.102: RT21.2 RT40.1 18.84,130.24 v1(18.84,130.31) 19.23,130.7 UT1.A5
TBTA_MRESET: length 3.9
  BOTTOM w0.076: v2(34.14,84.73) 33.91,84.96 33.02,84.96 32.91,85.07 32.91,85.59 33.05,85.73 UT4.E11
  BOTTOM w0.102: RT122.1 RT63.1 33.87,84.16 34.14,84.43 v2(34.14,84.73)
TBTA_ROSC: length 3.2
  BOTTOM w0.076: 34.3,92.11 34.3,90.74 UT4.G2
  BOTTOM w0.102: RT75.1 34.3,93.31 v2(34.3,92.48) 34.3,92.11
TBTB_I2C_INT: length 3.6
  BOTTOM w0.076: 21.46,133.86 21.46,133.13 21.65,132.95 21.65,132.31 UT1.E2
  BOTTOM w0.102: 21.46,133.86 21.46,134.11 v2(21.32,134.26) RT33.2
TESTMODE: length 9
  BOTTOM w0.102: 205.32,100.28 204.49,99.44 204.29,99.44
  BOTTOM w0.109: 204.29,99.44 RV62.1 ; 205.32,100.28 207.25,100.28 207.47,100.49 207.47,100.75 207.74,101.02 208,101.02 208.27,101.29 208.27,101.55 208.64,101.92 209.65,101.92 209.85,102.12 209.85,102.77 209.63,102.98 209.63,103.02 UV1.AK11
THERMDA: length 0.5
  BOTTOM w0.102: UT1.AC23 UT1.AB23
THM_SML1_CLK: length 7
  TOP w0.102: v2(197.21,56.96) 197.97,56.2 Q11.4 198.44,55.27 R49.2 199.41,54.3 200.44,54.3 200.64,54.49 v1(200.64,54.92)
  BOTTOM w0.102: U2.8 200.75,55.56 200.64,55.45 v1(200.64,54.92)
THM_SML1_DATA: length 5.6
  TOP w0.102: v1(200.26,57.06) 200.38,57.06 201.06,57.74 R48.2 200.39,57.8 200.09,58.1 Q11.1 199.74,58.11 v2(200.44,58.81)
  BOTTOM w0.102: U2.7 200.38,56.21 200.26,56.34 v1(200.26,57.06)
TON_1.2V: length 2
  BOTTOM w0.203: PUM01.9 36.95,40.73 36.07,39.85 PRM07.2
TOUCH_SCREEN_PD#: length 15
  TOP w0.102: D5.2 252.37,37.46 R19.2 252.55,36.82 252.34,36.6 v2(252.34,35.88) 252.34,30.61 v1(253.76,29.18)
  BOTTOM w0.102: UH1.AM45 179,33.86 178.96,33.82 178.96,32.57 178.83,32.45 178.83,31.98 178.61,31.76 v1(177.99,31.76) 177.46,31.23 177.46,30.66 177.72,30.39 RH69.1
TOUCHPAD_INTR#: length 7.8
  TOP w0.102: v2(188.28,39.56) 188.28,40.27 187.95,40.6 DH2.2 188.3,41.35 188.82,41.35 v1(189.28,41.81) 189.36,41.88 RH179.1
  BOTTOM w0.102: v1(189.28,41.81) 188.29,40.82 186.09,40.82 UH1.BF32
TP_EN#: length 6.7
  TOP w0.102: v1(77.3,37.82) 76.43,37.82 75.82,37.21 UE1.49 ; v1(236.83,42.18) v2(237.48,41.53) 238.27,40.74 238.27,39.36 237.94,39.03 R38.1
TP_LOCK#: length 7.2
  TOP w0.102: v3(234.06,33.15) 233.67,33.15 v1(233.02,33.79)
  BOTTOM w0.102: D6.2 235.36,35.82 R41.2 235.08,35.53 235.08,35.05 234.3,34.27 233.5,34.27 v1(233.02,33.79) 232.8,33.79 232.55,33.54 JTP.3
TP_WAKE_KBC#: length 16.7
  TOP w0.102: DH2.1 189.65,41.49 190.37,42.21 v2(190.37,43.75) 190.37,43.88 190.81,44.31 v1(190.81,44.7) ; v1(79.71,41.34) 79.59,41.45 78.34,41.45 76.17,43.61 UE1.33 74.07,43.61 73.38,42.93 72.9,42.93 72.65,43.18 71.82,43.18 71.51,43.48 RE14.1
  BOTTOM w0.102: Q9.1 230.66,38.81 v1(230.02,39.44)
TPM_PIRQ#: length 4.1
  TOP w0.102: v1(184.94,47.29) 184.94,47.1 v2(184.46,46.62) ; v1(197.35,35.81) 197.69,35.47 RTPM9.2 197.69,34.8 198.42,34.07 UTPM1.18
  BOTTOM w0.089: UH1.BE18 185.03,47.39 v1(184.94,47.29)
TRIP_+1.05V: length 1.9
  BOTTOM w0.254: PRH03.2 136.93,39.07 136.67,39.33 136.25,39.33 135.85,39.73 PUH01.2
TS_EN: length 3.3
  TOP w0.102: v2(254.97,37.65) v1(254.3,37.65) 253.85,38.1 C16.1 253.47,37.92 R19.1
  BOTTOM w0.102: JEDP1.39 v1(254.3,37.65)
TSENSE_2PH: length 3.2
  BOTTOM w0.203: PCZ31.1 PRZ68.1 110.72,152.25 110.45,151.98 v2(110.45,151.71) 110.45,151.61 109.88,151.04 PUZ01.25
TSENSE_4PH: length 4.4
  TOP w0.102: v2(104.04,153.47) 104.04,152.88 PRZ66.1
  TOP w0.203: PRZ66.1 104.35,152.28 v1(104.35,151.72)
  BOTTOM w0.203: PUZ01.14 105.48,150.89 105.24,151.13 104.94,151.13 v1(104.35,151.72) 104.39,151.76 PCZ29.1
TSENSE_PSYS: length 3.6
  TOP w0.102: v2(110.54,151.6) 110.41,151.73 v1(109.92,151.73) ; PRB31.2 264.75,58.34 264.75,58.81 v1(264.88,58.94)
  TOP w0.203: v1(109.92,151.73) 109.33,151.14 PRZ58.1
  BOTTOM w0.203: v1(109.92,151.73) 109.92,151.56 109.48,151.13 PUZ01.24
TYPEC_SMBCLK: length 16.1
  TOP w0.102: v1(25.53,81.33) 25.53,82.04 26.04,82.55 26.04,84.52 25.38,85.17 v1(25.38,85.37) ; RE31.1 89.89,26.17 89.89,26.63 89.51,27.01 89.22,27.01 88.2,28.03 v1(88.2,28.22) 87.87,28.55 87.37,28.55 87.09,28.83 UE1.91
  BOTTOM w0.102: v1(25.38,85.37) 25.24,85.52 25.24,87.4 26.84,89 v2(26.84,89.11) 26.84,89.5 26.62,89.71 RT60.1
TYPEC_SMBDA: length 12.2
  TOP w0.102: UE1.89 86.29,28.74 86.67,28.36 87.23,28.36 87.54,28.06 v1(87.54,28.02) 87.8,27.76 87.8,27.57 87.74,27.52 87.74,27.48 88.33,26.9 RE30.1
  BOTTOM w0.102: v1(25.15,82.21) 25.81,82.86 25.81,85.64 26.44,86.27 v2(26.44,86.83) 26.44,86.93 27.45,87.93 27.45,88.7 27.69,88.94 RT59.1
UART_2_CRXD_DTXD: length 13.1
  TOP w0.102: v2(35.36,102.31) 35,102.66 v1(35,102.81) 35.15,102.96 RW27.2
  BOTTOM w0.076: UH1.BD20 184.97,46.27 185.09,46.15 186.67,46.15 187.38,46.86
  BOTTOM w0.102: RH709.1 193.42,50.77 190.45,50.77 v1(189.95,50.28) 189.48,49.81 189.48,49.05 187.74,47.3 187.74,47.22 187.38,46.86
UART_2_CTXD_DRXD: length 11.9
  TOP w0.102: v2(189.19,50.56) 189.51,50.87 v1(189.96,50.87) ; RW28.2 32.93,105.27 v1(33.67,105.27)
  BOTTOM w0.089: UH1.BE20 185.36,46.33 186.56,46.33 187.26,47.03
  BOTTOM w0.102: 187.26,47.03 187.55,47.32 187.55,47.44 189.26,49.14 189.26,50.26 189.55,50.55 189.55,51.07 189.97,51.48 190.42,51.48 RH710.1 190.44,51.04 190.13,51.04 v1(189.96,50.87)
UG1_CHG: length 17.4
  TOP w1.016: 246.18,50.47 246.18,47.65 244.58,46.05 244.58,40.85 245.58,39.85 247.55,39.85 250.2,37.2
  vias: v1(245.83,51.81) v1(245.83,51.23) v1(250.27,36.32) v1(250.27,35.74) v1(265.71,50.24) v1(266.23,50.53) v3(246.38,51.57)
UG2_CHG: length 0.9
  TOP w0.102: v3(243.47,49.83) 242.55,49.83
  vias: v1(234.66,50.29) v1(235.17,50.67) v1(242.27,50.2) v1(263.22,53.19) v1(263.83,53.19)
UG_1.2V: length 4.5
  TOP w0.762: 37.56,45.61 37.96,46 37.96,49.95
  vias: v1(36.82,45.78) v1(36.78,45.18) v1(37.78,51.4) v1(37.96,50.83) v2(37.41,44.94)
UG_+1.05V: length 14.3
  TOP w0.762: 135.78,51.94 v3(137.2,50.52) 138.37,49.35 139.55,49.35 141.3,47.6 141.3,45.47 140.53,44.7 136.77,44.7
  vias: v1(134.72,52.68) v1(135.33,52.68) v1(136.04,43.95) v1(136.65,43.95)
UPD1_ALERT: length 25.9
  TOP w0.102: v1(73.07,43.33) 72.97,43.43 72.48,43.43 72.31,43.6 RE155.2 72.38,44.04 76.31,44.04 76.69,44.42 UE1.32
  BOTTOM w0.102: v1(36.54,78.21) 36.48,78.15 34.85,78.15 34.28,78.73 34.28,79.79 33.69,80.38 31.53,80.38 31.19,80.71 30.55,80.71 30.33,80.5 29.19,80.5 28.84,80.85 28.11,80.85 26.9,82.06 26.9,82.37 v2(26.59,82.68) 26.04,83.23 26.04,85.55 26.78,86.3 26.78,86.95 RT120.2
US2_5VHDD: length 2.5
  TOP w0.102: RS8.1 277.94,37.87 v2(278.22,37.59)
  TOP w0.508: RS8.1 277.08,39.14 US2.1
USB2_COMP: length 4
  BOTTOM w0.102: UH1.F4 166.07,55.12 166.52,55.57 166.52,56.59 167.72,57.79 RH109.1
USB2_ID: length 4.1
  BOTTOM w0.102: RH581.1 167.16,56.69 167.16,55.19 166.77,54.81 UH1.G3
USB2_VBUSSENSE: length 3.2
  BOTTOM w0.254: RH580.1 166.15,57.17 166.15,55.58 UH1.F3
USB3_PRX_DTX_N1: length 8.7
  TOP w0.102: v1(17.26,42.48) 17.47,42.69 17.47,43.17 17.24,43.4 17.24,44.74 18.1,45.59 18.1,46.52 17.95,46.67 LU3.3
  BOTTOM w0.089: v1(162.85,50.78) 162.73,50.67 162.73,50.56 162.88,50.4 163.19,50.4 163.52,50.73 164.7,50.73 164.96,50.99 165.28,50.99 UH1.D11
USB3_PRX_DTX_N3: length 4
  TOP w0.102: LU6.3 27.3,26.08 27.59,26.37 27.8,26.37 27.95,26.21 27.95,25.76 27.85,25.65 27.85,24.9 v1(27.66,24.71)
  BOTTOM w0.102: v1(163.53,51.21) 163.72,51.01 164.21,51.01 164.31,51.12 UH1.B10
USB3_PRX_DTX_P1: length 8.9
  TOP w0.102: v1(17.84,42.48) 17.68,42.64 17.68,43.25 17.45,43.48 17.45,44.65 18.3,45.51 18.3,46.53 18.45,46.68 LU3.2
  BOTTOM w0.089: v1(162.24,50.78) 162.81,50.21 163.27,50.21 163.6,50.54 164.73,50.54 164.75,50.52 165.18,50.52 165.25,50.59 165.25,50.7 165.2,50.76 UH1.C11
USB3_PRX_DTX_P3: length 4.2
  TOP w0.102: LU6.2 27.88,26.58 28.18,26.27 v4(28.18,25.96) 28.18,25.7 28.05,25.56 28.05,24.9 v1(28.24,24.71)
  BOTTOM w0.102: UH1.C10 165.07,51.36 164.16,51.36 v1(164.06,51.46)
USB3_PRX_L_DTX_N1: length 9.3
  TOP w0.102: LU3.4 17.95,48.47 18.11,48.62 18.11,49.08 18.27,49.25 18.27,49.52 18.13,49.66 DU1.1 DU1.9 18.13,51.07 18.28,51.22 18.28,51.59 17.92,51.94 17.73,51.94 v4(16.97,51.19) 16.49,50.7 15.53,50.7 15.05,50.22 14.5,50.22 14.38,50.1 JUSB1.5
USB3_PRX_L_DTX_N3: length 12.7
  TOP w0.102: JUSB2.5 14.38,25.97 14.58,26.17 15.04,26.17 15.54,26.67 18.12,26.67 18.42,26.36 v4(19.01,26.36) 20.61,26.36 20.64,26.34 21.25,26.34 21.27,26.36 22.51,26.36 22.65,26.21 DU3.9 DU3.1 24.25,26.21 24.39,26.36 24.57,26.36 24.71,26.22 25.1,26.22 25.25,26.08 LU6.4
USB3_PRX_L_DTX_P1: length 9.4
  TOP w0.102: LU3.1 18.45,48.5 18.31,48.64 18.31,49 18.48,49.16 18.48,49.52 18.63,49.67 DU1.2 DU1.8 18.63,51.08 18.48,51.23 18.48,51.71 v4(18.26,51.93) 18.05,52.14 17.64,52.14 17.12,51.62 17.09,51.62 16.6,51.14 16.6,51.1 16.4,50.9 15.45,50.9 14.97,50.42 14.5,50.42 14.38,50.54 JUSB1.6
USB3_PRX_L_DTX_P3: length 12.7
  TOP w0.102: LU6.1 25.25,26.58 25.1,26.43 24.8,26.43 24.66,26.57 24.38,26.57 24.24,26.71 DU3.2 DU3.8 22.65,26.71 22.51,26.57 v4(20.92,26.57) 19.32,26.57 19.29,26.59 18.72,26.59 18.69,26.57 18.51,26.57 18.2,26.87 15.45,26.87 14.96,26.38 14.54,26.38 14.38,26.54 JUSB2.6
USB3_PTX_C_DRX_N1: length 1.3
  TOP w0.102: LU2.3 19.64,46.75 19.79,46.61 19.79,46.35 CU2.2
USB3_PTX_C_DRX_N3: length 1.4
  TOP w0.102: CU4.2 27.63,27.83 27.24,27.83 27.12,27.7 LU5.3
USB3_PTX_C_DRX_P1: length 1.3
  TOP w0.102: CU1.2 19.99,46.33 19.99,46.61 20.14,46.75 LU2.2
USB3_PTX_C_DRX_P3: length 1.4
  TOP w0.102: LU5.2 27.11,28.2 27.28,28.03 27.68,28.03 CU3.2
USB3_PTX_DRX_N1: length 3.4
  TOP w0.102: v1(18.37,43.55) 18.58,43.76 18.58,44.04 18.84,44.3 19.63,44.3 19.77,44.45 19.77,44.69 CU2.1
  BOTTOM w0.089: v1(167.15,52.08) 167.1,52.02 UH1.F9
USB3_PTX_DRX_N3: length 1.8
  TOP w0.102: CU4.1 29.28,27.77 29.74,27.77 v1(29.91,27.61)
  BOTTOM w0.102: UH1.F11 166.4,51.07 v1(166.13,51.34)
USB3_PTX_DRX_P1: length 3.3
  TOP w0.102: v1(18.96,43.55) 18.78,43.73 18.78,43.95 18.92,44.09 19.71,44.09 19.98,44.36 19.98,44.67 CU1.1
  BOTTOM w0.089: v1(166.73,52.54) 166.65,52.45 166.34,52.45 UH1.F7
USB3_PTX_DRX_P3: length 1.8
  TOP w0.102: CU3.1 29.35,27.98 29.7,27.98 v1(29.91,28.19)
  BOTTOM w0.102: v1(166.9,51.03) 167.06,50.87 UH1.G12
USB3_PTX_L_DRX_N1: length 12.8
  TOP w0.102: LU2.4 19.64,48.63 19.79,48.78 19.79,49.47 19.63,49.62 DU1.4 DU1.7 19.63,51.07 19.76,51.21 v4(19.76,52.03) 19.76,53.33 19.38,53.71 19.38,53.74 17.86,55.27 15.65,55.27 14.71,56.22 14.48,56.22 14.38,56.11 JUSB1.8
USB3_PTX_L_DRX_N3: length 15
  TOP w0.102: LU5.4 25.41,27.7 25.25,27.86 24.41,27.86 24.26,27.71 DU3.4 DU3.7 22.88,27.71 22.71,27.89 22.45,27.89 v4(22.05,28.29) 22.01,28.33 22.01,28.95 v1(21.79,29.17)
  BOTTOM w0.102: v1(21.79,29.17) 21.96,29.33 21.96,29.66 21.61,30.01 18.39,30.01 18.37,29.99 17.81,29.99 17.78,30.01 17.55,30.01 16.2,31.36 15.61,31.36 14.84,32.13 14.44,32.13 14.38,32.07 JUSB2.8
USB3_PTX_L_DRX_P1: length 12.9
  TOP w0.102: LU2.1 20.14,48.32 20.14,48.64 19.99,48.79 19.99,49.45 20.13,49.59 DU1.5 DU1.6 20.13,51.05 19.97,51.22 19.97,51.73 19.99,51.75 19.99,52.31 19.97,52.33 19.97,53.45 v4(19.74,53.68) 17.94,55.47 15.74,55.47 14.79,56.42 14.48,56.42 14.38,56.53 JUSB1.9
USB3_PTX_L_DRX_P3: length 14.9
  TOP w0.102: v1(22.38,29.17) 22.22,29.01 22.22,28.44 22.42,28.25 22.42,28.21 22.54,28.09 22.7,28.09 22.82,28.21 DU3.6 DU3.5 24.24,28.21 24.38,28.07 25.25,28.07 25.39,28.2 LU5.1
  BOTTOM w0.102: JUSB2.9 14.38,32.4 14.44,32.34 14.92,32.34 15.7,31.56 16.29,31.56 17.64,30.22 v4(18.09,30.22) 21.7,30.22 22.17,29.75 22.17,29.38 v1(22.38,29.17)
USB20_N1: length 3.4
  BOTTOM w0.102: UH1.J3 167.92,54.68 167.64,54.96 167.64,55.37 167.43,55.57 167.43,56.34 v1(167.75,56.66) ; LU1.2 20.53,44.27 20.66,44.13 20.66,43.96 v1(20.47,43.78)
USB20_N1_R: length 11.7
  BOTTOM w0.102: v1(17.68,54.14) 17.68,53.91 17.31,53.54 17.31,51.72 v4(17.93,51.1) 18.4,50.62 18.4,49.53 19.46,48.48 19.46,48.2 19.35,48.1 18.76,48.1 DU2.3 18.77,47.73 19.25,47.73 19.43,47.56 19.43,47.02 19.85,46.59 20.51,46.59 20.67,46.43 20.67,46.19 20.53,46.04 LU1.1
USB20_N2: length 1.6
  TOP w0.102: v1(260.75,37.34) 260.56,37.15 260.56,36.8 260.73,36.63 LU9.3
  BOTTOM w0.089: v1(169.43,49.35) 169.43,49.35 169.76,49.68 UH1.N13
USB20_N2_R: length 2.2
  TOP w0.102: v1(260.77,34.11) 260.58,34.3 260.58,34.67 260.73,34.82 LU9.4
  BOTTOM w0.102: v1(260.77,34.11) 261,33.88 JIOB1.7
USB20_N3: length 4
  TOP w0.102: v1(25.43,30.51) 25.25,30.33 24.85,30.33 24.77,30.41 LU4.2
  BOTTOM w0.089: v1(168.4,56.56) 168.85,56.12 168.85,55.64 168.66,55.45 168.66,54.22 UH1.K4
USB20_N3_R: length 11.9
  TOP w0.102: LU4.1 22.84,30.41 22.68,30.25 22.29,30.25 22.09,30.45 v4(22.09,30.69) 22.09,31.1 21.29,31.9 20.84,31.9 20.71,32.03 20.71,32.4 DU4.3 20.13,32.5 20.13,31.98 20.03,31.88 19.79,31.88 18.78,30.88 18.78,30.18 17.98,29.38 17.32,29.38 17.3,29.35 15.98,29.35 15.88,29.45 JUSB2.2
USB20_N4: length 3.6
  TOP w0.102: RT133.1 42.35,85.94 42.35,85.56 42.06,85.26 42.06,85.05 42.04,85.03 42.04,84.44 42.06,84.42 42.06,84.2 42.35,83.9 42.35,83.74 v1(42.18,83.57)
  BOTTOM w0.102: v1(168.95,51.23) 169,51.18 UH1.M10
USB20_N4_R: length 10
  TOP w0.102: RT131.1 42.06,88.22 v1(42.43,87.86) 42.06,87.49 RT133.2
  BOTTOM w0.089: UT4.K5 35.8,89.24 36.3,89.24
  BOTTOM w0.102: 36.3,89.24 v4(37.64,89.24) 38.01,89.24 38.76,88.48 38.76,87.89 39.23,87.41 41.12,87.41 41.26,87.56 42.32,87.56 42.43,87.67 v1(42.43,87.86)
USB20_N5: length 19.4
  BOTTOM w0.102: v1(169.54,56.58) 169.1,56.15 UH1.M1 ; v1(248.41,55.78) 248.22,55.59 248.22,55.45 248.48,55.19 250.03,55.19 251.57,53.66 251.57,40.89 251.96,40.5 252.07,40.5 252.22,40.64 L3.4
USB20_N5_R: length 1.6
  BOTTOM w0.102: JEDP1.33 254.67,40.65 254.53,40.5 254.12,40.5 253.98,40.64 L3.3
USB20_N6: length 1.3
  TOP w0.102: v1(257.79,37.06) 257.61,36.88 257.61,36.69 257.74,36.55 LU8.3
  BOTTOM w0.089: v1(168.78,52.91) 168.47,52.6 UH1.K7
USB20_N6_R: length 2.1
  TOP w0.102: LU8.4 257.74,34.75 257.59,34.61 257.59,34.28 v1(257.79,34.09)
  BOTTOM w0.102: v1(257.79,34.09) 258,33.88 JIOB1.4
USB20_N7: length 4
  BOTTOM w0.102: v1(30.83,100.43) 30.45,100.81 29.9,100.81 29.29,100.2 29.29,99.86 29.45,99.7 JWLAN1.5 ; v1(168.75,53.68) 168.75,53.88 168.99,54.12 UH1.L4
USB20_N8: length 1.6
  TOP w0.102: v1(259.31,43.47) 259.49,43.29 259.49,43.15 259.35,43 L4.4 259.22,42.61 R21.2
  BOTTOM w0.089: UH1.G4 166.73,54.13 v1(166.51,53.91)
USB20_N8_R: length 8.5
  TOP w0.102: v1(256.49,39.19) 256.65,39.04 257.92,39.04 258.05,39.17 258.05,39.58 DA6.2 258.72,39.5 258.72,38.94 258.8,38.87 259,38.87 259.23,39.1 259.23,39.39 259.5,39.66 259.5,40.96 259.35,41.11 L4.3 259.15,41.68 R21.1
  BOTTOM w0.102: v1(256.49,39.19) 256.3,39 255.81,39 255.67,39.15 JEDP1.36
USB20_N9: length 10
  BOTTOM w0.089: UH1.M6 169.54,53.02 v1(169.36,52.85)
  BOTTOM w0.102: v1(240.15,35.18) 240.09,35.18 239.94,35.32 239.94,35.66 241.11,36.82 241.31,36.82 241.43,36.71 241.43,35.99 DF1.3 241.85,36.05 241.85,36.68 241.99,36.83 242.33,36.83 242.58,36.58 242.58,35.45 244,34.04 244,33.85 243.85,33.7 JFP.6
USB20_N11: length 1.6
  TOP w0.102: v1(169.91,51.4) 170.13,51.18 TH145.1
  BOTTOM w0.089: v1(169.91,51.4) 170.13,51.18 UH1.R10
USB20_N14: length 1.3
  TOP w0.102: v1(165.4,53.44) 164.77,53.44 TH142.1
  BOTTOM w0.089: UH1.E5 165.75,53.44 v1(165.4,53.44)
USB20_P1: length 2.8
  BOTTOM w0.102: LU1.3 21.03,44.29 20.87,44.13 20.87,43.9 21.02,43.75 v1(21.13,43.75) ; v1(167.9,56.07) 167.83,56.13 167.73,56.13 167.64,56.04 167.64,55.66 167.85,55.45 167.85,55.05 167.94,54.95 168.01,54.95 168.08,55.02 UH1.J2
USB20_P1_R: length 11.6
  BOTTOM w0.102: LU1.4 21.03,46.04 20.88,46.19 20.88,46.52 20.6,46.8 19.94,46.8 19.63,47.1 19.63,47.56 19.81,47.73 20.32,47.73 DU2.2 20.33,48.1 19.76,48.1 19.66,48.2 19.66,48.56 18.61,49.62 18.61,50.71 18.29,51.03 18.29,51.06 17.82,51.53 17.79,51.53 17.51,51.8 17.51,53.45 17.79,53.73 v1(18.09,53.73)
USB20_P2: length 1.7
  TOP w0.102: LU9.2 260.23,36.67 260.35,36.79 260.35,37.15 v1(260.16,37.34)
  BOTTOM w0.102: v1(170.08,49.34) 170.08,49.33 170.07,49.32 170.07,49.23 UH1.N15
USB20_P2_R: length 2.1
  TOP w0.102: LU9.1 260.23,34.84 260.38,34.69 260.38,34.3 v1(260.19,34.11)
  BOTTOM w0.102: v1(260.19,34.11) 260,33.92 JIOB1.6
USB20_P3: length 4
  TOP w0.102: v1(25.41,29.81) 25.41,29.98 25.26,30.12 24.92,30.12 24.7,29.91 LU4.3
  BOTTOM w0.089: v1(168.48,55.97) 168.62,55.83 168.62,55.68 168.47,55.53 168.47,54.96 168.43,54.93 168.28,54.93 168.16,54.81 168.16,54.32 168.22,54.25 168.31,54.25 168.45,54.39 168.45,54.6 UH1.K3
USB20_P3_R: length 11.9
  TOP w0.102: JUSB2.3 15.88,29.05 15.98,29.15 v4(17.69,29.15) 18.04,29.15 18.99,30.09 18.99,30.79 19.87,31.68 20.03,31.68 20.13,31.58 20.13,31.06 DU4.2 20.76,31.2 20.76,31.58 20.88,31.7 21.2,31.7 21.86,31.04 21.86,30.39 22.2,30.04 22.7,30.04 22.83,29.91 LU4.4
USB20_P4: length 3.8
  TOP w0.102: RT132.1 42.56,85.97 42.56,85.47 42.27,85.18 v4(42.27,84.75) 42.27,84.28 42.56,83.99 42.56,83.77 v1(42.77,83.57)
  BOTTOM w0.089: v1(168.25,51.56) 168.6,51.91 UH1.L9
USB20_P4_R: length 10
  TOP w0.102: RT130.1 43.11,88.2 43.11,87.96 v1(43.01,87.87) 43.09,87.79 43.09,87.42 RT132.2
  BOTTOM w0.102: v1(43.01,87.87) 42.61,87.46 42.51,87.46 42.4,87.35 41.35,87.35 41.21,87.21 39.15,87.21 38.53,87.82 v4(38.53,88.1) 38.53,88.42 37.94,89.01 37.33,89.01 37.31,89.03 36.1,89.03 UT4.L5
USB20_P5: length 19.7
  BOTTOM w0.102: UH1.L2 168.98,55.32 169.54,55.88 v1(169.54,56) ; L3.1 252.25,40.14 252.1,40.29 251.88,40.29 251.36,40.81 251.36,53.57 249.95,54.99 248.39,54.99 248.02,55.36 248.02,55.59 v1(247.83,55.78)
USB20_P5_R: length 1.6
  BOTTOM w0.102: JEDP1.34 254.67,40.15 254.52,40.3 254.17,40.3 254.01,40.14 L3.2
USB20_P6: length 1.6
  TOP w0.102: v1(257.2,37.06) 257.4,36.86 257.4,36.69 257.24,36.53 LU8.2
  BOTTOM w0.089: v1(167.94,52.68) 167.94,53.13 UH1.K6
USB20_P6_R: length 2.1
  TOP w0.102: v1(257.2,34.09) 257.39,34.28 257.39,34.63 257.24,34.78 LU8.1
  BOTTOM w0.102: JIOB1.3 257,33.89 v1(257.2,34.09)
USB20_P7: length 4.2
  BOTTOM w0.102: JWLAN1.3 28.95,99.72 29.08,99.86 29.08,100.29 29.81,101.02 v1(30.83,101.02) ; UH1.L3 169.43,54.29 v1(169.43,54.26)
USB20_P8: length 1.7
  TOP w0.102: R20.2 259.98,42.61 L4.1 259.85,43.03 259.7,43.17 259.7,43.28 v1(259.89,43.47)
  BOTTOM w0.089: v1(167.18,54.32) 167.01,54.15 UH1.G5
USB20_P8_R: length 8.6
  TOP w0.102: v1(256.49,38.61) 256.72,38.83 257.92,38.83 258.05,38.71 258.05,38.24 DA6.3 258.74,38.34 258.74,38.52 258.89,38.67 259.09,38.67 259.43,39.01 259.43,39.3 259.7,39.57 259.7,40.95 259.85,41.1 L4.2 260.04,41.68 R20.1
  BOTTOM w0.102: v1(256.49,38.61) 256.3,38.8 255.82,38.8 255.67,38.65 JEDP1.37
USB20_P9: length 10
  BOTTOM w0.102: JFP.5 244.35,33.72 244.2,33.87 244.2,34.12 242.79,35.53 242.79,36.66 242.42,37.03 241.99,37.03 241.85,37.18 241.85,37.5 DF1.2 241.43,37.57 241.43,37.14 241.31,37.03 241.02,37.03 239.74,35.75 239.74,35.35 v1(239.56,35.18) ; UH1.N8 169.73,52.71 v1(169.96,52.94)
USB20_P11: length 8
  TOP w0.102: TH143.1 164.31,53.15 165.14,52.32 165.86,52.32 166.54,51.65 167.45,51.65 167.74,51.94 169.03,51.94 v1(169.23,51.74)
  BOTTOM w0.089: UH1.P9 169.41,51.91 v1(169.23,51.74)
USB20_P14: length 1.4
  TOP w0.102: v1(165.78,52.98) 165.79,53 TH141.1
  BOTTOM w0.089: UH1.F6 165.89,53.09 v1(165.78,52.98)
USB20_VCCB:
  vias: v1(267.64,34.9) v1(267.64,34.16) v1(268.28,34.9) v1(268.28,34.16) v1(268.91,34.9) v1(268.91,34.16) v3(268.62,35.51)
USB30_VCCA:
  vias: v1(16.33,58.43) v1(16.33,57.8) v1(17.05,58.87) v1(17.05,58.24) v1(17.69,38.98) v1(17.69,38.39) v1(17.69,37.81) v1(17.68,37.15) v1(22.5,36.6) v1(22.5,35.98) v1(23.1,36.6) v1(23.11,35.99) v3(18.15,35.3)
USB_EN#: length 26.1
  TOP w0.102: UU3.4 270.3,29.25 269.9,28.85 266.13,28.85 264.02,30.96 264.02,33.44 264.54,33.97 v3(264.54,35.42) 264.54,35.94 v1(263.59,36.89) ; v1(84.18,37.83) 84.18,39.74 83.9,40.03 83.9,42.17 83.52,42.55 83.52,43.69 84.29,44.46 UE1.13 84.29,46.24 84.38,46.33 84.38,47.17 RE17.1 ; UU1.4 25.58,34.68 v1(24.8,33.9)
USB_OC0#: length 139.8
  TOP w0.102: v1(176.77,38.63) 177.29,38.1 177.29,34.01 175.13,31.85 175.13,30.95 175.48,30.6 RPH6.4 175.48,30.03 175.02,29.56 175.02,28.08 173.95,27.01 172.06,27.01 171.87,27.2 171.46,27.2 170.34,28.33 169.96,28.33 169.75,28.55 CH228.1 169.75,29.18 169.19,29.74 165.86,29.74 165.24,29.12 158.31,29.12 155.41,26.22 131.2,26.22 128.51,28.92 127.4,28.92 126.73,29.58 126.73,30.8 123.36,34.17 118.32,34.17 112.13,27.98 112.13,27.96 109.53,25.36 108.18,25.36 106.78,23.96 64.01,23.96 v1(62.74,25.23) ; v1(24.24,32.17) 24.47,32.4 v2(24.47,33.3) 24.47,33.62 23.87,34.22 UU1.3
  BOTTOM w0.089: UH1.AH36 176.96,38.44 v1(176.77,38.63)
USB_OC1#: length 20.1
  TOP w0.102: v1(178.23,36.28) 178.23,35.95 177.56,35.28 177.56,33.92 176.07,32.43 176.07,30.94 175.98,30.84 RPH6.3 ; v1(264.2,39.04) 264.2,37.68 v3(264.63,37.25) 265.02,36.86 265.02,33.77 264.5,33.24 264.5,31.16 266.17,29.49 UU3.3
  BOTTOM w0.102: UH1.AL40 178.23,36.59 v1(178.23,36.28)
USB_OC2#: length 5.5
  TOP w0.102: RPH6.1 176.98,30.54 177.53,31.09 v2(177.53,32.04) 177.32,32.26 177.32,32.8 178.27,33.75 v1(178.27,34.58)
  BOTTOM w0.102: v1(178.27,34.58) 177.81,34.58 UH1.AJ44
USB_OC3#: length 7.8
  TOP w0.102: v1(178.85,36.55) 178.85,36.27 178.54,35.95 178.54,35.7 v2(178.2,35.36) 177.86,35.03 177.86,33.79 176.48,32.41 RPH6.2
  BOTTOM w0.102: v1(178.85,36.55) 178.69,36.39 UH1.AL41
USB_POWERSHARE_VBUS_EN: length 5.9
  TOP w0.102: UE1.71 79.09,28.43 78.65,27.99 v2(78.52,27.99) 78.21,27.99 77.36,27.14 76.9,27.14 76.44,26.68 RE168.1 76.44,26.43 RE169.1
USBC_B2B_S1:
  vias: v2(31.79,45.55)
USBC_B2B_S1_A: length 9.9
  TOP w0.102: v2(33.77,51.68) 33.04,51.68 v1(32.87,51.5)
  TOP w0.254: v1(32.87,51.5) 32.51,51.14 PRS14.1 ; PRS14.1 PCS11.1 ; PRS14.1 PRS12.2 31.12,49.74 PQS03.1 32.31,47.71 v1(32.64,47.71)
  BOTTOM w0.254: PQS04.2 32.64,51.5 v1(32.87,51.5) ; PQS08.1 32.77,47.83 v1(32.64,47.71)
USBC_B2B_S2: length 8.1
  TOP w0.102: PQS19.2 31.1,56.3 v1(30.8,56.59) ; PQS05.2 22.09,42.2 22.24,42.05 22.24,41.73 22.06,41.55 PQS05.3 20.69,41.55 PCS12.1 19.49,41.22 PRS25.1 18.86,41.22 v2(18.45,40.82) 18.45,40.5 18.7,40.25 v1(18.8,40.25) PUS02.4
USBC_B2B_S2_G: length 6
  TOP w0.381: PQS16.4 28.31,44.98 v1(28.18,44.86) ; v1(23.8,45.31) 23.82,45.33 PQS02.4
  TOP w0.508: v1(26.23,42.43) 26.23,42.63 26.68,43.08 27.54,43.08 v2(27.81,43.36) 28.18,43.72 v1(28.18,44.86)
USBC_B2B_S3: length 2.1
  BOTTOM w0.102: PQS07.2 25.64,38.6 24.82,37.77 PRS34.2
USBC_SW_PROCHOT: length 3.2
  TOP w0.102: PCS20.1 PCS19.1 ; PCS19.1 24.04,112.93 PRS28.2 ; PCS19.1 22.65,113.53 PQS10.6
VBST_+1.05V: length 1.1
  BOTTOM w0.102: PRH02.1 v2(138.46,41.9)
VCI_IN1: length 7.6
  TOP w0.102: RE70.1 v2(92.75,46.06) 92.3,46.06 92.13,45.88 91.3,45.88 89.41,43.99 89.41,43.1 89.7,42.81 UE1.126
VCIN0_PH: length 9.2
  TOP w0.102: v1(103.64,48.45) 103.64,48.28 v2(102.63,47.27) 102.29,46.93 C33.1 102.29,45.75 102.38,45.66 RE37.2 ; R42.2 R43.2 66.05,111.83 66.48,112.26 66.48,112.41 RH1.1 66.73,112.66 66.73,114.21 66.87,114.35 C32.1 67.52,114.35 67.87,114.69 v1(67.87,115.04)
VCREF0: length 5.4
  TOP w0.102: RE46.2 RE167.2 76.29,47.26 CE23.1 RE48.1 78.88,46.32 79.3,46.32 79.49,46.12 UE1.25
VD_IN1_C: length 5.6
  TOP w0.102: v1(67.89,113.8) 67.52,113.43 C32.2 67.25,112.94 RH1.2 ; v1(104.22,48.53) 104.22,47.95 v2(104.22,47.95) 104.22,47.95 103.2,46.93 C33.2 R45.1
VGA_CSREF: length 52
  TOP w0.102: v1(246.74,68.96) 246.74,69.3 v2(246.36,69.68)
  BOTTOM w0.203: PUV101.21 248.58,68.91 246.79,70.7 PCV11.2 PCV14.1 PRV37.2 245.96,69.86 PCV15.1 ; PCV15.1 245.11,68.96 PRV40.2 ; PCV15.1 v1(246.74,68.96) ; v1(245.06,65.53) PCV16.1 245.07,66.15 PRV43.2
  BOTTOM w0.254: PRV50.1 PRV54.1 PRV58.1 244.08,77.06 245.33,75.82 245.33,71.38 PCV14.1
VGA_DRON: length 4.6
  TOP w0.102: v2(247.49,64.81) 247.22,64.55 v1(246.8,64.55)
  BOTTOM w0.203: PUV101.12 246.91,64.44 v1(246.8,64.55)
  BOTTOM w0.305: v1(219.28,66.62) 218.92,66.99 PUV01.16 ; PUV02.16 228.84,67.19 v1(229.14,66.9) ; PUV03.16 v1(239.35,67.07)
VGA_PWM1: length 3.6
  TOP w0.102: v1(246.85,63.8) v2(246.09,63.8)
  TOP w0.203: v1(246.85,63.8) 247.13,63.52 PRV38.2
  BOTTOM w0.203: v1(246.85,63.8) 247.09,64.04 PUV101.11
  BOTTOM w0.305: v1(218.09,65.09) 218.09,65.26 217.78,65.56 PUV01.1
VGA_PWM2: length 6.1
  TOP w0.102: v1(246.53,62.36) v2(245.38,62.36)
  BOTTOM w0.203: PUV101.10 248.58,62.97 248.5,62.89 247.07,62.89 v1(246.53,62.36) PRV35.2
  BOTTOM w0.305: v1(228.44,65.69) 228.29,65.53 227.88,65.53 227.66,65.75 PUV02.1
VGA_PWM3: length 5
  TOP w0.102: v1(247.29,62.33) v2(247.93,62.33)
  BOTTOM w0.203: PUV101.9 248.98,62.88 248.65,62.55 247.51,62.55 v1(247.29,62.33) PRV34.2
  BOTTOM w0.254: v1(238.22,65.11) 237.74,65.59 PUV03.1
VGA_REFIN: length 4.8
  BOTTOM w0.203: PRV16.1 254.71,60.6 PRV19.1 PCV06.2 253.86,62.1 v2(253.75,62.22) 252.91,62.22 252.18,62.95 PUV101.1
VGA_SMB_CK2: length 2.3
  BOTTOM w0.102: UV1.T4 221.6,96.9 221.6,96.86 ; RV191.1 221.13,86.75 QV1.4 220.98,87.37 v1(221.17,87.56)
VGA_SMB_DA2: length 2.8
  BOTTOM w0.102: UV1.T3 221.14,96.45 220.76,96.83 ; QV1.1 219.68,89.22 219.74,89.28 RV192.1 219.06,90.46 v1(218.87,90.46)
VGA_SW1: length 2.5
  TOP w0.102: v1(215.16,71.45) v2(215.16,72.77)
  TOP w0.381: PRV49.1 214.77,71.05 v1(215.16,71.45)
VGA_SW2: length 2.7
  TOP w0.102: v1(226.51,71.89) v2(226.51,73.14)
  TOP w0.508: v1(226.51,71.89) 226.87,71.53 PRV53.1
VGA_SW3: length 2.7
  TOP w0.102: v1(236.66,71.58) v2(236.66,73.09)
  TOP w0.381: v1(236.66,71.58) 236.92,71.32 PRV57.1
VGA_SWN1: length 3.7
  TOP w0.102: v2(243.89,70.64) 243.36,70.11 v1(243.36,69.97)
  TOP w0.203: PRV39.1 243.4,69.94 v1(243.36,69.97)
  BOTTOM w0.203: PRV46.2 v1(243.36,69.97) ; PLV01.2 213.62,75.01 v1(213.72,75.11)
VGA_SWN2: length 3.8
  TOP w0.102: v1(242.37,67.52) v2(242.37,68.19)
  TOP w0.203: PRV41.1 243.07,67.52 v1(242.37,67.52)
  BOTTOM w0.203: PRV45.2 242.78,67.93 v1(242.37,67.52)
  BOTTOM w0.254: PLV02.2 v1(224.37,75.17)
VGA_SWN3: length 3.4
  TOP w0.102: v2(242.27,65.99) 242.27,66.36 v1(242.52,66.62)
  TOP w0.203: PRV42.1 v1(242.52,66.62)
  BOTTOM w0.203: v1(234.88,75.11) 235.08,74.91 PLV03.2 ; v1(242.52,66.62) 242.52,66.61 PRV44.2
VGA_VREF: length 3.4
  BOTTOM w0.203: PRV17.1 PCV08.2 252.88,61.68 v2(252.41,62.16) 251.78,62.79 PUV101.2
VL: length 4.4
  BOTTOM w0.203: PU501.15 126.98,53.11 127.33,52.76 130.24,52.76 PC515.1
VR_CAP: length 5.5
  TOP w0.102: UE1.18 82.29,46.73 82.92,47.36 CE24.1 83.74,47.99 83.74,49.17 84.05,49.48 TP44.1
VR_ON: length 41.5
  TOP w0.102: v1(128.62,37.29) 128.62,36.67 128.99,36.3 129.75,36.3 130.65,35.41 v2(132.09,35.41) 134.27,35.41 134.9,34.78 136.23,34.78 ; 136.23,34.78 136.23,33.43 136.44,33.22 UC16.2 ; 136.23,34.78 137.67,34.78 RZ71.1 138.58,33.87 UZ21.4
  BOTTOM w0.102: v1(111.6,131.19) 110.53,132.26 110.53,138.72 109.01,140.24 PRZ19.2 ; v1(128.62,37.29) 128.62,37.8 126.63,39.79 125.61,39.79 118.85,46.55 v1(118.85,47.51)
VR_SVID_ALERT#: length 3.9
  TOP w0.102: PRZ22.2 110.43,140.75 v1(110.58,140.59) 110.58,140.49 v2(110.94,140.14)
  BOTTOM w0.102: RC267.1 RC261.2 68.53,128.38 v1(68.5,128.35) ; PRZ26.1 v1(110.58,140.59)
VR_SVID_ALERT#_R: length 1.4
  BOTTOM w0.102: v1(66.64,122.58) 67.01,122.21 UC1.BH31 ; RC267.2 66.84,129.25 v1(66.84,128.37)
VR_SVID_CLK: length 2.2
  TOP w0.102: PRZ23.2 109.64,140.72 v1(109.8,140.56)
  BOTTOM w0.102: UC1.BH32 66.97,122.86 v1(66.65,123.18) ; PRZ25.2 v1(109.8,140.56)
VR_SVID_DATA: length 3
  TOP w0.102: PRZ21.1 111.21,140.77 v1(111.36,140.62)
  BOTTOM w0.102: UC1.BH29 v1(67.17,120.3) ; PRZ27.2 v1(111.36,140.62) ; RC260.2 v1(69.29,128.34)
VREF_CPU: length 5
  TOP w0.203: CE17.1 89.5,28.32 89.15,28.32 88.69,28.78 UE1.95
  TOP w0.254: CE17.1 90.41,28.61 91.59,28.61 91.86,28.34 RE162.2
VSN_1PH: length 3.4
  TOP w0.203: v1(105.27,143.05) 105.27,142.52 PRZ03.2 PCZ01.2
  BOTTOM w0.203: v1(105.27,143.05) 105.27,143.5 105.88,144.12 PUZ01.51
VSN_2PH: length 2.9
  BOTTOM w0.203: PRZ41.1 111.91,145.56 111.49,145.98 PUZ01.37
  BOTTOM w0.254: PRZ41.1 PCZ21.1
VSN_4PH: length 4.5
  TOP w0.102: v1(103.51,144.18) 103.93,143.76 v2(104.12,143.76)
  TOP w0.203: PCZ05.2 103.49,144.16 v1(103.51,144.18)
  BOTTOM w0.203: PUZ01.2 104.35,145.58 104.15,145.38 104.15,144.81 v1(103.51,144.18) 103.51,144.18 PRZ11.2
VSP_1PH: length 3.7
  TOP w0.203: PCZ03.2 v1(104.6,143.04)
  BOTTOM w0.203: PUZ01.52 105.48,144.2 105.21,143.93 104.81,143.93 v2(104.41,143.53) 104.41,143.22 v1(104.6,143.04) 104.59,143.03 PRZ06.2
VSP_2PH: length 3.9
  TOP w0.102: v2(111.52,144.37) 111.96,144.81 v1(112.15,144.81)
  TOP w0.203: PCZ20.1 112.78,144.68 PRZ40.1 112.29,144.67 v1(112.15,144.81)
  BOTTOM w0.203: PUZ01.38 111.38,145.58 v1(112.15,144.81)
VSP_4PH: length 5
  TOP w0.102: PRZ08.2 102.65,142.49 v2(102.49,142.33)
  TOP w0.203: v1(103.51,143.52) 103.31,143.31 PRZ08.2
  BOTTOM w0.203: PCZ04.2 103.33,143.33 v1(103.51,143.52) 103.65,143.52 104.81,144.67 PUZ01.1
VTTREF_1.2V: length 1.9
  BOTTOM w0.203: PUM01.4 40.62,42.42 PCM19.1
WHITE_LED_BAT: length 2.9
  BOTTOM w0.102: v2(10.39,108.52) 10.06,108.19 R69.2 9.98,107.42 Q19.1
WLAN_PWR_EN: length 7.4
  TOP w0.102: v1(80.98,46.48) 81.09,46.36 UE1.21 ; Q30.3 24.69,121.63 23.47,120.41 22.62,120.41 22.28,120.75 v2(21.87,120.75) 21.58,120.75 20.36,119.53 v1(20.36,119.28)
WLAN_RADIO_DIS#: length 21.1
  TOP w0.102: DN1.1 38.33,100.84 38.33,100.28 v2(38.48,100.13) 38.6,100.01 39.65,100.01 40.26,100.62 40.26,101.57 v1(40.29,101.61)
  BOTTOM w0.076: UH1.BB16 184,47.96 184.44,47.52 184.64,47.52 184.89,47.76 186.06,47.76 186.44,48.15 186.71,48.15 186.93,48.36 187.52,48.36 187.64,48.48
  BOTTOM w0.102: 187.64,48.48 188.09,48.93 188.09,49.94 188.37,50.21 188.89,50.21 189.32,50.65 189.32,51.18 189.79,51.65 189.79,51.89 190.32,52.42 190.84,52.42 191.25,52.02 192.89,52.02 193.14,52.27 193.81,52.27 193.89,52.2 194.37,52.2 194.84,52.67 RH520.2 RH707.2 v1(196.42,52.83)
WLAN_RADIO_DIS#_R: length 8.1
  TOP w0.102: DN1.2 39.57,101.5 40.16,102.08 v1(40.81,102.08) 41.38,101.51 v2(41.38,100.91)
  BOTTOM w0.102: JWLAN1.56 42.2,103.48 v1(40.81,102.08)
XCLK_BIASREF: length 5.7
  BOTTOM w0.089: 171.63,55.47 171.48,55.32 171.48,55.02 171.27,54.81 UH1.T3
  BOTTOM w0.102: RH20.2 172.56,58.95 172.56,58.95 RH71.2 171.68,58.72 171.68,57.36 171.63,57.31 171.63,55.47
XDP_BPM#0: length 1.2
  TOP w0.102: v1(62.41,118.77) 62.33,118.85 TC98.1
  BOTTOM w0.102: UC1.BR27 62.41,118.86 v1(62.41,118.77)
XDP_BPM#1: length 3.3
  BOTTOM w0.102: TC99.1 62.09,119.15 UC1.BT27
XDP_BPM#2: length 1.1
  TOP w0.102: v1(64.36,122.73) 64.2,122.9 TC101.1
  BOTTOM w0.102: UC1.BM31 v1(64.36,122.73)
XDP_BPM#3: length 2.5
  BOTTOM w0.102: TC100.1 60.98,121.55 UC1.BT30
XDP_HOOK0: length 1.2
  TOP w0.102: RC86.2 181.34,34.06 TPC32.1
XDP_ITP_PMODE: length 9.6
  TOP w0.102: v1(111.85,114.96) 111.61,115.2 TPC7.1
  BOTTOM w0.089: UH1.AL3 178.36,54.91 178.36,56.3
  BOTTOM w0.102: 178.36,56.3 178.36,56.99 178.93,57.56 v1(178.93,57.76) ; RC80.2 115,113.89 114.52,114.37 112.43,114.37 v1(111.85,114.96)
XDP_PRDY#: length 9.1
  TOP w0.102: TPC31.1 60.06,117.23 60.06,117.7 v1(60.03,117.72)
  BOTTOM w0.076: v1(60.03,117.72) 61.81,119.5 63.08,119.5 UC1.BP27
  BOTTOM w0.089: UH1.AM5 178.9,53.96 178.9,55.37 178.85,55.42 178.85,56.09 178.82,56.11
  BOTTOM w0.102: v1(179.76,57.76) 179.76,57.7 178.82,56.76 178.82,56.11
XDP_PREQ#: length 8
  TOP w0.102: v1(59.41,110.13) 59.09,109.82 TPC30.1
  BOTTOM w0.089: UH1.AL2 178.59,56.15
  BOTTOM w0.102: 178.59,56.15 178.59,56.84 179.36,57.61 179.36,58.16 179.08,58.44 179.08,60.17 v1(178.6,60.64) ; UC1.BL30 65.1,121.86 v1(65.1,121.88) ; v1(59.41,110.13) RC259.2
XDP_PRSENT_CPU: length 2
  TOP w0.102: RC250.2 61.77,119.94 RC144.1 61.14,120.2 61.14,120.71 TPC33.1
XDP_PRSENT_PCH: length 3.5
  BOTTOM w0.102: RC145.1 179.62,30.29 179.92,30.59 180.82,30.59 181.29,30.12 RC249.2 181.29,29.05 TPC9.1
XDP_SPI_SI: length 3.4
  TOP w0.102: RC264.1 180.15,36.66 180.15,36 179.73,35.59 RC252.2 179.73,35 179.9,34.83 TPC8.1
XTAL24_IN: length 1.3
  BOTTOM w0.102: RH712.1 154.65,49.51 v1(155.12,49.03) ; UH1.U10 171.94,51.46 v1(172.13,51.64)
XTAL24_IN_R: length 3.2
  BOTTOM w0.102: YH2.1 155.7,51.83 CH47.1 155.7,50.33 RH72.1 155.23,49.87 RH712.2
XTAL24_OUT: length 1.5
  BOTTOM w0.102: v1(153.95,49.03) 153.95,49.64 RH711.1 ; v1(171.3,51.18) 171.3,51.51 UH1.U9
XTAL24_OUT_R: length 5.2
  BOTTOM w0.102: RH711.2 153.93,50.26 RH72.2 154.71,51.02 CH48.1 155.09,51.41 155.09,53.01 YH2.3
XTAL_OUT: length 7
  BOTTOM w0.102: 228.61,92.75 228.61,92.69 RV52.2 228.15,91.37 CV71.2 228.48,91.04 228.48,90.33 228.19,90.04 YV1.3
  BOTTOM w0.109: 228.61,92.75 228.61,94.21 228.28,95.09 228.1,95.27 228.1,95.45 UV1.H2
XTALIN: length 9.1
  BOTTOM w0.102: RV52.1 229.11,92.2 CV70.2 228.73,90.97 228.73,89.32 YV1.1
  BOTTOM w0.109: RV52.1 228.87,92.43 228.87,94.1 228.49,95.25 228.35,95.39 228.35,95.69 227.9,96.15 UV1.H3
XTALOUT: length 2.5
  TOP w0.109: RV51.1 226.47,96.86 226.67,96.86
  BOTTOM w0.102: UV1.J4 227.07,97.25 226.67,96.86
XTALSSIN: length 2.4
  TOP w0.102: 227.55,94.25 v2(226.95,94.25) 226.65,93.95 RV49.1
  BOTTOM w0.109: UV1.H1 227.55,94.5 227.55,94.25
N12281337:
  vias: v2(35.03,18.93)
N16785983: length 1.4
  TOP w0.102: TC28.1 65.47,119.77 v1(65.66,119.58)
  BOTTOM w0.102: UC1.BK28 v1(65.66,119.58)
N16785994: length 1
  TOP w0.102: TC30.1 66.64,119.9 v1(66.31,119.58)
  BOTTOM w0.102: TC30.1 v1(66.31,119.58)
N16789236: length 1.3
  TOP w0.102: TC45.1 65.14,122.98 v1(64.99,122.71)
  BOTTOM w0.102: UC1.BL31 v1(64.99,122.71)
N16789248: length 1.2
  TOP w0.102: TC47.1 81.63,104.7 v1(81.31,105.02)
  BOTTOM w0.076: TC47.1 v1(81.31,105.02)
N16789274: length 1.7
  TOP w0.102: v1(99.16,108.76) 98.82,109.1 TC48.1
  BOTTOM w0.102: UC1.G13 98.81,108.41 v1(99.16,108.76)
N16789292: length 1.7
  TOP w0.102: TC51.1 101.42,127.66 v1(101.78,127.3)
  BOTTOM w0.102: v1(101.78,127.3) 101.38,126.89 UC1.C38
N16789346: length 5.2
  BOTTOM w0.076: TC55.1 60.55,98.31 61.69,99.45 62.77,99.45 63.38,100.05 UC1.BP1
N16789364: length 1.5
  TOP w0.102: v1(102.58,127.3) 102.97,127.69 TC57.1
  BOTTOM w0.102: UC1.B38 102.16,126.88 v1(102.58,127.3)
N16789382: length 6
  BOTTOM w0.076: TC59.1 107.34,100.8 UC1.B2
N16789430: length 10.8
  BOTTOM w0.076: 103.38,99.73 102.58,99.73 102.41,99.57 100.81,99.57 100.31,100.07 100.31,100.72 UC1.E2
  BOTTOM w0.102: 103.38,99.73 105.99,97.12 105.99,96.07 TC25.1
N16789448: length 10.9
  BOTTOM w0.076: 103.18,99.35 100.72,99.35 UC1.E1
  BOTTOM w0.102: TC26.1 105.44,94.58 105.44,97.09 103.18,99.35
N16789466: length 8.5
  BOTTOM w0.076: UC1.D1 101.1,99.76 102.17,99.76 102.36,99.95 105.33,99.95 TC24.1
N16789484: length 5.4
  BOTTOM w0.076: UC1.BR1 62.65,100.14 61.56,100.14 60.04,98.61 60.04,97.15 59.79,96.9 TC27.1
N16789502: length 7.1
  BOTTOM w0.076: TC29.1 58.83,95.69 58.83,96.58 59.6,97.34 59.6,98.87 61.43,100.71 UC1.BT2
N16789520: length 5.1
  BOTTOM w0.076: 60.17,123.9 60.42,124.14 62.46,124.14 62.64,124.33 63.67,124.33 UC1.BN35
  BOTTOM w0.102: TC31.1 60.17,123.9
N16789538: length 1.1
  TOP w0.102: TC32.1 97.79,117.35 v1(97.79,117.45)
  BOTTOM w0.102: v1(97.79,117.45) 97.46,117.12 UC1.J24
N16789556: length 2.9
  TOP w0.102: TC33.1 100.27,117.87 98.92,117.87 v1(98.48,117.42)
  BOTTOM w0.102: v1(98.48,117.42) 98.11,117.06 UC1.H24
N16789574: length 1.2
  TOP w0.102: TC34.1 63.42,123.8 v1(63.71,123.51)
  BOTTOM w0.102: UC1.BN33 v1(63.71,123.51)
N16789592: length 1.4
  TOP w0.102: v1(64.99,124.33) 65.35,124.7 65.41,124.7 65.57,124.87 TC35.1
  BOTTOM w0.076: UC1.BL34 65.15,124.16 v1(64.99,124.33)
N16789610: length 1
  TOP w0.102: TC36.1 v1(94.2,121.19)
  BOTTOM w0.102: UC1.N29 v1(94.2,121.19)
N16789628: length 1.2
  TOP w0.102: TC37.1 92.61,108.6 v1(92.28,108.27)
  BOTTOM w0.102: TC37.1 v1(92.28,108.27)
N16789646: length 1.2
  TOP w0.102: v1(84.76,121.19) 84.87,121.3 TC38.1
  BOTTOM w0.102: UC1.AE29 85.08,120.86 v1(84.76,121.19)
N16789664: length 1.1
  TOP w0.102: TC39.1 v1(88.62,108.27)
  BOTTOM w0.102: TC39.1 v1(88.62,108.27)
N16789682: length 1.2
  TOP w0.102: v1(77.67,121.19) 77.44,121.41 TC40.1
  BOTTOM w0.102: v1(77.67,121.19) 77.99,120.86 UC1.AP29
N16789700: length 1.4
  TOP w0.102: TC41.1 77.65,108.64 v1(77.65,108.27)
  BOTTOM w0.102: UC1.AP14 v1(77.65,108.27)
N16789725: length 2.8
  TOP w0.102: v1(99.14,122.17) 100.19,123.23 TC42.1
  BOTTOM w0.102: v1(99.14,122.17) 99.14,122.1 UC1.F30
N16789743: length 1.1
  TOP w0.102: TC43.1 100.19,122.58 v1(99.78,122.17)
  BOTTOM w0.102: UC1.E30 99.78,122.1 v1(99.78,122.17)
N16789761: length 1.3
  TOP w0.102: v1(102.39,121.38) 102.21,121.56 TC44.1
  BOTTOM w0.102: UC1.B30 102.06,121.71 v1(102.39,121.38)
N16789779: length 2.5
  TOP w0.102: v1(101.74,121.38) 101.6,121.52 TC46.1
  BOTTOM w0.102: v1(101.74,121.38) 101.41,121.71 UC1.C30
N16789797: length 2.3
  TOP w0.102: TC49.1 99.4,100.1 v1(98.36,101.15)
  BOTTOM w0.102: v1(98.36,101.15) 98.64,101.44 UC1.G3
N16789815: length 1.8
  TOP w0.102: v1(97.54,101.15) 98.07,100.62 TC50.1
  BOTTOM w0.102: v1(97.54,101.15) 97.82,101.44 UC1.J3
N16789833: length 4.8
  BOTTOM w0.076: UC1.BR35 62.37,124.31 60.05,124.31 59.68,123.94
  BOTTOM w0.102: 59.68,123.94 59.56,123.82 TC54.1
N16789851: length 5.8
  BOTTOM w0.076: 59.46,120.47 60.73,121.74 61.67,121.74 61.9,121.97 62.18,121.97 62.54,122.33 UC1.BR31
  BOTTOM w0.102: 59.46,120.47 58.38,120.47 TC56.1
N16789869: length 1.2
  TOP w0.102: TC58.1 66.75,122.03 v1(66.64,121.93)
  BOTTOM w0.102: UC1.BH30 v1(66.64,121.93)
N16795294: length 4.6
  TOP w0.102: v2(103.51,126.45) 103.89,126.07 v1(103.89,125.8)
  BOTTOM w0.076: UC1.A36 103.4,125.41
  BOTTOM w0.102: RC6.2 104.97,125.03 104.19,125.8 v1(103.89,125.8) 103.49,125.41 103.4,125.41
N16795301: length 4.2
  TOP w0.102: v1(105.47,125.68) v2(106.17,125.68)
  BOTTOM w0.076: UC1.A37 104.63,126.19 104.93,125.89
  BOTTOM w0.102: RC7.2 v1(105.47,125.68) 105.14,125.68 104.93,125.89
N16815495: length 9.5
  BOTTOM w0.102: TC4.1 72.47,91.65 72.47,95.12 72.65,95.3 72.65,99.87 72.54,99.98 72.54,100.45 UC1.BA2
N16815498: length 9.1
  BOTTOM w0.102: TC5.1 72.75,92.45 72.75,95.02 72.87,95.13 UC1.BA1
N16815505: length 1.3
  TOP w0.102: TC6.1 73.61,102.02 v1(74.01,102.42)
  BOTTOM w0.102: UC1.AY4 v1(74.01,102.42)
N16815512: length 1.2
  TOP w0.102: TC7.1 74.34,102.72 v1(74.01,103.04)
  BOTTOM w0.102: UC1.AY5 v1(74.01,103.04)
N16815519: length 1.1
  TOP w0.102: TC8.1 72.09,102.74 v1(72.42,102.41)
  BOTTOM w0.102: UC1.BA5 72.55,102.41 v1(72.42,102.41)
N16815526: length 1.5
  TOP w0.102: TC9.1 72.15,101.46 v1(72.44,101.75)
  BOTTOM w0.102: UC1.BA4 v1(72.44,101.75)
N16815533: length 7.8
  BOTTOM w0.102: TC10.1 73.09,92.97 73.09,99.62 UC1.AY1
N16815540: length 1.3
  TOP w0.102: v1(74.05,101.11) 73.6,100.66 TC12.1
  BOTTOM w0.102: UC1.AY2 v1(74.05,101.11)
N16820214: length 1.5
  TOP w0.102: TC13.1 72.19,100.84 v1(72.44,101.09)
  BOTTOM w0.102: v1(72.44,101.09) 72.53,101.09 UC1.BA3
N16820216: length 1.3
  TOP w0.102: v1(74.03,101.76) 74.41,101.38 TC11.1
  BOTTOM w0.102: UC1.AY3 v1(74.03,101.76)
N16844270: length 1.6
  TOP w0.102: TC14.1 75.3,107.31 v1(74.91,106.93)
  BOTTOM w0.102: UC1.AW11 v1(74.91,106.93)
N16844279: length 1.2
  TOP w0.102: TC15.1 74.39,107.4 v1(73.94,106.96)
  BOTTOM w0.102: UC1.AY11 v1(73.94,106.96)
N16844288: length 2
  TOP w0.102: v1(73.94,105.01) 73.49,104.56 TC16.1
  BOTTOM w0.102: UC1.AY8 v1(73.94,105.01)
N16844297: length 1.5
  TOP w0.102: v1(74.91,105.05) 75.42,104.55 TC17.1
  BOTTOM w0.102: UC1.AW8 v1(74.91,105.05)
N16844306: length 2.6
  TOP w0.102: TC18.1 72.62,107.43 73.25,107.43 73.52,107.16 73.52,106.72 v1(73.94,106.31)
  BOTTOM w0.102: UC1.AY10 v1(73.94,106.31)
N16844322: length 1.2
  TOP w0.102: TC19.1 75.29,106.01 v1(74.96,106.33)
  BOTTOM w0.102: UC1.AW10 v1(74.96,106.33)
N16844331: length 1.7
  TOP w0.102: v1(73.94,104.35) 73.33,103.75 TC20.1
  BOTTOM w0.102: UC1.AY7 v1(73.94,104.35)
N16844333: length 2.2
  TOP w0.102: v1(74.91,104.4) 75.82,103.49 TC22.1
  BOTTOM w0.102: UC1.AW7 v1(74.91,104.4)
N16844514: length 1
  TOP w0.102: TC23.1 73.61,105.98 v1(73.94,105.66)
  BOTTOM w0.102: UC1.AY9 v1(73.94,105.66)
N16844516: length 2.3
  TOP w0.102: v1(74.94,105.65) 74.9,105.65 74.42,105.17 TC21.1
  BOTTOM w0.102: UC1.AW9 v1(74.94,105.65)
N16865170: length 1.2
  TOP w0.102: TC94.1 75.35,108.71 v1(74.91,108.27)
  BOTTOM w0.076: UC1.AU13 v1(74.91,108.27)
N16865242: length 1.2
  TOP w0.102: TC95.1 72.63,108.72 v1(73.08,108.27)
  BOTTOM w0.076: UC1.AY13 v1(73.08,108.27)
N16946088: length 2.2
  BOTTOM w0.102: RG546.2 199.25,89.93 198.65,90.52 v2(198.65,91.86)
N17003752: length 4.9
  TOP w0.102: RD23.2 76.85,60.87 v2(77.36,60.37) v1(78.1,60.37)
  BOTTOM w0.102: v1(78.1,60.37) 77.57,60.89 JDIMM1.134
N17004366: length 2.8
  TOP w0.102: RD24.2 80.69,51.85 v1(81.01,51.53)
  BOTTOM w0.102: v1(81.01,51.53) 80.58,51.09 JDIMM2.134
N17075731: length 2.7
  TOP w0.102: DA8.2 22.59,14.09 v2(22.04,14.64)
  TOP w0.254: RA29.1 22.47,12.93 DA8.2
N17075741: length 2.2
  TOP w0.102: DA8.3 23.04,11.6 v2(23.04,10.88)
  TOP w0.254: RA33.1 22.47,12.17 DA8.3
N17283936: length 1.6
  TOP w0.102: QA1.3 40.34,23.54 v2(40.56,23.77)
N17389450: length 1.6
  TOP w0.102: v1(213.63,46.53) 214.06,46.96 v2(214.11,46.96)
  BOTTOM w0.254: PR502.2 213.21,46.11 v1(213.63,46.53)
  vias: v1(129.02,57.28)
N17462309: length 5.8
  TOP w0.102: RE58.2 71.84,31.12 v2(71.84,30.25) 71.44,29.84 71.44,28.71 70.98,28.26 69.65,28.26 69.46,28.44 JDEG1.9
N17462311: length 4
  TOP w0.102: JDEG1.1 65.46,29.57 65.32,29.72 63.98,29.72 v2(63.53,30.17) 63.53,30.91 RE59.2
N17462343: length 3.5
  BOTTOM w0.102: RE65.2 72.38,40.29 v2(73.01,40.29) 74.01,40.29 74.31,40.6 JESPI1.8
N17731278: length 27.1
  TOP w0.102: v1(239.78,87.14) v3(238.67,87.14) 237.41,87.14 234.26,83.99 224.17,83.99 223.8,84.37 223.8,85.22 v1(222.66,86.36)
  BOTTOM w0.102: v1(206.18,86.32) 205.66,85.8 203.73,85.8 203.57,85.95 RG505.2 203.57,87.02 RG580.2 201.12,87.12 DG3.1 ; QG502.3 v1(239.78,87.14)
N18346546: length 7.7
  TOP w0.102: v2(241.66,40.52) Q13.1
  TOP w0.254: R37.1 238.51,36.24 238.72,36.03 240.42,36.03 241.66,37.26 Q13.1
N18346552: length 6.9
  TOP w0.102: Q12.2 236.39,38.11 C18.2 R38.2 238.9,38.11 Q13.2 v2(239.57,40.56)
N18346555: length 7.4
  TOP w0.102: v2(231.52,38.53) 232.28,39.29 Q12.3
  TOP w0.508: C18.1 236.63,39.1 R35.2 235.99,40.47 233.78,40.47 233.27,39.97 Q12.3
N18855880: length 7.2
  TOP w0.102: v2(254.88,49.76) 254.99,49.65 U1.3 256.16,48.8 256.63,48.33 259.36,48.33 R57.2
N18983262: length 2.3
  BOTTOM w0.102: v2(71.72,38.39) 71.8,38.31 CE35.2 73.79,38.31 RE67.1
N19136586: length 1.2
  TOP w0.102: v2(272.28,41.65) 272.42,41.8 QS1.6
N20816771: length 1.2
  BOTTOM w0.102: PCG09.1 v2(60.59,154.03)
N20816793: length 2.4
  TOP w0.102: v1(58.38,140.66) v2(58.38,141.31)
  TOP w0.203: v1(58.38,140.66) 58.38,139.73 PRG03.1
  BOTTOM w0.203: PLG01.3 v1(58.38,140.66)
N20816859: length 1
  BOTTOM w0.102: PRA02.2 v2(110.18,134.94)
N20820556: length 2.3
  TOP w0.203: v1(88.49,135.53) v2(88.49,136.09) 88.49,137.12 PRI03.1
  BOTTOM w0.203: PLI01.3 v1(88.49,135.53)
N20820665: length 3.2
  TOP w0.203: PRI07.1 83.43,138.97 v2(82.03,138.97) v1(81.07,138.97)
  BOTTOM w0.203: PLI02.3 v1(81.07,138.97)
N20820729: length 3.1
  TOP w0.203: PRI11.1 v2(74.4,138.91) 73.5,138.91 v1(73.49,138.92)
  BOTTOM w0.203: PLI03.3 v1(73.49,138.92)
N20820776: length 3.3
  TOP w0.203: v1(65.79,139.02) 65.89,138.92 v2(66.73,138.92) PRI15.1
  BOTTOM w0.203: PLI04.3 v1(65.79,139.02)
N20905578: length 2.2
  TOP w0.102: v2(36.71,87.93) CT104.1 35.07,87.93 v1(35.04,87.9)
  BOTTOM w0.076: v1(35.04,87.9) 34.96,87.99 UT4.H7
N21354362: length 3.7
  TOP w0.102: PQS05.5 24.13,42.2 24.4,41.93 v2(24.4,41.63) 24.4,40.38 24.26,40.25 PUS03.4
N21379353: length 1.5
  TOP w0.102: v2(127.13,52.58) 127.78,51.93 v1(128.33,51.93)
N21388536: length 3.2
  TOP w0.102: PUS03.2 26.07,39.6 26.53,39.14 v1(26.77,39.14) 26.87,39.14 v2(27.33,39.6)
  BOTTOM w0.102: PDS03.1 26.77,39.11 v1(26.77,39.14)
N21449558: length 7.3
  TOP w0.102: v2(49.87,143.61) 49.25,142.99 PQ2.1 48.34,142.99 47.11,141.76 46.55,141.76 PR4.2 PR7.1 44.45,140.49 PQ1.2
N21449563: length 10.7
  TOP w0.102: PR3.1 44.75,142.26 PD1.2 42.88,141.24 PQ1.1 40.45,138.4 40.23,138.62 v2(40.23,139.61) 40.23,140.99 PL3.2
N21449587: length 3.6
  TOP w0.102: PQ13.2 53.31,141.23 53.23,141.31 PR45.1 53.23,142.61 PR31.2 53.23,143.34 PR35.2 v2(52.23,143.37)
N21449588: length 1.6
  TOP w0.102: PR32.2 51.01,142.09 v2(50.71,142.39)
N21449601: length 5.4
  BOTTOM w0.102: v2(49.51,129.67) 48.93,129.67 47.12,127.85 PR36.2
  BOTTOM w0.254: PR36.2 47.11,127.39 PR44.2 46.3,127.32 PQ12.2
N21449607: length 4.9
  TOP w0.102: v2(273.65,61.06) 273.97,60.74 PQ11.2 ; PC14.2 273.14,58.59 PQ11.2 ; PQ11.2 274.14,58.42 PR43.1
N21449609:
  vias: v2(54.86,137.27)
N21449623: length 3.7
  TOP w0.102: v1(47.26,123.84) 47.26,124.05 v2(47.6,124.4)
  BOTTOM w0.254: PQ12.5 46.3,124.21 46.42,124.09 PC13.2 46.72,123.54 47.02,123.84 v1(47.26,123.84) 47.71,123.84 PR40.1
N21449665: length 3.7
  TOP w0.102: v2(44.5,137.11) 45.33,137.94 PD3.1 45.33,140.34 PR7.2
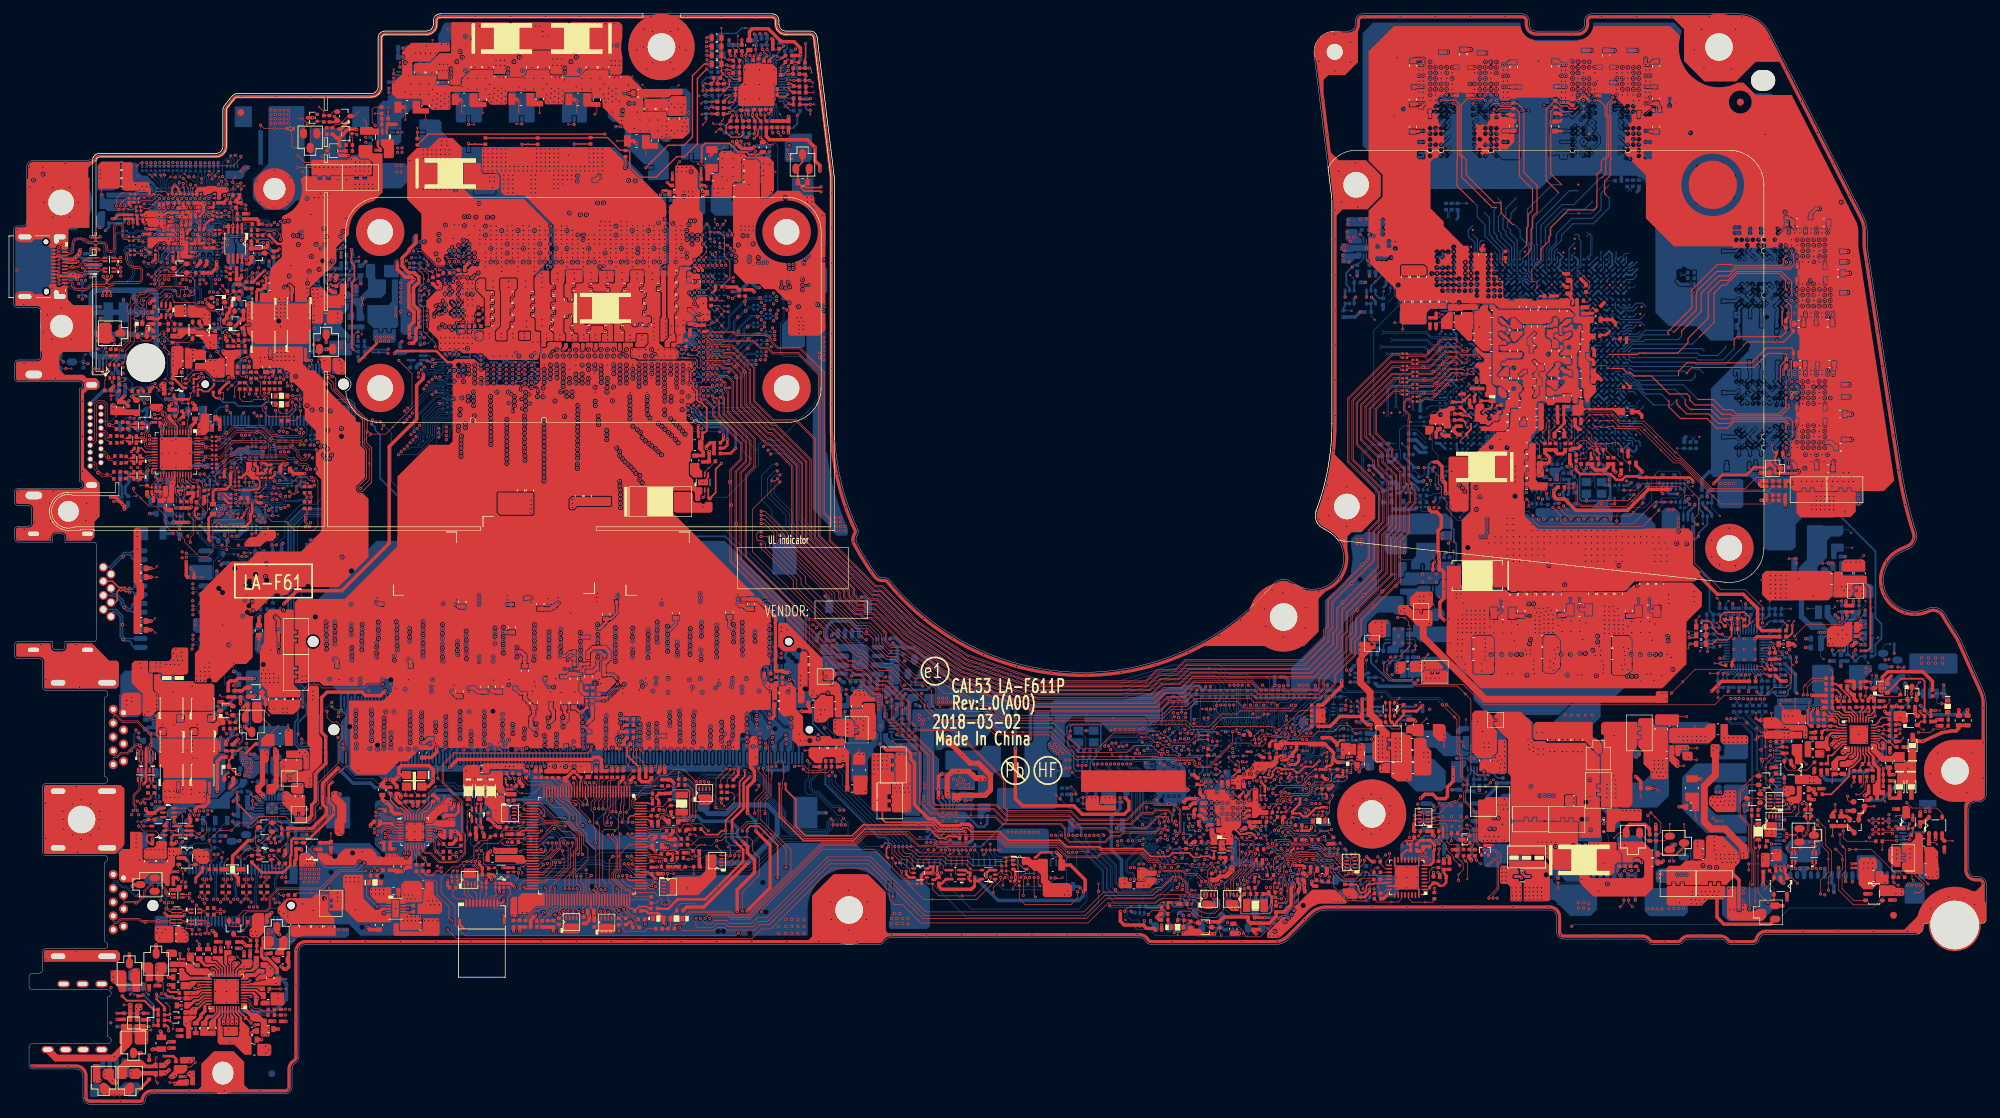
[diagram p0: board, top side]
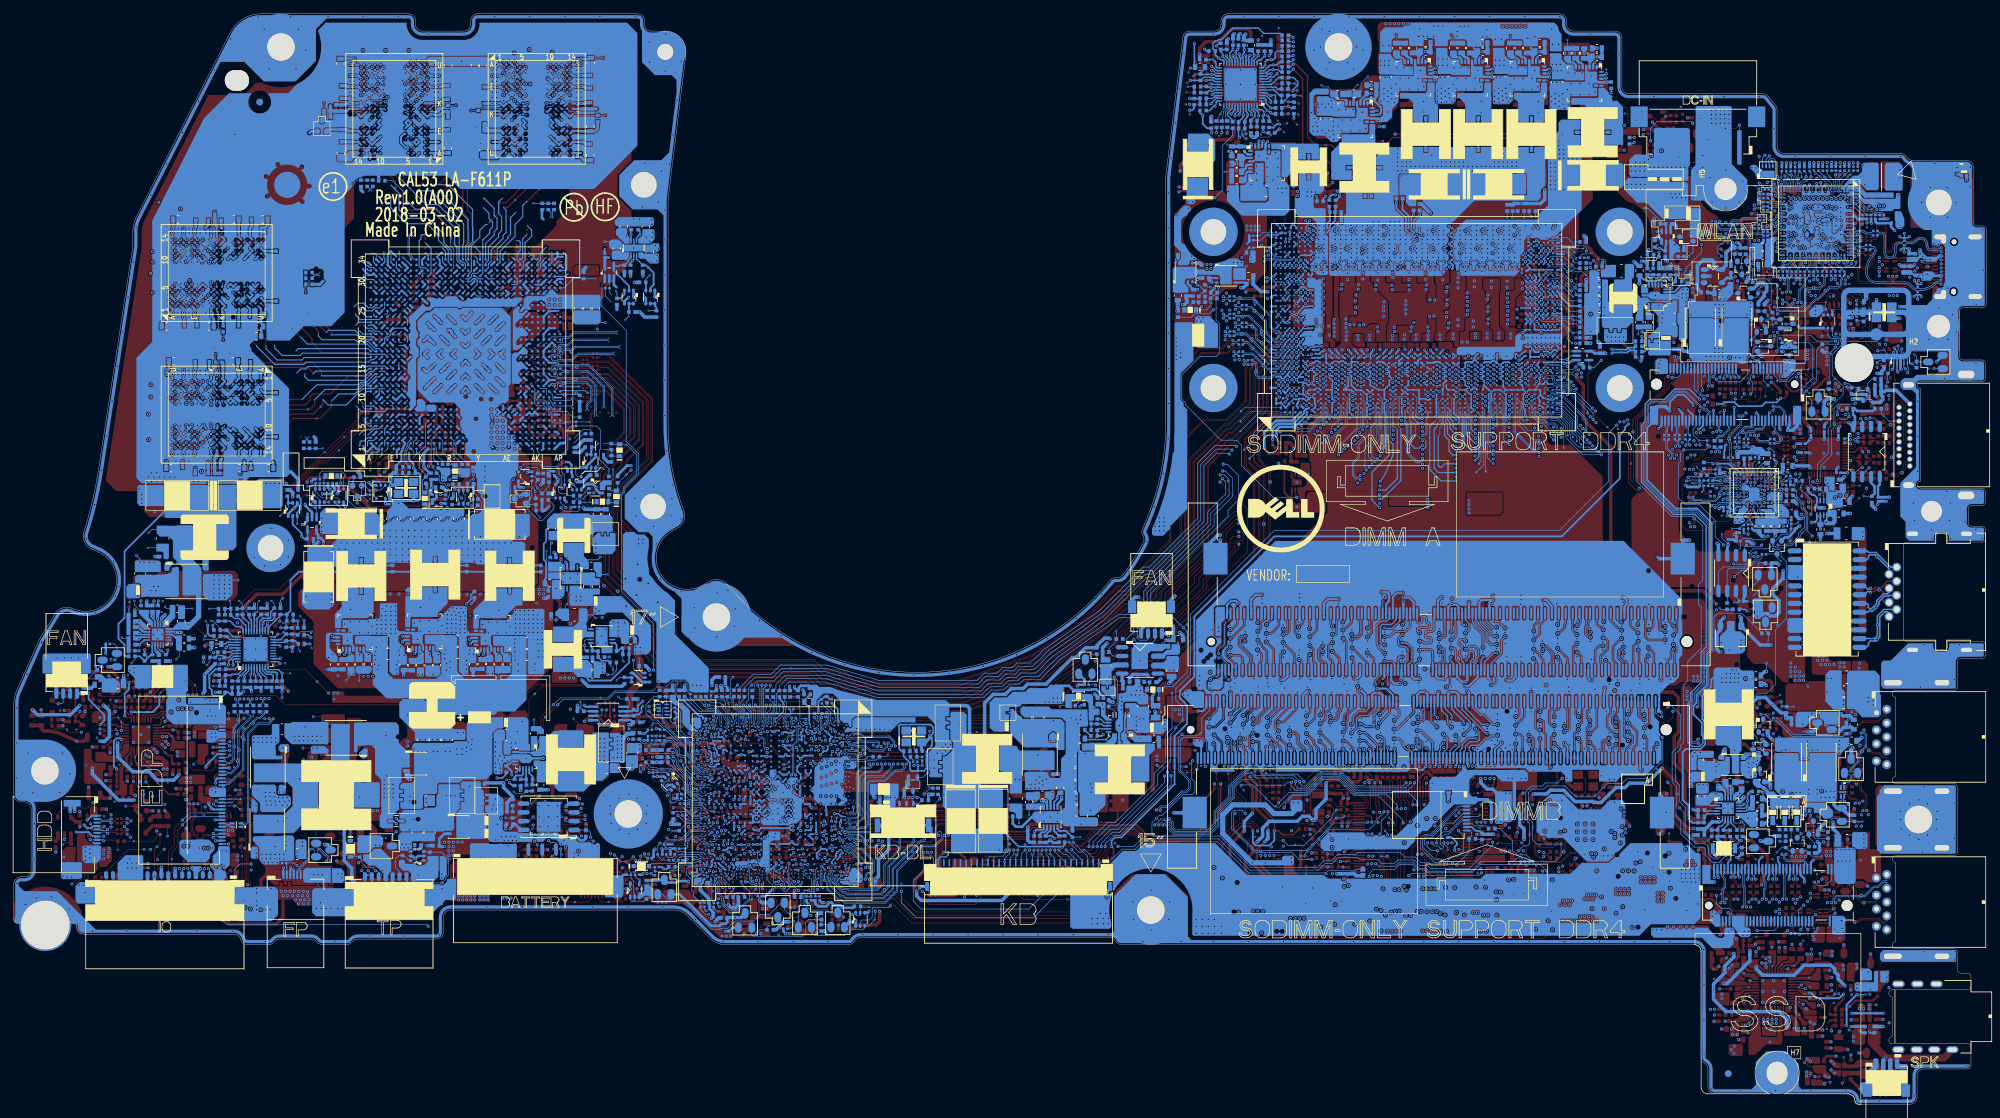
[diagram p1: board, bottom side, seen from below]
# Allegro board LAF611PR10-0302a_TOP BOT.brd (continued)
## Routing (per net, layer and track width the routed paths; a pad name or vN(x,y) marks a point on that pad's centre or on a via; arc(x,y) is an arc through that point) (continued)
N21449681: length 14.5
  TOP w0.102: PR12.2 39.05,105.48 v1(39.05,104.91)
  BOTTOM w0.102: v1(39.05,104.91) 38.69,104.55 35.56,104.55 34.49,105.62 34.49,107.99 33.76,108.72 33.76,109.27 33.35,109.68 PQ6.1 30.7,110.2 v2(30.7,110.68)
N21449685: length 6.9
  TOP w0.102: v1(36.29,119.78) 36.29,119.91 v2(36.63,120.24)
  TOP w0.381: PQ7.4 40.21,117.35 40.27,117.41 PR8.2 40.27,118.2 v1(39.9,118.57) ; PQ3.4 35.13,117.65 PR10.1 35.83,117.85 PC5.2 36.5,118.53 36.5,119.56 v1(36.29,119.78)
N21449690: length 2.6
  TOP w0.102: PR10.2 35.71,119.15 v1(35.96,119.15)
  BOTTOM w0.102: PQ5.1 35.91,119.1 v1(35.96,119.15)
N21449736: length 3.4
  TOP w0.102: v3(212.23,34.81) 212.1,34.81 v1(211.59,35.32) 211.39,35.52 PR39.1
  BOTTOM w0.102: v1(211.59,35.32) 210.9,36.01 PBATT1.5
N21449778: length 4.7
  TOP w0.102: PRS27.2 20.03,114.68 20.04,114.69 20.04,115.14 PRS26.2 20.73,115.04 21.77,115.04 22,115.27 PQS10.2 22,116.23 v2(22.64,116.88)
N21484822:
  vias: v1(197.9,69.09) v1(197.93,68.49) v1(197.93,67.88) v1(197.95,69.7) v1(198.55,69.8) v3(196.98,69.7)
N21513882: length 2
  BOTTOM w0.102: PD10.3 36.39,122.37 PR14.2 36.38,123.02 PR16.1
N21517490: length 5.9
  TOP w0.102: PR65.2 30.26,103 30.34,102.92 30.34,102.13 v2(30.25,102.04)
  TOP w0.254: PR46.2 33.4,112.01 PQ15.2 33.12,112.42 33.53,112.83 v1(34.02,112.83)
  TOP w0.381: v1(31.12,104.49) 30.99,104.49 29.77,103.28 PR65.2
N21537645: length 3.4
  TOP w0.102: v1(33.76,108.1) 33.19,108.1 v2(32.84,107.76) 32.36,107.27 PR48.2
  BOTTOM w0.102: PQ17.1 28.92,112.94 v1(28.96,112.9)
N21556764: length 2.5
  TOP w0.102: PQS10.5 22,113.56 22.34,113.22 PCS19.2 21.12,112.93 PRS29.1
N21558641: length 5.4
  TOP w0.102: PCS20.2 22.22,111.89 21.46,111.89 21.18,111.62 v2(21.18,111.4) 20.96,111.17 20.41,111.17 PRS30.1 19.79,110.55 18.53,110.55 PQS11.2
N21562486: length 1.4
  BOTTOM w0.102: PDS06.2 29.01,40.91 PRS23.2
N21563532: length 1.3
  BOTTOM w0.102: PRS33.2 27.31,40.96 PDS05.2
N21563639: length 1.7
  BOTTOM w0.102: PDS04.2 29.9,40.05 PRS32.2
N21599913: length 2.8
  TOP w0.102: RL7.2 v2(45.87,39.18)
  TOP w0.508: UL2.3 45.72,37.84 RL7.2
N21664134: length 2.4
  TOP w0.102: RS5.1 v2(280.5,38.11)
  TOP w0.508: RS5.1 278.98,38.43 US2.3
N21741311: length 4.8
  TOP w0.102: v2(32.6,52.21) 33.03,52.64 33.03,54.41 v1(32.74,54.7) 32.4,54.35 PRS37.2
  BOTTOM w0.102: v1(32.74,54.7) 32.27,55.17 PQS12.1
N21741314: length 11.4
  TOP w0.102: PRS37.1 31.65,55.27 31.64,55.26 PRS36.2 30.81,55.7 v1(30.81,55.88)
  BOTTOM w0.102: v1(30.81,55.88) 30.25,55.88 v2(29.72,55.35) 27.86,53.49 23.09,53.49 PQS13.2
N21741394: length 2.7
  TOP w0.102: PRS38.2 31.27,53.66 v2(31.61,53.31) 32.15,53.31 v1(32.29,53.45)
  BOTTOM w0.102: v1(32.29,53.45) 32.51,53.45 PQS12.2
N21741739: length 6.3
  BOTTOM w0.127: v1(25.78,53.92) v2(26.59,53.92)
  BOTTOM w0.508: PRS11.1 20.23,54.53 PRS08.2 ; PRS11.1 19.43,54.53 PCS09.2 ; PRS11.1 20.62,54.53 v1(21.23,53.92) ; v1(25.78,53.92) 25.02,53.92 24.44,54.51 PQS13.1
N21876819: length 4.2
  TOP w0.102: v2(254.42,95.41) 254.42,94.58 254.73,94.27 RV141.1
  TOP w0.254: QV21.1 254.83,92.78 254.83,93.66 255,93.83 RV141.1
N21996246: length 3.6
  TOP w0.102: R30.1 254.64,33.17 U3.3 254.64,32.42 v2(253.25,31.04)
N22121555: length 5.3
  TOP w0.102: UW1.3 25.86,112.87 26.54,112.19 27.99,112.19 28.31,111.87 RW12.2 29.54,112.29 v2(29.54,112.98)
N22230445: length 7.8
  TOP w0.102: PUS01.1 33.01,127.48 33.09,127.56 34.32,127.56 PCS04.1 34.36,127.27 PRS39.1 PRS01.2 34.85,125.26 34.87,125.26 PRS02.2 35.5,125.13 36.88,125.13 v2(37.4,124.62)
N22234781: length 2.8
  BOTTOM w0.102: PDS03.2 28.53,36.66 PRS40.2 29.58,37.13 v2(30.28,36.44)
N22234784: length 3.2
  BOTTOM w0.102: v2(23.75,35.9) 25.18,35.9 PRS41.2 25.94,36.66 PDS03.3
N22253138: length 7.5
  TOP w0.102: v1(21.78,109.56) 22.45,108.89 v2(22.45,108.55)
  BOTTOM w0.102: v1(21.78,109.56) 22.62,108.72 22.62,104.5 R68.1
  BOTTOM w0.406: LED1.4 v1(2.85,133.73)
N22253145: length 2.4
  TOP w0.102: v1(10.74,107.17) v2(10.04,107.17)
  BOTTOM w0.102: R69.1 10.15,106.59 v1(10.74,107.17)
  BOTTOM w0.457: LED1.2 3.8,134.59 v1(4.21,134.59)
N22336501: length 2.9
  TOP w0.102: v1(87.81,141.48) v2(87.06,141.48)
  TOP w0.203: PRZ66.2 103.58,151.86 v1(103.71,151.74)
  BOTTOM w0.203: PRZ67.1 103.49,151.95 v1(103.71,151.74) ; PHZ03.1 v1(87.81,141.48)
N22336574: length 2.9
  TOP w0.102: v1(54.25,146.4) v2(54.25,147.05)
  TOP w0.203: v1(111.38,153.16) 110.98,152.75 PRZ69.1
  BOTTOM w0.152: PHZ04.1 v1(54.25,146.4)
  BOTTOM w0.203: v1(111.38,153.16) 111,153.54 PRZ68.2
N22572921: length 2.8
  BOTTOM w0.203: PRZ71.2 v2(111.94,151.19) 111.82,151.19 111.44,150.81 111.44,150.16 111.26,149.98 PUZ01.27
N22693418: length 15
  TOP w0.102: v2(200.86,37.26) 200.86,37.79 201.17,38.1 201.5,38.1 v1(201.52,38.07)
  TOP w0.254: RTPM10.2 202.6,38.35 202.38,38.12 201.57,38.12 v1(201.52,38.07) 201.52,37.74 201.68,37.59 RTPM8.2 CTPM6.1 201.44,36.74 200.77,36.08 UTPM1.14 ; UTPM1.22 198.35,32.07 198.26,31.98 196.86,31.98 196.75,31.86 196,31.86 195.68,31.55 195.68,30.94 195.39,30.64 194.83,30.64 194.51,30.96 v1(194.51,31.15) 194.51,31.51 194.2,31.82 CTPM7.1 192.59,31.82 CTPM5.1
N22693460: length 6.8
  TOP w0.203: 204.83,31.27 204.63,31.07 UTPM1.1
  TOP w0.381: 204.83,31.27 204.83,31.44 CTPM2.1 205.89,32 206.29,31.61 v3(206.76,31.61) 207.21,32.07 CTPM1.1 207.21,33.13 206.9,33.45 RTPM7.1 RTPM6.1
N22693593: length 4.9
  TOP w0.102: UTPM1.27 200.77,29.74 200.28,29.25 v2(199.3,29.25) 197.32,29.25 RTPM4.1
N22894187: length 5.3
  TOP w0.102: UE1.42 v2(73.29,40.01) 72.85,39.57 70.72,39.57 70.59,39.44 RE85.1
N23415623: length 4.5
  TOP w0.102: v2(93.23,29.4) 92.92,29.09 RE89.1 91.72,29.59 UE1.96
N23757940: length 7.1
  BOTTOM w0.076: UC1.C1 102.12,100.13 102.26,100.28 106.44,100.28 TC52.1
N23757941: length 6.9
  BOTTOM w0.076: TC53.1 59.21,96.58 59.85,97.22 59.85,98.74 61.46,100.35 62.27,100.35 62.77,100.85 UC1.BR2
N24091331: length 6
  BOTTOM w0.089: 187.67,39.53 187.52,39.68 185.73,39.68 UH1.BE33
  BOTTOM w0.102: 187.67,39.53 188.65,38.56 188.96,38.56 189.18,38.34 190.69,38.34 T92.1
N24173022: length 1.1
  TOP w0.102: TH101.1 178.58,38.51 v1(178.84,38.76)
  BOTTOM w0.089: v1(178.84,38.76) 178.49,39.11 UH1.AL35
N24203733: length 30.5
  TOP w0.102: v1(25.32,117.02) 25.95,117.02 26.15,117.22 v2(26.15,117.87) 26.15,119.24 25.63,119.76 21.68,119.76 21.13,119.21 21.13,118.63 20.48,117.97 19.37,117.97 18.82,117.42 18.27,117.42 17.84,116.98 17.21,116.98 16.88,116.66 16.88,115.95 16.4,115.47 16.4,114.68 16.55,114.53 16.55,110.54 15.24,109.23 15.24,107.95 14.52,107.23 QV96.5 QV96.2
  BOTTOM w0.102: RV683.2 RV684.2 209.54,91.98 209.73,92.18 211.14,92.18 v1(211.54,91.77)
N24570150: length 2.3
  TOP w0.102: Q25.1 174.36,25.61 R73.2 174.45,24.83 v2(174.73,24.55)
N24570154: length 4.8
  TOP w0.102: v2(168.39,24.47) 168.39,24.79 D7.2 169.21,26.54 R78.1 170.07,26.62 C60.1 170.42,26.26 Q25.2
N24625779: length 1.6
  TOP w0.203: UZ1.12 56.64,28.69 56.72,28.76 57.77,28.76 CZ11.1
N24625783: length 1.6
  TOP w0.203: UZ1.10 56.74,27.89 56.82,27.81 57.78,27.81 CZ10.1
N24678846: length 5.9
  TOP w0.102: RH103.2 127.08,35.38 RH105.1 127.56,34.57 v3(128.45,33.68) 128.45,33.18 129.74,31.89 RH180.2
N24681096: length 6.7
  BOTTOM w0.203: UC1.H14 97.73,109.56 97.02,109.56 96.9,109.68 v1(96.11,109.68)
  BOTTOM w0.254: RC271.1 RC272.1 50.92,109.11 51.6,109.11 51.92,108.79 v2(52.79,108.79) 54.01,108.79 v1(54.14,108.65)
N24681102: length 5.4
  BOTTOM w0.254: RC274.1 RC273.1 50.9,109.5 51.76,109.5 52.05,109.21 54.11,109.21 v1(54.18,109.27) ; v1(96.58,109.25) 96.68,109.15 97.44,109.15 UC1.J14
N25297595: length 4.6
  TOP w0.102: v2(144.54,31.09) 144.54,31.42 145.38,32.26 RZ234.2 145.31,32.42 145.31,34.41 145.05,34.67 UC12.2
N25297620: length 3.3
  TOP w0.102: v2(142.02,35.1) RZ238.1 ; RZ238.1 RZ237.2 ; RZ238.1 143.77,35.32 UC12.1
N25559338: length 2.2
  BOTTOM w0.102: RX6.1 16.46,104.98 17.16,104.28 QX3.2
N25587837: length 4.8
  TOP w0.102: UTPM1.29 201.77,29.77 202.31,29.23 v2(204.18,29.23) 205.23,29.23 205.51,29.51 RTPM11.1
N25587876: length 3.7
  TOP w0.102: RTPM12.1 205.33,34.24 v2(205.23,34.13) 204.8,33.7 204.8,32.31 204.56,32.07 UTPM1.3
N25755660: length 2.5
  TOP w0.102: PQS19.1 29.83,57.29 v1(29.53,57.6)
  BOTTOM w0.102: v1(29.53,57.6) 29.46,57.54 PRS43.2 v2(27.81,57.54)
N25756286: length 13.6
  TOP w0.508: PQS20.1 34.17,53.87 v1(33.39,54.65)
  BOTTOM w0.508: v1(33.39,54.65) 33.8,55.06 33.8,58.12 33.07,58.85 31.95,58.85 v2(30.89,57.79) 29.72,56.62 PRS43.1 29,56.51 v1(29,55.92) 28.22,55.92 PRS42.2 PCS21.2
  vias: v1(24.38,56.07)
N25791938: length 2.6
  BOTTOM w0.102: RV126.1 v2(240.47,144.87)
  BOTTOM w0.508: RV126.1 240.47,142.68 QV20.1
N25839183: length 2.4
  BOTTOM w0.381: PR63.1 PR62.2 37.53,119.58 PU01.4
N25903529: length 3.9
  BOTTOM w0.102: 223.04,144.47 222.65,144.47 RV116.1 v2(221.38,144.57)
  BOTTOM w0.109: 223.04,144.47 224.68,144.47 UV6.J1
N25932446: length 4
  BOTTOM w0.102: RV132.1 v2(256.14,108.57)
  BOTTOM w0.109: UV8.J1 256,105 255.6,105.39 255.6,105.43 255.6,105.44 255.6,106 255.57,106.03 255.57,106.37 255.73,106.53 255.73,106.95 RV132.1
N25932452: length 3.6
  TOP w0.102: v1(256.42,94.98) 256.42,93.67 256.74,93.35 v2(256.74,93.29) RV136.1
  BOTTOM w0.102: UV8.J13 v1(256.42,94.98)
N25986828: length 4.9
  BOTTOM w0.102: RV131.1 v2(255.06,110.58)
  BOTTOM w0.109: RV131.1 255.72,112.46 255.72,114.38 256,114.65 UV9.J1
N25986830: length 3.5
  TOP w0.127: 255.2,126.06 255.31,126.06 v2(255.67,126.42) 256.44,127.19 RV135.1
  BOTTOM w0.109: 255.2,126.06 255.56,125.7 255.56,125.14 UV9.J13
N26540304: length 1.9
  TOP w0.089: LV3.3 16.49,96.33 16,96.33 RV500.2 15.62,96.71 RV673.1
N26540312: length 1.9
  TOP w0.089: RV674.1 15.8,98.68 RV501.2 16.8,98.37 17.03,98.37 17.13,98.47 LV4.3
N26540318: length 2.2
  TOP w0.089: RV29.1 16.21,93.8 RV502.2 16.57,93.44 16.86,93.44 16.96,93.54 LV5.3 17.21,93.54 17.36,93.69 RV642.2
N26540324: length 2.3
  TOP w0.089: RV33.1 16.15,91.51 RV503.2 16.52,91.15 16.84,91.15 16.94,91.25 LV6.3 17.36,91.43 RV645.2
N26540332: length 2.3
  TOP w0.089: RV34.1 16.15,90.5 RV503.1 16.51,90.85 16.85,90.85 16.95,90.75 LV6.2 17.36,90.58 RV638.2
N26540338: length 2.2
  TOP w0.089: RV30.1 16.21,92.78 RV502.1 16.56,93.14 16.82,93.14 16.92,93.04 LV5.2 17.36,92.87 RV639.2
N26540344: length 1.9
  TOP w0.089: LV4.2 17.13,97.97 17.03,98.07 16.79,98.07 RV501.1 15.8,97.76 RV28.1
N26540350: length 1.9
  TOP w0.089: RV675.1 15.58,95.7 RV500.1 15.91,96.03 16.47,96.03 LV3.2
N26571966: length 4.1
  BOTTOM w0.102: RV56.1 234.56,89.52 QV3.2 235.03,88.08 v2(234.2,87.25)
N26577826: length 9.3
  BOTTOM w0.102: v2(209.21,84.91) 209.79,85.49 RG573.1 209.82,85.94 RG575.1 211.06,86.76 QG10.2 210.43,87.81 210.43,89.08 212.34,90.98 UV20.4
N26578092: length 5.9
  BOTTOM w0.102: RV572.2 220.92,89.68 220.33,89.09 QV1.2 220.33,88.39 220.06,88.12 220.06,87.36 220.33,87.09 QV1.5 220.33,86.69 219.94,86.3 218.59,86.3 RV571.2
N26699849: length 2.1
  BOTTOM w0.102: v2(38.58,71.84) 38.35,71.61 RT156.1
  BOTTOM w0.203: RT156.1 CT156.2
N26700727: length 3.3
  TOP w0.102: CT157.2 31.82,117.67 RT157.1 31.34,117.19 30.58,117.19 v2(29.83,117.94)
N26701062: length 0.9
  BOTTOM w0.102: CH224.2 RH708.1
N26874760: length 9.1
  BOTTOM w0.254: PRV17.2 PCV03.2 254.1,59.38 254.33,59.61 PRV16.2 254.79,59.38 255.09,59.08 256.44,59.08 256.69,59.34 256.69,59.88 257.05,60.24 v2(257.05,61.84) 257.05,62.1 256.2,62.95 PRV15.1
N26874782: length 2.1
  BOTTOM w0.203: PRV06.1 v2(254.01,65.43) 253.91,65.43 253.7,65.64 PUV101.36
N26874784: length 5.1
  BOTTOM w0.102: v2(243.93,65.54) 244.19,65.8 PRV44.1
  BOTTOM w0.203: PUV101.18 246.17,66.84 PRV43.1 245.07,67.07 PCV16.2 244.65,67.08 PRV44.1
N26874788: length 7.4
  TOP w0.203: v1(244.25,69.92) 245.26,69.92 245.71,69.48 245.71,68.97 v2(246.4,68.28) 246.66,68.02 v1(247.17,68.02)
  BOTTOM w0.203: v1(247.17,68.02) 247.55,67.64 PUV101.20 ; PCV14.2 PRV37.1 244.3,69.98 v1(244.25,69.92) 244.28,69.89 PRV46.1
N26874798: length 3.7
  BOTTOM w0.203: PRV22.1 253.01,70.86 PRV20.1 252.25,70.53 v2(251.56,69.85) 251.38,69.67 PUV101.28
N26874811: length 4.4
  BOTTOM w0.203: PCV07.2 PCV04.2 254.04,69.91 v2(253.67,69.54) 253.24,69.11 252.51,69.11 252.18,68.78 PUV101.30
N26875019: length 11.6
  TOP w0.203: PRV39.2 244.8,67.88 PRV41.2 244.81,66.63 PRV42.2 245.76,66.62 246.34,67.2 v2(247.17,67.2) 247.92,67.2 248.49,67.77 PCV12.2 248.49,69.37 v1(248.66,69.54) 248.49,69.71 PCV13.2 248.31,70.13 PRV36.2
  BOTTOM w0.203: PUV101.22 248.98,68.98 248.66,69.3 v1(248.66,69.54)
N26875029: length 9.4
  TOP w0.203: PRV36.1 v1(246.87,69.89) 246.87,70.57 247.49,71.19 v2(250.39,71.19) 251.15,70.43 251.15,69.56 250.8,69.21 PRV28.2
  BOTTOM w0.203: v1(219.19,72.4) 218.72,72.86 PHV01.1
N26875045: length 2.9
  TOP w0.102: v1(249.92,62.14) v2(249.34,62.14)
  BOTTOM w0.203: PUV101.6 250.18,62.55 249.92,62.29 v1(249.92,62.14) 249.58,61.8 PRV31.2
N26875049: length 2.9
  TOP w0.102: v2(251.23,62.23) 251.13,62.13 v1(250.53,62.13)
  BOTTOM w0.203: PUV101.5 250.58,62.17 v1(250.53,62.13) 250.34,61.94 PRV30.2
N26875053: length 3.8
  TOP w0.102: v1(251.99,61.85) 252.31,62.17 v2(252.73,62.17)
  TOP w0.203: PRV23.1 v1(251.99,61.85)
  BOTTOM w0.203: PUV101.3 251.38,62.72 251.99,62.1 v1(251.99,61.85) PCV09.1
N26875069: length 3.2
  BOTTOM w0.203: PRV33.2 247.83,61.47 247.83,62.02 v2(247.97,62.17) 248.03,62.22 248.79,62.22 249.38,62.8 PUV101.8
N26875073: length 2.4
  BOTTOM w0.203: PUV101.7 249.78,62.66 v2(249.28,62.16) 248.82,61.7 PRV32.2
N26875077: length 2.1
  BOTTOM w0.203: PUV101.4 250.98,62.29 v2(251.1,62.17) PRV29.2
N26875110: length 3.9
  TOP w0.102: v2(252.17,63.36) 252.97,63.36 v1(253.38,62.95)
  BOTTOM w0.203: PUV101.40 252.93,63.4 v1(253.38,62.95) PRV15.2
N26875121: length 5.4
  BOTTOM w0.102: v2(257.86,67.25) 256.02,67.25 PRV09.2
  BOTTOM w0.203: PRV09.2 254.67,67.78 PCV02.2 254.13,67.24 PUV101.32
N26875125: length 5
  BOTTOM w0.102: v2(256.85,69.96) 256.58,69.96 255.49,68.87 PRV14.2
  BOTTOM w0.203: PRV14.2 255.47,68.61 PCV02.1 253.61,67.64 PUV101.31
N26875157: length 5.8
  BOTTOM w0.102: PRV08.1 256.97,64.03 v2(257.43,63.57)
  BOTTOM w0.203: PRV08.1 PRV04.2 256.18,64.67 255.93,64.92 255.17,64.92 PRV03.2 254.19,64.67 253.62,65.24 PUV101.37
N26875247: length 3.5
  TOP w0.102: v1(253.64,63.57) 252.93,64.29 v2(252.93,64.4)
  TOP w0.203: v1(253.64,63.57) 253.64,63.35 PRV13.1
  BOTTOM w0.203: v1(253.64,63.57) 253.64,64.25 253.46,64.44 PUV101.39
N26877105: length 5.1
  BOTTOM w0.254: PRV50.2 213.34,77.98 213.62,78.26 PLV01.3
N26877609:
  vias: v1(213.7,65.04)
N26877615:
  vias: v1(215.29,65.05)
N26877657:
  vias: v1(216.59,65.09)
N26877691:
  vias: v1(225.21,65.06)
N26877733: length 1.1
  BOTTOM w0.102: PRV48.2 v2(215.23,61.81)
N26877795:
  vias: v1(223.89,65.1)
N26877907:
  vias: v1(226.59,65.23)
N26878499:
  vias: v1(235.34,65.06)
N26878505:
  vias: v1(234,65.09)
N26878545: length 1.2
  BOTTOM w0.102: 235.38,62.42 v2(235.38,61.26)
N26878585: length 3.4
  TOP w0.102: PRV57.2 v2(235.06,73.1)
  TOP w0.508: PCV49.1 234.4,70.66 PRV57.2
N26878589: length 5
  BOTTOM w0.254: PLV03.3 235.08,78.23 234.82,77.98 v1(232.21,77.98) PRV58.2
N26891657: length 1.8
  BOTTOM w0.102: v2(256.58,60.53) PRV18.1
  BOTTOM w0.203: PRV18.1 255.55,61.19 PRV19.2
N26891663: length 6.2
  BOTTOM w0.102: v2(242.23,68.4) 243.8,68.4 PRV45.1
  BOTTOM w0.203: PRV45.1 244.36,68.03 PRV40.1 245.11,68.05 PCV15.2 246.77,67.24 PUV101.19
N26891668: length 7.5
  BOTTOM w0.102: v2(254.11,72.82) 253.97,72.67 PCV05.2
  BOTTOM w0.203: PCV04.1 254.82,70.83 PRV21.1 PCV05.2 PRV22.2 253.44,70.29 252.79,70.29 251.78,69.28 PUV101.29
N26891679: length 2.3
  BOTTOM w0.102: v2(257.07,71.71) PRV21.2 255.66,71.71
  BOTTOM w0.203: 255.66,71.71 255.66,70.88 PCV07.1
N26891685: length 2.1
  BOTTOM w0.102: PRV20.2 252.25,72.34 v2(252.74,72.83)
  BOTTOM w0.203: PCV05.1 252.32,71.71 PRV20.2
N26891690: length 5.7
  TOP w0.102: v2(255.89,65.02) 255.34,65.58 PRV05.1
  TOP w0.203: PRV05.1 v1(256.02,66.6)
  BOTTOM w0.203: PUV101.33 254.53,66.84 254.77,66.6 PRV05.1 v1(256.02,66.6)
N26891691: length 3
  TOP w0.102: v2(252.87,65.82) 253.09,66.04 v1(253.98,66.04)
  TOP w0.203: v1(253.98,66.04) 254.03,65.99 PRV01.2
  BOTTOM w0.203: PUV101.35 v1(253.98,66.04)
N26891692: length 3.8
  TOP w0.102: v1(254.64,66.06) 254.64,66.46 v2(254.19,66.9)
  TOP w0.203: v1(254.64,66.06) 254.79,65.91 PRV02.2
  BOTTOM w0.203: PUV101.34 253.61,66.44 253.67,66.5 254.2,66.5 v1(254.64,66.06)
N26891707: length 4.9
  BOTTOM w0.102: v2(251.31,72.81) 251.77,72.35 251.77,71.37 251.31,70.92 PRV24.1
  BOTTOM w0.203: PUV101.27 250.98,70.05 251.31,70.38 PRV24.1
N26891711: length 4.7
  BOTTOM w0.102: PRV25.1 250.06,71.35 250.06,72.63 v2(249.86,72.83)
  BOTTOM w0.203: PUV101.26 250.58,70.83 PRV25.1
N26891716: length 3.6
  BOTTOM w0.203: PRV26.1 PCV10.1 250.18,70.27 v2(250.18,69.86) PUV101.25
N26891720: length 6.1
  BOTTOM w0.102: PRV27.1 247.68,72.43 v2(248.1,72.85)
  BOTTOM w0.203: PUV101.24 249.78,69.85 249.3,70.33 248.29,70.33 248.18,70.43 248.18,71.27 PRV27.1
N26891721: length 9.8
  TOP w0.102: v2(249.62,67.74) 249.4,67.96 PCV12.1
  TOP w0.203: PCV12.1 249.4,69.43 v1(249.29,69.54) 249.4,69.65 PCV13.1 250.17,70.31 PRV28.1
  BOTTOM w0.203: PHV01.2 219.23,73.68 219.23,73.04 v1(219.85,72.41) ; PUV101.23 249.38,69.45 v1(249.29,69.54) 249.29,69.76 249.05,70 248.06,70 247.68,70.38 PRV27.2
N26893030: length 5.2
  BOTTOM w0.254: PLV02.3 224.37,78.37 223.98,77.98 v1(222.1,77.98) PRV54.2
N26893128:
  vias: v1(224.73,62.14)
N26894100:
  vias: v1(236.68,65.07)
N26983473: length 5.6
  BOTTOM w0.102: PQS07.1 24.99,38.76 24.65,38.42 23.47,38.42 23.41,38.48 PRS15.2 22.89,37.44 v2(22.94,37.39)
N26983484: length 6.8
  BOTTOM w0.102: PRS15.1 22.67,39.61 22.67,40.93 22.21,41.39 21.69,41.39 21.22,40.92 PQS06.2 19.08,40.92 PRS10.2 v2(17.89,40.91)
N26985058: length 3.4
  BOTTOM w0.254: UC1.M38 95.35,126.8 95.35,127.45 v1(95.33,127.47) 94.95,127.85 RC15.1 95.02,129.18 RC275.1
N26985064: length 4.3
  BOTTOM w0.254: RC276.1 94.13,129.18 RC16.1 v1(94.21,128.1) 94.21,127.89 94.99,127.11 94.99,126.51 UC1.M37
N27106564: length 5
  BOTTOM w0.102: RC277.2 59.51,121.74 v2(59.74,121.97) 59.74,122.35 60.83,123.44 62.31,123.44 62.63,123.12 UC1.BR33
N27108011: length 1.8
  TOP w0.102: v1(179.01,37.58) 178.68,37.25 T4941.1
  BOTTOM w0.089: UH1.AN40 179.77,36.82 v1(179.01,37.58)
N27125806: length 4
  BOTTOM w0.102: PQ20.2 42.41,123.33 v1(43.05,122.68) PR64.1 PC24.2
N27182711: length 1.9
  TOP w0.102: PRZ47.2 v2(115.68,146.42)
  TOP w0.203: PRZ47.2 114.6,147.27 PCZ25.1
N27238858: length 1.9
  TOP w0.102: PRI04.2 v2(91.44,137.51)
N27238942: length 1.5
  TOP w0.102: PCI27.1 84.35,143.58 v3(84.05,143.28)
N27239057: length 1.3
  TOP w0.102: PCI37.1 v2(76.07,143.42)
N27239175: length 1.2
  TOP w0.102: PCI47.1 v2(67.84,143.43)
N27239423: length 1.3
  TOP w0.102: PCG10.1 v2(59.57,142.5)
N27239504: length 2.3
  TOP w0.102: PRA04.2 100.15,135.48 99.71,135.93 99.17,135.93 v2(98.97,136.13)
N27327907: length 2
  TOP w0.102: 35.41,55.95 35.9,55.95 v2(36.98,54.88)
N27327919: length 2.2
  TOP w0.102: v2(29.82,59.19) 30.09,58.93 PRS45.2
  TOP w0.508: PRS45.2 PRS47.2
N27330630: length 3.8
  TOP w0.102: PRS46.2 36.42,56.81 v2(36.96,56.27)
  TOP w0.508: PRS46.2 36.42,58.57 35.9,59.09 PQS21.1
N27330757: length 3.6
  TOP w0.102: v2(32.53,60.9) 32.53,60.69 31.9,60.06 PRS47.1
  TOP w0.508: PRS47.1 PCS22.1 33.06,59.84 33.51,60.29 PQS21.2
N27396422: length 2.7
  TOP w0.102: v2(219.35,70.67) PCV29.1
  TOP w0.508: PRV49.2 217.15,70.67 PCV29.1
N27396428: length 3.4
  TOP w0.102: PRV53.2 v2(225.17,73.18)
  TOP w0.508: PRV53.2 224.4,70.76 PCV39.1
N27484470: length 2.2
  BOTTOM w0.102: v2(267.89,72.83) 267.89,72.22 266.96,71.29 ; PRW10.2 266.96,71.03
N27522006: length 3.7
  BOTTOM w0.102: v2(161.57,28.52) 162.73,28.52 R82.2 162.89,28.56 Q27.5 162.89,27.37 163,27.26 163.44,27.26 163.54,27.37 Q27.6
N27603868: length 4.7
  TOP w0.102: v1(31.99,90.05) 31.99,90.45 32.02,90.47 32.02,91.73 31.86,91.88 31.86,92.75 32.4,93.28 T65.1
  BOTTOM w0.102: v1(31.99,90.05) UT4.B2
N27604678: length 3.9
  BOTTOM w0.076: 31.17,91.74 31.17,91.34 31.3,91.21 31.3,90.8 31.37,90.73 31.81,90.73 UT4.C2
  BOTTOM w0.102: 31.17,91.74 v2(30.5,92.41) 30.37,92.55 30.37,92.97 RT164.1
N27605266: length 3
  TOP w0.102: v2(29.71,84.12) 29.33,83.75 v1(29.33,83.65)
  BOTTOM w0.102: v1(32.1,87.65) 32.43,87.99 UT4.D7 ; RT165.1 28.52,84.57 28.63,84.46 28.63,83.9 28.88,83.65 v1(29.33,83.65)
N27606921: length 2.9
  BOTTOM w0.102: v2(29.72,78.6) 30.25,79.13 Q29.1 31.8,79.64 RT167.1
N27736039: length 6.4
  BOTTOM w0.102: TC105.1 27.29,106.36 28.83,104.82 29.67,104.82 29.9,105.05 29.9,105.52 29.7,105.72 JWLAN1.6
N27736188: length 3.6
  TOP w0.102: v1(31.56,104.04) 30.94,103.41 TC106.1
  BOTTOM w0.102: v1(31.56,104.04) 32.2,104.68 JWLAN1.16
N27736197: length 1.9
  TOP w0.102: TC107.1 39.51,105.28 v1(39.52,105.27)
  BOTTOM w0.102: JWLAN1.44 39.2,105.59 v1(39.52,105.27)
N27736206: length 3.3
  TOP w0.102: v1(39.62,103.93) 39.51,104.04 TC108.1
  BOTTOM w0.102: JWLAN1.46 39.7,105.69 39.93,105.46 39.93,104.25 v1(39.62,103.93)
N27736215: length 3.2
  TOP w0.102: TC109.1 40.2,103.48 v1(40.2,103.93)
  BOTTOM w0.102: JWLAN1.48 v1(40.2,103.93)
N27736333: length 1.2
  TOP w0.102: RW13.2 33.43,102.77 33.35,102.69 TC110.1
N27933602: length 1.1
  BOTTOM w0.102: PCI46.1 v2(68.84,154.64)
N28152235: length 4.1
  TOP w0.203: PCZ20.2 113.86,145.4 v2(114.67,145.4) 115.09,145.4 v1(115.25,145.55)
  BOTTOM w0.254: PCZ21.2 PRZ41.2 113.76,145.55 114.58,145.55 PRZ42.1 v1(115.25,145.55)
N28152401: length 5.1
  TOP w0.102: PRZ52.2 104.75,152.96 v2(104.75,154.62)
  TOP w0.203: PRZ52.2 v1(105.32,151.76)
  BOTTOM w0.203: PUZ01.15 105.88,151.1 105.32,151.67 v1(105.32,151.76) PRZ52.2
N28152437: length 4.6
  TOP w0.203: v1(103.49,144.99) 104.07,144.99 v2(104.2,145.12) 104.4,145.32 PRZ31.1 104.41,146.09 PCZ16.1
  BOTTOM w0.203: v1(103.49,144.99) 103.49,145.28 104.2,145.98 PUZ01.3
N28152465: length 3.8
  TOP w0.203: PCZ22.1 PRZ44.1 110.73,145.78 v2(111.4,145.78) 111.59,145.78 v1(111.97,146.16)
  BOTTOM w0.203: v1(111.97,146.16) 111.83,146.16 111.61,146.38 PUZ01.36
N28152580: length 8.5
  TOP w0.203: PCZ01.1 PRZ03.1 105.48,140.29 105.14,139.95 103.78,139.95 v2(103.44,140.3) 103.05,140.69 103.05,141.67 PCZ02.2 103.68,142.76 v1(103.98,143.05)
  BOTTOM w0.203: PRZ02.2 103.73,142.81 v1(103.98,143.05)
N28152729: length 3.5
  TOP w0.102: v2(104.93,140.35) 104.6,140.68 v1(104.6,140.78)
  TOP w0.203: PCZ02.1 PCZ03.1 104.6,140.78 v1(104.6,140.78)
  BOTTOM w0.152: PRZ06.1 104.6,141.35 v1(104.6,140.78) 104.39,140.57 PRZ05.2
N28152784: length 4
  TOP w0.102: v1(105.91,151.8) 105.91,151.09 v2(105.99,151)
  TOP w0.203: PRZ53.2 105.91,152.05 v1(105.91,151.8)
  BOTTOM w0.203: PUZ01.16 106.28,151.26 105.91,151.64 v1(105.91,151.8) 105.91,152.06 PCZ32.1
N28152958: length 2.9
  TOP w0.102: v1(115.13,149.94) 115.14,149.94 115.41,149.68 v2(115.41,149.32)
  TOP w0.203: PRZ50.1 114.48,149.95 PRZ49.2 v1(115.13,149.94)
  BOTTOM w0.152: v1(50.9,139.93) 50.92,139.9 PHZ02.2
N28153073: length 2.8
  TOP w0.203: PRZ12.1 107.7,141.04 v2(107.7,140.36) v1(107.09,139.76)
  BOTTOM w0.203: v1(96.93,131.39) 96.83,131.29 PHZ05.2
N28153589: length 2.9
  BOTTOM w0.203: PUZ01.43 109.08,144.12 109.75,143.45 109.75,143.12 109.01,142.38 PRZ19.1
N28153954: length 1.8
  BOTTOM w0.102: PRZ29.2 v2(99.99,147.76)
  BOTTOM w0.203: PRZ29.2 100.95,147 PCZ15.1
N28154016: length 4.3
  TOP w0.102: v1(100.96,144.4) 100.88,144.4 v2(100.52,144.04)
  TOP w0.203: PCZ05.1 101.2,144.16 v1(100.96,144.4)
  BOTTOM w0.152: PCZ04.1 PRZ11.1 101.69,144.4 v1(100.96,144.4) 100.8,144.25 PRZ10.2
N28154283: length 5.3
  TOP w0.152: v1(99.7,146.68) 99.7,147.37 v2(99.9,147.57) 100,147.67 PRZ33.2
  TOP w0.203: PRZ33.2 101.29,148.04 PRZ34.1
  BOTTOM w0.203: PHZ01.2 v1(88.94,133.66)
N28180064: length 0.9
  BOTTOM w0.203: PRZ16.1 105.48,141.49 PCZ10.2
N28185893: length 1.8
  BOTTOM w0.102: v2(115.53,147.26) PCZ23.1
  BOTTOM w0.203: PCZ23.1 114.55,146.4 PRZ45.2
N28185971: length 3.3
  TOP w0.102: v1(100.97,145.08) 99.73,145.08 v2(99.47,144.82)
  TOP w0.203: PCZ14.1 v1(100.97,145.08)
  BOTTOM w0.203: v1(100.97,145.08) 100.92,145.03 PRZ28.2
N28761690: length 3.3
  TOP w0.102: PRB61.1 v3(235.38,44.42)
  TOP w0.508: PRB61.1 235.38,46.7 v1(234.63,47.45)
  vias: v1(228.04,46.98)
N28764708: length 5.8
  TOP w0.102: v2(252.04,56.65) v1(252.04,55.85)
  TOP w0.203: PUB01.3 263.77,54.08 263.7,54.16 v1(262.34,54.16)
  TOP w0.254: v1(252.04,55.85) 252.33,55.57 PRB57.1 ; v1(262.34,54.16) 261.89,54.16 PCB35.1 261.58,53.01 PRB21.1
N28766144: length 10.6
  TOP w0.203: PRB26.1 267.53,56.68 PUB01.27
  TOP w0.254: v1(268.34,56.74) 268.47,56.87 268.47,57.3 PRB26.1 ; PRB59.2 263.67,59.99 v2(264.1,59.56) 264.3,59.36 v1(264.3,58.95)
  BOTTOM w0.254: v1(268.34,56.74) 265.29,56.74 264.3,57.73 v1(264.3,58.95)
N28767446: length 5.5
  TOP w0.102: PRB60.2 271.36,58.17 v2(271.36,58.53)
  TOP w0.203: PUB01.26 267.93,56.01 268.21,56.29 268.59,56.29 268.95,56.64
  TOP w0.254: 268.95,56.64 269.12,56.81 PRB29.2 PRB27.2 270.64,57.44 PRB60.2
N28769298:
  vias: v1(230.5,46.29) v1(230.5,45.65) v1(230.5,45.02) v1(230.5,44.38) v1(231.13,46.92) v1(231.13,46.29) v1(231.13,45.65) v1(231.13,45.02) v1(231.13,44.38) v1(231.45,47.51) v1(231.77,46.92) v1(231.77,46.29) v1(231.77,45.65) v1(231.77,45.02) v1(231.77,44.38) v3(231.53,53.35)
N28789751: length 5.7
  BOTTOM w0.102: v2(268.3,63.87) 267.82,64.35 PRW14.1
  BOTTOM w0.203: PUW01.11 265.34,65.54 265.3,65.51 PCW17.1
  BOTTOM w0.254: PCW17.1 265.52,65.05 PRW19.1 267.12,64.82 PRW14.1
N28823932: length 2.6
  TOP w0.102: UZ16.6 99.97,91.51 v2(100.52,92.06) CZ57.1
N28832867: length 3.1
  TOP w0.203: RL17.1 60.4,43.54 60.4,43.1 v2(59.95,42.65) 59.58,42.28 59.32,42.28 59.01,41.97 UL1.26
N28866414: length 9.3
  TOP w0.508: PRB70.2 268.39,44 v1(267.96,44)
  BOTTOM w0.508: v1(273.99,48.63) 273.99,47.8 270.19,44 v1(267.96,44)
  vias: v2(274.84,49.07)
N28866422: length 2.7
  TOP w0.102: v1(266.24,46.65) 265.86,46.26 v2(265.86,45.96)
  TOP w0.254: PRB03.1 v1(266.24,46.65)
  TOP w0.381: PRB01.3 218.66,32.96 218.21,33.42 v1(218.21,33.48)
N28866424: length 2.3
  TOP w0.203: PRB28.1 266.73,56.26 PUB01.29
N28866425: length 6.3
  TOP w0.102: PRB35.1 263.1,62.58 v2(262.8,62.89)
  TOP w0.254: PRB28.2 265.59,58.92 264.31,60.2 PCB40.1 264.3,60.52 263.97,60.52 263.67,60.83 PRB34.1 PRB35.1
N28866427: length 3.7
  TOP w0.203: PRB33.1 PRB31.1 264.77,56.95 265.01,56.72 265.77,56.72 266.33,56.16 PUB01.30
N28866432: length 3.1
  TOP w0.102: PRB37.1 38.75,39.93 PRB38.2 38.75,40.7 v2(38.55,40.91) 38.08,40.91 37.9,40.73 PDB04.3
N28866460: length 2.9
  TOP w0.254: PRB36.2 259.96,55.82 v2(259.96,56.64) 259.96,56.67 260.36,57.06 v1(260.36,57.24)
  BOTTOM w0.254: PRB12.3 229.64,40.97 v1(230.02,41.35)
N28866498: length 8.8
  TOP w0.102: PDB04.1 34.96,39.58 34.96,37.67 35.41,37.22 PUB02.1 34.75,36.72 34.51,36.97 v2(34.11,36.97) 33.79,36.97 32.85,36.02 PDB05.1
N28866500: length 3.4
  TOP w0.102: PRB42.1 38.58,34.15 37.54,34.15 v2(37.41,34.28) 37.31,34.38 PUB02.4
N28866517: length 4.9
  TOP w0.127: v1(259.72,57.23) v2(259.72,58.15)
  TOP w0.254: PRB32.2 259.85,54.73 259.56,55.02 259.56,57.06 v1(259.72,57.23)
  BOTTOM w0.254: v1(230.02,40.59) 230.4,40.97 PRB12.2
N28866565: length 2.3
  TOP w0.102: PUB02.2 34.55,36.07 PRB41.2 33.86,35.97 v2(33.36,35.47)
N28866567: length 2.4
  TOP w0.102: v2(35.87,37.77) 36.53,38.43 PRB40.2 37.36,39.01 PDB04.2
N28866577: length 1
  TOP w0.254: PRB30.2 267.14,58.7 PCB42.1
N28866586: length 2.6
  TOP w0.102: PCB25.1 263.08,47.45 v2(263.08,46.54)
  TOP w0.254: PCB25.1 264.61,47.78 PRB06.2
N28866613: length 4.4
  TOP w0.102: v1(268.06,46.7) 267.84,46.48 267.84,45.53 267.15,44.83 v2(266.55,44.83)
  TOP w0.254: PRB02.1 v1(268.06,46.7)
  TOP w0.381: v1(218.12,32.73) 218.11,32.73 217.88,32.96 PRB01.2
N28866635: length 3.2
  TOP w0.102: PUB01.21 269.48,53.68 269.57,53.59 v1(270.4,53.59) 270.6,53.59 270.91,53.28 PRB14.2
  BOTTOM w0.102: v2(270.57,54.25) 270.4,54.08 v1(270.4,53.59)
N28866636: length 3.6
  TOP w0.102: PUB01.22 v1(269.79,54.08) 271.31,54.08 PRB16.2
  BOTTOM w0.102: v1(269.79,54.08) v2(269.79,55.33)
N28866639: length 2.5
  TOP w0.203: PUB01.23 269.44,54.48 269.62,54.66 ZTB02.1 270.58,54.93 PRB19.2
N28866700: length 3
  TOP w0.102: v2(30.94,35.47) 30.45,34.98 PDB05.2 PRB44.2
N28866811: length 10.6
  TOP w0.254: PRB45.2 v2(276.44,58.7) 276.44,61.23 276.1,61.57 273.04,61.57 PQB05.2
N28909904: length 2.9
  BOTTOM w0.381: RG50.2 224.36,88.92 224.19,88.76 224.19,87.81 224.46,87.54 QV10.2 QV10.3
N28980130: length 10.5
  TOP w0.102: RE163.1 91.66,25.39 91.23,24.97 v2(88.48,24.97) 88.02,25.42 88.02,26.4 RE90.1 87.33,27.09 87.33,27.61 86.82,28.12 86.42,28.12 85.89,28.65 UE1.88
N29040119: length 9.1
  TOP w0.508: PDB01.2 275.27,52.53 v3(276.24,52.53) 278.87,53.74 280.28,54.02 281.01,54.02 281.39,54.41 PRB67.1 PRB69.1
N29056076: length 3.7
  TOP w0.127: v3(269.15,43.12) PQB10.1
  TOP w0.508: PQB11.2 266.92,41.71 267.75,42.54 PQB10.1
N29169731: length 1
  TOP w0.102: TC111.1 64.01,108.8 v1(63.71,108.5)
  BOTTOM w0.102: v1(63.71,108.5) 63.39,108.18 UC1.BP13
N29212180: length 4.6
  BOTTOM w0.102: UP1.2 23.5,88.5 RP30.2 RP31.1 25.57,89.8 v2(25.57,90.69)
N29536756: length 5.9
  TOP w0.102: UZ7.3 173.09,37.15 172.29,37.95 CZ46.2 171.81,37.95 171.3,37.44 170.92,37.44 170.46,36.98 RZ21.2 168.86,36.98 v2(168.63,37.21)
N29536778: length 3.3
  TOP w0.102: UZ7.6 176.3,37.15 176.52,36.93 176.52,36.39 176.25,36.12 CZ33.2 176.25,35.24 v2(176.81,34.68)
N29634660: length 3.6
  TOP w0.102: UP2.36 25.66,90.67 25.99,90.34 26.89,90.34 v2(27.12,90.11) 27.31,89.92 27.31,89.39 27.54,89.15 RP32.1
N29634710: length 2.7
  TOP w0.102: RP11.1 21.38,99.27 21.58,99.07 21.58,98.82 v4(21.95,98.45) 22.46,97.94 UP2.9
N29634752: length 3.7
  TOP w0.102: v1(27.46,93.18) UP2.40 ; v1(27.55,91.2) 28.41,90.34 v2(28.41,90.27) 28.41,89.06 RP45.1
N30315085: length 1.6
  BOTTOM w0.203: CG64.1 196.06,126.51 v1(196.06,125.86) UG12.12
N30315086: length 1.9
  BOTTOM w0.203: CG65.1 194.77,126.3 v1(194.77,125.88) 195.26,125.38 UG12.10
N30316777: length 2
  BOTTOM w0.102: DG4.2 240.49,90.69 RG506.2 240.49,89.61 240.43,89.56 QG502.4
N30316795: length 6.9
  BOTTOM w0.102: UG22.2 238.29,87.49 238.55,87.75 240.82,87.75 241.73,88.66 QG502.6 241.73,89.37 241.68,89.42 RG516.2 241.8,89.87 242.25,89.42 v2(242.91,89.42)
N30391035: length 0.8
  BOTTOM w0.102: RG554.2 QG502.5
N30391036: length 7.1
  BOTTOM w0.102: UG22.4 237.64,90.65 v2(237.42,90.87) 237.42,91.12 237.92,91.62 240.79,91.62 241.08,91.33 RG554.1
N30391037: length 3.3
  BOTTOM w0.102: RG553.2 241.08,86.38 QG502.2 241.08,87.42 241.76,88.1 v2(242.95,88.1)
N30700583: length 2.9
  BOTTOM w0.127: v2(200.81,95.63) 201.35,95.1 RG543.2
  BOTTOM w0.254: QG505.6 QG505.5 201.83,94.51 201.75,94.59 RG543.2
N30700603: length 4
  BOTTOM w0.102: v2(246.81,85.15) 245.65,86.31 QG506.6
  BOTTOM w0.254: RG513.2 245.65,87.85 QG506.6 QG506.5
N30700625: length 4.4
  BOTTOM w0.127: v2(244.35,83.98) QG506.3
  BOTTOM w0.254: QG506.3 244.35,85.62 243.84,86.13 243.84,87.62 RG514.2
N30700675: length 3.2
  BOTTOM w0.127: RG509.2 196.37,114.03 v2(196.88,113.52)
  BOTTOM w0.254: RG509.2 196.35,114.67 QG503.5 QG503.6
N30700682: length 3
  BOTTOM w0.127: RG510.2 198.1,117.55 v2(198.21,117.66)
  BOTTOM w0.254: RG510.2 197.57,116.62 197,117.19 QG503.3
N30700690: length 2.9
  BOTTOM w0.127: RG511.2 v2(193.54,114.83)
  BOTTOM w0.254: QG504.5 QG504.6 192.61,115.53 192.38,115.3 RG511.2
N30700699: length 2.5
  BOTTOM w0.127: RG512.2 193.92,119.42 v2(193.33,120)
  BOTTOM w0.254: RG512.2 193.91,118.92 QG504.3
N30700734: length 2.4
  BOTTOM w0.127: v2(200.04,91.96) 200.21,92.13 QG505.3
  BOTTOM w0.254: RG544.2 201.18,91.22 QG505.3
N30909781: length 3
  BOTTOM w0.127: v2(198.13,61.33) 197.69,61.77 RH747.2
  BOTTOM w0.254: RH747.2 196.96,61.75 QH10.5 QH10.6
N30909795: length 2.6
  BOTTOM w0.127: RH748.2 v2(194.87,64.51)
  BOTTOM w0.254: RH748.2 194.87,62.88 194.39,62.4 QH10.3
N31133241: length 8.9
  TOP w0.102: UW1.4 25.3,110.23 RW11.2 22.7,110.23 21.73,111.2 v1(21.73,111.49) ; v1(19.94,119.71) v2(20.43,120.2) 21.37,121.14 22.44,121.14 22.61,120.98 Q30.1
N31240142: length 1.3
  TOP w0.254: T4942.1 v1(179.01,51)
  BOTTOM w0.254: UH1.AL10 178.64,51 v1(179.01,51)
N31240160: length 8.2
  BOTTOM w0.102: UH1.AR3 180.57,54.69 180.44,54.81 180.44,56.69 180.86,57.11 181.03,57.11 181.46,57.54 181.46,58.51 181.65,58.7 181.65,60.29 181.66,60.29 181.66,61.46 T4943.1
N31738846: length 2.6
  BOTTOM w0.102: QH8.6 QH8.5 22.9,114.74 RH744.2 v2(23.2,116.09)
N31739459: length 3
  TOP w0.102: v2(21.92,104.95) 22.57,104.3 QH9.5 QH9.6 22.96,103.28 RH745.2
N32320644: length 0.7
  TOP w0.102: v2(267.92,69.47) 267.26,69.47
  vias: v1(267.22,68.93)
N32320879: length 0.7
  TOP w0.102: v1(264.78,65.65) v3(264.06,65.65)
N32320932: length 1.7
  TOP w0.102: v1(267.22,68.12) 267.71,68.12 v2(267.92,67.91)
  TOP w0.381: v1(267.22,68.12) 266.8,67.7 PCW14.2
N32321023: length 2.1
  BOTTOM w0.102: PRW04.2 v2(265.98,80.53)
N32321094: length 1.1
  BOTTOM w0.102: PCW15.2 v2(268.75,71.87)
N32332705: length 1.1
  TOP w0.102: v2(267.64,70.86) 267.18,70.41 v1(267.18,69.91)
N33188643: length 1.6
  TOP w0.254: RA23.2 RA24.1 CA31.1
N35924928: length 2
  TOP w0.102: RV77.2 227.26,116.09 227.69,116.09 228.09,116.48 v2(228.09,116.48)
  BOTTOM w0.109: 227.69,116.09 227.56,116.09 UV1.J27
N35928308: length 4.1
  TOP w0.102: v2(227.08,119.84) 227.92,119 227.92,118.02 RV78.2 227.45,116.96 227.56,116.85
  BOTTOM w0.102: 227.56,116.85 227.86,116.55 UV1.H27
N35950826: length 1.4
  TOP w0.254: 228.43,115.27 228.81,114.89 RV79.2
  BOTTOM w0.254: UV1.H25 228,114.85 228.43,115.27
N36655056: length 3.8
  BOTTOM w0.089: UH1.BE35 185.39,38.79 187.35,38.79 187.56,38.58
  BOTTOM w0.102: 187.56,38.58 187.57,38.58 188.25,37.9 TH148.1
N36697219: length 1.6
  TOP w0.102: v1(173.95,49.14) 174.18,49.14 TH1.1
  BOTTOM w0.089: v1(173.95,49.14) 173.61,49.14 UH1.Y14
N36697221: length 1.6
  TOP w0.102: v1(173.91,48.52) 174.2,48.52 TH2.1
  BOTTOM w0.089: v1(173.91,48.52) 173.87,48.52 173.6,48.79 UH1.Y15
N36697223: length 1.4
  TOP w0.102: TH4.1 171.36,39.47 v1(171.52,39.63)
  BOTTOM w0.089: UH1.U35 171.94,39.21 v1(171.52,39.63)
N36697225: length 1.3
  TOP w0.102: v1(169.99,41.34) 169.82,41.5 TH5.1
  BOTTOM w0.102: UH1.N32 170.04,41.28 v1(169.99,41.34)
N36697227: length 1.3
  TOP w0.102: TH6.1 170.14,40.61 v1(170.56,40.2)
  BOTTOM w0.102: v1(170.56,40.2) 170.81,40.45 UH1.R32
N36697229: length 2.1
  TOP w0.102: v1(176.8,49.11) 176.72,49.11 TH7.1
  BOTTOM w0.089: v1(176.8,49.11) 176.89,49.11 UH1.AH15
N36697231: length 1.2
  TOP w0.102: TH8.1 177.83,49.48 v1(177.75,49.56)
  BOTTOM w0.089: UH1.AH14 v1(177.75,49.56)
N36697247: length 1.3
  TOP w0.102: TH3.1 171.84,38.67 v1(171.57,38.67)
  BOTTOM w0.089: v1(171.57,38.67) 171.9,38.34 UH1.U37
N40598435: length 1.3
  BOTTOM w0.102: PR301.2 v2(210.08,55.68)
N40598500: length 1.1
  BOTTOM w0.508: PR501.2 119.67,52.81 PC507.1
N40598503: length 2.9
  BOTTOM w0.102: v2(213.02,45.21) 212.78,44.97 211.5,44.97 PC315.2
  BOTTOM w0.254: PR306.1 211.13,45.33 PC315.2
N40598539: length 1.2
  BOTTOM w0.203: PR509.1 129.54,53.29 PC517.2
N40598619: length 1.4
  BOTTOM w0.102: v2(134.02,57.52) 133.85,57.69 PR507.2
N40664383: length 2.5
  BOTTOM w0.102: JDIMM1.165 87.32,72.83 TP41.1
N40665360: length 3.1
  TOP w0.102: v1(90.94,60.47) 91.27,60.79 TP42.1
  BOTTOM w0.127: JDIMM2.165 90.32,59.17 90.94,59.79 v1(90.94,60.47)
N40665398: length 3.8
  TOP w0.102: v1(90.07,51.36) 90.07,50.47 TP43.1
  BOTTOM w0.127: v1(90.07,51.36) 89.58,50.87 JDIMM2.162
N41527020: length 2.2
  BOTTOM w0.127: TP40.1 JDIMM1.162
N42077965: length 2.4
  BOTTOM w0.102: PCI16.2 94.51,146.5 95.23,147.22 95.92,147.22 v2(96.18,147.47)
N42077969: length 3
  BOTTOM w0.102: v2(89.45,148.73) 90.44,147.74 90.44,146.54 PRI02.1
N42077993: length 3.9
  TOP w0.102: v1(88.95,146.28) v2(88.27,146.28)
  TOP w0.305: PCI14.2 88.96,146.28 v1(88.95,146.28)
  BOTTOM w0.254: v1(88.95,146.28) PRI01.2 89.64,146.18 90.53,145.28 PUI01.3
N42078421: length 1.8
  BOTTOM w0.102: v2(90.93,147.52) 92.15,146.3 PRI02.2
N42078657: length 1.2
  BOTTOM w0.102: PCI26.1 v2(85.35,154.76)
N42079902: length 1.2
  BOTTOM w0.102: v2(77.36,154.68) 77.1,154.43 PCI36.1
N45824609: length 10.5
  TOP w0.102: v1(32.83,133.29) 32.2,133.29 31.72,132.81 v2(31.72,132.62) 31.72,131.55 PCS03.1 31.31,131.14 PRS05.1 31.31,129.67 31.71,129.27 PUS01.3 ; v1(37.69,125.97) 37.38,126.28 36.57,126.28 PRS03.2 35.28,125.74 PRS01.1
N45824651: length 3.2
  TOP w0.102: PCS02.1 32.35,129.55 PRS04.2 32.36,128.87 PRS06.1 PUS01.2
N45824918: length 14.7
  BOTTOM w0.102: v1(33.69,52.22) 33.72,52.2 PQS04.1 ; PRS11.2 20.63,53.22 28.08,53.22 v2(28.77,53.92) 30.33,55.47 31,55.47 31.96,56.43 v1(32.59,56.43)
N45824994: length 4.3
  TOP w0.102: v1(26.14,41.83) v2(25.41,42.56) 25.12,42.85 PQS05.6
  BOTTOM w0.102: v1(26.14,41.83) 26.14,41.89 25.55,42.48
N47710281: length 2.3
  BOTTOM w0.508: PU2501.4 125.01,61.26 PR2504.2 124.89,61.04 PC2504.1
N47714748: length 2.5
  TOP w0.102: v2(38.28,54.74) 37.15,53.61 PRM01.2
N47719295: length 1.4
  BOTTOM w0.203: PUM01.12 34.75,42.42 34.51,42.67
N47720067: length 5.1
  TOP w0.102: v2(33.88,40.05) 34.44,40.05 35.26,40.87 v1(35.41,40.87)
  BOTTOM w0.102: PUM01.10 36.55,40.86 36.37,40.68 35.6,40.68 v1(35.41,40.87) 35,40.46 35,39.94 PRM06.2
N47887852: length 1.7
  BOTTOM w0.102: v2(205.31,72.43) 205.58,72.16 PR1804.2
N101473793: length 3.1
  TOP w0.102: RV120.1 236.71,143.86 236.1,143.25
  BOTTOM w0.109: UV6.J13 234.85,144.05 235.23,143.67 235.68,143.67 236.1,143.25
N101484120: length 4.4
  BOTTOM w0.102: UV7.J1 217.9,144.05 RV117.1 v2(219.18,143.81)
N101484397: length 5.9
  BOTTOM w0.102: v2(199.76,143.11) RV121.1 203.8,143.11 204.38,143.69 204.94,143.69 UV7.J13
N124752685: length 1.9
  TOP w0.102: v2(80.11,64.26) 80.39,64.53 RD11.1
  TOP w0.254: CD30.2 81.1,64.49 RD11.1
N124753277: length 3.9
  TOP w0.102: RD22.1 CD59.2 89.66,53.01 89.66,50.39 v2(89.9,50.15)
N132121209: length 3
  BOTTOM w0.102: RV595.2 RV594.2 CV903.1 235.69,133.73 v2(236.22,133.2)
N132122697: length 3
  BOTTOM w0.102: v2(210.19,130.37) CV904.1 208.02,130.37 RV597.2 RV596.2
N132123770: length 2.7
  BOTTOM w0.102: v2(240.66,94.92) CV905.1 RV599.2 RV598.2
N132124417: length 2.9
  BOTTOM w0.102: v2(243.1,117.46) CV906.1 RV601.2 RV600.2
N132421462: length 20.1
  BOTTOM w0.102: UV1.R32 221.7,121.05 221.7,123.76 222.2,124.25 222.2,126.62 224.49,128.91 v2(226.42,128.91) 228.2,128.91 229.01,129.72 229.01,132.11 230.55,133.64 RV602.1
N132421465: length 3.3
  TOP w0.102: 215.82,121.05 215.34,121.54 215.34,122.96 RV603.1
  BOTTOM w0.109: 215.82,121.05 215.8,121.05 UV1.AC32
N132618344: length 1.3
  TOP w0.102: 232.5,104.37 232.89,103.98 RV604.1
  BOTTOM w0.17: 232.5,104.37 232.5,104.35 UV1.C12
N133325166: length 2.4
  TOP w0.102: 232.5,110.22 232.5,110.75 RV605.1 231.53,110.84 v2(231.37,110.68)
  BOTTOM w0.17: UV1.C20 232.5,110.25 232.5,110.22
N135624823: length 3
  BOTTOM w0.076: UT4.F1 33.55,91.22 33.52,91.26 33.52,91.8 33.8,92.09 33.8,92.67 33.43,93.04
  BOTTOM w0.102: 33.43,93.04 RT83.2
N135625951: length 3.1
  TOP w0.102: v1(32.44,85.41) 31.8,85.41 v2(31.66,85.55) 31.39,85.81 RT111.1
  BOTTOM w0.076: UT4.D10 32.81,86.23 32.81,85.78 v1(32.44,85.41)
N135629282: length 1.3
  TOP w0.102: v1(33.44,90.01) 33.44,90.49 T62.1
  BOTTOM w0.102: UT4.F4 33.55,89.72 33.44,89.83 v1(33.44,90.01)
N135629285: length 1
  TOP w0.102: v1(34.05,89.97) 34.05,89.8 34.06,89.8 T63.1
  BOTTOM w0.102: UT4.G4 v1(34.05,89.97)
N137678407: length 1.7
  BOTTOM w0.102: RG576.2 203.18,88.07 QG23.2

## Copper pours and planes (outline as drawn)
1.0VS_VGAP_VIN on TOP (solid shape): 205.31,74.02 205.31,72.12 204.86,71.68 203.75,71.68 203.72,71.65 203.72,71.13 203.69,71.1 203.52,71.1 203.5,71.13 203.5,71.65 203.41,71.65 203.41,71.65 202.52,71.65 201.97,72.21 201.97,73.26 202.89,74.19 205.14,74.19
1.0VS_VGAP_VIN on BOTTOM (solid shape): 204.96,74.98 204.96,72.32 204.74,72.1 201.65,72.1 201.57,72.18 201.57,73.53 201.37,73.73 200.68,73.73 200.54,73.88 200.54,74.52 200.65,74.63 202.9,74.63 203.32,75.05 204.88,75.05
1.2V_VIN on TOP (solid shape): 41.74,49.96 41.74,48.49 41.53,48.28 40.72,48.28 40.2,47.77 39.5,47.77 39.49,47.75 39.49,47.22 39.49,47.22 40.04,47.22 40.05,47.21 40.05,47.03 40.04,47.03 39.5,47.03 39.49,47.02 39.49,46.59 39.45,46.56 38.75,46.56 38.62,46.68 38.62,48.78 38.51,48.89 38.51,49.57 38.86,49.92 38.87,49.92 38.96,50.01 41.69,50.01
1.2V_VIN on BOTTOM (solid shape): 37.75,50.27 37.75,49.84 37.93,49.67 40.51,49.67 40.83,49.98 41.66,49.98 41.77,49.88 41.77,48.5 41.64,48.37 41.38,48.37 40.75,47.73 40.75,46.82 40.64,46.71 39.64,46.71 39.14,47.2 38.62,47.2 38.32,47.5 37.52,47.5 37.12,47.9 37.12,50.29 37.73,50.29
1.35VGPUP on TOP (solid shape): 259.21,88.6 259.23,88.58 259.95,88.58 259.96,88.59 259.96,89.13 259.96,89.13 260.41,89.13 260.41,88.61 260.44,88.58 264.06,88.58 264.09,88.6 264.09,89.13 264.55,89.13 264.55,88.6 264.57,88.59 265.28,88.59 265.29,88.6 265.29,89.13 265.75,89.13 265.75,88.59 265.76,88.58 266.48,88.58 266.48,85.74 265.71,84.96 258.47,84.96 257.89,85.55 257.89,88.47 258.01,88.59 258.73,88.59 258.76,88.62 258.76,89.12 258.77,89.13 259.21,89.13
1.35VGPUP on BOTTOM (solid shape): 256.85,89.64 256.87,89.62 256.91,89.58 256.96,89.55 257.01,89.53 257.06,89.52 257.12,89.51 257.17,89.52 257.23,89.53 257.28,89.55 257.32,89.58 257.37,89.62 257.38,89.64 260.35,89.64 260.99,89 263.17,89 263.55,88.62 263.55,85.01 263.37,84.83 258.7,84.83 257.79,83.93 257.79,80.65 257.29,80.15 253.67,80.15 253.14,80.67 253.14,86.69 255.91,86.69 255.91,86.64 255.92,86.58 255.94,86.53 255.96,86.49 255.99,86.44 256.03,86.4 256.07,86.37 256.12,86.34 256.16,86.32 256.22,86.31 256.27,86.31 256.32,86.31 256.38,86.32 256.42,86.34 256.47,86.37 256.51,86.4 256.55,86.44 256.58,86.49 256.6,86.53 256.62,86.58 256.63,86.64 256.63,86.69 256.62,86.74 256.6,86.79 256.58,86.84 256.55,86.89 256.51,86.92 256.47,86.96 256.42,86.98 256.38,87 256.32,87.02 256.27,87.02 256.22,87.02 256.16,87 256.12,86.98 256.07,86.96 256.03,86.92 255.99,86.89 255.96,86.84 255.94,86.79 255.92,86.74 255.91,86.69 253.14,86.69 253.14,87.36 253.14,87.43 253.14,89.46 253.32,89.64
2.5V_VIN on BOTTOM (solid shape): 126.54,63.73 128.02,63.73 128.17,63.57 128.17,60.93 127.94,60.71 127.35,60.71 127.24,60.7 127.24,60.15 127.08,60.15 127.08,60.69 127.06,60.71 126.63,60.71 126.52,60.82 126.52,62.6 125.93,63.18 124.23,63.18 124.05,63.36 124.05,63.76 124.23,63.94 126.33,63.94
3V_SN on TOP (solid shape): 203.98,54.87 203.98,53.38 203.85,53.25 202.49,53.25 202.1,53.64 201.62,53.64 201.43,53.82 201.43,54.63 201.5,54.69 201.7,54.9 202.19,54.9 202.28,54.98 203.87,54.98
3V_VIN on TOP (solid shape): 214.02,56.08 214.02,55.69 214.04,55.67 214.56,55.67 214.56,55.66 214.56,55.48 214.55,55.47 214.02,55.47 214.01,55.45 214.01,54.61 214.56,54.06 214.56,50.91 213.71,50.06 211.85,50.06 210.98,50.93 210.98,56.55 211.4,56.97 213.13,56.97
3V_VIN on BOTTOM (solid shape): 214.13,55.85 214.13,52.82 214.52,52.44 214.52,50.68 214.4,50.57 213.59,50.57 213.46,50.69 213.46,51.17 213.24,51.39 212.45,51.39 212.22,51.16 210.7,51.16 210.64,51.22 210.64,51.98 210.87,52.21 210.87,55.59 211.29,56.01 213.97,56.01
5V_SN on TOP (solid shape): 123.5,47.45 123.5,44.99 123.3,44.79 121.65,44.79 121.44,45 121.44,47.52 121.5,47.58 123.37,47.58
5V_VIN on TOP (solid shape): 124.62,57.91 124.62,56.45 124.76,56.31 124.76,53.06 124.43,52.72 121.79,52.72 121.73,52.79 121.73,53.49 121.75,53.51 122.18,53.51 122.26,53.51 122.28,53.53 122.28,54.03 122.27,54.04 121.75,54.04 121.73,54.06 121.73,54.31 122.27,54.31 122.28,54.32 122.28,54.8 122.27,54.81 122.27,54.83 122.25,54.84 121.76,54.84 121.74,54.86 121.74,55.32 120.96,56.1 120.96,57.07 121.1,57.21 122.72,57.21 122.87,57.35 122.87,57.9 123,58.03 124.51,58.03
5V_VIN on BOTTOM (solid shape): 124.57,57.97 124.57,57.42 124.47,57.32 124.07,57.32 123.93,57.18 123.93,56.84 124.27,56.49 124.27,55.77 124.32,55.72 124.32,54.27 124.23,54.18 123.35,54.18 122.91,53.73 121.15,53.73 121.09,53.79 121.09,57.29 121.34,57.53 122.51,57.53 123.03,58.05 124.49,58.05
+0.6V_DDR_VTT on TOP (solid shape): 41.32,42.12 41.32,41.6 41.33,41.58 43.04,41.58 43.18,41.45 43.18,41.34 42.67,40.83 40.78,40.83 40.69,40.92 40.69,41.55 40.72,41.58 41.11,41.58 41.13,41.61 41.13,42.14 41.3,42.14
+0.6V_DDR_VTT on TOP (solid shape): outline of 214 points within 110.67,51.86 120.27,61.04
+0.6V_DDR_VTT on BOTTOM (solid shape): 114.75,52.65 114.75,52.16 114.33,51.74 113.88,51.74 113.72,51.58 113.72,49.31 113.64,49.23 113.5,49.23 113.43,49.31 113.43,51.54 113.26,51.71 113.26,52.58 113.52,52.84 114.56,52.84
+0.6V_DDR_VTT on BOTTOM (solid shape): 110.74,63.68 110.74,61.9 111.12,61.52 111.78,61.52 111.84,61.5 111.88,61.43 112.09,61.13 112.45,61.17 112.56,61.18 112.61,61.09 112.61,60.57 112.59,60.57 112.59,60.23 112.36,60 112.09,60 112,60.01 111.91,60 110.85,60 110.43,60.42 110.43,60.82 110.43,60.83 110.43,63.68 110.49,63.75 110.68,63.75
+0.6VSP on TOP (solid shape): 40.16,44.8 42,44.8 42.15,44.65 42.15,42.94 42.05,42.69 42.16,42.44 42.16,41.92 41.96,41.72 41.49,41.72 41.46,41.75 41.46,42.26 41.44,42.28 41,42.28 40.99,42.27 40.99,41.74 40.58,41.74 38.85,43.47 38.85,45.2 38.89,45.21 38.98,45.24 39.06,45.3 39.66,45.3
+0.6VSP on BOTTOM (solid shape): 40.22,44.77 41.92,44.77 42.03,44.66 42.03,43.44 41.8,43.21 40.25,43.21 39.54,43.92 38.11,43.92 38.05,43.98 38.05,44.84 38.32,45.12 39.88,45.12
+0.9V_CIO on BOTTOM (solid shape): 25.92,129.51 25.96,129.53 26.01,129.53 26.06,129.49 26.08,129.47 26.22,129.33 26.38,129.33 26.41,129.29 26.44,129.25 26.49,129.22 26.49,129 26.42,128.94 26.4,128.91 26.24,128.75 26.24,127.59 26,127.36 25.66,127.36 25.52,127.5 25.5,127.55 25.47,127.62 25.41,127.67 25.41,127.94 25.52,128.13 25.41,128.32 25.41,128.43 25.86,128.88 25.87,128.89 25.94,129.1 25.87,129.31 25.86,129.33 25.86,129.45
+0.9V_DP on TOP (solid shape): 24.69,130.1 24.82,129.97 25.1,129.97 25.2,129.87 25.2,129.64 25.06,129.5 24.11,129.5 24.07,129.46 23.5,129.46 23.5,129.84 23.6,129.95 24.16,129.95 24.31,130.1 24.31,130.55 24.69,130.55
+0.9V_DP on BOTTOM (solid shape): 25.1,129.94 25.13,129.92 25.22,129.82 25.22,129.65 25.2,129.64 25.1,129.56 25.06,129.43 25.06,129.41 24.97,129.32 23.89,129.32 23.44,129.77 23.44,129.83 23.59,129.99 23.71,129.99 23.86,130.14 23.89,130.17 23.94,130.22 24.02,130.22 24.17,130.07 24.45,130.07 24.64,130.26 24.78,130.26
+0.9V_DP on BOTTOM (solid shape): 26.66,128.23 26.85,128.12 27.08,128.15 27.17,128.21 27.34,128.21 27.39,128.15 27.39,128.09 27.37,128.07 27.23,127.8 27.37,127.53 27.39,127.52 27.39,127.45 27.27,127.3 27.24,127.27 27.23,127.16 27.24,127.1 27.24,127.02 27.38,126.88 27.38,126.78 27.31,126.72 27.17,126.72 27,126.89 26.83,126.89 26.8,126.92 26.75,126.99 26.69,127.03 26.68,127.04 26.36,127.36 26.36,128.18 26.49,128.3 26.61,128.3
+0.9V_LVR_OUT on TOP (solid shape): 23.27,125.3 23.27,125.04 23.12,124.89 22.79,124.89 22.67,124.78 22.67,124.36 22.59,124.28 22.31,124.28 22.07,124.52 22.07,124.55 21.84,124.89 21.44,124.79 20.92,124.79 20.03,123.9 19.36,123.9 19.36,123.9 19.36,125.32 19.52,125.49 23.08,125.49
+0.9V_PCIE on TOP (solid shape): 24.62,126.61 24.61,126.58 24.61,126.44 24.66,126.31 24.66,125.13 24.88,124.91 25.17,124.91 25.23,124.85 25.23,123.01 25.3,122.95 25.81,122.95 25.87,122.88 25.87,122.44 25.81,122.37 24.34,122.37 24.12,122.6 24.12,123.46 24.15,123.53 24.24,123.55 24.67,123.94 24.17,124.23 24.07,124.24 24.03,124.32 24.03,125.05 24.03,125.41 24.03,126.69 24.15,126.82 24.41,126.82
+0.9V_PCIE on BOTTOM (solid shape): 24.78,126.91 24.81,126.85 24.8,126.79 24.64,126.57 24.7,126.3 24.76,126.25 24.82,126.21 24.84,126.2 24.84,125.51 25.36,125 25.41,124.94 25.41,124.17 25.37,124.13 25.33,124.09 25.27,124.09 25.03,124.32 25,124.32 24.88,124.32 24.73,124.47 24.55,124.47 24.39,124.31 24.25,124.31 24.16,124.22 24.08,124.17 24.03,124.11 23.92,124.11 23.89,124.15 23.89,124.31 23.99,124.55 23.89,124.8 23.89,124.96 23.96,125.06 23.99,125.18 23.99,125.25 24.06,125.31 24.11,125.33 24.14,125.36 24.22,125.54 24.13,125.71 24.09,125.73 24.05,125.81 24.08,125.89 24.14,125.96 24.14,126.01 24.22,126.18 24.14,126.35 24.14,126.66 24.2,126.75 24.21,126.85 24.21,126.87 24.24,126.94 24.31,126.97 24.71,126.97
+0.9V_SVR on TOP (solid shape): 15.42,136.26 15.42,132.79 15.11,132.49 12.37,132.49 12.19,132.66 12.19,135.93 12.62,136.36 12.62,136.36 12.69,136.42 15.25,136.42
+0.9V_SVR on TOP (solid shape): 20.79,128.09 21.87,128.09 21.94,128.01 21.94,126.26 21.9,126.21 21.73,126.21 21.64,126.23 21.55,126.21 21.46,126.21 21.42,126.25 21.42,126.44 21.43,126.51 21.42,126.58 21.42,126.69 21.11,127.01 19.51,127.01 19.31,127.21 19.31,127.59 19.17,127.73 19.01,127.89 19.01,128.24 20.64,128.24
+0.9V_SVR on TOP (solid shape): 24.66,129.17 24.66,128.66 24.73,128.6 25.11,128.6 25.17,128.53 25.17,128.15 25.04,128.15 24.96,128.16 24.8,128.15 24.74,128.09 24.53,128.09 24.37,128.16 24.2,128.14 24.17,128.13 24.09,128.22 23.52,128.22 23.39,128.34 23.39,128.6 23.52,128.72 24.03,128.72 24.05,128.75 24.08,128.75 24.08,128.77 24.15,128.85 24.15,129.17 24.28,129.3 24.54,129.3
+0.9V_SVR on BOTTOM (solid shape): 14.38,136.24 14.67,135.95 14.67,132.38 14.49,132.2 12.24,132.2 12.08,132.36 12.08,135.79 12.54,136.24 14.37,136.24
+0.9V_SVR on BOTTOM (solid shape): 24.78,128.88 24.78,128.43 24.7,128.35 24.67,128.36 24.54,128.34 24.44,128.24 24.23,128.24 24.2,128.25 24.18,128.27 24.13,128.32 24.1,128.36 23.99,128.36 23.87,128.36 23.76,128.23 23.66,128.23 23.57,128.25 23.49,128.31 23.46,128.34 23.42,128.34 23.38,128.35 23.27,128.35 23.19,128.43 23.19,128.88 23.25,128.94 24.71,128.94
+0.9V_SVR on BOTTOM (solid shape): 22.08,128.28 22.14,128.21 22.22,128.15 22.25,128.14 22.25,126.15 22.11,126.01 21.87,126.01 21.58,126.3 21.55,126.34 21.51,126.37 21.41,126.48 21.41,126.5 21.29,126.76 21.02,126.84 20.98,126.84 20.96,126.88 20.92,126.97 20.84,127.03 20.81,127.05 20.81,127.26 20.84,127.27 20.97,127.47 20.85,127.68 20.83,127.69 20.83,127.92 20.85,127.93 20.9,127.97 20.94,128.02 20.95,128.04 21.17,128.04 21.19,128.02 21.42,127.9 21.61,128.07 21.61,128.08 21.64,128.11 21.78,128.11 21.82,128.14 21.83,128.14 21.92,128.2 21.99,128.28
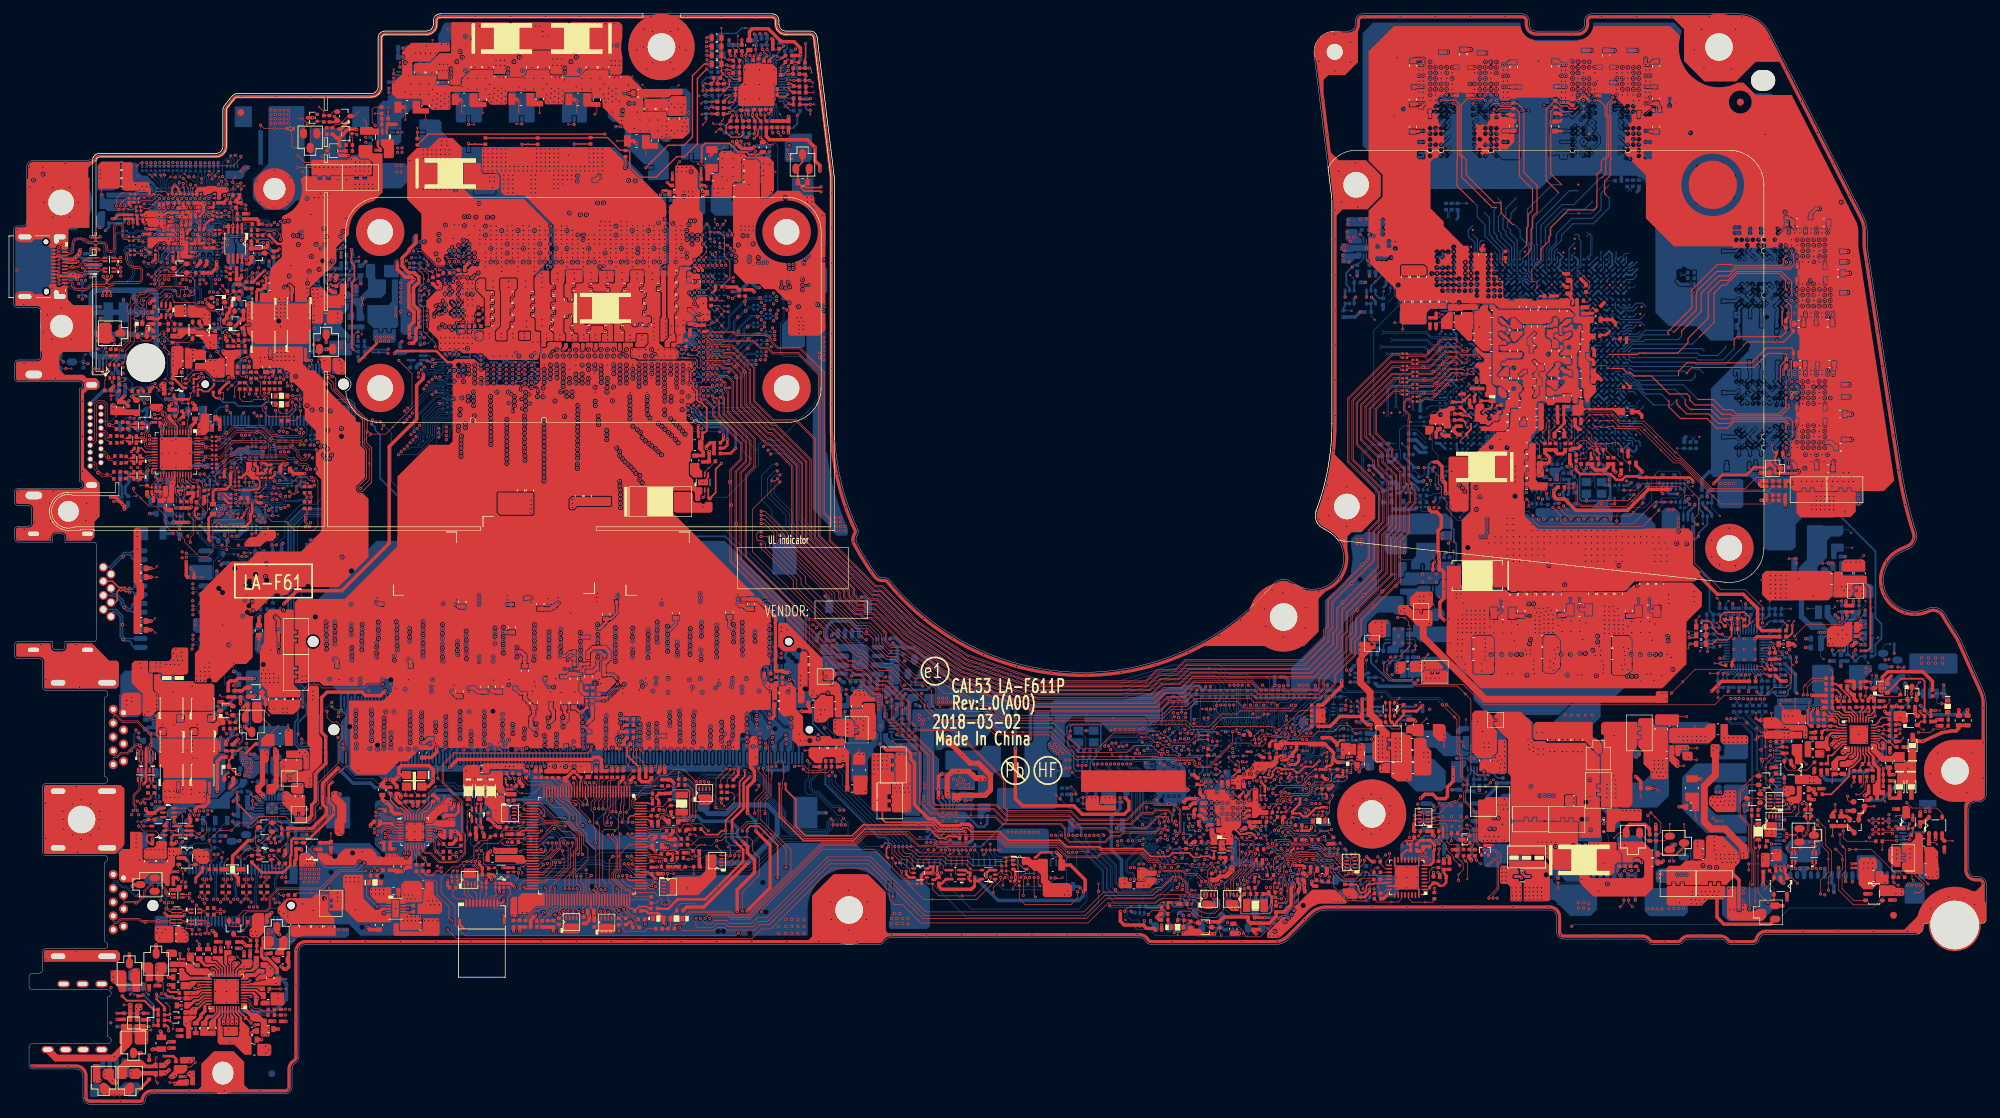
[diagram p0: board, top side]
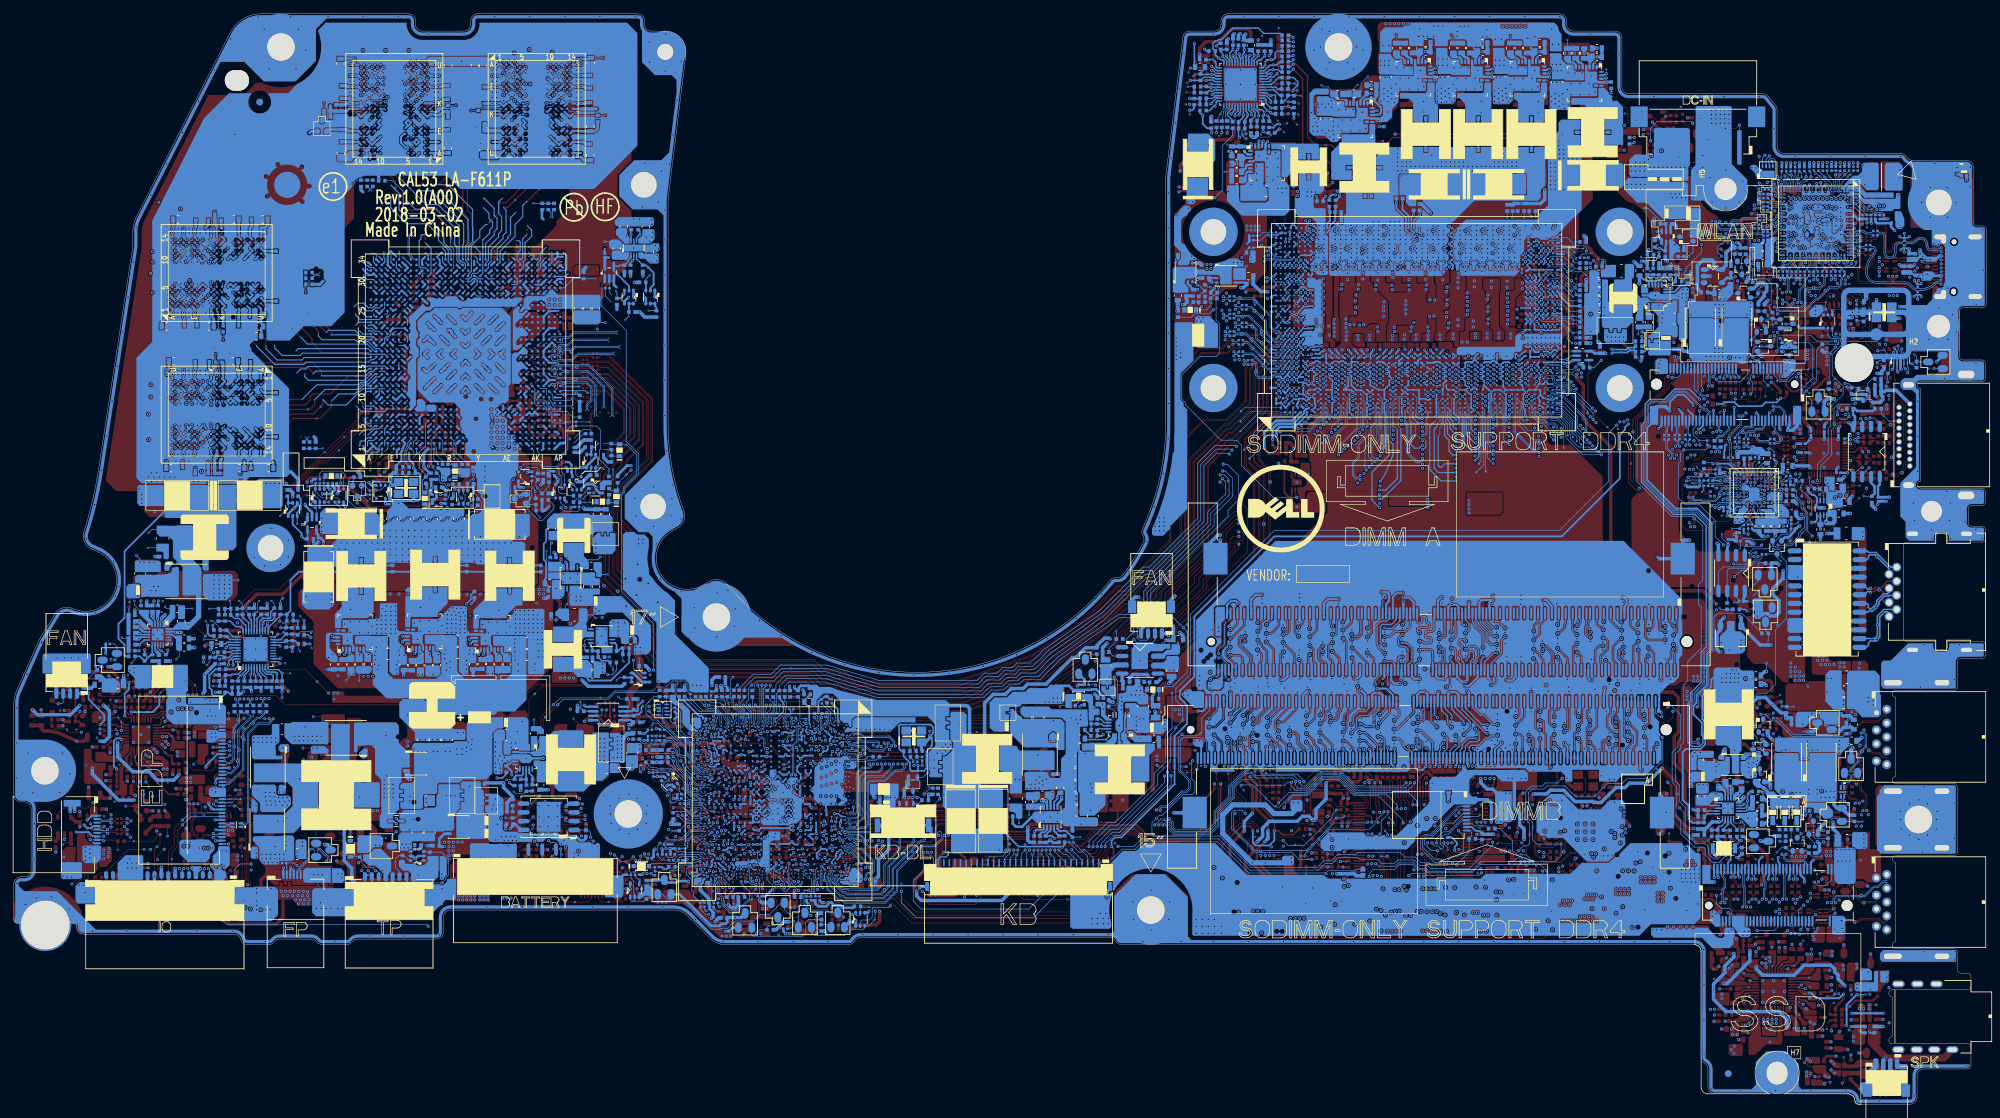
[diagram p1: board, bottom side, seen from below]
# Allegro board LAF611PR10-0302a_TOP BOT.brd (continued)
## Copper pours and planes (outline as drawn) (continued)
+1.0VS_VGAP on BOTTOM (solid shape): 208.23,84.53 208.23,83.58 207.93,83.28 206.41,83.28 205.58,82.46 201.56,82.46 201.19,82.83 200.32,82.83 200.32,82.3 200.08,82.3 200.08,82.85 199.52,82.85 199.52,82.3 199.27,82.3 199.27,82.83 198.76,82.83 198.7,82.88 198.7,84.91 199.09,85.29 201.96,85.29 202.17,85.51 207.26,85.51
+1.2V_DDR on TOP (solid shape): 63.5,74.23 55.5,74.23 55.5,82.23 63.5,82.23
+1.2V_DDR on TOP (solid shape): 83.43,74.49 68.43,74.49 68.43,84.49 83.43,84.49
+1.2V_DDR on TOP (solid shape): 97.14,74.23 89.14,74.23 89.14,82.23 97.14,82.23
+1.2V_DDR on TOP (solid shape): outline of 28013 points within 40.62,47.69 109.53,110.3
+1.2V_DDR on VCC: 49.74,48.08 41.55,56.26 41.55,63.32 97.31,63.32 97.31,51.31 94.08,48.08
+1.2V_RTM on TOP (solid shape): 23.41,91.54 23.41,89.6 23.2,89.39 23.2,87.08 23.17,87.04 22.21,87.04 22.19,87.07 22.19,87.78 22.47,88.06 22.47,89.94 23.11,90.58 23.11,91.6 23.15,91.64 23.31,91.64
+1.2V_RTM on TOP (solid shape): 28.29,99.85 28.29,97.46 27.68,96.85 27.18,96.85 27.11,96.78 27.08,96.81 26.66,96.81 26.56,96.91 26.56,98.4 26.92,98.76 26.92,98.76 27,98.85 27,99.72 27.23,99.95 28.18,99.95
+1.2V_RTM on BOTTOM (solid shape): 23.41,90.68 23.41,89.92 23.04,89.55 22.89,89.55 22.72,89.38 22.72,88.84 22.68,88.8 21.95,88.8 21.92,88.82 21.92,90.74 22.01,90.83 23.27,90.83
+1.2V_RTM_IN on BOTTOM (solid shape): outline of 113 points within 20.26,86.33 23.49,89.83
+1.2V_VCCPLL_OC_OUT on TOP (solid shape): 99.21,92.72 99.21,92.02 99.59,91.64 99.59,90.75 99.53,90.69 98.29,90.69 97.82,91.15 97.82,92.67 97.97,92.81 99.12,92.81
+1.2VP on TOP (solid shape): outline of 263 points within 35.59,58.86 41.47,71.61
+1.2VP on BOTTOM (solid shape): 39.09,46.28 39.09,45.45 38.94,45.3 38.11,45.3 37.86,45.06 37.86,44.01 37.78,43.93 37.71,43.93 37.64,43.99 37.64,45.5 38.56,46.42 38.95,46.42
+1.2VP on BOTTOM (solid shape): outline of 100 points within 33.55,57.69 39.45,63.19
+1.05V_VCCAMPHYPLL on TOP (solid shape): 165.3,32.71 165.3,32.25 164.31,31.25 162.4,31.25 162.33,31.33 162.33,31.98 162.33,31.98 162.33,32.08 162.41,32.15 163.55,32.15 163.73,32.33 163.73,32.56 163.73,32.76 163.78,32.82 165.2,32.82
+1.05V_VCCAMPHYPLL on BOTTOM (solid shape): 165.1,32.35 165.8,32.35 165.8,32.12 165.45,31.77 164.44,31.77 164.25,31.58 163.24,31.58 163.2,31.62 163.2,31.8 163.36,31.96 164.11,31.96 164.14,31.95 164.34,31.95 164.48,32.09 164.57,32.18 164.57,32.25 164.68,32.36 165.05,32.36
+1.05VALW on TOP (solid shape): 161.16,32.76 161.16,32.35 161.34,32.17 161.69,32.17 161.75,32.11 161.75,31.32 161.68,31.26 160.03,31.26 159.82,31.47 159.82,32.68 160,32.86 161.05,32.86
+1.05VALW on BOTTOM (solid shape): 109.47,122.39 110.29,122 111.17,121.79 111.18,121.78 111.85,121.11 111.84,121.08 111.95,120.66 112.39,120.67 112.46,120.69 112.52,120.67 112.84,120.6 113.08,120.81 114.13,120.81 114.5,121.19 117.4,121.19 117.68,120.91 117.68,117.52 117.62,117.46 115.51,117.46 115.43,117.53 115.43,118.23 115.94,118.74 115.94,119.23 115.68,119.49 114.7,119.49 114.16,120.03 111.07,120.03 110.8,119.76 110.8,118.69 110.78,118.67 109.21,118.67 109.17,118.7 109.17,121.02 109,121.19 107.57,121.19 107.43,121.33 107.43,121.98 107.55,122.1 108.02,122.1 108.31,122.39 109.46,122.39
+1.05VALW on BOTTOM (solid shape): 170.52,60.59 170.52,60.07 170.39,59.94 169.87,59.94 169.73,59.8 169.73,58.96 170.03,58.67 170.03,57.73 169.97,57.67 169.28,57.67 169.22,57.74 169.22,58.45 168.22,59.45 166.89,59.45 165.82,58.38 165.82,55.67 165.32,55.17 164.72,55.17 164.57,55.02 164.57,54.76 164.38,54.57 164.24,54.57 164.15,54.66 164.15,55.59 163.61,56.13 154.89,56.13 154.89,56.12 153.21,56.12 152.04,54.96 152.04,51.88 153.03,50.89 153.03,48.36 152.99,48.35 152.77,48.04 152.94,47.71 152.94,47.48 152.77,47.31 151.12,47.31 151.1,47.34 151.1,47.86 151.11,47.87 151.63,47.87 151.65,47.88 151.65,48.59 151.64,48.6 151.11,48.6 151.1,48.61 151.1,49.06 151.11,49.07 151.63,49.07 151.65,49.09 151.65,49.79 151.64,49.8 151.12,49.8 151.1,49.81 151.1,50.38 151,50.48 150.53,50.48 149.58,51.43 149.58,52.27 150.02,52.71 150.02,54.2 150.57,54.2 150.57,54.95 150.02,54.95 150.02,55.39 150.57,55.39 150.57,56.14 150.02,56.14 150.02,58 150.5,58.48 160.44,58.48 160.84,58.6 166.16,59.94 166.19,59.97 167.28,60.4 168.83,60.4 169.15,60.71 170.39,60.71
+1.05VALW on BOTTOM (solid shape): outline of 596 points within 171.02,40.37 177.33,48.44
+1.05VALW on VCC: 159.84,44.02 159.66,44.2 159.66,44.96 157.69,46.94 130.96,46.94 130.96,49.91 122.2,58.67 122.2,62.23 120.86,63.57 110.77,63.57 110.77,89.41 110.13,90.04 110.13,92.71 104.42,98.43 104.42,121.99 109.07,121.99 109.37,121.69 109.37,120.14 105.69,116.46 105.69,101.24 113.31,93.62 113.31,74.7 134.97,53.03 177.32,53.03 177.32,44.78 161.77,44.78 161.01,44.02
+1.05VP on BOTTOM (solid shape): 149.86,56.62 149.86,55.99 150.41,55.99 150.41,55.55 149.86,55.55 149.86,54.79 150.41,54.79 150.41,54.34 149.87,54.34 149.87,52.79 149.45,52.38 149.45,51.36 150.47,50.34 150.95,50.34 150.96,50.33 150.96,49.67 150.97,49.67 151.5,49.67 151.51,49.66 151.51,49.22 151.5,49.21 150.97,49.21 150.96,49.2 150.96,48.47 150.96,48.47 151.51,48.47 151.51,48.46 151.51,48.02 151.5,48.01 150.98,48.01 150.96,48 150.96,43.13 150.58,42.74 142.54,42.74 142.25,43.04 142.25,45.6 142.43,45.78 144.97,45.78 146.2,47.01 146.2,52.01 146.54,52.34 147.24,52.34 147.5,52.6 147.5,56.36 147.93,56.79 149.7,56.79
+1.8V_AVDD on TOP (solid shape): 29.87,14.15 29.87,12.88 29.34,12.35 29.34,12.34 29.26,12.27 29.26,10.92 29.16,10.82 28.33,10.82 28.25,10.9 28.25,11.99 28.37,12.11 28.55,12.11 29.64,13.21 29.64,14.17 29.69,14.22 29.79,14.22
+1.8V_CPVDD on TOP (solid shape): 28.66,14.95 28.66,14.86 28.6,14.8 27.79,14.8 26.52,13.53 26.52,13.1 26.37,12.95 24.57,12.95 24.54,12.98 24.54,13.56 24.6,13.62 25.37,13.62 25.82,14.08 26.68,14.08 27.09,14.49 27.23,14.56 27.31,14.71 27.62,15.02 28.59,15.02
+1.8V_PLLVDD on TOP (solid shape): 208.53,100.91 208.53,100.46 208.42,100.35 207.93,100.35 207.78,100.2 207.78,98.72 207.88,98.62 207.88,97.84 207.82,97.78 206.92,97.78 206.86,97.84 206.86,98.14 206.65,98.34 204.86,98.34 204.79,98.42 204.79,99.1 204.89,99.2 204.89,99.68 205.04,99.83 206.05,99.83 206.05,99.77 206.05,99.72 206.07,99.67 206.09,99.62 206.12,99.58 206.16,99.54 206.2,99.51 206.25,99.48 206.3,99.46 206.35,99.45 206.4,99.44 206.45,99.45 206.51,99.46 206.56,99.48 206.6,99.51 206.64,99.54 206.68,99.58 206.71,99.62 206.73,99.67 206.75,99.72 206.76,99.77 206.76,99.83 206.75,99.88 206.73,99.93 206.71,99.98 206.68,100.02 206.64,100.06 206.6,100.09 206.56,100.12 206.51,100.14 206.45,100.15 206.4,100.16 206.35,100.15 206.3,100.14 206.25,100.12 206.2,100.09 206.16,100.06 206.12,100.02 206.09,99.98 206.07,99.93 206.05,99.88 206.05,99.83 205.04,99.83 205.09,99.88 205.67,99.88 206.45,100.66 207.23,100.66 207.56,100.99 208.45,100.99
+1.8V_PRIM on TOP (solid shape): 205.74,62.78 205.74,62.24 205.75,62.23 206.22,62.23 206.24,62.25 206.25,62.25 206.26,62.27 206.26,62.77 206.28,62.79 207.2,62.79 207.51,62.48 207.51,61.14 207.36,60.99 203.93,60.99 203.75,61.16 203.75,62.41 204.14,62.79 204.92,62.79 204.94,62.78 204.94,62.26 204.96,62.24 205.44,62.24 205.46,62.26 205.46,62.3 205.46,62.3 205.46,62.78 205.48,62.8 205.73,62.8
+1.8V_PRIM on TOP (solid shape): outline of 240 points within 176.07,45.57 184.13,50.62
+1.8V_PRIM on BOTTOM (solid shape): 198.83,123.3 198.83,122.39 198.63,122.19 196.72,122.19 196.33,122.58 196.33,123.22 196.42,123.3 197.31,123.3 197.57,123.56 198.57,123.56
+1.8V_PRIM on BOTTOM (solid shape): outline of 105 points within 184.8,59.56 197.24,82.82
+1.8V_PRIM on VCC: 193.91,80.59 193.91,80.6 193.46,80.6 193.45,80.62 193.35,80.62 192.37,82.51 190.78,83.91 189.86,84.44 189.5,84.88 189.5,85.45 191.27,91.87 191.87,98.5 191.87,122.88 193.68,122.88 199.54,122.88 199.54,83.06 197.08,80.59
+1.8VALW_EC on TOP (solid shape): 73.94,35.76 73.94,35.51 74.07,35.38 74.08,35.38 74.13,35.33 75.9,35.33 75.98,35.25 75.98,35.18 75.9,35.1 74.18,35.1 74.07,34.99 74.06,34.99 73.85,34.79 72.71,34.79 72.49,35 69.72,35 69.6,35.12 69.6,36 69.67,36.07 73.64,36.07
+1.8VALWP on TOP (solid shape): 206.77,63.35 206.77,63.09 206.61,62.92 206.14,62.92 206.13,62.91 206.13,62.38 206.13,62.38 205.88,62.38 205.87,62.38 205.87,62.92 205.86,62.93 205.34,62.93 205.33,62.92 205.33,62.38 205.33,62.38 205.08,62.38 205.07,62.38 205.07,62.91 205.06,62.92 204,62.92 203.61,62.53 202.15,62.53 202.01,62.67 202.01,64.03 202.11,64.13 205.99,64.13
+1.8VALWP on BOTTOM (solid shape): 207.34,64.7 207.34,62.6 207.28,62.54 204.48,62.54 203.75,61.81 202.79,61.81 202.69,61.72 201.72,61.72 201.63,61.81 201.63,63.57 202.36,64.3 203.36,64.3 203.41,64.34 203.5,64.41 203.56,64.5 203.82,64.76 207.28,64.76
+1.24V_PRIM_MAR on BOTTOM (solid shape): 190.44,59.21 190.44,58.41 189.76,57.73 189.41,57.73 188.62,56.95 188.62,55.04 187.6,54.02 187.58,54.01 187.5,53.98 187.43,53.93 187.36,53.9 187.29,53.93 187.01,54.01 186.78,53.84 186.45,53.84 186.38,53.91 186.38,54.03 186.53,54.18 186.62,54.18 187.53,55.1 187.53,57 188.62,58.09 189.03,58.09 189.56,58.62 189.56,59.18 189.66,59.28 190.36,59.28
+1.35VGPU_BOOT1 on BOTTOM (solid shape): 262.81,72.12 262.81,70.95 263.84,69.92 263.84,69.13 263.78,69.07 263.34,69.07 261.96,70.45 261.96,72.13 262.08,72.25 262.67,72.25
+1.35VGPU_BOOT1_1 on BOTTOM (solid shape): 261.61,72.06 261.61,70.29 261.54,70.22 261.47,70.22 261.47,70.22 260.63,70.22 260.58,70.27 260.58,72.12 260.66,72.2 261.47,72.2
+1.35VGPU_EN on BOTTOM (solid shape): 264.77,71.5 264.77,70.18 264.65,70.06 264.65,69.14 264.58,69.07 264.48,69.07 264.42,69.13 264.42,70.08 264.33,70.18 264.33,70.85 264.19,70.99 264.19,71.5 264.21,71.53 264.74,71.53
+1.35VGPU_LGATE1 on BOTTOM (solid shape): 258.06,79.07 258.06,77.44 257.84,77.21 257.23,77.21 257.15,77.29 257.15,78.87 257.48,79.2 257.94,79.2
+1.35VGPU_LGATE1 on BOTTOM (solid shape): 263.43,68.41 263.43,68.33 263.35,68.25 262.26,68.25 262.03,68.02 261.01,68.02 260.88,68.15 260.88,68.4 261.01,68.53 263.32,68.53
+1.35VGPU_PHASE1 on BOTTOM (solid shape): 262.41,68.91 263.34,68.91 263.42,68.83 263.42,68.73 263.35,68.65 260.14,68.65 259.73,69.06 259.73,69.68 259.85,69.8 261.52,69.8
+1.35VGPU_PHASE1 on BOTTOM (solid shape): 264.67,83.68 264.67,82.59 264.23,82.14 262.9,82.14 262.33,81.57 262.33,79.12 260.93,77.72 260.93,73.68 260.9,73.64 258.25,73.64 258.22,73.67 258.22,77.62 259.41,78.81 259.41,83.69 259.43,83.71 264.65,83.71
+1.35VGPU_PSI on BOTTOM (solid shape): 265.61,71.53 265.61,70.52 265.07,69.99 265.05,69.97 265.05,69.14 264.98,69.07 264.89,69.07 264.82,69.14 264.82,70.04 264.97,70.19 264.97,71.47 265.05,71.55 265.58,71.55
+1.35VGPU_PVCC on BOTTOM (solid shape): 263.43,68.01 263.43,67.92 263.37,67.87 262.66,67.87 262.46,67.84 261.91,67.29 261.91,65.8 261.69,65.58 261.11,65.58 261.04,65.66 261.04,67.82 261.06,67.84 262.08,67.84 262.31,68.07 263.37,68.07
+1.35VGPU_TON on BOTTOM (solid shape): 268.11,67.7 268.11,67.14 268.07,67.1 267.16,67.1 266.81,67.46 265.7,67.46 265.62,67.54 265.62,67.61 265.69,67.68 266.52,67.68 266.57,67.73 268.08,67.73
+1.35VGPU_TON_1 on BOTTOM (solid shape): 269.04,67.69 269.04,65.32 268.98,65.27 268.52,65.27 268.46,65.32 268.46,67.69 268.52,67.75 268.99,67.75
+1.35VGPU_UGATE1 on BOTTOM (solid shape): 263.58,78.18 263.58,77.24 263.53,77.19 262.87,77.19 262.81,77.24 262.81,77.67 262.28,78.21 262.28,78.46 262.43,78.61 263.14,78.61
+1.35VGPU_UGATE1 on BOTTOM (solid shape): 264.17,70.5 264.17,70.06 264.24,69.99 264.24,69.12 264.19,69.06 264.11,69.06 264.03,69.14 264.03,69.9 263.98,69.95 263.98,69.95 263.35,70.59 263.35,70.6 263.25,70.7 263.25,70.95 263.39,71.09 263.58,71.09
+1.35VGPU_VIN on TOP (solid shape): 264.8,76.47 268,76.47 268.08,76.39 268.08,75.31 268.02,75.25 266.22,75.25 266.04,75.07 266.04,73.74 265.78,73.48 265.76,73.48 265.59,73.31 263.37,73.31 263.27,73.42 263.27,76.06 263.28,76.07 263.28,76.95 263.41,77.08 264.2,77.08
+1.35VGPU_VIN on BOTTOM (solid shape): 262.53,77.62 262.53,76.91 262.59,76.86 262.92,76.86 263.14,76.63 267.51,76.63 267.77,76.37 267.77,75.57 267.68,75.47 267.28,75.47 266.93,75.13 266.93,73.51 266.85,73.43 263.6,73.43 263.59,73.42 261.72,73.42 261.47,73.68 261.47,77.57 261.57,77.67 262.48,77.67
+1.35VS_VGA on TOP (solid shape): outline of 1041 points within 211.5,137.31 217.09,144.19
+1.35VS_VGA on TOP (solid shape): outline of 17668 points within 195.99,88.72 272.07,156.03
+1.35VS_VGA on BOTTOM (solid shape): 225.32,149.68 225.32,149.6 225.02,149.3 223.69,149.3 223.45,149.05 223.45,148.69 223.74,148.39 225.02,148.39 225.27,148.15 225.27,147.94 225.12,147.79 223.21,147.79 223.09,147.91 220.91,147.91 220.71,147.71 216.99,147.71 216.85,147.84 216.85,149.88 216.99,150.02 218.64,150.02 218.65,150.02 224.98,150.02
+1.35VS_VGA on BOTTOM (solid shape): 213.28,140.39 213.37,140.36 213.39,140.34 213.54,140.16 213.77,140.13 213.81,140.12 213.83,140.07 213.83,140.04 213.76,139.98 213.74,139.98 213.46,139.88 213.37,139.6 213.36,139.56 213.32,139.54 213.18,139.54 212.9,139.26 212.71,139.46 212.62,139.51 212.52,139.54 212.46,139.57 212.43,139.64 212.43,139.68 212.42,139.74 212.46,139.78 212.48,139.78 212.68,139.84 212.81,140.1 212.88,140.12 213.08,140.17 213.21,140.33
+1.35VS_VGA on BOTTOM (solid shape): 261.27,117.58 261.31,117.57 261.33,117.52 261.39,117.32 261.58,117.23 261.65,117.19 261.67,117.12 261.76,116.88 261.99,116.77 262.01,116.77 262.06,116.72 261.97,116.63 261.95,116.63 261.73,116.49 261.68,116.23 261.67,116.19 261.62,116.17 261.58,116.17 261.54,116.19 261.52,116.23 261.47,116.49 261.25,116.63 261.23,116.63 261.05,116.82 260.99,116.89 260.92,116.95 260.91,116.95 260.76,117.1 260.91,117.25 260.92,117.25 260.99,117.31 261.05,117.38 261.05,117.39 261.23,117.57
+1.35VS_VGA on BOTTOM (solid shape): outline of 122 points within 211.8,100.36 228.61,116.94
+1.35VS_VGA on BOTTOM (solid shape): 213.23,149.95 213.32,149.98 213.4,149.92 213.53,149.76 213.74,149.72 213.76,149.72 213.83,149.66 213.83,149.64 213.9,149.46 214.08,149.38 214.14,149.34 214.17,149.27 214.17,149.19 214.11,149.12 214.09,149.12 213.83,148.86 214.08,148.58 214.14,148.54 214.17,148.47 214.17,148.43 214.14,148.36 214.08,148.32 213.91,148.24 213.83,148.07 213.79,148.01 213.72,147.98 213.53,147.93 213.4,147.78 213.39,147.78 213.37,147.75 213.28,147.72 213.2,147.78 213.05,147.94 212.83,147.97 212.79,147.99 212.77,148.03 212.77,148.07 212.79,148.11 212.83,148.13 213.05,148.16 213.2,148.31 213.2,148.32 213.52,148.63 213.61,148.85 213.52,149.07 213.2,149.38 213.2,149.39 213.13,149.48 213.04,149.55 213.02,149.56 212.93,149.58 212.83,149.57 212.79,149.59 212.77,149.63 212.77,149.67 212.79,149.71 212.83,149.73 213.05,149.76 213.2,149.92 213.21,149.93
+1.35VS_VGA on BOTTOM (solid shape): 253.22,104.27 253.29,104.25 253.33,104.18 253.41,104.01 253.58,103.93 253.65,103.89 253.67,103.82 253.77,103.57 254.02,103.47 254.09,103.45 254.13,103.38 254.4,103.13 254.67,103.38 254.71,103.45 254.78,103.47 255.02,103.56 255.13,103.79 255.13,103.81 255.18,103.86 255.27,103.77 255.27,103.75 255.41,103.53 255.67,103.48 255.71,103.46 255.73,103.42 255.73,103.38 255.71,103.34 255.38,103.25 255.27,102.98 255.25,102.91 255.18,102.87 255.01,102.79 254.93,102.62 254.89,102.56 254.82,102.53 254.58,102.44 254.47,102.21 254.47,102.19 254.42,102.14 254.33,102.23 254.33,102.25 254.21,102.46 253.98,102.53 253.91,102.55 253.87,102.62 253.79,102.79 253.62,102.87 253.56,102.91 253.53,102.98 253.43,103.23 253.18,103.33 253.11,103.36 253.07,103.42 253.02,103.56 252.92,103.65 252.91,103.65 252.73,103.83 252.72,103.87 252.74,103.91 252.78,103.93 252.98,103.99 253.11,104.25 253.18,104.27
+1.35VS_VGA on BOTTOM (solid shape): outline of 17203 points within 195.13,89.13 267.61,156.53
+1V8_AON on TOP (solid shape): 221.27,93 221.26,92.98 221.26,91.96 221.39,91.82 221.39,90.91 221.21,90.72 220.56,90.72 220.34,90.94 220.34,93 220.45,93.12 221.15,93.12
+1V8_AON on TOP (solid shape): 227.11,101.87 227.11,101.01 227.23,100.89 227.23,100.89 227.49,100.7 227.79,100.79 228.19,100.79 228.42,100.69 228.66,100.79 229.04,100.79 229.24,100.72 229.44,100.79 229.88,100.79 230.07,100.72 230.27,100.79 230.7,100.79 230.9,100.72 231.1,100.79 231.5,100.79 231.7,100.72 231.9,100.79 232.3,100.79 232.5,100.72 232.7,100.79 232.97,100.79 233.12,100.63 233.12,99.8 233.05,99.72 232.59,99.72 232.5,99.73 232.41,99.72 232.05,99.72 231.37,100.4 227.79,100.4 227.49,100.52 227.22,100.34 227.22,100.34 227.11,100.23 227.11,99.96 226.79,99.64 225.55,99.64 225.47,99.72 225.47,101.03 225.65,101.21 226.35,101.21 226.45,101.31 226.45,101.78 226.61,101.94 227.03,101.94
+1V8_AON on BOTTOM (solid shape): 198.26,126.55 198.26,125.83 196.97,124.54 196.33,124.54 196.3,124.58 196.3,125.53 196.67,125.91 196.67,126.76 196.76,126.85 197.95,126.85
+1V8_AON on BOTTOM (solid shape): 194.99,123.22 194.99,122.58 194.75,122.34 194.03,122.34 193.34,121.65 192.18,121.65 192.04,121.79 192.04,123.03 192.16,123.14 194.16,123.14 194.31,123.29 194.92,123.29
+1V8_AON on BOTTOM (solid shape): 221.33,91.79 221.33,91.38 221.2,91.24 221.09,91.24 220.93,91.07 220.93,90.91 220.7,90.69 219.68,90.69 219.33,91.03 219.33,91.99 219.39,92.04 221.08,92.04
+1V8_AON on BOTTOM (solid shape): 227.02,101.88 227.02,101.02 227.32,100.71 227.32,100.42 227.26,100.36 227.22,100.28 227.21,100.25 225.95,100.25 225.79,100.4 225.79,101.58 226.3,102.09 226.81,102.09
+1V8_AON on BOTTOM (solid shape): 224.22,92.24 224.22,91.92 224.1,91.8 223.92,91.8 223.83,91.71 223.79,91.71 223.79,91.67 223.61,91.49 223.61,91.44 223.56,91.39 223.56,90.24 223.42,90.1 222.79,90.1 222.69,90.2 222.69,90.67 222.17,91.19 222.17,91.98 222.33,92.13 223.64,92.13 223.81,92.31 224.16,92.31
+1V8_MAIN on TOP (solid shape): 205.4,98.1 205.4,97.44 205.4,97.44 205.4,97.37 204.92,96.89 204.23,96.89 204.18,96.94 204.18,98.09 204.28,98.18 205.32,98.18
+1V8_MAIN on TOP (solid shape): 208.89,115.8 209.09,115.72 209.3,115.8 211.66,115.8 211.86,115.59 211.86,115.09 211.73,114.95 211.44,114.95 211.43,114.93 209.65,114.93 209.53,114.81 207.65,114.81 207.49,114.96 207.49,115.7 207.59,115.8
+1V8_MAIN on TOP (solid shape): 212.59,108.7 213.7,108.7 213.75,108.65 213.75,104.28 214.41,103.62 214.41,102.51 214.19,102.29 212.98,102.29 212.81,102.47 212.81,103.01 213.02,103.22 213.02,104 212.82,104.2 212.19,104.2 212.15,104.24 212.15,104.89 212.05,104.99 212.05,106.31 212.05,106.31 211.75,106.61 211.48,106.61 211.38,106.7 211.38,107.02 211.67,107.31 212.5,107.31 212.75,107.56 212.75,107.91 212.5,108.16 212.39,108.16 211.35,109.2 211.35,109.45 211.5,109.6 211.68,109.6
+1V8_MAIN on BOTTOM (solid shape): 225.68,101.09 225.68,100.36 225.53,100.21 224.41,100.21 224.24,100.37 224.24,101.04 224.46,101.26 225.51,101.26
+1V8_MAIN on BOTTOM (solid shape): 194.41,126.52 194.41,125.94 194.42,125.94 194.44,125.73 194.59,125.57 194.59,125.57 194.72,125.44 194.78,125.44 194.98,125.24 194.98,124.58 194.94,124.54 193.28,124.54 192.66,125.16 192.66,126.45 192.86,126.66 194.27,126.66
+1V8_MAIN on BOTTOM (solid shape): 212,109.3 212,109.18 212.38,108.8 212.96,108.8 213.3,108.46 213.3,104.4 213.15,104.25 212.28,104.25 211.87,104.66 211.87,104.89 211.84,104.91 212.3,105.37 212.35,105.37 212.4,105.42 212.4,105.85 211.82,106.44 211.41,106.44 211.23,106.26 211.13,106.26 211.03,106.36 211.03,106.59 211.92,107.48 212.11,107.48 212.61,107.56 212.46,108.04 212.43,108.05 212.43,108.19 212.1,108.52 211.13,108.52 211,108.65 211,109.1 211.49,109.59 211.7,109.59
+1V8_MAIN on BOTTOM (solid shape): outline of 307 points within 200.43,114.62 212.19,117.95
+1VS_GFX on TOP (solid shape): 213.27,115.66 213.27,114.97 213.76,114.47 213.76,109.35 213.36,108.95 212.48,108.95 211.86,109.58 211.82,109.62 211.78,109.65 211.15,110.28 211.15,112.06 211.26,112.17 211.26,112.31 211.27,112.33 211.27,114.56 211.26,114.58 211.26,114.62 211.48,114.85 211.84,114.85 212.13,115.14 212.13,115.31 212.52,115.7 213.23,115.7
+1VS_GFX on BOTTOM (solid shape): 198.7,82.7 199.14,82.7 199.14,82.17 199.65,82.17 199.65,82.7 199.94,82.7 199.94,82.17 200.45,82.17 200.45,82.7 200.87,82.7 201.58,81.99 201.58,79.91 201.25,79.58 198.85,79.58 198.27,80.15 198.27,82.5 198.48,82.7 198.7,82.7
+1VS_GFX on BOTTOM (solid shape): 213.15,114.83 213.15,109.23 213.08,109.17 212.35,109.17 211.81,109.7 211.81,109.89 211.92,110 212.08,110 212.11,109.97 212.14,109.95 212.23,109.86 212.62,109.86 212.67,109.91 212.67,110.39 212.57,110.49 212.57,110.59 212,111.16 211.09,111.16 210.99,111.26 210.99,111.65 211.84,112.5 212.09,112.5 212.19,112.4 212.63,112.4 212.8,112.56 212.8,112.97 212.14,113.63 211.98,113.63 211.67,113.94 211.67,114.07 211,114.73 211,114.86 211.14,115 211.26,115 211.78,114.48 212.15,114.48 212.3,114.63 212.3,114.95 212.13,115.12 212.13,115.35 212.26,115.47 212.5,115.47
+2.5V_MEM on TOP (solid shape): outline of 202 points within 110.58,55.96 119.84,69.67
+2.5V_MEM on BOTTOM (solid shape): 116.39,59.35 116.39,59.17 114.56,57.33 113.31,57.33 113.16,57.48 113.16,59.61 113.32,59.76 114.83,59.76 115.09,60.02 115.72,60.02
+2.5V_MEM on BOTTOM (solid shape): 111.54,71.73 111.54,67.97 111.29,67.72 110.79,67.72 110.64,67.87 110.64,69.58 110.57,69.66 110.57,69.73 110.16,70.14 110.16,71.93 110.23,71.99 111.28,71.99
+2.5VP on TOP (solid shape): 119.03,62.46 119.03,62.02 118.36,61.34 117.23,61.34 117.16,61.41 117.16,61.64 117.17,61.65 117.62,61.65 117.71,61.66 117.72,61.67 117.72,62.11 117.7,62.13 117.16,62.13 117.15,62.14 117.15,63.06 117.32,63.22 118.28,63.22
+2.5VP on BOTTOM (solid shape): 118.6,64.73 118.6,64.36 119.08,63.88 120.63,63.88 120.82,63.69 120.82,63.22 120.62,63.03 119.01,63.03 118.54,62.56 117.15,62.56 116.78,62.93 116.78,64.68 116.95,64.85 118.48,64.85
+3.3V_ANA_PCIE on TOP (solid shape): 23.31,125.82 23.31,125.81 23.41,125.6 23.62,125.5 23.63,125.5 23.71,125.42 23.84,125.42 23.9,125.36 23.9,125.1 23.77,124.98 23.52,124.98 23.39,125.1 23.39,125.35 23.13,125.61 22.54,125.61 22.54,125.61 22.12,125.61 22.01,125.72 22.01,126.07 22.06,126.12 23.01,126.12
+3.3V_ANA_USB2 on TOP (solid shape): 23.33,126.63 23.32,126.6 23.31,126.49 23.33,126.39 23.34,126.36 23.41,126.25 23.52,126.18 23.53,126.17 23.58,126.12 23.84,126.12 23.9,126.06 23.9,125.68 23.84,125.61 23.7,125.61 23.69,125.62 23.63,125.63 23.5,125.69 23.44,125.82 23.43,125.88 23.41,125.91 23.06,126.25 22.77,126.25 22.68,126.34 22.68,126.7 22.73,126.76 23.2,126.76
+3.3V_FLASH on TOP (solid shape): 37.96,82.76 37.96,82.02 37.41,81.47 36.45,81.47 35.68,80.69 33.44,80.69 33.36,80.77 33.36,81.28 34.2,82.12 35.02,82.12 35.8,82.9 35.81,82.9 36.02,83.11 37.61,83.11
+3.3V_FLASH on TOP (solid shape): 34.47,92.88 34.47,92.18 34.33,91.9 34.47,91.62 34.57,91.52 34.92,91.52 34.96,91.47 34.96,90.94 35.04,90.87 35.44,90.87 35.46,90.85 35.46,90.44 35.41,90.39 34.38,90.39 33.61,91.16 33.61,92.93 33.65,92.97 34.38,92.97
+3.3V_LC on TOP (solid shape): 29.37,132.77 30.71,132.77 30.79,132.75 30.86,132.75 30.89,132.75 31.09,132.54 31.09,132.18 30.81,131.9 30.17,131.9 30.01,131.73 30.01,131.01 29.89,130.89 29.59,130.89 29.58,130.89 29.48,130.89 29.42,130.96 29.42,131.99 29.33,132.08 29.23,132.08 29.23,132.08 28.84,132.08 28.49,131.73 28.02,131.73 27.85,131.56 27.85,131.53 27.81,131.49 27.48,131.49 27.41,131.56 27.41,132.01 27.36,132.06 26.76,132.06 26.74,132.04 26.74,131.48 26.65,131.39 26.36,131.39 26.31,131.4 26.21,131.5 26.21,132.28 26.7,132.77 27.84,132.77 27.98,132.9 29.24,132.9
+3.3V_WLAN on TOP (solid shape): 48,107.42 48,105.71 47.87,105.58 46.79,105.58 46.13,106.25 46.13,107.9 46.25,108.02 47.4,108.02
+3.3V_WLAN on TOP (solid shape): 30.53,107.87 30.53,105.38 30.29,105.14 28.86,105.14 27.66,106.34 26.28,106.34 26.21,106.41 26.21,107.17 26.31,107.28 27.54,107.28 28.14,107.88 29.55,107.88 29.68,108.02 30.39,108.02
+3.3V_WLAN on TOP (solid shape): 26.48,115.31 26.52,115.31 26.53,115.3 27.68,115.3 28.51,114.48 28.51,112.92 28.3,112.71 27.6,112.71 27.39,112.91 27.39,113.32 26.9,113.81 25.43,113.81 25.16,114.08 25.16,115.58 25.22,115.64 26.14,115.64
+3.3V_WLAN on BOTTOM (solid shape): 47.87,107.56 47.87,105.83 47.71,105.67 46.11,105.67 46.04,105.74 46.04,107.68 46.25,107.9 47.52,107.9
+3.3V_WLAN on BOTTOM (solid shape): 29.37,107.73 29.37,105.7 29.62,105.45 29.62,105.22 29.54,105.14 28.83,105.14 27.55,106.41 27.55,107.62 27.76,107.82 29.28,107.82
+3V_DVDD on TOP (solid shape): 33.76,14.55 33.76,13.82 34.38,13.19 35.29,13.19 36.09,12.39 36.53,12.39 36.6,12.32 36.6,11.61 37.03,11.18 37.03,9.92 36.89,9.78 35.86,9.78 35.71,9.93 35.71,11.82 35.69,11.84 35.59,11.94 34.61,11.94 34.48,12.05 34.32,12.09 34.29,12.08 34.14,12.24 34.14,12.65 32.87,13.92 32.87,14.58 32.92,14.63 33.68,14.63
+3V_DVDD on TOP (solid shape): 38.64,18.4 38.64,17.24 38.57,17.17 36.45,17.17 34.57,17.17 34.5,17.23 34.11,17.23 34.05,17.17 32.89,17.17 32.84,17.22 32.84,17.37 32.92,17.45 34.02,17.45 34.05,17.48 34.09,17.48 34.13,17.52 34.2,17.53 34.26,17.54 34.61,17.54 34.82,17.75 34.9,17.75 35.53,17.75 35.69,17.91 36.35,17.91 36.68,18.24 37.33,18.24 37.56,18.46 38.58,18.46
+3V_PCH_PRIM on TOP (solid shape): 22.1,104.37 22.1,102.59 22.05,102.54 21.46,102.54 21.41,102.6 21.41,103.45 21.03,103.83 21.03,104.19 21.42,104.57 21.89,104.57
+3V_PCH_PRIM on TOP (solid shape): 24.98,115.54 24.98,114.04 24.86,113.92 23.33,113.92 23.15,114.1 23.15,115.41 23.43,115.68 24.84,115.68
+3V_PCH_PRIM on TOP (solid shape): 177.12,29.38 177.12,28.88 177.28,28.72 177.28,28.1 177.14,27.96 176.12,27.96 175.33,28.75 175.33,29.43 175.43,29.53 176.97,29.53
+3V_PCH_PRIM on TOP (solid shape): 24.28,31.69 24.28,30.9 24.13,30.75 23.28,30.75 23.26,30.77 22.53,30.77 22.45,30.85 22.45,31.17 22.58,31.3 23.41,31.3 23.61,31.5 23.61,31.69 23.67,31.75 24.22,31.75
+3V_PCH_PRIM on TOP (solid shape): 46.93,45.17 46.83,44.9 46.96,44.64 46.96,44.63 48.11,43.49 48.11,40.88 47.84,40.61 47.84,39.2 47.44,38.8 46.81,38.8 46.39,39.22 46.39,41.02 46.76,41.39 46.76,43.16 45.92,44 45.92,45.06 46.18,45.32 46.79,45.32
+3V_PCH_PRIM on TOP (solid shape): 176.61,34.43 176.61,33.69 175.68,32.76 175.68,32.76 175.6,32.69 174.73,32.69 174.6,32.56 174.59,32.56 174.45,32.48 174.37,32.34 174.37,32.33 174.14,32.1 173.05,32.1 173.01,32.15 173.01,32.69 173,32.69 173,32.79 173.03,32.82 173.83,32.82 174.3,33.29 175.16,33.29 175.78,33.91 175.78,34.38 176,34.59 176.44,34.59
+3V_PCH_PRIM on TOP (solid shape): 147.33,35.35 148.04,35.35 148.21,35.52 149.36,35.52 149.44,35.52 149.61,35.35 149.61,32.56 150.17,32 152.68,32 153.08,31.6 153.08,30.15 152.87,29.95 149.16,29.95 148.85,30.25 148.85,31.82 148.58,32.09 148.58,33.22 148.06,33.74 147.54,33.74 147.05,34.24 147.04,34.24 146.65,34.63 146.05,34.63 145.8,34.89 145.8,35.58 146.03,35.81 146.87,35.81
+3V_PCH_PRIM on TOP (solid shape): 184.19,52.47 186.27,52.47 186.44,52.42 186.62,52.47 186.9,52.47 187.05,52.43 187.2,52.47 189.57,52.47 189.68,52.36 189.68,51.82 189.61,51.75 187.38,51.75 187.17,51.96 184.79,51.96 184.73,51.96 183.88,51.96 183.6,51.68 183.6,51.49 183.37,51.26 182.57,51.26 182.27,51.56 182.27,52.22 182.33,52.28 182.43,52.28 182.44,52.27 182.61,52.24 182.77,52.3 182.91,52.3 183.36,52.76 183.49,52.76 183.51,52.77 183.88,52.77
+3V_PCH_PRIM on TOP (solid shape): outline of 868 points within 172.18,37.53 181.53,45.8
+3V_PCH_PRIM on BOTTOM (solid shape): 25.59,114.79 25.59,114.2 25.3,113.91 24.4,113.91 23.53,114.77 23.53,115.35 23.88,115.7 24.69,115.7
+3V_PCH_PRIM on BOTTOM (solid shape): 37.88,25.36 37.88,24.3 38.12,24.06 38.85,24.06 40.34,25.55 42.06,25.55 42.08,25.52 42.41,25.3 42.74,25.52 42.75,25.55 42.99,25.55 43,25.52 43.33,25.29 43.67,25.52 43.68,25.55 43.88,25.55 43.89,25.52 44.22,25.29 44.55,25.52 44.57,25.55 44.89,25.55 44.9,25.52 45.24,25.29 45.57,25.52 45.58,25.55 45.76,25.55 45.77,25.52 46.1,25.3 46.43,25.52 46.44,25.55 48.39,25.55 48.48,25.46 48.48,24.47 48.1,24.09 41.14,24.09 39.82,22.77 39.81,22.77 39.6,22.57 37.16,22.57 36.55,23.18 36.55,24.04 36.39,24.2 36.39,25.2 36.76,25.57 37.67,25.57
+3V_PCH_PRIM on BOTTOM (solid shape): outline of 108 points within 174.44,33.51 181.03,39.46
+3VALW on TOP (solid shape): 66.85,34.03 66.85,32.82 66.75,32.71 65.13,32.71 65.04,32.8 65.04,34.02 65.18,34.16 66.72,34.16
+3VALW on TOP (solid shape): 86.89,25.86 86.89,24.84 86.74,24.69 84.51,24.69 84.48,24.71 84.48,25.73 84.86,26.11 86.64,26.11
+3VALW on TOP (solid shape): 81.88,25.96 81.88,24.91 81.69,24.71 79.49,24.71 79.4,24.8 79.4,25.94 79.6,26.15 81.69,26.15
+3VALW on TOP (solid shape): 101.04,44.58 101.04,43.66 100.71,43.33 99.27,43.33 99.15,43.45 99.15,44.08 98.99,44.24 98.99,44.74 99.09,44.83 100.79,44.83
+3VALW on TOP (solid shape): 239.34,59.67 239.34,58.21 239.19,58.07 237.71,58.07 237.57,58.21 237.57,58.24 237.54,58.27 237.54,59.61 237.71,59.78 239.23,59.78
+3VALW on TOP (solid shape): 43.38,35.71 43.38,35.28 43.71,34.95 43.71,34.52 43.56,34.36 41.35,34.36 41.28,34.44 41.28,35.97 41.7,36.39 41.71,36.39 42.7,36.39
+3VALW on TOP (solid shape): 101.63,36.08 101.63,32.88 98.99,30.25 95,30.25 94.87,30.38 94.87,32.51 95.29,32.93 99.21,32.93 100.07,33.79 100.07,35.93 100.29,36.15 101.55,36.15
+3VALW on TOP (solid shape): 54.61,31.32 54.61,29.03 54.56,28.98 53.96,28.98 53.82,29.12 52.65,29.12 51.47,30.3 51.47,31.18 51.69,31.4 54.53,31.4
+3VALW on TOP (solid shape): 173.7,39.81 173.7,39.33 173.96,39.08 174.34,39.08 174.45,38.97 174.45,38.55 174.12,38.21 174.12,37.65 173.99,37.52 173.22,37.52 173.14,37.61 173.14,38.6 172.97,38.76 172.97,39.82 173.07,39.92 173.6,39.92
+3VALW on TOP (solid shape): 70.23,44.72 70.89,44.72 71.04,44.57 71.04,43.43 71.57,42.9 71.57,41.23 71.51,41.17 71.5,41.17 71.34,41.08 71.25,40.92 71.25,40.91 70.94,40.6 69.98,40.6 69.14,41.44 69.14,42.47 68.17,43.43 68.17,45.03 68.44,45.3 69.65,45.3
+3VALW on TOP (solid shape): 26.47,112.01 27.61,112.01 27.93,111.69 28.15,111.69 28.35,111.49 29.37,111.49 29.44,111.43 29.44,109.39 29.31,109.26 28.13,109.26 27.66,109.73 27.66,110.13 26.38,111.41 24.9,111.41 24.27,110.78 22.82,110.78 22.81,110.78 22.73,110.78 22.64,110.88 22.64,111.44 22.72,111.52 23.54,111.52 23.68,111.66 23.68,112.18 23.79,112.29 26.2,112.29
+3VALW on TOP (solid shape): 196.28,66.37 196.71,66.37 196.71,66.91 197,66.91 197,66.9 197,66.21 195.39,64.6 195.39,64.44 195.34,64.26 195.39,64.08 195.39,63.62 195.26,63.49 194.39,63.49 194.24,63.64 194.24,64.44 194.57,64.77 194.57,65.24 194.57,65.24 194.57,66.72 194.75,66.91 196.28,66.91
+3VALW on TOP (solid shape): 202.36,71.52 203.34,71.52 203.34,71.11 203.38,71.07 203.38,71.01 203.42,70.97 203.8,70.97 203.85,71.02 203.85,71.52 203.87,71.54 204.98,71.54 205.25,71.26 205.25,69.4 205.01,69.16 203.1,69.16 201.44,70.81 200.55,70.81 200.22,71.14 200.22,72.03 200.44,72.25 201.64,72.25
+3VALW on TOP (solid shape): 198.01,55.41 198.01,54.94 199.12,53.83 199.12,53.1 198.6,53.1 198.59,53.09 198.59,52.39 198.6,52.39 198.6,51.89 198.59,51.89 198.59,51.19 198.6,51.18 199.12,51.18 199.12,49.78 198.93,49.59 198.26,49.59 198.08,49.41 197.63,49.41 197.59,49.37 197.17,49.37 196.53,50.01 196.53,52.49 196.55,52.5 196.77,52.77 196.66,53.09 196.63,53.16 196.66,53.23 196.89,53.46 196.96,53.49 197.03,53.46 197.61,53.63 197.2,54.08 197.2,54.13 197.11,54.13 196.86,54.38 196.86,55.19 197.16,55.49 197.93,55.49
+3VALW on BOTTOM (solid shape): 100.66,43.83 100.66,42.76 100.24,42.34 99.14,42.34 98.9,42.58 98.9,43.8 99.13,44.03 100.46,44.03
+3VALW on BOTTOM (solid shape): 101.88,35.7 101.88,34.83 101.59,34.54 100.44,34.54 100.14,34.84 100.14,35.74 100.33,35.93 101.66,35.93
+3VALW on BOTTOM (solid shape): 71.06,44.97 71.06,40.7 70.92,40.56 70.04,40.56 69.77,40.83 68.79,40.83 68.36,41.26 68.36,42.44 68.64,42.72 68.64,45.22 68.69,45.27 70.76,45.27
+3VALW on BOTTOM (solid shape): 29.02,110.26 29.02,110.13 29.31,109.85 29.68,109.85 29.87,109.66 29.87,109.47 29.65,109.25 27.36,109.25 27.28,109.34 27.28,109.72 27.4,109.84 27.92,109.84 28.11,110.03 28.11,110.3 28.34,110.54 28.74,110.54
+3VALW on BOTTOM (solid shape): 126.91,59.99 127.4,59.99 127.4,60.56 127.94,60.56 128.03,60.46 128.03,59.84 127.36,59.16 126.83,59.16 126.3,58.64 126.23,58.64 126.19,58.6 126.06,58.6 125.88,58.77 125.88,60.3 126.14,60.56 126.91,60.56
+3VALW on BOTTOM (solid shape): 13.22,129.17 13.22,127.93 13.13,127.84 13.13,127 12.79,126.66 12.29,126.66 11.82,127.13 11.82,128.11 11.83,128.12 12.01,128.56 12.16,129.01 12.38,129.23 13.17,129.23
+3VALW on BOTTOM (solid shape): 201.08,73.23 201.08,72.35 201.5,71.92 201.5,70.94 201.4,70.83 199.9,70.83 199.59,71.14 197.28,71.14 195.76,69.62 195.76,68.23 195.44,67.91 195.2,67.91 194.95,67.65 194.95,66.71 194.95,66.71 194.95,66.59 195.07,66.47 195.42,66.47 195.63,66.26 195.63,65.19 195.52,65.09 193.72,65.09 193.15,65.66 193.15,68.9 193.18,68.93 193.18,69.27 197.43,73.53 200.78,73.53
+3VALW on BOTTOM (solid shape): 196.14,53.92 196.86,53.92 196.93,53.85 196.92,53.82 197.18,53.38 197.61,53.64 197.62,53.68 197.78,53.68 197.8,53.7 199.09,53.7 199.14,53.65 199.14,53.09 198.59,53.09 198.59,52.39 199.14,52.39 199.14,51.89 198.59,51.89 198.59,51.19 199.13,51.19 199.13,50.65 199.12,50.65 199.12,49.78 198.86,49.51 197.7,49.51 197.56,49.38 197.23,49.38 197.02,49.59 197.02,52.68 196.75,52.95 196.75,52.96 196.67,53.08 196.54,53.16 196.53,53.17 196.4,53.3 195.59,53.3 195.43,53.47 195.43,54.02 195.45,54.04 196.02,54.04
+3VALW on VCC: outline of 97 points within 5.32,19.63 198.53,110.44 ; 2 cut-outs
+3VALW on VCC: 56.92,105.36 56.92,115.77 61.11,115.77 61.11,105.36
+3VALW_EC on TOP (solid shape): 76.8,30.49 76.8,28.73 76.77,28.7 76.02,28.7 76.02,28.7 75.59,28.7 74.37,27.48 73.2,27.48 72.96,27.73 72.96,29.98 73.53,30.55 76.73,30.55
+3VALW_EC on TOP (solid shape): 67.42,48.91 67.42,47.85 67.59,47.69 68.78,47.69 68.97,47.88 68.97,48.06 69.13,48.21 70.62,48.21 70.77,48.06 70.77,46.12 70.99,45.9 70.99,45.35 71.16,45.19 72.68,45.19 72.75,45.12 72.75,44.59 72.68,44.52 71.26,44.52 71.17,44.62 71.17,44.62 70.94,44.84 70.94,44.84 70.9,44.89 70.35,44.89 69.77,45.46 65.3,45.46 64.97,45.79 64.97,48.61 65.49,49.14 67.2,49.14
+3VALW_EC on BOTTOM (solid shape): outline of 483 points within 66.31,36.61 96.31,49.11
+3VALWP on TOP (solid shape): 201.52,53.43 202.04,53.43 202.26,53.21 202.26,46.94 202.03,46.71 200.19,46.71 199.74,47.04 199.26,47.32 199.26,51.26 199.24,51.28 199.24,51.29 199.23,51.29 199.21,51.31 198.73,51.31 198.73,51.79 199.24,51.79 199.24,52.49 198.73,52.49 198.73,52.97 199.24,52.97 199.26,53 199.26,53.3 199.26,53.3 199.26,53.71 199.38,53.82 201.13,53.82
+3VALWP on BOTTOM (solid shape): 201.6,53.72 201.6,52.48 201.61,52.48 201.61,51.18 202.84,49.95 203.79,49.95 203.99,49.88 204.19,49.95 204.42,49.95 204.62,49.88 204.82,49.95 205.43,49.95 207.17,48.2 207.17,45.92 206.51,45.26 206.45,45.25 206.4,45.24 202.89,45.24 202.89,45.25 201.33,46.81 200.18,46.81 199.28,47.71 199.28,51.35 198.72,51.35 198.72,51.76 199.27,51.76 199.27,52.51 198.72,52.51 198.72,52.94 199.28,52.94 199.28,53.76 199.32,53.81 201.51,53.81
+3VLP on BOTTOM (solid shape): 210.15,49.68 210.15,49.02 209.7,48.57 209.7,46.64 209.64,46.58 208.03,46.58 207.95,46.66 207.95,49.55 208.05,49.66 209.17,49.66 209.25,49.74 210.09,49.74
+3VS on TOP (solid shape): 37.62,24.04 37.62,23.07 37.17,22.63 36.13,22.63 35.81,22.95 35.81,24.1 36.02,24.32 37.34,24.32
+3VS on TOP (solid shape): 260.05,47.53 260.92,47.53 261.54,46.91 261.54,46.39 261.46,46.3 257.83,46.3 257.67,46.47 257.67,47.56 257.8,47.7 259.89,47.7
+3VS on TOP (solid shape): 173.19,29.22 173.85,29.22 173.85,28.7 173.69,28.53 173.69,28.5 173.44,28.26 172.47,28.26 172.35,28.37 172.1,28.37 171.92,28.55 171.92,29.38 172.03,29.48 172.93,29.48
+3VS on TOP (solid shape): 25.5,109.34 26.26,109.34 26.38,109.23 27.48,109.23 27.8,108.91 27.8,107.92 27.56,107.68 26.2,107.68 25.84,107.32 25.84,106.69 25.6,106.45 24.88,106.45 24.73,106.6 24.73,109.46 24.75,109.47 25.36,109.47
+3VS on TOP (solid shape): 194.71,49.46 194.71,48.64 194.48,48.41 194.47,48.41 194.39,48.34 194.33,48.26 194.32,48.25 194.09,48.25 193.97,48.36 193.97,49.21 193.96,49.32 193.92,49.43 193.9,49.46 193.96,49.53 194.64,49.53
+3VS on TOP (solid shape): 47.78,30.94 47.78,28.27 47.52,28.01 45.72,28.01 45.64,28.09 45.64,28.4 46.18,28.4 46.18,28.91 45.64,28.91 45.64,29.2 46.18,29.2 46.18,29.71 45.64,29.71 45.64,30.81 45.75,30.91 45.76,30.91 45.89,30.97 45.98,31.06 47.65,31.06
+3VS on TOP (solid shape): 59.11,31.87 59.11,29.34 59,29.23 56.82,29.23 56.57,28.98 55.93,28.98 55.86,29.06 55.86,29.68 55.95,29.77 56,29.88 56.01,29.89 56.03,29.92 56.03,30.29 56.08,30.29 56.08,31.43 56.03,31.43 56.03,31.82 56.54,32.33 58.64,32.33
+3VS on TOP (solid shape): 193.45,52.13 194.13,52.13 194.21,52.05 194.21,50.61 194.1,50.5 193.94,50.5 193.86,50.58 193.36,50.58 193.36,50.59 193.01,50.59 192.93,50.6 192.84,50.59 192.7,50.59 192.56,50.44 192.56,50.04 192.48,49.96 192.05,49.96 191.97,50.04 191.97,52.17 192.08,52.28 193.3,52.28
+3VS on BOTTOM (solid shape): 243.48,33.86 243.48,32.32 243.2,32.04 239.62,32.04 239.5,32.16 239.5,34.11 239.59,34.2 243.15,34.2
+3VS on BOTTOM (solid shape): 196.81,50.35 196.81,48.5 196.57,48.27 195.83,48.27 195.47,48.63 195.15,48.63 195.05,48.73 195.05,49.51 195.05,49.52 195.05,50.43 195.14,50.52 196.63,50.52
+3VS on BOTTOM (solid shape): 22.75,85.77 23.03,85.77 23.17,85.63 23.17,84.76 23.41,84.52 23.41,83.91 23.27,83.77 22,83.77 21.62,84.15 21.62,84.7 22.23,84.7 22.23,84.64 22.23,84.59 22.25,84.54 22.27,84.49 22.3,84.45 22.34,84.41 22.38,84.37 22.43,84.35 22.48,84.33 22.53,84.32 22.58,84.31 22.63,84.32 22.69,84.33 22.74,84.35 22.78,84.37 22.82,84.41 22.86,84.45 22.89,84.49 22.91,84.54 22.93,84.59 22.94,84.64 22.94,84.7 22.93,84.75 22.91,84.8 22.89,84.85 22.86,84.89 22.82,84.93 22.78,84.96 22.74,84.99 22.69,85.01 22.63,85.02 22.58,85.03 22.53,85.02 22.48,85.01 22.43,84.99 22.38,84.96 22.34,84.93 22.3,84.89 22.27,84.85 22.25,84.8 22.23,84.75 22.23,84.7 21.62,84.7 21.62,85.9 21.71,86 22.53,86
+3VS on VCC: 44.6,29.16 44.6,35.43 44.4,35.63 32.36,35.63 30.07,33.35 24.72,33.35 23.52,34.54 23.52,43.33 35.59,55.39 35.59,57.53 33.93,59.18 33.93,62.89 35.59,64.54 35.59,77.37 38.89,80.67 38.89,110.11 38.31,110.69 28.29,110.69 27.46,109.86 27.46,107.57 27.15,107.26 24.66,107.26 24.66,122.25 43.33,122.25 43.33,117.09 41.55,115.32 41.55,80.26 37.74,76.45 37.74,73.68 39.52,71.9 39.52,70.87 37.74,69.09 37.74,63.01 38.38,62.38 38.38,60.07 37.74,59.44 37.74,55.12 25.55,42.93 25.55,35.25 28.78,35.25 32.59,39.06 45.95,39.06 47.14,37.87 47.14,31.57 47.9,31.57 47.9,29.21 47.85,29.16
+3VS on VCC: 171.78,28.27 171.02,29.03 133.05,29.03 127.84,34.24 114.78,34.24 109.83,29.28 57,29.28 56.41,28.7 56.41,31.95 68.15,31.95 68.91,32.71 69.32,32.71 69.82,32.21 106.89,32.21 113.74,39.06 132.05,39.06 137.64,33.48 178.26,33.48 182.96,38.17 196.29,38.17 198.78,40.66 198.78,55.19 200.51,55.19 201.4,54.3 202.54,54.3 211.17,45.67 217.25,45.67 218.9,47.32 234.98,47.32 234.98,43.33 235.05,43.25 254.91,43.25 254.91,65.61 272.31,65.61 272.31,38.74 266.42,32.84 226.77,32.84 220.68,38.94 207.87,38.94 203.17,34.24 185.14,34.24 180.06,29.16 175.11,29.16 174.22,28.27
+3VS_CAM on TOP (solid shape): 258.66,46.05 258.66,45.87 258.64,45.84 258.64,45.69 258.63,45.69 258.62,45.56 258.66,45.43 258.66,45.42 258.66,44.6 258.62,44.56 258.62,44.24 258.66,44.2 258.66,43.97 258.19,43.51 257.56,43.51 257.36,43.31 257.01,43.31 256.84,43.47 256.84,43.71 256.67,43.87 256.49,43.87 256.44,43.92 256.44,44.35 256.46,44.36 256.84,44.36 257.01,44.53 257.7,44.53 257.93,44.76 257.93,46.01 258,46.09 258.62,46.09
+3VS_SSD on TOP (solid shape): 23.11,25.62 23.11,23.55 22.91,23.36 20.85,23.36 20.37,23.84 20.37,25.64 20.55,25.82 22.91,25.82
+3VS_SSD on TOP (solid shape): 36.22,27.5 36.22,24.91 35.42,24.1 34.77,24.1 34.77,24.1 34.62,24.1 34.62,24.1 34.4,24.1 34.12,24.39 34.12,25.28 34.4,25.56 34.4,27.21 34.85,27.66 36.07,27.66
+3VS_SSD on TOP (solid shape): outline of 130 points within 38.16,26.07 46.36,30.37
+3VS_SSD on BOTTOM (solid shape): 22.3,27.16 22.3,24.79 22.05,24.55 20.52,24.55 20.39,24.68 20.39,27.01 20.64,27.27 22.18,27.27
+3VS_SSD on BOTTOM (solid shape): 39.78,28.03 39.93,27.88 39.93,26.44 39.17,25.68 38.56,25.68 38.46,25.78 38.46,27.32 39.18,28.05 39.74,28.05
+3VS_SSD on BOTTOM (solid shape): 36.78,27.19 36.78,25.77 35.98,24.97 35.98,24.66 35.52,24.21 34.37,24.21 34.1,24.47 34.1,25.3 34.38,25.58 34.58,25.58 34.62,25.57 34.78,25.58 34.96,25.75 34.96,27.18 35.08,27.29 36.67,27.29
+3VS_TBT on BOTTOM (solid shape): 19.78,132.1 19.78,131.96 19.97,131.77 20.08,131.77 20.17,131.68 20.17,131.58 20.15,131.56 20.15,131.46 20.09,131.4 19.2,131.4 19.19,131.43 18.76,131.61 18.51,131.21 18.52,131.19 17.6,130.27 17.11,130.27 17.09,130.28 16.81,130.28 16.62,130.08 16.61,130.07 16.24,129.7 16.16,129.67 16.09,129.71 15.99,129.79 15.87,129.83 15.8,129.87 15.78,129.95 15.61,130.34 15.19,130.29 15.13,130.26 15.06,130.28 14.49,129.97 15.1,129.74 15.16,129.77 15.23,129.75 15.3,129.7 15.38,129.68 15.45,129.64 15.47,129.56 15.46,129.47 15.47,129.38 15.46,129.29 15.37,129.25 13.58,129.25 13.29,129.54 12.48,129.54 12.41,129.61 12.41,130.9 12.41,131.72 12.52,131.84 13.03,131.84 13.08,131.79 13.08,131.16 13.2,131.04 17.65,131.04 18.53,131.92 19.09,131.92 19.35,132.18 19.71,132.18
+5V_AVDD on TOP (solid shape): 25.04,20.37 25.55,20.37 26.27,19.66 28.09,19.66 28.45,19.3 28.47,19.29 28.67,19.23 28.88,19.29 28.89,19.3 29,19.3 29.06,19.24 29.06,18.44 29.02,18.4 28.71,18.4 28.44,18.67 25.52,18.67 24.9,19.3 24.9,19.65 24.68,19.86 22.66,19.86 22.56,19.96 22.56,20.54 22.67,20.65 24.76,20.65
+5V_HDD on TOP (solid shape): 276.23,38.88 276.23,33.39 276.15,33.31 273.85,33.31 273.18,33.98 273.18,34.98 273.72,34.98 273.72,35.53 273.18,35.53 273.18,35.77 273.72,35.77 273.72,36.34 273.18,36.34 273.18,37.81 273.25,37.88 274.49,37.88 275.06,38.45 275.06,39.2 275.16,39.3 275.8,39.3
+5V_HDD on BOTTOM (solid shape): 275.41,37.25 275.41,35.32 274.98,34.88 273.3,34.88 272.76,35.43 272.76,37.33 272.85,37.42 275.23,37.42
+5V_KB_BL on TOP (solid shape): 159.49,44.5 159.49,43.56 159.36,43.43 157.26,43.43 157.17,43.53 157.17,44.5 157.33,44.66 159.33,44.66
+5V_KB_BL on BOTTOM (solid shape): 159.49,45.73 159.49,43.29 159.22,43.02 157.87,43.02 157.77,43.12 157.77,44 157.34,44.42 157.34,46.29 157.44,46.39 158.83,46.39
+5V_PVDD on TOP (solid shape): 30.28,14.14 30.28,12.75 29.95,12.42 29.95,11.45 30.23,11.17 30.23,9.85 30.35,9.73 32.36,9.73 32.64,10.01 32.64,12.62 32.06,13.21 32.06,14.16 32.11,14.22 32.19,14.22 32.26,14.15 32.26,13.36 33.05,12.57 33.05,12.09 34.06,11.07 34.06,9.98 34.38,9.66 34.38,7.21 34.33,7.16 33.35,7.16 31.9,8.61 29.77,8.61 29.46,8.91 29.46,12.29 30.04,12.87 30.04,14.14 30.12,14.22 30.19,14.22
+5VALW on TOP (solid shape): 272.35,31.32 273.3,31.32 273.51,31.11 273.51,30.32 273.31,30.11 269.98,30.11 269.84,30.26 269.84,31.51 270.02,31.69 271.98,31.69
+5VALW on TOP (solid shape): 28.3,36.34 28.3,35.13 27.94,34.77 26.85,34.77 26.74,34.88 26.67,34.97 26.58,35.04 25.86,35.76 25.86,36.75 26.06,36.96 27.69,36.96
+5VALW on TOP (solid shape): 127.41,50.58 127.41,50.05 126.91,50.05 126.91,49.35 127.41,49.35 127.41,48.85 126.91,48.85 126.91,48.15 127.41,48.15 127.41,46.84 126.91,46.34 126.91,44.84 126.41,44.84 126.41,44.14 126.92,44.14 126.92,43.64 126.41,43.64 126.41,42.94 126.92,42.94 126.92,42.42 126.87,42.37 124.38,42.37 124.08,42.67 124.08,50.57 124.34,50.84 127.15,50.84
+5VALW on TOP (solid shape): 50.57,33.09 50.57,29.78 52.17,28.18 52.23,28.12 52.83,28.12 53.18,28.46 53.69,28.46 53.73,28.41 54.5,28.41 54.59,28.33 54.59,28.22 54.54,28.17 53.82,28.17 53.64,27.99 53.61,28 53.25,27.44 53.9,27.6 54.52,27.6 54.59,27.53 54.59,26.47 54.43,26.31 49.73,26.31 47.9,28.14 47.91,28.22 47.91,30.99 47.9,31.11 47.63,31.39 47.63,32.97 47.88,33.22 50.44,33.22
+5VALW on BOTTOM (solid shape): 32.66,86.07 32.66,85.85 32.58,85.76 32.21,85.76 31.98,85.53 31.98,84.88 32.08,84.77 33.33,84.77 33.4,84.7 33.4,83.5 33.33,83.43 29.91,83.43 29.73,83.61 29.73,83.83 29.55,84.02 29.05,84.02 28.87,84.02 28.85,84.03 28.85,84.68 28.95,84.77 30,84.77 30.53,85.3 30.53,85.57 30.95,85.98 30.96,86.04 30.96,86.09 31.01,86.14 32.6,86.14
+5VALW on VCC: outline of 139 points within 25.81,31.82 234.98,152.6
+5VALWP on TOP (solid shape): 129.31,50.5 129.31,49.66 129.68,49.29 129.68,49.27 129.85,49.11 129.85,42.39 129.69,42.24 127.2,42.24 127.05,42.39 127.05,43.04 127.05,43.04 127.05,43.54 127.05,43.54 127.05,44.24 127.05,44.24 127.05,44.74 127.05,44.74 127.05,45.52 127.05,45.52 127.05,45.67 127.06,45.67 127.06,46.25 127.53,46.72 127.53,47.47 127.56,47.47 127.56,48.25 127.53,48.25 127.53,48.75 127.56,48.75 127.56,49.45 127.53,49.45 127.53,49.95 127.56,49.95 127.56,50.78 127.66,50.87 128.94,50.87
+5VALWP on BOTTOM (solid shape): 131.38,50.81 131.38,45.25 131.17,45.03 131.17,41.81 131.09,41.73 128.98,41.73 127.42,43.29 127.42,44.73 127.01,45.14 127.01,50.26 127.79,51.04 131.16,51.04
+5VS on TOP (solid shape): 37.26,8.45 37.26,7.27 36.96,6.97 35.4,6.97 35.22,7.14 35.22,8.6 35.37,8.74 36.97,8.74
+5VS on TOP (solid shape): 254.04,36.25 254.04,34.42 253.89,34.27 252.84,34.27 252.77,34.34 252.77,36.28 252.87,36.38 253.9,36.38
+5VS on TOP (solid shape): 23.6,22.14 23.6,21.39 23.54,21.33 22.7,21.33 22.59,21.23 22.17,21.23 22.03,21.37 22.03,22.19 22.23,22.4 23.34,22.4
+5VS on TOP (solid shape): 21.59,101.17 21.59,100.68 21.26,100.35 21.26,100.35 21.11,100.2 20.64,100.2 20.46,100.38 19.92,100.38 19.63,100.66 19.63,101.08 19.89,101.34 21.42,101.34
+5VS on TOP (solid shape): 56.73,27.58 57.05,27.58 57.25,27.38 58.83,27.38 58.95,27.25 58.95,25.47 58.67,25.2 55.93,25.2 55.88,25.25 55.88,27.56 55.93,27.61 56.7,27.61
+5VS on TOP (solid shape): 273.01,36.98 273.01,36.18 273.58,36.18 273.58,35.93 273.02,35.93 273.02,35.37 273.58,35.37 273.58,35.13 273.01,35.13 273.01,34.47 272.87,34.33 272.07,34.33 271.17,35.23 271.17,36.92 271.55,37.3 272.69,37.3
+5VS on TOP (solid shape): 270.57,61.15 270.57,61.14 270.48,60.87 270.57,60.59 270.57,59.84 270.51,59.73 270.48,59.61 270.48,59.59 270.32,59.44 270.06,59.44 269.74,59.75 269.74,60.16 269.75,60.22 269.74,60.27 269.74,61.15 269.78,61.16 269.91,61.22 270,61.34 270.02,61.37 270.35,61.37
+5VS on TOP (solid shape): outline of 116 points within 106.27,49 107.7,53.29
+5VS on BOTTOM (solid shape): 273.66,62.17 273.66,61.51 273.58,61.43 272.93,61.43 272.63,61.14 272.63,59.71 272.5,59.58 270.12,59.58 270.02,59.68 270.02,60.96 270.15,61.09 270.16,61.09 270.67,61.61 271.56,61.61 271.6,61.61 272.02,61.61 272.64,62.23 273.6,62.23
+5VS on BOTTOM (solid shape): 33.8,73.04 33.8,72.42 33.65,72.13 33.8,71.85 33.8,71.61 33.78,71.57 33.75,71.56 33.42,71.2 33.75,70.85 33.78,70.83 33.8,70.79 33.8,70.7 33.34,70.25 32.71,70.25 32.29,70.67 32.29,72.95 32.57,73.23 33.61,73.23
+5VS on VCC: outline of 104 points within 21.9,5.92 284.18,65.61
+VBUS_DC_SS on TOP (solid shape): 29.97,52.29 29.97,51.19 28.85,50.08 28.85,47.45 28.64,47.23 21.75,47.23 21.63,47.35 21.63,48.52 21.34,48.81 21.09,48.81 20.98,48.92 20.98,52.65 21.23,52.91 29.35,52.91
+VBUS_DC_SS on BOTTOM (solid shape): 30.56,53.03 30.56,52.88 30.55,52.87 30.52,52.71 30.55,52.55 30.56,52.54 30.56,51.23 30.31,50.98 27.14,50.98 26.99,50.83 26.99,49.92 26.85,49.79 25.84,49.79 25.68,49.95 25.68,50.84 25.57,50.95 21.64,50.95 21.61,50.93 21.46,50.77 21.46,50.67 21.37,50.59 21.13,50.59 19.82,51.9 19.82,52.95 19.91,53.04 30.55,53.04
+VBUS_DC_TRIP on TOP (solid shape): 28.82,56.82 28.96,56.82 29.69,56.08 30.36,56.08 30.38,56.08 30.41,56.07 30.43,56.06 30.45,56.03 30.46,56 30.47,55.97 30.46,55.93 30.45,55.87 30.46,55.82 30.47,55.76 30.49,55.71 30.52,55.67 30.56,55.62 30.58,55.61 30.58,54.86 30.56,54.84 29.82,54.84 29.52,54.53 29.52,53.57 28.98,53.03 21.18,53.03 20.83,53.03 20.52,53.34 20.52,54.29 20.85,54.29 20.85,53.49 21.1,53.25 22,53.25 22.17,53.42 22.17,54.31 22.12,54.36 25.43,54.36 25.43,53.49 25.63,53.29 26.49,53.29 26.7,53.49 26.7,54.36 26.49,54.56 25.63,54.56 25.43,54.36 22.12,54.36 21.95,54.53 21.09,54.53 20.85,54.29 20.52,54.29 20.52,56.33 23.46,56.33 23.46,55.33 23.6,55.19 24.54,55.19 24.75,55.41 24.75,56.26 27.97,56.26 27.97,55.39 28.17,55.19 29.03,55.19 29.37,55.53 29.37,56.13 29.03,56.46 28.17,56.46 27.97,56.26 24.75,56.26 24.75,56.27 24.53,56.49 23.62,56.49 23.46,56.33 20.52,56.33 20.52,56.42 20.92,56.82
+VBUS_DC_TRIP on BOTTOM (solid shape): 27.59,56.41 27.59,54.66 27.46,54.53 26.3,54.53 25.05,55.78 24.94,55.78 24.87,55.8 24.8,55.82 24.73,55.87 24.72,55.95 24.38,56.43 24.05,55.93 24.05,55.85 23.99,55.8 23.93,55.78 23.85,55.78 23.44,55.37 23.44,54.81 23.29,54.66 23.09,54.66 22.81,54.94 21.84,54.94 21.67,54.76 21.43,54.76 21.25,54.94 21.25,55.97 21.41,56.13 21.41,56.62 21.59,56.79 27.2,56.79
+VCC_CORE on TOP (solid shape): outline of 2499 points within 67.72,107.77 96.19,138.5
+VCC_CORE on BOTTOM (solid shape): outline of 2920 points within 63.78,119.87 95.07,138.5
+VCC_CORE on VCC: 67.46,138.63 85.95,138.63 92.81,132.03 95.02,132.03 95.02,121.54 94.26,120.78 94.26,109.98 94.21,109.93 77.5,109.93 77.5,127.38 74.88,130 70.06,130 67.46,132.59
+VCCGT on TOP (solid shape): outline of 3397 points within 56.91,107.69 77.5,139.85
+VCCGT on BOTTOM (solid shape): outline of 84 points within 61.43,107.68 76.6,111.52
+VCCGT on BOTTOM (solid shape): outline of 1759 points within 58.53,119.89 77.12,142.52
+VCCGT on VCC: 61.37,109.93 61.37,116.03 58.7,116.03 58.7,139.9 67.21,139.9 67.21,132.48 69.95,129.74 74.78,129.74 77.24,127.28 77.24,109.93
+VCCIO on BOTTOM (solid shape): 55.27,112.11 55.27,110.5 54.97,110.19 52.34,110.19 51.97,110.57 51.97,111.98 52.15,112.16 52.72,112.16 52.72,111.64 52.73,111.63 52.78,111.63 53.46,111.63 53.47,111.64 53.47,112.17 53.92,112.17 53.92,111.64 53.92,111.63 54.66,111.63 54.67,111.64 54.67,112.18 55.21,112.18
+VCCIO on BOTTOM (solid shape): outline of 153 points within 95.99,109.64 99.34,119.61
+VCCIOP on BOTTOM (solid shape): 55.6,119.32 55.6,112.59 55.31,112.3 54.54,112.3 54.51,112.28 54.51,111.76 54.06,111.76 54.06,112.28 54.04,112.3 53.34,112.3 53.32,112.28 53.32,111.76 52.86,111.76 52.86,112.28 52.84,112.29 52.01,112.29 51.15,113.15 51.15,115.59 51.21,115.65 52.79,115.65 52.79,115.66 54.16,115.66 54.17,115.65 54.69,116.18 54.69,119.2 54.87,119.38 55.55,119.38
+VCCSA on TOP (solid shape): outline of 752 points within 94.14,109.53 99.68,135.88
+VCCSA on BOTTOM (solid shape): outline of 569 points within 95.21,119.97 100.04,135.81
+VCCSA on VCC: 94.51,110.82 94.51,120.67 95.28,121.43 95.28,135.84 98.27,135.84 103.29,130.82 103.28,130.81 103.28,122.96 104.17,122.07 104.17,117.31 104.15,117.3 102.78,117.3 101.96,118.13 96.64,118.13 96.44,117.93 96.44,117.75 96.44,110.82
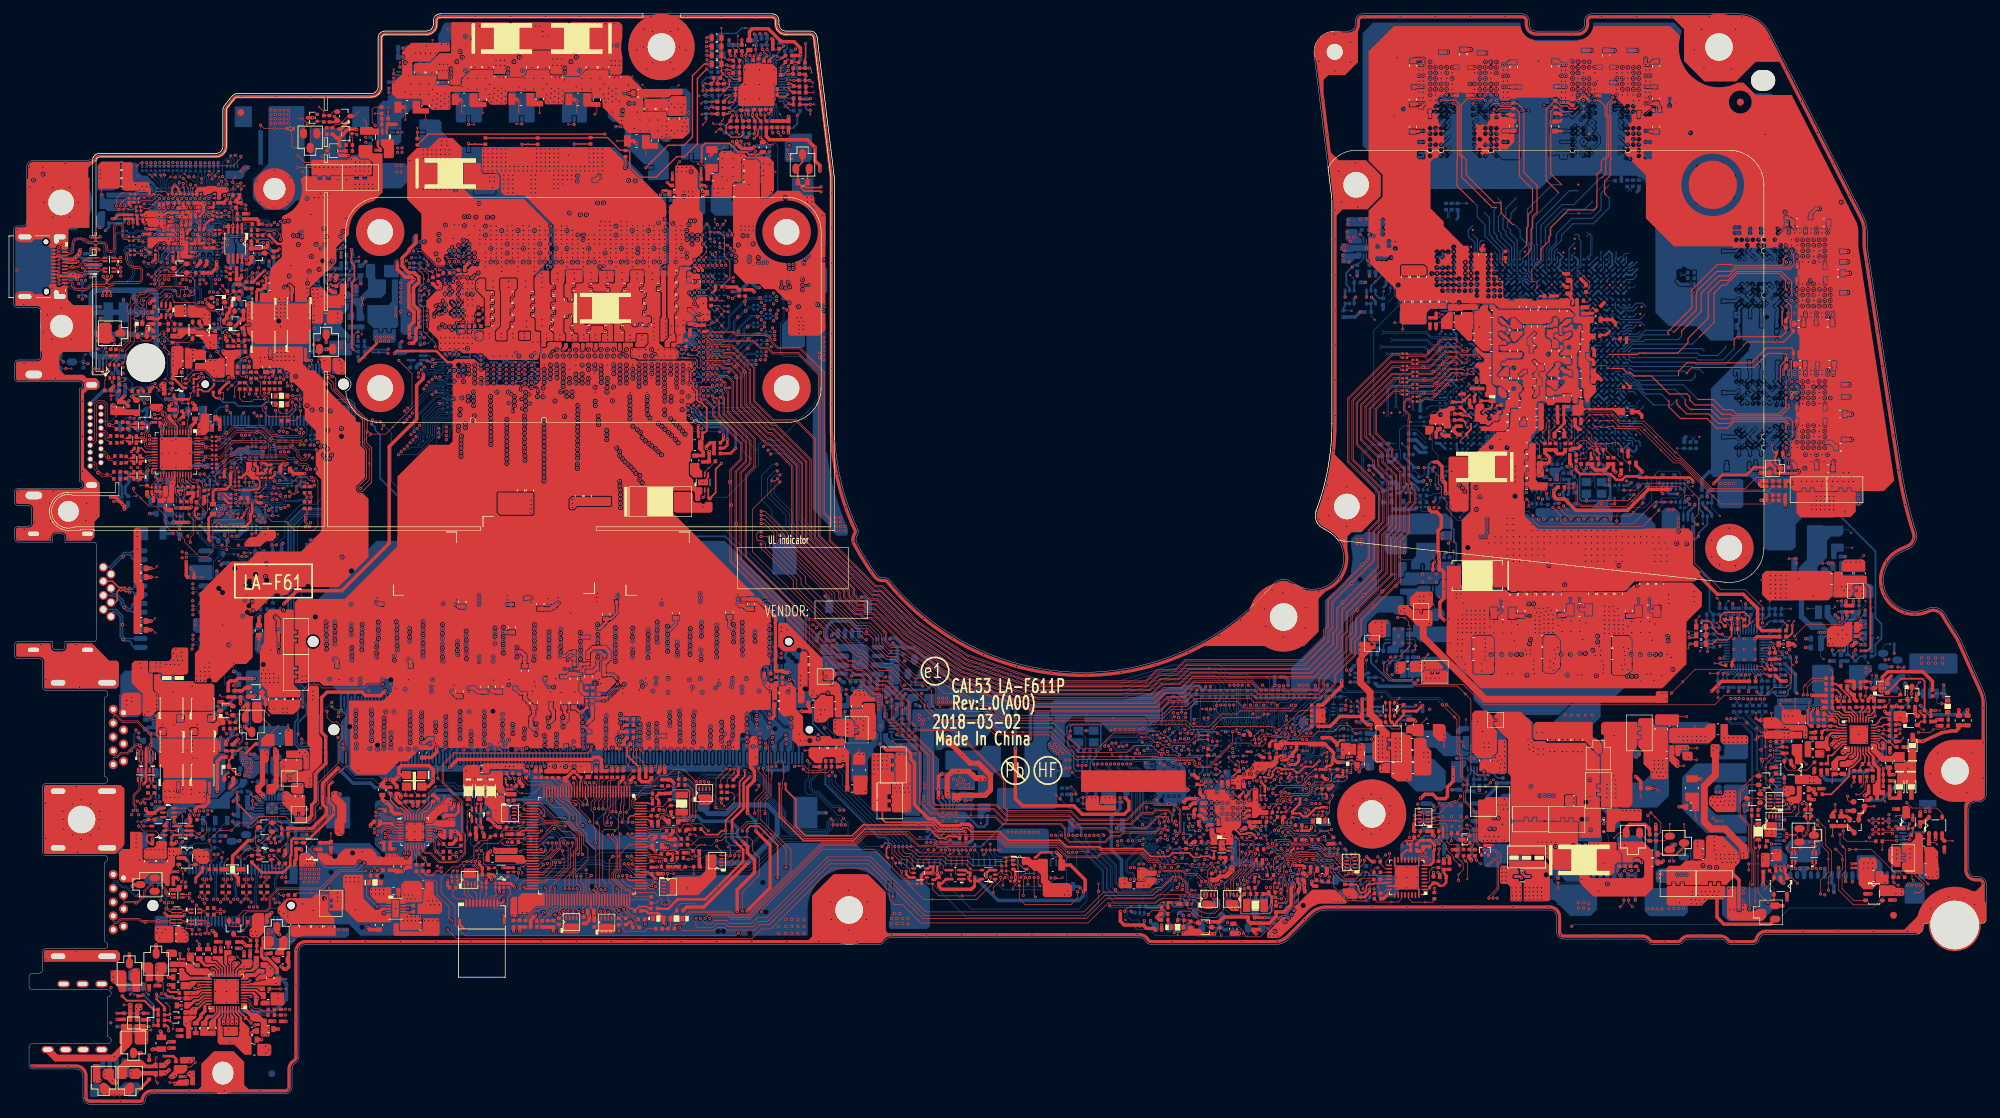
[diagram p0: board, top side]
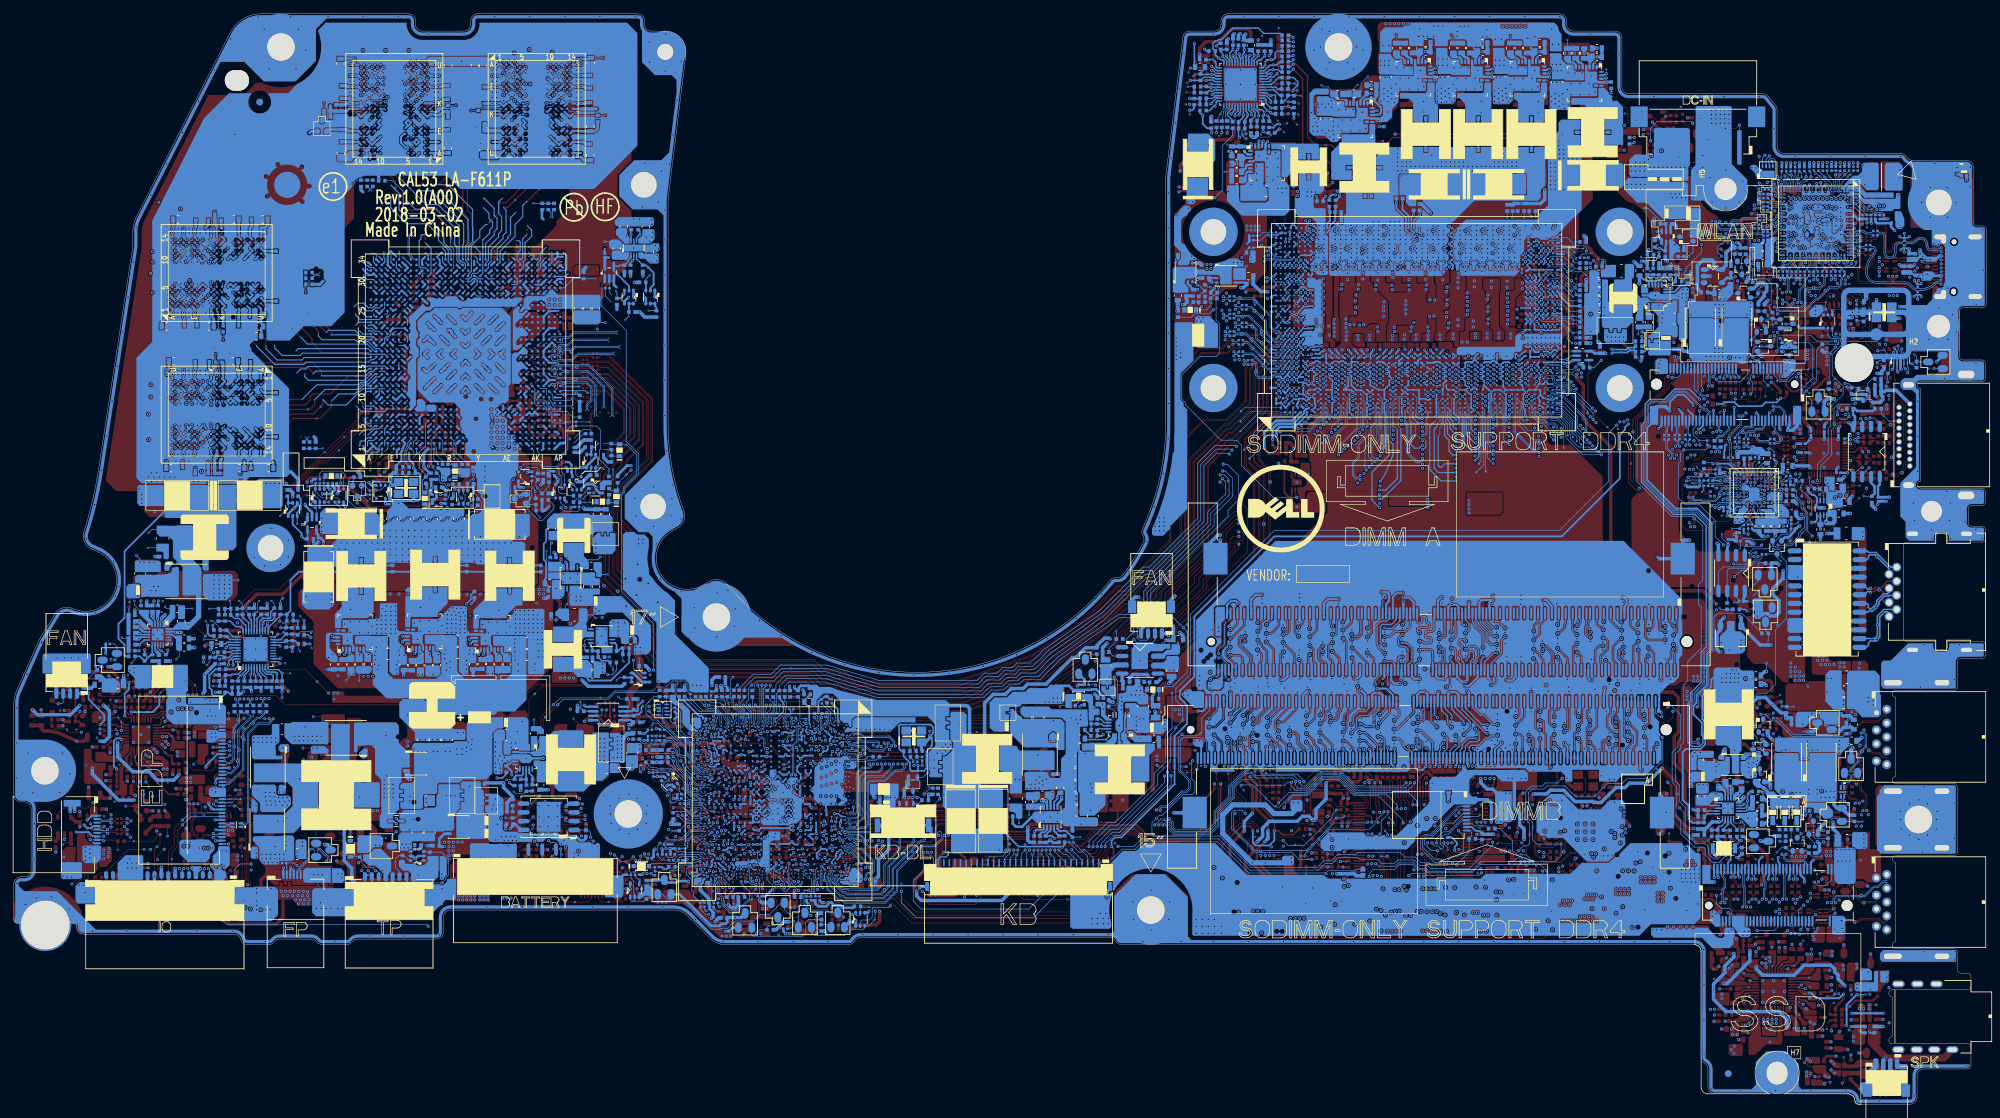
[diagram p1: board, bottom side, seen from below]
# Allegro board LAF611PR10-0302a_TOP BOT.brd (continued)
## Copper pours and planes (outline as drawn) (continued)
+VCCST on TOP (solid shape): 98.25,120.2 99.14,120.2 99.32,120.03 99.32,119.5 99.24,119.43 98.91,119.43 98.88,119.43 98.38,119.43 97.87,118.92 97.45,118.92 97.41,118.95 97.41,120.41 97.54,120.53 97.92,120.53
+VCCST on BOTTOM (solid shape): 106.48,123.46 106.48,122.91 106.66,122.72 106.66,121.84 106.56,121.74 105.86,121.74 105.68,121.91 105.68,123.46 105.78,123.55 106.38,123.55
+VCCST on BOTTOM (solid shape): 116.7,129.37 116.7,129.17 116.03,128.5 115.72,128.5 115.71,128.52 115.42,128.96 115.08,129.37 115.06,129.38 115.06,129.78 115.33,130.05 116.03,130.05
+VCCST on BOTTOM (solid shape): 116.92,124.33 116.92,123.74 116.5,123.32 116.5,122.31 116.95,121.86 116.95,121.6 116.79,121.43 115.47,121.43 115.28,121.63 115.28,121.95 115.11,122.12 114.31,122.12 114.19,122.23 114.19,122.43 114.22,122.44 115.03,123.1 115.67,123.93 115.83,124.21 115.96,124.5 116.75,124.5
+VCCSTG_OUT on BOTTOM (solid shape): 108.92,120.91 108.92,119.43 108.78,119.29 107.18,119.29 107.09,119.38 107.09,120.86 107.27,121.04 108.79,121.04
GND on TOP (solid shape): 10.95,108.9 3.85,108.9 3.85,115.58 10.95,115.58
GND on TOP (solid shape): 25.81,96.4 25.81,91.96 25.64,91.79 21.29,91.79 21.12,91.97 21.12,96.38 21.26,96.53 25.68,96.53
GND on TOP (solid shape): 32.44,11.17 32.44,10.03 32.26,9.85 30.43,9.85 30.35,9.93 30.35,11.17 30.4,11.23 32.39,11.23
GND on TOP (solid shape): 39.14,16.08 39.14,14.47 38.94,14.27 37.29,14.27 37.15,14.41 37.15,16.13 37.2,16.18 39.04,16.18
GND on TOP (solid shape): 74.68,111.76 74.68,110.69 74.59,110.6 73.18,110.6 73.11,110.67 73.11,111.75 73.17,111.81 74.63,111.81
GND on TOP (solid shape): 177.53,24.86 177.53,24.51 177.39,24.37 175.91,24.37 175.87,24.4 175.87,25 176.02,25.14 177.25,25.14
GND on TOP (solid shape): 189.75,57.19 189.75,55.3 189.6,55.15 188.41,55.15 188.36,55.21 188.36,57.21 188.43,57.28 189.65,57.28
GND on TOP (solid shape): 204.4,121.02 204.4,120.14 204.16,119.9 200.83,119.9 200.7,120.03 200.7,121.3 200.83,121.42 204,121.42
GND on TOP (solid shape): 225.96,44.53 225.96,43.31 225.77,43.12 224.48,43.12 224.41,43.2 224.41,44.63 224.49,44.71 225.78,44.71
GND on TOP (solid shape): 244.59,38.09 244.59,35.82 244.22,35.45 243.09,35.45 243,35.55 243,38.07 243.21,38.28 244.4,38.28
GND on TOP (solid shape): 255.08,40.71 255.08,38.79 254.95,38.66 253.36,38.66 253.26,38.76 253.26,40.61 253.47,40.82 254.97,40.82
GND on TOP (solid shape): 267.86,78.5 267.86,77.23 267.72,77.09 264.59,77.09 264.44,77.24 264.44,78.38 264.9,78.84 267.53,78.84
GND on TOP (solid shape): 201.35,63.98 201.35,62.75 200.89,62.29 200.03,62.29 199.9,62.41 199.9,63.78 200.18,64.06 201.27,64.06
GND on TOP (solid shape): 67.86,111.68 67.86,111.18 67.87,111.18 67.87,110.79 67.6,110.52 67.02,110.52 66.77,110.77 66.77,111.75 66.87,111.85 67.69,111.85
GND on TOP (solid shape): 75.19,88.43 75.19,85.45 75.03,85.29 70.37,85.29 69.98,85.68 69.98,88.4 70.1,88.53 75.09,88.53
GND on TOP (solid shape): 86.43,87.84 86.43,86.72 86.28,86.57 81.52,86.57 81.03,86.08 80.52,86.08 80.38,86.22 80.38,87.51 80.78,87.9 86.36,87.9
GND on TOP (solid shape): 91.68,111.34 91.68,110.1 91.13,109.54 89.96,109.54 89.9,109.6 89.9,110.15 90.09,110.33 90.09,111.35 90.22,111.48 91.54,111.48
GND on TOP (solid shape): 263.15,76.9 263.15,76.12 263.14,76.11 263.14,73.57 262.48,72.91 253.76,72.91 252.93,73.73 252.93,76.67 253.45,77.2 262.85,77.2
GND on TOP (solid shape): 45.95,108.12 45.95,106.11 45.76,105.92 45.03,105.92 44.41,106.54 44.41,107.52 44.22,107.71 44.22,108.15 44.48,108.41 45.66,108.41
GND on TOP (solid shape): 194.42,30.61 194.42,29.81 194.36,29.74 193.02,29.74 192.24,30.52 192.24,31.15 192.33,31.24 193.79,31.24
GND on TOP (solid shape): 41.88,46.34 41.88,45.06 41.77,44.95 40.43,44.95 40.08,45.29 40.08,46.28 40.21,46.4 40.39,46.4 40.49,46.5 40.52,46.5 40.52,46.5 41.73,46.5
GND on TOP (solid shape): 72.82,29.92 72.82,27.68 72.97,27.52 72.97,27.25 72.85,27.13 71.96,27.13 71.83,27.25 71.83,29.67 72.21,30.05 72.7,30.05
GND on TOP (solid shape): 195.51,52.01 195.51,49.73 195.4,49.62 194.81,49.62 194.73,49.7 194.28,49.7 194.18,49.8 194.18,50.31 194.38,50.52 194.38,51.97 194.69,52.27 195.25,52.27
GND on TOP (solid shape): 199.14,49.35 199.14,47.97 199.09,47.92 197.69,47.92 197.5,48.12 197.5,48.96 197.76,49.22 198.09,49.22 198.27,49.4 199.08,49.4
GND on TOP (solid shape): 204.37,52.66 204.37,51.84 205.11,51.11 205.11,47.84 204.83,47.56 202.74,47.56 202.55,47.76 202.55,52.84 202.7,52.99 204.04,52.99
GND on TOP (solid shape): 207.29,115.9 207.29,115.26 207.16,115.14 205,115.14 204.37,114.5 204.37,112.98 204.24,112.85 200.81,112.85 200.56,113.1 200.56,115.64 200.94,116.03 207.16,116.03
GND on TOP (solid shape): 211.17,114.52 211.17,112.37 211,112.2 211,110.69 210.78,110.47 210.37,110.47 208.39,112.45 208.39,114.09 208.54,114.24 209.22,114.24 209.63,114.65 211.04,114.65
GND on TOP (solid shape): 156.99,44.49 156.99,43.44 157.15,43.28 159.44,43.28 159.49,43.23 159.49,42.57 159.39,42.47 155.24,42.47 155.07,42.64 155.07,44.5 155.22,44.65 156.83,44.65
GND on TOP (solid shape): 246.18,54.98 246.18,53.14 245.32,52.28 239.57,52.28 239.47,52.37 239.47,54.26 239.65,54.44 244.52,54.44 245.13,55.05 246.11,55.05
GND on TOP (solid shape): 249.2,45.28 249.2,42.57 248.89,42.27 246.34,42.27 245.26,43.35 245.26,44.35 245.57,44.66 247.18,44.66 247.41,44.89 247.41,45.28 247.58,45.44 249.03,45.44
GND on TOP (solid shape): 24.54,109.45 24.54,106.84 24.23,106.54 24.08,106.54 23.73,106.19 23.73,105.63 23.63,105.52 22.98,105.52 22.76,105.74 22.76,109.5 22.99,109.72 24.27,109.72
GND on TOP (solid shape): 26.39,12.8 26.39,12.67 25.93,12.22 25.81,12.22 25.68,12.09 25.68,9.64 25.53,9.49 24.98,9.49 24.9,9.57 24.9,11.06 24.49,11.47 24.49,12.7 24.61,12.82 26.37,12.82
GND on TOP (solid shape): 67.55,136.11 67.55,135.24 67.59,135.2 67.59,134.92 67.84,134.67 69.9,134.67 70.26,134.31 70.26,132.66 69.88,132.28 65.81,132.28 65.11,132.98 65.11,136.11 65.2,136.2 67.46,136.2
GND on TOP (solid shape): 117.56,59.08 118.53,59.08 118.57,59.04 118.57,56.02 118.5,55.94 118.04,55.94 117.33,55.24 116.02,55.24 115.75,55.5 115.75,58.36 115.91,58.51 116.04,58.51 116.81,59.28 117.36,59.28
GND on TOP (solid shape): 218.37,111.75 218.37,111.53 217.16,110.32 216.92,110.32 216.65,110.59 216.65,110.91 216.52,111.03 216.52,111.47 216.54,111.49 216.54,111.77 216.6,111.83 217.71,111.83 217.84,111.96 218.16,111.96
GND on TOP (solid shape): 257.7,45.8 257.7,44.89 257.58,44.78 257.06,44.78 256.78,44.5 256.31,44.5 255.93,44.88 255.93,45.92 256.06,46.05 256.06,46.05 256.11,46.1 257.4,46.1
GND on TOP (solid shape): 278.41,36.58 278.41,34.3 278.57,34.15 278.57,32.78 278.3,32.51 276.97,32.51 276.44,33.04 276.44,36.65 276.36,36.73 276.36,37.18 276.44,37.26 277.73,37.26
GND on TOP (solid shape): 17.2,136.13 17.2,133.7 17.45,133.45 19.45,133.45 19.62,133.27 19.62,132.27 19.35,132 18.07,132 17.88,132.2 15.94,132.2 15.63,132.5 15.63,136.19 15.77,136.33 17,136.33
GND on TOP (solid shape): 270.54,33.59 270.54,33.36 270.66,33.24 271.15,33.24 271.22,33.17 271.22,31.93 271.12,31.82 269.96,31.82 269.84,31.7 269.49,31.7 269.34,31.85 269.34,33.57 269.48,33.71 270.41,33.71
GND on TOP (solid shape): 17.38,2.81 17.38,1.85 16.8,1.27 13.05,1.27 12.45,1.86 12.45,2.77 12.78,3.1 13.2,3.1 14.09,2.22 15.76,2.22 16.66,3.12 17.07,3.12
GND on TOP (solid shape): 69.69,37.11 72.69,37.11 72.84,37.11 72.9,37.05 72.9,36.41 72.69,36.2 69.56,36.2 69.36,36.4 69.36,36.77 69.36,36.78 69.36,37.18 69.43,37.25 69.55,37.25
GND on TOP (solid shape): 169.51,48.28 169.51,45.85 169.58,45.78 169.99,45.78 170.12,45.65 170.12,45.34 169.99,45.22 154.43,45.22 154.41,45.24 154.41,48.26 154.46,48.32 169.47,48.32
GND on TOP (solid shape): 228.44,55.13 228.44,53.16 228.63,52.97 228.94,52.97 229.77,52.14 229.77,50.94 229.51,50.68 229.13,50.68 227.28,52.53 221.93,52.53 221.77,52.69 220.14,52.69 219.81,53.03 219.81,54.91 220.23,55.33 228.24,55.33
GND on TOP (solid shape): 46.58,25.6 46.58,24.46 46.5,24.37 42.25,24.37 41.82,24.33 41.41,24.21 41.4,24.2 40.34,24.2 40.01,24.54 40.01,25.68 40.23,25.91 46.28,25.91
GND on TOP (solid shape): 231.6,42.76 235.33,42.76 235.53,42.56 235.53,41.18 235.34,40.99 232.14,40.99 231.7,40.55 231.7,39.47 231.62,39.39 230.51,39.39 230.43,39.47 230.43,42.65 230.55,42.77 231.59,42.77
GND on TOP (solid shape): 22.33,89.39 22.33,88.11 22.06,87.84 22.06,87.34 21.71,86.98 20.93,86.98 20.84,87.07 20.84,87.66 20.92,87.74 21.3,87.74 21.51,87.95 21.51,88.03 21.51,88.04 21.51,88.77 21.51,88.78 21.51,89.37 21.65,89.51 22.21,89.51
GND on TOP (solid shape): 41.47,58.41 41.47,57.58 41.46,57.5 41.46,57.42 41.47,57.39 40.5,56.42 37.29,56.42 36.75,56.96 36.75,57.39 36.85,57.49 36.85,58.43 36.99,58.57 41.31,58.57
GND on TOP (solid shape): 170.69,25.7 170.69,25.47 170.74,25.42 171.55,25.42 172.05,24.92 173.89,24.92 173.96,24.85 173.96,24.46 173.88,24.38 169.05,24.38 168.92,24.51 168.92,24.94 169.08,25.09 169.65,25.09 169.84,25.28 169.84,25.71 169.93,25.81 170.59,25.81
GND on TOP (solid shape): 42.67,50.98 42.67,48.57 42.57,48.47 42.07,48.47 41.9,48.63 41.9,50.01 41.9,50.01 41.9,50.08 41.86,50.12 41.76,50.12 41.75,50.13 39.52,50.13 39.39,50.26 39.39,51.12 39.47,51.2 40.99,51.2 41.17,51.38 42.27,51.38
GND on TOP (solid shape): 61.6,26.77 61.6,24.51 61.46,24.37 55.11,24.37 54.92,24.56 54.92,26.03 55.08,26.19 55.65,26.19 55.73,26.11 55.73,25.09 55.8,25.02 59.03,25.02 59.18,25.17 59.18,26.8 59.31,26.92 61.44,26.92
GND on TOP (solid shape): 19.41,64.09 19.41,62.53 19.61,62.33 19.99,62.33 20.08,62.24 20.08,59.98 20.12,59.95 20.12,59.92 20.89,59.15 20.89,57.14 19.87,56.12 18.77,56.12 18.62,56.27 18.62,59.37 17.05,60.94 17.05,63.75 17.49,64.19 19.31,64.19
GND on TOP (solid shape): 26.58,130.65 27.72,130.65 27.84,130.53 27.84,130.12 27.65,129.93 27.65,129.04 27.58,128.98 27.27,128.98 27.2,129.04 27.2,130.06 27.16,130.09 27.16,130.11 27.15,130.11 27.14,130.12 26.86,130.12 26.85,130.12 25.87,130.12 25.87,130.69 26.53,130.69
GND on TOP (solid shape): 80.29,156.37 80.29,152.98 79.92,152.62 73.02,152.62 72.83,152.67 72.65,152.62 72.63,152.62 72.52,152.62 71.9,153.24 71.9,156.38 72.09,156.56 80.09,156.56
GND on TOP (solid shape): 124.09,58.88 124.12,58.88 124.52,58.88 124.6,58.79 124.6,58.38 124.47,58.26 122.95,58.26 122.73,58.04 122.73,57.58 122.5,57.34 121.13,57.34 120.91,57.57 120.91,59.01 121.4,59.5 121.4,59.73 121.71,60.04 122.94,60.04
GND on TOP (solid shape): 220.22,111.63 220.22,111.45 219.61,110.84 219.61,110.36 220.11,109.85 220.11,109.52 219.78,109.19 219.78,108.76 219.3,108.76 219.3,109.34 219.35,109.39 219.35,109.72 219.17,109.9 219,109.9 219,110.84 219.91,111.76 220.09,111.76
GND on TOP (solid shape): 265.98,69.74 265.98,67.15 265.02,66.19 262.46,66.19 262.28,66.37 262.28,68.12 262.33,68.29 262.29,68.47 262.28,68.48 262.28,68.63 262.87,69.21 264.61,69.21 265.17,69.78 265.95,69.78
GND on TOP (solid shape): 120.87,51 120.87,49.73 120.65,49.51 119.77,49.51 119.59,49.32 118.92,49.32 118.88,49.36 118.88,50.1 118.74,50.24 117.27,50.24 117.1,50.08 117.09,50.08 117.09,50.07 117,49.98 117,49.47 116.88,49.34 115.95,49.34 114.97,50.32 114.97,51.4 115.24,51.67 120.21,51.67
GND on TOP (solid shape): 231.9,37.76 231.9,36.84 232.56,36.18 232.56,35.1 232.44,34.98 231.92,34.98 231.69,34.75 231.69,34.75 231.56,34.62 231.56,33.54 231.13,33.1 228.3,33.1 227.75,33.65 227.75,37.82 227.88,37.95 231.71,37.95
GND on TOP (solid shape): 24.62,25.51 24.61,25.49 24.62,25.4 24.65,25.33 24.73,25.22 24.85,25.16 24.86,25.16 25.29,24.73 25.29,23.64 25.01,23.37 23.6,23.37 23.33,23.64 23.33,25.61 23.44,25.72 24.41,25.72
GND on TOP (solid shape): 249.2,31.38 249.2,27.95 249.39,27.76 249.83,27.76 250.03,27.95 250.03,28.9 250.15,29.03 250.6,29.03 250.72,28.9 250.72,28.08 250.91,27.89 251.87,27.89 252.25,28.27 253.26,28.27 253.52,28.01 253.52,27.06 253.01,26.55 248.31,26.55 247.87,27 247.87,31.38 247.99,31.51 249.07,31.51
GND on TOP (solid shape): 256.07,54.91 259.16,54.91 259.39,54.68 259.39,54.56 259.52,54.43 259.52,53.07 259.36,52.91 259.02,52.91 258.87,53.06 258.87,53.93 258.75,54.05 257.08,54.05 256.79,54.34 253.18,54.34 253.1,54.41 253.1,54.95 253.1,54.95 253.1,55.79 253.18,55.87 253.21,55.87 253.35,56.01 254.98,56.01
GND on TOP (solid shape): 15.36,21.84 15.36,20.92 15.06,20.62 4.35,20.62 4.35,22 4.44,22.21 4.65,22.3 13.1,22.3 13.16,22.3 13.21,22.31 14.89,22.31
GND on TOP (solid shape): 25.87,129.23 25.87,128.72 25.8,128.66 25.8,128.15 25.69,128.15 25.61,128.16 25.54,128.15 25.36,128.15 25.3,128.22 25.3,128.59 25.3,128.72 25.17,128.85 24.85,128.85 24.79,128.91 24.79,129.22 24.79,129.3 24.85,129.36 25.74,129.36
GND on TOP (solid shape): 80.75,114.1 80.75,112.98 80.39,112.63 80.39,112.31 80.59,112.11 80.81,112.11 80.95,111.97 80.95,111.66 81.16,111.45 81.51,111.45 81.55,111.41 81.55,110.43 81.49,110.37 79.91,110.37 79.91,110.37 79.91,111.49 79.65,111.75 79.65,113.56 79.75,113.66 80.13,113.66 80.28,113.81 80.28,114.11 80.42,114.26 80.59,114.26
GND on TOP (solid shape): 85.26,112.59 85.26,112.21 85.41,112.06 85.72,112.06 85.84,111.94 85.84,111.68 85.76,111.6 85.08,111.6 84.93,111.45 84.93,110.45 84.85,110.37 83.46,110.37 83.39,110.43 83.39,111.43 83.21,111.61 83.11,111.61 82.97,111.76 82.97,111.98 83.07,112.09 83.43,112.09 83.54,112.2 83.54,112.61 83.62,112.68 85.17,112.68
GND on TOP (solid shape): 108.13,150.6 108.13,150.58 108.16,150.58 108.21,150.53 109.83,150.53 110.43,149.93 110.43,147.55 110.21,147.33 110.06,147.33 110.06,145.67 110.09,145.67 110.09,144.6 109.93,144.44 104.96,144.44 104.8,144.6 104.8,147.19 105.54,147.93 105.54,150.24 105.92,150.62 107.36,150.62 107.48,150.74 108,150.74
GND on TOP (solid shape): 73.33,49.34 73.76,49.34 73.99,49.11 73.99,49.03 73.98,48.93 73.99,48.83 73.99,48.77 73.88,48.65 73.67,48.65 73.44,48.42 71.62,48.42 71.55,48.49 68.94,48.49 68.78,48.33 68.78,47.99 68.68,47.89 67.82,47.89 67.76,47.95 67.76,49.15 67.95,49.35 73.32,49.35
GND on TOP (solid shape): 110.63,61.17 110.63,60.51 110.45,60.33 110.45,58.75 110.45,58.74 110.45,58.54 110.38,58.46 109.77,58.46 109.69,58.55 109.69,59.78 109.46,60.01 109.18,60.01 108.46,60.73 108.46,61.07 108.56,61.17 109.17,61.17 109.46,60.88 109.85,60.88 109.96,60.99 109.96,61.16 110.03,61.24 110.57,61.24
GND on TOP (solid shape): 223.38,112.29 223.38,111.79 223.28,111.69 222.9,111.69 222.73,111.52 222.73,111.08 222.71,111.07 222.71,110.86 222.87,110.71 223.21,110.71 223.32,110.6 223.32,110.57 223.49,110.4 223.49,109.45 223.43,109.39 222.56,109.39 222.56,110.53 222.18,110.9 222,110.9 221.75,111.16 221.75,112.01 221.87,112.13 222.59,112.13 222.79,112.33 223.34,112.33
GND on TOP (solid shape): 60.75,32.08 60.75,30.36 61.95,29.16 61.95,27.87 61.59,27.51 58.88,27.51 58.5,27.51 58.42,27.58 58.42,29.01 58.45,29.03 59.03,29.03 59.16,29.16 59.18,29.16 59.18,29.18 59.23,29.23 59.23,30.94 59.49,31.19 59.49,32.21 59.52,32.24 60.59,32.24
GND on TOP (solid shape): 94.37,120.58 94.37,113.84 94.59,113.62 94.59,111 93.95,110.36 93.56,110.36 93.53,110.39 93.53,113.7 93.75,113.92 93.75,117.47 93.52,117.7 93.17,117.7 93.02,117.85 93.02,118.09 93.02,118.13 93.1,118.21 93.45,118.21 93.57,118.34 93.57,118.42 93.59,118.44 93.59,120.64 93.64,120.69 94.26,120.69
GND on TOP (solid shape): 21.34,129.17 21.35,129.16 21.42,129.05 21.53,128.98 21.54,128.98 21.63,128.89 21.8,128.89 22,128.69 22,128.34 21.87,128.22 20.85,128.22 20.78,128.29 20.78,128.31 20.76,128.31 20.73,128.34 20.71,128.34 20.69,128.37 18.92,128.37 18.76,128.53 18.76,128.98 19.08,129.3 21.22,129.3
GND on TOP (solid shape): 37.59,19.63 37.59,18.69 37.32,18.42 36.67,18.42 36.3,18.04 35.67,18.04 35.66,18.03 35.63,18.03 35.49,17.89 35.01,17.89 34.97,17.94 34.97,18.24 34.99,18.26 35.06,18.26 35.57,18.77 36.29,18.77 36.43,18.91 36.43,19.65 36.4,19.68 36.39,19.68 36.37,19.71 35.81,19.71 35.68,19.83 35.68,20.48 35.8,20.59 36.63,20.59
GND on TOP (solid shape): 48.17,118.62 48.17,116.95 47.88,116.66 47.88,115.75 47.35,115.22 45.35,115.22 44.8,114.67 44.8,113.16 44.61,112.97 43.21,112.97 43.13,113.05 43.13,116.59 43.11,116.61 43.11,116.89 42.95,117.04 42.95,118.1 43.08,118.23 44.48,118.23 45.69,117.02 46.81,117.02 46.91,117.12 46.91,117.12 47.15,117.35 47.15,118.59 47.31,118.75 48.03,118.75
GND on TOP (solid shape): 98.3,88.31 98.3,87.35 98.58,87.07 99.42,87.07 99.78,86.88 100.08,87.15 100.09,87.19 100.91,87.19 101.09,87.01 101.09,85.88 100.81,85.6 99.75,85.6 99.74,85.59 95.74,85.59 95.5,85.83 95.5,88.59 95.52,88.61 98,88.61
GND on TOP (solid shape): 16.01,45.65 16.01,37.55 14.72,36.25 14.71,36.25 14.66,36.2 13.18,36.2 13.14,36.2 13.1,36.2 4.65,36.2 4.44,36.29 4.35,36.5 4.35,45.9 4.44,46.11 4.65,46.2 15.46,46.2
GND on TOP (solid shape): 86.79,120.52 86.79,119.03 86.69,118.93 85.81,118.93 85.64,118.76 85.64,118.69 85.63,118.68 85.59,118.5 85.63,118.32 85.64,118.3 85.83,118.11 86.13,118.11 86.18,118.07 86.18,117.67 86.09,117.59 83.99,117.59 83.87,117.71 83.87,118.04 83.67,118.25 83.36,118.25 83.25,118.35 83.25,118.68 83.35,118.77 84.51,118.77 84.63,118.89 84.63,120.49 84.77,120.63 86.68,120.63
GND on TOP (solid shape): 220.29,107.59 220.29,107.41 220.57,107.13 221.16,107.13 221.36,106.93 221.36,106.12 220.8,106.12 220.55,105.86 220.55,105.43 221.03,104.95 221.03,104.03 220.98,103.98 220.77,103.98 220.62,103.83 220.62,103.4 220.7,103.32 220.7,102.81 220.06,102.18 219.89,102.18 219.76,102.31 219.76,102.54 220.06,102.84 220.06,103.32 219.78,103.6 219.78,103.78 220.39,104.39 220.39,104.82 219.78,105.43 219.78,105.63 220.47,106.32 220.47,106.7 219.76,107.41 219.76,107.64 219.89,107.77 220.11,107.77
GND on TOP (solid shape): 163.99,33.86 164.34,33.86 164.53,33.8 164.73,33.86 165.25,33.86 165.35,33.76 165.35,33.26 165.3,33.17 165.27,33.07 165.27,33.02 163.77,33.02 163.6,32.85 163.6,32.38 163.54,32.32 162.64,32.32 162.52,32.45 162.53,32.56 162.52,32.64 162.52,34.17 162.63,34.28 163.56,34.28
GND on TOP (solid shape): 82.31,120.55 82.31,119.05 82.17,118.91 81.28,118.91 81.25,118.88 81.25,118.42 81.12,118.29 80.88,118.29 80.7,118.1 80.7,118.06 80.69,118.05 80.67,117.92 80.69,117.8 80.7,117.79 80.7,117.46 80.85,117.3 80.85,116.24 80.77,116.16 80.27,116.16 80.2,116.23 80.2,116.57 80.1,116.67 80.02,116.67 80.01,116.68 79.9,116.73 79.78,116.75 79.76,116.75 79.65,116.86 79.65,118.61 79.89,118.85 79.89,120.66 80,120.78 82.08,120.78
GND on TOP (solid shape): 221.37,101.24 221.37,100.32 221.36,100.31 221.33,100.16 221.36,100.01 221.37,100 221.37,99.48 221.36,99.47 221.32,99.3 221.36,99.13 221.37,99.12 221.37,98.63 221.34,98.49 221.36,98.37 221.37,98.36 221.37,97.76 221.03,97.43 220.6,97.43 220.54,97.5 220.54,101.37 220.6,101.43 221.18,101.43
GND on TOP (solid shape): 228.94,106.34 228.94,106.21 228.93,106.2 228.92,105.91 229.15,105.73 229.17,105.72 229.75,105.14 229.76,105.13 229.82,105.01 229.93,104.93 229.93,104.74 229.76,104.57 229.54,104.57 229.36,104.75 229,104.75 228.88,104.62 228.88,104.29 228.7,104.29 228.7,104.29 228.27,104.29 228.1,104.46 228.1,106.34 228.25,106.49 228.78,106.49
GND on TOP (solid shape): 114.85,65.31 114.85,60.49 114.8,60.4 114.69,60.41 114.15,60.27 114.4,59.77 114.4,58.24 114.15,57.99 113.56,57.99 113.44,58.11 113.44,63.65 113.74,63.96 113.74,65.23 114.05,65.54 114.06,65.54 114.62,65.54
GND on TOP (solid shape): 22.12,37.96 22.12,35.6 22.04,35.51 21.58,35.51 21.57,35.51 21.45,35.53 21.33,35.51 21.32,35.51 20.99,35.51 20.98,35.51 20.87,35.53 20.75,35.51 20.74,35.51 20.41,35.51 20.4,35.51 20.28,35.53 20.16,35.51 20.16,35.51 19.82,35.51 19.82,35.51 19.7,35.53 19.58,35.51 19.57,35.51 18.99,35.51 18.78,35.72 18.78,36.77 19.16,37.15 20.26,37.15 20.4,37.29 20.44,37.29 20.44,37.32 20.58,37.47 20.58,37.91 20.74,38.07 22.01,38.07
GND on TOP (solid shape): 104.29,137.54 105.73,137.54 106.11,137.16 109.11,137.16 109.97,136.3 109.97,132.19 109.02,131.24 108.22,131.24 108.07,131.39 108.07,136.39 107.59,136.87 105.42,136.87 105.24,136.69 105.24,136.59 105.23,136.58 105.23,135.84 105.23,135.83 105.21,135.73 105.23,135.63 105.23,135.63 105.23,134.79 105.23,134.78 105.21,134.68 105.23,134.58 105.23,134.57 105.23,133.8 105.22,133.71 105.23,133.62 105.23,133.48 105.22,133.47 104.27,133.47 103.89,133.09 103.89,131.32 101.04,131.32 101.04,134.35 101.41,134.71 101.93,134.71 102.03,134.81 102.03,137.62 102.38,137.97 102.47,137.97 102.47,137.97 103.86,137.97
GND on TOP (solid shape): 72.77,119.43 72.77,118.03 72.47,117.73 72.44,117.73 72.39,117.68 72.39,116.99 72.27,116.87 72.13,116.87 72.08,116.86 71.81,116.86 71.76,116.81 71.76,116.15 72.34,115.57 72.34,115.26 72.22,115.14 72.08,115.14 72.01,115.13 71.94,115.11 71.83,115.11 71.73,115.01 71.73,114.86 71.72,114.78 71.73,114.71 71.73,114.27 72.09,113.92 72.25,113.92 72.34,113.83 72.34,113.43 72.26,113.36 71.84,113.36 71.7,113.22 71.7,112.36 71.31,111.97 71.31,110.62 71.2,110.51 69.89,110.51 69.73,110.68 69.73,111.84 70.49,112.6 70.49,117.6 70.36,117.73 70.36,119.38 70.49,119.51 72.7,119.51
GND on TOP (solid shape): 30.6,109.14 31.82,109.14 31.9,109.21 32.78,109.21 32.82,109.17 32.82,108.15 32.6,107.93 32.23,107.93 31.91,107.61 31.9,107.61 31.9,105.46 32,105.37 32,105.07 31.85,104.93 31.53,104.93 31.44,105.02 31.44,105.05 31.39,105.37 31.09,105.52 30.94,105.51 30.83,105.46 30.72,105.46 30.67,105.55 30.67,108 30.05,108.62 30.05,109.14 30.16,109.25 30.49,109.25
GND on TOP (solid shape): 215.97,52.6 215.97,47.99 215.8,47.81 213.64,47.81 213.45,47.99 213.18,47.99 213.09,48 213.04,48.08 212.75,48.42 212.36,48.22 212.19,48.22 212.03,48.39 212.03,49.54 212.42,49.93 213.76,49.93 213.79,49.96 213.82,49.96 214.51,50.65 214.53,50.65 214.53,50.67 214.69,50.83 214.69,52.59 214.89,52.79 215.79,52.79
GND on TOP (solid shape): 2.48,134.1 2.53,134.09 2.56,134.05 2.85,133.3 3.14,134.05 3.18,134.09 3.23,134.1 10.95,134.1 10.95,126.82 1.85,126.82 1.85,133.6 2,133.95 2.35,134.1
GND on TOP (solid shape): 68.22,119.35 68.22,117.83 68.26,117.8 68.26,117.77 68.28,117.77 68.38,117.68 69.34,117.68 69.49,117.53 69.49,117.12 69.42,117.04 69.01,117.04 68.87,116.9 68.87,116.42 68.99,116.31 69.25,116.31 69.37,116.3 69.49,116.18 69.49,115.9 69.39,115.8 69.23,115.8 69.01,115.8 68.86,115.65 68.86,115.26 69.06,115.06 69.37,115.06 69.49,114.93 69.49,114.68 69.34,114.53 69.23,114.53 69.01,114.53 68.86,114.38 68.86,113.94 69.04,113.77 69.42,113.77 69.49,113.69 69.49,113.41 69.37,113.28 69.04,113.28 68.89,113.13 68.89,112.65 68.81,112.57 68.22,112.57 68.12,112.67 68.12,113.54 68.24,113.8 68.12,114.07 68.12,114.79 68.23,115.04 68.12,115.29 68.12,116.63 66.83,117.93 66.83,119.01 67.33,119.51 68.07,119.51
GND on TOP (solid shape): 5.35,66.25 5.57,65.72 6.1,65.5 6.9,65.5 7.43,65.72 7.65,66.25 7.65,66.7 11.3,66.7 13.81,64.19 14.89,64.19 15.2,63.88 15.2,60.55 14.8,60.15 4.65,60.15 4.48,60.23 4.4,60.4 4.4,64 4.18,64.53 3.65,64.75 0.6,64.75 0.43,64.83 0.35,65 0.35,66.45 0.43,66.62 0.6,66.7 5.35,66.7
GND on TOP (solid shape): 220.18,95.6 220.18,90.37 220.56,90 221.68,90 221.9,89.78 221.9,88.99 221.65,88.75 221.3,88.75 221.19,88.85 219.43,88.85 219.19,89.1 219.06,89.42 218.72,89.48 218.62,89.49 218.58,89.57 218.58,90.04 218.63,90.12 218.72,90.13 219.22,90.46 218.72,90.78 218.63,90.79 218.58,90.87 218.58,91.39 218.64,91.45 219.01,91.45 219.19,91.63 219.19,91.82 219.19,91.98 218.58,92.58 218.58,93.12 218.63,93.17 218.98,93.17 219.2,93.39 219.2,93.71 218.59,94.32 218.59,94.53 218.72,94.67 218.99,94.67 219.22,94.91 219.22,95.56 219.32,95.66 220.13,95.66
GND on TOP (solid shape): 285.15,44.75 284.91,44.19 284.35,43.95 283.85,43.95 283.5,43.9 283.18,43.75 280.85,43.75 276.35,48.25 280.85,52.75 285.15,52.75
GND on TOP (solid shape): outline of 102 points within 74.83,109.57 78.33,120.67
GND on TOP (solid shape): outline of 83 points within 86.51,110.35 92.2,120.71
GND on TOP (solid shape): outline of 113 points within 207.55,85.76 210.49,93.73
GND on TOP (solid shape): outline of 149 points within 76.73,47.85 83.52,49.48
GND on TOP (solid shape): outline of 210 points within 212.23,97.4 225.76,115.71
GND on TOP (solid shape): outline of 265 points within 221.72,101.43 226.88,112.86
GND on TOP (solid shape): outline of 276 points within 95.11,109.53 100.79,121.19
GND on TOP (solid shape): outline of 103 points within 0.2,81.55 12.41,118.71
GND on TOP (solid shape): outline of 556 points within 54.67,139.72 97.69,153.62
GND on TOP (solid shape): outline of 1594 points within 207.23,60.19 244.22,77.9
GND on TOP (solid shape): outline of 2802 points within 0.2,0.2 285.15,157.6
GND on BOTTOM (solid shape): 209.68,39.46 206.27,39.46 206.27,43.75 209.68,43.75
GND on BOTTOM (solid shape): 57.05,135.71 57.05,133.55 56.03,132.54 52.86,132.54 52.46,132.93 52.46,135.92 52.76,136.22 56.54,136.22
GND on BOTTOM (solid shape): 69.71,134.33 69.71,131.84 69.52,131.64 66.62,131.64 66.59,131.67 66.59,134.61 66.6,134.62 69.43,134.62
GND on BOTTOM (solid shape): 149.75,39.54 149.75,36.59 149.47,36.3 142.55,36.3 142.25,36.6 142.25,39.16 142.98,39.89 149.4,39.89
GND on BOTTOM (solid shape): 196.68,52.09 196.68,51.05 196.42,50.8 194.72,50.8 194.53,50.99 194.53,52.08 194.72,52.28 196.49,52.28
GND on BOTTOM (solid shape): 198.4,127.92 198.4,127.3 198.11,127.01 192.97,127.01 192.73,127.26 192.73,128.13 192.98,128.38 197.94,128.38
GND on BOTTOM (solid shape): 204.5,114.63 204.5,113.23 204.11,112.85 200.81,112.85 200.43,113.23 200.43,114.76 200.56,114.88 204.24,114.88
GND on BOTTOM (solid shape): 208.03,82.88 208.03,81.83 207.82,81.63 206.56,81.63 206.35,81.84 206.35,82.78 206.53,82.96 207.95,82.96
GND on BOTTOM (solid shape): 213.34,85.06 213.34,82.19 213,81.86 211.15,81.86 210.69,82.32 210.69,85.27 210.85,85.42 212.98,85.42
GND on BOTTOM (solid shape): 217,63.34 217,62.2 216.86,62.07 216.03,62.07 215.91,62.19 215.91,63.32 216.02,63.44 216.9,63.44
GND on BOTTOM (solid shape): 226.01,44.58 226.01,43.26 225.92,43.17 224.48,43.17 224.4,43.25 224.4,44.61 224.5,44.72 225.87,44.72
GND on BOTTOM (solid shape): 227.05,63.14 227.05,62.04 226.93,61.92 226.12,61.92 225.99,62.04 225.99,63.12 226.09,63.22 226.97,63.22
GND on BOTTOM (solid shape): 237.08,63.27 237.08,62.17 236.93,62.02 236.16,62.02 236.02,62.15 236.02,63.23 236.12,63.32 237.03,63.32
GND on BOTTOM (solid shape): 242.2,30.95 242.2,27.75 241.64,27.19 236.67,27.19 235.94,27.92 235.94,30.82 236.39,31.27 241.88,31.27
GND on BOTTOM (solid shape): 243.7,74.27 243.7,72.31 242.97,71.59 239.75,71.59 239.04,72.3 239.04,74.52 239.12,74.61 243.36,74.61
GND on BOTTOM (solid shape): 244.6,38.08 244.6,35.83 244.23,35.46 243.11,35.46 242.99,35.59 242.99,38.06 243.26,38.34 244.34,38.34
GND on BOTTOM (solid shape): 250.22,90.22 250.22,86.56 249.89,86.24 246.86,86.24 246.44,86.66 246.44,90.38 246.59,90.53 249.91,90.53
GND on BOTTOM (solid shape): 257.99,76.53 257.99,73.63 257.27,72.91 254.58,72.91 253.7,73.79 253.7,76.51 253.92,76.73 257.79,76.73
GND on BOTTOM (solid shape): 267.84,78.54 267.84,77.06 267.78,77 264.15,77 264.08,77.06 264.08,78.42 264.34,78.68 267.71,78.68
GND on BOTTOM (solid shape): 276.44,31.51 276.44,29.41 276.06,29.03 273.67,29.03 273.54,29.16 273.54,31.69 274,32.15 275.81,32.15
GND on BOTTOM (solid shape): 281.2,64.97 281.2,62.43 281.08,62.3 274.35,62.3 274.22,62.43 274.22,65.1 274.35,65.23 280.95,65.23
GND on BOTTOM (solid shape): 42,46.32 42,45.09 41.84,44.93 40.27,44.93 40.14,45.07 40.14,46.34 40.28,46.49 41.83,46.49
GND on BOTTOM (solid shape): 199.14,49.33 199.14,47.98 199.09,47.94 197.84,47.94 197.66,48.12 197.66,49.14 197.84,49.33 198.23,49.33 198.27,49.36 199.11,49.36
GND on BOTTOM (solid shape): 223.74,35.79 223.74,32.63 223.57,32.46 223.21,32.46 223.04,32.63 223.04,32.85 222.71,33.17 222.71,35.49 223.14,35.92 223.6,35.92
GND on BOTTOM (solid shape): 239.32,34.11 239.32,32.16 239.18,32.02 237.82,32.02 237.53,32.3 237.53,33.67 238.01,34.15 239.28,34.15
GND on BOTTOM (solid shape): 241.07,85.55 241.07,82.75 240.82,82.5 238.53,82.5 238.4,82.62 238.4,85.8 238.66,86.05 238.66,86.05 238.93,86.32 240.3,86.32
GND on BOTTOM (solid shape): 267.49,89.36 267.49,86.94 267.11,86.56 263.8,86.56 263.68,86.69 263.68,88.67 263.68,89.51 263.77,89.6 267.24,89.6
GND on BOTTOM (solid shape): 278.48,34.88 278.48,32.82 278.26,32.6 275.74,32.6 275.49,32.85 275.49,34.88 275.62,35.01 278.35,35.01
GND on BOTTOM (solid shape): 86.57,121.97 86.57,121.78 86.19,121.4 86.19,120.77 86.07,120.64 85.84,120.64 85.75,120.74 85.75,121.64 86.23,122.12 86.43,122.12
GND on BOTTOM (solid shape): 200.38,32.89 200.38,30.69 199.61,29.91 197.43,29.91 197.16,30.19 197.16,32.37 197.16,32.97 197.31,33.12 200.15,33.12
GND on BOTTOM (solid shape): 23.27,62.15 23.27,58.29 22.07,57.1 21.31,57.1 21.16,56.95 20.6,56.95 20.45,57.1 20.45,59.71 20.9,60.17 20.9,62.67 21.01,62.78 22.64,62.78
GND on BOTTOM (solid shape): 34.16,135.69 34.16,135.46 33.37,134.67 33.37,134.29 32.96,133.88 30.82,133.88 30.6,134.11 30.6,135.02 30.7,135.12 32.52,135.12 33.34,135.94 33.9,135.94
GND on BOTTOM (solid shape): 245.31,55.14 246.09,55.14 246.2,55.03 246.2,53.14 245.13,52.07 239.98,52.07 239.82,52.23 239.82,55.15 239.99,55.32 245.13,55.32
GND on BOTTOM (solid shape): 260.17,58.68 260.17,58 260.13,57.96 255.15,57.96 255.08,58.03 255.08,58.66 255.15,58.73 256.44,58.73 256.45,58.73 257.49,58.73 257.57,58.81 260.04,58.81
GND on BOTTOM (solid shape): 236.49,137.94 236.9,137.94 237.29,137.55 238.5,137.55 238.57,137.48 238.57,136.62 238.38,136.43 236.5,136.43 235.34,137.6 235.34,137.73 235.56,137.95 236.48,137.95
GND on BOTTOM (solid shape): 22.01,36.8 22.01,34.25 21.96,34.14 21.94,34.02 21.94,32.35 21.44,31.85 19.18,31.85 18.87,32.15 18.87,36.82 19.16,37.11 21.7,37.11
GND on BOTTOM (solid shape): 84.9,134.42 84.9,131.61 84.86,131.57 84.02,131.57 83.95,131.49 83.95,130.48 83.41,129.95 82.58,129.95 82.45,130.07 82.45,130.88 81.27,132.06 81.27,134.54 81.3,134.57 84.76,134.57
GND on BOTTOM (solid shape): 229.59,58.1 229.59,56.04 227.32,53.77 227.32,52.72 227.16,52.56 221.89,52.56 221.77,52.69 220.11,52.69 220,52.79 220,54.13 220.14,54.27 221.7,54.27 226.06,58.63 229.06,58.63
GND on BOTTOM (solid shape): 250.93,46.03 250.93,44.75 249.71,43.53 249.71,42.49 249.48,42.26 246.32,42.26 245.25,43.34 245.25,44.35 245.54,44.64 247.11,44.64 247.36,44.89 247.36,45.99 247.63,46.26 250.7,46.26
GND on BOTTOM (solid shape): 259.82,34.31 259.82,34.1 259.36,33.64 259.36,32.71 259.21,32.56 258.83,32.56 258.67,32.71 258.67,33.44 258.18,33.93 258.18,33.95 258.15,33.98 258.15,34.24 258.37,34.45 259.68,34.45
GND on BOTTOM (solid shape): 42.81,50.78 42.81,48.43 42.72,48.34 41.96,48.34 41.9,48.4 41.9,49.93 41.9,49.95 41.71,50.13 39.53,50.13 39.41,50.24 39.41,51.09 39.44,51.12 42.47,51.12
GND on BOTTOM (solid shape): 123.65,65.9 123.65,63.05 123.57,62.97 121.3,62.97 121.27,63 121.27,65.14 120.87,65.54 119.15,65.54 118.77,65.92 118.09,65.92 118.05,65.96 118.05,66.55 118.11,66.62 122.94,66.62
GND on BOTTOM (solid shape): 187.31,55.81 187.31,55.04 186.58,54.31 186.22,54.31 185.88,54.66 185.88,55.49 185.96,55.57 185.96,55.86 186.06,55.95 186.33,55.95 186.33,55.95 187.16,55.95
GND on BOTTOM (solid shape): 219.37,37.56 219.37,35.33 218.86,34.82 215.3,34.82 214.77,34.29 212.89,34.29 212.6,34.57 212.6,37.57 212.7,37.66 216.62,37.66 216.74,37.78 219.15,37.78
GND on BOTTOM (solid shape): 257.13,45.52 257.13,44.72 256.87,44.46 254.74,44.46 254.66,44.54 254.66,45.72 255.23,45.72 255.39,45.75 255.53,45.84 256.81,45.84
GND on BOTTOM (solid shape): 42.04,144.32 42.04,135.94 42.72,135.25 42.72,130.96 42.53,130.77 40.87,130.77 39.52,129.42 36.23,129.42 34.57,131.09 34.57,133.82 36.83,136.08 36.83,144.31 36.98,144.46 41.9,144.46
GND on BOTTOM (solid shape): 32.44,125.24 32.44,124.93 32.75,124.61 33.85,124.61 33.95,124.51 33.95,122.17 33.77,121.99 33.56,121.99 33.24,122.32 32.55,122.32 32.27,122.6 32.27,124.46 32,124.74 32,125.24 32.01,125.26 32.42,125.26
GND on BOTTOM (solid shape): 79.46,122.01 79.46,121.82 79.08,121.45 79.08,120.7 79.02,120.64 78.76,120.64 78.64,120.77 78.64,121.4 78.26,121.78 78.26,121.97 78.38,122.1 78.57,122.1 78.72,121.95 78.99,121.95 79.15,122.12 79.34,122.12
GND on BOTTOM (solid shape): 217.57,142 217.57,140.79 217.38,140.6 215.57,140.6 215.55,140.62 214.96,140.62 214.58,140.24 214.48,140.24 214.33,140.39 214.33,140.6 214.94,141.21 216.56,141.21 216.81,141.46 216.81,142 216.94,142.13 217.45,142.13
GND on BOTTOM (solid shape): 69.29,121.93 69.51,121.93 69.68,122.11 69.92,122.11 70.04,121.98 70.04,121.83 69.67,121.46 69.67,120.84 69.46,120.63 69.32,120.63 69.18,120.77 69.18,121.38 68.76,121.8 68.76,121.97 68.9,122.11 69.12,122.11
GND on BOTTOM (solid shape): 76.39,121.93 76.59,121.93 76.79,122.13 76.95,122.13 77.11,121.97 77.11,121.78 76.73,121.4 76.73,120.77 76.6,120.64 76.35,120.64 76.29,120.7 76.29,121.41 75.9,121.8 75.9,121.99 76.04,122.13 76.19,122.13
GND on BOTTOM (solid shape): 81.8,121.99 81.8,121.8 81.43,121.42 81.43,120.7 81.37,120.64 81.11,120.64 80.99,120.77 80.99,121.4 80.6,121.78 80.6,121.97 80.73,122.1 80.92,122.1 81.07,121.95 81.32,121.95 81.5,122.13 81.67,122.13
GND on BOTTOM (solid shape): 199.25,124.87 199.25,124.06 198.89,123.7 197.37,123.7 197.09,123.43 196.36,123.43 196.36,123.42 193.85,123.42 193.7,123.27 192.32,123.27 191.97,123.62 191.97,124.44 192.12,124.59 193.03,124.59 193.22,124.4 197.1,124.4 197.83,125.14 198.99,125.14
GND on BOTTOM (solid shape): 201.18,68.97 201.18,66.43 200.85,66.09 200.47,66.09 200.36,65.98 200.36,65.35 200.26,65.26 198.75,65.26 198.72,65.29 198.72,66.13 198.86,66.28 199.12,66.28 199.44,66.6 199.44,68.94 199.5,69 201.16,69
GND on BOTTOM (solid shape): 208.06,76.9 208.06,76.11 207.98,76.02 206.37,76.02 206.09,75.74 206.09,75.36 206,75.27 203.11,75.27 202.92,75.08 200.67,75.08 200.56,75.19 200.56,75.99 200.68,76.11 201.04,76.11 201.23,76.31 201.23,76.87 201.33,76.96 208,76.96
GND on BOTTOM (solid shape): 20.25,132.61 20.25,132 20.2,131.95 19.97,131.95 19.91,132.01 19.91,132.21 19.78,132.34 19.24,132.34 18.95,132.06 18.48,132.06 17.6,131.17 13.43,131.17 13.38,131.22 13.38,131.87 13.46,131.96 17.39,131.96 18.46,133.03 19.83,133.03
GND on BOTTOM (solid shape): 37.5,69.76 37.5,68.75 38.54,67.71 38.54,66.12 38.44,66.02 38.44,66.02 38.41,65.99 38.05,65.99 37.83,65.77 37.83,65.31 37.73,65.21 35.3,65.21 34.84,65.67 34.84,67.75 35.55,68.45 36.26,68.45 36.42,68.61 36.42,69.83 36.51,69.92 37.34,69.92
GND on BOTTOM (solid shape): 214.71,137.99 214.85,137.99 214.91,137.93 217.78,137.93 217.94,137.77 217.94,137.04 217.63,136.73 215.4,136.73 214.83,137.31 214.82,137.32 214.76,137.45 214.65,137.54 214.65,137.57 214.28,137.94 214.28,138.13 214.43,138.28
GND on BOTTOM (solid shape): 18.27,2.9 18.27,1.97 18.04,1.64 17.86,1.27 11.27,1.27 11.27,2.93 11.74,2.93 11.8,2.92 11.87,2.93 13.55,2.93 14.2,2.28 15.1,2.28 15.99,3.17 18,3.17
GND on BOTTOM (solid shape): 15.36,21.84 15.36,20.92 15.06,20.62 4.35,20.62 4.35,22 4.44,22.21 4.65,22.3 13.1,22.3 13.16,22.3 13.21,22.31 14.89,22.31
GND on BOTTOM (solid shape): 88.12,122.03 88.21,121.95 88.4,121.95 88.43,121.97 88.48,121.97 88.61,122.1 88.8,122.1 88.92,121.97 88.92,121.78 88.54,121.4 88.54,120.77 88.42,120.64 88.16,120.64 88.1,120.7 88.1,121.37 87.7,121.77 87.7,121.99 87.84,122.13 88.03,122.13
GND on BOTTOM (solid shape): 164.02,55.53 164.02,54.63 164.02,54.61 164.19,54.44 164.21,54.44 164.23,54.41 164.41,54.41 164.55,54.55 164.7,54.55 165.17,54.09 165.17,53.87 165.1,53.8 164.62,53.8 164.51,53.92 158.51,53.92 157.15,55.28 154.99,55.28 154.89,55.39 154.89,55.94 154.94,56 163.55,56
GND on BOTTOM (solid shape): 217.83,151.59 225.27,151.59 225.76,151.1 225.76,151.07 225.52,150.83 225.41,150.66 225.37,150.46 225.37,150.44 225.17,150.25 217.56,150.25 217.56,150.25 216.62,150.25 216.39,150.01 215.45,150.01 215.27,150.2 215.27,151.11 215.76,151.61 217.82,151.61
GND on BOTTOM (solid shape): 194.13,31.68 194.13,30.92 194.44,30.62 194.98,30.62 195.1,30.5 195.1,29.78 194.54,29.78 194.13,30.19 193.56,30.19 193.44,30.06 193.41,30.06 193.41,29.81 193.31,29.71 192.94,29.71 192.82,29.84 192.82,29.95 192.83,30.04 192.84,30.12 192.84,30.63 192.83,30.71 192.82,30.8 192.82,31.16 193.44,31.78 194.03,31.78
GND on BOTTOM (solid shape): 91.3,122 91.3,121.81 90.89,121.4 90.89,120.7 90.83,120.64 90.57,120.64 90.45,120.77 90.45,121.4 90.07,121.78 90.07,121.97 90.19,122.1 90.38,122.1 90.51,121.97 90.57,121.97 90.58,121.97 90.66,121.96 90.74,121.97 90.75,121.97 90.8,121.97 90.96,122.13 91.17,122.13
GND on BOTTOM (solid shape): 186.38,32.82 186.5,32.79 186.62,32.81 186.62,32.81 186.71,32.81 187.01,32.52 187.01,31.72 187.01,31.72 187.01,31.52 186.88,31.39 186.54,31.39 186.44,31.49 186.44,31.85 186.32,31.97 186.2,32.05 186.06,32.08 186.04,32.09 185.91,32.21 185.91,32.47 185.87,32.51 185.87,32.76 185.94,32.82
GND on BOTTOM (solid shape): 33.43,50.91 33.69,50.91 33.8,50.8 33.8,50.42 33.96,50.26 34.26,50.26 34.65,49.87 34.69,49.81 34.75,49.77 34.85,49.67 35.41,49.67 35.54,49.54 35.54,47.97 34.7,47.13 33.8,47.13 33.65,47.28 33.33,47.28 33.15,47.46 33.15,47.89 33.28,48.02 33.28,48.75 32.8,49.23 32.8,49.56 32.6,49.76 32.6,50.97 32.76,51.13 33.21,51.13
GND on BOTTOM (solid shape): 92.8,122.1 92.85,122.03 92.94,121.97 93.02,121.96 93.11,121.97 93.11,121.97 93.18,121.97 93.3,122.1 93.5,122.1 93.62,121.97 93.62,121.78 93.24,121.4 93.24,120.77 93.11,120.64 92.86,120.64 92.8,120.7 92.8,121.39 92.43,121.76 92.43,122.03 92.55,122.15 92.74,122.15
GND on BOTTOM (solid shape): 229.74,38.89 229.74,37.01 229.41,36.68 228.36,36.68 228.35,36.71 228.22,36.86 228.03,36.92 227.85,36.92 227.74,37.03 227.74,37.95 227.64,38.05 224.46,38.05 224.41,38.1 224.41,39.29 224.46,39.34 229.29,39.34
GND on BOTTOM (solid shape): 13.1,46.15 14.73,46.15 15.44,45.43 15.44,44.93 15.8,44.56 15.8,36.81 15.25,36.25 4.65,36.25 4.48,36.33 4.4,36.5 4.4,45.9 4.48,46.07 4.65,46.15 9.8,46.15
GND on BOTTOM (solid shape): 201.48,64 201.48,61.76 201.4,61.68 200.57,61.68 200.51,61.74 200.53,61.78 200.49,62.18 200.09,62.28 200.08,62.28 199.86,62.28 199.7,62.44 199.7,63.83 199.78,63.92 200.38,63.92 200.49,64.02 200.67,64.02 200.75,64.1 201.38,64.1
GND on BOTTOM (solid shape): 42.88,129.5 42.88,125.62 42.61,125.35 42.55,125.36 42.51,125.36 42.31,125.36 42.26,125.36 42.2,125.35 41.51,125.35 41.44,125.42 41.44,125.53 41.45,125.54 41.48,125.69 41.45,125.85 41.44,125.86 41.44,125.9 41.38,125.97 41.3,126.05 41.3,126.28 41.28,126.3 41.28,129.42 41.53,129.67 42.72,129.67
GND on BOTTOM (solid shape): 164.24,33.99 164.24,33.75 164.48,33.52 164.49,33.49 164.49,33.11 164.67,32.93 164.73,32.87 165.14,32.87 165.19,32.82 165.19,32.5 165.17,32.48 164.6,32.48 164.42,32.3 164.42,32.17 164.39,32.15 164.38,32.13 164.3,32.04 164.18,32.05 164.17,32.05 164.12,32.06 162.74,32.06 162.54,32.26 162.54,33.15 163.63,34.24 164,34.24
GND on BOTTOM (solid shape): 222.68,32.57 222.68,32.24 223.1,31.82 223.12,31.82 223.13,31.8 223.42,31.67 223.7,31.82 227.74,31.82 229.07,30.48 229.07,28.21 228.12,27.25 225.83,27.25 225.83,27.26 225.15,27.26 222.86,29.54 221.58,29.54 221.36,29.76 221.36,32.03 221.37,32.03 221.37,32.55 221.44,32.62 222.62,32.62
GND on BOTTOM (solid shape): 88.04,57.22 88.07,57.26 88.12,57.25 89.36,56.02 90.56,56.02 90.9,55.68 90.9,55.43 90.85,55.35 90.76,55.34 90.52,55.36 90.33,55.22 90.15,55.22 89.77,54.84 88.93,54.84 88.76,55.01 88.76,56.43 88.04,57.16
GND on BOTTOM (solid shape): 104.41,138.92 104.41,138.29 104.68,138.02 105.71,138.02 105.78,137.95 105.78,136.55 105.7,136.47 104.49,136.47 104.29,136.27 104.29,132.96 103.83,132.49 103.83,130.84 104.19,130.48 107.79,130.48 108.08,130.77 108.08,132.89 108.19,133 109.67,133 109.85,132.82 109.85,130.76 107.67,128.58 101.47,128.58 100.81,129.23 100.81,132.92 102.09,134.19 102.09,137.3 102.09,137.93 102.14,137.98 103.43,137.98 103.47,137.93 103.47,137.43 103.51,137.39 104.06,137.39 104.08,137.42 104.08,138.89 104.13,138.94 104.38,138.94
GND on BOTTOM (solid shape): 72.37,122.01 72.37,121.74 72.32,121.69 72.28,121.63 71.95,121.29 71.95,120.77 71.85,120.67 71.65,120.67 71.54,120.78 71.54,121.31 71.26,121.59 71.25,121.6 71.2,121.7 71.12,121.76 71.1,121.78 71.1,121.97 71.24,122.11 71.51,122.11 71.61,122.01 71.63,122 71.83,121.96 71.99,122.09 71.99,122.1 72.03,122.13 72.24,122.13
GND on BOTTOM (solid shape): 73.89,122.11 73.9,122.1 74.06,121.97 74.26,122 74.29,122.01 74.41,122.13 74.6,122.13 74.73,122.01 74.73,121.81 74.35,121.43 74.35,120.8 74.22,120.67 74.03,120.67 73.94,120.76 73.94,121.3 73.6,121.63 73.6,121.64 73.54,121.72 73.46,121.78 73.46,121.99 73.52,122.03 73.57,122.1 73.6,122.13 73.87,122.13
GND on BOTTOM (solid shape): 215.93,53.69 215.93,48.02 215.63,47.72 214.84,47.72 214.66,47.9 214.66,49.21 214.41,49.46 213.74,49.46 213.34,49.86 213.33,49.86 213.31,49.88 212.35,49.88 211.82,49.35 210.74,49.35 210.21,49.88 210.18,49.88 210.18,49.89 209.22,49.89 209.21,49.88 208.92,49.88 208.86,49.83 208.66,49.83 208.53,49.96 208.53,50.19 208.64,50.29 208.89,50.29 208.96,50.22 210.31,50.22 210.73,50.64 213.26,50.64 213.47,50.43 214.44,50.43 214.46,50.44 214.64,50.63 214.65,50.64 214.65,52.45 214.64,52.45 214.64,52.49 214.3,52.83 214.3,54.01 214.53,54.24 215.37,54.24
GND on BOTTOM (solid shape): 84.19,122 84.19,121.75 84.13,121.69 84.09,121.61 84.08,121.6 83.92,121.43 83.92,120.82 83.76,120.67 83.48,120.67 83.36,120.79 83.36,121.31 83.06,121.6 83.06,121.61 83.01,121.7 82.92,121.77 82.92,121.96 83.06,122.1 83.33,122.1 83.37,122.06 83.39,122.03 83.45,121.99 83.64,121.96 83.79,122.08 83.84,122.13 84.07,122.13
GND on BOTTOM (solid shape): 44.92,117.24 45.48,117.24 45.49,117.24 46.62,117.24 46.68,117.24 47.01,117.24 47.37,117.6 48.54,117.6 48.94,117.21 49.77,117.21 49.85,117.13 49.85,116.96 49.78,116.89 48.96,116.89 48.93,116.85 48.88,116.85 48.47,116.44 46.71,116.44 46.69,116.42 45.85,116.42 45.85,116.42 45.38,116.42 45.3,116.5 44.6,116.5 44.48,116.37 44.48,114.63 44.66,114.45 44.66,112.9 44.48,112.72 44.48,110.69 44.16,110.37 43.65,110.37 43.21,110.82 43.21,116.46 43.18,116.49 43.04,116.63 43.04,117.54 43.04,117.54 42.98,117.6 42.98,118.01 43.17,118.2 43.96,118.2
GND on BOTTOM (solid shape): 123.17,61.51 123.17,60.79 123.36,60.59 124.26,60.59 124.38,60.46 124.38,59.84 124.75,59.48 125.35,59.48 125.53,59.31 125.53,57.97 125.53,57.93 125.68,57.78 125.68,56.9 125.56,56.78 125.56,55.87 125.97,55.46 125.97,54.22 125.67,53.92 125.67,53.91 125.55,53.79 125.55,52.63 125.67,52.51 125.67,52.13 125.42,51.88 125.16,51.88 125.07,51.98 125.07,52.45 125.26,52.64 125.26,53.74 124.9,54.1 124.9,55.87 124.85,55.92 124.85,58.01 124.59,58.26 122.97,58.26 122.56,57.86 121.37,57.86 121.24,57.99 121.24,59.11 121.61,59.49 121.84,59.49 121.94,59.58 121.94,60.36 122.38,60.79 122.38,61.44 122.5,61.57 123.1,61.57
GND on BOTTOM (solid shape): 58.04,150.4 58.04,149.45 58.04,148.23 58.04,148.02 58.12,147.94 60.92,147.94 61.09,148.11 62.98,148.11 63.14,147.95 63.14,147.29 63.15,147.29 63.15,144.08 62.98,143.91 60.46,143.91 60.23,144.15 60.23,145.88 60.21,145.9 56.34,145.9 56.34,147.04 56.39,147.08 56.89,147.08 56.92,147.12 56.92,147.68 56.88,147.73 55.28,147.73 55.23,147.67 54.83,147.67 54.72,147.78 54.72,148.03 54.82,148.13 55.29,148.13 55.36,148.06 56.08,148.06 56.34,148.31 56.34,149.4 56.36,149.43 57.53,149.43 57.66,149.55 57.66,149.73 57.66,150.35 57.77,150.47 57.97,150.47
GND on BOTTOM (solid shape): 29.66,88.59 29.73,88.57 29.81,88.57 29.84,88.57 30.04,88.56 30.1,88.58 31.22,88.58 31.32,88.47 31.33,88.45 31.39,88.32 31.52,88.26 31.54,88.26 31.72,88.07 31.75,88.04 31.75,87.86 31.74,87.85 31.69,87.67 31.74,87.49 31.75,87.47 31.75,87.32 31.7,87.27 31.46,87.27 31.36,87.37 30.82,87.37 30.78,87.34 29.58,87.34 29.44,87.48 29.44,88.42 29.63,88.61
GND on BOTTOM (solid shape): 115.49,140.39 115.49,136.75 115.09,136.35 111.79,136.35 111.53,136.6 111.53,138.79 111.81,138.79 111.81,138.73 111.82,138.68 111.83,138.63 111.86,138.58 111.89,138.54 111.92,138.5 111.97,138.46 112.01,138.44 112.06,138.42 112.11,138.41 112.17,138.4 112.22,138.41 112.27,138.42 112.32,138.44 112.37,138.46 112.41,138.5 112.45,138.54 112.48,138.58 112.5,138.63 112.51,138.68 112.52,138.73 112.52,138.79 112.51,138.84 112.5,138.89 112.48,138.94 112.45,138.98 112.41,139.02 112.37,139.05 112.32,139.08 112.27,139.1 112.22,139.11 112.17,139.12 112.11,139.11 112.06,139.1 112.01,139.08 111.97,139.05 111.92,139.02 111.89,138.98 111.86,138.94 111.83,138.89 111.82,138.84 111.81,138.79 111.53,138.79 111.53,139.47 112.53,140.47 115.42,140.47
GND on BOTTOM (solid shape): 74.55,151.12 74.55,150.22 74.55,150.22 74.55,149 74.55,148.77 74.64,148.68 77.42,148.68 77.58,148.84 79.1,148.84 79.27,148.67 79.27,148.32 79.34,148.25 79.34,148.19 79.34,147.97 79.65,147.66 79.65,145.15 79.31,144.8 77.2,144.8 76.73,145.27 76.73,146.52 76.73,146.52 76.73,146.68 72.88,146.68 72.88,147.88 73.33,147.88 73.39,147.88 73.39,148.49 71.78,148.49 71.72,148.44 71.33,148.44 71.22,148.55 71.22,148.76 71.36,148.9 71.39,148.9 71.45,148.89 71.52,148.9 71.71,148.9 71.78,148.83 72.6,148.83 72.85,149.08 72.85,150.17 72.87,150.19 74.04,150.19 74.21,150.36 74.21,151.12 74.31,151.22 74.45,151.22
GND on BOTTOM (solid shape): 139.74,57.25 139.74,56.56 139.12,55.94 133.76,55.94 133.19,55.38 133.19,50.66 133.85,50 133.85,47.42 134.05,47.22 135.34,47.22 135.64,47.51 135.64,47.8 135.92,48.09 138.97,48.09 139.16,47.9 139.16,47.48 139.05,47.38 139.05,45.56 138.97,45.47 135.77,45.47 135.71,45.54 133.53,45.54 133.5,45.5 133.39,45.5 133.39,45.4 133.29,45.29 133.29,42.98 133.89,42.38 137.64,42.38 138.02,42 138.02,41.31 137.41,40.7 133.81,40.7 133.32,40.21 128.65,40.21 128.47,40.38 128.47,41.31 128.7,41.54 131.2,41.54 131.41,41.74 131.41,45.05 131.54,45.18 131.54,50.86 131.1,51.29 131.1,54.51 130.98,54.64 130.12,54.64 129.93,54.82 129.93,55.49 129.98,55.53 129.98,56.97 130.15,57.14 135.2,57.14 135.61,57.56 139.43,57.56
GND on BOTTOM (solid shape): 66.29,151.15 66.29,150.22 66.29,150.22 66.29,148.75 66.36,148.69 69.01,148.69 69.17,148.84 70.99,148.84 71.07,148.81 71.09,148.73 71.11,148.53 71.22,148.38 71.22,148.24 71.4,148.06 71.4,144.93 71.25,144.78 69.1,144.78 69.1,144.78 68.97,144.78 68.5,145.24 68.5,146.48 68.47,146.52 68.47,146.66 68.46,146.66 64.62,146.66 64.62,147.88 65.08,147.88 65.13,147.88 65.13,148.49 63.5,148.49 63.45,148.44 63.08,148.44 62.96,148.55 62.96,148.77 63.08,148.89 63.49,148.89 63.56,148.82 64.34,148.82 64.59,149.08 64.59,150.17 64.62,150.19 65.79,150.19 65.91,150.32 65.91,151.11 66.04,151.23 66.21,151.23
GND on BOTTOM (solid shape): 57.42,120.49 57.42,117.49 57.53,117.38 58.07,117.38 58.15,117.3 58.15,111.42 58.07,111.33 56.35,111.33 55.95,111.74 55.95,114.03 55.79,114.19 55.79,114.34 56.87,114.34 56.87,114.28 56.89,114.23 56.91,114.18 56.93,114.14 56.97,114.09 57,114.06 57.05,114.03 57.1,114 57.15,113.99 57.2,113.98 57.25,113.98 57.31,113.99 57.36,114 57.41,114.03 57.45,114.06 57.49,114.09 57.52,114.14 57.55,114.18 57.57,114.23 57.58,114.28 57.58,114.34 57.58,114.39 57.57,114.44 57.55,114.49 57.52,114.54 57.49,114.58 57.45,114.62 57.41,114.65 57.36,114.67 57.31,114.68 57.25,114.69 57.2,114.69 57.15,114.68 57.1,114.67 57.05,114.65 57,114.62 56.97,114.58 56.93,114.54 56.91,114.49 56.89,114.44 56.87,114.39 56.87,114.34 55.79,114.34 55.79,119.32 55.95,119.47 55.95,120.28 56.32,120.66 57.25,120.66
GND on BOTTOM (solid shape): 34.11,95.21 34.11,95.19 34.1,95.13 34.11,95.06 34.11,94.89 34.31,94.69 35.6,94.69 35.62,94.69 35.75,94.66 35.88,94.69 35.89,94.69 35.95,94.69 35.96,94.7 36.17,94.7 36.24,94.68 36.33,94.59 36.33,94.21 36.29,94.18 36.29,93.83 36.21,93.75 36.21,93.37 36.18,93.35 35.74,93.35 35.64,93.44 35.64,93.93 35.54,94.03 33.24,94.03 33.18,93.97 33.12,93.97 33.12,93.91 32.99,93.78 31.27,93.78 31.2,93.84 31.2,94.46 31.25,94.51 31.3,94.51 31.44,94.48 31.56,94.5 31.57,94.51 31.88,94.51 31.88,94.5 32.5,95.13 33.34,95.13 33.55,95.34 33.99,95.34
GND on BOTTOM (solid shape): 256.96,34.57 256.96,34.36 256.92,34.31 256.35,33.74 256.35,31.85 256.25,31.75 255.65,31.75 254.61,32.79 254.61,33.54 254.85,33.78 255.09,33.78 255.28,33.97 255.28,34.44 255.28,34.54 255.42,34.68 255.61,34.68 255.74,34.54 255.74,34.16 255.87,34.03 256.18,34.03 256.35,34.2 256.48,34.34 256.47,34.43 256.46,34.49 256.48,34.55 256.48,34.56 256.53,34.63 256.61,34.68 256.7,34.72 256.81,34.72
GND on BOTTOM (solid shape): 74.97,65.72 74.97,65.71 75.24,65.48 75.58,65.6 75.65,65.64 75.73,65.61 75.86,65.47 75.94,65.47 75.98,65.42 75.98,65.04 75.69,64.74 75.69,64.56 75.62,64.47 75.51,64.49 75.41,64.57 75.28,64.61 75.27,64.61 75.01,64.87 75.01,65.42 74.68,65.74 74.27,65.74 73.97,65.45 73.97,64.38 74.36,63.99 74.36,63.89 74.3,63.8 74.19,63.82 73.86,64.15 73.86,64.69 73.64,64.91 73.64,65.64 74.05,66.05 74.63,66.05
GND on BOTTOM (solid shape): 86.54,57.03 86.6,57.12 86.71,57.1 87.4,56.41 87.4,56.39 87.71,56.06 88.09,56.3 88.17,56.36 88.26,56.34 88.34,56.26 88.34,54.95 88.29,54.86 88.19,54.85 88.17,54.87 88.11,54.92 88.11,55 88.07,55.35 87.75,55.5 87.73,55.5 86.54,56.69
GND on BOTTOM (solid shape): 109.34,72.3 109.36,72.2 109.28,72.13 109.06,72.01 108.97,71.77 108.97,71.3 108.91,71.18 108.89,71.05 108.89,70.1 109.77,69.22 109.77,69.01 109.71,68.91 109.6,68.94 109.37,69.04 109.14,68.98 109.1,68.95 108.5,69.55 108.5,70.02 108.63,70.15 108.68,70.33 108.68,71.77 108.63,71.96 108.5,72.09 108.45,72.16 108.48,72.25 108.55,72.34 108.59,72.45 108.59,72.47 108.69,72.57 109.07,72.57
GND on BOTTOM (solid shape): 83.54,69.8 83.6,69.89 83.71,69.87 84.08,69.5 84.08,69.48 84.42,69.09 84.79,69.46 84.85,69.56 84.96,69.53 85.87,68.62 86.91,68.62 86.92,68.62 87.1,68.61 87.27,68.7 87.38,68.72 87.44,68.63 87.44,68.01 87.38,67.92 87.27,67.94 86.99,68.03 86.73,67.89 86.39,67.89 85.65,68.64 84.12,68.64 83.54,69.22
GND on BOTTOM (solid shape): 5.35,66.25 5.57,65.72 6.1,65.5 6.9,65.5 7.43,65.72 7.65,66.25 7.65,66.7 11.3,66.7 13.81,64.19 14.9,64.19 15.2,63.88 15.2,60.55 14.79,60.15 13.18,60.15 13.14,60.15 13.1,60.15 4.65,60.15 4.48,60.23 4.4,60.4 4.4,60.83 4.4,64 4.18,64.53 3.65,64.75 0.6,64.75 0.43,64.83 0.35,65 0.35,66.45 0.43,66.62 0.6,66.7 5.35,66.7
GND on BOTTOM (solid shape): 285.15,44.75 284.91,44.19 284.35,43.95 283.85,43.95 283.5,43.9 283.18,43.75 280.85,43.75 276.35,48.25 280.85,52.75 285.15,52.75
GND on BOTTOM (solid shape): outline of 108 points within 79.47,139.25 97.93,151.23
GND on BOTTOM (solid shape): outline of 147 points within 256.31,35 261.39,38.3
GND on BOTTOM (solid shape): outline of 170 points within 10.8,111 21,118.2
GND on BOTTOM (solid shape): outline of 147 points within 208.6,62.05 240.2,72.51
GND on BOTTOM (solid shape): outline of 85 points within 220.15,84.43 231.33,87.98
GND on BOTTOM (solid shape): outline of 206 points within 247.12,26.48 254.38,32.04
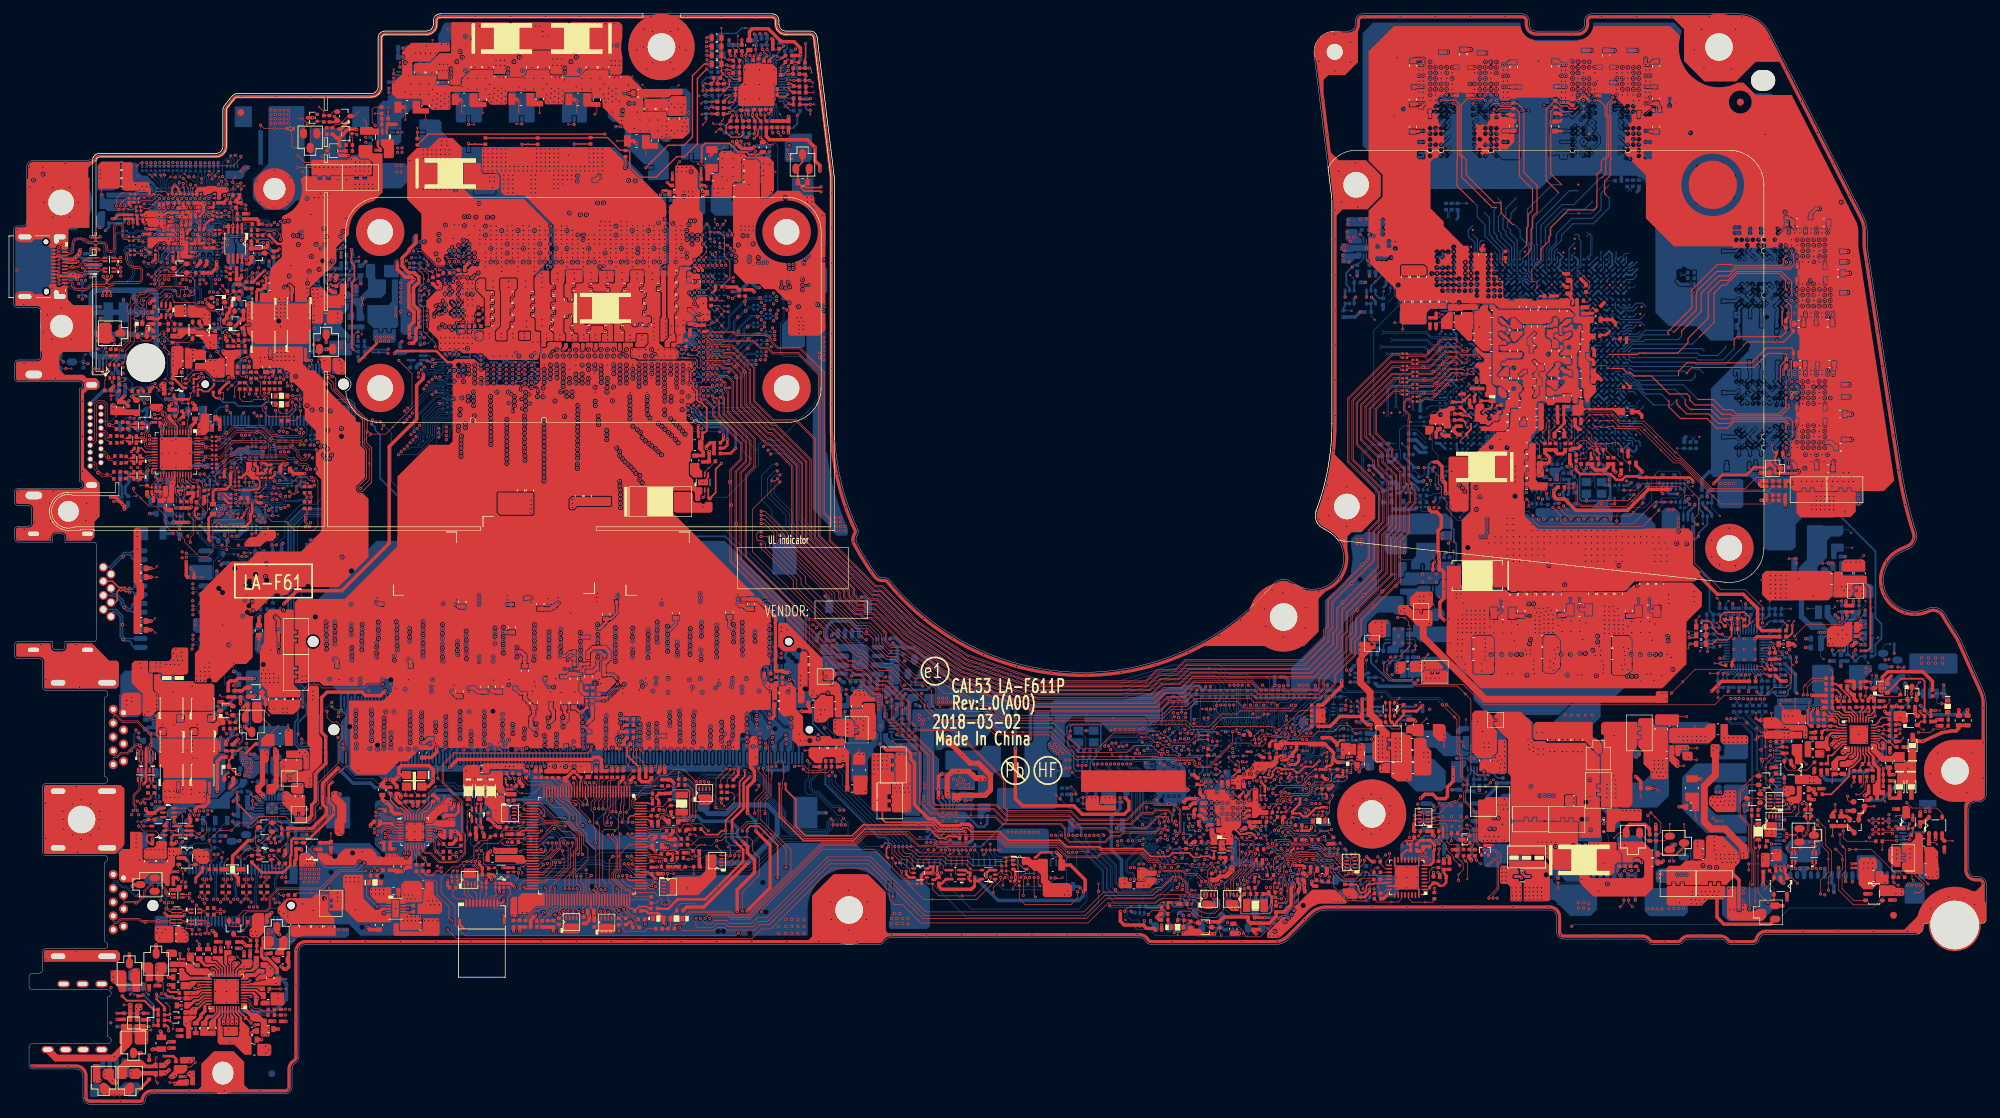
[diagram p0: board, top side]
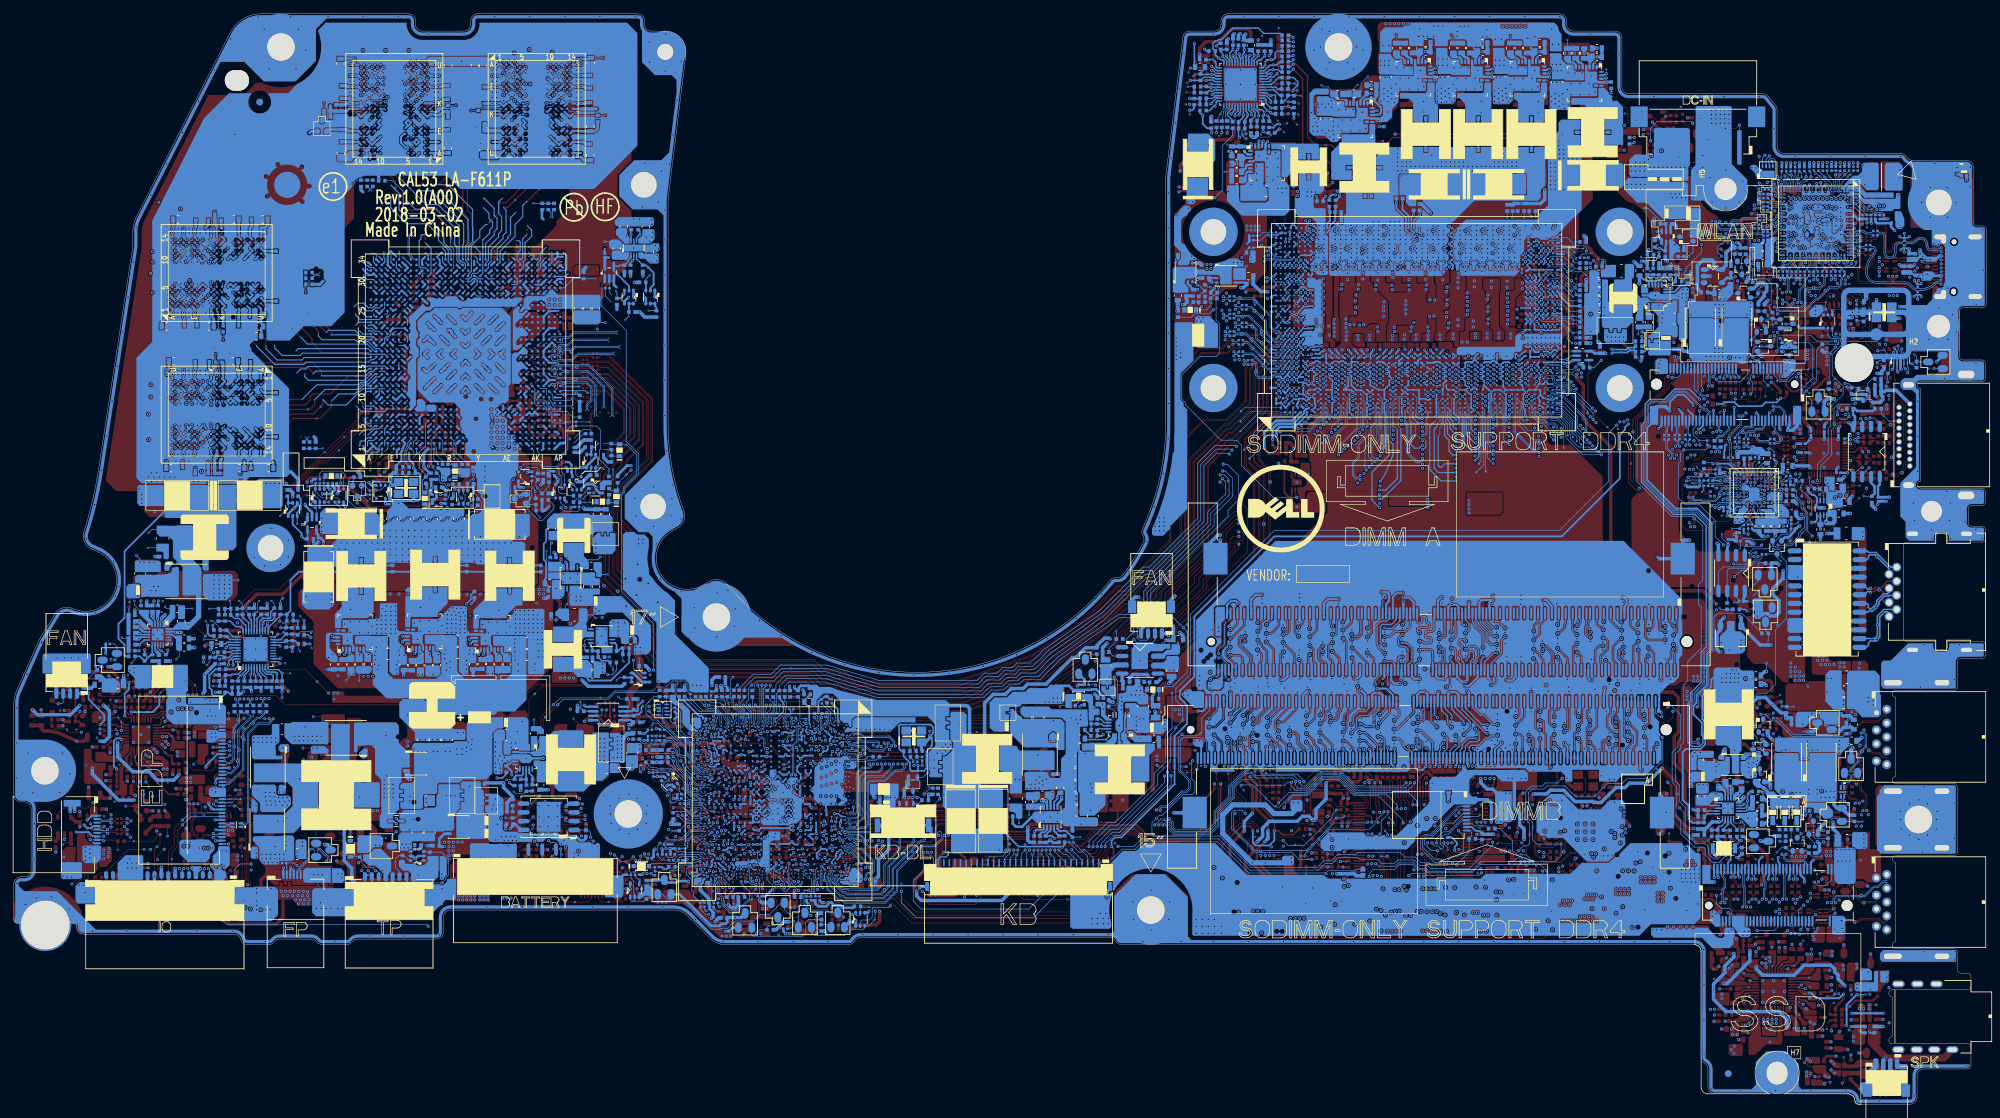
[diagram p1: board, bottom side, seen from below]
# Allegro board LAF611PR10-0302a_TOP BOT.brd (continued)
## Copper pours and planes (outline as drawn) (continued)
GND on BOTTOM (solid shape): outline of 82 points within 22.55,131.42 26.68,132.18
GND on BOTTOM (solid shape): 41.05,6.8 41.02,6.6 40.95,6.41 40.92,6.37 40.89,6.32 40.86,6.29 40.83,6.25 40.78,6.21 40.73,6.16 40.69,6.14 40.55,6.05 40.47,5.98 40.42,5.94 40.38,5.9 40.3,5.81 40.23,5.71 40.09,5.4 40.05,5.07 40.05,2.5 40.01,2.27 39.91,2.05 39.62,1.8 39.25,1.7 37.11,1.7 20,1.7 19.22,1.42 18.81,0.69 18.8,0.59 18.8,0.5 18.72,0.3 18.54,0.21 18.5,0.2 12.43,0.2 11,0.2 10.69,0.26 10.44,0.44 10.26,0.7 10.2,1 10.2,3.4 10.2,4.1 10.17,4.4 10.05,4.68 9.61,5.14 9,5.3 2.71,5.3 2.7,5.3 2.49,5.39 2.4,5.6 2.4,5.76 9,5.76 10.17,5.27 10.66,4.1 10.66,1 10.76,0.76 11,0.66 18.35,0.66 18.88,1.73 20,2.16 26.7,2.16 27.12,2.58 27.12,5.82 28.96,7.66 31.79,7.66 33.33,6.12 33.33,2.78 33.95,2.16 39.25,2.16 39.49,2.26 39.59,2.5 39.59,5.07 39.81,5.9 40.54,6.63 40.59,6.8 40.59,13.32 41.05,13.32
GND on BOTTOM (solid shape): outline of 101 points within 32.31,86.71 35.38,89.97
GND on BOTTOM (solid shape): outline of 400 points within 61.42,152.22 87.68,156.53
GND on BOTTOM (solid shape): outline of 1067 points within 163.42,43.21 170.1,50.35
GND on BOTTOM (solid shape): outline of 1804 points within 19.35,123.12 29.41,130.87
GND on BOTTOM (solid shape): outline of 2905 points within 0.2,8.3 285.15,157.6
GND on BOTTOM (solid shape): outline of 19999 points within 43.95,46.68 114.3,81.53
GND on GND1: outline of 381 points within 0.2,0.2 285.15,157.6
GND on VCC: 45.24,63.57 45.24,65.41 43.97,66.68 43.97,75.84 46.63,78.51 46.63,83.72 49.56,86.64 49.56,88.41 51.71,90.57 51.71,96.59 52.15,96.59 56.92,101.37 56.92,105.1 61.37,105.1 61.37,109.67 61.37,109.68 94.31,109.68 94.51,109.88 94.51,110.55 94.53,110.56 104.17,110.56 104.17,98.32 109.88,92.61 109.88,89.94 110.52,89.3 110.52,63.57
GND on VCC: 11,0.25 10.47,0.47 10.25,1 10.25,4.1 9.89,4.99 9,5.35 2.7,5.35 2.53,5.43 2.45,5.6 2.45,5.85 2.51,5.79 14.66,5.79 17.07,8.2 19.61,8.2 19.89,8.48 23.62,8.48 24.97,9.83 29.21,9.83 29.49,10.11 29.49,12.24 30.07,12.82 30.07,12.93 30.05,12.95 30.05,14.26 29.91,14.4 28.05,14.4 27.86,14.21 27.86,13.33 27.36,12.82 27.36,12.56 26.68,11.89 26.64,11.89 26.39,11.63 26.14,11.63 25.63,11.12 24.84,11.12 24.49,11.48 24.49,12.62 23.14,13.97 23.14,14.32 23.6,14.78 25.65,14.78 26.03,15.16 26.74,15.16 27.4,15.82 28.74,15.82 28.96,16.03 28.96,18.07 29.02,18.13 32.83,18.13 33.6,18.9 34.74,18.9 35.33,19.49 35.33,6.63 36.3,5.66 40.2,5.66 40.09,5.38 40.05,5.07 40.05,2.5 39.81,1.94 39.25,1.7 38.21,1.7 38.21,1.75 20,1.75 19.11,1.39 18.67,0.33 18.5,0.25
GND on VCC: 235.23,43.51 235.23,67.56 234.9,67.89 211.99,67.89 211.99,63.83 208.49,63.83 204.8,67.51 173.52,67.51 178.25,70.94 182.37,75.07 183.41,75.67 184.59,75.45 185.5,74.92 190.83,75.26 192.47,80.34 197.18,80.34 199.8,82.95 199.8,123.14 190.95,123.14 190.95,130.64 190.95,130.96 190.92,131.28 188.38,151.97 189.04,154.12 191.1,155.04 193.1,155.04 193.99,155.41 194.35,156.3 194.35,156.8 194.57,157.33 195.1,157.54 213.77,157.54 213.77,157.55 218.25,157.55 218.78,157.33 219,156.8 219,156.3 219.36,155.41 220.25,155.05 226.25,155.05 227.14,155.41 227.5,156.3 227.5,156.8 227.72,157.33 228.25,157.55 249.59,157.55 252.07,156.85 253.82,154.95 260.06,142.71 260.06,142.71 267.36,128.37 267.75,127.33 267.88,126.22 267.88,124.5 267.89,124.1 267.94,123.7 272.87,91.65 273.75,87.15 274.98,82.73 274.91,81.49 274.03,80.6 273.07,80.18 270.66,73.9 276.94,71.49 276.98,71.51 278.23,71.57 279.2,70.79 279.2,70.78 279.79,69.8 280.39,68.83 280.72,68.31 281.06,67.79 281.26,67.46 281.43,67.11 281.98,65.87 280.6,65.87 280.6,65.86 254.66,65.86 254.66,43.51 ; 1 cut-out
GND on VCC: 18.11,122.5 13.54,127.07 1.89,127.07 2.05,127.32 2.1,127.6 2.1,135.6 2.32,136.13 2.85,136.34 10.67,136.34 11.3,136.51 12.03,137.25 12.4,137.34 29.25,137.34 30.14,137.71 30.5,138.6 30.5,144.18 30.56,144.29 30.63,144.4 31.71,145.75 31.86,145.89 32.05,145.99 40.28,145.99 40.28,133.75 43.33,130.71 43.33,122.5
GND on VCC: 115.58,129.14 115.58,129.15 114.15,129.15 113.16,130.13 113.16,139.58 113.09,139.65 101.17,139.65 100.61,140.21 100.61,148.08 100.15,148.54 87.71,148.54 83.39,152.86 53.39,152.86 52.9,152.86 52.9,154.3 53.14,154.86 53.7,155.1 59.7,155.1 60.55,155.45 60.9,156.3 60.9,156.8 61.14,157.36 61.7,157.6 109.7,157.6 110.26,157.36 110.5,156.8 110.5,156.3 110.85,155.45 111.7,155.1 115.22,155.1 115.75,154.9 116.01,154.4 118.5,134.18 118.5,129.14
GND on GND2: outline of 380 points within 0.2,0.2 285.15,157.6
GND on GND3: outline of 383 points within 0.2,0.2 285.15,157.6
V3D3_STB on TOP (solid shape): 30.25,21.43 30.25,20.31 30.67,19.9 30.67,18.46 30.61,18.4 30.48,18.4 30.43,18.46 30.43,19.74 29.27,20.9 28.83,20.9 28.75,20.98 28.75,21.42 28.79,21.46 30.22,21.46
VCC3V3_S0 on BOTTOM (solid shape): 31.32,125.3 31.77,125.3 31.83,125.24 31.83,124.68 31.98,124.53 31.98,122.11 32.07,122.02 32.07,121.17 32,121.1 31.22,121.1 31.14,121.18 31.14,121.48 30.67,121.95 30.67,124.66 30.13,125.2 30.13,125.38 30.28,125.52 31.09,125.52
VCC_VCCIO on BOTTOM (solid shape): 49.94,118.48 49.94,117.42 49.88,117.36 48.99,117.36 48.95,117.41 48.95,117.99 49.06,118.11 49.06,118.54 49.21,118.69 49.73,118.69
VDD10 on TOP (solid shape): 63.5,44.12 63.5,43.8 63.37,43.61 63.39,43.38 63.39,43.36 63.39,43.34 63.23,43.18 62.99,43.18 62.89,43.08 62.89,42.49 62.64,42.24 62,42.24 61.55,41.79 61.53,41.78 61.33,41.68 61.23,41.48 61.23,41.47 60.99,41.23 60.98,41.23 60.46,40.71 59.67,40.71 59.59,40.79 59.59,40.99 59.63,41.06 59.64,41.14 59.64,41.58 61.15,43.09 61.43,43.09 62.47,44.13 62.47,44.19 62.66,44.39 63.23,44.39
VDD_1.2V on BOTTOM (solid shape): 34.68,42.13 36.18,42.13 36.25,42.06 36.25,41.69 35.94,41.38 35.59,41.38 35.59,41.38 35.41,41.38 34.16,40.14 33.2,40.14 33.04,40.3 33.04,42.19 33.17,42.32 34.48,42.32
VIN_+1.05V on BOTTOM (solid shape): 141.18,57.16 141.18,56.92 141.17,56.92 141.17,56.05 141.24,55.98 141.24,54.63 141.24,54.62 141.24,53.71 139.17,51.64 134.6,51.64 134.21,51.26 133.43,51.26 133.33,51.36 133.33,53.51 134.34,53.51 134.34,52.55 134.59,52.3 135.49,52.3 135.71,52.52 135.71,53.44 135.22,53.94 134.77,53.94 134.34,53.51 133.33,53.51 133.33,55.22 133.88,55.78 139.42,55.78 140.84,57.2 141.14,57.2
VIN_VCCIO on TOP (solid shape): 47.6,114.62 47.6,113.26 47.27,112.92 45.47,112.92 45.27,113.12 45.27,114.68 45.5,114.91 47.32,114.91
VIN_VCCIO on BOTTOM (solid shape): 45.82,115.78 46.7,115.78 46.86,115.93 48.36,115.93 48.44,115.85 48.44,115.06 47.41,114.04 47.41,112.53 48.86,111.08 48.86,110.85 48.84,110.83 48.46,110.83 48.45,110.82 48.45,110.29 48.44,110.28 48.26,110.28 48.26,110.29 48.26,110.84 48.25,110.84 47.31,110.84 46.92,111.23 45.54,111.23 45.32,111.01 44.78,111.01 44.62,111.17 44.62,112.6 44.8,112.78 44.8,114.61 44.67,114.74 44.67,116.29 44.74,116.35 45.25,116.35
+CHARGER_SRC on TOP (solid shape): 247.99,54.9 247.99,53.57 248.17,53.39 250.67,53.39 250.94,53.12 250.94,52.26 250.77,52.09 247.64,52.09 247.64,52.1 247.28,52.1 246.93,52.45 246.93,54.95 247,55.03 247.87,55.03
+CHARGER_SRC on TOP (solid shape): outline of 138 points within 216.22,33.91 226.29,41.47
+CHARGER_SRC on TOP (solid shape): outline of 291 points within 239.1,31.7 249.68,38.93
+CHARGER_SRC on BOTTOM (solid shape): 248.02,54.86 248.02,53.59 248.21,53.4 250.66,53.4 250.91,53.16 250.91,50.17 250.63,49.9 246.66,49.9 246.56,50 246.56,50.4 246.59,50.43 247.4,50.43 247.52,50.55 247.52,51.87 246.94,52.46 246.94,54.95 247.01,55.02 247.86,55.02
+CHARGER_SRC on BOTTOM (solid shape): 246.53,38.8 250.55,38.8 250.74,38.62 250.74,38.06 249.83,37.16 249.83,35.33 249.2,34.7 247.09,34.7 246.94,34.85 246.94,35.18 246.91,35.2 245.62,35.2 245.08,35.2 244.8,35.48 244.8,38.59 245.1,38.9 246.43,38.9
+DC_IN on TOP (solid shape): outline of 1178 points within 35.58,116.03 53.36,138.84
+DC_IN on BOTTOM (solid shape): 52.23,133.59 52.23,132.2 50.51,130.48 49.15,130.48 46.77,128.09 43.41,128.09 43.12,128.38 43.12,133.17 43.38,133.44 45.66,133.44 46.29,134.06 51.76,134.06
+DC_IN on BOTTOM (solid shape): 37.4,118.88 37.4,118.55 37.78,118.17 38.07,118.17 38.74,117.5 38.74,116.48 38.56,116.31 37.57,116.31 37.27,116.6 37.26,116.6 36.57,117.3 36.57,118.9 36.65,118.99 37.3,118.99
+DC_IN_SS on TOP (solid shape): outline of 101 points within 33.68,110.03 43,116.64
+DC_IN_SS on BOTTOM (solid shape): 43.04,116.45 43.04,114.08 42.84,113.88 39.54,113.88 39.51,113.86 39.5,113.86 39.5,113.84 39.4,113.74 37.98,113.74 37.87,113.85 37.87,113.87 37.85,113.87 37.82,113.9 34.35,113.9 34.32,113.87 34.26,113.87 34.26,113.82 34.21,113.77 34.21,113.49 34.09,113.36 33.81,113.36 33.66,113.51 33.66,115.98 33.88,116.2 37.49,116.2 37.51,116.18 37.75,116.18 37.76,116.18 37.86,116.16 37.96,116.18 37.97,116.18 38.61,116.18 38.64,116.2 39.13,116.2 39.14,116.2 39.27,116.18 39.39,116.2 39.4,116.2 42.04,116.2 42.42,116.58 42.9,116.58
+DCBAT_LCD on TOP (solid shape): 258.61,56.83 258.59,56.8 258.69,56.38 259.13,56.37 259.23,56.37 259.28,56.28 259.28,55.17 259.16,55.04 256.13,55.04 255.77,55.4 255.77,56.99 255.9,57.13 258.31,57.13
+DCBAT_LCD on BOTTOM (solid shape): outline of 309 points within 254.66,54.96 263.3,63.6
+FB_PLLAVDD on TOP (solid shape): 208.18,114.58 208.18,112.39 207.98,112.19 206.68,112.19 206.48,112.39 206.48,113.62 207.49,114.63 208.13,114.63
+FB_PLLAVDD on TOP (solid shape): 225.47,119.46 225.47,119.44 225.48,119.34 225.53,119.25 225.53,118.8 225.52,118.79 225.49,118.65 225.52,118.51 225.53,118.5 225.53,117.97 225.47,117.77 225.53,117.58 225.53,117.15 225.49,116.82 225.74,116.61 225.76,116.58 225.76,115.75 225.6,115.59 225.4,115.59 225.27,115.72 225.27,115.95 225.37,116.05 225.37,116.41 224.79,116.99 224.59,116.99 224.54,117.04 224.54,117.55 224.59,117.6 225.07,117.6 225.2,117.73 225.2,118.72 225.07,118.85 224.64,118.85 224.54,118.95 224.54,119.53 224.61,119.61 225.32,119.61
+GPU_CORE on TOP (solid shape): 220.6,108.12 221.36,108.12 221.36,107.51 220.47,107.51 220.47,107.62 219.81,108.28 219.81,108.45 219.94,108.58 220.14,108.58
+GPU_CORE on TOP (solid shape): 223.44,104.69 223.44,103.7 223.09,103.35 222.91,103.35 222.27,103.98 221.92,103.98 221.76,104.14 221.76,104.67 221.92,104.82 223.31,104.82
+GPU_CORE on TOP (solid shape): 218.2,112.73 218.2,112.32 218.06,112.18 216.8,112.18 216.54,112.44 216.54,112.51 216.54,112.56 216.54,112.61 216.54,113.58 216.74,113.78 217.15,113.78
+GPU_CORE on TOP (solid shape): 223.39,113.62 223.39,112.72 223.23,112.56 222.73,112.56 222.55,112.38 221.86,112.38 221.75,112.49 221.75,112.72 221.86,112.83 222.3,112.83 222.72,113.25 222.72,113.7 222.87,113.85 223.16,113.85
+GPU_CORE on TOP (solid shape): 215.14,103.85 215.89,103.1 215.93,103.06 215.93,102.29 215.87,102.22 215.28,102.22 215.27,102.23 214.75,102.74 214.75,103.65 214.95,103.85 215.12,103.85
+GPU_CORE on TOP (solid shape): 215.17,111.72 215.28,111.72 215.67,111.33 215.87,111.33 216.5,110.69 216.5,110.43 216.36,110.28 216.19,110.28 215.67,110.81 215.39,110.81 214.82,111.38 214.82,111.71 214.89,111.78 215.1,111.78
+GPU_CORE on TOP (solid shape): 216.3,106.55 216.3,105.4 216.18,105.28 214.84,105.28 214.75,105.37 214.75,105.67 215.71,106.62 215.77,106.62 215.89,106.75 216.1,106.75
+GPU_CORE on TOP (solid shape): 224.54,106.31 224.71,106.31 224.74,106.29 225.24,106.29 225.48,106.04 225.48,105.43 225.38,105.33 225.12,105.33 224.7,105.75 224.27,105.75 223.67,106.34 223.67,106.56 223.78,106.67 223.88,106.67 223.88,106.7 224.14,106.7
+GPU_CORE on TOP (solid shape): 225.38,113.55 225.38,113.25 225.13,112.99 225,112.99 224.7,112.69 224.24,112.69 224.01,112.46 224.01,111.64 224.09,111.56 224.09,111.46 223.93,111.3 223.76,111.3 223.58,111.48 223.58,112.64 224.58,113.64 225.29,113.64
+GPU_CORE on TOP (solid shape): 216.21,112.8 216.31,112.8 216.39,112.72 216.39,112.2 216.41,112.18 216.41,111.54 216.24,111.36 216.08,111.36 215.93,111.51 215.93,111.71 215.94,111.72 216.02,111.72 216.02,111.8 216.07,111.85 216.07,112.47 215.78,112.76 215.44,112.76 214.82,113.38 214.82,113.72 214.9,113.8 215.2,113.8
+GPU_CORE on TOP (solid shape): 225.39,111.67 225.39,111.31 224.82,110.75 224.76,110.75 224.76,110.75 224.37,110.75 223.92,110.31 223.76,110.31 223.44,110.63 223.44,110.65 223.2,110.89 223.1,110.89 223.03,110.9 222.97,110.9 222.89,110.98 222.89,111.45 222.95,111.51 223.41,111.51 223.45,111.47 223.45,111.43 223.48,111.4 223.48,111.34 223.65,111.16 224.08,111.16 224.57,111.65 224.79,111.65 224.95,111.8 225.25,111.8
+GPU_CORE on TOP (solid shape): outline of 1496 points within 209.45,74.24 243.93,112.8
+GPU_CORE on BOTTOM (solid shape): outline of 4352 points within 211.34,77.8 242.89,115.25
+GPU_CORE on VCC: 212.12,77.67 206.76,83.03 206.76,113.25 207.38,113.87 226.8,113.87 227.1,113.56 227.1,100.73 228.12,99.72 228.12,94.51 234.21,88.41 234.21,86.38 239.93,80.67 239.93,78.11 239.5,77.67
+LAN_VDD33 on TOP (solid shape): 63.88,41.25 63.88,41.1 63.88,41.1 63.88,40.29 63.72,40.12 61.41,40.12 61.27,40.26 61.27,40.26 60.76,40.26 60.72,40.31 59.65,40.31 59.61,40.35 59.61,40.51 59.68,40.57 60.5,40.57 61.03,41.1 61.45,41.1 61.46,41.1 61.59,41.08 61.71,41.1 61.72,41.1 62.64,41.1 62.92,41.38 63.75,41.38
+LAN_VDD33 on TOP (solid shape): outline of 205 points within 43.94,34.6 57.68,37
+LAN_VDD33 on BOTTOM (solid shape): outline of 1222 points within 52.22,35.13 65.05,44.91
+LCDVDD on TOP (solid shape): 258.75,52.07 258.75,49.28 258.64,49.17 257.79,49.17 257.68,49.28 257.68,50.18 257.2,50.65 257.2,52.05 257.25,52.11 258.71,52.11
+LCDVDD_LCD on TOP (solid shape): 257.03,53.92 258.65,53.92 258.7,53.87 258.7,52.91 257.26,52.91 257.26,52.88 256.29,52.88 255.52,52.88 255.37,52.88 254.61,52.88 253.39,52.88 253.13,53.14 253.13,53.99 253.21,54.07 256.87,54.07
+LCDVDD_LCD on BOTTOM (solid shape): 256.19,54.19 256.23,54.19 257.36,54.19 257.48,54.06 257.48,52.44 257.36,52.31 256.33,52.31 255.88,52.77 255.87,52.78 255.77,52.89 255.62,52.93 254.84,52.93 254.78,52.92 254.72,52.91 254.69,52.91 254.66,52.94 254.66,53.8 254.72,53.86 255.66,53.86 255.68,53.87 255.69,53.88 255.82,53.95 255.9,54.08 255.9,54.1 255.99,54.19
+PWR_SRC on TOP (solid shape): 268.02,74.82 268.02,73.46 267.82,73.26 266.54,73.26 266.2,73.6 266.23,73.66 266.23,73.66 266.23,74.07 266.79,74.07 266.79,74.51 266.23,74.51 266.23,74.86 266.41,75.04 267.8,75.04
+PWR_SRC on TOP (solid shape): 121.59,55.22 121.59,54.7 122.14,54.7 122.15,54.69 122.15,54.45 121.58,54.45 121.58,53.89 122.15,53.89 122.15,53.66 121.59,53.66 121.59,53.15 121.57,53.13 120.31,53.13 120.15,53.29 119.09,53.29 118.53,53.85 118.53,55.64 118.69,55.79 121.01,55.79
+PWR_SRC on TOP (solid shape): 44.14,60.41 44.14,53.65 44.15,53.64 44.15,53.47 44.61,53.01 44.61,49.34 43.23,47.95 43.23,45.94 43.05,45.77 42.23,45.77 42.06,45.95 42.06,46.44 41.87,46.63 40.44,46.63 40.41,46.61 39.64,46.61 39.63,46.62 39.63,46.88 39.63,46.88 40.19,46.88 40.19,46.89 40.19,47.35 40.18,47.36 39.64,47.36 39.63,47.37 39.63,47.63 39.64,47.64 40.26,47.64 40.26,47.64 40.64,48.02 40.77,48.14 41.72,48.14 41.9,48.32 42.63,48.32 42.81,48.5 42.81,51.65 42.44,52.02 42.44,60.15 42.87,60.58 43.97,60.58
+PWR_SRC on TOP (solid shape): outline of 487 points within 214.13,38.56 229.64,56.81
+PWR_SRC on BOTTOM (solid shape): 269.07,74.93 269.07,73.45 268.82,73.2 267.29,73.2 267.09,73.39 267.09,75.08 267.32,75.3 268.7,75.3
+PWR_SRC on BOTTOM (solid shape): 43.01,47.74 43.01,45.83 42.93,45.75 42.58,45.75 42.47,45.86 42.47,46.51 42.32,46.65 41.47,46.65 41.37,46.75 41.37,48.02 41.46,48.11 42.63,48.11
+PWR_SRC on BOTTOM (solid shape): 268.84,63.39 268.84,62.64 267.88,61.68 267.88,60.38 267.67,60.17 265.67,60.17 265.53,60.31 265.53,63.46 265.64,63.57 268.65,63.57
+PWR_SRC on BOTTOM (solid shape): 119.1,55.63 119.1,55.47 119.29,55.28 120.79,55.28 120.88,55.19 120.88,53.69 120.77,53.58 119.16,53.58 118.54,54.2 118.54,55.67 118.67,55.8 118.93,55.8
+PWR_SRC on BOTTOM (solid shape): 135.88,60.22 138.49,60.22 139.03,59.68 140.83,59.68 141.65,58.86 143.48,58.86 144.17,58.17 144.17,54.52 143.58,53.92 142.12,53.92 141.37,54.68 141.37,56.08 141.32,56.13 141.32,56.44 141.87,56.44 141.87,56.88 141.33,56.88 141.33,57.09 141.34,57.09 141.34,57.31 141.16,57.48 139.9,57.48 139.46,57.91 133.71,57.91 133.46,58.16 133.46,60.32 133.84,60.7 135.4,60.7
+PWR_SRC on BOTTOM (solid shape): 48.12,110.69 48.12,110.17 48.15,110.14 48.55,110.14 48.58,110.18 48.58,110.57 48.58,110.69 48.59,110.7 48.87,110.7 48.92,110.65 48.92,109.61 48.71,109.28 48.92,108.96 48.92,108.56 48.71,108.35 45.77,108.35 45.62,108.5 45.62,109.14 45.63,109.25 45.62,109.36 45.62,110.44 45.7,110.51 47.1,110.51 47.3,110.71 48.09,110.71
+PWR_SRC on BOTTOM (solid shape): 117.43,112.97 117.43,98.5 117.44,97.53 117.48,96.56 117.48,94.41 117.68,94.21 117.68,94.19 118.63,89.11 120.28,84.21 120.41,83.81 120.47,83.75 120.58,83.51 120.68,83.28 120.68,82.48 120.46,82.26 119.08,82.26 118.7,82.64 118.05,83.3 118.05,83.64 115.58,86.11 115.58,100.55 116.1,101.06 116.1,101.5 116.55,101.96 116.55,105.75 114.68,107.62 114.68,113 114.84,113.16 117.24,113.16
+PWR_SRC on BOTTOM (solid shape): outline of 97 points within 214.51,42.72 229.45,55.99
+PWR_SRC on VCC: 220.04,49.99 211.91,58.11 201.5,58.11 198.07,61.54 191.98,61.54 190.64,62.88 180.19,62.88 178.85,61.54 172.87,61.54 172.84,61.54 172.81,61.53 166.36,58.88 159.54,57.38 148.73,57.38 136.02,61.25 125.21,69 117.26,76.95 117.25,76.95 117.25,76.96 116.87,77.34 116.87,84.71 115.72,85.85 115.72,95.63 113.82,97.54 113.82,119.13 113.78,119.16 111.79,121.16 111.79,123.09 111.84,123.14 116.97,123.14 117.53,123.14 117.53,98.5 117.55,97.23 117.62,95.96 118.09,92.06 118.97,88.24 119.87,85.52 120.98,82.87 120.67,81.81 120.92,80.74 121.68,79.36 122.49,78.02 122.49,78.02 123.19,76.96 123.93,75.92 124.78,75.23 125.87,75.04 126.41,74.39 126.98,73.74 130.16,70.58 133.7,67.83 136.37,66.17 139.17,64.73 140.55,64.13 141.96,63.58 146.98,62.14 152.15,61.42 155.56,61.34 158.97,61.58 163.48,62.38 167.85,63.74 169.57,64.44 171.25,65.22 173.08,66.19 174.85,67.27 175.65,67.27 175.65,67.27 177.6,67.27 177.6,67.26 204.7,67.26 208.38,63.57 217.4,63.57 227.86,53.11 227.86,50.67 227.18,49.99
+PWR_SRC on VCC: 51.64,96.85 45.75,102.74 45.62,113.69 46.18,114.25 50.12,114.25 50.44,114.58 50.44,119.51 49.68,120.27 49.68,129.05 55.02,134.39 55.02,139.9 58.45,139.9 58.45,116.03 56.67,116.03 56.67,101.47 52.04,96.85
+PWR_SRC_AC on TOP (solid shape): 240.4,32.11 240.4,31.59 240.42,31.57 241.13,31.57 241.14,31.58 241.14,32.12 241.14,32.12 241.59,32.12 241.6,32.11 241.6,31.59 241.62,31.57 245.21,31.57 245.23,31.59 245.23,32.12 245.23,32.12 245.67,32.12 245.68,32.11 245.68,31.58 245.69,31.57 246.42,31.57 246.43,31.58 246.43,32.12 246.44,32.13 246.88,32.13 246.89,32.11 246.89,31.59 246.91,31.57 247.56,31.57 247.57,31.56 247.57,29.95 247.24,29.62 245.11,29.62 244.19,28.71 239.42,28.71 239.13,29 239.13,31.44 239.27,31.58 239.89,31.58 239.9,31.59 239.92,31.59 239.92,31.6 239.93,31.61 239.93,32.1 239.95,32.13 240.39,32.13
+PWR_SRC_AC on TOP (solid shape): outline of 127 points within 216.34,29.37 222.23,35.24
+SDC_IN on TOP (solid shape): 216.21,34.29 216.21,34.28 216.38,34.11 217.45,34.11 217.71,33.85 217.71,33.34 217.69,33.32 217.18,33.32 216.99,33.26 216.86,33.1 216.85,33.09 216.82,33.06 216.82,32.78 216.98,32.62 217.08,32.62 217.13,32.61 217.18,32.6 217.67,32.6 217.71,32.56 217.71,32.36 218.17,31.91 218.17,29.44 218.1,29.37 216.57,29.37 216.5,29.44 216.5,31.46 216.1,31.86 216.02,31.86 215.25,31.86 215.01,32.1 215.01,34.34 215.22,34.54 215.95,34.54
+SDC_IN on TOP (solid shape): 27.87,46.78 27.87,45.35 27.8,45.29 27.8,44.91 27.8,43.88 27.44,43.52 26.48,43.52 26.48,43.52 21.88,43.52 21.49,43.9 21.49,45.29 23.44,45.29 23.45,45.24 23.46,45.19 23.48,45.14 23.51,45.09 23.55,45.05 23.59,45.02 23.63,44.99 23.68,44.97 23.73,44.96 23.79,44.95 23.84,44.96 23.89,44.96 23.94,44.98 23.99,45.01 24.03,45.04 24.07,45.07 24.1,45.12 24.12,45.16 24.15,45.25 24.15,45.31 24.15,45.37 24.14,45.4 24.14,45.78 24.15,45.81 24.15,45.85 24.15,45.87 24.15,46.46 24.15,46.48 24.14,46.53 24.13,46.58 24.11,46.63 24.07,46.67 24.04,46.71 24,46.74 23.95,46.76 23.9,46.78 23.85,46.79 23.8,46.79 23.75,46.78 23.7,46.76 23.65,46.74 23.61,46.71 23.57,46.67 23.54,46.63 23.52,46.58 23.5,46.53 23.49,46.48 23.49,46.46 23.49,45.87 23.49,45.85 23.5,45.81 23.51,45.78 23.51,45.51 23.49,45.49 23.47,45.44 23.45,45.39 23.44,45.34 23.44,45.29 21.49,45.29 21.49,46.56 21.91,46.98 27.67,46.98
+SDC_IN on TOP (solid shape): outline of 216 points within 181.3,24.03 192.88,31.05
+SDC_IN on TOP (solid shape): outline of 1683 points within 26.19,61.05 51.32,109.66
+SDC_IN on BOTTOM (solid shape): outline of 113 points within 34.37,107.16 42.98,113.75
+SDC_IN on BOTTOM (solid shape): outline of 159 points within 21.62,43.76 30.63,50.82
+SDC_IN on BOTTOM (solid shape): outline of 5458 points within 41.32,24.37 132.52,37.81
+TBTA_VBUS on TOP (solid shape): 25.24,65.91 25.24,62.45 24.98,62.2 21.63,62.2 21.34,62.48 19.71,62.48 19.58,62.61 19.58,64.02 19.69,64.13 22.4,64.13 22.8,64.54 22.8,65.79 23.12,66.11 25.04,66.11
+TBTA_VBUS on TOP (solid shape): 14.17,112.77 14.17,111.29 14.7,110.76 14.7,110.48 14.54,110.32 14.06,110.32 13.82,110.08 12.96,110.08 12.91,110.14 12.2,110.14 12.08,110.26 12.08,112.62 12.55,113.09 13.86,113.09
+TBTA_VBUS on TOP (solid shape): 9.78,123.7 9.78,123 8.76,121.98 7.91,121.98 7.72,122.17 6.99,122.17 6.9,122.26 6.9,122.33 6.68,122.55 6.28,122.55 6.16,122.43 5.43,122.43 5.34,122.51 5.34,122.63 5.45,122.73 6.03,122.73 6.33,123.03 6.61,123.03 6.76,122.88 6.76,122.76 7.04,122.48 7.69,122.48 7.72,122.45 8.53,122.45 9.27,123.19 9.27,123.62 9.43,123.78 9.71,123.78
+TBTA_VBUS on TOP (solid shape): 9,120.21 9.33,120.21 9.43,120.12 9.77,120.12 9.96,119.92 9.96,119.8 9.82,119.65 9.56,119.65 9.35,119.44 9.35,119.29 9.26,119.2 9.07,119.2 8.95,119.32 8.95,119.39 8.71,119.63 6.42,119.63 6.12,119.93 5.43,119.93 5.34,120.03 5.34,120.14 5.43,120.23 6.25,120.23 6.37,120.11 6.8,120.11 6.93,119.98 7.74,119.98 8.1,120.34 8.88,120.34
+TBTA_VBUS on BOTTOM (solid shape): 30.94,86.72 31.61,86.72 31.69,86.64 31.69,86.35 31.61,86.27 30.95,86.27 30.84,86.16 30.84,86.06 30.83,86.05 30.4,85.62 30.4,85.35 29.95,84.9 28.64,84.9 28.56,84.98 28.56,85.97 29.49,86.9 30.76,86.9
+TBTA_VBUS on BOTTOM (solid shape): 12.29,120.63 12.29,120.16 12.18,120.04 10.72,120.04 10.32,119.64 9.56,119.64 9.35,119.44 9.35,119.3 9.22,119.16 8.12,119.16 7.59,119.69 6.87,119.69 6.8,119.62 6.4,119.62 6.26,119.76 6.26,119.97 6.4,120.1 7.36,120.1 7.79,120.53 8.96,120.53 9.27,120.22 10.47,120.22 10.68,120.43 10.68,120.64 10.79,120.74 12.18,120.74
+TBTA_VBUS on BOTTOM (solid shape): 9.75,123.72 9.75,122.76 9.88,122.63 11.4,122.63 11.51,122.52 11.51,121.96 11.42,121.87 9.91,121.87 9.91,122.06 9.54,122.43 9.2,122.43 8.7,121.93 7.3,121.93 6.67,122.55 6.37,122.55 6.26,122.66 6.26,122.89 6.38,123.01 6.84,123.01 7.19,122.67 8.59,122.67 9.21,123.29 9.21,123.29 9.32,123.4 9.32,123.71 9.4,123.79 9.68,123.79
+TBTA_VBUS on BOTTOM (solid shape): 35.29,86.56 35.29,86.39 35.47,86.21 35.63,86.21 35.75,86.1 35.8,86.04 35.8,86.01 35.81,85.91 35.86,85.82 35.86,85.65 36.55,84.96 36.55,84.15 36.37,83.97 35.54,83.97 35.35,84.16 35.12,84.16 34.93,84.35 34.93,84.66 35.13,84.86 35.13,84.99 35.13,85 35.15,85.1 35.13,85.21 35.13,85.22 35.13,85.28 34.44,85.97 34.44,86.21 34.48,86.24 34.5,86.24 34.72,86.29 34.81,86.49 34.81,86.51 34.99,86.69 35.16,86.69
+TBTA_VBUS on VCC: 14.74,58.74 14.71,60.15 13.66,61.08 13.66,62.47 13.74,62.47 13.74,85.05 3.87,85.05 3.87,85.06 3.77,85.06 3.77,86.15 3.28,87.33 2.1,87.82 1.27,87.82 1.27,87.98 9.5,87.98 11.04,89.02 10.67,90.84 10.67,102.86 11.04,104.68 9.5,105.72 1.27,105.72 1.27,106.53 3.35,106.53 4.53,107.02 5.02,108.2 5.02,114.8 4.53,115.98 3.35,116.47 1.17,116.47 1.17,125.93 1.35,125.93 2.18,126.15 2.84,126.81 13.44,126.81 18.01,122.25 24.41,122.25 24.41,100.99 25.88,99.52 27.53,99.52 28.98,98.07 28.98,91.59 31.52,89.05 31.52,86.64 32.03,86.13 32.06,58.75 15.27,58.75 15.27,58.74
+TBTA_VBUS_1 on TOP (solid shape): 21.22,62.1 21.22,61.58 21.58,61.23 25.94,61.23 26.29,60.88 28.74,60.88 29.02,60.6 29.02,57.19 28.77,56.95 21.08,56.95 21.02,57.01 21.02,59.2 20.95,59.27 20.9,59.33 20.84,59.38 20.25,59.97 20.25,62.1 20.39,62.24 21.08,62.24
+TP_VDD on TOP (solid shape): 237.18,36.57 237.18,31.24 235.99,30.05 228.52,30.05 226.63,31.95 230.19,31.95 230.19,31.89 230.2,31.84 230.22,31.79 230.24,31.74 230.27,31.7 230.31,31.66 230.35,31.62 230.4,31.6 230.44,31.58 230.5,31.57 230.55,31.56 230.6,31.57 230.66,31.58 230.7,31.6 230.75,31.62 230.79,31.66 230.83,31.7 230.86,31.74 230.88,31.79 230.9,31.84 230.91,31.89 230.91,31.95 230.9,32 230.88,32.05 230.86,32.1 230.83,32.14 230.79,32.18 230.75,32.21 230.7,32.24 230.66,32.26 230.6,32.27 230.55,32.28 230.5,32.27 230.44,32.26 230.4,32.24 230.35,32.21 230.31,32.18 230.27,32.14 230.24,32.1 230.22,32.05 230.2,32 230.19,31.95 226.63,31.95 226.52,32.05 226.52,33.26 226.73,33.47 227.49,33.47 228.24,32.71 235.59,32.71 235.86,32.99 235.86,35.13 235.23,35.76 234.42,35.76 234.29,35.63 234.29,35.08 234.2,34.99 232.8,34.99 232.72,35.07 232.72,36.23 232.1,36.85 232.1,37.71 232.41,38.02 235.73,38.02
+TP_VDD on BOTTOM (solid shape): 235.66,38.64 235.66,36.45 235.59,36.37 234.09,36.37 233.25,37.21 232.26,37.21 231.91,37.56 231.91,38.55 232.29,38.93 235.37,38.93
+TP_VDD on BOTTOM (solid shape): 225.53,35.81 225.53,35.07 226.01,34.59 226.51,34.59 226.73,34.52 226.95,34.59 227.05,34.59 227.24,34.78 228.61,34.78 228.83,35 228.83,35.3 228.91,35.39 229.52,35.39 229.64,35.27 229.64,34.42 229.03,33.81 228.3,33.81 227.9,33.41 227.9,32.4 227.72,32.22 224.61,32.22 224,32.83 224,32.83 223.91,32.92 223.91,35.85 223.99,35.93 225.42,35.93
+TPAN_VDD on TOP (solid shape): 255.78,36.7 255.78,35.3 255.64,35.17 254.41,35.17 254.33,35.24 254.33,36.71 254.53,36.92 255.56,36.92
+TPAN_VDD on BOTTOM (solid shape): 255.81,37.19 255.81,36.69 256.59,35.91 256.59,34.81 256.56,34.8 256.44,34.73 256.37,34.62 256.36,34.6 256.34,34.5 256.34,34.41 256.34,34.38 256.16,34.2 255.94,34.2 255.87,34.28 255.87,34.6 255.66,34.81 255.36,34.81 255.15,34.6 255.15,34.18 255.08,34.11 254.58,34.11 254.1,34.6 254.1,37.23 254.18,37.31 254.21,37.3 254.35,37.3 254.48,37.35 255.65,37.35
+VCHGR on BOTTOM (solid shape): outline of 98 points within 220.3,39.47 229.53,46.3
+VDISPLAY_VCC on TOP (solid shape): 14.97,100.98 15.69,100.98 16.11,100.56 18.01,100.56 18.27,100.3 18.27,99.69 18.17,99.59 18.1,99.58 18.04,99.57 17.53,99.57 17.48,99.58 17.41,99.59 17.26,99.74 14.05,99.74 13.95,99.84 13.95,101.24 14.17,101.46 14.49,101.46
AC_SW_PROCHOT on BOTTOM (solid shape): 45.84,125.08 45.84,122.39 45.8,122.36 45.24,122.36 45.22,122.38 45.22,122.51 45.22,122.52 45.22,122.89 44.84,123.27 44.3,123.27 44.25,123.32 44.25,123.99 45.44,125.17 45.75,125.17
ACAV_IN1 on TOP (solid shape): 274.07,56.49 274.07,55.39 273.85,55.17 273.25,55.17 272.99,55.43 271.99,55.43 271.93,55.49 271.93,56.8 272.04,56.91 273.65,56.91
ADJ_2.5V on BOTTOM (solid shape): 117.87,66.47 117.87,65.9 118,65.76 118.57,65.76 119.11,65.23 120.64,65.23 120.82,65.05 120.82,64.62 120.66,64.46 118.94,64.46 118.77,64.63 118.77,64.78 118.53,65.03 116.9,65.03 116.62,65.31 116.62,66.39 116.83,66.59 117.75,66.59
ADP_CHG on TOP (solid shape): 268.49,51.7 268.49,51.07 269.32,50.24 269.32,49.43 270.1,48.64 270.1,48.12 270.08,48.12 270.08,45.58 270.1,45.58 270.1,45.5 270.14,45.46 270.69,45.46 270.75,45.4 270.75,44.8 270.65,44.7 269.01,44.7 268.94,44.78 268.94,46.25 269.01,46.33 269.16,46.33 269.33,46.49 269.33,46.72 269.56,46.95 269.56,48.47 268.78,49.26 268.78,50.32 268.2,50.9 268.2,51.69 268.29,51.78 268.41,51.78
ADPIN on TOP (solid shape): 50.05,136.69 51.28,136.69 51.81,136.17 51.81,134.58 51.66,134.44 43.13,134.44 43.05,134.52 43.05,136.52 43.21,136.68 48.37,136.68 48.82,137.14 49.61,137.14
ADPIN on BOTTOM (solid shape): outline of 91 points within 42.86,133.67 51.64,141.29
AUD_AGND on TOP (solid shape): 28.04,11.08 28.04,10.79 28.16,10.66 29.17,10.66 29.21,10.63 29.21,9.97 29.13,9.89 27.03,9.89 26.95,9.98 26.95,11.13 27.04,11.22 27.89,11.22
AUD_AGND on TOP (solid shape): 26.14,21.84 26.14,21.44 26.04,21.33 26.04,20.62 26.21,20.45 26.82,20.45 26.9,20.37 26.9,19.91 26.87,19.89 26.29,19.89 25.48,20.7 25.04,20.7 25.02,20.73 25.02,21.8 25.15,21.94 26.04,21.94
AUD_AGND on BOTTOM (solid shape): 16.21,19.25 16.21,17.78 16.33,17.66 18.79,17.66 19.03,17.41 19.03,16.55 18.8,16.32 15.89,16.32 15.65,16.57 15.65,19.22 15.7,19.27 16.18,19.27
AUD_AGND on GND1: outline of 88 points within 2.4,6.04 35.48,23.82
AUD_AGND on VCC: outline of 91 points within 2.45,5.99 35.48,23.82
AUD_AGND on GND2: outline of 88 points within 2.4,6.04 35.48,23.82
AUD_AGND on GND3: outline of 88 points within 2.4,6.04 35.48,23.82
AUD_HP1_JACK_L on TOP (solid shape): 28.66,16.55 28.66,16.47 28.59,16.39 27.19,16.39 26.55,15.76 24.64,15.76 24.58,15.82 24.58,16.33 24.62,16.38 26.39,16.38 26.52,16.51 26.95,16.51 27.06,16.62 28.59,16.62
AUD_HP1_JACK_R on TOP (solid shape): 28.65,16.15 28.65,16.08 28.58,16 27.31,16 26.68,15.37 25.96,15.37 25.6,15.01 24.61,15.01 24.56,15.06 24.56,15.55 24.63,15.62 26.62,15.62 27.23,16.23 28.58,16.23
AUD_PC_BEEP on TOP (solid shape): 35.46,21.46 35.46,21.06 35.46,21.05 35.46,19.96 34.65,19.15 33.55,19.15 32.82,18.41 32.49,18.41 32.44,18.46 32.44,19.24 32.68,19.48 34.25,19.48 34.7,19.93 34.7,21.4 34.77,21.48 35.45,21.48
AUD_SENSE_A on TOP (solid shape): 34.49,20.83 34.49,19.98 34.18,19.66 32.67,19.66 32.27,19.26 32.27,18.49 32.18,18.4 32.11,18.4 32.04,18.46 32.04,19.44 32.96,20.36 32.96,20.89 33.06,20.98 34.34,20.98
AUD_SPK_L+ on TOP (solid shape): 30.68,14.18 30.68,13.3 30.69,13.29 30.69,12.57 30.59,12.48 30.59,11.54 30.51,11.45 30.23,11.45 30.13,11.56 30.13,12.39 30.44,12.71 30.44,14.19 30.49,14.23 30.63,14.23
AUD_SPK_L+ on TOP (solid shape): 26.23,6.71 26.23,6.38 26.22,6.37 26.04,6.28 25.94,6.1 25.94,6.09 25.75,5.9 24.11,5.9 24.02,5.99 24.02,6.69 24.18,6.85 26.09,6.85
AUD_SPK_L+_C on TOP (solid shape): 14.44,4.94 14.44,3.88 15.01,3.31 15.01,2.95 14.86,2.79 14.19,2.79 13.42,3.56 13.16,3.56 13.13,3.59 12.85,3.88 12.85,4.84 13.2,5.18 14.2,5.18
AUD_SPK_L+_C on TOP (solid shape): 25.1,5.56 25.1,4.92 24.58,4.41 23.76,4.41 23.69,4.34 23.69,4.16 23.17,3.63 22.61,3.63 22.38,3.86 22.38,4.06 23.12,4.81 23.12,5.49 23.31,5.67 24.99,5.67
AUD_SPK_L+_C on BOTTOM (solid shape): 14.19,6.49 14.19,4.33 13.68,3.82 12.98,3.82 12.85,3.95 12.85,4.74 12.96,4.84 13.3,4.84 13.55,5.09 13.55,6.49 13.68,6.62 14.06,6.62
AUD_SPK_L- on TOP (solid shape): 26.21,4.72 26.21,2.81 26.14,2.74 25.63,2.74 25.53,2.84 25.53,3.75 25.03,4.25 25.03,4.48 25.4,4.85 26.09,4.85
AUD_SPK_L- on TOP (solid shape): 31.08,14.16 31.08,12.77 31.2,12.65 31.2,11.5 31.14,11.44 30.82,11.44 30.76,11.5 30.76,12.39 30.82,12.46 30.82,14.15 30.89,14.22 31.01,14.22
AUD_SPK_L-_C on TOP (solid shape): 12.52,5.61 12.52,3.76 12.75,3.53 12.75,3.4 12.37,3.01 11.66,3.01 11.43,3.24 11.43,5.64 11.58,5.79 12.34,5.79
AUD_SPK_L-_C on TOP (solid shape): 25.29,3.62 25.29,2.76 25.2,2.67 23.21,2.67 23.09,2.8 23.09,3.15 23.21,3.28 23.55,3.28 23.83,3.55 24.65,3.55 24.72,3.62 25.28,3.62
AUD_SPK_L-_C on BOTTOM (solid shape): 13.21,6.45 13.21,5.3 13,5.08 11.48,5.08 11.35,5.21 11.35,5.66 11.51,5.82 12.45,5.82 12.6,5.97 12.6,6.45 12.75,6.6 13.06,6.6
AUD_SPK_R+ on TOP (solid shape): 22.7,5.09 22.7,4.85 21.99,4.14 21.03,4.14 20.99,4.18 20.99,4.9 21.02,4.93 21.07,4.93 22.02,4.93 22.31,5.22 22.57,5.22
AUD_SPK_R+ on TOP (solid shape): 31.86,14.16 31.86,13.17 32.47,12.55 32.47,11.57 32.35,11.44 32.03,11.44 31.97,11.5 31.97,12.7 31.97,12.71 31.65,13.03 31.65,14.16 31.71,14.22 31.81,14.22
AUD_SPK_R+_C on TOP (solid shape): 18.41,4.81 20.77,4.81 20.84,4.74 20.84,4.17 20.83,4.17 20.83,4.06 20.77,4 20.25,4 20.1,4.15 18.55,4.15 18.05,3.66 16.96,3.66 16.73,3.88 16.73,4.9 16.98,5.15 18.07,5.15
AUD_SPK_R+_C on BOTTOM (solid shape): 16.35,6.49 16.35,5.66 17.23,4.77 17.23,4.01 17.11,3.88 16.41,3.88 16.22,4.08 16.22,4.58 15.58,5.22 15.58,6.49 15.71,6.62 16.22,6.62
AUD_SPK_R- on TOP (solid shape): 22.7,6.36 22.7,6.06 21.85,5.22 21.04,5.22 21.04,5.99 21.05,6 21.62,6 22.11,6.49 22.57,6.49
AUD_SPK_R- on TOP (solid shape): 31.46,14.2 31.46,13.03 31.84,12.65 31.84,11.57 31.71,11.44 31.46,11.44 31.33,11.57 31.33,12.21 31.35,12.32 31.33,12.43 31.33,12.7 31.33,12.71 31.27,12.77 31.27,14.2 31.3,14.24 31.42,14.24
AUD_SPK_R-_C on TOP (solid shape): 19.22,5.73 20.02,5.73 20.28,5.99 20.8,5.99 20.8,5.23 20.78,5.21 18.5,5.21 18.24,5.47 16.79,5.47 16.41,5.09 16.41,3.95 16.11,3.64 15.11,3.64 14.77,3.99 14.77,5.17 16.05,6.45 18.51,6.45
AUD_SPK_R-_C on BOTTOM (solid shape): 15.2,6.49 15.2,5.09 15.46,4.84 15.46,3.95 15.33,3.82 14.69,3.82 14.57,3.95 14.57,6.49 14.69,6.62 15.08,6.62
AUD_VREF on TOP (solid shape): 28.66,17.76 28.66,17.67 28.59,17.6 26.54,17.6 25.96,17.02 25.93,16.99 25.54,16.6 24.17,16.6 24.13,16.64 24.13,17.59 24.22,17.68 25.45,17.68 25.6,17.83 28.59,17.83
BATT+ on BOTTOM (solid shape): 220.7,46.46 220.7,45.65 220.17,45.65 220.17,44.95 220.7,44.95 220.7,44.45 220.17,44.45 220.17,43.75 220.7,43.75 220.7,42.71 221.32,42.09 221.32,38.6 221.13,38.41 217.11,38.41 216.95,38.57 216.95,41.86 217.35,42.26 217.35,45.28 217.76,45.69 217.76,46.55 217.93,46.72 220.44,46.72
BATT++ on TOP (solid shape): outline of 162 points within 211.82,37.88 216.36,44.44
BATT++ on BOTTOM (solid shape): outline of 247 points within 200.56,34.76 217.2,44.93
BOOT1_CHG on TOP (solid shape): 266.85,51.72 266.85,51.03 266.9,50.97 266.9,50.96 266.93,50.93 266.93,50.2 266.86,50.09 266.83,49.97 266.83,49.95 265.95,49.07 265.77,49.07 265.51,48.82 264.19,48.82 264.14,48.87 264.14,49.5 264.26,49.63 264.95,49.63 265.17,49.84 266.06,49.84 266.1,49.88 266.12,49.88 266.63,50.39 266.63,50.94 266.62,50.94 266.62,51.71 266.7,51.79 266.78,51.79
BOOT2_CHG on TOP (solid shape): 264.32,53.79 265.19,53.79 265.23,53.75 265.23,53.62 265.18,53.57 263.09,53.57 262.85,53.33 262.85,53.31 262.59,53.05 262.59,53.04 262.56,53.01 262.56,51.91 262.56,51.91 262.56,51.86 262.81,51.61 262.81,51.15 262.76,51.1 262.16,51.1 262.13,51.13 262.12,51.13 262.12,51.27 261.94,51.46 260.69,51.46 260.58,51.57 260.58,52.46 260.67,52.55 261.88,52.55 262.02,52.68 262.02,53.05 262.83,53.85 264.26,53.85
BS_VCCIO on BOTTOM (solid shape): 48.91,115.85 48.91,114.85 49.27,114.49 49.27,113.59 49.21,113.53 48.35,113.53 48.28,113.6 48.28,114.28 48.59,114.59 48.59,115.03 48.59,115.04 48.59,115.84 48.69,115.93 48.83,115.93
BST_1.2V on BOTTOM (solid shape): 38.13,47.05 38.13,46.17 37.48,45.52 37.48,44.84 37.46,44.82 37.46,43.99 37.39,43.92 37.32,43.92 37.24,44 37.24,44.74 37.24,44.74 37.24,44.87 37.26,44.89 37.26,46.92 37.43,47.09 38.09,47.09
BST_1.2V_R on BOTTOM (solid shape): 36.75,47.05 36.75,46.2 36.71,46.16 35.98,46.16 35.78,46.36 35.09,46.36 35.03,46.42 35.03,46.88 35.13,46.98 35.84,46.98 35.95,47.09 36.72,47.09
BST_3V on BOTTOM (solid shape): 210.57,53.21 210.57,52.11 210.49,52.04 210.49,51.24 210.42,51.16 210.26,51.16 210.22,51.2 210.08,51.2 210.04,51.21 209.98,51.21 209.51,51.68 209.51,52.46 209.63,52.58 209.63,53.24 209.65,53.26 210.52,53.26
BST_5V on BOTTOM (solid shape): 124.33,53.92 124.33,53.78 124.07,53.52 124.07,53.24 123.17,52.35 120.82,52.35 120.73,52.44 120.73,53.29 120.79,53.35 122.83,53.35 123.49,54.01 124.25,54.01
BST_+1.05V on BOTTOM (solid shape): 138.01,45.16 138.84,45.16 138.94,45.06 138.94,44.12 138.86,44.04 138.23,44.04 137.87,43.69 137.47,43.69 136.92,44.24 136.92,45.2 136.95,45.23 137.93,45.23
BST_VCCIO on BOTTOM (solid shape): 50.73,112.8 50.73,112.18 50.66,112.11 49.91,112.11 49.81,112.13 49.7,112.11 48.34,112.11 48.31,112.14 48.31,112.8 48.36,112.84 50.69,112.84
CORE_SW1 on BOTTOM (solid shape): 89.21,141.81 89.21,140.56 89.41,140.36 93.23,140.36 93.28,140.31 93.28,139.27 94.77,137.78 94.77,133.93 94.61,133.78 91.81,133.78 91.8,133.78 91.8,135.15 92.69,135.15 92.69,135.91 91.85,135.91 91.82,135.91 91.73,136.01 91.2,136.01 88.39,138.82 88.39,141.78 88.44,141.83 89.18,141.83
CORE_SW2 on BOTTOM (solid shape): 80.87,147.76 80.87,146.65 81.19,146.33 84.78,146.33 84.78,145.56 84.75,145.53 83.53,145.53 82.9,144.9 82.9,142.23 82.74,142.07 81.47,142.07 81.45,142.09 81.45,142.99 81.45,142.99 81.45,143.12 80.69,143.12 80.69,143 80.68,142.99 80.68,142.09 80.65,142.07 79.31,142.07 79.29,142.09 79.29,144.61 79.46,144.77 79.47,144.78 79.65,144.87 79.75,145.05 79.75,145.07 79.8,145.12 79.8,147.75 79.91,147.85 80.78,147.85
CORE_SW3 on BOTTOM (solid shape): 72.61,147.73 72.61,146.57 72.85,146.33 76.11,146.33 76.11,146.34 76.51,146.34 76.54,146.31 76.54,145.61 76.53,145.59 76.2,145.59 75.36,144.75 75.36,142.55 75.38,142.53 75.38,142.25 75.2,142.07 73.9,142.07 73.88,142.09 73.88,142.99 73.88,142.99 73.88,143.12 73.11,143.12 73.11,143 73.11,142.99 73.11,142.09 73.08,142.07 71.71,142.07 71.6,142.18 71.6,147.75 71.68,147.83 72.51,147.83
CORE_SW4 on BOTTOM (solid shape): 64.41,147.78 64.41,146.63 64.49,146.55 64.49,146.54 64.51,146.54 64.67,146.38 68.22,146.38 68.33,146.28 68.33,145.62 67.72,145.01 67.72,142.28 67.51,142.07 66.2,142.07 66.17,142.09 66.17,142.99 66.17,142.99 66.17,143.12 65.41,143.12 65.41,143 65.4,142.99 65.4,142.09 65.38,142.07 64.16,142.07 63.94,142.28 63.94,145.31 63.51,145.74 63.51,147.76 63.58,147.83 64.36,147.83
CPU_B+ on TOP (solid shape): 97.34,145.71 97.34,143.35 97.03,143.03 94.84,143.03 94.58,143.3 94.58,143.64 94.51,143.71 94.51,143.73 94.48,143.73 91.32,143.73 91.22,143.83 91.22,145.4 91.32,145.5 94.8,145.5 95.19,145.9 97.15,145.9
CPU_B+ on TOP (solid shape): outline of 1210 points within 57.92,147.51 88.04,156.63
CPU_B+ on TOP (solid shape): outline of 1421 points within 104.03,111.21 117.42,136.73
CPU_B+ on BOTTOM (solid shape): 114.44,113.82 114.44,109.71 114.19,109.45 111.2,109.45 111.13,109.53 111.13,112.83 112.34,114.04 114.23,114.04
CPU_B+ on BOTTOM (solid shape): 115.7,134.01 115.7,130.52 115.42,130.24 114.66,130.24 114.42,130.49 114.42,131.09 114.12,131.39 112.78,131.39 112.57,131.6 112.57,134.06 112.6,134.09 115.62,134.09
CPU_B+ on BOTTOM (solid shape): 87.83,151.87 87.83,149.18 87.66,149 82.98,149 82.93,149.05 82.93,150.17 82.96,150.19 84.13,150.19 84.48,150.55 84.48,151.05 84.56,151.13 85.45,151.13 85.5,151.13 86.09,151.72 86.09,151.91 86.19,152.01 87.69,152.01
CPU_B+ on BOTTOM (solid shape): 105.78,136.14 105.78,134.85 105.98,134.65 105.99,134.65 106.03,134.61 106.71,134.61 106.82,134.5 106.82,133.54 107.35,133.01 107.78,133.01 107.91,132.88 107.91,130.82 107.82,130.74 104.21,130.74 103.95,130.99 103.95,132.41 104.56,133.02 104.56,136.12 104.61,136.17 105.75,136.17
CPU_B+ on BOTTOM (solid shape): 63.07,152.05 63.07,150.29 62.84,150.06 62.84,149.7 62.88,149.66 62.88,149.43 62.82,149.38 62.82,148.34 62.79,148.31 61.01,148.31 60.91,148.21 58.24,148.21 58.17,148.28 58.17,149.4 58.19,149.43 59.36,149.43 59.72,149.78 59.72,150.36 59.81,150.46 60.71,150.46 61.41,151.16 61.41,151.91 61.6,152.1 63.02,152.1
CPU_B+ on BOTTOM (solid shape): 79.58,152.82 79.58,150.31 79.55,150.29 79.44,150.21 79.37,150.08 79.35,150.06 79.35,149.97 79.35,149.93 79.35,149.12 79.31,149.08 77.48,149.08 77.39,149 74.73,149 74.68,149.05 74.68,150.17 74.7,150.19 75.87,150.19 76.23,150.55 76.23,151.06 76.23,151.06 76.23,151.14 76.31,151.22 77.33,151.22 77.92,151.81 77.92,152.68 78.11,152.86 79.53,152.86
CPU_B+ on BOTTOM (solid shape): 96.88,145.69 96.88,145.06 96.84,145.05 96.57,144.7 96.84,144.36 96.88,144.35 96.88,143.22 96.74,143.08 94.81,143.08 94.68,142.95 91.36,142.95 91.31,143 91.31,144.12 91.39,144.19 92.66,144.19 92.86,144.4 92.86,145.09 92.96,145.19 94.11,145.19 94.51,145.59 94.9,145.59 95.17,145.86 96.71,145.86
CPU_B+ on BOTTOM (solid shape): 71.32,152.82 71.32,150.17 71.3,150.15 71.1,149.91 71.18,149.6 71.2,149.54 71.18,149.48 71.1,149.3 71.12,149.11 71.1,149.09 69.25,149.09 69.13,148.97 69.04,148.97 69.04,148.97 66.5,148.97 66.42,149.05 66.42,150.17 66.45,150.19 67.62,150.19 67.97,150.55 67.97,151.05 68.05,151.13 68.94,151.13 68.99,151.13 69.67,151.81 69.67,152.68 69.85,152.86 71.28,152.86
CPVEE on TOP (solid shape): 28.66,15.76 28.66,15.66 28.61,15.61 27.54,15.61 26.97,15.04 26.84,14.97 26.76,14.84 26.3,14.84 25.28,13.83 24.71,13.83 24.71,13.87 24.69,13.92 24.67,13.97 24.67,14.77 25.23,14.77 25.23,14.77 25.63,14.77 26.06,15.2 26.73,15.2 27.37,15.83 28.59,15.83
DCIN_CHG on TOP (solid shape): 269.57,51.98 269.57,51.46 269.57,51.41 269.89,51.09 269.91,51.09 270.58,50.42 271.61,50.42 272.13,50.94 273.56,50.94 273.56,49.63 273.46,49.53 270.23,49.53 268.64,51.12 268.64,52.13 268.71,52.2 269.35,52.2
EN_1.0VS_VGAP on BOTTOM (solid shape): 208.07,78.46 208.07,77.17 208.02,77.12 206.14,77.12 206.02,77.24 205.76,77.24 205.68,77.32 205.68,78.04 205.68,78.08 205.78,78.17 205.95,78.17 206.29,78.51 208.02,78.51
ENLDO_3V5V on BOTTOM (solid shape): 128.89,58.13 128.89,57.64 128.84,57.59 128.79,57.56 128.26,57.56 128.08,57.38 128.08,56.23 127.37,55.52 126.59,55.52 126.52,55.6 126.52,55.75 126.6,55.83 126.88,55.83 127.4,56.35 127.4,58.11 127.53,58.24 128.78,58.24
FB_1.0VS_VGAP on BOTTOM (solid shape): 207.51,75.79 207.51,73.18 207.42,73.09 206.24,73.09 205.68,73.65 205.68,74.98 205.75,75.05 206.03,75.05 206.26,75.28 206.26,75.7 206.45,75.89 207.41,75.89
GT_SW1 on BOTTOM (solid shape): outline of 202 points within 52.53,138.84 60.05,147.09
HDA_CODEC_SDIN0 on TOP (solid shape): 34.51,17.04 36.32,17.04 36.32,16.41 36.3,16.38 35.61,16.38 35.21,16.79 32.89,16.79 32.84,16.84 32.84,16.99 32.89,17.04 34.2,17.04 34.26,17.1 34.45,17.1
HPOUT_L on TOP (solid shape): 16.29,19.03 16.29,16.44 16.03,16.18 15.31,16.18 15.24,16.24 15.22,16.35 15.19,16.47 15.17,16.56 15.14,16.62 15.12,16.69 15.05,16.82 15,16.92 14.93,17.03 14.8,17.18 14.64,17.33 14.6,17.36 14.45,17.47 14.34,17.53 14.28,17.55 14,17.83 14,19.25 14.12,19.38 15.94,19.38
HPOUT_L on BOTTOM (solid shape): 15.31,19.25 15.31,17.75 15.15,17.6 14.25,17.6 14.12,17.73 14.12,19 14.4,19.28 15.28,19.28
HPOUT_R on TOP (solid shape): 18.25,19.5 18.25,16.31 18.21,16.27 17.4,16.27 17.11,16.55 17.11,17.61 16.78,17.94 16.78,19.27 16.93,19.42 17.03,19.42 17.19,19.58 17.2,19.58 17.26,19.65 18.1,19.65
HPOUT_R on BOTTOM (solid shape): 18.27,19.51 18.27,18.17 18.05,17.95 16.53,17.95 16.51,17.97 16.51,19.2 16.94,19.63 18.15,19.63
IFP_IOVDD on TOP (solid shape): 212.72,101.25 212.72,100.7 212.46,100.44 212.45,100.44 212.22,99.88 212.82,99.93 212.9,99.98 212.98,99.95 213,99.92 213.1,99.8 213.23,99.73 213.3,99.65 213.26,99.55 213.56,98.93 213.59,99.62 213.52,99.7 213.56,99.8 213.61,99.85 213.65,99.92 213.67,99.95 213.9,99.95 214.33,99.84 214.53,100.23 214.53,100.25 214.7,100.43 215.15,100.43 215.24,100.34 215.24,100.05 215.11,99.92 215.02,99.92 214.97,99.87 214.95,99.87 214.95,99.85 214.89,99.79 214.89,99.09 214.7,98.9 214.13,98.9 213.43,98.2 213.16,98.2 212.93,98.43 212.22,98.43 211.9,98.75 211.82,98.75 211.82,98.75 211.71,98.77 211.6,98.75 211.59,98.75 211.46,98.75 211.34,98.87 211.34,100.42 211.47,100.55 211.47,101.17 211.67,101.37 212.6,101.37
INT_TP# on BOTTOM (solid shape): 233.99,36.17 234.72,36.17 234.84,36.05 234.84,35.32 234.04,34.52 233.03,34.52 231.86,33.35 231.86,32.45 231.69,32.28 231.34,32.28 231.17,32.46 231.17,33.28 230.76,33.73 230.76,35.52 232.21,36.97 233.19,36.97
JACK_PLUG on TOP (solid shape): 22.08,20.31 22.08,19.21 21.62,18.74 21.62,17.85 21.49,17.73 20.73,17.73 20.45,18.01 20.45,20.24 20.73,20.53 21.86,20.53
JACK_PLUG_DET on TOP (solid shape): 20.18,20.18 20.18,17.94 20.04,17.8 19.2,17.8 19.08,17.93 19.08,18.98 18.48,19.58 18.48,20.41 18.59,20.52 19.84,20.52
LDO1_CAP on TOP (solid shape): 24.7,19.53 24.7,19.22 25.45,18.46 28.36,18.46 28.65,18.17 28.65,18.05 28.6,18 25.53,18 25.44,17.91 24.12,17.91 23.93,18.09 23.93,19.64 23.97,19.67 24.55,19.67
LDO2_CAP on TOP (solid shape): 29.46,14.12 29.46,13.26 28.65,12.44 28.32,12.44 28.02,12.14 28.02,11.4 27.96,11.35 27.78,11.35 27.74,11.35 27.21,11.35 27.17,11.35 27.08,11.35 27.05,11.38 27.05,11.75 27.62,12.32 27.62,12.59 27.97,12.93 28.85,12.93 29.24,13.31 29.24,14.15 29.31,14.22 29.36,14.22
LDO3_CAP on TOP (solid shape): 35.56,16.25 36.32,16.25 36.45,16.13 36.45,15.26 36.42,15.24 35.81,15.24 35.71,15.34 35.71,15.59 34.93,16.38 32.92,16.38 32.84,16.46 32.84,16.58 32.92,16.66 35.15,16.66
LG1_CHG on TOP (solid shape): 265.64,51.73 265.64,51.04 265.58,50.98 265.28,50.98 264.87,50.57 264.47,50.57 264.29,50.75 264.29,51.15 264.92,51.79 265.58,51.79
LG1_CHG on BOTTOM (solid shape): 247.04,46.05 247.04,45.44 247.17,45.32 247.17,45.03 247.01,44.88 246.18,44.88 246.02,45.03 246.02,45.92 246.34,46.24 246.85,46.24
LG1_CHG on BOTTOM (solid shape): 251,44.13 251,42.39 250.87,42.25 250.19,42.25 250.06,42.38 250.06,43.58 250.68,44.19 250.94,44.19
LG2_CHG on TOP (solid shape): 242.42,51.79 242.42,51.38 242.29,51.26 241.36,51.26 241.1,50.99 241.1,50.43 241.01,50.34 240.53,50.34 240.36,50.51 240.36,51.96 240.39,51.99 242.21,51.99
LG2_CHG on TOP (solid shape): 265.23,52.55 265.23,52.4 265.15,52.32 264.52,52.32 264.5,52.31 264.49,52.3 264.38,52.24 264.32,52.14 264.31,52.12 263.55,51.35 263.33,51.35 263.18,51.51 263.18,51.65 263.95,52.42 264.21,52.42 264.39,52.6 265.18,52.6
LG2_CHG on BOTTOM (solid shape): 242.38,51.66 242.38,50.85 242.25,50.71 240,50.71 239.82,50.89 239.82,51.29 240.35,51.82 242.23,51.82
LG_1.2V on BOTTOM (solid shape): 36.27,43.67 36.27,43.58 36.2,43.51 35.43,43.51 35.33,43.6 35.33,43.68 34.8,44.22 34.8,44.59 34.93,44.72 35.22,44.72
LG_1.2V on BOTTOM (solid shape): 35.55,50.3 35.55,49.97 35.41,49.83 34.87,49.83 34.31,50.38 34.23,50.39 34.13,50.39 33.99,50.53 33.99,50.84 34.04,50.9 34.95,50.9
LG_+1.05V on BOTTOM (solid shape): 134.01,44.49 134.01,44.05 134.5,43.56 134.5,42.67 134.41,42.58 134.29,42.58 134.2,42.67 134.2,43.34 133.52,44.01 133.52,44.49 133.65,44.61 133.89,44.61
LINE1_L on TOP (solid shape): 27.31,21.36 27.31,21.29 27.31,21.29 27.31,20.81 27.83,20.28 29.09,20.28 29.33,20.05 29.38,19.98 29.45,19.93 29.86,19.52 29.86,18.49 29.8,18.43 29.7,18.43 29.66,18.47 29.66,19.32 29.01,19.96 28.41,19.96 28.31,19.86 27.6,19.86 26.75,20.71 26.44,20.71 26.34,20.8 26.34,21.39 26.37,21.41 27.26,21.41
LINE1_R on TOP (solid shape): 28.61,21.33 28.61,20.85 28.72,20.75 29.21,20.75 30.26,19.71 30.26,18.45 30.22,18.42 30.09,18.42 30.03,18.48 30.03,19.54 29.17,20.41 27.89,20.41 27.62,20.69 27.62,21.38 27.63,21.4 28.54,21.4
LOM_TCT on BOTTOM (solid shape): 28.75,70.16 28.75,68.5 28.47,68.22 26.26,68.22 25.89,68.59 25.89,70.14 26.1,70.34 28.56,70.34
LOM_TCT on BOTTOM (solid shape): 26.58,78.01 27.7,78.01 27.83,78.02 27.96,78.05 28.6,78.05 28.73,77.93 28.73,76.02 28.6,75.89 25.55,75.89 25.3,76.15 25.3,77.93 25.43,78.05 26.53,78.05
LX1_CHG on TOP (solid shape): 266.05,51.72 266.05,50.89 265.81,50.65 265.61,50.65 265.35,50.39 265.35,50.28 264.88,49.81 264.18,49.81 263.93,49.55 263.93,48.39 263.83,48.28 263.04,48.28 262.97,48.36 262.97,49.54 263.84,50.41 264.88,50.41 264.91,50.44 264.92,50.44 265.33,50.85 265.65,50.85 265.83,51.02 265.83,51.72 265.89,51.78 265.99,51.78
LX1_CHG on BOTTOM (solid shape): 250.63,49.26 250.63,46.64 250.59,46.59 245.79,46.59 245,45.8 245,43.18 246.3,41.88 250.65,41.88 250.69,41.84 250.69,39.22 244.86,39.22 241.35,42.72 241.35,47.32 243.34,49.31 250.59,49.31
LX2_CHG on TOP (solid shape): 240.23,51.91 240.23,50.41 240.97,49.67 240.97,48.82 240.83,48.69 240.46,48.69 239.48,49.67 239.48,51.88 239.56,51.96 240.18,51.96
LX2_CHG on TOP (solid shape): 261.95,51.15 261.95,50.24 261.86,50.15 260.71,50.15 260.59,50.27 260.59,51.18 260.65,51.24 261.86,51.24
LX2_CHG on TOP (solid shape): 265.23,52.93 265.23,52.82 265.19,52.78 264.39,52.78 264.16,52.55 263.9,52.55 263.26,51.92 263.21,51.88 263.17,51.82 263.08,51.74 262.95,51.74 262.71,51.98 262.71,52.18 263.29,52.76 264.03,52.76 264.28,53 265.16,53
LX2P_CHG on TOP (solid shape): 237.24,55.72 237.24,54.92 237.52,54.64 239.08,54.64 239.3,54.42 239.3,47.23 239.09,47.02 237.05,47.02 236.8,47.27 236.8,48.19 235.77,49.22 235.77,50.94 235,51.71 235,52.75 235.52,52.75 235.52,53.5 235,53.5 235,53.94 235.52,53.94 235.52,54.7 235,54.7 235,55.65 235.21,55.87 237.1,55.87
LX2P_CHG on BOTTOM (solid shape): 239.47,55.02 239.47,44.65 237.75,42.93 232.47,42.93 232.44,42.96 232.44,45.72 236.68,45.72 236.68,45.67 236.69,45.61 236.71,45.56 236.74,45.52 236.77,45.48 236.81,45.44 236.85,45.41 236.9,45.39 236.95,45.37 237.01,45.36 237.06,45.36 237.11,45.37 237.16,45.39 237.21,45.41 237.26,45.44 237.29,45.48 237.33,45.52 237.35,45.56 237.37,45.61 237.39,45.67 237.39,45.72 237.39,45.77 237.37,45.82 237.35,45.87 237.33,45.92 237.29,45.96 237.26,46 237.21,46.03 237.16,46.05 237.11,46.07 237.06,46.07 237.01,46.07 236.95,46.07 236.9,46.05 236.85,46.03 236.81,46 236.77,45.96 236.74,45.92 236.71,45.87 236.69,45.82 236.68,45.77 236.68,45.72 232.44,45.72 232.44,46.49 232.52,46.57 235.64,46.57 236.76,47.69 236.76,55.04 239.44,55.04
LX_1.0VS_VGAP on BOTTOM (solid shape): 205.78,81.2 205.78,79.34 204.95,78.51 204.95,77.32 204.88,77.25 204.24,77.25 204.18,77.31 204.18,78.11 203.97,78.31 203.66,78.31 203.48,78.13 203.48,77.5 203.38,77.4 202.21,77.4 202.17,77.43 202.17,78.61 202.9,79.33 202.9,81.2 202.94,81.24 205.74,81.24
LX_1.2V on TOP (solid shape): 36.9,51.1 36.9,49.74 36.53,49.37 35.77,49.37 35.58,49.56 35.58,51.19 35.81,51.43 36.57,51.43
LX_1.2V on TOP (solid shape): 40.41,54.11 40.41,51.91 40.34,51.83 39.26,51.83 39.2,51.89 39.2,54.07 39.44,54.3 40.22,54.3
LX_1.2V on TOP (solid shape): 35.98,45.92 35.98,45.85 35.81,45.61 35.86,45.33 35.87,45.32 35.87,45.28 36.34,44.81 36.34,44.49 36.14,44.29 35.93,44.29 34.94,45.29 34.94,46.13 35.04,46.24 35.66,46.24
LX_1.2V on BOTTOM (solid shape): 35.74,45.99 35.78,45.95 35.78,45.39 36,45.17 36.25,45.17 36.65,44.77 36.65,44.77 36.65,44 36.58,43.92 36.22,43.92 34.99,45.16 34.99,45.9 35.08,45.99 35.64,45.99
LX_1.2V on BOTTOM (solid shape): 39.97,54.48 39.97,53.77 39.17,52.96 39.17,52.13 38.93,51.89 37.54,51.89 37.08,51.44 37.08,50.53 36.82,50.27 36.82,50.25 36.79,50.22 36.79,47.9 36.75,47.86 35.8,47.86 35.78,47.89 35.78,50.77 35.39,51.16 35.39,54.54 35.59,54.74 39.71,54.74
LX_1.8VALW on BOTTOM (solid shape): 203.64,71.63 203.64,69.82 204.32,69.13 207.27,69.13 207.35,69.06 207.35,66.92 207.29,66.87 203.46,66.87 202.76,67.57 201.53,67.57 201.41,67.68 201.41,68.32 201.49,68.4 202.33,68.4 202.44,68.51 202.44,68.51 202.44,69.26 202.55,69.51 202.46,69.76 202.44,69.77 202.44,69.79 202.37,69.87 202.37,71.68 202.44,71.75 203.51,71.75
LX_3V on TOP (solid shape): 207.16,54.68 207.16,52.65 207.04,52.53 206.14,52.53 205.29,53.37 205.29,54.91 205.4,55.02 206.83,55.02
